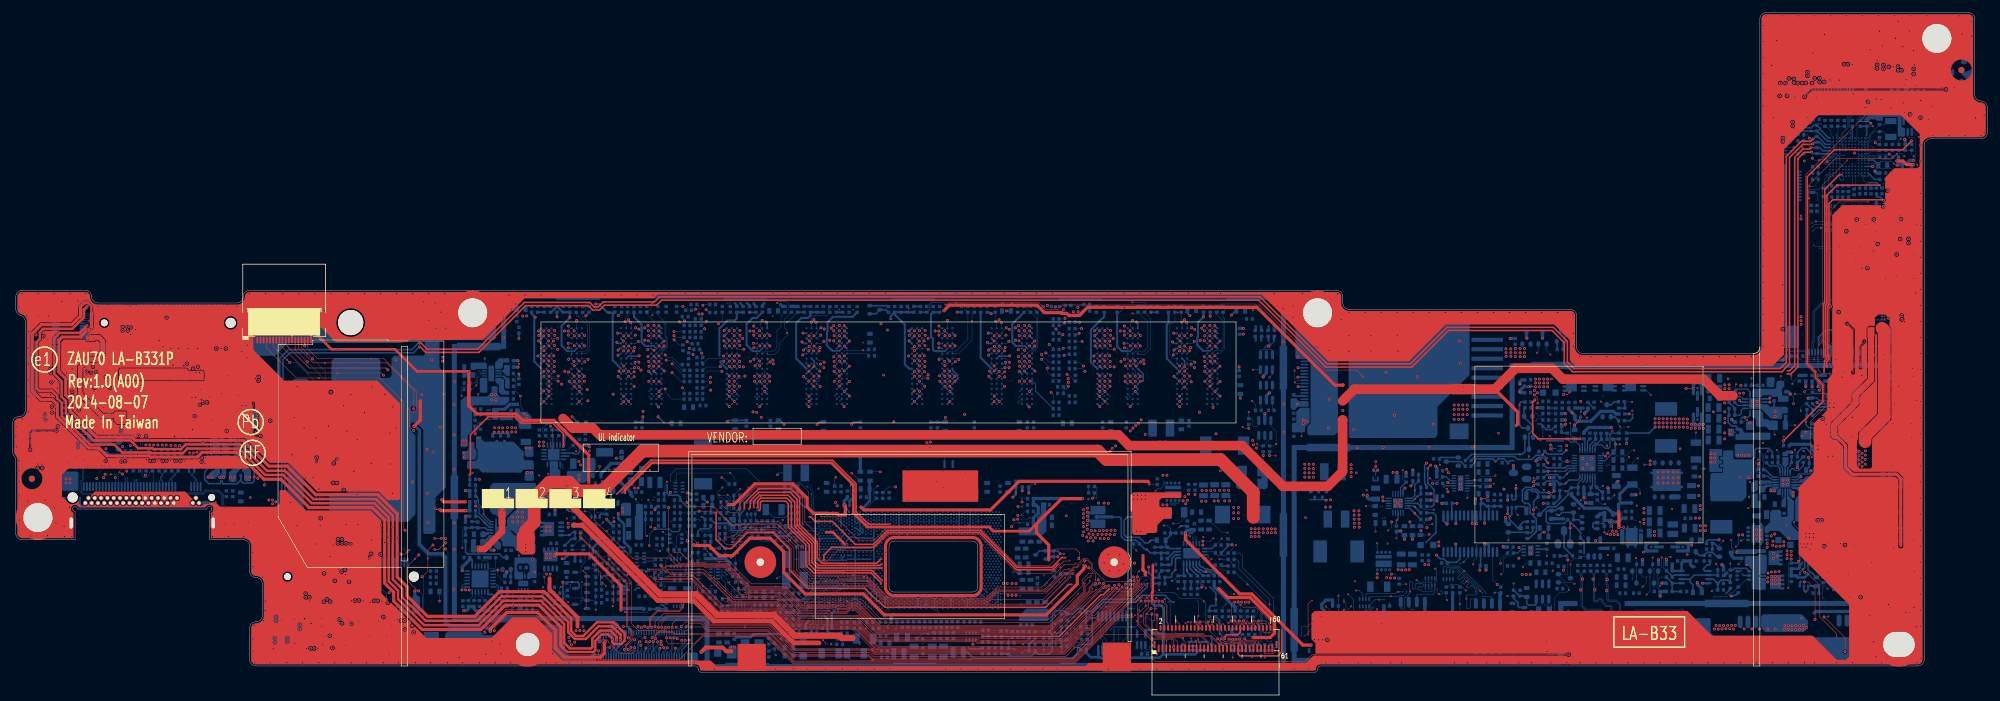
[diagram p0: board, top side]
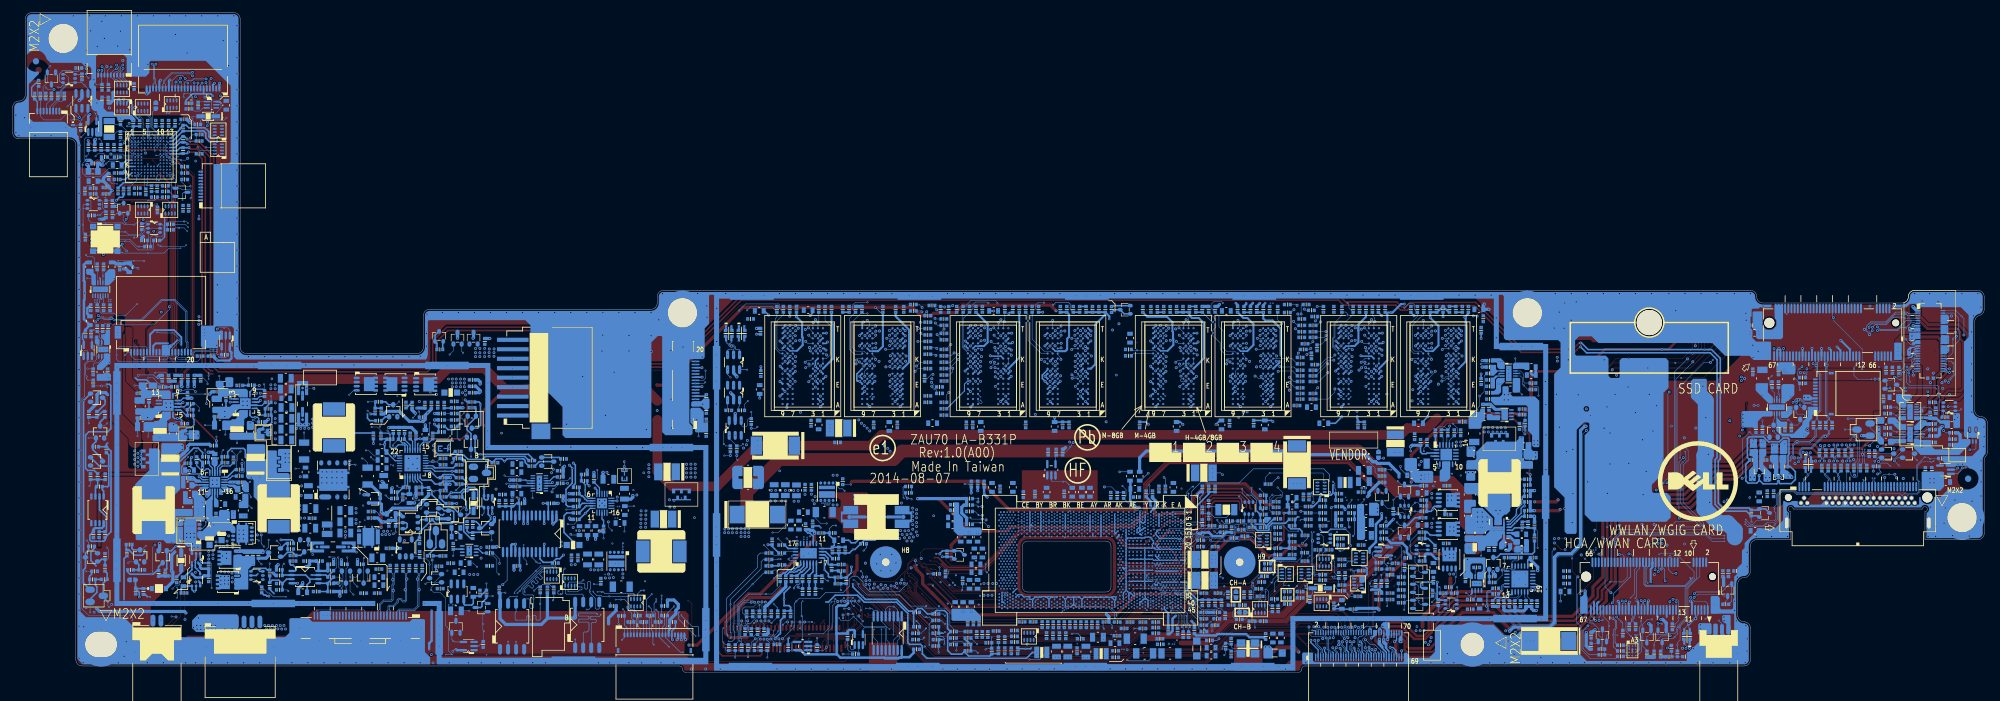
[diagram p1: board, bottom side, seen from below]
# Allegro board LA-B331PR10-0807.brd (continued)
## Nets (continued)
+3VALW_EC: C140.1 C141.1 C142.1 C143.1 C144.1 C145.1 C146.1 C147.1 C256.1 L10.1 R206.2 R207.1 R215.2 R229.1 R233.1 R234.1 R236.1 R237.1 R239.1 R243.1 R309.1 R330.2 R331.2 R332.2 R340.1 R349.2 R354.1 RP12.2 RP12.3 RP12.4 RP14.7 RP14.8 RP15.5 RP15.6 RP15.7 RP15.8 RP16.1 RP16.2 RP16.3 RP16.4 RP17.5 RP17.6 RP17.7 RP17.8 RP20.1 RP20.2 RP20.3 RP20.4 RP21.1 RP21.2 RP21.3 RP21.4 U38.A6 U38.F3 U38.F12 U38.K1 U38.K2 U38.K4 U38.K12 U38.L4 U38.N4
+3VALW_EC_L: C139.1 L10.2 U38.H3
+3VALWP: PC307.1 PJ301.1 PL301.1 PR300.1 PR311.1
+3VLP: PC300.1 PR773.1 PU300.3 RTCD1.2 U58.6
+3VNS_PWR: C198.1 JSNR1.3 R153.2 R336.2
+3VS: C103.1 C193.1 C234.1 C235.1 C243.1 C252.1 CH54.1 CH80.1 CH81.1 CH82.1 CZ3.1 JCAN1.4 JCAN1.5 JIO1.65 JLPDE1.1 JLPDE1.2 JUSH1.8 MD2.5 MD7.5 MD14.5 PR512.2 Q7.2 Q43.2 QH1.2 QH1.5 R14.2 R168.1 R175.1 R183.1 R194.1 R212.1 R292.2 R316.1 R317.1 R318.1 R319.1 R346.1 R390.1 RC17.1 RC51.1 RH11.1 RH16.2 RH17.2 RH21.1 RH26.1 RH29.1 RH34.1 RH37.1 RH42.1 RH44.1 RH59.2 RH94.2 RH95.2 RH96.2 RH99.2 RH101.2 RH114.1 RH119.2 RH120.2 RH122.2 RH124.2 RH126.1 RH142.2 RH160.2 RH168.2 RH169.2 RH174.2 RH176.2 RH177.1 RP1.1 RP1.2 RP1.3 RP1.4 RP7.5 RP7.6 RP8.1 RP19.1 RP19.2 RP19.3 RP19.4 RP22.5 RP22.6 RP22.7 RP22.8 U56.1 U56.13 UCPU1.A26 UCPU1.A28 UCPU1.A30 UCPU1.AB36 UCPU1.T27 UH1.5
+3VS_AUDIO: CH62.1 JAUD1.29 JIO1.66 Q1.6 R190.2 UCPU1.AA13 UCPU1.W1
+3VS_CAM: C119.1 C194.1 C244.1 JCAN1.1 JCAN1.2 JCAN1.3 R160.2
+3VS_TPM: C74.1 C75.1 C76.1 C77.1 C78.1 C79.1 C90.1 C250.1 R345.2 U21.3 U21.10 U21.12 U21.19 U21.24
+3VS_TS: C112.1 C262.1 JTS1.8 MD1.5 Q5.2 Q41.2 Q41.5 R40.1 R159.2 R335.2 R337.2 RH166.2 RH167.2 U60.5
+3VS_WLAN: C16.1 C17.1 C18.1 C19.1 C96.1 C245.1 C246.1 JNGFF1.2 JNGFF1.4 JNGFF1.64 JNGFF1.66 R146.2 U51.5
+3VS_WWAN: C20.1 C21.1 C22.1 C23.1 C35.1 C247.1 C248.1 C260.1 C266.1 C267.1 JNGFF2.2 JNGFF2.4 JNGFF2.62 JNGFF2.64 JNGFF2.66 R70.1 R72.1 R73.1 R78.2 R391.1 U53.A2
+5V_DOCK: C239.1 JIO1.67 JIO1.68 R321.2
+5VALW: C33.1 C95.1 C106.1 C118.1 C240.1 JDEBUG.1 JSNR1.1 PC607.2 PJ300.2 PR104.2 PR603.1 PU600.12 Q12.4 Q16.4 Q20.4 R1.2 R169.1 R176.1 R184.1 U24.4 U25.1 U25.2 U25.4 U26.4 U27.4 U28.2 U29.4 U30.4 U33.4 U33.6 U33.7 U34.4 U57.1 U57.2 U57.4 U59.4
+5VALWP: PC308.1 PJ300.1 PL302.2 PR301.2 PU300.14
+5VLP: PC311.1 PU300.13
+5VS: C92.1 C251.1 CZ2.1 JUSH1.7 PC519.1 PU702.12 QV1.2 R143.2
+5VS_AUDIO: JAUD1.19 JAUD1.21 JAUD1.23 R193.2
+V1.05A_AOSCSUS: CH72.1 CH73.1 CH74.1 L2.1 UCPU1.T21
+V1.05A_DCPSUS1: CH58.1 RH138.1 UCPU1.U16
+V1.05A_DCPSUS2: CH63.1 RH141.2 UCPU1.AG14
+V1.05A_DCPSUS3: CH60.1 CH61.1 RH139.2 UCPU1.U30
+V1.05S_APLL: CH69.1 RH144.1 UCPU1.AK29
+V1.05S_APLLOPI: CH65.1 RH143.1 UCPU1.AK19
+V1.05S_ASATA3PLL: CH46.1 CH47.1 CH48.1 LH1.2 RH20.2 UCPU1.L42 UCPU1.T33
+V1.05S_AUSB: CH79.1 RH147.1 UCPU1.AK17
+V1.05S_AUSB3PLL: CH55.1 CH56.1 CH57.1 LH2.2 RH134.1 UCPU1.C41 UCPU1.T35
+V1.05S_AXCK_DCB: CH66.1 CH67.1 CH68.1 L1.2 UCPU1.AL37
+V1.05S_AXCK_LCPLL: CH75.1 CH76.1 CH77.1 L3.2 RH31.2 UCPU1.AK35
+V1.05S_MPHY_PCIE: CH25.1 CH26.1 CH27.1 R9.2 UCPU1.AA45 UCPU1.AB38 UCPU1.W45
+V1.05S_MPHY_SATA: CH30.1 CH31.1 R10.2 UCPU1.N45 UCPU1.T45
+V1.05S_MPHY_USB3: CH38.1 CH39.1 R11.2 UCPU1.AC45 UCPU1.AD36 UCPU1.AE45
+VCC_CORE: C225.1 PC800.1 PC801.1 PC802.1 PC803.1 PC804.1 PC805.1 PC806.1 PC807.1 PC808.1 PC809.1 PC810.1 PC811.1 PC812.1 PC813.1 PC814.1 PC815.1 PC816.1 PC817.1 PC818.1 PC819.1 PC820.1 PC821.1 PC822.1 PC823.1 PC824.1 PC825.1 PC826.1 PC827.1 PC828.1 PC829.1 PC830.1 PC831.1 PC832.1 PC833.1 PC834.1 PC835.1 PC836.1 PC840.1 PL504.4 RC24.1 UCPU1.AV45 UCPU1.AY45 UCPU1.BB45 UCPU1.BD45 UCPU1.BF45 UCPU1.BH45 UCPU1.BK45 UCPU1.BM45 UCPU1.BP45 UCPU1.BT45 UCPU1.BV41 UCPU1.BV43 UCPU1.BV45 UCPU1.BW40 UCPU1.BW42 UCPU1.BW44 UCPU1.BY41 UCPU1.BY43 UCPU1.BY45 UCPU1.CA40 UCPU1.CA42 UCPU1.CA44 UCPU1.CB41 UCPU1.CB43 UCPU1.CB45 UCPU1.CD45 UCPU1.CF45 UCPU1.CM45 UCPU1.CN44 UCPU1.CR43 UCPU1.CR45 UCPU1.CU44 UCPU1.CV43 UCPU1.CV45 UCPU1.CY13 UCPU1.CY15 UCPU1.CY17 UCPU1.CY19 UCPU1.CY21 UCPU1.CY23 UCPU1.CY25 UCPU1.CY27 UCPU1.CY29 UCPU1.CY31 UCPU1.CY33 UCPU1.CY36 UCPU1.CY38 UCPU1.CY40 UCPU1.CY42 UCPU1.CY44
+VCCIO_OUT: CH19.1 UCPU1.BM43
+VCCIOA_OUT: RC1.2 UCPU1.AR40
AGND: JAUD1.15 JAUD1.17 JIO1.58 JIO1.60
GND: C1.2 C2.2 C4.2 C5.2 C6.2 C12.2 C16.2 C17.2 C18.2 C19.2 C20.2 C21.2 C22.2 C23.2 C29.2 C30.2 C31.2 C32.2 C33.2 C34.2 C35.2 C74.2 C75.2 C76.2 C77.2 C78.2 C79.2 C90.2 C92.2 C93.2 C94.2 C95.2 C96.2 C97.2 C98.2 C99.2 C100.2 C101.2 C102.1 C103.2 C104.2 C105.2 C106.2 C107.2 C109.2 C110.2 C111.2 C112.2 C113.2 C114.2 C115.2 C116.2 C117.2 C118.2 C119.2 C120.2 C121.2 C122.2 C123.2 C124.2 C125.2 C126.2 C127.2 C128.2 C129.2 C130.2 C131.2 C132.2 C133.2 C134.2 C135.2 C136.2 C139.2 C140.2 C141.2 C142.2 C143.2 C144.2 C145.2 C146.2 C147.2 C148.2 C149.2 C150.2 C157.2 C158.2 C159.2 C160.2 C161.2 C162.2 C165.2 C193.2 C194.2 C197.2 C198.2 C199.2 C200.2 C214.2 C215.2 C216.2 C217.2 C218.2 C219.2 C220.2 C221.2 C222.2 C223.2 C224.2 C225.2 C234.2 C235.2 C238.2 C239.2 C240.2 C241.2 C242.2 C243.2 C244.2 C245.2 C246.2 C247.2 C248.2 C249.2 C250.2 C251.2 C252.2 C253.2 C255.2 C256.2 C257.2 C258.2 C259.2 C260.2 C261.2 C262.2 C263.2 C264.2 C265.2 C266.2 C267.2 C268.2 C269.2 C270.2 C271.2 C272.2 C273.2 CA53.2 CA54.2 CA55.2 CA56.2 CA57.2 CC1.2 CC2.2 CC3.2 CC4.2 CC5.2 CC6.2 CC7.2 CC8.2 CC9.2 CC10.2 CC11.2 CD1.2 CD2.2 CD3.1 CD4.1 CD5.2 CD6.2 CD7.2 CD8.2 CD9.2 CD10.2 CD11.2 CD12.2 CD13.2 CD14.2 CD15.2 CD16.2 CD17.2 CD18.2 CD19.2 CD20.2 CD21.1 CD22.1 CD23.2 CD24.2 CD25.2 CD26.2 CD27.2 CD28.2 CD29.2 CD30.2 CD31.2 CD32.2 CD33.2 CD34.2 CD35.2 CD36.2 CD37.2 CD38.1 CD39.1 CD40.2 CD41.2 CD42.2 CD43.2 CD44.2 CD45.2 CD46.2 CD47.2 CD48.2 CD49.2 CD50.2 CD51.2 CD52.2 CD53.2 CD54.2 CD55.2 CD56.1 CD57.1 CD58.2 CD59.2 CD60.2 CD61.2 CD62.2 CD63.2 CD64.2 CD65.2 CD66.2 CD67.2 CD68.2 CD69.2 CD70.2 CD71.2 CD75.2 CD76.2 CD77.2 CD78.2 CD79.2 CD80.2 CD81.2 CD82.2 CD83.2 CD84.2 CD85.2 CD86.2 CD87.2 CD88.2 CH1.2 CH2.2 CH3.1 CH4.2 CH5.2 CH6.2 CH7.2 CH8.2 CH19.2 CH20.2 CH21.2 CH25.2 CH26.2 CH27.2 CH28.2 CH30.2 CH31.2 CH32.2 CH33.2 CH34.2 CH35.2 CH38.2 CH39.2 CH40.2 CH41.2 CH42.2 CH44.2 CH45.2 CH46.2 CH47.2 CH48.2 CH49.2 CH50.2 CH51.2 CH52.2 CH53.2 CH54.2 CH55.2 CH56.2 CH57.2 CH58.2 CH59.2 CH60.2 CH61.2 CH62.2 CH63.2 CH64.2 CH65.2 CH66.2 CH67.2 CH68.2 CH69.2 CH70.2 CH71.2 CH72.2 CH73.2 CH74.2 CH75.2 CH76.2 CH77.2 CH78.2 CH79.2 CH80.2 CH81.2 CH82.2 CH83.2 CH84.2 CH85.2 CH86.2 CH87.2 CH88.2 CH89.2 CH90.2 CH93.2 CLIP1.1 CLIP2.1 CLIP3.1 CLIP4.1 CLIP5.1 CLIP6.1 CLIP7.1 CLIP8.1 CLIP9.1 CLIP10.1 CLIP11.1 CLIP12.1 CLIP13.1 CLIP14.1 CLIP15.1 CLIP17.1 CLIP18.1 CLIP19.1 CLIP20.1 CLIP21.1 CLIP22.1 CLIP23.1 CLIP24.1 CLRP1.1 CLRP3.2 CZ2.2 CZ3.2 CZ4.2 D23.2 DA1.1 DA5.1 H1.1(TP-1) H2.1(TP-1) H3.1(TP-1) H4.1(TP-1) H5.1(TP-1) H6.1(TP-1) H8.1(TP-1) H9.1(TP-1) JAPS1.5 JAPS1.7 JAPS1.9 JAPS1.11 JAPS1.19 JAPS1.20 JAUD1.31 JAUD1.35 JAUD1.39 JAUD1.40 JAUD1.43 JAUD1.44 JAUD1.47 JAUD1.48 JAUD1.51 JAUD1.52 JAUD1.53 JAUD1.54 JBAT1.1 JBAT1.2 JBAT1.4 JBAT1.10 JBAT1.11 JBT1.2 JBT1.3 JBT1.4 JCAN1.7 JCAN1.10 JCAN1.13 JCAN1.16 JCAN1.19 JCAN1.20 JCAN1.21 JCAN1.22 JCAN1.23 JCAN1.24 JDEBUG.4 JDEBUG.11 JDEBUG.12 JDEG1.10 JDEG1.11 JDEG1.12 JIO1.3 JIO1.9 JIO1.15 JIO1.21 JIO1.27 JIO1.33 JIO1.39 JIO1.44 JIO1.45 JIO1.46 JIO1.48 JIO1.50 JIO1.51 JIO1.52 JIO1.54 JIO1.55 JIO1.56 JIO1.62 JIO1.64 JIO1.71 JIO1.72 JLPDE1.9 JLPDE1.11 JLPDE1.12 JLVDS1.2 JLVDS1.5 JLVDS1.8 JLVDS1.11 JLVDS1.15 JLVDS1.16 JLVDS1.18 JLVDS1.19 JLVDS1.20 JLVDS1.21 JLVDS1.31 JLVDS1.32 JLVDS1.33 JLVDS1.34 JLVDS1.35 JNGFF1.1 JNGFF1.7 JNGFF1.9 JNGFF1.10 JNGFF1.15 JNGFF1.16 JNGFF1.21 JNGFF1.22 JNGFF1.25 JNGFF1.28 JNGFF1.31 JNGFF1.37 JNGFF1.43 JNGFF1.49 JNGFF1.55 JNGFF1.61 JNGFF1.67 JNGFF1.68 JNGFF1.69 JNGFF2.3 JNGFF2.5 JNGFF2.11 JNGFF2.19 JNGFF2.25 JNGFF2.31 JNGFF2.37 JNGFF2.43 JNGFF2.49 JNGFF2.63 JNGFF2.65 JNGFF2.68 JNGFF2.69 JNGFF3.3 JNGFF3.5 JNGFF3.11 JNGFF3.19 JNGFF3.25 JNGFF3.31 JNGFF3.37 JNGFF3.43 JNGFF3.49 JNGFF3.63 JNGFF3.65 JNGFF3.68 JNGFF3.69 JPWR1.1 JPWR1.2 JPWR1.3 JPWR1.7 JPWR1.8 JSNR1.17 JSNR1.20 JSNR1.23 JSNR1.24 JSNR1.25 JSNR1.26 JSPI1.18 JSPI1.19 JSPI1.20 JSPI1.21 JSPI1.22 JSPK1.5 JSPK1.6 JTS1.1 JTS1.2 JTS1.9 JTS1.10 JUSH1.2 JUSH1.3 JUSH1.17 JUSH1.20 JUSH1.21 JUSH1.22 JXDP1.1 JXDP1.2 JXDP1.7 JXDP1.8 JXDP1.13 JXDP1.14 JXDP1.19 JXDP1.20 JXDP1.25 JXDP1.26 JXDP1.31 JXDP1.32 JXDP1.37 JXDP1.38 JXDP1.49 JXDP1.50 JXDP1.59 JXDP1.61 JXDP1.62 JXDP1.63 MC1.2 MC2.1 MC5.2 MD1.2 MD2.2 MD7.2 MD14.2 PC1.2 PC2.2 PC3.2 PC4.2 PC5.2 PC6.2 PC8.2 PC55.2 PC56.2 PC60.2 PC70.2 PC80.2 PC108.2 PC110.2 PC111.2 PC300.2 PC303.2 PC307.2 PC308.2 PC309.2 PC310.2 PC311.2 PC312.2 PC313.2 PC314.2 PC315.2 PC400.2 PC401.2 PC403.2 PC404.2 PC405.2 PC406.2 PC407.2 PC408.2 PC409.2 PC411.2 PC412.2 PC413.2 PC414.2 PC415.2 PC500.2 PC502.2 PC503.2 PC504.2 PC506.2 PC507.2 PC509.2 PC510.2 PC511.2 PC512.2 PC513.2 PC514.2 PC515.2 PC517.2 PC519.2 PC532.2 PC533.1 PC538.1 PC539.2 PC540.1 PC541.2 PC542.1 PC547.1 PC559.1 PC600.2 PC601.2 PC602.2 PC603.2 PC605.2 PC606.2 PC607.1 PC609.2 PC610.2 PC611.2 PC612.2 PC613.2 PC614.2 PC617.2 PC705.2 PC706.1 PC709.2 PC713.2 PC714.2 PC717.2 PC718.2 PC719.2 PC720.2 PC722.2 PC726.2 PC727.2 PC728.2 PC729.2 PC730.2 PC731.2 PC732.2 PC760.2 PC800.2 PC801.2 PC802.2 PC803.2 PC804.2 PC805.2 PC806.2 PC807.2 PC808.2 PC809.2 PC810.2 PC811.2 PC812.2 PC813.2 PC814.2 PC815.2 PC816.2 PC817.2 PC818.2 PC819.2 PC820.2 PC821.2 PC822.2 PC823.2 PC824.2 PC825.2 PC826.2 PC827.2 PC828.2 PC829.2 PC830.2 PC831.2 PC832.2 PC833.2 PC834.2 PC835.2 PC836.2 PC840.2 PC900.2 PC901.2 PC902.2 PC903.2 PC905.2 PC906.2 PC907.1 PD3.1 PD4.1 PH504.2 PJP701.2 PQ6.3 PQ7.3 PQ30.3 PQ31.3 PQ32.3 PQ34.3 PQ52.3 PQ53.3 PQ54.3 PQ60.3 PQ61.3 PQ62.3 PQ102.3 PQ300.8 PQ501.8 PQ503.5 PQ503.6 PQ503.7 PQ600.5 PQ600.6 PQ600.7 PQ701.6 PQ702.8 PQ900.1 PQ901.1 PR30.2 PR42.2 PR62.1 PR75.2 PR76.2 PR106.2 PR302.1 PR303.2 PR304.1 PR305.1 PR306.2 PR403.2 PR408.2 PR501.2 PR507.2 PR508.2 PR514.2 PR518.2 PR520.1 PR529.2 PR562.2 PR607.2 PR772.2 PR905.2 PR906.2 PR911.2 PR912.2 PU300.21 PU400.6 PU400.8 PU400.15 PU400.16 PU400.17 PU401.6 PU401.8 PU401.15 PU401.16 PU401.17 PU500.9 PU600.1 PU600.3 PU600.14 PU600.21 PU700.22 PU702.21 PU900.4 PU901.3 PU902.3 PU904.4 Q1.4 Q3.3 Q4.3 Q12.1 Q13.3 Q14.3 Q16.1 Q17.3 Q18.3 Q20.1 Q21.3 Q22.3 Q23.3 Q45.4 Q46.3 R13.1 R23.2 R32.2 R35.2 R44.2 R48.2 R68.2 R79.1 R147.1 R148.1 R155.1 R158.1 R162.1 R163.1 R173.2 R181.2 R189.2 R192.1 R195.1 R210.2 R214.1 R223.2 R225.1 R230.2 R244.2 R303.2 R306.1 R308.1 R320.2 R322.1 R326.2 R334.2 R341.2 R350.1 R361.1 R379.1 R380.1 R381.1 R382.1 R383.1 RC2.1 RC4.1 RC10.1 RC12.2 RC13.2 RC14.2 RC15.2 RC16.2 RC18.2 RC22.2 RC34.2 RC35.2 RC36.2 RC37.2 RC39.2 RD1.2 RD2.2 RD3.2 RD4.2 RD5.2 RD6.2 RD7.2 RD8.2 RD9.2 RD10.2 RD11.2 RD12.2 RD13.2 RD14.2 RD15.2 RD16.2 RD19.2 RD20.2 RD25.2 RD26.2 RD27.2 RD28.2 RH1.1 RH2.1 RH3.1 RH4.1 RH24.1 RH39.1 RH64.2 RH81.1 RH89.2 RH92.1 RH102.2 RH103.2 RH105.2 RH113.2 RH121.1 RH123.1 RH125.1 RH132.2 RH133.2 RH170.2 RH171.2 RH172.2 RH173.2 RH178.1 RP12.1 RP13.2 RP13.3 RP13.4 RP24.1 RP24.2 RP24.3 RP24.4 RV1.2 RZ3.1 RZ5.1 SW6.1 SW6.2 U1.4 U2.4 U4.8 U5.3 U6.2 U7.3 U21.1 U21.2 U21.4 U21.8 U21.9 U21.11 U21.17 U21.18 U21.25 U24.5 U24.9 U25.11 U25.15 U26.11 U26.15 U27.11 U27.15 U28.3 U29.11 U29.15 U30.11 U30.15 U33.11 U33.15 U34.5 U34.9 U37.3 U38.A2 U38.A3 U38.F4 U38.F11 U38.G2 U38.H4 U38.J4 U38.N3 U46.2 U46.7 U51.3 U53.D2 U54.3 U56.10 U56.21 U56.25 U57.5 U57.9 U58.2 U59.5 U59.9 U60.3 U61.3 UC1.3 UCPU1.A6 UCPU1.A10 UCPU1.A16 UCPU1.A20 UCPU1.A36 UCPU1.A40 UCPU1.A42 UCPU1.AA3 UCPU1.AA5 UCPU1.AA7 UCPU1.AA11 UCPU1.AA19 UCPU1.AA21 UCPU1.AA22 UCPU1.AA24 UCPU1.AA25 UCPU1.AA26 UCPU1.AA28 UCPU1.AA29 UCPU1.AA30 UCPU1.AA32 UCPU1.AA33 UCPU1.AA34 UCPU1.AA35 UCPU1.AA37 UCPU1.AA39 UCPU1.AB8 UCPU1.AB12 UCPU1.AB15 UCPU1.AB16 UCPU1.AB40 UCPU1.AB44 UCPU1.AC1 UCPU1.AC3 UCPU1.AC5 UCPU1.AC7 UCPU1.AC9 UCPU1.AC11 UCPU1.AC13 UCPU1.AC19 UCPU1.AC24 UCPU1.AC28 UCPU1.AC32 UCPU1.AC35 UCPU1.AC37 UCPU1.AC41 UCPU1.AC43 UCPU1.AD6 UCPU1.AD12 UCPU1.AD14 UCPU1.AD16 UCPU1.AD19 UCPU1.AD24 UCPU1.AD28 UCPU1.AD32 UCPU1.AD44 UCPU1.AE16 UCPU1.AE19 UCPU1.AE24 UCPU1.AE28 UCPU1.AE32 UCPU1.AE35 UCPU1.AE37 UCPU1.AF6 UCPU1.AF12 UCPU1.AF14 UCPU1.AF16 UCPU1.AF36 UCPU1.AF44 UCPU1.AG19 UCPU1.AG24 UCPU1.AG28 UCPU1.AG32 UCPU1.AG35 UCPU1.AG37 UCPU1.AG39 UCPU1.AH6 UCPU1.AH12 UCPU1.AH14 UCPU1.AH15 UCPU1.AH16 UCPU1.AH17 UCPU1.AH19 UCPU1.AH20 UCPU1.AH21 UCPU1.AH22 UCPU1.AH23 UCPU1.AH25 UCPU1.AH26 UCPU1.AH27 UCPU1.AH28 UCPU1.AH29 UCPU1.AH30 UCPU1.AH31 UCPU1.AH32 UCPU1.AH33 UCPU1.AH34 UCPU1.AH44 UCPU1.AJ13 UCPU1.AJ18 UCPU1.AJ24 UCPU1.AJ30 UCPU1.AJ37 UCPU1.AJ39 UCPU1.AK6 UCPU1.AK12 UCPU1.AK15 UCPU1.AK21 UCPU1.AK27 UCPU1.AK44 UCPU1.AL26 UCPU1.AL28 UCPU1.AM13 UCPU1.AM17 UCPU1.AM19 UCPU1.AM21 UCPU1.AM23 UCPU1.AM25 UCPU1.AM27 UCPU1.AM29 UCPU1.AM31 UCPU1.AM33 UCPU1.AM35 UCPU1.AM39 UCPU1.AM45 UCPU1.AN2 UCPU1.AN4 UCPU1.AN6 UCPU1.AN8 UCPU1.AN10 UCPU1.AN12 UCPU1.AN14 UCPU1.AN40 UCPU1.AN42 UCPU1.AN44 UCPU1.AP7 UCPU1.AP15 UCPU1.AP39 UCPU1.AP43 UCPU1.AR12 UCPU1.AR14 UCPU1.AR42 UCPU1.AT1 UCPU1.AT7 UCPU1.AT15 UCPU1.AT39 UCPU1.AT45 UCPU1.AU12 UCPU1.AU44 UCPU1.AV3 UCPU1.AV5 UCPU1.AV7 UCPU1.AV9 UCPU1.AV11 UCPU1.AV13 UCPU1.AV15 UCPU1.AV39 UCPU1.AW14 UCPU1.AW44 UCPU1.AY1 UCPU1.AY7 UCPU1.AY13 UCPU1.AY15 UCPU1.AY39 UCPU1.BA44 UCPU1.BB3 UCPU1.BB5 UCPU1.BB7 UCPU1.BB9 UCPU1.BB11 UCPU1.BB13 UCPU1.BB15 UCPU1.BB39 UCPU1.BC44 UCPU1.BD1 UCPU1.BD7 UCPU1.BD13 UCPU1.BD15 UCPU1.BD39 UCPU1.BE40 UCPU1.BE42 UCPU1.BE44 UCPU1.BF7 UCPU1.BF13 UCPU1.BF15 UCPU1.BF39 UCPU1.BG14 UCPU1.BG44 UCPU1.BH1 UCPU1.BH7 UCPU1.BH13 UCPU1.BH15 UCPU1.BH39 UCPU1.BH41 UCPU1.BH43 UCPU1.BJ44 UCPU1.BK7 UCPU1.BK13 UCPU1.BK15 UCPU1.BK39 UCPU1.BL2 UCPU1.BL4 UCPU1.BL6 UCPU1.BL8 UCPU1.BL10 UCPU1.BL12 UCPU1.BL40 UCPU1.BL42 UCPU1.BL44 UCPU1.BM1 UCPU1.BM7 UCPU1.BM13 UCPU1.BM15 UCPU1.BM39 UCPU1.BN14 UCPU1.BN44 UCPU1.BP7 UCPU1.BP13 UCPU1.BP15 UCPU1.BP39 UCPU1.BR14 UCPU1.BR44 UCPU1.BT1 UCPU1.BT7 UCPU1.BT13 UCPU1.BT39 UCPU1.BU40 UCPU1.BU42 UCPU1.BU44 UCPU1.BV7 UCPU1.BV13 UCPU1.BV15 UCPU1.BV39 UCPU1.BW14 UCPU1.BY1 UCPU1.BY3 UCPU1.BY5 UCPU1.BY7 UCPU1.BY9 UCPU1.BY11 UCPU1.BY13 UCPU1.BY15 UCPU1.BY39 UCPU1.C16 UCPU1.C20 UCPU1.C24 UCPU1.C28 UCPU1.C32 UCPU1.C36 UCPU1.CA8 UCPU1.CA14 UCPU1.CB7 UCPU1.CB13 UCPU1.CB15 UCPU1.CB39 UCPU1.CC10 UCPU1.CC40 UCPU1.CC42 UCPU1.CC44 UCPU1.CD1 UCPU1.CD3 UCPU1.CD5 UCPU1.CD7 UCPU1.CD9 UCPU1.CD11 UCPU1.CD13 UCPU1.CD15 UCPU1.CD39 UCPU1.CE14 UCPU1.CE44 UCPU1.CF7 UCPU1.CF13 UCPU1.CF15 UCPU1.CF39 UCPU1.CG14 UCPU1.CG44 UCPU1.CH1 UCPU1.CH7 UCPU1.CH13 UCPU1.CH15 UCPU1.CJ18 UCPU1.CJ20 UCPU1.CJ24 UCPU1.CJ26 UCPU1.CJ30 UCPU1.CJ34 UCPU1.CK3 UCPU1.CK10 UCPU1.CK29 UCPU1.CK33 UCPU1.CK38 UCPU1.CK44 UCPU1.CL5 UCPU1.CL12 UCPU1.CL24 UCPU1.CL30 UCPU1.CL32 UCPU1.CM15 UCPU1.CM17 UCPU1.CM19 UCPU1.CM21 UCPU1.CM23 UCPU1.CM25 UCPU1.CM31 UCPU1.CM35 UCPU1.CM43 UCPU1.CN1 UCPU1.CN5 UCPU1.CN8 UCPU1.CN26 UCPU1.CN42 UCPU1.CP3 UCPU1.CP17 UCPU1.CP29 UCPU1.CR5 UCPU1.CR8 UCPU1.CR14 UCPU1.CR18 UCPU1.CR22 UCPU1.CR26 UCPU1.CR37 UCPU1.CT31 UCPU1.CU1 UCPU1.CU5 UCPU1.CU8 UCPU1.CU14 UCPU1.CU18 UCPU1.CU22 UCPU1.CU26 UCPU1.CU42 UCPU1.CV3 UCPU1.CV35 UCPU1.CV37 UCPU1.CV39 UCPU1.CV41 UCPU1.CW5 UCPU1.CW8 UCPU1.CW12 UCPU1.CW14 UCPU1.CW16 UCPU1.CW18 UCPU1.CW20 UCPU1.CW22 UCPU1.CW24 UCPU1.CW26 UCPU1.CW28 UCPU1.CW30 UCPU1.CW32 UCPU1.CW34 UCPU1.CY7 UCPU1.CY10 UCPU1.D4 UCPU1.D10 UCPU1.D42 UCPU1.E16 UCPU1.E20 UCPU1.E24 UCPU1.E28 UCPU1.E32 UCPU1.E36 UCPU1.F5 UCPU1.G16 UCPU1.G20 UCPU1.G24 UCPU1.G28 UCPU1.G32 UCPU1.H4 UCPU1.H10 UCPU1.H36 UCPU1.H42 UCPU1.J1 UCPU1.J3 UCPU1.J16 UCPU1.J20 UCPU1.J24 UCPU1.J28 UCPU1.J32 UCPU1.J43 UCPU1.J45 UCPU1.L2 UCPU1.L16 UCPU1.L20 UCPU1.L24 UCPU1.L28 UCPU1.L32 UCPU1.L38 UCPU1.N16 UCPU1.N20 UCPU1.N24 UCPU1.N28 UCPU1.N32 UCPU1.P35 UCPU1.R2 UCPU1.R4 UCPU1.R6 UCPU1.R8 UCPU1.R10 UCPU1.R16 UCPU1.R18 UCPU1.R20 UCPU1.R22 UCPU1.R24 UCPU1.R26 UCPU1.R28 UCPU1.R30 UCPU1.R44 UCPU1.T13 UCPU1.T15 UCPU1.T19 UCPU1.T23 UCPU1.T29 UCPU1.U14 UCPU1.U20 UCPU1.U22 UCPU1.U24 UCPU1.U26 UCPU1.U28 UCPU1.U32 UCPU1.U34 UCPU1.V2 UCPU1.V17 UCPU1.V40 UCPU1.V44 UCPU1.W16 UCPU1.W18 UCPU1.W19 UCPU1.W24 UCPU1.W28 UCPU1.W30 UCPU1.W32 UCPU1.W34 UCPU1.W35 UCPU1.Y2 UCPU1.Y12 UCPU1.Y14 UCPU1.Y16 UCPU1.Y19 UCPU1.Y24 UCPU1.Y28 UCPU1.Y32 UCPU1.Y40 UCPU1.Y42 UCPU1.Y44 UD1.A9 UD1.B1 UD1.B3 UD1.B9 UD1.D1 UD1.D3 UD1.D8 UD1.E1 UD1.E2 UD1.E7 UD1.E8 UD1.F9 UD1.G1 UD1.G8 UD1.G9 UD1.J2 UD1.J8 UD1.M1 UD1.M9 UD1.P1 UD1.P9 UD1.T1 UD1.T9 UD2.A9 UD2.B1 UD2.B3 UD2.B9 UD2.D1 UD2.D3 UD2.D8 UD2.E1 UD2.E2 UD2.E7 UD2.E8 UD2.F9 UD2.G1 UD2.G8 UD2.G9 UD2.J2 UD2.J8 UD2.M1 UD2.M9 UD2.P1 UD2.P9 UD2.T1 UD2.T9 UD3.A9 UD3.B1 UD3.B3 UD3.B9 UD3.D1 UD3.D3 UD3.D8 UD3.E1 UD3.E2 UD3.E7 UD3.E8 UD3.F9 UD3.G1 UD3.G8 UD3.G9 UD3.J2 UD3.J8 UD3.M1 UD3.M9 UD3.P1 UD3.P9 UD3.T1 UD3.T9 UD4.A9 UD4.B1 UD4.B3 UD4.B9 UD4.D1 UD4.D3 UD4.D8 UD4.E1 UD4.E2 UD4.E7 UD4.E8 UD4.F9 UD4.G1 UD4.G8 UD4.G9 UD4.J2 UD4.J8 UD4.M1 UD4.M9 UD4.P1 UD4.P9 UD4.T1 UD4.T9 UD5.A9 UD5.B1 UD5.B3 UD5.B9 UD5.D1 UD5.D3 UD5.D8 UD5.E1 UD5.E2 UD5.E7 UD5.E8 UD5.F9 UD5.G1 UD5.G8 UD5.G9 UD5.J2 UD5.J8 UD5.M1 UD5.M9 UD5.P1 UD5.P9 UD5.T1 UD5.T9 UD6.A9 UD6.B1 UD6.B3 UD6.B9 UD6.D1 UD6.D3 UD6.D8 UD6.E1 UD6.E2 UD6.E7 UD6.E8 UD6.F9 UD6.G1 UD6.G8 UD6.G9 UD6.J2 UD6.J8 UD6.M1 UD6.M9 UD6.P1 UD6.P9 UD6.T1 UD6.T9 UD7.A9 UD7.B1 UD7.B3 UD7.B9 UD7.D1 UD7.D3 UD7.D8 UD7.E1 UD7.E2 UD7.E7 UD7.E8 UD7.F9 UD7.G1 UD7.G8 UD7.G9 UD7.J2 UD7.J8 UD7.M1 UD7.M9 UD7.P1 UD7.P9 UD7.T1 UD7.T9 UD8.A9 UD8.B1 UD8.B3 UD8.B9 UD8.D1 UD8.D3 UD8.D8 UD8.E1 UD8.E2 UD8.E7 UD8.E8 UD8.F9 UD8.G1 UD8.G8 UD8.G9 UD8.J2 UD8.J8 UD8.M1 UD8.M9 UD8.P1 UD8.P9 UD8.T1 UD8.T9 UH1.3 YH2.2 YH2.4
GNDA_CHG: PC702.1 PC704.2 PC707.1 PC715.1 PC716.1 PC721.1 PC723.1 PC725.2 PJP701.1 PQ709.3 PR709.1 PR712.2 PR723.2 PR745.2 PU700.29
VBATT: PQ2.5 PQ703.5 PR720.2
VCCSENSE: PC542.2 PC549.1 PR542.1 PR550.1 RC25.1
VCCSENSE_R: RC24.2 RC25.2 UCPU1.CH45
VCCSTPG_MCP: RC29.2 UCPU1.BU14
VDD_1.35V: PC611.1 PR601.1 PR603.2 PU600.11
VSSSENSE: PC547.2 PC549.2 PU702.8 RC38.2
VSSSENSE_R: RC38.1 RC39.1 UCPU1.CH43
+DC_IN: JPWR1.4 JPWR1.5 JPWR1.6 PC700.1 PD700.3 PQ4.5 PQ700.1 PQ720.3 PR707.1 R333.1
+DCIN: PC706.2 PR705.2 PU700.28
+EDP_COM: RC1.1 UCPU1.AP41
+INV_PWR_SRC: C12.1 JLVDS1.25 JLVDS1.26 JLVDS1.27 JLVDS1.28 Q2.1 Q2.2 Q2.5 Q2.6 R25.2 R39.1
+LCDVDD: C4.1 C5.1 C6.1 C215.1 C242.1 JLVDS1.12 JLVDS1.13 R19.2 U7.5
+PBATT: PC8.1 PC56.1 PD700.2 PL1.2 PQ1.5 PR10.1
+PCH_VCCDSW: C205.1 RH137.1 UCPU1.AG13
+PWR_SRC_AC: PL700.1 PR700.1
+RTC_VCCSUS: CH28.1 RH136.1 UCPU1.AC15
+RTCBATT: JBT1.1 RTCR1.2
+RTCVCC: CH32.1 CH33.1 CH34.1 CH93.1 CLRP3.1 JAUD1.33 R208.1 RH15.1 RH18.1 RH19.1 RH23.1 RH79.1 RP13.1 RTCD1.1 RTCR1.1 UCPU1.AA15
+RTCVCC_R: C149.1 R208.2 U38.B2
+SDC_IN: PQ700.3 PR700.4
+SIM_PWR: JIO1.69 JIO1.70 JNGFF2.28
+VCHGR: PC718.1 PC719.1 PC720.1 PQ703.1 PQ703.2 PQ703.3 PR717.1
+VR_CAP: C160.1 U38.H1
+VREFCA: CD1.1 CD2.1 CD19.1 CD20.1 CD36.1 CD37.1 CD54.1 CD55.1 CD71.1 RD17.2 RD18.2 RD19.1 UD1.M8 UD2.M8 UD3.M8 UD4.M8 UD5.M8 UD6.M8 UD7.M8 UD8.M8
+VREFDQ_A: CD3.2 CD4.2 CD21.2 CD22.2 RD21.2 RD23.2 RD25.1 UD1.H1 UD2.H1 UD3.H1 UD4.H1
+VREFDQ_B: CD38.2 CD39.2 CD56.2 CD57.2 RD22.2 RD24.2 RD26.1 UD5.H1 UD6.H1 UD7.H1 UD8.H1
+VS_LPSS_SDIO: CH64.1 RH112.1 RH140.1 RH142.1 UCPU1.A32
A_ON: R152.1 R163.2 R342.1 R368.1 U38.L8
A_ON_R: R152.2 U24.3
AC_DIS: PQ701.5 PQ721.3 PR774.2 U38.B6
AC_PRESENT: RH70.1 RH80.2 U38.N8
AC_PRESENT_R: RH70.2 UCPU1.M17
ACAV_IN: PR56.1 PR711.1 U38.C1
ALS_INT#: JCAN1.6 MD14.1 R52.2
ALS_INT#_HUB: JSNR1.14 R52.1
ALS_SMBCLK: JCAN1.8 MD14.6 R54.2
ALS_SMBDATA: JCAN1.9 MD14.4 R55.2
ALW_PWRGD: PR311.2 PU300.7 R213.2
ALWON: D22.2 PC312.1 PR330.1 PR331.2 R356.2 RP13.7
APWROK: RH65.2 RH179.2 UCPU1.J22
AUDIO_IRQ: JAUD1.2 UCPU1.F35
AUDIO_PWREN: R194.2 R195.2 U30.3 U33.3 U33.5 UCPU1.R36
AUX_EN_WOWL: D13.3 U38.L13
B+: C11.1 PC111.1 PC713.1 PC714.1 PC717.1 PC732.1 PL300.1 PL304.1 PL400.1 PL402.1 PL500.1 PL503.2 PL600.1 PL701.2 PQ5.5 PR72.1 PR560.2 PR561.2 PR717.4 PR770.1 Q2.4 R25.1 R28.1
B+_1.05V: PC503.1 PC504.1 PC506.1 PC507.1 PL500.2 PU500.8
BASE_DC_IN_SS: JIO1.2 PC11.2 PQ4.4 PQ5.4 PR12.2 PR46.2 PR95.2
BASE_DET: Q44.2 Q44.5 Q45.2 Q45.3 R354.2
BASE_DET#: D21.1 JIO1.8 PD1.1 PR13.2 PR93.2 Q45.5 R215.1 U38.K10
BASE_HEAD_CHG_ON: PR55.1 U38.N10
BASE_SMB_ALERT#: JIO1.20 Q45.6 R330.1 R353.2
BASE_SMB_ALERT#_Q: Q45.1 R353.1 RP12.5 U38.B5
BASE_SMBCLK: JIO1.22 Q44.6 R331.1 R351.2
BASE_SMBCLK_Q: Q44.1 R351.1 RP15.3 U38.A9
BASE_SMBDAT: JIO1.24 Q44.3 R332.1 R352.2
BASE_SMBDAT_Q: Q44.4 R352.1 RP15.4 U38.D8
BATDRV#: PQ703.4 PR718.2
BATT++: JBAT1.8 JBAT1.9 PC3.1 PC4.1 PC5.1 PC55.1 PL1.1
BATT_PRS#: JBAT1.5 PC6.1 PD4.2 PR5.1
BATT_SEL_BASE_HEAD#: JIO1.6 PR42.1 PR59.1
BATT_SEL_CONTROL: PQ6.1 PQ32.1 PQ901.5 PR30.1 PR59.2
BATT_VREF: PC907.2 PR908.2 PR912.1 PU900.2 PU900.6
BEEP: JAUD1.38 U38.M8
BIA_PWM_EC: D4.2 U38.M10
BOARD_ID: C150.1 R207.2 U38.G1
BOOT: PR538.2 PU702.13
BOOT_1.35V: PR600.2 PU600.18
BQ24777_REGN: PC705.1 PR710.1 PR721.1 PR740.2 PU700.24
BST_1.05V: PR503.1 PU500.6
BST_1.35V: PC604.1 PR600.1
BST_3V: PR307.2 PU300.9
BST_5V: PR308.1 PU300.17
BT_OFF#_R: D19.1 JNGFF1.46 R326.1
BT_ON/OFF#: D19.3 UCPU1.L34
BT_RADIO_DIS#: D19.2 U38.L11
CFG0: JXDP1.9 R310.1
CFG1: JXDP1.11 UCPU1.CT27
CFG2: JXDP1.15 UCPU1.CP27
CFG3: JXDP1.17 R17.2 T39.1(TP-1) UCPU1.CU28
CFG4: JXDP1.27 RC34.1 UCPU1.CV29
CFG5: JXDP1.29 UCPU1.CT29
CFG6: JXDP1.33 UCPU1.CM29
CFG7: JXDP1.35 UCPU1.CU30
CFG8: JXDP1.10 UCPU1.CN30
CFG9: JXDP1.12 UCPU1.CV31
CFG10: JXDP1.16 UCPU1.CP31
CFG11: JXDP1.18 UCPU1.CN32
CFG12: JXDP1.28 UCPU1.CV33
CFG13: JXDP1.30 UCPU1.CU34
CFG14: JXDP1.34 UCPU1.CT33
CFG15: JXDP1.36 UCPU1.CP33
CFG16: JXDP1.6 UCPU1.CR28
CFG17: JXDP1.4 UCPU1.CN28
CFG18: JXDP1.24 UCPU1.CR32
CFG19: JXDP1.22 UCPU1.CU32
CFG_RCOMP: RC35.1 UCPU1.CR30
CHAGER_SRC: PC709.1 PC726.1 PC727.1 PC728.1 PC729.1 PC730.1 PC731.1 PL700.2 PQ702.1
CHARGER_SCL: PR731.2 PU700.12
CHARGER_SDA: PR730.2 PU700.11
CHARGER_SMBCLK: PR731.1 RP14.2 U38.B8
CHARGER_SMBDAT: PR730.1 RP14.1 U38.C8
CHG_BTS: PR708.1 PU700.25
CHG_BTS_C: PC708.1 PR708.2
CHG_LED#: JSNR1.10 U38.E3
CHG_LGATE: PQ702.4 PU700.23
CHG_ON#: PR49.2 U38.C3
CHG_SNUB: PC722.1 PR719.1
CHG_SW: PC708.2 PQ702.3 PU700.27
CHG_SW1: PL701.1 PQ702.5 PQ702.6 PQ702.7 PR719.2
CHG_UGATE: PQ702.2 PU700.26
CL_CLK: R64.2 UCPU1.D23
CL_CLK_R: JNGFF1.34 R64.1
CL_DATA: R63.2 UCPU1.H23
CL_DATA_R: JNGFF1.32 R63.1
CL_RST#: R61.2 UCPU1.K23
CL_RST#_R: JNGFF1.30 R61.1
CLK_LPC_DEBUG: JLPDE1.10 RH41.2
CLK_PCI_MEC: R231.1 RH38.2 U38.N6
CLK_PCIE2: JNGFF1.39 UCPU1.AG30
CLK_PCIE2#: JNGFF1.41 UCPU1.AE30
CLK_PCIE4: JNGFF1.63 UCPU1.AG29
CLK_PCIE4#: JNGFF1.65 UCPU1.AE29
CLK_PCIE5: JNGFF2.47 UCPU1.AE33
CLK_PCIE5#: JNGFF2.45 UCPU1.AG33
CLK_REQ2#: JNGFF1.45 RH40.1
CLK_REQ2#_R: RH34.2 RH40.2 UCPU1.P25
CLK_REQ3#_R: RH37.2 UCPU1.P27
CLK_REQ4#: JNGFF1.60 RH43.1
CLK_REQ4#_R: RH42.2 RH43.2 UCPU1.D35
CLK_REQ5#: JNGFF2.44 RH45.1
CLK_REQ5#_R: RH44.2 RH45.2 UCPU1.G30
CLKOUT_LPC0: RH38.1 UCPU1.K15
CLKOUT_LPC1: RH41.1 UCPU1.L14
CLKRUN#: RH59.1 U38.J3 UCPU1.B35
CODEC_MUTE#: DA8.1 JAUD1.4
COMP: PC538.2 PR564.2 PU702.6
CONTACTLESS_DET#: JUSH1.4 RH174.1 UCPU1.H40
CPU_B+: PC108.1 PC110.1 PC515.1 PC517.1 PC539.1 PL503.1 PQ503.2 PQ503.3 PQ503.4 PQ503.10 PR560.1 PR561.1
CPU_PATH_EN: R12.2 R13.2 U5.2
CPU_PATH_EN_G: U4.2 U4.5 U4.12 U4.15 U5.4
CPU_XDP_TCK: RC15.1 RH148.1 T11.1(TP-1) UCPU1.CM41
CPU_XDP_TDI: T14.1(TP-1) U4.11 UCPU1.CU36
CPU_XDP_TDO: RC11.1 T15.1(TP-1) U4.6 UCPU1.CU38
CPU_XDP_TMS: T12.1(TP-1) U4.14 UCPU1.CN40
CS1: PR305.2 PU300.1
CS2: PR304.2 PU300.5
CS_1.35V: PR601.2 PU600.13
CS_PWR_BTN#: RP8.6 U38.H13 UCPU1.H17
CSSN_1: PR700.2 PR704.2
CSSP_1: PR700.3 PR703.2
DDI2_HPD_SINK: JNGFF1.23 QV1.1 RV1.1
DDR3_DRAMRST#: CD5.1 CD23.1 CD40.1 CD58.1 RC19.2 RC20.2 UD1.T2 UD2.T2 UD3.T2 UD4.T2 UD5.T2 UD6.T2 UD7.T2 UD8.T2
DDR_A_BS0: RD71.1 UCPU1.CB5 UD1.M2 UD2.M2 UD3.M2 UD4.M2
DDR_A_BS1: RD75.1 UCPU1.CC2 UD1.N8 UD2.N8 UD3.N8 UD4.N8
DDR_A_BS2: RD73.1 UCPU1.CF11 UD1.M3 UD2.M3 UD3.M3 UD4.M3
DDR_A_CAS#: RD67.1 UCPU1.CC8 UD1.K3 UD2.K3 UD3.K3 UD4.K3
DDR_A_CKE0: RD61.1 UCPU1.CH11 UD1.K9 UD2.K9 UD3.K9 UD4.K9
DDR_A_CKE1: RD77.1 UCPU1.CH9 UD1.J9 UD2.J9 UD3.J9 UD4.J9
DDR_A_CS0#: RD65.1 UCPU1.CA4 UD1.L2 UD2.L2 UD3.L2 UD4.L2
DDR_A_CS1#: RD79.1 UCPU1.CA2 UD1.L1 UD2.L1 UD3.L1 UD4.L1
DDR_A_D0: UCPU1.CT17 UD1.F7
DDR_A_D1: UCPU1.CV17 UD1.H7
DDR_A_D2: UCPU1.CN14 UD1.G2
DDR_A_D3: UCPU1.CP15 UD1.F2
DDR_A_D4: UCPU1.CN16 UD1.H8
DDR_A_D5: UCPU1.CR16 UD1.F8
DDR_A_D6: UCPU1.CM13 UD1.H3
DDR_A_D7: UCPU1.CV15 UD1.E3
DDR_A_D8: UCPU1.CT13 UD1.A7
DDR_A_D9: UCPU1.CP13 UD1.B8
DDR_A_D10: UCPU1.CP10 UD1.A2
DDR_A_D11: UCPU1.CM10 UD1.C2
DDR_A_D12: UCPU1.CN12 UD1.C8
DDR_A_D13: UCPU1.CV13 UD1.D7
DDR_A_D14: UCPU1.CV10 UD1.C3
DDR_A_D15: UCPU1.CT10 UD1.A3
DDR_A_D16: UCPU1.CT25 UD2.H8
DDR_A_D17: UCPU1.CP25 UD2.F8
DDR_A_D18: UCPU1.CN22 UD2.H3
DDR_A_D19: UCPU1.CP23 UD2.F2
DDR_A_D20: UCPU1.CN24 UD2.H7
DDR_A_D21: UCPU1.CV25 UD2.F7
DDR_A_D22: UCPU1.CV23 UD2.G2
DDR_A_D23: UCPU1.CT23 UD2.E3
DDR_A_D24: UCPU1.CN20 UD2.B8
DDR_A_D25: UCPU1.CN18 UD2.C2
DDR_A_D26: UCPU1.CT21 UD2.A7
DDR_A_D27: UCPU1.CT19 UD2.C3
DDR_A_D28: UCPU1.CP19 UD2.A2
DDR_A_D29: UCPU1.CP21 UD2.C8
DDR_A_D30: UCPU1.CV19 UD2.A3
DDR_A_D31: UCPU1.CV21 UD2.D7
DDR_A_D32: UCPU1.BU2 UD4.C3
DDR_A_D33: UCPU1.BW2 UD4.A7
DDR_A_D34: UCPU1.BW6 UD4.B8
DDR_A_D35: UCPU1.BU4 UD4.A3
DDR_A_D36: UCPU1.BW4 UD4.C8
DDR_A_D37: UCPU1.BT3 UD4.A2
DDR_A_D38: UCPU1.BU6 UD4.D7
DDR_A_D39: UCPU1.BT5 UD4.C2
DDR_A_D40: UCPU1.BN2 UD3.C8
DDR_A_D41: UCPU1.BR2 UD3.B8
DDR_A_D42: UCPU1.BN6 UD3.A2
DDR_A_D43: UCPU1.BN4 UD3.D7
DDR_A_D44: UCPU1.BR6 UD3.C3
DDR_A_D45: UCPU1.BR4 UD3.A7
DDR_A_D46: UCPU1.BM5 UD3.C2
DDR_A_D47: UCPU1.BM3 UD3.A3
DDR_A_D48: UCPU1.BT11 UD4.F2
DDR_A_D49: UCPU1.BU10 UD4.F8
DDR_A_D50: UCPU1.BW12 UD4.F7
DDR_A_D51: UCPU1.BW10 UD4.H8
DDR_A_D52: UCPU1.BW8 UD4.H7
DDR_A_D53: UCPU1.BU8 UD4.H3
DDR_A_D54: UCPU1.BU12 UD4.E3
DDR_A_D55: UCPU1.BT9 UD4.G2
DDR_A_D56: UCPU1.BN8 UD3.G2
DDR_A_D57: UCPU1.BR8 UD3.H3
DDR_A_D58: UCPU1.BN12 UD3.F8
DDR_A_D59: UCPU1.BN10 UD3.F7
DDR_A_D60: UCPU1.BR12 UD3.H7
DDR_A_D61: UCPU1.BR10 UD3.H8
DDR_A_D62: UCPU1.BM11 UD3.E3
DDR_A_D63: UCPU1.BM9 UD3.F2
DDR_A_DQS0: UCPU1.CT15 UD1.F3
DDR_A_DQS1: UCPU1.CU12 UD1.C7
DDR_A_DQS2: UCPU1.CU24 UD2.F3
DDR_A_DQS3: UCPU1.CU20 UD2.C7
DDR_A_DQS4: UCPU1.BV5 UD4.C7
DDR_A_DQS5: UCPU1.BP5 UD3.C7
DDR_A_DQS6: UCPU1.BV11 UD4.F3
DDR_A_DQS7: UCPU1.BP11 UD3.F3
DDR_A_DQS#0: UCPU1.CU16 UD1.G3
DDR_A_DQS#1: UCPU1.CR12 UD1.B7
DDR_A_DQS#2: UCPU1.CR24 UD2.G3
DDR_A_DQS#3: UCPU1.CR20 UD2.B7
DDR_A_DQS#4: UCPU1.BV3 UD4.B7
DDR_A_DQS#5: UCPU1.BP3 UD3.B7
DDR_A_DQS#6: UCPU1.BV9 UD4.G3
DDR_A_DQS#7: UCPU1.BP9 UD3.G3
DDR_A_MA0: RD33.1 UCPU1.CE8 UD1.N3 UD2.N3 UD3.N3 UD4.N3
DDR_A_MA1: RD41.1 UCPU1.CE12 UD1.P7 UD2.P7 UD3.P7 UD4.P7
DDR_A_MA2: RD39.1 UCPU1.CF5 UD1.P3 UD2.P3 UD3.P3 UD4.P3
DDR_A_MA3: RD45.1 UCPU1.CE10 UD1.N2 UD2.N2 UD3.N2 UD4.N2
DDR_A_MA4: RD37.1 UCPU1.CG8 UD1.P8 UD2.P8 UD3.P8 UD4.P8
DDR_A_MA5: RD51.1 UCPU1.CG6 UD1.P2 UD2.P2 UD3.P2 UD4.P2
DDR_A_MA6: RD43.1 UCPU1.CH3 UD1.R8 UD2.R8 UD3.R8 UD4.R8
DDR_A_MA7: RD55.1 UCPU1.CE6 UD1.R2 UD2.R2 UD3.R2 UD4.R2
DDR_A_MA8: RD57.1 UCPU1.CB9 UD1.T8 UD2.T8 UD3.T8 UD4.T8
DDR_A_MA9: RD47.1 UCPU1.CC12 UD1.R3 UD2.R3 UD3.R3 UD4.R3
DDR_A_MA10: RD35.1 UCPU1.CF3 UD1.L7 UD2.L7 UD3.L7 UD4.L7
DDR_A_MA11: RD49.1 UCPU1.CG12 UD1.R7 UD2.R7 UD3.R7 UD4.R7
DDR_A_MA12: RD29.1 UCPU1.CH5 UD1.N7 UD2.N7 UD3.N7 UD4.N7
DDR_A_MA13: RD59.1 UCPU1.CB3 UD1.T3 UD2.T3 UD3.T3 UD4.T3
DDR_A_MA14: RD53.1 UCPU1.CF9 UD1.T7 UD2.T7 UD3.T7 UD4.T7
DDR_A_MA15: RD31.1 UCPU1.CG10 UD1.M7 UD2.M7 UD3.M7 UD4.M7
DDR_A_RAS#: RD63.1 UCPU1.CE2 UD1.J3 UD2.J3 UD3.J3 UD4.J3
DDR_A_WE#: RD69.1 UCPU1.CE4 UD1.L3 UD2.L3 UD3.L3 UD4.L3
DDR_B_BS0: RD74.1 UCPU1.AY11 UD5.M2 UD6.M2 UD7.M2 UD8.M2
DDR_B_BS1: RD70.1 UCPU1.BA12 UD5.N8 UD6.N8 UD7.N8 UD8.N8
DDR_B_BS2: RD72.1 UCPU1.AU2 UD5.M3 UD6.M3 UD7.M3 UD8.M3
DDR_B_CAS#: RD66.1 UCPU1.AW10 UD5.K3 UD6.K3 UD7.K3 UD8.K3
DDR_B_CKE0: RD62.1 UCPU1.BA2 UD5.K9 UD6.K9 UD7.K9 UD8.K9
DDR_B_CKE1: RD78.1 UCPU1.BA4 UD5.J9 UD6.J9 UD7.J9 UD8.J9
DDR_B_CS0#: RD64.1 UCPU1.AR10 UD5.L2 UD6.L2 UD7.L2 UD8.L2
DDR_B_CS1#: RD80.1 UCPU1.AT11 UD5.L1 UD6.L1 UD7.L1 UD8.L1
DDR_B_D0: UCPU1.BK3 UD5.C2
DDR_B_D1: UCPU1.BK5 UD5.C3
DDR_B_D2: UCPU1.BG6 UD5.A2
DDR_B_D3: UCPU1.BJ2 UD5.D7
DDR_B_D4: UCPU1.BJ4 UD5.C8
DDR_B_D5: UCPU1.BJ6 UD5.A3
DDR_B_D6: UCPU1.BG2 UD5.A7
DDR_B_D7: UCPU1.BG4 UD5.B8
DDR_B_D8: UCPU1.BF3 UD6.C8
DDR_B_D9: UCPU1.BF5 UD6.D7
DDR_B_D10: UCPU1.BC6 UD6.A2
DDR_B_D11: UCPU1.BE2 UD6.B8
DDR_B_D12: UCPU1.BE4 UD6.A7
DDR_B_D13: UCPU1.BE6 UD6.A3
DDR_B_D14: UCPU1.BC2 UD6.C3
DDR_B_D15: UCPU1.BC4 UD6.C2
DDR_B_D16: UCPU1.BE10 UD6.F2
DDR_B_D17: UCPU1.BC10 UD6.H3
DDR_B_D18: UCPU1.BE8 UD6.F8
DDR_B_D19: UCPU1.BC8 UD6.G2
DDR_B_D20: UCPU1.BF11 UD6.H8
DDR_B_D21: UCPU1.BC12 UD6.F7
DDR_B_D22: UCPU1.BE12 UD6.E3
DDR_B_D23: UCPU1.BF9 UD6.H7
DDR_B_D24: UCPU1.BJ12 UD5.F7
DDR_B_D25: UCPU1.BG12 UD5.H3
DDR_B_D26: UCPU1.BJ8 UD5.F8
DDR_B_D27: UCPU1.BJ10 UD5.G2
DDR_B_D28: UCPU1.BG8 UD5.E3
DDR_B_D29: UCPU1.BG10 UD5.F2
DDR_B_D30: UCPU1.BK9 UD5.H8
DDR_B_D31: UCPU1.BK11 UD5.H7
DDR_B_D32: UCPU1.AM1 UD8.A7
DDR_B_D33: UCPU1.AH2 UD8.A3
DDR_B_D34: UCPU1.AJ3 UD8.C2
DDR_B_D35: UCPU1.AM5 UD8.C8
DDR_B_D36: UCPU1.AM3 UD8.B8
DDR_B_D37: UCPU1.AJ1 UD8.C3
DDR_B_D38: UCPU1.AJ5 UD8.D7
DDR_B_D39: UCPU1.AH4 UD8.A2
DDR_B_D40: UCPU1.AG3 UD7.A7
DDR_B_D41: UCPU1.AG1 UD7.B8
DDR_B_D42: UCPU1.AD2 UD7.C3
DDR_B_D43: UCPU1.AE3 UD7.D7
DDR_B_D44: UCPU1.AE1 UD7.C8
DDR_B_D45: UCPU1.AG5 UD7.C2
DDR_B_D46: UCPU1.AD4 UD7.A3
DDR_B_D47: UCPU1.AE5 UD7.A2
DDR_B_D48: UCPU1.AM9 UD8.H8
DDR_B_D49: UCPU1.AM7 UD8.H7
DDR_B_D50: UCPU1.AH8 UD8.F2
DDR_B_D51: UCPU1.AJ9 UD8.F8
DDR_B_D52: UCPU1.AM11 UD8.H3
DDR_B_D53: UCPU1.AJ7 UD8.E3
DDR_B_D54: UCPU1.AJ11 UD8.F7
DDR_B_D55: UCPU1.AH10 UD8.G2
DDR_B_D56: UCPU1.AE11 UD7.E3
DDR_B_D57: UCPU1.AG7 UD7.H8
DDR_B_D58: UCPU1.AE7 UD7.H3
DDR_B_D59: UCPU1.AE9 UD7.H7
DDR_B_D60: UCPU1.AG11 UD7.F8
DDR_B_D61: UCPU1.AG9 UD7.F2
DDR_B_D62: UCPU1.AD8 UD7.F7
DDR_B_D63: UCPU1.AD10 UD7.G2
DDR_B_DQS0: UCPU1.BH3 UD5.C7
DDR_B_DQS1: UCPU1.BD3 UD6.C7
DDR_B_DQS2: UCPU1.BD9 UD6.F3
DDR_B_DQS3: UCPU1.BH9 UD5.F3
DDR_B_DQS4: UCPU1.AK4 UD8.C7
DDR_B_DQS5: UCPU1.AF4 UD7.C7
DDR_B_DQS6: UCPU1.AK10 UD8.F3
DDR_B_DQS7: UCPU1.AF10 UD7.F3
DDR_B_DQS#0: UCPU1.BH5 UD5.B7
DDR_B_DQS#1: UCPU1.BD5 UD6.B7
DDR_B_DQS#2: UCPU1.BD11 UD6.G3
DDR_B_DQS#3: UCPU1.BH11 UD5.G3
DDR_B_DQS#4: UCPU1.AK2 UD8.B7
DDR_B_DQS#5: UCPU1.AF2 UD7.B7
DDR_B_DQS#6: UCPU1.AK8 UD8.G3
DDR_B_DQS#7: UCPU1.AF8 UD7.G3
DDR_B_MA0: RD34.1 UCPU1.AT9 UD5.N3 UD6.N3 UD7.N3 UD8.N3
DDR_B_MA1: RD48.1 UCPU1.AR4 UD5.P7 UD6.P7 UD7.P7 UD8.P7
DDR_B_MA2: RD44.1 UCPU1.AU8 UD5.P3 UD6.P3 UD7.P3 UD8.P3
DDR_B_MA3: RD54.1 UCPU1.AR6 UD5.N2 UD6.N2 UD7.N2 UD8.N2
DDR_B_MA4: RD42.1 UCPU1.AT5 UD5.P8 UD6.P8 UD7.P8 UD8.P8
DDR_B_MA5: RD60.1 UCPU1.AT3 UD5.P2 UD6.P2 UD7.P2 UD8.P2
DDR_B_MA6: RD40.1 UCPU1.BA8 UD5.R8 UD6.R8 UD7.R8 UD8.R8
DDR_B_MA7: RD52.1 UCPU1.AY3 UD5.R2 UD6.R2 UD7.R2 UD8.R2
DDR_B_MA8: RD46.1 UCPU1.AW2 UD5.T8 UD6.T8 UD7.T8 UD8.T8
DDR_B_MA9: RD56.1 UCPU1.AY5 UD5.R3 UD6.R3 UD7.R3 UD8.R3
DDR_B_MA10: RD36.1 UCPU1.AY9 UD5.L7 UD6.L7 UD7.L7 UD8.L7
DDR_B_MA11: RD58.1 UCPU1.AU4 UD5.R7 UD6.R7 UD7.R7 UD8.R7
DDR_B_MA12: RD30.1 UCPU1.AU6 UD5.N7 UD6.N7 UD7.N7 UD8.N7
DDR_B_MA13: RD50.1 UCPU1.AW8 UD5.T3 UD6.T3 UD7.T3 UD8.T3
DDR_B_MA14: RD38.1 UCPU1.BA6 UD5.T7 UD6.T7 UD7.T7 UD8.T7
DDR_B_MA15: RD32.1 UCPU1.AR2 UD5.M7 UD6.M7 UD7.M7 UD8.M7
DDR_B_RAS#: RD68.1 UCPU1.BA10 UD5.J3 UD6.J3 UD7.J3 UD8.J3
DDR_B_WE#: RD76.1 UCPU1.AW12 UD5.L3 UD6.L3 UD7.L3 UD8.L3
DDR_CHA_EN: RH99.1 RH102.1 UCPU1.M35
DDR_CHB_EN: RH101.1 RH103.1 UCPU1.F39
DDR_PG_CNTL: UC1.2 UCPU1.BL14
DDR_PWROK: PR604.2 PU600.10 R227.2
DEAD_BATT#: PD701.1 PQ52.2 PQ54.2 PR65.2 PR67.1 PR94.2 U38.B9
DEBUG_UART_TX: JDEG1.9 UCPU1.H38
DEVSLP0: JNGFF2.30 UCPU1.E30
DEVSLP1: JNGFF3.30 T51.1(TP-1) UCPU1.K31
DH_1.35V: PQ600.1 PU600.17
DISPOFF#: D3.1 JLVDS1.22 R44.1
DL_1.35V: PQ600.8 PU600.15
DMIC_CLK: JAUD1.49 R300.1
DMIC_CLK_R: JCAN1.11 MD2.6 R300.2
DMIC_DAT: JAUD1.45 R301.1
DMIC_DAT_R: JCAN1.12 MD2.4 R301.2
DOCKPWROUT: R322.2 U38.M5 U56.5 U57.3
DPWROK: RH64.1 RH72.1 RH74.1 UCPU1.J7
DSWODVREN: RH79.2 RH81.2 UCPU1.G14
DTDK_AC_DET: C272.1 R333.2 R334.1 U38.L3
EC_ALWON: R356.1 U38.E1
EC_GPIO166: R349.1 U38.J2
EC_GPIO222: RP12.8 U38.M7
EC_IN_VOLUMEDOWN#: JSNR1.8 RP16.5 U38.E12
EC_IN_VOLUMEUP#: JSNR1.7 RP16.8 U38.E11
EC_MUTE#: DA8.2 U38.C6
EC_PROCHOT#: Q23.2 U38.M12
EC_SMCA: JBAT1.7 PD3.2 PR1.1
EC_SMDA: JBAT1.6 PD3.3 PR2.1
EC_WAKE#: RH93.2 U38.C12
EC_WAKE#_R: RH93.1 RP8.5 UCPU1.K17
EDP_AUXN: C14.1 UCPU1.AG16
EDP_AUXN_CONN: C14.2 JLVDS1.10
EDP_AUXP: C13.1 UCPU1.AE17
EDP_AUXP_CONN: C13.2 JLVDS1.9
EDP_DISP: RC2.2 UCPU1.Y21
EDP_HPD: JLVDS1.17 RC4.2 UCPU1.W29
EDP_TXN_P0: C9.1 UCPU1.AD17
EDP_TXN_P0_CONN: C9.2 JLVDS1.6
EDP_TXN_P1: C7.1 UCPU1.AG18
EDP_TXN_P1_CONN: C7.2 JLVDS1.3
EDP_TXP_P0: C10.1 UCPU1.AC17
EDP_TXP_P0_CONN: C10.2 JLVDS1.7
EDP_TXP_P1: C8.1 UCPU1.AE18
EDP_TXP_P1_CONN: C8.2 JLVDS1.4
EN_0.675VSP: PC614.1 PR609.1 PU600.7
EN_1.5V: PC400.1 PR400.2 PU400.13
EN_1.8V: PC408.1 PR405.2 PU401.13
EN_1.35V: PC613.1 PR608.1 PU600.8
EN_CAM: R162.2 U25.5 UCPU1.F17
EN_INVPWR: Q3.2 R32.1 R225.2 U7.2 U38.J10
ENBKL: D3.2 RH1.2 UCPU1.BR42
ENVDD: D1.1 R23.1 U6.3
FB: PC523.2 PR550.2 PU702.7
FB_1.5V: PC402.2 PR401.2 PR403.1 PU400.5
FB_1.8V: PC410.2 PR406.2 PR408.1 PU401.5
FB_1.35V: PR605.1 PR607.1 PU600.6
FB_3V: PR300.2 PR302.2 PU300.4
FB_5V: PR301.1 PR303.1 PU300.2
FIVE_EN: JXDP1.45 R8.2 UCPU1.CK40
GNSS_IRQ: R364.2 RC49.1
GNSS_IRQ_L: JNGFF2.36 U53.D3
GNSS_IRQ_R: RC49.2 RP1.8 UCPU1.C39
GNSS_OFF#: Q43.1 UCPU1.F15
GNSS_OFF#_R: JNGFF2.18 Q43.3 R290.2
GNSS_SCL: JNGFF2.32 U53.B3
GNSS_SDA: JNGFF2.34 U53.C3
GPIO88_SLP_S0#: R329.1 UCPU1.M31
H_CATERR#: T2.1(TP-1) UCPU1.CH39
H_CPU_SVIDALRT#: RC26.2 UCPU1.CD43
H_CPU_SVIDCLK: RC27.2 UCPU1.CD41
H_CPU_SVIDDAT: RC28.2 RC33.2 UCPU1.CE40
H_CPUPWRGD_R: RC10.2 UCPU1.CG42
H_DRAMRST#: RC20.1 UCPU1.AB2
H_PECI: R219.2 UCPU1.CK42
H_PROCHOT#: JIO1.12 PC541.1 PQ900.6 PR511.2 PR714.1 PR901.2 Q23.1 RC6.1 RC8.1
H_PROCHOT#_R: RC8.2 UCPU1.CH41
H_THERMTRIP#: Q26.3 RC21.1 RC23.2
H_THERMTRIP#_R: RC23.1 UCPU1.CG40
HDA_BIT_CLK: RP2.8 UCPU1.L6
HDA_RST#: RP2.7 UCPU1.J9
HDA_SDOUT: MC1.1 RH25.2 RP2.5 UCPU1.N3
HDA_SPKR: JAUD1.42 RH126.2 UCPU1.A34
HDA_SYNC: RP2.6 UCPU1.L4
HOME_KEY#: JSNR1.5 RP16.7 U38.H12
HOST_DEBUG_TX: JDEG1.8 R237.2 U38.C9
HOT#: PR511.1 PU702.4
HP_AMP_EN: JAUD1.37 JIO1.42
HW_RST#: D22.1 U58.5
I2C0_SCK: JAUD1.50 JSNR1.21 R362.2 RP22.1 UCPU1.R42
I2C0_SDA: JAUD1.46 JSNR1.22 R363.2 RP22.2 UCPU1.N36
I2C1_SCK: JIO1.30 Q41.6 R338.1 RP22.4 UCPU1.M33
I2C1_SCK_TS: JTS1.3 MD1.1 Q41.1 R338.2 RH166.1
I2C1_SDA: JIO1.32 Q41.3 R339.1 RP22.3 UCPU1.J37
I2C1_SDA_TS: JTS1.4 MD1.3 Q41.4 R339.2 RH167.1
I2C#_LINE_SEL: JIO1.16 Q47.2 R350.2 U38.F10
I2C_READY: JIO1.28 RP16.6 U38.A11
I2S_MCLK: CA57.1 JAUD1.7 RP2.2
I2S_SCLK: JAUD1.3 RP2.1
I2S_SDIN0: JAUD1.9 UCPU1.L10
I2S_SDOUT: JAUD1.11 RP2.4
I2S_SFRM: JAUD1.5 RP2.3
I_ADP: C257.1 PR713.1 U38.M2
I_BATT: C259.1 R228.1 U38.M4
I_SYS: C258.1 PR716.1 U38.M1
ILMT_1.05V: PR504.2 PR507.1 PU500.3
IMON: PC540.2 PR520.2 PU702.3
INV_PWM_R: D4.1 JLVDS1.23 MC5.1 R48.1
IRQ_SERIRQ: RH95.1 U38.L5 UCPU1.E34
ISUMN: PC531.2 PC537.2 PH503.2 PL504.3 PR540.2 PR565.2
ISUMP: PC531.1 PC537.1 PR546.2 PR562.1 PR563.1 PR565.1 PU702.10
JTAG_CLK: JDEG1.4 RP17.3 U38.D9
JTAG_RST#: C161.1 R210.1 R229.2 U38.B10
JTAG_TDI: JDEG1.2 RP17.1 U38.D10
JTAG_TDO: JDEG1.5 RP17.4 U38.C10
JTAG_TMS: JDEG1.3 RP17.2 U38.A10
JTAG_TRST#: RC16.1 T13.1(TP-1) U4.3 UCPU1.CM7 UCPU1.CR39
LAGTE: PQ503.8 PU702.16
LCD_CAB_DET#: RH114.2 UCPU1.J39
LCD_TST: JLVDS1.14 U38.C5
LCD_VCC_TEST_EN: D1.3 R214.2 U38.B12
LDO_3V: PC513.1 PU500.5
LG_3V: PQ300.4 PU300.11
LG_5V: PQ501.4 PU300.15
LID_CL_SIO#: C200.1 R284.2 U38.J1 U46.6 U54.2
LINE1_L: JAUD1.13 JIO1.57
LINE1_R: JAUD1.1 JIO1.59
LINE_PLUG#: JIO1.18 Q47.1 R365.1
LINE_PLUG#_Q: JAUD1.41 Q47.6 R365.2
LPC_AD0: JLPDE1.3 U38.K6 UCPU1.P13
LPC_AD1: JLPDE1.4 U38.L6 UCPU1.M13
LPC_AD2: JLPDE1.5 U38.M6 UCPU1.R14
LPC_AD3: JLPDE1.6 U38.K7 UCPU1.K13
LPC_FRAME#: JLPDE1.7 U38.K5 UCPU1.P15
LX_1.05V: PC505.2 PL501.1 PR502.1 PU500.10
LX_3V: PC305.1 PL301.2 PQ300.3 PQ300.5 PQ300.6 PQ300.7 PR309.1 PU300.8
LX_5V: PC306.2 PL302.1 PQ501.3 PQ501.5 PQ501.6 PQ501.7 PR310.1 PU300.18
M_CLK_A_DDR0: RD83.1 UCPU1.CG2 UD1.J7 UD2.J7 UD3.J7 UD4.J7
M_CLK_A_DDR#0: RD85.1 UCPU1.CG4 UD1.K7 UD2.K7 UD3.K7 UD4.K7
M_CLK_B_DDR0: RD84.1 UCPU1.AW4 UD5.J7 UD6.J7 UD7.J7 UD8.J7
M_CLK_B_DDR#0: RD86.1 UCPU1.AW6 UD5.K7 UD6.K7 UD7.K7 UD8.K7
M_ODT0: RD81.1 UD1.J1 UD1.K1 UD2.J1 UD2.K1 UD3.J1 UD3.K1 UD4.J1 UD4.K1
M_ODT2: RD82.1 UD5.J1 UD5.K1 UD6.J1 UD6.K1 UD7.J1 UD7.K1 UD8.J1 UD8.K1
MASK_LEDS#: JSNR1.4 U54.4
ME_FWP#: Q1.5 R243.2 R244.1 U38.J13
ME_SUS_PWR_ACK: RH68.1 U38.H2
MEC_XTAL1: C157.1 U38.A1 Y3.1
MEC_XTAL2: C158.1 U38.B1 Y3.2
MEM_CONFIG0: RH122.1 RH123.2 UCPU1.N26
MEM_CONFIG1: RH124.1 RH125.2 UCPU1.H31
MEM_CONFIG2: RH120.1 RH121.2 UCPU1.H33
MPHY_PWREN: R172.1 R180.1 R188.1 UCPU1.D29
MPHY_PWREN#: Q12.2 Q12.5 Q13.1 Q14.2 R169.2
MPHY_PWREN_R: Q13.2 R168.2 R172.2 R173.1
MSCLK: JDEG1.6 R236.2 U38.C11
MSDATA: JDEG1.7 R223.1 R239.2 U38.E10
NGFF1_CONFIG_0: JNGFF2.13 RP20.8 U38.G13
NGFF1_CONFIG_1: JNGFF2.61 RP20.7 U38.N13
NGFF1_CONFIG_2: JNGFF2.67 RP20.6 U38.G10
NGFF1_CONFIG_3: JNGFF2.1 RP20.5 U38.L9
NGFF1_SATA_SEL: RH17.1 T24.1(TP-1) U38.K11 UCPU1.L26
NGFF2_CONFIG_0: JNGFF3.13 RP21.8 U38.H11
NGFF2_CONFIG_1: JNGFF3.61 RP21.7 U38.J11
NGFF2_CONFIG_2: JNGFF3.67 RP21.6 U38.K8
NGFF2_CONFIG_3: JNGFF3.1 RP21.5 U38.H10
NGFF_COEX1: JNGFF1.40 JNGFF2.56
NGFF_COEX2: JNGFF1.38 JNGFF2.54
NGFF_COEX3: JNGFF1.36 JNGFF2.52
NGFF_WWAN_PWREN: D18.2 UCPU1.G34
NTC: PR526.1 PU702.5
PANEL_BKEN_EC: D3.3 U38.F2
PBAT_PRES#: PR3.2 PR5.2 PR722.1 U38.M9
PBAT_SMBCLK: PC2.1 PR1.2 RP15.1 U38.C7
PBAT_SMBDAT: PC1.1 PR2.2 RP15.2 U38.D7
PBTN_OUT#_R: R2.2 RH69.2 UCPU1.M21
PCH_ALW_ON: R323.1 R343.1 U38.D5
PCH_APWROK: RH65.1 RP24.7 U38.N7
PCH_DDI1_AUXN: JIO1.31 UCPU1.Y26
PCH_DDI1_AUXP: JIO1.29 UCPU1.W26
PCH_DDI1_CLK: JIO1.63 RP19.7 UCPU1.BP43
PCH_DDI1_DAT: JIO1.61 RP19.8 UCPU1.BN42
PCH_DDI1_HPD: JIO1.14 RH3.2 UCPU1.Y30
PCH_DDI1_N0: JIO1.7 UCPU1.AD25
PCH_DDI1_N1: JIO1.13 UCPU1.AD26
PCH_DDI1_N2: JIO1.19 UCPU1.AG25
PCH_DDI1_N3: JIO1.25 UCPU1.AG26
PCH_DDI1_P0: JIO1.5 UCPU1.AC25
PCH_DDI1_P1: JIO1.11 UCPU1.AC26
PCH_DDI1_P2: JIO1.17 UCPU1.AE25
PCH_DDI1_P3: JIO1.23 UCPU1.AE26
PCH_DDI2_AUXN: CV9.1 UCPU1.Y25
PCH_DDI2_AUXN_C: CV9.2 JNGFF1.12
PCH_DDI2_AUXP: CV10.1 UCPU1.W25
PCH_DDI2_AUXP_C: CV10.2 JNGFF1.14
PCH_DDI2_CLK: RP19.6 UCPU1.BP41
PCH_DDI2_DAT: RP19.5 UCPU1.BR40
PCH_DDI2_HPD: QV1.3 RH4.2 UCPU1.Y29
PCH_DDI2_N0: CV1.1 UCPU1.AD22
PCH_DDI2_N0_C: CV1.2 JNGFF1.24
PCH_DDI2_N1: CV3.1 UCPU1.AG22
PCH_DDI2_N1_C: CV3.2 JNGFF1.18
PCH_DDI2_N2: CV5.1 UCPU1.AD21
PCH_DDI2_N2_C: CV5.2 JNGFF1.17
PCH_DDI2_N3: CV7.1 UCPU1.AG21
PCH_DDI2_N3_C: CV7.2 JNGFF1.11
PCH_DDI2_P0: CV2.1 UCPU1.AC22
PCH_DDI2_P0_C: CV2.2 JNGFF1.26
PCH_DDI2_P1: CV4.1 UCPU1.AE22
PCH_DDI2_P1_C: CV4.2 JNGFF1.20
PCH_DDI2_P2: CV6.1 UCPU1.AC21
PCH_DDI2_P2_C: CV6.2 JNGFF1.19
PCH_DDI2_P3: CV8.1 UCPU1.AE21
PCH_DDI2_P3_C: CV8.2 JNGFF1.13
PCH_DPWROK: RH72.2 U38.A5
PCH_ENVDD: D1.2 RH2.2 U60.1 U60.2 UCPU1.BN40
PCH_GPIO13: RH111.2 UCPU1.E14
PCH_GPIO15: RH100.1 UCPU1.K25
PCH_GPIO18: RH26.2 UCPU1.B33
PCH_GPIO19: RH29.2 UCPU1.H25
PCH_GPIO34: D21.2 RH168.1 T21.1(TP-1) UCPU1.F29
PCH_GPIO64: RH11.2 UCPU1.N34
PCH_GPIO79: RC51.2 UCPU1.J34
PCH_GPIO83: RH176.1 UCPU1.D40
PCH_INTVRMEN: RH23.2 RH24.2 UCPU1.H6
PCH_INV_PWM: D4.3 UCPU1.BM41
PCH_JTAG_JTAGX: RH36.2 RH154.1 RH155.1 T16.1(TP-1) UCPU1.CL16
PCH_JTAG_TCK: RH39.2 RH152.1 RH153.1 T19.1(TP-1) UCPU1.CK17
PCH_JTAG_TDO: RH32.2 RH156.1 RH157.1 T17.1(TP-1) UCPU1.CL18
PCH_MUTE#: DA8.3 UCPU1.M29
PCH_ON: R306.2 R323.2 U26.3
PCH_OPIRCOMP: RC22.1 UCPU1.AB4
PCH_PCIE_WAKE#: RH83.2 U38.G12
PCH_PLTRST#: RH78.2 RH92.2 UCPU1.M23 UH1.1 UH1.2
PCH_PWRBTN#_XDP: JXDP1.41 RH163.2
PCH_RSMRST#: RH67.1 RH74.2 RP24.6 U38.N12
PCH_RSMRST#_R: RH67.2 UCPU1.F7
PCH_RTCRST#: CH3.2 CLRP1.2 JAPS1.10 RH18.2 UCPU1.A8
PCH_RTCX1: CH1.1 RH14.1 UCPU1.C9 YH1.1
PCH_RTCX2: CH2.1 RH14.2 UCPU1.C7 YH1.2
PCH_SATALED#: RH21.2 UCPU1.C30
PCH_SMBCLK: JXDP1.53 QH1.1 RH54.2 RP7.3
PCH_SMBDATA: JXDP1.51 QH1.4 RH57.2 RP7.4
PCH_SPI_CLK: JSPI1.8 RC43.2 RP11.5 UCPU1.C26
PCH_SPI_CS0#: JSPI1.10 RC44.2 UCPU1.H27
PCH_SPI_CS1#: JSPI1.2 RC40.2 UCPU1.M27
PCH_SPI_CS2#: U21.22 UCPU1.K27
PCH_SPI_IO2: JSPI1.12 RC45.2 UCPU1.F27
PCH_SPI_IO3: JSPI1.14 RC46.2 UCPU1.J26
PCH_SPI_SI: JSPI1.6 RC42.2 RP11.6 UCPU1.D31
PCH_SPI_SO: JSPI1.4 RC41.2 RP11.7 UCPU1.B23
PCH_SRTCRST#: CH4.1 RH19.2 UCPU1.D6
PCH_WWAN_WAKE#: R358.1 RH175.2 UCPU1.P23
PCIE_PRX_DTX_N3: JNGFF1.35 UCPU1.AD38
PCIE_PRX_DTX_N5: JNGFF1.59 UCPU1.AF40
PCIE_PRX_DTX_N6: JNGFF2.35 UCPU1.W37
PCIE_PRX_DTX_P3: JNGFF1.33 UCPU1.AC39
PCIE_PRX_DTX_P5: JNGFF1.57 UCPU1.AG41
PCIE_PRX_DTX_P6: JNGFF2.33 UCPU1.Y36
PCIE_PTX_DRX_N3: CH15.1 JNGFF1.29
PCIE_PTX_DRX_N3_C: CH15.2 UCPU1.AY41
PCIE_PTX_DRX_N5: CH9.1 JNGFF1.53
PCIE_PTX_DRX_N5_C: CH9.2 UCPU1.AU40
PCIE_PTX_DRX_N6: C203.1 UCPU1.AB42
PCIE_PTX_DRX_N6_C: C203.2 JNGFF2.39
PCIE_PTX_DRX_P3: CH16.1 JNGFF1.27
PCIE_PTX_DRX_P3_C: CH16.2 UCPU1.AY43
PCIE_PTX_DRX_P5: CH11.1 JNGFF1.51
PCIE_PTX_DRX_P5_C: CH11.2 UCPU1.AU42
PCIE_PTX_DRX_P6: C204.1 UCPU1.AA41
PCIE_PTX_DRX_P6_C: C204.2 JNGFF2.41
PCIE_RCOMP: RH134.2 UCPU1.F41
PCIE_WAKE#: JNGFF1.47 JNGFF1.62 JNGFF2.46 RP12.7 U38.G11
PECI_EC: R219.1 U38.A12
PHASE: PC534.2 PL504.1 PQ503.9 PR548.1 PU702.15
PLT_RST#: JLPDE1.8 JNGFF2.42 JSNR1.12 R366.1 R387.1 RH78.1 RH89.1 RH164.2 U21.16 U38.K3 U51.1 U61.2 UH1.4
PLTRST1#_XDP: JXDP1.46 RH164.1
PM_SYS_RESET#: C1.1 JAPS1.6 JXDP1.48 RH63.1 RH160.1
POWER_SW_IN#: JSNR1.6 R324.1 SW6.3 SW6.4
PQ2_G: PC10.2 PQ2.4 PR58.2 PR77.1 PR78.1
PRGM1: PR514.1 PU702.17
PRGM2: PR518.1 PU702.11
PROC_OPI_COMP: RC36.1 UCPU1.AB6
PROJECT_ID: R340.2 R341.1 U38.N9 U61.1
PROXIMITY_OUT#: JSNR1.15 RP12.6 U38.D4
PS_ID: JIO1.10 PQ101.1 PR105.1 PR130.1
PS_ID_EC: PR102.2 PR103.2 U38.L12
PSID-1: PQ102.2 PR105.2 PR106.1
PSID-2: PQ101.2 PQ102.1 PR104.1
PTP_I2C_BUF_EN: JIO1.26 U38.N11
PWR_LED#: JSNR1.9 U38.B3
PWR_SRC_ON: C11.2 Q2.3 R28.2 R33.1
PWR_SW_IN#: C241.1 R324.2 RP13.8 U38.C2 U58.3
REM_DIODE1_N: C154.2 C163.2 C164.1 Q24.3 Q25.1 Q25.2 U38.E13
REM_DIODE1_P: C154.1 C163.1 C164.2 Q24.1 Q24.2 Q25.3 U38.F13
REM_DIODE2_N: C155.2 C166.2 Q27.3 U38.D13
REM_DIODE2_P: C155.1 C166.1 Q27.1 Q27.2 U38.C13
REM_DIODE3_N: C156.2 C168.2 Q29.3 U38.A13
REM_DIODE3_P: C156.1 C168.1 Q29.1 Q29.2 U38.B13
RESET_OUT#: R202.1 RH179.1 RP24.5 U38.G3 UCPU1.F9
RUN_ON: PR400.1 PR405.1 R142.1 R149.1 R157.2 R369.1 RP13.5 U38.D1
RUNPWROK: R212.2 R213.1 R222.1 R227.1 R240.1 R241.1 U38.F1
RX_DE_0: R318.2 R381.2 U56.16
RX_DE_1: R319.2 R382.2 U56.18
RX_EQ_0: R316.2 R379.2 U56.17
RX_EQ_1: R317.2 R380.2 U56.15
RX_GND: R383.2 U56.6
S3_CONTROL: PQ901.2 PQ901.3 PR9.2 PR10.2 PR48.1 PR79.2
SAR_DPR: JNGFF2.17 R327.2 U38.E4
SATA_MPHY_EN#: Q16.2 Q16.5 Q17.1 Q18.2 R176.2
SATA_RCOMP: RH20.1 UCPU1.L44
SATA_RN1: CS4.1 UCPU1.T37
SATA_RN1_C: CS4.2 JNGFF3.35
SATA_RP1: CS3.1 UCPU1.T39
SATA_RP1_C: CS3.2 JNGFF3.33
SATA_TN1: CS7.1 UCPU1.T43
SATA_TN1_C: CS7.2 JNGFF3.39
SATA_TP1: CS8.1 UCPU1.V42
SATA_TP1_C: CS8.2 JNGFF3.41
SATAMPHY_PWREN: R178.1 RH169.1 T22.1(TP-1) UCPU1.H29
SATAMPHY_PWREN_R: Q17.2 R175.2 R178.2 R180.2 R181.1
SDIO_D0: RH112.2 RH113.1 UCPU1.R40
SENSOR_EN: R155.2 U27.5 UCPU1.L22
SENSOR_HUB_I2C_WAKE: JSNR1.11 UCPU1.B29
SENSOR_I2C_SCL: JSNR1.18 R54.1
SENSOR_I2C_SDA: JSNR1.19 R55.1
SENSOR_INT#: JSNR1.16 RH109.1 UCPU1.M19
SENSOR_RST#: JSNR1.13 UCPU1.L18
SIO_EXT_SCI#: RH12.2 U38.C4 UCPU1.B17
SIO_EXT_SMI#: R357.1 RH16.1 T23.1(TP-1) UCPU1.D33
SIO_EXT_SMI#_R: R357.2 U38.N5
SIO_EXT_WAKE#: RH110.2 U38.L7 UCPU1.F25
SIO_PWRBTN#: JAPS1.8 RH69.1 RH163.1 U38.M13
SIO_RCIN#: RH96.1 U38.D11 UCPU1.C34
SIO_SLP_M#: JAPS1.13 T49.1(TP-1) U38.N1 UCPU1.G18
SIO_SLP_S0#: JAPS1.4 PR913.1 R328.1 RH71.1
SIO_SLP_S0#_R: R328.2 R329.2 U38.J12
SIO_SLP_S3#: JAPS1.17 T48.1(TP-1) U38.L2 UCPU1.N22
SIO_SLP_S4#: JAPS1.14 T47.1(TP-1) U38.A4 UCPU1.H19
SIO_SLP_S5#: JAPS1.15 T46.1(TP-1) UCPU1.A18
SIO_SLP_SUS#: RH73.2 U38.M3
SIO_SLP_WLAN#: T50.1(TP-1) U38.A8 UCPU1.J18
SLP_S0#: RH71.2 UCPU1.G22
SM_INTRUDER#: RH15.2 UCPU1.J5
SM_PG_CTRL: PR609.2 RC17.2 RC18.1 UC1.4
SM_RCOMP0: RC12.1 UCPU1.CV7
SM_RCOMP1: RC13.1 UCPU1.CP7
SM_RCOMP2: RC14.1 UCPU1.CT7
SMBALERT#: RP7.1 UCPU1.K21
SMBCLK: QH1.6 RH54.1 RP5.1 UCPU1.P21
SMBDATA: QH1.3 RH57.1 RP5.2 UCPU1.B21
SML0ALERT#: RP23.1 UCPU1.F21
SML0CLK: RP23.2 UCPU1.P19
SML0DATA: RP23.3 UCPU1.B19
SML1_SMBCLK: RH55.2 U38.D3
SML1_SMBDATA: RH56.2 U38.A7
SML1ALERT#: RP7.2 UCPU1.H8
SML1CLK: RH55.1 RP5.3 UCPU1.C14
SML1DATA: RH56.1 RP5.4 UCPU1.A14
SNB_1.05V: PC502.1 PR502.2
SNUB_1.5V: PC407.1 PR402.2
SNUB_1.8V: PC415.1 PR407.2
SPI_CLK_ROM1: RH46.1 U1.6
SPI_CLK_ROM2: RH52.1 U2.6
SPI_IO2_ROM1: RP4.2 U1.3
SPI_IO2_ROM2: RP6.2 U2.3
SPI_IO3_ROM1: RP4.4 U1.7
SPI_IO3_ROM2: RP6.4 U2.7
SPI_PCH_CLK: JSPI1.7 RC43.1 RH46.2 RH52.2
SPI_PCH_CS0#: JSPI1.9 RC44.1 U1.1
SPI_PCH_CS1#: JSPI1.1 RC40.1 U2.1
SPI_PCH_IO2: JSPI1.11 RC45.1 RH47.2 RP4.7 RP6.7
SPI_PCH_IO3: JSPI1.13 RC46.1 RH48.2 RP4.5 RP6.5
SPI_PCH_SI: JSPI1.5 RC42.1 RP4.6 RP6.6
SPI_PCH_SO: JSPI1.3 RC41.1 RP4.8 RP6.8
SPI_SI_ROM1: RP4.3 U1.5
SPI_SI_ROM2: RP6.3 U2.5
SPI_SO_ROM1: RP4.1 U1.2
SPI_SO_ROM2: RP6.1 U2.2
SPK_L+_C: JAUD1.6 JAUD1.8 JAUD1.10 JAUD1.12 L11.1
SPK_L+_L: CA53.1 DA1.3 JSPK1.3 L11.2
SPK_L-_C: JAUD1.14 JAUD1.16 JAUD1.18 JAUD1.20 L12.1
SPK_L-_L: CA54.1 DA1.2 JSPK1.4 L12.2
SPK_R+_C: JAUD1.22 JAUD1.24 JAUD1.26 JAUD1.28 L13.1
SPK_R+_L: CA55.1 DA5.2 JSPK1.2 L13.2
SPK_R-_C: JAUD1.30 JAUD1.32 JAUD1.34 JAUD1.36 L14.1
SPK_R-_L: CA56.1 DA5.3 JSPK1.1 L14.2
SS_1.5V: PC406.1 PU400.9
SS_1.8V: PC414.1 PU401.9
SSD_PWREN: R192.2 RH105.1 U30.5 UCPU1.K33
SUS_ON: PR608.2 R385.1 RP13.6 U38.N2
SUS_PWR_DN: RH61.1 RH68.2 RP8.7 UCPU1.D8
SUSACK#: RH62.1 U38.L1
SUSACK#_R: RH61.2 RH62.2 UCPU1.D19
SUSCLK: JNGFF2.60 MC2.2 R65.2 R76.2 UCPU1.B27
SVID_ALRT#: PR509.1 PR516.2 PU702.19
SVID_CLK: PR513.1 PR517.2 PU702.20
SVID_DAT: PR510.1 PR515.2 PU702.18
SW_1.5V: PL401.1 PR402.1 PU400.1 PU400.2 PU400.3
SW_1.8V: PL403.1 PR407.1 PU401.1 PU401.2 PU401.3
SW_1.35V: PC604.2 PL601.2 PQ600.9 PR602.1 PU600.16
SYS_LED_MASK#: U38.K13 U54.1
SYS_PWROK: R16.1 U38.D6 UCPU1.A22
SYS_PWROK_XDP: C2.1 JXDP1.47 R14.1 R16.2
SYS_RESET#: RH63.2 RP8.8 UCPU1.E26
SYSCLK: JNGFF2.38 U53.A3
TD_IREF: RC37.1 UCPU1.L40
TESTLOW1: RH170.1 UCPU1.AC33
TESTLOW2: RH171.1 UCPU1.AD33
TESTLOW3: RH172.1 UCPU1.N14
TESTLOW4: RH173.1 UCPU1.M15
THERMATRIP#: C165.1 Q26.1 R233.2 U38.B4
TON_1.35V: PR606.2 PU600.9
TP_A44: T41.1(TP-1) UCPU1.A44
TP_C45: T42.1(TP-1) UCPU1.C45
TP_D2: T43.1(TP-1) UCPU1.D2
TP_D44_C43: UCPU1.C43 UCPU1.D44
TP_F1: T45.1(TP-1) UCPU1.F1
TP_F3_H2: UCPU1.F3 UCPU1.H2
TP_F45_F43: UCPU1.F43 UCPU1.F45
TP_H44: T44.1(TP-1) UCPU1.H44
TP_INT#: JIO1.34 RP1.6 U38.E2 UCPU1.L30
TPM_DET: RH129.2 RH132.1 UCPU1.M25
TPM_IRQ#: RC50.1 U21.20
TPM_IRQ#_R: RC50.2 RP1.5 UCPU1.F31
TPM_SPI_CLK: RP11.4 U21.21
TPM_SPI_SI: RP11.3 U21.23
TPM_SPI_SO: RP11.2 U21.26
TS_EN: R158.2 U27.3 UCPU1.F37
TS_GPIO: JTS1.7 MD1.4 R35.1 R337.1 R371.2 U60.4
TS_INT#: Q5.1 R41.1 RH119.1 UCPU1.F33
TS_INT#_R: JTS1.5 MD1.6 Q5.3 R40.2 R41.2
TS_RST#: R371.1 R388.1 UCPU1.N43
TS_RST#_R: D23.1 JTS1.6 R388.2
TX_BLANKING: JNGFF2.40 T40.1(TP-1)
UAGTE: PQ503.1 PU702.14
UG_3V: PQ300.2 PU300.10
UG_5V: PQ501.2 PU300.16
UIM_CLK: JIO1.53 JNGFF2.24
UIM_DATA: JIO1.38 JNGFF2.26
UIM_DET: JNGFF2.58 Q46.1 R348.1
UIM_DET#: JIO1.40 Q46.2 R70.2 R348.2
UIM_RESET: JIO1.36 JNGFF2.22
USB3_MPHY_EN#: Q20.2 Q20.5 Q21.1 Q22.2 R184.2
USB3MPHY_PWREN: R186.1 UCPU1.J30
USB3MPHY_PWREN_R: Q21.2 R183.2 R186.2 R188.2 R189.1
USB3RN1: C236.2 UCPU1.AJ41
USB3RN1_C: C236.1 U56.11
USB3RN1_RP: JIO1.43 U56.20
USB3RP1: C237.2 UCPU1.AM41
USB3RP1_C: C237.1 U56.12
USB3RP1_RP: JIO1.41 U56.19
USB3TN1: JIO1.37 UCPU1.BG42
USB3TP1: JIO1.35 UCPU1.BG40
USB20_N0: JIO1.49 UCPU1.W12
USB20_N1: JDEBUG.2 UCPU1.T9
USB20_N2: ML10.1 R139.1 UCPU1.Y10
USB20_N2_R: JCAN1.18 MD7.3 ML10.2 R139.2
USB20_N4: ML1.1 R22.1 UCPU1.W9
USB20_N4_R: JCAN1.15 MD7.4 ML1.2 R22.2
USB20_N5: ML6.4 R71.1 UCPU1.V8
USB20_N5_R: JNGFF2.9 ML6.3 R71.2
USB20_N6: ML5.4 R62.1 UCPU1.V6
USB20_N6_R: JNGFF1.5 ML5.3 R62.2
USB20_N7: JUSH1.19 UCPU1.Y6
USB20_P0: JIO1.47 UCPU1.V12
USB20_P1: JDEBUG.3 UCPU1.V10
USB20_P2: ML10.4 R138.1 UCPU1.Y8
USB20_P2_R: JCAN1.17 MD7.1 ML10.3 R138.2
USB20_P4: ML1.4 R20.1 UCPU1.W7
USB20_P4_R: JCAN1.14 MD7.6 ML1.3 R20.2
USB20_P5: ML6.1 R69.1 UCPU1.T7
USB20_P5_R: JNGFF2.7 ML6.2 R69.2
USB20_P6: ML5.1 R60.1 UCPU1.T5
USB20_P6_R: JNGFF1.3 ML5.2 R60.2
USB20_P7: JUSH1.18 UCPU1.W5
USB_OC0#: RP9.1 T35.1(TP-1) UCPU1.E18
USB_OC1#: RP9.4 T36.1(TP-1) UCPU1.E22
USB_OC2#: RP9.2 T37.1(TP-1) UCPU1.H21
USB_OC3#: RP9.3 T38.1(TP-1) UCPU1.D21
USBRBIAS: RH133.1 UCPU1.B13 UCPU1.D13
USH_ALERT#: JUSH1.14 R309.2 U38.L10
USH_DET#: JUSH1.1 RH94.1 UCPU1.L36
USH_ON: R384.1 RH107.1 UCPU1.J14
USH_ON_R: R308.2 R384.2 R385.2 U34.3
USH_PWR_STATE#: JUSH1.5 RZ3.2 U38.K9
USH_RST#: JUSH1.6 R387.2 RZ4.2 RZ5.2 U61.4
USH_SMBCLK: JUSH1.16 RP14.4 U38.B7
USH_SMBDAT: JUSH1.15 RP14.3 U38.D2
V_DDR_REF_CA: CD72.1 RD18.1 UCPU1.AP13
V_DDR_REFA_R: CD73.1 RD23.1 UCPU1.AU14
V_DDR_REFB_R: CD74.1 RD24.1 UCPU1.AT13
V_SYS: PR715.1 R228.2
VGATE: PR512.1 PU702.2 R6.2 R7.2 RC31.1
VPRO: RH177.2 RH178.2 UCPU1.D38
VR12.6_VR_ON: PR519.1 R7.1 RC30.1
VR_ON: PR519.2 PU702.1
VR_ON_MCP: RC30.2 UCPU1.CE42
VR_SVID_ALRT#: PR516.1 RC26.1 RC32.1
VR_SVID_CLK: PR517.1 RC27.1
VR_SVID_DAT: PR515.1 RC28.1
VRPG_MCP: RC31.2 UCPU1.CF43
VS_EN: R148.2 R149.2 U26.5
VSET_1641: C159.1 R230.1 U38.D12
VTTREF_1.35V: PC610.1 PU600.4
WAKE#: RH58.1 RH83.1 UCPU1.F19
WL_OFF#_R: D20.1 JNGFF1.48 R68.1
WLAN_EN: D13.1 R147.2 U29.3
WLAN_ON: D20.3 UCPU1.C18
WLAN_PWR: D13.2 UCPU1.C22
WLAN_RST#: RP1.7 U51.2 UCPU1.K35
WLAN_RST#_Q: JNGFF1.44 JNGFF1.58 R303.1 U51.4
WLAN_WIGIG60GHZ_DIS#: D20.2 U38.M11
WWAN_EN: D18.1 R79.2 U29.5
WWAN_OFF#: Q7.3 UCPU1.F23
WWAN_OFF#_R: JNGFF2.8 Q7.1 R73.2
WWAN_PWR_OFF#: R386.2 UCPU1.J41
WWAN_PWR_OFF#_R: JNGFF2.6 R389.1
WWAN_RST#: R367.1 UCPU1.R38
WWAN_RST#_Q: JNGFF2.59 Q48.3
WWAN_WAKE#: JNGFF2.15 R358.2
XCLK_BIASREF: RH31.1 UCPU1.A38
XDP_BPM0#: JXDP1.21 UCPU1.CM39
XDP_BPM1#: JXDP1.23 UCPU1.CN38
XDP_PIN60: JXDP1.60 R17.1
XDP_PRDY#: JXDP1.5 T9.1(TP-1) UCPU1.CU40
XDP_PREQ#: JXDP1.3 T10.1(TP-1) UCPU1.CR41
XDP_PWRGD: JXDP1.39 R15.2
XDP_TCK0: JXDP1.57 RH148.2 RH153.2 RH154.2
XDP_TCK1: JXDP1.55 RH152.2
XDP_TDI: JXDP1.56 RH28.2 RH158.1 T20.1(TP-1) UCPU1.CL20
XDP_TDI_SWITCH: RH157.2 RH158.2 U4.10
XDP_TDO: JXDP1.52 RH155.2 RH156.2 RH159.2 U4.7
XDP_TMS: JXDP1.58 RH33.2 T18.1(TP-1) U4.13 UCPU1.CK15
XDP_TRST#: JXDP1.54 U4.4
XTAL24_IN: CH6.1 RH27.2 UCPU1.AR44 YH2.3
XTAL24_OUT: CH5.1 RH27.1 UCPU1.AP45 YH2.1
N13240801: PQ900.4 PR902.2 PR903.2 PU900.1
N13240823: PC906.1 PR907.2 PR909.1 PR911.1 PU900.5
N13240827: PQ900.5 PR909.2 PR910.2 PU900.7
N13240889: PQ900.3 PR904.2 PU901.1
N13240891: PU901.2 PU902.4
N13240897: PC904.2 PR906.1 PU902.1 PU902.2
N13240925: PC903.1 PR900.2 PR902.1 PR905.1 PU900.3
N13240953: PC904.1 PQ900.2 PU901.4
N13282828: PQ8.1 PR7.1 PR43.1 PR77.2
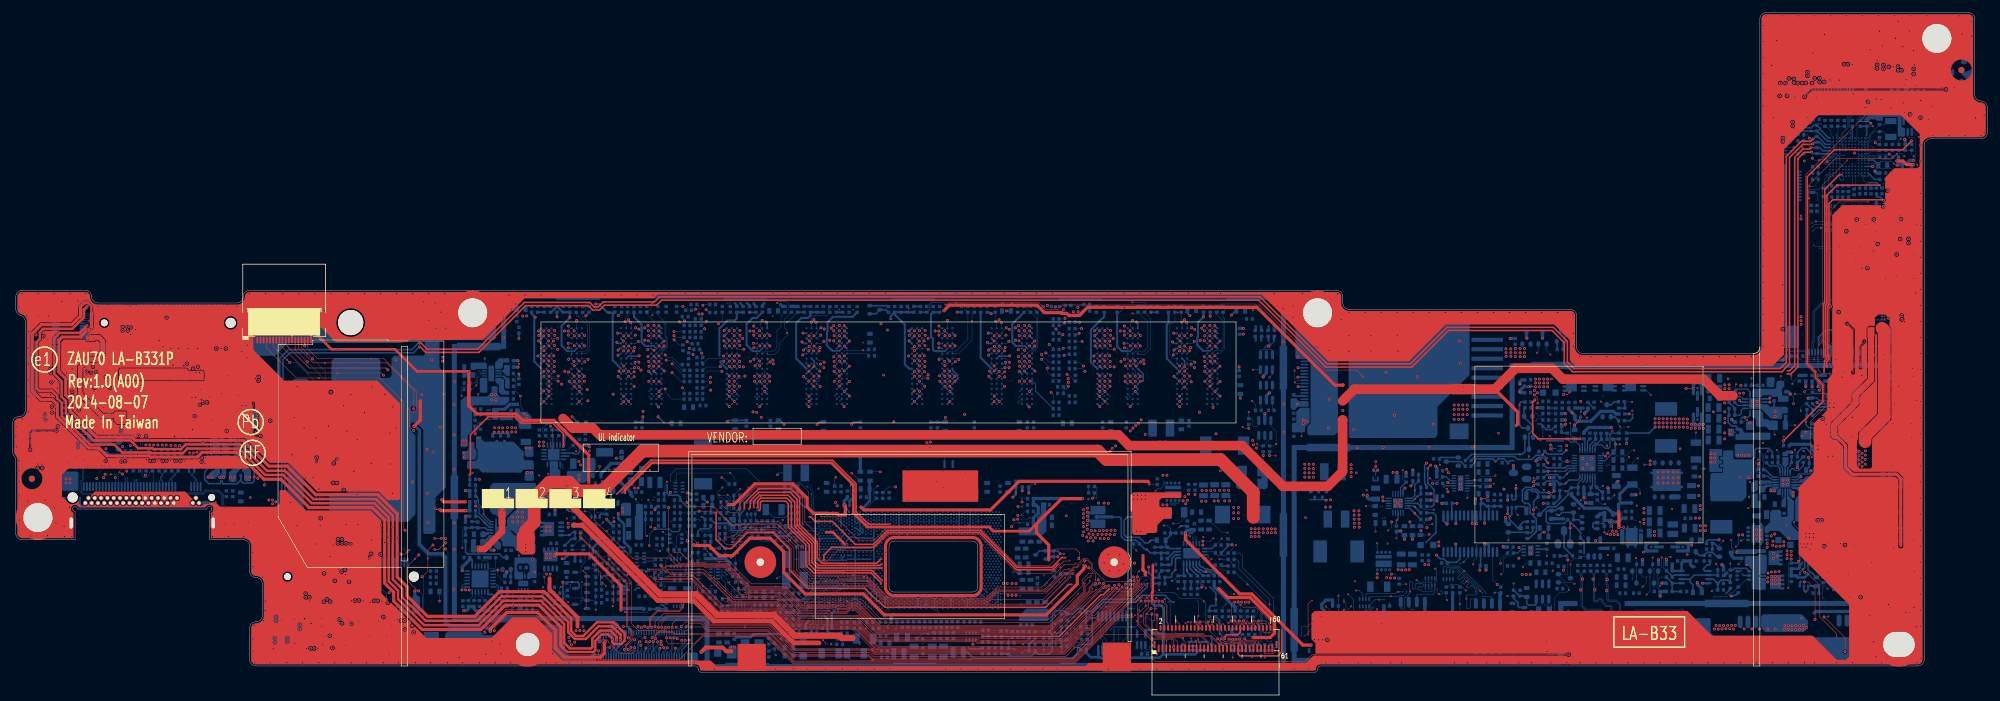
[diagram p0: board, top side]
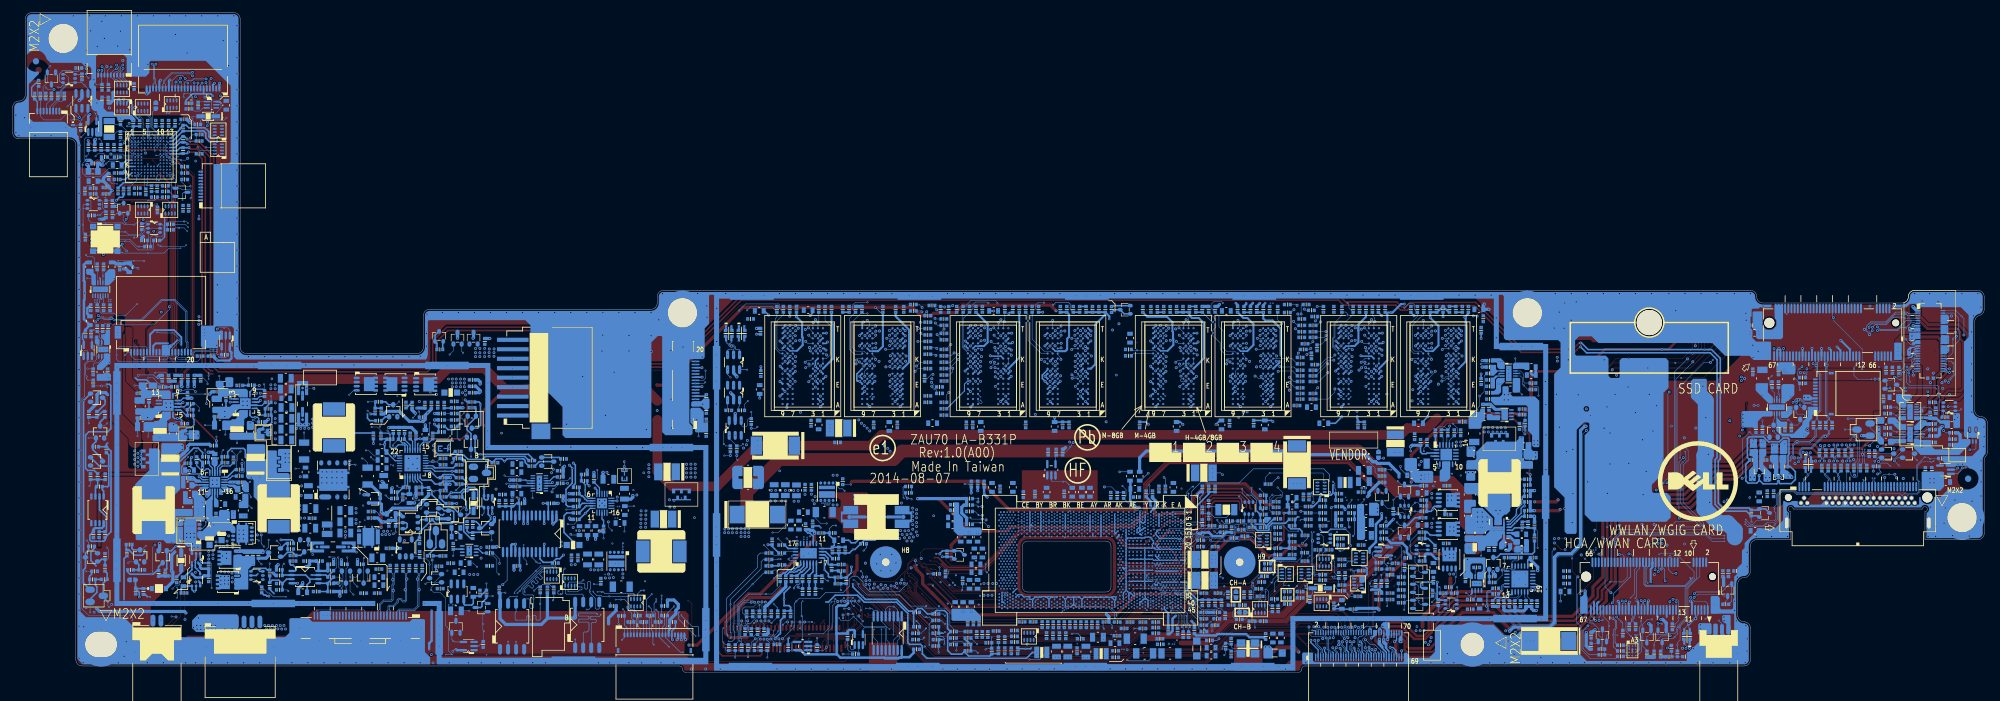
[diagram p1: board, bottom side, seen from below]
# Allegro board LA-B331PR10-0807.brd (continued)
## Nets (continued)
N13290509: PC508.2 PR505.2 PR508.1 PR521.1 PU500.4
N13291543: PQ7.1 PR521.2
N13321827: PQ101.3 PR103.1 PR130.2
N17205976: JDEG1.1 R234.2
N22841841: R291.1 U26.13 U26.14
N34536136: T1.1(TP-1) UCPU1.B25
N35032609: CH35.1 UCPU1.V15
N36180324: CH49.1 RH137.2
N39815594: T3.1(TP-1) UCPU1.CK36
N39815596: T4.1(TP-1) UCPU1.CM37
N39815598: T5.1(TP-1) UCPU1.CN36
N39815600: T6.1(TP-1) UCPU1.CR35
N39815609: T8.1(TP-1) UCPU1.CR34
N39815611: T7.1(TP-1) UCPU1.CN34
N40621945: Q3.1 R33.2
N41500627: C111.1 U28.1
N41500629: R156.1 U28.15
N41500729: R154.1 U28.6 U28.7 U28.8
N41505847: R157.1 U28.16
N41869823: C108.1 U28.17
N42233415: JNGFF1.42 R65.1
N42775202: Q1.1 RH25.1
N43454028: R143.1 U25.13 U25.14
N43599831: Q1.2 Q1.3 R1.1
N44370994: C104.1 U27.12
N44372336: R153.1 U27.8 U27.9
N44373242: C105.1 U27.10
N44377351: C98.1 U26.12
N44380707: C113.1 U29.12
N44531503: C93.1 U25.12
N44535135: C94.1 U25.10
N44948988: RD9.1 UD5.L8
N44951196: RD10.1 UD6.L8
N44953884: RD13.1 UD7.L8
N44956010: RD14.1 UD8.L8
N44984260: RD1.1 UD1.L8
N44985933: RD2.1 UD2.L8
N44994261: RD5.1 UD3.L8
N44996448: RD6.1 UD4.L8
N45067794: CD73.2 RD27.1
N45067802: CD74.2 RD28.1
N45067875: CD72.2 RD20.1
N45134129: RD3.1 UD1.L9
N45134345: RD4.1 UD2.L9
N45134724: RD7.1 UD3.L9
N45134937: RD8.1 UD4.L9
N45136338: RD11.1 UD5.L9
N45136742: RD12.1 UD6.L9
N45137119: RD15.1 UD7.L9
N45137332: RD16.1 UD8.L9
N45346942: C99.1 U26.10
N45347364: C114.1 U29.10
N47519532: R19.1 U6.1
N48029100: PC612.1 PR602.2
N48096052: PR306.1 PU300.19
N48096331: PC305.2 PR307.1
N48096357: PC309.1 PR309.2
N48096365: PC310.1 PR310.2
N48096452: PC306.1 PR308.2
N49570867: PC500.1 PR500.1 PR501.1 PU500.1
N49571039: PC505.1 PR503.2
N49813715: RH73.1 UCPU1.D27
N50118236: C124.1 Q11.4 R170.2 R171.2
N50118262: Q12.3 R170.1
N50118264: Q12.6 R171.1
N50119442: C127.1 Q15.4 R177.2 R179.2
N50119466: Q16.3 R177.1
N50119468: Q16.6 R179.1
N50121680: C130.1 Q19.4 R185.2 R187.2
N50121692: Q20.3 R185.1
N50121694: Q20.6 R187.1
N50198050: CH70.1 CH71.1 LH3.1 RH143.2 RH144.2 RH147.2
N50266102: JNGFF3.60 R76.1
N50817741: PC701.1 PQ700.4 PQ701.4 PR706.1
N50817746: PQ700.2 PR701.1
N50817748: PC700.2 PC701.2 PQ701.3 PR701.2 PR702.1
N50817758: PR706.2 PU700.3
N50817759: PQ701.1 PQ701.2
N50817763: PC721.2 PR41.1 PR720.1 PU700.17
N50817815: PR702.2 PU700.4
N50817862: PC707.2 PQ709.1 PR707.2 PR709.2 PU700.6
N50817876: PR710.2 PR711.2 PR712.1 PU700.5
N50817886: PC715.2 PR713.2 PU700.7
N50817889: PC716.2 PR715.2 PU700.8
N50817892: PR716.2 PR745.1 PU700.9
N50817915: PR714.2 PU700.10
N50817928: PC703.2 PC704.1 PR704.1 PU700.1
N50817929: PR721.2 PR723.1 PU700.16
N50817930: PC702.2 PC703.1 PR703.1 PU700.2
N50817943: PC723.2 PC724.1 PR717.3 PU700.20
N50817947: PC724.2 PC725.1 PR717.2 PU700.19
N50817961: PR722.2 PU700.15
N50817990: PR718.1 PU700.18
N51581707: R161.1 U24.7 U24.8
N51581718: C121.1 U24.6
N51582271: C102.2 R151.2 U30.1 U30.2
N51582977: R292.1 U26.8 U26.9
N51584481: R159.1 U27.13 U27.14
N51589797: R146.1 U29.13 U29.14
N51592304: R160.1 U25.8 U25.9
N51594594: C34.1 U30.12
N51597050: R78.1 U29.8 U29.9
N51600655: R190.1 U33.13 U33.14
N51600691: R193.1 U33.8 U33.9
N51600744: C132.1 U33.12
N51600766: C135.1 U33.10
N52122807: PC10.1 PQ1.1 PQ1.2 PQ1.3 PQ2.1 PQ2.2 PQ2.3 PQ8.3 PR8.1 PR44.1 PR58.1
N52128481: PC11.1 PQ4.1 PQ4.2 PQ4.3 PQ5.1 PQ5.2 PQ5.3 PR12.1
N52131952: PR330.2 PU300.6
N52518612: Q48.2 R390.2 R391.2
N52542818: R362.1 U53.A1 U53.B1
N52542819: R363.1 U53.C1
N52542820: R364.1 U53.D1
N52674055: PQ8.2 PR8.2 PR9.1
N52697183: PD700.1 PR705.1
N52711885: PD1.2 PQ901.4
N53141348: R191.1 U30.8 U30.9
N53141760: C133.1 U30.10
N53209975: PC533.2 PR564.1
N53258922: R310.2 UCPU1.CV27
N53478108: C238.1 U57.6
N53478114: R321.1 U57.7 U57.8
N53657262: R142.2 U25.3
N53764974: PC532.1 PR548.2
N53793451: PR331.1 PU300.20
N53869491: C162.1 R231.2
N54019852: C218.1 U34.6
N54019866: R307.1 U34.7 U34.8
N54349775: PQ1.4 PR43.2 PR44.2 PR45.1
N54350306: PQ53.1 PR48.2
N54350813: PC60.1 PQ53.2 PR60.2
N54351061: PQ54.1 PR60.1 PR61.2
N54351819: PQ51.1 PR95.1
N54351962: PQ51.3 PR62.2 PR93.1
N54352171: PQ51.2 PQ52.1 PR63.2
N54358925: PQ7.2 PR530.2 PR913.2
N54390062: PC70.1 PR72.2 PR75.1 PR80.1 PU904.3
N54390064: PR73.2 PR76.1 PU904.2
N54390136: PQ62.2 PR74.2 PR80.2 PU904.1
N54390171: PR70.1 PR71.1 PR78.2
N54390185: PQ60.2 PR79.1
N54390343: PQ61.2 PQ62.1 PR81.2
N54404550: PQ32.2 PR46.1
N54411628: PQ34.1 PR45.2
N54411650: PR740.1 PU700.21
N54411767: PQ34.2 PR49.1
N54412068: PQ6.2 PR55.2 PR56.2
N54716504: C261.1 U58.1
N54825139: C264.1 U59.6
N54825153: R360.1 U59.7 U59.8
N54916658: Q48.1 R366.2 R367.2
N55068043: PQ60.1 PR71.2
N55068086: PQ61.1 PR70.2
N55263746: R320.1 U56.7
N55267985: PQ30.1 PQ31.2 PR40.2
N55268579: PQ31.1 PR41.2
N55269036: PQ30.2 PR67.2
N55274703: PQ720.2 PR770.2
N55277501: PQ720.1 PR771.1
N55277504: PQ721.2 PR771.2 PR772.1
N55277649: PC760.1 PD701.2 PQ709.2 PQ721.1 PR773.2 PR774.1
N55277894: PQ901.6 PR7.2
N55924880: C273.1 R72.2 R386.1 R389.2
N62111964: Q26.2 R235.2
N93297419: Q4.2 U7.4
N93297423: Q4.1 R39.2
N115444004: PR540.1 PU702.9
N115444061: PC534.1 PR538.1
N115444065: PH504.1 PR526.2 PR529.1
N115444070: PL504.2 PR546.1
N115444157: PC523.1 PR542.2
N115444179: PH503.1 PR563.2

Pads without a net: FD1 1; FD2 1; FD3 1; FD4 1; JAPS1 1 2 3; JBAT1 3; JDEBUG 5 6 7 8 9 10; JIO1 1 4; JLVDS1 1 24 29 30; JNGFF1 6 8 50 52 54 56; JNGFF2 10 12 14 16 20 21 23 27 29 48 50 51 53 55 57; JNGFF3 6 7 8 9 10 12 14 15 16 17 18 20 21 22 23 24 26 27 28 29 32 34 36 38 40 42 44 45 46 47 48 50 51 52 53 54 55 56 57 58 59; JSPI1 17; JUSH1 9 10; JXDP1 40 42; MD2 1 3; MD14 3; PD4 3; PU700 13 14; PU904 5 6 7; Q47 3 4 5; RP11 1 8; RP23 4; RP24 8; U4 1 9; U7 1; U21 5 6 7 13 14 15 27 28; U37 1; U46 1 3 5; U56 2 3 4 8 9 14 22 23 24; U58 4; UC1 1; UCPU1 AA9 AA17 AA18 AA43 AB10 AC18 AC29 AC30 AC34 AD18 AD29 AD30 AD34 AD40 AD42 AE34 AE39 AE41 AE43 AF38 AF42 AG34 AG43 AH38 AH40 AH42 AJ14 AJ22 AJ34 AJ43 AK25 AK33 AK42 AL16 AL18 AL20 AL22 AL24 AL32 AL34 AM43 AP3 AP5 AP9 AP11 AR8 AT41 AT43 AU10 AV41 AV43 AW40 AW42 B15 B31 BA40 BA42 BB41 BB43 BC40 BC42 BD41 BD43 BF41 BF43 BJ14 BJ40 BJ42 BK41 BK43 BT15 BT41 BT43 C5 CA6 CA10 CA12 CB11 CC4 CC6 CC14 CF41 CJ16 CJ22 CJ28 CJ32 CK6 CK13 CK19 CK21 CK23 CK25 CK27 CK31 CL8 CL14 CL22 CL26 CL28 CL34 CM27 CM33 D15 D17 D25 F13 G26 H13 H15 H35 K19 K29 L8 N5 N7 N9 N18 N30 N39 N41 P17 P29 P31 P33 R32 R34 T3 T41 V4 V36 V38 W3 W17 W21 W33 W39 W41 W43 Y4 Y18 Y33 Y34 Y38

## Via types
v1: diameter 0.254, hole 0.102, IN4 to BOTTOM, 1810 vias
v2: diameter 0.305, hole 0.152, TOP to BOTTOM, 543 vias
v3: diameter 0.457, hole 0.203, TOP to BOTTOM, 2310 vias
v4: diameter 0.406, hole 0.203, IN1 to IN4, 1281 vias
v5: diameter 0.254, hole 0.102, TOP to IN1, 178 vias
v6: diameter 0.406, hole 0.203, TOP to BOTTOM, 98 vias
v7: diameter 0.254, hole 0.102, IN4 to GND3, 85 vias
v8: diameter 0.254, hole 0.102, GND3 to BOTTOM, 1366 vias
v9: diameter 0.254, hole 0.102, TOP to GND1, 85 vias
v10: diameter 0.254, hole 0.102, GND1 to IN1, 92 vias
v11: diameter 0.305, hole 0.102, IN4 to BOTTOM, 3 vias
v12: diameter 0.508, hole 0.254, TOP to BOTTOM, 19 vias

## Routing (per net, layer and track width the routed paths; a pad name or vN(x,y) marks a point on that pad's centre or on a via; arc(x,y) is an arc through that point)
1.05V_M_EN: length 2.2
  BOTTOM w0.076: U59.3 74.7,41.06 74.43,40.8 R342.2 R361.2
1.05V_VR_EN: length 30
  TOP w0.254: v3(87.14,35.79) 87.14,37.8 85.47,39.46 80.5,39.46 79.49,40.48 75.28,40.48 v3(73.17,38.36) 72.45,37.64 72.45,31.41 v3(72.35,31.31)
  BOTTOM w0.076: v3(72.35,31.31) 72.5,31.31 v2(72.78,31.59)
  BOTTOM w0.254: v3(87.14,35.79) 87.36,36.01 R369.2 ; v3(72.35,31.31) R343.2 72.35,29.67 PR500.2 ; R368.2 v3(73.17,38.36)
1.05VA_PG: length 333.9
  IN2 w0.076: v4(289.09,6.32) 288.78,6.32 287.43,4.97 266.92,4.97 266.66,5.23 261.04,5.23 259.62,6.65 243.48,6.65 243.14,6.3 237.92,6.3 237.25,6.98 216.74,6.98 216.13,7.59 210.22,7.59 209.74,8.07 205.66,8.07 204.38,9.35 197.1,9.35 196.94,9.19 192.6,9.19 192.5,9.1 185.48,9.1 185.16,8.78 185.16,8.23 184.7,7.77 183.62,7.77 181.94,6.09 171.6,6.09 169.33,8.36 163.04,8.36 162.96,8.44 158.04,8.44 157.95,8.52 157.57,8.52 157.52,8.47 145.08,8.47 143.83,9.73 135.18,9.73 134.43,8.98 133.57,8.98 131.97,7.38 127.49,7.38 126.74,8.14 125.21,8.14 125,8.35 123.85,8.35 122.76,9.44 121.49,9.44 120.03,10.9 115.34,10.9 114.68,11.56 113.79,11.56 112.37,12.98 104.1,12.98 103.93,13.15 102.58,13.15 101.71,14.01 99.53,14.01 96.16,17.38 95.2,17.38 94.59,16.77 92.47,16.77 92.19,16.49 83.56,16.49 83.25,16.81 81.6,16.81 79.86,18.55 73.19,18.55 72.76,18.98 72.76,25.83 v3(73.26,26.33)
  IN4 w0.076: v4(289.09,6.32) 293.17,6.32 293.83,6.97 293.83,11.74 293.95,11.86 297.89,11.86 297.96,11.79 299.92,11.79 300.99,12.85 300.99,20.84 300.79,21.03 300.79,33.48 301.3,33.99 301.3,62.23 296.84,66.7 296.84,68.95 298.47,70.59 298.47,71.92 298.55,72.01 298.55,78.5 297.81,79.24 297.81,82.99 298.44,83.61 v1(298.49,83.61)
  BOTTOM w0.076: v2(298.78,84.5) 298.49,84.21 v1(298.49,83.61)
  BOTTOM w0.203: PU500.2 75.55,23.42 73.79,25.18 73.79,25.99 73.44,26.33 v3(73.26,26.33) PR506.2
1.05VS_PG: length 9.8
  IN4 w0.076: v1(184.67,3.96) 180.03,3.96 v1(179.93,4.06)
  BOTTOM w0.076: U37.2 185.41,4.16 R202.2 ; v1(179.93,4.06) 179.96,4.03 179.96,3.74 179.81,3.59 179.47,3.59 179.25,3.81 U5.1 ; v2(185.2,5.44) R202.2 ; R202.2 184.88,4.36 184.67,4.14 v1(184.67,3.96)
1.5VS_PWROK: length 62.9
  IN1 w0.076: v3(294.76,83.9) 295.59,83.9 296.19,83.3 298.51,83.3 298.98,82.83 298.98,77.11 299.79,76.3 299.79,70.63 299.36,70.2 299.36,66.58 299.79,66.15 299.79,65.22 299.23,64.66 299.23,59.24 296.77,56.78 296.77,54.84 296.19,54.25 296.19,50.35 296.15,50.31 296.15,50.11 294.89,48.85 294.89,44.63 295.32,44.2 295.32,42.11 295.03,41.82 294.37,41.82 293.51,40.96 293.51,40.34 293.18,40.01 286.62,40.01 v3(286.43,40.2)
  BOTTOM w0.076: v3(294.76,83.9) 294.76,83.89 295.04,83.61 R240.2 ; PR404.1 286.04,39.68 v2(286.71,39.68)
  BOTTOM w0.203: PU400.4 287.13,40.43 286.9,40.2 v3(286.43,40.2) 285.99,40.2 285.75,39.96 PR404.1
1.05VS_VCCST_PG: length 46.1
  IN4 w0.066: v1(170.27,28.41) 170.27,27.86 169.58,27.17 169.17,27.17 168.1,26.1 168.1,23.17 167.9,22.98 167.9,15.86 170.79,12.97 178.37,12.97 178.97,12.37 179.15,12.37 179.28,12.24 180.76,12.24 180.91,12.24 181.26,11.89 186.85,11.89 v1(187.48,11.26)
  BOTTOM w0.097: R201.2 189.37,3.45 189.19,3.62 189.19,4.69 189.07,4.81 U37.4 187.74,4.81 187.54,5 187.54,8.82 v2(187.64,8.92) 187.64,11.09 v1(187.48,11.26) ; v1(170.27,28.41) R15.1
1.8VS_PWROK: length 75.8
  IN1 w0.076: v4(296.68,84.09) 297.14,83.63 298.41,83.63 299.13,82.91 299.13,77.2 299.94,76.39 299.94,70.56 299.51,70.13 299.51,66.64 299.94,66.21 299.94,65.15 299.39,64.6 299.39,59.17 296.92,56.71 296.92,54.77 296.34,54.19 296.34,48.76 295.04,47.46 295.04,44.7 295.48,44.26 295.48,42.05 295.1,41.67 294.45,41.67 293.72,40.95 293.72,40.3 293.28,39.86 286.61,39.86 284.12,37.37 283.63,37.37 282.72,38.28 277.43,38.28 275.32,40.39 v3(274.13,40.39)
  IN4 w0.254: v1(296.45,83.61) 296.45,83.86 v4(296.68,84.09)
  BOTTOM w0.076: PR409.1 273.92,39.64 274.27,39.98 v2(274.48,39.98)
  BOTTOM w0.203: PR409.1 273.55,40.21 273.73,40.39 v3(274.13,40.39) 274.65,40.39 274.94,40.68 PU401.4
1.35V_B+: length 6.6
  BOTTOM w0.254: PR606.1 224.81,25.24 225.25,24.81 225.25,22.15 223.63,20.54
  vias: v2(217.59,20.4)
3.3V_NGFF1_EN: length 380
  IN2 w0.076: v3(28.79,40.59) 29.62,40.59 36.66,33.55 51.51,33.55 61.68,23.37 61.68,22.12 69.45,14.34 73.67,14.34 74.66,13.35 74.86,13.35 75.16,13.66 77.18,13.66 77.33,13.51 85.99,13.51 86.49,13.01 92.68,13.01 92.82,13.15 94.08,13.15 95.06,12.17 97.15,12.17 97.89,11.43 99.16,11.43 99.51,11.08 103.08,11.08 103.85,10.32 110.13,10.32 111.69,8.76 119.42,8.76 123.18,5 128.03,5 128.59,4.44 129.64,4.44 130.2,5 133.07,5 134.57,6.49 138.2,6.49 139.34,5.35 152.79,5.35 154.36,3.79 166.85,3.79 167.5,4.44 168.66,4.44 169.24,3.86 197.8,3.86 199.07,5.13 200.63,5.13 202.53,7.04 204.48,7.04 205.66,5.86 213.43,5.86 214.07,5.22 234.99,5.22 236.23,3.98 243.72,3.98 244.7,4.95 259.34,4.95 260.69,3.6 289.01,3.6 292.62,7.21 v4(293.28,7.21)
  IN4 w0.076: v1(292.11,81.63) 292.37,81.89 292.37,82.23 292.51,82.37 292.75,82.37 292.77,82.34 292.99,82.34 293.01,82.37 293.21,82.37 293.35,82.23 293.78,82.23 294.03,82.49 295.06,82.49 295.51,82.04 297,80.55 297,78.08 297.58,77.5 297.58,75.07 297.79,74.87 297.79,71.78 296.53,70.52 296.53,66.57 301,62.1 301,34.11 300.49,33.6 300.49,20.9 300.68,20.71 300.68,12.98 299.79,12.09 298.09,12.09 298.02,12.16 293.82,12.16 293.28,11.62 v4(293.28,7.21)
  BOTTOM w0.076: D18.3 30.27,41.15 30.01,40.89 29.09,40.89 v3(28.79,40.59)
3/5V_B+: length 27.9
  IN1 w0.254: v4(271.05,12.04) 271.66,12.65 272.53,12.65 273.44,11.74 279.5,11.74 280.59,12.83 280.59,15.6 281.9,16.91 281.9,20.4 281.07,21.23 v3(281.06,21.23)
  IN4 w0.254: v1(271.13,12.48) 271.13,12.13 v4(271.05,12.04) 270.34,12.04 269.59,12.79 v1(264.91,12.79)
  BOTTOM w0.254: v1(271.13,12.48) 271.14,12.48 271.81,13.15 PR900.1
  vias: v2(280.73,23.34)
+0.675VS: length 4
  IN4 w0.254: v4(103.92,57.12) 103.77,56.96 103.49,56.96 v1(103.41,57.04) ; v1(105.07,57.04) 104.53,57.04 v4(104.38,56.89) ; v4(162.67,57.04) v1(163.1,57.04) ; v4(169.91,58.11) 170.06,58.26 v1(170.37,58.26) ; v4(171.08,57.96) v1(171.51,57.96) ; v4(163.94,57.04) v1(164.37,57.04)
  BOTTOM w0.102: v3(215.71,32.58) v6(215.71,33.37)
  vias: v1(106.89,56.43) v1(113.07,58.46) v1(113.45,58.46) v3(215.4,32.05) v3(216.01,32.05) v4(112.86,58.77) v4(113.29,58.77) v4(196.89,55.97) v4(197.14,56.35) v4(197.52,55.97)
+0.675VSP:
  vias: v2(214.26,28.85)
+1.5V_B+: length 1.2
  BOTTOM w0.076: PL400.2 v2(293.21,45.42)
+1.05V_M: length 10
  IN1 w0.254: v4(132.38,21.57) 132.37,21.59 132.37,22.33 132.41,22.37 132.41,23.55 131.05,24.91 131.05,26.03 130.83,26.24 130.79,26.24 130.66,26.37 v3(130.5,26.37)
  IN2 w0.254: v4(132.38,21.57) 132.51,21.44 132.51,21.3 132.96,20.85 133.32,20.85 133.34,20.87 134.12,20.87 134.76,21.51 v4(134.88,21.51)
  IN4 w0.203: v7(134.67,21.78) 134.67,21.72 v4(134.88,21.51)
  IN4 w0.254: v1(132.34,21.92) 132.34,21.62 132.38,21.58 v4(132.38,21.57)
  GND3 w0.203: v8(134.99,21.87) 134.75,21.87 v7(134.67,21.78)
  vias: v2(127.52,29.1) v3(80.94,40.94) v3(81.35,40.52) v3(89.6,33.39) v3(89.9,32.86) v3(98.4,29.19) v3(98.98,29.19) v3(130.21,26.9)
+1.05V_SATAMODPHY: length 46.6
  TOP w0.762: 88.76,23.28 90.18,23.28 102.09,11.37 107.77,11.37 111,8.14 120.08,8.14 123.57,4.65 127.61,4.65
  vias: v1(128.65,4.45) v1(128.95,4.45) v2(87.69,24.36) v3(87.92,23.59) v3(87.92,22.98) v4(129.07,4.77) v4(129.49,4.77) v5(128.59,4.74) v5(129.6,4.41)
+1.05V_SATAMODPHY_D: length 4.4
  BOTTOM w0.102: v2(93.43,23.75) 92.95,23.27 Q18.1
  BOTTOM w0.254: Q18.1 91.77,23.27 90.56,24.48 R174.2
+1.05V_USB3MODPHY: length 63.4
  TOP w0.635: v3(108.98,3.22) 109.69,3.93 112.31,3.93 112.91,3.33 113.69,3.33 113.7,3.32 ; 89.39,7.24 89.39,8.69 84.97,13.11 84.97,14.88
  IN2 w0.635: 114.03,4.65 114.03,5.05 114.74,5.76 119.16,5.76 120.24,4.68 120.24,2.91 120.83,2.32 134.24,2.32 135.11,3.19 135.85,3.19 v4(136.25,3.58) ; v3(108.98,3.22) 108.98,2.95 108.57,2.55 105.22,2.55 105.03,2.35 90.66,2.35 89.75,3.27 89.75,5.9
  vias: v1(136.61,3.62) v1(136.99,3.64) v3(84.48,15.55) v3(85.06,15.55) v3(89.15,6.59) v3(89.76,6.61) v3(113.64,4) v3(114.23,4) v6(136.13,3.57)
+1.05V_USB3MODPHY_D: length 3.5
  BOTTOM w0.254: Q22.1 89.48,13.3 89.67,13.49 89.67,14.02 89.42,14.28 v2(88.54,14.28) 87.83,14.28 R182.2
+1.05VA: length 164.9
  TOP w0.432: 162.02,23.53 160.86,22.36 155.19,22.36 154.53,23.02 135.24,23.02 133.04,25.21 133.04,29.69 129.56,33.18 101.15,33.18 96.89,28.91 v5(96.89,28.44)
  TOP w0.508: v3(96.28,9.9) 96.28,13.73 91.25,18.75 86.03,18.75 v3(85.76,18.48) ; v5(163.97,17.8) 163.97,20.16 162.02,22.1 162.02,23.53 166.01,27.51 v3(169.28,27.51)
  IN1 w0.508: v4(96.48,28.04) 96.87,28.44 v5(96.89,28.44) ; v5(163.97,17.8) 164.53,17.8 v4(164.83,17.49)
  IN2 w0.508: v4(181.24,9.67) 181.24,9.95 180.54,10.65 171.68,10.65 v4(164.83,17.49)
  IN4 w0.508: v4(181.24,9.67) 181.56,9.99 186.16,9.99 187.16,8.98 189.93,8.98 191.09,7.82 191.09,7.81 191.22,7.68 191.22,7.54 191.37,7.38 191.37,7.38 191.7,7.05 191.7,7.05 191.72,7.04 191.87,7.04 191.88,7.05 192.62,7.05 192.75,6.93 192.82,6.93 192.91,6.84 v1(192.94,6.84) 193.15,6.84 193.43,7.12 195.26,7.12 195.54,7.39 195.54,8.88 v1(196.36,9.7)
  BOTTOM w0.508: v1(192.94,6.84) 192.94,6.22 193.16,5.99 RH159.1 ; v3(96.28,9.9) 96.5,10.13 99.78,10.13 RH139.1 ; RH28.1 161.53,24.41 161.52,24.43 162.3,25.21 162.3,26.14 161.95,26.49 RH36.1 RH33.1 v3(169.28,27.51)
  vias: v1(86.78,32.34) v1(87.01,32.95) v1(87.01,32.64) v1(87.13,32.37) v1(101.36,27.25) v1(101.56,27.7) v1(113.45,24.48) v1(114.13,23.97) v2(83.33,31.18) v3(76.21,38.03) v3(76.26,38.74) v3(76.95,38.74) v3(76.93,38.04) v3(77.54,38.71) v3(77.58,38.04) v3(78.24,38.05) v3(78.29,38.77) v3(78.98,38.77) v3(78.97,38.07) v3(79.58,38.74) v3(79.61,38.07) v3(83.35,36.48) v3(83.34,35.87) v3(84.02,36.47) v3(84.01,35.87) v3(84.44,23) v3(84.45,22.38) v3(84.5,18.71) v3(84.5,18.13) v3(84.77,27.96) v3(84.8,27.27) v3(85.05,23.03) v3(85.06,22.37) v3(85.1,18.72) v3(85.1,18.14) v3(85.37,27.93) v3(85.39,27.27) v4(86.02,33.34) v4(86.09,32.89) v4(86.52,33.63) v4(86.52,33.23) v4(86.51,32.76) v4(101.91,27.18) v4(102.42,26.81) v4(112.56,24.6) v4(113.07,24.6)
+1.05VDX_MODPHY: length 53.4
  TOP w1.016: 88.45,26.64 88.45,26.37 102.49,12.34 108.17,12.34 111.4,9.11 120.48,9.11 123.78,5.81 130.85,5.81 131.23,5.43 132.88,5.43
  vias: v1(133.59,3.78) v1(133.55,3.1) v3(87.92,28.31) v3(87.92,27.63) v4(133.35,3.42) v4(133.79,3.42) v5(134.05,4.44) v5(134.07,4.78) v6(87.69,29.52)
+1.05VDX_MODPHY_D: length 4
  BOTTOM w0.102: Q14.1 92.77,29.75 v2(93.3,30.28)
  BOTTOM w0.254: Q14.1 92.05,29.56 R167.2
+1.5VS: length 214.3
  IN1 w0.508: v4(294.36,43.09) 294.29,43.02 290.54,43.02 288.35,40.84 284.14,40.84 283.49,40.19 283.49,38.28 v3(283.78,37.99)
  IN2 w0.508: v4(137.01,13.23) 137.7,13.23 138.1,12.83 138.1,12.83 138.42,12.52 138.42,12.51 138.96,11.97 140.42,11.97 141.4,10.99 144.47,10.99 145.58,9.89 169.99,9.89 172.44,7.43 181.13,7.43 184.19,10.49 196.5,10.49 197.35,11.34 211.44,11.34 213.04,9.75 224.86,9.75 225.87,8.74 238.48,8.74 239.1,8.12 250.37,8.12 250.61,7.88 260.32,7.88 261.07,7.13 267.75,7.13 269.33,8.7 284.01,8.7 285.48,7.23 287.6,7.23 288.21,7.84 289.51,7.84 294.64,12.97 294.64,15.52 295.12,16 295.12,18.12 296.1,19.09 296.1,20.92 296.17,20.99 296.17,42.03 295.05,43.16 294.57,43.16 294.52,43.11 294.43,43.11 294.41,43.09 v4(294.36,43.09)
  IN4 w0.254: v4(137.01,13.23) 136.94,13.23 136.79,13.37 v1(136.79,13.99)
  vias: v6(283.14,37.46)
+1.05VS: length 490.1
  TOP w0.254: v5(137.55,14.64) 137.48,14.64 135.99,16.12 127.06,16.12 126.06,17.12 126.06,20.24 123.23,23.06 123.23,26.86 122.5,27.59 118.37,27.59 117.9,27.12 117.9,26.13 v5(117.82,26.04) ; v5(137.46,18) 136.73,17.26 128.12,17.26 127.32,18.07 127.32,20.63 124.53,23.41 124.53,27.68 123.15,29.06 118.06,29.06 115.82,26.83 v5(115.82,25.89) ; v5(137.61,16.58) 137.57,16.58 137.51,16.52 127.38,16.52 126.5,17.39 126.5,20.36 123.77,23.09 123.77,26.99 122.72,28.05 118.22,28.05 117.27,27.09 117.27,26.14 v5(117.29,26.12) ; v5(116.53,25.9) 116.54,25.9 116.72,26.08 116.72,27.16 118.08,28.52 123.04,28.52 124.15,27.4 124.15,23.25 126.9,20.51 126.9,17.54 127.52,16.92 137.25,16.92 137.53,17.2 v5(137.54,17.2) ; v5(118.03,25.63) 118.15,25.63 118.32,25.81 118.32,26.93 118.51,27.12 122.3,27.12 122.74,26.68 122.74,22.99 125.52,20.21 125.52,16.98 126.75,15.75 135.85,15.75 137.46,14.14 v5(137.46,13.96)
  IN1 w0.254: v4(137.28,17.58) 137.28,17.7 137.46,17.89 v5(137.46,18) ; v4(137.34,16.39) 137.41,16.39 v5(137.61,16.58) ; v4(137.81,13.95) 137.46,13.95 v5(137.46,13.96) ; v5(117.29,26.12) 117.27,26.12 117.16,26.23 v4(116.98,26.23) ; v4(117.77,25.34) 117.84,25.41 117.84,25.42 118.03,25.61 v5(118.03,25.63) ; v4(116.98,25.58) 116.87,25.58 116.55,25.9 v5(116.53,25.9) ; v4(116.17,25.61) 115.9,25.89 v5(115.82,25.89) ; v5(117.82,26.04) 117.82,26.03 117.5,25.71 117.47,25.71 v4(117.45,25.68) ; v4(137.31,20.84) 137.23,20.76 136.4,20.76 136.34,20.81 136.17,20.81 135.79,21.2 v4(135.29,21.2) ; v4(137.3,16.92) 137.3,16.96 137.54,17.2 v5(137.54,17.2) ; v5(137.55,14.64) 137.66,14.64 v4(137.84,14.46)
  IN1 w0.508: v4(149.92,3.9) 148.5,5.33 139.87,5.33 139.66,5.53 138.59,5.53 v4(138.36,5.76)
  IN2 w0.254: v4(123.87,15.45) 124.77,15.45 126.84,13.38 127.64,13.38 129.01,14.74 131.68,14.74 v4(131.74,14.68) ; v4(293.41,13.52) 293.09,13.52 291.76,12.18 291.76,11.47 288.96,8.68 287.46,8.68 286.28,9.86 273.94,9.86 271.94,11.85 v3(271.94,12.07) 271.51,11.64 270.94,11.64 267.71,8.41 261.15,8.41 260.13,9.43 246.78,9.43 246.67,9.54 226.97,9.54 224.06,12.45 215.31,12.45 214.6,13.16 v4(202.74,13.16)
  IN3 w0.254: v4(287.88,86.96) 288.45,86.96 288.78,86.63 288.78,85.18 289.44,84.52 295.68,84.52 299.45,80.75 299.45,74.55 299.06,74.15 298.6,74.15 298.07,73.62 298.07,73.61 v4(296.71,72.26) ; v4(133.15,21.25) 133.15,21.19 132.73,20.77 131.89,20.77 131.74,20.62 131.74,20.01 131.94,19.8 132.06,19.8 132.42,19.44 v4(132.42,19.35)
  IN4 w0.203: v4(133.15,21.25) 133.12,21.28 132.79,21.28 132.61,21.1 132.45,21.1 132.17,20.82 131.43,20.82 v1(131.38,20.77)
  IN4 w0.254: v1(136.79,20.92) 137.19,20.92 137.27,20.84 v4(137.31,20.84) ; v1(288.61,84.13) 288.48,84.13 287.64,84.97 287.64,86.33 v1(287.82,86.5) 287.88,86.57 v4(287.88,86.96) ; v1(296.71,72.94) v4(296.71,72.26) 295.52,71.06 295.52,69.53 295.67,69.37 295.67,67.6 294.87,66.79 294.87,65.85 295.12,65.6 296.08,65.6 299.99,61.69 299.99,34.53 299.48,34.02 299.48,20.49 299.68,20.3 299.68,16.06 298.43,14.81 297.39,14.81 296.09,13.51 293.42,13.51 v4(293.41,13.52) ; v1(137.04,14.43) 137.52,13.95 v4(137.81,13.95) ; v4(137.28,17.58) 137.21,17.65 137.21,17.66 137.04,17.82 v1(137.04,17.89) ; 88.75,32.25 88.75,35.49 v1(85.86,38.37) 85.84,38.37 85.81,38.4 v1(84.36,38.4) ; v4(137.34,16.39) 137.27,16.39 136.8,15.92 136.8,15.73 v1(136.79,15.72) ; v4(125.92,25.77) 125.61,26.08 125.58,26.08 v1(125.45,26.21) ; v1(136.61,16.27) 136.62,16.27 136.9,16.55 136.9,16.67 137.16,16.92 v4(137.3,16.92) ; v1(132.12,18.51) 132.12,18.82 132.4,19.1 132.4,19.2 132.42,19.22 v4(132.42,19.35) ; v4(149.92,3.9) 149.92,3.32 150.1,3.14 v1(150.44,3.14) ; v1(136.29,12.38) 136.31,12.37 136.37,12.37 v4(136.96,11.78) 137.19,11.55 v1(137.29,11.55) ; v1(137.29,14.86) 137.3,14.86 137.7,14.46 v4(137.84,14.46) ; v4(131.74,14.68) 131.72,14.71 v1(131.38,14.71) ; v3(192.97,20.21) 192.97,19.17 191.96,18.15 191.96,17.72 v1(191.25,17.01) 191.27,16.98 191.27,16.57 189.49,14.79 v1(189.49,13.49) ; v4(202.74,13.16) 201.72,13.16 199.04,10.47 197.38,10.47 197.11,10.21 190.77,10.21 v1(190.42,10.56) 186.95,10.56 186.38,11.13 v1(183.81,11.13)
  BOTTOM w0.254: v3(271.94,12.07) 272.29,12.07 272.45,12.24 272.73,12.24 PR901.1 ; RH161.1 CH90.1 189.39,10.32 189.64,10.56 v1(190.42,10.56) v6(190.42,11.56) 190.42,12.55 189.49,13.48 v1(189.49,13.49) ; v1(136.61,16.27) 136.61,16.41 UCPU1.AJ26 ; RH135.1 109.32,27.45 109.8,26.97 v3(109.95,26.97) ; PR509.2 191.4,16.86 v1(191.25,17.01) ; v1(85.86,38.37) 85.89,38.4 C108.2 ; v1(125.45,26.21) 125.26,26.21 123.23,28.24 CH88.1 CH59.1 ; PR510.2 192.31,19.96 PC559.2 v3(192.97,20.21) ; UCPU1.Y22 v1(132.12,18.51) ; v1(150.44,3.14) 151.13,3.14 152.06,2.21 167.83,2.21 168.54,2.93 168.54,4.15 168.82,4.42 170.57,4.42 170.84,4.69 170.84,9.31 172.63,11.1 177.72,11.1 178.83,12.21 182.32,12.21 183.4,11.13 v1(183.81,11.13)
  vias: v1(88.45,31.31) v1(88.45,30.9) v1(88.45,30.5) v1(89.01,31.34) v1(89.01,30.93) v1(89.01,30.5) v1(123.87,17.89) v1(124.27,17.9) v1(124.25,15.54) v1(124.8,17.87) v1(124.8,15.44) v1(134.99,22.37) v1(137.95,6.46) v1(138.67,5.99) v3(89.62,31.21) v3(89.65,30.57) v3(96.52,26) v3(96.52,25.39) v4(88.4,31.74) v4(88.73,31.13) v4(88.73,30.7) v4(88.91,31.77) v4(89.42,31.77) v4(123.18,17.49) v4(123.4,15.45) v4(123.66,17.49) v4(137.75,5.76) v4(137.88,12.3)
+1.05VS_VCCST: length 157.6
  TOP w0.254: v3(111.31,25.19) 111.31,21.01 112.71,19.61 113.76,19.61 115.71,21.56 115.71,21.58 116.25,22.13 120.29,22.13 122.95,19.48 122.95,16.18 125.83,13.3 134.85,13.3 136.85,11.3 v5(136.89,11.3) 137.06,11.3 138.05,10.3 163.48,10.3 167.1,13.92 v5(167.61,13.92)
  IN1 w0.254: v4(137.45,19.08) 137.45,18.97 136.7,18.22 136.7,17.33 136.89,17.14 136.89,15.68 137.23,15.34 137.88,15.34 138.25,14.97 138.25,13.25 137.37,12.37 137.37,11.61 137.13,11.37 136.97,11.37 v5(136.89,11.3) ; v4(178.14,15.98) 178.13,15.97 176.93,15.97 176.41,15.45 172.46,15.45 171.77,16.15 170.76,16.15 170.45,15.84 170,15.84 169.9,15.74 169.67,15.74 167.85,13.92 v5(167.61,13.92)
  IN4 w0.254: v4(178.14,15.98) 178.22,15.98 178.45,15.75 178.69,15.75 179.08,15.36 179.08,14.46 v1(179.54,14) ; v4(137.45,19.08) 137.42,19.08 137.32,19.19 v1(136.79,19.19) ; v1(169.91,7.21) 169.68,6.98 v4(169.68,6.82) 170.08,6.43 173.22,6.43 173.74,5.91 178.79,5.91 179.1,6.21 182.7,6.21 182.95,6.47 183.78,6.47 184.33,5.91 185.69,5.91 186.4,5.2 189.34,5.2 v1(189.6,5.45)
  BOTTOM w0.254: v3(111.31,25.19) 111.26,25.24 CH21.1 110.48,26.14 CH20.1 RH135.2 ; RC6.2 169.29,10.11 168.6,10.11 167.73,9.24 R8.1 166.32,9.78 165.03,9.78 164.55,9.3 164.55,6.93 RC21.2 164.53,5.99 164.53,3.46 163.94,2.88 162.3,2.88 R6.1 161.78,3.14 161.22,2.58 157.88,2.58 RC33.1 157.52,2.94 RC32.2 ; RC6.2 v1(169.91,7.21) ; RC6.2 170.1,9.68 170.71,9.68 172.58,11.55 177.54,11.55 v6(178.05,12.06) 179.54,13.55 v1(179.54,14) ; v1(189.6,5.45) 189.77,5.28 R201.1
+1.05VS_XDP: length 29.8
  TOP w0.254: v5(200.84,6.7) 200.84,3.25 200.18,2.59 194.21,2.59 193.96,2.84 JXDP1.43 ; JXDP1.44 194.26,6.3 193.89,5.93 192.12,5.93 191.82,5.63 v3(191.82,5.3)
  IN1 w0.254: v5(200.84,6.7) 200.62,6.48 v4(200.62,6.25)
  IN2 w0.254: v4(200.62,6.25) 200.2,5.83 198.74,5.83 197.55,4.65 192.42,4.65 191.82,5.24 v3(191.82,5.3)
  BOTTOM w0.254: v3(191.82,5.3) 191.82,5.37 191.11,6.09 v2(191.11,6.09) 190.99,6.2 190.99,8.22 RH161.2
+1.5VSP: length 15.4
  IN4 w0.508: v1(289.37,42.55) 291.77,42.55 292.52,41.8 292.52,37.71 292.52,37.7 292.52,37.69 292.07,37.24 v1(289.18,37.24)
  BOTTOM w0.203: PR401.1 283.93,41.58 PC402.1 283.93,40.17 283.79,40.04 v2(283.79,39.62) 283.79,39.2 284.26,38.74
  BOTTOM w0.254: 285.28,38.35 284.89,38.74 284.26,38.74
+1.05VSP: length 14
  IN4 w0.254: v1(73.65,34.64) 71.03,32.02 71.03,24.63 71.79,23.87 v1(72.68,23.87)
  BOTTOM w0.254: PC508.1 73.54,23.87 v1(72.68,23.87)
  vias: v2(73.68,37.16)
+1.8V_B+: length 1.2
  BOTTOM w0.076: PL402.2 v2(279.81,46.92)
+1.8VS: length 406.6
  IN1 w0.635: 293.3,43.86 287.55,43.86 285.35,41.66 284.52,41.66 284.16,42.02 278.36,42.02 277.75,41.41 273.84,41.41 273.35,40.92 273.35,38.87 272.65,38.17 ; v4(53.16,27.75) 63.09,27.75 68.03,22.81 v4(68.03,22.64)
  IN2 w0.635: 44.24,26.89 44.49,27.14 46.06,27.14 46.67,27.75 v4(53.16,27.75) ; v4(74.65,19.06) 75.57,19.98 79.1,19.98 81.84,17.24 83.42,17.24 83.74,16.92 87.84,16.92 89.65,18.72 95.43,18.72 99.68,14.47 101.87,14.47 102.75,13.58 104.5,13.58 105.74,13.58 106.2,14.04 107.21,14.04 107.67,13.58 112.41,13.58 113.22,12.77 114.12,12.77 115.54,11.34 120.24,11.34 121.33,10.25 121.52,10.25 v4(121.75,10.25) 122.08,9.92 124.28,9.92 125.44,8.76 127.38,8.76 128.18,7.97 131.56,7.97 134.59,10.99 138.02,10.99 138.67,10.35 144.2,10.35 145.31,9.24 169.72,9.24 172.17,6.79 181.4,6.79 184.46,9.85 196.77,9.85 197.62,10.7 211.18,10.7 212.77,9.1 224.4,9.1 225.45,8.06 237.16,8.06 237.74,7.47 250.1,7.47 250.34,7.23 260.06,7.23 261.47,5.82 266.93,5.82 267.18,5.57 286.93,5.57 288.54,7.18 289.77,7.18 295.31,12.73 295.31,14.59 296,15.28 296,18.08 296.75,18.83 296.75,20.44 296.82,20.51 296.82,42.44 295.4,43.86 295.01,43.86 295.03,43.88 ; 5.31,39.2 5.31,37.43 14.11,28.63 21.76,28.63 22.21,29.07 33.69,29.07 37.6,25.16 40.68,25.16 ; 42.06,24.51 42.06,24.02 44.65,21.43 44.65,9.35 47.89,6.11 49.39,6.11 v4(49.44,6.06)
  IN3 w0.635: v4(74.65,19.06) 74.65,18.78 74.05,18.18 72.55,18.18 68.1,22.64 v4(68.03,22.64)
  IN4 w0.254: v1(56.17,3.15) 55.87,2.85 55.6,2.85 55.56,2.81
  IN4 w0.635: 55.56,2.81 55.18,2.43 v1(53.88,2.43) v1(52.74,2.43) 52.74,2.77 50.61,4.91 49.96,4.91 49.44,5.43 v4(49.44,6.06) ; v4(121.75,10.25) 121.45,10.56 v1(121.19,10.56)
  BOTTOM w0.254: U53.B2 v1(56.17,3.15)
  BOTTOM w0.635: v1(52.74,2.43) v1(53.88,2.43)
  vias: v2(4.7,40.37) v3(5.1,40.84) v3(5.17,40.02) v3(271.84,38.32) v3(271.82,37.74) v4(42.65,25.1) v4(43.12,24.63) v4(43.61,26.55) v4(43.99,26.23) v4(294.27,44.16) v4(294.33,43.68)
+1.8VS_AUDIO: length 15
  IN4 w0.508: v1(13.9,40.18) 13.9,45.24 13.16,45.99 13.16,46.6 13.96,47.4 13.96,48.38 v4(13.92,48.42) 13.92,48.59 13.09,49.42 13.09,50.75 11.88,51.95 v1(11.75,51.95)
  BOTTOM w0.076: v1(11.75,51.95) 12.2,51.95 12.85,52.61 v2(12.85,52.8)
+1.8VSP: length 18.8
  IN4 w0.254: v1(273.75,37.89) 279.69,37.89 280.02,38.22 280.02,42.03 279.49,42.56 278.3,42.56 v3(278.08,42.78)
  BOTTOM w0.076: PL403.2 v2(276.99,36.32)
  BOTTOM w0.203: PU401.14 278.06,42.8 v3(278.08,42.78)
  BOTTOM w0.254: PR406.1 PC410.1 271.49,40.61 271.49,39.58 272.07,38.99 272.7,38.99 273.09,38.61
+1.35V_DDR: length 128.3
  IN1 w0.254: v4(119.01,49.32) 119.29,49.32 v5(119.49,49.52) ; v4(135.02,52.23) v5(134.59,52.23) ; v5(184.39,56.99) v4(184.39,57.96) ; v5(120.28,56.41) 120.15,56.53 v4(120.15,56.89) ; v5(129.22,57.5) 128.89,57.83 128.78,57.83 v4(128.76,57.85) ; v5(159.07,57.04) v4(159.55,57.04) ; v5(180.17,57) 180.17,57.08 180.5,57.42 v4(180.58,57.42) ; v4(142.1,58.03) 141.81,57.74 v5(141.81,57.6) ; v5(100.37,57.14) 100.26,57.04 v4(99.83,57.04) ; v4(130.82,57.04) v5(130.82,57.47) ; v4(117.16,57.02) v5(116.66,57.02) ; v4(108.67,49.19) v5(109.05,49.19) ; v4(133.03,57.04) v5(133.03,57.42)
  IN4 w0.254: v4(159.55,57.04) v1(159.04,57.04) ; v1(183.93,57.96) v4(184.39,57.96) ; v4(142.1,58.03) 142.02,57.96 v1(141.62,57.96) ; v1(108.29,48.86) 108.34,48.86 v4(108.67,49.19) ; v4(119.01,49.32) 118.63,49.7 v1(118.61,49.7) ; v1(116.62,57.02) v4(117.16,57.02) ; v4(145.8,27.49) 145.91,27.49 146.09,27.68 v1(146.09,27.81) ; v1(132.37,57.04) v4(133.03,57.04) ; v1(119.73,57.24) 119.8,57.24 v4(120.15,56.89) ; v1(128.31,57.96) 128.61,57.96 128.72,57.85 v4(128.76,57.85) ; v1(135.67,52.23) v4(135.02,52.23) ; v1(180.12,57.04) 180.5,57.42 v4(180.58,57.42) ; v1(143.24,21.59) 143.24,21.59 143.24,21.59 143.16,21.59 143.15,21.6 143.13,21.6 142.96,21.43 v4(142.96,21.41) ; v1(130.34,57.04) v4(130.82,57.04) ; v1(99.35,57.04) v4(99.83,57.04)
  BOTTOM w0.102: UD7.F1 v3(84.07,46.9) ; v3(172.05,46.1) 172.05,46.11 171.66,46.5 UD1.F1 ; UD3.F1 v3(142.72,46.9) ; UD6.F1 v3(113.41,46.1)
  BOTTOM w0.203: v1(141.57,21.54) UCPU1.BA14
  BOTTOM w0.254: v3(189.52,56.41) CD9.1 ; UD3.N9 148.74,52.1 v3(149.14,51.7) ; v3(119.83,53.34) 119.47,53.7 UD6.R9 ; UD5.F1 125.54,46.5 v3(125.17,46.88) ; v3(122.07,39.27) 121.45,39.89 CD51.1 ; UD7.K8 89.62,49.35 89.62,49.34 v3(89.65,49.32) ; v3(155.33,47.74) 155.7,48.1 UD4.H2 ; UD1.C9 v3(177.65,44.5) ; UD7.H2 84.47,48.07 84.82,47.73 v3(84.82,47.7) ; v3(112.56,52.5) 112.96,52.1 UD6.N1 ; CD46.1 114.35,39.91 CD70.1 113.24,39.89 v3(113.07,39.72) ; v3(90.49,51.7) 90.1,52.1 UD7.N9 ; UD6.G7 v3(118.21,46.9) ; v3(129.99,47.68) 130.37,47.3 UD5.G7 ; UD1.K2 172.85,49.3 v3(172.85,49.3) ; v3(90.5,53.34) 90.14,53.7 UD7.R9 ; UD2.A8 189.98,42.39 v3(189.98,41.95) ; UD5.N1 125.14,52.1 v3(124.91,52.33) ; UD4.G7 159.68,47.3 v3(159.3,47.68) ; v3(143.51,43.76) 143.12,43.37 UD3.B2 ; UD3.C9 v3(148.32,44.5) ; UD7.A1 v3(84.07,42.9) ; v3(155.33,42.88) 154.95,42.5 UD4.A1 ; UD8.D9 102.3,44.51 v3(102.3,44.48) ; UD4.F1 154.85,46.5 v3(154.48,46.88) ; UD7.K2 84.87,49.3 v3(84.87,49.3) ; v3(112.6,53.3) 112.62,53.3 113.01,53.69 UD6.R1 ; UD8.C9 102.68,44.08 v3(102.3,43.69) ; v3(149.14,53.34) 148.78,53.7 UD3.R9 ; v3(154.39,53.72) 154.41,53.7 UD4.R1 ; UD2.H9 191.05,48.49 v3(191.05,48.49) ; UD5.H9 132.03,48.1 132.41,48.48 v3(132.41,48.49) ; UD4.H9 161.39,48.1 v3(161.77,47.72) ; UD1.R9 178.12,53.7 v3(178.48,53.34) ; v1(130.34,57.04) 131.34,57.04 CD49.1 ; UD1.B2 v3(172.85,42.9) ; UD1.R1 171.65,53.69 171.27,53.3 v3(171.24,53.3) ; v3(96.69,47.74) 97.05,48.1 UD8.H2 ; UD2.F1 184.19,46.5 v3(183.81,46.88) ; v3(99.73,40.48) 99.73,40.16 99.62,40.04 99.62,39.66 CD67.1 CD64.1 ; UD3.A1 142.32,42.5 v3(142.72,42.9) ; RD17.1 v3(86.14,56.33) ; UD6.C1 v3(113.41,43.7) ; UD2.D9 190.28,44.51 v3(190.28,44.48) ; UD8.R9 102.67,53.7 v3(102.29,54.08) ; v3(88.56,40.48) 89.32,39.71 CD66.1 ; UD1.K8 177.25,49.7 v3(177.63,49.32) ; UD3.E9 v3(149.12,46.1) 149.55,46.53 149.55,47.08 148.72,47.91 UD3.H9 ; UD8.K8 101.86,49.7 v3(101.48,50.08) ; UD2.E9 190.66,45.71 191.02,46.06 v3(191.08,46.06) ; UD1.N1 171.61,52.1 v3(171.21,52.5) ; v3(176.85,46.9) UD1.G7 ; UD6.N9 119.43,52.1 v3(119.83,51.7) ; UD5.C9 132.08,44.1 132.42,43.76 v3(132.42,43.76) ; UD7.C1 83.67,44.21 v3(84.04,44.58) ; UD8.K2 97.47,50.08 99.07,50.08 v3(99.14,50.14) ; UD2.N1 183.79,52.1 v3(183.55,52.33) ; UD8.H9 102.75,48.1 v3(103.13,47.72) ; v3(156.14,42.9) 155.74,43.3 UD4.B2 ; UD1.A8 v3(176.85,42.1) ; UD7.D9 v3(89.67,45.3) ; CD61.1 v3(80.11,52.88) ; UD2.K8 189.84,49.7 v3(189.46,50.08) ; v3(132.78,39.29) 133.14,39.65 CD43.1 ; UD5.B2 126.42,43.3 v3(126.04,42.92) ; v3(142.68,44.58) 142.32,44.21 UD3.C1 ; v3(96.68,42.88) 96.66,42.88 96.29,42.5 UD8.A1 ; UD3.N1 142.27,52.1 v3(141.87,52.5) ; UD2.C9 190.7,44.1 191.04,43.76 v3(191.07,43.76) ; v3(149.49,57.04) CD25.1 ; CD62.1 v3(80.11,47.25) ; UD8.A8 101.86,42.48 101.86,42.39 v3(102.22,42.04) ; v3(192.87,56.58) 192.87,56.59 193.52,57.24 CD16.1 ; UD6.B2 v3(114.21,42.9) ; UD6.K2 114.21,49.3 v3(114.21,49.3) ; v3(141.9,53.36) 142.24,53.7 UD3.R1 ; UD6.D2 v3(114.21,44.5) ; UD2.A1 v3(184.69,42.08) ; UD1.A1 v3(172.05,42.1) ; UD6.A8 v3(118.21,42.1) ; UD2.N9 190.69,52.1 v3(191.06,52.48) ; CD13.1 185.9,56.9 v3(186.29,56.51) ; v3(90.71,56.48) 91.22,56.99 CD68.1 ; v3(148.32,45.3) UD3.D9 ; v3(100.66,47.68) 101.04,47.3 UD8.G7 ; UD8.B2 97.09,43.3 v3(97.5,42.9) ; UD8.R1 95.77,53.7 v3(95.74,53.72) ; v3(154.26,52.27) 154.43,52.1 UD4.N1 ; UD5.H2 126.46,48.1 v3(126.82,48.47) 126.82,49.3 126.43,49.7 UD5.K2 ; UD7.R1 83.59,53.7 v3(83.25,53.36) ; v3(84.87,43.76) 84.47,43.37 UD7.B2 ; v3(148.32,42.9) 148.32,42.9 UD3.A8 ; UD2.K2 185.07,49.7 185.47,49.3 v3(185.47,48.47) 185.1,48.1 UD2.H2 ; CD63.1 96.36,57.02 v3(95.84,56.51) ; UD5.A8 131.24,42.5 131.58,42.15 v3(131.58,42.08) ; v3(132.42,52.48) 132.04,52.1 UD5.N9 ; v3(132.43,46.06) 132.36,46.06 132.02,45.72 UD5.E9 ; v3(89.67,42.9) 89.67,42.9 UD7.A8 ; UD1.E9 v3(178.45,46.1) 178.49,46.14 178.83,46.14 178.91,46.22 178.91,47.24 UD1.H9 ; UD6.A1 v3(113.41,42.1) ; v3(130.82,50.08) 131.2,49.7 UD5.K8 ; v3(147.52,46.9) UD3.G7 ; v3(160.86,42.04) 160.53,42.37 UD4.A8 ; UD4.K8 160.51,49.7 v3(160.13,50.08) ; v3(131.63,44.48) 131.63,44.51 UD5.D9 ; CD45.1 v1(116.62,57.02) ; UD2.B2 v3(184.68,42.92) ; UD5.R9 132.01,53.7 v3(131.63,54.08) ; v3(95.62,52.27) 95.78,52.1 UD8.N1 ; UD8.N9 102.71,52.1 v3(103.08,52.48) ; UD4.D9 160.94,44.51 v3(160.94,44.48) ; v3(157.26,57.24) CD35.1 ; v3(177.65,45.3) UD1.D9 ; v3(127.32,39.27) 127.68,39.64 CD48.1 ; v3(157.78,50.14) 157.72,50.08 156.11,50.08 UD4.K2 ; v3(147.61,40.35) CD31.1 146.35,39.64 CD28.1 CD26.1 ; v1(180.12,57.04) CD14.1 ; UD6.H2 113.81,48.13 113.46,48.48 v3(113.41,48.48) ; v3(178.47,51.7) 178.08,52.1 UD1.N9 ; UD1.D2 v3(172.85,44.5) ; UD1.H2 172.45,48.13 172.1,48.48 v3(172.05,48.48) ; v3(102.3,46.08) 102.32,46.05 102.33,46.05 UD8.E9 ; UD4.R9 161.32,53.7 v3(160.93,54.08) ; v3(102.14,40.48) 103.18,39.45 CD69.1 ; UD5.R1 125.1,53.7 v3(125.08,53.72) ; UD7.G7 v3(88.87,46.9) ; v3(148.29,49.32) 148.27,49.34 148.27,49.35 UD3.K8 ; v3(154.85,56.81) 154.64,57.02 CD29.1 ; v3(190.27,54.08) 190.65,53.7 UD2.R9 ; UD4.N9 161.35,52.1 v3(161.73,52.48) ; UD1.C1 v3(172.05,43.7) ; v3(194.09,48.4) CD11.1 ; UD3.K2 v3(143.52,49.3) ; v3(143.47,47.7) 143.47,47.73 143.12,48.07 UD3.H2 ; v3(183.72,53.72) 183.75,53.7 UD2.R1 ; UD3.D2 v3(143.52,44.5) ; v3(194.78,53.56) CD8.1 ; v3(95.83,46.88) 96.21,46.5 UD8.F1 ; UD7.D2 v3(84.87,44.5) ; v3(188.64,47.68) 189.02,47.3 UD2.G7 ; v3(83.23,52.5) 83.63,52.1 UD7.N1 ; v3(194.28,43.43) CD12.1 ; UD5.A1 v3(126.04,42.08) ; UD6.D9 v3(119.01,45.3) ; v3(89.67,44.5) UD7.C9 ; v3(119.01,44.5) UD6.C9
  vias: v1(150.72,27.76) v3(90.47,46.1) v3(90.93,44.77) v3(91.03,43) v3(95.03,44.05) v3(96.7,43.74) v3(99.76,41.35) v3(117.16,41.26) v3(117.75,41.17) v3(118.47,40.39) v3(119.81,46.1) v3(126.03,43.74) v3(139.45,39.68) v3(150.65,40.85) v3(155.34,43.74) v3(187.82,41.19) v3(190.43,37.77) v3(204.48,32.96) v3(204.48,32.28) v3(204.48,31.59) v3(204.48,30.9) v3(205.17,32.96) v3(205.17,32.28) v3(205.17,31.59) v3(205.17,30.9) v3(205.85,32.96) v3(205.85,32.28) v3(205.85,31.59) v3(205.85,30.9) v4(145.54,27.08) v6(137.83,47.08)
+1.35VP: length 36.8
  IN3 w0.254: v3(220.33,29.18) 211.52,29.18 209.66,27.32 v3(208.57,27.32) ; v3(221.27,29.53) 221.14,29.53 220.94,29.74 211.39,29.74 209.46,27.81 208.29,27.81 207.83,27.35 v3(207.83,27.25)
  IN3 w1.016: 215.89,27.14 210.98,27.14 210.04,26.21 209.43,26.21
  BOTTOM w0.203: v3(220.33,29.18) 220.04,28.88 PU600.5 ; v3(216.85,27.16) PU600.19
  BOTTOM w0.254: PR605.2 221.57,29.84 v3(221.27,29.53)
  vias: v3(207.78,26.15) v3(208.49,26.18) v3(216.83,27.75) v6(204.61,24.49)
+3.3V_M: length 199
  TOP w0.254: v5(165.53,17.22) 164.56,16.25 159.33,16.25 159.33,16.25 158.88,16.25 153.01,22.12 138.54,22.12 136.23,19.8 129.63,19.8 128.38,18.56 128.38,17.79 v5(128.34,17.75)
  IN1 w0.203: v5(165.53,17.22) 165.48,17.26 165.48,17.65 v4(165.45,17.68)
  IN1 w0.254: v5(128.34,17.75) 128.28,17.75 128.18,17.64 v4(127.29,17.64)
  IN2 w0.254: 128.26,17.35 128.03,17.35 127.74,17.64 v4(127.29,17.64) ; 128.26,17.35 129.37,17.35 129.48,17.24 129.51,17.24 129.97,16.78 130.53,16.78 130.72,16.97 130.72,16.98 130.96,17.21 131.29,17.21 131.66,16.85 v4(131.66,16.81) ; 128.26,17.35 128.23,17.33 128.23,15.26 127.65,14.67 126.69,14.67 126.27,15.09 126.27,15.46 125.51,16.22 125.23,16.22 124.96,16.49 122.49,16.49 119.28,19.7 117.2,19.7 115.69,18.19 107.71,18.19 106.97,17.45 105.75,17.45 105.28,17.92 105.27,17.92 105.09,18.1 104.44,18.1 103.46,19.08 102.16,19.08 101.66,19.58 v3(101.66,22.77)
  IN3 w0.203: v4(165.45,17.68) 165.82,17.32 165.82,11.35 173.02,4.15 197.24,4.15 197.83,4.75 200.89,4.75 201.86,5.72 205.29,5.72 205.42,5.58 207.62,5.58 v3(208.06,5.14) 208.06,5.16 208.47,4.75 230.81,4.75 234.25,8.2 v4(238.16,8.2)
  IN4 w0.203: v1(243.03,21.48) 242.72,21.17 v1(242.72,17.28) 242.72,15.39 238.16,10.83 v4(238.16,8.2)
  IN4 w0.254: v1(126.96,17.72) 127.01,17.72 127.09,17.64 v4(127.29,17.64) ; v1(131.38,17.3) 131.39,17.3 131.39,17.12 131.53,16.98 131.53,16.93 v4(131.66,16.81)
  BOTTOM w0.102: v3(101.66,22.77) 101.66,22.76 100.76,21.86 v6(100.76,20.07)
  BOTTOM w0.203: v3(101.66,22.77) 101.76,22.67 103.92,22.67 104.33,22.27 105.27,22.27 105.6,22.6 CH40.1 ; RC47.1 207.6,7.1 208.18,6.53 JSPI1.16 208.18,5.26 v3(208.06,5.14) ; R346.2 243.03,22.84 v1(243.03,21.48)
  BOTTOM w0.254: v1(126.96,17.72) 126.97,17.72 126.99,17.74 UCPU1.A24
+3.3V_SPI: length 50.6
  IN4 w0.508: v1(217,10.51) 216.86,10.51 216.03,11.34 212.44,11.34 212.13,11.03 209.29,11.03 v1(208.87,11.45) ; v1(218.2,7.66) 221.27,7.66 222.26,8.65 v1(223.48,8.65)
  BOTTOM w0.076: v2(234.53,12.6) 234.54,12.59 CH8.1
  BOTTOM w0.33: RC47.2 208.52,7.54 208.52,7.53 208.52,6.78 208.68,6.62 JSPI1.15
  BOTTOM w0.508: RH48.1 v1(208.87,11.45) 207.85,11.45 207.16,10.76 207.16,10.19 207.54,9.81 207.54,9.26 208.52,8.28 RC47.2 ; 227.87,8.59 CH7.1 ; 227.87,8.59 223.57,8.59 223.49,8.67 ; 227.87,8.59 227.87,8.53 228.82,7.57 234.47,7.57 235.37,8.48 U2.8 235.37,12.46 CH8.1 ; v1(217,10.51) 217,9.78 218.2,8.59 v1(218.2,7.66) ; U1.8 223.48,8.9 223.49,8.88 223.49,8.67 ; 223.49,8.67 v1(223.48,8.65)
+3.3V_SUS: length 71
  IN1 w0.508: v4(283.5,88.77) 284.62,88.77 v4(285.89,90.04) ; v3(280.16,49.47) 284.87,49.47 286.42,51.02 286.87,51.02
  IN3 w0.508: v4(283.5,88.77) 283.5,88.75 283.22,88.47 280.22,88.47 279.55,87.8 279.55,81.56 281.66,79.46 281.66,70.31 v4(281.21,69.87)
  IN4 w0.254: v4(285.89,90.04) 285.94,90.04 286.49,90.58 v1(286.56,90.58)
  IN4 w0.508: v1(283.75,47.03) 283.75,48.25 284.55,49.05 284.55,49.84 284.62,49.9 284.62,51.53 285.6,52.51 ; v1(286.37,52.58) 286.29,52.51 285.6,52.51 ; v4(281.21,69.87) 281.21,64.69 282.05,63.85 282.05,54.59 284.14,52.51 285.6,52.51
  BOTTOM w0.076: CZ4.1 282.74,47.03 281.66,45.95 v2(281.66,45.69)
  BOTTOM w0.254: v1(287.37,51.71) 287.06,52.02 287.02,52.02 286.46,52.58 v1(286.37,52.58)
  BOTTOM w0.356: v3(280.16,49.47) 280.08,49.39 278.2,49.39 277.87,49.72 277.87,50.68 278.13,50.93 U61.5
  BOTTOM w0.508: v3(280.16,49.47) 280.64,49.95 RZ4.1 ; v1(283.75,47.03) CZ4.1
  vias: v1(287.76,51.72) v1(287.87,51.43) v1(297.1,46.72) v1(297.43,46.7) v1(297.47,47.13) v4(287.51,51.33) v4(287.53,50.84) v4(287.87,51.09) v4(296.69,47.99) v4(296.95,47.68) v4(297.24,47.39)
+3.3VDX_SSD:
  vias: v1(36.17,53.97) v1(36.15,53.53) v2(17.18,48.35) v3(17.18,46.43) v3(17.77,46.43) v3(28.99,47.45) v3(29.58,47.46)
+3V_PCH: length 286.2
  TOP w0.305: JAPS1.12 44.21,53.41 44.65,53.85 47.12,53.85 47.21,53.76 JAPS1.18
  TOP w0.406: v3(180.31,11.26) 180.31,12.6 180.43,12.72 v5(180.43,17.04) ; 47.13,53.84 47.79,53.84 50.46,51.17 v6(51.48,51.17) 60.52,51.17 64.02,47.67 72.16,47.67 72.21,47.62 v3(72.21,47.6) ; v5(131.74,20.24) 129.79,22.18 v5(128.73,22.18)
  TOP w0.508: 72.21,45.52 v3(72.21,47.6) ; 72.21,45.52 72.21,42.18 ; 72.21,45.52 72.2,45.51 72.2,42.19 72.21,42.18 ; v3(91.17,30.12) 91.17,34.41 85.66,39.92 80.69,39.92 79.68,40.94 73.45,40.94 72.21,42.18 ; v5(134.26,26.19) 134.73,25.72 154.74,25.72 159.27,30.24 179.63,30.24 v5(179.82,30.05)
  IN1 w0.254: v4(134.45,25.79) 134.26,25.98 v5(134.26,26.19) ; v4(132.14,20.24) v5(131.74,20.24)
  IN1 w0.406: v3(93.98,24.26) 94.32,24.26 95.21,25.15 95.84,25.15 v3(95.84,25.15) 96.19,24.81 98.17,24.81 98.72,25.35 100.33,25.35 100.72,25.75 v3(101.65,25.75) ; v4(125.43,22.18) 126.76,22.18 126.96,22.38 128.52,22.38 v5(128.73,22.18)
  IN1 w0.508: v5(179.82,30.05) 180.07,29.8 180.07,17.39 v5(180.43,17.04)
  IN2 w0.406: v4(125.43,22.18) 125.46,22.21 125.46,23.67 124.72,24.4 124.14,24.4 123.77,24.77 v4(123.77,24.78)
  IN3 w0.178: 137.03,21.22 137.04,21.22 137.79,21.22 138.13,20.89 v4(138.13,20.88)
  IN3 w0.254: 134.74,22.33 135.45,21.62 135.45,21.61 135.7,21.37 135.7,21.19 136.07,20.82 136.63,20.82 137.03,21.22
  IN3 w0.406: v3(101.65,25.75) 101.64,25.74 v4(101.64,23.91) ; v4(109.88,16.34) 109.88,16.64 110.79,17.56 110.79,21.77 110.91,21.89 v4(110.91,22.15) ; 134.74,22.33 134.74,24.89 134.45,25.18 v4(134.45,25.79)
  IN4 w0.203: v1(125.04,22.14) 125.39,22.14 v4(125.43,22.18) ; 133.58,20.52 132.5,20.52 132.25,20.27 132.18,20.27 v4(132.14,20.24) 131.73,20.24 v1(131.63,20.33)
  IN4 w0.254: v4(138.13,20.88) 138.27,20.75 138.27,20.16 138.25,20.14 138.25,19.62 138.21,19.58 ; v1(134.17,26.08) 134.17,26.01 134.4,25.79 v4(134.45,25.79)
  IN4 w0.305: v4(138.13,20.88) 138.05,20.96 137.75,21.26 v1(137.75,21.3) ; 138.21,19.58 138.21,19.15 137.65,18.6 137.25,18.6 137.24,18.61 136.97,18.61 136.8,18.78 136.69,18.78 136.39,19.09 136.39,19.22 136.09,19.52 135.28,19.52 135.27,19.52 134.58,19.52 133.58,20.52
  IN4 w0.406: v1(95.08,21.18) v1(95.08,23.21) ; v4(101.64,23.91) 101.74,23.8 102.36,23.8 102.98,24.42 107.32,24.42 108.33,23.4 109.64,23.4 110.8,22.25 110.82,22.25 v4(110.91,22.15) 110.93,22.15 111.31,22.54 111.31,22.71 111.56,22.95 v1(111.85,22.95) 112.12,23.22 114.78,23.22 ; 114.78,23.22 114.62,23.39 114.62,24.34 114.64,24.36 114.64,24.57 114.93,24.86 116.01,24.86 117.57,24.86 117.57,24.86 117.95,24.86 118.37,24.44 120.04,24.44 120.91,23.56 121.71,23.56 121.92,23.77 122.32,23.77 123.28,24.73 123.72,24.73 v4(123.77,24.78) ; 114.78,23.22 v1(115.05,22.95) ; v1(110.46,16.34) v4(109.88,16.34)
  IN4 w0.508: v3(93.98,24.26) 94.14,24.43 94.14,27.45 93.01,28.58 93.01,29.39 92.29,30.12 v3(91.17,30.12)
  BOTTOM w0.254: UCPU1.AL14 137.44,21.62 v1(137.75,21.3)
  BOTTOM w0.381: 171.88,2.32 171.8,2.39 U4.16 ; 97.53,13.01 97.46,13.09 96.16,13.09 96.13,13.06 95.84,12.77 RH12.1 ; R12.1 180.38,6.47 180.14,6.7 179.36,6.7 179.25,6.58 U5.5
  BOTTOM w0.406: 171.88,2.32 172.22,2.32 172.32,2.21 174.44,2.21 174.54,2.32 181.52,2.32 182.04,2.84 ; 171.8,2.39 170.6,2.39 169.91,3.08 CH89.1 ; RH109.2 101.98,26.26 101.65,25.93 v3(101.65,25.75) ; 182.04,2.84 182.1,2.9 182.1,6.14 ; 182.04,2.84 187.13,2.84 187.8,3.51 U37.5 ; v1(134.17,26.08) 134.61,26.08 135.65,27.12 135.65,28.3 135.61,28.34 RH146.1 135.61,30.3 CH50.1 ; v1(95.08,23.21) 95.04,23.25 94.97,23.25 94.57,23.64 94.57,23.67 v3(93.98,24.26) ; 182.1,6.14 182.13,6.16 182.13,10.29 181.85,10.57 180.68,10.57 180.31,10.94 v3(180.31,11.26) ; 182.1,6.14 R12.1 ; 97.76,18.94 97.76,19.63 96.76,20.63 96.76,23.45 95.84,24.36 v3(95.84,25.15) ; RH175.1 119.67,22.19 RH111.1 120.48,22.18 121.09,21.57 122.6,21.57 123.17,22.14 124.28,22.14 124.45,21.96 124.86,21.96 v1(125.04,22.14) ; R291.2 C97.1 71.96,47.08 72.21,47.34 v3(72.21,47.6) ; RH100.2 91.27,18.36 91.86,18.94 91.86,19.75 92.57,20.46 94.37,20.46 v1(95.08,21.18)
+3V_PCH_DSW: length 68.9
  IN2 w0.254: v4(99.83,17.43) 99.85,17.42 100.13,17.42 102.06,15.49 102.27,15.49 103.2,14.56 105.08,14.56 v4(105.22,14.7)
  IN3 w0.254: 133.74,26.41 133.69,26.36 133.69,26.18 133.59,26.08 133.59,25.44 133.67,25.37 133.67,22.72 133.29,22.35 133.29,22.33 v4(133.27,22.31) ; 133.74,26.41 v4(133.79,26.46) ; 133.74,26.41 132.41,26.41 131.27,27.55 114.69,27.55 114.23,27.09 114.23,26.58 114.07,26.42 114.07,25.85 v4(113.85,25.63) ; v4(107.58,26.81) 107.58,25.93 108.06,25.45 108.06,21.24 ; 108.06,21.24 108.85,21.24 109.26,20.84 109.26,19.88 108.23,18.85 108.23,17.79 v4(108.06,17.62) ; 108.06,21.24 106.33,21.24 105.63,20.54 104.42,20.54 102.53,18.65 101.93,18.65 100.71,17.43 v4(99.83,17.43)
  IN4 w0.254: v1(99.1,16.92) 99.16,16.92 99.65,17.42 99.82,17.42 v4(99.83,17.43) ; v1(107.35,27.32) 107.58,27.09 v4(107.58,26.81) 107.66,26.74 108.21,26.74 109.15,25.8 112.87,25.8 112.88,25.8 113.06,25.8 113.29,25.57 113.79,25.57 v4(113.85,25.63) 114.13,25.91 v1(114.13,26) ; v4(105.22,14.7) 104.99,14.47 v1(104.73,14.47) ; v1(133.7,22.12) 133.55,22.12 133.35,22.32 133.28,22.32 v4(133.27,22.31) ; v1(133.46,26.66) 133.46,26.64 133.64,26.46 v4(133.79,26.46) ; v1(108.44,17.62) v4(108.06,17.62)
  BOTTOM w0.102: RH145.2 133.96,30.37 v6(132.79,31.54)
  BOTTOM w0.254: v1(99.1,16.92) 98.98,16.81 98.49,16.81 98.17,16.49 98.17,15.49 98.47,15.18 98.77,15.18
+3VALW: length 303.3
  TOP w0.102: v6(66.81,19.43) 67.42,19.43 68.48,20.49 v3(68.5,20.49) ; v6(66.89,25.95) 67.03,25.81 67.63,25.81 v3(67.61,25.8) ; v3(67.84,21.21) v6(66.79,21.21)
  TOP w0.305: JAPS1.16 v3(46.21,51.72)
  TOP w0.508: v3(67.61,25.8) 67.81,25.6 v3(71.69,25.6)
  TOP w2.032: 295.82,54.5 296.19,54.13 296.19,40.49 293.15,37.46 293.15,36.54
  IN1 w0.508: v3(279.61,91.31) 279.49,91.18 279.49,85.51 279.18,85.21 279.18,69.72 284.22,64.67 294.89,64.67 v4(295.11,64.46) ; v3(243.11,27.78) 242.25,27.78 241.92,28.11 241.92,32.66 v3(241.08,33.49) 240.71,33.86 240.71,36.31 241.48,37.08 v4(243.42,37.08) ; v4(283.2,17.97) 284.32,17.97 285.76,19.41 290.11,19.41 291.12,20.41 292.43,20.41 293.86,21.85 293.86,32.3 v3(293.19,32.97)
  IN3 w0.508: v3(272.04,40.06) 273.3,41.32 v3(273.3,43.07) ; v4(295.11,64.46) 295.11,65.5 296.15,66.54 296.15,69.22 296.72,69.79 296.72,70.88 298.22,72.38 299.53,72.38 300.45,73.31 v4(300.45,77.12)
  IN4 w0.254: v1(299.07,16.01) 298.83,16.01 v4(298.61,16.22) ; v1(297.46,36.33) v4(297.46,35.56)
  IN4 w0.508: 266.84,16.73 267.05,16.52 269.73,16.52 270.17,16.08 270.93,16.08 v1(271.27,15.74) ; 266.84,16.73 267.68,17.57 v1(267.68,17.62) 268.56,18.51 v1(268.59,18.51) ; 266.84,16.73 v1(266.1,16.73) ; v1(262.62,16.1) 262.61,16.11 258.16,16.11 257.98,16.29 255.4,16.29 252.05,19.64 v1(251.12,19.64) 251.12,19.88 v4(250.77,20.22) ; v3(285.54,42.74) 285.54,40.1 v1(284.83,39.39) 284.83,35.95 v4(285.01,35.77) ; v1(240.26,41.91) 240.88,42.54 241.46,42.54 242.94,41.06 242.94,39.29 244.18,38.04 ; v4(283.2,17.97) v1(283.2,17.38) ; v1(93.11,30.92) 91.02,30.92 89.99,29.89 88.1,29.89 87.69,30.29 87.69,33.86 83.75,37.8 83.75,39.91 81.23,42.44 77.14,42.44 76.96,42.61 ; 244.18,38.04 243.42,37.28 v4(243.42,37.08) ; 244.18,38.04 v1(244.18,38.07) ; v1(287.73,15.26) 287.73,15.94 v4(287.75,15.97) ; v3(300.26,88.38) 299.73,87.85 299.73,85.11 299.98,84.85 299.98,82.69 299.67,82.38 299.67,79.96 300.45,79.18 v1(300.45,77.82) v4(300.45,77.12)
  BOTTOM w0.254: PR74.1 297.59,35.7 296.93,35.04 296.93,22.28 PR73.1 297.86,20.97 298.08,20.75 300.03,20.75 300.28,21 300.28,21.72 PC80.1 ; PR74.1 297.69,35.73 PR81.1 ; PR74.1 297.66,36.13 v1(297.46,36.33) ; v3(273.3,43.07) 273.57,42.8 PU401.7 ; v3(285.54,42.74) 285.63,42.74 285.83,42.55 PU400.7
  BOTTOM w0.356: PC80.1 299.74,22.61 299.51,22.84 298.39,22.84 298.1,23.13 PU904.8
  BOTTOM w0.381: PC901.1 264.11,17.33 PU900.8 262.66,16.06 v1(262.62,16.1) ; v3(300.26,88.38) 300.53,88.12 U54.5 ; R335.1 300.68,56.81 300.68,57.66 C101.1
  BOTTOM w0.406: PR904.1 282.63,16.4 282.82,16.6 PU901.5 282.82,17.01 v1(283.2,17.38) ; PU902.5 283.57,15.01 282.5,15.01
  BOTTOM w0.508: v1(271.27,15.74) 270.86,15.33 PR908.1 ; 4.32,36.04 4.32,36.04 4.32,37.61 4.65,37.94 R284.1 ; PC905.1 v1(262.62,16.1) ; v1(93.11,30.92) 93.11,31.49 94.71,33.09 96.51,33.09 96.76,33.34 97.24,33.34 98.38,34.49 110.91,34.49 111.47,35.04 133.08,35.04 134.15,33.98 RH145.1 ; PR530.1 77.9,15.46 78.19,15.75 v3(78.19,15.92) ; PR94.1 241.46,33.88 v3(241.08,33.49) ; 282.5,15.01 282.23,15.28 PC902.1 PR904.1 ; PC901.1 PC900.1 265.52,17.06 265.85,16.73 v1(266.1,16.73) ; v1(287.73,15.26) 287.74,15.27 PR65.1 289.34,15.27 PR61.1 ; v3(71.69,25.6) PR504.1 PR506.1 ; PR409.2 272.46,39.64 v3(272.04,40.06) ; R336.1 294.08,63.4 294.57,63.9 v1(294.96,63.9) ; v3(224.39,24.41) 224.2,24.22 PR604.1 ; v3(243.11,27.78) PR13.1 ; v1(251.12,19.64) C214.1
  vias: v1(30.97,42.03) v1(30.99,41.68) v1(31.19,41.35) v1(31.29,41.67) v1(31.53,41) v1(31.56,41.32) v1(76.36,20.29) v1(76.36,19.91) v1(76.69,49.19) v1(76.9,45.66) v1(77,49.19) v1(77,20.67) v1(77.2,45.66) v1(77.3,49.19) v1(77.51,45.66) v1(296.97,59.06) v1(296.97,58.76) v1(297.32,59.05) v1(297.3,58.74) v1(298.02,53.4) v1(298.03,53.01) v1(298.33,53.41) v1(298.35,53.01) v1(299.12,59.02) v1(299.12,58.67) v1(299.5,59.02) v1(299.5,58.64) v3(9.43,44.44) v3(9.42,43.85) v3(10.35,36.28) v3(10.34,35.66) v3(38.71,40.82) v3(38.68,40.22) v3(38.69,39.61) v3(38.67,38.98) v3(68.04,49.29) v3(68.07,49.89) v3(68.51,21.18) v3(226.93,32.16) v3(227.21,31.62) v3(238.36,18.08) v3(250.49,20.86) v3(292.19,35.02) v3(292.19,34.33) v3(292.19,33.65) v3(292.19,32.96) v3(292.68,34.69) v3(292.68,34) v3(292.68,33.32) v3(292.68,32.63) v3(293.19,35.09) v3(293.19,34.4) v3(293.19,33.71) v4(30.57,42) v4(31.33,42.11) v4(31.37,42.57) v4(31.63,41.67) v4(31.76,42.11) v4(32.14,41.7) v4(294.99,55.8) v4(295.39,56.43) v4(295.37,55.95) v4(295.39,55.45) v5(295.82,56.35) v5(295.82,55.95) v5(296.2,56.35) v5(296.2,55.95)
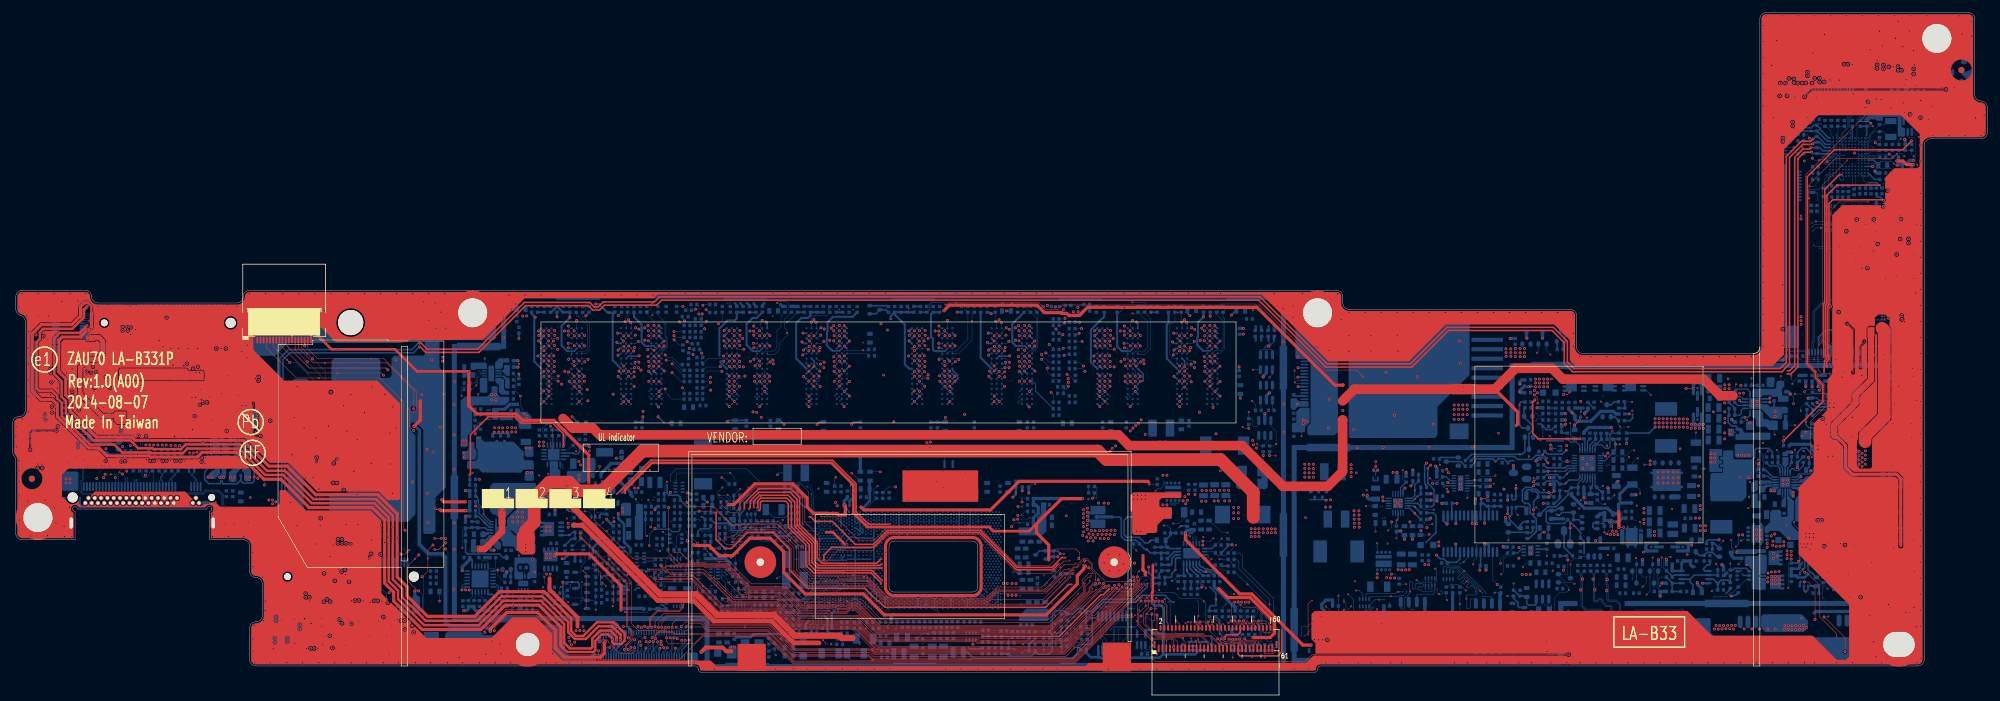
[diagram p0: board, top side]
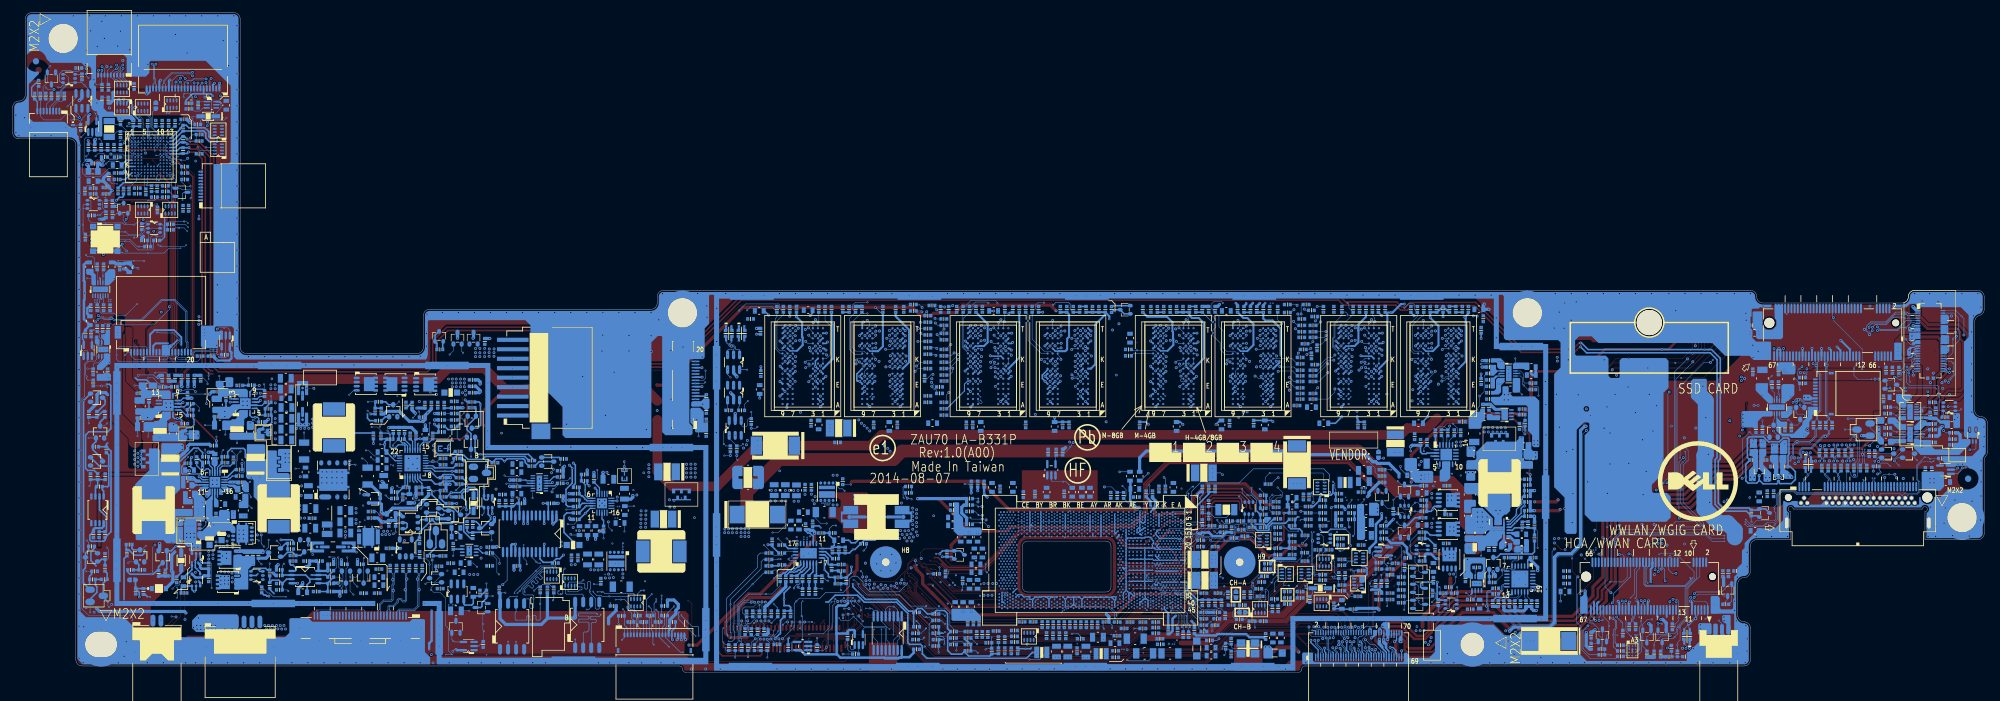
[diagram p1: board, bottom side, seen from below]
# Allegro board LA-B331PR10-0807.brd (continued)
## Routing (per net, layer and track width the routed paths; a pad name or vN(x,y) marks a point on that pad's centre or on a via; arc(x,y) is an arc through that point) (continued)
+3VALW_EC: length 101.9
  TOP w0.508: v3(298.21,80.99) 299.12,80.99 299.68,80.43 v3(300.74,80.43)
  IN1 w0.508: v4(292.16,80.56) 292.21,80.56 293.67,82.02 v4(294.27,82.02) 295.49,82.02 296.52,80.99 v3(298.21,80.99) ; v4(287.82,90.89) 287.36,91.34 285.1,91.34 284.53,90.77 v4(284.53,89.82) ; v3(298.82,71.79) 298.04,71.79 v3(296.02,73.8)
  IN2 w0.508: v3(291.84,71.71) 292.21,71.71 292.25,71.75 292.95,71.75 293.13,71.93 293.13,75.25 292.16,76.22 v4(292.16,80.56) 293.1,81.5 293.1,83.88 292.33,84.65 291.78,84.65 291.4,85.03 291.4,85.78 v4(291.06,86.12) ; v3(294.32,80.13) 294.32,81.97 v4(294.27,82.02) ; v4(287.82,90.89) 287.82,89.22 286.97,88.37 286.97,82.94 287.67,82.24 v4(287.67,82.24) 287.78,82.12 287.78,82.11 288.36,81.54 288.36,80.69 287.86,80.19 v4(287.65,80.19)
  IN3 w0.508: v3(298.82,71.79) 299.37,71.79 300.19,70.97 v4(300.19,69.29) ; v4(291.06,86.12) 290.83,86.35 290.31,86.35 289.42,87.24 v4(289.42,87.84) ; 294.75,79.38 294.32,79.81 v3(294.32,80.13) ; 294.75,79.38 296.74,77.39 v3(296.74,76.29) 296.74,74.52 v3(296.02,73.8) ; 294.75,79.38 v3(294.73,79.38)
  IN4 w0.203: v1(288.11,80.13) 288.09,80.1 287.74,80.1 v4(287.65,80.19) ; v1(288.11,82.13) 287.78,82.13 v4(287.67,82.24) ; v4(294.27,82.02) 294.16,82.02 293.99,81.86 293.27,81.86 293.24,81.82 292.99,81.82 292.68,82.13 v1(292.61,82.13) ; v4(292.16,80.56) 292.11,80.51 v1(292.11,80.13) v1(292.11,79.63)
  IN4 w0.254: v4(291.06,86.12) 291.06,86.23 291.12,86.29 v1(291.12,86.5) ; v1(287.31,72.67) 287.31,72.49 287.13,72.31 v4(287.03,72.31) 286.81,72.52 v1(286.81,72.67) ; v1(288.06,90.58) 288.06,90.64 v4(287.82,90.89) 287.56,90.63 v1(287.56,90.58) ; v1(287.81,72.67) 287.81,72.55 v4(288.05,72.32) 288.31,72.59 v1(288.31,72.67) ; v1(289.85,87.42) 289.84,87.42 v4(289.42,87.84)
  IN4 w0.508: v1(291.81,69.07) 291.87,69.13 291.87,71.68 v3(291.84,71.71) ; v4(284.53,89.82) 281.92,89.82 278.77,86.67 v1(278.7,86.67) ; v4(300.19,69.29) 300.74,68.74 300.74,68.73 v1(300.99,68.48)
  BOTTOM w0.203: U38.A6 291.11,86.5 v1(291.12,86.5) ; 288.46,71.8 288.45,71.78 288.45,68.96 288.99,68.42 R331.2 ; U38.K2 U38.K1
  BOTTOM w0.254: U38.K1 v3(294.32,80.13)
  BOTTOM w0.381: C145.1 297.25,75.79 v3(296.74,76.29) 297.25,76.8 C143.1
  BOTTOM w0.508: C141.1 295.01,79.09 294.73,79.37 v3(294.73,79.38) ; v3(300.74,80.43) 300.74,80.41 300.51,80.18 L10.1 ; v3(298.21,80.99) 298.44,81.22 R207.1 ; 298.13,77.82 297.27,76.96 C143.1 ; 298.13,77.82 298.13,78.28 297.39,79.01 R349.2 ; 298.13,77.82 R206.2 ; v1(291.81,69.07) 292.09,68.79 R332.2 ; R330.2 297.84,72.03 298.08,71.79 v3(298.82,71.79) ; 296.54,91.9 296.62,91.83 296.62,90.59 297.03,90.19 R239.1 ; v3(296.02,73.8) R233.1
  vias: v6(283.54,80.99)
+3VALW_EC_L: length 8.4
  IN3 w0.254: v3(298.21,80.36) 297.3,81.27 v4(295.15,81.27)
  IN4 w0.152: v1(292.61,81.13) 292.61,81.13 292.89,81.41 293.43,81.41 293.44,81.41 293.89,81.41
  IN4 w0.203: 293.89,81.41 295.01,81.41 v4(295.15,81.27)
  BOTTOM w0.508: v3(298.21,80.36) 298.49,80.36 298.74,80.61 C139.1 299.04,79.38 L10.2
+3VALWP: length 12.9
  BOTTOM w0.254: PR300.1 282.43,34.8 283.14,35.51 283.84,35.51 285.3,34.05 285.37,34.05 286.17,33.25 286.17,32.99
  BOTTOM w0.508: 286.68,33.49 285.56,34.61 285.48,34.61 284.81,35.29 v2(284.81,35.79) 284.48,36.12 281.38,36.12 PR311.1
+3VLP: length 165.1
  IN3 w0.508: v4(281.16,33.37) 278.21,36.33 270.52,36.33 270.17,36.68 270.17,46.41 270.94,47.19 277.71,47.19 278.95,48.43 v4(278.95,89.74)
  IN4 w0.254: v4(278.95,89.74) 279.13,89.74 279.52,90.14 v1(279.52,90.17)
  IN4 w0.508: v1(248.12,20.37) 248.12,20.42 249.71,22.01 251.81,22.01 255.32,18.51 262.45,18.51 264.13,16.82 264.13,15.56 264.78,14.91 265.38,14.91 266.01,15.55 269.23,15.55 269.61,15.17 270.55,15.17 270.94,14.77 271.9,14.77 273.77,12.91 273.77,11.59 274.88,10.48 280.21,10.48 281.28,11.55 281.28,15.76 281.95,16.43 283.79,16.43 286.45,19.08 v1(286.82,19.08) 287.3,19.56 290.52,19.56 290.93,19.97 292.99,19.97 293.23,20.2 293.23,23.37 293.54,23.68 293.54,30.62 290.79,33.37 v4(281.16,33.37) 280.73,33.37 280.54,33.18 v1(280.52,33.18)
  BOTTOM w0.254: v1(279.52,90.17) 279.76,90.41 U58.6
  BOTTOM w0.508: v1(286.82,19.08) 287.34,18.57 v2(287.34,16.03) 287.14,15.84 287.14,14.36 RTCD1.2
+3VNS_PWR: length 48.6
  IN1 w0.508: v3(280.57,93.32) 280.57,93.18 278.42,91.04 278.42,69.65 285.1,62.97 292.48,62.97 293.49,63.99 v3(293.49,64.06)
  BOTTOM w0.102: v3(293.49,64.06) 292.73,64.06 v6(292.67,64)
  BOTTOM w0.305: v3(280.57,93.32) 280.78,93.11 JSNR1.3
  BOTTOM w0.508: v3(293.49,64.06) 293.49,64.27 294.03,64.8 R336.2 294.79,64.8 294.9,64.69 C198.1 296.11,64.69 296.35,64.93 R153.2
+3VS: length 794.5
  TOP w0.254: v5(173.52,13.22) 173.52,13.2 172.6,12.29 172.23,12.29 165.63,5.68 v5(153.45,5.68)
  TOP w0.508: v3(67.93,27.32) 68.26,27 v3(71.66,27) ; v3(147.38,57.27) 148.26,58.15 162.12,58.15 163.31,56.96 165.92,56.96 166.02,56.86 166.79,56.86 167.11,56.54 168.85,56.54 169.17,56.87 169.17,56.89 170.1,57.82 188.18,57.82 188.19,57.81 196.93,57.81 209.26,45.48 210.5,45.48 210.56,45.55 ; v5(237.92,39.08) 238.16,39.32 238.16,41.24 234.55,44.85 ; v5(196.26,5.5) 198.99,5.5 199.69,6.2 199.69,7.98 195.84,11.83 192.29,11.83 190.88,13.24 v5(190.84,13.24)
  TOP w1.524: 210.45,39.97 210.48,39.95 210.48,31.82 208.11,29.46 201.03,29.46 194.57,35.91 176.69,35.91 174.99,37.61 92.87,37.61 91.81,38.68 88.63,38.68 87.1,40.21 ; 272.25,43.81 270.22,43.81 267.57,46.45 245.31,46.45 243.61,48.15 237.86,48.15 234.55,44.85 231.32,44.85 231.29,44.82 ; 228.34,44.85 212.33,44.85 210.48,42.99
  IN1 w0.254: v4(152.92,5.68) v5(153.45,5.68) ; v5(190.84,13.24) 190.22,13.24 v4(190.18,13.2) 190.04,13.06 187.87,13.06 187.56,13.36 178.43,13.36 177.91,12.84 173.69,12.84 173.52,13.02 v5(173.52,13.22) ; v4(131.68,16.1) 131.52,15.93 131.52,15.92 131.13,15.53 131.13,15.02 130.77,14.66 130.43,14.66 130.19,14.9 129.64,14.9 129.41,15.14 127.49,15.14 127.24,15.38 v4(127.22,15.38) ; v4(196.66,5.33) 196.43,5.33 v5(196.26,5.5)
  IN1 w0.508: v5(229.59,45.12) v4(229.94,45.12) ; v3(223.8,22.93) 228.93,28.06 233.93,28.06 236.03,30.15 236.03,33.57 237.3,34.84 237.3,37.58 237.88,38.17 v4(237.88,38.31) 237.92,38.35 v5(237.92,39.08) ; v5(229.54,44.49) v4(229.93,44.49) ; v3(67.93,27.32) 64.65,27.32 63.09,28.88 v3(52.4,28.88)
  IN2 w0.508: 105.75,18.26 v4(105.75,18.1) ; 105.75,18.26 105.59,18.26 105.47,18.38 105.46,18.38 104.73,19.1 104.73,19.23 104.42,19.54 102.68,19.54 v4(102.44,19.78) ; 105.75,18.26 105.79,18.31 105.94,18.31 106.18,18.55 107.42,18.55 107.52,18.65 108.72,18.65 v4(109.04,18.97) 109.04,18.85 109.25,18.65 115.5,18.65 117.01,20.16 119.47,20.16 122.67,16.96 125.15,16.96 125.42,16.68 125.7,16.68 126.23,16.15 126.93,16.15 ; v4(145.53,35.93) 145.55,35.93 146.05,36.43 146.05,38 140.83,43.22 140.83,54.37 141.36,54.91 141.74,54.91 v4(142.12,55.29) ; v3(51.66,8.36) 52.92,8.36 v3(53.59,7.69) 57.62,7.69 58.75,6.56 60.81,6.56 61.49,5.87 63.04,5.87 v3(63.47,6.3) ; v4(126.95,16.87) 126.95,16.85 126.93,16.83 126.93,16.15 ; 126.93,16.15 127.24,15.84 127.24,15.4 v4(127.22,15.38) ; v3(197.9,46.8) 198.88,45.82 v3(198.88,44.26) 198.16,43.54 v3(198.16,40.99) 201.83,40.99 v3(203.31,42.47) 204.31,41.47 v3(210.5,41.47) ; v3(52.4,28.88) 46.65,28.88 44,31.53 28.45,31.53 28.16,31.82 20.42,31.82 19.52,32.72 16.42,32.72 15.44,33.7 15.44,36.3 14.48,37.25 6.98,37.25 6.39,37.85 6.39,39.13 v4(6.44,39.18)
  IN3 w0.254: v4(131.68,16.1) 132.34,15.44 132.75,15.44 133.31,14.88 133.31,14.44 v4(132.88,14.01)
  IN3 w0.508: v4(142.12,55.29) 145.45,55.29 147.38,57.22 v3(147.38,57.27) ; v4(93.75,11.8) 93.75,9.43 94.81,8.37 96.87,8.37 99.01,6.23 104.39,6.23 104.57,6.06 107.4,6.06 108.07,5.39 108.07,2.3 ; 108.07,2.3 109.94,2.3 113.1,5.47 113.1,7.12 114.78,8.8 114.78,10.82 114.01,11.6 v4(114.01,11.9) ; 108.07,2.3 96.26,2.3 94.64,3.93 v3(94.51,3.93) ; v3(53.59,7.69) 53.66,7.75 59.66,7.75 60.86,8.96 70.56,8.96 v3(71.38,9.78) ; v4(190.88,15.38) 196.12,15.38 198.22,17.48 202.14,17.48 204.02,15.6 214.83,15.6 215.43,16.2 218.38,16.2 219.56,15.02 222.03,15.02 222.49,15.47 222.49,17.65 223.07,18.23 223.07,20.27 223.8,21 v3(223.8,22.93) ; v4(75.3,13.09) 73.07,13.09 71.16,15 v3(71.16,16.11)
  IN4 w0.203: 133.51,12.84 133.53,12.83 133.53,12.55 v1(133.7,12.38) 134.19,12.88 134.78,12.88 135.35,12.31 135.35,11.74 135.12,11.51 135.12,10.73 135.22,10.63
  IN4 w0.254: v4(109.04,18.97) 109.04,18.47 109.51,18 v1(109.57,18) ; v4(145.53,35.93) 145.55,35.93 v1(145.87,35.61) ; v4(196.66,5.33) 196.66,5.26 195.39,3.99 v1(194.59,3.99) ; v4(105.75,18.1) 105.73,18.08 105.73,17.62 v1(105.45,17.34) ; v4(152.92,5.68) 152.92,5.72 152.57,6.06 v1(152.42,6.22) ; v1(287.91,52.1) 287.77,52.24 v4(287.77,52.41) ; v1(127.63,16.87) v4(126.95,16.87) ; v1(98.51,13.04) 98.45,13.04 98.19,13.29 97.21,13.29 96.91,13.59 95.93,13.59 v1(95.92,13.61) ; v4(131.68,16.1) 131.68,16.21 131.45,16.44 v1(131.38,16.44) ; v4(132.88,14.01) 133.06,14.01 133.51,13.56 133.51,12.84 ; v1(127.54,15.46) 127.3,15.46 127.23,15.38 v4(127.22,15.38)
  IN4 w0.381: v1(114.64,12.03) 114.13,12.03 v4(114.01,11.9)
  IN4 w0.508: v4(6.44,39.18) 6.92,39.18 v3(7.15,38.96) ; v3(298.14,66.18) 297.22,67.1 297.22,68.82 298.78,70.38 298.9,70.38 299.65,71.14 299.65,76.58 299.4,76.83 299.4,78.68 299.08,79 299.08,82.62 299.4,82.94 v3(299.4,84.43) ; 78.14,13.62 78.2,13.62 78.23,13.59 78.52,13.3 85.65,13.3 86.65,12.3 92.94,12.3 v1(93.2,12.03) 93.52,12.03 v4(93.75,11.8) ; v1(284.77,47.03) 284.77,47.21 v4(284.45,47.53) ; 135.22,10.63 135.55,10.3 135.55,8.55 v4(135.51,8.51) 135.51,8.36 v1(135.21,8.07) ; v4(75.3,13.09) 75.3,12.82 v1(75.73,12.39) ; v4(288.8,46.71) 288.8,46.66 288.83,46.63 v1(288.83,46.12) ; v4(190.18,13.2) 190.18,13.68 190.16,13.71 v1(190.16,14.37) 190.16,14.66 v4(190.88,15.38)
  IN4 w0.762: 241.98,23.41 241.98,25.48 240.46,27 240.46,28.69 238.68,30.47 238.68,39.78 235.13,43.34 231.72,43.34 230.72,44.34
  GND3 w0.254: v7(126.15,6.8) 126.38,6.57 126.38,5.61 v8(126.4,5.58)
  BOTTOM w0.203: R14.2 194.46,3.99 v1(194.59,3.99) ; v3(94.51,3.93) 94.06,3.93 93.61,3.48 93.61,3.13 93.5,3.02 JIO1.65
  BOTTOM w0.254: C234.1 77.77,11.85 76.38,11.85 75.84,12.39 v1(75.73,12.39) 75.65,12.31 75.23,12.31 U56.13 ; C235.1 72.73,17.77 U56.1 ; RP8.1 98.77,13.31 98.51,13.06 v1(98.51,13.04)
  BOTTOM w0.305: JUSH1.8 290.25,51.73 289.88,52.1 v1(287.91,52.1)
  BOTTOM w0.508: R317.1 76.52,9.91 76.34,9.73 74.75,9.73 ; v3(71.16,16.11) 71.16,16.67 72.34,17.85 C235.1 ; v3(299.4,84.43) 299.5,84.33 R212.1 ; v3(198.88,44.26) 198.41,43.79 MD2.5 ; 74.75,9.73 73.34,9.73 73.01,10.06 R316.1 R319.1 72.13,10.09 71.83,9.78 v3(71.38,9.78) ; 74.75,9.73 74.76,9.74 R318.1 ; v3(53.59,7.69) 53.53,7.69 53.23,7.39 Q43.2 ; v3(198.16,40.99) MD14.5 ; CH82.1 CH81.1 v1(103.11,23.21) ; v1(98.11,27.82) 97.85,28.07 97.85,28.47 R168.1 ; MD7.5 198.41,47.4 197.9,46.89 v3(197.9,46.8) ; RH160.2 193.46,10.38 193.28,10.56 193.14,10.56 190.16,13.54 v1(190.16,14.37) ; RH26.1 v1(123.53,9.49) ; v1(145.87,35.61) 146.15,35.33 RC17.1 ; Q7.2 50.82,7.81 51.37,8.36 v3(51.66,8.36) ; RH120.2 113.47,17.34 112.81,18 v1(109.57,18) ; R390.1 62.94,3.66 63.47,4.19 v3(63.47,6.3) ; v3(7.15,38.96) 7.58,38.52 7.58,37.69 7.83,37.43 R194.1
  vias: v1(93.72,18.27) v1(101.94,20.16) v1(103.99,21.18) v1(105.89,21.18) v1(123.23,10.56) v1(123.53,8.48) v1(241.65,22.86) v3(71.13,36.09) v3(71.16,36.67) v3(71.74,36.67) v3(71.71,36.09) v3(75.83,43.99) v3(75.83,43.15) v3(76.41,43.99) v3(76.45,43.15) v3(273.3,44.21) v3(273.9,44.21) v3(283.02,56.33) v3(283.02,55.69) v3(283.05,55.11) v6(66.6,34.95) v8(117.43,10.63) v8(120.13,10.63)
+3VS_AUDIO: length 220
  TOP w0.508: v3(93.81,4.84) 93.62,4.66 93.62,2.99 93.03,2.39 87.31,2.39 85.88,3.83 85.88,6.66 83.04,9.5 78.2,9.5 75.6,6.9 v3(75.6,6.52) ; v5(64.51,43.02) 64.51,39.95 v3(63.52,38.97) ; v3(131.6,26.54) 131.79,26.35 v5(131.79,24.91) 130.66,24.91 130.4,25.16 126.74,25.16 125.73,26.18 125.73,27.59 123.47,29.85 117.43,29.85 114.14,26.56 v5(113.24,26.56)
  IN1 w0.254: v5(131.79,24.91) 131.9,24.79 131.9,24.63 132.18,24.36 132.36,24.36 132.5,24.22 132.83,24.22 132.98,24.38 132.98,24.41 133.04,24.48 133.04,24.48 v4(133.06,24.49)
  IN1 w0.381: v5(113.24,26.56) 113.05,26.37 112.57,26.37 v4(112.55,26.38)
  IN1 w0.508: v4(112.55,26.38) 108.9,26.38 107.47,27.81 100.51,27.81 100.33,27.98 98.42,27.98 97.76,27.32 95.8,27.32 94.32,28.8 94.32,29.61 85.48,38.45 84.77,38.45 84.33,38.89 84.33,39.75 81.49,42.59 75.6,42.59 75.17,43.02 v5(64.51,43.02) ; v3(17.18,38.75) 18.62,38.75 19.66,39.8 34.53,39.8 36.27,41.53 37.54,41.53 37.91,41.9 46.96,41.9 47.99,40.87 61.5,40.87 63.41,38.97 v3(63.52,38.97)
  IN3 w0.508: v4(117.53,26.52) 117.53,26.52 117.08,26.97 115.89,26.97 115.51,26.59 115.51,25.61 115,25.1 113.55,25.1 112.55,26.1 v4(112.55,26.38)
  IN4 w0.254: v7(133.37,22.74) 133.41,22.74 133.61,22.94 133.61,23.73 133.2,24.14 133.2,24.25 133.06,24.39 v4(133.06,24.49)
  IN4 w0.508: v1(117.53,26.95) v4(117.53,26.52)
  GND3 w0.203: v8(133.26,22.37) 133.37,22.48 v7(133.37,22.74)
  BOTTOM w0.203: v3(93.81,4.84) 93.72,4.84 93.5,5.07 JIO1.66
  BOTTOM w0.254: 131.97,25.86 132.4,25.44 UCPU1.W1
  BOTTOM w0.508: 131.97,25.86 131.6,26.24 v3(131.6,26.54) 131.6,27.11 132.12,27.64 CH62.1 ; v3(63.52,38.97) 63.73,38.97 64.39,38.32 64.39,20.26 65.86,18.79 67.96,18.79 68.51,18.23 68.51,7.9 69.26,7.15 74.97,7.15 v3(75.6,6.52)
  vias: v1(12.22,50.5) v1(12.55,50.51) v3(17.16,38.14) v6(12.38,50.97)
+3VS_CAM: length 31.4
  IN4 w1.524: 233.63,34.5 233.13,34.99 233.13,35.37 231.62,36.89 206.91,36.89 205.23,38.56
  BOTTOM w0.102: 203.95,38.5 v2(203.95,37.39)
  vias: v1(233.4,33.29) v1(233.4,32.99) v1(233.4,31.72) v3(204.24,39.99) v3(204.26,39.4) v3(204.8,39.73)
+3VS_TPM: length 69.5
  TOP w0.102: v6(233.44,27.81) 233.11,27.48 v3(232.4,27.48)
  IN1 w0.254: 234.97,23.21 234.97,25.56 233.06,27.48 v3(232.4,27.48) 231.68,26.76 v3(228.56,26.76) ; 234.97,23.21 235.11,23.21 235.46,22.87 241.74,22.87 242.39,22.22 v3(242.39,22.2) ; 234.97,23.21 234.97,18.98 v3(232.17,16.17) 229.53,16.17 227.52,18.18 225.73,18.18 v3(225.33,18.57)
  IN3 w0.254: v3(245.4,16.15) 245.17,16.38 238.24,16.38 237.39,15.52 233.11,15.52 232.46,16.17 v3(232.17,16.17)
  BOTTOM w0.254: C74.1 C250.1 C75.1 ; C74.1 233.21,26.31 232.75,26.76 C79.1 ; C74.1 233.59,26.18 U21.12 ; C79.1 232.29,26.66 U21.10 ; C79.1 v3(232.4,27.48) ; U21.19 232.29,16.91 C76.1 232.17,16.78 v3(232.17,16.17) ; U21.3 227.74,26.68 C78.1 v3(228.56,26.76) ; v3(245.4,16.15) 245.51,16.26 C90.1 ; R345.2 241.63,21.77 242.06,22.2 v3(242.39,22.2) ; v3(225.33,18.57) 225.92,17.99 226.46,17.99 227.07,17.38 C77.1 227.19,17.42 228.51,17.42 229.04,17.95 U21.24
+3VS_TS: length 47
  IN4 w0.381: v1(300.39,64.93) 300.39,66.22 299.26,67.35 299.26,69.14 301.05,70.93 301.05,79.32 300.19,80.18 300.19,82.16 300.51,82.48 300.51,83.47 301.08,84.04 301.08,88.89 v1(301.53,89.34)
  BOTTOM w0.203: U60.5 301.26,52.57 301.45,52.76 301.45,53.61 C112.1 ; JTS1.8 308.6,90.41 C262.1 309.5,91.3 309.5,92.66 v1(308.39,93.77)
  BOTTOM w0.381: C112.1 300.98,54.28 R335.2 301.22,55.95 301.22,58.96 301.13,59.04 v6(301.13,60.06) 301.13,61.92 301.24,62.03 301.24,64.54 300.86,64.93 v1(300.39,64.93)
  vias: v1(302.62,94.07) v1(304.33,91.74) v1(304.52,94.07) v1(305.34,91.74) v1(305.71,95.02) v1(307.25,91.74)
+3VS_WLAN:
  vias: v3(8.44,30.66) v3(8.44,30.03) v3(9.08,30.66) v3(9.08,30.03) v3(40.55,27.29) v3(41.14,27.28) v3(41.14,26.69) v3(41.66,27.02) v6(37.6,27.68)
+3VS_WWAN: length 65
  TOP w0.102: v6(53.5,20.36) 53.43,20.44 52.77,20.44 v3(52.74,20.41)
  IN3 w0.508: 59.03,5.96 59.47,5.96 59.8,5.63 60.95,5.63 v3(62.09,6.77) ; 59.03,5.96 v4(59.03,6.01) ; 59.03,5.96 57.91,5.96 57.58,5.63 52.33,5.63 51.45,4.74 50.38,4.74 49.92,4.28 v4(48.93,4.28) 48.73,4.49 48.73,6.39 49.67,7.33 49.67,8.78 50.89,10 50.89,12.51 50.29,13.11 50.29,16.95 51.47,18.13 v3(51.47,20.41)
  IN4 w0.254: v4(59.03,6.01) 59,6.04 58.75,6.04 v1(58.57,5.86)
  IN4 w0.508: v1(51.71,2.43) 50.77,2.43 50.2,3 50.2,3.02 v4(48.93,4.28)
  BOTTOM w0.508: R72.1 51.68,2.47 v1(51.71,2.43) ; R391.1 62.52,6.34 v3(62.09,6.77)
  BOTTOM w2.54: 45.64,44.05 44.55,42.96 44.55,34.56 44.78,34.33 44.78,25.91 42.48,23.61 41.12,23.61 39.96,22.46 39.96,21.38
  vias: v1(31.56,47.48) v1(31.86,47.79) v1(31.87,47.48) v1(32.17,48.11) v1(32.17,47.79) v1(32.18,47.46) v1(44.65,46.07) v1(44.98,46.06) v1(45.32,46.06) v1(45.67,46.06) v1(45.98,46.04) v1(46.31,46.03) v1(61.96,19.73) v1(61.99,19.37) v1(62.24,19.02) v1(62.37,19.35) v1(62.62,19.04) v3(51.5,21.06) v3(52.11,21.06) v3(52.11,20.41)
+5V_DOCK: length 0.9
  IN1 w0.508: v4(89.7,14.27) v5(90.1,14.27)
  IN4 w0.508: v1(83.33,15.54) v4(83.82,15.54)
  vias: v3(90.41,6.59) v6(90.27,7.24)
+5VALW: length 335.3
  TOP w0.508: 288.84,37.15 290.04,35.95 290.04,32.47 291.14,31.37 298.13,31.37 298.8,30.7 v5(298.8,20.09)
  TOP w1.016: 288.25,38.38 288.25,39.21 291.63,42.59 291.63,43.89 294.09,46.35 294.09,53.33
  IN1 w0.254: v5(298.8,20.09) 298.98,19.92 v4(298.98,16.56)
  IN1 w0.508: 294.74,61.46 296.16,61.46 298.03,59.59 298.03,58.86 v4(298.01,58.84) ; 294.74,61.46 294.74,61.88 294.23,62.39 284.86,62.39 277.84,69.41 277.84,91.34 279.74,93.25 v3(279.74,93.34) ; 294.74,61.46 294.74,60.41 293.81,59.48 293.81,55.3 294.09,55.02
  IN1 w1.016: 248.08,20.69 239.81,20.69 239.3,20.19 ; 248.08,20.69 248.59,20.69 ; 248.08,20.69 248.59,20.69 ; 248.59,20.69 249.17,20.69 250.46,19.41 252.98,19.41 256.52,15.87 262.57,15.87 263.62,16.92 v4(265.11,16.92) ; 269.35,35.6 269.85,36.1 277.42,36.1 278.98,37.66 282.46,37.66 283.37,36.75 287.67,36.75
  IN2 w0.508: v4(77.34,46.86) 77.34,50.45 v4(76.54,51.25) ; v3(222.84,22.42) 222.84,42.46 225.16,44.77 225.16,50.34 v4(225.23,50.41) ; v3(91.26,35.73) 94.69,32.3 97.51,32.3 100.15,29.66 100.47,29.66 103.03,27.09 103.03,27.05 103.42,26.66 104.41,26.66 104.92,26.15 106.49,26.15 106.58,26.24 107.21,26.24 107.91,25.54 107.91,25.16 108.16,24.91 109.99,24.91 110.96,23.94 v4(115.48,23.94)
  IN3 w0.508: v3(87.06,14.27) 87.06,17.87 v3(86.95,17.98) 86.3,17.98 84.86,16.54 83.28,16.54 82.63,15.89 v3(82.61,15.89)
  IN3 w0.61: 81.44,43.45 81.44,42.85 80.29,41.7 80.29,37.98 83.98,34.28 83.98,24.99 82.64,23.64 82.64,15.92 v3(82.61,15.89) ; 81.44,43.45 81.44,49.75 v4(78.45,52.75) ; 81.44,43.45 84.61,40.29 86.7,40.29 v3(91.26,35.73)
  IN4 w0.076: 115.5,23.97 v4(115.48,23.94)
  IN4 w0.203: v1(298.45,59.12) 298.22,58.89 298.12,58.89 298.12,58.84 v4(298.01,58.84) ; v1(115.91,23.97) 115.5,23.97
  IN4 w0.254: v1(77.32,47.29) 77.3,47.27 77.3,46.89 v4(77.34,46.86) ; v4(298.98,16.56) 298.99,16.57 299,16.57 v1(299.32,16.89) ; v3(86.95,17.98) 86.95,18.05 90.18,21.28 90.97,21.28 92.89,23.2 v1(92.89,24.6)
  IN4 w0.508: v1(75.31,41.56) 75.26,41.61 75.26,46.31 75.67,46.72 76.68,46.72
  IN4 w1.016: v4(265.11,16.92) 265.11,18.28 269.17,22.34 269.17,32.02
  BOTTOM w0.102: v6(224.18,21.86) 224.06,21.75 PR603.1 ; v3(91.26,35.73) v6(91.26,35.06)
  BOTTOM w0.203: U27.4 298.61,59.29 v1(298.45,59.12) ; U26.4 77.2,47.34 77.25,47.29 v1(77.32,47.29) ; U25.4 227.21,29.94 v3(227.09,30.07)
  BOTTOM w0.254: C106.1 89.7,34.9 89.42,34.63 88.78,34.63 88.67,34.74 U28.2 ; v1(299.32,16.89) 299.32,16.89 300.1,17.67 300.1,19.11 299.57,19.65 PR104.2 ; R169.1 93.03,25.04 92.89,24.9 v1(92.89,24.6) ; v3(87.06,14.27) 87.06,13.78 87.08,13.76 87.08,11.65 R184.1 86.5,11.47 86.44,11.41 Q20.4
  BOTTOM w0.305: v3(279.74,93.34) 279.74,93.2 279.78,93.16 JSNR1.1
  BOTTOM w0.406: R176.1 88.99,18.62 88.86,18.75 Q16.4 88.04,18.75 87.27,17.98 v3(86.95,17.98)
  BOTTOM w0.508: C106.1 91.03,35.96 v3(91.26,35.73)
  vias: v1(9.9,39.81) v1(10.01,37.71) v1(10.21,39.81) v1(10.31,37.71) v1(10.42,39.46) v1(10.51,39.81) v1(10.63,37.71) v1(28.74,37.76) v1(28.73,37.43) v1(29.04,37.76) v1(29.06,37.42) v1(299.35,53.15) v1(299.35,52.82) v3(10.48,41.52) v3(227.14,28.59) v3(238.38,19.76) v3(268.74,34.64) v3(268.74,33.95) v3(268.74,33.27) v3(269.35,34.64) v3(269.35,33.95) v3(269.35,33.27) v4(9.56,47.24) v4(9.66,46.55) v4(10.04,47.26) v4(10.15,46.55) v4(294.14,54.22) v4(294.6,54.17) v5(288.01,37.69) v5(288.54,37.7) v5(294,54.62) v5(294.36,54.59) v6(82.27,17.87)
+5VALWP: length 13.8
  IN4 w0.254: v3(274.76,30.8) 278.34,30.8 280.09,29.06 v1(280.09,27.78)
  BOTTOM w0.203: PU300.14 v1(280.09,27.78)
  BOTTOM w0.254: 275.22,33.62 275.35,33.75 275.35,33.75 275.68,34.07 275.68,35.18 275.96,35.46 277.9,35.46 278.47,34.89 PR301.2
  vias: v2(273.4,30.9)
+5VS: length 429.7
  TOP w0.102: v6(51.33,33.81) 50.82,33.3 v3(50.82,33.1)
  TOP w0.508: v3(205.47,4.31) 204.19,4.31 196.09,12.41 194.19,12.41 185.6,21.01 185.6,22.01 v3(185.61,22.03)
  IN1 w0.508: v3(236,29.01) 236,28.8 236.43,28.36 237.27,28.36 238.66,26.97 238.66,25.25 239.69,24.22 247.98,24.22 251.93,20.28 253.29,20.28 256.75,16.82 262.32,16.82 263.36,17.86 268.06,17.86 269.11,16.81 269.11,11.61 270.75,9.97 280.46,9.97 282.26,11.77 282.26,14.51 282.63,14.89 284.9,14.89 287.62,17.61 290.75,17.61 295.84,22.71 295.84,44.42 295.41,44.85 295.41,46.3 v4(295.84,46.73)
  IN2 w0.508: v4(295.84,46.73) 294.71,46.73 292.72,48.72 291.66,48.72 291.32,49.07 291.1,49.28 288.92,49.28 288.21,49.99 286.75,49.99 286.12,49.37 v4(286.11,49.37) ; v3(19.92,37.48) 19.92,36.97 20.23,36.67 26.53,36.67 27.2,36 32.99,36 35.6,33.39 35.6,33.39 35.89,33.1 v3(50.82,33.1) 51.43,33.1 61.3,23.23 61.3,20.76 68.29,13.77 73.45,13.77 74.67,12.55 75.54,12.55 75.92,12.93 85.83,12.93 86.27,12.49 92.9,12.49 93.04,12.63 93.68,12.63 94.28,12.02 94.28,11.49 94.93,10.84 98.48,10.84 98.76,10.56 101.98,10.56 102.92,9.62 107.5,9.62 107.85,9.28 109.24,9.28 109.61,8.91 109.82,8.91 110.35,8.39 119.26,8.39 123.14,4.51 127.99,4.51 128.43,4.07 129.8,4.07 130.36,4.63 133.22,4.63 134.71,6.11 136.57,6.11 138.02,4.66 138.64,4.66 138.95,4.36 143.55,4.36 144.03,4.84 150.42,4.84 151.86,3.4 197.86,3.4 199.16,4.7 200.72,4.7 202.58,6.56 204.41,6.56 205.42,5.55 205.42,4.36 v3(205.47,4.31) 205.7,4.54 208.77,4.54 209.06,4.84 234.7,4.84 235.29,4.24 v4(235.31,4.24)
  IN4 w0.508: v1(285.81,51.86) 285.86,51.81 285.86,49.61 v4(286.11,49.37) 286.11,47.28 285.86,47.03 v1(285.79,47.03) ; v3(236,29.01) 235.97,29.01 235.32,28.36 235.32,19.36 236.61,18.06 236.61,10.97 236,10.36 236,4.91 235.34,4.24 v4(235.31,4.24)
  BOTTOM w0.254: PU702.12 185.81,21.54 186.32,22.05 186.66,22.05 187.02,22.41 PC519.1
  BOTTOM w0.305: v1(285.81,51.86) 285.81,53.07 286.94,54.2 290.04,54.2 290.75,53.49 JUSH1.7
  BOTTOM w0.508: PC519.1 186.46,22.61 186.32,22.47 185.85,22.47 185.61,22.23 v3(185.61,22.03) ; v3(19.92,37.48) QV1.2 ; v1(285.79,47.03) CZ2.1
+5VS_AUDIO: length 24
  TOP w0.762: 12.95,53.05 13.67,53.05 14.27,52.46 14.27,50.44 13.38,49.56 11.96,49.56 10.69,48.29 10.69,44.05 14.13,40.62 16.38,40.62 16.39,40.61
  BOTTOM w0.102: v3(17.42,40.16) v6(22.05,40.16)
  vias: v3(11.94,53.28) v3(11.95,52.68) v3(17.44,39.58)
+V1.05A_AOSCSUS: length 40.4
  IN2 w0.254: v4(100.11,27.45) 100.11,26.64 103.24,23.51 103.24,22.36 105.51,20.08 105.51,20.03 105.81,19.73 106.61,19.73 106.99,20.1 106.99,20.78 107.36,21.16 108.68,21.16 109.38,20.46 111.8,20.46 111.94,20.33 113.82,20.33 115.26,21.77 116.4,21.77 116.47,21.84 120.4,21.84 123.33,18.9 124.6,18.9 124.93,18.57 126.13,18.57 126.17,18.53 126.67,18.53 126.9,18.76 127.23,18.76 127.35,18.76 127.35,18.76 128.71,18.76 128.86,18.61 129.65,18.61 129.66,18.61 130.09,18.61 130.09,18.61 130.59,18.61 131.35,19.37 v4(131.38,19.37)
  IN4 w0.254: v1(131.38,19.04) v4(131.38,19.37) ; v4(100.11,27.45) 99.99,27.32 v1(99.55,27.32)
  vias: v2(100.85,32.02)
+V1.05A_DCPSUS1: length 37.7
  IN2 w0.254: v4(103.57,27.27) 103.64,27.35 107.96,27.35 109.66,25.65 112.91,25.65 113.5,25.06 115.78,25.06 115.92,25.21 116.34,25.21 116.58,25.45 116.58,25.78 116.57,25.79 116.57,26.39 116.57,26.4 116.57,27.45 116.92,27.81 122.74,27.81 128.18,22.37 128.67,22.37 129.33,21.71 129.84,21.71 129.87,21.74 130.82,21.74 130.86,21.71 130.9,21.71 131.2,21.4 v4(131.2,21.33)
  IN4 w0.254: v4(131.2,21.33) 131.26,21.33 131.39,21.2 v1(131.63,21.2) ; v1(103.11,27.27) v4(103.57,27.27)
  BOTTOM w0.102: RH138.1 103.11,28.94 103.26,29.09 103.26,29.9 v2(103.55,30.19)
  BOTTOM w0.254: RH138.1 v1(103.11,27.27)
+V1.05A_DCPSUS2: length 33.9
  IN2 w0.254: v4(136.15,21.61) 135.46,21.61 134.9,22.17 134.9,23.44 134.66,23.68 134.66,24.29 134.21,24.73 134.21,24.96 133.5,25.67 133.39,25.67 132.95,26.1 131.33,26.1 131.1,26.33 131.1,26.99 129.5,28.59 116.6,28.59 114.97,26.97 v4(114.97,26.26)
  IN4 w0.203: v4(136.15,21.61) 136.12,21.64 136.08,21.64 135.86,21.86 v1(135.86,21.87)
  IN4 w0.254: v4(114.97,26.26) 115,26.23 115,25.95 115.34,25.61 v1(115.67,25.61)
  BOTTOM w0.102: v2(117.08,28.06) 116.47,28.06 115.67,27.26 v1(115.67,25.61)
  BOTTOM w0.254: RH141.2 CH63.1 v1(115.67,25.61)
+V1.05A_DCPSUS3: length 49.6
  IN2 w0.254: v4(103.36,18.33) 103.36,18.24 103.55,18.05 103.55,18.04 104.05,17.54 104.2,17.54 104.77,16.97 107.3,16.97 107.54,17.21 108.38,17.21 108.87,17.71 115.89,17.71 117.39,19.21 119.08,19.21 122.31,15.98 124.79,15.98 125.03,15.74 125.29,15.74 125.63,15.41 125.79,15.24 125.79,14.89 126.98,13.71 127.51,13.71 128.87,15.07 131.23,15.07 131.67,15.51 v4(131.68,15.51)
  IN3 w0.254: v4(103.36,18.33) 103.36,18.28 103.16,18.08 103.16,16.55 102.8,16.2 102.8,11.12 102.91,11.02 102.91,10.77 v4(102.93,10.75)
  IN4 w0.203: v1(102.6,10.71) 102.7,10.71 102.72,10.72 102.88,10.72 102.91,10.75 v4(102.93,10.75)
  IN4 w0.254: v1(131.63,15.14) 131.63,15.46 v4(131.68,15.51)
  BOTTOM w0.102: RH139.2 100.82,9.97 100.37,9.52 96.96,9.52 v2(96.9,9.58)
  BOTTOM w0.254: RH139.2 102.08,10 CH60.1 103.4,10.06 CH61.1 103.41,10.11 102.82,10.71 v1(102.6,10.71)
+V1.05S_APLL: length 60.4
  IN2 w0.254: v4(137.32,15.85) 137.15,15.85 136.91,16.09 136.3,16.09 135.72,15.51 135.15,15.51 133.97,14.33 133.97,12.03 131.06,9.12 128.76,9.12 127.96,9.92 125.95,9.92 124.79,11.08 124.33,11.08 123.62,11.8 122.56,11.8 122.41,11.95 121.52,11.95 119.79,13.68 116.6,13.68 115.39,14.89 108.39,14.89 107.54,15.74 104.27,15.74 103.89,16.12 103.38,16.12 102.8,16.71 101.77,16.71 100.62,17.86 v4(100.62,18.23)
  IN3 w0.254: v4(100.58,21.26) 100.58,18.27 v4(100.62,18.23)
  IN4 w0.254: v4(100.58,21.26) 100.99,21.67 102.28,21.67 102.83,22.22 106.02,22.22 106.55,21.68 v1(108.44,21.68) ; v1(137.04,15.29) 137.35,15.6 137.35,15.83 v4(137.32,15.85)
  BOTTOM w0.254: v1(108.44,21.68) 108.44,22.31 108.86,22.72 110.23,22.72 110.48,22.96 RH144.1
+V1.05S_APLLOPI: length 65.5
  IN2 w0.254: v4(97.45,23.35) 97.27,23.17 97.27,20.74 101.71,16.3 102.41,16.3 102.8,15.91 102.8,15.58 103.49,14.89 104.57,14.89 104.86,15.18 107.63,15.18 108.26,14.56 113.02,14.56 113.7,13.87 114.18,13.87 114.29,13.98 115.61,13.98 116.33,13.25 119.75,13.25 121.39,11.62 122.27,11.62 122.42,11.47 122.86,11.47 123.58,10.75 124.62,10.75 125.78,9.59 127.83,9.59 128.62,8.79 131.22,8.79 134.3,11.87 134.3,14.19 135.27,15.16 135.84,15.16 136.44,15.76 136.78,15.76 137.15,15.38 137.45,15.38 138.21,16.15 138.21,17.6 137.01,18.8 137.01,19.68 v4(137.26,19.92)
  IN4 w0.254: v1(137.04,19.62) 137.04,19.69 137.26,19.91 v4(137.26,19.92) ; v1(100.16,24.22) 98.22,24.22 97.45,23.45 v4(97.45,23.35)
  BOTTOM w0.102: v1(100.16,24.22) 100.16,21.81 v2(100.39,21.58)
  BOTTOM w0.254: RH143.1 v1(100.16,24.22)
+V1.05S_ASATA3PLL: length 14.1
  IN2 w0.381: v4(132.17,13.97) 132.36,13.78 132.36,13.29 132.59,13.06 132.93,13.06 133.16,12.84 133.16,11.77 131.46,10.08 130.92,10.08 130.71,10.29 v4(130.13,10.29)
  IN4 w0.203: v4(130.13,10.29) 130.13,10.29 130.08,10.34 130.08,10.74 v1(130.23,10.88)
  IN4 w0.254: v1(131.81,13.99) 132.15,13.99 132.17,13.97 132.17,13.97 v4(132.17,13.97)
  IN4 w0.381: v4(130.13,10.29) 129.87,10.02 129.18,10.02 128.43,9.27 v1(128.43,8.97)
  BOTTOM w0.254: UCPU1.T33 131.66,13.84 v1(131.81,13.99)
  BOTTOM w0.381: RH20.2 129.4,6.09 128.94,6.54 128.94,8.46 v1(128.43,8.97)
  vias: v2(128.24,5.07)
+V1.05S_AUSB: length 34.8
  IN2 w0.254: v4(136.69,20.35) 136.69,19.94 136.34,19.59 134.44,19.59 133.74,20.29 133.04,20.29 132.69,20.64 131.94,20.64 131.66,20.92 130.88,20.92 130.88,20.93 130.28,20.93 130.14,20.78 129.37,20.78 128.37,21.79 128.08,21.79 124.52,25.34 124.52,25.34 122.74,27.12 118.5,27.12 118.33,26.95 118.33,24.9 117.97,24.54 117.33,24.54 116.81,24.02 v4(116.81,23.99)
  IN4 w0.254: v1(116.47,23.51) 116.56,23.51 116.81,23.77 v4(116.81,23.99) ; v1(137.04,20.49) 136.83,20.49 v4(136.69,20.35)
  BOTTOM w0.254: RH147.1 111.07,23.63 113.16,23.63 113.68,23.11 113.68,22.59 113.81,22.46 115.49,22.46 115.91,22.88 CH79.1 115.94,22.95 116.47,23.49 v1(116.47,23.51)
+V1.05S_AUSB3PLL: length 53.2
  IN2 w0.381: v4(132.03,12.77) 132.03,12.77 131.73,12.77 131.43,12.47 131.04,12.47 130.7,12.81 129.59,12.81 129.53,12.87 129.31,12.87 127.54,11.1 v4(127.54,11.03) 126.91,11.03 125.39,12.55 124.95,12.55 123.76,13.74 121.8,13.74 120.76,14.78 117.25,14.78 116.26,15.76 108.77,15.76 v4(108.71,15.7)
  IN3 w0.381: v4(110.28,3.8) 110.28,3.83 109.23,4.88 109.23,14.79 108.71,15.31 v4(108.71,15.7)
  IN4 w0.254: v4(127.54,11.03) 127.65,11.13 v1(128.07,11.13) ; v1(131.59,12.74) 132,12.74 v4(132.03,12.77)
  IN4 w0.381: v4(110.28,3.8) 110.99,3.8 v1(111.45,3.34)
  BOTTOM w0.381: CH57.1 114.53,5.54 116.79,5.54 v2(117.17,5.92) 117.29,6.05 121.84,6.05 122.06,5.83 125.2,5.83 RH134.1
+V1.05S_AXCK_DCB: length 15.2
  IN4 w0.254: v1(144.02,4.53) 141.27,4.53 140.09,5.71 140.09,6.3 139.33,7.06 139.33,8.28 139.03,8.58 139.03,8.86 137.96,9.93 137.96,11.49 v1(137.29,12.15)
  BOTTOM w0.102: L1.2 149.95,2.04 v2(151.59,2.04)
+V1.05S_AXCK_LCPLL: length 35.5
  IN2 w0.254: v4(124.42,6.82) 124.87,6.38 132.39,6.38 133.96,7.96 137.72,7.96 138.44,8.68 138.96,8.68 139.55,8.09 142.1,8.09 143.22,6.98 v4(143.24,6.98)
  IN4 w0.254: v1(137.04,12.69) 137.13,12.78 138.35,12.78 139.5,11.63 139.5,10.88 139.5,10.88 139.5,10.75 139.51,10.74 139.51,10.49 140.46,9.54 141.67,9.54 143.24,7.97 v4(143.24,6.98) 143.06,6.8 v1(143.09,5.3) ; v1(123.98,6.82) v4(124.42,6.82)
  BOTTOM w0.102: v2(144.87,6.1) 143.89,6.1 v1(143.09,5.3)
  BOTTOM w0.254: RH31.2 123.91,6.82 v1(123.98,6.82)
+V1.05S_MPHY_PCIE: length 9.1
  IN4 w0.381: v1(132.61,8.44) 134.09,9.92 134.09,11.05 134.04,11.09 134.04,11.16 133.7,11.51 v1(133.7,11.88)
  BOTTOM w0.102: v2(136.12,1.92) 136.01,1.82 132.73,1.82 132.03,2.52 R9.2
+V1.05S_MPHY_SATA:
  vias: v2(129.5,4.53)
+V1.05S_MPHY_USB3: length 5.7
  IN4 w0.254: v1(134.56,12.38) 134.56,12.35 134.89,12.02 134.89,11.75 134.76,11.61 134.76,8.63 134.18,8.04 v1(134.17,8.04)
  BOTTOM w0.102: CH39.1 v2(135.07,6.94)
+VCC_CORE: length 13.3
  IN3 w0.508: v3(158.79,12.2) 158.83,12.2 158.86,12.16 161.43,12.16 165.05,8.54 165.05,5.33 165.66,4.73 166.15,4.73 v4(166.21,4.79)
  IN4 w0.508: v1(166.86,4.16) 166.75,4.27 166.72,4.27 v4(166.21,4.79)
  vias: v1(145.78,10.05) v1(146.09,9.87) v1(146.37,9.7) v1(146.54,9.44) v1(149.36,11.55) v1(149.79,11.13) v1(149.79,10.63) v1(150.23,11.55) v1(150.23,10.88) v1(150.54,11.44) v1(150.66,11.13) v1(150.66,10.13) v3(156.8,14.06) v3(157.39,14.06) v3(157.52,12.2) v3(158.15,14.06) v3(158.16,12.2) v3(158.79,14.06) v3(169.33,21.68) v3(169.45,25.75) v3(169.45,25.11) v3(169.45,24.48) v3(169.45,23.72) v3(169.45,23.08) v3(169.49,22.24) v3(169.96,21.43) v3(170.09,26) v3(170.08,25.38) v3(170.08,24.73) v3(170.08,24.06) v3(170.06,23.38) v3(170.06,22.66) v3(170.22,20.79) v3(170.33,21.92) v3(170.6,21.3) v3(170.7,22.44) v3(170.98,21.81) v3(170.98,20.79) v3(171.3,22.41) v3(171.36,21.3) v3(171.73,21.82) v3(171.84,26.81) v3(171.98,22.44) v3(172.12,21.18) v3(172.4,21.83) v3(172.59,22.46) v3(172.72,26.8) v3(172.76,21.19) v3(173.04,21.85) v3(173.19,22.46) v3(173.4,26.77) v3(173.4,21.17) v3(173.67,21.82) v3(173.82,22.48) v3(174.36,21.82) v3(174.46,22.47) v4(145.07,11.14) v4(145.53,11.47) v4(145.45,10.94) v4(145.91,10.94) v4(145.98,11.4) v4(146.39,11.54) v4(149.16,11.19) v4(149.57,10.89) v4(149.74,11.55) v4(150.18,11.22) v4(150.15,10.53) v4(150.53,11.78) v4(150.58,10.79) v4(150.92,11.48) v6(166.75,24.8)
+VCCIO_OUT: length 11.4
  IN4 w0.254: v1(146.33,10.63) 146.33,10.31 147.88,8.76 147.88,8.74 149.24,7.39 149.35,7.39 150,6.73 150.21,6.52 150.21,6.15 150.21,6.15 150.21,4.6 150.96,3.85 v1(151.29,3.85)
  BOTTOM w0.254: v1(151.29,3.85) 151.42,3.73 v2(152.26,3.73) 153.33,3.73 CH19.1
+VCCIOA_OUT: length 5.2
  IN1 w0.508: v4(139.89,8.53) 139.89,10 139.13,10.76 139.13,11.09 139.05,11.17 139.05,11.17 v4(139.07,11.17)
  IN4 w0.254: v4(139.07,11.17) 139.05,11.17 139.13,11.24 139.13,11.39 v1(138.97,11.55) ; v1(139.94,7.97) 139.94,8.48 v4(139.89,8.53)
  BOTTOM w0.102: v2(139.8,6.91) 139.94,7.05 v1(139.94,7.97)
AGND: length 286.7
  TOP w0.381: 87.17,3.8 87.75,3.22 91.91,3.22 92.21,3.52 92.21,4.97 93.22,5.97 94.26,5.97 94.89,5.35 v3(94.89,5.19) 94.89,4.76 95.17,4.48 96.34,4.48 96.84,4.99 96.84,6.2 95.77,7.27 v3(95.66,7.27) 95.66,7.38 95.12,7.92 92.46,7.92 90.31,5.76 89.17,5.76 88.4,6.52 88.4,8.48 ; 12.46,56.86 12.46,57.99 11.92,58.53
  TOP w0.508: 12.46,56.86 12.46,54.65 v3(12.29,54.48) 11.97,54.16 v3(11.77,54.16) 10.72,53.12 7.85,53.12 7.31,52.58 7.31,47.6 8.41,46.5 8.41,43.95 9.12,43.23 9.12,41.38 13.24,37.27 18.85,37.27 19.36,36.76 36.45,36.76 40.54,32.66 43.44,32.66 47.97,28.13 v6(54.48,28.13) 57.81,28.13 60.85,25.1 v6(60.85,21.33) 60.85,15.1 62.42,13.54 62.42,12.1 65.65,8.86 73.13,8.86 77.04,12.77 84.12,12.77 88.4,8.48 ; 87.17,3.8 86.74,4.23 86.74,7.18 83.29,10.63 77.95,10.63 74.09,6.77 64.82,6.77 60.3,11.29 60.3,12.68 58.88,14.1 v6(58.88,20.58) 58.88,24.14 56.91,26.1 46.91,26.1 42.42,30.59 39.76,30.59 35.5,34.85 30.01,34.85 29.25,34.09 21.82,34.09 21.63,34.28 14.92,34.28 13.66,35.54 12.03,35.54 7.06,40.51 7.06,42.43 6.25,43.24 4.45,43.24 3.09,44.6 3.09,53.63 4.53,55.07 9.36,55.07 10.75,56.47 10.75,57.97 11.32,58.53 11.92,58.53
GND: length 1422
  TOP w0.508: JAPS1.20 v3(49.31,57.29) ; v3(38.16,55.77) JAPS1.19
  GND1 w0.203: 8.62,24.86 JNGFF1.69 ; JNGFF1.69 8.62,22.44 ; JNGFF1.69 8.62,23.65 ; JNGFF1.69 9.25,24.86 ; JNGFF1.69 9.25,22.44 ; H2.1 301.43,1.98 ; H2.1 301.43,6.84 ; H2.1 301.43,4.41 ; H2.1 295.57,4.41 ; H2.1 298.5,1.98 ; H2.1 295.57,6.84 ; H2.1 298.5,6.84 ; H2.1 295.57,1.98 ; H8.1 175.1,16.67 ; H8.1 174.32,16.42 ; H8.1 173.54,18.23 ; H8.1 174.32,18.48 ; H8.1 175.35,17.45 ; H8.1 173.54,16.67 ; H8.1 173.29,17.45 ; H8.1 175.1,18.23 ; H1.1 307.23,100.41 ; H1.1 304.5,103.14 ; H1.1 302.52,102.39 ; H1.1 304.5,97.68 ; H1.1 302.52,98.43 ; H1.1 301.77,100.41 ; H1.1 306.48,98.43 ; H1.1 306.48,102.39 ; H6.1 209.23,56.95 ; H6.1 204.52,58.93 ; H6.1 208.48,58.93 ; H6.1 206.5,54.22 ; H6.1 206.5,59.68 ; H6.1 208.48,54.97 ; H6.1 203.77,56.95 ; H6.1 204.52,54.97 ; H4.1 75.53,56.95 ; H4.1 70.07,56.95 ; H4.1 74.78,58.93 ; H4.1 72.8,59.68 ; H4.1 70.82,54.97 ; H4.1 72.8,54.22 ; H4.1 70.82,58.93 ; H4.1 74.78,54.97 ; JNGFF1.22 22.94,26.36 ; JNGFF1.22 22.05,26.36 ; JNGFF1.22 22.5,26.25 ; 118.32,16.42 H9.1 ; H9.1 119.1,16.67 ; H9.1 119.35,17.45 ; H9.1 117.54,16.67 ; H9.1 119.1,18.23 ; H9.1 118.32,18.48 ; H9.1 117.29,17.45 ; H9.1 117.54,18.23 ; JNGFF1.68 32.37,23.65 ; JNGFF1.68 31.75,24.86 ; JNGFF1.68 32.37,24.86 ; JNGFF1.68 32.37,22.44 ; JNGFF1.68 31.75,22.44 ; JNGFF1.16 24,28.17 ; JNGFF1.16 24.44,28.06 ; JNGFF1.16 23.55,28.06 ; 1.27,24.51 H5.1 ; H5.1 6.73,24.51 ; H5.1 4,27.24 ; H5.1 5.98,26.49 ; H5.1 4,21.78 ; H5.1 2.02,26.49 ; H5.1 5.98,22.53 ; H5.1 2.02,22.53 ; JNGFF1.10 26.06,26.81 ; JNGFF1.10 25.94,26.36 ; JNGFF1.10 25.05,26.36 ; JNGFF1.10 25.5,26.25 ; H3.1 83.17,6.08 ; H3.1 79.21,4.41 ; H3.1 79.83,2.74 ; H3.1 81.5,6.7 ; H3.1 79.83,6.08 ; H3.1 83.17,2.74 ; H3.1 83.79,4.41 ; H3.1 81.5,2.12 ; JNGFF1.28 21.44,28.06 ; JNGFF1.28 21,28.17 ; JNGFF1.28 20.55,28.06
  IN1 w0.203: v10(138.2,20.06) 138.05,19.91 v4(137.77,19.91) ; v10(143.89,11.76) 143.75,11.9 v4(143.75,12.16) ; v10(142.29,12.28) 142.47,12.28 v4(142.65,12.1) ; v4(142.65,12.1) 142.83,12.28 v10(142.98,12.28) ; v4(142.65,12.1) 142.69,12.06 v10(142.69,11.67) ; v4(134.83,17.85) v10(134.83,18.28)
  IN1 w0.254: v4(153.66,14.41) 154,14.41 v10(154.01,14.39) ; v10(151.86,11.96) 151.76,11.96 151.72,11.92 v4(151.36,11.92) ; v4(140.74,21.32) 140.72,21.3 v10(140.37,21.3) ; v4(202.32,13.68) v10(202.32,14.01) ; v10(135.01,1.92) 135.05,1.96 v4(135.05,2.28) ; v10(152.87,28.06) 152.87,27.73 v4(152.89,27.7) ; v10(252.82,16.1) 252.8,16.11 v4(252.8,16.43) ; v10(137.96,2.79) 137.96,2.47 v4(137.98,2.44) ; v10(153.33,13.73) 153.45,13.86 v4(153.67,13.86) ; v4(153.62,17.94) 153.62,17.58 v10(153.6,17.57) ; v10(136.51,16.39) 136.51,16.72 v4(136.48,16.74) ; v10(156.07,27.45) 156.22,27.6 v4(156.22,27.81) ; v4(138.65,21.06) 138.64,21.06 138.42,21.28 v10(138.36,21.28) ; v10(297.04,13.35) 297.01,13.38 v4(297.01,13.73) ; v10(250.73,16.86) 250.73,16.53 v4(250.71,16.5) ; v4(113,2.1) 112.98,2.1 v10(112.72,2.36) ; v10(133.84,19.14) 133.84,19.17 v4(133.59,19.42) ; v4(153.85,15.79) 153.87,15.82 v10(154.21,15.82) ; 30.36,32.96 30.36,32.99 v3(30.44,33.06) 30.54,32.96 ; 30.36,32.96 30.36,32.52 29.72,31.88 29.72,30.8 34.06,26.47 34.06,25.24 40.7,18.6 40.7,4.37 41.25,3.83 v3(41.25,3.75) 44.74,3.75 45.3,4.31 45.3,4.41 48.72,7.83 48.72,18.46 39.81,27.36 39.81,29 38.22,30.59 v3(38.22,30.95) 38.22,32 37.26,32.96 30.54,32.96 ; 30.36,32.96 30.54,32.96 ; v4(128.23,26.36) 128.23,25.93 v10(128.26,25.9) ; v10(150.81,21.23) 150.81,21.23 150.58,21.45 v4(150.58,21.48) ; v4(143.88,8.91) 143.72,8.76 v10(143.55,8.76) ; v10(148.04,2.71) 148.07,2.74 v4(148.07,3.09) ; v10(153.6,16.71) 153.97,16.71 v4(153.97,16.7) ; v10(111.74,3.29) 111.98,3.29 112.09,3.18 v4(112.12,3.18) ; v4(157.76,8.05) 157.81,8.01 158.01,8.01 158.07,7.94 v10(158.25,7.94) ; v4(144.33,27.65) 144.31,27.68 v10(144.31,28.01) ; v10(144.31,11.83) 144.28,11.85 v4(144.28,12.18) ; v4(153.38,18.99) 153.38,18.86 v10(153.2,18.69) ; v10(161.05,7.87) 161.05,7.52 v4(161.03,7.5) ; v4(136.31,18.45) 136.55,18.69 v10(136.56,18.69) ; v4(249.04,16.13) 249.04,15.92 v10(248.89,15.78) ; v4(137.86,20.38) 137.9,20.38 137.98,20.45 138.22,20.45 v10(138.27,20.5) ; v10(141.64,9.16) v4(141.64,8.81) ; v10(140.85,27.04) 140.8,27.09 v4(140.8,27.4) ; v10(247.53,15.94) 247.51,15.97 v4(247.51,16.3) ; v10(159.45,7.89) 159.45,7.54 v4(159.47,7.51) ; v4(135.49,12.72) 135.49,12.57 v10(135.34,12.41) ; v4(159.07,17.21) 158.91,17.06 v10(158.74,17.06) ; v10(132.52,13.43) 132.62,13.53 v4(132.88,13.53) ; v4(151.5,21.48) 151.55,21.48 v10(151.78,21.25) ; v4(133.03,16.4) 133.03,16.25 v10(132.88,16.1) ; v4(200.57,13.4) v10(200.9,13.4) ; v4(18.86,31.39) v10(18.86,31.01)
  IN1 w0.508: v4(185.51,57.96) v10(185.89,57.96) ; v4(145.07,58.01) v10(144.56,58.01) ; v4(88.17,58.51) v10(88.17,58.88) ; v4(89.19,58.64) v10(89.57,58.64) ; v4(187.3,56.93) v10(186.79,56.93) ; v4(190.1,57.96) v10(190.1,57.57) ; v4(192.11,57.96) v10(192.11,57.45) ; v4(90.21,58.77) v10(90.59,58.77) ; v4(179.87,57.5) 179.74,57.5 v10(179.49,57.75) ; v4(87.16,58.51) v10(87.16,58.89) ; v4(132.37,58.5) v10(132.37,58.83) ; v4(130.34,58.34) v10(130.34,58.68) ; v4(129.32,58.34) v10(129.32,58.76) ; v4(83.09,58.39) v10(83.09,58.89) ; v4(127.86,58.81) v10(128.29,58.81) ; v10(131.34,58.79) 131.38,58.76 v4(131.38,58.45) ; v4(189.14,57.96) v10(189.14,57.5) ; v4(188.02,57.98) v10(187.51,57.98) ; v4(133.64,58.43) v10(133.64,58.76) ; v4(82.13,58.44) v10(82.13,58.82) ; v4(150.15,57.62) v10(150.53,57.62) ; v4(148.25,57.24) v10(148.88,57.24)
  VCC w0.203: 301.77,100.41 H1.1 ; H1.1 302.52,102.39 ; H1.1 302.52,98.43 ; H1.1 306.48,102.39 ; H1.1 304.5,103.14 ; H1.1 306.48,98.43 ; H1.1 304.5,97.68 ; H1.1 307.23,100.41 ; H6.1 208.48,54.97 ; H6.1 204.52,54.97 ; H6.1 206.5,54.22 ; H6.1 204.52,58.93 ; H6.1 203.77,56.95 ; H6.1 209.23,56.95 ; H4.1 75.53,56.95 ; H4.1 70.82,58.93 ; H4.1 70.82,54.97 ; H4.1 70.07,56.95 ; H4.1 74.78,58.93 ; H4.1 74.78,54.97 ; H4.1 72.8,54.22
  IN3 w0.254: 5.14,55.53 5.96,54.71 5.96,53.23 5.89,53.16 5.89,52.46 5.89,52.46 5.89,50.16 6.89,49.15 10.01,49.15 10.34,48.82 19.73,48.82 20.93,50.02 20.93,52.56 19.85,53.64 18.8,53.64 v3(18.66,53.49) ; v3(99.22,4.83) 99.22,5.32 96.63,7.92 93.22,7.92 91.16,5.86 91.16,4.65 90.69,4.18 88.62,4.18 v3(88.44,4.36) 88.26,4.18 87.98,4.18 87.54,4.63 87.54,6.46 82.38,11.62 71.52,11.62 71.5,11.64 64.03,11.64 61.89,13.77 58.62,13.77 55.16,17.23 52.49,17.23 51.62,16.36 v3(51.62,16.35) 51.47,16.19 51.47,15.88 51.88,15.47 v3(52.7,15.47) 52.93,15.47 53.56,16.1 54.97,16.1 58.91,12.16 61.86,12.16 63.62,10.41 70.79,10.41 71.03,10.64 71.74,10.64 71.98,10.41 82.1,10.41 86.5,6.01 86.5,4.23 87.58,3.15 91.15,3.15 92.2,4.21 92.2,5.16 92.94,5.9 94.24,5.9 94.43,5.71 97.19,5.71 v3(97.45,5.46) 97.45,5.07 97.93,4.59 98.97,4.59 99.21,4.83 v3(99.22,4.83)
  GND2 w0.203: H2.1 301.43,4.41 ; H2.1 295.57,4.41 ; H2.1 301.43,6.84 ; H2.1 301.43,1.98 ; H2.1 298.5,6.84 ; H2.1 295.57,1.98 ; H2.1 295.57,6.84 ; H2.1 298.5,1.98 ; JNGFF1.28 21,28.17 ; JNGFF1.28 21.44,28.06 ; JNGFF1.28 20.55,28.06 ; H6.1 208.48,58.93 ; H6.1 208.48,54.97 ; H6.1 204.52,54.97 ; H6.1 206.5,54.22 ; H6.1 209.23,56.95 ; H6.1 203.77,56.95 ; H6.1 204.52,58.93 ; H6.1 206.5,59.68 ; H1.1 306.48,98.43 ; H1.1 302.52,98.43 ; H1.1 301.77,100.41 ; H1.1 304.5,103.14 ; H1.1 304.5,97.68 ; H1.1 302.52,102.39 ; H1.1 306.48,102.39 ; H1.1 307.23,100.41 ; JNGFF1.68 32.37,22.44 ; JNGFF1.68 31.75,24.86 ; JNGFF1.68 32.37,24.86 ; JNGFF1.68 31.75,22.44 ; JNGFF1.68 32.37,23.65 ; H4.1 72.8,59.68 ; H4.1 70.82,54.97 ; H4.1 74.78,58.93 ; H4.1 70.82,58.93 ; H4.1 74.78,54.97 ; H4.1 75.53,56.95 ; H4.1 72.8,54.22 ; H4.1 70.07,56.95 ; 9.25,22.44 JNGFF1.69 ; JNGFF1.69 9.25,24.86 ; JNGFF1.69 8.62,24.86 ; JNGFF1.69 8.62,22.44 ; JNGFF1.69 8.62,23.65 ; 174.32,16.42 H8.1 ; H8.1 174.32,18.48 ; H8.1 173.54,16.67 ; H8.1 175.1,18.23 ; H8.1 175.35,17.45 ; H8.1 173.54,18.23 ; H8.1 175.1,16.67 ; H8.1 173.29,17.45 ; H3.1 83.17,6.08 ; H3.1 81.5,2.12 ; H3.1 83.79,4.41 ; H3.1 79.83,6.08 ; H3.1 83.17,2.74 ; H3.1 81.5,6.7 ; H3.1 79.21,4.41 ; H3.1 79.83,2.74 ; 25.5,26.25 JNGFF1.10 ; JNGFF1.10 25.94,26.36 ; JNGFF1.10 26.06,26.81 ; JNGFF1.10 25.05,26.36 ; 22.05,26.36 JNGFF1.22 ; JNGFF1.22 22.5,26.25 ; JNGFF1.22 22.94,26.36 ; H9.1 119.1,16.67 ; H9.1 118.32,16.42 ; H9.1 117.54,18.23 ; H9.1 118.32,18.48 ; H9.1 117.54,16.67 ; H9.1 117.29,17.45 ; H9.1 119.35,17.45 ; H9.1 119.1,18.23 ; H5.1 4,27.24 ; H5.1 5.98,26.49 ; H5.1 6.73,24.51 ; H5.1 4,21.78 ; H5.1 2.02,26.49 ; H5.1 5.98,22.53 ; H5.1 1.27,24.51 ; H5.1 2.02,22.53 ; JNGFF1.16 24,28.17 ; JNGFF1.16 23.55,28.06 ; JNGFF1.16 24.44,28.06
  IN4 w0.102: 121.2,4.06 121.58,3.68 122.1,3.68 122.58,3.21 v7(122.82,3.21) v7(126.5,3.21) v7(129.05,3.21) 129.96,3.21 v7(130.95,4.2) v7(132.23,5.47) 132.67,5.92 v7(133.93,5.92) 134.24,6.22 135.98,6.22 137.38,7.62 137.38,9.04 137.67,9.34 137.91,9.34 138.3,8.94 138.3,7.51 v7(138.23,7.43) 138.23,7.23 135.75,4.75 134.72,4.75 v4(134.71,4.77) 134.37,5.11 133.01,5.11 132.16,4.25 v7(132.16,4.25) 132.16,4.25 v7(130.98,3.08) 130.24,2.33 v7(129.1,2.33) v7(126.32,2.33) v7(123.43,2.33) v7(120.79,2.33) 120.76,2.36 120.74,2.36 120.21,2.89 120.21,4.13 v7(120.39,4.32) 120.65,4.06 121.2,4.06
  IN4 w0.203: v4(153.38,18.99) 153.4,19.02 153.4,19.09 153.61,19.3 v1(153.62,19.3) ; v1(153.62,17.57) v4(153.62,17.94) ; v4(153.85,15.79) 153.87,15.77 v1(153.87,15.41) ; v4(153.66,14.41) 153.68,14.41 153.81,14.54 v1(154.37,14.54) ; v4(153.67,13.86) 153.77,13.86 154.02,14.11 v1(154.12,14.11) ; v4(140.74,21.32) 140.64,21.32 140.42,21.54 v1(140.27,21.54) ; v4(134.83,17.85) v7(134.83,18.23) ; v1(153.62,16.7) v4(153.97,16.7)
  IN4 w0.254: v4(293.76,85.64) v7(293.76,86) ; v7(157.36,17.9) 157.14,18.13 v4(157.14,18.18) ; v7(159.42,17.21) v4(159.07,17.21) ; v7(132.99,13.19) 132.88,13.3 v4(132.88,13.53) ; v7(152.54,27.63) 152.82,27.63 v4(152.89,27.7) ; v4(113,2.1) 113.01,2.11 113.26,2.11 v7(113.36,2.01) ; v7(151.01,21.4) 150.66,21.4 v4(150.58,21.48) ; v7(140.42,27.42) 140.78,27.42 v4(140.8,27.4) ; v7(144.5,11.68) 144.5,11.71 144.28,11.93 v4(144.28,12.18) ; v4(297.01,13.73) 297.01,13.91 v7(297.18,14.08) ; v4(156.22,27.81) 156.22,27.73 v7(156.02,27.53) ; v3(18.66,53.49) 18.48,53.68 16.4,53.68 16.14,53.93 16.14,55.75 15.4,56.49 13.92,56.49 12.77,55.35 12.77,53.35 12.41,52.98 12.41,52.08 13.55,50.94 13.55,49.63 16.1,47.08 19.47,47.08 24.84,41.71 24.86,41.71 28.15,38.42 28.43,38.42 v3(28.46,38.45) 28.99,38.45 29.89,37.55 29.89,37.55 30.56,36.88 30.56,36.88 31.36,36.08 31.87,36.08 32.31,35.64 37.58,35.64 38.16,36.22 38.16,41.03 v3(36.92,42.27) 33.15,46.04 30.59,46.04 30.26,46.37 28.2,46.37 23.79,50.79 v3(23.79,51.54) 23.79,51.96 23.2,52.55 v3(23.2,52.56) ; v7(144.69,27.78) 144.46,27.78 v4(144.33,27.65) ; v7(151.84,21.39) 151.65,21.39 151.56,21.48 v4(151.5,21.48) ; v1(137.54,20.49) 137.75,20.49 v4(137.86,20.38) ; v7(144.17,8.64) 143.9,8.91 v4(143.88,8.91) ; v4(137.77,19.91) 137.77,19.86 137.54,19.63 v1(137.54,19.62) ; v4(198.47,7.53) 198.47,7.54 198.64,7.71 v7(198.64,7.91) ; v7(142.9,11.64) 142.89,11.64 142.65,11.88 v4(142.65,12.1) ; v4(161.03,7.5) v7(161.43,7.5) ; v4(249.04,16.13) 249.29,15.88 v7(249.31,15.88) ; v4(141.64,8.81) 141.7,8.81 v7(141.95,8.56) ; v4(136.48,16.74) 136.48,16.81 136.56,16.88 v7(136.56,17.16) ; v7(250.48,16.22) 250.71,16.45 v4(250.71,16.5) ; v1(296.64,80.36) 296.64,79.81 v4(296.68,79.77) ; v4(135.05,2.28) 135.14,2.28 135.37,2.05 v7(135.38,2.05) ; v4(133.59,19.42) 133.64,19.47 v7(133.64,19.78) ; v1(69.9,27.75) v4(69.9,28.2) ; v4(143.75,12.16) v7(143.75,11.66) ; v4(252.8,16.43) 252.8,16.13 v7(252.77,16.1) ; v7(140.04,27.3) 140.04,26.97 v4(140.02,26.94) ; v4(136.31,18.45) 136.51,18.45 136.65,18.31 v7(136.66,18.31) ; v1(181.14,57.96) v1(180.12,57.96) ; v4(157.76,8.05) 157.76,8.24 v7(157.63,8.37) ; v7(112.32,2.89) 112.32,2.89 112.12,3.09 v4(112.12,3.18) ; v7(247.81,16.1) 247.61,16.3 v4(247.51,16.3) ; v7(138.85,2.76) 138.3,2.76 v4(137.98,2.44) ; v1(144.66,57.96) 144.71,58.01 v4(145.07,58.01) 145.63,58.01 v1(145.68,57.96) ; v4(128.23,26.36) 128.23,26.29 128.15,26.22 v7(128.15,25.98) ; v4(204.43,4.26) v7(204.85,4.26) ; v4(135.49,12.72) 135.34,12.87 v7(135.34,13.07) ; v1(151.61,11.6) 151.61,11.66 v4(151.36,11.92) ; v4(148.07,3.09) v7(148.45,3.09)
  IN4 w0.381: v1(114.26,58.49) 114.26,58.62 v4(114.06,58.82) ; v1(115.15,58.49) 115.15,58.69 v4(115.01,58.83) ; v4(119.31,58.68) 119.12,58.68 v1(118.93,58.49) ; v4(116.55,58.67) 116.38,58.5 v1(116.23,58.5) ; v4(118.08,58.67) 117.47,58.67 v1(117.3,58.49)
  IN4 w0.508: v1(130.34,57.96) v4(130.34,58.34) ; v1(188.45,57.98) v4(188.02,57.98) ; v1(127.29,57.96) 127.29,58.23 v4(127.86,58.81) ; v1(190.54,57.96) v4(190.1,57.96) ; v4(179.87,57.5) 180.12,57.75 v1(180.12,57.96) ; v1(83.09,57.96) v4(83.09,58.39) ; v1(184.92,57.96) v4(185.51,57.96) ; v1(178.09,57.96) v7(177.51,57.96) ; v1(172.76,57.96) 173.21,57.96 v4(173.39,58.13) ; v1(132.37,57.96) v4(132.37,58.5) ; v1(90.21,57.94) v4(90.21,58.77) ; v1(80.11,54.64) v4(80.11,55.14) ; v1(191.55,57.96) v4(192.11,57.96) ; v4(131.38,58.45) 131.35,58.42 v1(131.35,57.94) ; v1(129.32,57.94) v4(129.32,58.34) ; v1(87.16,57.96) v4(87.16,58.51) ; v1(174.79,57.96) v4(175.3,57.96) ; v4(148.25,57.24) 148.25,57.37 147.66,57.96 v1(146.7,57.96) ; v1(187.3,57.37) v4(187.3,56.93) ; v1(82.13,57.96) v4(82.13,58.44) ; v1(89.19,57.94) v4(89.19,58.64) ; v1(133.64,57.94) v4(133.64,58.43) ; v1(88.17,57.96) v4(88.17,58.51) ; v1(121.51,58.26) v4(121.51,58.88) ; v1(189.52,57.96) v4(189.14,57.96)
  GND3 w0.203: 118.32,16.42 H9.1 ; H9.1 117.54,16.67 ; H9.1 118.32,18.48 ; H9.1 119.1,16.67 ; H9.1 117.54,18.23 ; H9.1 119.1,18.23 ; H9.1 117.29,17.45 ; H9.1 119.35,17.45 ; H5.1 4,27.24 ; H5.1 2.02,26.49 ; H5.1 1.27,24.51 ; H5.1 4,21.78 ; H5.1 6.73,24.51 ; H5.1 5.98,22.53 ; H5.1 5.98,26.49 ; H5.1 2.02,22.53 ; 70.07,56.95 H4.1 ; H4.1 74.78,54.97 ; H4.1 70.82,54.97 ; H4.1 75.53,56.95 ; H4.1 72.8,54.22 ; H4.1 70.82,58.93 ; H4.1 72.8,59.68 ; H4.1 74.78,58.93 ; 81.5,2.12 H3.1 ; H3.1 79.83,2.74 ; H3.1 81.5,6.7 ; H3.1 79.21,4.41 ; H3.1 83.17,6.08 ; H3.1 83.79,4.41 ; H3.1 79.83,6.08 ; H3.1 83.17,2.74 ; H6.1 209.23,56.95 ; H6.1 204.52,58.93 ; H6.1 208.48,54.97 ; H6.1 204.52,54.97 ; H6.1 203.77,56.95 ; H6.1 206.5,59.68 ; H6.1 206.5,54.22 ; H6.1 208.48,58.93 ; 302.52,102.39 H1.1 ; H1.1 302.52,98.43 ; H1.1 304.5,103.14 ; H1.1 307.23,100.41 ; H1.1 306.48,98.43 ; H1.1 301.77,100.41 ; H1.1 304.5,97.68 ; H1.1 306.48,102.39 ; JNGFF1.16 24.44,28.06 ; JNGFF1.16 23.55,28.06 ; JNGFF1.16 24,28.17 ; H8.1 175.35,17.45 ; H8.1 174.32,16.42 ; H8.1 173.29,17.45 ; H8.1 173.54,18.23 ; H8.1 175.1,18.23 ; H8.1 174.32,18.48 ; H8.1 175.1,16.67 ; H8.1 173.54,16.67 ; 9.25,22.44 JNGFF1.69 ; JNGFF1.69 8.62,22.44 ; JNGFF1.69 8.62,24.86 ; JNGFF1.69 8.62,23.65 ; JNGFF1.69 9.25,24.86 ; 298.5,1.98 H2.1 ; H2.1 295.57,6.84 ; H2.1 295.57,1.98 ; H2.1 301.43,1.98 ; H2.1 295.57,4.41 ; H2.1 301.43,6.84 ; H2.1 301.43,4.41 ; H2.1 298.5,6.84 ; JNGFF1.10 26.06,26.81 ; JNGFF1.10 25.94,26.36 ; JNGFF1.10 25.5,26.25 ; JNGFF1.10 25.05,26.36 ; 22.05,26.36 JNGFF1.22 ; JNGFF1.22 22.5,26.25 ; JNGFF1.22 22.94,26.36 ; JNGFF1.68 32.37,22.44 ; JNGFF1.68 31.75,24.86 ; JNGFF1.68 32.37,24.86 ; JNGFF1.68 31.75,22.44 ; JNGFF1.68 32.37,23.65 ; JNGFF1.28 21,28.17 ; JNGFF1.28 20.55,28.06 ; JNGFF1.28 21.44,28.06
  BOTTOM w0.076: v8(154.87,15.41) 154.69,15.23 154.53,15.23 154.28,14.97 v8(154.12,14.97) ; v8(292.11,82.13) 292.36,81.88 292.87,81.88 293.11,81.63 v8(293.11,81.63) ; v8(155.93,12.13) UCPU1.CR37 155.07,12.29 155.41,12.63 v8(155.93,12.63) ; v8(156.12,14.97) 155.93,14.78 155.77,14.78 155.72,14.73 155.56,14.73 v8(155.37,14.54) ; v8(144.17,10.38) 144.16,10.39 143.3,10.39 v8(143.3,10.38) 143.29,10.39 142.44,10.39 v8(142.43,10.38) 142.43,10.39 141.57,10.39 v8(141.57,10.38) 141.24,10.38 141.24,10.39 140.7,10.39 v8(140.7,10.38) 140.7,10.39 139.84,10.39 v8(139.83,10.38) ; v8(138.1,24.12) v8(137.16,24.12) v8(136.29,24.12) v8(135.43,24.12) v8(134.56,24.12) 134.38,24.12 v8(134.13,24.37) ; v8(141.13,23.87) v8(142,23.87) v8(142.87,23.87) v8(143.73,23.87) v8(144.6,23.87) v8(145.46,23.87) ; v8(152.39,23.87) v8(153.34,23.87) ; v8(145.03,10.38) 145.04,10.39 145.57,10.39 145.57,10.38 v8(145.9,10.38) ; v8(131.96,11.38) v8(132.83,11.38) ; v8(146.33,23.87) v8(147.2,23.87) v8(148.06,23.87) v8(148.93,23.87) v8(149.79,23.87)
  BOTTOM w0.102: v8(135.67,31.76) 137.3,31.76 v6(137.32,31.74) ; v6(130.29,30.88) 130.08,30.68 v8(130.08,29.49) ; v3(289.47,46.74) 289.85,46.74 290.22,47.11 292.54,47.11 v6(292.63,47.02) ; v8(179.56,2.89) v6(181.1,2.89) ; v6(121.6,5.31) 121.87,5.05 CH48.2 ; v8(91.79,31.21) 91.86,31.21 92.87,32.22 v6(92.87,32.6) ; v6(121.03,31.3) 121.32,31.59 v8(122.61,31.59) ; v6(108.38,20.43) 107.53,21.28 v8(107.53,21.68) ; v6(112.22,30.84) 112.34,30.84 v8(113.37,29.81) ; v8(159.73,45.71) UD4.E7 ; v1(101.08,24.22) 101.08,23.12 v6(100.98,23.02) ; v3(36.92,42.27) v6(36.26,42.27) ; v3(281.32,44.09) 281.82,43.58 v6(281.82,42.55) ; UD8.E7 v8(101.08,45.71) ; v8(67.54,12.79) v6(67.54,11.27)
  BOTTOM w0.203: U27.11 298.61,62.36 v8(298.7,62.45) ; v8(131.38,22.5) 131.38,22.32 v8(131.63,22.07) 131.63,21.88 v8(131.38,21.63) 131.13,21.38 v8(131.13,21.2) v8(130.63,21.2) v8(130.13,21.2) v8(129.63,21.2) v8(129.13,21.2) v8(128.63,21.2) v8(128.13,21.2) 128.05,21.12 127.72,21.12 v8(127.63,21.2) ; v8(151.09,11.55) v8(151.09,10.88) v8(151.09,10.38) ; v8(151.09,11.55) 151.08,11.55 v8(150.66,11.96) 150.58,11.96 150.52,11.9 149.97,11.9 149.91,11.96 v8(149.79,11.96) 149.68,11.96 149.67,11.97 149.05,11.97 149.04,11.96 v8(148.93,11.96) ; v8(151.09,11.55) 151.56,11.55 v1(151.61,11.6) 151.61,11.88 v8(151.53,11.96) v8(152.39,11.96) 152.52,11.96 152.84,12.28 153.38,12.28 153.77,11.89 v8(153.77,11.88) ; v8(133.34,16.16) v8(133.95,16.16) v8(134.56,16.16) v8(135.17,16.16) v8(135.77,16.16) ; v8(133.34,16.16) v8(133.34,16.76) v8(133.34,17.31) v8(133.34,17.91) ; v8(133.34,16.16) v8(133.34,15.56) v8(133.34,15) v8(133.34,14.4) ; v8(133.34,16.16) v8(132.73,16.16) v8(132.12,16.16) ; v8(133.26,11.63) 133.08,11.63 v8(132.83,11.38) v8(132.83,10.88) v8(132.83,10.38) ; v8(133.26,11.63) 133.44,11.63 v8(133.7,11.38) 133.94,11.13 v8(134.13,11.13) v8(134.13,10.63) ; v8(133.26,11.63) v8(133.26,12.13) v8(133.26,12.63) ; v8(143.3,11.55) 143.32,11.55 v8(143.73,11.96) 143.79,11.9 144.54,11.9 v8(144.6,11.96) ; v8(143.3,11.55) v8(143.3,10.88) v8(143.3,10.38) ; v8(143.3,11.55) 143.28,11.55 v8(142.87,11.96) 142.77,11.87 142.1,11.87 v8(142,11.96) 141.9,11.87 141.23,11.87 v8(141.13,11.96) 141.04,11.87 140.37,11.87 v8(140.27,11.96) 140.19,11.89 139.48,11.89 v8(139.4,11.96) 139.33,11.89 138.61,11.89 v8(138.54,11.96) ; v8(134.13,23.87) v8(134.13,23.37) v8(134.13,22.87) ; v8(134.13,23.87) v8(134.13,24.37) v8(134.13,24.87) v8(134.13,25.37) ; v8(134.13,23.87) 133.95,23.87 v8(133.7,23.62) 133.51,23.62 v8(133.26,23.87) v8(133.26,24.37) v8(133.26,24.87) ; v8(133.34,14.4) v8(132.73,14.4) v8(132.12,14.4) ; v8(133.34,14.4) v8(133.95,14.4) v8(134.56,14.4) v8(135.17,14.4) v8(135.77,14.4) ; v8(133.34,14.4) v8(133.34,13.8) v8(133.34,13.25) ; v8(151.53,25.37) v8(151.53,24.87) v8(151.53,24.37) v8(151.53,23.87) v8(151.53,23.37) ; v8(94.3,5.55) 94.3,5.56 JIO1.62 ; U26.11 v8(74.03,47.34) ; v8(135.86,12.63) v8(135.86,12.13) v8(135.86,11.63) ; v8(135.86,12.63) 135.93,12.63 v8(136.29,13) ; v8(135.86,12.63) 135.68,12.63 v8(135.43,12.38) 135.18,12.13 v8(134.99,12.13) v8(134.99,12.63) ; v8(134.13,22.37) 134.13,22.36 134.38,22.12 v8(134.56,22.12) v8(134.56,22.62) 134.31,22.87 v8(134.13,22.87) ; v8(134.13,22.37) 134.04,22.37 133.79,22.62 v8(133.7,22.62) 133.45,22.87 UCPU1.AA11 ; v8(134.13,22.37) v8(134.13,22.87) ; v8(138.54,11.96) v8(137.94,11.96) 137.94,11.55 v8(138.1,11.38) ; v8(138.54,11.96) 138.54,11.82 v8(138.1,11.38) ; v8(138.1,11.38) v8(138.1,10.88) v8(138.1,10.38) ; v8(131.38,18.17) 131.13,17.92 v8(131.13,17.74) ; v8(131.38,18.17) 131.13,18.42 v8(131.13,18.6) ; v8(131.38,18.17) 131.63,18.42 v8(131.63,18.6) ; v3(97.85,3.98) 97.85,3.41 97.5,3.06 JIO1.45 ; v8(95.59,5.63) 95.5,5.72 JIO1.56 ; PU400.8 285.88,43.05 285.49,43.44 PC406.2 ; v8(95.73,3.29) 95.5,3.06 JIO1.55 ; v3(102.44,3.8) 102.3,3.67 JIO1.21 ; v8(142,24.87) v8(142,24.37) v8(142,23.87) v8(142,23.37) v8(142,22.87) v8(142,22.37) ; v8(148.5,11.55) 148.48,11.55 v8(148.06,11.96) ; v8(148.5,11.55) 148.51,11.55 v8(148.93,11.96) ; v8(148.5,11.55) v8(148.5,10.88) v8(148.5,10.38) ; v8(11.54,48.1) JAUD1.47 ; v8(132.12,19.66) 132.13,19.66 v8(132.13,20.26) 131.96,20.43 v8(131.96,20.79) 132.26,21.09 v8(132.26,21.19) 132.47,21.4 v8(132.78,21.4) 133.26,21.4 v8(133.38,21.28) 133.85,21.28 v8(133.88,21.31) 134.39,21.31 v8(134.4,21.3) 134.87,21.3 v8(134.92,21.25) 135.55,21.25 v8(135.57,21.27) 136.02,21.27 v8(136.29,21) ; v8(132.12,19.66) 131.82,19.66 v8(131.63,19.47) v8(131.13,19.47) ; v8(132.12,19.66) v8(132.73,19.66) v8(133.34,19.66) ; v8(135.77,19.66) v8(135.17,19.66) v8(134.56,19.66) v8(133.95,19.66) v8(133.34,19.66) ; v8(33.31,43.68) U29.11 ; v8(96.43,3.18) 96.3,3.05 JIO1.51 ; PR408.2 273.03,42.26 274.16,42.26 ; v8(131.13,20.33) 131.38,20.09 v8(131.38,19.9) 131.38,19.9 131.13,19.66 v8(131.13,19.47) ; v8(140.27,24.87) v8(140.27,24.37) v8(140.27,23.87) v8(140.27,23.37) v8(140.27,22.87) v8(140.27,22.37) v1(140.27,21.54) ; JIO1.46 97.5,6.78 v8(97.71,6.99) 97.9,6.8 JIO1.44 ; v8(144.6,11.96) v8(144.6,11.13) v8(144.6,10.63) ; v8(144.6,11.96) 144.67,11.89 145.39,11.89 v8(145.46,11.96) 145.88,11.55 v8(145.9,11.55) ; v8(128.13,17.74) v8(128.63,17.74) v8(129.13,17.74) v8(129.63,17.74) v8(130.13,17.74) v8(130.63,17.74) v8(131.13,17.74) ; v8(136.29,21) v8(136.29,21.62) v8(136.29,22.12) v8(136.29,22.62) ; v8(136.29,21) v8(136.29,20.5) v8(136.29,20) v8(136.29,19.5) v8(136.29,19) v8(136.29,18.5) v8(136.29,18) v8(136.29,17.5) v8(136.29,17) v8(136.29,16.5) v8(136.29,16) v8(136.29,15.5) v8(136.29,15) v8(136.29,14.5) v8(136.29,14) v8(136.29,13.5) v8(136.29,13) ; JIO1.15 103.5,3.05 103.66,3.21 v8(103.66,3.2) ; JAUD1.43 11.47,48.9 v8(11.58,48.79) ; JIO1.27 101.1,3.18 101.37,3.46 v3(101.37,4.87) ; v3(107.05,5.07) 107.05,4.7 105.9,3.56 JIO1.3 ; v8(11.55,49.58) 11.43,49.7 JAUD1.39 ; v8(131.1,25.12) v8(131.1,24.62) v8(131.1,24.12) v8(131.1,23.62) v8(131.1,23.12) ; JAUD1.48 6.74,48.1 v8(6.45,47.82) ; v8(153.62,13.24) 154.2,12.66 v8(154.2,12.63) ; v8(133.34,17.91) v8(133.95,17.91) v8(134.56,17.91) v8(135.17,17.91) v8(135.77,17.91) ; v8(133.34,17.91) v8(132.73,17.91) v8(132.12,17.91) 131.95,17.74 v8(131.63,17.74) v8(131.13,17.74) ; v8(133.34,17.91) v8(133.34,18.51) v8(133.34,19.06) v8(133.34,19.66) ; JIO1.33 99.9,3.14 100.1,3.34 100.1,3.71 v3(100.23,3.84) ; JIO1.39 98.7,2.95 98.96,3.21 98.96,4.57 v3(99.22,4.83) ; JIO1.52 96.3,6.83 v8(96.16,6.96) 95.9,6.7 JIO1.54 ; v8(136.29,13) 136.73,12.57 v8(136.73,12.13) v8(136.73,11.63) ; v3(104.89,3.83) 104.89,3.29 104.7,3.11 JIO1.9 ; v8(146.33,11.96) 145.91,11.55 v8(145.9,11.55) ; UCPU1.C36 128.12,12.25 128.32,12.45 128.5,12.45 128.58,12.52 v8(128.61,12.52) ; v8(147.2,11.96) 147.26,11.9 148,11.9 v8(148.06,11.96) ; PR403.2 285.34,42.05 PU400.6 ; v8(151.53,23.37) v8(151.53,22.87) v8(151.53,22.37) ; v8(151.53,23.37) 151.34,23.37 v8(151.09,23.12) ; v8(130.63,14.27) v8(130.13,14.27) v8(129.63,14.27) v8(129.13,14.27) v8(128.63,14.27) v8(128.13,14.27) ; v8(148.06,11.96) v8(148.93,11.96) ; PU401.8 273.79,43.3 273.4,43.69 v8(272.64,43.69) ; JAUD1.44 6.64,48.9 v8(6.47,48.72) ; v8(155.5,10.88) 155.75,11.13 v8(155.93,11.13) v8(155.93,11.63) v8(155.93,12.13) v8(155.93,12.63) ; v8(144.6,10.63) 144.78,10.63 v8(145.03,10.38) ; v8(144.6,10.63) 144.42,10.63 v8(144.17,10.38) ; v8(138.1,25.12) v8(138.1,24.62) v8(138.1,24.12) v8(138.1,23.62) v8(138.1,23.12) v8(138.1,22.62) v8(138.1,21.95) 138.01,21.95 v8(137.59,22.37) ; v8(134.13,12.63) v8(134.13,12.13) ; v8(131.13,19.47) v8(130.63,19.47) v8(130.13,19.47) v8(129.63,19.47) v8(129.13,19.47) v8(128.63,19.47) v8(128.13,19.47) v8(127.63,19.47) ; PU700.22 251.58,34.31 251.67,34.41 v8(251.67,34.82) ; v8(149.79,25.37) v8(149.79,24.87) v8(149.79,24.37) v8(149.79,23.87) v8(149.79,23.37) v8(149.79,22.87) v8(149.79,22.37) ; v8(231.05,29.94) U25.11 ; JAUD1.31 11.29,51.3 11.46,51.13 v8(11.53,51.13) ; v8(145.9,10.38) v8(145.9,10.88) v8(145.9,11.55) ; v8(131.63,16) v8(131.13,16) v8(130.63,16) v8(130.13,16) v8(129.63,16) v8(129.13,16) v8(128.63,16) v8(128.13,16) ; v8(6.43,49.57) 6.56,49.7 JAUD1.40 ; JAUD1.35 11.28,50.5 11.45,50.34 v8(11.55,50.34) ; JIO1.64 v8(93.9,5.55) ; v8(13.9,37.69) U33.11 ; v8(145.9,25.12) v8(145.9,24.62) v8(145.9,24.12) v8(145.9,23.62) v8(145.9,23.12) v8(145.9,22.62) ; v8(13.93,41.24) U30.11
  BOTTOM w0.254: v3(102.28,53.29) 102.67,52.9 UD8.P9 ; v3(171.24,54.13) 171.28,54.13 UD1.T1 ; v3(84.04,53.3) 83.67,52.93 UD7.P1 ; UD5.P9 132.01,52.9 v3(131.62,53.29) ; UD6.E1 v3(113.41,45.3) ; UD3.J2 143.13,48.9 143.5,48.53 143.5,48.54 v3(143.5,48.54) ; v3(83.21,54.06) 83.62,54.47 83.64,54.47 UD7.T1 ; UD4.M9 161.34,51.3 v3(161.74,51.7) ; UD5.E2 126.42,45.69 126.78,45.32 126.78,45.31 v3(126.81,45.28) ; v3(177.87,55.48) 178.05,55.3 UD1.T9 ; PR302.1 282.48,33.24 283.37,34.13 PR304.1 ; UD2.P9 190.65,52.9 v3(190.26,53.29) ; 36.1,30.46 v8(36.1,31.14) ; 36.1,30.46 36.1,30.36 36.49,29.98 37.87,29.98 38.22,30.33 v3(38.22,30.95) 38.22,32.94 37.58,33.58 v8(37.58,33.62) 37.98,34.03 37.98,37 37.69,37.29 35.42,37.29 34.63,36.5 32.92,36.5 32.32,37.1 31.56,37.1 31.39,36.94 31.39,34.5 31.54,34.35 31.54,32.64 v8(31.58,32.61) 31.2,32.61 30.39,31.79 30.39,30.52 31.02,29.89 32.82,29.89 v8(33.06,30.13) 33.33,29.85 35.49,29.85 36.1,30.46 ; v3(101.5,49.28) 101.87,48.9 UD8.J8 ; v3(176.05,46.1) UD1.E7 ; v3(189.51,49.29) 189.86,48.94 UD2.J8 ; v3(84.09,51.62) 84.09,51.62 84.09,51.62 83.77,51.3 UD7.M1 ; v3(154.6,47.71) 154.93,47.39 UD4.G1 ; UD2.G8 189.84,47.3 v3(189.46,46.92) ; UD5.G8 131.19,47.3 v3(130.81,46.92) ; RP13.2 v3(294.93,90.78) ; v3(131.59,54.91) 131.59,54.9 131.99,54.5 UD5.T9 ; UD3.P1 142.32,52.93 v3(142.69,53.3) ; v3(147.52,46.1) UD3.E8 ; v3(203.41,45.25) JCAN1.10 ; UD7.G8 v3(89.67,46.9) ; v3(190.23,54.91) 190.23,54.9 190.63,54.5 UD2.T9 ; UD6.T1 112.64,54.13 v3(112.6,54.13) ; UD6.G9 119.41,47.3 v3(119.81,46.9) 119.41,46.5 UD6.F9 ; v3(155.32,52.47) 154.93,52.86 UD4.P1 ; v8(202.73,43.97) 202.95,43.75 JCAN1.7 ; UD4.G8 160.53,47.31 v3(160.12,47.72) ; UD4.T9 161.3,54.5 160.9,54.9 v3(160.9,54.91) ; v3(172.05,46.94) 172.03,46.96 172.03,46.98 171.71,47.3 UD1.G1 ; v3(146.72,46.1) UD3.E7 ; UD3.F9 v3(149.12,46.9) UD3.G9 ; UD3.T1 142.29,54.47 142.27,54.47 v3(141.86,54.06) ; UD3.M1 142.42,51.3 142.73,51.62 142.73,51.62 v3(142.74,51.62) ; UD7.F9 v3(90.47,46.9) UD7.G9 ; UD2.P1 184.33,52.9 v3(184.76,52.47) ; UD1.J8 177.39,48.9 v3(177.79,48.51) ; PC413.2 278.74,42.09 279.1,41.73 ; UD6.E2 v3(114.21,45.3) ; UD2.M9 190.3,51.67 v3(190.3,51.68) ; v3(96.67,52.47) 96.28,52.86 UD8.P1 ; v3(84.08,47.68) 83.7,47.3 UD7.G1 ; UD5.P1 125.69,52.9 v3(126.12,52.47) ; v3(103.1,51.7) 102.69,51.3 UD8.M9 ; v3(101.48,47.72) 101.88,47.31 UD8.G8 ; v3(176.85,46.1) UD1.E8 ; JCAN1.19 203.55,49.75 v3(203.36,49.94) 203.67,50.25 JCAN1.20 ; PC405.2 290.93,41.83 291.29,41.48 ; UD6.D1 v3(113.41,44.5) ; v3(184.67,47.71) UD2.G1 ; UD1.D1 v3(172.05,44.5) ; UD8.M1 96.08,51.3 v3(95.81,51.03) ; v3(172.04,52.51) 171.65,52.9 UD1.P1 ; UD3.D8 v3(147.52,45.3) ; UD1.E1 v3(172.05,45.3) ; UD5.J8 131.22,48.94 v3(130.86,49.29) ; UD7.J2 84.48,48.9 84.85,48.53 84.85,48.54 v3(84.86,48.54) ; v3(113.41,46.94) 113.39,46.96 113.39,46.98 113.07,47.3 UD6.G1 ; UD1.M1 171.65,51.35 v3(171.3,51.71) ; v3(183.79,51.03) 184.06,51.3 UD2.M1 ; UD6.T9 119.41,55.3 v3(119.23,55.48) ; UD5.G1 v3(126.03,47.71) ; UD5.M9 131.65,51.67 v3(131.65,51.68) ; v3(172.85,45.3) UD1.E2 ; UD6.P1 113.01,52.9 v3(113.4,52.51) ; RP13.3 295.43,90.48 v3(295.7,90.75) 295.72,90.75 295.93,90.53 RP13.4 ; v3(112.65,51.71) 113.01,51.35 UD6.M1 ; v3(95.96,47.71) 96.28,47.39 UD8.G1 ; UD2.E8 v3(189.47,45.31) ; v3(154.46,51.03) 154.72,51.3 UD4.M1 ; U57.5 81.56,12.48 v8(81.7,12.34) ; UD5.M1 125.41,51.3 v3(125.15,51.03) ; UD3.G1 142.34,47.3 v3(142.72,47.68) ; v3(185.44,46.14) 185.06,45.76 UD2.E2 ; UD4.P9 161.32,52.9 v3(160.93,53.29) ; UD7.E7 v3(88.07,46.1) ; v3(102.25,54.91) 102.25,54.9 102.65,54.5 UD8.T9 ; UD6.E7 v3(117.41,46.1) ; UD1.G9 v3(178.45,46.9) UD1.F9 ; UD7.D8 v3(88.87,45.3) ; v3(203.39,46.75) JCAN1.13 ; UD4.J8 160.52,48.9 v3(160.14,49.28) ; v3(148.32,46.9) UD3.G8 ; U28.3 v8(88,34.24) ; UD7.E8 v3(88.87,46.1) ; v3(203.41,48.25) JCAN1.16 ; v3(130.82,45.31) 131.22,45.7 UD5.E8 ; UD6.E8 v3(118.21,46.1)
  BOTTOM w0.305: v3(299.63,93.87) 299.47,94.03 JDEG1.10 ; v3(55.46,11.32) 55.25,11.11 JNGFF2.37 ; JSNR1.20 289.28,93.62 v3(289.09,93.81) ; v3(206.02,5.17) 206.02,5.25 206.18,5.41 JSPI1.20 ; JNGFF2.43 56.75,11 v3(56.65,11.1) ; JNGFF3.25 23.25,51.01 v3(23.79,51.54) ; U21.25 228.39,20.28 v3(228.36,20.31) ; JNGFF2.49 58.25,11.06 v3(58.43,11.24) ; JNGFF2.65 v8(62.25,11.15) ; JNGFF3.65 33.25,51.03 v3(32.98,51.3) 32.75,51.07 JNGFF3.63 ; v3(26.25,51.31) JNGFF3.37 ; v3(207.35,5.15) 207.35,5.16 207.17,5.34 207.17,5.92 JSPI1.18 ; v3(46.99,11.29) 46.75,11.05 JNGFF2.11 ; U21.18 232.94,20.3 ; JSNR1.24 291.29,92.47 v3(291.29,91.61) 291.13,91.61 290.78,91.96 JSNR1.23 ; v8(61.53,11.17) 61.54,11.17 61.75,10.96 JNGFF2.63 ; v3(29.25,51.3) JNGFF3.49 ; v3(25.04,51.31) 24.75,51.02 JNGFF3.31 ; JSNR1.17 287.78,93.67 v3(287.61,93.83) ; v3(53.63,11.32) 53.75,11.2 JNGFF2.31 ; JNGFF2.19 v8(50.75,8.79) ; v3(23.2,52.56) 23.16,52.56 21.75,51.16 JNGFF3.19 ; JSPI1.19 206.68,5.17 v3(206.66,5.15) ; v3(27.75,51.31) JNGFF3.43 ; v8(52.13,8.78) 52.25,8.9 JNGFF2.25
  BOTTOM w0.356: U21.9 v3(231.64,23.52) ; U21.4 v3(228.39,23.55) ; U21.17 233.59,20.16 233.46,20.29 232.95,20.29 v3(232.93,20.31) ; U21.11 v3(232.94,23.6) ; v1(283.04,14.39) 282.82,14.17 PU902.3 ; U21.2 227.09,23.57 v3(226.99,23.46) 226.44,24 U21.1 ; U21.8 v3(230.99,23.56) ; v3(278.33,96.11) 278.78,95.66 JSNR1.25 ; PU900.4 v3(267.41,14.11)
  BOTTOM w0.381: v3(284.4,19.47) 284.12,19.19 PU901.3 ; CD37.2 118.65,58.2 118.93,58.48 v1(118.93,58.49) ; CD39.1 115.61,57.99 115.15,58.45 v1(115.15,58.49) ; CD45.2 117.64,58.01 117.3,58.35 v1(117.3,58.49) ; CD42.2 116.62,58.09 116.23,58.49 v1(116.23,58.5) ; CD38.1 114.59,58.16 v1(114.26,58.49)
  BOTTOM w0.406: v3(291.09,96.31) 291.8,96.31 292.28,95.83 JSNR1.26 ; JDEG1.12 300.47,96.77 v3(300.99,96.25) ; JDEG1.11 v3(293.97,98.62)
  BOTTOM w0.432: v3(236.6,27.27) PQ901.1
  BOTTOM w0.508: v3(283.75,45.26) C253.2 ; v3(76.19,19.35) 75.73,19.35 75.53,19.55 PC514.2 ; R44.2 v3(257.92,17.87) ; v3(208.24,38.69) 207.9,38.35 JCAN1.21 ; v3(78.9,57.5) 78.9,57.5 CD65.2 79.78,58.15 v3(79.6,58.32) ; v3(238.52,45.67) 238.52,46 238.83,46.32 PC5.2 ; C79.2 v3(231.48,27.48) ; PD4.1 239.56,53 v3(239.63,52.93) ; v3(224.45,28.29) PC614.2 ; PC412.2 280.95,44.45 v3(281.32,44.09) ; v3(245.7,40.99) PC2.2 ; v3(284.44,87.06) 284.95,87.57 R214.1 ; C100.2 v3(79.94,49.37) ; v3(284.52,31.91) 285.11,31.91 PC312.2 ; v1(121.51,58.26) 121.82,57.96 RD10.2 ; PC905.2 v3(261.71,17.87) ; v3(266.61,14.19) 266.61,13.94 267.31,13.24 PC907.1 ; v3(221.57,32.05) PR607.2 ; JCAN1.24 v3(208.33,50.99) ; v3(284.77,45.23) C252.2 ; v3(260.72,12.06) MC5.2 PR911.2 ; JNGFF3.69 v3(36.28,50.85) ; v3(282.43,32.43) PR302.1 ; v3(221.52,21.07) PC611.2 ; C251.2 285.79,45.33 v3(285.71,45.26) ; PC605.2 219.07,31.65 v3(219.06,31.67) ; PC55.2 v3(236.99,52.88) ; JAUD1.51 8.11,58.41 v3(7.8,58.73) ; R223.2 v3(299.17,90.19) ; v3(225.18,32.63) 225.38,32.43 C117.2 R162.1 ; C95.2 v3(225.38,27.14) ; PQ6.3 236.7,23.48 236.27,23.9 v3(236.27,24.52) ; R163.1 235.98,19.83 v3(235.88,19.93) ; JAUD1.52 9.92,58.41 v3(10.32,58.82) ; JSPK1.5 45.3,3.89 v3(44.66,4.52) ; v8(77.39,10.43) C234.2 ; C93.2 233.79,29.43 v3(233.84,29.48) ; PQ54.3 289.23,19.43 v3(289.23,20.4) ; PC706.1 253.78,29.98 v3(254.05,30.24) ; PC3.2 239.2,45.31 238.53,44.63 v3(238.53,44.4) 238.64,44.29 PC4.2 ; v3(206.41,51.52) 206.38,51.55 JCAN1.22 ; PC500.2 PR501.2 v3(71.66,28.78) ; C125.2 v3(85.84,25.72) ; v3(228.96,52.47) 228.9,52.53 JBAT1.10 ; C76.2 v3(233.16,16.2) ; JNGFF2.69 63.85,11.95 63.65,12.15 v3(63.65,12.87) ; PC613.2 v3(224.47,27.27) ; R48.2 v3(260.46,17.82) ; C78.2 v3(226.17,26.76) ; v8(41.86,15.16) 41.75,15.04 Q46.3 ; v3(260.99,14.13) 261.64,14.13 PC906.2 ; PR912.2 270.75,16.78 v3(270.5,17.04) ; v3(233.84,30.47) 233.82,30.45 C94.2 ; RD12.2 v1(124.24,57.96) ; PR508.2 71.66,24.68 v3(71.69,24.71) PR507.2 ; PC606.2 214.65,27.44 214.36,27.73 v3(214.36,28.01) ; R383.1 v8(75.52,18.16) ; v3(220.25,21.07) PC607.1 ; v3(194.78,54.48) CD8.2 ; v3(284.14,43.4) 284.17,43.44 PC406.2 ; C139.2 299.96,80.84 300.22,81.11 v3(300.78,81.11) ; v3(289.47,46.74) 289.47,46.75 289.4,46.82 289.4,46.84 289.2,47.03 CZ3.2 ; PD3.1 v3(242.1,52.93) ; JCAN1.23 v3(208.33,43.27) ; v8(287.82,46.12) CZ2.2 ; v3(220.51,31.67) PC610.2 ; PC300.2 280.52,34.6 280.78,34.87 v3(281.54,34.87) ; MD1.2 301.53,91 v3(301.95,90.58) ; v3(245.73,39.97) PC1.2 ; R306.1 v3(79.96,48.35) ; v1(178.09,57.96) RD3.2
  vias: v1(43.15,10.65) v1(85.99,29.56) v1(91.22,57.96) v1(92.95,34.79) v1(93.43,34.79) v1(93.89,34.79) v1(102.19,25.22) v1(102.19,24.21) v1(102.19,23.21) v1(104.68,23.21) v1(150.15,57.96) v1(151.17,57.96) v1(181.14,30.65) v1(195.11,57.37) v1(195.11,56.99) v1(233.41,45.17) v1(239.69,22.95) v1(248.09,19.12) v1(248.37,22.75) v1(250.28,18.51) v1(266.43,17.62) v1(284.92,12.56) v1(289.63,77.07) v3(0.54,38.88) v3(0.51,37.33) v3(0.56,35.73) v3(1.01,57.84) v3(1.01,33.5) v3(1,31.93) v3(1.01,30.16) v3(1,27.93) v3(1.08,24.12) v3(1.5,59.99) v3(1.53,40.11) v3(2.2,56.46) v3(2.41,27.11) v3(2.5,53.93) v3(2.5,51.39) v3(2.5,48.85) v3(2.5,46.31) v3(2.5,43.77) v3(2.47,41.22) v3(2.86,21.58) v3(3.95,32.97) v3(4.04,59.99) v3(4.65,32.96) v3(5.07,53.88) v3(5.14,27.3) v3(5.52,21.64) v3(5.7,56.44) v3(6.01,43.96) v3(6.58,59.99) v3(6.66,46.15) v3(6.67,26.03) v3(6.86,23.61) v3(7.07,44.99) v3(7.19,45.87) v3(8.15,23.1) v3(8.19,21.52) v3(8.56,47.38) v3(9.01,45.88) v3(9,26.15) v3(9.12,59.99) v3(9.43,48.06) v3(9.38,21.52) v3(11.5,59.99) v3(11.72,47.08) v3(13.31,30.7) v3(13.5,57.99) v3(14.39,30.83) v3(18.58,57.99) v3(19.46,54.32) v3(21.09,36.01) v3(21.17,33.69) v3(22.88,33.47) v3(23,36.01) v3(24.98,33.49) v3(25.06,35.93) v3(27.18,33.47) v3(28.38,43.53) v3(28.97,43.54) v3(29.17,34.86) v3(30.54,33.96) v3(31.62,25.07) v3(31.62,21.5) v3(34.14,21.5) v3(35.5,57.99) v3(36.59,21.5) v3(37.5,59.99) v3(38,19.02) v3(38,16.72) v3(37.98,5.28) v3(38.02,3.37) v3(38.21,56.86) v3(38.22,7.39) v3(38.33,1.51) v3(38.44,46.53) v3(38.8,30.74) v3(39.56,15.07) v3(39.73,8.16) v3(40.04,59.99) v3(40.04,11.27) v3(39.99,9.77) v3(40.76,1.49) v3(42.78,59.99) v3(43.41,1.51) v3(45.32,59.99) v3(45.86,1.49) v3(46.12,38.69) v3(46.37,30.78) v3(46.54,3.75) v3(47.58,30.88) v3(47.86,59.99) v3(47.97,37.14) v3(48.25,3.8) v3(48.49,1.51) v3(50.4,59.99) v3(50.7,20.15) v3(50.91,1.49) v3(52.74,23.39) v3(52.93,38.21) v3(53.14,59.99) v3(53.5,44.01) v3(53.57,1.51) v3(54.66,23.42) v3(55.68,59.99) v3(55.99,1.5) v3(56.75,33.1) v3(58.22,59.99) v3(58.23,23.3) v3(58.65,1.51) v3(58.91,44) v3(60.64,49.5) v3(60.64,38.66) v3(60.76,59.99) v3(61.08,1.5) v3(63.3,59.99) v3(63.26,30.17) v3(63.73,1.51) v3(64.74,43.97) v3(65.06,58.66) v3(65.59,35.31) v3(65.59,28.31) v3(65.7,23.7) v3(65.84,59.99) v3(65.86,55.77) v3(66.14,1.5) v3(66.3,49.5) v3(66.88,58.5) v3(66.98,54.5) v3(67.71,38.82) v3(67.75,57.06) v3(68.2,44.04) v3(68.38,59.99) v3(68.54,54.52) v3(68.81,1.51) v3(69.78,13.15) v3(69.94,46.07) v3(69.86,42.41) v3(69.86,37.61) v3(69.86,32.12) v3(69.86,23.67) v3(69.86,19.47) v3(70.66,2.34) v3(71.19,1.49) v3(71.49,34.76) v3(71.49,34.1) v3(72.24,13.03) v3(73.89,1.51) v3(74.89,2.85) v3(76.38,1.5) v3(77.18,4.46) v3(77.25,2.95) v3(77.71,56.13) v3(77.71,53) v3(78.52,59.74) v3(78.76,1.49) v3(79.16,24.6) v3(79.16,23.84) v3(79.92,25.37) v3(79.92,24.6) v3(79.92,23.84) v3(80.73,56.43) v3(80.68,25.37) v3(80.68,24.6) v3(80.68,23.84) v3(81.06,59.74) v3(81.24,35.54) v3(81.34,56.46) v3(81.46,31.64) v3(81.87,35.5) v3(82.14,31.64) v3(83.6,59.74) v3(84.43,1.51) v3(84.87,54.13) v3(85.46,2.95) v3(85.57,52.48) v3(85.63,50.14) v3(86,1.51) v3(86.88,45.65) v3(87.34,54.07) v3(88.02,5.52) v3(88.05,1.5) v3(88.89,53.31) v3(88.89,51.72) v3(90.09,1.51) v3(93.72,59.75) v3(96.26,59.75) v3(97.46,55.85) v3(98.42,51.44) v3(98.51,49.11) v3(98.8,59.75) v3(99.08,54.35) v3(99.43,47.87) v3(100.03,54.57) v3(100.05,52.6) v3(100.04,7.28) v3(100.06,5.48) v3(101.34,59.75) v3(101.49,51.01) v3(102.66,4.36) v3(103.89,59.99) v3(104.07,28.49) v3(105.18,5.33) v3(106.43,59.99) v3(106.77,28.41) v3(107.87,1.51) v3(108.96,60.01) v3(110.46,44.7) v3(111.07,0.5) v3(111.5,60.01) v3(112.54,49.28) v3(114.2,54.13) v3(114.96,52.47) v3(114.96,50.14) v3(115.66,48.38) v3(116.68,54.07) v3(116.75,49.26) v3(118.23,53.31) v3(118.23,51.72) v3(120.33,60) v3(120.39,48.86) v3(120.76,0.49) v3(122.87,60) v3(123.57,0.53) v3(125.41,60) v3(125.84,0.49) v3(126.8,55.85) v3(127.75,51.44) v3(127.84,48.82) v3(127.95,60) v3(128.45,54.38) v3(128.65,0.53) v3(129.3,52.6) v3(129.54,54.52) v3(130.49,60) v3(131.29,0.52) v3(133.03,60) v3(133.73,0.53) v3(135.57,60) v3(136.37,0.52) v3(138.11,60) v3(138.81,0.53) v3(143.51,54.13) v3(144.22,52.48) v3(144.27,50.14) v3(145.22,36.47) v3(145.99,54.07) v3(146.77,60) v3(147.54,53.31) v3(147.54,51.72) v3(147.66,0.52) v3(149.31,60) v3(150.06,0.51) v3(151.85,60) v3(151.97,4.47) v3(152.74,0.52) v3(154.39,60) v3(155.14,0.51) v3(156.11,55.85) v3(156.93,60) v3(157.06,51.44) v3(157.15,49.11) v3(157.72,54.31) v3(157.92,0.49) v3(158.46,24.14) v3(158.69,54.56) v3(158.69,52.61) v3(159.47,60) v3(160.13,51.01) v3(160.22,0.51) v3(162.01,60) v3(163,0.49) v3(164.55,60) v3(165.3,0.51) v3(167.04,46.5) v3(170.32,16.54) v3(171.18,49.28) v3(171.79,14.65) v3(172.72,17.33) v3(172.84,54.13) v3(173.37,60) v3(173.39,18.68) v3(173.41,0.5) v3(173.61,52.47) v3(173.61,50.14) v3(173.65,35.02) v3(173.55,16.08) v3(174.03,35.48) v3(174.31,48.38) v3(174.56,35.86) v3(175.09,16.09) v3(175.19,18.68) v3(175.32,54.07) v3(175.4,49.26) v3(175.77,17.17) v3(175.91,60) v3(176.87,53.31) v3(176.87,51.72) v3(176.87,38.23) v3(177.28,38.68) v3(177.54,17.29) v3(177.72,39.07) v3(178.17,39.45) v3(178.45,60) v3(178.37,0.5) v3(178.6,39.98) v3(179.03,48.86) v3(179.23,37.66) v3(180.99,60) v3(181.03,0.5) v3(183.45,0.5) v3(183.53,60) v3(184.68,43.74) v3(185.23,27.17) v3(185.44,55.85) v3(185.51,27.83) v3(185.63,26.69) v3(185.89,27.25) v3(186.07,60) v3(186.09,28.21) v3(186.12,0.5) v3(186.4,51.44) v3(186.48,48.82) v3(187.06,54.31) v3(187.11,28.16) v3(187.95,52.6) v3(188.15,27.09) v3(188.18,54.51) v3(188.22,28.8) v3(188.61,60) v3(188.64,0.5) v3(188.83,27.09) v3(188.91,28.8) v3(189.6,28.8) v3(190.22,28.82) v3(190.16,27.14) v3(190.79,27.14) v3(191.01,28.82) v3(191.15,60) v3(191.53,0.51) v3(191.74,28.82) v3(191.81,27.14) v3(192.43,28.82) v3(192.57,27.14) v3(193.23,26.1) v3(193.23,25.27) v3(193.23,24.35) v3(193.99,26.1) v3(193.99,25.27) v3(193.99,24.35) v3(196.23,36.72) v3(196.38,36.03) v3(196.84,35.53) v3(199.65,60) v3(200.52,0.5) v3(201.08,57.65) v3(201.08,52.39) v3(201.15,42.49) v3(201.15,37.99) v3(202.61,56.24) v3(202.65,58.04) v3(202.83,0.51) v3(204.11,60.01) v3(205.1,0.51) v3(207.86,1.5) v3(209.66,59.98) v3(209.9,1.51) v3(210.26,55.85) v3(211.44,50.82) v3(211.48,56.99) v3(211.45,53.32) v3(211.82,32.89) v3(211.82,32.28) v3(211.82,31.67) v3(211.82,30.98) v3(212.2,38.44) v3(212.28,25.57) v3(212.3,24.91) v3(212.3,24.25) v3(212.33,23.59) v3(212.33,22.98) v3(212.81,35.57) v3(212.94,1.5) v3(213.04,25.57) v3(213.07,24.91) v3(213.07,24.25) v3(213.09,23.59) v3(213.09,22.98) v3(213.73,28.08) v3(214.02,56.99) v3(214.96,53.34) v3(214.96,50.9) v3(214.98,1.51) v3(216.56,56.99) v3(216.91,35.59) v3(217.32,47.53) v3(217.43,15) v3(218.04,14.94) v3(218.02,1.5) v3(218.2,15.55) v3(218.45,31.67) v3(218.68,40.71) v3(218.7,14.94) v3(218.8,27.2) v3(218.8,26.38) v3(219.1,56.99) v3(219.12,53.41) v3(219.21,26.79) v3(219.25,50.88) v3(219.26,16.26) v3(219.63,27.2) v3(219.63,26.38) v3(219.85,16.21) v3(219.8,1.51) v3(220.43,16.22) v3(221.02,16.25) v3(221.64,56.99) v3(222.31,46.83) v3(223.48,17.06) v3(224.09,17.04) v3(224.18,56.99) v3(224.17,35.66) v3(224.85,39.3) v3(226.72,56.99) v3(228.13,42.34) v3(228.13,41.66) v3(228.13,40.82) v3(228.13,40.06) v3(228.18,1.5) v3(228.81,42.34) v3(228.81,41.66) v3(228.81,40.82) v3(228.81,40.06) v3(229.11,48.96) v3(229.12,30.62) v3(229.12,29.79) v3(229.12,29.1) v3(229.26,56.99) v3(229.5,42.34) v3(229.5,41.66) v3(229.5,40.82) v3(229.5,40.06) v3(230.19,42.34) v3(230.19,41.66) v3(230.19,40.82) v3(230.22,1.51) v3(231.05,35.66) v3(231.8,56.99) v3(233.26,1.5) v3(234.34,56.99) v3(235.3,1.51) v3(236.88,56.99) v3(238.34,1.5) v3(239.42,56.99) v3(240.22,19.73) v3(240.22,18.89) v3(240.38,1.51) v3(241.96,56.99) v3(243.37,36.01) v3(243.37,35.4) v3(243.42,1.5) v3(244.5,56.99) v3(245.96,1.5) v3(246.93,56.72) v3(247.01,53.69) v3(247,51.65) v3(247.98,50.09) v3(248,1.51) v3(249.77,49.99) v3(250.54,1.51) v3(250.89,48.68) v3(252.31,49.99) v3(253.08,1.51) v3(254.85,49.99) v3(255.62,1.51) v3(257.39,49.99) v3(258.15,25.95) v3(258.15,25.27) v3(258.15,24.2) v3(258.15,23.59) v3(258.16,1.51) v3(258.51,48.68) v3(259.83,22.29) v3(259.83,21.68) v3(259.93,49.99) v3(260.36,31.74) v3(260.36,30.83) v3(260.36,29.99) v3(260.7,1.51) v3(261.2,31.74) v3(261.2,30.83) v3(261.2,29.99) v3(261.96,31.74) v3(261.96,30.83) v3(261.96,29.99) v3(262.47,49.99) v3(262.8,31.74) v3(262.8,30.83) v3(262.8,29.99) v3(263.24,1.51) v3(263.48,31.74) v3(263.56,30.83) v3(263.56,29.99) v3(265.01,49.99) v3(265.78,1.51) v3(266.13,48.68) v3(266.3,24.43) v3(266.76,29.53) v3(266.84,28.01) v3(266.91,24.43) v3(266.99,30.98) v3(267.07,26.41) v3(267.07,25.8) v3(267.07,23.21) v3(267.07,22.45) v3(267.55,49.99) v3(267.9,23.21) v3(267.9,22.45) v3(268.32,1.51) v3(269.14,41.25) v3(270.09,49.99) v3(270.93,42.68) v3(270.93,37.92) v3(270.92,36.98) v3(270.86,1.51) v3(270.95,45.53) v3(270.95,44.92) v3(270.95,41.27) v3(270.95,40.2) v3(270.95,39.51) v3(271.64,45.53) v3(271.64,44.92) v3(272.63,49.99) v3(273.01,34.39) v3(273.4,1.51) v3(273.59,34.39) v3(274.2,34.38) v3(274.79,34.38) v3(274.91,39.51) v3(275.17,49.99) v3(275.37,42.94) v3(275.37,42.26) v3(275.94,1.51) v3(275.98,22.52) v3(275.98,21.84) v3(275.98,21.15) v3(276.06,42.94) v3(276.06,42.26) v3(276.67,22.52) v3(276.67,21.84) v3(276.67,21.15) v3(277,102.43) v3(277,99.89) v3(277,97.35) v3(277,94.81) v3(277,92.27) v3(277,89.73) v3(277,87.19) v3(277,84.65) v3(277,82.11) v3(277,79.57) v3(277,77.03) v3(277,74.49) v3(277,71.95) v3(277,69.41) v3(277,66.87) v3(277,64.33) v3(277,61.79) v3(277,59.25) v3(277,56.71) v3(277,54.17) v3(277,51.63) v3(277.5,103.99) v3(277.76,6.84) v3(278.48,1.51) v3(278.93,41.32) v3(278.93,40.51) v3(278.94,6.85) v3(279.18,100.08) v3(280.04,103.99) v3(280.1,61.38) v3(280.1,57.04) v3(280.17,51.78) v3(280.17,30.45) v3(280.17,29.76) v3(280.39,6.81) v3(280.45,7.39) v3(280.86,30.45) v3(280.86,29.76) v3(281.03,7.4) v3(280.98,6.81) v3(281.02,1.51) v3(281.62,7.36) v3(281.56,6.78) v3(282.05,91.1) v3(282.14,6.79) v3(282.2,7.37) v3(282.58,103.99) v3(282.73,6.79) v3(282.79,7.38) v3(282.87,20.35) v3(283.18,19.81) v3(283.31,6.82) v3(283.37,7.41) v3(283.46,20.33) v3(283.56,1.51) v3(283.79,22) v3(283.78,21.4) v3(283.79,19.78) v3(283.86,7.09) v3(284.04,20.33) v3(284.39,21.99) v3(284.36,21.38) v3(284.62,20.33) v3(284.88,98.11) v3(284.97,21.99) v3(284.97,21.38) v3(285.12,103.99) v3(285.12,1.5) v3(285.66,35.91) v3(285.66,35.27) v3(286.74,101.03) v3(287.03,39.29) v3(287.14,80.88) v3(287.31,34.21) v3(287.49,42.64) v3(287.49,41.95) v3(287.66,103.99) v3(288.02,34.23) v3(288.25,42.64) v3(288.17,41.95) v3(288.64,1.51) v3(290.2,103.99) v3(291.15,40.35) v3(291.18,1.51) v3(291.48,82.26) v3(292.74,103.99) v3(293.18,89.45) v3(294.51,4.84) v3(294.85,2.52) v3(295.06,96.92) v3(295.28,103.99) v3(295.44,101.55) v3(295.77,1.49) v3(295.88,99.2) v3(296.84,10.75) v3(297.19,89.4) v3(297.58,95.94) v3(297.82,103.99) v3(297.98,100.42) v3(298.38,103.11) v3(299.11,99.13) v3(299.38,55.52) v3(299.6,9.52) v3(300.16,101.6) v3(300.36,103.99) v3(300.81,98.47) v3(300.87,10.25) v3(301.25,7.22) v3(301.34,1.51) v3(301.99,83.5) v3(301.99,80.96) v3(301.99,78.42) v3(301.99,75.88) v3(301.99,73.34) v3(301.99,70.8) v3(301.99,68.26) v3(301.99,65.72) v3(301.99,63.18) v3(301.99,60.64) v3(301.99,58.1) v3(301.99,55.56) v3(301.99,53.02) v3(301.99,50.48) v3(301.99,47.94) v3(301.99,45.4) v3(301.99,42.86) v3(301.99,40.32) v3(301.99,37.78) v3(301.99,35.24) v3(301.99,32.7) v3(301.99,30.16) v3(301.99,27.62) v3(301.99,25.08) v3(301.99,22.54) v3(301.99,20) v3(301.99,17.46) v3(301.99,14.92) v3(301.99,12.38) v3(301.99,9.84) v3(301.99,7.3) v3(301.99,2.22) v3(302.9,103.99) v3(303.88,85.01) v3(306.42,85.01) v3(307.98,103.99) v3(308.48,101.12) v3(308.96,85.01) v3(309.9,103.06) v3(310,100.77) v3(310.63,87.84) v3(311.5,85.01) v3(311.99,88.26) v3(311.99,85.5) v4(86.14,57.37) v4(194.6,57.5) v4(194.6,56.99) v6(37.12,51.81) v6(37.08,49.83) v6(43.95,26.91) v6(44.17,34.51) v6(44.55,40.35) v6(45.02,45.29) v6(44.99,23.22) v6(47.93,20.32) v6(48.46,29.03) v6(48.66,23.21) v6(49.99,39.01) v6(50.23,18.34) v6(52.33,42.23) v6(53.99,31.81) v6(54.57,36.84) v6(55.69,41.13) v6(56.84,45.2) v6(56.79,20.95) v6(59.71,37.9) v6(59.71,33) v6(60.13,28.34) v6(60.18,42.04) v6(75.83,4.95) v6(212.63,31.6) v6(235.13,37.89) v6(271.46,46.49) v6(283.09,8.6) v7(138.02,18.22) v7(138.03,17.4) v7(138.03,16.61) v7(138.03,15.71) v7(138.05,14.97) v7(138.07,13.22) v7(139.52,12.26) v7(140.32,12.26) v7(141.04,12.26) v7(148.53,12.25) v7(149.33,12.27) v7(149.96,12.26) v7(150.8,12.26) v7(151.96,12.28) v7(153.14,15.29) v7(153.14,14.51) v7(153.17,20.14) v7(153.23,18.48) v7(153.22,17.08) v7(153.22,16.31) v7(153.19,15.69) v7(153.15,13.78) v8(5.04,36.92) v8(5.9,30.47) v8(5.9,30.15) v8(5.9,29.84) v8(5.95,36.03) v8(8.21,42.77) v8(8.15,41.89) v8(8.21,39.34) v8(8.21,38.45) v8(8.21,36.42) v8(8.55,46.58) v8(8.8,32.43) v8(9.05,41.19) v8(9.45,46.58) v8(9.82,32.43) v8(11.25,29.4) v8(12.23,41.83) v8(12.23,41.24) v8(12.23,40.65) v8(12.23,38.22) v8(12.23,37.69) v8(12.23,37.06) v8(12.75,29.4) v8(14.01,47.39) v8(14.15,51.49) v8(14.13,50.21) v8(14.15,50.85) v8(14.25,29.4) v8(15.02,47.39) v8(15.75,29.4) v8(15.75,50.12) v8(16.04,47.39) v8(16.24,42) v8(16.24,40.99) v8(16.24,38.7) v8(16.24,37.69) v8(16.25,50.12) v8(16.43,42.87) v8(17.25,29.4) v8(17.75,50.12) v8(17.82,35.1) v8(18.71,35.1) v8(18.75,29.4) v8(20.25,29.4) v8(21.75,29.4) v8(22.13,32.81) v8(22.75,29.4) v8(24.25,29.4) v8(24.72,47.4) v8(24.72,40.9) v8(25.75,29.4) v8(28.25,29.4) v8(28.78,45.77) v8(29.75,29.4) v8(31.02,38.24) v8(32.04,38.24) v8(32.75,42) v8(33.06,47.13) v8(33.06,46.02) v8(33.31,42) v8(33.82,28.75) v8(33.87,42) v8(34.07,46.02) v8(34.28,32.61) v8(34.83,28.75) v8(34.88,33.62) v8(35.6,37.99) v8(36.1,28.48) v8(36.61,37.99) v8(37.12,47.13) v8(37.58,53.95) v8(37.56,53.57) v8(39.7,2.95) v8(40.98,15.16) v8(44.75,9.88) v8(45.25,9.88) v8(56.17,2.65) v8(67.04,15.08) v8(67.04,14.06) v8(67.06,16.04) v8(70.55,8.43) v8(71.26,10.43) v8(71.42,18.16) v8(71.46,45.81) v8(71.46,44.8) v8(71.77,4.94) v8(71.93,14.53) v8(72.07,51.55) v8(72.35,4.95) v8(72.88,47.39) v8(72.87,47.08) v8(72.86,46.78) v8(72.99,21.85) v8(72.96,4.94) v8(73.07,15.73) v8(73.1,13.86) v8(73.16,41.7) v8(73.75,51.6) v8(73.89,10.43) v8(74.04,38.5) v8(73.98,14.78) v8(74.75,8.5) v8(74.88,15.73) v8(74.88,13.81) v8(75.25,51.59) v8(75.64,10.43) v8(75.73,47.97) v8(75.73,47.34) v8(75.73,46.73) v8(76.03,14.53) v8(76.74,22.83) v8(77.13,22.83) v8(77.53,16.29) v8(77.6,22.79) v8(78.01,22.83) v8(78.01,19.3) v8(78.4,22.83) v8(78.88,42.43) v8(78.89,19.3) v8(78.85,8.5) v8(79.23,46.32) v8(79.23,44.29) v8(79.23,43.27) v8(79.78,55.55) v8(79.79,42.43) v8(79.86,22.97) v8(80.11,45.59) v8(80.23,22.96) v8(80.33,14.05) v8(80.35,16.6) v8(80.6,22.98) v8(80.81,14.06) v8(81.19,14.08) v8(82.28,11.52) v8(82.28,10) v8(82.64,39.7) v8(82.59,14.37) v8(83.35,38.4) v8(83.67,45.7) v8(83.67,44.9) v8(83.67,43.3) v8(83.73,8.5) v8(83.98,10.11) v8(84.47,45.7) v8(85.27,44.9) v8(85.27,43.3) v8(85.74,13.48) v8(86.09,20.41) v8(87.35,59.61) v8(87.41,19.19) v8(87.36,17.32) v8(87.67,17.3) v8(87.97,17.32) v8(88.53,8.5) v8(88.68,36.87) v8(89.27,48.9) v8(89.5,59.6) v8(89.65,27.27) v8(89.7,36.87) v8(90.07,54.5) v8(90.07,52.9) v8(90.07,51.3) v8(90.07,43.3) v8(90.07,42.5) v8(90.14,28.41) v8(90.14,23.33) v8(90.13,23.03) v8(90.16,23.64) v8(90.34,20.05) v8(90.64,36.87) v8(90.72,39.45) v8(90.9,15.19) v8(90.9,12.65) v8(90.9,10.11) v8(91.23,59.66) v8(91.59,27.85) v8(91.59,26.39) v8(91.59,21.37) v8(92.24,17.06) v8(92.72,8.58) v8(93.2,11.02) v8(94.07,16.35) v8(94.07,11.52) v8(95.08,22.19) v8(95.29,57.96) v8(95.84,17.37) v8(95.84,11.52) v8(96.28,54.5) v8(96.28,45.7) v8(96.28,44.9) v8(96.28,43.3) v8(96.25,32.1) v8(96.37,57.94) v8(96.35,34.93) v8(96.44,28.73) v8(96.41,18.49) v8(96.99,8.5) v8(97.08,48.9) v8(97.08,45.7) v8(97.32,57.96) v8(97.47,24.1) v8(97.48,23.72) v8(97.47,23.31) v8(97.47,22.06) v8(97.48,21.68) v8(97.5,21.23) v8(97.83,32.36) v8(97.81,31.98) v8(97.8,31.6) v8(97.83,30.59) v8(97.81,30.21) v8(97.83,29.82) v8(97.88,44.9) v8(97.88,43.3) v8(98.33,57.94) v8(98.59,38.74) v8(98.64,28.54) v8(98.64,20.16) v8(99.35,57.96) v8(99.6,38.74) v8(99.9,8.46) v8(100.16,26.26) v8(100.37,57.96) v8(101.25,8.5) v8(101.88,45.7) v8(101.88,44.9) v8(101.94,21.18) v8(102.14,57.96) v8(102.14,11.46) v8(102.19,27.27) v8(102.45,8.5) v8(102.68,47.3) v8(102.68,46.5) v8(102.68,43.3) v8(102.68,42.5) v8(103.41,57.96) v8(103.41,10.97) v8(104.73,25.24) v8(105.37,8.43) v8(105.65,26.26) v8(105.7,39.45) v8(106.27,42) v8(107.02,24.22) v8(107.58,18.94) v8(108.62,29.86) v8(108.95,53.05) v8(109.21,44.16) v8(109.21,43.27) v8(109.26,29.86) v8(109.32,26.38) v8(109.56,25.24) v8(109.56,21.68) v8(109.56,20.67) v8(109.56,19.65) v8(109.71,42.26) v8(109.79,29.88) v8(109.87,8.12) v8(109.87,3.93) v8(109.87,0.96) v8(110.32,12.79) v8(111.85,24.3) v8(111.85,18.64) v8(111.8,6.13) v8(112.1,27.02) v8(112.1,26.13) v8(112.1,25.24) v8(112.23,0.88) v8(113.01,43.3) v8(113.07,6.13) v8(113.47,16.35) v8(113.57,57.04) v8(113.81,48.9) v8(114.02,21.67) v8(114.02,21.17) v8(114.02,20.67) v8(114.02,20.17) v8(114.13,24.99) v8(114.13,8.09) v8(114.21,6.14) v8(114.3,59.58) v8(114.34,38.5) v8(114.61,44.9) v8(114.61,43.3) v8(114.62,0.93) v8(115.05,28.03) v8(115.9,2.93) v8(116,59.6) v8(116.11,38.99) v8(116.23,26.95) v8(116.25,0.9) v8(116.62,12.74) v8(116.83,22.95) v8(117.41,9.49) v8(117.55,59.61) v8(117.96,0.91) v8(118.1,4.63) v8(118.61,48.9) v8(118.61,47.3) v8(118.61,44.9) v8(118.91,12.77) v8(119.41,52.9) v8(119.41,51.3) v8(119.41,43.3) v8(119.41,42.5) v8(119.7,5.38) v8(119.7,2.41) v8(119.92,38.99) v8(120.38,23.97) v8(120.48,23.08) v8(120.61,8.5) v8(121.14,57.42) v8(121.14,57.04) v8(121.19,38.5) v8(121.3,12.54) v8(121.75,19.91) v8(122.15,17.32) v8(122.21,29.49) v8(122.16,18.5) v8(122.16,17.91) v8(122.18,15.26) v8(122.16,14.44) v8(122.16,13.76) v8(122.16,3.93) v8(122.16,2.56) v8(122.59,32.24) v8(122.62,30.93) v8(122.62,5.07) v8(122.71,18.5) v8(122.71,17.91) v8(122.72,17.32) v8(122.79,15.26) v8(122.77,14.47) v8(122.79,13.75) v8(123.23,29.49) v8(123.23,27.21) v8(123.23,24.27) v8(123.51,12.54) v8(124.24,29.51) v8(124.24,24.17) v8(124.19,10.56) v8(124.95,20.92) v8(124.95,19.91) v8(125.62,54.5) v8(125.62,45.7) v8(125.62,44.9) v8(125.62,43.3) v8(126.42,48.9) v8(127.22,44.9) v8(127.22,43.3) v8(127.63,24.12) v8(127.63,23.12) v8(127.63,12.42) v8(127.63,11.38) v8(127.63,10.88) v8(128.08,38.22) v8(128.53,38.22) v8(128.5,24.62) v8(128.5,23.12) v8(128.5,10.88) v8(128.81,29.99) v8(128.93,24.37) v8(129.36,24.62) v8(129.36,23.12) v8(129.36,12.38) v8(129.36,10.88) v8(129.8,25.37) v8(129.8,24.87) v8(129.8,10.63) v8(129.8,10.13) v8(130.23,25.12) v8(130.23,11.88) v8(130.42,45.7) v8(130.88,12.97) v8(131.1,29.49) v8(131.13,16.87) v8(131.13,15.14) v8(131.1,10.38) v8(131.22,44.9) v8(131.15,7.95) v8(131.15,7.08) v8(131.15,6.19) v8(131.33,4.44) v8(131.38,15.57) v8(131.4,5.3) v8(131.63,16.87) v8(131.63,14.27) v8(131.63,13.41) v8(132.02,47.3) v8(132.02,46.5) v8(132.02,43.3) v8(132.02,42.5) v8(131.96,25.12) v8(131.96,10.38) v8(132.12,28.73) v8(132.12,15) v8(132.12,13.25) v8(132.4,12.63) v8(132.83,25.12) v8(132.83,22.62) v8(132.83,22.12) v8(133.13,28.73) v8(133.18,7.97) v8(133.18,6.98) v8(133.7,10.38) v8(134.17,38.75) v8(134.56,10.38) v8(135.09,27.79) v8(135.43,22.62) v8(135.43,22.12) v8(135.43,10.38) v8(135.67,53.62) v8(136.15,7.89) v8(136.15,6.95) v8(136.29,10.38) v8(136.38,51.15) v8(136.38,50.13) v8(136.73,22.37) v8(136.79,20.05) v8(136.79,17.46) v8(136.79,14.86) v8(137.02,21.37) v8(137.04,18.76) v8(137.04,16.16) v8(137.16,22.62) v8(137.16,10.38) v8(137.29,16.59) v8(137.29,15.72) v8(137.28,5.78) v8(137.36,4.61) v8(137.54,18.76) v8(137.54,17.89) v8(137.54,17.02) v8(137.54,16.16) v8(137.54,15.29) v8(137.54,14.43) v8(137.54,13.56) v8(137.54,12.69) v8(137.48,3.42) v8(137.59,10.13) v8(137.55,2.35) v8(138.16,7.97) v8(138.54,23.87) v8(138.54,21.54) v8(138.54,10.63) v8(138.72,28.49) v8(138.97,22.62) v8(138.97,21.95) v8(138.97,10.88) v8(139.4,25.37) v8(139.4,23.87) v8(139.4,21.54) v8(139.4,10.13) v8(139.58,57.96) v8(139.83,22.62) v8(139.91,5.91) v8(139.91,5.22) v8(140.4,59.66) v8(140.6,57.96) v8(140.7,21.95) v8(140.79,7.06) v8(141.13,25.37) v8(141.13,22.37) v8(141.13,21.54) v8(141.26,0.86) v8(141.7,7.08) v8(142.02,29.24) v8(142,21.54) v8(142.32,45.7) v8(142.32,44.9) v8(142.32,43.3) v8(142.4,2.35) v8(142.5,59.6) v8(142.58,7.08) v8(142.75,0.9) v8(142.87,25.37) v8(142.87,22.37) v8(142.87,21.54) v8(143.01,2.35) v8(143.12,45.7) v8(143.24,29.24) v8(143.46,7.08) v8(143.73,22.37) v8(143.73,21.54) v8(143.92,44.9) v8(143.92,43.3) v8(144,5.3) v8(144.08,2.94) v8(144.23,59.62) v8(144.17,21.95) v8(144.32,7.08) v8(144.32,0.92) v8(144.6,25.37) v8(144.6,22.37) v8(144.6,21.54) v8(144.84,29.24) v8(145.2,7.08) v8(145.32,38.74) v8(145.27,2.41) v8(145.46,22.37) v8(145.46,21.54) v8(145.73,2.41) v8(146.06,28.7) v8(146.07,7.08) v8(146.33,25.37) v8(146.33,22.37) v8(146.33,21.54) v8(146.37,38.75) v8(146.76,21.95) v8(146.76,10.38) v8(146.95,7.08) v8(147.03,2.41) v8(147.2,22.37) v8(147.2,21.54) v8(147.43,38.3) v8(147.36,35.33) v8(147.47,31.19) v8(147.48,2.41) v8(147.63,21.95) v8(147.63,10.38) v8(147.81,38.3) v8(147.83,7.08) v8(147.92,48.9) v8(148.06,25.37) v8(148.06,22.37) v8(148.63,35.33) v8(148.72,54.5) v8(148.72,52.9) v8(148.72,51.3) v8(148.72,43.3) v8(148.72,42.5) v8(148.7,7.09) v8(148.88,29.24) v8(148.93,22.37) v8(148.93,21.54) v8(149.36,21.95) v8(149.58,7.09) v8(149.79,21.54) v8(150.23,23.62) v8(150.23,21.95) v8(150.56,7.99) v8(150.7,28.65) v8(150.66,23.87) v8(150.66,22.37) v8(150.66,21.54) v8(151.53,21.54) v8(151.96,21.95) v8(151.96,10.38) v8(152.18,57.96) v8(152.16,38.75) v8(152.39,22.37) v8(152.39,21.54) v8(152.59,28.58) v8(152.83,21.95) v8(152.83,10.38) v8(153.2,57.96) v8(153.21,7.98) v8(153.34,25.37) v8(153.34,22.37) v8(153.38,21.8) v8(153.53,2.94) v8(153.62,20.17) v8(153.62,14.97) v8(153.83,23.18) v8(153.77,10.38) v8(153.86,24.93) v8(153.87,13.67) v8(154.12,24.5) v8(154.12,22.77) v8(154.12,17.57) v8(154.21,57.94) v8(154.21,30) v8(154.2,10.63) v8(154.37,21.47) v8(154.37,20.6) v8(154.37,19.74) v8(154.37,18.87) v8(154.37,18) v8(154.37,17.14) v8(154.43,6.63) v8(154.42,5.71) v8(154.42,4.79) v8(154.52,2.94) v8(154.62,25.37) v8(154.62,24.5) v8(154.62,23.63) v8(154.62,16.7) v8(154.63,10.88) v8(154.93,54.5) v8(154.93,45.7) v8(154.93,44.9) v8(154.93,43.3) v8(154.87,24.93) v8(154.87,20.6) v8(155.12,24.5) v8(155.12,23.63) v8(155.12,21.9) v8(155.12,20.17) v8(155.12,18.44) v8(155.12,16.7) v8(155.51,57.96) v8(155.51,2.94) v8(155.62,25.37) v8(155.62,24.5) v8(155.62,23.63) v8(155.62,21.9) v8(155.62,20.17) v8(155.62,18.44) v8(155.62,16.7) v8(155.73,48.9) v8(155.73,45.7) v8(155.87,24.93) v8(156.12,24.5) v8(156.12,23.63) v8(156.12,22.77) v8(156.12,21.9) v8(156.12,21.03) v8(156.12,20.17) v8(156.12,19.3) v8(156.12,18.44) v8(156.12,17.57) v8(156.12,16.7) v8(156.12,15.84) v8(156.12,14.11) v8(156.12,13.24) v8(156.2,29.47) v8(156.37,24.07) v8(156.37,23.2) v8(156.53,57.42) v8(156.53,57.04) v8(156.53,44.9) v8(156.53,43.3) v8(157.31,6.54) v8(157.49,30) v8(158.18,5.53) v8(158.76,30.27) v8(158.91,18.19) v8(159.04,57.96) v8(159.05,5.54) v8(159.24,18.18) v8(159.29,38.24) v8(159.36,16.89) v8(159.6,22.24) v8(159.61,21.93) v8(159.62,14.64) v8(159.78,30.27) v8(159.93,22.24) v8(159.92,21.93) v8(159.93,5.54) v8(160.03,57.96) v8(159.97,14.64) v8(160.15,18.19) v8(160.53,45.7) v8(160.53,44.9) v8(160.48,18.19) v8(160.56,38.74) v8(160.64,9.87) v8(160.65,9.53) v8(160.79,30.27) v8(160.79,16.03) v8(160.77,15.65) v8(160.95,22.26) v8(160.86,14.62) v8(160.96,21.91) v8(160.96,9.87) v8(160.96,9.53) v8(161.15,57.96) v8(161.23,14.62) v8(161.33,47.3) v8(161.33,46.5) v8(161.33,43.3) v8(161.33,42.5) v8(161.3,22.26) v8(161.3,21.91) v8(161.53,25.48) v8(161.58,38.74) v8(161.94,9.87) v8(161.94,9.53) v8(162.06,58.03) v8(162.16,14.95) v8(162.25,9.86) v8(162.27,9.54) v8(163.13,57.96) v8(164.07,5.43) v8(164.65,46.14) v8(164.73,40.81) v8(164.88,16.05) v8(166.86,7.21) v8(166.91,0.93) v8(166.98,59.58) v8(167.63,39.51) v8(168.16,43.78) v8(168.16,42.79) v8(169,59.6) v8(169,3.65) v8(169.25,0.9) v8(170.06,6.22) v8(170.06,5.15) v8(170.62,59.63) v8(170.8,0.96) v8(171.49,57.04) v8(171.65,43.3) v8(172.45,48.9) v8(172.5,38.74) v8(173.25,44.9) v8(173.25,43.3) v8(173.77,38.24) v8(176.24,38.74) v8(176.25,8.86) v8(177.25,47.3) v8(177.25,44.9) v8(177.95,4.3) v8(178.05,52.9) v8(178.05,51.3) v8(178.05,43.3) v8(178.05,42.5) v8(180.92,17.07) v8(180.87,16.06) v8(182.41,36.42) v8(182.92,57.96) v8(183.15,39.3) v8(183.15,38.69) v8(183.15,38.08) v8(183.17,26.8) v8(183.32,27.2) v8(183.32,26.52) v8(183.5,26.8) v8(183.63,26.52) v8(183.82,26.79) v8(183.96,27.22) v8(183.98,26.51) v8(184.12,26.79) v8(184.26,54.5) v8(184.26,45.7) v8(184.26,44.9) v8(184.26,43.3) v8(184.44,26.8) v8(184.47,14.37) v8(184.61,27.23) v8(184.95,38.5) v8(185.02,22.06) v8(185.06,48.9) v8(185.46,12.39) v8(185.68,19.32) v8(185.68,18.41) v8(185.86,44.9) v8(185.86,43.3) v8(185.9,24) v8(186.15,38.99) v8(186.52,12.39) v8(186.56,18.85) v8(186.59,4.81) v8(186.99,23.55) v8(187.36,19.32) v8(187.36,18.41) v8(187.51,12.39) v8(188.35,14.37) v8(189.06,45.7) v8(189.27,14.37) v8(189.39,8.81) v8(189.86,44.9) v8(190.66,47.3) v8(190.66,46.5) v8(190.66,43.3) v8(190.66,42.5) v8(191.25,20.16) v8(192.31,21.15) v8(192.44,9.72) v8(193.08,4.36) v8(193.53,0.88) v8(193.58,59.66) v8(194.09,46.88) v8(194.07,45.53) v8(194.45,45.53) v8(194.6,36.77) v8(194.6,35.93) v8(194.6,35.25) v8(195.5,59.6) v8(195.75,0.9) v8(196.18,55.97) v8(197,59.66) v8(197.8,0.88) v8(198.16,37.53) v8(198.41,50.29) v8(198.41,45.46) v8(201.08,50.26) v8(201.08,48.28) v8(201.08,46.14) v8(201.1,21.53) v8(201.18,23) v8(201.17,20.27) v8(201.15,17.42) v8(201.15,13.68) v8(201.15,9.8) v8(201.15,6.44) v8(202.73,41.02) v8(202.74,40.1) v8(202.75,37.38) v8(202.78,8.2) v8(202.8,6.75) v8(202.83,5.45) v8(205.18,3.44) v8(206.58,35.6) v8(208.25,35.6) v8(209.59,35.59) v8(216.68,3.44) v8(217.26,16.25) v8(217.71,15.49) v8(217.94,16.25) v8(218.74,15.5) v8(219.42,14.88) v8(219.67,3.88) v8(222.41,1.92) v8(223.75,1.9) v8(225.08,1.89) v8(226.16,17.3) v8(227.87,13.51) v8(228.77,32.73) v8(231.56,3.65) v8(232,32.99) v8(233.46,27.22) v8(234.48,27.22) v8(235.44,28.16) v8(235.49,27.22) v8(235.49,13.51) v8(235.72,33.19) v8(236.56,16.86) v8(237.27,45.84) v8(237.35,38.22) v8(237.35,35.64) v8(237.34,10.9) v8(238.03,3.95) v8(239.41,48.58) v8(239.48,4.81) v8(240.49,40.58) v8(240.61,37.24) v8(241.34,20.02) v8(241.7,6.26) v8(242.15,42.92) v8(242.78,20.41) v8(243.06,38.96) v8(243.63,17.28) v8(243.75,48.6) v8(243.95,18.43) v8(244.6,16.79) v8(245.04,10.79) v8(245.04,10.19) v8(245.02,7.42) v8(244.99,5.95) v8(245.01,4.11) v8(245.22,41.85) v8(245.3,13.25) v8(247.33,10.86) v8(247.85,7) v8(250.75,8.95) v8(251.1,5.05) v8(251.63,40.48) v8(252.25,8.95) v8(253.39,19.64) v8(253.78,15.08) v8(253.78,13.81) v8(253.75,8.95) v8(254.04,16.35) v8(254.34,12.54) v8(254.73,34.89) v8(255.25,8.95) v8(255.48,10.94) v8(257.25,8.95) v8(257.41,12.54) v8(257.5,5.05) v8(257.75,8.95) v8(258.75,8.95) v8(259.25,8.95) v8(259.75,8.95) v8(260.06,10.94) v8(260.25,8.95) v8(263.48,17.62) v8(263.64,10.94) v8(263.9,5.05) v8(267.01,20.98) v8(267.07,10.94) v8(267.15,7) v8(268.06,19.52) v8(268.98,48.57) v8(270.25,48.6) v8(270.75,14.06) v8(270.75,13.05) v8(271.17,3.92) v8(271.25,10.9) v8(271.49,48.7) v8(272.9,14.68) v8(274.31,48.43) v8(275.22,10.86) v8(276.18,31.08) v8(276.97,48.51) v8(277.01,45.45) v8(277.2,28.01) v8(277.2,27.63) v8(277.56,34.1) v8(277.58,25.42) v8(277.57,24.99) v8(278.45,33.2) v8(278.7,89.13) v8(278.88,26.79) v8(278.88,26.41) v8(280.02,10.86) v8(280.24,80.31) v8(280.24,73.81) v8(280.33,25.19) v8(281.47,14.37) v8(281.77,89.91) v8(281.85,48.58) v8(281.82,3.92) v8(282.15,54.34) v8(282.15,53.85) v8(282.15,53.36) v8(282.53,85.18) v8(282.53,84.17) v8(282.53,82.14) v8(282.46,26.94) v8(282.74,78.81) v8(282.74,46.12) v8(283.14,89.4) v8(283.07,25.87) v8(283.07,25.49) v8(283.07,25.04) v8(283.3,50.09) v8(283.93,23.17) v8(284.25,50.7) v8(284.39,23.17) v8(284.44,10.86) v8(284.65,73.05) v8(284.82,79.09) v8(284.85,23.17) v8(285.06,89.26) v8(285.2,48.58) v8(285.53,73.04) v8(285.75,50.7) v8(286.19,3.26) v8(286.54,14.19) v8(286.74,75.39) v8(287.82,87.42) v8(288.61,82.13) v8(288.83,87.42) v8(288.78,76.17) v8(289.04,8.19) v8(289.2,45.19) v8(289.6,73.7) v8(289.77,48.58) v8(289.85,90.24) v8(290.15,10.79) v8(290.56,75.28) v8(291.12,87.42) v8(291.13,73.82) v8(291.62,16.22) v8(291.68,17.5) v8(292.11,81.13) v8(292.11,80.63) v8(292.61,84.63) v8(292.61,78.63) v8(292.75,50.7) v8(292.8,44.2) v8(293.03,12.4) v8(293.11,84.63) v8(293.05,48.51) v8(293.14,3.26) v8(293.28,76.7) v8(293.28,75.86) v8(293.25,50.7) v8(293.41,87.42) v8(294.02,14.64) v8(294.08,75.79) v8(295.44,87.67) v8(295.44,84.73) v8(295.57,63.77) v8(295.82,75.79) v8(295.82,70.6) v8(295.84,54.35) v8(295.85,53.85) v8(295.87,53.37) v8(295.95,48.35) v8(295.95,36.01) v8(295.95,31.06) v8(295.95,21.91) v8(295.97,45.71) v8(296,44.25) v8(295.97,42.85) v8(296.02,40.05) v8(296.02,26.48) v8(296.02,19.27) v8(296,17.75) v8(296.02,13.68) v8(296.09,16.48) v8(296.1,10.94) v8(296.4,81.63) v8(296.4,79.09) v8(296.4,78.07) v8(297.09,57.29) v8(297.37,54.91) v8(297.47,48.05) v8(297.72,73.8) v8(297.74,51.16) v8(297.85,31.45) v8(297.88,18.81) v8(297.97,60.65) v8(298.01,37.12) v8(298.11,64.69) v8(298.11,57.29) v8(298.14,51.15) v8(298.18,76.8) v8(298.18,75.79) v8(298.61,60.67) v8(298.59,51.16) v8(298.77,73.47) v8(298.81,21.35) v8(298.89,50.05) v8(299.12,64.69) v8(299.1,60.66) v8(299.12,57.29) v8(299.12,54.91) v8(299.07,18.85) v8(299.23,85.58) v8(299.74,21.35) v8(299.76,70.6) v8(299.76,47.13) v8(299.96,50.1) v8(300.05,27.85) v8(300.14,57.29) v8(300.21,76.67) v8(300.17,42.85) v8(300.17,32.75) v8(300.18,31.45) v8(300.98,53.17) v8(301.06,75.77) v8(304.1,86.25) v8(305.1,88.9) v8(305.6,88.9) v8(308.13,91.74) v8(309.01,91.74) v8(309.6,86.25) v9(8.17,50.88) v9(40.71,52.62) v9(41.71,52.62) v9(42.71,52.62) v9(43.71,52.62) v9(114.84,3.31) v9(114.86,2.37) v9(117.21,17.69) v9(117.54,16.58) v9(117.87,18.51) v9(118.94,18.43) v9(119.01,16.56) v9(119.1,3.06) v9(119.12,2.35) v9(119.46,17.59) v9(138.16,18.92) v9(138.16,17.65) v9(138.16,16.38) v9(138.16,15.11) v9(138.16,14.44) v9(138.16,13.84) v9(138.33,12.84) v9(138.64,21.14) v9(139.25,12.28) v9(139.44,21.29) v9(140.17,12.26) v9(140.71,21.29) v9(141.02,12.26) v9(141.74,31.78) v9(141.74,29.19) v9(141.72,27.17) v9(141.98,21.29) v9(143.25,21.29) v9(143.56,12.26) v9(144.55,31.75) v9(144.61,29.23) v9(144.57,21.26) v9(144.83,12.26) v9(145.84,21.26) v9(147.11,21.26) v9(147.06,12.24) v9(147.33,31.79) v9(147.28,29.23) v9(148.38,21.26) v9(149.6,12.24) v9(149.65,21.26) v9(150.74,29.18) v9(150.82,31.66) v9(150.79,27.18) v9(150.87,12.24) v9(152.14,12.24) v9(152.41,21.2) v9(152.99,12.89) v9(153.16,20.3) v9(153.18,19.18) v9(153.18,17.91) v9(153.18,16.64) v9(153.18,14.1) v9(172.95,4.27) v9(173.02,2.01) v9(174.93,4.31) v9(174.92,2.08) v9(176.78,4.31) v9(176.79,2.07) v9(180.71,4.38) v9(181.36,3.78) v9(181.66,7.03) v9(183.16,3.78) v9(183.46,7.03) v9(184.96,3.78) v9(185.26,7.03) v9(186.76,3.78) v9(187.06,7.03) v9(188.56,3.78) v9(188.86,7.03) v9(190.36,3.78) v9(190.66,7.03) v9(192.16,3.78) v9(192.46,7.03) v9(195.76,3.78) v9(196.06,7.03) v9(198.76,3.78) v9(199.36,3.78) v9(200.01,4.16) v10(138.14,15.77) v10(138.18,19.45) v10(138.17,18.41) v10(138.16,17.02) v10(145.2,12.26) v10(146.22,12.27) v10(148.35,12.24) v10(149.9,12.26) v10(151.19,21.23) v10(152.16,21.24) v10(153.17,19.49) v10(153.21,18.2) v10(153.21,16.94) v10(153.21,16.34) v10(153.23,15.84) v10(153.18,15.26) v10(153.21,14.72) v10(153.23,13.35) v10(194.22,57.5) v10(194.22,56.99)
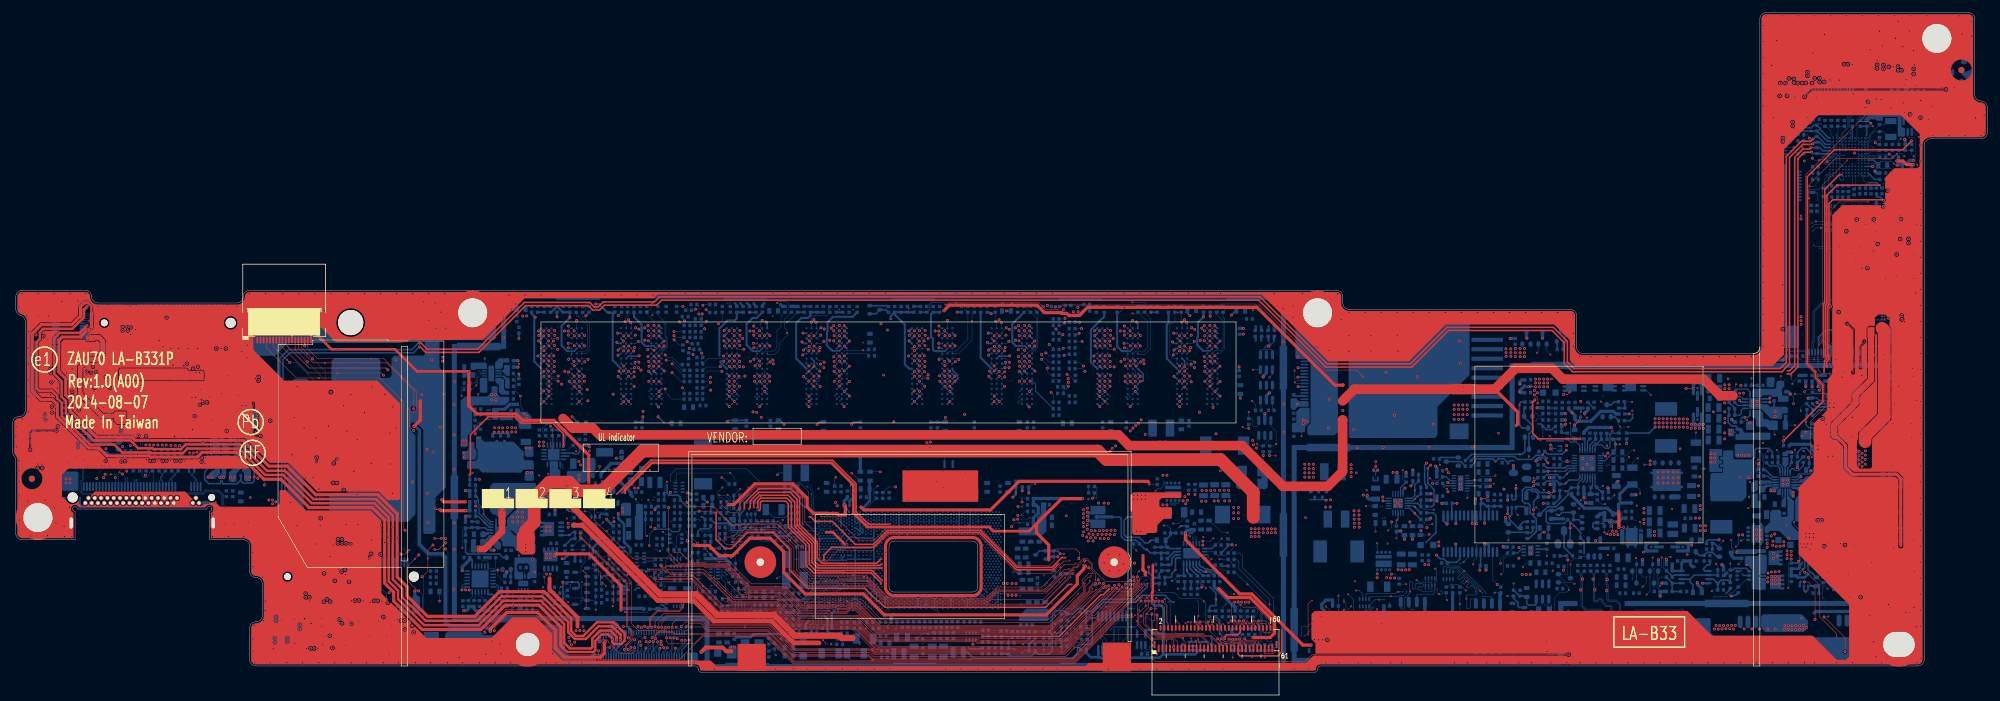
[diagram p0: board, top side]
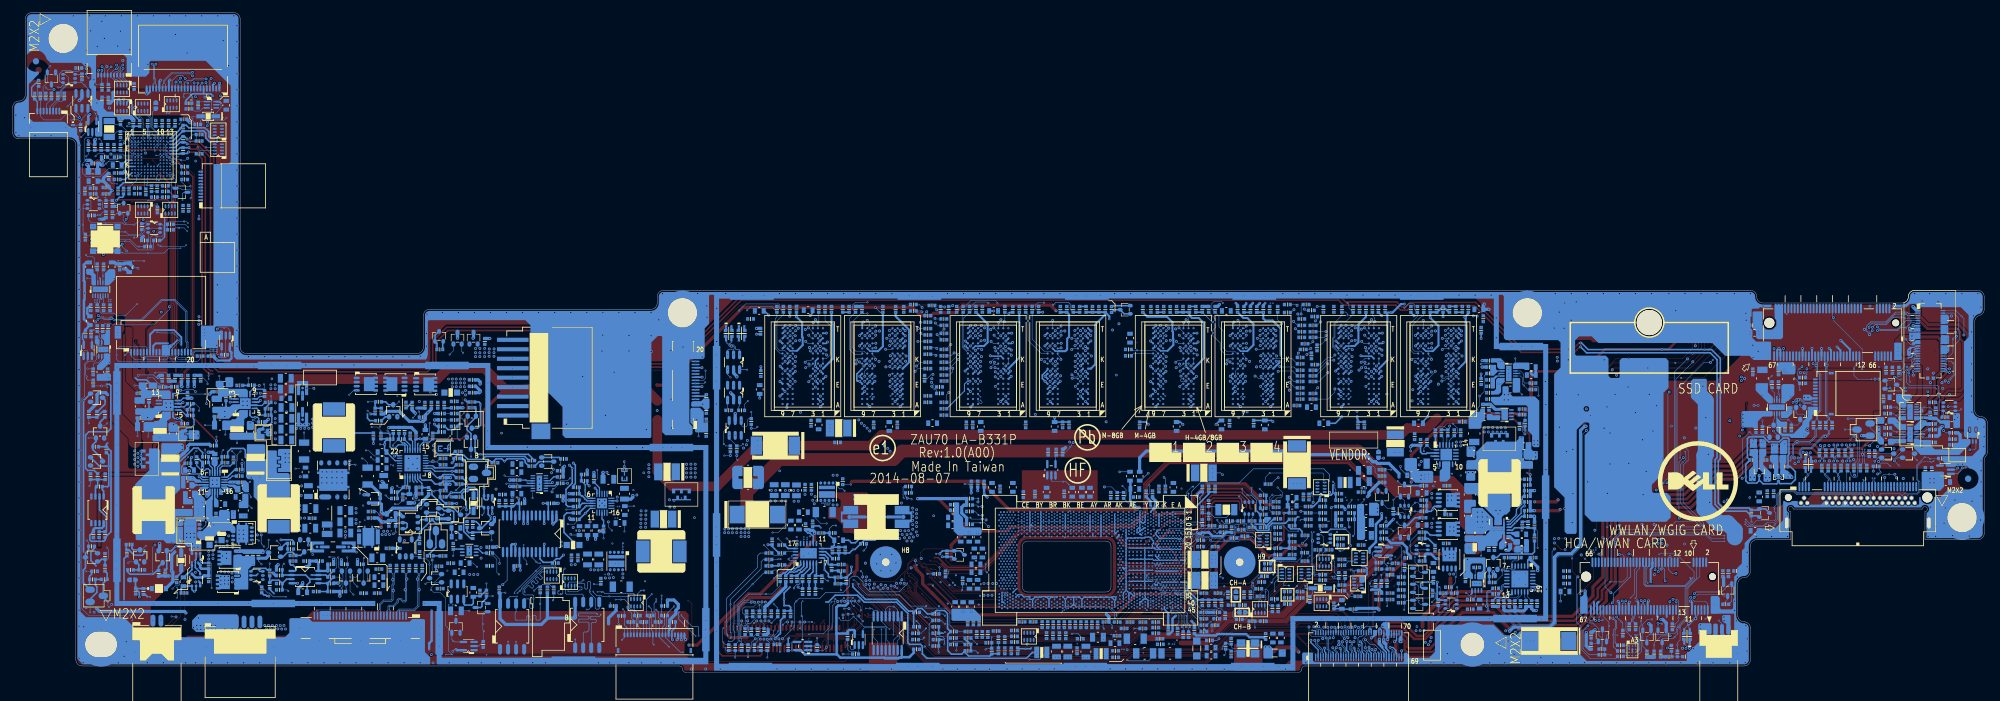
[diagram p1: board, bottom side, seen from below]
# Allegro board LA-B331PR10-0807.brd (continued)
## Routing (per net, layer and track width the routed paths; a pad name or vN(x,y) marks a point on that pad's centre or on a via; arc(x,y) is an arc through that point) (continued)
GNDA_CHG: length 22.4
  IN4 w0.508: v3(243.29,29.76) 243.29,29.35 245.46,27.19 v1(245.46,24.34)
  BOTTOM w0.254: v3(245.86,35.17) 245.25,34.56 242.9,34.56 242.49,34.97 PR745.2
  BOTTOM w0.508: v3(252.44,29.23) 252.54,29.13 PC704.2 ; v3(252.97,38.78) PR723.2 PC723.1 PC725.2 249.39,38.78 248.66,38.05 PC721.1 ; PC707.1 PR709.1 v3(248.65,27.65) ; v1(245.46,24.34) 245.43,24.31 PQ709.3 ; v3(243.29,29.76) 243.34,29.81 PC715.1 PR712.2 ; PC716.1 v3(243.22,30.83) ; PC702.1 v3(248.89,26.83)
  vias: v3(245.91,35.91) v3(248.47,33.88) v3(248.47,32.28) v3(249.16,32.96) v3(249.85,33.88) v3(249.92,32.28)
VBATT: length 9.1
  TOP w0.102: v6(247.97,39.9) 247.25,39.18 v3(247.18,39.18)
  IN4 w0.508: v1(251.65,43.77) 251.65,42.37 248.46,39.18 v3(247.18,39.18)
  BOTTOM w0.508: PR720.2 v3(247.18,39.18)
VCCSENSE: length 39.3
  IN3 w0.254: v4(166.82,5.6) 166.88,5.66 166.88,6.28 166.78,6.38 166.78,9.17 162.32,13.64 162.32,16.14 165.47,19.3 166.5,19.3 167.32,18.48 168.24,18.48 172.19,18.48 173.15,19.44 177.99,19.44 179.77,17.66 v3(179.77,16.68)
  IN4 w0.254: v1(166.81,5.17) 166.82,5.22 v4(166.82,5.6)
  BOTTOM w0.254: v3(179.77,16.68) 179.77,16.67 v2(179.77,15.79) PR542.1 181.38,14.99 PR550.1 181.43,15.65 PC542.2 181.89,16.11 PC549.1
VCCSENSE_R: length 16.7
  IN4 w0.254: v1(153.34,10.13) 153.57,9.9 153.75,9.9 154.29,9.36 157.22,9.36 158.53,8.04 162.54,8.04 165.14,5.44 165.14,5.32 v1(165.29,5.17)
  BOTTOM w0.102: RC24.2 v2(165.95,3.14)
  BOTTOM w0.254: v1(165.29,5.17) RC25.2 165.95,5.12 RC24.2
VCCSTPG_MCP: length 29.1
  IN3 w0.076: 158.79,21.18 157.39,21.18 156.42,20.21 154.83,20.21 154.81,20.24 153.85,20.24 153.71,20.09 153.45,20.09 153.26,20.28 153.26,20.3 152.42,21.14 149.96,21.14 149.77,21.33 149.77,21.45 149.55,21.68 149.28,21.68 149.06,21.46 v4(148.94,21.46)
  IN3 w0.097: 158.79,21.18 160.46,21.18 160.52,21.24 162.08,21.24 168.95,28.11 170.39,28.11 v3(170.93,27.58)
  IN4 w0.066: v1(148.43,21.49) 148.91,21.49 v4(148.94,21.46)
  BOTTOM w0.076: UCPU1.BU14 148.5,21.55 v1(148.43,21.49)
  BOTTOM w0.097: v2(170.23,27.4) 170.33,27.5 170.85,27.5 v3(170.93,27.58) 170.93,27.63 171.18,27.88 RC29.2
VDD_1.35V: length 4.3
  IN3 w0.508: v3(221.12,23.82) 221.12,22.9 220.58,22.37 v3(219.67,22.37)
  BOTTOM w0.076: PR601.1 v2(218.98,21.23)
  BOTTOM w0.508: PR601.1 219.11,22.37 v3(219.67,22.37)
VSSSENSE: length 43.7
  IN3 w0.254: v4(166.28,5.83) 166.28,5.86 166.11,6.03 166.11,9.06 161.76,13.41 161.76,16.37 165.24,19.86 166.73,19.86 167.55,19.04 168.01,19.04 168.01,19.04 171.96,19.04 172.92,20 178.22,20 180.86,17.37 v4(181.37,17.37)
  IN4 w0.254: v4(166.28,5.83) 166.28,5.84 166.62,6.19 v1(166.86,6.19) ; v4(181.37,17.37) 181.37,17.23 181.52,17.07 v1(181.84,17.07)
  BOTTOM w0.102: v2(165.05,4.41) 165.01,4.45 165.01,5.34 165.33,5.66 166.33,5.66 v1(166.86,6.19)
  BOTTOM w0.254: v1(181.84,17.07) 181.89,17.02 PC549.2 183.3,17.02 183.45,17.18 183.45,18.05 184,18.6 PU702.8
VSSSENSE_R: length 15.9
  IN4 w0.254: v1(153.34,10.63) 153.58,10.39 153.73,10.39 154.35,9.77 157.39,9.77 158.18,8.98 158.43,8.98 158.81,8.6 162.78,8.6 165.19,6.19 v1(165.33,6.19)
  BOTTOM w0.102: v2(164.98,6.39) 165.17,6.19 v1(165.33,6.19)
  BOTTOM w0.254: v1(165.33,6.19) RC38.1 RC39.1
+DC_IN: length 124.7
  TOP w0.102: v3(254.19,22.94) v6(254.96,22.94) ; v3(253.17,22.33) 253.17,23.28 v6(252.7,23.75) ; v3(252.87,21.82) 252.36,21.82 v6(252.25,21.94)
  TOP w0.508: v3(254.19,22.94) 254.19,25.35 v3(254.14,25.4)
  IN2 w0.381: v4(298.98,65.6) 300.19,64.39 300.19,63.47 300.59,63.06 300.59,52.75 300.71,52.63 300.71,11.68 v4(299.71,10.68)
  IN4 w0.508: v1(252.56,22.41) 252.12,22.85 249.26,22.85 248.52,22.11 246.35,22.11 244.57,20.34 v1(244.55,20.34) ; v1(299.25,10.14) 299.25,10.21 v4(299.71,10.68) ; v4(298.98,65.6) 298.97,65.61 298.97,66.18 297.81,67.34 297.81,68.58 299.03,69.8 299.17,69.8 300.24,70.87 300.24,75.73 v1(300.26,75.76) ; v3(274.01,6.87) 275.04,5.84 283.99,5.84 284.59,6.45 284.59,8.92 v1(285.06,9.39)
  BOTTOM w0.508: v1(299.25,10.14) 298.74,9.63 285.3,9.63 v1(285.06,9.39) ; PD700.3 254.38,26.82 254.14,26.58 v3(254.14,25.4) 253.82,25.09 PC700.1 252.39,25.99 248.73,25.99 246.67,28.04 PR707.1
  vias: v3(253.45,21.81) v3(253.77,22.33) v3(254.04,21.8) v3(269.32,6.85) v3(269.56,7.42) v3(269.91,6.85) v3(270.15,7.39) v3(270.53,6.88) v3(270.74,7.42) v3(271.12,6.89) v3(271.4,7.41) v3(271.72,6.89) v3(272.02,7.43) v3(272.32,6.85) v3(272.61,7.43) v3(275.23,6.89) v3(276.43,6.84) v3(277.75,14.98) v3(277.75,14.3) v3(277.79,15.71) v3(278.34,15.89) v3(278.38,15.18) v3(278.37,14.56) v3(278.36,13.98) v3(278.93,15.91) v3(278.94,14.01) v3(278.97,15.18) v3(278.95,14.6) v3(279.54,15.97) v3(279.56,15.16) v3(279.55,14.57) v3(279.55,13.94)
+DCIN: length 1.9
  BOTTOM w0.076: PR705.2 256.32,33.18 257.02,33.88 v2(257.2,33.88)
+EDP_COM: length 4.9
  IN4 w0.508: v1(138.54,11.13) 138.54,10.3 139.42,9.42 v1(139.42,9.2)
  BOTTOM w0.102: v2(138.5,7.03) 138.5,7.46 139.01,7.97 RC1.1
  BOTTOM w0.508: RC1.1 139.02,8.8 v1(139.42,9.2)
+INV_PWR_SRC:
  vias: v1(242.43,10.69) v1(242.86,10.69) v1(243.5,10.69) v1(262.25,8.95) v1(262.75,8.95) v1(263.25,8.95) v2(243.71,16.09)
+LCDVDD: length 29
  IN4 w0.381: v1(246.2,9.77) 246.2,12.65 246.89,13.34 254.84,13.34 255.26,12.92 v1(255.26,12.54) 255.75,12.05 v1(255.75,8.95) ; v1(246.59,3.65) v1(242.33,3.65)
  BOTTOM w0.102: v6(242.83,3.32) 242.5,3.65 v1(242.33,3.65)
  BOTTOM w0.381: v1(242.33,3.65) 242.18,3.51 U7.5 ; v1(246.2,9.77) 246.2,4.98 246.59,4.59 v1(246.59,3.65)
+PBATT: length 31.3
  TOP w0.102: v3(245.43,44.01) 246.04,44.01 v6(246.42,44.39)
  IN1 w0.508: v3(256.89,28.12) 256.7,28.31 247.18,28.31 246.57,28.92 246.57,37.48 249.49,40.4 249.49,41.29 248.8,41.98 247.97,41.98 245.93,44.01 v3(245.43,44.01)
  BOTTOM w0.508: v3(256.89,28.12) PD700.2
+PCH_VCCDSW: length 37
  IN2 w0.254: v4(114.48,26.25) 114.48,26.33 114.58,26.43 114.58,27.27 116.91,29.6 129.14,29.6 130.58,28.16 131,28.16 132.45,26.71 132.81,26.71 133.52,26 133.64,26 134.99,24.66 134.99,23.81 135.66,23.14 136.42,23.14 137.12,22.45 137.12,21.58 136.88,21.34 136.57,21.34 v4(136.46,21.23)
  IN4 w0.102: 135.52,21.89 135.86,22.23 v1(135.86,22.37)
  IN4 w0.254: 135.52,21.89 135.52,21.59 136.06,21.06 136.29,21.06 v4(136.46,21.23) ; v4(114.48,26.25) 114.48,26.15 114.62,26.01 v1(114.62,25.58)
  BOTTOM w0.102: v2(116.44,29.23) 116.44,28.41 RH137.1
  BOTTOM w0.254: v1(114.62,25.58) C205.1 RH137.1
+PWR_SRC_AC:
  vias: v6(265.01,18.66)
+RTC_VCCSUS: length 27.6
  IN2 w0.254: v4(127.67,26.13) 128.2,25.6 128.52,25.6 130.12,24 131.19,24 131.52,23.67 132.27,23.67 132.42,23.82 132.88,23.82 133.03,23.97 133.36,23.97 133.6,23.73 133.6,22.89 133.69,22.81 133.69,21.72 v4(133.53,21.56)
  IN3 w0.254: v4(116.32,23.97) 116.32,24.21 116.55,24.44 117.52,24.44 117.79,24.17 122.49,24.17 124.62,26.31 127.49,26.31 v4(127.67,26.13)
  IN4 w0.254: v1(115.86,23.46) 115.88,23.49 115.9,23.49 116.24,23.83 116.24,23.89 v4(116.32,23.97) ; v4(133.53,21.56) 133.64,21.67 133.79,21.67 v1(133.84,21.72)
  BOTTOM w0.254: v1(115.86,23.46) 114.43,23.46 114.13,23.17 114.13,23.12 ; UCPU1.AC15 133.99,21.87 v1(133.84,21.72) ; 114.13,23.12 RH136.1 ; 114.13,23.12 112.96,24.3 CH28.1
+RTCBATT: length 5.8
  IN4 w0.254: v1(291.17,11.99) 291.18,11.99 291.58,11.59 291.58,9.47 v1(290.29,8.19)
  BOTTOM w0.076: v1(291.17,11.99) 290.81,11.99 v2(290.73,11.9)
  BOTTOM w0.254: RTCR1.2 291.52,12.34 291.17,11.99 v1(291.17,11.99)
+RTCVCC: length 438
  TOP w0.254: v5(166.63,18.17) 166.01,18.17 164.46,16.62 158.97,16.62 153.14,22.45 138.41,22.45 136.22,20.26 133.34,20.26 v5(132.67,20.93) 132.67,20.93 v2(131.07,22.54) 129.7,23.91 126.99,23.91 126.3,24.59 126.08,24.59 v5(126.07,24.58)
  IN1 w0.203: v5(132.67,20.93) 132.76,21.02 132.76,21.6 v4(132.86,21.7)
  IN1 w0.254: v4(165.97,17.96) 166.17,18.17 v5(166.63,18.17) ; v4(122.85,23.27) 122.93,23.35 122.93,23.36 124.54,24.96 125.23,24.96 125.52,24.68 125.97,24.68 v5(126.07,24.58) ; v4(88.5,37.48) 88.5,37.76 80.88,45.39 80.66,45.61 37.44,45.61 34.15,48.9 v3(27.58,48.9)
  IN2 w0.254: v4(106.36,25.6) 107.24,24.72 107.7,24.72 107.97,24.45 109.61,24.45 110.58,23.49 115.67,23.49 115.73,23.55 116.96,23.55 117.22,23.81 117.22,23.94 117.49,24.21 118.36,24.21 118.57,24.43 122.17,24.43 122.85,23.75 122.85,23.27 v4(122.85,23.27) ; v3(12.71,48.37) 13.36,49.01 27.46,49.01 v3(27.58,48.9) ; v3(293.62,90.35) 293.76,90.21 293.76,88.03 293.18,87.44 291.37,87.44 288.59,84.66 288.59,81.95 288.81,81.73 288.81,81.68 288.99,81.5 288.99,79.78 290.17,78.6 290.17,72.08 290.22,72.03 290.22,72 290.56,71.66 290.56,70.23 290.21,69.88 v3(290.18,69.88)
  IN3 w0.254: v4(165.97,17.96) 166.15,17.77 166.15,11.51 173.21,4.46 196.93,4.46 197.53,5.05 200.77,5.05 201.78,6.06 205.5,6.06 205.64,5.92 208.51,5.92 209.37,5.06 230.68,5.06 234.22,8.6 246.17,8.6 248.94,5.83 260.91,5.83 262.07,4.68 285.32,4.68 292.45,11.82 v3(292.45,11.9) 292.86,12.31 293.64,12.31 297.13,15.8 297.13,17.59 297.55,18.01 297.55,19.52 299.3,21.26 299.3,46.91 298.8,47.4 298.8,47.95 297.85,48.9 297.85,49.42 294.1,53.17 294.1,53.25 290.98,56.37 290.98,69.46 290.55,69.89 290.23,69.89 290.21,69.88 v3(290.18,69.88) ; v4(105.98,22.66) 105.98,22.75 106.46,23.23 106.46,25.49 v4(106.36,25.6)
  IN4 w0.203: v1(133.26,21.87) 133.09,21.7 132.87,21.7 v4(132.86,21.7)
  IN4 w0.254: v1(110.02,21.68) 110.02,21.74 109.89,21.86 108.77,21.86 108.45,22.19 108.04,22.19 v1(107.02,23.21) 106.44,23.21 105.98,22.75 v4(105.98,22.66) ; v1(12.53,49.81) 12.58,49.76 12.58,49.14 12.71,49.02 v3(12.71,48.37) ; v1(103.52,29.68) 103.5,29.67 98.92,29.67 95.82,32.77 95.02,32.77 94.83,32.96 94.83,34.51 92.26,37.08 88.91,37.08 v4(88.5,37.48) ; v1(122.26,23.21) 122.7,23.21 122.76,23.27 v4(122.85,23.27) ; v4(106.36,25.6) 106.36,25.98 106.64,26.26 v1(107.02,26.26)
  BOTTOM w0.203: JAUD1.33 11.29,50.9 11.43,50.76 11.65,50.76 11.86,50.55 11.86,50.11 12.05,49.91 12.43,49.91 v1(12.53,49.81)
  BOTTOM w0.254: CH93.1 293.03,13.24 292.45,12.67 v3(292.45,11.9) ; CH93.1 292.96,13.25 RTCR1.1 290.45,13.25 RTCD1.1 ; CH93.1 293.05,13.34 CLRP3.1 ; RH79.1 CH32.1 CH34.1 CH33.1 v1(110.02,21.68) ; R208.1 292.42,87.42 293.62,88.63 v3(293.62,90.35) 293.8,90.53 294.21,90.53 294.43,90.3 RP13.1 ; v1(103.52,29.68) 103.57,29.63 103.57,28.36 103.87,28.06 105.34,28.06 105.65,27.75 RH23.1 106.67,26.26 v1(107.02,26.26)
+RTCVCC_R: length 4.5
  BOTTOM w0.076: 293.36,85.08 293.36,84.38 U38.B2
  BOTTOM w0.102: v2(294.38,86.5) C149.1
  BOTTOM w0.254: R208.2 C149.1 293.41,85.12 293.36,85.08
+SDC_IN:
  vias: v6(258.09,19.03)
+SIM_PWR: length 59.2
  IN1 w0.508: v3(92.7,3.41) 92.71,3.41 92.95,3.65 92.95,4.75 v3(92.84,4.85)
  IN3 w0.508: v3(92.7,3.41) 92.7,3.39 91.59,2.28 87.09,2.28 85.25,4.12 85.25,5.96 82.08,9.14 77.91,9.14 76.36,7.59 68.72,7.59 68.26,8.04 62.91,8.04 62.46,7.59 61,7.59 60.31,6.9 56.97,6.9 55.68,6.88 55.06,6.88 53.75,6.88 53.74,6.87 53.18,6.87 52.72,7.33 52.72,8.03 53.33,8.63 53.33,9.5 53,9.83 53,14.08 v3(53.24,14.32)
  BOTTOM w0.203: JIO1.69 v3(92.7,3.41)
  BOTTOM w0.305: v3(53.24,14.32) 53.28,14.36 53.28,16.34 53,16.62 53,17.25 53,17.26 JNGFF2.28
+VCHGR: length 1.1
  TOP w0.102: v3(264.83,44.98) v6(265.95,44.98)
+VR_CAP: length 4.9
  BOTTOM w0.102: v2(297.7,80.59) 297.32,80.97 295.73,80.97 295.25,80.48 C160.1
  BOTTOM w0.254: C160.1 294.48,81.13 U38.H1
+VREFCA: length 201.1
  IN1 w0.254: v4(98.91,57.02) 98.91,57.02 99.4,57.51 101.01,57.51 v4(101.54,56.98)
  IN3 w0.254: v4(101.54,56.98) 101.54,56.98 100.42,58.11 ; 174.64,57.75 174.64,57.78 173.29,59.12 173.26,59.12
  IN3 w0.33: v3(188.45,56.3) 187.87,56.89 187.87,57.12 186.35,58.64 179.05,58.64 177.44,57.03 v4(175.36,57.03) 173.26,59.12 162.7,59.12 v4(160.61,57.04) 159.32,58.34 153.69,58.34 153.25,58.78 146.73,58.78 145.07,57.12 v4(144.69,57.12) 144.54,57.27 144.54,58.03 143.93,58.64 141.23,58.64 138.94,56.35 v4(133.64,56.35) 133.59,56.3 128.75,56.3 127.03,58.02 122.34,58.02 121.84,57.52 118.5,57.52 v4(118.02,57.04) 117.51,56.53 113.52,56.53 111.34,58.72 108.88,58.72 108.72,58.56 103.13,58.56 v4(101.54,56.98) 100.42,58.11 93.71,58.11 93.47,57.86 91.25,57.86 89.98,56.6 88.54,56.6 v3(88.17,56.23)
  IN4 w0.254: v1(118.65,57.04) v4(118.02,57.04) ; v1(174.79,57.04) 174.8,57.03 v4(175.36,57.03) ; v4(160.61,57.04) v1(160.06,57.04) ; v4(144.69,57.12) 144.77,57.04 v1(145.68,57.04) ; v1(98.33,57.02) v4(98.91,57.02) ; v1(133.64,57.02) v4(133.64,56.35)
  BOTTOM w0.102: v1(174.79,57.04) 175.22,57.04 v6(175.96,57.78)
  BOTTOM w0.254: 159.43,51.68 160.15,51.68 UD4.M8 ; UD6.M8 118.18,50.87 117.65,50.87 117.65,50.87 117.13,50.87 ; UD3.M8 147.49,50.87 146.93,50.87 ; 129.75,50.92 130.84,50.92 UD5.M8 ; UD1.M8 176.83,50.87 176.3,50.87 176.29,50.87 176.1,50.87 ; UD8.M8 101.5,51.68 100.63,51.68 ; 188.39,50.92 189.48,50.92 UD2.M8 ; UD7.M8 88.85,50.87 87.76,50.87 ; 99.53,54.57 99.53,54.14
  BOTTOM w0.305: 99.87,51.95 100.14,51.68 100.63,51.68
  BOTTOM w0.33: 159.43,51.68 158.79,51.68 158.2,52.27 158.2,55.18 v1(160.06,57.04) ; 99.87,51.95 99.53,52.29 99.53,54.14 99.55,54.16 99.55,54.55 99.53,54.57 99.53,55.11 98.33,56.3 v1(98.33,57.02) ; CD2.1 v3(188.45,56.3) 187.57,55.43 187.57,53.14 187.47,53.03 187.47,51.84 188.39,50.92 ; v1(133.64,57.02) 132.92,56.3 129.81,56.3 128.97,55.46 128.97,54.02 128.87,53.92 128.87,52.83 128.82,52.78 128.82,51.85 129.75,50.92 ; v1(118.65,57.04) 117.74,56.13 117.1,56.13 116.14,55.17 116.14,51.85 117.13,50.87 ; RD18.2 85.23,57.04 RD17.2 87.06,57.04 RD19.1 CD55.1 v3(88.17,56.23) 88.17,56.17 86.86,54.85 86.86,51.78 87.76,50.87 ; 176.1,50.87 175.55,50.87 174.79,51.63 v1(174.79,57.04) ; CD19.1 v1(145.68,57.04) 145.32,56.69 145.32,53.13 145.63,52.83 145.63,51.15 145.9,50.87 146.93,50.87
+VREFDQ_A: length 95.2
  IN3 w0.33: 173.33,57.05 173.29,57.05 171.65,58.69 163.03,58.69 160.92,56.58 157.1,56.58 155.93,57.75 153.93,57.75 v4(153.72,57.54) 152.99,58.26 147.23,58.26 145.57,56.6 144.45,56.6 144,57.04 144,57.73 143.77,57.96 142.86,57.96 141.95,57.04 v4(140.73,57.04) ; 173.33,57.05 173.72,57.05 174.22,56.55 177.65,56.55 179.27,58.17 182.75,58.17 v4(182.92,58.01) ; 173.33,57.05 v4(173.33,57.04)
  IN4 w0.33: v4(153.72,57.54) 153.22,57.04 v1(153.2,57.04) ; v1(182.92,57.04) v4(182.92,58.01) ; v1(172.76,57.04) 173.01,57.04 173.02,57.05 173.33,57.05 v4(173.33,57.04) ; v4(140.73,57.04) v1(141.62,57.04)
  BOTTOM w0.33: RD23.2 v1(141.62,57.04) RD25.1 CD21.2 ; v2(138.95,55.94) 138.95,56.41 CD21.2 ; v1(153.2,57.04) 153.2,49.83 UD4.H1 ; UD2.H1 182.64,49.73 182.64,55.06 182.92,55.34 v1(182.92,57.04) ; CD21.2 139.58,56.69 141.18,55.08 141.18,48.79 141.87,48.1 UD3.H1 ; UD1.H1 170.64,49.12 170.64,54.26 171.96,55.59 172.5,56.13 172.76,56.38 v1(172.76,57.04)
+VREFDQ_B: length 99.5
  IN3 w0.33: v4(128.99,57.04) 128.63,57.04 127.21,58.46 122.03,58.46 121.53,57.96 116.43,57.96 115.49,57.02 v4(115.18,57.02) 113.72,57.02 111.61,59.13 93.97,59.13 93.18,58.34 v3(92.26,58.34) 90.96,58.34 89.72,57.09 88.28,57.09 86.98,55.8 83.14,55.8 v3(82.69,56.25)
  IN4 w0.33: v1(112.04,49.33) 112.04,49.34 111.85,49.53 v1(111.85,50.16) ; v1(128.31,57.04) v4(128.99,57.04) ; v1(114.59,57.02) v4(115.18,57.02)
  BOTTOM w0.33: UD5.H1 123.99,49.73 123.99,55.31 124.8,56.13 125.87,56.13 126.27,56.53 RD24.2 RD26.1 v1(128.31,57.04) ; 95.24,56.99 94.96,56.71 94.96,49.43 UD8.H1 ; 95.24,56.99 CD56.2 ; 95.24,56.99 v2(94.4,56.99) 94.13,56.99 92.78,58.34 v3(92.26,58.34) ; v1(111.85,50.16) 111.85,54.46 113.11,55.73 114.27,55.73 114.59,56.05 v1(114.59,57.02) CD39.2 ; UD6.H1 112.04,49.07 v1(112.04,49.33) ; UD7.H1 82.55,49.23 82.55,56.11 v3(82.69,56.25) 82.13,56.81 CD57.2
+VS_LPSS_SDIO: length 8.2
  BOTTOM w0.254: UCPU1.A32 126.77,14.27 126.52,14.02 126.52,12.98 125.01,11.47 CH64.1 RH142.1 RH112.1 RH140.1
A_ON: length 359
  IN1 w0.076: v4(238.86,18.46) 238.9,18.42 239.2,18.42 240.07,19.28 240.78,19.28 241.56,20.07 248.89,20.07 250.18,18.78 252.72,18.78 266.16,5.35 282.9,5.35 284.44,6.89 284.44,9.85 289.47,14.88 v4(289.47,14.93) ; v3(73.19,37.77) 73.18,37.77 72.45,37.04 72.45,34.18 71.07,32.79 71.07,18.84 71.66,18.24 74.3,18.24 75.88,16.67 81.14,16.67 v4(81.54,16.26)
  IN2 w0.076: v4(81.54,16.26) 82.94,16.26 83.04,16.16 92.3,16.16 92.6,16.45 95.68,16.45 97.1,15.03 98.07,15.03 99.4,13.7 101.48,13.7 102.4,12.78 103.78,12.78 103.89,12.67 110.03,12.67 110.75,11.94 112.85,11.94 113.61,11.18 114.48,11.18 115.06,10.59 119.85,10.59 121.31,9.12 122.49,9.12 123.63,7.99 124.58,7.99 125.33,7.23 132.03,7.23 133.63,8.83 134.49,8.83 135.24,9.58 143.76,9.58 145.02,8.32 153.9,8.32 153.92,8.3 157.56,8.3 157.63,8.37 157.89,8.37 158.13,8.13 162.73,8.13 163.37,7.5 169.98,7.5 171.55,5.92 181.99,5.92 183.68,7.62 184.77,7.62 185.31,8.16 185.31,8.71 185.54,8.95 192.57,8.95 192.66,9.03 198.04,9.03 198.24,8.83 204.69,8.83 205.8,7.71 209.78,7.71 210.13,7.36 214.35,7.36 214.9,6.81 236.9,6.81 v4(237.12,6.6)
  IN4 w0.076: v1(236.56,18.89) 237.08,18.37 237.08,17.66 237.27,17.47 237.27,6.75 v4(237.12,6.6) ; v1(237.45,19.83) 237.45,19.27 238.21,18.51 238.67,18.51 238.72,18.46 v4(238.86,18.46) ; v1(290.11,79.63) 290.14,79.6 290.14,79.44 290.35,79.23 290.35,78.53 290.26,78.44 290.26,76.86 289.35,75.95 289.35,74.55 289.23,74.43 289.23,73.02 289.04,72.83 289.04,71.26 288.49,70.72 288.49,58.47 289.61,57.36 289.61,55.47 290.42,54.65 290.42,52.12 290.42,50.86 290.42,50.2 291.68,48.94 293.22,48.94 293.3,49.02 295.46,49.02 295.63,48.85 295.63,48.54 295.35,48.27 295.35,46.51 295.58,46.28 295.58,45.41 296.09,44.9 296.09,43.79 296.77,43.1 296.77,22.34 296.53,22.09 296.53,16.97 295.4,15.84 295.19,15.84 295.16,15.81 295.16,15.8 294.51,15.16 292.92,15.16 292.42,15.65 292.14,15.65 291.39,14.91 289.49,14.91 v4(289.47,14.93)
  BOTTOM w0.076: v3(73.19,37.77) 73.19,37.77 73.57,38.15 73.57,39.51 73.17,39.91 R368.1 73.16,39.92 R342.1 ; v1(237.45,19.83) 237.45,19.78 v1(236.56,18.89) 236.41,18.89 235.46,17.94 v6(235.46,17.25)
A_ON_R: length 6.5
  BOTTOM w0.076: v2(235.56,15.51) 235.88,15.83 235.88,17.9 236.41,18.43 237.02,18.43 R152.2
  BOTTOM w0.203: R152.2 238.16,18.89 238.79,19.52 U24.3
AC_DIS: length 121
  IN4 w0.076: v1(244.27,25.06) 244.27,25.25 241.59,27.93 241.59,30.37 242.68,31.46 243.15,31.46 243.38,31.69 243.38,34.05 243.96,34.64 243.96,37.3 244.6,37.94 244.6,39.67 244.84,39.91 244.84,41.8 244.45,42.19 244.45,47.1 245.22,47.87 280.54,47.87 280.88,48.21 280.88,63.14 279.89,64.13 279.89,79.49 282.24,81.84 282.24,86.07 285.19,89.02 287.32,89.02 287.64,89.34 288.58,89.34 290.29,87.63 290.29,86.73 290.15,86.59 290.15,85.03 290.37,84.81 290.37,84.53 290.77,84.13 v1(291.11,84.13)
  BOTTOM w0.254: PQ701.5 247.9,24.17 PR774.2 247,24.2 PQ721.3 245.18,25.31 244.75,24.88 v2(244.65,24.88) 244.45,24.88 v1(244.27,25.06)
AC_PRESENT: length 291
  TOP w0.076: v5(167.17,16.39) 167.09,16.31 166.48,16.31 163.35,13.17 155.69,13.17 154.09,11.58 138.66,11.58 135.15,15.09 v2(134.72,15.09) 132.43,15.09 132.29,15.23 126.2,15.23 124.77,16.67 124.77,19.89 121.32,23.33 121.3,23.33 121.12,23.51 115.3,23.51 115.22,23.44 113.77,23.44 110.95,26.26 107.35,26.26 v3(106.69,26.92)
  IN1 w0.076: v4(167.5,16.48) 167.35,16.48 167.26,16.39 v5(167.17,16.39)
  IN3 w0.076: v4(167.5,16.48) 167.5,13.02 174.67,5.85 182.23,5.85 182.61,6.22 187.77,6.22 187.96,6.04 195.1,6.04 195.37,6.31 197.39,6.31 197.59,6.11 200.01,6.11 201.02,7.12 208.93,7.12 209.52,6.53 209.52,6.53 209.75,6.3 213.88,6.3 214.07,6.11 216.91,6.11 217.32,6.53 227.3,6.53 230.46,9.7 246.8,9.7 249.75,6.75 261.29,6.75 261.51,6.53 267.32,6.53 268.14,5.71 284.83,5.71 288.36,9.24 288.36,10.65 288.72,11 290.69,11 292.37,12.69 293.68,12.69 296.82,15.83 296.82,17.62 297.31,18.11 297.31,19.62 299.05,21.36 299.05,46.81 297.14,48.72 295.57,48.72 295.55,48.71 295.31,48.71 v4(295.31,48.71)
  IN4 w0.076: v1(290.11,78.63) 290.11,76.93 289.2,76.02 289.2,74.62 289.08,74.49 289.08,73.08 288.88,72.89 288.88,71.33 288.34,70.78 288.34,58.41 289.45,57.29 289.45,55.4 290.27,54.59 290.27,52.06 290.27,50.92 290.27,50.13 291.62,48.79 295.23,48.79 v4(295.31,48.71)
  BOTTOM w0.076: RH70.1 RH80.2 107.12,28.24 106.69,27.81 v3(106.69,26.92)
AC_PRESENT_R: length 40.2
  IN2 w0.076: v4(133.92,21.27) 133.93,21.29 133.93,23.05 133.86,23.12 133.86,24.05 133.81,24.1 133.81,24.68 132.71,25.77 131.68,25.77 131.62,25.7 131.38,25.7 131.2,25.52 131.2,25.29 130.92,25.01 130.31,25.01 130.03,25.29 130.03,26.47 130.05,26.48 130.05,26.55 128.24,28.35 116.7,28.35 115.31,26.97 115.31,26.15 115.1,25.94 114.61,25.94 114.34,25.94 113.76,26.51 113.76,27.15 113.58,27.34 113.22,27.34 113,27.12 113,26.17 112.72,25.89 110.14,25.89 v4(108.8,27.23)
  IN4 w0.076: v4(133.92,21.27) 133.53,20.88 132.54,20.88 132.26,20.6 131.56,20.6 131.48,20.53 131.28,20.53 131.04,20.77 v1(130.38,20.77) ; v1(108.24,27.32) 108.65,27.32 108.74,27.23 v4(108.8,27.23)
ACAV_IN: length 133.7
  TOP w0.102: v6(243.98,28.72) 243.72,28.47 v3(243.09,28.47)
  IN3 w0.254: v3(243.09,28.47) 243.9,29.28 243.9,46.5 245.05,47.65 277.52,47.65 278.48,48.61 278.48,90.12 278.85,90.49 279.74,90.49 v4(280.35,89.88)
  IN4 w0.076: v4(280.35,89.88) 280.76,90.29 284.41,90.29 285.1,90.97 285.28,90.97 285.9,91.6 288.04,91.6 288.73,90.9 288.73,90.8 291.41,88.12 291.41,87.88 292.39,86.89 293.32,86.89 294.12,86.1 294.12,85.27 293.77,84.93 293.77,83.79 v1(293.61,83.63)
  BOTTOM w0.254: PR56.1 240.02,21.2 241.12,22.3 241.12,24.29 240.14,25.26 240.14,26.5 239.9,26.74 239.33,26.74 238.91,27.16 238.91,28.79 239.42,29.3 240.32,29.3 240.65,28.97 241.17,28.97 241.68,28.47 v3(243.09,28.47) 243.77,27.78 PR711.1
ALS_INT#: length 11.7
  IN4 w0.076: v1(204.43,43.25) 204.43,43.25 203.59,43.25 199.11,38.76 v1(199.11,37.53)
  BOTTOM w0.076: v1(199.11,37.53) 199.11,37.06 R52.2 197.22,35.86 v2(196.92,36.15)
ALS_INT#_HUB: length 142.2
  IN3 w0.076: v3(285.93,94.12) 285.57,94.48 284.94,94.48 284.21,93.76 284.21,92.87 283.74,92.4 279.11,92.4 278.24,91.53 278.24,48.71 277.42,47.89 240.13,47.89 229.04,36.8 201.87,36.8 199.06,33.99 198.24,33.99 v3(197.9,34.33)
  BOTTOM w0.076: v3(285.93,94.12) 285.93,94.1 286.33,93.69 286.33,92.53 JSNR1.14 ; v2(197.79,33.65) 197.9,33.76 v3(197.9,34.33) R52.1
ALS_SMBCLK: length 15.9
  IN4 w0.076: v1(199.11,39.88) 198.4,39.88 197.72,40.56 197.72,41.72 198.26,42.26 200.29,42.26 202.42,44.39 204.29,44.39 v1(204.43,44.25)
  BOTTOM w0.076: v1(199.11,39.88) 199.11,39.02 199.96,38.17 v2(199.96,36.16) 199.65,35.86 R54.2
ALS_SMBDATA: length 14.7
  IN4 w0.076: v1(197.21,39.88) 197.57,40.24 197.57,41.79 198.19,42.41 200.23,42.41 202.36,44.54 204.22,44.54 v1(204.43,44.75)
  BOTTOM w0.076: v2(195.62,41.22) R55.2 196.02,40.18 196.23,39.97 196.23,39.08 196.43,38.88 196.91,38.88 197.21,39.17 v1(197.21,39.88)
ALW_PWRGD: length 75.9
  TOP w0.254: v3(300.54,84.22) 299.11,82.78 288.28,82.78 284,78.5 284,48.84 285.3,47.53 285.3,46.68 286.47,45.51 286.47,42.89 v3(280.25,36.67)
  IN1 w0.254: v3(282.99,30.98) 282.99,31.02 283.5,31.53 283.5,35.15 281.98,36.67 v3(280.25,36.67)
  BOTTOM w0.076: v3(280.25,36.67) v2(280.25,37.33)
  BOTTOM w0.203: v3(282.99,30.98) 282.95,30.98 282.48,30.5 PU300.7
  BOTTOM w0.254: v3(300.54,84.22) 300.52,84.19 R213.2 ; v3(280.25,36.67) PR311.2
ALWON: length 107.1
  TOP w0.076: v5(298.23,82.14) 297.47,81.37 288.43,81.37 284.26,77.21 284.26,48.91 285.54,47.63 285.54,46.94 285.55,46.94 285.55,46.78 286.8,45.52 286.8,42.03 284.52,39.74 284.52,34.41 v3(284.16,34.05)
  IN1 w0.076: v4(298.23,82.86) v5(298.23,82.14)
  IN4 w0.076: v4(298.23,82.86) 298.26,82.86 298.73,83.33 298.73,85.54 298.49,85.77 298.49,87.91 297.89,88.51 295.35,88.51 v1(294.93,88.93) 294.59,89.27 294.59,90.34 292.49,92.44 290.52,92.44 289.81,93.15 285.69,93.15 284.07,91.53 281.75,91.53 v1(281.49,91.28)
  IN4 w0.254: v3(284.16,34.05) 279.97,34.05 278.81,32.9 276.38,32.9 v3(276.21,33.06)
  BOTTOM w0.076: v1(281.49,91.28) 281.04,90.82 281.04,88.71 281.67,88.08 D22.2 283.88,88.08 v2(284.07,87.88) 284.07,87.47 283.67,87.06 R356.2
  BOTTOM w0.254: PR331.2 276.18,33.04 v3(276.21,33.06) ; PC312.1 284.31,32.53 PR330.1 284.31,33.9 v3(284.16,34.05)
APWROK: length 26.8
  IN2 w0.076: v4(117,21.13) 117.03,21.09 120.34,21.09 123.12,18.32 124.41,18.32 124.7,18.03 125.9,18.03 125.94,17.99 126.9,17.99 127.12,18.22 128.49,18.22 128.64,18.06 131.77,18.06 131.8,18.03 132.34,18.03 132.73,18.41 v4(133.49,18.41)
  IN4 w0.076: v1(117.54,21.2) 117.51,21.18 117.05,21.18 v4(117,21.13) ; v4(133.49,18.41) 133.11,18.03 132.05,18.03 131.66,18.41 130.78,18.41 130.73,18.36 130.53,18.36 130.48,18.41 130.28,18.41 130.23,18.36 130.03,18.36 129.79,18.6 v1(129.63,18.6)
  BOTTOM w0.076: v1(117.54,21.2) 117.57,21.24 117.6,21.24 117.92,21.56 RH65.2 118.5,21.56 RH179.2 118.79,21.22 119.16,20.85 120.68,20.85 v2(120.84,21.01)
AUDIO_IRQ: length 186.7
  TOP w0.076: v5(112.9,16.23) 114.82,14.31 114.82,12.84 115.35,12.31 116.15,12.31 116.37,12.53 121.59,12.53 124.57,9.55 v5(128.83,9.55)
  IN1 w0.076: v4(13.09,52.07) 13.56,51.6 20.55,51.6 27.49,44.66 50.16,44.66 50.35,44.47 v3(50.35,44.39) ; v4(129.92,9.53) 129.9,9.55 v5(128.83,9.55) ; v4(112.55,16.32) 112.63,16.23 v5(112.9,16.23)
  IN2 w0.076: v4(13.09,52.07) 12.95,51.93 5.21,51.93 3.71,53.43 v3(3.71,53.44)
  IN4 w0.076: v1(128.22,7.57) 128.39,7.74 129.98,7.74 132.45,10.21 132.45,11.27 133.15,11.97 133.15,12.41 132.32,13.24 v1(132.32,13.53) ; v4(112.55,16.32) 112.29,16.06 v1(112.21,16.06) 112.09,16.06 111.24,15.21 106.72,15.21 106.56,15.05 105.69,15.05 105.48,15.26 105,15.26 104.64,14.9 103.2,14.9 99.01,14.9 97.84,16.08 88.98,16.08 88.77,16.29 83.14,16.29 82.51,16.92 54.19,16.92 53.11,18 52.99,18 52.99,17.99 50.27,17.99 49.96,18.3 49.96,20.73 50.3,21.07 50.3,33.52 v1(50.54,33.76) ; v4(129.92,9.53) 129.68,9.29 v1(129.06,9.29)
  BOTTOM w0.076: v3(3.71,53.44) 3.71,56.02 v2(4.08,56.4) 4.98,57.3 JAUD1.2 ; v3(50.35,44.39) 50.54,44.2 v1(50.54,33.76) ; v1(129.06,9.29) 128.09,9.29 127.94,9.13 127.94,7.85 v1(128.22,7.57) ; v1(132.32,13.53) 131.99,13.53 131.87,13.41 131.87,13.3 131.74,13.17 131.03,13.17 130.98,13.22 130.79,13.22 130.64,13.07 130.64,12.88 130.45,12.7 130.3,12.7 130.22,12.78 130.04,12.78 129.94,12.68 129.17,12.68 UCPU1.F35
AUDIO_PWREN: length 150.5
  IN1 w0.127: v4(9.55,39.48) 9.55,39.4 10.75,38.19 13.35,38.19 14.18,37.36 18.04,37.36 19.98,39.29 34.83,39.29 36.67,41.14 37.77,41.14 38.14,41.51 39.12,41.51 v3(40.76,39.86)
  IN2 w0.127: v3(40.76,39.86) 41.02,40.11 83.21,40.11 84.87,38.45 85.96,38.45 95.91,28.5 95.91,28 98.19,25.71 98.19,20.87 99.93,19.13 100.85,19.13 102.05,17.92 102.71,17.92 103.9,16.73 104.14,16.73 104.53,16.35 107.54,16.35 107.8,16.6 108.63,16.6 108.95,16.92 116.48,16.92 117.65,15.75 121.64,15.75 122.46,14.94 122.49,14.94 122.68,14.76 124.6,14.76 126.24,13.11 126.59,12.77 126.87,12.77 126.88,12.76 128.27,12.76 128.78,13.26 130.89,13.26 131.22,12.94 v4(131.23,12.94)
  IN4 w0.076: v1(9.59,38.45) 9.59,38.46 9.55,38.5 v4(9.55,39.48) v1(9.55,40.89)
  IN4 w0.127: v1(131.13,12.44) 131.13,12.76 131.23,12.87 v4(131.23,12.94)
  BOTTOM w0.076: U30.3 9.59,40.84 v1(9.55,40.89) ; U33.3 10.23,37.29 v2(10.16,37.22) 9.35,37.22 R194.2 R195.2 v1(9.59,38.45) 9.6,38.45 9.96,38.09 U33.5
AUX_EN_WOWL: length 361.4
  IN2 w0.076: v3(33.87,38.22) 36.87,35.22 51.94,35.22 67.44,19.72 67.44,19.69 69.55,17.58 78.81,17.58 79.08,17.58 81.93,14.74 86.08,14.74 86.55,15.21 92.48,15.21 93.03,15.75 95.45,15.75 96.78,14.42 97.79,14.42 99.12,13.09 101.2,13.09 102.12,12.17 103.52,12.17 103.63,12.06 109.75,12.06 111.96,9.84 119.73,9.84 121.06,8.51 122.24,8.51 123.38,7.38 124.32,7.38 125.08,6.62 132.28,6.62 133.89,8.22 134.75,8.22 135.44,8.92 139.98,8.92 140.56,8.34 142.64,8.34 143.42,7.56 153.55,7.56 154.23,6.89 155.59,6.89 155.61,6.86 168.27,6.86 169.92,5.21 184.14,5.21 185.96,7.04 190.72,7.04 191.06,7.38 197.14,7.38 197.88,8.13 204.52,8.13 205.94,6.71 214.08,6.71 214.77,6.02 217.04,6.02 217.17,6.16 236.25,6.16 236.8,5.61 243.56,5.61 243.9,5.95 259.46,5.95 261.05,4.36 288.67,4.36 296.43,12.12 296.43,14.14 297.05,14.76 297.05,17.64 297.86,18.44 297.86,20.04 298.65,20.84 298.65,48.08 293.7,53.04 293.7,53.28 293.13,53.85 293.13,55.01 286.12,62.02 286.12,76.17 v4(285.74,76.55)
  IN4 w0.076: v1(287.61,79.63) 287.49,79.63 287.02,79.15 286.83,79.15 286.58,78.91 286.58,78.28 285.72,77.42 285.72,76.56 v4(285.74,76.55)
  BOTTOM w0.076: D13.3 33.17,37.52 v3(33.87,38.22)
B+: length 190.1
  TOP w1.016: 81.18,20.96 81.18,21.11
  TOP w2.032: 81.18,21.11 81.18,22.41 82.54,23.77 82.54,27.7 84.95,30.12 88.05,30.12 89.42,28.75 93.33,28.75 99.63,35.04 171.75,35.04 173.1,33.7 191.15,33.7 196.33,28.52 196.33,24.54
  IN2 w0.254: v4(297.22,45.61) 297.22,45.61 296.82,46 293.53,46 293.23,46.31 v4(293.22,46.31)
  IN4 w0.254: v1(293.06,46.61) 293.06,46.47 293.22,46.32 v4(293.22,46.31) ; v1(297.64,45.61) v4(297.22,45.61)
  IN4 w0.508: v1(289.72,45.42) 288.98,45.42 288.86,45.53 288.59,45.53 288.31,45.81 279.65,45.81 279.51,45.67 v4(278.84,45.67) v1(278.21,45.67) 277.7,46.18 270.02,46.18 268.43,44.58 v1(268.43,41.5)
  BOTTOM w0.254: PR72.1 299.57,31.98 300.62,31.98 300.95,32.3 300.95,37.6 300.44,38.11 297.46,38.11 296.96,38.6 296.96,45.41 297.17,45.61 v1(297.64,45.61) ; v3(259.93,38.85) 258.98,37.9 PR770.1 ; v1(293.06,46.61) 293.04,46.61 292.76,46.33 291.32,46.33 PL400.1
  vias: v1(81.82,19.55) v1(82.12,19.82) v3(81.23,20.29) v3(81.16,19.7) v3(81.19,19.11) v3(196.01,22.73) v3(196.01,22.12) v3(196.01,21.51) v3(196.62,22.73) v3(196.62,22.12) v3(196.62,21.51) v3(197.23,22.73) v3(197.23,22.12) v3(197.23,21.51) v3(197.91,22.73) v3(197.91,22.12) v3(198.6,22.73) v3(198.6,22.12) v3(199.21,22.73) v3(199.21,22.12) v3(199.79,22.69) v3(199.82,22.11) v3(225.69,20.64) v3(225.69,20.03) v3(238.9,15.49) v3(239.53,15.49) v3(240.17,15.49) v3(259.92,40.16) v3(259.92,39.5) v3(260.55,40.16) v3(260.55,39.5) v3(260.56,38.85) v3(261.19,40.16) v3(261.19,39.5) v3(261.2,38.85) v3(261.82,40.16) v3(261.82,39.5) v3(261.83,38.85) v3(262.47,40.14) v3(262.47,39.5) v3(262.48,38.83) v3(263.1,40.14) v3(263.1,39.5) v3(263.12,38.83) v3(263.74,40.14) v3(263.74,39.5) v3(263.75,38.83) v3(264.37,40.14) v3(264.37,39.5) v3(264.39,38.83) v3(265.02,40.11) v3(265.02,39.47) v3(265.03,38.8) v3(265.64,38.64) v3(265.66,39.29) v3(266.29,39.29) v3(266.28,38.64) v3(266.93,39.29) v3(266.91,38.64) v3(267.55,38.64) v3(267.56,39.29) v3(278.52,20.11) v3(278.57,20.77) v3(278.65,18.05) v3(278.67,18.83) v3(279.09,19.95) v3(279.3,18.42) v3(279.69,19.96) v3(280.3,20.67) v3(280.28,20.03) v3(280.8,19.23) v3(280.8,18.62) v3(280.8,18.01) v3(281.47,19.16) v3(281.47,18.55) v3(281.47,17.94) v4(81.71,19.88) v4(81.9,20.31) v5(81.98,19.63) v5(82.05,20.01) v6(263.88,35.4)
B+_1.05V: length 1.3
  BOTTOM w0.076: PL500.2 v2(80.12,18.48)
BASE_DC_IN_SS: length 240.3
  TOP w0.508: v3(107.83,20.18) 107.93,20.08 110.2,20.08 111.82,18.46 113.89,18.46 116.67,21.24 119.9,21.24 122.03,19.11 122.03,15.81 125.43,12.41 134.6,12.41 137.92,9.1 163.56,9.1 166.99,12.53 167,12.53 168.48,14 168.48,15.27 168.68,15.47 168.68,15.52 169.5,16.34 169.5,16.54 v5(169.8,16.83) ; v5(179.27,15.42) 179.25,15.45 179.25,15.87 178.88,16.24 v5(178.88,18.48)
  IN1 w0.508: v4(225.25,16.76) 225.25,16.71 225.27,16.73 225.27,16.84 223.92,18.19 v4(223.92,19.8) ; v5(169.8,16.83) 169.8,16.89 172.48,19.58 175.49,19.58 176.58,18.48 v5(178.88,18.48) ; v5(179.27,15.42) 179.31,15.46 180.43,15.46 v4(180.55,15.33)
  IN3 w0.508: v3(107.83,20.18) 107.78,20.18 106.56,18.97 105.33,18.97 104.05,17.68 104.05,17.17 104.62,16.6 104.77,16.6 106.27,15.11 106.27,12.46 106.93,11.8 106.93,10.04 105.01,8.12 v3(105.01,7.14) ; 225.25,16.73 225.27,16.71 227.59,19.03 230.58,19.03 230.9,19.35 236.14,19.35 237.31,20.51 238.72,20.51 238.92,20.31 248.95,20.31 250.22,19.04 252.49,19.04 254.29,17.24 262.11,17.24 263.33,16.02 271.04,16.02 272.91,17.89 v3(272.91,18.99) ; 225.25,16.73 225.25,16.43 222.33,13.51 215,13.51 214.08,14.43 203.53,14.43 201.65,16.31 198.7,16.31 196.57,14.18 188.82,14.18 188.4,14.6 187.44,14.6 186.7,15.33 v4(180.55,15.33) ; 225.25,16.73 v4(225.25,16.76)
  IN4 w0.203: v3(105.01,7.14) 105.01,6.85 105.21,6.65 v1(106.85,6.65)
  IN4 w0.508: v1(224.86,33.8) 223.09,33.8 222.76,33.47 222.76,23.85 222.25,23.35 222.25,21.48 v4(223.92,19.8) ; v1(276.73,19.12) 276.73,15.54 v1(276.98,15.28)
  BOTTOM w0.102: v2(271.99,20.97) 271.99,19.81 272.78,19.02 272.78,18.99 v3(272.91,18.99) 272.91,19.07 272.71,19.07
  BOTTOM w0.203: JIO1.2 106.3,6.51 106.4,6.61 106.8,6.61 v1(106.85,6.65)
  BOTTOM w0.508: PR95.2 v3(272.91,18.99)
BASE_DET: length 18.7
  BOTTOM w0.076: 301.36,73.48 v2(301.36,70.92) 301.36,69.76 R354.2 300.81,69.21 292.19,69.21 291.57,69.83 291.57,70.17 291.41,70.33 Q44.2 Q44.5 ; 301.36,73.48 301.34,73.47 Q45.3 ; 301.36,73.48 301.36,73.97 301.21,74.12 Q45.2
BASE_DET#: length 358
  TOP w0.076: v3(240.7,25.75) v2(240.7,25.1) ; v3(105.84,7.24) 105.85,7.26 105.85,7.33 106.49,7.97 108.87,7.97 110.08,6.76 119.51,6.76 123.44,2.83 135.46,2.83 136.05,2.24 167.61,2.24 176.17,10.79 176.81,11.44 177.44,11.44 177.65,11.64 177.65,11.65 178.05,12.06 v5(178.05,12.11)
  IN1 w0.076: v4(288.35,71.53) 288.41,71.47 288.76,71.47 290.17,72.88 292.86,72.88 294.16,74.17 298.48,74.17 v4(298.97,73.68) ; v4(290.2,15.5) 290.09,15.38 290.09,14.67 285.75,10.33 285.75,7.55 282.96,4.76 266.1,4.76 252.53,18.33 249.44,18.33 249.31,18.45 247.11,18.45 246.82,18.17 245.89,18.17 243.12,15.4 v4(241.71,15.4) 240.57,14.26 238.43,14.26 237.63,13.47 205.69,13.47 203.3,15.85 198.56,15.85 195.53,12.82 187.77,12.82 187.46,13.12 179.08,13.12 178.06,12.11 v5(178.05,12.11)
  IN3 w0.076: v3(270.04,20.99) 272.41,20.99 276.45,16.95 283.92,16.95 284.74,17.77 288.19,17.77 289.33,18.91 289.98,19.56 v3(289.98,20.16) ; v4(107.02,13.3) 107.15,13.3 108.49,11.96 108.49,9.45 106.89,7.85 106.32,7.85 105.84,7.37 v3(105.84,7.24)
  IN4 w0.076: v1(104.37,13.3) v4(107.02,13.3) ; v4(241.71,15.4) 241.71,20.89 240.18,22.42 240.18,25.23 v3(240.7,25.75) ; v1(290.36,15.91) 290.2,15.75 v4(290.2,15.5) 290.32,15.5 290.4,15.58 291.22,15.58 291.55,15.91 292.38,15.91 292.98,15.31 294.45,15.31 295.01,15.87 295.01,15.87 295.29,16.15 295.49,16.15 296.37,17.03 296.37,22.15 296.62,22.4 296.62,43.04 295.93,43.73 295.93,44.84 295.43,45.35 295.43,46.22 295.2,46.45 295.2,48.27 294.83,48.63 291.55,48.63 290.1,50.08 290.1,54.54 288.03,56.61 288.03,71.21 v4(288.35,71.53) 288.56,71.73 288.56,72.99 288.71,73.14 288.71,74.4 288.33,74.78 288.33,76.42 288.71,76.8 288.71,76.98 v1(288.78,77.06) 288.94,77.21 288.94,77.81 289.15,78.02 289.15,78.39 289.16,78.4 289.16,78.46 289.23,78.53 289.23,78.9 289.26,78.93 289.26,78.94 289.35,79.03 289.35,79.79 289.11,80.03 v1(289.11,80.13) ; v1(298.82,74.12) 298.82,74.12 298.97,73.97 v4(298.97,73.68)
  BOTTOM w0.076: v1(290.36,15.91) 290.36,19.78 v3(289.98,20.16) ; JIO1.8 105.1,6.59 105.53,7.03 105.62,7.03 v3(105.84,7.24)
  BOTTOM w0.254: v3(240.7,25.75) 240.7,27.05 241.39,27.74 PR13.2 241.39,28.29 241.03,28.64 240.51,28.64 240.24,28.92 239.71,28.92 239.56,28.77 PD1.1 ; PR93.2 268.06,20.73 268.31,20.99 v3(270.04,20.99)
BASE_HEAD_CHG_ON: length 108.2
  IN1 w0.076: v4(280.36,77.65) 280.68,77.97 283.37,77.97 283.79,77.55 286.42,77.55 286.71,77.26 289,77.26 v4(289.32,77.57) ; v4(240.83,23.51) v4(244.26,23.51)
  IN4 w0.076: v1(289.38,77.91) 289.35,77.88 289.35,77.61 v4(289.32,77.57) ; v1(240.59,23.88) 240.59,23.75 v4(240.83,23.51) ; v4(244.26,23.51) 244.54,23.79 244.54,25.21 241.74,28.01 241.74,30.31 242.75,31.31 243.25,31.31 243.53,31.59 243.53,33.99 244.12,34.57 244.12,37.24 244.75,37.88 244.75,39.6 244.99,39.84 244.99,41.86 244.6,42.26 244.6,47.03 245.27,47.71 280.67,47.71 281.09,48.13 281.09,63.3 280.07,64.32 280.07,77.36 v4(280.36,77.65)
  BOTTOM w0.076: U38.N10 289.11,78.19 289.38,77.92 v1(289.38,77.91)
BASE_SMB_ALERT#: length 301.5
  TOP w0.076: v3(102.73,7.13) 102.73,7.84 103.69,8.81 108.95,8.81 110.42,7.34 119.75,7.34 123.68,3.41 135.7,3.41 136.29,2.82 166.44,2.82 168.31,4.69 169.16,4.69 176.48,12.02 177.01,12.02 178.47,13.49 178.47,13.5 179.12,14.14 179.58,14.14 v5(179.68,14.04)
  IN1 w0.076: v5(179.68,14.04) 179.72,14 189.08,14 189.6,14.53 190.9,14.53 191.93,13.49 195.43,13.49 198.33,16.4 203.64,16.4 205.98,14.06 226.59,14.06 227.2,14.67 228.26,14.67 228.36,14.78 236.88,14.78 239.17,17.06 239.91,17.06 241.24,18.39 244.65,18.39 245.46,19.21 249.28,19.21 250.01,18.48 252.6,18.48 266.03,5.04 283.02,5.04 284.78,6.8 284.78,9.58 289.94,14.74 289.94,15.28 289.84,15.38 289.84,15.97 296.45,22.59 296.45,45.24 296.14,45.56 v4(296.14,45.56) ; v4(298.96,73.09) 298.96,72.88 299.41,72.42 299.41,70.71 298.94,70.24 289.63,70.24 289.42,70.02 283.27,70.02 v4(282.94,69.69)
  IN3 w0.076: v4(296.14,45.56) 295.59,45.56 293.22,47.93 293.22,48.23 292.68,48.77 292.68,50.78 282.67,60.78 282.67,69.42 v4(282.94,69.69)
  IN4 w0.076: v1(299.04,72.44) 299.04,73.01 v4(298.96,73.09)
  BOTTOM w0.076: Q45.6 298.42,74.77 298.26,74.6 298.26,73.56 297.72,73.03 R330.1 298.13,72.94 v2(298.63,72.45) 298.64,72.44 v1(299.04,72.44) 299.1,72.37 R353.2 ; JIO1.20 102.7,7.1 v3(102.73,7.13)
BASE_SMB_ALERT#_Q: length 38.2
  IN4 w0.076: v1(292.48,87.97) 292.76,87.97 293,87.72 294.63,87.72 295.46,86.89 295.46,84.75 295.82,84.4 295.82,83.38 296.53,82.67 296.53,81.86 297.5,80.89 297.5,79.1 298.24,78.35 298.24,75.02 298.09,74.87 298.09,71.65 297.78,71.33 v1(297.78,71.18) ; v1(292.63,72.67) 292.68,72.63 v1(292.68,71.38)
  BOTTOM w0.076: U38.B5 291.61,84.14 291.86,84.39 291.86,87.63 292.2,87.97 v1(292.48,87.97) ; Q45.1 300.26,74.77 300.11,74.62 300.11,73.26 300.48,72.89 R353.1 300.48,71.67 300.07,71.26 298.99,71.26 298.91,71.18 v1(297.78,71.18) 295.08,71.18 294.82,70.91 v2(293.25,70.91) 293.16,70.91 292.69,71.38 v1(292.68,71.38)
BASE_SMBCLK: length 291.4
  TOP w0.076: v3(101.75,5.33) 101.75,5.81 102.23,6.29 104.37,6.29 104.71,5.95 119.31,5.95 123.63,1.63 167.89,1.63 175.18,8.92 v5(177.14,8.92)
  IN1 w0.076: v3(300.02,68) 300.02,67.99 300.25,67.76 300.25,65.01 299.69,64.46 299.69,59.05 297.25,56.61 297.25,54.67 297.05,54.47 297.05,48.94 297.69,48.3 297.69,45.62 296.96,44.9 296.96,22.84 291.29,17.16 291.29,15.92 290.9,15.54 290.9,15.23 285.94,10.27 285.94,7.49 283.06,4.61 266.04,4.61 252.47,18.17 249.37,18.17 249.25,18.3 247.26,18.3 246.14,17.18 245.3,17.18 241.78,13.66 238.14,13.66 237.75,13.27 205.29,13.27 202.94,15.61 198.61,15.61 195.66,12.66 187.71,12.66 187.4,12.97 179.31,12.97 177.33,10.99 177.33,10.98 176.92,10.57 176.92,9.14 v5(177.14,8.92)
  BOTTOM w0.076: v3(300.02,68) 300,67.97 298.55,67.97 298.25,68.28 v2(294.66,68.28) 294.01,68.28 292.64,66.9 290.43,66.9 290.18,67.15 R331.1 289.55,69.05 288.86,69.05 288.68,69.24 288.68,70.83 288.83,70.98 Q44.6 289.76,70.98 290.14,71.37 291.32,71.37 291.64,71.05 R351.2 ; JIO1.22 102.3,5.88 v3(101.75,5.33)
BASE_SMBCLK_Q: length 36.6
  IN4 w0.076: v1(297.97,70.43) 298.31,70.77 298.31,71.98 298.4,72.07 298.4,78.41 297.66,79.15 297.66,82.15 297.03,82.78 296.7,82.78 295.97,83.51 295.97,87.13 295.22,87.88 293.06,87.88 292.69,88.24 292.3,88.24 291.63,88.91 v1(291.63,88.93)
  BOTTOM w0.076: v1(291.63,88.93) 291.63,88.63 290.68,87.67 290.68,86.4 289.61,85.34 U38.A9 ; v1(297.97,70.43) 297.3,69.77 v2(294.78,69.77) 294.56,69.77 294.16,69.36 292.34,69.36 292.05,69.65 R351.1 292.05,70.17 291.24,70.98 Q44.1
BASE_SMBDAT: length 284.8
  TOP w0.076: v3(101.2,5.48) 102.17,6.44 104.43,6.44 104.77,6.1 119.38,6.1 123.7,1.78 167.83,1.78 175.12,9.07 176.93,9.07 177.15,9.29 v5(177.16,9.29)
  IN1 w0.076: v5(177.16,9.29) 177.15,9.29 177.07,9.36 177.07,10.51 177.48,10.91 177.48,10.93 179.37,12.82 187.34,12.82 187.64,12.51 195.73,12.51 198.68,15.46 202.88,15.46 205.22,13.12 237.81,13.12 238.2,13.51 241.85,13.51 245.37,17.03 246.21,17.03 247.32,18.15 249.18,18.15 249.31,18.02 252.41,18.02 265.97,4.46 283.12,4.46 286.09,7.42 286.09,10.2 291.06,15.17 291.06,15.47 291.44,15.85 291.44,17.1 297.11,22.78 297.11,44.84 297.84,45.56 297.84,48.37 297.2,49 297.2,54.41 297.41,54.61 297.41,56.54 299.84,58.98 299.84,64.39 300.4,64.95 300.4,68.27 v3(300.01,68.66)
  BOTTOM w0.076: v3(300.01,68.66) 299.96,68.66 299.42,68.13 298.61,68.13 298.13,68.61 293.96,68.61 292.8,67.44 v2(292.5,67.44) R352.2 291.17,67.86 R332.1 291.06,68.53 291.06,69.67 Q44.3 ; v3(101.2,5.48) 101.46,5.73 101.74,5.73 101.9,5.9 JIO1.24
BASE_SMBDAT_Q: length 25.6
  IN3 w0.076: v4(290.03,70.96) 290.07,71 290.07,80.02 289.58,80.5 289.33,80.5 289.04,80.79 289.04,81.44 289.35,81.75 289.35,81.98 289.56,82.19 289.56,82.2 v4(289.57,82.21)
  IN4 w0.076: v4(289.57,82.21) 289.59,82.21 289.97,82.59 v1(289.98,82.59) ; v1(289.84,69.16) 289.84,70.77 v4(290.03,70.96)
  BOTTOM w0.076: Q44.4 289.4,69.68 289.54,69.55 289.54,69.34 289.72,69.16 v1(289.84,69.16) 290.35,69.16 290.67,68.84 290.67,67.45 R352.1 ; v1(289.98,82.59) 290,82.62 290,82.97 290.11,83.08 U38.D8 289.86,83.38 289.43,83.38 289.36,83.45 289.36,85.3 290.52,86.46 290.52,87.85 291.13,88.46 RP15.4
BATDRV#: length 13.4
  IN4 w0.508: v1(258.05,44.66) 257.74,44.66 254.82,41.74 252.27,41.74 249.59,39.06 v1(249.59,37.89)
  BOTTOM w0.102: v1(258.05,44.66) 258.54,44.66 v2(259.23,43.97)
BATT++: length 3.3
  TOP w0.076: v3(242.91,46.45) v6(243.52,46.45) ; v3(240.83,43.95) 240.83,43.96 241.36,43.42 v6(241.36,42.64) ; v3(241.01,45.23) v6(239.88,45.23)
  vias: v3(236.31,51.22) v3(236.33,50.64) v3(236.33,50.06) v3(237.07,51.22) v3(237.09,50.64) v3(237.09,50.06) v3(237.81,51.3) v3(237.81,50.61) v3(237.81,50) v3(238.57,51.3) v3(238.57,50.61) v3(238.57,50) v3(239.25,51.3) v3(239.25,50.61) v3(239.25,50) v3(240.84,44.63) v3(241.01,46.45) v3(241.01,45.84) v3(241.31,44.28) v3(241.62,46.45) v3(241.62,45.84) v3(241.62,45.23) v3(242.3,46.45) v3(242.3,45.84) v3(242.3,45.23) v3(242.91,45.84) v3(242.91,45.23)
BATT_PRS#: length 29.5
  IN4 w0.254: v1(240.21,52) 240.05,52.16 234.1,52.16 232.93,51 232.93,47.15 v1(233.41,46.67) 233.41,46.04 240.12,39.34 v1(241.34,39.34)
  BOTTOM w0.102: v2(241.78,36.78) 242.15,37.15 PC6.1
  BOTTOM w0.254: JBAT1.5 v1(233.41,46.67) ; v1(241.34,39.34) 241.83,39.34 242.08,39.08 242.08,39.02 PC6.1 242.66,38.45 243.6,38.45 244.1,38.96 PR5.1
BATT_SEL_BASE_HEAD#: length 172.8
  TOP w0.076: v3(106.58,7.19) 107.12,7.74 108.86,7.74 109.99,6.61 119.45,6.61 123.38,2.68 135.4,2.68 135.99,2.09 167.67,2.09 176.32,10.73 176.87,11.28 177.79,11.28 178.32,11.82 178.64,12.13 v5(179.44,12.13)
  IN1 w0.076: v4(238.49,13.15) 238.24,12.9 205,12.9 202.63,15.27 198.73,15.27 195.82,12.36 187.58,12.36 187.45,12.49 179.79,12.49 v5(179.44,12.13)
  IN4 w0.254: v1(237.55,33.53) 237.95,33.14 237.95,30.2 239.33,28.82 239.33,17.42 238.08,16.16 238.08,13.56 v4(238.49,13.15)
  BOTTOM w0.076: JIO1.6 105.5,6.69 105.64,6.82 105.79,6.82 105.8,6.83 106.13,6.83 106.49,7.19 v3(106.58,7.19)
  BOTTOM w0.254: PR59.1 231.38,33.24 231.38,33.53 231.66,33.81 234.25,33.81 v2(234.67,33.39) 235.09,33.81 236.01,33.81 PR42.1 236.98,33.53 v1(237.55,33.53)
BATT_SEL_CONTROL: length 22.9
  IN4 w0.254: v1(237.25,26.07) 237.25,30.66 236.8,31.11 230.31,31.11 229.88,31.54 v1(229.88,32.66)
  BOTTOM w0.254: v1(237.25,26.07) 237.25,25.02 v2(236.87,24.64) 236.87,24.22 238.26,22.83 PQ6.1 238.6,23.33 239.14,23.87 PR30.1 ; v1(229.88,32.66) 229.16,33.38 PQ32.1
BATT_VREF: length 10.3
  BOTTOM w0.076: PR912.1 269.83,16.93 v2(269.58,17.19)
  BOTTOM w0.254: 265.47,14.75 265.47,14.29 265.91,13.85 PC907.2 ; 265.47,14.75 264.11,14.75 PU900.6 ; 265.47,14.75 266.12,15.41 PU900.2 269.76,15.41 PR908.2 PR912.1
BEEP: length 402.7
  IN1 w0.076: v4(34.39,45.8) 28.94,45.8 19.41,55.33 17.4,55.33 16.83,54.75 16.82,54.75 v4(16.69,54.62)
  IN2 w0.076: v4(34.39,45.8) 33.91,45.32 33.91,42.05 39.59,36.37 51.52,36.37 67.97,19.92 68.65,19.92 70.53,18.04 78.62,18.04 78.63,18.04 79.27,18.04 82.12,15.19 85.86,15.19 86.68,16.01 92.37,16.01 92.66,16.3 95.61,16.3 97.04,14.88 97.98,14.88 99.31,13.54 101.41,13.54 102.33,12.62 103.71,12.62 103.82,12.51 109.94,12.51 112.15,10.3 119.92,10.3 121.25,8.97 122.43,8.97 123.57,7.83 124.51,7.83 125.27,7.08 132.1,7.08 133.7,8.68 134.56,8.68 135.31,9.43 142.2,9.43 143.46,8.17 153.83,8.17 153.87,8.13 156.96,8.13 157.44,7.65 158,7.65 158.31,7.96 162.69,7.96 163.3,7.34 169.91,7.34 171.51,5.74 182.47,5.74 184.16,7.43 185.02,7.43 186.38,8.79 192.63,8.79 192.72,8.88 197.98,8.88 198.18,8.67 204.62,8.67 205.74,7.56 209.72,7.56 210.1,7.18 214.26,7.18 214.79,6.65 236.49,6.65 237.07,6.06 243.37,6.06 243.77,6.47 259.59,6.47 261.04,5.01 266.66,5.01 266.86,4.82 288.4,4.82 295.97,12.39 295.97,13.4 295.97,13.52 295.97,13.53 295.97,14.33 296.59,14.95 296.59,17.83 297.39,18.63 297.39,20.26 298.2,21.06 298.2,47.9 293.38,52.71 292.82,52.71 288.96,56.57 v3(288.96,57.05) ; v4(16.69,54.62) 16.38,54.31 14.35,54.31 13.81,53.76 11.32,53.76 11.06,53.51 5.16,53.51 v3(4.89,53.24)
  IN4 w0.076: v3(288.96,57.05) 288.19,57.83 288.19,70.84 288.73,71.39 288.73,72.95 288.91,73.13 288.91,74.66 289.05,74.8 289.05,76.08 289.96,76.99 289.96,78.44 289.87,78.53 289.87,78.73 290.01,78.87 290.01,79.03 v1(290.11,79.13)
  BOTTOM w0.076: v3(4.89,53.24) 4.9,53.23 5.09,53.23 5.45,52.87 v2(5.45,52.77) 5.45,50.62 5.97,50.1 JAUD1.38
BIA_PWM_EC: length 120.1
  IN2 w0.076: v4(287.18,15.97) 287.18,12.77 286.73,12.31 284.26,12.31 v4(284.22,12.27)
  IN4 w0.076: v4(287.18,15.97) 287.69,16.48 290.21,16.48 290.83,15.85 291.28,15.85 291.49,16.06 292.44,16.06 293.04,15.46 294.38,15.46 296.22,17.3 296.22,22.22 296.47,22.47 296.47,42.97 295.78,43.66 295.78,44.78 295.28,45.28 295.28,46.16 295.04,46.39 295.04,48.2 294.77,48.48 291.49,48.48 289.95,50.02 289.95,54.4 286.8,57.55 286.8,71.87 286.56,72.11 286.56,72.87 286.85,73.16 286.85,74.86 287.69,75.7 287.69,76.17 288.49,76.97 288.49,77.25 288.79,77.54 288.79,77.87 289,78.08 289,78.46 289.01,78.46 289.01,78.53 289.06,78.58 289.06,78.94 289.08,78.95 289.08,78.96 289.11,79 v1(289.11,79.13) ; v4(284.22,12.27) 284.22,11.28 281.52,8.58 273.4,8.58 269.45,12.53 268.9,12.53 268.67,12.3 264.3,12.3 261.44,15.16 259.15,15.16 v1(259.1,15.11)
  BOTTOM w0.076: D4.2 v1(259.1,15.11) 259.1,12.84 v2(258.57,12.31)
BOARD_ID: length 6.5
  BOTTOM w0.076: U38.G1 C150.1 295.92,81.2 297.09,81.2 R207.2 298.05,82.16 298.98,82.16 v2(299.39,81.75)
BOOT:
  vias: v2(186.35,21.54)
BOOT_1.35V: length 1.4
  BOTTOM w0.076: PR600.2 v2(214.17,26.32)
BQ24777_REGN: length 28.6
  IN3 w0.254: v3(253.63,36.11) 253.22,35.7 253.22,26.83 252.35,25.95 243.02,25.95 v3(242.23,26.75)
  BOTTOM w0.102: v3(253.63,36.11) v2(254.34,36.11)
  BOTTOM w0.203: PU700.24 251.96,33.51 PC705.1
  BOTTOM w0.254: PC705.1 253.63,35.18 v3(253.63,36.11) 253.63,36.52 PR721.1 253.27,36.97 PR740.2 ; v3(242.23,26.75) 242.24,26.74 PR710.1
BST_1.35V: length 1.3
  BOTTOM w0.076: PC604.1 v2(215.68,22.31)
BST_3V:
  vias: v2(283.13,29.67)
BST_5V: length 2.8
  BOTTOM w0.076: PR308.1 276.29,28.38 275.21,28.38 274.8,27.97 v2(274.8,27.73)
BT_OFF#_R: length 17.2
  IN1 w0.076: v4(18.41,33.86) 18.36,33.81 18.36,33.27 16.9,31.8 16.9,29.67 16.5,29.27 JNGFF1.46
  IN4 w0.076: v1(11.53,34.64) 11.91,34.26 13.63,34.26 13.88,34.51 18.63,34.51 18.71,34.43 v1(18.71,34.18) 18.41,33.89 v4(18.41,33.86)
  BOTTOM w0.076: v2(11.12,33.57) 11.53,33.98 v1(11.53,34.64)
BT_ON/OFF#: length 142.1
  IN1 w0.076: v4(87.77,10.65) 87.77,10.69 87.98,10.9 93.94,10.9 95.06,12.02 98.36,12.02 98.87,11.51 101.13,11.51 102.29,12.67 108.8,12.67 109.84,13.71 110.89,14.76 114.18,14.76 114.56,14.37 116.66,14.37 116.94,14.09 123.55,14.09 124.05,13.58 124.33,13.58 124.87,14.12 126.54,14.12 127.02,14.61 129.31,14.61 v4(129.7,14.22)
  IN2 w0.076: v3(14.73,33.49) 14.74,33.49 15.45,32.78 15.45,30.63 15.88,30.21 21.21,30.21 21.31,30.31 35.69,30.31 37.47,28.53 41.38,28.53 42.81,27.1 42.81,26.52 45.87,23.46 45.87,11.47 47.51,9.83 57.67,9.83 59.5,11.66 68.01,11.66 69.16,10.51 77.28,10.51 78.01,11.24 85.27,11.24 85.87,10.65 v4(87.77,10.65)
  IN4 w0.076: v1(130.13,13.41) 130.12,13.42 130.12,13.94 129.98,14.08 129.94,14.08 129.8,14.21 129.7,14.21 v4(129.7,14.22)
  BOTTOM w0.076: D19.3 14.24,33.99 v3(14.73,33.49) 14.02,32.79 v2(14.02,32.76)
BT_RADIO_DIS#: length 384.3
  IN2 w0.076: v4(287.11,77.84) 287.11,73.88 287.56,73.42 287.56,70.88 288.8,69.65 288.8,60.2 293.74,55.26 293.74,54.17 294.33,53.57 294.33,53.27 299.43,48.17 299.43,12.68 296.36,9.61 296.36,9.22 293.71,6.57 292.69,6.57 289.27,3.14 260.5,3.14 259.17,4.47 245.1,4.47 244.14,3.51 206.13,3.51 205.87,3.26 202.3,3.26 201.57,3.98 199.52,3.98 198.14,2.61 151.41,2.61 151.13,2.88 149.06,2.88 148.37,3.57 137.88,3.57 136.66,4.79 135.7,4.79 135.15,4.25 133.95,4.25 133.65,3.95 132.99,3.95 132.9,3.86 130.61,3.86 130.14,3.4 127.98,3.4 127.65,3.72 122.85,3.72 119.16,7.41 109.94,7.41 108.95,8.4 108.73,8.4 108.53,8.6 107.57,8.6 107.22,8.95 102.42,8.95 101.88,9.49 94.96,9.49 92.7,11.75 86.05,11.75 85.55,12.26 77.63,12.26 77.07,11.7 69.29,11.7 60.46,20.53 60.46,22.22 53.02,29.66 53.02,30.28 51.1,32.2 45.59,32.2 45.29,31.9 28.61,31.9 28.3,32.2 20.56,32.2 19.67,33.09 19.37,33.09 17.51,33.09 17.23,33.37 v3(17.23,33.39)
  IN4 w0.076: v1(288.61,79.63) 288.45,79.63 288.21,79.38 287.93,79.38 287.77,79.23 287.52,79.23 287.26,78.96 287.26,78.62 287.11,78.48 v4(287.11,77.84)
  BOTTOM w0.076: v2(15.35,32.65) 15.83,33.13 16.96,33.13 17.22,33.39 v3(17.23,33.39) 17.13,33.49 16.47,33.49 16.09,33.88 14.67,33.88 13.43,35.11 D19.2
CFG0: length 26.7
  TOP w0.076: v3(178.57,11.3) 178.05,10.77 178.05,7.41 180.21,5.25 183.51,5.25 183.76,5.01 JXDP1.9
  IN4 w0.076: v1(166.74,15.65) 166.83,15.65 170.4,12.09 177.78,12.09 v3(178.57,11.3)
  BOTTOM w0.076: R310.1 v2(167.73,15.59)
CFG1: length 40.8
  TOP w0.076: v3(179.23,11.3) 179.23,10.41 178.2,9.38 178.2,7.63 180.41,5.42 183.73,5.42 184.36,4.79 JXDP1.11
  IN4 w0.076: v3(179.23,11.3) 179.02,11.51 178.84,11.51 178.71,11.64 178.51,11.64 177.91,12.24 170.49,12.24 166.03,16.7 162.29,16.7 162.01,16.43 157.49,16.43 157.32,16.26 156.22,16.26 155.97,16.51 155.77,16.51 155.6,16.35 155.45,16.35 v1(155.37,16.27)
  BOTTOM w0.076: v3(179.23,11.3) 178.27,10.33 v2(178.27,9.81)
CFG2: length 41.5
  TOP w0.076: JXDP1.15 185.56,4.83 184.82,5.57 181.05,5.57 178.98,7.64 178.98,9.5 179.77,10.29 v3(179.77,11.3)
  IN4 w0.076: v3(179.77,11.3) 179.77,11.46 179.57,11.66 179.04,11.66 178.91,11.79 178.57,11.79 177.97,12.39 170.55,12.39 166.09,16.86 162.22,16.86 161.94,16.58 157.39,16.58 157.22,16.41 156.28,16.41 156.03,16.67 155.7,16.67 155.54,16.5 155.48,16.5 155.47,16.51 155.11,16.51 v1(154.87,16.27)
  BOTTOM w0.076: v2(179.39,10.51) 179.77,10.89 v3(179.77,11.3)
CFG3: length 54.8
  TOP w0.076: v5(186.45,5.39) 186.57,5.26 186.57,5 186.16,4.58 JXDP1.17
  IN1 w0.076: v4(187.07,5.9) 187.06,5.9 186.94,5.9 186.45,5.41 v5(186.45,5.39)
  IN4 w0.076: v1(196.57,7.41) 195.55,6.39 193.66,6.39 193.15,5.89 189.33,5.89 188.9,6.31 187.56,6.31 187.15,5.9 v4(187.07,5.9) 186.61,5.9 v1(186.5,6.01) ; v1(158.52,17.14) 158.77,16.88 161.82,16.88 162.1,17.16 166.22,17.16 170.68,12.7 178.26,12.7 178.86,12.1 179.04,12.1 179.16,11.97 180.76,11.97 180.79,11.97 181.14,11.61 182.64,11.61 182.88,11.37 v1(182.88,11.17) ; v1(158.31,15.82) 158.29,15.8 155.76,15.8 155.73,15.84 v1(155.62,15.84)
  BOTTOM w0.076: v1(158.31,15.82) 158.52,16.03 v1(158.52,17.14) ; v1(182.88,11.17) 183.27,10.78 183.27,7.05 184.2,6.11 186.21,6.11 186.31,6.01 v1(186.5,6.01) ; R17.2 196.2,6.38 196.2,7.04 196.2,7.2 196.41,7.41 v1(196.57,7.41)
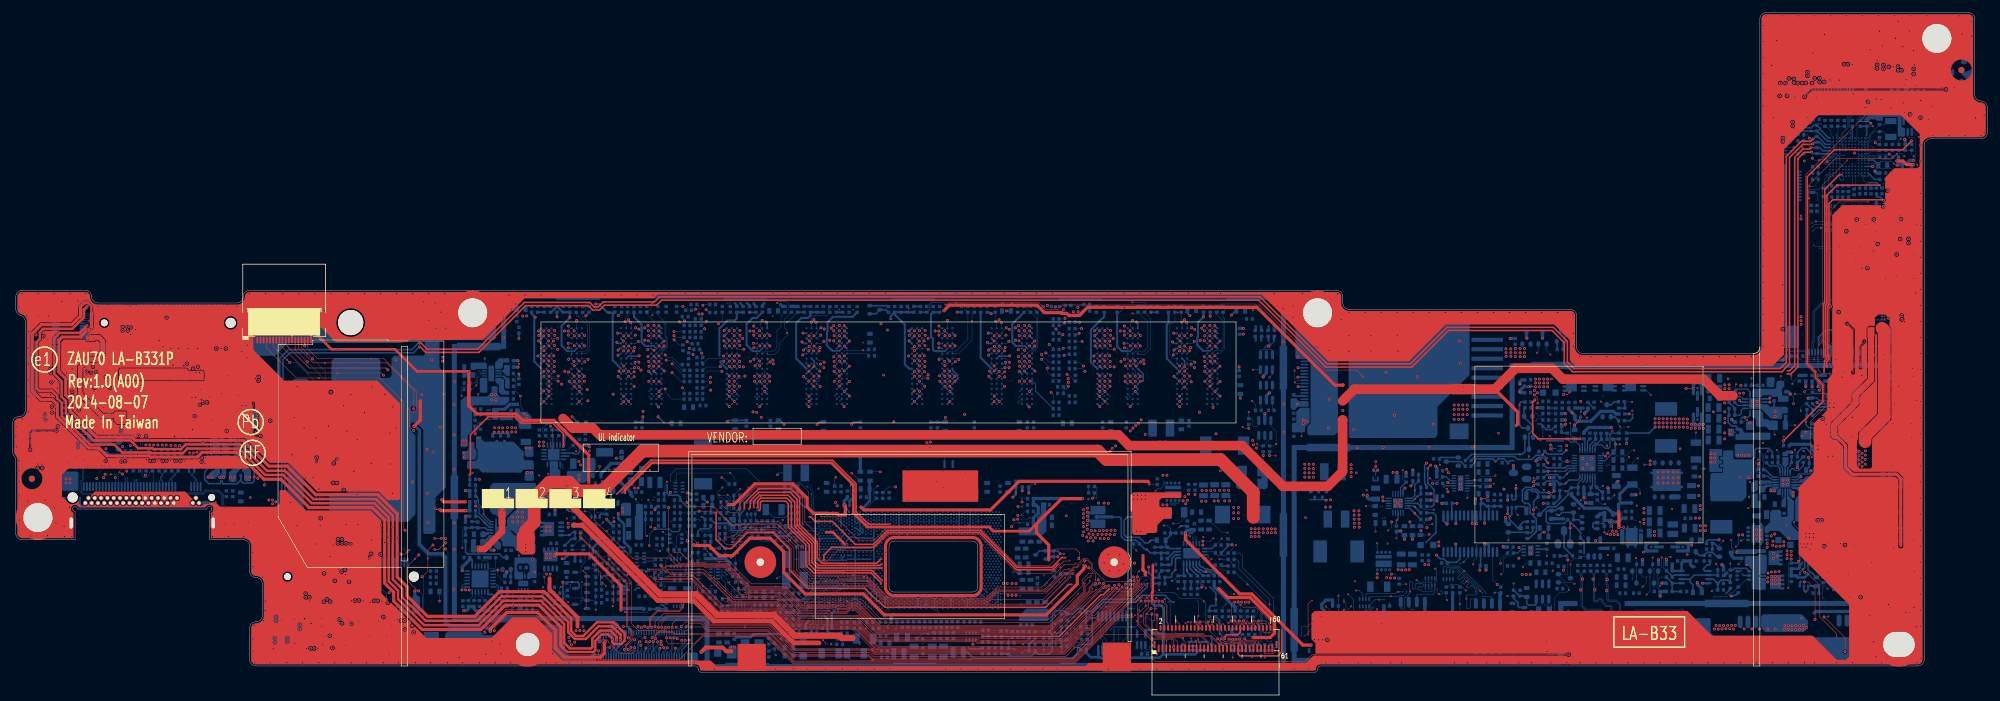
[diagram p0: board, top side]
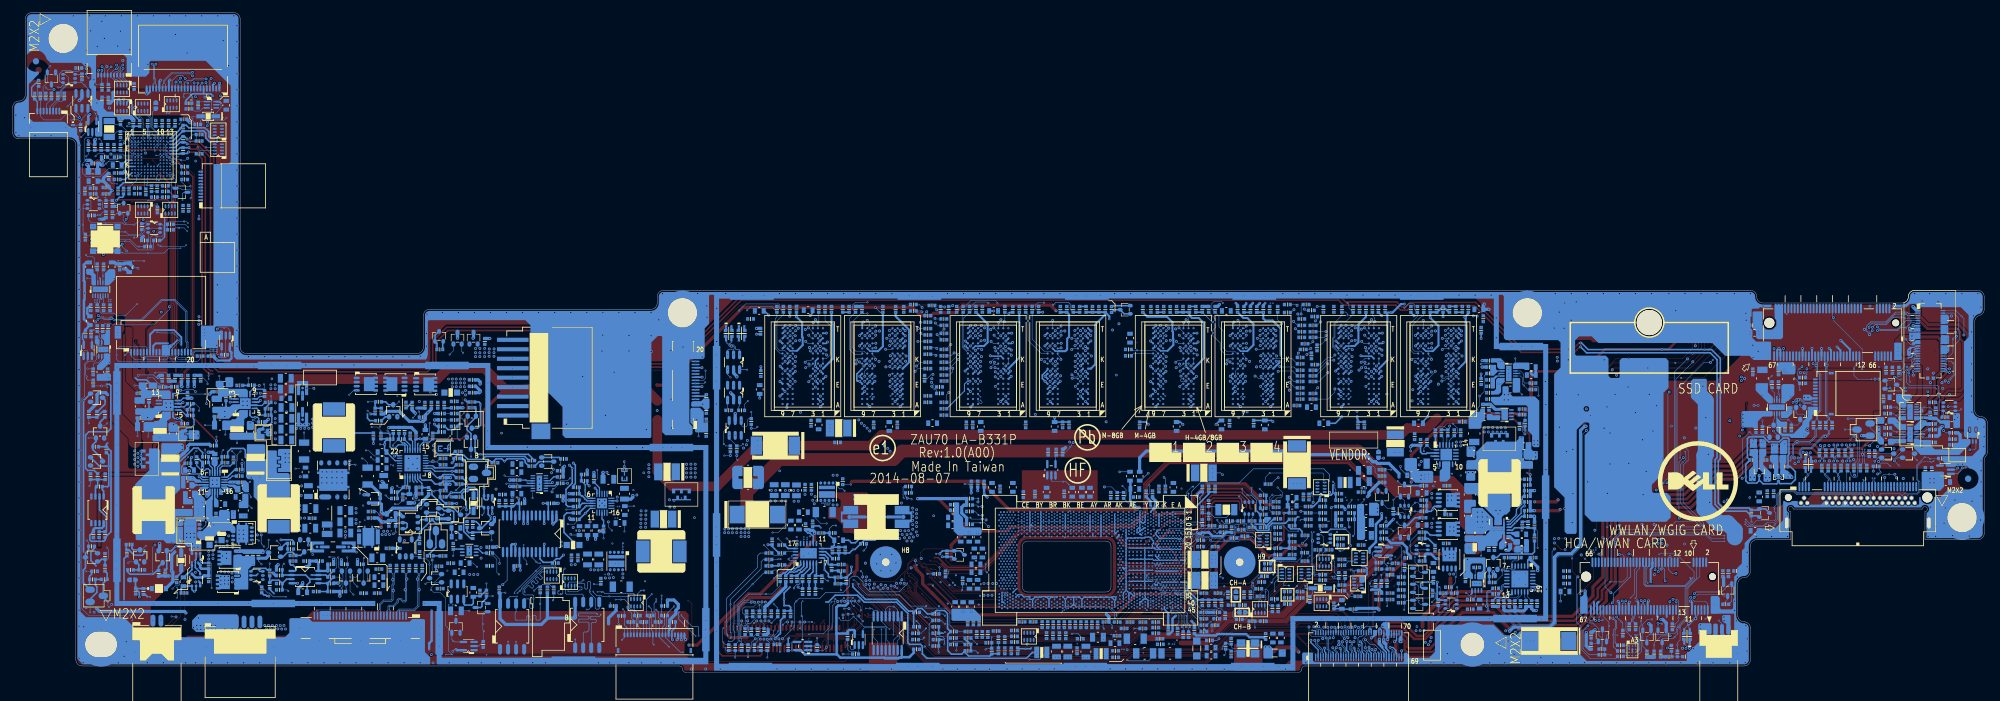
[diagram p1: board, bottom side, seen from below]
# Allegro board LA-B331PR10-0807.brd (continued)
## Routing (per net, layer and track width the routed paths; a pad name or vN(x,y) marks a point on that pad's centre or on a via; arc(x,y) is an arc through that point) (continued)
CFG4: length 43.6
  TOP w0.076: JXDP1.27 189.16,4.57 188.01,5.72 181.21,5.72 179.33,7.6 179.33,9.28 v3(180.15,10.09)
  IN4 w0.076: v1(155.87,15.41) 155.88,15.42 158.57,15.42 158.96,15.82 162.26,15.82 162.54,16.09 164.23,16.09 v1(164.37,15.95) 164.74,15.95 165.65,15.04 166.76,15.04 170.17,11.63 177.18,11.63 178.2,10.62 179.71,10.62 180.15,10.18 v3(180.15,10.09)
  BOTTOM w0.076: RC34.1 164.84,15.13 164.37,15.59 v1(164.37,15.95) ; v3(180.15,10.09) v2(180.92,10.09)
CFG5: length 43.1
  TOP w0.076: JXDP1.29 189.76,4.28 188.16,5.87 181.37,5.87 180.2,7.04 180.2,9.11 v3(180.3,9.22)
  IN4 w0.076: v1(155.37,15.41) 155.53,15.41 155.77,15.16 155.97,15.16 156.07,15.27 158.63,15.27 159.03,15.66 162.32,15.66 162.59,15.93 164.05,15.93 164.27,15.71 164.76,15.71 165.59,14.89 166.68,14.89 172.32,9.25 177.06,9.25 177.77,9.96 177.77,10.02 177.91,10.16 179.05,10.16 179.79,9.42 180.1,9.42 v3(180.3,9.22)
  BOTTOM w0.076: v3(180.3,9.22) v2(179.56,9.22)
CFG6: length 48.4
  TOP w0.076: v3(180.85,11.24) 180.69,11.09 180.69,8.31 180.39,8.01 180.39,7.07 181.43,6.02 188.28,6.02 188.64,5.66 189.63,5.66 190.96,4.34 JXDP1.33
  IN4 w0.076: v3(180.85,11.24) 180.71,11.38 180.71,11.64 180.53,11.81 179.1,11.81 178.97,11.94 178.63,11.94 178.03,12.54 170.62,12.54 166.15,17.01 162.16,17.01 161.88,16.73 157.31,16.73 157.15,16.57 156.35,16.57 156.09,16.82 155.64,16.82 155.49,16.67 155.05,16.67 154.91,16.67 154.37,16.12 v1(154.37,15.41)
  BOTTOM w0.076: v2(179.55,11.78) 180.31,11.78 v3(180.85,11.24)
CFG7: length 43.9
  TOP w0.076: v3(181.09,9.07) 181.09,6.58 181.49,6.18 188.36,6.18 188.69,5.85 189.66,5.85 190.99,4.52 191.07,4.52 191.18,4.41 191.44,4.41 191.56,4.29 JXDP1.35
  IN4 w0.076: v3(181.09,9.07) 181.09,9.07 180.59,8.58 177.52,8.58 177,9.1 172.26,9.1 166.62,14.74 165.52,14.74 164.7,15.56 164.21,15.56 163.99,15.78 162.66,15.78 162.39,15.51 159.09,15.51 158.64,15.07 156.12,15.07 156.03,14.97 v1(155.62,14.97)
  BOTTOM w0.076: v3(181.09,9.07) v2(181.09,8.56)
CFG8: length 35.6
  TOP w0.076: JXDP1.10 v5(184.06,7.79)
  IN1 w0.076: v4(184.63,8.54) 184.63,8.36 v5(184.06,7.79) ; v4(154.22,14.97) 154.73,14.97 155.25,14.44 v4(157.77,14.44)
  IN4 w0.076: v4(184.63,8.54) 184.63,8.49 184.47,8.32 182.18,8.32 182.13,8.28 181.95,8.28 181.79,8.11 177.17,8.11 176.64,8.64 171.82,8.64 167.21,13.25 160.74,13.25 159.55,14.44 v4(157.77,14.44) ; v4(154.22,14.97) v1(154.62,14.97)
CFG9: length 33
  TOP w0.076: JXDP1.12 184.66,7.67 v5(184.1,8.22)
  IN1 w0.076: v4(184.11,8.64) 184.1,8.63 v5(184.1,8.22)
  IN4 w0.076: v1(155.87,14.54) 156.37,14.54 156.59,14.76 159.52,14.76 160.88,13.41 167.27,13.41 171.88,8.79 176.71,8.79 177.23,8.27 181.73,8.27 182,8.54 184.01,8.54 v4(184.11,8.64)
CFG10: length 37
  TOP w0.076: JXDP1.16 185.86,7.55 v5(185.6,7.81)
  IN1 w0.076: v4(185.63,8.55) 185.6,8.52 v5(185.6,7.81)
  IN4 w0.076: v4(185.63,8.55) 185.34,8.84 185.34,9.17 184.89,9.62 182.39,9.62 181.18,8.42 177.42,8.42 176.9,8.95 172.18,8.95 166.54,14.58 165.46,14.58 164.64,15.41 164.15,15.41 163.93,15.63 162.72,15.63 162.45,15.36 159.15,15.36 158.71,14.91 156.28,14.91 156.15,14.78 155.77,14.78 155.53,14.54 v1(154.87,14.54)
CFG11: length 36.2
  TOP w0.076: JXDP1.18 v5(186.46,7.99)
  IN1 w0.076: v4(186.17,7.65) 186.46,7.93 v5(186.46,7.99)
  IN4 w0.076: v1(154.62,14.11) 154.78,14.11 155.02,13.87 155.22,13.87 155.27,13.91 155.47,13.91 155.52,13.87 155.72,13.87 155.77,13.91 155.97,13.91 156.11,13.77 156.11,13.77 156.5,13.38 159.84,13.38 160.5,12.72 166.98,12.72 171.52,8.18 176.45,8.18 177.01,7.62 182.13,7.62 182.37,7.87 184.4,7.87 184.49,7.78 184.77,7.5 184.92,7.35 185.87,7.35 v4(186.17,7.65)
CFG12: length 38.5
  TOP w0.076: JXDP1.28 189.46,7.47 189.32,7.61 189,7.61 188.64,7.97 v3(187.9,7.97)
  IN4 w0.076: v1(155.87,13.67) 155.99,13.67 156.44,13.23 159.78,13.23 160.46,12.54 166.95,12.54 171.46,8.03 176.39,8.03 176.95,7.47 182.19,7.47 182.43,7.71 184.34,7.71 184.47,7.59 184.86,7.2 187.13,7.2 v3(187.9,7.97)
  BOTTOM w0.076: v3(187.9,7.97) 187.89,7.96 v2(187.89,6.95)
CFG13: length 38.1
  TOP w0.076: JXDP1.30 190.06,7.43 189.94,7.55 v5(189.76,7.55)
  IN1 w0.076: v4(188.66,7.71) 188.82,7.55 v5(189.76,7.55)
  IN4 w0.076: v4(188.66,7.71) 187.83,6.89 184.69,6.89 184.17,7.41 182.56,7.41 182.32,7.17 176.82,7.17 176.26,7.73 171.28,7.73 166.8,12.2 160.33,12.2 159.61,12.92 156.31,12.92 155.99,13.24 v1(155.62,13.24)
CFG14: length 41.2
  TOP w0.076: v3(189.16,7.95) 189.55,8.35 190.41,8.35 191.26,7.5 JXDP1.34
  IN4 w0.076: v1(155.37,13.67) 155.53,13.67 155.77,13.43 156.02,13.43 156.37,13.07 159.67,13.07 160.36,12.39 166.88,12.39 171.4,7.88 176.32,7.88 176.88,7.32 182.25,7.32 182.5,7.56 184.23,7.56 184.75,7.04 187.68,7.04 188.24,7.6 188.24,7.91 188.48,8.15 188.97,8.15 v3(189.16,7.95)
  BOTTOM w0.076: v3(189.16,7.95) 189.24,7.88 189.24,7.33 v2(189.27,7.31)
CFG15: length 42.4
  TOP w0.076: v5(191.54,7.66) 191.86,7.34 JXDP1.36
  IN1 w0.076: v3(189.87,7.97) 191.23,7.97 v5(191.54,7.66)
  IN4 w0.076: v3(189.87,7.97) 189.87,7.5 189.09,6.72 184.64,6.72 184.11,7.26 182.62,7.26 182.38,7.01 176.69,7.01 176.13,7.57 171.21,7.57 166.74,12.04 160.27,12.04 159.55,12.77 157.75,12.77 157.75,12.77 157.5,12.77 156.25,12.77 156.02,13 155.51,13 155.36,13.15 155.36,13.34 155.03,13.67 v1(154.87,13.67)
  BOTTOM w0.076: v3(189.87,7.97) 190.17,7.97 v2(190.59,7.55)
CFG16: length 34.8
  TOP w0.076: JXDP1.6 182.86,7.72 182.61,7.97 182.61,10.53 v3(181.93,11.22)
  IN4 w0.076: v1(155.12,15.84) 155.28,15.84 155.52,15.6 155.72,15.6 155.77,15.65 158.03,15.65 158.11,15.58 158.51,15.58 158.9,15.97 162.2,15.97 162.48,16.25 164.66,16.25 165.71,15.19 166.83,15.19 170.24,11.78 177.25,11.78 178.26,10.77 180.1,10.77 180.12,10.75 181.45,10.75 v3(181.93,11.22)
  BOTTOM w0.076: v3(181.93,11.22) v2(182.32,11.61)
CFG17: length 34.9
  TOP w0.076: JXDP1.4 182.26,9.94 181.39,10.8 v3(181.39,11.27)
  IN4 w0.076: v3(181.39,11.27) 181.39,11.18 181.11,10.9 180.18,10.9 180.16,10.92 178.32,10.92 177.31,11.94 170.32,11.94 166.88,15.37 165.76,15.37 164.74,16.4 162.41,16.4 162.13,16.12 157.65,16.12 157.48,15.96 155.84,15.96 155.72,16.08 155.52,16.08 155.47,16.03 155.27,16.03 155.22,16.08 155.02,16.08 154.97,16.03 154.81,16.03 154.62,15.84 v1(154.62,15.84)
  BOTTOM w0.076: v3(181.39,11.27) 181.39,11.31 v2(180.96,11.74)
CFG18: length 38.3
  TOP w0.076: JXDP1.24 188.26,7.44 188.07,7.62 187.76,7.62 187.42,7.97 v3(187.16,7.97)
  IN4 w0.076: v3(187.16,7.97) 186.94,8.19 186.05,8.19 185.56,7.7 185,7.7 184.88,7.82 184.7,8 184.66,8.05 184.53,8.17 182.24,8.17 182.2,8.13 182.02,8.13 181.85,7.96 177.11,7.96 176.58,8.49 171.76,8.49 167.14,13.1 160.59,13.1 160.01,13.68 156.63,13.68 156.41,13.9 156.41,13.9 156.09,14.22 156.09,14.22 156.02,14.29 155.77,14.29 155.72,14.35 155.34,14.35 155.12,14.13 v1(155.12,14.11)
  BOTTOM w0.076: v3(187.16,7.97) v2(186,7.97)
CFG19: length 35.7
  TOP w0.076: JXDP1.22 187.66,7.36 187.41,7.61 v5(187.4,7.61)
  IN1 w0.076: v5(187.4,7.61) 186.77,7.61 v4(186.71,7.66)
  IN4 w0.076: v1(155.62,14.11) 155.99,14.11 156.03,14.07 156.03,14.07 156.26,13.84 156.26,13.83 156.56,13.53 159.91,13.53 160.52,12.92 167.07,12.92 171.65,8.34 176.52,8.34 177.04,7.81 181.92,7.81 182.08,7.97 182.26,7.97 182.31,8.02 184.47,8.02 184.59,7.89 184.88,7.61 184.94,7.55 185.62,7.55 186.11,8.04 186.34,8.04 v4(186.71,7.66)
CFG_RCOMP: length 9.5
  IN1 w0.381: v4(161.3,14.06) 160.79,14.57 158.51,14.57 158.1,14.98 155.2,14.98 v4(154.82,15.36)
  IN4 w0.381: v4(161.3,14.06) v1(162.16,14.06) ; v1(155.12,14.97) 155.01,15.08 155.01,15.14 154.82,15.32 v4(154.82,15.36)
  BOTTOM w0.102: v2(162.29,12.98) 162.16,13.11 RC35.1
CHAGER_SRC:
  vias: v2(262.61,25.89)
CHARGER_SCL: length 2.5
  BOTTOM w0.076: PR731.2 245.27,33.44 v12(245.98,33.44) 246.57,33.44 246.64,33.51 PU700.12
CHARGER_SDA: length 2.6
  BOTTOM w0.076: PU700.11 246.8,33.11 246.62,33.29 246.27,33.29 246.26,33.29 245.71,33.29 245.7,33.29 245.27,33.29 PR730.2
CHARGER_SMBCLK: length 104.6
  IN4 w0.076: v1(243.93,33.88) 243.93,33.52 244,33.44 244.37,33.44 244.75,33.82 244.75,37.15 245.18,37.58 245.18,41.9 244.75,42.33 244.75,46.94 245.36,47.55 280.73,47.55 281.24,48.06 281.24,63.37 280.22,64.38 280.22,76.13 280.73,76.63 280.73,80.11 282.51,81.89 282.51,85.27 283,85.77 283,86.35 284.81,88.16 287.34,88.16 v1(287.73,88.55) 288.06,88.88 288.38,88.88 288.86,88.4 288.86,87.53 289.7,86.7 289.7,84.37 289.94,84.13 v1(290.11,84.13)
  BOTTOM w0.076: RP14.2 287.56,88.72 v1(287.73,88.55)
CHARGER_SMBDAT: length 104.6
  IN4 w0.076: v1(290.11,83.63) 289.53,84.21 289.53,86.64 288.71,87.47 288.71,88.32 288.48,88.55 v1(288.15,88.55) 287.82,88.22 287.61,88.22 287.4,88 284.87,88 283.16,86.29 283.16,85.7 282.66,85.21 282.66,81.82 280.88,80.04 280.88,76.57 280.38,76.06 280.38,64.44 281.39,63.43 281.39,48 280.79,47.4 245.43,47.4 244.9,46.88 244.9,42.4 245.34,41.97 245.34,37.52 244.9,37.09 244.9,33.76 244.43,33.29 244,33.29 243.93,33.22 v1(243.93,32.86)
  BOTTOM w0.076: v1(288.15,88.55) 288.06,88.64 RP14.1
CHG_BTS: length 4
  BOTTOM w0.076: v2(256.59,35.15) 256.16,35.15 255.28,34.27 253.77,34.27 253.34,33.84 PR708.1
CHG_BTS_C: length 1.3
  BOTTOM w0.076: PR708.2 255.34,33.62 v2(255.8,34.08)
CHG_LED#: length 22.2
  IN4 w0.076: v1(285.34,91.66) 285.34,91.79 285.97,92.41 288.19,92.41 290.71,89.89 290.71,89.49 291.94,88.27 291.94,88.13 292.5,87.57 294.5,87.57 295.26,86.81 295.26,82.92 294.98,82.64 293.97,82.64 293.71,82.39 293.47,82.39 293.12,82.73 292.79,82.73 292.78,82.72 292.7,82.72 v1(292.61,82.63)
  BOTTOM w0.076: v2(285.43,91.09) 285.43,91.57 v1(285.34,91.66) 284.5,91.66 284.28,91.88 JSNR1.10
CHG_LGATE: length 6.6
  IN1 w1.016: 253.27,35.25 255.79,35.25 257.92,33.11 258.15,33.11
  BOTTOM w0.102: v3(259.14,32.89) v2(258.25,32.89)
  vias: v3(252.05,34.26) v3(252.44,34.71) v3(259.14,33.49)
CHG_ON#: length 83.9
  IN1 w0.076: v4(280.9,75.87) 280.93,75.87 281.87,74.93 286.5,74.93 287.54,75.97 289.85,75.97 292.16,78.29 292.16,79.8 291.79,80.17 291.79,80.78 294.12,83.11 v4(294.93,83.11)
  IN4 w0.076: v4(280.9,75.87) 280.53,75.5 280.53,64.85 281.54,63.83 281.54,47.53 v1(281.48,47.46) ; v1(256.35,40.94) 256.35,41.99 258.57,44.21 258.57,46.29 258.86,46.59 281.35,46.59 v1(281.48,46.46) ; v1(294.47,83.11) v4(294.93,83.11)
  BOTTOM w0.076: v1(281.48,47.46) v2(281.48,46.98) v1(281.48,46.46) ; U38.C3 292.62,83.63 292.87,83.38 294.21,83.38 v1(294.47,83.11)
  BOTTOM w0.254: PR49.2 255.95,39.86 256.35,40.25 v1(256.35,40.94)
CHG_SNUB: length 0.7
  BOTTOM w0.076: 267.03,32.26 v2(267.73,32.26)
CHG_SW: length 6.4
  IN4 w1.016: 254.34,32.28 254.65,32.28 258.99,27.93
  vias: v1(253.35,32.58) v1(253.35,32.2) v1(259.88,28.01) v1(259.88,27.65)
CHG_SW1: length 1.6
  BOTTOM w0.076: PR719.2 v2(266.38,37.98)
CHG_UGATE: length 9.7
  IN4 w1.016: 261.12,29 259.75,29 255.33,33.42 253.27,33.42
  vias: v1(252.66,32.89) v1(261.2,27.98) v1(261.17,27.63) v11(252.27,32.76)
CL_CLK: length 135.1
  IN4 w0.076: v1(19.4,35.3) 19.4,35.38 19.68,35.66 20.6,35.66 20.94,35.33 26.54,35.33 27.04,35.83 30.18,35.83 30.91,35.11 31.52,35.11 31.99,34.64 47.45,34.64 47.49,34.68 48.98,34.68 49.9,33.76 49.9,23.75 49.64,23.5 49.64,17.75 52.35,15.04 61.42,15.04 62.55,13.91 64.31,13.91 65.94,15.54 76.64,15.54 77.02,15.16 78.87,15.16 79.19,14.84 86.27,14.84 86.46,15.03 94.67,15.03 94.82,15.18 96.45,15.18 96.51,15.13 96.99,15.13 97.04,15.08 97.83,15.08 98.46,14.44 103.23,14.44 103.64,14.03 106.79,14.03 107.22,14.47 112.81,14.47 113.95,15.61 115,15.61 115.5,16.12 116.62,16.12 117.18,15.56 119.06,15.56 121.97,18.47 125.85,18.47 126.01,18.32 127.73,18.32 127.94,18.12 128.33,18.12 v1(128.38,18.17)
  BOTTOM w0.076: v1(19.4,35.3) 19.43,35.28 19.43,33.15 R64.2
CL_CLK_R: length 5.3
  IN1 w0.076: JNGFF1.34 19.5,26.81 19.5,31.37 19.34,31.53 v4(19.33,31.53)
  IN4 w0.076: v4(19.33,31.53) 19.33,31.65 v1(19.09,31.89)
CL_DATA: length 135.7
  IN4 w0.076: v1(19.78,35.3) 19.82,35.33 20.46,35.33 20.8,35 26.67,35 27.18,35.5 30.05,35.5 30.77,34.78 31.38,34.78 31.85,34.31 47.58,34.31 47.62,34.35 48.84,34.35 49.57,33.62 49.57,23.89 49.31,23.64 49.31,17.61 52.22,14.7 61.29,14.7 62.41,13.58 64.45,13.58 66.08,15.21 76.51,15.21 76.88,14.83 78.73,14.83 79.06,14.51 86.41,14.51 86.6,14.7 94.81,14.7 94.96,14.85 96.32,14.85 96.37,14.8 96.85,14.8 96.91,14.75 97.69,14.75 98.32,14.11 103.1,14.11 103.51,13.7 106.92,13.7 107.36,14.14 112.95,14.14 114.09,15.28 115.13,15.28 115.64,15.79 116.49,15.79 117.04,15.23 119.2,15.23 122.1,18.14 125.72,18.14 125.87,17.99 126.05,17.99 126.19,18.13 127.67,18.13 127.87,17.93 129.12,17.93 v1(129.37,18.18)
  BOTTOM w0.076: v1(129.37,18.18) 129.37,18.18 129.37,18.17 UCPU1.H23 ; R63.2 19.76,33.16 v12(19.76,34.54) 19.76,35.27 v1(19.78,35.3)
CL_DATA_R: length 4.7
  IN1 w0.076: JNGFF1.32 19.65,27.96 19.65,31.37 19.8,31.53 v4(19.86,31.53)
  IN4 w0.076: v1(20.1,31.89) 19.86,31.65 v4(19.86,31.53)
CL_RST#: length 129.1
  IN1 w0.076: v3(38.79,38.38) 38.75,38.35 36.87,38.35 36.32,38.89 22.6,38.89 v3(21.12,37.41)
  IN2 w0.076: v3(38.79,38.38) 38.88,38.38 39.92,39.42 39.92,39.79 40.69,40.55 63.69,40.55 64.6,41.47 83.94,41.47 98.78,26.63 98.78,26.28 102.32,22.74 102.32,22.41 105.57,19.16 107.25,19.16 107.29,19.19 108.49,19.19 108.84,19.55 115.63,19.55 116.78,20.71 119.91,20.71 122.63,17.99 124.27,17.99 124.56,17.7 125.77,17.7 125.81,17.66 126.4,17.66 126.55,17.81 126.94,17.81 127.09,17.96 128.52,17.96 128.58,17.91 129.43,17.91 v4(129.68,17.66)
  IN4 w0.076: v4(129.68,17.66) 129.7,17.68 129.7,17.75 129.88,17.93 v1(129.88,18.17)
  BOTTOM w0.076: R61.2 21.12,33.02 20.6,33.54 20.6,36.78 21.12,37.3 v3(21.12,37.41) 21.13,37.41 v2(21.69,36.85)
CL_RST#_R: length 5.3
  IN1 w0.076: JNGFF1.30 20.5,30.7 v3(21,31.21)
  BOTTOM w0.076: v3(21,31.21) 21.12,31.32 R61.1
CLK_LPC_DEBUG: length 282.7
  TOP w0.076: v5(166.57,15.03) 166.57,15.02 163.04,11.49 154.91,11.49 154.36,10.95 138.43,10.95 135.3,14.08 126.15,14.08 124.01,16.21 124.01,19.55 124.01,19.87 120.9,22.98 115.52,22.98 113.97,21.43 v5(112.66,21.43) ; v3(285.21,8.36) 285.24,8.39 285.24,13.21 284.15,14.3 v3(283.53,14.3)
  IN1 w0.076: v5(166.57,15.03) 166.98,15.44 167.55,15.44 167.58,15.41 168.22,15.41 168.71,15.9 168.71,16.6 v4(168.77,16.66) ; v4(112.23,21.07) 112.58,21.43 v5(112.66,21.43)
  IN3 w0.076: v4(168.77,16.66) 168.77,16.66 168.77,16.68 168.79,16.65 168.87,16.65 169.12,16.4 169.12,15.5 168.91,15.28 168.91,12.65 175,6.56 181.76,6.56 182.15,6.95 190.78,6.95 191.06,7.23 197.44,7.23 197.86,6.81 199.67,6.81 200.68,7.82 209.29,7.82 209.83,7.27 215.35,7.27 215.74,6.88 216.03,6.88 216.43,7.28 226.65,7.28 230,10.63 246.83,10.63 250.03,7.43 268.1,7.43 269.03,8.36 272.03,8.36 272.21,8.18 282.44,8.18 282.88,8.63 284.95,8.63 v3(285.21,8.36)
  IN4 w0.076: v1(282.74,79.31) 282.39,78.96 282.39,72.87 282.08,72.56 282.08,71.68 283.94,69.83 283.94,55.55 285.22,54.27 286.8,54.27 288.3,52.77 288.3,49.33 290.37,47.27 290.37,46.76 290.95,46.17 291.37,46.17 293.05,44.48 293.05,43.2 293.81,42.45 293.81,42.26 293.8,42.25 293.8,41.19 294.82,40.17 294.82,23.15 294.51,22.84 294.51,19.67 293.03,18.19 287.76,18.19 286.29,16.72 286.29,16.22 284.38,14.3 v3(283.53,14.3) ; v1(111.85,21.07) v4(112.23,21.07)
CLK_PCI_MEC: length 279.4
  TOP w0.076: v5(109.93,19.17) 111.49,17.6 113.32,17.6 116.91,14.01 122.7,14.01 125.1,11.61 130.63,11.61 130.95,11.3 v2(132.06,11.3) 134,11.3 137.37,7.92 164.1,7.92 168.63,12.45 v5(168.63,12.49)
  IN1 w0.076: v5(168.63,12.49) 168.63,13.77 168.63,13.77 168.63,14.03 169.87,15.27 170.2,15.27 v4(170.2,15.27) ; v5(109.93,19.17) 109.88,19.12 109.68,19.12 v4(109.59,19.21)
  IN3 w0.076: v4(292.92,14.59) 292.92,14.59 292.61,14.29 291.71,14.29 290.09,12.67 287.93,12.67 284.93,9.67 282.85,9.67 282.12,8.95 272.53,8.95 272.09,9.38 268.96,9.38 267.77,8.2 250.35,8.2 247.15,11.4 229.69,11.4 226.4,8.11 210.07,8.11 209.6,8.58 199.57,8.58 199.41,8.73 192.78,8.73 192.39,8.34 186.07,8.34 185.53,7.8 175.05,7.8 169.68,13.17 169.68,14.67 170.2,15.19 v4(170.2,15.27)
  IN4 w0.076: v1(291.25,77.13) 291.25,76.66 290.35,75.75 290.35,71.5 290.55,71.3 290.55,68.96 290.09,68.5 290.09,67.22 289.35,66.48 289.35,58.79 290.61,57.54 290.61,55.46 291.11,54.96 291.11,52.41 291.11,51.27 292.5,49.88 295.57,49.88 295.74,49.71 295.74,49.71 296.31,49.14 296.31,48.26 296.16,48.11 296.16,47.42 296.61,46.98 296.61,46.46 296.89,46.18 297.58,46.18 297.97,45.79 297.97,35.37 297.46,34.86 297.46,22.05 297.21,21.81 297.21,16.29 295.45,14.54 292.97,14.54 v4(292.92,14.59) ; v1(109.56,18.64) 109.52,18.67 109.52,19.14 v4(109.59,19.21)
  BOTTOM w0.076: U38.N6 291.11,77.49 291.25,77.36 v1(291.25,77.13) 291.18,77.07 R231.1
CLK_PCIE2: length 151.1
  IN1 w0.066: v4(45.27,25.99) 45.39,26.1 46.31,26.1 50,22.41 50,18.69 50.43,18.26 50.43,13.83 55.07,9.19 58.98,9.19 59.55,8.62 83.17,8.62 85.77,6.01 94.13,6.01 94.32,5.83 94.32,5.03 96.69,2.66 109.84,2.66 113.22,6.04 119.14,6.04 120.88,4.3 122.73,4.3 123.41,3.62 129.78,3.62 130.65,4.49 131.14,4.49 132.27,4.49 134.63,6.85 135.64,6.85 136.69,7.9 136.69,8.88 136.03,9.54 136.03,11.98 136.69,12.64 136.69,14.06 v4(136.08,14.67)
  IN4 w0.066: v1(18.18,30.76) 18.08,30.87 18.08,30.98 18.16,31.06 18.35,31.06 18.49,30.92 19.1,30.92 19.21,31.03 20.25,31.03 21.04,31.82 22.07,31.82 22.72,31.17 28.43,31.17 28.9,30.7 30.4,30.7 30.78,30.32 34.88,30.32 37.52,27.68 43.15,27.68 44.65,26.18 45.08,26.18 v4(45.27,25.99) ; v4(136.08,14.67) 135.93,14.52 135.82,14.52 135.52,14.83 135.52,14.9 135.62,15 v1(135.77,15)
  BOTTOM w0.084: v1(18.18,30.76) 18.11,30.68 18.11,30.29 18.25,30.15 JNGFF1.39
CLK_PCIE2#: length 151.1
  IN1 w0.066: v4(45.27,26.52) 45.53,26.25 46.37,26.25 50.15,22.47 50.15,18.75 50.58,18.32 50.58,13.89 55.13,9.34 59.04,9.34 59.61,8.77 83.23,8.77 85.83,6.16 94.19,6.16 94.47,5.89 94.47,5.09 96.75,2.81 109.78,2.81 113.15,6.19 119.2,6.19 120.94,4.45 122.79,4.45 123.47,3.77 129.72,3.77 130.58,4.64 131.2,4.64 132.21,4.64 134.57,7 135.58,7 136.54,7.96 136.54,8.82 135.88,9.48 135.88,12.04 136.54,12.7 136.54,14 136.18,14.36 136.1,14.36 v4(135.93,14.19)
  IN4 w0.066: v4(45.27,26.52) 45.08,26.33 44.71,26.33 43.21,27.83 37.58,27.83 34.94,30.47 30.84,30.47 30.46,30.85 28.97,30.85 28.5,31.32 22.78,31.32 22.13,31.97 20.98,31.97 20.19,31.18 19.15,31.18 19.04,31.07 18.55,31.07 18.41,31.21 18.1,31.21 17.93,31.04 17.93,30.86 v1(17.82,30.75) ; v4(135.93,14.19) 135.93,14.21 135.37,14.76 135.17,14.97 v1(135.17,15)
  BOTTOM w0.084: JNGFF1.41 17.75,30.12 17.92,30.29 17.92,30.65 v1(17.82,30.75)
CLK_PCIE4: length 161.3
  IN1 w0.066: v4(136.61,15.36) 136.61,15.36 136.71,15.26 136.96,15.26 137.14,15.08 137.14,13.74 137.47,13.42 137.47,12.85 136.56,11.94 136.56,9.82 137.32,9.06 137.32,7.69 135.89,6.26 134.88,6.26 132.52,3.89 130.89,3.89 129.99,2.99 123.17,2.99 122.47,3.69 120.64,3.69 118.94,5.38 113.44,5.38 110.11,2.05 96.43,2.05 95.9,2.58 88.98,2.58 88.97,2.59 88.32,2.59 82.89,8.02 62.87,8.02 62.48,7.63 55.54,7.63 49.82,13.34 49.82,17.86 49.31,18.37 49.31,21.25 46.34,24.22 45.21,24.22 44.62,24.81 44.62,26.31 40.37,30.56 40.07,30.56 39.73,30.21 39.55,30.21 v4(39.39,30.05)
  IN4 w0.066: v4(136.61,15.36) 136.61,15.35 136.61,15.18 136.54,15.11 136.48,15.11 136.42,15.05 136.37,15.05 136.21,15.21 136.12,15.21 135.93,15.39 135.8,15.39 135.77,15.42 v1(135.77,15.56) ; v1(12.25,29.4) 12.19,29.34 12.1,29.34 12.02,29.42 12.02,29.5 11.95,29.57 11.95,31.46 12.75,32.26 18.35,32.26 18.64,32.55 22.2,32.55 22.97,31.78 28.68,31.78 29.15,31.31 35.51,31.31 36.6,30.22 39.22,30.22 v4(39.39,30.05)
CLK_PCIE4#: length 161.4
  IN1 w0.066: v4(39.39,30.59) 39.62,30.36 39.67,30.36 40.01,30.71 40.43,30.71 44.77,26.37 44.77,24.88 45.27,24.37 46.41,24.37 49.46,21.32 49.46,18.43 49.97,17.92 49.97,13.4 55.6,7.78 62.42,7.78 62.81,8.17 82.95,8.17 88.39,2.74 89.04,2.74 89.04,2.73 95.96,2.73 96.49,2.2 110.05,2.2 113.38,5.53 119.01,5.53 120.7,3.84 122.53,3.84 123.23,3.14 129.93,3.14 130.83,4.04 132.46,4.04 134.82,6.41 135.83,6.41 137.17,7.75 137.17,9 136.41,9.76 136.41,12 137.32,12.91 137.32,13.36 136.99,13.68 136.99,15.02 136.9,15.11 136.82,15.11 136.61,14.9 v4(136.61,14.8)
  IN4 w0.066: v4(136.61,14.8) 136.51,14.9 136.31,14.9 136.15,15.06 136.06,15.06 135.87,15.24 135.74,15.24 135.52,15.46 135.26,15.46 v1(135.17,15.56) ; v1(11.75,29.4) 11.8,29.45 11.8,31.52 12.69,32.41 18.29,32.41 18.58,32.7 22.26,32.7 23.03,31.93 28.74,31.93 29.21,31.46 35.57,31.46 36.66,30.37 39.17,30.37 v4(39.39,30.59)
CLK_PCIE5: length 94.6
  IN1 w0.066: v4(135.86,13.17) 136.04,13.35 136.15,13.35 136.23,13.27 136.23,12.96 135.42,12.15 135.42,9.09 135.93,8.58 135.93,8.2 135.42,7.69 134.39,7.69 132.08,5.37 128.02,5.37 127.73,5.09 121.16,5.09 119.45,6.79 112.15,6.79 109.11,3.75 108,3.75 107.67,3.42 102.31,3.42 101.33,4.4 100.05,4.4 99.73,4.71 99.73,5.26 98.6,6.39 95.96,6.39 95.07,7.28 85.67,7.28 83.59,9.36 60.09,9.36 59.39,10.06 58.18,10.06 57.39,10.85 57.39,10.96 57.74,11.31 v3(57.79,11.31)
  IN4 w0.066: v1(135.17,13.8) 135.17,13.8 135.8,13.17 v4(135.86,13.17)
  BOTTOM w0.084: JNGFF2.47 57.75,10.85 57.63,10.97 57.63,11.16 57.79,11.31 v3(57.79,11.31)
CLK_PCIE5#: length 94.9
  IN1 w0.066: v3(57.21,11.31) 57.24,11.29 57.24,10.79 58.11,9.91 59.33,9.91 60.03,9.22 83.52,9.22 85.61,7.13 95.01,7.13 95.9,6.24 98.53,6.24 99.58,5.2 99.58,4.65 99.98,4.25 101.27,4.25 102.25,3.27 107.73,3.27 108.06,3.6 109.17,3.6 112.21,6.64 119.39,6.64 121.09,4.94 127.79,4.94 128.08,5.22 132.14,5.22 134.45,7.54 135.48,7.54 136.08,8.14 136.08,8.64 135.57,9.15 135.57,12.08 136.38,12.89 136.38,13.33 136.15,13.56 v4(136.15,13.68)
  IN4 w0.066: v4(136.15,13.68) 136.15,13.66 136.01,13.51 135.7,13.51 135.62,13.59 135.62,13.71 135.72,13.8 v1(135.77,13.8)
  BOTTOM w0.084: v3(57.21,11.31) 57.21,11.31 57.37,11.16 57.37,10.97 57.25,10.85 JNGFF2.45
CLK_REQ2#: length 97.4
  IN1 w0.076: v4(20.23,35.02) 20.45,34.79 27.46,34.79 28.24,35.57 28.83,35.57 28.83,35.57 29.21,35.57 37.69,35.57 45.2,28.06 47.12,28.06 55.7,19.47 62.73,19.47 68.39,13.81 72.03,13.81 73.78,12.06 91.25,12.06 v4(94.63,15.44)
  IN3 w0.076: v4(20.23,35.02) 20.04,34.83 19.91,34.83 17.89,32.81 16.09,32.81 v3(14.64,31.36)
  IN4 w0.076: v1(94.09,15.44) v4(94.63,15.44)
  BOTTOM w0.076: JNGFF1.45 16.75,30.99 16.37,31.36 v2(15.53,31.36) v3(14.64,31.36)
CLK_REQ2#_R: length 41.1
  IN1 w0.076: v4(95.39,14.52) 95.52,14.66 104.68,14.66 105.2,15.19 108.89,15.19 109.46,15.75 109.46,16.37 109.8,16.71 116.09,16.71 117.46,15.34 117.93,15.34 121.19,15.34 122.05,16.2 125.75,16.2 125.94,16 126.45,16 126.56,16.11 127.81,16.11 128.79,17.09 129.28,17.09 129.64,16.72 130.56,16.72 130.9,17.06 130.9,17.34 v4(131.24,17.68)
  IN4 w0.076: v1(130.88,17.3) 130.88,17.33 131.24,17.68 v4(131.24,17.68) ; v1(95.01,14.52) v4(95.39,14.52)
  BOTTOM w0.076: RH40.2 v1(95.01,14.52)
CLK_REQ3#_R: length 40.3
  IN1 w0.076: v4(94.78,12.95) 95.25,13.42 96.14,13.42 97.1,14.38 105.45,14.38 105.83,14.76 108.83,14.76 110.43,16.36 111.97,16.36 112.35,15.98 115.04,15.98 115.41,16.35 116.23,16.35 117.39,15.19 117.99,15.19 121.26,15.19 122.1,16.03 125.7,16.03 125.88,15.85 126.52,15.85 126.62,15.96 128.04,15.96 128.52,16.44 129.51,16.44 129.64,16.57 130.67,16.57 v4(131.1,16.15)
  IN4 w0.076: v4(131.1,16.15) 130.88,16.36 v1(130.88,16.44) ; v4(94.78,12.95) 94.98,12.74 v1(94.98,12.54)
CLK_REQ4#: length 156.1
  IN4 w0.076: v1(122.87,8.02) 122.87,8.08 121.8,9.16 111.17,9.16 109.17,11.16 106.87,11.16 106.19,11.84 101.44,11.84 101.07,11.47 97.52,11.47 97.22,11.77 94.7,11.77 93.8,12.67 86.82,12.67 85.81,13.67 78.67,13.67 78.32,14.03 69.46,14.03 67.2,11.77 62.46,11.77 60.76,13.47 51.26,13.47 50.31,14.42 50.31,15.28 48.61,16.98 48.61,22.93 48.61,22.94 v1(48.61,23.04) ; v1(8.48,33.49) 8.54,33.55 9.41,33.55 12.24,36.38 18.74,36.38 19.19,36.82 26.66,36.82 27.48,36 30.25,36 30.95,35.3 31.55,35.3 32.06,34.79 47.32,34.79 47.5,34.97 v1(47.83,34.97)
  BOTTOM w0.076: JNGFF1.60 12.38,28.22 11.05,28.22 10.67,28.6 10.67,30.18 11.02,30.53 11.02,32.71 10.39,33.34 v2(8.86,33.34) 8.64,33.34 v1(8.48,33.49) ; v1(47.83,34.97) 47.72,34.87 47.72,33.76 48.6,32.89 48.6,26.85 45.3,23.55 45.3,23.2 45.48,23.02 48.59,23.02 v1(48.61,23.04) ; v1(122.87,8.02) 122.97,8.02 RH43.1
CLK_REQ4#_R: length 7.7
  BOTTOM w0.076: UCPU1.D35 128.25,12.97 127.97,12.7 127.22,12.7 125.75,11.22 125.75,9.67 124.55,8.48 RH42.2 RH43.2
CLK_REQ5#: length 56.7
  IN4 w0.076: v1(59.73,14.32) 61.22,14.32 62.19,13.35 64.4,13.35 64.76,12.99 66.64,12.99 68.3,14.65 78.56,14.65 78.93,14.28 86.11,14.28 86.82,13.57 95.59,13.57 95.88,13.28 96.86,13.28 97.09,13.05 98.06,13.05 98.32,12.79 100.37,12.79 100.72,13.15 102.64,13.15 103.48,12.31 107.48,12.31 107.72,12.55 108.05,12.55 v1(108.29,12.79)
  BOTTOM w0.076: v1(59.73,14.32) 57.69,14.32 57,15.01 JNGFF2.44
CLK_REQ5#_R: length 23
  IN4 w0.076: v1(129.13,15.14) 128.97,15.14 128.73,15.38 128.53,15.38 128.48,15.33 128.28,15.33 128.23,15.38 128.03,15.38 127.87,15.22 127.86,15.22 127.54,14.9 126.53,14.9 125.5,15.93 121.62,15.93 119.6,13.91 115.91,13.91 115.59,13.59 114.38,13.59 114.3,13.52 114.04,13.52 113.72,13.2 109.61,13.2 v1(109.21,12.79)
  BOTTOM w0.076: RH44.2 v1(109.21,12.79)
CLKOUT_LPC0: length 22.8
  IN4 w0.076: v1(129.88,21.63) 129.68,21.63 129.63,21.58 129.63,21.36 129.55,21.28 129.43,21.28 129.35,21.36 129.35,21.51 128.98,21.88 128.78,21.88 128.72,21.81 128.46,21.81 128.38,21.88 128.38,22.23 128.25,22.36 127.22,22.36 126.94,22.08 126.17,22.08 125.6,22.65 125.27,22.65 124.94,22.65 124.85,22.55 124.34,22.55 123.38,21.6 121.47,21.6 121.18,21.89 118.37,21.89 118.29,21.98 116.64,21.98 115.71,21.05 115.65,21.05 115.4,21.05 115.38,21.05 114.92,20.59 114.56,20.59 113.65,19.68 113.42,19.68 113.01,19.27 112.6,19.27 112.6,19.27 111.11,19.27 v1(110.48,18.64)
CLKOUT_LPC1: length 18.5
  IN1 w0.076: v4(129.67,22.12) 129.41,21.86 128.52,21.86 128.34,22.04 127.07,22.04 126.67,21.63 124.65,21.63 124.46,21.44 120.67,21.44 120.28,21.83 117.81,21.83 117.56,22.09 113.92,22.09 113.22,21.38 v4(113.14,21.38)
  IN4 w0.076: v4(113.14,21.38) 113.14,21.35 112.86,21.07 v1(112.76,21.07) ; v4(129.67,22.12) 129.68,22.12 129.73,22.07 v1(130.13,22.07)
CLKRUN#: length 271.1
  IN2 w0.076: v4(297.5,13.72) 297.47,13.7 297.47,12.95 288.73,4.21 260.98,4.21 259.43,5.76 244.14,5.76 243.07,4.68 236.54,4.68 235.36,5.87 214.49,5.87 213.81,6.56 205.83,6.56 204.41,7.98 199.42,7.98 198.3,6.86 197.51,6.86 196.78,6.12 190.42,6.12 189.14,4.85 169.8,4.85 169.53,5.12 168.16,6.49 154.14,6.49 153.38,7.26 144.64,7.26 143.89,6.51 141.78,6.51 140.73,7.56 134.12,7.56 132.57,6.01 124.47,6.01 122.34,8.15 v4(121.8,8.15)
  IN4 w0.076: v4(297.5,13.72) 297.9,13.72 300.07,15.9 300.07,20.46 299.88,20.65 299.88,33.86 300.39,34.37 300.39,61.85 295.92,66.32 295.92,70.77 297.18,72.03 297.18,74.61 296.33,75.47 296.33,77.86 295.63,78.55 295.63,80.04 294.63,81.04 293.47,81.04 293.3,80.87 293.01,80.87 292.77,80.63 v1(292.61,80.63) ; v4(121.8,8.15) 121.75,8.2 121.75,8.22 v1(121.5,8.48)
  BOTTOM w0.076: v1(121.5,8.48) 122.06,9.03 124.68,9.03 125.58,9.93 125.58,11.27 127.28,12.97 UCPU1.B35
CODEC_MUTE#: length 23
  IN4 w0.076: v1(8.08,44.91) 7.61,45.38 6.13,45.38 5.71,45.8 5.71,46.15 v1(5.84,46.28)
  BOTTOM w0.076: v1(5.84,46.28) 5.84,46.41 5.12,47.13 5.12,51.91 4.48,52.54 4.48,54.28 v2(4.61,54.41) 4.61,56.19 5.32,56.9 JAUD1.4 ; v1(8.08,44.91) 8.21,45.05 v3(12.96,45.05) 13.84,45.05 DA8.1
COMP: length 4.4
  BOTTOM w0.102: v2(183.45,14.5) 183.65,14.5 PC538.2
  BOTTOM w0.254: PU702.6 185.31,15.43 PR564.2 PC538.2
CONTACTLESS_DET#: length 224.7
  TOP w0.076: v5(130.97,11.61) 130.97,11.61 134.22,11.61 137.53,8.3 163.9,8.3 169.28,13.67 169.28,14.64 170.33,15.69 v5(170.88,15.69)
  IN1 w0.076: v4(171.27,15.66) 170.9,15.66 v5(170.88,15.69) ; v4(130.73,11.1) 130.73,11.18 130.86,11.31 130.86,11.5 v5(130.97,11.61)
  IN3 w0.076: v4(171.27,15.66) 171.84,15.66 172.54,14.96 176.53,14.96 177.2,15.64 179.73,15.64 180.23,16.15 187.02,16.15 187.73,15.44 188.69,15.44 189.15,14.98 196.24,14.98 198.37,17.11 201.98,17.11 203.86,15.23 214.41,15.23 215.33,14.31 222,14.31 224.43,16.75 224.43,17.1 227.16,19.83 229.55,19.83 230.45,20.73 232.99,20.73 233.22,20.5 234.94,20.5 235.99,21.56 239.6,21.56 240.04,21.11 249.31,21.11 250.58,19.84 252.82,19.84 254.62,18.04 257.22,18.04 257.73,18.55 271.28,18.55 272.53,19.79 273.39,19.79 276.39,16.79 283.98,16.79 284.81,17.62 288.26,17.62 289.39,18.76 289.56,18.93 289.82,18.93 291.63,20.73 292.45,20.73 294.33,22.6 294.33,39.92 293.45,40.79 293.45,42.53 292.57,43.41 292.57,44.76 291.71,45.62 291.16,45.62 290,46.79 290,47.51 288.2,49.31 v4(287.89,49.31)
  IN4 w0.076: v1(129.36,11.38) 129.88,11.38 129.89,11.37 129.9,11.37 130.04,11.23 130.04,11.22 130.12,11.14 ; v1(127.18,7.5) 127.18,8.45 129.61,10.89 129.92,10.89 129.99,10.96 129.99,10.98 130.12,11.12 130.12,11.14 ; v4(130.73,11.1) 130.69,11.14 130.12,11.14 ; v4(287.89,49.31) 287.89,49.69 v1(287.95,49.74)
  BOTTOM w0.076: RH174.1 127.18,6.51 v1(127.18,7.5) ; v1(287.95,49.74) 288.14,49.55 v2(288.5,49.55) 291.12,49.55 291.46,49.89 292.03,49.89 292.25,50.11 JUSH1.4
CPU_B+:
  vias: v6(191.12,31.92)
CPU_PATH_EN: length 5.1
  BOTTOM w0.076: U5.2 178.6,2.94 R13.2 179.09,3.33 180.11,3.33 180.38,3.6 v2(180.38,4.26) R12.2
CPU_PATH_EN_G: length 21.6
  BOTTOM w0.076: U4.5 174.34,10.01 173.95,10.41 v2(173.05,10.41) 172.96,10.41 172.44,9.89 U4.2 172.18,8.61 172.18,5.31 172.44,5.06 U4.15 172.44,2.68 172.57,2.56 174.23,2.56 174.33,2.66 174.33,3.5 U4.12 174.34,6.88 174.52,7.05 177.68,7.05 177.95,6.79 U5.4
CPU_XDP_TCK: length 52.8
  IN4 w0.076: v1(154.2,11.13) 154.33,11.13 154.72,10.74 155.02,10.74 155.42,10.34 157.71,10.34 158.11,9.93 165.1,9.93 165.49,9.54 166.33,9.54 168.14,7.73 168.14,5.59 v1(168.24,5.49) 168.87,5.49 169.34,5.02 171.88,5.02 171.95,4.95 179.17,4.95 179.49,5.27 185.13,5.27 185.46,4.94 189.42,4.94 189.56,5.08 189.7,5.08 190.28,5.66 193.16,5.66 193.74,6.23 195.73,6.23 196.76,7.26 v1(197.82,7.26)
  BOTTOM w0.076: v1(168.24,5.49) 168.56,5.17 RC15.1 ; v1(197.82,7.26) 197.82,7.25 197.82,6.77 197.7,6.65 197.7,4.82 RH148.1
CPU_XDP_TDI: length 25.1
  IN4 w0.076: v1(155.5,12.38) 156.78,12.38 157.33,11.83 166.6,11.83 v1(167.92,10.51) 171,7.42 174.41,7.42 v1(175.02,6.81)
  BOTTOM w0.076: U4.11 174.98,6 175.02,6.04 v1(175.02,6.81)
CPU_XDP_TDO: length 24.1
  IN4 w0.076: v1(155.5,11.88) 155.52,11.9 156.55,11.9 156.92,11.54 156.92,11.45 157.09,11.28 166.33,11.28 169.47,8.14 v1(169.47,8.1) 170.42,7.15 170.42,7.15 170.75,6.82 v1(173.73,6.82)
  BOTTOM w0.076: v1(169.47,8.1) 169,7.63 RC11.1 ; U4.6 174.98,8.04 173.76,6.82 v1(173.73,6.82)
CPU_XDP_TMS: length 23.7
  IN4 w0.076: v1(154.63,11.38) 154.65,11.4 154.96,11.4 154.97,11.39 155.15,11.39 155.76,10.79 159.56,10.79 v1(159.62,10.73) 159.71,10.64 165.4,10.64 165.57,10.81 166.13,10.81 168.84,8.09 168.84,6.53 169.62,5.76 v1(172.45,5.76)
  BOTTOM w0.076: v1(172.45,5.76) 172.45,5.74 173.07,5.11 U4.14
CS1: length 5.5
  BOTTOM w0.076: PR305.2 277.12,33.61 277.12,34.38 v2(277.76,35.02)
  BOTTOM w0.203: PR305.2 277.58,33.18 278.09,32.67 279.35,32.67 279.69,32.33 PU300.1
CS2: length 5.7
  BOTTOM w0.076: PR304.2 283.4,33.23 283.78,33.61 283.78,34.71 v2(283.4,35.1)
  BOTTOM w0.203: PR304.2 283.37,32.75 282.6,31.97 282.11,31.97 281.85,32.23 281.52,32.23 281.29,32 PU300.5
CS_1.35V: length 2.2
  BOTTOM w0.203: PU600.13 219.24,24.3 v2(219.06,24.12) 218.98,24.05 PR601.2
CS_PWR_BTN#: length 312.8
  IN2 w0.076: v4(124.31,8.67) 124.89,8.67 125.24,8.33 127.2,8.33 128,7.54 131.91,7.54 134.28,9.91 144.02,9.91 145.24,8.69 169.21,8.69 171.63,6.28 181.92,6.28 183.63,7.99 184.71,7.99 185.01,8.29 185.01,8.84 185.42,9.25 192.44,9.25 192.55,9.36 196.9,9.36 197.41,9.87 199.9,9.87 200.17,10.14 203.8,10.14 205.55,8.4 209.63,8.4 210.2,7.83 216.24,7.83 216.94,7.13 237.31,7.13 237.98,6.46 241.46,6.46 242.05,7.04 249.92,7.04 250.16,6.8 259.88,6.8 261.29,5.39 266.72,5.39 266.98,5.12 287.1,5.12 288.71,6.74 290.1,6.74 295.82,12.45 295.82,13.34 295.82,13.34 295.82,13.59 295.82,13.59 295.82,14.39 296.44,15.02 296.44,17.89 297.24,18.69 297.24,20.32 298.04,21.13 298.04,47.83 293.32,52.56 292.76,52.56 292.21,53.1 291.7,53.1 287.31,57.5 287.31,58.98 285.15,61.13 285.15,74.07 284.33,74.89 284.33,78.46 283.46,79.33 283.46,80.41 284.49,81.44 v3(284.8,81.44)
  IN3 w0.076: v4(128,21.27) 127.97,21.27 127.89,21.19 127.3,21.19 127.14,21.02 127.14,18.7 126.9,18.46 125.44,18.46 123.09,16.1 123.09,13.1 124.31,11.87 v4(124.31,8.67)
  IN4 w0.076: v1(129.38,20.77) 129.22,20.77 128.98,21.01 128.91,21.01 128.57,21.35 128.08,21.35 v4(128,21.27) 127.97,21.24 125.13,21.24 124.98,21.09 124.82,21.09 124.33,20.6 120.73,20.6 120.54,20.41 118.14,20.41 117.64,20.41 117.13,20.41 115.4,18.68 113.89,18.68 113.39,18.18 112.01,18.18 110.93,17.1 107.9,17.1 107.21,16.41 101.24,16.41 101.15,16.5 100.61,16.5 100.41,16.3 v1(100.41,16.12)
  BOTTOM w0.076: RP8.6 100.74,14.31 100.8,14.37 100.8,14.98 100.39,15.38 100.39,16.1 v1(100.41,16.12) ; U38.H13 287.39,81.13 287.29,81.22 285.94,81.22 v2(285.85,81.13) 285.11,81.13 v3(284.8,81.44)
CSSN_1: length 16.9
  IN4 w0.254: v1(263.13,19.86) 262.49,19.86 262.04,20.31 262.04,23.36 258.38,27.02 252.97,27.02 v1(252.46,27.53)
  BOTTOM w0.102: v2(253.48,28.03) 252.97,27.53 v1(252.46,27.53)
CSSP_1: length 18.5
  IN4 w0.254: v1(260.51,19.86) 261.28,19.86 261.71,20.29 261.71,23.22 258.24,26.69 251.38,26.69 v1(250.76,27.31)
  BOTTOM w0.102: v2(252,26.64) 251.42,26.64 250.76,27.3 v1(250.76,27.31)
DDI2_HPD_SINK: length 14.5
  BOTTOM w0.076: JNGFF1.23 22.25,31.78 RV1.1 21.89,31.89 21.6,31.6 21.6,31.23 21.18,30.81 20.84,30.81 20.58,31.07 20.58,33.09 20.24,33.43 20.24,36.9 20.64,37.29 QV1.1 v2(22.55,38.45)
DDR3_DRAMRST#: length 217.5
  IN2 w0.076: v4(144.32,27.07) 144.18,27.07 143.99,27.26 143.99,27.61 144,27.62 144,27.7 142.34,29.36 v3(139.74,29.36)
  IN3 w0.076: v3(142.71,54.08) 143.05,53.74 144.96,53.74 146.42,55.2 149.6,55.2 150.81,56.42 152.12,56.42 v4(152.37,56.67) 152.55,56.85 153.68,56.85 154.66,55.87 155.34,55.87 155.59,55.63 v3(155.59,55.55) ; v3(96.94,55.55) 96.94,55.63 96.7,55.87 95.97,55.87 94.99,56.85 93.91,56.85 v4(93.73,56.67) 93.47,56.42 92.17,56.42 90.95,55.2 87.77,55.2 86.31,53.74 84.41,53.74 v3(84.06,54.08) ; v3(126.4,55.47) 126.4,55.9 126.33,55.97 126.16,55.97 125.99,55.8 125.99,55.3 125.89,55.2 125.79,55.2 125.46,55.53 125.41,55.58 125.41,55.69 125.96,56.24 125.96,56.35 125.86,56.46 125.75,56.46 125.19,55.9 125.09,55.9 124.98,56.01 124.98,56.12 125.53,56.68 125.53,56.78 125.43,56.89 125.32,56.89 124.76,56.33 124.65,56.33 124.55,56.44 124.55,56.55 125.04,57.04 125.04,57.15 124.93,57.26 124.82,57.26 124.49,56.93 124.42,56.85 123.58,56.85 123.5,56.77 123.5,56.49 123.43,56.42 123.27,56.42 123.2,56.49 123.2,56.77 123.12,56.85 123.01,56.85 v4(122.75,56.58) 122.58,56.42 121.76,56.42 120.09,54.75 118.7,54.75 118.44,55.01 117.85,55.01 117.65,55.2 117.1,55.2 115.66,53.76 113.73,53.76 v3(113.38,54.11) ; v4(144.32,27.07) 144.27,27.02 144.08,27.02 143.93,27.17 143.93,28.69 144.12,28.89 144.12,32.21 142.88,33.45 142.88,38.58 138.44,43.02 v3(138.44,54.22) ; v3(172.02,54.11) 172.37,53.76 174.31,53.76 175.74,55.2 176.3,55.2 176.49,55.01 177.09,55.01 177.35,54.75 178.74,54.75 180.41,56.42 181.23,56.42 v4(181.39,56.58) 181.66,56.85 181.77,56.85 181.84,56.77 181.84,56.49 181.92,56.42 182.07,56.42 182.15,56.49 182.15,56.77 182.22,56.85 183.06,56.85 183.14,56.93 183.47,57.26 183.57,57.26 183.68,57.15 183.68,57.04 183.19,56.55 183.19,56.44 183.3,56.33 183.41,56.33 183.96,56.89 184.07,56.89 184.18,56.78 184.18,56.68 183.62,56.12 183.62,56.01 183.73,55.9 183.84,55.9 184.39,56.46 184.5,56.46 184.61,56.35 184.61,56.24 184.05,55.69 184.05,55.58 184.11,55.53 184.43,55.2 184.53,55.2 184.63,55.3 184.63,55.8 184.81,55.97 184.97,55.97 185.05,55.9 v3(185.05,55.47)
  IN4 w0.076: v4(93.73,56.67) 93.08,56.67 92.88,56.87 92.88,57.33 94.74,59.19 119.91,59.19 121.21,57.89 123.51,57.89 123.8,57.61 123.8,57.24 123.51,56.95 123.12,56.95 v4(122.75,56.58) ; v3(142.71,54.08) 142.11,54.68 141.18,54.68 140.73,54.22 v3(138.44,54.22) 133.64,54.22 132.42,55.44 128.38,55.44 127.32,56.51 126.55,56.51 126.17,56.13 126.17,55.69 v3(126.4,55.47) ; v4(152.37,56.67) 152.03,56.67 151.7,57.01 151.7,57.5 153.03,58.83 178.02,58.83 178.39,58.46 181.91,58.46 182.23,58.14 182.23,57.87 182.32,57.78 182.32,57.24 181.66,56.58 v4(181.39,56.58)
  BOTTOM w0.076: v3(84.06,54.08) 84.46,54.48 84.47,54.48 UD7.T2 ; UD2.T2 185.06,55.45 v3(185.05,55.47) 184.92,55.59 CD5.1 ; UD4.T2 155.73,55.41 v3(155.59,55.55) 155.48,55.66 CD23.1 ; UD5.T2 126.42,55.45 v3(126.4,55.47) 126.4,56.13 126.78,56.51 128.8,56.51 CD40.1 ; UD3.T2 143.12,54.49 v3(142.71,54.08) ; UD1.T2 172.07,54.11 v3(172.02,54.11) ; UD6.T2 113.42,54.11 v3(113.38,54.11) ; CD58.1 97.32,56.53 96.94,56.16 v3(96.94,55.55) 97.08,55.41 UD8.T2 ; RC20.2 RC19.2 138.59,29.36 v3(139.74,29.36)
DDR_A_BS0: length 127.5
  IN3 w0.076: v3(142.72,50.95) 143.03,51.26 144.28,51.26 145.1,50.44 149.43,50.44 149.72,50.73 150.74,50.73 150.81,50.67 v4(151.11,50.67) 151.35,50.67 151.42,50.74 151.42,50.82 151.5,50.89 151.67,50.89 151.74,50.82 151.74,50.63 151.82,50.55 151.97,50.55 152.05,50.63 152.05,50.82 152.12,50.89 152.28,50.89 152.35,50.82 152.35,50.63 152.43,50.55 152.58,50.55 152.66,50.63 152.66,50.82 152.73,50.89 152.89,50.89 152.96,50.82 152.96,50.55 153.04,50.47 153.19,50.47 153.27,50.55 153.27,50.82 153.34,50.89 153.5,50.89 153.57,50.82 153.57,50.46 153.65,50.39 153.8,50.39 153.88,50.46 153.88,50.82 153.95,50.89 154.11,50.89 154.32,50.69 154.94,50.69 155.02,50.61 155.02,50.21 155.09,50.13 155.71,50.13 155.79,50.21 155.79,50.55 155.73,50.61 155.73,50.84 155.65,50.92 v3(155.31,50.92) ; v4(150.98,24.19) 150.61,24.56 150.61,24.97 148.35,27.23 148.35,28.02 ; v3(172.06,51.71) 172.51,51.26 173.61,51.26 174.44,50.44 178.77,50.44 179.06,50.73 180.08,50.73 180.14,50.67 v4(180.45,50.67) 180.68,50.67 180.76,50.74 180.76,50.82 180.83,50.89 181,50.89 181.08,50.82 181.08,50.63 181.15,50.55 181.31,50.55 181.38,50.63 181.38,50.82 181.46,50.89 181.61,50.89 181.69,50.82 181.69,50.63 181.76,50.55 181.92,50.55 181.99,50.63 181.99,50.82 182.07,50.89 182.22,50.89 182.3,50.82 182.3,50.55 182.37,50.47 182.53,50.47 182.6,50.55 182.6,50.82 182.68,50.89 182.83,50.89 182.91,50.82 182.91,50.46 182.98,50.39 183.14,50.39 183.21,50.46 183.21,50.82 183.29,50.89 183.45,50.89 183.65,50.69 184.27,50.69 184.35,50.61 184.35,50.21 184.43,50.13 185.05,50.13 185.13,50.21 185.13,50.55 185.06,50.61 185.06,50.84 184.99,50.92 v3(184.65,50.92)
  IN3 w0.165: 148.35,28.02 148.35,37.56 153.11,42.32 153.41,42.32 153.58,42.48 153.58,42.87 153.7,42.99 154.11,42.99 154.24,42.87 154.24,42.48 154.4,42.32 156.3,42.32 156.55,42.57 156.55,43.43 156.68,43.55 158.04,43.55 158.17,43.68 158.17,44.09 158.38,44.3 159.05,44.3 159.19,44.44 159.19,44.8 159.32,44.92 159.75,44.92 159.88,44.8 159.88,44.59 160.01,44.47 160.34,44.47 160.46,44.59 160.46,44.8 160.59,44.92 161.2,44.92 161.33,44.8 161.33,44.59 161.43,44.49 161.78,44.49 161.91,44.62 161.91,44.8 162.04,44.92 162.06,44.92 162.94,45.8 162.94,48.91 163.07,49.04 163.46,49.04 163.59,49.17 163.59,50.51 v3(163.51,50.59)
  IN4 w0.076: v4(180.45,50.67) 180.45,50.79 180.32,50.92 180.17,50.92 180.17,50.91 179.98,50.73 174.09,50.73 174.03,50.79 174.03,50.97 173.96,51.03 167.09,51.03 167.02,50.96 167.02,50.79 167.14,50.67 167.3,50.67 167.42,50.54 167.42,50.41 167.3,50.28 167.14,50.28 167.02,50.16 167.02,49.94 166.94,49.86 165.71,49.86 165.63,49.94 165.63,50.62 165.51,50.74 165.33,50.74 165.21,50.62 165.21,49.99 165.13,49.92 164.98,49.92 164.9,49.99 164.9,50.49 164.83,50.56 164.67,50.56 164.6,50.49 164.6,49.97 164.52,49.89 164.06,49.89 163.94,50.01 163.94,50.17 164.06,50.28 164.2,50.28 164.32,50.41 164.32,50.69 164.2,50.82 163.64,50.82 163.51,50.69 v3(163.51,50.59) 163.49,50.56 163.26,50.56 163.18,50.64 163.18,50.87 163.1,50.94 162.93,50.94 162.88,50.89 162.88,50.78 162.79,50.69 162.66,50.69 162.57,50.78 162.57,50.84 162.48,50.93 161.29,50.93 161.2,50.84 161.2,50.76 161.1,50.67 160.97,50.67 160.87,50.76 160.87,50.86 160.79,50.94 160.67,50.94 160.59,50.86 160.59,50.74 160.51,50.67 159.9,50.67 159.78,50.79 159.78,51.12 159.69,51.2 159.58,51.2 159.5,51.12 159.5,50.79 159.37,50.67 158.88,50.67 158.81,50.74 158.81,51.25 158.75,51.31 158.57,51.31 158.49,51.23 158.49,50.74 158.41,50.67 158.26,50.67 158.19,50.74 158.19,51.27 158.15,51.31 158.02,51.31 157.92,51.21 157.92,51.05 157.87,51 157.71,51 156.92,50.21 154.93,50.21 154.6,49.87 154.31,49.87 154.18,50 153.71,50 153.6,50.11 153.6,50.26 153.71,50.36 153.78,50.36 153.88,50.46 153.88,50.9 153.76,51.03 153.53,51.03 153.45,50.95 153.45,50.47 153.37,50.4 153.22,50.4 153.15,50.47 153.15,51.07 153.07,51.15 152.92,51.15 152.84,51.07 152.84,50.47 152.76,50.4 152.61,50.4 152.54,50.47 152.54,51.07 152.46,51.15 152.31,51.15 152.23,51.07 152.23,50.47 152.15,50.4 152,50.4 151.93,50.47 151.93,51.07 151.85,51.15 151.45,51.15 151.39,51.09 151.39,50.92 151.45,50.87 151.57,50.87 151.62,50.82 151.62,50.47 151.55,50.4 151.39,50.4 151.32,50.47 151.32,50.59 151.24,50.67 v4(151.11,50.67) ; v4(150.98,24.19) 150.8,24.37 v1(150.66,24.37)
  BOTTOM w0.076: RD71.1 164.02,50.13 163.51,50.64 v3(163.51,50.59) ; UD3.M2 143.07,51.3 v3(142.72,50.95) ; UD2.M2 185.06,51.29 184.69,50.92 v3(184.65,50.92) ; UD1.M2 172.06,51.69 v3(172.06,51.71) ; v3(155.31,50.92) 155.7,51.3 UD4.M2
DDR_A_BS1: length 118.4
  IN3 w0.076: v3(148.34,51.69) 148.34,51.95 148.42,52.02 148.69,52.02 148.77,51.95 148.77,51.12 148.84,51.05 149.1,51.05 149.18,51.12 149.18,51.27 149.25,51.35 149.41,51.35 149.54,51.49 149.54,51.95 149.62,52.02 150.04,52.02 150.16,52.15 150.81,52.15 150.92,52.05 151.18,52.05 151.34,52.21 153.01,52.21 153.05,52.25 153.25,52.25 153.33,52.18 153.33,52 153.4,51.92 v4(153.61,51.92) 154.4,51.92 154.6,52.12 154.6,52.13 155.55,52.13 155.6,52.18 157.42,52.18 157.52,52.08 160.56,52.08 v3(160.94,51.7) ; v4(151.47,25.19) 151.47,25.27 149.49,27.25 149.49,28.02 ; v3(177.68,51.69) 177.85,51.69 177.93,51.61 177.93,51.12 178.01,51.05 178.25,51.05 178.33,51.12 178.33,51.27 178.4,51.35 178.74,51.35 179.15,51.76 179.58,51.76 179.66,51.83 179.66,51.95 179.74,52.02 179.89,52.02 179.96,51.95 179.96,51.83 180.04,51.76 180.19,51.76 180.27,51.83 180.27,51.95 180.35,52.02 181.04,52.02 181.14,52.13 182.74,52.13 v4(182.95,51.92) 183.64,51.92 183.82,52.1 185.19,52.1 185.27,52.18 185.68,52.18 185.76,52.1 186.83,52.1 186.85,52.08 189.06,52.08 v3(189.47,52.48)
  IN3 w0.165: v3(164.04,51.94) 164.04,53.55 164.21,53.71 164.87,53.71 165.03,53.55 165.03,53.05 164.65,52.67 164.65,51.58 164.34,51.26 164.34,47.85 164.01,47.52 164.01,45.41 162.99,44.4 162.99,44.23 162.99,43.94 161.91,42.87 160.39,42.87 159.82,42.3 157.91,42.3 156.4,40.78 153.6,40.78 153.43,40.95 153.2,40.95 152.96,40.72 152.96,40.48 153.06,40.39 153.06,40.15 152.83,39.92 152.59,39.92 152.5,40.02 152.26,40.02 152.03,39.78 152.03,39.55 152.13,39.45 152.13,39.22 151.89,38.99 151.66,38.99 151.56,39.08 151.33,39.08 151.09,38.85 151.09,38.62 151.19,38.52 151.19,38.29 150.96,38.05 150.72,38.05 150.63,38.15 150.39,38.15 150.16,37.91 150.16,37.68 150.21,37.63 150.21,37.4 149.98,37.17 149.64,37.17 149.49,37.01 149.49,28.02
  IN4 w0.076: v1(151.09,25.12) 151.17,25.19 151.45,25.19 151.47,25.17 v4(151.47,25.19) ; v4(182.95,51.92) 182.74,52.13 180.59,52.13 180.51,52.05 180.12,52.05 179.88,51.81 179.07,51.81 178.22,52.66 176.54,52.66 176.46,52.74 175.5,52.74 174.51,53.73 170.74,53.73 170.14,53.13 168.57,53.13 168.17,52.74 166.55,52.74 165.75,51.94 v3(164.04,51.94) 163.76,51.94 163.61,52.09 163.61,53.07 163.54,53.14 163.13,53.14 163.06,53.07 163.06,52.19 162.98,52.11 162.83,52.11 162.75,52.19 162.75,53.07 162.68,53.14 162.52,53.14 162.45,53.07 162.45,52.33 162.37,52.25 162.22,52.25 162.14,52.33 162.14,53.07 162.07,53.14 161.49,53.14 161.41,53.07 161.41,52.85 161.34,52.77 160.94,52.77 160.87,52.7 160.87,52.33 160.79,52.25 160.64,52.25 160.56,52.33 160.56,52.7 160.49,52.77 160.34,52.77 160.26,52.7 160.26,52.33 160.18,52.25 160.03,52.25 159.95,52.33 159.95,52.7 159.88,52.77 159.66,52.77 159.58,52.7 159.58,52.25 159.51,52.17 158.34,52.17 158.27,52.25 158.27,52.83 158.19,52.91 156.51,52.91 156.37,52.77 156.07,52.77 156.03,52.81 155.13,52.81 155.06,52.89 154.83,52.89 154.68,52.74 154.53,52.74 154.37,52.89 154.22,52.89 154.15,52.81 154.15,52.71 154.07,52.63 153.92,52.63 153.84,52.71 153.84,52.81 153.77,52.89 153.6,52.89 152.88,52.17 152.88,52.01 152.97,51.92 v4(153.61,51.92)
  BOTTOM w0.076: v3(189.47,52.48) 189.85,52.1 UD2.N8 ; v3(177.68,51.69) 177.67,51.69 UD1.N8 ; v3(164.04,51.94) 164.68,51.3 RD75.1 ; UD4.N8 160.54,52.1 v3(160.94,51.7) ; UD3.N8 148.33,51.69 v3(148.34,51.69)
DDR_A_BS2: length 119.2
  IN3 w0.076: v3(174.35,51.17) 174.35,50.74 174.5,50.59 178.7,50.59 179.08,50.97 179.47,50.97 179.55,51.05 v4(179.85,51.05) 183.07,51.05 183.42,51.4 184.38,51.4 184.52,51.26 185.4,51.26 185.48,51.33 v3(185.48,51.68) ; 153.53,28.02 153.53,27.14 153.77,26.9 153.77,26.6 152.99,25.83 152.99,24.28 152.68,23.97 152.68,22.36 152.59,22.27 v4(152.33,22.27) ; v3(144.9,51.14) 144.9,50.88 145.18,50.59 149.37,50.59 149.75,50.97 150.14,50.97 150.21,51.05 v4(150.51,51.05) 153.73,51.05 154.09,51.4 155.04,51.4 155.18,51.26 156.07,51.26 156.14,51.33 v3(156.14,51.68)
  IN3 w0.165: v3(166.39,50.2) 166.09,49.9 166.09,47.17 165.8,46.88 165.8,43.59 162.31,40.1 160.62,40.1 160.42,39.9 160.19,39.9 159.99,40.1 159.76,40.1 159.52,39.87 159.52,39.63 159.72,39.44 159.72,39.2 159.49,38.97 159.25,38.97 158.67,39.55 158.44,39.55 158.21,39.31 158.21,39.08 158.79,38.5 158.79,38.27 158.55,38.03 158.32,38.03 157.74,38.61 157.51,38.61 157.27,38.38 157.27,38.15 157.85,37.57 157.85,37.33 157.62,37.1 157.39,37.1 156.81,37.68 156.57,37.68 156.34,37.45 156.34,37.21 156.92,36.63 156.92,36.4 156.69,36.17 156.45,36.17 155.87,36.75 155.64,36.75 155.4,36.51 155.4,36.28 156.23,35.45 156.23,35.21 155.91,34.89 154.58,34.89 154.42,34.72 154.42,34.39 154.58,34.23 155.6,34.23 155.77,34.06 155.77,33.73 155.6,33.57 154.58,33.57 154.42,33.4 154.42,33.07 154.58,32.91 155.6,32.91 155.77,32.74 155.77,32.41 155.6,32.25 154.44,32.25 154.32,32.12 154.32,31.71 154.44,31.59 155.51,31.59 155.64,31.46 155.64,31.06 155.51,30.93 154.14,30.93 154.01,30.8 154.01,30.35 154.14,30.22 154.43,30.22 154.55,30.09 154.55,29.86 154.32,29.62 154.09,29.62 154.04,29.67 153.81,29.67 153.57,29.44 153.57,29.2 153.62,29.16 153.62,28.92 153.53,28.83 153.53,28.02
  IN4 w0.076: v4(150.51,51.05) 150.77,51.3 153.71,51.3 154.33,50.68 154.85,50.68 155.17,50.36 156.85,50.36 157.95,51.46 160.31,51.46 160.61,51.16 164.28,51.16 164.35,51.08 164.35,50.96 164.43,50.88 164.58,50.88 164.66,50.96 164.66,51.08 164.74,51.16 164.89,51.16 164.96,51.08 164.96,51.06 165.04,50.98 165.19,50.98 165.27,51.06 165.27,51.08 165.35,51.16 165.72,51.16 165.8,51.08 165.8,50.28 165.87,50.2 v3(166.39,50.2) 166.79,50.2 166.86,50.28 166.86,51.11 166.94,51.19 168.71,51.19 168.78,51.26 168.78,51.85 168.86,51.92 169.01,51.92 169.09,51.85 169.09,51.26 169.17,51.19 169.32,51.19 169.39,51.26 169.39,51.85 169.47,51.92 169.62,51.92 169.7,51.85 169.7,51.26 169.78,51.19 169.93,51.19 170,51.26 170,51.78 170.08,51.86 170.23,51.86 170.31,51.78 170.31,51.43 170.37,51.36 173.84,51.36 174.04,51.57 175.03,51.57 175.69,50.91 179.71,50.91 v4(179.85,51.05) ; v1(152.39,22.87) 152.33,22.81 v4(152.33,22.27)
  BOTTOM w0.076: UD4.M3 156.52,51.3 v3(156.14,51.68) ; RD73.1 166.57,50.39 v3(166.39,50.2) ; v3(185.48,51.68) 185.86,51.3 UD2.M3 ; UD1.M3 173.38,51.17 v3(174.35,51.17) ; v3(144.9,51.14) 144.74,51.3 UD3.M3
DDR_A_CAS#: length 145
  IN3 w0.076: v3(187.08,49.11) 187.08,48.84 185.86,47.63 185.86,47.45 185.74,47.33 184.9,47.33 184.33,46.75 184.33,46.51 184.2,46.39 183.97,46.39 183.82,46.53 183.67,46.53 183.59,46.46 183.59,46.16 183.52,46.08 183.36,46.08 183.29,46.16 183.29,46.91 183.21,46.98 183.06,46.98 182.98,46.91 182.98,45.87 182.91,45.8 182.75,45.8 182.68,45.87 182.68,46.3 182.6,46.37 182.45,46.37 182.37,46.3 182.37,45.98 182.3,45.9 182.14,45.9 182.07,45.98 182.07,46.3 181.99,46.37 181.84,46.37 181.76,46.3 181.76,46.16 181.69,46.08 v4(181.28,46.08) 180.81,46.08 180.74,46.16 180.74,46.42 180.66,46.5 180.45,46.5 180.38,46.42 180.38,45.88 180.3,45.8 180.15,45.8 180.07,45.88 180.07,46.42 180,46.5 179.84,46.5 179.77,46.42 179.77,45.88 179.69,45.8 179.54,45.8 179.46,45.88 179.46,46.42 179.39,46.5 178.37,46.5 178.11,46.76 178.11,46.95 177.01,48.05 175.75,48.05 174.67,49.13 174.18,49.13 174.05,49.25 v3(173.69,49.25) ; v4(150.83,22.97) 150.64,22.97 150.29,23.31 150.29,23.76 146.86,27.18 146.86,28.02 ; v3(157.74,49.11) 157.74,48.85 157.58,48.68 156.12,48.68 155.99,48.56 155.99,48.22 156.12,48.1 156.51,48.1 156.58,48.02 156.58,46.54 156.13,46.08 154.64,46.08 154.56,46.16 154.56,46.33 154.47,46.42 154.35,46.42 154.26,46.33 154.26,46.16 154.18,46.08 154.03,46.08 153.95,46.16 153.95,46.65 153.88,46.73 153.72,46.73 153.65,46.65 153.65,46.14 153.56,46.05 153.43,46.05 153.29,46.19 153.13,46.19 153.01,46.08 v4(151.95,46.08) 149.74,46.08 149.31,46.51 146.63,46.51 146.32,46.82 146.32,47.29 146.23,47.38 146.23,47.49 146.46,47.72 146.46,47.85 146.38,47.94 146.25,47.94 146.02,47.7 145.91,47.7 145.8,47.81 145.8,47.92 146.11,48.23 146.11,48.34 146,48.45 145.9,48.45 145.58,48.14 145.48,48.14 145.37,48.24 145.37,48.35 145.68,48.66 145.68,48.77 145.57,48.88 144.73,48.88 v3(144.35,49.25)
  IN3 w0.165: v3(161.01,46.12) 161.01,46.53 160.87,46.68 159.22,46.68 158.98,46.43 158.74,46.43 158.49,46.68 158.26,46.68 158.03,46.45 158.03,46.22 158.27,45.97 158.27,45.73 157.34,44.8 154.16,44.8 154.04,44.67 154.04,44.28 153.93,44.18 151.05,44.18 148.63,41.76 148.63,41.52 148.91,41.24 148.91,41.01 146.86,38.97 146.86,28.02
  IN4 w0.076: v4(151.95,46.08) 150.96,46.08 150.89,46.16 150.89,46.59 150.96,46.66 152.11,46.66 152.23,46.54 152.23,46.37 152.36,46.25 152.49,46.25 152.61,46.37 152.61,46.54 152.74,46.66 153.15,46.66 153.25,46.56 153.25,46.3 153.3,46.25 153.73,46.25 153.86,46.12 153.86,45.86 153.95,45.78 154.38,45.78 154.46,45.7 154.46,45.02 154.53,44.95 154.76,44.95 154.84,45.02 154.84,45.48 154.92,45.56 155.07,45.56 155.14,45.48 155.14,45.02 155.22,44.95 155.49,44.95 155.57,45.02 155.57,45.47 155.64,45.55 155.8,45.55 155.87,45.47 155.87,45.02 155.95,44.95 156.1,44.95 156.18,45.02 156.18,45.47 156.25,45.55 156.41,45.55 156.48,45.47 156.48,45.02 156.56,44.95 157.26,44.95 157.33,45.02 157.33,45.38 157.41,45.46 157.66,45.46 157.73,45.38 157.73,45.06 157.81,44.99 157.96,44.99 158.04,45.06 158.04,45.38 158.12,45.46 158.27,45.46 158.34,45.38 158.34,45.06 158.42,44.99 158.57,44.99 158.65,45.06 158.65,45.38 158.72,45.46 158.88,45.46 158.95,45.38 158.95,45.06 159.03,44.99 159.18,44.99 159.26,45.06 159.26,45.38 159.33,45.46 159.49,45.46 159.56,45.38 159.56,45.06 159.64,44.99 159.79,44.99 159.87,45.06 159.87,45.38 159.94,45.46 160.1,45.46 160.17,45.38 160.17,45.06 160.25,44.99 160.4,44.99 160.48,45.06 160.48,45.38 160.55,45.46 160.89,45.46 160.95,45.41 160.95,45.15 161.02,45.08 162.27,45.08 162.39,45.2 162.39,45.62 162.27,45.74 162.11,45.74 161.99,45.62 161.99,45.46 161.86,45.33 161.63,45.33 161.5,45.46 161.5,45.56 161.38,45.69 161.14,45.69 161.01,45.81 v3(161.01,46.12) 162.44,46.12 162.65,45.92 162.65,44.94 162.7,44.89 162.85,44.89 162.93,44.96 162.93,45.7 163.02,45.79 163.14,45.79 163.23,45.7 163.23,44.96 163.31,44.89 163.46,44.89 163.54,44.96 163.54,45.42 163.63,45.51 163.75,45.51 163.84,45.42 163.84,44.96 163.92,44.89 164.12,44.89 164.2,44.96 164.2,45.22 164.29,45.31 164.42,45.31 164.5,45.22 164.5,44.96 164.83,44.63 168.46,44.63 168.67,44.84 174.45,44.84 175.29,45.68 178.64,45.68 179.04,46.08 v4(181.28,46.08) ; v1(151.09,23.62) 151.09,23.27 150.83,23 v4(150.83,22.97)
  BOTTOM w0.076: v3(144.35,49.25) 143.92,49.69 UD3.K3 ; v3(157.74,49.11) 157.15,49.7 UD4.K3 ; UD2.K3 186.18,49.38 186.81,49.38 v3(187.08,49.11) ; UD1.K3 173.25,49.69 173.69,49.26 v3(173.69,49.25)
  BOTTOM w0.17: v3(161.01,46.12) 161.4,46.12 161.87,45.65 161.87,44.56 RD67.1
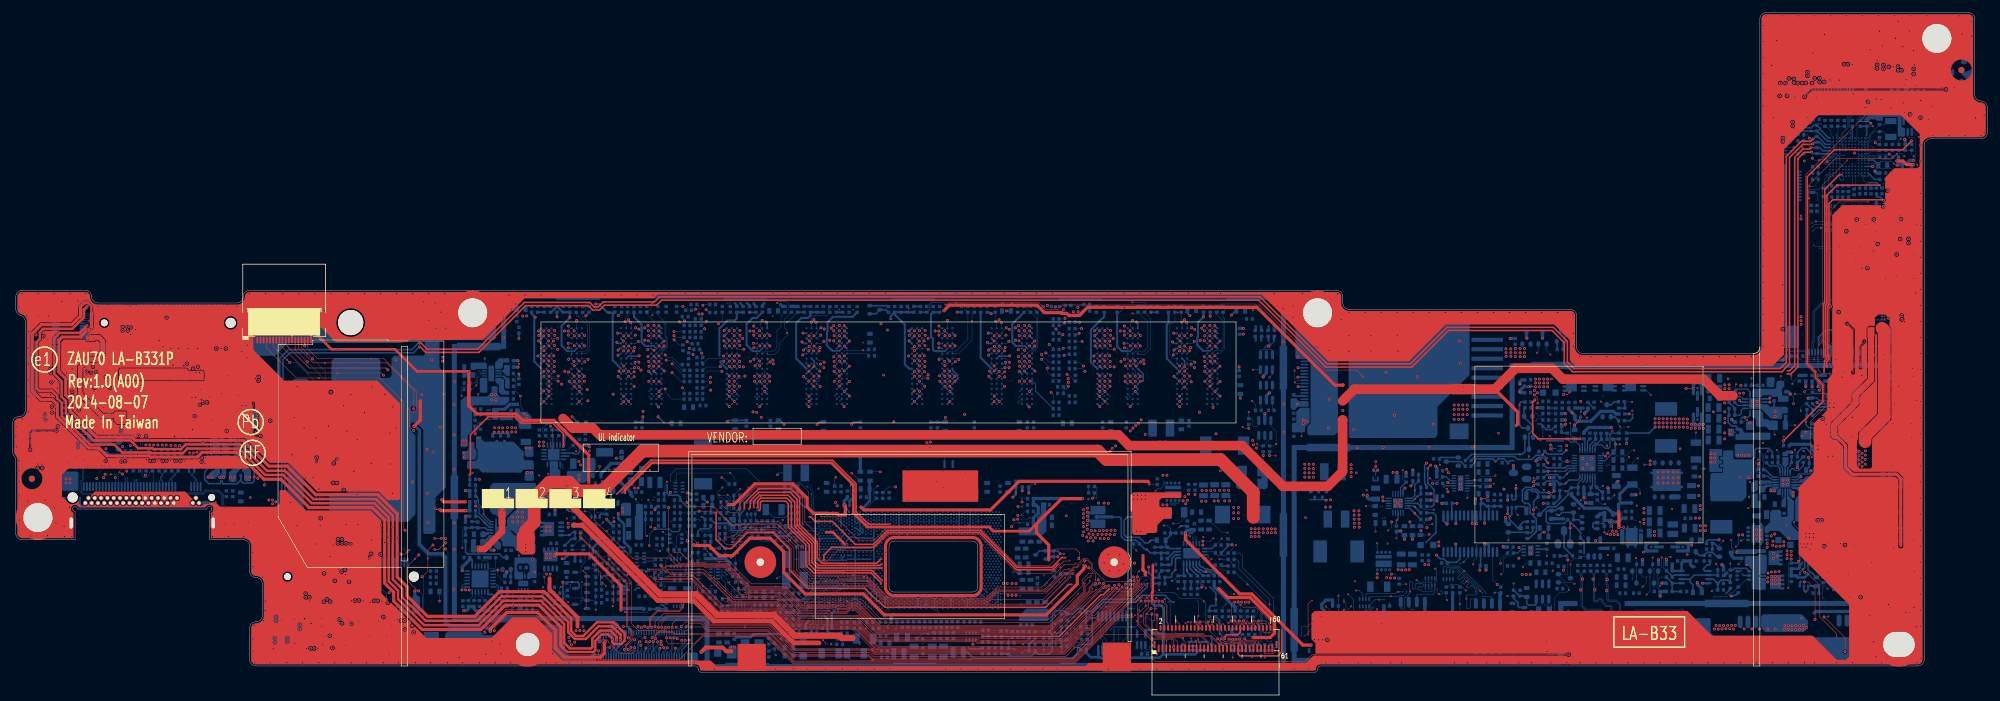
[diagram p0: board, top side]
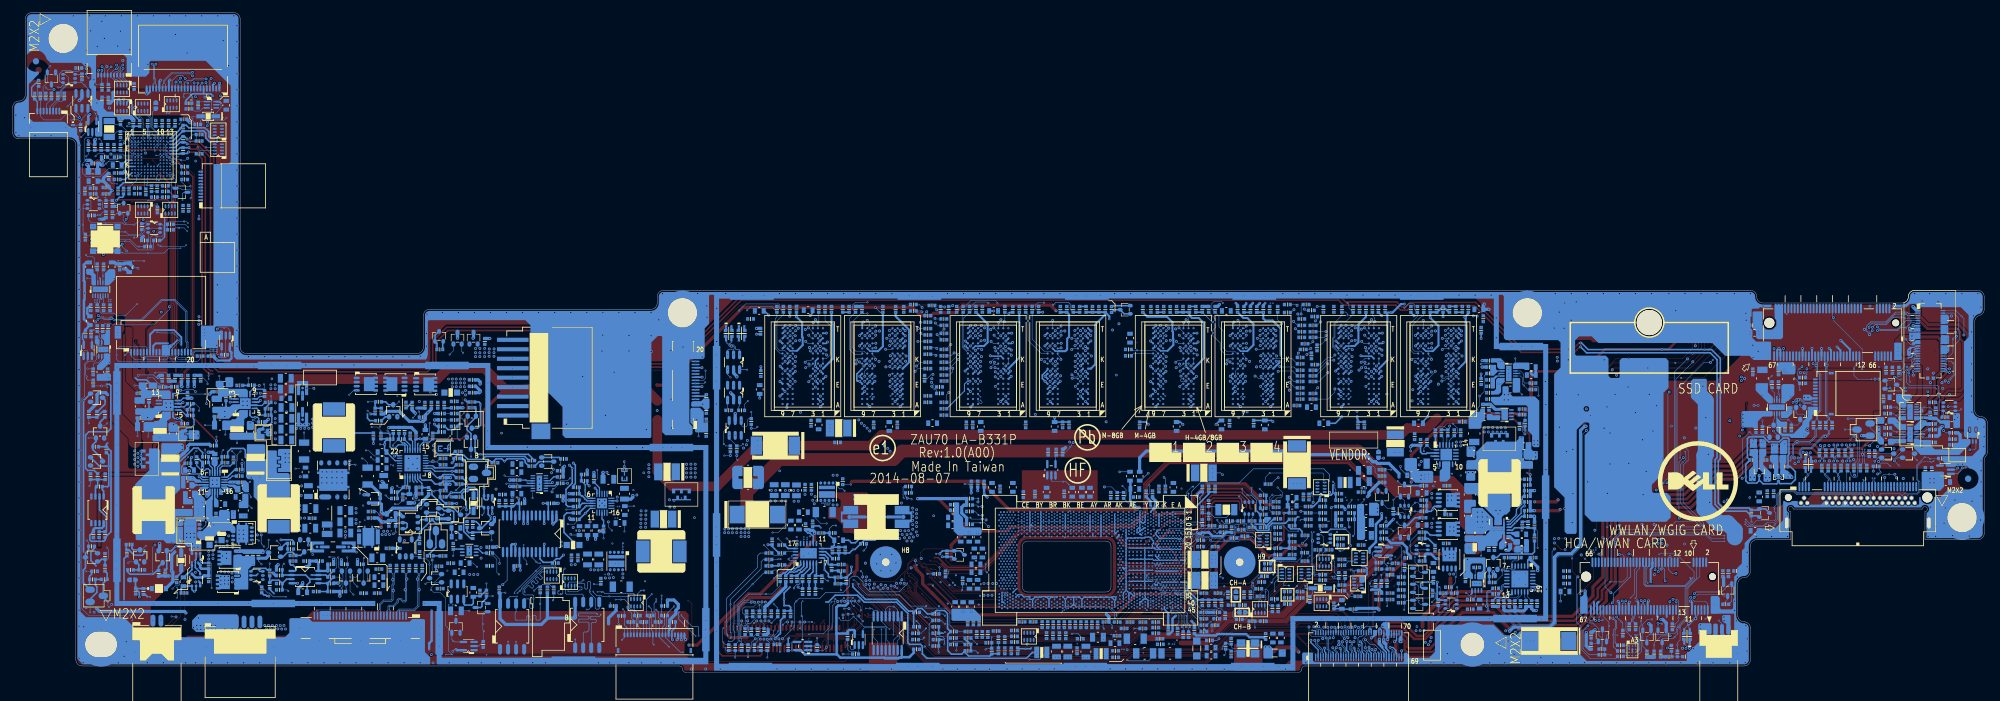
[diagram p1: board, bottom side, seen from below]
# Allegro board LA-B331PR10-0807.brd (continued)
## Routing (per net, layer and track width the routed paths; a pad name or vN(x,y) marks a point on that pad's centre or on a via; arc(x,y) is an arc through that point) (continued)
DDR_A_CKE0: length 120.6
  IN3 w0.076: v3(178.95,49.46) 178.95,49.27 179.02,49.2 179.22,49.2 179.4,49.38 179.53,49.38 179.69,49.22 179.93,49.22 180.01,49.29 180.01,49.34 180.08,49.42 180.19,49.42 180.33,49.28 180.5,49.28 180.64,49.42 180.8,49.42 180.9,49.32 181.14,49.32 181.25,49.42 181.32,49.42 181.4,49.34 181.4,48.84 181.48,48.76 181.63,48.76 181.71,48.84 181.71,49.34 181.78,49.42 181.93,49.42 182.01,49.34 182.01,48.84 182.09,48.76 182.24,48.76 182.32,48.84 182.32,49.34 182.39,49.42 182.54,49.42 182.62,49.34 182.62,48.99 182.7,48.91 182.85,48.91 182.92,48.99 182.92,49.12 183,49.19 v4(183.21,49.19) 183.44,49.42 184.03,49.42 184.03,49.42 184.29,49.67 185.43,49.67 186.34,50.58 189.79,50.58 v3(190.25,50.13) ; v3(149.71,49.55) 149.67,49.5 149.67,49.24 149.74,49.17 149.92,49.17 150.09,49.33 150.24,49.33 150.36,49.22 150.6,49.22 150.67,49.29 150.67,49.34 150.75,49.42 151.99,49.42 152.07,49.34 152.07,49.1 152.15,49.01 152.28,49.01 152.37,49.1 152.37,49.34 152.45,49.42 152.6,49.42 152.68,49.34 152.68,48.84 152.75,48.76 152.9,48.76 152.98,48.84 152.98,49.34 153.06,49.42 153.21,49.42 153.28,49.34 153.28,48.99 153.36,48.91 153.51,48.91 153.59,48.99 153.59,49.12 153.67,49.19 v4(153.88,49.19) 154.64,49.19 154.93,49.48 155.9,49.48 156.49,50.08 157.01,50.08 157.58,50.64 160.4,50.64 v3(160.92,50.13) ; 157.39,23.26 157.27,23.14 153.85,23.14 v4(153.74,23.25)
  IN3 w0.165: 157.39,23.26 157.72,23.59 160.12,23.59 160.45,23.26 160.68,23.26 160.92,23.49 160.92,23.73 160.78,23.86 160.78,24.04 161.07,24.33 161.25,24.33 161.66,23.92 161.89,23.92 162.13,24.15 162.13,24.38 161.63,24.88 161.63,25.11 161.87,25.35 162.1,25.35 162.6,24.85 162.83,24.85 163.06,25.08 163.06,25.32 162.57,25.81 162.57,26.05 162.8,26.28 163.03,26.28 163.53,25.78 163.76,25.78 164,26.02 164,26.25 163.5,26.75 163.5,26.98 163.73,27.22 163.97,27.22 164.46,26.72 164.7,26.72 164.93,26.95 164.93,27.19 164.43,27.68 164.43,27.92 164.67,28.15 164.9,28.15 165.4,27.65 165.63,27.65 165.87,27.89 165.87,28.12 165.37,28.62 165.37,28.85 165.6,29.08 165.84,29.08 166.33,28.59 166.57,28.59 166.8,28.82 166.8,29.05 166.3,29.55 166.3,29.78 166.54,30.02 166.77,30.02 167.27,29.52 167.5,29.52 167.73,29.76 167.73,29.99 167.24,30.49 167.24,30.72 167.56,31.04 167.79,31.04 168.29,30.55 168.52,30.55 168.76,30.78 168.76,31.01 168.26,31.51 168.26,31.74 170.86,34.34 170.86,34.58 170.63,34.81 170.63,35.04 171.68,36.09 171.68,40.73 170.61,41.8 170.61,47.48 169.58,48.51 v3(169.45,48.51)
  IN4 w0.076: v4(153.74,23.25) 153.68,23.25 153.34,22.9 v1(153.34,22.87) ; v4(153.88,49.19) 155.15,49.19 155.57,48.77 158.58,48.77 159.22,48.13 162.42,48.13 162.73,47.82 166.76,47.82 167.35,48.4 168.98,48.4 169.09,48.51 v3(169.45,48.51) 169.71,48.51 170.09,48.89 173.97,48.89 174.05,48.96 174.05,49.26 174.13,49.34 174.28,49.34 174.35,49.26 174.35,48.96 174.43,48.89 174.58,48.89 174.66,48.96 174.66,49.28 174.74,49.35 174.89,49.35 174.96,49.28 174.96,48.96 175.04,48.89 175.64,48.89 175.72,48.96 178.07,48.96 178.59,48.44 179.1,48.44 180.41,49.75 182.66,49.75 v4(183.21,49.19)
  BOTTOM w0.076: UD3.K9 149.56,49.7 v3(149.71,49.55) ; v3(178.95,49.46) 178.71,49.7 UD1.K9 ; UD2.K9 190.66,49.72 v3(190.25,50.13) ; v3(160.92,50.13) 160.92,50.06 161.27,49.7 UD4.K9 ; v3(169.45,48.51) 168.84,49.12 RD61.1
DDR_A_CKE1: length 123.3
  IN3 w0.076: v3(149.18,49.2) 149.02,49.2 148.86,49.05 148.86,48.8 149.15,48.52 150.11,48.52 150.19,48.6 150.19,48.99 150.26,49.07 150.42,49.07 150.49,48.99 150.49,48.58 150.57,48.51 150.72,48.51 150.8,48.58 150.8,49.05 150.87,49.13 151.02,49.13 151.1,49.05 151.1,48.6 151.18,48.52 151.33,48.52 151.41,48.6 151.41,49.08 151.48,49.15 151.63,49.15 151.71,49.08 151.71,48.68 151.79,48.61 v4(153.61,48.61) 154.27,48.61 155,49.33 155.96,49.33 156.17,49.54 156.56,49.92 157.08,49.92 157.64,50.49 159.24,50.49 159.87,49.86 159.87,49.86 160.08,49.64 160.56,49.64 v3(160.92,49.28) ; 157.16,23.62 154.12,23.62 v4(154.11,23.61) ; v3(190.25,49.28) 189.89,49.64 189.42,49.64 189.2,49.86 189.2,49.86 188.73,50.33 186.29,50.33 185.5,49.54 185.45,49.48 184.31,49.48 184.09,49.26 183.73,49.26 183.08,48.61 v4(182.95,48.61) 181.12,48.61 181.05,48.68 181.05,49.08 180.97,49.15 180.82,49.15 180.74,49.08 180.74,48.6 180.66,48.52 180.51,48.52 180.44,48.6 180.44,49.05 180.36,49.13 180.21,49.13 180.13,49.05 180.13,48.58 180.06,48.51 179.9,48.51 179.83,48.58 179.83,48.99 179.75,49.07 179.6,49.07 179.52,48.99 179.52,48.6 179.45,48.52 178.48,48.52 178.2,48.8 178.2,49.05 178.32,49.17 v3(178.51,49.17)
  IN3 w0.165: v3(169.68,47.67) 170.27,47.08 170.27,41.58 171.34,40.52 171.34,36.23 169.87,34.77 169.87,34.54 170.06,34.35 170.06,34.11 169.83,33.88 169.59,33.88 169.41,34.07 169.17,34.07 168.94,33.83 168.94,33.6 169.13,33.41 169.13,33.18 168.89,32.95 168.66,32.95 168.47,33.13 168.24,33.13 168,32.9 168,32.67 168.19,32.48 168.19,32.25 167.96,32.01 167.72,32.01 167.54,32.2 167.3,32.2 167.07,31.97 167.07,31.73 167.26,31.55 167.26,31.31 167.02,31.08 166.79,31.08 166.6,31.27 166.37,31.27 166.14,31.03 166.14,30.8 166.32,30.61 166.32,30.38 166.09,30.14 165.86,30.14 165.67,30.33 165.44,30.33 165.14,30.03 165.14,29.8 165.37,29.57 165.37,29.33 165.13,29.1 164.9,29.1 164.32,29.68 164.09,29.68 163.85,29.45 163.85,29.21 164.43,28.63 164.43,28.4 164.2,28.17 163.97,28.17 163.39,28.75 163.15,28.75 162.92,28.51 162.92,28.28 163.5,27.7 163.5,27.47 163.27,27.23 163.03,27.23 162.45,27.81 162.22,27.81 161.98,27.58 161.98,27.35 162.56,26.77 162.56,26.53 162.33,26.3 162.1,26.3 161.52,26.88 161.28,26.88 161.05,26.64 161.05,26.41 161.63,25.83 161.63,25.6 161.4,25.36 161.16,25.36 160.58,25.94 160.35,25.94 160.12,25.71 160.12,25.48 160.7,24.9 160.7,24.66 160.46,24.43 160.23,24.43 159.39,25.27 158.81,25.27 157.16,23.62
  IN4 w0.076: v4(153.61,48.61) 154.04,48.19 156.48,48.19 156.9,48.6 158.48,48.6 158.96,48.13 158.96,47.54 159.16,47.33 161.96,47.33 162.29,47.67 v3(169.68,47.67) 170.58,48.57 171.26,48.57 171.79,48.04 174.62,48.04 174.7,48.11 174.7,48.56 174.78,48.63 174.93,48.63 175.01,48.56 175.01,48.11 175.08,48.04 175.23,48.04 175.31,48.11 175.31,48.56 175.39,48.63 175.54,48.63 175.62,48.56 175.62,48.11 175.69,48.04 177.08,48.04 177.18,48.14 177.18,48.2 177.27,48.29 177.39,48.29 177.48,48.2 177.48,48.14 177.58,48.04 178.91,48.04 180.48,49.6 182.31,49.6 182.95,48.96 v4(182.95,48.61) ; v4(154.11,23.61) 153.58,23.61 v1(153.34,23.37)
  BOTTOM w0.076: v3(190.25,49.28) 190.63,48.9 UD2.J9 ; UD4.J9 161.29,48.9 v3(160.92,49.28) ; RD77.1 169.25,48.1 v3(169.68,47.67) ; v3(178.51,49.17) 178.24,48.9 UD1.J9 ; v3(149.18,49.2) 148.88,48.9 UD3.J9
DDR_A_CS0#: length 124.8
  IN3 w0.076: 147.78,28.02 147.78,27.26 150.02,25.01 150.02,24.48 v4(150.55,23.95) ; v3(156.06,50.92) 156.27,50.71 156.27,50.29 155.77,49.79 154.81,49.79 154.67,49.65 154.18,49.65 154.1,49.73 150.75,49.73 150.23,50.25 v4(149.9,50.25) 149.73,50.25 149.57,50.09 145.02,50.09 144.58,50.53 143.32,50.53 142.91,50.12 v3(142.73,50.12) ; v3(172.06,50.12) 172.24,50.12 172.65,50.53 173.92,50.53 174.35,50.09 178.91,50.09 179.06,50.25 v4(179.24,50.25) 179.56,50.25 180.08,49.73 183.91,49.73 184.16,49.98 185.3,49.98 185.61,50.29 185.61,50.85 185.54,50.92 v3(185.4,50.92)
  IN3 w0.165: v3(162.82,49.57) 162.55,49.29 162.55,46.22 161.61,45.28 159.01,45.28 157.66,43.92 156.16,43.92 155.56,43.32 152.52,43.32 152.28,43.08 152.28,42.85 152.54,42.6 152.54,42.36 152.31,42.13 152.07,42.13 151.82,42.38 151.58,42.38 151.35,42.15 151.35,41.92 151.61,41.66 151.61,41.43 151.37,41.19 151.14,41.19 150.88,41.45 150.65,41.45 150.15,40.95 150.15,40.69 150.29,40.56 150.29,40.31 149.35,39.37 149.24,39.25 149,39.25 148.87,39.39 148.64,39.39 148.4,39.15 148.4,38.92 148.54,38.79 148.54,38.55 147.78,37.8 147.78,28.02
  IN4 w0.076: v4(150.55,23.95) 150.23,24.28 v1(150.23,24.62) ; v4(149.9,50.25) 149.9,50.04 150.06,49.89 150.58,49.89 150.81,49.66 150.92,49.66 151,49.59 151,49.28 151.07,49.2 151.23,49.2 151.3,49.28 151.3,49.59 151.38,49.66 151.53,49.66 151.61,49.59 151.61,49.28 151.68,49.2 151.84,49.2 151.91,49.28 151.91,49.59 151.99,49.66 152.14,49.66 152.22,49.59 152.22,49.28 152.29,49.2 152.45,49.2 152.52,49.28 152.52,49.59 152.6,49.66 152.75,49.66 152.83,49.59 152.83,49.28 152.9,49.2 153.06,49.2 153.13,49.28 153.13,49.59 153.21,49.66 154.07,49.66 154.17,49.57 155.02,49.57 155.1,49.64 155.1,49.83 155.17,49.9 155.32,49.9 155.4,49.83 155.4,49.74 155.48,49.66 155.63,49.66 155.71,49.74 155.71,49.83 155.78,49.9 155.93,49.9 156.01,49.83 156.01,49.74 156.09,49.66 156.24,49.66 156.31,49.74 156.31,49.83 156.39,49.9 156.54,49.9 156.62,49.83 156.62,49.74 156.7,49.66 156.85,49.66 156.92,49.74 156.92,49.83 157,49.9 157.15,49.9 157.23,49.83 157.23,49.74 157.31,49.66 158.1,49.66 158.17,49.74 158.17,50.26 158.25,50.34 158.77,50.34 158.85,50.26 158.85,50.13 158.77,50.06 158.55,50.06 158.48,49.98 158.48,49.7 158.55,49.62 159.42,49.62 159.5,49.7 159.5,49.88 159.58,49.96 159.73,49.96 159.8,49.88 159.8,49.7 159.88,49.62 160.27,49.62 160.35,49.7 160.35,49.81 160.43,49.89 160.58,49.89 160.66,49.81 160.66,49.7 160.73,49.62 161.2,49.62 161.27,49.54 161.27,48.82 161.35,48.74 161.55,48.74 161.63,48.82 161.63,49.7 161.71,49.78 161.87,49.78 161.95,49.7 161.95,48.84 162.02,48.76 162.25,48.76 162.33,48.84 162.33,49.92 162.41,50 162.75,50 162.82,49.92 v3(162.82,49.57) 163.28,49.57 163.65,49.2 163.79,49.2 163.86,49.28 163.86,49.34 163.94,49.42 164.09,49.42 164.17,49.34 164.17,49.03 164.24,48.95 164.4,48.95 164.47,49.03 164.47,49.34 164.55,49.42 164.7,49.42 164.78,49.34 164.78,49.03 164.85,48.95 165.01,48.95 165.08,49.03 165.08,49.34 165.16,49.42 165.31,49.42 165.39,49.34 165.39,49 165.46,48.93 165.61,48.93 165.69,49 165.69,49.34 165.77,49.42 165.92,49.42 166,49.34 166,49 166.07,48.93 166.22,48.93 166.3,49 166.3,49.34 166.38,49.42 167.14,49.42 168.34,50.61 169.55,50.61 169.62,50.54 169.62,50.35 169.7,50.27 169.85,50.27 169.93,50.35 169.93,50.54 170,50.61 170.16,50.61 170.23,50.54 170.23,50.39 170.31,50.31 170.46,50.31 170.54,50.39 170.54,50.54 170.61,50.61 173.72,50.61 173.92,50.41 174.81,50.41 174.89,50.34 174.89,50.13 174.97,50.06 175.12,50.06 175.19,50.13 175.19,50.34 175.27,50.41 175.54,50.41 175.61,50.34 175.61,50.14 175.69,50.07 175.84,50.07 175.92,50.14 175.92,50.34 175.99,50.41 176.15,50.41 176.22,50.34 176.22,50.14 176.3,50.07 176.45,50.07 176.53,50.14 176.53,50.34 176.6,50.41 176.76,50.41 176.83,50.34 176.83,50.14 176.91,50.07 177.06,50.07 177.14,50.14 177.14,50.34 177.21,50.41 177.37,50.41 177.44,50.34 177.44,50.14 177.52,50.07 177.67,50.07 177.75,50.14 177.75,50.34 177.82,50.41 177.98,50.41 178.05,50.34 178.05,50.14 178.13,50.07 178.28,50.07 178.36,50.14 178.36,50.34 178.43,50.41 178.58,50.41 178.66,50.34 178.66,50.32 178.74,50.25 178.92,50.25 v4(179.24,50.25)
  BOTTOM w0.076: v3(162.82,49.57) 164.3,48.1 RD65.1 ; UD3.L2 143.11,50.5 v3(142.73,50.12) ; UD1.L2 172.45,50.5 v3(172.06,50.12) ; v3(156.06,50.92) 156.06,50.84 UD4.L2 ; v3(185.4,50.92) 185.4,50.84 UD2.L2
DDR_A_CS1#: length 126.3
  IN3 w0.076: v3(171.11,50.1) 171.57,50.1 172.14,50.68 173.98,50.68 174.39,50.27 178.82,50.27 179.11,50.56 179.8,50.56 v4(179.95,50.41) 179.95,50.07 180.12,49.9 180.24,49.9 180.31,49.97 180.31,50.27 180.38,50.35 180.54,50.35 180.61,50.27 180.61,49.95 180.69,49.88 180.84,49.88 180.92,49.95 180.92,50.32 180.99,50.4 181.14,50.4 181.22,50.32 181.22,49.95 181.3,49.88 181.45,49.88 181.53,49.95 181.53,50.32 181.6,50.4 181.75,50.4 181.83,50.32 181.83,49.95 181.91,49.88 182.06,49.88 182.14,49.95 182.14,50.25 182.21,50.32 182.36,50.32 182.44,50.25 182.44,49.95 182.52,49.88 182.72,49.88 182.8,49.95 182.8,50.12 182.87,50.2 183.03,50.2 183.1,50.12 183.1,49.95 183.18,49.88 183.84,49.88 184.2,50.23 184.2,50.46 184.12,50.54 183.76,50.54 183.68,50.46 v3(183.68,50.27) ; v3(154.45,50.21) 154.45,50.4 154.53,50.47 154.79,50.47 154.86,50.4 154.86,50.06 154.61,49.8 154.24,49.8 154.16,49.88 153.84,49.88 153.77,49.95 153.77,50.12 153.69,50.2 153.54,50.2 153.46,50.12 153.46,49.95 153.39,49.88 153.18,49.88 153.11,49.95 153.11,50.25 153.03,50.32 152.88,50.32 152.8,50.25 152.8,49.95 152.72,49.88 152.57,49.88 152.5,49.95 152.5,50.32 152.42,50.4 152.27,50.4 152.19,50.32 152.19,49.95 152.11,49.88 151.96,49.88 151.89,49.95 151.89,50.32 151.81,50.4 151.66,50.4 151.58,50.32 151.58,49.95 151.5,49.88 151.35,49.88 151.28,49.95 151.28,50.27 151.2,50.35 151.05,50.35 150.97,50.27 150.97,49.97 150.9,49.9 150.79,49.9 150.62,50.07 v4(150.62,50.41) 150.46,50.56 149.77,50.56 149.48,50.27 145.05,50.27 144.65,50.68 143.06,50.68 142.92,50.54 142.56,50.54 142.12,50.1 v3(141.78,50.1) ; 147.44,27.97 147.44,26.98 149.53,24.88 v4(149.71,24.88)
  IN3 w0.165: v3(162.82,50.34) 162.82,50.82 162.7,50.94 162.32,50.94 162.19,50.82 162.19,47.34 162.06,47.21 161.38,47.21 161.25,47.08 161.25,46.78 161.38,46.65 162.01,46.65 162.14,46.53 162.14,46.23 162.01,46.11 161.78,46.11 161.64,45.97 161.64,45.8 161.47,45.62 158.76,45.62 157.45,44.32 154.98,44.32 154.37,43.71 151.85,43.71 151.71,43.85 151.53,43.85 151.25,43.56 151.25,43.38 151.58,43.05 151.58,42.87 151.28,42.58 151.11,42.58 150.79,42.9 150.61,42.9 150.32,42.61 150.32,42.43 150.64,42.11 150.64,41.98 150.21,41.54 150.07,41.54 149.83,41.78 149.65,41.78 149.37,41.49 149.37,41.31 149.6,41.07 149.6,40.84 149.45,40.69 149.45,40.45 149.55,40.35 149.55,40.12 149.32,39.89 149.08,39.89 148.98,39.99 148.75,39.99 147.44,38.67 147.44,27.97
  IN4 w0.076: v4(149.71,24.88) 149.85,25.03 150.14,25.03 v1(150.23,25.12) ; v4(179.95,50.41) 179.58,50.41 179.43,50.56 174.03,50.56 173.82,50.77 168.27,50.77 168.02,50.52 167.92,50.52 167.82,50.61 167.71,50.61 167.61,50.51 167.61,50.4 167.7,50.3 167.7,50.2 167.12,49.61 163.85,49.61 163.78,49.69 163.78,50.14 163.7,50.22 163.51,50.22 163.43,50.14 163.43,49.8 163.36,49.73 163.18,49.73 163.1,49.8 163.1,50.26 163.03,50.34 v3(162.82,50.34) 162.36,50.34 162.28,50.41 162.28,50.7 162.2,50.78 162.05,50.78 161.98,50.7 161.98,50 161.9,49.93 161.75,49.93 161.67,50 161.67,50.7 161.6,50.78 161.44,50.78 161.37,50.7 161.37,50.41 161.29,50.34 161.19,50.34 161.04,50.49 159.88,50.49 159.8,50.41 159.8,50.28 159.72,50.21 159.57,50.21 159.49,50.28 159.49,50.41 159.42,50.49 158.11,50.49 158.03,50.56 158.03,50.77 157.96,50.84 157.8,50.84 157.73,50.77 157.73,50.56 157.65,50.49 157.41,50.49 156.98,50.06 155,50.06 154.66,49.72 154.23,49.72 154.14,49.81 153.53,49.81 153.41,49.94 153.41,50.17 153.33,50.25 153.18,50.25 153.1,50.17 153.1,49.9 153.03,49.82 152.87,49.82 152.8,49.9 152.8,50.17 152.72,50.25 152.57,50.25 152.49,50.17 152.49,49.9 152.42,49.82 152.26,49.82 152.19,49.9 152.19,50.17 152.11,50.25 151.96,50.25 151.88,50.17 151.88,49.9 151.81,49.82 151.65,49.82 151.58,49.9 151.58,50.17 151.5,50.25 151.35,50.25 151.27,50.17 151.27,49.94 151.2,49.86 150.9,49.86 150.82,49.94 150.82,49.97 150.75,50.04 150.3,50.04 150.22,50.12 150.22,50.34 150.3,50.41 v4(150.62,50.41)
  BOTTOM w0.076: v3(141.78,50.1) 142.17,50.5 UD3.L1 ; UD2.L1 183.91,50.5 v3(183.68,50.27) ; v3(171.11,50.1) 171.51,50.5 UD1.L1 ; v3(162.82,50.34) 164.04,49.12 RD79.1 ; UD4.L1 154.53,50.5 154.46,50.42 154.46,50.21 v3(154.45,50.21)
DDR_A_D0: length 41.8
  IN1 w0.122: v4(154.96,20.53) 155.33,20.16 156.79,20.16 156.97,20.34 157.44,20.34 158.44,21.34 158.44,21.4 162.53,25.49 162.53,29.03 167.23,33.73 167.41,33.73 167.72,33.41 167.93,33.41 168.08,33.57 168.08,33.77 167.77,34.09 167.77,34.27 168.03,34.53 168.21,34.53 168.54,34.21 168.86,34.21 169.34,34.69 169.52,34.69 169.92,34.28 170.1,34.28 175.69,39.87 175.69,43.76 176.43,44.51 176.43,45.38 176.19,45.62 175.91,45.62 175.69,45.84 175.69,46.53 v3(176.05,46.9)
  IN4 w0.076: v1(155.37,20.6) 155.04,20.6 v4(154.96,20.53)
  BOTTOM w0.076: v3(176.05,46.9) UD1.F7
DDR_A_D1: length 41.2
  IN1 w0.122: v3(176.13,48.54) 175.69,48.1 175.69,47.06 175.69,47.05 175.69,46.94 175.34,46.6 175.34,40.01 170.2,34.86 170.02,34.86 169.04,35.84 168.86,35.84 168.59,35.57 168.59,35.39 168.98,35 168.98,34.82 168.81,34.64 168.63,34.64 168.23,35.03 168.05,35.03 162.19,29.17 162.19,25.63 158.44,21.88 158.44,21.83 157.3,20.68 156.84,20.68 156.76,20.6 v4(156.25,20.6)
  IN4 w0.076: v1(155.87,20.6) 155.9,20.56 156.22,20.56 v4(156.25,20.6)
  BOTTOM w0.076: UD1.H7 176.45,48.23 v3(176.13,48.54)
DDR_A_D2: length 42.1
  IN1 w0.122: v3(172.85,46.9) 172.53,46.57 172.01,46.57 171.61,46.18 171.61,43.83 170.48,42.7 170.48,41.58 170.34,41.43 170.16,41.43 169.94,41.65 169.76,41.65 169.58,41.47 169.58,41.29 169.8,41.07 169.8,40.89 163.13,34.23 163.13,34.05 163.46,33.72 163.46,33.54 163.28,33.36 163.1,33.36 162.77,33.69 162.59,33.69 162.41,33.51 162.41,33.33 162.74,33 162.74,32.82 162.56,32.64 162.38,32.64 162.05,32.97 161.87,32.97 161.69,32.79 161.69,32.61 162.02,32.29 162.02,32.11 161.84,31.93 161.66,31.93 161.34,32.25 161.16,32.25 160.98,32.07 160.98,31.89 161.3,31.57 161.3,31.39 161.12,31.21 160.94,31.21 160.62,31.53 160.44,31.53 160.26,31.35 160.26,31.17 160.58,30.85 160.58,30.67 160.42,30.51 160.24,30.51 159.93,30.83 159.75,30.83 159.57,30.65 159.57,30.47 159.88,30.15 159.88,29.97 159.7,29.79 159.52,29.79 159.3,30.02 159.12,30.02 158.94,29.84 158.94,29.66 159.17,29.43 159.17,29.25 159.01,29.1 159.01,27.39 158.38,26.76 158.38,26.6 158.25,26.48 158.11,26.48 157.92,26.29 157.92,26.14 158.21,25.85 158.21,25.66 158.13,25.58 157.96,25.58 157.83,25.45 157.83,25.28 154.43,21.87 v4(154.25,21.87)
  IN4 w0.076: v1(154.62,21.9) 154.28,21.9 v4(154.25,21.87)
  BOTTOM w0.076: v3(172.85,46.9) UD1.G2
DDR_A_D3: length 43.3
  IN1 w0.122: v3(172.85,46.1) 173.12,46.1 173.29,45.93 173.29,43.56 173.01,43.29 172.68,43.29 172.33,42.94 172.15,42.94 171.84,43.25 171.67,43.25 171.49,43.07 171.49,42.89 171.79,42.58 171.79,42.4 171.61,42.22 171.43,42.22 171.13,42.53 170.95,42.53 170.77,42.35 170.77,42.17 171.07,41.86 171.07,41.68 168.06,38.67 168.06,38.49 168.38,38.16 168.38,37.98 168.2,37.8 168.02,37.8 167.7,38.13 167.52,38.13 167.34,37.95 167.34,37.77 167.66,37.44 167.66,37.26 167.48,37.08 167.3,37.08 166.98,37.41 166.8,37.41 166.62,37.23 166.62,37.05 166.94,36.72 166.94,36.55 166.76,36.37 166.58,36.37 166.26,36.69 166.08,36.69 165.9,36.51 165.9,36.33 166.22,36.01 166.22,35.83 166.04,35.65 165.87,35.65 165.54,35.97 165.36,35.97 165.18,35.79 165.18,35.61 165.49,35.31 165.49,35.09 165.28,34.88 165.1,34.88 164.77,35.2 164.59,35.2 164.41,35.02 164.41,34.84 164.74,34.52 164.74,34.34 164.56,34.16 164.38,34.16 164.06,34.48 163.88,34.48 163.7,34.3 163.7,34.13 164.02,33.8 164.02,33.61 159.35,28.94 159.35,27.2 158.7,26.55 158.7,25.66 154.42,21.38 v4(154.4,21.38)
  IN4 w0.076: v1(154.87,21.47) 154.49,21.47 v4(154.4,21.38)
  BOTTOM w0.076: v3(172.85,46.1) UD1.F2
DDR_A_D4: length 42.2
  IN1 w0.122: v4(154.28,20.66) 154.28,20.45 154.8,19.93 156.97,19.93 157.03,19.99 157.58,19.99 158.44,20.86 158.44,20.91 162.87,25.34 162.87,28.88 167.06,33.07 168.21,33.07 169.07,33.93 170.24,33.93 176.03,39.73 176.03,43.59 176.84,44.4 176.84,45.57 177.22,45.95 177.22,46.47 v3(177.65,46.9)
  IN4 w0.076: v4(154.28,20.66) 154.62,20.99 v1(154.62,21.03)
  BOTTOM w0.076: UD1.H8 177.65,47.7 v3(177.65,46.9)
DDR_A_D5: length 41.7
  IN1 w0.122: v4(154.37,19.75) 154.47,19.65 157.72,19.65 158.44,20.37 158.44,20.43 163.22,25.2 163.22,28.74 167.2,32.73 168.35,32.73 169.21,33.59 170.44,33.59 176.37,39.52 176.37,43.46 177.18,44.27 177.18,45.34 177.65,45.82 v3(177.65,46.1)
  IN4 w0.076: v1(155.12,21.03) 154.96,21.03 154.61,20.68 154.61,20.53 154.37,20.29 v4(154.37,19.75)
  BOTTOM w0.076: v3(177.65,46.1) UD1.F8
DDR_A_D6: length 43.3
  IN1 w0.122: v4(153.73,22.76) 153.85,22.76 154,22.91 154.18,22.91 154.54,22.55 154.72,22.55 154.9,22.73 154.9,22.91 154.54,23.27 154.54,23.45 154.72,23.63 154.9,23.63 155.26,23.27 155.44,23.27 155.62,23.45 155.62,23.63 155.26,23.99 155.26,24.17 155.38,24.3 156.37,24.3 157.49,25.42 157.49,26.36 158.67,27.54 158.67,29.45 158.6,29.52 158.6,30.18 167.07,38.65 167.07,38.83 166.77,39.13 166.77,39.31 166.95,39.49 167.13,39.49 167.43,39.19 167.61,39.19 167.79,39.37 167.79,39.55 167.16,40.18 167.16,40.36 167.34,40.54 167.52,40.54 168.15,39.91 168.33,39.91 168.51,40.09 168.51,40.27 167.87,40.91 167.87,41.09 168.05,41.27 168.23,41.27 168.87,40.63 169.05,40.63 169.31,40.89 169.31,42.14 171.19,44.02 171.19,46.6 172.85,48.26 v3(172.85,48.48)
  IN4 w0.076: v1(154.37,22.33) 154.16,22.33 v4(153.73,22.76)
  BOTTOM w0.076: v3(172.85,48.48) 173.23,48.1 UD1.H3
DDR_A_D7: length 41.4
  IN1 w0.122: v4(156.59,21.82) 156.59,22.95 156.83,23.19 157.01,23.19 157.25,22.95 157.43,22.95 157.61,23.13 157.61,23.31 157.37,23.55 157.37,23.73 159,25.36 159.18,25.36 159.42,25.12 159.54,25.12 159.78,25.36 159.78,25.48 159.54,25.72 159.54,25.9 159.72,26.08 159.9,26.08 160.14,25.84 160.26,25.84 160.5,26.08 160.5,26.2 160.26,26.44 160.26,26.62 160.42,26.79 160.42,29.54 168.87,37.99 168.87,38.17 168.58,38.46 168.58,38.64 168.76,38.82 168.94,38.82 169.23,38.53 169.41,38.53 169.59,38.71 169.59,38.89 169.3,39.18 169.3,39.36 169.48,39.54 169.66,39.54 169.95,39.25 170.13,39.25 170.31,39.43 170.31,39.61 170.02,39.9 170.02,40.08 170.2,40.26 170.38,40.26 170.67,39.97 170.85,39.97 171.03,40.15 171.03,40.33 170.74,40.62 170.74,40.8 170.92,40.98 171.1,40.98 171.39,40.69 171.57,40.69 171.75,40.87 171.75,41.05 171.46,41.34 171.46,41.52 171.64,41.7 171.82,41.7 172.11,41.41 172.29,41.41 174.14,43.26 174.14,44.01 174.01,44.13 173.65,44.13 173.52,44.26 173.52,44.51 173.65,44.64 174.01,44.64 174.14,44.77 174.14,45.19 174.03,45.3 v3(173.65,45.3)
  IN4 w0.076: v4(156.59,21.82) 156.38,21.82 156.17,21.61 156.01,21.61 v1(155.87,21.47)
  BOTTOM w0.076: v3(173.65,45.3) UD1.E3
DDR_A_D8: length 39.9
  IN4 w0.076: 157.62,22.4 157.05,22.4 157,22.45 156.32,22.45 155.97,22.09 155.72,22.09 155.48,22.33 v1(155.37,22.33)
  IN4 w0.122: v1(176.45,42.5) 176.45,42.4 175.83,41.78 175.83,41.6 176.64,40.79 176.64,40.56 176.46,40.38 176.33,40.38 175.47,41.24 175.29,41.24 175.11,41.06 175.11,40.88 175.88,40.11 175.88,39.92 175.7,39.74 175.53,39.74 174.75,40.52 174.57,40.52 174.06,40 174.06,37.33 171.2,34.47 169.84,34.47 169.71,34.33 169.71,33.68 169.58,33.55 169.32,33.55 169.19,33.68 169.19,34.18 169.11,34.27 168.77,34.27 168.69,34.18 168.69,33.68 168.56,33.55 167.09,33.55 162.62,29.09 162.62,25.68 159.19,22.25 157.76,22.25 157.62,22.4
DDR_A_D9: length 40.3
  IN4 w0.076: 157.35,22.18 157.02,22.18 156.91,22.29 156.38,22.29 156.03,21.94 155.66,21.94 155.5,22.09 155.27,22.09 155.03,22.33 v1(154.87,22.33)
  IN4 w0.122: 157.35,22.18 157.62,21.91 159.36,21.91 162.96,25.52 162.96,28.94 167.23,33.21 169.72,33.21 170.64,34.12 171.34,34.12 174.64,37.42 174.64,37.6 174.4,37.84 174.4,38.02 174.58,38.2 174.76,38.2 175,37.96 175.18,37.96 175.36,38.14 175.36,38.32 174.4,39.28 174.4,39.49 174.58,39.67 174.73,39.67 175.72,38.68 175.9,38.68 176.08,38.86 176.08,39.04 175.86,39.26 175.86,39.41 176.04,39.59 176.24,39.59 176.44,39.4 176.62,39.4 177.28,40.06 177.28,43.28 v1(177.25,43.3)
DDR_A_D10: length 38.1
  IN4 w0.076: 157.11,24.72 157.11,24.57 156.13,23.59 155.26,23.59 v1(154.87,23.2)
  IN4 w0.122: v1(172.45,42.5) 172.39,42.56 171.7,42.56 171.57,42.69 171.57,43.31 171.44,43.44 171.19,43.44 171.06,43.31 171.06,41.92 170.93,41.79 170.67,41.79 170.53,41.93 170.53,43.39 170.43,43.49 170.13,43.49 170.01,43.37 170.01,41.84 169.9,41.72 169.12,41.72 168.99,41.6 168.99,39.89 168.78,39.67 168.58,39.67 168.49,39.76 168.49,41.6 168.35,41.74 168.07,41.74 167.93,41.6 167.93,38.82 158.95,29.84 158.95,27.66 157.11,25.82 157.11,24.72
DDR_A_D11: length 39
  IN4 w0.076: v1(154.37,23.2) 154.92,23.75 156.07,23.75 156.85,24.53 156.85,24.86
  IN4 w0.122: v1(172.82,43.73) 172.37,43.29 171.95,43.29 171.46,43.77 169.78,43.77 169.65,43.64 169.65,42.21 169.53,42.08 169.27,42.08 169.15,42.21 169.15,43.64 169.02,43.77 168.77,43.77 168.64,43.64 168.64,42.21 168.5,42.07 168.24,42.07 168.13,42.18 168.13,43.64 168,43.77 167.7,43.77 167.59,43.65 167.59,38.96 158.05,29.43 158.05,28.67 157.9,28.52 157.9,27.4 156.85,26.36 156.85,24.86
  BOTTOM w0.076: UD1.C2 v1(172.82,43.73)
DDR_A_D12: length 38.8
  IN4 w0.076: v1(154.62,22.77) 154.62,22.24 154.82,22.04 155.1,22.04 155.2,21.94 155.44,21.94 155.61,21.77 156.08,21.77 156.45,22.14 156.72,22.14 156.93,21.93 157.17,21.93
  IN4 w0.122: v1(177.25,44.1) 177.63,43.72 177.63,39.93 171.28,33.58 171.14,33.58 170.95,33.78 170.78,33.78 170.53,33.53 170.53,33.39 170.74,33.19 170.74,33.04 170.56,32.87 167.37,32.87 163.31,28.8 163.31,25.35 159.52,21.57 157.53,21.57 157.17,21.93
DDR_A_D13: length 38.9
  IN4 w0.076: 157.1,22.6 156.18,22.6 155.92,22.33 v1(155.87,22.33)
  IN4 w0.122: 157.1,22.6 159.05,22.6 162.28,25.82 162.28,29.23 167.37,34.32 167.55,34.32 167.98,33.89 168.16,33.89 168.34,34.07 168.34,34.25 167.91,34.68 167.91,34.86 168.09,35.04 168.27,35.04 168.7,34.61 168.88,34.61 169.06,34.79 169.06,34.97 168.63,35.4 168.63,35.58 168.83,35.78 169.1,35.78 170.07,34.81 171.05,34.81 173.71,37.47 173.71,40.14 177.09,43.52 177.09,43.88 176.45,44.52 v1(176.45,44.9)
DDR_A_D14: length 37.4
  IN4 w0.122: v1(155.87,23.2) 156.59,23.2 159.65,26.26 160.46,26.26 160.59,26.38 160.59,27.28 160.46,27.41 159.71,27.41 159.62,27.5 159.62,27.82 159.73,27.92 160.07,27.92 160.2,28.05 160.2,29.31 164.47,33.58 164.47,33.76 164.26,33.96 164.26,34.14 164.44,34.32 164.62,34.32 164.83,34.12 165.01,34.12 165.19,34.3 165.19,34.48 164.98,34.68 164.98,34.86 165.16,35.04 165.34,35.04 165.55,34.84 165.73,34.84 165.9,35.02 165.9,35.2 165.7,35.4 165.7,35.58 165.88,35.76 166.06,35.76 166.26,35.56 166.44,35.56 166.62,35.74 166.62,35.92 166.42,36.12 166.42,36.3 166.6,36.48 166.78,36.48 166.98,36.28 167.16,36.28 167.34,36.45 167.34,36.63 167.14,36.84 167.14,37.02 167.32,37.2 167.5,37.2 167.7,36.99 167.88,36.99 168.06,37.17 168.06,37.35 167.86,37.56 167.86,37.74 168.04,37.92 168.22,37.92 168.42,37.71 168.6,37.71 168.78,37.89 168.78,38.07 168.57,38.28 168.57,38.46 168.75,38.64 168.93,38.64 169.14,38.43 169.32,38.43 169.5,38.61 169.5,38.79 169.29,39 169.29,39.18 169.47,39.36 169.65,39.36 169.86,39.15 170.04,39.15 171.99,41.1 172.51,41.1 173.67,42.26 173.67,43.68 v1(173.59,43.76)
  BOTTOM w0.076: UD1.C3 v1(173.59,43.76)
DDR_A_D15: length 38
  IN4 w0.076: v1(155.37,23.2) 155.61,23.44 156.2,23.44 157.44,24.69
  IN4 w0.122: v1(173.25,42.5) 172.17,41.42 171.51,41.42 171.38,41.29 171.38,40.81 171.26,40.68 171,40.68 170.88,40.81 170.88,41.29 170.75,41.42 170.5,41.42 170.37,41.29 170.37,39.97 170.24,39.84 169.99,39.84 169.86,39.97 169.86,41.29 169.73,41.42 169.45,41.42 169.34,41.3 169.34,39.74 168.92,39.33 168.41,39.33 168.27,39.18 168.27,38.68 163.68,34.08 163.68,33.9 163.9,33.68 163.9,33.5 163.72,33.32 163.54,33.32 163.32,33.54 163.14,33.54 162.96,33.36 162.96,33.18 163.18,32.96 163.18,32.78 163,32.6 162.82,32.6 162.6,32.82 162.42,32.82 162.24,32.64 162.24,32.47 162.46,32.24 162.46,32.06 162.28,31.88 162.1,31.88 161.88,32.11 161.7,32.11 161.52,31.93 161.52,31.75 161.74,31.52 161.74,31.35 161.56,31.17 161.38,31.17 161.16,31.39 160.98,31.39 160.8,31.21 160.8,31.03 161.02,30.81 161.02,30.63 160.84,30.45 160.66,30.45 160.44,30.67 160.26,30.67 160.08,30.49 160.08,30.31 160.3,30.09 160.3,29.91 160.12,29.73 159.94,29.73 159.72,29.95 159.54,29.95 159.29,29.69 159.29,27.47 157.44,25.62 157.44,24.69
DDR_A_D16: length 55.4
  IN1 w0.122: v4(154.52,16.87) 155.84,15.55 159.8,15.55 167.16,22.91 167.16,26.01 169.68,28.52 175.19,28.52 187.4,40.73 187.4,42.49 190.26,45.34 v3(190.26,47.75)
  IN4 w0.076: v4(154.52,16.87) 154.99,16.87 155.26,17.14 v1(155.37,17.14)
  BOTTOM w0.076: v3(190.26,47.75) 190.23,47.75 189.87,48.1 UD2.H8
DDR_A_D17: length 53.2
  IN1 w0.122: v4(154.2,17.37) 154.51,17.37 155.98,15.89 159.66,15.89 166.82,23.05 166.82,26.15 169.54,28.87 175.05,28.87 187.06,40.88 187.06,40.9 187.07,40.92 187.07,43.72 v3(189.45,46.1)
  IN4 w0.076: v1(154.87,17.14) 154.7,17.3 154.26,17.3 v4(154.2,17.37)
  BOTTOM w0.076: UD2.F8 189.85,46.5 v3(189.45,46.1)
DDR_A_D18: length 51.1
  IN1 w0.122: v4(154.43,18.86) 154.85,19.28 157.84,19.28 163.56,25 163.56,27.45 168.2,32.09 171.58,32.09 172.45,32.96 172.63,32.96 173.36,32.23 173.54,32.23 173.72,32.41 173.72,32.59 172.99,33.32 172.99,33.5 173.17,33.68 173.35,33.68 174.08,32.95 174.26,32.95 174.44,33.13 174.44,33.31 173.71,34.04 173.71,34.22 181.86,42.37 182.03,42.37 183.56,43.91 183.56,45.81 v3(185.48,47.72)
  IN4 w0.076: v1(154.62,18.44) 154.62,18.68 v4(154.43,18.86)
  BOTTOM w0.076: UD2.H3 185.86,48.1 v3(185.48,47.72)
DDR_A_D19: length 50.9
  IN1 w0.122: v3(184.64,46.12) 184.64,45.51 183.96,44.82 183.96,42.72 183.03,41.79 181.76,41.79 175.16,35.19 175.16,35.01 176.01,34.16 176.01,33.98 175.83,33.8 175.65,33.8 174.8,34.65 174.62,34.65 174.44,34.47 174.44,34.29 175.29,33.44 175.29,33.26 173.78,31.75 168.34,31.75 163.9,27.31 163.9,24.86 157.96,18.92 154.97,18.92 154.47,18.42 v4(154.19,18.42)
  IN4 w0.076: v4(154.19,18.42) 154.44,18.17 154.53,18.17 154.69,18 v1(154.87,18)
  BOTTOM w0.076: v3(184.64,46.12) 184.68,46.12 UD2.F2
DDR_A_D20: length 53.7
  IN1 w0.122: v3(189.47,47.72) 186.52,44.78 186.52,41.31 174.76,29.55 169.25,29.55 166.13,26.44 166.13,23.33 159.38,16.58 157.31,16.58 156,17.89 v4(154.2,17.89)
  IN4 w0.076: v1(154.62,17.57) 154.52,17.57 v4(154.2,17.89)
  BOTTOM w0.076: v3(189.47,47.72) 189.44,47.72 UD2.H7
DDR_A_D21: length 49.8
  IN1 w0.122: v3(188.67,46.09) 186.78,44.19 186.78,41.08 174.91,29.21 169.39,29.21 166.48,26.3 166.48,23.19 159.52,16.24 157.16,16.24 v4(156.45,16.95)
  IN4 w0.076: v1(155.87,17.14) 156.26,17.14 v4(156.45,16.95)
  BOTTOM w0.076: v3(188.67,46.09) 189.06,46.48 UD2.F7
DDR_A_D22: length 52.7
  IN1 w0.122: v4(156.3,18.09) 156.76,18.55 158.13,18.55 164.24,24.66 164.24,27.17 168.48,31.41 174,31.41 176.66,34.07 176.66,34.31 175.8,35.17 175.8,35.35 175.98,35.53 176.16,35.53 177.02,34.67 177.2,34.67 177.38,34.85 177.38,35.03 176.52,35.89 176.52,36.07 176.7,36.25 176.88,36.25 177.74,35.39 177.92,35.39 178.1,35.57 178.1,35.75 177.24,36.61 177.24,36.79 181.85,41.39 183.27,41.39 184.31,42.43 184.31,44.55 185.01,45.25 185.01,46.46 v3(185.45,46.91)
  IN4 w0.076: v4(156.3,18.09) 156.25,18.03 155.89,18.03 v1(155.87,18)
  BOTTOM w0.076: v3(185.45,46.91) 185.06,47.29 UD2.G2
DDR_A_D23: length 52.1
  IN1 w0.122: v3(185.45,45.17) 185.45,42.32 183.95,40.82 181.76,40.82 181.6,40.66 181.6,40.48 181.91,40.17 181.91,39.99 181.73,39.81 181.55,39.81 181.24,40.12 181.06,40.12 180.88,39.94 180.88,39.76 181.19,39.45 181.19,39.27 181.01,39.09 180.83,39.09 180.52,39.4 180.41,39.4 178.54,37.53 178.54,37.35 179.39,36.5 179.39,36.32 179.21,36.14 179.03,36.14 178.18,36.99 178,36.99 177.82,36.81 177.82,36.63 178.67,35.78 178.67,35.6 177.7,34.62 177.7,34.62 174.14,31.06 168.63,31.06 164.59,27.02 164.59,24.52 158.12,18.05 157.64,18.05 157.41,17.82 v4(156.71,17.82)
  IN4 w0.076: v4(156.71,17.82) 156.65,17.76 155.77,17.76 155.53,18 155.37,18 v1(155.37,18)
  BOTTOM w0.076: UD2.E3 185.86,45.59 v3(185.45,45.17)
DDR_A_D24: length 49.4
  IN4 w0.076: 157.44,18.61 157.33,18.72 156.38,18.72 156.36,18.7 156.26,18.7 156.03,18.48 155.7,18.48 155.56,18.62 155.27,18.62 155.11,18.78 155.11,18.97 154.78,19.3 v1(154.62,19.3)
  IN4 w0.122: v1(189.86,43.3) 189.58,43.02 189.58,41.43 177.46,29.3 169.42,29.3 167.03,26.91 167.03,23.62 161.4,17.99 158.48,17.99 157.86,18.61 157.44,18.61
DDR_A_D25: length 48.5
  IN4 w0.076: 157.26,21.23 157.05,21.01 157.05,20.88 156.45,20.28 155.19,20.28 155.08,20.17 v1(154.62,20.17)
  IN4 w0.122: 157.26,21.23 159.67,21.23 163.7,25.25 163.7,28.71 167.51,32.52 174.74,32.52 175.61,33.39 175.79,33.39 176.28,32.9 176.46,32.9 176.64,33.07 176.64,33.25 176.15,33.75 176.15,33.93 176.33,34.11 176.51,34.11 177,33.61 177.18,33.61 177.36,33.79 177.36,33.97 176.87,34.47 176.87,34.65 177.05,34.83 177.23,34.83 177.72,34.33 177.9,34.33 178.08,34.51 178.08,34.69 177.59,35.19 177.59,35.37 184.15,41.93 184.15,43.93 184.4,44.19 184.98,44.19 v1(185.06,44.1)
DDR_A_D26: length 46.7
  IN4 w0.076: v1(155.37,18.87) 155.38,18.87 155.42,18.83 155.57,18.83 155.77,18.63 155.97,18.63 156.2,18.86 156.3,18.86 156.32,18.88 157.53,18.88 157.59,18.81
  IN4 w0.122: 157.59,18.81 158,18.81 158.48,18.33 161.25,18.33 166.69,23.77 166.69,27.05 169.28,29.64 177.31,29.64 188.81,41.14 188.81,42.25 v1(189.06,42.5)
DDR_A_D27: length 45.1
  IN4 w0.076: 156.7,19.98 155.61,19.98 v1(155.37,19.74)
  IN4 w0.122: 156.7,19.98 157.26,20.54 160.07,20.54 164.39,24.86 164.39,28.43 167.8,31.84 176.4,31.84 181.55,36.98 181.55,37.16 181.09,37.61 181.09,37.79 184.3,41 185.02,41 185.52,41.5 185.52,43.76 v1(185.86,44.1)
DDR_A_D28: length 47.9
  IN4 w0.076: v1(154.87,19.74) 155.03,19.74 155.42,20.13 156.51,20.13 157.26,20.88
  IN4 w0.122: v1(185.06,42.5) 185.06,41.83 184.71,41.47 184.24,41.47 180.46,37.69 180.46,37.51 180.93,37.03 180.93,36.85 180.75,36.67 180.57,36.67 180.1,37.15 179.92,37.15 179.74,36.97 179.74,36.79 180.22,36.31 180.22,36.13 180.04,35.95 179.86,35.95 179.38,36.43 179.2,36.43 179.02,36.25 179.02,36.07 179.5,35.59 179.5,35.41 179.32,35.23 179.14,35.23 178.66,35.71 178.48,35.71 178.3,35.53 178.3,35.35 178.78,34.88 178.78,34.7 176.26,32.18 167.66,32.18 164.04,28.57 164.04,25.06 159.86,20.88 157.26,20.88
DDR_A_D29: length 50.7
  IN4 w0.076: 157.44,18.36 157.22,18.57 156.44,18.57 156.42,18.55 156.32,18.55 156.09,18.32 155.64,18.32 155.49,18.47 155.21,18.47 154.87,18.81 v1(154.87,18.87)
  IN4 w0.122: 157.44,18.36 157.77,18.36 158.48,17.65 161.54,17.65 167.37,23.47 167.37,26.76 169.56,28.96 177.6,28.96 190.35,41.7 190.35,43.62 v1(189.86,44.1)
DDR_A_D30: length 43.4
  IN4 w0.076: v1(155.87,19.74) 155.89,19.72 156.77,19.72
  IN4 w0.122: 156.77,19.72 157.25,20.2 160.27,20.2 164.73,24.66 164.73,28.28 167.94,31.49 176.55,31.49 182.29,37.24 182.29,37.42 181.85,37.86 181.85,38.04 184.24,40.43 185.02,40.43 185.86,41.27 v1(185.86,42.5)
DDR_A_D31: length 48.1
  IN4 w0.076: 158.2,19.03 156.25,19.03 156.24,19.01 156.01,19.01 v1(155.87,18.87)
  IN4 w0.122: 158.2,19.03 158.56,18.68 160.93,18.68 166.34,24.09 166.34,27.19 169.14,29.98 177.17,29.98 188.47,41.28 188.47,42.33 189.37,43.23 189.37,44.59 v1(189.06,44.9)
DDR_A_D32: length 39.6
  IN4 w0.076: v1(148.5,25.12) 148.5,25.36 149.06,25.92 149.67,25.92 149.81,26.06 150.25,26.06 150.52,26.33 151.25,26.33 151.83,26.91 153.6,26.91 153.94,27.24 154.38,27.24 154.56,27.42 154.56,27.73 154.38,27.91 154.38,28.02
  IN4 w0.122: 154.38,28.02 154.38,31.33 157.97,34.92 157.97,37.4 158.1,37.53 160.15,37.53 160.28,37.65 160.28,37.91 160.15,38.03 158.1,38.03 157.97,38.16 157.97,38.41 158.1,38.54 160.15,38.54 160.28,38.67 160.28,38.92 160.15,39.05 158.1,39.05 157.97,39.18 157.97,39.43 158.1,39.56 160.15,39.56 160.28,39.68 160.28,39.94 160.15,40.07 158.1,40.07 157.97,40.19 157.97,43.81 157.68,44.1 v1(156.53,44.1)
DDR_A_D33: length 39.7
  IN4 w0.076: 154.2,26.4 154.06,26.26 152.19,26.26 151.6,25.66 150.87,25.66 150.56,25.36 150.09,25.36 149.95,25.21 149.46,25.21 v1(149.36,25.12)
  IN4 w0.122: 154.2,26.4 155.29,26.4 156.58,27.68 156.58,28.36 156.26,28.68 156.26,29.5 158.42,31.67 158.42,31.85 158.16,32.11 158.16,32.29 158.34,32.47 158.52,32.47 158.78,32.21 158.96,32.21 159.14,32.39 159.14,32.57 158.88,32.83 158.88,33.01 159.06,33.19 159.24,33.19 159.5,32.93 159.68,32.93 159.86,33.11 159.86,33.29 159.6,33.55 159.6,33.73 159.78,33.91 159.96,33.91 160.22,33.65 160.4,33.65 160.58,33.83 160.58,34.01 160.32,34.26 160.32,34.44 160.5,34.62 160.68,34.62 160.94,34.37 161.12,34.37 161.3,34.55 161.3,34.73 161.04,34.98 161.04,35.16 161.22,35.34 161.4,35.34 161.66,35.08 161.84,35.08 162.02,35.26 162.02,35.44 161.76,35.7 161.76,35.88 161.94,36.06 162.12,36.06 162.38,35.8 162.55,35.8 162.73,35.98 162.73,36.16 162.48,36.42 162.48,36.6 166.37,40.49 166.37,41.95 165.74,42.58 159.8,42.58 v1(159.73,42.5)
DDR_A_D34: length 41.7
  IN4 w0.076: v1(149.36,24.12) 149.4,24.08 149.71,24.08 149.83,23.96 150.1,23.96 150.43,23.62 150.72,23.62 150.96,23.87 151.1,23.87 151.31,24.07 151.31,24.26 151.28,24.28 151.28,24.46 151.69,24.87 152.06,24.87 152.15,24.96 152.15,24.97 152.22,25.04 152.22,25.14 152.45,25.37 152.45,25.56 152.84,25.95 156.02,25.95
  IN4 w0.122: v1(160.53,43.3) 160.57,43.26 161.25,43.26 161.38,43.39 161.38,43.67 161.5,43.79 161.76,43.79 161.88,43.67 161.88,43.39 162.01,43.26 162.26,43.26 162.39,43.39 162.39,43.67 162.52,43.79 162.77,43.79 162.9,43.67 162.9,43.39 163.03,43.26 163.28,43.26 163.41,43.39 163.41,43.67 163.53,43.79 163.79,43.79 163.92,43.67 163.92,43.39 164.04,43.26 164.3,43.26 164.42,43.39 164.42,43.67 164.55,43.79 164.8,43.79 164.93,43.67 164.93,43.39 165.06,43.26 165.31,43.26 165.44,43.39 165.44,43.67 165.57,43.79 165.82,43.79 165.95,43.67 165.95,43.39 166.07,43.26 166.39,43.26 166.48,43.35 166.48,43.71 166.57,43.79 166.93,43.79 167.05,43.67 167.05,39.33 157,29.27 157,28.91 157.32,28.58 157.32,27.26 156.02,25.95
DDR_A_D35: length 39.6
  IN4 w0.076: 154.01,28.02 154.01,27.9 153.17,27.07 151.77,27.07 151.18,26.48 150.46,26.48 150.19,26.21 149.74,26.21 149.6,26.07 149,26.07 148.25,25.33 148.25,25.02 148.3,24.97 148.3,24.96 148.5,24.77 v1(148.5,24.62)
  IN4 w0.122: v1(156.53,42.5) 156.07,42.5 155.98,42.41 155.98,42.09 156.11,41.97 156.94,41.97 157.08,42.11 157.08,43.03 156.96,43.16 156.44,43.16 156.33,43.26 156.33,43.65 156.45,43.77 157.52,43.77 157.63,43.66 157.63,37.92 157.5,37.8 156.2,37.8 156.07,37.67 156.07,37.42 156.2,37.29 157.5,37.29 157.63,37.16 157.63,36.91 157.5,36.78 156.2,36.78 156.07,36.65 156.07,36.4 156.2,36.27 157.5,36.27 157.63,36.15 157.63,35.89 157.5,35.76 156.2,35.76 156.07,35.64 156.07,35.38 156.2,35.26 157.5,35.26 157.57,35.19 157.57,35.04 157.27,34.75 156.17,34.75 156.07,34.65 156.07,33.55 154.01,31.48 154.01,28.02
DDR_A_D36: length 40.1
  IN4 w0.076: v1(149.36,24.62) 149.41,24.56 149.84,24.56 149.85,24.58 149.86,24.58 149.99,24.7 149.99,24.71 150.02,24.75 150.02,24.75 150.14,24.88 150.33,24.88 150.47,25.02 150.47,25.05 150.93,25.51 151.66,25.51 152.26,26.1 154.16,26.1 154.21,26.15
  IN4 w0.122: 154.21,26.15 155.63,26.15 156.98,27.5 156.98,28.43 156.65,28.76 156.65,29.42 163.27,36.03 163.27,36.21 163.02,36.47 163.02,36.65 163.2,36.83 163.38,36.83 163.63,36.57 163.81,36.57 163.99,36.75 163.99,36.93 163.73,37.18 163.73,37.36 163.91,37.54 164.09,37.54 164.35,37.29 164.53,37.29 164.71,37.47 164.71,37.65 164.45,37.9 164.45,38.08 164.63,38.26 164.81,38.26 165.07,38.01 165.25,38.01 165.43,38.19 165.43,38.37 165.17,38.62 165.17,38.8 165.35,38.98 165.53,38.98 165.79,38.73 165.96,38.73 166.14,38.91 166.14,39.09 165.89,39.34 165.89,39.52 166.71,40.34 166.71,42.05 165.83,42.93 160.22,42.93 160.09,43.06 160.09,43.95 160.25,44.1 v1(160.53,44.1)
DDR_A_D37: length 39
  IN4 w0.076: 153.66,28.02 153.66,27.76 153.11,27.22 151.7,27.22 151.12,26.63 150.39,26.63 150.13,26.37 149.68,26.37 149.54,26.23 148.93,26.23 148.06,25.36 148.06,25.02 v1(148.06,24.87)
  IN4 w0.122: v1(155.73,42.5) 155.73,42.47 155.6,42.34 154.67,42.34 154.54,42.21 154.54,41.96 154.67,41.83 155.53,41.83 155.67,41.7 157.05,41.7 157.17,41.57 157.17,41.31 157.05,41.19 155.86,41.19 155.73,41.06 155.73,40.81 155.86,40.68 157.05,40.68 157.17,40.55 157.17,40.3 157.05,40.17 155.86,40.17 155.73,40.04 155.73,39.79 155.86,39.66 157.05,39.66 157.17,39.54 157.17,39.28 157.05,39.16 155.86,39.16 155.73,39.03 155.73,38.77 155.86,38.65 157.05,38.65 157.17,38.52 157.17,38.27 157.05,38.14 155.86,38.14 155.73,38.01 155.73,34.64 155.6,34.52 154.7,34.52 154.57,34.39 154.57,34.13 154.7,34.01 155.6,34.01 155.73,33.88 155.73,33.7 155.1,33.07 154.92,33.07 154.68,33.31 154.5,33.31 154.32,33.13 154.32,32.95 154.56,32.71 154.56,32.53 154.38,32.35 154.2,32.35 153.96,32.59 153.78,32.59 153.6,32.41 153.6,32.23 153.84,31.99 153.84,31.82 153.66,31.63 153.66,28.02
DDR_A_D38: length 40.3
  IN4 w0.076: 155.91,27.97 155.91,28.02 ; 154.19,26.64 153.97,26.42 152.14,26.42 151.56,25.83 150.77,25.83 150.48,25.54 150.04,25.54 149.86,25.36 149.26,25.36 149.11,25.21 149.11,25.03 149.19,24.94 149.19,24.79 149.12,24.72 149.12,24.52 149.17,24.46 149.17,24.27 149.12,24.22 149.12,24.21 149.03,24.12 v1(148.5,24.12)
  IN4 w0.122: 154.19,26.64 154.71,26.64 155.77,27.7 155.77,27.83 155.91,27.97 ; v1(159.39,44.53) 159.74,44.18 159.74,42.99 159.37,42.63 159.37,41.78 159.52,41.62 161.08,41.62 161.68,42.22 165.59,42.22 166.01,41.8 166.01,40.68 157.61,32.28 157.61,32.1 157.85,31.86 157.85,31.68 157.67,31.5 157.49,31.5 157.25,31.74 157.07,31.74 156.89,31.56 156.89,31.38 157.13,31.14 157.13,30.96 156.95,30.78 156.77,30.78 156.53,31.02 156.35,31.02 155.91,30.58 155.91,28.02
  BOTTOM w0.076: v1(159.39,44.53) 159.39,44.56 UD4.D7
DDR_A_D39: length 39.7
  IN4 w0.076: v1(148.06,24.37) 148.06,24.52 147.82,24.77 147.82,24.96 147.9,25.05 147.9,25.41 148.87,26.38 149.48,26.38 149.62,26.52 150.06,26.52 150.33,26.79 151.06,26.79 151.64,27.37 153.01,27.37 153.26,27.61 153.26,28.02
  IN4 w0.122: 153.26,28.02 153.26,32.55 154.23,33.53 154.23,34.8 154.36,34.93 155.24,34.93 155.37,35.06 155.37,35.31 155.24,35.44 154.36,35.44 154.23,35.57 154.23,35.82 154.36,35.95 155.24,35.95 155.37,36.07 155.37,36.33 155.24,36.46 154.36,36.46 154.23,36.58 154.23,36.84 154.36,36.96 155.24,36.96 155.37,37.09 155.37,37.34 155.24,37.47 154.36,37.47 154.23,37.6 154.23,37.85 154.36,37.98 155.24,37.98 155.37,38.11 155.37,38.36 155.24,38.49 154.36,38.49 154.23,38.61 154.23,38.87 154.36,39 155.24,39 155.37,39.12 155.37,39.38 155.24,39.5 154.36,39.5 154.23,39.63 154.23,39.88 154.36,40.01 155.24,40.01 155.37,40.14 155.37,40.39 155.24,40.52 154.36,40.52 154.23,40.65 154.23,40.9 154.36,41.03 155.24,41.03 155.37,41.15 155.37,41.41 155.24,41.54 154.36,41.54 154.23,41.66 154.23,42.3 154.54,42.61 154.54,43.11 154.68,43.25 155.84,43.25 156.04,43.45 156.04,43.79 v1(155.73,44.1)
DDR_A_D40: length 38.6
  IN4 w0.076: 150.23,28.02 150.23,27.9 149.69,27.36 149.32,27.36 149.15,27.18 148.56,27.18 147.07,25.69 147.06,25.69 v7(146.89,25.52)
  IN4 w0.122: 150.23,28.02 150.23,34.11 150.76,34.64 150.76,35.25 150.23,35.78 150.23,37.67 148.02,39.88 148.02,40.57 147.82,40.77 147.13,40.77 145.96,41.94 145.96,43.95 146.64,44.63 147.81,44.63 148.08,44.9 148.5,44.9 148.73,45.13 148.73,47.97 148.93,48.18 150.96,48.18 151.12,48.02 151.12,47.71 150.91,47.5 149.87,47.5 149.49,47.12 149.49,44.49 149.1,44.1 v1(147.92,44.1)
  GND3 w0.076: v7(146.89,25.52) 146.89,25.24 v8(146.76,25.12)
DDR_A_D41: length 39.3
  IN4 w0.076: 152.66,28.02 152.59,27.94 152.47,27.94 152.09,27.56 151.62,27.56 150.99,26.94 150.27,26.94 150,26.67 149.55,26.67 149.41,26.53 148.81,26.53 147.75,25.47 147.75,25.24 v1(147.63,25.12)
  IN4 w0.122: 152.66,28.02 152.72,28.08 152.72,32.77 153.7,33.75 153.7,42.36 154.1,42.76 154.1,43.63 154.16,43.69 154.86,43.69 154.96,43.79 154.96,44.12 154.77,44.32 153.68,44.32 153.55,44.19 153.55,43.02 153.48,42.94 153.33,42.94 153.03,43.24 153.03,44.24 152.92,44.35 152.64,44.35 152.52,44.24 152.52,44.06 152.46,44 152.27,44 151.69,44.58 151.69,45.6 151.48,45.8 150.89,45.8 150.7,45.99 150.7,46.3 150.45,46.54 149.9,46.54 149.69,46.33 149.69,44 148.86,43.16 148.74,43.16 148.67,43.22 148.67,43.74 148.55,43.87 148.29,43.87 148.16,43.74 148.16,43.43 148.04,43.3 v1(147.92,43.3)
DDR_A_D42: length 40.1
  IN4 w0.076: 148.52,28.02 148.52,27.98 148.48,27.94 148.25,27.94 147.66,27.36 147.44,27.36 146.01,25.93 146.01,25.12 145.92,25.03 145.92,24.72 146.07,24.56 146.07,24.27 146.22,24.13 146.75,24.13 v1(146.76,24.12)
  IN4 w0.122: v1(143.12,42.5) 143.12,43.13 142.77,43.48 142.77,44.14 143.1,44.47 143.1,46.23 143.13,46.26 143.13,47.28 143.1,47.31 143.1,49.12 143.13,49.15 143.13,50.31 142.94,50.5 142.45,50.5 142.31,50.36 142.31,42.73 143.02,42.03 143.4,42.03 148.52,36.91 148.52,28.02
DDR_A_D43: length 39.4
  IN4 w0.076: v1(146.76,24.62) 146.77,24.63 146.77,24.98 146.62,25.13 146.62,25.64 146.84,25.86 147.03,25.86 148.5,27.33 149.08,27.33 149.26,27.51 149.63,27.51 149.89,27.77 149.89,28.02
  IN4 w0.122: 149.89,28.02 149.89,34.25 150.42,34.78 150.42,35.11 149.89,35.63 149.89,37.53 145.62,41.8 145.62,44.06 146.38,44.82 146.5,44.95 146.5,45.31 147.09,45.9 147.09,47.39 146.96,47.51 146.68,47.51 146.56,47.64 146.56,47.89 146.68,48.02 146.96,48.02 147.09,48.15 147.09,48.4 146.96,48.53 146.68,48.53 146.56,48.66 146.56,48.91 146.68,49.04 146.96,49.04 147.09,49.16 147.09,50.36 147.25,50.53 147.76,50.53 147.91,50.37 147.91,47.95 147.88,47.91 147.88,47.49 147.91,47.45 147.91,45.03 147.75,44.86 147.16,44.86 v1(147.12,44.9)
DDR_A_D44: length 38.6
  IN4 w0.076: 149.55,28.02 149.55,28.01 149.02,27.48 148.44,27.48 146.96,26.01 146.76,26.01 146.47,25.71 146.47,25.07 146.62,24.92 146.62,24.81 146.52,24.72 146.52,24.52 146.66,24.38 146.85,24.38 147,24.22 147,24.2 147.08,24.13 147.62,24.13 v1(147.63,24.12)
  IN4 w0.122: v1(143.92,44.1) 143.89,44.13 143.89,44.88 143.76,45.01 143.5,45.01 143.37,45.14 143.37,45.39 143.5,45.52 143.76,45.52 143.89,45.64 143.89,49.3 143.99,49.4 144.2,49.62 144.2,49.62 144.36,49.78 144.42,49.78 144.7,50.05 144.94,50.05 146.3,48.69 146.3,45.03 145.4,44.13 145.4,41.53 149.55,37.38 149.55,28.02
DDR_A_D45: length 39.6
  IN4 w0.076: 151.93,27.79 151.63,27.79 150.93,27.09 150.2,27.09 149.94,26.82 149.49,26.82 149.35,26.68 148.74,26.68 147.6,25.54 147.6,25.43 147.39,25.22 147.39,25.02 147.63,24.78 v1(147.63,24.62)
  IN4 w0.122: 151.93,27.79 152.38,28.24 152.38,32.91 153.36,33.89 153.36,39.48 153.23,39.61 152.59,39.61 152.46,39.73 152.46,39.99 152.59,40.12 153.23,40.12 153.36,40.24 153.36,40.5 153.23,40.62 152.59,40.62 152.46,40.75 152.46,41 152.59,41.13 153.23,41.13 153.36,41.26 153.36,41.51 153.23,41.64 152.59,41.64 152.46,41.77 152.46,42.02 152.59,42.15 153.23,42.15 153.36,42.27 153.36,42.63 151.64,44.34 150.61,44.34 150.49,44.46 150.49,44.75 150.62,44.88 151.29,44.88 151.42,45.01 151.42,45.26 151.29,45.39 150.62,45.39 150.49,45.52 150.49,46.21 150.37,46.33 150.01,46.33 149.9,46.22 149.9,43.82 148.58,42.5 v1(147.12,42.5)
DDR_A_D46: length 39.1
  IN4 w0.076: 148.86,28.02 148.86,27.88 148.77,27.79 148.31,27.79 147.73,27.21 147.53,27.21 146.16,25.84 146.16,25.06 146.07,24.97 146.07,24.78 146.33,24.52 v1(146.33,24.37)
  IN4 w0.122: v1(143.12,44.1) 143.12,43.64 143.36,43.4 143.43,43.4 143.65,43.17 143.65,42.31 143.77,42.19 144.08,42.19 144.21,42.33 144.21,42.62 144.12,42.71 144.12,43.44 144.39,43.71 144.39,44.56 145.53,45.7 145.53,47.69 145.11,48.11 145.11,48.76 145.2,48.86 145.55,48.86 145.89,48.52 145.89,45.2 144.99,44.3 144.99,42.88 144.51,42.4 144.51,41.42 148.86,37.07 148.86,28.02
DDR_A_D47: length 39.1
  IN4 w0.076: 149.2,28.02 149.2,27.88 148.96,27.64 148.37,27.64 147.79,27.05 147.59,27.05 146.31,25.78 146.31,24.88 v1(146.33,24.87)
  IN4 w0.122: v1(143.92,42.5) 143.92,43.53 144.19,43.79 144.19,44.65 145.22,45.68 145.22,45.79 145.16,45.85 144.17,45.85 144.09,45.93 144.09,46.13 144.17,46.21 145.01,46.21 145.26,46.46 145.26,47.46 144.74,47.99 144.74,49.54 144.84,49.64 145.06,49.64 146.09,48.6 146.09,45.12 145.2,44.22 145.2,41.24 149.2,37.24 149.2,28.02
DDR_A_D48: length 42.1
  IN1 w0.076: v4(148.63,21.85) 148.64,21.86 148.64,22.18 149.01,22.54 149.01,25.22 149.96,26.18 150.66,26.18 151.36,26.87 152.16,26.87 152.48,27.19 152.85,27.19 153.29,27.64 153.29,28.02
  IN1 w0.122: v3(156.13,46.88) 156.13,44.7 156.39,44.44 156.39,44.26 156.21,44.08 156.21,43.9 156.39,43.72 156.57,43.72 156.75,43.9 156.93,43.9 157.33,43.5 157.33,43.26 157.2,43.13 156.64,43.13 156.51,43 156.51,42.75 156.64,42.62 157.2,42.62 157.33,42.5 157.33,42.24 157.2,42.11 156.23,42.11 156.11,41.99 156.11,41.73 156.23,41.61 157.2,41.61 157.33,41.48 157.33,41.23 157.2,41.1 156.23,41.1 156.11,40.97 156.11,40.72 156.23,40.59 157.2,40.59 157.33,40.46 157.33,40.21 157.2,40.08 156.37,40.08 156.25,39.96 156.25,39.7 156.37,39.57 157.2,39.57 157.33,39.45 157.33,39.19 157.2,39.07 156.37,39.07 156.25,38.94 156.25,38.69 156.37,38.56 157.2,38.56 157.33,38.43 157.33,34.45 153.29,30.41 153.29,28.02
  IN4 w0.076: v4(148.63,21.85) 148.61,21.86 148.61,21.86 148.09,22.37 148.09,22.84 v1(148.06,22.87)
  BOTTOM w0.076: v3(156.13,46.88) 155.75,46.5 UD4.F2
DDR_A_D49: length 42.3
  IN1 w0.076: v4(150.15,21.97) 150.55,21.97 150.88,21.64 151.12,21.64 151.3,21.82 151.84,21.82 152.02,22 152.02,22.52
  IN1 w0.122: v3(160.12,46.1) 160.12,45.84 160.7,45.26 160.97,45.26 162.04,44.18 162.36,44.18 165.1,41.44 165.61,41.44 165.73,41.31 166.27,41.31 166.39,41.19 166.39,40.93 166.27,40.8 165.73,40.8 165.61,40.68 165.61,40.42 165.73,40.3 166.34,40.3 166.47,40.17 166.47,39.92 166.34,39.79 165.73,39.79 165.61,39.66 165.61,39.41 165.73,39.28 166.3,39.28 166.43,39.15 166.43,38.9 166.3,38.77 165.73,38.77 165.61,38.65 165.61,37.97 157.97,30.33 157.97,28.47 154.75,25.24 153.97,25.24 152.02,23.28 152.02,22.52
  IN4 w0.076: v1(148.5,23.12) 148.5,22.96 148.74,22.72 148.74,22.64 149.29,22.09 149.29,22.01 149.37,21.93 149.38,21.93 149.47,21.83 149.74,21.83 149.87,21.97 v4(150.15,21.97)
  BOTTOM w0.076: v3(160.12,46.1) 160.13,46.1 160.53,46.5 UD4.F8
DDR_A_D50: length 43.1
  IN1 w0.076: v4(151,21.99) 151.15,22.14 151.15,23.7 151.48,24.03 151.81,24.03 152.99,25.21 152.99,25.66 153.29,25.96 155.09,25.96
  IN1 w0.122: v3(159.33,46.09) 159.33,45.1 159.51,44.93 159.86,44.93 159.99,44.8 159.99,44.51 160.11,44.38 160.37,44.38 160.5,44.51 160.5,44.8 160.62,44.93 161.01,44.93 161.63,44.31 161.63,44.13 161.31,43.81 161.31,43.63 161.49,43.45 161.67,43.45 161.99,43.77 162.17,43.77 162.35,43.59 162.35,43.41 161.92,42.99 161.92,42.81 162.1,42.63 162.28,42.63 162.71,43.05 162.89,43.05 164.6,41.34 164.6,41.07 164.73,40.95 165.15,40.95 165.28,40.82 165.28,40.57 165.15,40.44 164.73,40.44 164.6,40.31 164.6,40.06 164.73,39.93 165.14,39.93 165.26,39.8 165.26,39.55 165.14,39.42 164.73,39.42 164.6,39.3 164.6,39.04 164.73,38.91 165.14,38.91 165.26,38.79 165.26,38.53 165.14,38.41 164.73,38.41 164.6,38.28 164.6,37.62 157.19,30.21 157.19,28.87 156.58,28.26 156.58,27.45 155.09,25.96
  IN4 w0.076: v1(149.36,22.62) 149.39,22.65 149.58,22.65 149.94,22.29 150.28,22.29 150.73,21.84 150.85,21.84 v4(151,21.99)
  BOTTOM w0.076: v3(159.33,46.09) 159.33,46.1 159.73,46.49 UD4.F7
DDR_A_D51: length 42.6
  IN1 w0.076: v4(150.02,23.14) 150.43,23.55 150.79,23.55 151.32,24.08 151.32,24.54 151.58,24.8 151.77,24.8 152.15,25.18 152.26,25.18 152.45,25.37 152.45,25.48 153.11,26.14
  IN1 w0.122: 153.11,26.14 154.48,26.14 155.71,27.37 155.71,27.75 155.87,27.9 155.87,28.24 156.74,29.11 156.74,30.25 163.57,37.07 163.57,37.55 163.72,37.71 164.13,37.71 164.26,37.83 164.26,38.09 164.13,38.21 163.69,38.21 163.57,38.34 163.57,38.59 163.69,38.72 164.13,38.72 164.26,38.85 164.26,39.1 164.13,39.23 163.64,39.23 163.51,39.36 163.51,39.61 163.64,39.74 164.13,39.74 164.26,39.86 164.26,40.12 164.13,40.25 163.64,40.25 163.51,40.37 163.51,40.63 163.64,40.75 164.27,40.75 164.4,40.88 164.4,41.13 164.27,41.26 163.85,41.26 163.73,41.39 163.73,41.71 163.02,42.42 161.44,42.42 158.97,44.9 158.97,47.07 159.16,47.26 160.6,47.26 160.92,47.58 v3(160.92,48.48)
  IN4 w0.076: v1(149.36,23.12) 149.39,23.14 v4(150.02,23.14)
  BOTTOM w0.076: UD4.H8 160.54,48.1 v3(160.92,48.48)
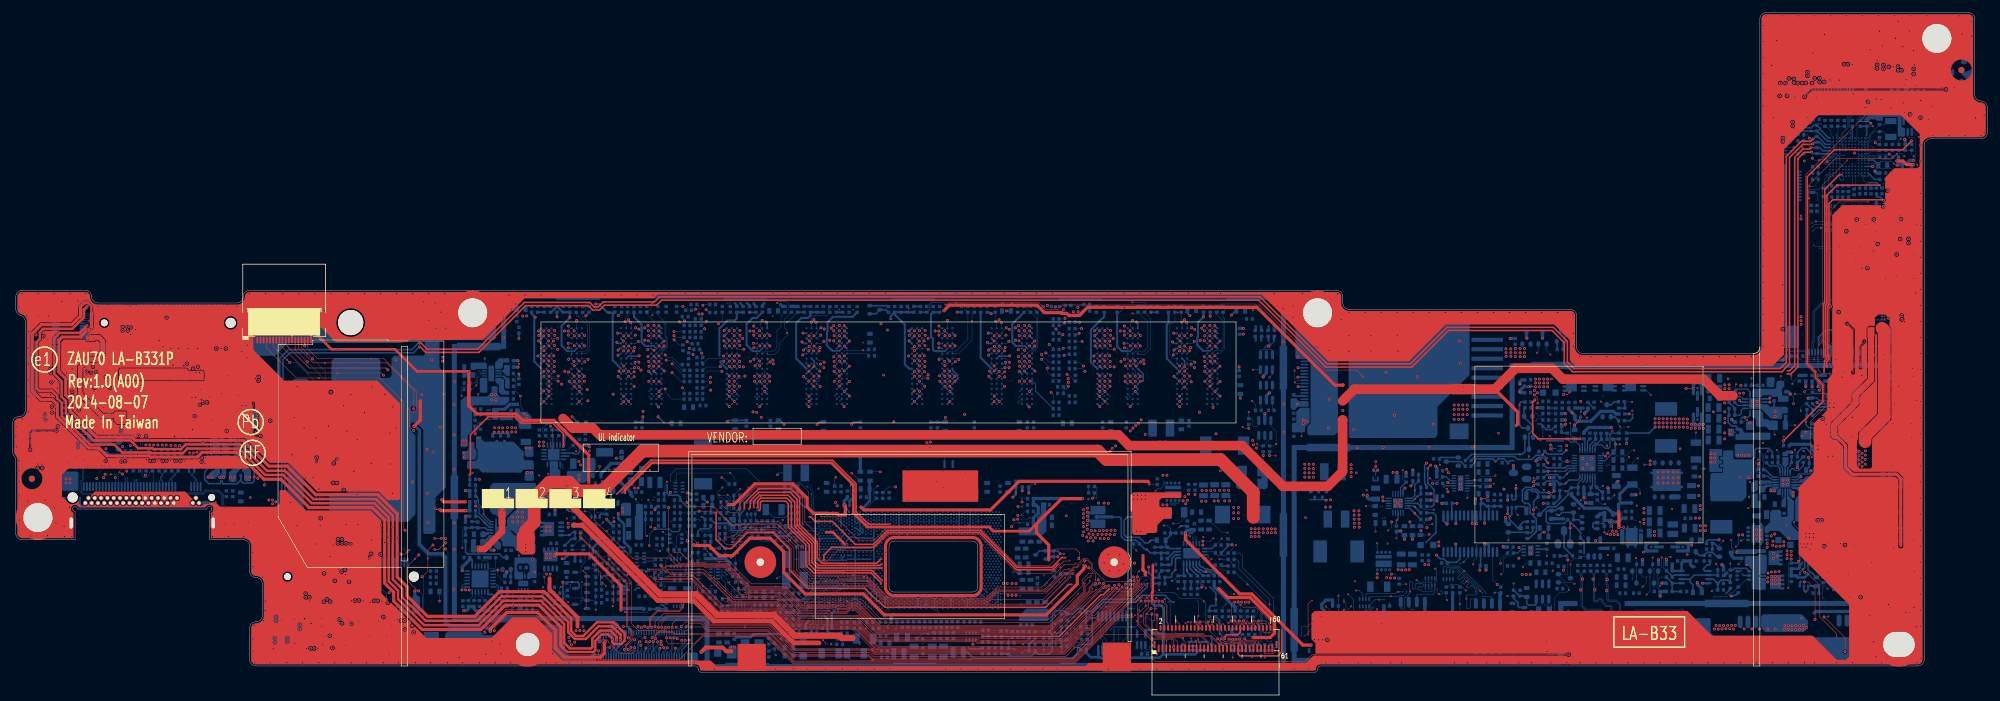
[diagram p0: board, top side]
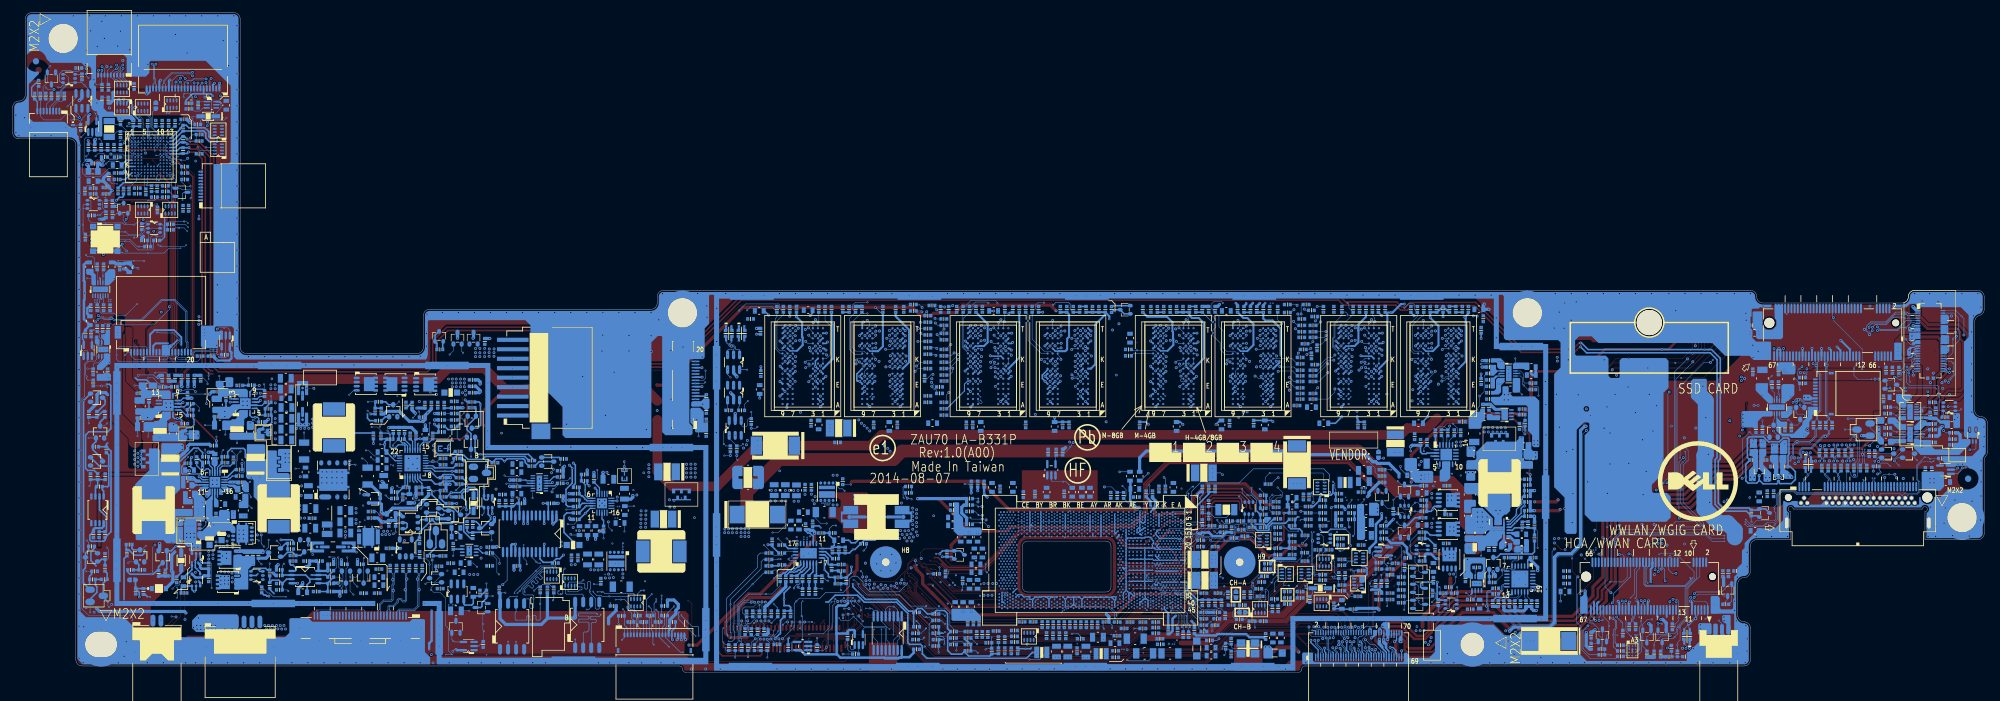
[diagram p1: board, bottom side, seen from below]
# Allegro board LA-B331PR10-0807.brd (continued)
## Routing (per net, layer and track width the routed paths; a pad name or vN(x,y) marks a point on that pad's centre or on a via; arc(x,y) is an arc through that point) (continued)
DDR_A_D52: length 42.1
  IN1 w0.076: 153.06,26.36 152.62,25.92 151.64,25.92 150.72,25 150.72,24.57 149.97,23.82 v4(149.97,23.62)
  IN1 w0.122: v3(160.11,48.5) 159.72,48.11 158.74,48.11 158.61,47.97 158.61,44.82 161.32,42.1 162.85,42.1 163.22,41.73 163.22,39.93 163.1,39.8 162.94,39.8 162.81,39.68 162.81,39.42 162.94,39.3 163.1,39.3 163.22,39.17 163.22,37.21 162.79,36.78 162.61,36.78 162.41,36.98 162.23,36.98 162.05,36.8 162.05,36.62 162.25,36.42 162.25,36.24 162.07,36.06 161.89,36.06 160.98,36.98 160.8,36.98 160.62,36.8 160.62,36.62 161.53,35.7 161.53,35.52 161.35,35.34 161.17,35.34 160.83,35.69 160.65,35.69 160.47,35.51 160.47,35.33 160.81,34.98 160.81,34.8 156.4,30.39 156.4,29.26 155.45,28.31 155.45,27.49 154.32,26.36 153.06,26.36
  IN4 w0.076: v4(149.97,23.62) 149.37,23.62 v1(149.36,23.62)
  BOTTOM w0.076: UD4.H7 159.73,48.12 v3(160.11,48.5)
DDR_A_D53: length 41.5
  IN1 w0.076: 153.63,28.02 153.63,27.74 152.93,27.04 152.54,27.04 152.16,26.66 151.36,26.66 150.72,26.02 150.16,26.02 149.16,25.02 149.16,22.47 148.97,22.28 148.97,21.9 149.41,21.46 149.41,21.36 v4(149.42,21.36)
  IN1 w0.122: v3(157.04,48.26) 156.81,48.26 156.62,48.07 156.62,46.44 156.75,46.31 157.46,46.31 157.59,46.19 157.59,45.93 157.46,45.81 156.75,45.81 156.62,45.68 156.62,44.75 157.67,43.71 157.67,37.29 157.8,37.17 158.49,37.17 158.62,37.04 158.62,36.79 158.49,36.66 157.8,36.66 157.67,36.53 157.67,36.28 157.8,36.15 158.49,36.15 158.62,36.02 158.62,35.77 158.49,35.64 157.8,35.64 157.67,35.52 157.67,35.26 157.8,35.14 157.99,35.14 158.12,35.01 158.12,34.75 157.99,34.63 157.8,34.63 157.67,34.5 157.67,34.31 153.63,30.27 153.63,28.02
  IN4 w0.076: v1(148.5,23.62) 148.3,23.43 148.3,23.27 148.25,23.22 148.25,23.02 148.3,22.97 148.3,22.77 148.25,22.71 148.25,22.52 148.41,22.35 148.58,22.35 148.97,21.96 148.97,21.9 149.41,21.46 149.41,21.36 v4(149.42,21.36)
  BOTTOM w0.076: UD4.H3 156.88,48.1 v3(157.04,48.26)
DDR_A_D54: length 42.8
  IN1 w0.076: 153.97,28.02 153.97,27.87 153,26.89 152.61,26.89 152.23,26.51 151.42,26.51 150.78,25.87 150.25,25.87 149.31,24.94 149.31,22.37 149.15,22.2 149.15,21.95 149.26,21.84 149.47,21.84 149.47,21.83 149.72,21.83 v4(150.09,21.46)
  IN1 w0.122: 153.97,28.02 153.97,29.1 154.87,30 154.87,31.02 158.96,35.11 158.96,37.39 158.83,37.52 158.14,37.52 158.01,37.65 158.01,37.9 158.14,38.03 158.83,38.03 158.96,38.16 158.96,38.52 158.83,38.64 158.14,38.64 158.01,38.77 158.01,39.02 158.14,39.15 158.83,39.15 158.96,39.28 158.96,39.53 158.83,39.66 158.14,39.66 158.01,39.79 158.01,40.04 158.14,40.17 158.97,40.17 159.1,40.29 159.1,40.55 158.97,40.67 158.14,40.67 158.01,40.8 158.01,41.06 158.14,41.18 159.16,41.18 159.29,41.31 159.29,41.56 159.16,41.69 158.14,41.69 158.01,41.82 158.01,42.07 158.14,42.2 158.83,42.2 158.96,42.33 158.96,42.75 158.75,42.95 158.57,42.95 158.44,42.82 158.26,42.82 158.08,43 158.08,43.18 158.21,43.31 158.21,43.49 157.41,44.29 157.41,45.13 157.25,45.29 v3(156.99,45.29)
  IN4 w0.076: v1(148.5,22.62) 148.55,22.62 148.91,22.25 149.12,22.04 149.12,21.96 149.31,21.77 149.32,21.77 149.41,21.68 149.8,21.68 149.8,21.68 149.87,21.68 150.1,21.46 v4(150.09,21.46)
  BOTTOM w0.076: UD4.E3 156.58,45.7 v3(156.99,45.29)
DDR_A_D55: length 42.5
  IN1 w0.076: v4(148.14,21.8) 148.14,21.93 148.85,22.65 148.85,25.33 149.86,26.33 150.59,26.33 151.29,27.03 152.01,27.03 152.52,27.53 152.52,28.02
  IN1 w0.122: v3(156.12,47.68) 155.71,47.28 155.71,45.58 155.59,45.45 154.43,45.45 154.3,45.33 154.3,45.07 154.43,44.94 155.59,44.94 155.71,44.82 155.71,42.66 155.9,42.47 155.9,38.2 156.03,38.07 156.86,38.07 156.98,37.94 156.98,37.69 156.86,37.56 156.03,37.56 155.9,37.44 155.9,37.18 156.03,37.06 156.86,37.06 156.98,36.93 156.98,36.67 156.86,36.55 156.03,36.55 155.9,36.42 155.9,36.17 156.03,36.04 156.86,36.04 156.98,35.91 156.98,35.66 156.86,35.53 156.03,35.53 155.9,35.4 155.9,35.15 156.03,35.02 156.86,35.02 156.98,34.9 156.98,34.64 156.86,34.52 156.03,34.52 155.9,34.39 155.9,33.51 152.52,30.13 152.52,28.02
  IN4 w0.076: v4(148.14,21.8) 148.14,22.11 147.94,22.31 147.94,22.65 147.87,22.72 147.81,22.77 147.81,22.95 147.82,22.96 147.82,22.97 148.06,23.21 v1(148.06,23.37)
  BOTTOM w0.076: v3(156.12,47.68) 155.74,47.3 UD4.G2
DDR_A_D56: length 42.4
  IN1 w0.122: v3(143.52,46.9) 143.52,46.66 143.39,46.53 141.36,46.53 141.23,46.4 141.23,46.13 141.36,46 142.99,46 143.11,45.88 143.11,45.55 142.99,45.42 141.48,45.42 141.35,45.29 141.35,44.19 141.43,44.11 143.04,44.11 143.11,44.04 143.11,42.42 144.84,40.7 145.14,40.7 146.4,41.96 146.58,41.96 146.76,41.78 146.76,41.6 145.41,40.25 145.41,40.07 145.59,39.89 145.77,39.89 146.43,40.55 146.6,40.55 146.78,40.37 146.78,40.19 146.11,39.51 146.11,39.33 146.38,39.06 146.56,39.06 147.03,39.53 147.21,39.53 147.39,39.35 147.39,39.17 146.95,38.73 146.95,38.55 147.13,38.37 147.31,38.37 147.49,38.56 147.67,38.56 147.85,38.38 147.85,38.2 147.75,38.09 147.75,37.91 148.32,37.34 148.32,28.25 146.44,26.36 v4(146.44,23.81)
  IN4 w0.076: v1(146.76,23.62) 146.63,23.62 v4(146.44,23.81)
  BOTTOM w0.076: v3(143.52,46.9) UD3.G2
DDR_A_D57: length 42.1
  IN1 w0.076: 149.84,27.13 149.21,27.13 147.92,25.84 v4(147.92,23.83)
  IN1 w0.122: v3(144.3,47.63) 144.9,47.63 145.24,47.29 145.24,45.92 147.36,43.79 150.67,43.79 152.12,42.35 152.12,41.13 153.04,40.21 153.04,39.42 153.19,39.27 153.77,39.27 153.9,39.14 153.9,38.89 153.77,38.76 152.77,38.76 152.65,38.63 152.65,38.38 152.77,38.25 153.77,38.25 153.9,38.13 153.9,37.87 153.77,37.74 153.17,37.74 153.04,37.62 153.04,37.36 153.17,37.24 153.77,37.24 153.9,37.11 153.9,36.86 153.77,36.73 153.1,36.73 152.98,36.6 152.98,36.35 153.1,36.22 153.77,36.22 153.9,36.09 153.9,35.84 153.77,35.71 153.19,35.71 153.06,35.59 153.06,35.33 153.19,35.2 153.77,35.2 153.9,35.08 153.9,34.82 153.77,34.7 153.19,34.7 153.06,34.57 153.06,34.08 152.38,33.39 150.79,33.39 150.61,33.22 150.61,27.9 149.84,27.13
  IN4 w0.076: v4(147.92,23.83) 147.84,23.83 147.78,23.76 v1(147.63,23.62)
  BOTTOM w0.076: UD3.H3 143.92,48.06 144.3,47.68 v3(144.3,47.63)
DDR_A_D58: length 42
  IN1 w0.076: 151.3,27.59 151.19,27.49 150.99,27.49 150.3,26.8 149.39,26.8 148.4,25.81 148.4,22.94 147.33,21.87 v4(147.33,21.76)
  IN1 w0.122: v3(148.32,46.1) 148.69,45.73 148.96,45.73 149.08,45.6 149.08,45.19 149.21,45.06 149.46,45.06 149.59,45.19 149.59,45.6 149.72,45.73 149.93,45.73 150.34,45.32 150.34,45.14 150.11,44.91 150.11,44.62 150.33,44.4 151.18,44.4 151.54,44.04 151.72,44.04 152.24,44.55 152.42,44.55 152.59,44.37 152.59,44.19 152.08,43.68 152.08,43.5 152.26,43.32 152.44,43.32 152.95,43.83 153.13,43.83 153.31,43.65 153.31,43.47 152.8,42.96 152.8,42.78 152.98,42.6 153.16,42.6 153.67,43.11 153.85,43.11 154.03,42.93 154.03,42.75 153.52,42.24 153.52,42.06 153.7,41.88 153.88,41.88 154.37,42.37 154.55,42.37 154.73,42.19 154.73,42.01 154.24,41.52 154.24,41.34 154.68,40.9 154.68,34.64 152.59,32.55 152.59,31.98 152.26,31.65 151.48,31.65 151.3,31.47 151.3,27.59
  IN4 w0.076: v4(147.33,21.76) 147.29,21.76 146.99,22.06 146.97,22.06 146.88,22.15 146.78,22.15 146.68,22.25 146.68,22.54 v1(146.76,22.62)
  BOTTOM w0.076: v3(148.32,46.1) UD3.F8
DDR_A_D59: length 42.7
  IN1 w0.076: 150.96,28.02 150.96,27.92 149.98,26.95 149.25,26.95 148.25,25.95 148.25,23.06 147.24,22.06 146.99,22.06 v4(146.75,21.83)
  IN1 w0.122: 150.96,28.02 150.96,31.86 151.08,31.99 152.12,31.99 152.25,32.12 152.25,32.37 152.12,32.5 151.08,32.5 150.96,32.63 150.96,32.92 151.08,33.05 152.6,33.05 154.24,34.68 154.24,39.56 154.11,39.68 153.51,39.68 153.38,39.81 153.38,40.06 153.51,40.19 154.11,40.19 154.24,40.32 154.24,40.73 153.97,41.01 153.79,41.01 153.47,40.69 153.29,40.69 153.11,40.87 153.11,41.05 153.43,41.36 153.43,41.54 153.25,41.72 153.07,41.72 152.75,41.41 152.57,41.41 152.39,41.59 152.39,41.77 152.71,42.08 152.71,42.26 150.9,44.07 148.21,44.07 146.35,45.93 146.35,46.65 v3(146.67,46.97)
  IN4 w0.076: v1(146.76,23.12) 146.76,22.96 146.52,22.72 146.52,22.47 146.52,22.46 146.52,22.06 v4(146.75,21.83)
  BOTTOM w0.076: UD3.F7 146.67,46.95 v3(146.67,46.97)
DDR_A_D60: length 43.2
  IN1 w0.076: v4(148.03,21.33) 147.8,21.56 147.8,21.91 148.7,22.81 148.7,25.49 149.69,26.48 150.52,26.48 151.22,27.18 151.82,27.18 151.98,27.34
  IN1 w0.122: 151.98,27.34 151.98,30.82 152.13,30.96 152.6,30.96 153.27,31.64 153.27,32.26 153.49,32.48 153.67,32.48 153.8,32.34 153.98,32.34 154.16,32.52 154.16,32.7 154.03,32.83 154.03,33.01 154.21,33.19 154.39,33.19 154.52,33.06 154.7,33.06 154.88,33.24 154.88,33.42 154.75,33.55 154.75,33.73 155.37,34.36 155.37,42.31 154.95,42.73 154.95,43.96 154.83,44.08 154.65,44.08 154.23,43.67 154.05,43.67 153.87,43.85 153.87,44.03 154.29,44.44 154.29,44.62 153.99,44.92 153.81,44.92 153.35,44.46 153.17,44.46 152.99,44.64 152.99,44.82 153.45,45.28 153.45,45.46 153.27,45.64 153.09,45.64 152.91,45.46 152.75,45.46 152.55,45.66 152.55,45.82 152.73,46 152.73,46.18 150.84,48.07 147.86,48.07 v3(147.49,47.71)
  IN4 w0.076: v4(148.03,21.33) 147.8,21.56 147.8,22.06 147.69,22.17 147.69,22.56 v1(147.63,22.62)
  BOTTOM w0.076: v3(147.49,47.71) 147.12,48.08 UD3.H7
DDR_A_D61: length 42.3
  IN1 w0.076: 151.64,27.5 151.47,27.33 151.05,27.33 150.37,26.65 149.57,26.65 148.55,25.63 148.55,22.87 147.65,21.97 147.65,21.41 v4(147.55,21.31)
  IN1 w0.122: 151.64,27.5 151.64,31.13 151.82,31.3 152.46,31.3 152.93,31.78 152.93,32.4 155.03,34.5 155.03,42.32 152.32,45.03 151.7,45.03 151.22,45.51 151.22,45.85 151.85,46.49 151.85,46.66 151.67,46.84 151.49,46.84 150.57,45.93 150.39,45.93 150.21,46.11 150.21,46.29 151.13,47.2 151.13,47.38 150.81,47.7 150.55,47.7 150.42,47.58 150.42,47.4 150.29,47.27 150.04,47.27 149.91,47.4 149.91,47.58 149.79,47.7 149.53,47.7 149.41,47.58 149.41,47.4 149.28,47.27 149.02,47.27 148.9,47.4 148.9,47.58 148.77,47.7 v3(148.28,47.7)
  IN4 w0.076: v1(147.63,23.12) 147.63,22.96 147.39,22.72 147.39,22.52 147.53,22.37 147.53,22.11 147.65,21.99 147.65,21.41 v4(147.55,21.31)
  BOTTOM w0.076: v3(148.28,47.7) 147.92,48.06 UD3.H8
DDR_A_D62: length 42
  IN1 w0.076: 146.93,25.89 146.93,23.64 146.42,23.12 146.42,21.71 146.81,21.32 v4(146.96,21.32) ; 149.01,28.02 149.01,27.96
  IN1 w0.122: 149.01,27.96 146.93,25.89 ; v3(144.32,45.3) 146.92,42.69 146.92,42.5 147.81,41.61 149.57,41.61 149.69,41.74 149.69,42.54 149.82,42.66 150.18,42.66 150.31,42.54 150.31,40.99 150.18,40.87 148.37,40.87 148.25,40.74 148.25,40.49 148.37,40.36 150.05,40.36 150.18,40.23 150.18,39.98 150.05,39.85 148.36,39.85 148.23,39.72 148.23,39.44 148.36,39.31 149.22,39.31 149.35,39.19 149.35,38.93 149.22,38.8 148.91,38.8 148.78,38.68 148.78,38.42 148.91,38.3 149.18,38.3 149.31,38.17 149.31,37.92 149.18,37.79 149.13,37.79 149.01,37.66 149.01,37.41 149.13,37.28 149.18,37.28 149.31,37.15 149.31,36.9 149.18,36.77 149.13,36.77 149.01,36.65 149.01,36.39 149.13,36.26 149.18,36.26 149.31,36.14 149.31,35.88 149.18,35.76 149.13,35.76 149.01,35.63 149.01,35.38 149.13,35.25 149.18,35.25 149.31,35.12 149.31,34.87 149.18,34.74 149.13,34.74 149.01,34.61 149.01,28.02
  IN4 w0.076: v4(146.96,21.32) 146.81,21.32 146.37,21.77 146.37,22.83 v1(146.33,22.87)
  BOTTOM w0.076: v3(144.32,45.3) UD3.E3
DDR_A_D63: length 42.1
  IN1 w0.076: 146.75,26.19 146.75,23.68 146.26,23.19 146.26,21.99 v4(146.05,21.77)
  IN1 w0.122: v3(143.52,46.1) 143.52,45.5 144.55,44.46 144.55,44.28 143.41,43.14 143.41,42.96 143.59,42.78 143.77,42.78 144.91,43.92 145.09,43.92 145.27,43.74 145.27,43.56 144.1,42.39 144.1,42.21 144.28,42.03 144.46,42.03 145.63,43.2 145.81,43.2 145.99,43.03 145.99,42.85 144.84,41.7 144.84,41.52 145.02,41.34 145.2,41.34 146.35,42.49 146.53,42.49 147.13,41.89 147.13,41.5 147.25,41.37 147.99,41.37 148.12,41.24 148.12,40.99 147.99,40.86 147.25,40.86 147.13,40.74 147.13,40.1 147.91,39.31 147.91,38.8 148.66,38.05 148.66,28.1 146.75,26.19
  IN4 w0.076: v1(146.33,23.37) 146.33,23.33 146.06,23.06 146.06,22.77 146.21,22.62 146.21,22.04 146.05,21.87 v4(146.05,21.77)
  BOTTOM w0.076: v3(143.52,46.1) UD3.F2
DDR_A_DQS0: length 43.5
  IN1 w0.076: v4(156.26,21.25) 156.47,21.47 156.69,21.47 157.31,22.09 157.58,22.09 158.61,23.12 158.61,23.18 158.62,23.19
  IN1 w0.137: v3(173.65,46.1) 173.54,46.21 173.54,46.4 173.7,46.55 173.89,46.55 174.53,45.91 174.53,42.87 174.1,42.44 173.35,41.68 173.35,41.12 174.11,40.36 174.11,40.13 173.76,39.78 173.53,39.78 173.19,40.12 173.19,40.19 172.94,40.45 172.87,40.45 172.77,40.54 172.21,40.54 172.11,40.45 172.08,40.45 171.62,40 171.62,39.39 172.27,38.75 172.27,38.52 171.92,38.17 171.69,38.17 171.05,38.82 170.48,38.82 169.9,38.23 169.9,37.67 170.66,36.91 170.66,36.68 170.31,36.33 170.08,36.33 169.32,37.09 168.76,37.09 161.23,29.57 161.23,25.8 158.62,23.19
  IN4 w0.076: v4(156.26,21.25) 156.23,21.23 155.77,21.23 155.63,21.37 155.63,21.42 155.57,21.47 v1(155.37,21.47)
  BOTTOM w0.076: v3(173.65,46.1) 173.65,46.4 173.56,46.5 UD1.F3
DDR_A_DQS1: length 40.3
  IN4 w0.076: v1(155.62,22.77) 156.87,22.77 157.63,23.53 158.73,23.53 158.78,23.48 158.79,23.48
  IN4 w0.137: v1(176.79,43.64) 176.78,43.64 176.12,42.98 175.64,42.98 173.1,40.44 172.68,40.44 171.94,39.7 171.94,39.47 173.16,38.25 173.16,37.7 172.58,37.11 172,37.11 170.79,38.32 170.56,38.32 170.22,37.98 170.22,37.75 171.45,36.52 171.45,35.98 170.83,35.36 170.3,35.36 169.07,36.6 168.84,36.6 161.71,29.47 161.71,26.01 159.18,23.48 158.79,23.48
  BOTTOM w0.076: v1(176.79,43.64) 176.45,43.98 UD1.C7
DDR_A_DQS2: length 51.8
  IN1 w0.076: 158.79,17.61 157.85,17.61 157.69,17.46 157.69,17.33 157.87,17.15 v4(157.92,17.15)
  IN1 w0.137: 158.79,17.61 159.4,17.61 165.58,23.79 165.58,24.16 165.58,26.67 169.02,30.1 174.53,30.1 180.78,36.35 180.78,36.92 180.15,37.55 180.15,37.78 180.49,38.13 180.72,38.13 181.36,37.49 181.92,37.49 182.32,37.89 182.32,39.04 182.6,39.32 183.72,39.32 186.06,41.66 186.06,46.12 186.18,46.23 186.31,46.23 v3(186.51,46.03)
  IN4 w0.076: v1(155.62,17.57) 155.66,17.53 156.03,17.53 156.06,17.51 156.58,17.51 156.58,17.5 156.84,17.5 156.85,17.51 157.29,17.51 157.3,17.49 157.58,17.49 v4(157.92,17.15)
  BOTTOM w0.076: UD2.F3 186.04,46.5 v3(186.51,46.03)
DDR_A_DQS3: length 47.5
  IN4 w0.076: v1(155.62,19.3) 155.62,19.43 155.68,19.49 158.73,19.49 158.78,19.53 158.79,19.53
  IN4 w0.137: v1(189.06,44.1) 189.16,44 189.16,43.79 189.02,43.65 188.89,43.65 185.8,40.57 185.8,40.39 184.89,39.47 184.89,38.95 184.54,38.6 183.19,38.6 182.78,38.19 182.78,37.7 183.11,37.37 183.11,37.13 176.86,30.89 168.62,30.89 165.29,27.56 165.29,24.39 160.43,19.53 158.79,19.53
DDR_A_DQS4: length 41.9
  IN4 w0.076: 155.02,28.02 155.02,27.47 154.59,27.04 154.09,27.04 153.79,26.74 151.93,26.74 151.34,26.15 150.59,26.15 150.3,25.86 149.88,25.86 149.72,25.7 149.13,25.7 148.78,25.34 148.78,25.06 148.69,24.97 148.69,24.77 148.93,24.53 v1(148.93,24.37)
  IN4 w0.137: 155.02,28.02 155.02,30.86 159.12,34.95 159.12,35.28 158.69,35.71 158.69,36.52 158.98,36.81 159.44,36.81 159.86,36.39 160.29,36.39 161.14,37.24 161.42,37.24 162.12,37.94 162.12,38.26 161.93,38.45 161.34,38.45 161,38.79 161,39.37 161.32,39.69 162.54,39.69 163.03,39.21 163.36,39.21 165.02,40.87 165.02,41.19 164.77,41.45 164,41.45 163.44,40.89 162.98,40.89 162.45,41.42 162,41.42 161.39,40.81 159.01,40.81 158.71,41.11 158.71,43.21 158.97,43.47 159.18,43.47 v1(159.34,43.64)
  BOTTOM w0.076: v1(159.34,43.64) 159.73,44.03 UD4.C7
DDR_A_DQS5: length 41.4
  IN4 w0.076: v1(147.2,24.37) 147.2,24.53 146.95,24.77 146.95,24.97 147.04,25.06 147.04,25.31 147.23,25.49 147.23,25.6 148.61,26.99 149.21,26.99 149.36,27.14 149.79,27.14 150.1,27.45 150.78,27.45 151.13,27.8 151.13,27.97 151.09,28.01 151.09,28.02
  IN4 w0.137: 151.09,28.02 151.09,28.71 151.58,29.19 151.58,29.68 151.35,29.9 151.2,29.9 150.95,30.16 150.95,30.95 151.19,31.2 151.36,31.2 151.58,31.41 151.58,32.12 151.35,32.34 151.2,32.34 150.95,32.6 150.95,33.8 151.21,34.06 151.67,34.06 151.85,33.89 152.24,33.89 152.57,34.22 152.57,35.58 152.32,35.83 151.19,35.83 150.95,36.07 150.95,36.88 151.19,37.12 152.32,37.12 152.57,37.37 152.57,38.21 152.31,38.46 150.45,38.46 149.64,39.27 149.64,39.65 149.87,39.88 151.31,39.88 151.6,40.17 151.6,43.21 151.14,43.67 150.76,43.67 149.89,42.8 149.89,41.3 149.6,41.02 148.93,41.02 148.65,41.3 148.65,41.62 148.37,41.89 146.71,41.89 146.42,42.18 146.42,43.56 146.77,43.91 146.99,43.91 147.12,44.04 v1(147.12,44.1)
DDR_A_DQS6: length 43.6
  IN1 w0.076: v4(149.6,22.15) 149.71,22.15 149.83,22.27 149.83,22.38 149.69,22.53 149.69,22.78 149.5,22.96 149.5,24.09 150.11,24.7 150.11,24.94 151.47,26.31 152.49,26.31 152.91,26.73 153.95,26.73 154.69,27.47 154.69,27.97 154.65,28.01 154.65,28.02
  IN1 w0.137: v3(156.99,46.81) 157.36,47.19 157.69,47.19 157.81,47.07 157.81,44.36 159.51,42.66 159.51,41.59 159.91,41.18 162.15,41.18 162.28,41.06 162.28,40.5 162.15,40.37 159.91,40.37 159.51,39.97 159.51,39.15 159.91,38.75 162.02,38.75 162.15,38.62 162.15,38.06 162.02,37.93 159.91,37.93 159.51,37.53 159.51,34.88 155.42,30.79 155.42,29.77 154.65,29 154.65,28.02
  IN4 w0.076: v1(148.93,22.87) 149.07,22.72 149.07,22.56 149.3,22.33 149.43,22.33 v4(149.6,22.15)
  BOTTOM w0.076: v3(156.99,46.81) 156.68,46.5 UD4.F3
DDR_A_DQS7: length 43.7
  IN1 w0.076: v4(147.1,22.39) 147.57,22.86 147.57,25.87 149.03,27.33 149.57,27.33 149.85,27.61 149.85,27.97 149.89,28.01 149.89,28.02
  IN1 w0.137: 149.89,28.02 149.89,33.89 150.11,34.11 152.08,34.11 152.34,34.37 152.34,35.25 152.08,35.51 150.36,35.51 150.14,35.74 150.14,36.43 150.36,36.66 152.05,36.66 152.32,36.93 152.32,37.69 152.05,37.96 150.36,37.96 150.14,38.18 150.14,38.88 150.36,39.1 151.87,39.1 152.32,39.56 152.32,40.12 151.97,40.47 151.58,40.47 151.3,40.75 151.3,41.27 151.65,41.61 151.65,42.11 150.46,43.29 149.53,43.29 148.51,42.28 148.04,42.28 147.52,42.8 147.52,42.95 144.39,46.07 144.39,46.27 144.7,46.58 v3(144.83,46.58)
  IN4 w0.076: v1(147.2,22.87) 147.2,22.48 v4(147.1,22.39)
  BOTTOM w0.076: UD3.F3 144.57,46.5 144.65,46.58 v3(144.83,46.58)
DDR_A_DQS#0: length 43.5
  IN1 w0.076: 158.79,23.02 158.78,23.02 158.72,23.02 157.64,21.94 157.37,21.94 156.73,21.29 v4(156.73,21.14)
  IN1 w0.137: 158.79,23.02 161.47,25.7 161.47,29.47 168.85,36.85 169.22,36.85 169.98,36.09 170.41,36.09 170.9,36.58 170.9,37.01 170.14,37.77 170.14,38.14 170.58,38.58 170.95,38.58 171.59,37.93 172.02,37.93 172.51,38.42 172.51,38.85 171.86,39.49 171.86,39.9 172.29,40.33 172.68,40.33 172.78,40.24 172.81,40.24 172.95,40.1 172.95,40.02 173.43,39.54 173.86,39.54 174.35,40.03 174.35,40.21 174.32,40.24 174.32,40.45 173.56,41.21 173.56,41.6 174.25,42.29 174.75,42.78 174.75,46 173.98,46.76 173.88,46.76 173.72,46.92 v3(173.72,47.05)
  IN4 w0.076: v1(155.62,21.03) 155.72,20.93 156.53,20.93 v4(156.73,21.14)
  BOTTOM w0.076: UD1.G3 173.47,47.3 173.72,47.05 v3(173.72,47.05)
DDR_A_DQS#1: length 40.3
  IN4 w0.076: 158.79,23.72 158.78,23.72 158.73,23.68 157.57,23.68 156.81,22.92 155.81,22.92 155.72,23.01 155.52,23.01 155.28,22.77 v1(155.12,22.77)
  IN4 w0.137: v1(176.16,43.6) 176.16,43.58 175.77,43.2 175.55,43.2 173.04,40.68 172.58,40.68 171.7,39.8 171.7,39.37 172.92,38.15 172.92,37.8 172.48,37.35 172.1,37.35 170.89,38.56 170.46,38.56 169.98,38.07 169.98,37.65 171.21,36.42 171.21,36.08 170.73,35.6 170.4,35.6 169.17,36.83 168.74,36.83 161.47,29.56 161.47,26.11 159.08,23.72 158.79,23.72
  BOTTOM w0.076: UD1.B7 176.48,43.32 176.48,43.58 176.35,43.71 176.26,43.71 v1(176.16,43.6)
DDR_A_DQS#2: length 51.8
  IN1 w0.076: 158.79,17.85 158.78,17.85 158.72,17.79 158.71,17.79 158.68,17.76 157.79,17.76 157.54,17.52 157.54,17.24 v4(157.44,17.14)
  IN1 w0.137: 158.79,17.85 159.3,17.85 165.34,23.89 165.34,24.26 165.34,26.76 168.92,30.34 174.44,30.34 180.54,36.45 180.54,36.82 179.91,37.45 179.91,37.88 180.39,38.37 180.82,38.37 181.46,37.73 181.82,37.73 182.08,37.99 182.08,39.14 182.5,39.56 183.62,39.56 184.42,40.36 184.46,40.36 185.85,41.75 185.85,46.21 186.25,46.61 v3(186.25,46.92)
  IN4 w0.076: v1(155.12,17.57) 155.28,17.57 155.52,17.33 155.72,17.33 155.77,17.38 155.97,17.38 155.99,17.35 156.51,17.35 156.52,17.35 156.91,17.35 156.91,17.35 157.22,17.35 v4(157.44,17.14)
  BOTTOM w0.076: UD2.G3 185.87,47.3 v3(186.25,46.92)
DDR_A_DQS#3: length 47.5
  IN4 w0.076: v1(155.12,19.3) 155.28,19.3 155.52,19.06 155.71,19.06 155.99,19.33 158.73,19.33 158.78,19.29 158.79,19.29
  IN4 w0.137: 158.79,19.29 160.52,19.29 165.53,24.29 165.53,27.46 168.72,30.65 176.96,30.65 183.35,37.04 183.35,37.47 183.02,37.8 183.02,38.09 183.29,38.36 184.64,38.36 185.13,38.85 185.13,39.38 186.01,40.26 186.01,40.48 188.84,43.3 v1(189.06,43.3)
DDR_A_DQS#4: length 42
  IN4 w0.076: v1(148.93,24.87) 148.93,25.28 149.2,25.54 149.78,25.54 149.95,25.71 150.36,25.71 150.65,26 151.41,26 151.99,26.59 153.86,26.59 154.16,26.88 154.65,26.88 155.24,27.47 155.24,28.02
  IN4 w0.137: v1(159.34,43.07) 159.34,43.16 159.24,43.26 159.06,43.26 158.93,43.12 158.93,41.19 159.09,41.03 161.3,41.03 161.91,41.64 162.54,41.64 163.07,41.1 163.35,41.1 163.91,41.66 164.86,41.66 165.24,41.28 165.24,40.75 163.46,38.97 162.93,38.97 162.44,39.45 161.41,39.45 161.24,39.27 161.24,38.89 161.44,38.69 162.02,38.69 162.35,38.36 162.35,37.84 161.52,37 161.24,37 160.39,36.15 159.76,36.15 159.35,36.57 159.08,36.57 158.93,36.42 158.93,35.81 159.36,35.37 159.36,34.85 155.24,30.73 155.24,28.02
  BOTTOM w0.076: v1(159.34,43.07) 159.09,42.82 159.09,42.72 159.19,42.61 159.42,42.61 159.73,42.92 UD4.B7
DDR_A_DQS#5: length 41.4
  IN4 w0.076: v1(147.2,24.87) 147.2,24.87 147.2,25.24 147.38,25.43 147.38,25.54 148.68,26.84 149.27,26.84 149.43,26.99 149.86,26.99 150.16,27.29 150.85,27.29 151.29,27.73 151.29,27.96 151.33,28 151.33,28.02
  IN4 w0.137: 151.33,28.02 151.33,28.61 151.81,29.09 151.81,29.78 151.45,30.14 151.3,30.14 151.19,30.26 151.19,30.85 151.29,30.96 151.46,30.96 151.81,31.31 151.81,32.22 151.45,32.58 151.3,32.58 151.19,32.7 151.19,33.71 151.31,33.83 151.57,33.83 151.75,33.65 152.33,33.65 152.8,34.12 152.8,35.68 152.42,36.07 151.29,36.07 151.19,36.17 151.19,36.78 151.29,36.88 152.42,36.88 152.8,37.27 152.8,38.31 152.41,38.7 150.55,38.7 149.88,39.37 149.88,39.55 149.97,39.64 151.41,39.64 151.81,40.05 151.81,43.3 151.23,43.88 150.67,43.88 149.67,42.89 149.67,41.39 149.51,41.23 149.02,41.23 148.86,41.39 148.86,41.71 148.46,42.11 146.8,42.11 146.63,42.27 146.63,43.47 146.86,43.69 147.46,43.69 147.53,43.62 147.53,43.38 147.46,43.3 v1(147.12,43.3)
DDR_A_DQS#6: length 43.6
  IN1 w0.076: 154.89,28.02 154.89,28.01 154.84,27.97 154.84,27.4 154.01,26.57 152.97,26.57 152.55,26.15 151.54,26.15 150.26,24.88 150.26,24.64 149.65,24.03 149.65,23.03 v4(150.02,22.66)
  IN1 w0.137: v3(156.99,47.6) 157.19,47.4 157.78,47.4 158.02,47.16 158.02,44.45 159.72,42.75 159.72,41.67 160,41.4 162.24,41.4 162.49,41.15 162.49,40.41 162.24,40.16 160.03,40.16 159.75,39.87 159.75,39.25 160.01,38.98 162.12,38.98 162.39,38.72 162.39,37.96 162.12,37.69 160.01,37.69 159.75,37.43 159.75,34.78 155.66,30.69 155.66,29.67 154.89,28.9 154.89,28.02
  IN4 w0.076: v4(150.02,22.66) 149.82,22.86 149.26,22.86 149.18,22.94 149.18,22.96 148.93,23.21 v1(148.93,23.37)
  BOTTOM w0.076: UD4.G3 156.69,47.3 v3(156.99,47.6)
DDR_A_DQS#7: length 43.7
  IN1 w0.076: 149.65,28.02 149.65,28.01 149.7,27.97 149.7,27.67 149.51,27.48 148.96,27.48 147.42,25.94 147.42,23.93 v4(147.25,23.77)
  IN1 w0.137: v3(144.87,47.13) 144.71,46.98 144.59,46.98 144.18,46.58 144.18,45.98 147.31,42.86 147.31,42.71 147.95,42.07 148.6,42.07 149.61,43.08 150.37,43.08 151.43,42.02 151.43,41.7 151.09,41.36 151.09,40.66 151.49,40.26 151.84,40.26 152.08,40.02 152.08,39.65 151.77,39.34 150.27,39.34 149.9,38.98 149.9,38.08 150.27,37.72 151.95,37.72 152.08,37.59 152.08,37.03 151.95,36.9 150.27,36.9 149.9,36.53 149.9,35.64 150.27,35.28 151.98,35.28 152.11,35.15 152.11,34.47 151.98,34.35 150.01,34.35 149.65,33.99 149.65,28.02
  IN4 w0.076: v1(147.2,23.37) 147.07,23.37 147.01,23.43 147.01,23.72 147.06,23.77 v4(147.25,23.77)
  BOTTOM w0.076: UD3.G3 143.84,47.22 143.84,47.03 144.1,46.77 144.46,46.77 144.63,46.93 144.64,46.93 144.84,47.13 v3(144.87,47.13)
DDR_A_MA0: length 116.8
  IN3 w0.076: v3(186.99,52.42) 185.65,52.42 185.26,52.81 183.11,52.81 183.07,52.77 182.71,52.77 182.31,52.37 v4(180.38,52.37) 179.74,52.37 179.55,52.18 176.45,52.18 176.03,51.76 v3(173.72,51.76) ; 151.14,28.02 151.14,27.75 152.54,26.36 152.54,24.47 152.22,24.16 152.22,23.6 151.77,23.15 v4(151.54,23.15) ; v3(144.38,51.76) 144.39,51.77 146.71,51.77 147.11,52.18 149.97,52.18 150.1,52.3 150.98,52.3 v4(151.05,52.37) 152.91,52.37 153.3,52.76 154.81,52.76 154.86,52.81 155.97,52.81 156.12,52.67 157.41,52.67 v3(157.66,52.42)
  IN3 w0.165: 151.14,28.02 151.14,32.98 151.31,33.15 152.31,33.15 152.47,33.31 152.47,33.71 152.31,33.88 151.97,33.88 151.81,34.04 151.81,34.37 151.97,34.54 152.31,34.54 152.47,34.7 152.47,35.11 152.35,35.23 151.94,35.23 151.83,35.35 151.83,36.02 152.15,36.34 152.38,36.34 152.9,35.81 153.14,35.81 153.37,36.04 153.37,36.28 152.84,36.8 152.84,37.04 153.08,37.27 153.31,37.27 153.84,36.74 154.07,36.74 154.31,36.98 154.31,37.21 153.78,37.74 153.78,37.97 154.01,38.21 154.25,38.21 154.77,37.68 155.01,37.68 155.24,37.91 155.24,38.15 154.71,38.67 154.71,38.91 154.95,39.14 155.18,39.14 155.71,38.61 155.94,38.61 158.46,41.13 161.84,41.13 164.77,44.06 164.77,47.31 165.06,47.6 165.06,50.8 166.2,51.95 v3(166.2,53.5)
  IN4 w0.076: v4(151.54,23.15) 151.64,23.15 151.96,23.48 v1(151.96,23.62) ; v4(180.38,52.37) 180.15,52.37 179.77,51.99 179.77,51.99 179.74,51.96 179.13,51.96 178.28,52.81 176.67,52.81 176.56,52.91 175.59,52.91 174.02,54.49 171.06,54.49 170.07,53.5 169.05,53.5 168.91,53.35 168.63,53.35 168.48,53.5 167.67,53.5 167.6,53.42 167.6,53.1 167.52,53.03 167.37,53.03 167.29,53.1 167.29,53.42 167.22,53.5 167.06,53.5 166.99,53.42 166.99,53.1 166.91,53.03 166.76,53.03 166.68,53.1 166.68,53.42 166.61,53.5 v3(166.2,53.5) 166.2,53 166.08,52.88 165.87,52.88 165.75,53 165.75,53.21 165.66,53.29 165.47,53.29 165.34,53.17 165.34,52.9 165.21,52.77 164.96,52.77 164.83,52.9 164.83,53.17 164.7,53.29 161.43,53.29 161.06,52.93 159.21,52.93 158.93,53.21 157.48,53.21 157.33,53.06 156.44,53.06 156.31,52.93 156.13,52.93 156.09,52.97 155.2,52.97 155.12,53.04 153.5,53.04 152.83,52.37 v4(151.05,52.37)
  BOTTOM w0.076: v3(173.72,51.76) 173.6,51.76 UD1.N3 ; UD2.N3 186.67,52.1 v3(186.99,52.42) ; v3(166.2,53.5) 165.59,52.89 RD33.1 ; v3(157.66,52.42) 157.34,52.1 UD4.N3 ; UD3.N3 144.26,51.76 v3(144.38,51.76)
DDR_A_MA1: length 118.6
  IN3 w0.076: v3(175.92,53.41) 176.27,53.75 176.96,53.75 177.19,53.99 179.06,53.99 179.1,54.03 179.14,54.03 179.86,54.75 v4(182.34,54.75) 182.74,54.75 182.86,54.87 183.08,54.87 183.2,54.75 183.8,54.75 184.17,54.39 185.49,54.39 186.06,53.81 186.64,53.81 186.79,53.66 188.23,53.66 188.32,53.57 188.38,53.57 v3(188.64,53.31) ; 153.9,28.02 153.9,27.51 153.99,27.42 154.28,27.42 154.37,27.34 154.37,26.98 153.15,25.76 153.15,24.22 152.83,23.9 152.83,21.95 152.62,21.74 v4(152.26,21.74) ; v3(159.31,53.31) 159.21,53.22 157.86,53.22 157.33,53.75 156.73,53.75 155.89,54.59 153.47,54.59 153.31,54.75 v4(153,54.75) 150.53,54.75 149.79,54.02 147.91,54.02 147.56,53.66 146.84,53.66 v3(146.59,53.41)
  IN3 w0.165: 153.9,28.02 153.9,28.71 154.36,29.18 154.83,29.18 155.03,29.38 155.03,30.37 155.13,30.48 155.66,30.48 156.11,30.93 156.11,33.68 156.34,33.91 156.34,34.14 156.11,34.37 156.11,34.6 156.35,34.84 156.58,34.84 156.81,34.61 157.04,34.61 157.27,34.84 157.27,35.08 156.79,35.56 156.79,35.79 157.03,36.02 157.26,36.02 157.74,35.54 157.97,35.54 158.21,35.78 158.21,36.01 157.73,36.49 157.73,36.72 157.96,36.96 158.2,36.96 158.67,36.48 158.91,36.48 159.14,36.71 159.14,36.94 158.66,37.42 158.66,37.66 158.9,37.89 159.13,37.89 159.61,37.41 159.84,37.41 160.08,37.65 160.08,37.88 159.6,38.36 159.6,38.59 159.83,38.82 160.06,38.82 160.54,38.35 160.78,38.35 161.01,38.58 161.01,38.81 160.53,39.29 160.53,39.53 160.76,39.76 161,39.76 161.48,39.28 161.71,39.28 162.19,39.76 162.45,39.76 166.14,43.44 166.14,46.74 166.44,47.04 166.44,47.64 166.65,47.85 166.91,47.85 167.04,47.97 167.04,48.35 166.88,48.52 166.67,48.52 166.51,48.68 166.51,49.01 166.67,49.18 166.88,49.18 167.04,49.34 167.04,54.08 166.04,55.08 166.04,55.82 166.29,56.08 v3(166.55,56.08)
  IN4 w0.076: v4(152.26,21.74) 151.96,22.05 v1(151.96,22.62) ; v4(182.34,54.75) 181.96,55.13 177.38,55.13 176.58,55.94 169,55.94 168.86,56.08 v3(166.55,56.08) 160.21,56.08 160.1,55.96 160.1,55.86 160.02,55.78 159.87,55.78 159.79,55.86 159.79,55.96 159.72,56.04 159.56,56.04 159.49,55.96 159.49,55.86 159.41,55.78 159.26,55.78 159.18,55.86 159.18,55.96 159.11,56.04 158.95,56.04 158.88,55.96 158.88,55.86 158.8,55.78 158.65,55.78 158.57,55.86 158.57,55.96 158.5,56.04 158.34,56.04 158.27,55.96 158.27,55.86 158.19,55.78 158.04,55.78 157.96,55.86 157.96,55.96 157.89,56.04 157.73,56.04 157.66,55.96 157.66,55.86 157.58,55.78 157.43,55.78 157.35,55.86 157.35,55.96 157.28,56.04 157.12,56.04 157.05,55.96 157.05,55.89 156.97,55.81 156.82,55.81 156.74,55.89 156.74,56.07 156.61,56.2 155.5,56.2 155.05,55.76 154,55.76 153.6,55.36 153.6,55.15 153.41,54.97 153.22,54.97 v4(153,54.75)
  BOTTOM w0.076: UD1.P7 176.26,52.9 175.92,53.24 v3(175.92,53.41) ; RD41.1 166.44,55.97 v3(166.55,56.08) ; v3(159.31,53.31) 159.37,53.37 159.6,53.37 159.73,53.24 UD4.P7 ; v3(188.64,53.31) 188.7,53.37 188.94,53.37 189.06,53.24 UD2.P7 ; v3(146.59,53.41) 146.59,53.21 146.9,52.9 UD3.P7
DDR_A_MA2: length 121.6
  IN3 w0.076: v3(186.52,53.4) 186.26,53.66 185.99,53.66 185.42,54.23 184.11,54.23 183.9,54.44 181.78,54.44 181.68,54.34 181.44,54.34 181.34,54.44 181.17,54.44 181.03,54.3 180.87,54.3 180.73,54.44 180.31,54.44 v4(180.24,54.37) 179.69,54.37 179.16,53.83 177.64,53.83 177.21,53.41 177.21,53.16 177.01,52.96 176.73,52.96 176.63,53.07 174.33,53.07 v3(174.17,52.9) ; 156.72,25.38 156.54,25.2 156.2,25.2 155.34,25.2 155.04,24.9 v4(154.62,24.9) ; v3(157.19,53.4) 156.83,53.4 155.86,54.37 152.86,54.37 152.71,54.22 152.55,54.22 152.4,54.37 152.25,54.37 152.1,54.22 151.94,54.22 151.79,54.37 151.57,54.37 151.47,54.27 151.26,54.27 151.16,54.37 v4(150.91,54.37) 150.36,54.37 149.85,53.87 148.03,53.87 147.95,53.79 147.95,53.15 147.76,52.96 144.96,52.96 v3(144.89,52.9)
  IN3 w0.165: 156.72,25.38 156.78,25.44 156.78,25.62 156.4,26 156.4,26.18 156.63,26.41 156.83,26.41 157.14,26.1 157.31,26.1 157.57,26.36 157.57,26.54 157.34,26.77 157.34,26.92 157.64,27.22 157.82,27.22 158.01,27.03 158.24,27.03 158.96,27.75 159.31,27.75 159.93,28.36 160.16,28.36 160.75,28.96 160.75,29.19 160.29,29.65 160.29,29.88 160.52,30.11 160.76,30.11 161.56,29.31 161.79,29.31 162.02,29.55 162.02,29.78 161.22,30.58 161.22,30.82 161.46,31.05 161.69,31.05 162.05,30.69 162.28,30.69 170.08,38.48 170.08,40.28 169.15,41.21 169.15,46.14 168.1,47.2 168.1,55.16 168.37,55.44 v3(168.84,55.44)
  IN4 w0.076: v4(150.91,54.37) 153.07,54.37 153.62,54.92 156.47,54.92 157.15,55.6 161.16,55.6 161.24,55.52 163.67,55.52 163.75,55.44 163.75,55.08 163.82,55.01 163.98,55.01 164.05,55.08 164.05,55.44 164.13,55.52 164.28,55.52 164.36,55.44 164.36,55.08 164.43,55.01 164.59,55.01 164.66,55.08 164.66,55.44 164.74,55.52 165.07,55.52 165.15,55.44 165.15,55.33 165.22,55.25 165.37,55.25 165.45,55.33 165.45,55.44 165.53,55.52 166.13,55.52 166.33,55.72 168.57,55.72 v3(168.84,55.44) 169.09,55.44 169.17,55.36 169.17,55.21 169.25,55.14 169.4,55.14 169.47,55.21 169.47,55.58 169.55,55.66 169.7,55.66 169.78,55.58 169.78,55.21 169.85,55.14 170.01,55.14 170.08,55.21 170.08,55.58 170.16,55.66 170.31,55.66 170.39,55.58 170.39,55.33 170.46,55.25 170.62,55.25 170.69,55.33 170.69,55.39 170.77,55.47 170.92,55.47 171,55.39 171,55.34 171.07,55.26 171.23,55.26 171.3,55.34 171.3,55.36 171.38,55.44 171.53,55.44 171.61,55.36 171.61,55.34 171.68,55.26 171.84,55.26 171.91,55.34 171.91,55.36 171.99,55.44 172.14,55.44 172.22,55.36 172.22,55.34 172.29,55.26 172.45,55.26 172.52,55.34 172.52,55.36 172.6,55.44 172.75,55.44 172.83,55.36 172.83,55.33 172.9,55.25 173.06,55.25 173.13,55.33 173.13,55.36 173.21,55.44 173.36,55.44 173.44,55.36 173.44,55.33 173.51,55.25 173.66,55.25 173.74,55.33 173.74,55.36 173.82,55.44 173.97,55.44 174.05,55.36 174.05,55.33 174.12,55.25 174.27,55.25 174.35,55.33 174.35,55.36 174.43,55.44 175.56,55.44 175.63,55.5 176.79,55.5 177.32,54.98 178.94,54.98 179.02,54.9 179.02,54.72 179.09,54.64 179.25,54.64 179.32,54.72 179.32,54.9 179.4,54.98 179.55,54.98 179.63,54.9 179.63,54.6 179.7,54.53 179.86,54.53 179.93,54.6 179.93,54.9 180.01,54.98 180.47,54.98 180.55,54.9 180.55,54.74 180.62,54.67 180.78,54.67 180.85,54.74 180.85,54.9 180.93,54.98 181.9,54.98 181.97,54.9 181.97,54.37 181.77,54.17 180.32,54.17 180.24,54.25 v4(180.24,54.37) ; v4(154.62,24.9) 154.3,24.9 154.12,24.72 153.56,24.72 153.45,24.61 153.17,24.61 152.93,24.37 v1(152.39,24.37)
  BOTTOM w0.076: UD2.P3 186.02,52.9 v3(186.52,53.4) ; v3(144.89,52.9) UD3.P3 ; RD39.1 168.82,55.47 v3(168.84,55.44) ; v3(157.19,53.4) 156.69,52.9 UD4.P3 ; UD1.P3 173.33,52.82 174.09,52.82 v3(174.17,52.9)
DDR_A_MA3: length 114.3
  IN3 w0.076: v3(143.52,51.71) 143.52,51.57 143.68,51.41 144.52,51.41 144.64,51.53 145.88,51.53 146.1,51.31 146.1,50.91 146.27,50.74 149.3,50.74 149.85,51.29 v4(150.01,51.29) 150.17,51.45 150.66,51.45 150.74,51.38 150.74,51.33 150.81,51.25 150.96,51.25 151.04,51.33 151.04,51.38 151.12,51.45 151.27,51.45 151.34,51.38 151.34,51.33 151.42,51.25 151.57,51.25 151.65,51.33 151.65,51.38 151.73,51.45 151.88,51.45 151.95,51.38 151.95,51.33 152.03,51.25 152.18,51.25 152.26,51.33 152.26,51.58 152.34,51.66 152.49,51.66 152.56,51.58 152.56,51.33 152.64,51.25 152.79,51.25 152.87,51.33 152.87,51.57 152.95,51.64 153.1,51.64 153.17,51.57 153.17,51.33 153.25,51.25 153.4,51.25 153.48,51.33 153.48,51.38 153.55,51.45 153.81,51.45 153.97,51.62 154.79,51.62 154.96,51.8 155.2,51.8 v3(155.38,51.62) ; 152.16,28.02 152.16,27.48 152.69,26.95 152.69,24.41 152.37,24.09 152.37,23.54 151.52,22.68 v4(151.52,22.63) ; v3(172.85,51.71) 172.85,51.57 173.01,51.41 173.86,51.41 173.97,51.53 175.22,51.53 175.44,51.31 175.44,50.91 175.6,50.74 178.64,50.74 179.18,51.29 v4(179.34,51.29) 179.51,51.45 179.99,51.45 180.07,51.38 180.07,51.33 180.15,51.25 180.3,51.25 180.38,51.33 180.38,51.38 180.45,51.45 180.6,51.45 180.68,51.38 180.68,51.33 180.76,51.25 180.91,51.25 180.98,51.33 180.98,51.38 181.06,51.45 181.21,51.45 181.29,51.38 181.29,51.33 181.37,51.25 181.52,51.25 181.59,51.33 181.59,51.58 181.67,51.66 181.82,51.66 181.9,51.58 181.9,51.33 181.98,51.25 182.13,51.25 182.2,51.33 182.2,51.57 182.28,51.64 182.43,51.64 182.51,51.57 182.51,51.33 182.58,51.25 182.74,51.25 182.81,51.33 182.81,51.38 182.89,51.45 183.14,51.45 183.31,51.62 183.78,51.62 183.96,51.8 184.51,51.8 v3(184.7,51.61)
  IN3 w0.165: v3(166.25,51.31) 166.25,51.25 165.4,50.4 165.4,47.46 165.11,47.17 165.11,43.87 162.03,40.79 158.61,40.79 152.82,34.99 152.82,32.97 152.65,32.81 151.65,32.81 151.48,32.64 151.48,32.31 151.65,32.15 152.72,32.15 152.88,31.98 152.88,31.65 152.72,31.49 151.65,31.49 151.48,31.32 151.48,30.99 151.65,30.82 152.74,30.82 152.91,30.66 152.91,30.33 152.74,30.16 151.65,30.16 151.48,30 151.48,29.67 151.65,29.5 151.99,29.5 152.16,29.34 152.16,29.01 151.99,28.84 151.65,28.84 151.48,28.68 151.48,28.35 151.65,28.18 151.99,28.18 152.16,28.02
  IN4 w0.076: v4(150.01,51.29) 150.17,51.45 154.52,51.45 154.8,51.18 154.8,50.95 155.17,50.57 156.21,50.57 156.55,50.92 156.55,51.42 156.92,51.78 160.37,51.78 160.84,51.31 v3(166.25,51.31) 166.6,51.31 166.67,51.39 166.67,52 166.75,52.08 166.93,52.08 167,52 167,51.48 167.08,51.4 167.23,51.4 167.31,51.48 167.31,52 167.38,52.08 167.54,52.08 167.61,52 167.61,51.48 167.69,51.4 167.84,51.4 167.92,51.48 167.92,52 167.99,52.08 168.15,52.08 168.22,52 168.22,51.48 168.3,51.4 168.45,51.4 168.53,51.48 168.53,52 168.6,52.08 170.94,52.08 170.97,52.1 174.74,52.1 175.78,51.06 176.2,51.06 176.43,51.29 v4(179.34,51.29) ; v1(151.96,23.12) 151.96,23.07 v4(151.52,22.63)
  BOTTOM w0.076: RD45.1 166.35,51.4 v3(166.25,51.31) ; v3(184.7,51.61) 185.06,51.97 UD2.N2 ; v3(172.85,51.71) 172.46,52.1 UD1.N2 ; UD3.N2 143.12,52.1 v3(143.52,51.71) ; v3(155.38,51.62) 155.73,51.97 UD4.N2
DDR_A_MA4: length 119.3
  IN3 w0.076: 157.26,27.84 156.87,27.45 156.27,27.45 156.14,27.32 156.14,26.61 154.81,25.27 153.47,25.27 153.3,25.1 153.3,23.89 v4(153.19,23.78) ; v3(177.63,53.34) 177.91,53.62 178.28,53.62 178.33,53.68 179.27,53.68 179.38,53.79 179.38,53.84 179.46,53.92 179.61,53.92 179.68,53.84 179.68,53.79 179.76,53.71 179.91,53.71 179.99,53.79 179.99,53.9 180.06,53.98 180.22,53.98 180.29,53.9 180.29,53.79 180.37,53.71 180.52,53.71 180.6,53.79 180.6,53.9 180.67,53.98 180.83,53.98 180.9,53.9 180.9,53.79 180.98,53.71 181.13,53.71 181.21,53.79 181.21,53.9 181.28,53.98 181.44,53.98 181.51,53.9 181.51,53.79 181.59,53.71 181.74,53.71 181.82,53.79 181.82,53.95 181.89,54.03 182.05,54.03 182.12,53.95 182.12,53.79 182.2,53.71 182.33,53.71 182.63,54.02 v4(182.87,54.02) 183.39,54.02 183.46,54.08 185.27,54.08 186.3,53.05 186.7,53.05 186.78,53.13 188.18,53.13 188.34,52.96 189.11,52.96 v3(189.46,53.31) ; v3(148.29,53.34) 148.54,53.34 148.92,53.71 149.97,53.71 150.04,53.79 150.04,53.84 150.12,53.92 150.27,53.92 150.35,53.84 150.35,53.79 150.43,53.71 150.58,53.71 150.65,53.79 150.65,53.9 150.73,53.98 150.88,53.98 150.96,53.9 150.96,53.79 151.03,53.71 151.19,53.71 151.26,53.79 151.26,53.9 151.34,53.98 151.49,53.98 151.57,53.9 151.57,53.79 151.64,53.71 151.8,53.71 151.87,53.79 151.87,53.9 151.95,53.98 152.1,53.98 152.18,53.9 152.18,53.79 152.25,53.71 152.41,53.71 152.48,53.79 152.48,53.9 152.56,53.98 152.71,53.98 152.79,53.9 152.79,53.79 152.86,53.71 152.99,53.71 153.3,54.02 v4(153.54,54.02) 154.06,54.02 154.12,54.08 155.94,54.08 157.05,52.97 159.78,52.97 v3(160.13,53.31)
  IN3 w0.165: v3(166.48,55.34) 166.48,55.54 166.61,55.67 167.27,55.67 167.4,55.54 167.4,55.29 167.27,55.16 166.99,55.16 166.86,55.03 166.86,54.73 166.99,54.6 167.26,54.6 167.38,54.48 167.38,46.91 168.4,45.89 168.4,41.55 168.1,41.25 168.01,41.25 167.47,40.72 167.47,40.39 167.98,39.88 169.23,39.88 169.39,39.71 169.39,39.38 169.23,39.22 168.24,39.22 168.07,39.05 168.07,38.65 167.86,38.44 167.86,38.21 168.23,37.84 168.23,37.61 168,37.37 167.76,37.37 167.25,37.89 167.07,37.89 166.78,37.6 166.78,37.42 167.3,36.91 167.3,36.67 167.06,36.44 166.83,36.44 166.46,36.81 166.23,36.81 164.36,34.94 161.53,32.11 158.1,28.68 157.87,28.68 157.52,29.03 157.34,29.03 157.05,28.74 157.05,28.56 157.4,28.21 157.4,27.98 157.26,27.84
  IN4 w0.076: v1(152.83,23.62) 153.03,23.62 v4(153.19,23.78) ; v4(182.87,54.02) 182.42,54.02 182.35,53.94 182.35,53.6 182.27,53.52 182.12,53.52 182.04,53.6 182.04,53.94 181.97,54.02 181.81,54.02 181.74,53.94 181.74,53.6 181.66,53.52 181.51,53.52 181.43,53.6 181.43,53.94 181.36,54.02 179.5,54.02 178.69,54.83 177.25,54.83 176.73,55.35 175.69,55.35 175.44,55.1 170.38,55.1 170.27,54.98 168.62,54.98 168.26,55.34 v3(166.48,55.34) 165.72,55.34 165.64,55.26 165.64,54.79 165.57,54.72 163.34,54.72 163.26,54.79 163.26,55.14 163.19,55.21 163.03,55.21 162.96,55.14 162.96,54.79 162.88,54.72 162.73,54.72 162.65,54.79 162.65,55.15 162.58,55.22 162.42,55.22 162.35,55.15 162.35,54.79 162.27,54.72 161.83,54.72 161.1,55.45 157.22,55.45 156.45,54.68 156.45,54.55 156.38,54.48 156.38,54.29 156.3,54.22 156.15,54.22 156.07,54.29 156.07,54.48 155.99,54.55 155.84,54.55 155.77,54.48 155.77,54.29 155.69,54.22 155.54,54.22 155.46,54.29 155.46,54.55 155.38,54.63 155.23,54.63 155.16,54.55 155.16,54.29 155.08,54.22 154.93,54.22 154.85,54.29 154.85,54.63 154.78,54.7 154.62,54.7 154.55,54.63 154.55,54.29 154.47,54.22 154.32,54.22 154.24,54.29 154.24,54.6 154.17,54.68 154.01,54.68 153.94,54.6 153.94,54.29 153.86,54.22 153.74,54.22 v4(153.54,54.02)
  BOTTOM w0.076: UD3.P8 147.92,52.96 v3(148.29,53.34) ; v3(160.13,53.31) 160.53,52.91 UD4.P8 ; v3(166.48,55.34) 166.1,54.96 RD37.1 ; UD1.P8 177.25,52.96 v3(177.63,53.34) ; UD2.P8 189.86,52.91 v3(189.46,53.31)
DDR_A_MA5: length 120.1
  IN3 w0.076: v3(143.47,52.47) 143.94,52 144.14,52 144.24,52.1 144.52,52.1 144.62,52 145.97,52 146.45,52.48 149.61,52.48 v4(149.78,52.65) 150.1,52.96 150.32,52.96 150.43,52.86 150.43,52.72 150.51,52.64 150.66,52.64 150.74,52.72 150.74,52.99 150.81,53.07 150.96,53.07 151.04,52.99 151.04,52.98 151.12,52.9 151.27,52.9 151.34,52.98 151.34,52.99 151.42,53.07 151.57,53.07 151.65,52.99 151.65,52.98 151.73,52.9 151.88,52.9 151.95,52.98 151.95,52.99 152.03,53.07 154.68,53.07 154.93,53.31 v3(155.34,53.31) ; v3(172.88,52.48) 173.11,52.48 173.46,52.13 174.15,52.13 174.66,52.63 179.1,52.63 v4(179.11,52.65) 179.36,52.65 179.44,52.72 179.44,53 179.51,53.08 179.78,53.08 179.85,53 179.85,52.91 179.93,52.84 180.08,52.84 180.16,52.91 180.16,53 180.23,53.08 182.93,53.08 183.08,53.23 183.93,53.23 184.22,53.52 184.6,53.52 184.67,53.44 v3(184.67,53.31) ; 157.26,24.53 156.66,23.93 v4(153.73,23.93)
  IN3 w0.165: v3(169.15,54.45) 169.18,54.42 169.18,53.43 168.78,53.03 168.78,47.6 169.84,46.55 169.84,41.49 170.76,40.56 170.76,37.17 170.48,36.89 170.48,36.65 170.6,36.54 170.6,36.3 170.37,36.07 170.13,36.07 170.02,36.19 169.78,36.19 169.55,35.95 169.55,35.72 169.66,35.6 169.66,35.37 169.43,35.14 169.2,35.14 169.08,35.25 168.85,35.25 168.61,35.02 168.61,34.78 168.73,34.67 168.73,34.43 168.5,34.2 168.26,34.2 168.15,34.32 167.91,34.32 167.68,34.08 167.68,33.85 167.8,33.73 167.8,33.5 167.56,33.27 167.33,33.27 167.21,33.38 166.98,33.38 166.75,33.15 166.75,32.92 166.86,32.8 166.86,32.57 166.63,32.33 166.39,32.33 166.28,32.45 166.05,32.45 165.81,32.22 165.81,31.98 165.93,31.87 165.93,31.63 165.69,31.4 165.46,31.4 165.34,31.51 165.11,31.51 164.88,31.28 164.88,31.05 164.99,30.93 164.99,30.7 164.76,30.46 164.53,30.46 164.41,30.58 164.18,30.58 159.44,25.84 158.58,25.84 157.26,24.53
  IN4 w0.076: v1(152.83,24.12) 153.54,24.12 v4(153.73,23.93) ; v4(149.78,52.65) 150.12,52.65 150.58,53.1 152.67,53.1 152.91,53.35 154.53,53.35 155.08,53.9 158.55,53.9 159.1,54.45 161.05,54.45 161.7,53.8 161.98,53.8 162.06,53.88 162.06,54.04 162.13,54.12 162.28,54.12 162.36,54.04 162.36,53.88 162.44,53.8 162.59,53.8 162.67,53.88 162.67,54.04 162.74,54.12 162.89,54.12 162.97,54.04 162.97,53.88 163.05,53.8 163.2,53.8 163.28,53.88 163.28,54.04 163.35,54.12 163.5,54.12 163.58,54.04 163.58,53.88 163.66,53.8 165.22,53.8 165.57,54.15 168.84,54.15 v3(169.15,54.45) 169.73,54.45 169.81,54.38 169.81,54.02 169.89,53.94 170.04,53.94 170.11,54.02 170.11,54.38 170.19,54.45 170.42,54.45 170.76,54.79 174.15,54.79 174.45,54.49 176.08,54.49 176.16,54.41 176.16,54.27 176.24,54.19 176.39,54.19 176.46,54.27 176.46,54.41 176.54,54.49 177.19,54.49 177.27,54.41 177.27,53.76 177.34,53.69 177.49,53.69 177.57,53.76 177.57,54.41 177.65,54.49 177.81,54.49 178.04,54.26 178.14,54.26 178.34,54.46 178.45,54.46 178.56,54.35 178.56,54.25 178.2,53.89 178.2,53.77 178.29,53.68 178.42,53.68 178.8,54.05 178.9,54.05 179.01,53.95 179.01,53.84 178.79,53.61 178.79,53.49 178.88,53.4 179,53.4 179.26,53.65 179.36,53.65 179.47,53.54 179.47,53.44 179.29,53.25 179.29,53.17 179.37,53.08 179.92,53.08 180.08,53.24 181.58,53.24 181.66,53.17 181.66,52.97 181.58,52.89 180.24,52.89 179.65,52.3 179.23,52.3 179.11,52.41 v4(179.11,52.65)
  BOTTOM w0.076: v3(155.34,53.31) 155.73,52.92 UD4.P2 ; UD1.P2 172.46,52.9 v3(172.88,52.48) ; v3(169.15,54.45) 169.14,54.45 RD51.1 ; UD2.P2 185.06,52.92 v3(184.67,53.31) ; UD3.P2 143.12,52.82 v3(143.47,52.47)
DDR_A_MA6: length 115.7
  IN3 w0.076: v3(147.49,54.11) 147.61,54.22 149.74,54.22 150.43,54.91 150.92,54.91 151,54.98 151,55.21 151.07,55.28 151.22,55.28 151.3,55.21 151.3,55.03 151.38,54.96 151.53,54.96 151.6,55.03 151.6,55.21 151.68,55.28 151.83,55.28 151.91,55.21 151.91,55.08 151.99,55.01 152.14,55.01 152.21,55.08 152.21,55.21 152.29,55.28 152.44,55.28 152.52,55.21 152.52,55.08 152.59,55.01 152.75,55.01 152.82,55.08 152.82,55.21 152.9,55.28 v4(153.28,55.28) 153.52,55.28 153.77,55.03 154.97,55.03 155.24,54.75 156,54.75 156.84,53.92 157.38,53.92 157.52,53.77 159.79,53.77 v3(160.12,54.1) ; v4(155.54,25.52) 156.08,25.52 156.17,25.61 156.17,26.27 157.26,27.36 ; v3(189.46,54.1) 189.08,53.73 188.38,53.73 188.29,53.81 186.85,53.81 186.7,53.97 186.12,53.97 185.55,54.54 184.23,54.54 183.79,54.98 183.35,54.98 183.05,55.28 v4(182.62,55.28) 182.23,55.28 182.16,55.21 182.16,55.08 182.08,55.01 181.93,55.01 181.85,55.08 181.85,55.21 181.78,55.28 181.62,55.28 181.55,55.21 181.55,55.08 181.47,55.01 181.32,55.01 181.24,55.08 181.24,55.21 181.17,55.28 181.02,55.28 180.94,55.21 180.94,55.03 180.86,54.96 180.71,54.96 180.63,55.03 180.63,55.21 180.56,55.28 180.41,55.28 180.33,55.21 180.33,54.98 180.26,54.91 179.76,54.91 178.99,54.14 176.86,54.14 v3(176.83,54.11)
  IN3 w0.165: v3(167.85,57.12) 167.74,57 167.74,47.05 168.77,46.02 168.77,46.01 168.81,45.97 168.81,41.47 168.17,40.83 168.17,40.38 168.3,40.25 169.46,40.25 169.74,39.97 169.74,38.63 169.63,38.52 169.39,38.52 169.08,38.83 168.85,38.83 168.61,38.6 168.61,38.36 168.93,38.05 168.93,37.82 167.06,35.95 166.83,35.95 166.46,36.32 166.23,36.32 166,36.08 166,35.85 166.36,35.48 166.36,35.25 166.13,35.02 165.89,35.02 165.53,35.38 165.3,35.38 165.06,35.15 165.06,34.91 165.43,34.55 165.43,34.32 165.19,34.08 164.96,34.08 164.59,34.45 164.36,34.45 164.13,34.21 164.13,33.98 164.49,33.62 164.49,33.38 164.26,33.15 164.03,33.15 163.66,33.51 163.43,33.51 163.19,33.28 163.19,33.05 163.56,32.68 163.56,32.45 163.32,32.21 163.09,32.21 162.73,32.58 162.49,32.58 162.26,32.35 162.26,32.11 162.62,31.75 162.62,31.51 162.39,31.28 162.16,31.28 161.79,31.64 161.56,31.64 160.62,30.71 160.62,30.71 159.53,29.63 158.33,28.43 157.26,27.36
  IN4 w0.076: v4(155.54,25.52) 155.29,25.27 154.46,25.27 154.06,24.87 153.34,24.87 v1(153.34,24.87) ; v4(153.28,55.28) 153.91,55.91 154.99,55.91 155.43,56.35 164.34,56.35 164.42,56.27 165.28,56.27 165.35,56.34 165.35,56.58 165.43,56.66 166.32,56.66 166.77,57.12 v3(167.85,57.12) 168.12,57.12 169.14,56.09 178.23,56.09 179.03,55.28 v4(182.62,55.28)
  BOTTOM w0.076: UD4.R8 160.52,53.7 v3(160.12,54.1) ; UD3.R8 147.9,53.7 v3(147.49,54.11) ; v3(189.46,54.1) 189.86,53.7 UD2.R8 ; RD43.1 168.13,56.84 v3(167.85,57.12) ; v3(176.83,54.11) 177.23,53.7 UD1.R8
DDR_A_MA7: length 121.4
  IN3 w0.076: v3(185.47,53.31) 185.47,53.66 185.21,53.93 185.01,53.93 184.93,53.85 184.93,53.74 184.85,53.66 184.7,53.66 184.62,53.74 184.62,53.85 184.55,53.93 184.19,53.93 184.07,53.8 184.07,53.58 183.87,53.38 183.01,53.38 182.95,53.32 182.95,53.31 182.87,53.23 182.72,53.23 182.64,53.31 182.64,53.32 182.57,53.4 182.41,53.4 182.34,53.32 182.34,53.31 182.26,53.23 182.11,53.23 182.03,53.31 182.03,53.32 181.96,53.4 181.8,53.4 181.73,53.32 181.73,53.31 181.65,53.23 181.5,53.23 181.42,53.31 181.42,53.45 181.35,53.52 181.19,53.52 181.12,53.45 181.12,53.4 181.04,53.32 180.81,53.32 180.74,53.4 v4(179.79,53.4) 179.02,53.4 178.41,52.79 174.57,52.79 174.34,52.56 174.02,52.56 173.26,53.32 v3(172.84,53.32) ; v3(143.51,53.32) 143.98,53.32 144.83,52.47 146.13,52.47 146.36,52.7 148.98,52.7 149.68,53.4 v4(150.45,53.4) 151.4,53.4 151.48,53.32 151.48,53.31 151.55,53.23 151.71,53.23 151.78,53.31 151.78,53.32 151.86,53.4 152.01,53.4 152.09,53.32 152.09,53.31 152.16,53.23 152.32,53.23 152.39,53.31 152.39,53.32 152.47,53.4 152.62,53.4 152.7,53.32 152.7,53.31 152.77,53.23 152.93,53.23 153,53.31 153,53.32 153.08,53.4 153.23,53.4 153.31,53.32 153.31,53.31 153.38,53.23 153.54,53.23 153.61,53.31 153.61,53.32 153.69,53.4 154.03,53.4 154.21,53.22 154.58,53.22 154.73,53.37 154.73,53.8 154.86,53.93 155.87,53.93 156.14,53.66 v3(156.14,53.31) ; 149.83,28.02 149.83,27.28 151.97,25.15 151.97,24.06 v4(151.55,23.64)
  IN3 w0.165: 149.83,28.02 149.83,34.36 150,34.53 150.96,34.53 151.12,34.7 151.12,35.19 150.96,35.36 150,35.36 149.83,35.52 149.83,36.44 149.94,36.54 150.17,36.54 150.68,36.04 150.91,36.04 151.15,36.27 151.15,36.5 150.64,37.01 150.64,37.25 153.63,40.24 156.36,40.24 157.95,41.83 159.97,41.83 160.67,42.52 162.07,42.52 163.4,43.85 163.4,44.32 164.35,45.27 164.35,47.37 164.7,47.73 164.7,50.93 165.07,51.29 165.07,52.12 165.16,52.21 165.56,52.21 165.79,52.44 165.79,54.13 165.54,54.37 v3(165.11,54.37)
  IN4 w0.076: v4(150.45,53.4) 150.81,53.4 150.89,53.47 150.89,53.85 150.98,53.94 151.11,53.94 151.19,53.85 151.19,53.47 151.27,53.4 151.42,53.4 151.5,53.47 151.5,53.85 151.59,53.94 151.72,53.94 151.8,53.85 151.8,53.47 151.88,53.4 152.03,53.4 152.11,53.47 152.11,53.8 152.19,53.88 152.34,53.88 152.41,53.8 152.41,53.47 152.49,53.4 152.75,53.4 152.85,53.5 153.68,53.5 154.25,54.07 156.48,54.07 156.84,54.42 156.84,54.86 157.28,55.3 157.46,55.3 157.53,55.22 157.53,54.86 157.61,54.78 157.76,54.78 157.84,54.86 157.84,55.22 157.91,55.3 158.07,55.3 158.14,55.22 158.14,54.86 158.22,54.78 158.37,54.78 158.45,54.86 158.45,55.22 158.52,55.3 161.01,55.3 161.94,54.37 v3(165.11,54.37) 165.95,54.37 166.02,54.45 166.02,54.84 166.11,54.93 166.24,54.93 166.33,54.84 166.33,54.45 166.41,54.37 166.56,54.37 166.63,54.45 166.63,54.89 166.72,54.98 166.85,54.98 166.94,54.89 166.94,54.45 167.02,54.37 167.17,54.37 167.24,54.45 167.24,54.79 167.33,54.88 167.46,54.88 167.55,54.79 167.55,54.45 167.62,54.37 167.75,54.37 167.83,54.45 167.83,54.78 167.88,54.83 168.08,54.83 168.15,54.75 168.15,54.45 168.23,54.37 168.38,54.37 168.46,54.45 168.46,54.75 168.54,54.83 170.33,54.83 170.44,54.95 174.32,54.95 174.39,54.87 174.39,54.78 174.47,54.7 174.62,54.7 174.7,54.78 174.7,54.87 174.77,54.95 174.93,54.95 175,54.87 175,54.78 175.08,54.7 175.23,54.7 175.31,54.78 175.31,54.87 175.38,54.95 175.53,54.95 175.78,55.2 176.26,55.2 176.31,55.15 176.31,54.83 176.47,54.68 178.5,54.68 179.27,53.9 179.4,53.9 179.79,53.52 v4(179.79,53.4) ; v1(151.96,24.12) 151.96,24.07 151.55,23.66 v4(151.55,23.64)
  BOTTOM w0.076: UD3.R2 143.12,53.7 v3(143.51,53.32) ; v3(185.47,53.31) 185.08,53.7 UD2.R2 ; v3(156.14,53.31) 155.75,53.7 UD4.R2 ; v3(165.11,54.37) 165.59,53.89 RD55.1 ; UD1.R2 172.46,53.7 v3(172.84,53.32)
DDR_A_MA8: length 129
  IN3 w0.076: v3(160.13,54.95) 159.83,55.26 157.63,55.26 155.49,57.4 154.28,57.4 154.03,57.16 153.31,57.16 152.89,57.57 v4(152.64,57.57) 151.54,57.57 151.36,57.4 151.25,57.4 151.07,57.58 150.96,57.58 150.85,57.47 150.85,57.36 151.04,57.18 151.04,57.07 150.93,56.96 150.82,56.96 150.64,57.15 150.53,57.15 150.42,57.04 150.42,56.93 150.6,56.75 150.6,56.64 150.5,56.53 150.39,56.53 150.21,56.71 150.1,56.71 149.99,56.61 149.99,56.5 150.17,56.32 150.17,56.21 150.07,56.1 149.96,56.1 149.78,56.28 149.67,56.28 149.56,56.18 149.56,56.07 149.74,55.89 149.74,55.78 149.47,55.5 148.88,55.5 148.8,55.58 148.8,55.78 148.73,55.86 148.57,55.86 148.5,55.78 148.5,55.58 148.42,55.5 148.16,55.5 v3(147.92,55.75) ; v3(189.47,54.95) 189.16,55.26 186.81,55.26 184.49,57.57 v4(181.97,57.57) 181.29,57.57 180.44,56.72 180.28,56.72 180,56.44 179.89,56.44 179.88,56.46 179.77,56.46 179.66,56.35 179.66,56.24 179.68,56.23 179.68,56.12 179.48,55.92 179.38,55.92 179.05,56.25 178.95,56.25 178.84,56.14 178.84,56.03 179.16,55.71 179.16,55.6 179.05,55.49 178.94,55.49 178.62,55.81 178.52,55.81 178.41,55.71 178.41,55.6 178.73,55.28 178.73,55.17 178.62,55.06 177.47,55.06 177.25,55.27 v3(177.25,55.75) ; v4(150.51,22.56) 150.29,22.34 149.89,22.34 149.48,22.76 149.48,24.11 146.67,26.92 146.67,27.77 146.5,27.94 146.5,28.02
  IN3 w0.165: v3(163.74,58.11) 163.74,57.54 162.19,55.99 162.19,51.53 161.44,50.78 161.44,48.34 160.21,47.12 158.06,47.12 156.18,45.23 153.31,45.23 153.04,44.96 151.26,44.96 146.5,40.19 146.5,28.02
  IN4 w0.076: v4(150.51,22.56) 150.51,23.21 v1(150.66,23.37) ; v4(152.64,57.57) 152.64,57.95 153.21,58.53 158.33,58.53 158.41,58.45 158.41,58.01 158.48,57.93 158.63,57.93 158.71,58.01 158.71,58.45 158.79,58.53 158.94,58.53 159.02,58.45 159.02,58.01 159.09,57.93 159.24,57.93 159.32,58.01 159.32,58.45 159.4,58.53 159.55,58.53 159.63,58.45 159.63,58.01 159.7,57.93 159.85,57.93 159.93,58.01 159.93,58.45 160.01,58.53 160.16,58.53 160.23,58.45 160.23,58.01 160.31,57.93 160.46,57.93 160.54,58.01 160.54,58.45 160.62,58.53 160.77,58.53 160.84,58.45 160.84,58.01 160.92,57.93 161.07,57.93 161.15,58.01 161.15,58.45 161.23,58.53 161.38,58.53 161.45,58.45 161.45,58.01 161.53,57.93 161.68,57.93 161.76,58.01 161.76,58.45 161.83,58.53 161.99,58.53 162.06,58.45 162.06,58.01 162.14,57.93 162.29,57.93 162.37,58.01 162.37,58.45 162.44,58.53 162.6,58.53 162.67,58.45 162.67,57.99 162.75,57.92 162.9,57.92 162.98,57.99 162.98,58.29 163.05,58.36 163.26,58.36 163.33,58.29 163.33,58.18 163.41,58.11 v3(163.74,58.11) 164.62,58.11 164.8,58.29 168.91,58.29 169.7,57.51 179.25,57.51 180.1,56.66 180.76,56.66 181.09,57 181.09,57.62 181.17,57.7 181.89,57.7 181.97,57.62 v4(181.97,57.57)
  BOTTOM w0.076: v3(189.47,54.95) 189.86,54.56 UD2.T8 ; v3(160.13,54.95) 160.53,54.56 UD4.T8 ; v3(163.74,58.11) 163.89,57.96 RD57.1 ; v3(177.25,55.75) 176.95,55.44 176.95,54.81 UD1.T8 ; v3(147.92,55.75) UD3.T8
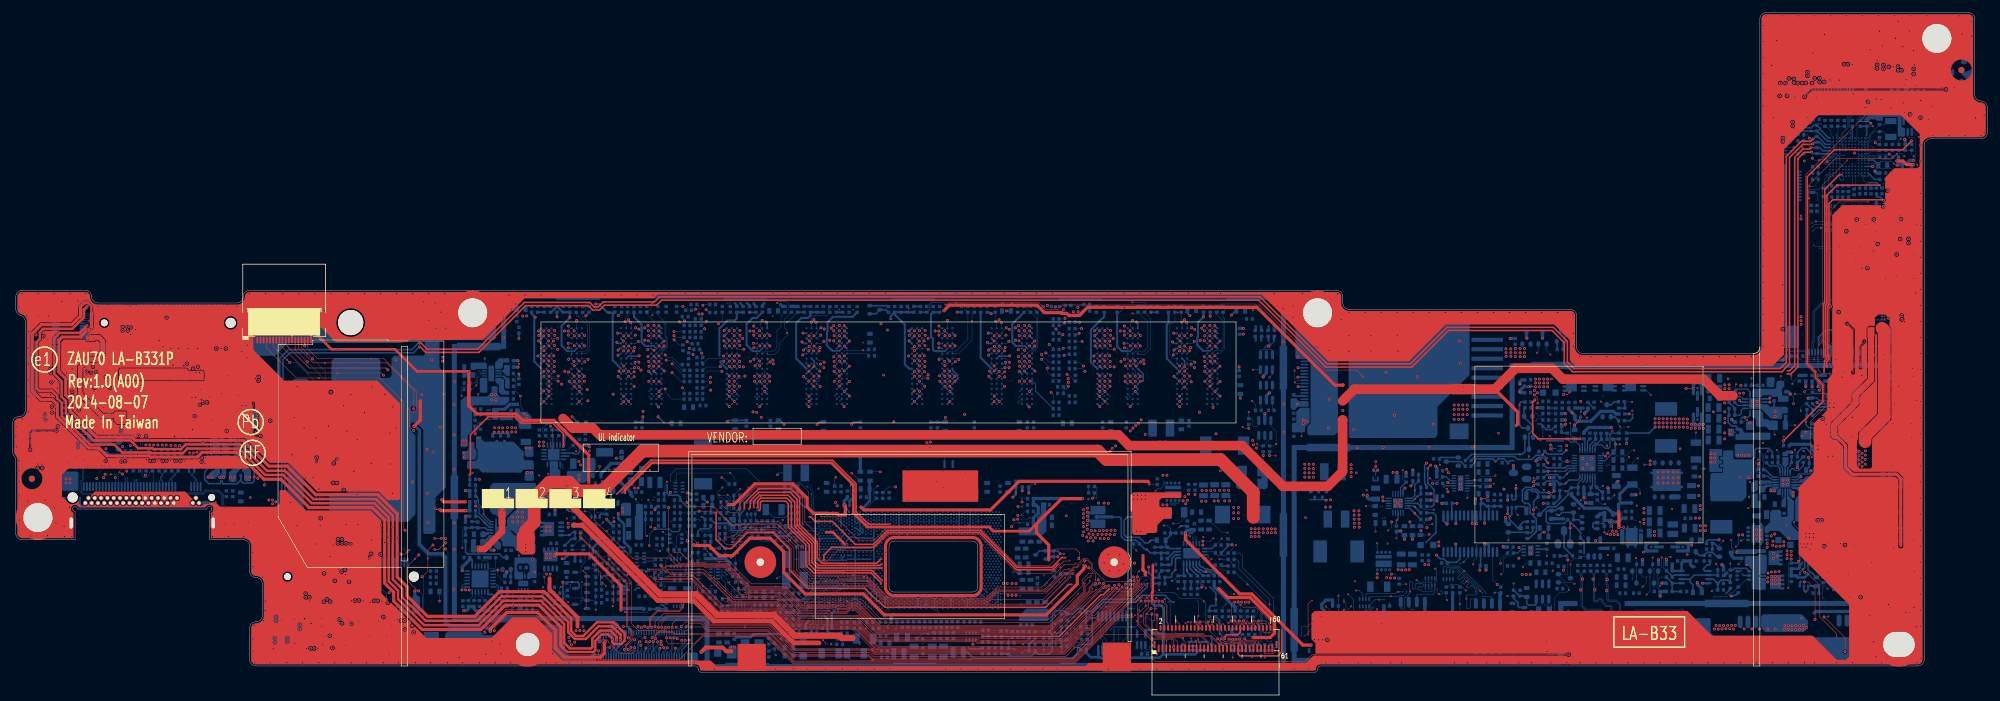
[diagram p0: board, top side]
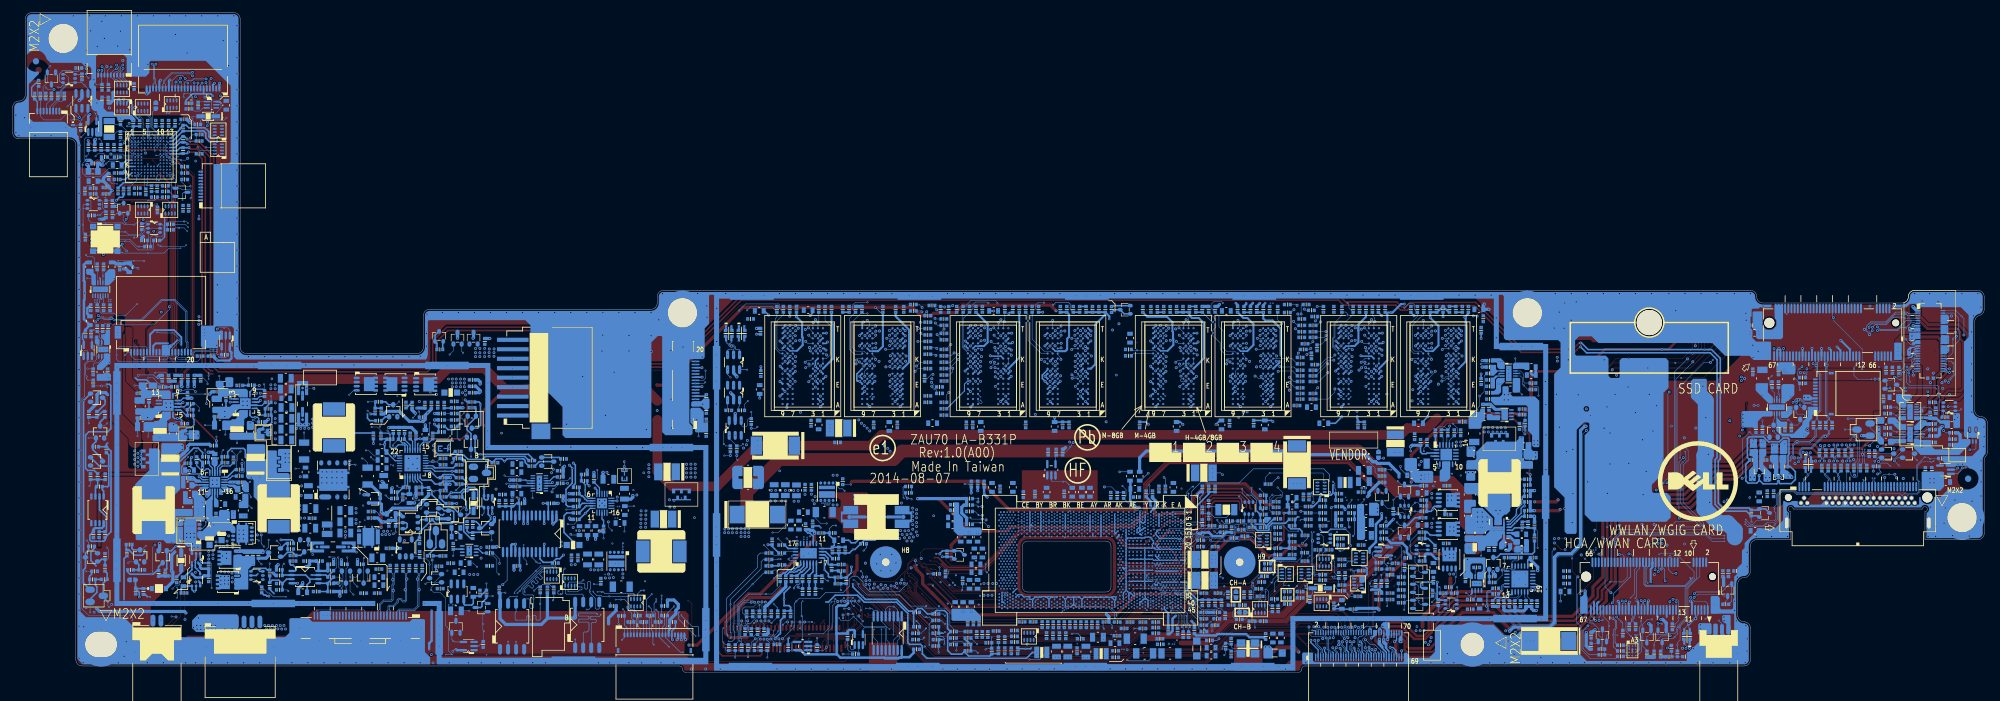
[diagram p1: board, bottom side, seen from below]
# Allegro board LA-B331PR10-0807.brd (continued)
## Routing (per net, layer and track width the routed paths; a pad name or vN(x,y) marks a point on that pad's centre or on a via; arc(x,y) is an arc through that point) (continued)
DDR_A_MA9: length 119.5
  IN3 w0.076: v3(186.57,54.58) 186.57,54.37 186.48,54.27 186.25,54.27 185.75,54.77 185.68,54.84 184.36,54.84 183.91,55.29 183.47,55.29 182.65,56.11 182.15,56.11 182.03,55.99 181.86,55.99 181.73,56.11 181.6,56.11 181.53,56.04 181.53,55.68 181.45,55.61 181.3,55.61 181.22,55.68 181.22,56.04 181.14,56.11 180.99,56.11 180.92,56.04 180.92,55.86 180.84,55.78 v4(180.64,55.78) 180.2,55.78 178.87,54.44 177.19,54.44 176.93,54.7 176.26,54.7 176.07,54.51 175.28,54.51 174.15,53.38 v3(173.74,53.38) ; v4(151.55,22.15) 151.77,22.15 152.52,22.91 152.52,24.03 152.84,24.35 152.84,27.01 152.58,27.28 152.58,28.02 ; v3(157.24,54.58) 157.24,54.38 157.14,54.27 156.91,54.27 156.13,55.06 155.37,55.06 155.1,55.33 154.04,55.33 153.3,56.08 152.38,56.08 152.3,56 152.3,55.68 152.23,55.61 152.07,55.61 152,55.68 152,56 151.92,56.08 151.77,56.08 151.69,56 151.69,55.86 151.62,55.78 v4(151.3,55.78) 150.61,55.78 149.52,54.69 146.93,54.69 146.72,54.48 145.91,54.48 144.82,53.38 v3(144.41,53.38)
  IN3 w0.165: v3(166.25,57.42) 166.25,56.55 165.66,55.95 165.66,54.91 166.69,53.88 166.69,51.08 165.75,50.14 165.75,47.32 165.45,47.02 165.45,43.73 162.17,40.44 159.61,40.44 159.31,40.14 158.55,40.14 154.91,36.51 154.91,36.27 155.49,35.7 155.49,35.47 155.26,35.23 155.02,35.23 154.45,35.81 154.21,35.81 154.07,35.67 154.07,35.24 153.91,35.08 153.39,35.08 153.22,34.91 153.22,34.58 153.39,34.42 153.91,34.42 154.07,34.25 154.07,33.92 153.91,33.76 153.39,33.76 153.22,33.59 153.22,33.26 153.39,33.1 153.91,33.1 154.07,32.93 154.07,32.6 153.91,32.43 153.39,32.43 153.22,32.27 153.22,31.94 153.59,31.57 153.59,29.96 153.36,29.73 153.12,29.73 153.03,29.82 152.79,29.82 152.58,29.61 152.58,29.09 152.74,28.92 152.87,28.92 153.03,28.76 153.03,28.43 152.87,28.26 152.74,28.26 152.58,28.1 152.58,28.02
  IN4 w0.076: v1(151.09,22.62) 151.09,22.52 151.46,22.15 v4(151.55,22.15) ; v4(180.64,55.78) 180.46,55.78 180.08,56.16 179.97,56.16 179.79,55.98 179.69,55.98 179.58,56.09 179.58,56.19 179.68,56.3 179.68,56.41 179.57,56.51 179.47,56.51 179.3,56.35 179.19,56.35 179.04,56.51 172.5,56.51 172.2,56.81 169.47,56.81 168.84,57.44 168.38,57.44 168.18,57.64 166.47,57.64 v3(166.25,57.42) 165.97,57.14 164.83,57.14 164.54,57.43 158.86,57.43 158.18,56.75 155.4,56.75 154.86,56.22 151.73,56.22 v4(151.3,55.78)
  BOTTOM w0.076: UD4.R3 156.53,53.87 v3(157.24,54.58) ; UD1.R3 173.42,53.7 v3(173.74,53.38) ; UD2.R3 185.86,53.87 v3(186.57,54.58) ; RD47.1 166.56,57.73 v3(166.25,57.42) ; v3(144.41,53.38) 144.09,53.7 UD3.R3
DDR_A_MA10: length 125.6
  IN3 w0.076: v3(175.95,49.57) 175.95,49.08 176.03,49 176.32,49 176.39,49.08 176.39,49.6 176.47,49.67 177.89,49.67 178.05,49.52 178.05,48.74 178.51,48.28 v4(181.56,48.28) 183.09,48.28 183.92,49.1 184.15,49.1 184.38,49.33 185.51,49.33 186.19,50 188.57,50 v3(188.59,49.98) ; 154.82,27.74 154.82,26.98 v4(153.46,25.63) ; v3(146.62,49.57) 146.62,49.08 146.69,49 146.98,49 147.06,49.08 147.06,49.6 147.14,49.67 148.56,49.67 148.71,49.52 148.71,48.74 149.17,48.28 v4(152.23,48.28) 154.16,48.28 155.06,49.18 156.02,49.18 156.62,49.77 158.95,49.77 v3(159.18,50)
  IN3 w0.165: 154.82,27.74 154.82,27.91 154.71,28.02 154.44,28.02 154.28,28.19 154.28,28.52 154.44,28.68 154.91,28.68 155.8,29.57 155.8,29.58 155.94,29.72 155.94,29.93 155.89,29.99 155.89,30.22 156.94,31.27 157.37,31.27 157.54,31.44 157.54,31.7 157.37,31.86 156.62,31.86 156.46,32.03 156.46,32.36 156.62,32.52 157.31,32.52 157.48,32.69 157.48,32.85 156.74,33.59 156.74,33.82 156.97,34.05 157.2,34.05 157.83,33.43 158.06,33.43 158.3,33.66 158.3,33.9 157.67,34.52 157.67,34.76 157.89,34.97 158.12,34.97 158.43,34.66 158.6,34.66 158.77,34.83 158.77,35.85 159.83,36.91 160.11,36.91 160.41,36.62 160.64,36.62 160.87,36.85 160.87,37.08 160.55,37.4 160.55,37.64 161.14,38.23 161.93,39.01 162.16,39.01 162.46,38.71 162.7,38.72 162.93,38.95 162.93,39.18 162.79,39.32 162.79,39.55 164.42,41.18 164.65,41.18 165.32,40.5 165.5,40.5 165.79,40.79 165.79,40.97 165.25,41.51 165.25,41.69 165.54,41.98 165.72,41.98 166.1,41.6 166.28,41.6 166.75,42.07 166.75,42.25 166.66,42.35 166.57,42.35 166.44,42.48 166.44,42.88 166.48,42.92 166.48,46.6 166.79,46.9 166.79,47.16 166.81,47.19 166.81,47.19 v3(166.86,47.19)
  IN4 w0.076: v4(181.56,48.28) 181.21,47.92 180.89,47.92 180.82,48 180.82,48.19 180.74,48.27 180.59,48.27 180.51,48.19 180.51,48 180.43,47.92 180.28,47.92 180.21,48 180.21,48.09 180.13,48.16 179.98,48.16 179.9,48.09 179.9,48 179.66,47.75 170.5,47.75 170.37,47.63 170.37,46.61 170.28,46.53 170.15,46.53 170.06,46.61 170.06,47.22 169.97,47.31 169.83,47.31 169.73,47.22 169.73,46.62 169.64,46.53 169.51,46.53 169.42,46.62 169.42,47.39 169.35,47.46 169.19,47.46 169.12,47.39 169.12,46.61 169.03,46.53 168.9,46.53 168.81,46.61 168.81,47.39 168.74,47.46 168.58,47.46 168.51,47.39 168.51,46.64 168.42,46.55 168.29,46.55 168.2,46.64 168.2,47.39 168.13,47.46 167.97,47.46 167.9,47.39 167.9,46.61 167.81,46.53 167.68,46.53 167.59,46.61 167.59,47.39 167.52,47.46 167.36,47.46 167.29,47.39 167.29,47.26 167.21,47.19 166.86,47.19 v3(166.86,47.19) 166.86,47.22 166.74,47.34 166.57,47.34 166.46,47.22 166.46,46.76 166.35,46.65 166.21,46.65 166.1,46.76 166.1,47.41 166.03,47.49 165.87,47.49 165.8,47.41 165.8,46.74 165.71,46.65 165.58,46.65 165.49,46.74 165.49,47.41 165.42,47.49 165.27,47.49 165.19,47.41 165.19,46.72 165.1,46.63 164.97,46.63 164.88,46.72 164.88,47.41 164.81,47.49 164.66,47.49 164.58,47.41 164.58,46.69 164.49,46.6 164.36,46.6 164.27,46.69 164.27,47.41 164.2,47.49 164.05,47.49 163.97,47.41 163.97,46.64 163.88,46.55 163.75,46.55 163.67,46.64 163.67,47.41 163.59,47.49 163.44,47.49 163.36,47.41 163.36,47.26 163.28,47.18 163.13,47.18 163.06,47.26 163.06,47.41 162.98,47.49 162.83,47.49 162.75,47.41 162.75,47.26 162.67,47.18 158.28,47.18 158.13,47.33 158.13,47.71 158.04,47.8 157.91,47.8 157.82,47.71 157.82,47.33 157.75,47.26 154.57,47.26 153.55,48.28 v4(152.23,48.28) ; v1(152.39,24.87) 152.39,25.09 152.6,25.3 152.6,25.49 152.74,25.63 v4(153.46,25.63)
  BOTTOM w0.076: v3(175.95,49.57) 175.95,49.8 176.45,50.3 UD1.L7 ; v3(146.62,49.57) 146.62,49.8 147.12,50.3 UD3.L7 ; v3(166.86,47.19) 166.86,47.19 167.12,47.19 RD35.1 ; v3(188.59,49.98) 189.06,50.46 UD2.L7 ; UD4.L7 159.68,50.5 v3(159.18,50)
DDR_A_MA11: length 118.8
  IN3 w0.076: v4(153.14,21.81) 153.63,22.29 153.93,22.29 153.98,22.34 157.26,22.34 ; v3(188.58,54.11) 188.44,53.97 186.91,53.97 186.76,54.12 186.18,54.12 185.61,54.69 184.29,54.69 183.85,55.14 183.41,55.14 182.83,55.72 v4(182.2,55.72) 181.91,55.72 181.64,55.45 180.09,55.45 178.93,54.29 177.13,54.29 176.97,54.45 176.31,54.45 v3(175.9,54.04) ; v3(159.25,54.11) 159.1,53.97 157.54,53.97 157.44,54.07 156.9,54.07 156.06,54.91 155.31,54.91 155.03,55.18 153.83,55.18 153.3,55.72 v4(152.86,55.72) 152.57,55.72 152.31,55.45 151.18,55.45 151.01,55.63 150.67,55.63 149.58,54.54 147.06,54.54 v3(146.56,54.04)
  IN3 w0.165: 157.26,22.34 161.62,22.34 171.94,32.67 171.94,32.91 171.45,33.4 171.45,33.64 171.71,33.9 171.95,33.9 172.24,33.6 172.42,33.6 172.59,33.78 172.59,40.95 171.3,42.24 171.3,47.97 170.06,49.2 170.06,55.35 168.62,56.8 v3(168.62,57.1)
  IN4 w0.076: v4(152.86,55.72) 153.21,56.06 154.93,56.06 155.41,56.55 164.49,56.55 164.55,56.61 164.55,56.75 164.63,56.82 164.78,56.82 164.86,56.75 164.86,56.49 164.93,56.42 165.08,56.42 165.16,56.49 165.16,56.75 165.24,56.82 166.14,56.82 166.8,57.49 168.12,57.49 168.35,57.26 168.46,57.26 v3(168.62,57.1) 169.22,56.49 169.22,56.37 169.3,56.29 169.45,56.29 169.53,56.37 169.53,56.49 169.6,56.57 169.76,56.57 169.83,56.49 169.83,56.33 169.91,56.25 170.06,56.25 170.14,56.33 170.14,56.49 170.21,56.57 170.37,56.57 170.44,56.49 170.44,56.33 170.52,56.25 170.67,56.25 170.75,56.33 170.75,56.49 170.82,56.57 170.97,56.57 171.05,56.49 171.05,56.33 171.13,56.25 171.28,56.25 171.36,56.33 171.36,56.49 171.43,56.57 171.58,56.57 171.66,56.49 171.66,56.33 171.74,56.25 171.89,56.25 171.97,56.33 171.97,56.46 172.04,56.53 172.19,56.53 172.27,56.46 172.27,56.33 172.35,56.25 178.92,56.25 178.99,56.18 178.99,55.54 179.07,55.47 179.39,55.47 179.46,55.54 179.46,55.68 179.54,55.76 179.69,55.76 179.77,55.68 179.77,55.54 179.84,55.47 181.95,55.47 v4(182.2,55.72) ; v1(152.83,22.62) 152.83,22.13 v4(153.14,21.81)
  BOTTOM w0.076: UD3.R7 146.91,53.7 v3(146.56,54.04) ; UD2.R7 188.99,53.7 v3(188.58,54.11) ; RD49.1 168.76,57.24 v3(168.62,57.1) ; UD4.R7 159.66,53.7 v3(159.25,54.11) ; UD1.R7 176.24,53.7 v3(175.9,54.04)
DDR_A_MA12: length 116.2
  IN3 w0.076: v3(175.9,52.11) 175.9,52.28 176.1,52.48 178.83,52.48 178.98,52.33 179.46,52.33 179.54,52.41 179.54,52.6 179.61,52.67 180.24,52.67 180.49,52.93 181.6,52.93 181.77,52.75 v4(182.1,52.75) 182.38,52.75 182.56,52.93 183,52.93 183.15,53.08 184.38,53.08 184.49,52.97 185.32,52.97 185.4,52.89 186.83,52.89 186.92,52.98 188.11,52.98 v3(188.57,52.52) ; v4(153.86,24.4) 154.16,24.1 156,24.1 157.25,25.36 ; v3(159.24,52.52) 158.98,52.25 158.47,52.25 157.9,52.82 156.18,52.82 156.03,52.97 154.8,52.97 154.75,52.91 153.22,52.91 153.06,52.75 v4(152.76,52.75) 152.6,52.75 152.53,52.67 152.53,52.63 152.45,52.56 152.3,52.56 152.22,52.63 152.22,52.67 152.15,52.75 152,52.75 151.92,52.67 151.92,52.63 151.84,52.56 151.69,52.56 151.61,52.63 151.61,52.67 151.54,52.75 150.98,52.75 150.72,52.49 150.07,52.49 149.91,52.33 146.64,52.33 146.56,52.25 v3(146.56,52.11)
  IN3 w0.165: 157.25,25.36 157.4,25.5 157.4,25.71 157.75,26.05 158.19,26.05 158.36,26.22 158.36,26.67 159.1,27.41 159.45,27.41 160.07,28.02 160.41,28.02 160.65,27.78 160.89,27.78 161.23,28.12 161.23,28.76 161.44,28.97 162.08,28.97 162.63,29.52 162.63,29.9 162.42,30.11 162.42,30.34 162.65,30.57 162.89,30.57 163.17,30.29 163.4,30.29 163.64,30.52 163.64,30.76 163.35,31.04 163.35,31.27 163.59,31.51 163.82,31.51 164.1,31.22 164.34,31.22 164.57,31.46 164.57,31.69 164.29,31.97 164.29,32.21 164.52,32.44 164.76,32.44 165.04,32.16 165.27,32.16 165.51,32.39 165.51,32.63 165.22,32.91 165.22,33.14 165.46,33.38 165.69,33.38 165.97,33.09 166.21,33.09 166.44,33.33 166.44,33.56 166.16,33.84 166.16,34.08 166.39,34.31 166.62,34.31 166.91,34.03 167.14,34.03 167.37,34.26 167.37,34.5 167.09,34.78 167.09,35.01 167.32,35.24 167.56,35.24 167.84,34.96 168.07,34.96 168.31,35.2 168.31,35.43 168.03,35.71 168.03,35.94 168.26,36.18 168.49,36.18 168.77,35.9 169.01,35.9 169.24,36.13 169.24,36.36 168.96,36.65 168.96,36.88 169.19,37.11 169.43,37.11 169.71,36.83 169.94,36.83 170.31,37.2 170.31,37.43 170.03,37.71 170.03,37.95 170.42,38.34 170.42,40.42 169.49,41.35 169.49,46.4 168.44,47.46 168.44,53.3 168.45,53.32 168.45,53.38 v3(168.77,53.7)
  IN4 w0.076: v4(182.1,52.75) 182.1,52.86 182.17,52.94 182.95,52.94 183.03,52.86 183.03,52.38 182.95,52.3 181.91,52.3 181.48,52.74 180.31,52.74 179.71,52.14 179.16,52.14 178.34,52.96 176.73,52.96 176.63,53.07 175.66,53.07 174.08,54.64 170.95,54.64 170.01,53.7 v3(168.77,53.7) 168.5,53.7 168.23,53.97 165.63,53.97 165.29,53.63 163.67,53.63 163.58,53.54 161.3,53.54 161.1,53.74 160.88,53.74 160.88,53.75 158.65,53.75 158.58,53.67 158.58,53.52 158.5,53.45 158.35,53.45 158.27,53.52 158.27,53.67 158.19,53.75 158.04,53.75 157.97,53.67 157.97,53.47 157.89,53.4 157.74,53.4 157.66,53.47 157.66,53.67 157.59,53.75 155.15,53.75 154.59,53.19 153.21,53.19 v4(152.76,52.75) ; v1(153.34,24.37) 153.58,24.37 153.62,24.4 v4(153.86,24.4)
  BOTTOM w0.076: RD29.1 168.5,53.43 v3(168.77,53.7) ; UD4.N7 159.68,52.1 159.27,52.52 v3(159.24,52.52) ; v3(146.56,52.11) 146.58,52.1 UD3.N7 ; v3(175.9,52.11) 175.91,52.1 UD1.N7 ; UD2.N7 189.02,52.1 188.6,52.52 v3(188.57,52.52)
DDR_A_MA13: length 123.4
  IN3 w0.076: v3(173.74,54.15) 174.47,54.15 175.68,55.35 176.36,55.35 176.55,55.16 177.15,55.16 177.4,54.91 178.68,54.91 180.35,56.57 180.53,56.57 181.21,57.24 v4(181.41,57.24) 181.66,57.24 181.73,57.17 181.73,57.08 181.81,57 182,57 182.08,57.08 182.08,57.23 182.15,57.31 182.31,57.31 182.38,57.23 182.38,57.08 182.46,57 182.61,57 182.69,57.08 182.69,57.35 182.76,57.42 182.94,57.42 183.01,57.35 183.01,57.28 183.07,57.22 183.21,57.22 183.4,57.41 183.86,57.41 184.21,57.05 184.33,57.05 184.51,57.23 184.62,57.23 184.72,57.12 184.72,57.02 184.5,56.79 184.5,56.69 184.61,56.58 184.72,56.58 184.94,56.8 185.05,56.8 185.16,56.69 185.16,56.59 184.93,56.36 184.93,56.26 185.04,56.15 185.15,56.15 185.37,56.37 185.48,56.37 186.24,55.61 186.24,55.34 186.08,55.17 185.88,55.17 185.81,55.25 v3(185.81,55.42) ; v3(144.41,54.15) 145.07,54.15 146.28,55.35 149.53,55.35 151.16,56.98 151.38,56.98 151.46,56.9 151.46,56.85 151.53,56.77 151.69,56.77 151.76,56.85 151.76,57.17 151.84,57.24 v4(152.08,57.24) 152.4,57.24 152.47,57.17 152.47,57.08 152.55,57 152.7,57 152.78,57.08 152.78,57.17 152.85,57.24 153.01,57.24 153.08,57.17 153.08,57.08 153.16,57 154.1,57 154.34,57.24 155.01,57.24 155.34,56.92 155.34,56.81 155.1,56.57 155.1,56.46 155.2,56.35 155.31,56.35 155.62,56.66 155.72,56.66 155.83,56.55 155.83,56.44 155.64,56.25 155.64,56.17 155.71,56.1 155.88,56.1 155.97,56.19 156.25,56.19 156.34,56.1 156.57,56.1 157.33,55.35 157.33,55.19 157.21,55.07 156.61,55.07 156.47,55.22 v3(156.47,55.42) ; 148.69,28.02 148.69,27.2 151.04,24.86 v4(151.04,24.7)
  IN3 w0.165: v3(165.01,57.88) 165.06,57.93 165.43,57.93 165.59,57.76 165.59,56.71 165.38,56.5 164.2,56.5 163.6,55.9 163.6,51.67 163.97,51.29 163.97,48.97 163.32,48.32 163.32,45.7 162.28,44.66 162.28,44.24 162.1,44.06 159.55,44.06 159.17,43.68 158.61,43.68 157.91,42.98 157.5,42.98 156.5,41.98 153.25,41.98 148.69,37.42 148.69,28.02
  IN4 w0.076: v4(152.08,57.24) 152.75,57.24 153.52,58.01 154.76,58.01 154.87,57.89 155.06,57.89 155.45,58.29 155.61,58.29 155.68,58.21 155.68,57.84 155.76,57.76 155.91,57.76 155.99,57.84 155.99,58.29 156.06,58.36 156.21,58.36 156.29,58.29 156.29,57.84 156.37,57.76 156.52,57.76 156.6,57.84 156.6,58.23 156.67,58.31 156.82,58.31 156.9,58.23 156.9,57.84 156.98,57.76 157.13,57.76 157.21,57.84 157.21,58.21 157.28,58.29 157.43,58.29 157.51,58.21 157.51,57.84 157.59,57.76 157.74,57.76 157.82,57.84 157.82,58.21 157.89,58.29 158.04,58.29 158.12,58.21 158.12,57.84 158.2,57.76 164.48,57.76 164.59,57.88 v3(165.01,57.88) 165.3,57.88 165.38,57.96 168.23,57.96 168.42,58.14 168.85,58.14 169.63,57.36 179.18,57.36 180.03,56.51 180.86,56.51 181.41,57.06 v4(181.41,57.24) ; v4(151.04,24.7) 150.88,24.87 v1(150.66,24.87)
  BOTTOM w0.076: v3(173.74,54.15) 173.61,54.15 UD1.T3 ; v3(185.81,55.42) 185.86,55.36 UD2.T3 ; RD59.1 165.09,57.96 v3(165.01,57.88) ; v3(156.47,55.42) 156.53,55.36 UD4.T3 ; v3(144.41,54.15) 144.27,54.15 UD3.T3
DDR_A_MA14: length 119.7
  IN3 w0.076: v4(152.79,21.45) 153.3,21.45 154.04,22.19 156.66,22.19 156.85,22 157.26,22 ; v3(159.18,54.91) 159.18,54.92 156.48,54.92 156.19,55.21 155.43,55.21 155.06,55.59 154.39,55.59 154.28,55.49 154.18,55.49 154.07,55.59 154.07,55.7 154.19,55.82 154.19,55.93 154.08,56.03 153.97,56.03 153.85,55.92 153.75,55.92 153.64,56.03 153.64,56.13 153.74,56.24 153.74,56.39 153.59,56.53 v4(153.21,56.53) 152.68,56.53 152.42,56.27 150.88,56.27 149.47,54.86 147.42,54.86 147.35,54.93 147.35,54.97 147.27,55.05 147.12,55.05 147.04,54.97 147.04,54.92 146.97,54.84 146.6,54.84 v3(146.59,54.86) ; v3(175.92,54.86) 176.99,54.86 177.25,54.6 178.8,54.6 180.47,56.27 182.27,56.27 v4(182.54,56.53) 182.88,56.53 183.07,56.34 183.07,56.24 182.97,56.13 182.97,56.03 183.08,55.92 183.19,55.92 183.29,56.02 183.4,56.02 183.51,55.91 183.51,55.8 183.4,55.7 183.4,55.59 183.51,55.49 183.62,55.49 183.72,55.59 183.83,55.59 184.42,55 185.74,55 185.82,54.92 188.58,54.92 v3(188.58,54.91)
  IN3 w0.165: v3(168.58,57.8) 170.48,55.89 170.48,49.32 171.64,48.16 171.64,43.3 172.94,42 172.94,33.18 161.76,22 157.26,22
  IN4 w0.076: v1(152.39,23.37) 152.39,23.21 152.63,22.97 152.63,22.77 152.58,22.72 152.58,22.52 152.67,22.43 152.67,22.06 152.79,21.94 v4(152.79,21.45) ; v4(153.21,56.53) 154.29,57.61 164.58,57.61 164.7,57.49 165.19,57.49 165.5,57.8 v3(168.58,57.8) 168.89,57.8 169.72,56.96 172.32,56.96 172.58,56.71 179.61,56.71 179.97,56.35 180.1,56.35 180.33,56.13 180.88,56.13 180.96,56.05 180.96,55.86 181.03,55.78 181.18,55.78 181.26,55.86 181.26,56.05 181.34,56.13 181.49,56.13 181.57,56.05 181.57,55.78 181.64,55.71 181.79,55.71 181.87,55.78 181.87,56.05 181.95,56.13 182.14,56.13 v4(182.54,56.53)
  BOTTOM w0.076: v3(159.18,54.91) 159.6,54.5 UD4.T7 ; v3(168.58,57.8) 169.04,58.26 RD53.1 ; v3(146.59,54.86) 146.59,54.77 146.86,54.5 UD3.T7 ; v3(188.58,54.91) 188.99,54.5 UD2.T7 ; v3(175.92,54.86) 176.28,54.5 UD1.T7
DDR_A_MA15: length 125.9
  IN3 w0.076: v3(159.15,51.12) 158.36,51.91 157.45,51.91 157.33,52.02 155.69,52.02 155.63,51.96 154.9,51.96 154.71,51.77 153.91,51.77 153.74,51.61 153.48,51.61 153.28,51.81 v4(151.97,51.81) 151.24,51.81 151.04,51.61 149.87,51.61 149.16,50.89 148.52,50.89 148.44,50.97 148.44,51.2 148.37,51.27 148.21,51.27 148.14,51.2 148.14,50.97 148.06,50.89 147.91,50.89 147.83,50.97 147.83,51.26 147.76,51.34 147.6,51.34 147.53,51.26 147.53,50.97 147.45,50.89 147.3,50.89 147.22,50.97 147.22,51.1 147.15,51.17 147,51.17 146.92,51.1 146.92,50.97 146.84,50.89 146.33,50.89 146.25,50.97 146.25,51.3 146.35,51.4 v3(146.59,51.4) ; 157.26,22.69 154.1,22.69 153.86,22.45 153.28,22.45 v4(153.15,22.32) ; v3(175.92,51.4) 175.69,51.4 175.59,51.3 175.59,50.97 175.66,50.89 176.18,50.89 176.25,50.97 176.25,51.1 176.33,51.17 176.48,51.17 176.56,51.1 176.56,50.97 176.64,50.89 176.79,50.89 176.86,50.97 176.86,51.26 176.94,51.34 177.09,51.34 177.17,51.26 177.17,50.97 177.24,50.89 177.4,50.89 177.47,50.97 177.47,51.2 177.55,51.27 177.7,51.27 177.78,51.2 177.78,50.97 177.85,50.89 178.5,50.89 179.21,51.61 180.38,51.61 180.58,51.81 v4(181.31,51.81) 182.61,51.81 182.82,51.61 183.08,51.61 183.24,51.77 183.72,51.77 183.89,51.95 185.26,51.95 185.33,52.02 185.62,52.02 185.69,51.95 186.75,51.95 186.78,51.91 189.27,51.91 v3(189.47,51.71)
  IN3 w0.165: 157.26,22.69 160.92,22.69 161.58,23.34 162.13,23.34 169.59,30.81 169.59,30.99 169.07,31.51 169.07,31.74 169.33,32 169.56,32 170.06,31.51 170.29,31.51 170.53,31.74 170.53,31.97 170.03,32.47 170.03,32.7 170.26,32.94 170.5,32.94 170.99,32.44 171.23,32.44 171.46,32.67 171.46,32.91 170.96,33.4 170.96,33.64 171.98,34.65 172.25,34.92 172.25,40.74 170.95,42.04 170.95,47.77 169.68,49.04 169.68,51.99 v3(169.25,52.42)
  IN4 w0.076: v4(181.31,51.81) 182.36,51.81 182.43,51.73 182.43,51.52 182.36,51.44 180.95,51.44 180.87,51.52 180.87,51.77 180.79,51.85 180.64,51.85 180.56,51.77 180.56,51.52 180.49,51.44 180.34,51.44 180.26,51.52 180.26,51.62 180.18,51.69 180.03,51.69 179.95,51.62 179.95,51.52 179.88,51.44 179.64,51.44 179.42,51.66 179,51.66 178.2,52.46 174.97,52.46 174.89,52.53 174.89,53.12 174.82,53.2 174.67,53.2 174.59,53.12 174.59,52.53 174.51,52.46 174.11,52.46 173.61,52.96 172.61,52.96 172.53,53.04 172.53,53.17 172.46,53.24 172.3,53.24 172.23,53.17 172.23,53.04 172.15,52.96 172,52.96 171.92,53.04 171.92,53.48 171.85,53.56 171.69,53.56 171.62,53.48 171.62,53.04 171.54,52.96 170.67,52.96 170.58,52.88 170.58,52.49 170.51,52.42 170.1,52.42 170.03,52.49 170.03,52.85 169.95,52.93 169.8,52.93 169.72,52.85 169.72,52.49 169.64,52.42 v3(169.25,52.42) 166.71,52.42 165.89,51.59 163.13,51.59 162.68,52.05 159.71,52.05 159.68,52.02 158.28,52.02 158.22,52.08 157.3,52.08 157.23,52.15 157.23,52.68 157.15,52.76 157,52.76 156.92,52.68 156.92,52.15 156.85,52.08 156.7,52.08 156.62,52.15 156.62,52.55 156.54,52.62 156.39,52.62 156.31,52.55 156.31,52.15 156.24,52.08 154.56,52.08 154.09,51.61 152.18,51.61 v4(151.97,51.81) ; v4(153.15,22.32) 153.15,22.67 152.83,22.99 v1(152.83,23.12)
  BOTTOM w0.076: v3(169.25,52.42) RD31.1 ; v3(159.15,51.12) 159.33,51.3 UD4.M7 ; UD3.M7 146.69,51.3 v3(146.59,51.4) ; UD2.M7 189.06,51.3 v3(189.47,51.71) ; v3(175.92,51.4) 176.35,51.4 UD1.M7
DDR_A_RAS#: length 131.8
  IN3 w0.076: v3(173.68,48.44) 175.54,46.58 175.54,46.13 176,45.66 178.74,45.66 178.91,45.5 v4(181.58,45.5) 183.01,45.5 183.09,45.57 183.09,45.76 183.16,45.84 183.32,45.84 183.39,45.76 183.39,45.57 183.47,45.5 183.62,45.5 183.7,45.57 183.7,45.89 183.77,45.97 183.93,45.97 184,45.89 184,45.57 184.08,45.5 184.23,45.5 184.31,45.57 184.31,45.7 184.38,45.78 184.53,45.78 184.61,45.7 184.61,45.57 184.69,45.5 184.84,45.5 184.92,45.57 184.92,45.78 184.99,45.85 185.14,45.85 185.42,45.57 185.72,45.57 185.85,45.7 185.85,47.09 v3(187.01,48.25) ; v3(157.68,48.25) 157.33,47.91 157.33,46.66 156.17,45.5 155.96,45.5 155.89,45.57 155.89,45.78 155.81,45.85 155.66,45.85 155.58,45.78 155.58,45.57 155.5,45.5 155.35,45.5 155.28,45.57 155.28,45.78 155.2,45.85 155.05,45.85 154.97,45.78 154.97,45.57 154.9,45.5 154.74,45.5 154.67,45.57 154.67,45.75 154.59,45.83 154.44,45.83 154.36,45.75 154.36,45.57 154.29,45.5 154.13,45.5 154.06,45.57 154.06,45.76 153.98,45.84 153.83,45.84 153.75,45.76 153.75,45.57 153.68,45.5 v4(152.24,45.5) 149.57,45.5 149.41,45.66 146.67,45.66 146.37,45.95 146.37,46.41 v3(144.35,48.44) ; v4(152.13,25.5) 152.29,25.5 152.39,25.6 152.39,26.26 152.06,26.59 151.29,26.59 150.76,27.12 150.76,27.68
  IN3 w0.165: 150.76,27.68 150.76,28.01 150.59,28.17 150.34,28.17 150.18,28.34 150.18,28.67 150.34,28.84 150.63,28.84 150.8,29 150.8,29.33 150.63,29.5 150.34,29.5 150.18,29.66 150.18,29.99 150.34,30.16 150.59,30.16 150.76,30.32 150.76,30.65 150.59,30.82 150.34,30.82 150.18,30.98 150.18,31.31 150.34,31.48 150.59,31.48 150.76,31.64 150.76,31.97 150.59,32.14 150.34,32.14 150.18,32.3 150.18,32.63 150.34,32.8 150.63,32.8 150.8,32.96 150.8,33.29 150.63,33.46 150.34,33.46 150.18,33.62 150.18,34.02 150.34,34.19 151.3,34.19 151.46,34.35 151.46,36.14 151.7,36.38 151.7,36.61 151.21,37.1 151.21,37.33 151.44,37.57 151.68,37.57 152.16,37.08 152.4,37.08 152.63,37.31 152.63,37.54 152.14,38.03 152.14,38.27 152.38,38.5 152.61,38.5 153.1,38.01 153.33,38.01 153.57,38.24 153.57,38.48 153.08,38.97 153.08,39.2 153.31,39.43 153.54,39.43 154.03,38.94 154.27,38.94 155.09,39.77 156.47,39.77 158.18,41.47 161.55,41.47 164.35,44.28 v3(164.35,44.32)
  IN4 w0.076: v4(152.13,25.5) 152.13,25.47 151.96,25.3 v1(151.96,25.12) ; v4(181.58,45.5) 181.58,45.19 181.35,44.96 181.03,44.96 180.95,45.03 180.95,45.41 180.88,45.48 180.73,45.48 180.65,45.41 180.65,45.03 180.57,44.96 180.42,44.96 180.35,45.03 180.35,45.41 180.27,45.48 180.12,45.48 180.04,45.41 180.04,44.79 179.95,44.7 179.82,44.7 179.74,44.79 179.74,45.41 179.66,45.48 179.51,45.48 179.43,45.41 179.43,44.79 179.34,44.7 179.22,44.7 179.13,44.79 179.13,45.41 179.05,45.48 178.9,45.48 178.82,45.41 178.82,45.03 178.74,44.96 178.59,44.96 178.52,45.03 178.52,45.41 178.44,45.48 178.29,45.48 178.21,45.41 178.21,45.03 178.14,44.96 177.51,44.96 177.14,45.33 175.5,45.33 174.31,44.15 171.77,44.15 171.65,44.26 169.66,44.26 169.59,44.34 169.59,44.47 169.51,44.54 169.36,44.54 169.28,44.47 169.28,44.23 169.19,44.14 169.07,44.14 168.98,44.23 168.98,44.47 168.9,44.54 168.75,44.54 168.67,44.47 168.67,44.34 168.6,44.26 168.45,44.26 168.37,44.34 168.37,44.39 168.28,44.48 168.15,44.48 168.06,44.39 168.06,44.34 167.99,44.26 164.4,44.26 v3(164.35,44.32) 164.35,44.34 164.22,44.47 164.05,44.47 163.92,44.34 163.92,44.26 163.85,44.19 163.69,44.19 163.62,44.26 163.62,44.56 163.53,44.65 163.4,44.65 163.31,44.56 163.31,44.34 163.24,44.26 163.08,44.26 163.01,44.34 163.01,44.49 162.93,44.57 162.78,44.57 162.7,44.49 162.7,44.34 162.63,44.26 162.47,44.26 162.4,44.34 162.4,44.81 162.31,44.9 162.18,44.9 162.09,44.81 162.09,44.34 162.02,44.26 161.81,44.26 161.73,44.34 161.73,44.72 161.63,44.82 160.3,44.82 160.22,44.74 160.22,44.56 160.14,44.48 159.99,44.48 159.92,44.56 159.92,44.74 159.84,44.82 158.84,44.82 158.71,44.69 158.71,43.76 158.64,43.68 158.48,43.68 158.41,43.76 158.41,44.57 158.33,44.64 154.33,44.64 154.25,44.72 154.25,45.37 154.17,45.46 154.04,45.46 153.95,45.37 153.95,44.72 153.87,44.64 153.72,44.64 153.64,44.72 153.64,45.85 153.56,45.94 153.43,45.94 153.34,45.85 153.34,44.72 153.26,44.64 153.11,44.64 153.04,44.72 153.04,46.16 152.95,46.25 152.82,46.25 152.73,46.16 152.73,44.72 152.65,44.64 152.32,44.64 152.24,44.72 v4(152.24,45.5)
  BOTTOM w0.076: v3(187.01,48.25) 187.01,48.3 186.93,48.38 186.38,48.38 UD2.J3 ; RD63.1 164.68,43.99 v3(164.35,44.32) ; v3(144.35,48.44) 143.92,48.87 UD3.J3 ; UD1.J3 173.25,48.87 v3(173.68,48.44) ; v3(157.68,48.25) 157.68,48.3 157.26,48.72 156.71,48.72 UD4.J3
DDR_A_WE#: length 130.3
  IN3 w0.076: v3(143.55,50.11) 143.55,49.88 143.62,49.8 144.41,49.8 144.63,50.02 144.82,50.02 144.88,49.95 144.88,49.6 144.96,49.52 145.11,49.52 145.19,49.6 145.19,49.87 145.26,49.94 145.42,49.94 145.49,49.87 145.49,49.6 145.57,49.52 145.72,49.52 145.8,49.6 145.8,49.87 145.87,49.94 148.79,49.94 148.87,49.87 148.87,49.62 148.95,49.55 149.21,49.55 149.29,49.62 149.29,49.87 149.36,49.94 149.76,49.94 149.77,49.93 150.06,49.93 150.14,49.85 150.14,49.65 150.22,49.57 v4(150.45,49.57) 154.04,49.57 154.11,49.5 154.73,49.5 154.87,49.63 155.83,49.63 156.51,50.31 156.51,51.38 156.92,51.78 157.2,51.78 157.4,51.58 157.4,51.3 157.03,50.92 v3(156.93,50.92) ; v3(186.26,50.92) 186.45,50.92 186.74,51.21 186.74,51.58 186.54,51.78 186.19,51.78 185.84,51.43 185.84,50.3 185.36,49.83 184.22,49.83 183.97,49.57 v4(179.79,49.57) 179.55,49.57 179.47,49.65 179.47,49.85 179.4,49.93 179.11,49.93 179.1,49.94 178.7,49.94 178.62,49.87 178.62,49.6 178.55,49.52 178.28,49.52 178.21,49.6 178.21,49.87 178.13,49.94 175.21,49.94 175.13,49.87 175.13,49.6 175.06,49.52 174.9,49.52 174.83,49.6 174.83,49.87 174.75,49.94 174.6,49.94 174.52,49.87 174.52,49.6 174.45,49.52 174.29,49.52 174.22,49.6 174.22,49.95 174.15,50.02 173.97,50.02 173.75,49.8 172.96,49.8 172.88,49.88 v3(172.88,50.11) ; 149.04,28.02 149.04,27.18 151.4,24.81 151.65,24.81 151.78,24.69 151.78,24.51 v4(151.65,24.38)
  IN3 w0.165: 149.04,28.02 149.04,37.28 153.15,41.39 156.47,41.39 157.71,42.64 158.43,42.64 158.56,42.77 158.56,43.07 158.68,43.2 159.04,43.2 159.17,43.07 159.17,42.77 159.29,42.64 159.62,42.64 159.75,42.77 159.75,43.5 159.87,43.62 160.24,43.62 160.34,43.53 160.34,43.29 160.41,43.21 161.77,43.21 162.65,44.09 162.65,44.54 163.66,45.56 163.66,48.09 v3(163.74,48.16)
  IN4 w0.076: v1(151.96,24.62) 151.89,24.62 v4(151.65,24.38) ; v4(179.79,49.57) 179.44,49.92 175.81,49.92 175.61,49.72 170.85,49.72 170.77,49.8 170.77,50.08 170.69,50.16 170.54,50.16 170.46,50.08 170.46,49.54 170.39,49.47 170.24,49.47 170.16,49.54 170.16,50.07 170.08,50.14 169.93,50.14 169.86,50.07 169.86,49.54 169.78,49.47 169.63,49.47 169.55,49.54 169.55,50.2 169.47,50.28 169.32,50.28 169.25,50.2 169.25,49.54 169.17,49.47 169.02,49.47 168.94,49.54 168.94,50.39 168.86,50.46 168.71,50.46 168.64,50.39 168.64,49.76 168.56,49.68 168.41,49.68 168.33,49.76 168.33,50.09 168.25,50.17 168.1,50.17 168.03,50.09 168.03,49.8 167.95,49.72 167.77,49.72 166.67,48.62 166.32,48.62 166.24,48.54 166.24,48.16 166.15,48.07 166.02,48.07 165.93,48.16 165.93,48.54 165.86,48.62 165.69,48.62 165.62,48.54 165.62,48.25 165.54,48.18 165.39,48.18 165.31,48.25 165.31,48.54 165.24,48.62 165.08,48.62 165.01,48.54 165.01,48.25 164.93,48.18 164.78,48.18 164.7,48.25 164.7,48.54 164.63,48.62 164.34,48.62 164.27,48.54 164.27,48.24 164.19,48.16 v3(163.74,48.16) 163.54,48.16 163.46,48.24 163.46,49.14 163.38,49.22 163.26,49.22 163.18,49.14 163.18,48.2 163.08,48.1 162.93,48.1 162.82,48.2 162.82,49.07 162.73,49.17 162.6,49.17 162.51,49.07 162.51,48.62 162.43,48.54 161.33,48.54 160.98,48.9 159.05,48.9 158.97,48.98 158.97,49.39 158.89,49.47 156.6,49.47 156.47,49.34 156.47,49.24 156.38,49.14 156.24,49.14 156.14,49.24 156.14,49.34 156.02,49.47 155.86,49.47 155.79,49.39 155.79,49.07 155.71,49 155.56,49 155.48,49.07 155.48,49.43 155.41,49.51 155.25,49.51 155.16,49.41 154.11,49.41 154.01,49.51 153.43,49.51 153.32,49.4 153.32,48.73 153.19,48.6 152.71,48.6 152.63,48.67 152.63,48.98 152.56,49.05 152.41,49.05 152.33,48.98 152.33,48.67 152.25,48.6 152.1,48.6 152.02,48.67 152.02,48.98 151.95,49.05 151.8,49.05 151.72,48.98 151.72,48.54 151.64,48.47 151.49,48.47 151.41,48.54 151.41,48.98 151.34,49.05 151.19,49.05 151.11,48.98 151.11,48.54 151.03,48.47 150.88,48.47 150.81,48.54 150.81,49.13 150.73,49.2 150.58,49.2 150.5,49.13 150.5,48.54 150.42,48.47 149.95,48.47 149.77,48.65 149.77,49.12 150.22,49.57 v4(150.45,49.57)
  BOTTOM w0.076: v3(186.26,50.92) 185.86,50.52 UD2.L3 ; v3(163.74,48.16) 163.74,47.59 164.25,47.08 RD69.1 ; v3(172.88,50.11) 173.25,50.48 UD1.L3 ; v3(143.55,50.11) 143.92,50.48 UD3.L3 ; v3(156.93,50.92) 156.53,50.52 UD4.L3
DDR_B_BS0: length 137.9
  IN3 w0.076: 138.44,27.67 138.55,27.67 138.7,27.53 138.7,27.41 139.16,26.94 139.17,26.94 139.25,26.86 139.36,26.74 139.36,26.26 139.44,26.18 139.44,25.96 140.78,24.63 140.78,22.81 141.13,22.45 v4(141.13,22.25) ; v3(126.01,50.92) 126.34,50.92 126.42,50.84 126.42,50.61 126.48,50.55 126.48,50.21 126.41,50.13 125.78,50.13 125.71,50.21 125.71,50.61 125.63,50.69 125.01,50.69 124.8,50.89 124.64,50.89 124.57,50.82 124.57,50.46 124.49,50.39 124.34,50.39 124.26,50.46 124.26,50.82 124.19,50.89 124.03,50.89 123.96,50.82 123.96,50.55 123.88,50.47 123.73,50.47 123.65,50.55 123.65,50.82 123.58,50.89 123.42,50.89 123.35,50.82 123.35,50.63 123.27,50.55 123.12,50.55 123.04,50.63 123.04,50.82 122.97,50.89 122.81,50.89 122.74,50.82 122.74,50.63 122.66,50.55 122.51,50.55 122.43,50.63 122.43,50.82 122.36,50.89 122.19,50.89 122.11,50.82 122.11,50.74 122.04,50.67 v4(121.8,50.67) 121.5,50.67 121.43,50.73 120.41,50.73 120.12,50.44 115.79,50.44 114.97,51.26 113.86,51.26 v3(113.42,51.71) ; v3(96.67,50.92) 97.01,50.92 97.09,50.84 97.09,50.61 97.15,50.55 97.15,50.21 97.07,50.13 96.45,50.13 96.37,50.21 96.37,50.61 96.3,50.69 95.67,50.69 95.47,50.89 95.31,50.89 95.23,50.82 95.23,50.46 95.16,50.39 95,50.39 94.93,50.46 94.93,50.82 94.85,50.89 94.7,50.89 94.62,50.82 94.62,50.55 94.55,50.47 94.39,50.47 94.32,50.55 94.32,50.82 94.24,50.89 94.09,50.89 94.01,50.82 94.01,50.63 93.94,50.55 93.78,50.55 93.71,50.63 93.71,50.82 93.63,50.89 93.48,50.89 93.4,50.82 93.4,50.63 93.33,50.55 93.17,50.55 93.1,50.63 93.1,50.82 93.02,50.89 92.85,50.89 92.78,50.82 92.78,50.74 92.7,50.67 v4(92.47,50.67) 92.16,50.67 92.1,50.73 91.08,50.73 90.79,50.44 86.46,50.44 85.63,51.26 84.39,51.26 v3(84.08,50.95)
  IN3 w0.165: v3(107.68,50.34) 107.88,50.13 107.88,41.79 113.57,36.1 124.42,36.1 125.35,37.04 133.54,37.04 133.74,36.84 133.74,36.29 133.87,36.16 134.28,36.16 134.4,36.29 134.4,36.81 134.63,37.04 134.85,37.04 135.72,36.16 135.72,35.93 133.72,33.93 133.72,33.69 133.95,33.46 134.19,33.46 136.19,35.46 136.42,35.46 136.66,35.23 136.66,34.99 134.66,32.99 134.66,32.76 137.6,29.81 137.6,28.44 138.36,27.67 138.44,27.67
  IN4 w0.076: v4(121.8,50.67) 121.74,50.73 115.66,50.73 115.17,51.21 111.98,51.21 111.9,51.29 111.9,51.63 111.82,51.71 111.67,51.71 111.6,51.63 111.6,51.29 111.52,51.21 111.37,51.21 111.29,51.29 111.29,51.49 111.22,51.57 111.06,51.57 110.99,51.49 110.99,51.29 110.91,51.21 110.76,51.21 110.68,51.29 110.68,51.49 110.61,51.57 110.45,51.57 110.38,51.49 110.38,51.29 110.3,51.21 110.17,51.21 109.18,50.22 108.82,50.22 108.71,50.34 v3(107.68,50.34) 107.21,50.81 106.86,50.81 106.67,51 102.02,51 101.55,51.47 99.53,51.47 99.12,51.06 98.27,50.21 96.29,50.21 95.95,49.87 95.65,49.87 94.86,50.67 v4(92.47,50.67) ; v4(141.13,22.25) v1(141.13,22.87)
  BOTTOM w0.076: v3(113.42,51.71) 113.42,51.69 UD6.M2 ; v3(107.68,50.34) 107.43,50.59 RD74.1 ; v3(96.67,50.92) 97.05,51.3 UD8.M2 ; UD7.M2 84.42,51.3 v3(84.08,50.95) ; UD5.M2 126.42,51.29 126.04,50.92 v3(126.01,50.92)
DDR_B_BS1: length 138.8
  IN3 w0.076: v3(119.03,51.69) 119.2,51.69 119.29,51.61 119.29,51.12 119.36,51.05 119.6,51.05 119.68,51.12 119.68,51.27 119.76,51.35 120.1,51.35 120.5,51.76 120.94,51.76 121.01,51.83 121.01,51.95 121.09,52.02 121.24,52.02 121.32,51.95 121.32,51.83 121.4,51.76 121.55,51.76 121.62,51.83 121.62,51.95 121.7,52.02 122.4,52.02 122.5,52.13 124.1,52.13 v4(124.3,51.92) 125,51.92 125.17,52.1 126.55,52.1 126.63,52.18 127.04,52.18 127.11,52.1 128.18,52.1 128.21,52.08 130.42,52.08 v3(130.82,52.48) ; v3(89.7,51.69) 89.7,51.95 89.77,52.02 90.05,52.02 90.12,51.95 90.12,51.12 90.2,51.05 90.46,51.05 90.53,51.12 90.53,51.27 90.61,51.35 90.76,51.35 90.9,51.49 90.9,51.95 90.97,52.02 91.39,52.02 91.52,52.15 92.17,52.15 92.27,52.05 92.53,52.05 92.7,52.21 94.36,52.21 94.4,52.25 94.6,52.25 94.68,52.18 94.68,52 94.76,51.92 v4(94.97,51.92) 95.76,51.92 95.96,52.12 95.96,52.13 96.9,52.13 96.95,52.18 98.77,52.18 98.87,52.08 101.91,52.08 v3(102.3,51.7) ; v4(141.86,22.84) 141.6,22.58 141.6,22.06 141.33,21.78 140.75,21.78 140.54,21.57 140.07,21.57 139.74,21.9 139.74,22.18 139.09,22.82 138.74,22.82 138.41,22.49 138.02,22.49 137.64,22.88 137.64,23.12 137.05,23.71 136.88,23.71 136.68,23.91 136.68,24.81 134.19,27.3 133.83,27.3 133.45,27.67 133.19,27.67 133.07,27.79
  IN3 w0.165: 133.07,27.79 130.98,29.88 115.84,29.88 114.04,31.68 111.88,31.68 111.74,31.81 108.17,31.81 102.83,37.15 102.83,45.1 103.31,45.58 103.31,46.75 103.97,47.41 103.97,49.24 103.97,49.24 103.97,51.96 v3(104.68,52.67)
  IN4 w0.076: v4(141.86,22.84) 141.79,22.84 v1(141.57,22.62) ; v4(94.97,51.92) 94.8,51.76 93.84,51.76 93.58,52.01 93.58,52.17 93.66,52.25 94.31,52.25 94.88,52.81 94.99,52.81 95.07,52.74 95.07,52.51 95.14,52.43 95.3,52.43 95.37,52.51 95.37,52.74 95.45,52.81 95.92,52.81 96,52.74 96,52.35 96.07,52.28 96.25,52.28 96.33,52.35 96.33,52.74 96.4,52.81 96.8,52.81 96.84,52.77 97.73,52.77 97.86,52.91 99.55,52.91 99.62,52.83 99.62,52.25 99.7,52.17 100.86,52.17 100.94,52.25 100.94,52.7 101.01,52.77 101.23,52.77 101.31,52.7 101.31,52.28 101.39,52.2 101.54,52.2 101.61,52.28 101.61,52.7 101.69,52.77 101.84,52.77 101.92,52.7 101.92,52.28 102,52.2 102.15,52.2 102.22,52.28 102.22,52.7 102.3,52.77 102.47,52.77 102.53,52.82 102.74,52.82 102.82,52.9 102.82,53.55 102.89,53.62 103.05,53.62 103.12,53.55 103.12,52.89 103.2,52.81 103.35,52.81 103.43,52.89 103.43,53.12 103.5,53.19 103.66,53.19 103.73,53.12 103.73,52.58 103.81,52.51 103.99,52.51 104.06,52.58 104.06,53 104.14,53.08 104.33,53.08 104.4,53 104.4,52.75 104.48,52.67 v3(104.68,52.67) 105.17,53.15 111.43,53.15 112,53.73 115.75,53.73 116.86,52.61 119.63,52.61 120.19,52.05 122.06,52.05 122.13,52.13 124.1,52.13 v4(124.3,51.92)
  BOTTOM w0.076: v3(104.68,52.67) 105.5,51.86 RD70.1 ; UD8.N8 101.89,52.1 v3(102.3,51.7) ; v3(130.82,52.48) 131.21,52.1 UD5.N8 ; UD7.N8 89.69,51.69 v3(89.7,51.69) ; v3(119.03,51.69) 119.02,51.69 UD6.N8
DDR_B_BS2: length 124.9
  IN3 w0.076: v3(86.25,51.14) 86.25,50.88 86.54,50.59 90.72,50.59 91.1,50.97 91.49,50.97 91.57,51.05 v4(91.87,51.05) 95.09,51.05 95.44,51.4 96.4,51.4 96.54,51.26 97.42,51.26 97.5,51.33 v3(97.5,51.68) ; v3(126.83,51.68) 126.83,51.33 126.76,51.26 125.88,51.26 125.73,51.4 124.78,51.4 124.42,51.05 v4(121.2,51.05) 120.9,51.05 120.83,50.97 120.44,50.97 120.06,50.59 115.86,50.59 115.71,50.74 v3(115.71,51.17) ; v4(139.83,26.46) 139.69,26.61 139.69,27.2 138.97,27.91 138.97,28.02
  IN3 w0.165: 138.97,28.02 138.97,28.03 138.29,28.72 138.29,30.32 137.66,30.94 137.66,35.23 135.17,37.72 125.06,37.72 124.13,36.79 113.85,36.79 108.6,42.05 108.6,48.47 109.06,48.93 109.06,49.35 108.83,49.58 108.8,49.58 108.57,49.81 108.57,50.73 108.43,50.87 108.43,53.31 108.54,53.42 108.91,53.42 109.03,53.29 v3(109.03,50.56)
  IN4 w0.076: v4(121.2,51.05) 121.13,50.97 120.56,50.97 120.47,51.06 116.95,51.06 116.88,51.14 116.88,51.77 116.8,51.85 115.49,51.85 115.42,51.77 115.42,51.44 115.34,51.36 112.38,51.36 112.3,51.44 112.3,51.81 112.23,51.88 112.07,51.88 111.99,51.96 111.99,52.06 111.92,52.14 111.76,52.14 111.69,52.06 111.69,51.96 111.61,51.88 111.46,51.88 111.38,51.96 111.38,52.44 111.31,52.52 111.15,52.52 111.08,52.44 111.08,51.96 111,51.88 110.85,51.88 110.77,51.96 110.77,52.44 110.7,52.52 110.54,52.52 110.47,52.44 110.47,51.96 110.39,51.88 110.24,51.88 110.16,51.96 110.16,52.44 110.09,52.52 109.93,52.52 109.86,52.44 109.86,51.96 109.78,51.88 109.46,51.88 109.38,51.81 109.38,50.64 109.31,50.56 v3(109.03,50.56) 108.64,50.96 106.92,50.96 106.72,51.16 102.12,51.16 101.66,51.62 99.47,51.62 98.21,50.36 96.53,50.36 96.19,50.69 95.67,50.69 95.06,51.3 92.12,51.3 v4(91.87,51.05) ; v4(139.83,26.46) 139.83,26.46 v1(139.83,25.12)
  BOTTOM w0.076: UD6.M3 114.74,51.17 v3(115.71,51.17) ; UD5.M3 127.21,51.3 v3(126.83,51.68) ; RD72.1 109.21,50.39 v3(109.03,50.56) ; UD8.M3 97.88,51.3 v3(97.5,51.68) ; UD7.M3 86.09,51.3 v3(86.25,51.14)
DDR_B_CAS#: length 147.4
  IN3 w0.076: v3(115.05,49.25) 115.41,49.25 115.53,49.13 116.03,49.13 117.11,48.05 118.37,48.05 119.47,46.95 119.47,46.76 119.72,46.5 120.74,46.5 120.82,46.42 120.82,45.88 120.89,45.8 121.05,45.8 121.12,45.88 121.12,46.42 121.2,46.5 121.35,46.5 121.43,46.42 121.43,45.88 121.5,45.8 121.66,45.8 121.73,45.88 121.73,46.42 121.81,46.5 122.02,46.5 122.09,46.42 122.09,46.16 122.17,46.08 v4(122.64,46.08) 123.04,46.08 123.12,46.16 123.12,46.3 123.19,46.37 123.35,46.37 123.42,46.3 123.42,45.98 123.5,45.9 123.65,45.9 123.73,45.98 123.73,46.3 123.8,46.37 123.96,46.37 124.03,46.3 124.03,45.87 124.11,45.8 124.26,45.8 124.34,45.87 124.34,46.91 124.41,46.98 124.57,46.98 124.64,46.91 124.64,46.16 124.72,46.08 124.87,46.08 124.95,46.16 124.95,46.46 125.02,46.53 125.18,46.53 125.33,46.39 125.56,46.39 125.68,46.51 125.68,46.75 126.26,47.33 127.09,47.33 127.22,47.45 127.22,47.68 127.58,48.05 127.61,48.05 128.43,48.87 v3(128.43,49.11) ; v3(85.71,49.25) 86.08,48.88 86.93,48.88 87.04,48.77 87.04,48.66 86.72,48.35 86.72,48.24 86.83,48.14 86.94,48.14 87.25,48.45 87.36,48.45 87.47,48.34 87.47,48.23 87.26,48.02 87.22,48.02 86.93,47.73 86.93,47.57 87.99,46.51 90.67,46.51 91.1,46.08 91.34,46.08 91.41,46.16 91.41,46.4 91.49,46.47 91.64,46.47 91.72,46.4 91.72,46.16 91.79,46.08 v4(93.3,46.08) 94.37,46.08 94.48,46.19 94.64,46.19 94.79,46.05 94.91,46.05 95,46.14 95,46.65 95.08,46.73 95.23,46.73 95.31,46.65 95.31,46.16 95.38,46.08 95.54,46.08 95.61,46.16 95.61,46.33 95.7,46.42 95.83,46.42 95.92,46.33 95.92,46.16 95.99,46.08 97.48,46.08 97.94,46.54 97.94,48.02 97.86,48.1 97.47,48.1 97.35,48.22 97.35,48.56 97.47,48.68 98.93,48.68 99.1,48.85 v3(99.1,49.11) ; v4(140.38,23.33) 140.37,23.35 140.37,23.37 140.07,23.67 140.07,24.26 139.3,25.02 138.95,25.02 137.48,26.48 137.3,26.48 136.62,27.17 136.62,27.19
  IN3 w0.165: v3(105.98,45.07) 105.95,45.07 105.8,44.92 105.8,41.45 112.86,34.39 121.12,34.39 121.24,34.26 121.24,33.06 121.37,32.94 121.78,32.94 121.91,33.06 121.91,34.26 122.03,34.39 122.44,34.39 122.57,34.26 122.57,32.91 122.69,32.78 123.1,32.78 123.23,32.91 123.23,34.26 123.35,34.39 123.76,34.39 123.89,34.26 123.89,32.91 124.01,32.78 124.42,32.78 124.55,32.91 124.55,34.26 124.67,34.39 125.08,34.39 125.21,34.26 125.21,32.91 125.33,32.78 125.74,32.78 125.87,32.91 125.87,34.26 125.99,34.39 126.4,34.39 126.53,34.26 126.53,32.91 126.66,32.78 127.06,32.78 127.19,32.91 127.19,34.22 127.32,34.35 127.72,34.35 127.85,34.22 127.85,32.91 127.98,32.78 131.89,32.78 135.89,28.78 135.89,27.88 136.09,27.68 136.09,27.68 136.33,27.43 136.37,27.43 136.62,27.19
  IN4 w0.076: v4(93.3,46.08) 95.26,46.08 96.39,44.95 96.85,44.95 96.92,45.02 96.92,45.47 97,45.55 97.15,45.55 97.23,45.47 97.23,45.02 97.3,44.95 97.46,44.95 97.53,45.02 97.53,45.47 97.61,45.55 97.76,45.55 97.84,45.47 97.84,45.02 97.91,44.95 98.61,44.95 98.69,45.02 98.69,45.38 98.77,45.46 104.01,45.46 104.08,45.38 104.08,45.15 104.16,45.07 104.31,45.07 104.39,45.15 104.39,45.42 104.46,45.5 104.61,45.5 104.69,45.42 104.69,45.15 104.77,45.07 104.92,45.07 105,45.15 105,45.39 105.07,45.47 105.22,45.47 105.3,45.39 105.3,45.15 105.38,45.07 v3(105.98,45.07) 112.94,45.07 113.05,44.96 115.15,44.96 115.88,45.68 119.99,45.68 120.39,46.08 v4(122.64,46.08) ; v1(140.7,23.12) 140.55,23.12 140.38,23.28 v4(140.38,23.33)
  BOTTOM w0.076: UD6.K3 114.61,49.69 115.05,49.26 v3(115.05,49.25) ; UD8.K3 98.51,49.7 v3(99.1,49.11) ; UD5.K3 127.54,49.38 128.16,49.38 v3(128.43,49.11) ; RD66.1 106.26,44.79 v3(105.98,45.07) ; v3(85.71,49.25) 85.27,49.69 UD7.K3
DDR_B_CKE0: length 137.1
  IN3 w0.076: v3(102.27,50.13) 101.76,50.64 98.93,50.64 98.37,50.08 97.85,50.08 97.25,49.48 96.29,49.48 96,49.19 v4(95.24,49.19) 95.02,49.19 94.95,49.12 94.95,48.99 94.87,48.91 94.72,48.91 94.64,48.99 94.64,49.34 94.56,49.42 94.41,49.42 94.34,49.34 94.34,48.84 94.26,48.76 94.11,48.76 94.03,48.84 94.03,49.34 93.95,49.42 93.8,49.42 93.73,49.34 93.73,48.84 93.65,48.76 93.5,48.76 93.42,48.84 93.42,49.34 93.34,49.42 93.27,49.42 93.16,49.32 92.92,49.32 92.82,49.42 92.66,49.42 92.52,49.28 92.35,49.28 92.21,49.42 92.1,49.42 92.03,49.34 92.03,49.29 91.95,49.22 91.71,49.22 91.6,49.33 91.44,49.33 91.28,49.17 91.1,49.17 91.02,49.24 91.02,49.5 v3(91.07,49.55) ; v3(120.31,49.46) 120.31,49.27 120.37,49.2 120.58,49.2 120.75,49.38 120.88,49.38 121.05,49.22 121.29,49.22 121.36,49.29 121.36,49.34 121.44,49.42 121.55,49.42 121.69,49.28 121.85,49.28 121.99,49.42 122.16,49.42 122.26,49.32 122.5,49.32 122.6,49.42 122.68,49.42 122.76,49.34 122.76,48.84 122.83,48.76 122.98,48.76 123.06,48.84 123.06,49.34 123.14,49.42 123.29,49.42 123.37,49.34 123.37,48.84 123.44,48.76 123.59,48.76 123.67,48.84 123.67,49.34 123.75,49.42 123.9,49.42 123.98,49.34 123.98,48.99 124.05,48.91 124.2,48.91 124.28,48.99 124.28,49.12 124.36,49.19 v4(124.57,49.19) 124.8,49.42 125.39,49.42 125.39,49.42 125.64,49.67 126.78,49.67 127.69,50.58 131.15,50.58 v3(131.61,50.13)
  IN3 w0.127: v4(141.6,25.53) 141.73,25.66 141.73,25.67
  IN3 w0.165: v3(111.97,48.44) 112.04,48.51 112.51,48.51 113.15,47.86 115.11,47.86 115.58,47.39 116.11,47.39 116.67,46.84 116.67,45.01 117.56,44.11 117.76,44.11 117.77,44.11 119.64,44.11 120.31,44.77 130.9,44.77 131.2,45.08 132.27,45.08 132.57,44.77 134.77,44.77 134.99,44.99 134.99,46.55 135.11,46.68 137.56,46.68 137.69,46.55 137.69,42.71 142.12,38.27 142.12,33.14 143.37,31.89 143.37,27.31 141.73,25.67
  IN4 w0.076: v4(124.57,49.19) 124.04,49.19 123.97,49.27 123.97,49.78 123.89,49.85 123.74,49.85 123.66,49.78 123.66,49.27 123.58,49.19 123.43,49.19 123.36,49.27 123.36,49.69 123.28,49.76 123.13,49.76 123.05,49.69 123.05,49.27 122.97,49.19 122.82,49.19 122.75,49.27 122.75,49.69 122.67,49.76 122.52,49.76 122.44,49.69 122.44,49.27 122.37,49.19 122.21,49.19 122.14,49.27 122.14,49.69 122.06,49.76 121.91,49.76 121.83,49.69 121.83,49.27 121.76,49.19 121.21,49.19 120.53,48.52 120.03,48.52 119.64,48.9 117.47,48.9 117.39,48.98 117.39,49.15 117.32,49.23 117.16,49.23 117.09,49.15 117.09,48.98 117.01,48.9 116.4,48.9 116.33,48.98 116.33,49.85 116.25,49.93 116.1,49.93 116.02,49.85 116.02,48.98 115.95,48.9 115.79,48.9 115.72,48.98 115.72,49.85 115.64,49.93 115.49,49.93 115.41,49.85 115.41,48.98 115.34,48.9 113.35,48.9 112.95,48.51 112.77,48.51 112.69,48.58 112.69,48.75 112.62,48.82 112.47,48.82 112.39,48.75 112.39,48.58 112.31,48.51 112.04,48.51 v3(111.97,48.44) 111.91,48.51 107.6,48.51 107.52,48.58 107.52,48.76 107.45,48.84 107.3,48.84 107.22,48.76 107.22,48.58 107.14,48.51 106.99,48.51 106.91,48.58 106.91,48.76 106.84,48.84 106.69,48.84 106.61,48.76 106.61,48.58 106.53,48.51 106.29,48.51 106.21,48.58 106.21,49.37 106.14,49.45 105.98,49.45 105.91,49.37 105.91,48.58 105.83,48.51 105.68,48.51 105.6,48.58 105.6,49.37 105.53,49.45 105.38,49.45 105.3,49.37 105.3,48.58 105.22,48.51 102.79,48.51 102.42,48.13 100.57,48.13 99.94,48.77 98.35,48.77 97.93,49.19 96.43,49.19 96.36,49.12 96.36,49.01 96.28,48.94 96.13,48.94 96.05,49.01 96.05,49.12 95.98,49.19 v4(95.24,49.19) ; v1(141.57,25.12) 141.6,25.15 v4(141.6,25.53)
  BOTTOM w0.076: UD8.K9 102.63,49.7 102.27,50.06 v3(102.27,50.13) ; RD62.1 109.71,48.35 111.88,48.35 v3(111.97,48.44) ; UD7.K9 90.92,49.7 v3(91.07,49.55) ; UD5.K9 132.02,49.72 v3(131.61,50.13) ; UD6.K9 120.07,49.7 v3(120.31,49.46)
DDR_B_CKE1: length 137.5
  IN3 w0.076: v3(131.61,49.28) 131.25,49.64 130.77,49.64 130.56,49.86 130.56,49.86 130.09,50.33 127.65,50.33 126.86,49.54 126.81,49.48 125.67,49.48 125.44,49.26 125.08,49.26 124.44,48.61 v4(124.3,48.61) 122.48,48.61 122.4,48.68 122.4,49.08 122.32,49.15 122.17,49.15 122.1,49.08 122.1,48.6 122.02,48.52 121.87,48.52 121.79,48.6 121.79,49.05 121.72,49.13 121.56,49.13 121.49,49.05 121.49,48.58 121.41,48.51 121.26,48.51 121.18,48.58 121.18,48.99 121.11,49.07 120.95,49.07 120.88,48.99 120.88,48.6 120.8,48.52 119.84,48.52 119.55,48.8 119.55,49.05 119.67,49.17 v3(119.86,49.17) ; v3(102.27,49.28) 101.91,49.64 101.44,49.64 101.22,49.86 101.22,49.86 100.59,50.49 99,50.49 98.43,49.92 97.91,49.92 97.52,49.54 97.52,49.54 97.32,49.33 96.35,49.33 95.63,48.61 v4(94.97,48.61) 93.14,48.61 93.07,48.68 93.07,49.08 92.99,49.15 92.84,49.15 92.76,49.08 92.76,48.6 92.69,48.52 92.53,48.52 92.46,48.6 92.46,49.05 92.38,49.13 92.23,49.13 92.15,49.05 92.15,48.58 92.08,48.51 91.92,48.51 91.85,48.58 91.85,48.99 91.77,49.07 91.62,49.07 91.54,48.99 91.54,48.6 91.47,48.52 90.5,48.52 90.22,48.8 90.22,49.05 90.37,49.2 v3(90.54,49.2)
  IN3 w0.127: 141.59,26.04 141.55,26.04 v4(141.51,26)
  IN3 w0.165: v3(112.23,47.67) 112.44,47.45 114.95,47.45 115.37,47.03 115.37,46.49 116.13,45.73 116.13,44.56 116.95,43.74 119.78,43.74 120.36,44.32 130.85,44.32 131.15,44.01 131.81,44.01 132.19,44.39 135.23,44.39 135.36,44.52 135.36,45.38 135.49,45.51 135.89,45.51 136.02,45.38 136.02,44.09 136.15,43.96 136.55,43.96 136.68,44.09 136.68,46.14 136.81,46.27 137.22,46.27 137.34,46.14 137.34,42.56 141.73,38.18 141.73,33.02 143.01,31.74 143.01,27.46 141.59,26.04
  IN4 w0.076: v4(94.97,48.61) 96.11,48.61 96.53,48.19 97.84,48.19 98.26,48.6 99.24,48.6 100.51,47.33 103.31,47.33 103.79,47.81 103.98,47.81 104.06,47.88 104.06,48.11 104.13,48.19 104.29,48.19 104.36,48.11 104.36,47.88 104.44,47.81 104.59,47.81 104.67,47.88 104.67,48.11 104.74,48.19 104.9,48.19 104.97,48.11 104.97,47.88 105.05,47.81 105.2,47.81 105.28,47.88 105.28,48.11 105.35,48.19 105.51,48.19 105.58,48.11 105.58,47.88 105.66,47.81 111.55,47.81 111.69,47.67 v3(112.23,47.67) 112.52,47.67 112.6,47.74 112.6,48.28 112.67,48.35 112.96,48.35 113.04,48.28 113.04,48.11 113.12,48.04 115.97,48.04 116.04,48.11 116.04,48.35 116.12,48.43 116.27,48.43 116.35,48.35 116.35,48.11 116.42,48.04 116.57,48.04 116.65,48.11 116.65,48.6 116.73,48.67 116.88,48.67 116.96,48.6 116.96,48.11 117.03,48.04 118.56,48.04 118.64,48.11 118.64,48.67 118.72,48.75 118.87,48.75 118.94,48.67 118.94,48.11 119.02,48.04 119.17,48.04 119.25,48.11 119.25,48.67 119.33,48.75 119.48,48.75 119.55,48.67 119.55,48.11 119.63,48.04 119.78,48.04 119.86,48.11 119.86,48.29 119.94,48.37 120.09,48.37 120.16,48.29 120.16,48.11 120.24,48.04 120.36,48.04 121.36,49.04 121.65,49.04 121.73,48.96 121.73,48.75 121.81,48.67 121.96,48.67 122.04,48.75 122.04,48.96 122.11,49.04 122.26,49.04 122.34,48.96 122.34,48.7 122.42,48.62 122.57,48.62 122.65,48.7 122.65,48.96 122.72,49.04 122.87,49.04 122.95,48.96 122.95,48.75 123.03,48.67 123.18,48.67 123.26,48.75 123.26,48.96 123.33,49.04 124.18,49.04 124.3,48.91 v4(124.3,48.61) ; v1(141.57,24.62) 141.57,24.78 141.33,25.02 141.33,25.36 141.25,25.43 141.25,25.59 141.3,25.64 141.3,25.77 141.51,25.99 141.51,26 v4(141.51,26)
  BOTTOM w0.076: RD78.1 109.97,47.72 112.18,47.72 v3(112.23,47.67) ; v3(119.86,49.17) 119.6,48.9 UD6.J9 ; UD5.J9 131.98,48.9 v3(131.61,49.28) ; v3(90.54,49.2) 90.23,48.9 UD7.J9 ; v3(102.27,49.28) 102.65,48.9 UD8.J9
DDR_B_CS0#: length 136
  IN3 w0.076: v3(84.08,50.12) 84.27,50.12 84.67,50.53 85.94,50.53 86.37,50.09 90.93,50.09 91.08,50.25 v4(91.26,50.25) 91.58,50.25 92.1,49.73 95.46,49.73 95.53,49.65 96.02,49.65 96.16,49.79 97.13,49.79 97.63,50.29 97.63,50.71 v3(97.42,50.92) ; v3(126.75,50.92) 126.9,50.92 126.96,50.85 126.96,50.29 126.66,49.98 125.52,49.98 125.26,49.73 121.44,49.73 120.92,50.25 v4(120.6,50.25) 120.42,50.25 120.26,50.09 115.71,50.09 115.27,50.53 114.01,50.53 113.6,50.12 v3(113.42,50.12) ; 133.08,27.45 133.09,27.43 133.11,27.43 133.4,27.14 134.12,27.14 136.47,24.8 136.47,23.83 136.79,23.51 136.98,23.51 137.3,23.19 137.3,21.77 137.49,21.58 138.34,21.58 138.65,21.89 138.65,22.25 v4(138.88,22.48)
  IN3 w0.165: v3(103.42,49.45) 103.57,49.3 103.57,47.54 102.74,46.72 102.74,45.92 101.71,44.89 101.71,37.43 107.91,31.24 108.25,31.24 108.42,31.07 108.42,30.98 108.55,30.85 108.95,30.85 109.08,30.98 109.08,31.07 109.25,31.24 109.81,31.24 109.92,31.13 109.92,29.43 110.04,29.31 110.49,29.31 110.66,29.47 110.66,31.11 110.78,31.24 111.19,31.24 111.32,31.11 111.32,29.47 111.48,29.31 130.75,29.31 132.61,27.45 133.08,27.45
  IN4 w0.076: v1(138.97,23.12) 138.88,23.03 v4(138.88,22.48) ; v4(120.6,50.25) 120.53,50.31 115.63,50.31 115.23,50.72 110.35,50.72 109.43,49.8 103.78,49.8 v3(103.42,49.45) 103.08,49.45 102.91,49.62 102.09,49.62 102.01,49.7 102.01,49.81 101.93,49.89 101.78,49.89 101.71,49.81 101.71,49.7 101.63,49.62 101.24,49.62 101.16,49.7 101.16,49.88 101.08,49.96 100.93,49.96 100.86,49.88 100.86,49.7 100.78,49.62 99.91,49.62 99.83,49.7 99.83,49.98 99.91,50.06 100,50.06 100.07,50.13 100.07,50.26 100,50.34 99.6,50.34 99.53,50.26 99.53,49.74 99.45,49.66 98.66,49.66 98.58,49.74 98.58,49.83 98.51,49.9 98.36,49.9 98.28,49.83 98.28,49.74 98.2,49.66 98.05,49.66 97.98,49.74 97.98,49.83 97.9,49.9 97.75,49.9 97.67,49.83 97.67,49.74 97.59,49.66 97.44,49.66 97.37,49.74 97.37,49.83 97.29,49.9 97.14,49.9 97.06,49.83 97.06,49.74 96.98,49.66 96.83,49.66 96.76,49.74 96.76,49.83 96.68,49.9 96.53,49.9 96.45,49.83 96.45,49.64 96.37,49.57 95.53,49.57 95.43,49.66 94.56,49.66 94.49,49.59 94.49,49.28 94.41,49.2 94.26,49.2 94.18,49.28 94.18,49.59 94.11,49.66 93.95,49.66 93.88,49.59 93.88,49.28 93.8,49.2 93.65,49.2 93.57,49.28 93.57,49.59 93.5,49.66 92.17,49.66 91.94,49.89 91.41,49.89 91.26,50.04 v4(91.26,50.25)
  BOTTOM w0.076: RD64.1 105.93,47.85 104.33,49.45 v3(103.42,49.45) ; UD5.L2 126.75,50.84 v3(126.75,50.92) ; UD8.L2 97.42,50.84 v3(97.42,50.92) ; UD7.L2 84.47,50.5 v3(84.08,50.12) ; v3(113.42,50.12) 113.8,50.5 UD6.L2
DDR_B_CS1#: length 143.9
  IN3 w0.076: v3(95.81,50.21) 95.81,50.4 95.89,50.47 96.14,50.47 96.22,50.4 96.22,50.06 95.96,49.8 95.59,49.8 95.52,49.88 95.2,49.88 95.12,49.95 95.12,50.12 95.05,50.2 94.89,50.2 94.82,50.12 94.82,49.95 94.74,49.88 94.54,49.88 94.46,49.95 94.46,50.25 94.38,50.32 94.23,50.32 94.16,50.25 94.16,49.95 94.08,49.88 93.93,49.88 93.85,49.95 93.85,50.32 93.77,50.4 93.62,50.4 93.55,50.32 93.55,49.95 93.47,49.88 93.32,49.88 93.24,49.95 93.24,50.32 93.17,50.4 93.01,50.4 92.94,50.32 92.94,49.95 92.86,49.88 92.71,49.88 92.63,49.95 92.63,50.27 92.56,50.35 92.4,50.35 92.33,50.27 92.33,49.97 92.26,49.9 92.14,49.9 91.97,50.07 v4(91.97,50.41) 91.82,50.56 91.13,50.56 90.84,50.27 86.41,50.27 86,50.68 84.42,50.68 84.28,50.54 83.91,50.54 83.48,50.1 v3(83.13,50.1) ; v4(139.05,22.02) 139.05,22 138.48,21.43 137.31,21.43 137.06,21.68 137.06,23.15 136.9,23.31 136.71,23.31 136.57,23.45 136.1,23.45 135.75,23.8 135.75,25.3 134.06,26.99 133.27,26.99 133.01,27.25 132.53,27.25 132.1,27.67 131.98,27.67 ; v3(112.47,50.1) 112.92,50.1 113.5,50.68 115.34,50.68 115.74,50.27 120.17,50.27 120.46,50.56 121.15,50.56 v4(121.31,50.41) 121.31,50.07 121.48,49.9 121.59,49.9 121.66,49.97 121.66,50.27 121.74,50.35 121.89,50.35 121.97,50.27 121.97,49.95 122.04,49.88 122.2,49.88 122.27,49.95 122.27,50.32 122.35,50.4 122.5,50.4 122.58,50.32 122.58,49.95 122.65,49.88 122.8,49.88 122.88,49.95 122.88,50.32 122.96,50.4 123.11,50.4 123.19,50.32 123.19,49.95 123.26,49.88 123.41,49.88 123.49,49.95 123.49,50.25 123.57,50.32 123.72,50.32 123.8,50.25 123.8,49.95 123.87,49.88 124.08,49.88 124.15,49.95 124.15,50.12 124.23,50.2 124.38,50.2 124.46,50.12 124.46,49.95 124.53,49.88 125.2,49.88 125.55,50.23 125.55,50.46 125.48,50.54 125.11,50.54 125.03,50.46 v3(125.03,50.27)
  IN3 w0.165: 131.98,27.67 131.9,27.67 130.61,28.96 109.69,28.96 100.3,38.36 100.3,46.94 100.49,47.13 101.71,47.13 102.8,48.23 102.8,50.13 102.93,50.26 v3(103.26,50.26)
  IN4 w0.076: v4(121.31,50.41) 121.15,50.56 115.59,50.56 115.29,50.87 110.16,50.87 109.28,49.99 107.53,49.99 107.26,50.26 v3(103.26,50.26) 102.84,50.26 102.44,50.67 100.47,50.67 100.12,51.01 99.82,51.01 99.7,50.89 99.7,50.56 99.62,50.49 99.46,50.49 99.39,50.56 99.39,50.79 99.31,50.87 99.16,50.87 99.08,50.79 99.08,50.56 99.01,50.49 98.77,50.49 98.34,50.06 96.35,50.06 96.02,49.72 95.59,49.72 95.49,49.81 94.88,49.81 94.76,49.94 94.76,50.42 94.69,50.5 94.53,50.5 94.46,50.42 94.46,49.9 94.38,49.82 94.23,49.82 94.15,49.9 94.15,50.44 94.08,50.51 93.92,50.51 93.85,50.44 93.85,49.9 93.77,49.82 93.62,49.82 93.54,49.9 93.54,50.42 93.47,50.5 93.31,50.5 93.24,50.42 93.24,49.9 93.16,49.82 93.01,49.82 92.93,49.9 92.93,50.37 92.86,50.45 92.7,50.45 92.63,50.37 92.63,49.94 92.55,49.86 92.26,49.86 92.18,49.94 92.18,49.97 92.1,50.04 91.65,50.04 91.58,50.12 91.58,50.34 91.65,50.41 v4(91.97,50.41) ; v1(139.4,22.87) 139.2,22.66 139.2,22.34 139.15,22.3 139.15,22.13 v4(139.05,22.02)
  BOTTOM w0.076: UD5.L1 125.26,50.5 v3(125.03,50.27) ; v3(83.13,50.1) 83.53,50.5 UD7.L1 ; v3(112.47,50.1) 112.86,50.5 UD6.L1 ; v3(103.26,50.26) 103.69,49.83 104.46,49.83 105.55,48.73 RD80.1 ; v3(95.81,50.21) 95.81,50.21 96.1,50.5 UD8.L1
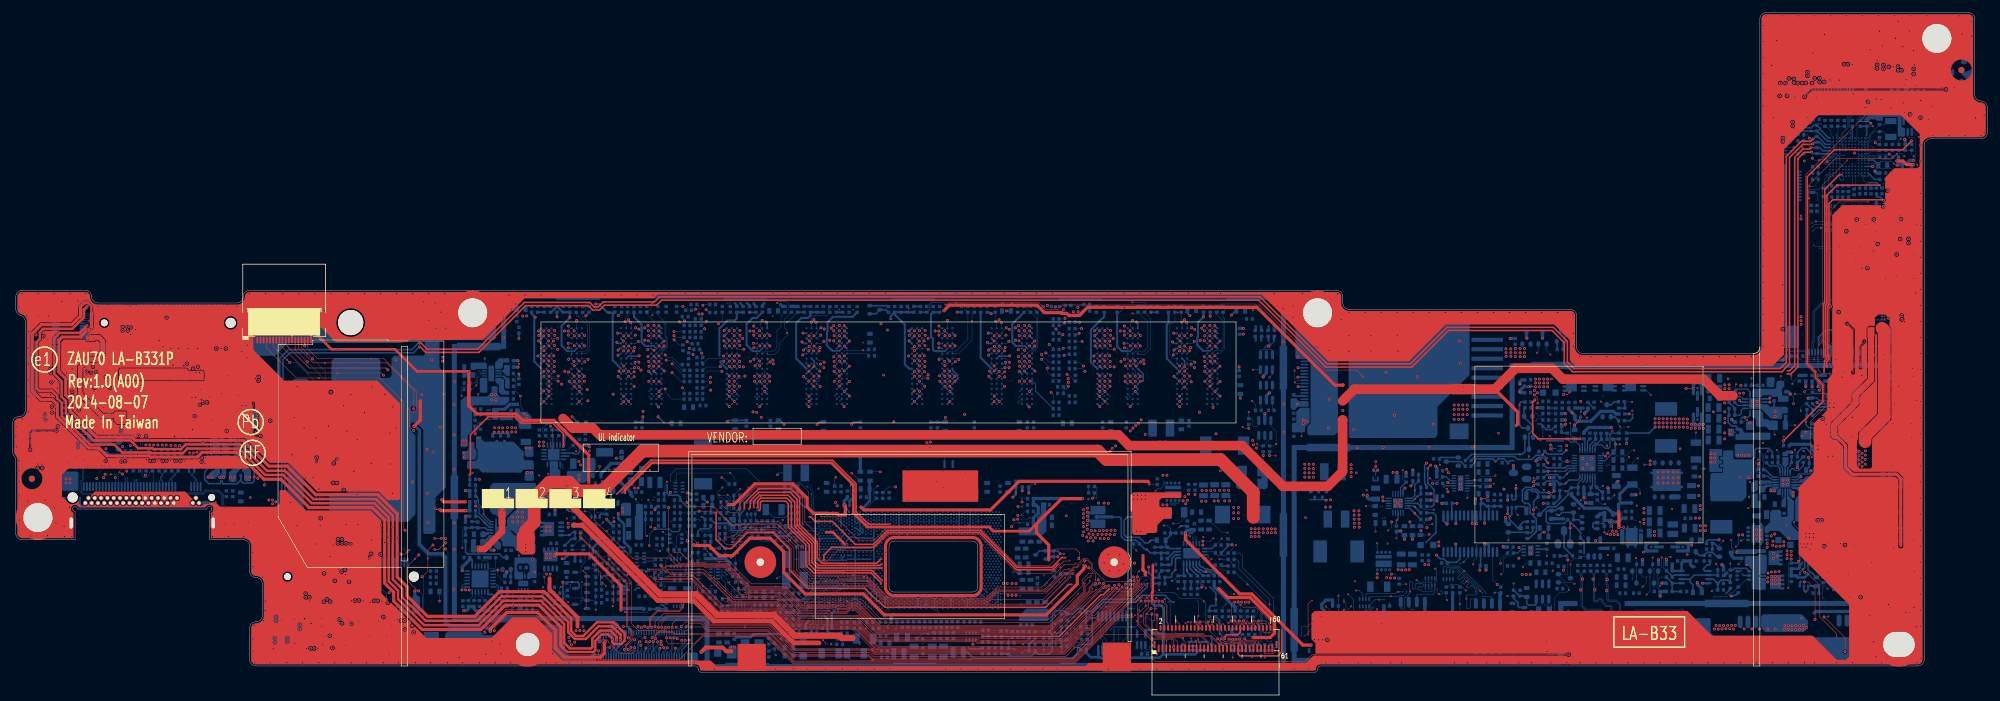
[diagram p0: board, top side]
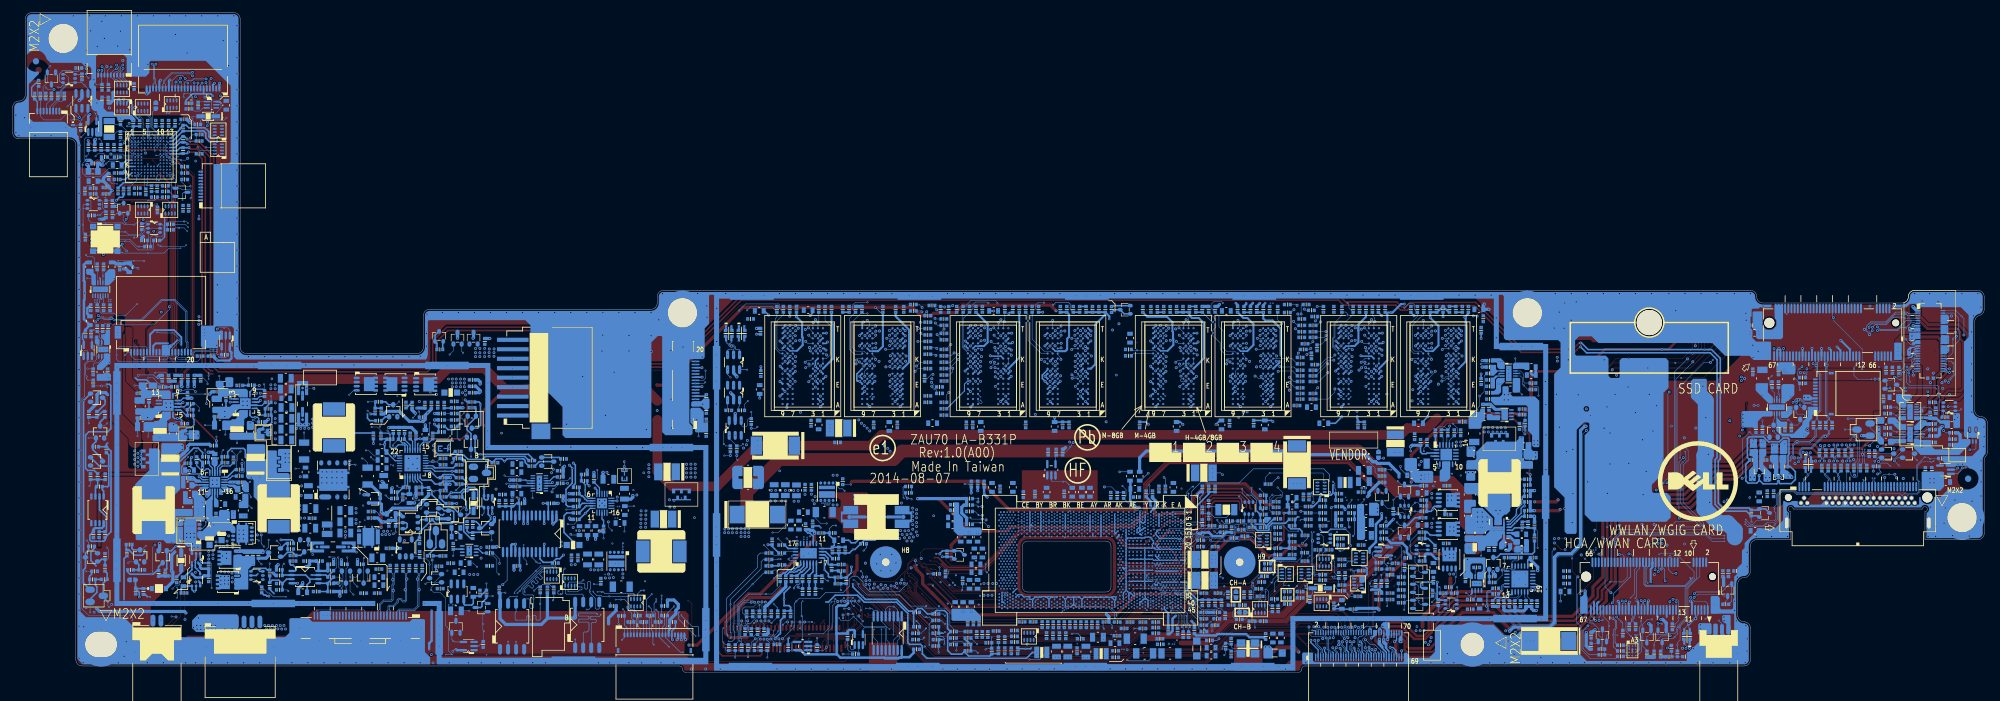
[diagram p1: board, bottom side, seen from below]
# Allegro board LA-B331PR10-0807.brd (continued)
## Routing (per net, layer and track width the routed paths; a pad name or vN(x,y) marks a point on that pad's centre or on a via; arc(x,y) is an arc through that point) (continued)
DDR_B_D0: length 52
  IN4 w0.076: 134.87,51.4 134.91,51.4 ; 147.64,28.02 145.54,25.92 145.54,25.36 145.46,25.28 v1(145.46,24.87)
  IN4 w0.102: 134.87,51.4 133.4,51.4 133.06,51.06 133.06,48.39 131.96,47.29 129.26,47.29 128.15,46.18 128.15,44.43 127.57,43.85 126.67,43.85 v1(126.42,44.1)
  IN4 w0.122: 147.64,28.02 147.64,36.54 141.4,42.78 141.4,49.08 140.52,49.95 140.52,51.82 139.65,52.7 136.74,52.7 136.5,52.46 136.5,51.89 136.01,51.4 134.91,51.4
DDR_B_D1: length 52.1
  IN4 w0.076: 147.98,28.02 147.98,27.93 147.56,27.51 147.37,27.51 145.71,25.84 145.71,24.61 v1(145.46,24.37)
  IN4 w0.102: v1(127.22,44.1) 127.44,44.32 127.44,46.04 129.5,48.1 132.52,48.1 132.76,48.34 132.76,51.04 134.77,53.05
  IN4 w0.122: 147.98,28.02 147.98,36.68 141.78,42.88 141.78,49.22 140.87,50.13 140.87,51.97 139.79,53.05 134.77,53.05
DDR_B_D2: length 52.8
  IN4 w0.076: v1(144.17,24.12) 144.17,24.28 143.92,24.52 143.92,24.72 143.98,24.77 143.98,24.96 143.88,25.06 143.88,25.49 143.61,25.77 143.61,26.82 143.66,26.87 143.66,28.15 144.4,28.89
  IN4 w0.122: v1(126.42,42.5) 125.92,42.5 125.71,42.7 125.71,42.72 125.67,42.77 125.67,43.07 125.71,43.12 125.71,43.38 125.56,43.54 125.36,43.54 125.28,43.46 125.28,42.16 125.16,42.03 124.9,42.03 124.77,42.16 124.77,44.12 124.86,44.21 125.69,44.21 125.82,44.34 125.82,44.67 125.69,44.8 124.39,44.8 124.27,44.67 124.27,42.16 124.14,42.03 123.89,42.03 123.76,42.16 123.76,44.32 123.63,44.44 123.38,44.44 123.25,44.32 123.25,41.71 123.82,41.14 134.35,41.14 134.69,41.48 136.7,41.48 138.97,39.21 139.53,39.21 139.82,38.92 139.82,38.35 143.96,34.22 143.96,32.12 144.4,31.68 144.4,28.89
DDR_B_D3: length 51.1
  IN4 w0.076: v1(145.15,25.52) 145.15,25.95 146.95,27.76 146.95,28.02
  IN4 w0.102: v1(130.42,44.9) 128.72,44.9 128.62,45 128.62,45.51 128.79,45.67 131.52,45.67 133.6,47.76 133.6,50.54 133.78,50.72 134.91,50.72
  IN4 w0.122: 134.91,50.72 138.06,50.72 138.15,50.81 138.15,51.72 138.44,52.01 138.55,52.01 138.66,51.91 138.66,50.84 138.78,50.72 139.02,50.72 139.16,50.86 139.16,51.95 139.23,52.01 139.36,52.01 139.67,51.7 139.67,49.62 140.66,48.63 140.66,42.54 146.95,36.25 146.95,28.02
  BOTTOM w0.076: UCPU1.BJ2 145.03,25.4 v1(145.15,25.52)
DDR_B_D4: length 51
  IN4 w0.076: v1(145.03,24.62) 145.03,25.1 145.03,25.1 145.03,25.29 144.9,25.42 144.9,25.97 146.61,27.67 146.61,28.02
  IN4 w0.102: 134.91,50.37 134.1,50.37 133.96,50.23 133.96,47.15 133.86,47.05 133.37,47.05 133.27,46.95 133.27,46.74 133.37,46.64 133.86,46.64 133.96,46.54 133.96,46.34 133.86,46.24 132.93,46.24 132.84,46.14 132.84,45.93 132.94,45.83 133.86,45.83 133.96,45.73 133.96,43.9 133.83,43.77 133.61,43.77 133.51,43.87 133.51,45.17 133.37,45.31 133.12,45.31 133.03,45.22 133.03,44.65 132.95,44.57 132.67,44.57 132.08,45.17 131.21,45.17 130.81,44.76 130.81,44.26 130.97,44.1 v1(131.22,44.1)
  IN4 w0.122: 146.61,28.02 146.61,36.11 140.31,42.41 140.31,48.5 139.33,49.48 139.33,50.23 139.19,50.37 134.91,50.37
DDR_B_D5: length 53.2
  IN4 w0.076: v1(145.03,24.12) 145.03,24.28 145.27,24.52 145.27,24.72 145.18,24.81 145.18,25.22 145.39,25.42 145.39,25.98 147.3,27.89 147.3,28.02
  IN4 w0.102: v1(127.22,42.5) 127.22,43.09 128.37,44.24 128.37,45.75 129.18,46.56 131.77,46.56 133.3,48.09 133.3,50.94 133.41,51.06 134.91,51.06
  IN4 w0.122: 147.3,28.02 147.3,36.39 141.03,42.66 141.03,48.86 140.12,49.78 140.12,51.74 139.5,52.35 137.98,52.35 137.86,52.23 137.86,51.9 137.74,51.78 137.49,51.78 137.35,51.92 137.35,52.23 137.22,52.35 136.95,52.35 136.84,52.24 136.84,51.22 136.68,51.06 134.91,51.06
DDR_B_D6: length 52
  IN4 w0.076: 144.74,28.9 144.25,28.41 144.14,28.41 143.81,28.09 143.81,26.81 143.76,26.76 143.76,25.83 144.04,25.56 144.04,25.56 144.08,25.52 144.08,25.21 v1(144.17,25.12)
  IN4 w0.102: v1(130.42,42.5) 130.25,42.33 130.13,42.33 130.03,42.44 130.03,42.61 130.3,42.88 130.3,43.15 129.79,43.67 129.68,43.67 129.62,43.6 129.62,42.4 129.52,42.3 129.32,42.3 129.21,42.4 129.21,44.05 129.33,44.17 130.18,44.17 130.25,44.24 130.25,44.48 130.17,44.56 128.91,44.56 128.81,44.46 128.81,42.4 128.71,42.3 128.5,42.3 128.4,42.4 128.4,43.43 128.3,43.53 128.1,43.53 128,43.43 128,43.24 127.89,43.14 127.7,43.14 127.59,43.04 127.59,42.83 127.7,42.73 127.89,42.73 128,42.63 128,42.28 127.92,42.21 126.97,42.21 126.9,42.13 126.9,41.79 127.11,41.57 131.63,41.57 131.89,41.84
  IN4 w0.122: 131.89,41.84 135.67,41.84 135.8,41.96 135.8,42.42 135.88,42.5 136.23,42.5 136.31,42.42 136.31,41.96 136.43,41.84 136.69,41.84 136.82,41.96 136.82,42.49 136.89,42.56 137.25,42.56 137.32,42.49 137.32,41.85 137.45,41.72 137.98,41.72 138.19,41.52 138.19,41.34 137.81,40.96 137.81,40.85 138.06,40.6 138.17,40.6 138.55,40.98 138.73,40.98 138.91,40.8 138.91,40.62 138.53,40.24 138.53,40.13 138.78,39.88 138.89,39.88 139.27,40.26 139.45,40.26 140.17,39.54 140.17,38.49 144.3,34.36 144.3,32.27 144.74,31.82 144.74,28.9
DDR_B_D7: length 52.4
  IN4 w0.076: v1(144.17,24.62) 144.29,24.62 144.36,24.68 144.36,24.97 144.41,25.02 144.41,25.64 144.34,25.71 144.1,25.71 143.91,25.9 143.91,26.69 143.99,26.77 143.99,28.05 144.2,28.26 144.32,28.26 144.49,28.43 144.6,28.43 144.74,28.28 145.12,28.28 145.17,28.34 145.17,28.46 144.96,28.68 144.96,29.84
  IN4 w0.102: 131.96,42.52 131.7,42.52 131.47,42.75 131.28,42.75 131.18,42.65 131.18,42.16 131.09,42.08 130.81,42.08 130.71,42.18 130.71,42.79 v1(130.92,43)
  IN4 w0.122: 131.96,42.52 132.22,42.27 134.54,42.27 134.68,42.41 134.87,42.41 135.01,42.27 135.25,42.27 135.46,42.48 135.46,42.6 135.22,42.84 135.22,42.97 135.46,43.21 135.46,43.84 135.61,43.99 136.85,43.99 137.84,44.98 137.84,45.52 137.93,45.61 138.1,45.61 138.54,45.17 138.74,45.17 138.74,45.17 138.87,45.04 138.87,44.56 138.74,44.43 138.1,44.43 137.97,44.3 137.97,44.05 138.1,43.92 138.74,43.92 138.87,43.8 138.87,43.54 138.74,43.41 137.89,43.41 137.59,43.72 137.46,43.72 137.16,43.41 136.08,43.41 135.97,43.3 135.97,42.99 136.05,42.91 138.74,42.91 138.87,42.78 138.87,42.53 138.74,42.4 138.11,42.4 138.03,42.32 138.03,42.16 138.3,41.89 138.74,41.89 138.87,41.76 138.87,41.56 140.76,39.67 140.76,39.53 140.51,39.27 140.51,39.16 140.76,38.91 140.87,38.91 141.14,39.18 141.25,39.18 141.5,38.93 141.5,38.82 141.01,38.33 141.01,38.15 141.19,37.97 141.37,37.97 141.86,38.46 141.97,38.46 142.22,38.21 142.22,38.1 141.73,37.61 141.73,37.43 141.91,37.25 142.09,37.25 142.58,37.74 142.69,37.74 142.94,37.49 142.94,37.39 142.45,36.89 142.45,36.7 144.64,34.51 144.64,34.36 144.74,34.26 144.89,34.26 145.1,34.05 145.1,33.89 144.98,33.76 144.72,33.76 144.64,33.68 144.64,33.33 144.72,33.25 144.98,33.25 145.1,33.13 145.1,32.87 144.98,32.74 144.81,32.74 144.74,32.67 144.74,32.31 144.81,32.24 144.98,32.24 145.1,32.11 145.1,29.98 144.96,29.84
  BOTTOM w0.076: v1(130.92,43) UD5.B8
DDR_B_D8: length 51.8
  IN4 w0.076: v1(143.73,24.87) 143.73,25.43 143.46,25.71 143.46,26.88 143.51,26.93 143.51,28.39
  IN4 w0.102: v1(118.61,44.1) 119.94,44.1 120.03,44.19 120.03,44.48 119.94,44.57 119.45,44.57 119.37,44.66 119.37,44.77 119.81,45.22 120.33,45.22 120.43,45.12 120.43,43.93 120.53,43.83 120.74,43.83 120.84,43.93 120.84,45.12 120.94,45.22 121.14,45.22 121.24,45.12 121.24,43.93 121.35,43.83 121.55,43.83 121.65,43.93 121.65,45.12 121.75,45.22 121.96,45.22 122.06,45.12 122.06,43.93 122.16,43.83 122.36,43.83 122.46,43.93 122.46,45 122.57,45.1 123.45,45.1 123.53,45.03 123.53,44.86 123.28,44.61 122.97,44.61 122.87,44.52 122.87,41.38 123.31,40.95 123.81,40.95
  IN4 w0.122: 143.51,28.39 143.87,28.75 143.87,31.46 143.42,31.9 143.42,34 136.48,40.95 123.81,40.95
DDR_B_D9: length 52.8
  IN4 w0.076: v1(143.73,24.37) 143.73,24.53 143.49,24.77 143.49,24.97 143.54,25.02 143.54,25.22 143.52,25.24 143.52,25.43 143.3,25.64 143.3,28.53 143.38,28.61
  IN4 w0.102: v1(117.81,44.9) 116.69,44.9 116.57,44.79 116.57,44.59 117.08,44.09 117.6,44.09 118.43,44.92 118.56,44.92 118.65,44.82 118.65,44.5 118.36,44.21 118.36,43.79 118.49,43.65 118.78,43.65 118.85,43.72 118.85,43.86 118.91,43.92 119.19,43.92 119.25,43.85 119.25,43.71 119.31,43.65 119.59,43.65 119.66,43.72 119.66,43.85 119.73,43.92 120,43.92 120.07,43.85 120.07,43.73 120.14,43.65 122.54,43.65 122.62,43.58 122.62,43.34 122.53,43.25 121.04,43.25 120.94,43.15 120.94,42.94 121.04,42.84 122.51,42.84 122.62,42.74 122.62,42.54 122.51,42.44 121.04,42.44 120.94,42.33 120.94,42.13 121.04,42.03 122.51,42.03 122.62,41.93 122.62,40.73 122.74,40.6
  IN4 w0.122: 122.74,40.6 136.33,40.6 143.08,33.86 143.08,31.76 143.53,31.32 143.53,28.75 143.38,28.61
DDR_B_D10: length 53.3
  IN4 w0.076: v1(142.43,24.12) 142.19,24.12 141.89,24.42 141.89,25.34 141.92,25.38 141.92,27.52 141.57,27.87 141.13,27.87 140.29,28.7 ; 111.45,42.37 111.58,42.5 v1(113.81,42.5)
  IN4 w0.122: 111.45,42.37 111.45,41.84 111.33,41.71 110.45,41.71 110.32,41.59 110.32,41.33 110.45,41.2 111.33,41.2 111.45,41.08 111.45,40.82 111.33,40.7 110.45,40.7 110.32,40.57 110.32,40.32 110.45,40.19 111.33,40.19 111.45,40.06 111.45,39.81 111.33,39.68 110.45,39.68 110.32,39.55 110.32,39.3 110.45,39.17 111.88,39.17 112,39.3 112,39.82 112.13,39.95 112.38,39.95 112.51,39.82 112.51,39.3 112.64,39.17 115.35,39.17 117.83,36.69 134.69,36.69 139.6,31.78 139.6,30.31 140.29,29.62 140.29,28.7
DDR_B_D11: length 51.9
  IN4 w0.076: v1(143.3,25.12) 143.3,25.43 143.15,25.58 143.15,28.92
  IN4 w0.102: v1(118.61,43.3) 118.79,43.48 119.04,43.48 119.14,43.38 119.14,43.03 119.04,42.93 118.52,42.93 118.43,42.84 118.43,42.64 118.54,42.52 119.04,42.52 119.14,42.42 119.14,41.18 119.21,41.11 119.47,41.11 119.54,41.18 119.54,43.38 119.64,43.48 119.85,43.48 119.95,43.38 119.95,41.18 120.02,41.11 120.29,41.11 120.36,41.18 120.36,43.38 120.46,43.48 120.67,43.48 120.76,43.39 120.76,41.97 120.89,41.84 121.16,41.84
  IN4 w0.122: 121.16,41.84 121.28,41.84 121.37,41.75 121.37,40.35 121.46,40.26 121.75,40.26 121.88,40.39 121.88,41.7 122.02,41.84 122.27,41.84 122.39,41.72 122.39,40.39 122.51,40.26 136.19,40.26 142.74,33.71 142.74,31.62 143.18,31.17 143.18,28.95 143.15,28.92
DDR_B_D12: length 52.4
  IN4 w0.076: 142.84,28.23 142.92,28.14 142.92,25.56 143.06,25.43 143.06,25.02 143.3,24.78 v1(143.3,24.62)
  IN4 w0.102: v1(117.81,42.5) 117.81,42.99 117.94,43.12 118.17,43.12 118.25,43.04 118.25,42.56 118.47,42.34 118.87,42.34 118.96,42.26 118.96,41.1 119.13,40.93 120.44,40.93 120.53,41.02 120.53,41.6 120.6,41.66 120.93,41.66 121.06,41.53 121.06,40.21
  IN4 w0.122: 142.84,28.23 142.84,31.03 142.4,31.48 142.4,32.61 142.11,32.89 142.11,33.03 142.4,33.31 142.4,33.57 142.23,33.74 142.05,33.74 141.72,33.41 141.6,33.41 141.36,33.64 141.36,33.76 141.69,34.09 141.69,34.27 141.51,34.45 141.33,34.45 141.01,34.13 140.87,34.13 140.65,34.35 140.65,34.49 140.97,34.81 140.97,34.99 140.79,35.17 140.61,35.17 140.28,34.84 140.16,34.84 139.93,35.07 139.93,35.2 140.25,35.53 140.25,35.71 140.07,35.89 139.9,35.89 139.57,35.57 139.44,35.57 139.2,35.8 139.2,35.92 139.54,36.25 139.54,36.43 139.36,36.61 139.18,36.61 138.85,36.29 138.71,36.29 138.49,36.51 138.49,36.64 138.82,36.97 138.82,37.15 138.64,37.33 138.46,37.33 138.13,37 138,37 137.77,37.23 137.77,37.36 138.1,37.69 138.1,37.87 137.92,38.05 137.74,38.05 137.41,37.72 137.28,37.72 137.06,37.94 137.06,38.08 137.38,38.41 137.38,38.59 137.2,38.77 137.02,38.77 136.69,38.44 136.57,38.44 136.33,38.67 136.33,38.8 136.66,39.13 136.66,39.31 136.43,39.54 136.28,39.54 135.98,39.24 135.81,39.24 135.67,39.38 135.67,39.82 135.57,39.92 135.22,39.92 135.13,39.83 135.13,39.7 135.01,39.58 134.76,39.58 134.63,39.71 134.63,39.82 134.53,39.92 121.86,39.92 121.6,39.65 121.6,39.32 121.51,39.23 121.13,39.23 121.06,39.3 121.06,40.21
DDR_B_D13: length 53
  IN4 w0.076: v1(114.61,42.5) 114.15,42.5 113.83,42.18 113.83,41.85 113.74,41.76 113.27,41.76 112.97,42.05 112.9,42.05 112.85,42 112.85,41.7 112.77,41.62 112.62,41.62 112.55,41.69 112.55,42.27 112.47,42.35 112.32,42.35 112.24,42.27 112.24,41.69 112.16,41.62 112.01,41.62 111.94,41.69 111.94,42.27 111.86,42.35 111.71,42.35 111.63,42.27 111.63,41.39 111.71,41.31 112.98,41.31 113.05,41.24 113.05,41.08 112.98,41.01 111.71,41.01 111.63,40.93 111.63,40.78 111.71,40.7 112.28,40.7 112.36,40.63 112.36,40.34 112.44,40.26 112.59,40.26 112.66,40.34 112.66,40.63 112.74,40.7 112.93,40.7 113,40.63 113,40.4 113.2,40.21 ; v1(143.3,24.12) 142.77,24.12 142.53,24.36 142.23,24.36 142.04,24.55 142.04,25.28 142.07,25.31 142.07,27.6 141.66,28.02 141.23,28.02 140.64,28.61
  IN4 w0.122: 140.64,28.61 140.64,29.79 139.94,30.48 139.94,31.92 134.83,37.03 117.97,37.03 115.49,39.52 113.59,39.52 113.46,39.64 113.46,39.95 113.2,40.21
DDR_B_D14: length 51.9
  IN4 w0.076: v1(114.94,43.76) 114.94,43.69 114.71,43.46 114.57,43.46 114.46,43.57 114.46,43.86 114.82,44.21 115.21,44.21 115.37,44.06 115.37,43.41 115.27,43.3 114.99,43.3 114.88,43.19 114.88,42.99 114.97,42.9 115.39,42.9 115.46,42.82 115.46,42.56 115.39,42.49 115.11,42.49 115.04,42.42 115.04,42.16 115.12,42.08 115.39,42.08 115.46,42.01 115.46,41.75 115.39,41.67 114.39,41.67 114.3,41.58 114.3,41.35 114.38,41.27 115.38,41.27 115.46,41.18 115.46,40.81 115.37,40.72 ; v1(142.43,25.12) 142.38,25.17 142.38,27.73 141.73,28.38 141.42,28.38
  IN4 w0.122: 141.42,28.38 141.32,28.48 141.32,30.41 140.63,31.11 140.63,32.21 135.11,37.72 134.14,37.72 134.06,37.8 134.06,37.97 133.87,38.16 133.76,38.16 133.55,37.94 133.55,37.81 133.46,37.72 131.58,37.72 131.48,37.82 131.48,37.99 131.3,38.17 131.12,38.17 130.97,38.02 130.97,37.85 130.85,37.72 129.06,37.72 128.99,37.79 128.99,37.99 128.82,38.16 128.63,38.16 128.48,38.01 128.48,37.83 128.37,37.72 126.05,37.72 125.94,37.83 125.94,38.02 125.75,38.22 125.59,38.22 125.44,38.07 125.44,37.81 125.34,37.72 123.57,37.72 123.48,37.81 123.48,38.05 123.37,38.16 123.09,38.16 122.97,38.04 122.97,37.84 122.85,37.72 119.69,37.72 119.56,37.85 119.56,38.37 119.43,38.5 119.19,38.5 118.99,38.29 118.99,37.82 118.88,37.72 118.58,37.72 118.45,37.85 118.45,38.18 118.34,38.29 117.68,38.29 116.79,39.19 116.79,39.32 117.04,39.57 117.04,39.9 116.91,40.02 116.67,40.02 116.39,39.74 116.23,39.74 115.37,40.6 115.37,40.72
  BOTTOM w0.076: v1(114.94,43.76) UD6.C3
DDR_B_D15: length 52.6
  IN4 w0.076: v1(114.18,43.73) 113.95,43.73 113.36,43.15 112.88,43.15 112.67,42.95 112.67,42.8 112.77,42.71 113.52,42.71 114.09,43.29 114.32,43.29 114.86,42.75 114.86,41.93 114.78,41.85 114.57,41.85 114.48,41.94 114.48,42.25 114.4,42.32 114.22,42.32 114.06,42.16 114.06,41.65 113.96,41.55 113.32,41.55 113.22,41.45 113.22,41.24 113.32,41.14 113.96,41.14 114.06,41.04 114.06,40.84 113.96,40.74 113.31,40.74 113.22,40.65 113.22,40.48 113.37,40.33 114,40.33 114.06,40.28 ; 141.3,28.2 141.69,28.2 142.23,27.66 142.23,25.25 142.19,25.22 142.19,25.02 142.23,24.98 142.23,24.82 v1(142.43,24.62)
  IN4 w0.122: 141.3,28.2 140.98,28.52 140.98,30.13 140.28,30.82 140.28,32.07 134.97,37.38 118.11,37.38 115.63,39.86 115.2,39.86 115.11,39.95 115.11,40.96 115,41.08 114.68,41.08 114.58,40.98 114.58,39.97 114.46,39.86 114.15,39.86 114.06,39.95 114.06,40.28
  BOTTOM w0.076: v1(114.18,43.73) UD6.C2
DDR_B_D16: length 51.5
  IN1 w0.076: v4(142.48,21.48) 142.31,21.65 142.31,22.03 142.29,22.05 142.29,22.82 142.18,22.92 142.18,24.13 141.16,25.15
  IN1 w0.122: 141.16,25.15 141.16,27.66 140.84,27.98 140.84,31.6 133.92,38.53 120.08,38.53 119.79,38.82 119.79,42.92 119.7,43.01 117.93,43.01 116.58,44.35 116.37,44.35 116.04,44.02 115.89,44.02 115.78,44.12 115.78,44.77 115.67,44.89 115.3,44.89 115.17,44.76 115.17,44.14 115.05,44.01 114.74,44.01 114.62,44.14 114.62,45.97 114.48,46.1 v3(114.21,46.1)
  IN4 w0.076: v4(142.48,21.48) 142.48,21.49 142.48,21.69 142.57,21.78 142.94,21.78 142.96,21.8 142.97,21.8 143.11,21.95 143.11,21.96 143.13,21.97 143.13,22.23 143.02,22.34 143.02,22.68 143.11,22.77 143.11,22.93 v1(143.3,23.12)
  BOTTOM w0.076: UD6.F2 v3(114.21,46.1)
DDR_B_D17: length 53.3
  IN1 w0.076: 139.33,26.84 139.33,24.68 139.91,24.1 139.91,23.8 139.51,23.4 139.51,22.27 140.02,21.76 141.61,21.76 v4(141.97,21.4)
  IN1 w0.122: 139.33,26.84 139.33,31.66 133.49,37.5 119.44,37.5 115.25,41.69 113.3,41.69 112.63,42.35 112.63,47 114.12,48.48 v3(114.21,48.48)
  IN4 w0.076: v1(142.43,23.12) 142.43,22.96 142.62,22.77 142.62,22.77 142.69,22.7 142.69,22.46 142.45,22.23 142.45,21.9 142.31,21.77 142.31,21.76 141.97,21.42 v4(141.97,21.4)
  BOTTOM w0.076: UD6.H3 114.59,48.1 v3(114.21,48.48)
DDR_B_D18: length 51.6
  IN1 w0.076: v4(143.62,23.85) 143.62,24.54 143.01,25.15 143.01,28.49 143.39,28.87 143.39,29.03
  IN1 w0.122: 143.39,29.03 143.39,32.64 134.63,41.41 124.9,41.41 124.64,41.67 124.64,42.14 124.76,42.26 125.59,42.26 125.72,42.39 125.72,42.65 125.59,42.77 124.76,42.77 124.64,42.9 124.64,43.15 124.76,43.28 125.44,43.28 125.56,43.41 125.56,43.66 125.44,43.79 124.76,43.79 124.64,43.92 124.64,46.23 124.52,46.34 124.34,46.34 123.98,45.98 123.81,45.98 123.63,46.16 123.63,46.35 123.98,46.7 123.98,46.88 123.65,47.21 123.18,47.21 123,47.03 123,46.63 122.9,46.53 122.45,46.53 122.33,46.65 122.33,47.31 122.2,47.44 121.95,47.44 121.82,47.31 121.82,46.65 121.69,46.53 121.41,46.53 121.28,46.65 121.28,47.23 121.12,47.39 119.57,47.39 119.39,47.21 119.39,46.48 v3(119.01,46.1)
  IN4 w0.076: v4(143.62,23.85) 143.62,23.83 143.4,23.62 v1(143.3,23.62)
  BOTTOM w0.076: UD6.F8 v3(119.01,46.1)
DDR_B_D19: length 52.5
  IN1 w0.076: v4(141.97,22.36) 141.8,22.36 141.54,22.62 141.54,24.23 140.88,24.89 140.88,26.66 140.45,27.09 140.45,28.98
  IN1 w0.122: 140.45,28.98 140.5,29.03 140.5,31.46 133.77,38.19 119.72,38.19 119.09,38.82 119.09,42.28 118.73,42.64 117.77,42.64 116.8,43.6 116.49,43.6 116.36,43.48 116.36,42.73 116.23,42.6 115.98,42.6 115.85,42.73 115.85,43.48 115.72,43.6 115.47,43.6 115.34,43.48 115.34,42.73 115.22,42.6 114.96,42.6 114.84,42.73 114.84,43.48 114.71,43.6 113.9,43.6 113.78,43.73 113.78,46.47 v3(114.21,46.9)
  IN4 w0.076: v1(142.43,23.62) 142.43,23.54 142.19,23.3 142.19,22.64 141.97,22.42 141.97,22.36 v4(141.97,22.36)
  BOTTOM w0.076: UD6.G2 v3(114.21,46.9)
DDR_B_D20: length 52.6
  IN1 w0.076: v4(143.75,22.23) 143.3,22.68 143.3,23.91 143.11,24.1 143.11,24.83 142.86,25.08 142.86,28.61 143.05,28.81 143.05,29.03
  IN1 w0.122: 143.05,29.03 143.05,32.5 134.49,41.06 124.96,41.06 124.43,41.59 124.43,45.56 124.28,45.71 123.56,45.71 123.43,45.59 123.43,45.06 123.3,44.94 122.71,44.94 122.59,45.06 122.59,45.53 122.46,45.66 122.21,45.66 122.08,45.53 122.08,45.06 121.95,44.94 121.7,44.94 121.57,45.06 121.57,46.06 121.45,46.19 121.19,46.19 121.06,46.06 121.06,45.06 120.94,44.94 120.68,44.94 120.56,45.06 120.56,45.82 120.43,45.95 120.18,45.95 120.05,45.82 120.05,45.06 119.92,44.94 119.61,44.94 119.48,45.06 119.48,45.59 119.35,45.71 118.69,45.71 118.59,45.81 118.59,46.49 119,46.9 v3(119.01,46.9)
  IN4 w0.076: v4(143.75,22.23) 143.73,22.24 v1(143.73,22.87)
  BOTTOM w0.076: UD6.H8 119.01,47.7 v3(119.01,46.9)
DDR_B_D21: length 53.5
  IN1 w0.076: 139.61,27.04 139.61,26.79 139.48,26.66 139.48,25.35 140.8,24.03 140.8,23.14 141.49,22.46 141.49,22.23 141.84,21.88 v4(141.98,21.88)
  IN1 w0.122: 139.61,27.04 140.14,27.58 140.14,31.33 133.63,37.85 119.58,37.85 115.26,42.17 113.86,42.17 112.84,43.19 112.84,46.91 113.67,47.74 116.56,47.74 v3(117.41,46.9)
  IN4 w0.076: v1(142.43,22.62) 142.3,22.49 142.3,22.2 141.98,21.88 v4(141.98,21.88)
  BOTTOM w0.076: UD6.F7 v3(117.41,46.9)
DDR_B_D22: length 52.8
  IN1 w0.076: 142.33,24.45 142.33,22.99 142.44,22.88 142.44,22.12 142.47,22.09 142.47,21.97 142.65,21.78 143.33,21.78 143.56,21.55 v4(143.56,21.31)
  IN1 w0.122: v3(115.01,45.3) 116.08,45.3 118.1,43.29 119.95,43.29 120.13,43.11 120.13,39.27 120.53,38.88 120.86,38.88 120.99,39 120.99,39.11 121.11,39.24 121.37,39.24 121.49,39.11 121.49,39 121.62,38.88 122.88,38.88 123,39 123,39.11 123.13,39.24 123.38,39.24 123.51,39.11 123.51,39 123.64,38.88 123.89,38.88 124.02,39 124.02,39.11 124.15,39.24 124.4,39.24 124.53,39.11 124.53,39 124.65,38.88 124.91,38.88 125.04,39 125.04,39.11 125.16,39.24 125.42,39.24 125.54,39.11 125.54,39 125.67,38.88 125.92,38.88 126.05,39 126.05,39.11 126.18,39.24 126.43,39.24 126.56,39.11 126.56,39 126.69,38.88 127.49,38.88 127.71,39.1 127.96,39.1 128.18,38.88 128.43,38.88 128.53,38.97 128.53,39.14 128.63,39.24 128.93,39.24 129.03,39.13 129.03,38.96 129.12,38.88 129.45,38.88 129.54,38.97 129.54,39.14 129.64,39.24 129.95,39.24 130.05,39.14 130.05,38.98 130.15,38.88 130.47,38.88 130.56,38.96 130.56,39.14 130.66,39.24 130.97,39.24 131.07,39.14 131.07,38.98 131.17,38.88 131.48,38.88 131.57,38.97 131.57,39.14 131.67,39.24 132,39.24 132.08,39.15 132.08,38.95 132.16,38.88 133.12,38.88 133.2,38.96 133.2,39.15 133.29,39.24 133.66,39.24 133.73,39.17 133.73,38.95 133.8,38.88 134.06,38.88 141.19,31.75 141.19,28.5 141.95,27.74 141.95,24.84 142.33,24.45
  IN4 w0.076: v4(143.56,21.31) 143.65,21.4 143.65,21.66 143.28,22.03 143.28,22.6 v1(143.3,22.62)
  BOTTOM w0.076: UD6.E3 v3(115.01,45.3)
DDR_B_D23: length 52.1
  IN1 w0.076: 142.71,29.03 142.71,25.02 142.96,24.77 142.96,24.03 143.15,23.84 143.15,22.27 143.7,21.72 143.82,21.72 v4(144.15,21.39)
  IN1 w0.122: 142.71,29.03 142.71,32.36 134.32,40.75 124.33,40.75 124.23,40.85 124.23,45.39 124.12,45.51 123.75,45.51 123.63,45.39 123.63,44.86 123.51,44.73 119.4,44.73 119.24,44.9 117.98,44.9 117.83,45.05 117.83,48.21 v3(117.49,48.54)
  IN4 w0.076: v4(144.15,21.39) 144.14,21.39 143.62,21.91 143.62,21.91 143.43,22.1 143.43,22.36 143.54,22.47 143.54,22.52 143.54,22.72 143.54,22.72 143.49,22.77 143.49,22.97 143.73,23.21 v1(143.73,23.37)
  BOTTOM w0.076: v3(117.49,48.54) 117.81,48.23 UD6.H7
DDR_B_D24: length 48.7
  IN1 w0.076: v4(145.24,21.88) 145.23,21.88 145.23,21.89 145.15,21.97 145.15,23.07 145.65,23.57 145.65,26.67 146.12,27.14 146.12,28.13
  IN1 w0.122: v3(130.03,46.09) 128.21,46.09 128.06,46.24 128.06,46.95 128.17,47.06 128.48,47.06 128.59,46.96 128.59,46.68 128.7,46.56 129,46.56 129.12,46.69 129.12,46.96 129.25,47.08 129.5,47.08 129.63,46.96 129.63,46.7 129.82,46.51 131.72,46.51 133.36,48.16 133.36,49.1 133.75,49.5 137.49,49.5 138.03,48.96 138.03,45.36 138.71,44.69 138.71,44.68 146.7,36.68 146.7,28.71 146.12,28.13
  IN4 w0.076: v1(145.11,22.31) 145.11,22.02 v4(145.24,21.88)
  BOTTOM w0.076: UCPU1.BJ12 145.03,22.38 v1(145.11,22.31)
  BOTTOM w0.102: v3(130.03,46.09) 130.42,46.48 UD5.F7
DDR_B_D25: length 50.1
  IN1 w0.076: v4(144.64,21.42) 144.64,21.75 144.45,21.94 144.45,22 144.22,22.23 144.22,22.42 144.09,22.56 144.09,24.58 143.38,25.29 143.38,28.21 144.03,28.86 144.24,28.86 144.32,28.93 144.32,29.03
  IN1 w0.122: v3(127.73,47.71) 127.72,47.72 127.1,47.72 126.44,47.06 126.44,44.47 127.21,43.71 130.22,43.71 131.48,42.45 134.83,42.45 135.14,42.13 135.32,42.13 136,42.81 136.18,42.81 136.36,42.63 136.36,42.45 135.68,41.77 135.68,41.59 135.86,41.41 136.04,41.41 136.72,42.09 136.9,42.09 137.04,41.94 137.04,41.69 136.4,41.05 136.4,40.87 137.91,39.36 138.04,39.36 138.53,39.86 138.71,39.86 138.89,39.68 138.89,39.5 138.42,39.02 138.42,38.86 142.48,34.8 142.66,34.8 143.43,35.58 143.61,35.58 143.79,35.4 143.79,35.22 143.37,34.8 143.37,34.62 143.55,34.44 143.73,34.44 144.02,34.72 144.17,34.72 144.32,34.58 144.32,29.03
  IN4 w0.076: v4(144.64,21.42) 144.64,21.42 144.49,21.57 144.49,21.83 144.45,21.87 144.45,22.06 144.22,22.29 144.22,22.42 144.17,22.48 v1(144.17,22.62)
  BOTTOM w0.102: v3(127.73,47.71) 127.34,48.1 UD5.H3
DDR_B_D26: length 47.8
  IN1 w0.076: 145.21,27.71 145.21,23.93 v4(145.31,23.83)
  IN1 w0.122: 145.21,27.71 146.36,28.86 146.36,36.54 138.36,44.54 138.36,44.55 137.69,45.22 137.69,48.81 137.35,49.15 137.25,49.15 137.12,49.03 137.12,46.86 136.99,46.73 136.74,46.73 136.61,46.86 136.61,49.03 136.48,49.15 136.23,49.15 136.1,49.03 136.1,46.86 135.98,46.73 135.72,46.73 135.59,46.86 135.59,49.03 135.47,49.15 134.06,49.15 133.67,48.76 133.67,48.07 131.69,46.1 v3(130.81,46.1)
  IN4 w0.076: v1(145.03,23.62) 145.24,23.83 v4(145.31,23.83)
  BOTTOM w0.076: v3(130.81,46.1) 131.2,46.5 UD5.F8
DDR_B_D27: length 48.9
  IN1 w0.076: v4(145.12,21.41) 145.22,21.41 145.58,21.76 145.58,22 145.38,22.2 145.37,22.2 145.3,22.27 145.3,23 145.81,23.51 145.81,26.61 146.33,27.13 146.33,27.85
  IN1 w0.122: 146.33,27.85 147.06,28.58 147.06,36.82 139.05,44.82 139.05,44.83 138.38,45.51 138.38,49.1 137.64,49.84 133.69,49.84 133.11,49.26 133.11,48.19 132.09,47.17 131.33,47.17 131.21,47.29 127.19,47.29 v3(126.81,46.91)
  IN4 w0.076: v4(145.12,21.41) 145.12,21.41 145.26,21.55 145.28,21.55 145.28,21.56 145.37,21.56 145.58,21.76 145.58,22.03 145.36,22.25 145.36,22.63 145.22,22.77 145.22,22.93 v1(145.03,23.12)
  BOTTOM w0.076: v3(126.81,46.91) 126.42,47.29 UD5.G2
DDR_B_D28: length 50.5
  IN1 w0.076: 144.98,27.96 144.98,22.24 v4(144.79,22.05)
  IN1 w0.122: v3(127.8,45.27) 128.22,45.7 133.58,45.7 133.7,45.82 133.7,47.66 133.85,47.8 134.1,47.8 134.21,47.69 134.21,45.82 134.34,45.7 134.59,45.7 134.72,45.82 134.72,47.99 134.22,48.48 134.22,48.66 134.38,48.81 135.1,48.81 135.23,48.69 135.23,46.61 135.46,46.39 137.17,46.39 137.35,46.21 137.35,45.08 138.02,44.41 138.02,44.4 144.1,38.32 144.11,38.32 145.91,36.52 145.91,28.89 144.98,27.96
  IN4 w0.076: v1(144.17,23.62) 144.27,23.51 144.27,23.35 144.41,23.22 144.5,23.13 144.68,23.13 144.7,23.11 144.7,23.11 144.88,22.93 144.88,22.43 144.86,22.41 144.86,22.33 144.79,22.26 v4(144.79,22.05)
  BOTTOM w0.102: v3(127.8,45.27) 127.8,45.27 127.37,45.7 UD5.E3
DDR_B_D29: length 50.1
  IN1 w0.076: v4(144.13,21.87) 144.13,22.08 144.07,22.15 144.07,22.36 143.93,22.49 143.93,24.52 143.23,25.22 143.23,28.28 143.95,29.01 143.95,29.03
  IN1 w0.122: v3(125.99,46.12) 125.6,45.73 125.6,45.33 125.13,44.86 125.13,44.61 125.27,44.47 125.82,44.47 127.29,43 127.29,41.88 127.46,41.71 127.73,41.71 127.85,41.84 127.85,43.15 127.98,43.27 128.23,43.27 128.36,43.15 128.36,41.84 128.49,41.71 128.74,41.71 128.87,41.84 128.87,43.15 129,43.27 129.25,43.27 129.38,43.15 129.38,41.84 129.5,41.71 129.76,41.71 129.88,41.84 129.88,43.15 130.01,43.27 130.27,43.27 130.39,43.15 130.39,41.84 130.52,41.71 135.08,41.71 142.5,34.29 142.68,34.29 142.84,34.45 143.02,34.45 143.2,34.27 143.2,34.09 143.04,33.93 143.04,33.75 143.22,33.57 143.4,33.57 143.71,33.88 143.86,33.88 143.97,33.77 143.97,33.42 143.76,33.21 143.76,33.03 143.95,32.84 143.95,29.03
  IN4 w0.076: v1(144.17,23.12) 144.17,22.96 143.97,22.77 143.97,22.77 143.91,22.71 143.91,22.51 144.07,22.36 144.07,22.09 144.16,22 144.16,21.87 v4(144.13,21.87)
  BOTTOM w0.102: UD5.F2 126.04,46.12 v3(125.99,46.12)
DDR_B_D30: length 45.8
  IN1 w0.076: 146.99,27.27 146.11,26.39 146.11,22.26 145.93,22.09 145.89,22.09 145.84,22.04 145.82,22.04 145.73,21.95 145.73,21.46 v4(145.59,21.32)
  IN1 w0.122: v3(131.61,47.75) 131.61,48.22 132.31,48.91 132.31,49.93 132.98,50.6 137.84,50.6 139.74,48.71 139.74,45.18 147.97,36.94 147.97,28.46 146.99,27.48 146.99,27.27
  IN4 w0.076: v1(145.46,23.37) 145.74,23.09 145.74,22.76 146.02,22.49 146.02,22.22 145.74,21.94 145.74,21.91 145.73,21.9 145.73,21.46 v4(145.59,21.32)
  BOTTOM w0.076: v3(131.61,47.75) 131.58,47.75 131.23,48.1 UD5.H8
DDR_B_D31: length 46.3
  IN1 w0.076: v4(145.71,22.35) 145.96,22.61 145.96,26.5 146.61,27.14 146.61,27.65
  IN1 w0.122: v3(130.82,47.72) 131.11,47.72 131.46,47.38 131.81,47.38 132.77,48.34 132.77,49.84 133.2,50.26 137.7,50.26 138.72,49.24 138.72,48.72 138.85,48.59 139.25,48.59 139.38,48.47 139.38,48.21 139.25,48.08 138.85,48.08 138.72,47.96 138.72,47.7 138.85,47.58 139.25,47.58 139.38,47.45 139.38,47.2 139.25,47.07 138.85,47.07 138.72,46.94 138.72,46.69 138.85,46.56 139.25,46.56 139.38,46.43 139.38,46.18 139.25,46.05 138.85,46.05 138.72,45.93 138.72,45.65 138.85,45.52 139.28,45.52 139.39,45.41 139.39,45.01 147.51,36.89 147.51,28.55 146.61,27.65
  IN4 w0.076: v4(145.71,22.35) 145.55,22.51 145.55,22.78 v1(145.46,22.87)
  BOTTOM w0.076: v3(130.82,47.72) 130.8,47.72 UD5.H7
DDR_B_D32: length 51.3
  IN4 w0.122: v1(137.59,25.37) 137.59,27.34 138.21,27.96 138.21,31.44 134.18,35.47 117.32,35.47 114.84,37.95 105.96,37.95 105.84,38.08 105.84,38.33 105.71,38.46 105.45,38.46 105.33,38.33 105.33,38.08 105.2,37.95 104.95,37.95 104.82,38.08 104.82,38.33 104.69,38.46 104.44,38.46 104.31,38.33 104.31,38.08 104.18,37.95 102.62,37.95 101.07,39.5 101.07,40.84 101.08,40.85 v1(101.08,42.5)
DDR_B_D33: length 50.4
  IN4 w0.122: v1(136.29,25.12) 136.29,27.26 135.67,27.88 135.67,30.39 133.13,32.94 116.27,32.94 113.79,35.42 101.4,35.42 98.33,38.49 98.33,42.05 v1(97.88,42.5)
DDR_B_D34: length 52.8
  IN4 w0.076: 136.5,25.66 136.48,25.65 136.48,25.27 136.53,25.22 136.53,25.2 136.73,25.01 v1(136.73,24.87)
  IN4 w0.122: v1(97.08,44.1) 97.11,44.1 98.68,42.53 98.68,38.63 101.55,35.76 113.93,35.76 116.41,33.28 133.27,33.28 136.02,30.53 136.02,27.9 136.5,27.42 136.5,25.66
DDR_B_D35: length 52.7
  IN4 w0.076: 138.1,25.99 138.16,25.92 138.16,24.94 v1(137.59,24.37)
  IN4 w0.122: v1(101.88,44.1) 101.89,44.1 102.46,44.1 102.82,43.74 102.82,39.57 103.2,39.18 105.95,39.18 106.5,38.64 115.13,38.64 117.61,36.16 134.47,36.16 138.97,31.65 138.97,27.83 138.82,27.68 138.66,27.68 138.1,27.12 138.1,25.99
DDR_B_D36: length 51.3
  IN4 w0.076: v1(137.59,24.87) 137.98,25.26 137.98,25.77 137.88,25.87
  IN4 w0.122: v1(101.88,43.3) 101.62,43.04 101.62,39.64 102.42,38.84 105.81,38.84 106.36,38.3 114.99,38.3 117.47,35.82 134.32,35.82 138.59,31.55 138.59,27.91 138.35,27.68 138.31,27.68 137.95,27.31 137.94,27.31 137.88,27.26 137.88,25.87
DDR_B_D37: length 51.9
  IN4 w0.122: v1(136.73,25.37) 136.73,25.37 136.73,27.59 136.36,27.95 136.36,30.67 133.41,33.62 116.56,33.62 114.08,36.1 101.74,36.1 99.02,38.82 99.02,42.96 v1(97.88,44.1)
DDR_B_D38: length 54
  IN4 w0.076: v1(136.73,24.37) 136.85,24.49 136.85,24.65 136.97,24.77 136.97,24.97 136.88,25.06 136.88,25.18 136.97,25.27 136.97,25.51
  IN4 w0.122: v1(100.75,44.53) 99.36,43.14 99.36,39.07 101.99,36.44 114.22,36.44 116.7,33.96 133.56,33.96 136.7,30.82 136.7,27.91 136.97,27.64 136.97,25.51
  BOTTOM w0.076: v1(100.75,44.53) 100.75,44.56 UD8.D7
DDR_B_D39: length 51.3
  IN4 w0.076: v1(136.29,24.62) 136.29,24.68 136.1,24.87 136.1,24.97 136.05,25.02 136.05,25.21 136.1,25.27 136.1,25.76 136.07,25.8
  IN4 w0.122: 136.07,25.8 136.07,27.08 135.33,27.82 135.33,30.25 132.99,32.59 116.13,32.59 113.65,35.07 101.26,35.07 97.99,38.34 97.99,41.59 v1(97.08,42.5)
DDR_B_D40: length 56.8
  IN4 w0.076: 135.62,25.57 135.62,25.27 135.86,25.03 v1(135.86,24.87)
  IN4 w0.122: 135.62,25.57 135.62,26.84 134.46,28.01 134.46,29.88 132.62,31.72 115.77,31.72 113.29,34.2 100.9,34.2 93.87,41.23 89.75,41.23 v1(88.47,42.5)
DDR_B_D41: length 56.8
  IN4 w0.122: v1(135.86,25.37) 135.86,26.91 134.8,27.97 134.8,30.03 132.77,32.06 115.91,32.06 113.43,34.54 101.04,34.54 94.11,41.47 90,41.47 89.27,42.19 v1(89.27,43.3)
DDR_B_D42: length 59.3
  IN4 w0.076: v1(134.56,25.12) 134.56,25.21 133.55,26.22 133.54,26.22 133.22,26.54 133.22,26.92 132.74,27.4
  IN4 w0.122: v1(85.27,44.1) 86.02,43.36 86.02,41.41 88.17,39.25 92.73,39.25 99.97,32 112.38,32 114.74,29.64 131.49,29.64 131.98,29.15 131.98,27.91 132.48,27.4 132.74,27.4
DDR_B_D43: length 60.7
  IN4 w0.076: 134.77,25.96 134.77,25.63 134.74,25.6 134.74,25.27 134.95,25.06 134.95,24.91 v1(134.99,24.87)
  IN4 w0.122: v1(88.47,44.9) 88.17,44.9 87.09,43.83 87.09,40.82 88.32,39.59 92.87,39.59 100.12,32.34 112.52,32.34 114.88,29.98 131.74,29.98 132.46,29.26 132.46,27.9 132.75,27.61 133.12,27.61 134.77,25.96
DDR_B_D44: length 60.2
  IN4 w0.122: v1(134.99,25.37) 134.99,26.08 132.95,28.13 132.95,29.26 132,30.21 131.99,30.21 131.88,30.32 115.03,30.32 112.66,32.69 100.26,32.69 93.01,39.93 88.46,39.93 87.43,40.96 87.43,43.66 88.32,44.54 88.83,44.54 v1(89.27,44.1)
DDR_B_D45: length 61.4
  IN4 w0.076: v1(135.86,24.37) 135.32,24.37 135.24,24.45 135.24,24.47 135.08,24.63 134.89,24.63 134.64,24.88 134.46,24.88 134.32,25.02 134.32,25.23 133.63,25.93 133.49,26.07 133.48,26.07 133.07,26.47 133.07,26.48 133.06,26.49 133.06,26.73 132.65,27.14 132.45,27.14
  IN4 w0.122: v1(84.47,44.1) 84.47,43.64 85.06,43.06 85.09,43.06 85.63,42.51 85.63,41.3 88.03,38.91 92.59,38.91 99.83,31.66 112.23,31.66 114.59,29.3 131.08,29.3 131.49,28.9 131.49,27.91 131.58,27.82 131.77,27.82 132.45,27.14
DDR_B_D46: length 58.1
  IN4 w0.076: v1(134.56,24.62) 134.45,24.72 134.4,24.72 134.17,24.95 134.17,25.17 133.56,25.77 133.42,25.91 133.41,25.91 132.92,26.41 132.92,26.42 132.91,26.43 132.91,26.54 132.57,26.88 132.41,26.88 131.68,27.6
  IN4 w0.122: 131.68,27.6 131.37,27.6 131.01,27.96 131.01,28.71 130.75,28.97 114.44,28.97 112.09,31.32 99.69,31.32 92.44,38.56 87.89,38.56 85.27,41.18 v1(85.27,42.5)
DDR_B_D47: length 59.1
  IN4 w0.076: v1(134.99,24.37) 134.45,24.37 133.94,24.87 133.94,25.18 133.48,25.64 133.36,25.76 133.35,25.76 132.81,26.3 132.76,26.3 131.81,27.25 131.71,27.25 131.6,27.36
  IN4 w0.122: 131.6,27.36 131.19,27.36 130.66,27.89 130.66,28.33 130.37,28.63 114.29,28.63 111.95,30.97 99.55,30.97 92.3,38.22 87.68,38.22 84.47,41.42 v1(84.47,42.5)
DDR_B_D48: length 57.4
  IN1 w0.076: v4(138.23,23.52) 138.67,23.96 138.67,24.39 138.42,24.63 138.42,26.7 138.64,26.92
  IN1 w0.122: v3(102.27,48.48) 103.34,48.48 103.82,48 103.82,47.16 104.15,46.83 105.4,46.83 115.41,36.82 115.81,36.82 115.94,36.95 115.94,37.84 116.07,37.97 116.32,37.97 116.45,37.84 116.45,36.95 116.58,36.82 116.83,36.82 116.96,36.95 116.96,37.84 117.08,37.97 117.34,37.97 117.46,37.84 117.46,36.95 117.59,36.82 133.2,36.82 138.64,31.38 138.64,26.92
  IN4 w0.076: v1(137.59,23.37) 137.75,23.52 v4(138.23,23.52)
  BOTTOM w0.076: UD8.H8 101.89,48.1 v3(102.27,48.48)
DDR_B_D49: length 57.8
  IN1 w0.076: v4(138.29,24.06) 138.29,24.39 138.19,24.49 138.19,26.76 138.3,26.88
  IN1 w0.122: 138.3,26.88 138.3,31.24 133.06,36.48 114.06,36.48 113.95,36.59 113.95,36.76 114.33,37.15 114.33,37.33 114.15,37.51 113.98,37.51 113.59,37.12 113.41,37.12 113.23,37.3 113.23,37.48 113.62,37.87 113.62,38.05 113.44,38.23 113.26,38.23 112.87,37.84 112.69,37.84 112.51,38.02 112.51,38.2 112.9,38.59 112.9,38.77 112.72,38.95 112.54,38.95 112.15,38.56 111.97,38.56 111.79,38.74 111.79,38.92 112.18,39.31 112.18,39.49 112,39.67 111.82,39.67 111.43,39.28 111.25,39.28 109.77,40.76 109.53,40.76 102.21,48.08 101.88,48.08 v3(101.46,48.5)
  IN4 w0.076: v4(138.29,24.06) 138.1,23.87 v1(137.59,23.87)
  BOTTOM w0.076: UD8.H7 101.08,48.12 v3(101.46,48.5)
DDR_B_D50: length 58
  IN1 w0.076: 136.68,24.45 136.68,23.71 136.56,23.6 136.56,22.53 136.21,22.18 v4(136.21,22.1)
  IN1 w0.122: 136.68,24.45 136.68,26.61 135.76,27.52 135.76,29.98 131.81,33.94 112.05,33.94 107.23,38.76 107.23,38.94 107.53,39.24 107.53,39.42 107.44,39.51 105.27,41.67 100.75,41.67 97.48,44.94 v3(97.48,46.88)
  IN4 w0.076: v1(136.29,23.62) 136.29,23.46 136.48,23.27 136.48,23.27 136.54,23.22 136.54,23.02 136.48,22.97 136.48,22.77 136.51,22.74 136.51,22.48 136.4,22.36 136.4,22.34 136.21,22.15 v4(136.21,22.1)
  BOTTOM w0.076: v3(97.48,46.88) 97.11,46.5 UD8.F2
DDR_B_D51: length 56
  IN1 w0.076: 137.49,24.5 137.49,23.71 137.07,23.29 137.07,21.85 136.97,21.75 v4(136.71,21.75)
  IN1 w0.122: v3(101.47,46.1) 100.91,45.54 100.91,43.65 101.37,43.2 105.2,43.2 113.43,34.97 132.24,34.97 136.79,30.41 136.79,27.5 137.49,26.8 137.49,24.5
  IN4 w0.076: v1(136.73,23.37) 136.73,23.21 137.04,22.89 137.04,22.02 136.76,21.74 136.74,21.74 136.74,21.75 v4(136.71,21.75)
  BOTTOM w0.076: UD8.F8 101.88,46.5 101.48,46.1 v3(101.47,46.1)
DDR_B_D52: length 58.3
  IN1 w0.076: v4(138.18,23.04) 138.23,23.04 138.53,23.33 138.53,23.38 138.54,23.39 138.54,23.6 138.82,23.88 138.82,24.46 138.58,24.71 138.58,26.6 138.99,27.01
  IN1 w0.122: v3(98.4,48.26) 98.76,48.62 99.13,48.62 99.38,48.87 103.57,48.87 104.72,47.72 105.62,47.72 115.03,38.31 117.65,38.31 118.8,37.16 133.35,37.16 138.99,31.52 138.99,27.01
  IN4 w0.076: v4(138.18,23.04) 137.76,23.04 v1(137.59,22.87)
  BOTTOM w0.076: v3(98.4,48.26) 98.24,48.1 UD8.H3
DDR_B_D53: length 55.7
  IN1 w0.122: v4(137.02,24.06) 137.02,26.57 136.11,27.49 136.11,30.13 131.95,34.28 112.19,34.28 109.96,36.51 109.96,36.69 110.26,36.99 110.26,37.17 110.08,37.35 109.9,37.35 109.6,37.05 109.42,37.05 109.24,37.23 109.24,37.41 109.54,37.71 109.54,37.89 109.36,38.07 109.18,38.07 108.88,37.77 108.7,37.77 108.52,37.95 108.52,38.13 108.82,38.43 108.82,38.61 108.64,38.79 108.46,38.79 108.16,38.49 107.98,38.49 107.8,38.67 107.8,38.85 108.1,39.15 108.1,39.33 104.95,42.47 100.82,42.47 98.35,44.95 v3(98.35,45.29)
  IN4 w0.076: v4(137.02,24.06) 136.83,23.87 v1(136.73,23.87)
  BOTTOM w0.076: v3(98.35,45.29) 97.94,45.7 UD8.E3
DDR_B_D54: length 57.5
  IN1 w0.076: 137.22,24.41 137.34,24.3 137.34,23.78 136.79,23.23 136.79,22.31 v4(136.71,22.23)
  IN1 w0.122: v3(100.69,46.09) 100.09,45.48 100.09,43.91 101.14,42.85 105.06,42.85 110.83,37.08 110.83,36.9 110.53,36.6 110.53,36.42 110.71,36.24 110.89,36.24 111.19,36.54 111.37,36.54 111.55,36.36 111.55,36.18 111.25,35.88 111.25,35.7 111.43,35.52 111.61,35.52 111.91,35.82 112.09,35.82 112.27,35.64 112.27,35.46 111.97,35.16 111.97,34.98 112.15,34.8 112.33,34.8 112.63,35.1 112.81,35.1 113.29,34.62 132.09,34.62 136.45,30.27 136.45,27.52 137.22,26.75 137.22,24.41
  IN4 w0.076: v4(136.71,22.23) 136.71,22.23 136.73,22.23 v1(136.73,22.87)
  BOTTOM w0.076: v3(100.69,46.09) 100.69,46.1 101.08,46.49 UD8.F7
DDR_B_D55: length 56.4
  IN1 w0.076: 136.48,24.3 136.48,23.8 136.19,23.51 v4(136.19,22.63)
  IN1 w0.122: 136.48,24.3 136.35,24.44 136.35,26.55 135.42,27.48 135.42,29.84 131.67,33.6 111.9,33.6 104.24,41.25 100.56,41.25 97.11,44.7 97.11,47.32 v3(97.47,47.68)
  IN4 w0.076: v4(136.19,22.63) 136.19,23.01 v1(136.29,23.12)
  BOTTOM w0.076: UD8.G2 97.09,47.3 v3(97.47,47.68)
DDR_B_D56: length 63
  IN1 w0.076: v4(134.25,21.79) 133.92,22.12 133.92,22.41 133.77,22.56 133.77,22.77 133.55,22.99 133.55,23.92 133.46,24.01 133.46,24.77 ; v3(84.88,45.34) 85.54,45.34 88.21,42.66 89.23,41.65 89.58,41.65
  IN1 w0.122: 89.58,41.65 92.35,41.65 97.55,36.45 103.23,36.45 110.19,29.5 129.94,29.5 131.28,28.15 131.28,27.6 132.4,26.48 132.4,26.17 133.46,25.11 133.46,24.77
  IN4 w0.076: v1(134.99,22.87) 134.99,22.79 134.57,22.36 134.57,22.15 134.25,21.83 v4(134.25,21.79)
  BOTTOM w0.076: v3(84.88,45.34) 85.25,45.7 UD7.E3
DDR_B_D57: length 61.9
  IN1 w0.122: v4(136.13,24.06) 136.13,26.41 134.89,27.65 134.89,29.62 131.45,33.06 111.68,33.06 103.9,40.85 98.19,40.85 97.98,41.06 97.98,41.24 98.08,41.34 98.08,41.52 97.9,41.7 97.72,41.7 97.62,41.6 97.44,41.6 97.26,41.78 97.26,41.95 97.37,42.06 97.37,42.24 97.19,42.42 97.01,42.42 96.9,42.31 96.72,42.31 96.31,42.72 96.31,44.75 93.79,47.27 90.07,47.27 v3(89.63,47.7)
  IN4 w0.076: v1(135.86,23.87) 136.05,24.06 v4(136.13,24.06)
  BOTTOM w0.076: UD7.H8 89.27,48.06 v3(89.63,47.7)
DDR_B_D58: length 62.3
  IN1 w0.076: v3(85.66,47.63) 85.66,45.86 89.27,42.26 89.55,42.26
  IN1 w0.122: v4(134.12,24.23) 134.12,25.3 133.16,26.26 133.16,26.87 132.31,27.72 132.31,28.58 130.36,30.52 110.61,30.52 103.65,37.49 97.96,37.49 93.19,42.26 89.55,42.26
  IN4 w0.076: v4(134.12,24.23) 134.15,24.21 134.53,24.21 134.87,23.87 v1(134.99,23.87)
  BOTTOM w0.076: v3(85.66,47.63) 85.66,47.68 85.27,48.06 UD7.H3
DDR_B_D59: length 65.6
  IN1 w0.076: v3(87.98,47.57) 87.69,47.27 86.19,47.27 85.98,47.07 85.98,45.98 88.52,43.45 89.1,43.45 ; v4(134.18,23.25) 134.68,23.75 134.68,25.53 134.77,25.62 134.77,26.14
  IN1 w0.122: 89.1,43.45 92.97,43.45 98.25,38.17 103.94,38.17 110.9,31.21 130.65,31.21 132.99,28.86 132.99,27.92 134.77,26.14
  IN4 w0.076: v4(134.18,23.25) 134.29,23.37 v1(134.99,23.37)
  BOTTOM w0.076: UD7.H7 88.47,48.08 87.98,47.59 v3(87.98,47.57)
DDR_B_D60: length 62.6
  IN1 w0.122: v3(89.67,46.1) 89.67,46.39 89.82,46.53 93.9,46.53 95.95,44.48 95.95,42.61 98.44,40.11 104.15,40.11 111.54,32.72 131.3,32.72 134.5,29.52 134.5,27.61 135.75,26.37 135.75,22.61 135.42,22.28 v4(135.39,22.28)
  IN4 w0.076: v1(135.86,22.87) 135.86,22.74 135.4,22.28 v4(135.39,22.28)
  BOTTOM w0.076: UD7.F8 v3(89.67,46.1)
DDR_B_D61: length 64
  IN1 w0.076: v3(84.87,46.1) 84.99,46.1 89.24,41.85 89.53,41.85 ; 132.82,26.04 133.65,25.2 133.65,24.03 133.71,23.98 133.71,23.06 133.93,22.84 133.93,22.63 134.25,22.31 v4(134.25,22.28)
  IN1 w0.122: 89.53,41.85 92.63,41.85 97.68,36.8 103.37,36.8 110.33,29.84 130.08,29.84 131.62,28.29 131.62,27.64 132.62,26.64 132.62,26.23 132.82,26.04
  IN4 w0.076: v1(135.86,23.37) 135.34,23.37 135.08,23.11 134.89,23.11 134.73,22.95 134.73,22.84 134.57,22.67 134.57,22.63 134.38,22.44 134.34,22.44 134.25,22.35 v4(134.25,22.28)
  BOTTOM w0.076: UD7.F2 v3(84.87,46.1)
DDR_B_D62: length 64.8
  IN1 w0.076: 89.53,42.53 89.22,42.53 85.83,45.92 85.83,47.13 86.14,47.44 87.13,47.44 v3(87.37,47.68) ; 134.44,25.31 134.44,23.96 v4(134.23,23.75)
  IN1 w0.122: 134.44,25.31 133.41,26.34 133.41,26.97 132.65,27.73 132.65,28.72 130.5,30.87 110.76,30.87 103.79,37.83 98.11,37.83 93.4,42.53 89.53,42.53
  IN4 w0.076: v4(134.23,23.75) 134.36,23.62 v1(134.56,23.62)
  BOTTOM w0.076: v3(87.37,47.68) 87.37,47.6 UD7.F7
DDR_B_D63: length 62.7
  IN1 w0.076: 133.81,25.33 133.81,24.1 133.86,24.04 133.86,23.12 134.22,22.76 v4(134.25,22.76) ; 89.61,42.05 89.25,42.05 85.51,45.8 85.51,46.27 v3(84.87,46.9)
  IN1 w0.122: 89.61,42.05 92.91,42.05 97.82,37.14 103.51,37.14 110.47,30.18 130.22,30.18 131.97,28.43 131.97,27.58 132.93,26.61 132.93,26.21 133.81,25.33
  IN4 w0.076: v4(134.25,22.76) 134.3,22.76 134.56,23.02 v1(134.56,23.12)
  BOTTOM w0.076: UD7.G2 v3(84.87,46.9)
DDR_B_DQS0: length 53.8
  IN4 w0.076: v1(144.6,24.87) 144.6,26.58 145.02,27.01 145.02,27.54 145.65,28.17 145.65,29.23 ; v1(130.08,43.77) 130.27,43.95 130.38,43.95 130.45,43.87 130.45,43.49 130.55,43.39 130.97,43.39
  IN4 w0.137: 145.65,29.23 145.65,34.28 143.5,36.44 143.5,37.71 139.42,41.79 139.42,45.56 139.26,45.72 138.77,45.72 138.37,46.12 138.37,46.95 138.77,47.35 139.26,47.35 139.42,47.51 139.42,48 139.26,48.16 138.77,48.16 138.37,48.56 138.37,49.18 138.14,49.42 135.15,49.42 134.91,49.18 134.91,48.77 135.07,48.6 137.16,48.6 137.56,48.2 137.56,47.38 137.16,46.98 135.07,46.98 134.91,46.81 134.91,46.33 135.07,46.16 136.9,46.16 137.29,45.78 137.29,45.21 136.6,44.52 135.07,44.52 134.82,44.27 134.82,43.35 134.31,42.84 131.7,42.84 131.15,43.39 130.97,43.39
  BOTTOM w0.076: UD5.C7 v1(130.08,43.77)
DDR_B_DQS1: length 54.2
  IN4 w0.076: 118.01,40.21 118.01,40.45 118.48,40.92 118.48,41.33 117.47,42.33 116.86,42.33 116.52,41.99 116.52,40.93 116.4,40.81 116.1,40.81 115.99,40.92 115.99,44.02 116.1,44.14 116.28,44.14 116.56,43.86 116.56,43.21 116.86,42.91 117.31,42.91 117.83,43.43 117.83,43.68 117.9,43.76 118.07,43.76 118.15,43.68 v1(118.15,43.64) ; v1(142.87,24.87) 142.83,24.91 142.83,25.44 142.77,25.5 142.77,27.92 142.2,28.49 142.2,28.93 142.23,28.96 142.23,28.97 142.29,29.02 142.29,29.03
  IN4 w0.137: 142.29,29.03 142.29,30.8 141.59,31.5 141.59,32.63 135.66,38.56 134.67,38.56 134.55,38.69 134.55,39.01 134.19,39.37 133.62,39.37 132.93,38.68 132.14,38.68 132,38.82 132,39.04 131.68,39.37 130.71,39.37 130.11,38.77 129.84,38.77 129.24,39.37 128.26,39.37 127.94,39.05 127.94,38.82 127.8,38.68 126.64,38.68 126.48,38.84 126.48,38.99 126.11,39.37 125.21,39.37 124.86,39.01 124.86,38.84 124.69,38.68 124.33,38.68 123.64,39.37 122.94,39.37 122.25,38.68 120.6,38.68 120.47,38.81 120.47,40.2 120.05,40.62 119.21,40.62 118.82,40.23 118.82,39.48 118.59,39.25 118.31,39.25 118.01,39.56 118.01,40.21
  BOTTOM w0.076: v1(118.15,43.64) 117.81,43.98 UD6.C7
DDR_B_DQS2: length 55.2
  IN1 w0.076: 142.14,29.03 142.14,29.02 142.1,28.98 142.1,28.46 142.39,28.17 142.39,25.06 142.81,24.64 142.81,23.97 142.83,23.95 v4(142.83,23.71)
  IN1 w0.137: 142.14,29.03 142.14,32.14 134.09,40.2 123.69,40.2 123.53,40.36 123.53,43.98 123.13,44.38 122.3,44.38 121.9,43.98 121.9,40.36 121.74,40.2 121.25,40.2 121.09,40.36 121.09,43.98 120.69,44.38 119.86,44.38 119.6,44.11 118.23,44.11 116.46,45.89 116.14,45.89 115.4,46.63 115.4,47.38 115.54,47.52 115.75,47.52 115.89,47.38 v3(115.89,46.93)
  IN4 w0.076: v4(142.83,23.71) 142.83,23.41 v1(142.87,23.37)
  BOTTOM w0.076: UD6.F3 115.33,46.5 115.76,46.93 v3(115.89,46.93)
DDR_B_DQS3: length 50.8
  IN1 w0.076: 144.98,30.07 144.98,29.97 145.03,29.92 145.03,29.3 144.38,28.65 144.05,28.65 143.78,28.38 143.6,28.2 143.6,25.38 144.51,24.46 144.51,23.87 v4(144.5,23.85) ; v3(126.83,46.15) 126.83,46.39 127.04,46.6 127.25,46.6 127.57,46.28 127.57,45.88 127.18,45.48 127.18,44.7 127.5,44.37 127.76,44.37
  IN1 w0.137: 127.76,44.37 130.66,44.37 131.94,43.09 132.77,43.09 133.08,43.39 133.08,44.64 133.34,44.9 133.96,44.9 134.22,44.64 134.22,43.24 134.54,42.92 135.28,42.92 135.68,43.32 135.68,44.79 135.84,44.95 136.12,44.95 136.49,44.57 136.49,43.49 137.9,42.08 137.9,41.85 137.58,41.53 137.58,40.99 138.17,40.41 138.76,40.41 139.05,40.7 139.28,40.7 140.46,39.51 140.46,39.28 139.92,38.74 139.92,38.18 140.5,37.59 141.07,37.59 141.61,38.13 141.84,38.13 142.18,37.79 142.18,37.52 141.64,36.98 141.64,36.45 142.23,35.87 142.79,35.87 143.33,36.41 143.56,36.41 144.85,35.12 144.85,33.6 144.98,33.47 144.98,30.07
  IN4 w0.076: v4(144.5,23.85) 144.6,23.75 v1(144.6,23.37)
  BOTTOM w0.076: UD5.F3 127.49,46.5 127.68,46.31 127.68,46.17 127.58,46.07 126.91,46.07 v3(126.83,46.15)
DDR_B_DQS4: length 52.8
  IN4 w0.076: 137.54,28.02 137.54,27.63 137.31,27.4 137.31,25.31 137.4,25.22 137.4,25.02 137.16,24.78 v1(137.16,24.62) ; 100.42,40.21 100.42,40.22 100.37,40.27 100.37,42.37 101.26,43.26 101.26,43.51 v1(101.46,43.72)
  IN4 w0.137: 137.54,28.02 137.54,31.1 133.88,34.75 117.03,34.75 114.55,37.23 102.32,37.23 100.42,39.14 100.42,40.21
  BOTTOM w0.076: v1(101.46,43.72) UD8.C7
DDR_B_DQS5: length 59.2
  IN4 w0.076: v1(135.43,24.62) 135.27,24.77 135.27,24.93 135.19,25.02 135.19,25.22 135.27,25.31 135.27,26.37 133.67,27.98 133.67,28.02 ; 89.27,40.69 89.26,40.69 89.23,40.72 89.2,40.72 89.17,40.75 88.96,40.75 87.97,41.74 87.97,43.55 88.21,43.79 88.4,43.79 88.47,43.87 v1(88.47,44.1)
  IN4 w0.137: 133.67,28.02 133.67,29.56 132.3,30.93 115.44,30.93 112.96,33.41 100.56,33.41 94.14,39.82 94.14,39.86 93.31,40.69 89.27,40.69
DDR_B_DQS6: length 58.6
  IN1 w0.076: 109.47,40.21 109.29,40.39 109.21,40.39 109.16,40.39 102.82,46.74 99.82,46.74 99.39,46.31 98.21,46.31 98,46.51 98,46.74 98.08,46.81 v3(98.35,46.81) ; 137.75,28.02 137.75,28.01 137.69,27.95 137.69,27.94 137.66,27.91 137.66,27.37 138.02,27.01 138.02,24.43 137.86,24.26 137.86,22.63 137.95,22.54 137.95,22.21 v4(137.63,21.9)
  IN1 w0.137: 109.47,40.21 113.76,35.92 132.63,35.92 137.75,30.81 137.75,28.02
  IN4 w0.076: v4(137.63,21.9) 137.2,22.33 137.2,23.08 v1(137.16,23.12)
  BOTTOM w0.076: UD8.F3 98.03,46.5 v3(98.35,46.81)
DDR_B_DQS7: length 63.9
  IN1 w0.076: 133.65,28.02 133.65,27.9 133.7,27.86 133.7,27.6 135.24,26.05 135.24,24.41 135.08,24.25 135.08,23.82 135.39,23.5 135.39,22.8 135.41,22.79 v4(135.41,22.77)
  IN1 w0.137: 133.65,28.02 133.65,29.1 130.97,31.78 111.2,31.78 104.07,38.92 103.15,38.92 102.73,39.34 102.09,39.34 101.67,38.92 101.03,38.92 100.61,39.34 99.98,39.34 99.47,38.83 98.48,38.83 93.45,43.86 89.32,43.86 87.05,46.13 v3(86.33,46.13)
  IN4 w0.076: v4(135.41,22.77) 135.41,22.79 135.39,22.8 135.39,23.08 v1(135.43,23.12)
  BOTTOM w0.076: UD7.F3 85.59,46.5 85.83,46.26 86.19,46.26 v3(86.33,46.13)
DDR_B_DQS#0: length 53.8
  IN4 w0.076: v1(144.6,24.37) 144.71,24.37 144.79,24.45 144.79,24.71 144.84,24.76 144.84,24.97 144.75,25.06 144.75,26.52 145.17,26.94 145.17,27.48 145.81,28.11 145.81,29.12 145.84,29.15 145.84,29.19 145.87,29.22 145.87,29.23 ; 131.39,43.44 131.26,43.57 130.91,43.57 v1(130.8,43.68)
  IN4 w0.137: 145.87,29.23 145.87,30.04 145.89,30.07 145.89,34.38 143.73,36.54 143.73,37.81 141.19,40.36 141.15,40.36 139.66,41.85 139.66,45.66 139.36,45.96 138.87,45.96 138.61,46.22 138.61,46.85 138.87,47.11 139.36,47.11 139.66,47.41 139.66,48.09 139.36,48.4 138.87,48.4 138.61,48.66 138.61,49.28 138.24,49.65 135.05,49.65 134.7,49.3 134.7,48.64 134.97,48.36 137.06,48.36 137.32,48.1 137.32,47.48 137.06,47.22 134.97,47.22 134.7,46.94 134.7,46.2 134.97,45.93 136.81,45.93 137.05,45.68 137.05,45.31 136.51,44.76 134.97,44.76 134.61,44.4 134.61,43.44 134.22,43.05 131.79,43.05 131.39,43.44
  BOTTOM w0.076: UD5.B7 v1(130.8,43.68)
DDR_B_DQS#1: length 54.4
  IN4 w0.076: v1(117.51,43.6) 117.6,43.51 117.6,43.41 117.24,43.06 116.93,43.06 116.71,43.27 116.71,43.92 116.34,44.29 116.04,44.29 115.83,44.09 115.83,40.86 116.04,40.66 116.47,40.66 116.67,40.86 116.67,41.93 116.93,42.18 117.41,42.18 118.32,41.27 118.32,40.98 117.85,40.51 117.85,40.32 117.82,40.29 117.82,40.28 117.77,40.22 117.77,40.21 ; 142.05,29.03 142.05,28.42 142.62,27.85 142.62,25.43 142.67,25.38 142.67,25.02 142.62,24.96 142.62,24.77 142.67,24.72 142.67,24.56 v1(142.87,24.37)
  IN4 w0.137: 142.05,29.03 142.05,30.7 141.35,31.4 141.35,32.53 135.56,38.32 134.57,38.32 134.31,38.59 134.31,38.91 134.09,39.13 133.72,39.13 133.03,38.44 132.04,38.44 131.77,38.72 131.77,38.94 131.58,39.13 130.81,39.13 130.21,38.53 129.74,38.53 129.14,39.13 128.36,39.13 128.18,38.95 128.18,38.72 127.9,38.44 126.54,38.44 126.24,38.74 126.24,38.89 126.01,39.13 125.31,39.13 125.09,38.91 125.09,38.74 124.79,38.44 124.23,38.44 123.54,39.13 123.04,39.13 122.35,38.44 120.51,38.44 120.23,38.71 120.23,40.1 119.95,40.38 119.31,40.38 119.06,40.13 119.06,39.38 118.69,39.01 118.21,39.01 117.77,39.46 117.77,40.21
  BOTTOM w0.076: UD6.B7 117.83,43.32 117.83,43.58 117.71,43.71 117.62,43.71 v1(117.51,43.6)
DDR_B_DQS#2: length 55.1
  IN1 w0.076: v4(142.81,22.1) 142.81,23.27 142.5,23.58 142.5,23.84 142.65,23.99 142.65,24.58 142.24,25 142.24,28.11 141.95,28.4 141.95,28.97 141.91,29.01 141.91,29.03
  IN1 w0.137: v3(114.94,46.89) 115.19,46.63 115.19,46.54 116.05,45.67 116.37,45.67 118.14,43.9 119.69,43.9 119.95,44.17 120.6,44.17 120.87,43.89 120.87,40.23 121.15,39.96 121.84,39.96 122.11,40.23 122.11,43.89 122.39,44.17 123.04,44.17 123.31,43.89 123.31,40.27 123.63,39.96 133.99,39.96 141.91,32.04 141.91,29.03
  IN4 w0.076: v1(142.87,22.87) 142.87,22.18 142.78,22.1 v4(142.81,22.1)
  BOTTOM w0.076: v3(114.94,46.89) 114.95,46.89 114.61,47.22 UD6.G3
DDR_B_DQS#3: length 50.8
  IN1 w0.076: v3(127.61,46.92) 127.61,46.46 127.72,46.35 127.72,45.81 127.33,45.42 127.33,44.76 127.54,44.55 127.72,44.55 127.75,44.58 127.76,44.58 ; 145.22,30.07 145.22,30.05 145.18,30 145.18,29.24 144.44,28.5 144.12,28.5 143.85,28.23 143.75,28.13 143.75,25.44 144.77,24.42 144.77,24.03 144.81,23.99 144.81,23.72 144.77,23.68 144.77,23.6 144.54,23.38 v4(144.54,22.46)
  IN1 w0.137: 127.76,44.58 130.75,44.58 132.03,43.3 132.69,43.3 132.86,43.48 132.86,44.73 133.25,45.12 134.05,45.12 134.44,44.73 134.44,43.32 134.6,43.16 135.18,43.16 135.44,43.42 135.44,44.89 135.75,45.19 136.22,45.19 136.73,44.67 136.73,43.58 138.13,42.18 138.13,41.75 137.82,41.44 137.82,41.09 138.27,40.65 138.66,40.65 138.95,40.93 139.37,40.93 140.7,39.61 140.7,39.19 140.16,38.65 140.16,38.28 140.6,37.83 140.97,37.83 141.51,38.37 141.94,38.37 142.42,37.89 142.42,37.42 141.88,36.88 141.88,36.55 142.33,36.11 142.69,36.11 143.23,36.65 143.66,36.65 145.09,35.22 145.09,33.7 145.22,33.57 145.22,30.07
  IN4 w0.076: v1(144.6,22.87) 144.6,22.52 v4(144.54,22.46)
  BOTTOM w0.076: UD5.G3 127.23,47.3 v3(127.61,46.92)
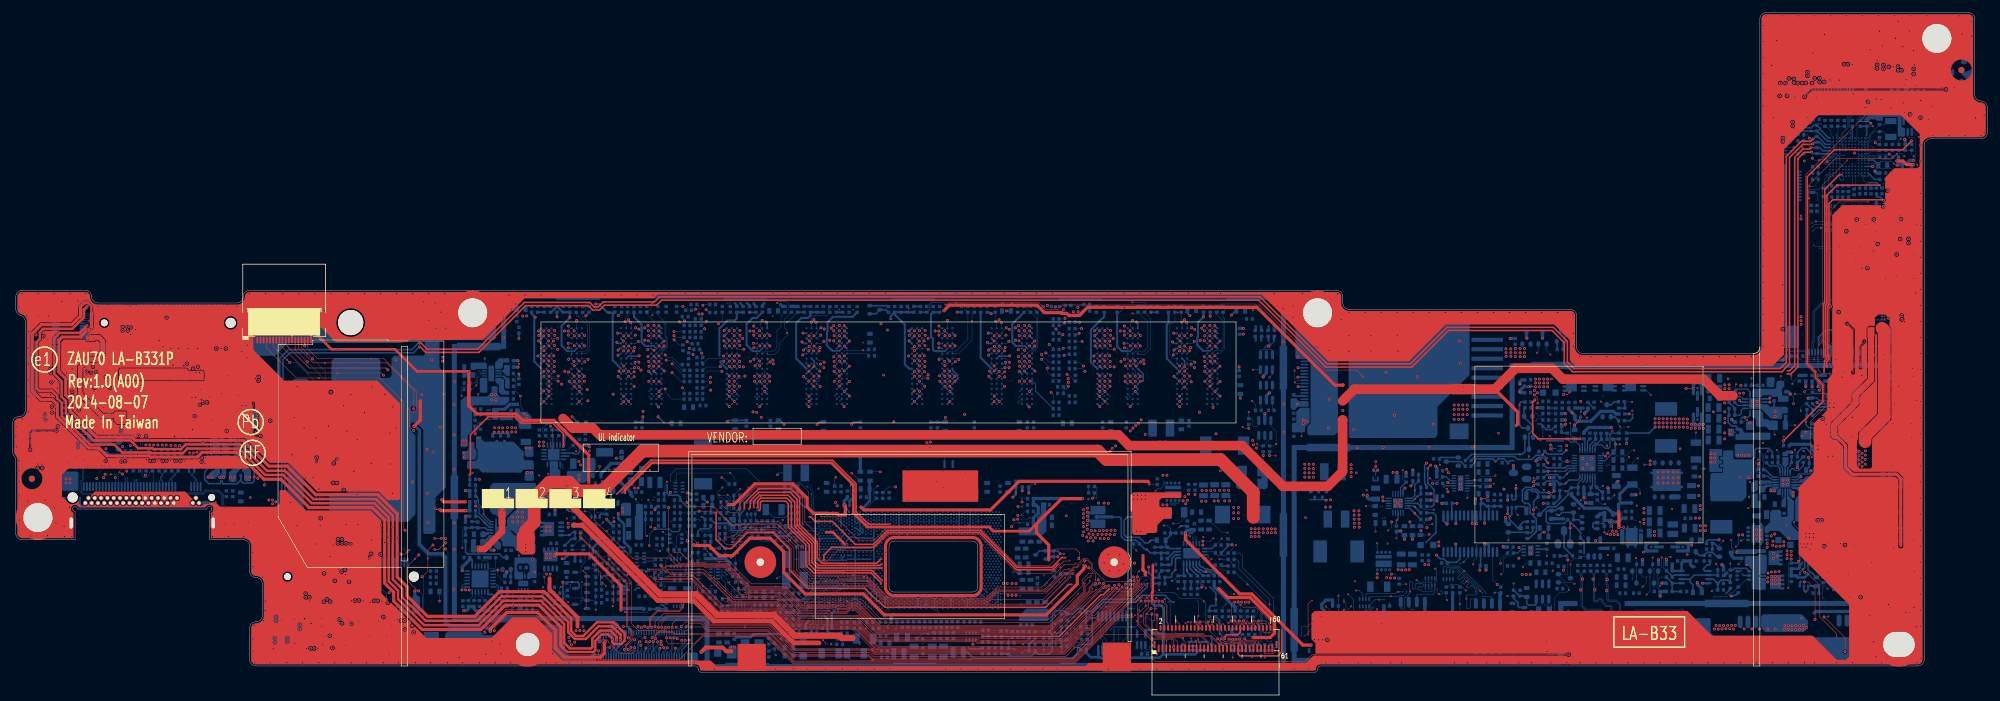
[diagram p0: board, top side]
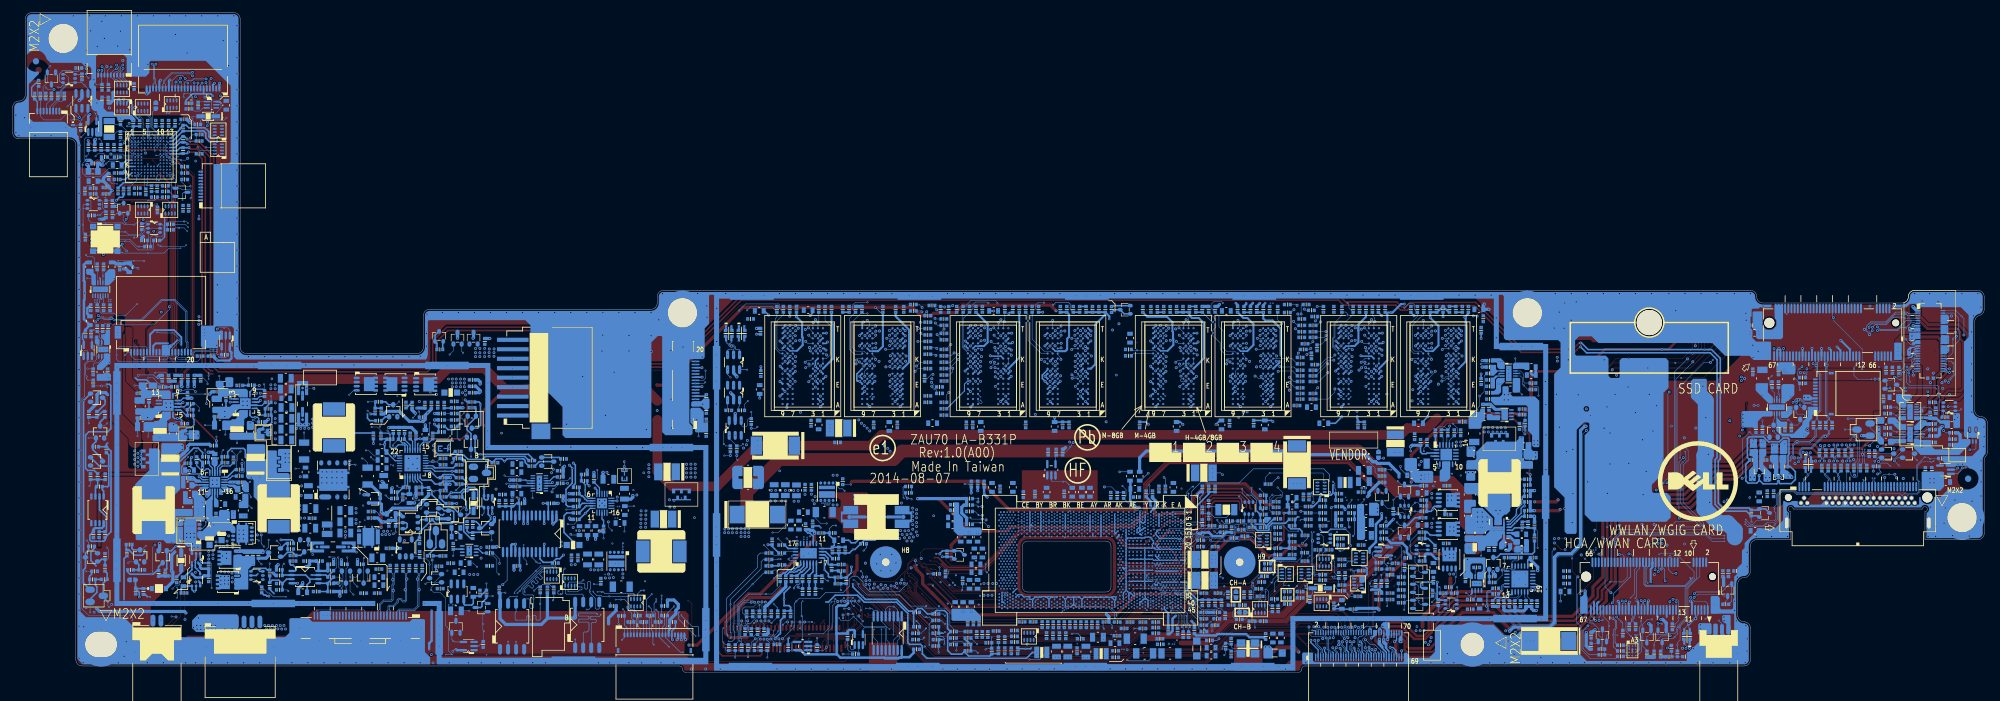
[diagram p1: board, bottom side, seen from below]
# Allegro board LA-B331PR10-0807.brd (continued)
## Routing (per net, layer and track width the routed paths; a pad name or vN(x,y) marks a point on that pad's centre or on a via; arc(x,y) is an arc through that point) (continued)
DDR_B_DQS#4: length 52.7
  IN4 w0.076: v1(100.75,43.64) 100.75,43.79 100.87,43.92 101.04,43.92 101.1,43.86 101.1,43.32 100.21,42.44 100.21,40.26 100.18,40.22 100.18,40.21 ; 137.3,28.02 137.3,28.01 137.35,27.95 137.35,27.94 137.38,27.91 137.38,27.69 137.16,27.46 137.16,25.12 v1(137.16,25.12)
  IN4 w0.137: 137.3,28.02 137.3,31 133.78,34.52 116.93,34.52 114.45,37 102.22,37 100.18,39.04 100.18,40.21
  BOTTOM w0.076: v1(100.75,43.64) UD8.B7
DDR_B_DQS#5: length 59.2
  IN4 w0.076: 89.27,40.9 89.02,40.9 88.12,41.8 88.12,43.49 88.28,43.64 88.85,43.64 88.92,43.57 88.92,43.38 88.85,43.3 v1(88.47,43.3) ; v1(135.43,25.12) 135.43,25.24 135.43,25.24 135.43,26.45 133.91,27.97 133.91,28.02
  IN4 w0.137: 133.91,28.02 133.88,28.05 133.88,29.68 132.39,31.17 115.54,31.17 113.06,33.64 100.66,33.64 93.4,40.9 89.27,40.9
DDR_B_DQS#6: length 58.5
  IN1 w0.076: 109.13,40.21 102.75,46.59 99.88,46.59 99.45,46.16 98.14,46.16 97.85,46.45 97.85,46.8 98.35,47.3 v3(98.35,47.6) ; 137.51,28.02 137.51,27.3 137.87,26.94 137.87,24.49 137.7,24.33 137.7,22.88 137.63,22.8 v4(137.63,22.4)
  IN1 w0.137: 109.13,40.21 113.66,35.69 132.53,35.69 137.51,30.71 137.51,28.02
  IN4 w0.076: v1(137.16,23.62) 137.16,23.46 137.41,23.21 137.41,23.03 137.35,22.97 137.35,22.68 137.63,22.41 v4(137.63,22.4)
  BOTTOM w0.076: v3(98.35,47.6) 98.05,47.3 UD8.G3
DDR_B_DQS#7: length 64.1
  IN1 w0.076: v4(135.41,24.01) 135.41,24.03 135.39,24.05 135.39,26.12 133.85,27.66 133.85,27.97 133.89,28.02
  IN1 w0.137: v3(86.33,46.93) 86.27,46.87 86.27,46.62 86.39,46.5 86.54,46.5 86.7,46.34 87.14,46.34 89.41,44.07 93.57,44.07 98.58,39.07 99.37,39.07 99.88,39.58 100.71,39.58 101.13,39.16 101.57,39.16 101.99,39.58 102.83,39.58 103.25,39.15 104.17,39.15 111.3,32.02 131.07,32.02 133.89,29.2 133.89,28.02
  IN4 w0.076: v1(135.43,23.62) 135.43,23.99 v4(135.41,24.01)
  BOTTOM w0.076: UD7.G3 85.27,46.92 85.41,46.79 85.71,46.79 85.95,46.55 86.26,46.55 86.33,46.62 v3(86.33,46.93)
DDR_B_MA0: length 133
  IN3 w0.076: v3(115.07,51.76) 117.38,51.76 117.8,52.18 120.91,52.18 121.1,52.37 v4(121.74,52.37) 123.66,52.37 124.07,52.77 124.42,52.77 124.46,52.81 126.62,52.81 127.01,52.42 v3(128.35,52.42) ; v4(139.1,23.73) 139.1,24.2 138.4,24.89 137.73,24.89 134.95,27.68 134.83,27.68 134.68,27.83 134.64,27.87 134.64,27.88 ; v3(99.01,52.42) 98.77,52.67 97.47,52.67 97.32,52.81 96.22,52.81 96.17,52.76 94.66,52.76 94.26,52.37 v4(92.4,52.37) 92.34,52.3 91.46,52.3 91.33,52.18 88.47,52.18 88.06,51.77 85.75,51.77 v3(85.74,51.76)
  IN3 w0.165: 134.64,27.88 134.64,28.45 131.34,31.75 119.43,31.75 119.3,31.62 119.3,31.45 119.13,31.29 118.8,31.29 118.64,31.45 118.64,31.62 118.51,31.75 118.1,31.75 117.98,31.62 117.98,31.39 117.85,31.26 117.42,31.26 117.29,31.39 117.29,33.15 117.13,33.32 116.64,33.32 116.47,33.15 116.47,31.97 116.35,31.84 115.94,31.84 115.81,31.97 115.81,33.15 115.65,33.32 112.47,33.32 104.68,41.11 104.68,46.27 105.12,46.7 105.12,48.44 104.79,48.77 104.79,49 105.01,49.22 105.01,49.64 104.81,49.84 104.56,49.84 104.46,49.94 104.46,50.27 104.62,50.43 105,50.43 105.09,50.52 105.09,51 105,51.09 104.62,51.09 104.46,51.26 104.46,51.59 104.62,51.75 105,51.75 105.12,51.87 105.12,53.46 105.07,53.51 104.79,53.51 104.66,53.38 v3(104.66,53.33)
  IN4 w0.076: v4(92.4,52.37) 92.4,52.28 92.33,52.2 90.85,52.2 90.78,52.13 90.78,51.91 90.85,51.83 92.42,51.83 93.01,52.43 94.26,52.43 94.87,53.04 96.48,53.04 96.55,52.97 96.86,52.97 96.9,52.93 97.67,52.93 97.93,53.19 98.14,53.19 98.28,53.06 98.69,53.06 98.83,53.21 100.29,53.21 100.55,52.94 102.42,52.94 102.63,53.14 102.63,53.57 102.87,53.81 103.58,53.81 103.65,53.74 103.65,53.41 103.73,53.33 103.88,53.33 103.96,53.41 103.96,53.74 104.03,53.81 104.19,53.81 104.26,53.74 104.26,53.41 104.34,53.33 v3(104.66,53.33) 104.94,53.33 105.42,53.81 110.79,53.81 111.47,54.49 115.3,54.49 117.03,52.76 119.73,52.76 120.27,52.23 120.69,52.23 120.83,52.37 v4(121.74,52.37) ; v1(139.4,23.37) 139.4,23.4 139.1,23.7 v4(139.1,23.73)
  BOTTOM w0.076: v3(99.01,52.42) 98.69,52.1 UD8.N3 ; v3(104.66,53.33) 104.94,53.05 RD34.1 ; UD5.N3 128.03,52.1 v3(128.35,52.42) ; UD6.N3 114.95,51.76 v3(115.07,51.76) ; UD7.N3 85.62,51.76 v3(85.74,51.76)
DDR_B_MA1: length 127.6
  IN3 w0.076: v4(138.95,25.99) 138.78,26.15 138.76,26.15 138.58,26.34 138.58,26.36 137.69,27.25 ; v3(130,53.31) 129.74,53.57 129.67,53.57 129.58,53.66 128.14,53.66 127.99,53.81 127.41,53.81 126.84,54.39 125.52,54.39 125.16,54.75 124.55,54.75 124.44,54.87 124.21,54.87 124.1,54.75 v4(123.69,54.75) 121.22,54.75 120.49,54.03 120.46,54.03 120.41,53.99 118.55,53.99 118.31,53.75 117.62,53.75 v3(117.28,53.41) ; v3(100.66,53.31) 100.57,53.22 99.21,53.22 98.69,53.75 98.09,53.75 97.24,54.59 94.83,54.59 94.66,54.75 v4(94.36,54.75) 91.88,54.75 91.15,54.02 89.27,54.02 88.91,53.66 88.2,53.66 v3(87.95,53.41)
  IN3 w0.165: 137.69,27.25 137.34,27.25 136.57,28.01 136.57,29.26 132.37,33.47 131.4,33.47 131.27,33.59 131.27,34 131.15,34.13 130.74,34.13 130.61,34 130.61,33.59 130.49,33.47 130.03,33.47 129.86,33.64 129.86,35.84 129.69,36.01 125.78,36.01 124.84,35.08 113.14,35.08 106.82,41.4 106.82,49.14 106.54,49.42 106.54,51.58 107.22,52.27 107.22,54.04 106.34,54.93 v3(106.34,55.67)
  IN4 w0.076: v4(94.36,54.75) 94.57,54.97 94.77,54.97 94.87,55.07 95.24,55.07 95.31,55.15 95.31,55.68 95.39,55.76 95.54,55.76 95.62,55.68 95.62,55.15 95.69,55.07 95.85,55.07 95.92,55.15 95.92,55.68 96,55.76 96.15,55.76 96.23,55.68 96.23,55.15 96.3,55.07 96.51,55.07 96.58,55.15 96.58,56.16 96.66,56.24 97.82,56.24 97.89,56.16 97.89,55.85 97.97,55.77 98.12,55.77 98.2,55.85 98.2,56.16 98.28,56.24 98.43,56.24 98.5,56.16 98.5,55.85 98.58,55.77 98.73,55.77 98.81,55.85 98.81,56.16 98.88,56.24 99.04,56.24 99.11,56.16 99.11,55.85 99.19,55.77 99.34,55.77 99.42,55.85 99.42,56.16 99.49,56.24 99.72,56.24 99.8,56.16 99.8,56.15 99.87,56.08 100.03,56.08 100.1,56.15 100.1,56.16 100.18,56.24 105.76,56.24 v3(106.34,55.67) 106.67,55.67 107.25,56.25 119.9,56.25 121.02,55.13 123.32,55.13 v4(123.69,54.75) ; v1(138.97,24.62) 138.97,24.62 138.61,24.98 138.61,25.64 v4(138.95,25.99)
  BOTTOM w0.076: UD5.P7 130.42,53.24 130.29,53.37 130.06,53.37 v3(130,53.31) ; UD7.P7 88.25,52.9 87.95,53.21 v3(87.95,53.41) ; UD8.P7 101.08,53.24 100.96,53.37 100.72,53.37 v3(100.66,53.31) ; v3(106.34,55.67) 105.98,56.02 RD48.1 ; UD6.P7 117.62,52.9 117.28,53.24 v3(117.28,53.41)
DDR_B_MA2: length 129.5
  IN3 w0.076: 135.44,28.02 138.26,25.2 138.53,25.2 138.86,24.87 139.2,24.87 139.85,24.22 139.85,24.09 139.88,24.06 139.88,23.21 v4(139.94,23.15) ; v3(86.25,52.9) 86.31,52.96 89.12,52.96 89.31,53.15 89.31,53.79 89.38,53.87 91.21,53.87 91.71,54.37 v4(92.26,54.37) 92.52,54.37 92.62,54.27 92.82,54.27 92.92,54.37 93.15,54.37 93.3,54.22 93.45,54.22 93.6,54.37 93.76,54.37 93.91,54.22 94.06,54.22 94.21,54.37 97.22,54.37 98.19,53.4 v3(98.54,53.4) ; v3(127.88,53.4) 127.62,53.66 127.35,53.66 126.78,54.23 125.46,54.23 125.26,54.44 123.14,54.44 123.03,54.34 122.79,54.34 122.69,54.44 122.53,54.44 122.39,54.3 122.22,54.3 122.08,54.44 121.67,54.44 v4(121.6,54.37) 121.05,54.37 120.51,53.83 118.99,53.83 118.57,53.41 118.57,53.16 118.37,52.96 118.08,52.96 117.98,53.07 115.69,53.07 v3(115.52,52.9)
  IN3 w0.165: v3(105.52,55.52) 105.84,55.2 105.84,46.28 105.42,45.86 105.42,41.34 112.71,34.05 118.13,34.05 118.26,33.92 118.26,33.57 118.39,33.44 118.79,33.44 118.92,33.57 118.92,33.92 119.05,34.05 119.45,34.05 119.58,33.92 119.58,32.56 119.71,32.44 120.11,32.44 120.24,32.56 120.24,33.92 120.37,34.05 120.77,34.05 120.9,33.92 120.9,32.56 121.03,32.44 131.62,32.44 135.39,28.67 135.39,28.07 135.44,28.02
  IN4 w0.076: v4(121.6,54.37) 121.57,54.37 119.84,56.1 107.31,56.1 106.54,55.33 105.98,55.33 105.79,55.52 v3(105.52,55.52) 104.95,56.09 102.76,56.09 102.68,56.01 102.68,55.97 102.61,55.9 102.46,55.9 102.38,55.97 102.38,56.01 102.3,56.09 102.15,56.09 102.07,56.01 102.07,55.68 102,55.61 101.85,55.61 101.77,55.68 101.77,56.01 101.69,56.09 101.54,56.09 101.47,56.01 101.47,55.68 101.39,55.61 101.24,55.61 101.16,55.68 101.16,56.01 101.08,56.09 100.93,56.09 100.86,56.01 100.86,55.68 100.78,55.61 100.63,55.61 100.55,55.68 100.55,56.01 100.47,56.09 100.26,56.09 99.78,55.6 98.51,55.6 97.83,54.92 97.39,54.92 97.31,55 97.31,55.14 97.23,55.21 97.08,55.21 97.01,55.14 97.01,55 96.93,54.92 94.97,54.92 94.42,54.37 v4(92.26,54.37) ; v4(139.94,23.15) 139.95,23.15 139.95,23.16 139.94,23.16 139.85,23.25 139.85,23.6 v1(139.83,23.62)
  BOTTOM w0.076: v3(127.88,53.4) 127.38,52.9 UD5.P3 ; RD44.1 106.08,54.96 v3(105.52,55.52) ; UD6.P3 114.68,52.82 115.45,52.82 v3(115.52,52.9) ; v3(98.54,53.4) 98.04,52.9 UD8.P3 ; UD7.P3 v3(86.25,52.9)
DDR_B_MA3: length 129.5
  IN3 w0.076: v3(126.05,51.61) 125.86,51.8 125.31,51.8 125.13,51.62 124.66,51.62 124.5,51.45 124.25,51.45 124.17,51.38 124.17,51.33 124.09,51.25 123.94,51.25 123.86,51.33 123.86,51.57 123.79,51.64 123.64,51.64 123.56,51.57 123.56,51.33 123.48,51.25 123.33,51.25 123.25,51.33 123.25,51.58 123.18,51.66 123.03,51.66 122.95,51.58 122.95,51.33 122.87,51.25 122.72,51.25 122.64,51.33 122.64,51.38 122.57,51.45 122.42,51.45 122.34,51.38 122.34,51.33 122.26,51.25 122.11,51.25 122.04,51.33 122.04,51.38 121.96,51.45 121.81,51.45 121.73,51.38 121.73,51.33 121.65,51.25 121.5,51.25 121.43,51.33 121.43,51.38 121.35,51.45 120.86,51.45 v4(120.7,51.29) 120.54,51.29 119.99,50.74 116.96,50.74 116.79,50.91 116.79,51.31 116.58,51.53 115.33,51.53 115.21,51.41 114.37,51.41 114.21,51.57 v3(114.21,51.71) ; v3(84.87,51.71) 84.87,51.57 85.03,51.41 85.88,51.41 85.99,51.53 87.24,51.53 87.46,51.31 87.46,50.91 87.62,50.74 90.66,50.74 91.21,51.29 v4(91.36,51.29) 91.53,51.45 92.01,51.45 92.09,51.38 92.09,51.33 92.17,51.25 92.32,51.25 92.4,51.33 92.4,51.38 92.47,51.45 92.62,51.45 92.7,51.38 92.7,51.33 92.78,51.25 92.93,51.25 93.01,51.33 93.01,51.38 93.08,51.45 93.23,51.45 93.31,51.38 93.31,51.33 93.39,51.25 93.54,51.25 93.61,51.33 93.61,51.58 93.69,51.66 93.84,51.66 93.92,51.58 93.92,51.33 94,51.25 94.15,51.25 94.22,51.33 94.22,51.57 94.3,51.64 94.45,51.64 94.53,51.57 94.53,51.33 94.61,51.25 94.76,51.25 94.83,51.33 94.83,51.38 94.91,51.45 95.16,51.45 95.33,51.62 96.14,51.62 96.32,51.8 96.55,51.8 v3(96.73,51.62) ; v4(138.89,26.47) 138.89,26.62 138.45,27.06 138.15,27.06 137.64,27.58 137.49,27.58 137.05,28.02
  IN3 w0.165: v3(107.07,51.31) 107.06,51.31 106.89,51.15 106.89,49.57 107.2,49.27 107.2,41.5 113.28,35.42 124.7,35.42 125.63,36.35 130.27,36.35 130.39,36.23 130.39,34.97 130.52,34.84 130.93,34.84 131.05,34.97 131.05,36.23 131.18,36.35 131.59,36.35 131.71,36.23 131.71,33.94 131.84,33.81 132.25,33.81 132.37,33.94 132.37,36.23 132.5,36.35 132.91,36.35 133.04,36.23 133.04,33.29 136.92,29.41 136.92,28.15 137.05,28.02
  IN4 w0.076: v4(138.89,26.47) 138.97,26.47 138.44,25.94 138.44,24.65 v1(138.97,24.12) ; v4(120.7,51.29) 118.17,51.29 117.71,51.74 117.13,51.74 116.77,52.1 116.45,52.1 116.37,52.18 116.37,52.19 116.29,52.27 116.14,52.27 116.07,52.19 116.07,52.18 115.99,52.1 112.29,52.1 112.22,52.18 112.22,52.6 112.14,52.67 109.63,52.67 109.56,52.6 109.56,52.18 109.48,52.1 109.33,52.1 109.25,52.18 109.25,52.57 109.18,52.65 109.02,52.65 108.95,52.57 108.95,52.18 108.87,52.1 108.72,52.1 108.64,52.18 108.64,52.57 108.57,52.65 108.42,52.65 108.34,52.57 108.34,52.18 108.26,52.1 108.07,52.1 107.28,51.31 v3(107.07,51.31) 102.2,51.31 101.72,51.78 98.27,51.78 97.91,51.42 97.91,50.91 97.57,50.57 96.53,50.57 96.24,50.86 96.24,51.09 95.88,51.45 91.53,51.45 v4(91.36,51.29)
  BOTTOM w0.076: UD7.N2 84.48,52.1 v3(84.87,51.71) ; UD8.N2 97.08,51.97 v3(96.73,51.62) ; v3(126.05,51.61) 126.42,51.97 UD5.N2 ; v3(107.07,51.31) 107.23,51.15 RD54.1 ; UD6.N2 113.81,52.1 v3(114.21,51.71)
DDR_B_MA4: length 126.9
  IN3 w0.076: v3(101.48,53.31) 101.14,52.97 98.4,52.97 97.29,54.08 95.48,54.08 95.41,54.02 v4(94.89,54.02) 94.65,54.02 94.35,53.71 94.22,53.71 94.14,53.79 94.14,53.9 94.07,53.98 93.91,53.98 93.84,53.9 93.84,53.79 93.76,53.71 93.61,53.71 93.53,53.79 93.53,53.9 93.46,53.98 93.3,53.98 93.23,53.9 93.23,53.79 93.15,53.71 93,53.71 92.92,53.79 92.92,53.9 92.85,53.98 92.7,53.98 92.62,53.9 92.62,53.79 92.54,53.71 92.39,53.71 92.31,53.79 92.31,53.9 92.24,53.98 92.09,53.98 92.01,53.9 92.01,53.79 91.93,53.71 91.78,53.71 91.7,53.79 91.7,53.84 91.63,53.92 91.48,53.92 91.4,53.84 91.4,53.79 91.32,53.71 90.27,53.71 89.9,53.34 v3(89.65,53.34) ; v3(118.98,53.34) 119.27,53.62 119.63,53.62 119.69,53.68 120.63,53.68 120.73,53.79 120.73,53.84 120.81,53.92 120.96,53.92 121.04,53.84 121.04,53.79 121.12,53.71 121.27,53.71 121.34,53.79 121.34,53.9 121.42,53.98 121.57,53.98 121.65,53.9 121.65,53.79 121.73,53.71 121.88,53.71 121.95,53.79 121.95,53.9 122.03,53.98 122.18,53.98 122.26,53.9 122.26,53.79 122.33,53.71 122.49,53.71 122.56,53.79 122.56,53.9 122.64,53.98 122.79,53.98 122.87,53.9 122.87,53.79 122.94,53.71 123.1,53.71 123.17,53.79 123.17,53.95 123.25,54.03 123.4,54.03 123.48,53.95 123.48,53.79 123.55,53.71 123.68,53.71 123.99,54.02 v4(124.23,54.02) 124.75,54.02 124.81,54.08 126.63,54.08 127.66,53.05 128.06,53.05 128.13,53.13 129.53,53.13 129.7,52.96 130.47,52.96 v3(130.82,53.31)
  IN3 w0.165: v3(109.79,55.58) 110.17,55.2 110.17,48.14 109.83,47.8 109.83,42.27 114.28,37.82 123.7,37.82 123.83,37.95 123.83,39.41 123.96,39.53 124.45,39.53 124.62,39.37 124.62,39.04 124.75,38.92 125.15,38.92 125.28,39.04 125.28,39.37 125.45,39.53 126.66,39.53 126.83,39.36 126.83,39.03 127.09,38.78 127.6,38.78 127.73,38.91 127.73,39.41 127.86,39.53 132.24,39.53 132.36,39.41 132.36,38.88 132.49,38.75 133.06,38.75 133.19,38.88 133.19,39.41 133.32,39.53 134.81,39.53 138.69,35.65 138.69,31.49 139.32,30.87 139.32,29.15 139.74,28.72 v4(139.77,28.72)
  IN4 w0.076: v4(94.89,54.02) 95.61,54.73 97.86,54.73 98.57,55.45 105.1,55.45 105.37,55.17 106.6,55.17 107,55.58 v3(109.79,55.58) 110.29,55.58 110.36,55.65 110.36,55.78 110.44,55.86 110.59,55.86 110.67,55.78 110.67,55.65 110.74,55.58 110.9,55.58 110.97,55.65 110.97,55.73 111.05,55.81 111.2,55.81 111.28,55.73 111.28,55.65 111.35,55.58 117.86,55.58 118.61,54.83 120.69,54.83 121.47,54.05 124.19,54.05 v4(124.23,54.02) ; v4(139.77,28.72) 139.44,28.39 139.44,28.16 139.29,28.01 139.29,26.8 139.21,26.72 139.21,26.2 139.29,26.13 139.29,25.09 139.14,24.95 139.14,24.78 139.4,24.53 v1(139.4,24.37)
  BOTTOM w0.076: v3(89.65,53.34) 89.27,52.96 UD7.P8 ; UD5.P8 131.22,52.91 v3(130.82,53.31) ; v3(101.48,53.31) 101.88,52.91 UD8.P8 ; v3(118.98,53.34) 118.61,52.96 UD6.P8 ; v3(109.79,55.58) 109.17,54.96 RD42.1
DDR_B_MA5: length 125
  IN3 w0.076: v3(126.03,53.31) 126.03,53.44 125.82,53.65 125.71,53.65 125.28,53.23 124.44,53.23 124.29,53.08 121.59,53.08 121.51,53 121.51,52.91 121.44,52.84 121.28,52.84 121.21,52.91 121.21,53 121.13,53.08 120.87,53.08 120.79,53 120.79,52.79 120.7,52.7 v4(120.47,52.7) 119.96,52.7 119.9,52.63 116.02,52.63 115.51,52.13 114.82,52.13 114.46,52.48 v3(114.24,52.48) ; v3(96.69,53.31) 96.28,53.31 96.04,53.07 93.39,53.07 93.31,52.99 93.31,52.98 93.23,52.9 93.08,52.9 93.01,52.98 93.01,52.99 92.93,53.07 92.78,53.07 92.7,52.99 92.7,52.98 92.62,52.9 92.47,52.9 92.4,52.98 92.4,52.99 92.32,53.07 92.17,53.07 92.09,52.99 92.09,52.72 92.01,52.64 91.86,52.64 91.79,52.72 91.79,52.86 91.68,52.96 91.45,52.96 v4(91.13,52.65) 90.97,52.48 87.8,52.48 87.32,52 85.98,52 85.88,52.1 85.59,52.1 85.49,52 85.29,52 v3(84.82,52.47)
  IN3 w0.165: v4(139.76,28.21) 139.41,28.57 139.41,28.57 138.97,29 138.97,30.65 138.35,31.27 138.35,35.51 135.45,38.41 126.39,38.41 126.23,38.57 126.23,38.6 126.1,38.73 125.7,38.73 125.57,38.6 125.57,38.57 125.4,38.41 124.78,38.41 123.85,37.48 114.14,37.48 109.39,42.22 109.39,48.01 109.83,48.44 109.83,53.75 109.69,53.89 109.69,54.25 v3(109.51,54.42)
  IN4 w0.076: v4(139.76,28.21) 139.44,27.89 139.44,26.74 139.42,26.71 139.36,26.65 139.36,26.26 139.44,26.19 139.44,24.9 v1(139.4,24.87) ; v4(120.47,52.7) 120.47,52.94 120.54,53.02 120.76,53.02 120.84,53.09 120.84,53.25 120.76,53.32 120.54,53.32 120.38,53.48 120.38,53.6 120.88,54.1 120.88,54.21 120.77,54.31 120.66,54.31 120.16,53.81 120.03,53.81 119.94,53.9 119.94,54.02 120.23,54.31 120.23,54.41 120.12,54.52 120.01,54.52 119.63,54.15 119.54,54.15 119.2,54.49 116.55,54.49 116.47,54.56 116.47,54.89 116.38,54.98 116.25,54.98 116.16,54.89 116.16,54.56 116.09,54.49 115.94,54.49 115.86,54.56 115.86,54.91 115.82,54.95 111.91,54.95 111.82,54.86 111.45,54.86 111.26,55.05 111.12,55.05 111.05,54.97 111.05,54.51 110.97,54.44 110.82,54.44 110.74,54.51 110.74,54.97 110.67,55.05 110.52,55.05 110.44,54.97 110.44,54.49 110.36,54.41 110.21,54.41 110.13,54.49 110.13,54.97 110.06,55.05 109.87,55.05 109.79,54.97 109.79,54.5 109.71,54.42 v3(109.51,54.42) 109.04,54.42 108.9,54.56 100.52,54.56 99.92,53.97 96.48,53.97 95.86,53.35 92.21,53.35 91.95,53.08 91.56,53.08 v4(91.13,52.65)
  BOTTOM w0.076: v3(114.24,52.48) 113.82,52.9 UD6.P2 ; RD60.1 109.43,54.42 v3(109.51,54.42) ; v3(84.82,52.47) 84.47,52.82 UD7.P2 ; UD8.P2 97.08,52.92 v3(96.69,53.31) ; UD5.P2 126.42,52.92 v3(126.03,53.31)
DDR_B_MA6: length 129.1
  IN3 w0.076: 141.16,25.35 141.97,24.54 141.97,23.93 141.87,23.83 v4(141.86,23.83) ; v3(130.81,54.1) 130.44,53.73 129.74,53.73 129.65,53.81 128.21,53.81 128.05,53.97 127.48,53.97 126.91,54.54 125.59,54.54 125.14,54.98 124.7,54.98 124.4,55.28 v4(123.97,55.28) 123.59,55.28 123.51,55.21 123.51,55.08 123.44,55.01 123.29,55.01 123.21,55.08 123.21,55.21 123.13,55.28 122.98,55.28 122.9,55.21 122.9,55.08 122.83,55.01 122.68,55.01 122.6,55.08 122.6,55.21 122.52,55.28 122.37,55.28 122.29,55.21 122.29,55.03 122.22,54.96 122.07,54.96 121.99,55.03 121.99,55.21 121.91,55.28 121.76,55.28 121.69,55.21 121.69,54.98 121.61,54.91 121.12,54.91 120.35,54.14 118.21,54.14 v3(118.18,54.11) ; v3(88.85,54.11) 88.96,54.22 91.1,54.22 91.78,54.91 92.28,54.91 92.35,54.98 92.35,55.21 92.43,55.28 92.58,55.28 92.65,55.21 92.65,55.03 92.73,54.96 92.88,54.96 92.96,55.03 92.96,55.21 93.04,55.28 93.19,55.28 93.26,55.21 93.26,55.08 93.34,55.01 93.49,55.01 93.57,55.08 93.57,55.21 93.65,55.28 93.8,55.28 93.87,55.21 93.87,55.08 93.95,55.01 94.1,55.01 94.18,55.08 94.18,55.21 94.26,55.28 v4(94.64,55.28) 94.87,55.28 95.13,55.03 96.32,55.03 96.6,54.75 97.35,54.75 98.19,53.92 98.73,53.92 98.88,53.77 101.14,53.77 v3(101.48,54.1)
  IN3 w0.127: 141.16,25.35 141.16,28.5 141.3,28.64
  IN3 w0.165: v3(109.13,56.76) 109.38,56.76 110.5,55.64 110.5,55.35 110.51,55.34 110.51,47.33 112.02,45.81 112.02,42.92 112.13,42.82 113.68,42.82 113.8,42.69 113.8,42.38 113.98,42.21 114.51,42.21 114.67,42.37 114.67,42.84 114.8,42.97 115.2,42.97 115.33,42.84 115.33,42.37 115.5,42.21 116.83,42.21 117.36,41.67 118.98,41.67 119.7,42.38 124.42,42.38 124.72,42.08 124.72,41.47 124.95,41.24 127.04,41.24 128,42.21 130.16,42.21 131.13,41.24 131.48,41.24 132.52,42.28 135.36,42.28 137.79,39.85 137.79,38.84 140.13,36.5 140.13,32.36 141.3,31.19 141.3,28.64
  IN4 w0.076: v4(94.64,55.28) 95.26,55.91 96.06,55.91 96.55,56.39 106.44,56.39 106.92,56.88 107.92,56.88 108.38,56.42 108.79,56.42 v3(109.13,56.76) 109.18,56.71 119.66,56.71 121.09,55.28 v4(123.97,55.28) ; v4(141.86,23.83) 141.78,23.83 v1(141.57,23.62)
  BOTTOM w0.076: v3(130.81,54.1) 131.21,53.7 UD5.R8 ; v3(88.85,54.11) 89.25,53.7 UD7.R8 ; RD40.1 108.95,56.58 v3(109.13,56.76) ; UD8.R8 101.88,53.7 v3(101.48,54.1) ; v3(118.18,54.11) 118.59,53.7 UD6.R8
DDR_B_MA7: length 132.8
  IN3 w0.076: 142.44,29.03 142.44,27.42 141.51,26.49 v4(141.51,26.48) ; v3(126.83,53.31) 126.83,53.66 126.56,53.93 126.36,53.93 126.28,53.85 126.28,53.74 126.21,53.66 126.06,53.66 125.98,53.74 125.98,53.85 125.9,53.93 125.55,53.93 125.42,53.8 125.42,53.58 125.22,53.38 124.36,53.38 124.3,53.32 124.3,53.31 124.23,53.23 124.07,53.23 124,53.31 124,53.32 123.92,53.4 123.77,53.4 123.69,53.32 123.69,53.31 123.62,53.23 123.46,53.23 123.39,53.31 123.39,53.32 123.31,53.4 123.16,53.4 123.08,53.32 123.08,53.31 123.01,53.23 122.85,53.23 122.78,53.31 122.78,53.45 122.7,53.52 122.55,53.52 122.47,53.45 122.47,53.4 122.4,53.32 122.17,53.32 122.09,53.4 v4(121.14,53.4) 120.37,53.4 119.76,52.79 115.93,52.79 115.7,52.56 115.38,52.56 114.62,53.32 v3(114.2,53.32) ; v3(84.86,53.32) 85.34,53.32 86.19,52.47 87.49,52.47 87.72,52.7 90.34,52.7 91.04,53.4 v4(91.81,53.4) 92.76,53.4 92.83,53.32 92.83,53.31 92.91,53.23 93.06,53.23 93.14,53.31 93.14,53.32 93.21,53.4 93.37,53.4 93.44,53.32 93.44,53.31 93.52,53.23 93.67,53.23 93.75,53.31 93.75,53.32 93.82,53.4 93.98,53.4 94.05,53.32 94.05,53.31 94.13,53.23 94.28,53.23 94.36,53.31 94.36,53.32 94.43,53.4 94.59,53.4 94.66,53.32 94.66,53.31 94.74,53.23 94.89,53.23 94.97,53.31 94.97,53.32 95.04,53.4 95.39,53.4 95.57,53.22 95.93,53.22 96.09,53.37 96.09,53.8 96.21,53.93 97.23,53.93 97.49,53.66 v3(97.49,53.31)
  IN3 w0.165: v3(111.69,55.21) 111.55,55.07 111.55,47.77 112.82,46.5 114.78,46.5 115.52,45.76 115.52,44.45 116.66,43.31 135.79,43.31 138.82,40.28 138.82,39.59 139.18,39.24 139.86,39.24 141.16,37.94 141.16,32.78 142.44,31.5 142.44,29.03
  IN4 w0.076: v4(121.14,53.4) 123.62,53.4 124.25,52.76 124.98,52.76 125.11,52.89 125.11,53.08 124.98,53.21 124.4,53.21 123.71,53.9 121.4,53.9 120.63,54.68 118.55,54.68 118.01,55.21 117.63,55.21 117.56,55.29 117.56,55.34 117.48,55.42 117.33,55.42 117.25,55.34 117.25,55.29 117.17,55.21 117.02,55.21 116.95,55.29 116.95,55.34 116.87,55.42 116.72,55.42 116.64,55.34 116.64,55.29 116.57,55.21 116.41,55.21 116.34,55.29 116.34,55.34 116.26,55.42 116.11,55.42 116.03,55.34 116.03,55.29 115.96,55.21 115.8,55.21 115.73,55.29 115.73,55.34 115.65,55.42 115.5,55.42 115.42,55.34 115.42,55.29 115.35,55.21 115.19,55.21 115.12,55.29 115.12,55.34 115.04,55.42 114.89,55.42 114.81,55.34 114.81,55.29 114.74,55.21 114.58,55.21 114.51,55.29 114.51,55.34 114.43,55.42 114.28,55.42 114.2,55.34 114.2,55.29 114.13,55.21 113.97,55.21 113.9,55.29 113.9,55.34 113.82,55.42 113.67,55.42 113.59,55.34 113.59,55.29 113.52,55.21 113.36,55.21 113.29,55.29 113.29,55.34 113.21,55.42 113.06,55.42 112.98,55.34 112.98,55.29 112.91,55.21 112.76,55.21 112.68,55.29 112.68,55.34 112.6,55.42 112.45,55.42 112.37,55.34 112.37,55.29 112.3,55.21 v3(111.69,55.21) 106.86,55.21 106.67,55.02 105.31,55.02 105.03,55.3 98.64,55.3 98.2,54.86 97.92,54.58 95.91,54.58 94.83,53.5 91.91,53.5 v4(91.81,53.4) ; v4(141.51,26.48) 141.51,26.47 141.15,26.1 141.15,25.7 141.1,25.65 141.1,25.37 141.17,25.29 141.17,24.91 v1(141.13,24.87)
  BOTTOM w0.076: UD5.R2 126.44,53.7 v3(126.83,53.31) ; v3(111.69,55.21) 112.3,55.82 RD52.1 ; v3(84.86,53.32) 84.48,53.7 UD7.R2 ; v3(97.49,53.31) 97.1,53.7 UD8.R2 ; v3(114.2,53.32) 113.81,53.7 UD6.R2
DDR_B_MA8: length 132.5
  IN3 w0.076: v3(130.83,54.95) 130.52,55.26 128.16,55.26 125.85,57.57 v4(123.33,57.57) 122.65,57.57 121.8,56.72 121.64,56.72 121.36,56.44 121.25,56.44 121.23,56.46 121.12,56.46 121.02,56.35 121.02,56.24 121.03,56.23 121.03,56.12 120.84,55.92 120.73,55.92 120.41,56.25 120.3,56.25 120.19,56.14 120.19,56.03 120.52,55.71 120.52,55.6 120.41,55.49 120.3,55.49 119.98,55.81 119.87,55.81 119.76,55.71 119.76,55.6 120.08,55.28 120.08,55.17 119.97,55.06 118.82,55.06 118.61,55.27 v3(118.61,55.75) ; v3(89.27,55.75) 89.52,55.5 89.78,55.5 89.85,55.58 89.85,55.78 89.93,55.86 90.08,55.86 90.16,55.78 90.16,55.58 90.23,55.5 90.82,55.5 91.1,55.78 91.1,55.89 90.92,56.07 90.92,56.18 91.02,56.28 91.13,56.28 91.31,56.1 91.42,56.1 91.53,56.21 91.53,56.32 91.35,56.5 91.35,56.61 91.45,56.71 91.56,56.71 91.74,56.53 91.85,56.53 91.96,56.64 91.96,56.75 91.78,56.93 91.78,57.04 91.89,57.15 91.99,57.15 92.18,56.96 92.28,56.96 92.39,57.07 92.39,57.18 92.21,57.36 92.21,57.47 92.32,57.58 92.43,57.58 92.61,57.4 92.72,57.4 92.89,57.57 v4(93.99,57.57) 94.25,57.57 94.67,57.16 95.39,57.16 95.63,57.4 96.63,57.4 97.78,56.25 97.99,56.25 98.99,55.26 101.19,55.26 v3(101.49,54.95)
  IN3 w0.165: v4(141.54,27.45) 141.69,27.6 141.69,31.28 140.47,32.5 140.47,36.64 138.14,38.98 138.14,39.99 135.5,42.63 127.82,42.63 126.89,41.69 125.7,41.69 124.7,42.69 116.01,42.69 115.25,43.45 113.8,43.45 113.65,43.3 112.91,43.3 112.42,43.79 112.42,45.92 110.86,47.48 110.86,55.77 109.13,57.5 108.94,57.5 108.77,57.66 108.77,58.06 108.9,58.18 109.18,58.18 v3(109.23,58.13)
  IN4 w0.076: v1(140.7,25.12) 140.75,25.16 140.75,25.74 140.84,25.83 140.84,26.32 140.86,26.34 140.86,26.76 141.2,27.09 141.2,27.1 141.38,27.28 141.39,27.28 141.54,27.43 v4(141.54,27.45) ; v4(93.99,57.57) 94.71,58.3 109.07,58.3 v3(109.23,58.13) 109.28,58.18 120.06,58.18 121.81,56.43 122.07,56.43 122.17,56.53 122.17,57.1 122.65,57.57 v4(123.33,57.57)
  BOTTOM w0.076: UD5.T8 131.22,54.56 v3(130.83,54.95) ; RD46.1 109.36,58.26 v3(109.23,58.13) ; v3(101.49,54.95) 101.88,54.56 UD8.T8 ; v3(118.61,55.75) 118.3,55.44 118.3,54.81 UD6.T8 ; UD7.T8 v3(89.27,55.75)
DDR_B_MA9: length 133.3
  IN3 w0.076: v3(85.76,53.38) 86.17,53.38 87.26,54.48 88.07,54.48 88.29,54.69 90.87,54.69 91.97,55.78 v4(92.66,55.78) 92.97,55.78 93.05,55.86 93.05,56 93.12,56.08 93.28,56.08 93.35,56 93.35,55.68 93.43,55.61 93.58,55.61 93.66,55.68 93.66,56 93.73,56.08 94.66,56.08 95.4,55.33 96.45,55.33 96.73,55.06 97.48,55.06 98.27,54.27 98.49,54.27 98.59,54.38 v3(98.59,54.58) ; v3(115.1,53.38) 115.51,53.38 116.64,54.51 117.42,54.51 117.61,54.7 118.28,54.7 118.54,54.44 120.22,54.44 121.56,55.78 v4(121.99,55.78) 122.2,55.78 122.27,55.86 122.27,56.04 122.35,56.11 122.5,56.11 122.58,56.04 122.58,55.68 122.65,55.61 122.8,55.61 122.88,55.68 122.88,56.04 122.96,56.11 123.09,56.11 123.22,55.99 123.38,55.99 123.51,56.11 124,56.11 124.83,55.29 125.27,55.29 125.71,54.84 127.03,54.84 127.11,54.77 127.6,54.27 127.83,54.27 127.93,54.37 v3(127.93,54.58) ; 142.07,27.51 141.53,26.97 v4(141.51,26.97)
  IN3 w0.165: 142.07,27.51 142.07,31.38 140.81,32.64 140.81,36.79 138.48,39.12 138.48,40.13 135.64,42.97 127.59,42.97 127.14,42.51 125.69,42.51 125.21,42.99 116.47,42.99 115.35,44.11 115.29,44.11 114.49,44.91 113.04,44.91 112.8,45.15 112.8,46.03 111.21,47.62 111.21,55.97 110.98,56.2 110.98,56.43 111.36,56.81 111.36,56.99 111.07,57.28 110.89,57.28 110.51,56.9 110.28,56.9 v3(109.74,57.44)
  IN4 w0.076: v4(121.99,55.78) 121.81,55.78 121.44,56.16 121.33,56.16 121.12,55.95 121.01,55.95 120.91,56.06 120.91,56.17 121.11,56.37 121.11,56.48 121,56.59 120.9,56.59 120.66,56.35 120.55,56.35 120.44,56.46 120.44,56.57 120.68,56.81 120.68,56.91 119.87,57.73 119.69,57.73 119.61,57.65 119.61,57.5 119.53,57.42 119.38,57.42 119.3,57.5 119.3,57.65 119.23,57.73 119,57.73 118.93,57.65 118.93,57.61 118.85,57.54 118.7,57.54 118.62,57.61 118.62,57.65 118.55,57.73 118.39,57.73 118.32,57.65 118.32,57.61 118.24,57.54 118.09,57.54 118.01,57.61 118.01,57.65 117.94,57.73 117.78,57.73 117.71,57.65 117.71,57.61 117.63,57.54 117.48,57.54 117.4,57.61 117.4,57.65 117.33,57.73 117.17,57.73 117.1,57.65 117.1,57.61 117.02,57.54 116.87,57.54 116.79,57.61 116.79,57.65 116.72,57.73 116.56,57.73 116.49,57.65 116.49,57.61 116.41,57.54 116.26,57.54 116.18,57.61 116.18,57.65 116.11,57.73 115.96,57.73 115.88,57.65 115.88,57.61 115.8,57.54 115.65,57.54 115.57,57.61 115.57,57.65 115.5,57.73 115.35,57.73 115.27,57.65 115.27,57.61 115.19,57.54 115.04,57.54 114.96,57.61 114.96,57.65 114.89,57.73 114.74,57.73 114.66,57.65 114.66,57.61 114.58,57.54 114.43,57.54 114.35,57.61 114.35,57.65 114.28,57.73 114.13,57.73 114.05,57.65 114.05,57.61 113.97,57.54 113.82,57.54 113.75,57.61 113.75,57.65 113.67,57.73 113.52,57.73 113.44,57.65 113.44,57.61 113.36,57.54 113.21,57.54 113.14,57.61 113.14,57.65 113.06,57.73 112.91,57.73 112.83,57.65 112.83,57.61 112.75,57.54 112.6,57.54 112.53,57.61 112.53,57.65 112.45,57.73 112.3,57.73 112.22,57.65 112.22,57.61 112.15,57.54 111.99,57.54 111.92,57.61 111.92,57.65 111.84,57.73 111.69,57.73 111.61,57.65 111.61,57.61 111.54,57.54 111.38,57.54 111.31,57.61 111.31,57.65 111.23,57.73 111.08,57.73 111,57.65 111,57.61 110.93,57.54 110.77,57.54 110.7,57.61 110.7,57.65 110.62,57.73 110.36,57.73 110.08,57.44 v3(109.74,57.44) 108.92,57.44 108.66,57.18 107.33,57.18 107.07,57.43 95.92,57.43 94.7,56.22 94.42,56.22 94.37,56.27 93.14,56.27 v4(92.66,55.78) ; v1(141.13,24.37) 141.13,24.53 140.89,24.77 140.89,24.97 141.02,25.1 141.02,25.23 140.94,25.31 140.94,25.72 140.99,25.77 140.99,26.25 141.11,26.37 141.11,26.54 141.51,26.95 v4(141.51,26.97)
  BOTTOM w0.076: UD8.R3 97.88,53.87 v3(98.59,54.58) ; RD56.1 110.19,56.99 v3(109.74,57.44) ; UD5.R3 127.22,53.87 v3(127.93,54.58) ; v3(85.76,53.38) 85.44,53.7 UD7.R3 ; UD6.R3 114.78,53.7 v3(115.1,53.38)
DDR_B_MA10: length 138.2
  IN3 w0.076: v3(117.31,49.57) 117.31,49.08 117.38,49 117.67,49 117.75,49.08 117.75,49.6 117.83,49.67 119.25,49.67 119.4,49.52 119.4,48.74 119.86,48.28 v4(122.92,48.28) 124.45,48.28 125.27,49.1 125.5,49.1 125.73,49.33 126.87,49.33 127.54,50 129.92,50 v3(129.95,49.98) ; v4(140.32,22.1) 140.04,22.1 140.04,22.38 139.19,23.23 138.9,23.23 138.82,23.31 138.81,23.31 138.59,23.52 138.59,23.88 138.61,23.89 138.61,23.93 138.63,23.96 138.63,24.2 138.32,24.51 137.52,24.51 137.31,24.73 137.23,24.73 134.47,27.5 134.43,27.5 134.29,27.63 ; v3(100.54,50) 100.3,49.77 97.97,49.77 97.38,49.18 96.41,49.18 95.52,48.28 v4(93.58,48.28) 90.53,48.28 90.07,48.74 90.07,49.52 89.91,49.67 88.49,49.67 88.42,49.6 88.42,49.08 88.34,49 88.05,49 87.97,49.08 v3(87.97,49.57)
  IN3 w0.127: 134.16,27.68 134.2,27.63 134.29,27.63
  IN3 w0.165: 134.16,27.68 131.27,30.56 116.13,30.56 114.33,32.36 112.37,32.36 109.51,35.22 109.33,35.22 107.87,33.76 107.69,33.76 107.41,34.05 107.41,34.23 108.84,35.66 108.84,35.84 108.55,36.13 108.37,36.13 106.98,34.74 106.75,34.74 106.51,34.97 106.51,35.2 107.18,35.87 107.18,36.1 106.95,36.34 106.71,36.34 106.05,35.67 105.81,35.67 103.82,37.66 103.82,46.55 104.35,47.08 v3(104.35,47.46)
  IN4 w0.076: v1(141.13,23.37) 141.13,23.21 140.94,23.02 140.88,22.95 140.88,22.78 140.94,22.72 140.94,22.52 140.53,22.1 v4(140.32,22.1) ; v4(122.92,48.28) 120.83,48.28 120.43,47.88 112.95,47.88 112.39,47.33 112.06,47.33 111.92,47.46 v3(104.35,47.46) 103.8,47.46 103.51,47.18 100.29,47.18 100.22,47.26 100.22,47.4 100.14,47.48 99.99,47.48 99.91,47.4 99.91,47.26 99.84,47.18 99.68,47.18 99.61,47.26 99.61,47.43 99.53,47.5 99.38,47.5 99.3,47.43 99.3,47.26 99.23,47.18 99.08,47.18 99,47.26 99,47.85 98.92,47.92 98.77,47.92 98.69,47.85 98.69,47.26 98.62,47.18 97.99,47.18 97.92,47.26 95.93,47.26 95.55,47.63 95.55,48.2 95.48,48.28 94.16,48.28 94.08,48.2 94.08,47.81 94,47.73 91.48,47.73 91.4,47.81 91.4,48 91.48,48.07 93.38,48.07 v4(93.58,48.28)
  BOTTOM w0.076: v3(104.35,47.46) 105.75,46.07 RD36.1 ; v3(129.95,49.98) 130.42,50.46 UD5.L7 ; UD6.L7 117.81,50.3 117.31,49.8 v3(117.31,49.57) ; v3(87.97,49.57) 87.97,49.8 88.47,50.3 UD7.L7 ; UD8.L7 101.03,50.5 v3(100.54,50)
DDR_B_MA11: length 126.2
  IN3 w0.076: v3(129.94,54.11) 129.79,53.97 128.27,53.97 128.12,54.12 127.54,54.12 126.97,54.69 125.65,54.69 125.21,55.14 124.77,55.14 124.18,55.72 v4(123.55,55.72) 123.26,55.72 123,55.45 121.45,55.45 120.28,54.29 118.48,54.29 118.32,54.45 117.66,54.45 v3(117.26,54.04) ; v4(139.76,27.7) 139.32,28.15 139.32,28.18 139.23,28.27 ; v3(87.92,54.04) 88.42,54.54 90.94,54.54 92.03,55.63 92.36,55.63 92.54,55.45 93.66,55.45 93.93,55.72 v4(94.22,55.72) 94.65,55.72 95.19,55.18 96.39,55.18 96.66,54.91 97.42,54.91 98.26,54.07 98.79,54.07 98.9,53.97 100.46,53.97 v3(100.6,54.11)
  IN3 w0.165: 139.23,28.27 138.63,28.86 138.63,30.46 138.01,31.09 138.01,35.37 135.31,38.07 124.92,38.07 123.99,37.13 113.99,37.13 108.99,42.14 108.99,48.21 109.48,48.71 109.48,53.61 109.05,54.04 109.05,54.41 108.99,54.48 108.72,54.48 108.6,54.6 108.6,55.1 108.72,55.23 109.1,55.23 109.23,55.36 109.23,55.76 109.1,55.89 108.52,55.89 108.43,55.98 108.43,56.67 108.52,56.76 v3(108.6,56.76)
  IN4 w0.076: v4(123.55,55.72) 123.3,55.47 121.12,55.47 119.2,57.38 110.23,57.38 109.94,57.09 109.45,57.09 109.43,57.1 108.94,57.1 v3(108.6,56.76) 108.3,56.76 108.04,57.03 106.86,57.03 106.37,56.55 96.48,56.55 96,56.06 94.36,56.06 94.31,56.11 94.05,56.11 93.85,55.91 93.85,55.64 93.93,55.57 94.07,55.57 v4(94.22,55.72) ; v4(139.76,27.7) 139.76,27.49 139.6,27.32 139.6,26.67 139.57,26.65 139.52,26.59 139.52,26.33 139.59,26.25 139.59,25.02 139.83,24.78 v1(139.83,24.62)
  BOTTOM w0.076: RD58.1 108.44,58.26 108.6,58.11 v3(108.6,56.76) ; v3(117.26,54.04) 117.6,53.7 UD6.R7 ; UD7.R7 88.26,53.7 v3(87.92,54.04) ; v3(129.94,54.11) 130.35,53.7 UD5.R7 ; UD8.R7 101.01,53.7 v3(100.6,54.11)
DDR_B_MA12: length 131.3
  IN3 w0.076: v3(117.26,52.11) 117.26,52.28 117.45,52.48 120.18,52.48 120.34,52.33 120.82,52.33 120.89,52.41 120.89,52.6 120.97,52.67 121.59,52.67 121.85,52.93 122.95,52.93 123.13,52.75 v4(123.45,52.75) 123.74,52.75 123.92,52.93 124.35,52.93 124.5,53.08 125.74,53.08 125.84,52.97 126.68,52.97 126.76,52.89 128.18,52.89 128.27,52.98 129.47,52.98 v3(129.93,52.52) ; v3(87.92,52.11) 87.92,52.25 88,52.33 91.26,52.33 91.43,52.49 92.08,52.49 92.34,52.75 92.89,52.75 92.97,52.67 92.97,52.63 93.05,52.56 93.2,52.56 93.27,52.63 93.27,52.67 93.35,52.75 93.5,52.75 93.58,52.67 93.58,52.63 93.66,52.56 93.81,52.56 93.88,52.63 93.88,52.67 93.96,52.75 v4(94.12,52.75) 94.41,52.75 94.58,52.91 96.1,52.91 96.16,52.97 97.39,52.97 97.54,52.82 99.26,52.82 99.82,52.25 100.33,52.25 v3(100.59,52.52) ; v4(139.56,23.93) 139.56,24.06 138.9,24.72 138.8,24.72 138.47,25.05 137.88,25.05 134.99,27.94 134.99,27.99 135.01,28.02
  IN3 w0.165: 135.01,28.02 135.01,28.56 131.48,32.09 119.22,32.09 119.05,32.26 119.05,32.97 118.92,33.1 118.52,33.1 118.39,32.97 118.39,32.26 118.23,32.09 117.9,32.09 117.73,32.26 117.73,33.58 117.6,33.7 112.57,33.7 105.04,41.24 105.04,46.04 105.5,46.5 105.5,54.12 105.34,54.27 104.79,54.27 104.66,54.15 v3(104.66,53.97)
  IN4 w0.076: v1(139.83,24.12) 139.65,23.93 v4(139.56,23.93) ; v4(94.12,52.75) 92.33,52.75 91.93,52.35 91.54,52.35 91.45,52.44 91.45,52.75 91.63,52.93 92.01,52.93 92.17,53.09 92.28,53.19 95.95,53.19 96.5,53.75 98.94,53.75 99.02,53.67 99.02,53.43 99.09,53.36 99.25,53.36 99.32,53.43 99.32,53.67 99.4,53.75 99.55,53.75 99.63,53.67 99.63,53.47 99.7,53.4 99.86,53.4 99.93,53.47 99.93,53.66 100.01,53.74 102.56,53.74 102.64,53.81 102.64,54.34 102.72,54.41 102.9,54.41 102.98,54.34 102.98,54.07 103.05,53.99 103.21,53.99 103.28,54.07 103.28,54.34 103.36,54.41 103.51,54.41 103.59,54.34 103.59,54.07 103.66,53.99 103.82,53.99 103.89,54.07 103.89,54.34 103.97,54.41 104.26,54.41 104.34,54.34 104.34,54.04 104.42,53.97 v3(104.66,53.97) 110.73,53.97 111.4,54.64 115.44,54.64 117.16,52.91 119.8,52.91 120.33,52.38 120.61,52.38 120.98,52.75 v4(123.45,52.75)
  BOTTOM w0.076: v3(100.59,52.52) 100.62,52.52 101.04,52.1 UD8.N7 ; v3(129.93,52.52) 129.96,52.52 130.38,52.1 UD5.N7 ; UD6.N7 117.27,52.1 v3(117.26,52.11) ; UD7.N7 87.93,52.1 v3(87.92,52.11) ; RD30.1 104.68,53.94 v3(104.66,53.97)
DDR_B_MA13: length 140
  IN3 w0.076: 138.45,27.43 139.21,26.68 139.21,26.2 139.29,26.12 139.29,25.78 140.4,24.68 v4(140.4,23.83) ; v3(85.76,54.15) 86.43,54.15 87.63,55.35 90.89,55.35 92.51,56.98 92.74,56.98 92.81,56.9 92.81,56.85 92.89,56.77 93.04,56.77 93.12,56.85 93.12,57.17 93.19,57.24 v4(93.43,57.24) 93.75,57.24 93.83,57.17 93.83,57.08 93.9,57 94.06,57 94.13,57.08 94.13,57.17 94.21,57.24 94.36,57.24 94.44,57.17 94.44,57.08 94.51,57 95.45,57 95.7,57.24 96.37,57.24 96.69,56.92 96.69,56.81 96.45,56.57 96.45,56.46 96.56,56.35 96.67,56.35 96.97,56.66 97.08,56.66 97.19,56.55 97.19,56.44 97,56.25 97,56.17 97.07,56.1 97.23,56.1 97.32,56.19 97.61,56.19 97.7,56.1 97.93,56.1 98.68,55.35 98.68,55.19 98.57,55.07 97.97,55.07 97.83,55.22 v3(97.83,55.42) ; v3(127.16,55.42) 127.16,55.25 127.24,55.17 127.43,55.17 127.6,55.34 127.6,55.61 126.83,56.37 126.73,56.37 126.5,56.15 126.4,56.15 126.29,56.26 126.29,56.36 126.51,56.59 126.51,56.69 126.4,56.8 126.3,56.8 126.07,56.58 125.97,56.58 125.86,56.69 125.86,56.79 126.08,57.02 126.08,57.12 125.97,57.23 125.86,57.23 125.69,57.05 125.57,57.05 125.21,57.41 124.76,57.41 124.57,57.22 124.42,57.22 124.37,57.28 124.37,57.35 124.29,57.42 124.12,57.42 124.04,57.35 124.04,57.08 123.97,57 123.81,57 123.74,57.08 123.74,57.23 123.66,57.31 123.51,57.31 123.43,57.23 123.43,57.08 123.36,57 123.17,57 123.09,57.08 123.09,57.17 123.01,57.24 v4(122.77,57.24) 122.56,57.24 121.89,56.57 121.7,56.57 120.04,54.91 118.76,54.91 118.51,55.16 117.91,55.16 117.72,55.35 117.03,55.35 115.83,54.15 v3(115.1,54.15)
  IN3 w0.165: v3(106.06,57.96) 106.06,56.81 106.94,55.92 106.94,54.93 107.66,54.22 107.66,51.15 107.24,50.73 107.24,49.87 107.54,49.56 107.54,41.65 113.43,35.76 124.56,35.76 125.49,36.7 133.25,36.7 133.38,36.57 133.38,33.55 137.26,29.67 137.26,28.29 137.88,27.67 138.02,27.67 138.26,27.43 138.45,27.43
  IN4 w0.076: v4(140.4,23.83) 140.61,23.62 v1(140.7,23.62) ; v4(93.43,57.24) 94.11,57.24 95.01,58.15 96.89,58.15 96.96,58.07 96.96,57.96 97.04,57.88 97.19,57.88 97.27,57.96 97.27,58.07 97.34,58.15 97.5,58.15 97.57,58.07 97.57,57.96 97.65,57.88 97.8,57.88 97.88,57.96 97.88,58.07 97.95,58.15 98.11,58.15 98.18,58.07 98.18,57.96 98.26,57.88 98.41,57.88 98.49,57.96 98.49,58.07 98.56,58.15 98.72,58.15 98.79,58.07 98.79,57.96 98.87,57.88 99.02,57.88 99.1,57.96 99.1,58.07 99.17,58.15 99.33,58.15 99.4,58.07 99.4,57.96 99.48,57.88 99.63,57.88 99.71,57.96 99.71,58.07 99.78,58.15 99.94,58.15 100.01,58.07 100.01,57.96 100.09,57.88 100.24,57.88 100.32,57.96 100.32,58.07 100.39,58.15 100.55,58.15 100.62,58.07 100.62,57.96 100.7,57.88 100.85,57.88 100.93,57.96 100.93,58.07 101,58.15 101.15,58.15 101.23,58.07 101.23,57.96 101.31,57.88 101.46,57.88 101.54,57.96 101.54,58.07 101.61,58.15 101.76,58.15 101.84,58.07 101.84,57.96 101.92,57.88 102.07,57.88 102.15,57.96 102.15,58.07 102.22,58.15 102.37,58.15 102.45,58.07 102.45,57.96 102.53,57.88 102.68,57.88 102.75,57.96 102.75,58.07 102.83,58.15 102.98,58.15 103.06,58.07 103.06,57.96 103.14,57.88 103.29,57.88 103.36,57.96 103.36,58.07 103.44,58.15 103.59,58.15 103.67,58.07 103.67,57.96 103.75,57.88 103.9,57.88 103.97,57.96 103.97,58.07 104.05,58.15 104.2,58.15 104.28,58.07 104.28,57.96 104.36,57.88 104.51,57.88 104.58,57.96 104.58,58.07 104.66,58.15 104.81,58.15 104.89,58.07 104.89,57.92 104.96,57.84 105.12,57.84 105.19,57.92 105.19,58.07 105.27,58.15 105.42,58.15 105.5,58.07 105.5,58.03 105.57,57.96 v3(106.06,57.96) 108.58,57.96 108.75,57.79 109.38,57.79 109.62,58.03 119.99,58.03 121.75,56.28 122.14,56.28 122.4,56.54 122.4,56.89 122.76,57.24 v4(122.77,57.24)
  BOTTOM w0.076: UD5.T3 127.22,55.36 v3(127.16,55.42) ; UD8.T3 97.88,55.36 v3(97.83,55.42) ; v3(115.1,54.15) 114.96,54.15 UD6.T3 ; v3(85.76,54.15) 85.63,54.15 UD7.T3 ; RD50.1 v3(106.06,57.96)
DDR_B_MA14: length 130.7
  IN3 w0.076: 138.5,28.02 139.48,27.04 139.48,26.92 139.52,26.89 139.52,26.33 139.6,26.25 139.6,26.02 141.16,24.46 v4(141.16,23.9) ; v3(87.95,54.86) 87.96,54.84 88.32,54.84 88.4,54.92 88.4,54.97 88.47,55.05 88.63,55.05 88.7,54.97 88.7,54.93 88.78,54.86 90.82,54.86 92.23,56.27 93.77,56.27 94.04,56.53 v4(94.56,56.53) 94.95,56.53 95.09,56.39 95.09,56.24 94.99,56.13 94.99,56.03 95.1,55.92 95.21,55.92 95.32,56.03 95.43,56.03 95.54,55.93 95.54,55.82 95.42,55.7 95.42,55.59 95.53,55.49 95.64,55.49 95.74,55.59 96.41,55.59 96.79,55.21 97.54,55.21 97.84,54.92 100.53,54.92 v3(100.54,54.91) ; v3(117.28,54.86) 118.35,54.86 118.61,54.6 120.16,54.6 121.83,56.27 123.63,56.27 v4(123.9,56.53) 124.24,56.53 124.43,56.34 124.43,56.24 124.33,56.13 124.33,56.03 124.44,55.92 124.54,55.92 124.65,56.02 124.75,56.02 124.86,55.91 124.86,55.8 124.76,55.7 124.76,55.59 124.87,55.49 124.97,55.49 125.08,55.59 125.18,55.59 125.78,55 127.09,55 127.17,54.92 129.93,54.92 v3(129.94,54.91)
  IN3 w0.165: 138.5,28.02 137.95,28.58 137.95,30.08 135.34,32.69 135.34,32.92 137.32,34.91 137.32,35.09 135.03,37.38 125.21,37.38 124.27,36.45 113.71,36.45 108.23,41.93 108.23,50.59 108.09,50.73 v3(108.09,57.52)
  IN4 w0.076: v4(94.56,56.53) 94.26,56.53 94.12,56.67 94.12,57.04 94.81,57.73 95.15,57.73 95.23,57.8 95.23,57.9 95.3,57.98 95.46,57.98 95.53,57.9 95.53,57.76 95.61,57.69 95.76,57.69 95.84,57.76 95.84,57.9 95.91,57.98 96.07,57.98 96.14,57.9 96.14,57.75 96.22,57.68 96.37,57.68 96.45,57.75 96.45,57.9 96.52,57.98 96.67,57.98 96.75,57.9 96.75,57.72 96.86,57.61 106.67,57.61 106.85,57.79 107,57.79 107.08,57.71 107.08,57.66 107.15,57.59 107.3,57.59 107.38,57.66 107.38,57.71 107.46,57.79 107.61,57.79 107.69,57.71 107.69,57.6 107.76,57.52 v3(108.09,57.52) 108.43,57.52 108.54,57.64 109.45,57.64 109.69,57.88 119.93,57.88 121.68,56.13 122.88,56.13 123.29,56.53 v4(123.9,56.53) ; v4(141.16,23.9) 141.37,24.12 v1(141.57,24.12)
  BOTTOM w0.076: v3(117.28,54.86) 117.28,54.77 117.55,54.5 UD6.T7 ; UD5.T7 130.35,54.5 v3(129.94,54.91) ; UD7.T7 88.22,54.5 87.95,54.77 v3(87.95,54.86) ; v3(100.54,54.91) 100.95,54.5 UD8.T7 ; v3(108.09,57.52) 107.91,57.35 RD38.1
DDR_B_MA15: length 129.5
  IN3 w0.076: v3(130.82,51.71) 130.62,51.91 128.14,51.91 128.1,51.95 127.05,51.95 126.97,52.02 126.69,52.02 126.61,51.95 125.25,51.95 125.07,51.77 124.6,51.77 124.44,51.61 124.17,51.61 123.97,51.81 v4(122.67,51.81) 121.93,51.81 121.73,51.61 120.57,51.61 119.85,50.89 119.21,50.89 119.13,50.97 119.13,51.2 119.06,51.27 118.91,51.27 118.83,51.2 118.83,50.97 118.75,50.89 118.6,50.89 118.52,50.97 118.52,51.26 118.45,51.34 118.3,51.34 118.22,51.26 118.22,50.97 118.14,50.89 117.99,50.89 117.91,50.97 117.91,51.1 117.84,51.17 117.69,51.17 117.61,51.1 117.61,50.97 117.53,50.89 117.02,50.89 116.94,50.97 116.94,51.3 117.05,51.4 v3(117.28,51.4) ; 137.58,26.89 v4(138.97,25.5) ; v3(87.95,51.4) 87.71,51.4 87.61,51.3 87.61,50.97 87.68,50.89 88.2,50.89 88.27,50.97 88.27,51.1 88.35,51.17 88.5,51.17 88.58,51.1 88.58,50.97 88.66,50.89 88.81,50.89 88.88,50.97 88.88,51.26 88.96,51.34 89.11,51.34 89.19,51.26 89.19,50.97 89.27,50.89 89.42,50.89 89.49,50.97 89.49,51.2 89.57,51.27 89.72,51.27 89.8,51.2 89.8,50.97 89.87,50.89 90.52,50.89 91.23,51.61 92.4,51.61 92.6,51.81 v4(93.33,51.81) 94.63,51.81 94.84,51.61 95.1,51.61 95.27,51.77 96.06,51.77 96.26,51.96 96.98,51.96 97.04,52.02 98.69,52.02 98.8,51.91 100.59,51.91 100.75,51.76 100.75,51.36 v3(100.5,51.12)
  IN3 w0.165: 137.58,26.89 137.35,26.89 136.57,27.68 136.43,27.68 136.23,27.88 136.23,28.92 132.03,33.12 129.64,33.12 129.51,33.25 129.51,35.54 129.39,35.67 128.98,35.67 128.85,35.54 128.85,34.03 128.73,33.9 128.32,33.9 128.19,34.03 128.19,35.54 128.06,35.67 127.66,35.67 127.53,35.54 127.53,34.82 127.4,34.69 127,34.69 126.87,34.82 126.87,35.54 126.74,35.67 126.34,35.67 126.21,35.54 126.21,34.94 126,34.73 113,34.73 106.46,41.27 106.46,48.91 106.18,49.19 106.18,51.81 v3(106.74,52.37)
  IN4 w0.076: v4(93.33,51.81) 93.53,51.61 95.44,51.61 95.91,52.08 97.59,52.08 97.67,52.15 97.67,52.55 97.75,52.62 97.9,52.62 97.97,52.55 97.97,52.15 98.05,52.08 98.2,52.08 98.28,52.15 98.28,52.68 98.36,52.76 98.51,52.76 98.58,52.68 98.58,52.15 98.66,52.08 99.58,52.08 99.64,52.02 101.04,52.02 101.07,52.05 103.52,52.05 103.59,52.12 103.59,52.28 103.67,52.35 103.82,52.35 103.9,52.28 103.9,52.12 103.98,52.05 104.13,52.05 104.2,52.12 104.2,52.18 104.28,52.25 104.43,52.25 104.51,52.18 104.51,52.12 104.58,52.05 104.74,52.05 105.07,52.37 v3(106.74,52.37) 107.2,52.37 107.73,52.9 115.06,52.9 115.19,52.77 115.19,52.74 115.47,52.46 119.57,52.46 120.13,51.9 122.58,51.9 v4(122.67,51.81) ; v1(138.97,25.12) v4(138.97,25.5)
  BOTTOM w0.076: v3(117.28,51.4) 117.71,51.4 UD6.M7 ; v3(130.82,51.71) 130.42,51.3 UD5.M7 ; v3(100.5,51.12) 100.69,51.3 UD8.M7 ; RD32.1 107.07,52.04 v3(106.74,52.37) ; v3(87.95,51.4) 88.05,51.3 UD7.M7
DDR_B_RAS#: length 147.6
  IN3 w0.076: v3(115.04,48.44) 115.75,47.72 117.28,47.72 117.83,47.17 117.83,45.9 118.07,45.66 120.1,45.66 120.26,45.5 v4(122.93,45.5) 124.98,45.5 125.05,45.57 125.05,45.89 125.13,45.97 125.28,45.97 125.36,45.89 125.36,45.57 125.43,45.5 125.59,45.5 125.66,45.57 125.66,45.7 125.74,45.78 125.89,45.78 125.97,45.7 125.97,45.57 126.04,45.5 126.2,45.5 126.27,45.57 126.27,45.78 126.35,45.85 126.62,45.85 126.78,45.69 127.04,45.69 127.21,45.86 127.21,47.02 127.56,47.36 127.89,47.36 128.37,47.84 v3(128.37,48.25) ; v3(99.03,48.25) 98.69,47.91 98.69,46.66 97.52,45.5 97.32,45.5 97.24,45.57 97.24,45.78 97.16,45.85 97.01,45.85 96.94,45.78 96.94,45.57 96.86,45.5 96.71,45.5 96.63,45.57 96.63,45.78 96.56,45.85 96.4,45.85 96.33,45.78 96.33,45.57 96.25,45.5 96.1,45.5 96.02,45.57 96.02,45.75 95.95,45.83 95.79,45.83 95.72,45.75 95.72,45.57 95.64,45.5 v4(93.6,45.5) 90.93,45.5 90.76,45.66 88.02,45.66 87.73,45.95 87.73,46.41 v3(85.7,48.44) ; 133.33,28.02 133.9,27.45 134.25,27.45 137.17,24.53 137.22,24.53 137.84,23.91 137.84,22.9 138.04,22.7 138.33,22.7 138.66,23.03 139.18,23.03 139.89,22.31 139.89,22 140.14,21.74 140.5,21.74 140.69,21.93 141.27,21.93 141.45,22.12 141.45,22.93 v4(141.86,23.34)
  IN3 w0.165: 133.33,28.02 131.13,30.22 115.99,30.22 114.19,32.02 112.2,32.02 110.59,33.63 110.36,33.63 108.88,32.15 108.64,32.15 108.41,32.39 108.41,32.62 109.89,34.1 109.89,34.34 109.66,34.57 109.42,34.57 107.94,33.09 107.71,33.09 103.36,37.43 103.36,44.78 v3(103.26,44.89)
  IN4 w0.076: v4(122.93,45.5) 119.69,45.5 119.15,44.96 118.87,44.96 118.49,45.33 115.89,45.33 115.24,44.68 114.91,44.68 114.37,44.15 110.06,44.15 109.54,44.67 103.48,44.67 v3(103.26,44.89) 102.87,45.28 102.34,45.28 102.27,45.2 102.27,44.9 102.19,44.82 102.04,44.82 101.96,44.9 101.96,45.2 101.89,45.28 101.73,45.28 101.66,45.2 101.66,44.9 101.58,44.82 101.43,44.82 101.35,44.9 101.35,45.2 101.28,45.28 101.12,45.28 101.05,45.2 101.05,44.9 100.97,44.82 100.82,44.82 100.74,44.9 100.74,45.2 100.67,45.28 100.51,45.28 100.44,45.2 100.44,44.9 100.36,44.82 100.21,44.82 100.13,44.9 100.13,45.2 100.06,45.28 99.9,45.28 99.83,45.2 99.83,44.9 99.75,44.82 99.6,44.82 99.52,44.9 99.52,45.2 99.45,45.28 99.29,45.28 99.22,45.2 99.22,44.72 99.14,44.64 96.3,44.64 96.22,44.72 96.22,44.91 96.14,44.98 95.99,44.98 95.91,44.91 95.91,44.72 95.84,44.64 95.69,44.64 95.61,44.72 95.61,45.39 95.53,45.47 95.38,45.47 95.31,45.39 95.31,44.72 95.23,44.64 95.08,44.64 95,44.72 95,45.62 94.92,45.7 94.77,45.7 94.7,45.62 94.7,44.72 94.62,44.64 94.47,44.64 94.39,44.72 94.39,45.67 94.31,45.75 94.16,45.75 94.09,45.67 94.09,44.72 94.01,44.64 93.67,44.64 93.6,44.72 v4(93.6,45.5) ; v4(141.86,23.34) 141.79,23.34 v1(141.57,23.12)
  BOTTOM w0.076: UD5.J3 127.74,48.38 128.29,48.38 128.37,48.3 v3(128.37,48.25) ; v3(103.26,44.89) 103.26,44.37 104.35,43.27 RD68.1 ; UD7.J3 85.27,48.87 v3(85.7,48.44) ; v3(115.04,48.44) 114.61,48.87 UD6.J3 ; v3(99.03,48.25) 99.03,48.3 98.61,48.72 98.07,48.72 UD8.J3
DDR_B_WE#: length 143.3
  IN3 w0.076: 134.3,27.88 134.3,27.87 134.32,27.85 134.32,27.85 134.5,27.68 134.62,27.68 134.77,27.52 134.8,27.52 137.58,24.74 138.34,24.74 138.81,24.27 138.81,23.88 138.78,23.86 138.78,23.81 138.77,23.8 138.77,23.6 138.88,23.48 138.89,23.48 138.97,23.41 139.23,23.41 140.02,22.62 v4(140.34,22.62) ; v3(84.9,50.11) 84.9,49.88 84.98,49.8 85.77,49.8 85.99,50.02 86.17,50.02 86.24,49.95 86.24,49.6 86.31,49.52 86.47,49.52 86.54,49.6 86.54,49.87 86.62,49.94 86.77,49.94 86.85,49.87 86.85,49.6 86.92,49.52 87.08,49.52 87.15,49.6 87.15,49.87 87.23,49.94 90.15,49.94 90.23,49.87 90.23,49.62 90.3,49.55 90.57,49.55 90.64,49.62 90.64,49.87 90.72,49.94 91.12,49.94 91.13,49.93 91.42,49.93 91.49,49.85 91.49,49.65 91.57,49.57 v4(91.81,49.57) 95.39,49.57 95.47,49.5 96.09,49.5 96.22,49.63 97.19,49.63 97.87,50.31 97.87,51.38 98.27,51.78 98.56,51.78 98.76,51.58 98.76,51.3 98.38,50.92 v3(98.28,50.92) ; v3(127.62,50.92) 127.8,50.92 128.09,51.21 128.09,51.58 127.89,51.78 127.55,51.78 127.19,51.43 127.19,50.3 126.72,49.83 125.58,49.83 125.33,49.57 v4(121.14,49.57) 120.91,49.57 120.83,49.65 120.83,49.85 120.75,49.93 120.46,49.93 120.45,49.94 120.06,49.94 119.98,49.87 119.98,49.6 119.9,49.52 119.64,49.52 119.56,49.6 119.56,49.87 119.48,49.94 116.56,49.94 116.49,49.87 116.49,49.6 116.41,49.52 116.26,49.52 116.18,49.6 116.18,49.87 116.11,49.94 115.95,49.94 115.88,49.87 115.88,49.6 115.8,49.52 115.65,49.52 115.57,49.6 115.57,49.95 115.51,50.02 115.32,50.02 115.1,49.8 114.32,49.8 114.24,49.88 v3(114.24,50.11)
  IN3 w0.165: v3(104.38,48.86) 104.38,48.2 104.76,47.82 104.76,46.93 104.28,46.45 104.28,41.03 104.86,40.44 104.86,40.21 104.16,39.51 104.16,39.33 104.45,39.04 104.63,39.04 105.33,39.74 105.56,39.74 105.8,39.51 105.8,39.27 104.4,37.88 104.4,37.64 104.63,37.41 104.87,37.41 106.26,38.81 106.5,38.81 106.73,38.57 106.73,38.34 105.33,36.94 105.33,36.71 105.57,36.47 105.8,36.47 107.2,37.87 107.43,37.87 112.6,32.71 114.56,32.71 116.37,30.91 131.7,30.91 134.3,28.31 134.3,27.88
  IN4 w0.076: v4(121.14,49.57) 120.84,49.87 120.52,49.87 120.31,50.08 115.64,50.08 115.16,50.56 110.54,50.56 109.62,49.65 105.12,49.65 105.04,49.57 105.04,48.94 104.96,48.86 v3(104.38,48.86) 104.09,48.86 104.05,48.9 100.4,48.9 100.32,48.98 100.32,49.38 100.25,49.46 96.61,49.46 96.61,49.45 96.57,49.41 95.47,49.41 95.37,49.51 94.78,49.51 94.68,49.4 94.68,48.73 94.54,48.6 93.13,48.6 93,48.47 92.85,48.47 92.77,48.54 92.77,48.98 92.69,49.05 92.54,49.05 92.47,48.98 92.47,48.54 92.39,48.47 92.24,48.47 92.16,48.54 92.16,49.09 92.08,49.17 91.93,49.17 91.86,49.09 91.86,48.54 91.78,48.47 91.3,48.47 91.12,48.65 91.12,49.12 91.58,49.57 v4(91.81,49.57) ; v1(140.7,22.62) v4(140.34,22.62)
  BOTTOM w0.076: v3(127.62,50.92) 127.22,50.52 UD5.L3 ; UD6.L3 114.61,50.48 v3(114.24,50.11) ; v3(84.9,50.11) 85.27,50.48 UD7.L3 ; RD76.1 106.26,46.98 v3(104.38,48.86) ; UD8.L3 97.88,50.52 v3(98.28,50.92)
DDR_CHA_EN: length 13.6
  IN4 w0.076: v1(130.38,12.97) 130.24,12.97 130,12.73 129.52,12.73 129.47,12.68 128.71,12.68 128.46,12.43 128.27,12.43 128.27,12.43 126.52,12.43 126.15,12.06 124.77,12.06 124.25,12.58 123.66,12.58 122.86,13.38 122.01,13.38 121.24,12.61 121.15,12.61 v1(120.79,12.26)
  BOTTOM w0.076: v1(120.79,12.26) 120.77,12.28 120.77,12.46 120.49,12.74 RH99.1 119.85,12.74 RH102.1
DDR_CHB_EN: length 13.7
  IN4 w0.076: v1(119.05,9.49) 119.51,9.49 121.01,10.99 121.51,10.99 121.91,11.38 122.69,11.38 122.72,11.35 123.97,11.35 124.39,10.93 125.45,10.93 125.81,10.57 126.1,10.57 126.42,10.25 127.79,10.25 128.53,11 128.53,11.08 128.93,11.47 v1(128.93,11.63)
  BOTTOM w0.076: RH101.1 118.37,10.61 RH103.1 119.05,9.49 v1(119.05,9.49)
DDR_PG_CNTL: length 13.9
  IN3 w0.076: v4(146.37,21.31) 146.37,23.17 146.09,23.46 146.09,25.63 146.26,25.81 146.26,27.65 145.39,28.53 145.39,28.69 v4(145.27,28.81)
  IN4 w0.076: v1(145.35,29.74) 145.35,28.88 v4(145.27,28.81) ; v1(146,21.35) 146.33,21.35 v4(146.37,21.31)
  BOTTOM w0.076: v1(145.35,29.74) 145.81,30.19 v2(146.25,30.19) 147.94,30.19 148.12,30.37 UC1.2 ; v1(146,21.35) 145.99,21.35 145.9,21.45 UCPU1.BL14
DDR_PWROK: length 172.2
  IN1 w0.076: v4(297.24,84.07) 297.52,83.79 298.47,83.79 299.29,82.97 299.29,82.85 299.29,77.27 300.1,76.46 300.1,70.5 299.67,70.07 299.67,66.7 300.1,66.27 300.1,65.09 299.54,64.53 299.54,59.11 297.08,56.65 297.08,54.71 296.49,54.13 296.49,48.52 296.34,48.37 296.34,46.59 295.78,46.03 295.78,45 296.24,44.54 296.24,22.58 289.68,16.03 289.68,15.31 289.78,15.21 289.78,14.8 284.62,9.63 284.62,6.85 282.96,5.19 266.1,5.19 252.66,18.63 250.11,18.63 249.39,19.36 241.99,19.36 239.91,17.28 239.11,17.28 236.76,14.93 223.4,14.93 222.74,15.59 222.74,18.81 221.88,19.68 v3(221.88,25.19)
  IN4 w0.254: v4(297.24,84.07) 297.47,83.84 v1(297.47,83.61)
  BOTTOM w0.076: PR604.2 222.86,24.22 223.62,23.46 v2(224.65,23.46)
  BOTTOM w0.203: 221.46,25.61 221.1,25.96 PU600.10
  BOTTOM w0.254: PR604.2 v3(221.88,25.19) 221.46,25.61
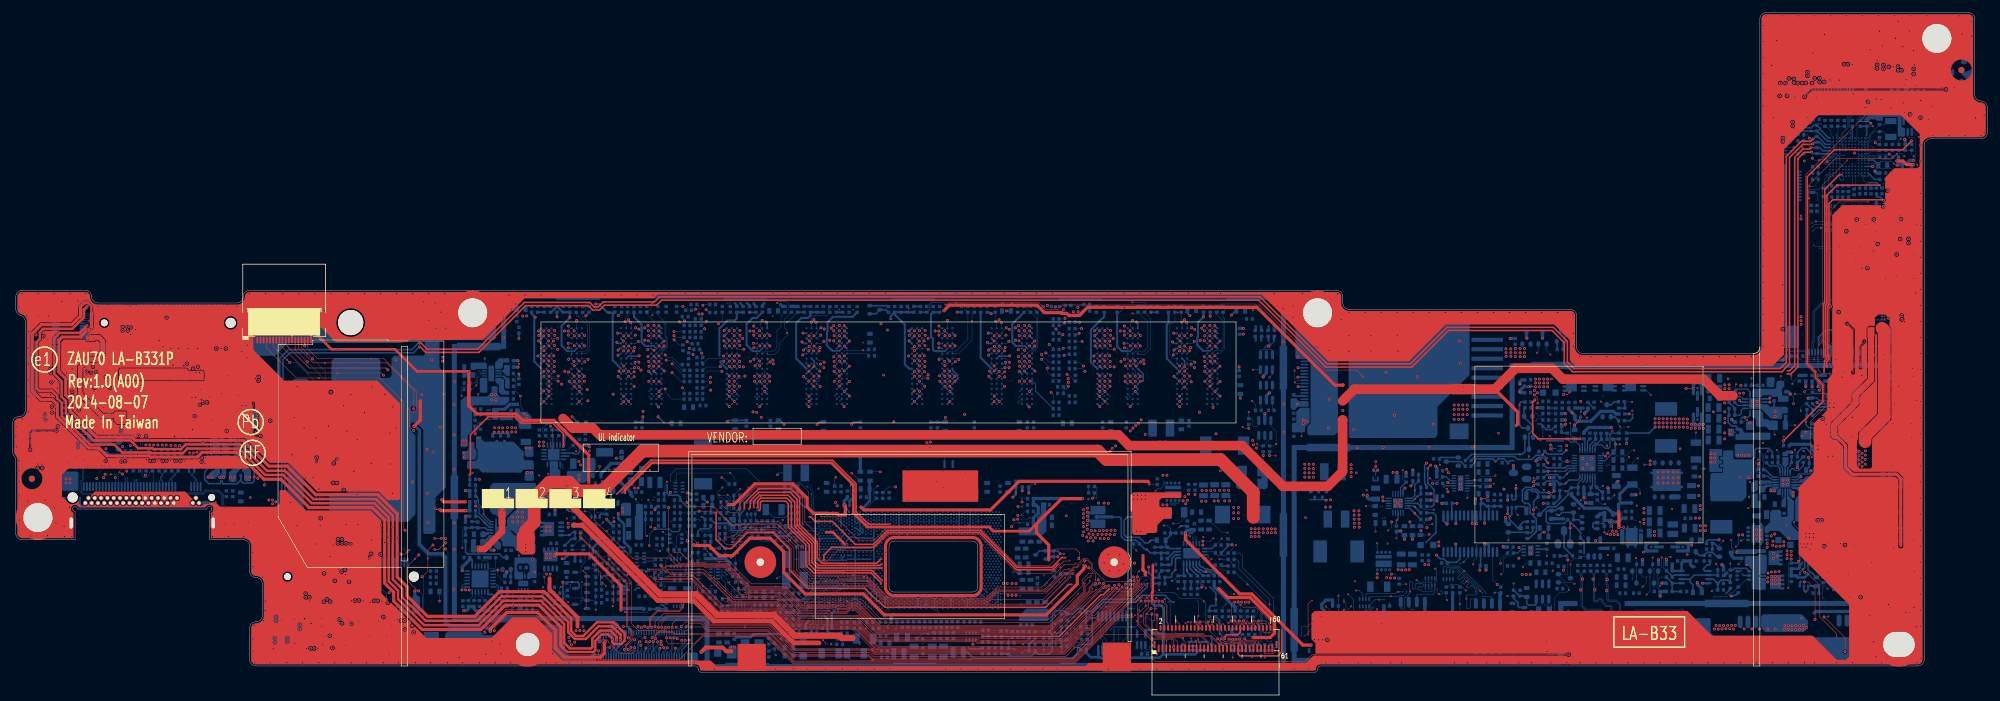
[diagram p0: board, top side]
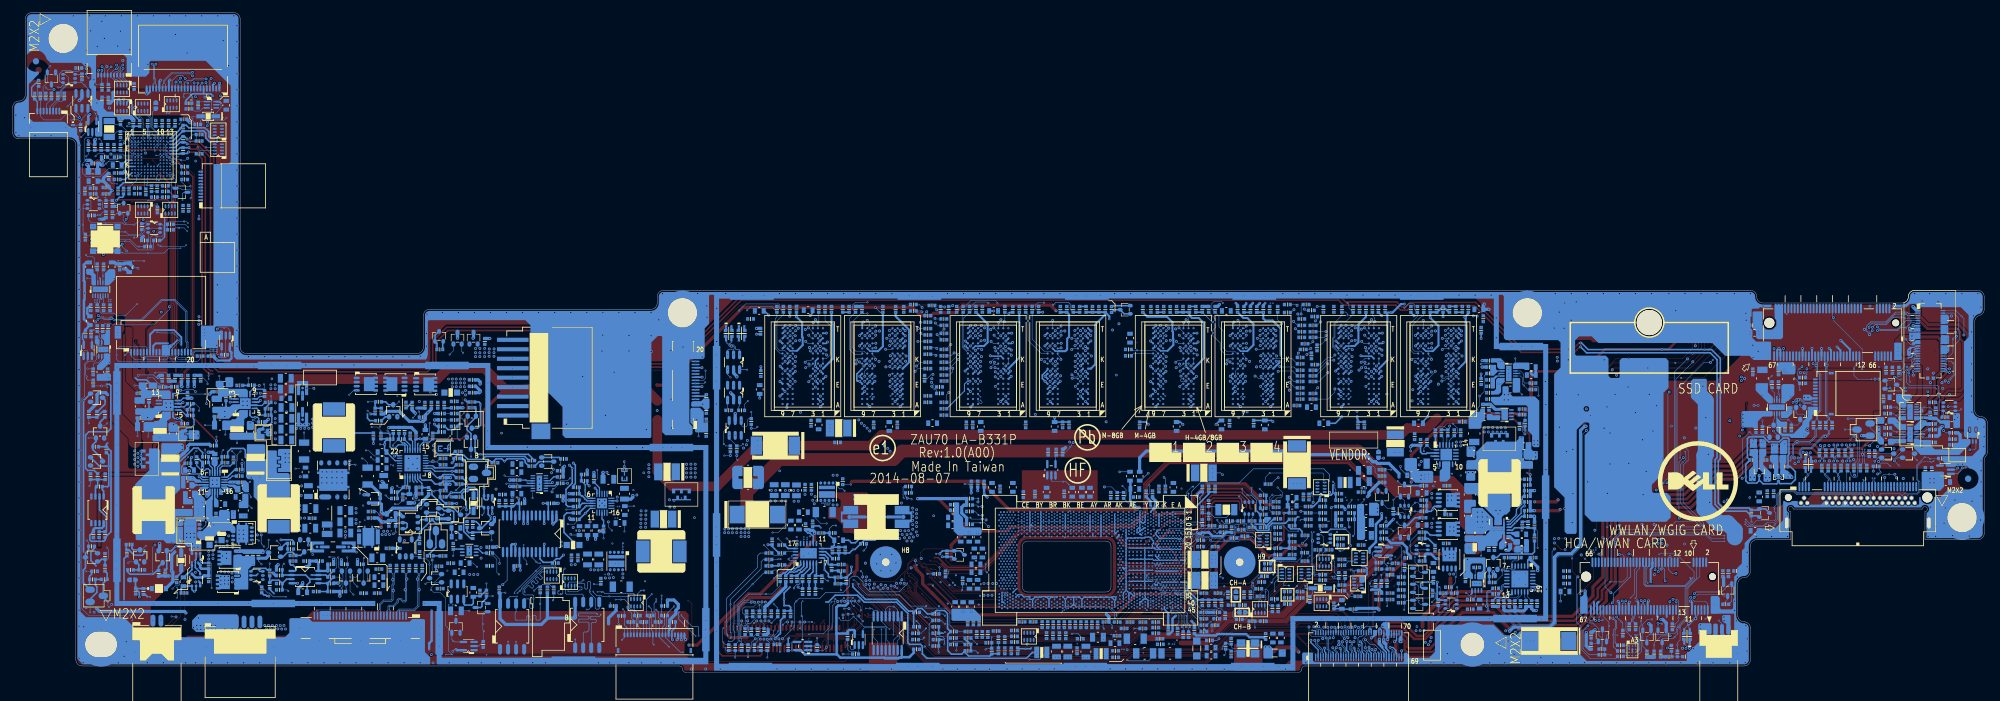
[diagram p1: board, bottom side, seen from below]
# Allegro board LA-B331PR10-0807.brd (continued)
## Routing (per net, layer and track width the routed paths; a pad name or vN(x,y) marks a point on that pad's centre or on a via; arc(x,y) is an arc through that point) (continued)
DEAD_BATT#: length 223.5
  TOP w0.076: v9(288.63,5.68) 288.63,6.13 285.98,8.77 285.98,13.75 283.9,15.84 v3(283.58,15.84) ; v2(242.15,34.57) 242.15,33.99 v3(242.96,33.18)
  GND1 w0.076: v10(288.34,5.44) 288.4,5.44 v9(288.63,5.68)
  IN1 w0.076: v10(288.34,5.44) 288.53,5.63 v4(288.71,5.63) 288.92,5.63 294.41,11.12 294.41,11.8 297.03,14.42 297.03,18.78 299.51,21.27 299.51,49.73 300.16,50.37 300.16,54.53 301.34,55.72 301.34,85.05 301.88,85.59 301.88,86.83 v4(302.08,87.02)
  IN2 w0.254: 265.71,17.76 263.34,17.76 261.42,15.84 259.12,15.84 257.87,14.6 238.07,14.6 236.89,15.78 236.89,22.7 239.3,25.11 242.44,25.11 243.81,26.48 243.81,32.31 242.96,33.16 v3(242.96,33.18) ; 265.71,17.76 266.03,17.43 268.45,17.43 268.77,17.11 268.77,15.59 269.28,15.08 271.96,15.08 273.4,13.63 274.04,13 274.04,12.81 275.13,11.71 281.15,11.71 282.23,12.79 282.23,14.51 283.56,15.84 v3(283.58,15.84) 283.85,15.84 286.18,18.17 286.18,19.48 v3(286.68,19.97) ; 265.71,17.76 v3(265.71,20.14)
  IN3 w0.076: v4(302.08,87.02) 301.97,86.91 300.48,86.91 299.23,88.16 295.07,88.16 294.7,87.79 293.3,87.79 291.15,85.63 290.64,85.63 v4(290.51,85.75)
  IN4 w0.076: v1(290.41,85.23) 290.41,85.65 v4(290.51,85.75)
  BOTTOM w0.076: U38.B9 289.86,84.38 289.86,84.76 290.33,85.23 v1(290.41,85.23)
  BOTTOM w0.254: 288.34,16.18 288.11,16.41 PQ54.2 287.39,19.25 v3(286.68,19.97) 286.13,19.97 285.82,19.66 PD701.1 ; PQ52.2 v3(265.71,20.14) ; PR67.1 231.46,34.19 237.68,34.19 238.15,33.72 240.42,33.72 241.08,34.38 242.18,34.38 PR94.2 242.68,33.46 v3(242.96,33.18)
DEBUG_UART_TX: length 304.5
  IN3 w0.076: v3(298.92,95.37) 299.18,95.1 299.18,91.74 301.57,89.35 302.96,89.35 303.35,88.96 303.35,86.73 301.44,84.83 301.44,13.01 290.59,2.15 259.02,2.15 258.96,2.21 206.67,2.21 206.38,1.92 204.66,1.92 204.04,1.3 121.98,1.3 119.19,4.09 119.19,5.21 116.01,8.39 116.01,10.11 114.45,11.67 114.45,11.99 114.15,12.3 113.7,12.3 113.43,12.03 113.43,11.48 114.17,10.75 v4(114.17,10.64)
  IN4 w0.076: v1(129.36,11.88) 128.84,11.88 128.6,11.64 128.42,11.64 128.15,11.38 127.37,11.38 127.12,11.13 125.9,11.13 125.89,11.12 124.42,11.12 124.03,11.5 122.87,11.5 122.83,11.54 121.84,11.54 121.45,11.14 120.95,11.14 119.55,9.74 118.84,9.74 118.73,9.86 115.2,9.86 114.41,10.64 v4(114.17,10.64)
  BOTTOM w0.076: JDEG1.9 298.97,95.32 v3(298.92,95.37)
DEVSLP0: length 83.6
  IN4 w0.076: v1(53.74,14.16) 53.85,14.06 61.26,14.06 63.03,12.29 66.3,12.29 68.51,14.5 78.49,14.5 78.86,14.13 86.05,14.13 86.76,13.42 95.53,13.42 95.82,13.12 96.8,13.12 97.02,12.9 98,12.9 98.26,12.64 100.43,12.64 100.74,12.95 102.63,12.95 103.42,12.16 107.54,12.16 107.64,12.26 109.01,12.26 109.8,13.05 113.78,13.05 114.1,13.37 114.36,13.37 114.44,13.44 116.06,13.44 116.08,13.43 116.46,13.43 116.49,13.46 119.58,13.46 121.24,15.12 v1(121.44,15.12) 123.37,15.12 123.67,14.81 126.18,14.81 126.41,14.59 127.67,14.59 127.97,14.9 128.23,14.9 128.47,15.14 v1(128.63,15.14)
  BOTTOM w0.076: v1(53.74,14.16) 53.99,14.41 53.99,16.4 53.5,16.89 JNGFF2.30 ; v1(121.44,15.12) 121.19,15.12 v2(120.98,14.9)
DEVSLP1: length 159.3
  IN1 w0.076: v4(19.14,36) 19.14,35.54 20.04,34.64 27.22,34.64 27.47,34.39 29.24,34.39 29.55,34.71 38.34,34.71 45.14,27.91 47.06,27.91 58.16,16.81 64.29,16.81 68.92,12.18 72.54,12.18 73.42,11.3 84.48,11.3 85.44,10.33 88.02,10.33 88.35,10.66 93.91,10.66 95.12,11.87 98.3,11.87 98.8,11.36 101.19,11.36 102.34,12.5 109.07,12.5 111.18,14.61 114.11,14.61 114.5,14.22 116.59,14.22 116.88,13.93 123.35,13.93 123.89,13.39 124.35,13.39 124.93,13.97 126.47,13.97 126.7,13.74 128.83,13.74 129.2,14.12 v4(129.2,14.21)
  IN3 w0.076: v3(24.36,56.18) 24.17,55.99 24.17,41.05 19.14,36.02 v4(19.14,36)
  IN4 w0.076: v1(129.88,14.71) 129.72,14.71 129.48,14.46 129.46,14.46 v4(129.2,14.21)
  BOTTOM w0.076: JNGFF3.30 24.5,56.32 v3(24.36,56.18) 24.36,55.74 19.81,51.2 T51.1
DH_1.35V: length 5.7
  IN4 w1.016: 215.71,20.62 215.71,25.04 216.16,25.49
  BOTTOM w0.076: v1(215.94,19.86) v2(215.94,20.44)
  vias: v1(215.94,19.47) v1(216.47,26.26) v1(216.77,26.26)
DISPOFF#: length 10.8
  IN4 w0.076: v1(256.96,14.13) 260.75,10.34 v1(260.75,8.95)
  BOTTOM w0.076: v1(256.96,14.13) 257.01,14.18 R44.1 257.01,17.99 v2(256.87,18.13)
DL_1.35V: length 9.2
  IN1 w1.016: 217,15.74 217,16.35 218.37,17.72 218.37,22.83
  BOTTOM w0.076: v3(218.22,23.82) 218.22,23.02 v2(217.68,22.47)
  vias: v3(215.94,15.59) v3(215.94,14.98)
DMIC_CLK: length 250.3
  IN2 w0.076: v4(199.48,7.43) 199.35,7.43 197.81,5.9 190.41,5.9 189.21,4.7 169.74,4.7 169.47,4.97 168.09,6.34 154.07,6.34 153.31,7.1 144.7,7.1 143.95,6.36 141.6,6.36 140.55,7.41 134.19,7.41 132.63,5.85 124.03,5.85 122.17,7.7 121.65,7.7 119.66,9.69 111.9,9.69 110.49,11.1 107.24,11.1 106.69,11.65 103.61,11.65 103.41,11.84 102.01,11.84 101.07,12.78 98.92,12.78 98.16,13.54 97.23,13.54 95.78,14.99 94.96,14.99 94.84,14.88 86.78,14.88 86.33,14.43 81.79,14.43 78.94,17.28 68.86,17.28 51.06,35.07 36.26,35.07 23.15,48.18 15.02,48.18 14.94,48.09 13.03,48.09 12.72,47.78 12.29,47.78 12.15,47.64 v3(11.73,47.64)
  IN4 w0.076: v4(199.48,7.43) 199.48,8.15 200.32,8.99 200.32,9.82 203.26,12.77 203.26,32.76 197.88,38.15 197.88,38.7 196.68,39.9 v1(196.68,41.5)
  BOTTOM w0.076: v3(11.73,47.64) 11.68,47.7 JAUD1.49 ; v1(196.68,41.5) 196.68,42.45 v2(196.15,42.98)
DMIC_CLK_R: length 11.6
  IN4 w0.076: v1(204.43,45.75) 203,45.75 200.04,42.79 197.78,42.79 v1(197.46,43.11)
  BOTTOM w0.076: v2(202.89,45.94) 203.08,45.75 v1(204.43,45.75) ; v1(197.46,43.11) 197.46,42.19 197.6,42.05 R300.2
DMIC_DAT: length 250.9
  IN2 w0.076: v4(199.98,7.62) 199.98,7.4 199.58,7 199.13,7 197.87,5.74 190.47,5.74 189.27,4.54 169.42,4.54 167.79,6.18 154.02,6.18 153.65,6.56 144.37,6.56 144.02,6.2 141.4,6.2 141.01,6.6 139.99,6.6 139.33,7.26 134.25,7.26 132.65,5.66 124,5.66 122.11,7.55 121.59,7.55 119.6,9.54 111.84,9.54 110.43,10.94 107.18,10.94 106.62,11.5 103.55,11.5 103.35,11.69 101.95,11.69 101.01,12.63 98.86,12.63 98.1,13.39 97.17,13.39 95.72,14.84 95.02,14.84 94.91,14.72 93.1,14.72 92.26,13.88 86.71,13.88 86.31,14.28 81.71,14.28 78.86,17.12 68.79,17.12 51,34.92 36.2,34.92 23.18,47.94 13.12,47.94 12.63,47.44 v3(12.43,47.44)
  IN4 w0.076: v1(198.71,41.5) 199.45,40.76 199.45,39.34 198.84,38.73 198.84,37.4 203.49,32.75 203.49,12.78 200.47,9.76 200.47,8.11 v4(199.98,7.62)
  BOTTOM w0.076: v2(12.28,46.04) 12.28,46.87 12.43,47.02 v3(12.43,47.44) 12.43,47.71 11.64,48.5 JAUD1.45
DMIC_DAT_R: length 11
  IN4 w0.076: v1(199.36,43.11) 200.15,43.11 203.29,46.25 v1(204.43,46.25)
  BOTTOM w0.076: v1(204.43,46.25) 203.18,46.25 202.86,46.57 v2(202.86,47.79) ; R301.2 199.36,41.77 v1(199.36,43.11)
DOCKPWROUT: length 315.7
  IN2 w0.076: v4(297.65,17.35) 297.98,17.02 297.98,15.05 298.13,14.9 298.13,13.18 295.76,10.8 295.76,9.36 295.37,8.98 294.16,8.98 288.94,3.75 260.77,3.75 259.4,5.12 244.64,5.12 243.66,4.13 236.31,4.13 235.06,5.37 214.2,5.37 213.51,6.06 205.68,6.06 204.55,7.19 202.47,7.19 200.56,5.29 199,5.29 197.73,4.02 169.29,4.02 168.71,4.6 167.45,4.6 166.78,3.94 155.17,3.94 153.09,6.02 144.65,6.02 144.16,5.53 139.39,5.53 138.28,6.65 134.5,6.65 133.06,5.2 123.19,5.2 119.48,8.91 111.77,8.91 110.19,10.48 103.9,10.48 103.15,11.23 99.62,11.23 99.27,11.58 97.96,11.58 97.15,12.39 97.04,12.39 96.12,13.3 92.76,13.3 92.62,13.16 86.55,13.16 86.04,13.67 81.18,13.67 79.26,15.59 v4(78.92,15.59)
  IN4 w0.076: v1(81.06,15.16) 80.64,15.59 v4(78.92,15.59) 78.76,15.59 78.63,15.46 77.02,15.46 v1(76.12,16.36) ; v1(291.61,79.13) 291.97,78.77 291.97,75.08 291.07,74.18 291.07,71.81 291.4,71.48 291.4,67.88 291.15,67.63 291.15,55.68 291.64,55.18 291.64,52.63 291.64,52.63 291.64,51.49 292.72,50.41 293.42,50.41 293.61,50.6 293.89,50.6 294.23,50.26 295.76,50.26 298.35,47.66 298.35,35.21 297.84,34.7 297.84,21.9 297.61,21.66 297.61,17.39 v4(297.65,17.35)
  BOTTOM w0.076: R322.2 81.06,16.4 v1(81.06,15.16) ; U56.5 74.73,16.41 74.88,16.26 75.32,16.26 75.51,16.45 76.03,16.45 v1(76.12,16.36)
DPWROK: length 28.5
  IN1 w0.076: v4(127.77,25.34) 127.07,25.34 126.25,26.17 123.33,26.17 122.48,25.32 122.48,24.76 122.32,24.6 118.38,24.6 118.27,24.71 117.21,24.71 117.03,24.9 114.5,24.9 113.88,24.27 109.49,24.27 109.29,24.47 108.19,24.47 v4(107.02,25.65)
  IN4 w0.076: v4(127.77,25.34) 128.4,25.34 128.77,24.97 128.85,24.97 129.8,24.03 v1(129.8,23.87) ; v1(107.02,25.24) v4(107.02,25.65)
  BOTTOM w0.076: RH74.1 RH64.1 v1(107.02,25.24)
DSWODVREN: length 20.6
  IN4 w0.076: v1(129.13,22.07) 129.13,22.08 128.54,22.67 126.35,22.67 125.82,23.2 124.73,23.2 124.62,23.09 123.82,23.09 123,22.27 118.63,22.27 118.54,22.36 116.48,22.36 115.56,21.43 115.15,21.43 114.69,20.97 114.23,20.97 113.37,20.12 113.23,20.12 112.76,19.66 v1(112.76,19.65)
  BOTTOM w0.076: v1(112.76,19.65) RH81.2 113.22,18.64 v2(113.71,18.14)
DTDK_AC_DET: length 19.3
  IN1 w0.076: v4(298.94,74.76) 298.51,74.33 294.09,74.33 293.04,73.27 v4(291.41,73.27)
  IN4 w0.076: v4(291.41,73.27) 291.38,73.3 291.38,74.28 292.17,75.07 292.17,79.3 292.5,79.63 v1(292.61,79.63) ; v1(298.94,75.29) v4(298.94,74.76)
  BOTTOM w0.076: C272.1 300.65,77.09 299.69,77.09 299.3,76.7 R334.1 R333.2 299.3,75.64 v1(298.94,75.29)
EC_ALWON: length 29.7
  IN4 w0.076: v1(279.21,87.87) 279.92,88.59 279.92,90.03 280.33,90.44 284.35,90.44 285.04,91.13 285.21,91.13 286.35,92.26 288.12,92.26 290.55,89.83 290.55,89.43 290.7,89.28 291.78,88.2 291.78,88.07 292.43,87.42 294.18,87.42 294.57,87.02 294.57,85.08 294.3,84.8 294.3,83.42 293.61,82.74 v1(293.61,82.63)
  BOTTOM w0.076: R356.1 282.75,87.44 282.62,87.57 279.51,87.57 v1(279.21,87.87)
EC_GPIO166: length 7.3
  IN4 w0.076: v1(293.11,80.63) 293.27,80.63 293.53,80.89 294.56,80.89 295.48,79.98 295.48,78.49 295.99,77.97 v1(295.99,77.38)
  BOTTOM w0.076: R349.1 297.28,77.95 296.71,77.38 v1(295.99,77.38)
EC_GPIO222: length 8
  IN4 w0.076: v1(289.62,74.19) 289.66,74.22 289.66,75.83 290.57,76.74 290.57,78.24 290.85,78.53 290.85,78.73 290.61,78.97 v1(290.61,79.13)
  BOTTOM w0.076: v1(289.62,74.19) 290.07,74.19 291.13,73.12 RP12.8
EC_IN_VOLUMEDOWN#: length 24
  IN1 w0.076: v3(283.18,93.34) 282.43,92.59 282.43,90.98 281.67,90.21 v3(281.67,87.16) 282.12,87.16 283.82,85.46 v4(284.64,85.46)
  IN4 w0.076: v4(284.64,85.46) 284.64,85.4 284.01,84.77 284.01,84.22 284.14,84.09 284.52,84.09 284.53,84.08 285.05,84.08 285.27,83.86 285.27,83.56 285.1,83.39 285.1,82.39 285.3,82.19 285.96,82.19 286.64,82.86 287.77,82.86 288.01,82.63 v1(288.11,82.63)
  BOTTOM w0.076: RP16.5 281.08,86.57 v3(281.67,87.16) 281.42,87.42 279.09,87.42 v2(278.65,87.86) ; JSNR1.8 283.28,93.07 283.18,93.17 v3(283.18,93.34)
EC_IN_VOLUMEUP#: length 82.2
  IN1 w0.076: v3(283.02,71.82) 283.65,71.19 288.7,71.19 290.21,72.71 294.67,72.71 296.28,71.1 v4(298.82,71.1) ; v4(281.3,85.08) 281.3,90.56 281.69,90.95 281.69,92.51 v3(282.52,93.34)
  IN4 w0.076: v1(288.61,82.63) 288.35,82.37 287.99,82.37 287.7,82.65 286.93,82.65 286.64,82.37 286.64,81.65 286.46,81.47 286.24,81.47 285.88,81.83 284.68,81.83 283.69,80.84 283.69,80.1 283.7,80.09 283.7,72.51 v3(283.02,71.82) ; v1(280.52,85.07) 280.53,85.08 v4(281.3,85.08) ; v4(298.82,71.1) 298.87,71.1 299.29,71.52 299.29,76.36 299.03,76.61 299.03,78.53 298.71,78.85 298.71,82.77 299.03,83.09 299.03,85.67 298.8,85.9 298.8,89.06 294.66,93.2 290.9,93.2 289.32,94.79 285.21,94.79 284.27,93.85 283.03,93.85 v3(282.52,93.34)
  BOTTOM w0.076: JSNR1.7 282.78,93.08 v3(282.52,93.34) ; v3(283.02,71.82) v2(283.02,72.33)
EC_MUTE#: length 406.2
  IN2 w0.076: v4(285.89,88.54) 285.89,88.32 285.93,88.28 285.93,81.84 285.68,81.6 285.68,77.05 286.39,76.35 286.39,61.96 293.28,55.07 293.28,53.92 293.85,53.35 293.85,53.1 298.81,48.15 298.81,20.53 298.02,19.74 298.02,18.39 297.22,17.59 297.22,15.5 297.98,14.74 297.98,13.24 288.8,4.06 260.92,4.06 259.53,5.44 244.32,5.44 243.39,4.51 236.5,4.51 235.31,5.7 214.39,5.7 213.7,6.39 205.78,6.39 204.64,7.53 202.38,7.53 200.44,5.59 198.84,5.59 197.57,4.33 169.42,4.33 168.84,4.91 167.33,4.91 166.81,4.4 155.58,4.4 153.57,6.4 144.45,6.4 143.91,5.87 140.42,5.87 139.19,7.1 134.31,7.1 132.71,5.5 123.94,5.5 122.08,7.36 121.56,7.36 119.53,9.39 111.77,9.39 110.37,10.79 104.04,10.79 103.29,11.54 101.88,11.54 100.94,12.48 98.79,12.48 98.03,13.23 97.05,13.23 96.08,14.2 94.45,14.2 94.1,14.56 93.15,14.56 92.32,13.73 86.64,13.73 86.24,14.13 81.65,14.13 78.8,16.97 68.73,16.97 50.94,34.76 36.13,34.76 23.3,47.59 15.56,47.59 v3(14.71,46.74)
  IN4 w0.076: v1(291.11,83.63) 290.85,83.89 290.69,83.89 290.2,84.38 290.02,84.38 289.85,84.55 289.85,86.76 289.01,87.6 289.01,88.46 288.44,89.03 287.84,89.03 287.13,88.32 286.04,88.32 285.89,88.47 v4(285.89,88.54)
  BOTTOM w0.076: DA8.2 15.24,46.21 v3(14.71,46.74) 14.42,46.74 14.06,46.39 v2(13.64,46.39)
EC_PROCHOT#: length 7.2
  BOTTOM w0.076: U38.M12 287.86,78.88 287.42,78.88 287.28,78.74 287.28,78.63 286.74,78.08 Q23.2 285.97,76.69 285.72,76.44 284.4,76.44 284.17,76.22 284.17,75.25 v2(284.33,75.1)
EC_SMCA: length 33.5
  IN4 w0.076: v1(233.41,49.67) 234.09,48.99 240.17,48.99 240.55,49.37 240.55,52.48 240.89,52.82 241.57,52.82 242.17,52.22 242.17,52.08 242.25,52 v1(242.75,52) 241.97,51.22 241.97,48.86 240.83,47.72 238.71,47.72 238.03,47.05 238.03,43.17 240.62,40.58 240.85,40.58 240.99,40.72 240.99,41.05 241.03,41.09 v1(241.03,41.12)
  BOTTOM w0.076: v2(243.34,50.33) 242.75,50.93 v1(242.75,52) ; v1(241.03,41.12) 241.08,41.07 241.08,41.04 241.54,40.58 241.74,40.58 PR1.1 ; JBAT1.7 v1(233.41,49.67)
EC_SMDA: length 32.8
  IN4 w0.076: v1(241.04,39.84) 241.04,39.89 240.99,39.94 240.99,40.22 240.78,40.43 240.56,40.43 237.88,43.11 237.88,47.11 238.64,47.87 240.76,47.87 241.82,48.93 241.82,51.63 v1(241.45,52) 241.95,52 242.02,52.08 242.02,52.15 241.5,52.67 240.96,52.67 240.7,52.42 240.7,49.31 240.23,48.84 234.08,48.84 v1(233.41,48.17)
  BOTTOM w0.076: v2(241.22,50.61) 241.45,50.84 v1(241.45,52) ; JBAT1.6 v1(233.41,48.17) ; PR2.1 241.84,40.28 241.44,40.28 241.08,39.92 241.08,39.89 v1(241.04,39.84)
EC_WAKE#: length 291.5
  TOP w0.076: v5(100.49,16.35) 103.01,16.35 103.42,15.94 103.81,15.94 104.17,15.58 109.41,15.58 113.89,11.1 121.1,11.1 124.18,8.02 133.68,8.02 136.57,5.13 152.73,5.13 153,4.86 166.09,4.86 166.35,5.13 166.37,5.13 171.76,10.51 171.99,10.51 174.74,13.26 v3(174.74,13.32)
  IN1 w0.076: v4(99.02,16.1) 99.25,16.1 99.5,16.35 v5(100.49,16.35)
  IN3 w0.076: v4(284.29,81.98) 283.6,81.3 283.6,60.07 292.83,50.84 292.83,48.83 293.37,48.29 293.37,48 295.45,45.92 296.26,45.92 296.45,45.73 296.45,44.65 296.8,44.31 296.8,21.76 291.52,16.49 290.57,16.49 288.35,14.27 287.2,14.27 286.32,13.39 285.57,13.39 285.4,13.23 284.3,13.23 283.38,12.3 282.56,12.3 281.33,11.07 273.47,11.07 273.13,11.41 267.99,11.41 267.1,10.52 251.04,10.52 247.62,13.94 237.25,13.94 236.75,14.45 232.77,14.45 232.21,15 228.09,15 227.05,13.96 227.05,13.22 224.34,10.5 213.55,10.5 213.11,10.95 200.58,10.95 199.59,11.94 192.48,11.94 191.36,10.82 188.95,10.82 188.59,11.18 187.48,11.18 187.48,11.18 184.99,11.18 184.6,11.57 184.27,11.57 183.15,12.69 175.09,12.69 174.74,13.05 v3(174.74,13.32)
  IN4 w0.076: v1(286.34,81.71) 286.07,81.98 v4(284.29,81.98) ; v1(98.64,16.1) v4(99.02,16.1)
  BOTTOM w0.076: v1(286.34,81.71) 286.67,81.39 287.43,81.39 287.44,81.38 287.77,81.38 287.86,81.47 287.86,81.78 287.96,81.88 288.27,81.88 288.36,81.97 288.36,83.38 U38.C12 ; v2(175.25,13.11) 174.95,13.11 v3(174.74,13.32)
EC_WAKE#_R: length 34.9
  IN4 w0.076: v1(100.02,16.13) 100.02,16.28 100.41,16.66 101.21,16.66 101.3,16.57 107.15,16.57 107.83,17.25 110.87,17.25 111.94,18.33 113.32,18.33 113.82,18.83 115.33,18.83 117.07,20.57 117.7,20.57 118.21,20.57 120.47,20.57 120.66,20.76 124.07,20.76 124.55,21.24 124.92,21.24 125.07,21.39 127.53,21.39 127.73,21.59 128.13,21.59 128.22,21.51 128.63,21.51 128.75,21.39 128.83,21.39 129.14,21.07 129.45,21.07 129.76,20.77 v1(129.88,20.77)
  BOTTOM w0.076: RP8.5 100.4,14.81 100.49,14.9 100.49,14.94 100.11,15.32 100.11,16.04 v1(100.02,16.13) 99.59,16.13 RH93.1
EDP_AUXN: length 134.3
  IN1 w0.066: v4(141.87,12.08) 141.96,11.99 142.25,11.99 142.38,11.87 142.38,11.58 143.01,10.94 143.98,10.94 144.59,10.33 145.76,10.33 147.66,10.33 151.11,6.88 153.83,6.88 154.82,5.9 162.99,5.9 164.97,7.88 169.78,7.88 171.62,6.05 180.16,6.05 180.64,6.53 181.93,6.53 182.39,7 184.47,7 184.68,6.79 186.28,6.79 186.65,7.16 187.62,7.16 187.98,6.79 191.44,6.79 191.86,7.21 197.04,7.21 198.08,8.25 199.63,8.25 200.93,9.55 244.19,9.55 250.4,15.77 250.49,15.77 251.29,16.57 251.84,16.57 252,16.73 252,16.78 v4(252.18,16.96)
  IN3 w0.076: v4(136.17,20.41) 135.98,20.21 135.98,20.08 136.04,20.02 136.7,20.02 137.15,19.57 137.66,19.57 138.33,18.9 138.33,13.03 138.99,12.37 141.05,12.37 141.49,11.93 141.72,11.93 v4(141.87,12.08)
  IN4 w0.066: v4(252.18,16.96) 252.18,16.89 252.32,16.76 252.59,16.76 v1(252.77,16.93) ; v4(136.17,20.41) 136,20.41 135.77,20.64 v1(135.77,20.81)
EDP_AUXN_CONN: length 9
  BOTTOM w0.097: JLVDS1.10 254.75,9.63 254.45,9.93 254.45,10.81 253.81,11.44 252.59,11.44 252.49,11.55 252.49,13.85 252.32,14.02 252.32,14.31 252.34,14.34 v12(252.34,14.67) 252.34,15 252.32,15.03 252.32,15.57 C14.2
EDP_AUXP: length 134.3
  IN1 w0.066: v4(141.87,11.6) 141.87,11.61 142.11,11.86 142.2,11.86 142.24,11.81 142.24,11.52 142.96,10.81 143.92,10.81 144.53,10.2 145.7,10.2 147.61,10.2 151.05,6.75 153.78,6.75 154.76,5.77 163.04,5.77 165.02,7.75 169.73,7.75 171.56,5.91 180.21,5.91 180.7,6.4 181.98,6.4 182.45,6.86 184.41,6.86 184.62,6.65 186.34,6.65 186.71,7.02 187.56,7.02 187.93,6.65 191.49,6.65 191.91,7.07 197.1,7.07 198.14,8.12 199.69,8.12 200.99,9.41 244.24,9.41 250.46,15.63 250.55,15.63 251.34,16.43 v4(252.18,16.43)
  IN3 w0.076: v4(135.47,20.54) 135.82,20.19 135.82,20.02 135.98,19.86 136.64,19.86 137.09,19.41 137.59,19.41 138.17,18.83 138.17,12.96 138.93,12.21 140.98,12.21 141.42,11.77 141.7,11.77 v4(141.87,11.6)
  IN4 w0.066: v4(252.18,16.43) 252.05,16.43 251.75,16.73 v1(251.75,16.93) ; v1(135.17,20.81) 135.2,20.81 v4(135.47,20.54)
EDP_AUXP_CONN: length 8.8
  BOTTOM w0.097: JLVDS1.9 254.25,10.73 253.73,11.24 252.51,11.24 252.29,11.47 252.29,12.65 252.26,12.67 v12(252.26,12.94) 252.26,13.25 252.29,13.27 252.29,13.77 252.12,13.94 252.12,15.65 C13.2
EDP_DISP: length 29.5
  IN2 w0.076: v4(133.07,19.4) 133.07,19.29 132.27,18.48 131.05,18.48 130.93,18.37 129.99,18.37 129.76,18.37 129.75,18.37 128.76,18.37 128.61,18.52 127.25,18.52 127,18.52 126.77,18.29 126.07,18.29 126.03,18.33 124.83,18.33 124.51,18.65 123.22,18.65 120.27,21.6 116.57,21.6 116.5,21.53 115.37,21.53 113.92,20.08 108.65,20.08 v4(108.55,20.18)
  IN4 w0.076: v4(108.55,20.18) 108.68,20.05 v1(108.97,20.05) ; v4(133.07,19.4) 132.74,19.06 v1(132.73,19.06)
  BOTTOM w0.076: RC2.2 108.49,19.56 108.97,20.04 v1(108.97,20.05)
EDP_HPD: length 184.6
  IN1 w0.076: v4(95.57,11.45) 95.83,11.71 98.23,11.71 98.74,11.21 101.26,11.21 102.4,12.35 109.13,12.35 110.73,13.94 114.11,13.94 114.23,14.07 116.48,14.07 116.77,13.78 123.28,13.78 123.83,13.24 124.41,13.24 125,13.82 126.41,13.82 126.64,13.59 130.19,13.59 130.35,13.75 130.35,14.06 130.41,14.12 130.5,14.21 130.5,14.23 130.64,14.37 130.97,14.37 131.61,15 131.62,15 132.12,15.5 132.12,16.1 132.17,16.15 132.17,16.18 v4(132.17,16.18)
  IN3 w0.076: v4(240.09,6.88) 239.9,7.07 234.07,7.07 231.05,4.04 205.92,4.04 205.66,3.79 202.27,3.79 202,4.06 198.15,4.06 197.43,3.35 165.83,3.35 164.08,5.09 164.08,7.26 161.42,9.92 153.36,9.92 152.98,9.54 152.6,9.54 140.46,9.54 140.23,9.77 138.45,9.77 137.3,10.93 136.08,10.93 134.17,12.83 134.17,12.98 134.17,12.98 134.17,13.24 134.17,13.24 134.17,13.36 134.17,14.39 132.34,16.22 132.22,16.22 v4(132.17,16.18)
  IN4 w0.076: v1(132.12,15.56) 132.17,15.61 v4(132.17,16.18) ; v1(258.25,8.95) 257.95,8.65 255.89,8.65 255.88,8.65 255.62,8.65 255.61,8.65 246.19,8.65 244.52,10.32 244.52,11.08 243.83,11.78 241.21,11.78 240.52,11.09 240.52,7.31 v4(240.09,6.88) ; v1(94.98,11.52) 95.01,11.5 95.51,11.5 v4(95.57,11.45)
  BOTTOM w0.076: v1(94.98,11.52) v2(94.98,10.48)
EDP_TXN_P0: length 134.8
  IN1 w0.066: v4(250.23,17.11) 250,16.88 249.14,16.88 248.79,17.24 247.7,17.24 241.32,10.86 197.85,10.86 196.44,9.44 191.33,9.44 190.93,9.83 183.46,9.83 181.39,7.76 180.11,7.76 179.6,7.25 172.24,7.25 170.4,9.09 163.34,9.09 161.31,7.06 155.45,7.06 154.29,8.22 151.55,8.22 147.78,11.99 145.68,11.99 145.62,11.93 144.99,11.93 v4(144.82,12.11)
  IN3 w0.076: v4(134.86,20.54) 134.86,20.53 134.4,20.07 134.4,19.87 134.96,19.32 136.22,19.32 136.22,19.32 136.96,18.58 136.96,15.7 137.3,15.36 137.3,14.81 136.69,14.2 136.69,12.72 138.63,10.78 140.96,10.78 141.11,10.63 143.09,10.63 144.18,11.73 144.41,11.73 144.79,12.11 v4(144.82,12.11)
  IN4 w0.066: v1(134.56,20.81) 134.56,20.68 134.69,20.54 v4(134.86,20.54) ; v4(250.23,17.11) 249.85,17.11 249.72,16.98 v1(249.72,16.93)
EDP_TXN_P0_CONN: length 10
  BOTTOM w0.097: C9.2 250.15,15.58 250.15,15.06 250.13,15.03 v12(250.13,14.76) 250.13,14.47 250.15,14.44 250.15,11.33 250.35,11.13 250.76,11.13 251.13,11.5 251.35,11.5 251.48,11.38 251.48,11.09 252.14,10.42 252.84,10.42 252.9,10.36 252.9,9.9 252.75,9.74 JLVDS1.6
EDP_TXN_P1: length 134.5
  IN1 w0.066: v4(248.07,16.6) 248.3,16.6 248.35,16.55 248.35,15.66 247.85,15.17 247.46,15.17 247.09,15.54 246.84,15.54 246.66,15.37 246.66,15.12 247.03,14.75 247.03,14.66 246.89,14.51 246.8,14.51 246.42,14.89 246.18,14.89 246,14.71 246,14.47 246.37,14.09 246.37,14 246.23,13.86 246.14,13.86 245.82,14.18 245.57,14.18 245.39,14.01 245.39,13.76 245.72,13.43 245.72,13.34 242.51,10.13 199.76,10.13 199.63,10.26 198.21,10.26 196.76,8.81 190.92,8.81 190.48,9.25 183.74,9.25 181.61,7.12 180.35,7.12 179.86,6.63 171.98,6.63 170.09,8.51 163.63,8.51 161.61,6.48 155.09,6.48 154.06,7.51 151.37,7.51 148.26,10.62 144.87,10.62 143.97,11.52 143.71,11.52 143.64,11.59 143.64,11.67 143.3,12.01 143.29,12.01 v4(143.29,12.01)
  IN3 w0.076: v4(135.48,20) 135.48,19.73 135.53,19.67 136.41,19.67 137.98,18.1 137.98,15.05 137.46,14.53 137.46,13.81 137.82,13.44 137.82,13.1 139.13,11.78 140.82,11.78 141.43,11.17 142.04,11.17 142.55,11.68 142.96,11.68 143.29,12.01 v4(143.29,12.01)
  IN4 w0.066: v1(135.77,20.26) 135.72,20.26 135.47,20.01 135.47,20 v4(135.48,20) ; v1(247.69,16.93) 247.93,16.93 248.07,16.79 v4(248.07,16.6)
EDP_TXN_P1_CONN: length 10
  BOTTOM w0.097: JLVDS1.3 251.25,9.57 251.33,9.66 251.33,9.74 251.26,9.81 248.85,9.81 248.19,10.47 248.19,12.73 248.17,12.75 v12(248.17,13.07) 248.17,13.34 248.19,13.36 248.19,15.14 248.07,15.27 248.07,15.64 C7.2
EDP_TXP_P0: length 134.8
  IN1 w0.066: v4(250.18,16.58) 250.01,16.75 249.09,16.75 248.73,17.1 247.76,17.1 241.38,10.72 197.91,10.72 196.49,9.31 191.27,9.31 190.88,9.7 183.52,9.7 181.45,7.63 180.17,7.63 179.65,7.12 172.18,7.12 170.34,8.96 163.4,8.96 161.37,6.93 155.39,6.93 154.23,8.09 151.49,8.09 147.72,11.85 145.74,11.85 145.68,11.8 145.16,11.8 145,11.63 v4(145,11.62)
  IN3 w0.076: v4(134.29,20.49) 134.24,20.45 134.24,19.81 134.89,19.16 136.15,19.16 136.16,19.16 136.8,18.52 136.8,15.63 137.14,15.29 137.14,14.88 136.53,14.27 136.53,12.66 138.57,10.62 140.9,10.62 141.04,10.48 143.15,10.48 144.25,11.57 144.48,11.57 144.66,11.75 144.87,11.75 v4(145,11.62)
  IN4 w0.066: v1(250.73,16.93) 250.68,16.93 250.33,16.58 v4(250.18,16.58) ; v4(134.29,20.49) 134.29,20.5 133.98,20.81 v1(133.95,20.81)
EDP_TXP_P0_CONN: length 10
  BOTTOM w0.097: C10.2 250.35,15.64 250.35,13.35 250.38,13.33 v12(250.38,13.07) 250.38,12.82 250.35,12.79 250.35,11.41 250.44,11.33 250.68,11.33 251.05,11.7 251.43,11.7 251.67,11.46 251.67,11.17 252.22,10.62 252.92,10.62 253.1,10.44 253.1,9.9 253.25,9.74 JLVDS1.7
EDP_TXP_P1: length 134.5
  IN1 w0.066: v4(143.32,11.53) 143.46,11.39 143.91,11.39 144.81,10.49 148.2,10.49 151.31,7.38 154.01,7.38 155.03,6.35 161.66,6.35 163.69,8.37 170.04,8.37 171.92,6.49 179.91,6.49 180.4,6.98 181.66,6.98 183.8,9.12 190.43,9.12 190.86,8.68 196.82,8.68 198.27,10.13 199.58,10.13 199.71,9.99 242.56,9.99 245.85,13.28 245.85,13.49 245.53,13.81 245.53,13.95 245.62,14.05 245.76,14.05 246.09,13.72 246.29,13.72 246.51,13.94 246.51,14.15 246.13,14.52 246.13,14.66 246.23,14.76 246.37,14.76 246.74,14.38 246.95,14.38 247.17,14.6 247.17,14.8 246.8,15.17 246.8,15.31 246.89,15.41 247.03,15.41 247.4,15.04 247.91,15.04 248.48,15.61 248.48,16.31 v4(248.69,16.52)
  IN3 w0.076: v4(143.32,11.53) 142.62,11.53 142.1,11.01 141.37,11.01 140.75,11.63 139.07,11.63 137.66,13.03 137.66,13.38 137.3,13.74 137.3,14.59 137.83,15.12 137.83,18.03 136.35,19.51 135.47,19.51 134.97,20.01 v4(134.86,20.01)
  IN4 w0.066: v1(248.7,16.93) 248.69,16.92 v4(248.69,16.52) ; v1(135.17,20.26) 135.11,20.26 v4(134.86,20.01)
EDP_TXP_P1_CONN: length 10.1
  BOTTOM w0.097: JLVDS1.4 251.75,9.54 251.53,9.76 251.53,9.83 251.35,10.01 248.93,10.01 248.39,10.55 248.39,14.46 248.42,14.48 v12(248.42,14.76) 248.42,14.97 248.39,15 248.39,15.23 248.27,15.35 248.27,15.58 C8.2
EN_0.675VSP: length 3.6
  BOTTOM w0.203: PU600.7 221.58,27.16
  BOTTOM w0.254: 221.58,27.16 v2(221.9,27.48) 222.35,27.93 222.49,27.93 PC614.1 PR609.1
EN_1.5V: length 6.9
  IN4 w0.254: v1(288.28,45.19) 288.28,44.13 v1(289.37,43.05)
  BOTTOM w0.076: v2(291.02,46.68) 290.29,46.68 289.25,45.64 288.72,45.64 288.28,45.2 v1(288.28,45.19)
  BOTTOM w0.254: PR400.2 287.4,45.19 v1(288.28,45.19)
EN_1.8V: length 6
  IN4 w0.254: v3(278.08,43.46) 278.08,43.82 276.45,45.45 v1(276.09,45.45)
  BOTTOM w0.076: PR405.2 v2(275.17,46.59)
  BOTTOM w0.203: PU401.13 277.92,43.3 v3(278.08,43.46)
  BOTTOM w0.254: PR405.2 275.2,45.45 v1(276.09,45.45)
EN_1.35V: length 5.6
  BOTTOM w0.076: v2(224.88,25.77) 223.33,25.77 PR608.1
  BOTTOM w0.203: PU600.8 221.96,26.76
  BOTTOM w0.254: PC613.1 PR608.1 222.34,26.76 221.96,26.76
EN_CAM: length 147.6
  IN1 w0.076: v4(155.48,7.61) 155.48,9.06 157.74,11.32 167.97,11.32 169.01,12.36 169.01,13.88 170.02,14.88 171.31,14.88 171.46,15.03 172.19,15.03 172.34,14.88 176.19,14.88 176.92,15.61 178.25,15.61 178.94,16.3 180.83,16.3 182.98,14.15 189.01,14.15 189.54,14.68 191.12,14.68 192.15,13.64 195.36,13.64 198.27,16.55 203.71,16.55 206.04,14.22 221.91,14.22 222.59,14.9 222.59,18.75 220.76,20.58 220.76,26.81 224.52,30.57 v4(226.3,30.57)
  IN3 w0.076: v4(128.44,21.04) 128.41,21.01 128.41,20.21 127.44,19.24 127.44,18.39 126.96,17.92 126.96,17.3 127.26,17 127.26,16.74 127.08,16.55 126.72,16.55 125.78,15.61 125.78,9.62 127.25,8.16 129.47,5.94 135.27,5.94 135.53,5.68 135.75,5.68 135.97,5.47 136.93,5.47 137.43,4.97 138.74,4.97 139.04,4.67 143.05,4.67 145.87,7.49 153.75,7.49 153.88,7.61 v4(155.48,7.61)
  IN4 w0.076: v1(128.88,20.77) 128.71,20.77 128.49,20.99 128.49,20.99 v4(128.44,21.04)
  IN4 w0.254: v4(226.3,30.57) v1(226.3,30.95)
  BOTTOM w0.076: v2(224.31,30.73) 224.61,30.42 225.77,30.42 v1(226.3,30.95)
  BOTTOM w0.203: U25.5 227.5,30.34 226.88,30.95 v1(226.3,30.95)
EN_INVPWR: length 166.3
  IN1 w0.076: v4(285.65,75.26) 286.19,75.81 287,75.81 287.45,76.25 289.88,76.25 292.01,78.39 292.01,79.73 291.49,80.25 291.49,81.05 291.13,81.4 v4(291.13,81.44)
  IN2 w0.076: v4(287.73,9.26) 288.47,9.26 290.95,11.75 290.95,16.03 290.97,16.04 v4(290.97,16.17)
  IN4 w0.076: v4(290.97,16.17) 290.97,16.17 291.51,16.71 292.77,16.71 293.35,16.12 294.11,16.12 295.56,17.57 295.56,22.49 295.81,22.74 295.81,42.7 295.12,43.39 295.12,44.5 294.61,45.01 294.61,45.88 294.38,46.11 294.38,47.02 293.95,47.45 292.17,47.45 291.8,47.82 291.21,47.82 289.29,49.74 289.29,50 289.29,53.22 285.63,56.89 285.63,71.45 285.44,71.63 285.44,73.87 v1(285.53,73.96) 285.24,74.25 285.24,74.86 v4(285.65,75.26) ; v1(237.89,6.51) 238.62,7.24 238.62,10.51 245.1,16.99 246.63,16.99 246.86,16.99 247.58,17.71 252.5,17.71 254.99,15.22 257.52,15.22 259.11,13.63 260.24,13.63 260.31,13.71 261.41,13.71 263.52,11.6 267.02,11.6 268.03,10.58 268.03,6.59 269.55,5.07 284.31,5.07 286.02,6.78 286.02,9 286.27,9.25 287.72,9.25 v4(287.73,9.26) ; v1(289.11,80.63) 289.17,80.69 289.42,80.69 290.56,81.83 290.98,81.83 291.13,81.68 v4(291.13,81.44)
  BOTTOM w0.076: Q3.2 237.86,9.6 238.08,9.38 v2(238.08,7.65) 238.08,6.7 v1(237.89,6.51) 238.03,6.37 R32.1 238.75,4.16 U7.2
ENBKL: length 140.3
  IN4 w0.076: v1(256.31,14.75) 256.35,14.79 257.65,14.79 259.18,13.25 260.07,13.25 260.37,13.56 261.17,13.56 263.94,10.79 263.94,7.28 261.88,5.22 250.48,5.22 248.4,3.14 243.88,3.14 242.86,2.13 199.97,2.13 199.15,1.31 157.25,1.31 154.71,3.85 v1(154.44,3.85) 153.25,5.05 153.25,5.9 151.71,7.44 151.71,7.44 148.35,10.81 148.35,11.56 148.12,11.79 147.51,11.79 146.95,11.23 146.95,11.03 147.1,10.88 v1(147.63,10.88)
  BOTTOM w0.076: D3.2 v1(256.31,14.75)
ENVDD: length 5.7
  BOTTOM w0.076: D1.1 v2(246.53,17.07) 246.53,17.46 247.04,17.97 247.86,17.97 R23.1 248.24,18.35 U6.3
FB: length 5.7
  BOTTOM w0.254: PC523.2 PR550.2 183.26,15.04 183.41,15.19 183.41,15.6 v2(184.02,16.21) 184.02,17.99 184.14,18.1 PU702.7
FB_1.5V: length 5.9
  BOTTOM w0.076: v2(282.98,41.45) 282.98,41.94 283.58,42.54 PR403.1
  BOTTOM w0.203: PR403.1 283.95,42.54 284.39,42.1 284.39,42.1 284.86,41.63 PR401.2 284.84,41.58 284.84,40.7 ; PC402.2 284.84,40.7 ; 284.84,40.7 285.04,40.7 285.89,41.55 PU400.5
FB_1.8V: length 5.9
  BOTTOM w0.076: PR408.1 v2(271.61,43.78)
  BOTTOM w0.203: PC410.2 273.31,40.73 273.54,40.96 273.54,41.5 273.85,41.8 PU401.5
  BOTTOM w0.254: PC410.2 PR406.2 272.53,41.85 PR408.1
FB_1.35V: length 4.9
  BOTTOM w0.203: PR605.1 221.89,29.72 v2(221.89,28.82) 221.89,28.02 221.44,27.56 PU600.6
  BOTTOM w0.254: PR605.1 PR607.1
FB_3V: length 4.2
  BOTTOM w0.076: v2(282.05,35.27) 282.05,34.66 PR300.2
  BOTTOM w0.203: PR300.2 PR302.2 281.34,33.06 281.34,32.8 280.89,32.35 PU300.4
FB_5V: length 4
  BOTTOM w0.076: v2(279.17,35.2) 279.39,34.98 PR301.1
  BOTTOM w0.203: PU300.2 280.09,32.46 279.37,33.18 PR303.1
  BOTTOM w0.254: PR301.1 279.37,34.11 PR303.1
FIVE_EN: length 47.5
  TOP w0.076: v3(192.53,5.27) 192.94,4.86 193.22,4.86 193.47,4.6 194.18,4.6 194.31,4.48 194.46,4.48 194.56,4.38 JXDP1.45
  IN4 w0.076: v3(192.53,5.27) 192.05,4.78 185.39,4.78 185.06,5.12 179.59,5.12 179.27,4.8 171.89,4.8 171.82,4.87 169.28,4.87 168.9,5.25 168.14,5.25 167.99,5.4 167.99,7.08 167.89,7.18 167.89,7.76 166.42,9.24 166.06,9.24 v1(165.95,9.24) 165.58,9.24 165.04,9.78 157.97,9.78 157.57,10.19 155.04,10.19 154.37,10.86 154.14,10.86 154.11,10.89 154.1,10.89 153.77,11.22 v1(153.77,11.38)
  BOTTOM w0.076: v2(164.97,8.97) 165.24,9.24 v1(165.95,9.24)
GNSS_IRQ: length 81.6
  TOP w0.076: v3(66.52,20.16) 65.71,19.35 v2(65.71,18.04) 65.71,16.01 64.82,15.12 v3(64.81,15.12)
  IN2 w0.076: v3(66.52,20.16) 66.52,19.86 68.95,17.43 79,17.43 81.85,14.58 86.15,14.58 86.6,15.03 94.78,15.03 94.89,15.14 95.84,15.14 96.74,14.24 97.75,14.24 99.06,12.93 101.13,12.93 102.05,12.01 103.46,12.01 103.67,11.8 107.73,11.8 v4(107.81,11.73)
  IN4 w0.076: v4(107.81,11.73) 107.92,11.62 108.92,11.62 111.23,9.31 116.45,9.31 v1(116.75,9.6)
  BOTTOM w0.076: v3(64.81,15.12) 65.02,14.9 65.02,7.97 64.3,7.24 64.3,3.65 62.8,2.15 58.87,2.15 R364.2 ; v1(116.75,9.6) 116.86,9.49 116.86,8.96 117.43,8.39 RC49.1
GNSS_IRQ_L: length 16.5
  IN4 w0.076: v1(55.13,8.76) 55.23,8.86 55.27,8.86 55.89,9.48 55.89,11.57 v1(55.71,11.75)
  BOTTOM w0.076: v1(55.13,8.76) 54.8,8.43 v2(54.8,8.08) 54.8,7.4 55.08,7.12 55.08,5.96 54.7,5.58 54.7,3.35 55.4,2.65 U53.D3 ; v1(55.71,11.75) 55.48,11.98 55.48,15.97 55,16.46 JNGFF2.36
GNSS_IRQ_R: length 15.5
  IN4 w0.076: v1(115.85,10.57) 116.41,10.01 v1(119.02,10.01) 119.6,10.01 120.89,11.3 121.39,11.3 121.79,11.7 122.89,11.7 122.93,11.65 124.1,11.65 124.46,11.29 124.76,11.29 127.07,11.29 127.41,11.63 v1(128.07,11.63)
  BOTTOM w0.076: RC49.2 118.96,8.39 119.39,8.82 119.39,9.64 v1(119.02,10.01)
GNSS_OFF#: length 104
  IN4 w0.076: v1(128.88,21.63) 128.72,21.63 128.7,21.66 128.39,21.66 128.31,21.75 127.67,21.75 127.47,21.54 125.01,21.54 124.86,21.39 124.49,21.39 124.01,20.91 120.6,20.91 120.41,20.72 117.01,20.72 115.27,18.98 113.76,18.98 113.26,18.48 111.88,18.48 110.8,17.4 109.15,17.4 108.67,17.89 108.24,17.89 108.19,17.94 107.72,17.94 106.5,16.72 101.37,16.72 101.26,16.82 99.57,16.82 99.28,16.53 89.22,16.53 89.01,16.74 88.45,16.74 83.33,16.74 82.7,17.38 54.56,17.38 53.27,18.66 v1(51.95,18.66)
  BOTTOM w0.076: Q43.1 53.88,5.62 53.48,6.02 50.67,6.02 50.53,6.16 49.44,6.16 49.22,6.38 49.22,6.9 48.96,7.17 v2(48.96,7.22) 48.96,7.43 47.84,8.55 47.84,13.29 46.42,14.71 46.42,15.94 49.34,18.86 51.75,18.86 v1(51.95,18.66)
GNSS_OFF#_R: length 20.9
  IN1 w0.076: v4(53.99,6.32) 53.99,8.54 49.29,13.24 v3(49.29,15.66)
  IN4 w0.076: v4(53.99,6.32) 54.3,6.63 v1(54.53,6.63)
  BOTTOM w0.076: R290.2 53.88,3.5 54.52,4.13 54.52,6.62 v1(54.53,6.63) 54.53,7.61 53.77,8.37 v2(53.07,8.37) ; JNGFF2.18 50.5,16.3 49.87,15.66 v3(49.29,15.66)
GNSS_SCL: length 27.9
  IN4 w0.066: v1(55.79,5.94) 55.67,6.06 55.67,6.11 55.22,6.56 55.22,6.95 49.86,12.31 49.27,12.31 46.93,14.66 46.93,14.86 v1(47.04,14.98)
  BOTTOM w0.097: JNGFF2.32 54,16.96 54.16,16.8 54.16,13.95 53.94,13.73 47.9,13.73 46.94,14.69 46.94,14.87 v1(47.04,14.98) ; v1(55.79,5.94) 55.71,5.86 55.71,5.61 55.16,5.05 55.16,3.67 55.32,3.51 55.53,3.51 U53.B3
GNSS_SDA: length 28.7
  IN4 w0.066: v1(46.66,14.98) 46.78,14.85 46.78,14.6 49.21,12.17 49.8,12.17 55.07,6.9 55.07,6.5 55.41,6.17 v1(55.41,5.94)
  BOTTOM w0.097: JNGFF2.34 54.5,16.96 54.34,16.8 54.34,13.88 54.01,13.56 47.83,13.56 46.76,14.62 46.76,14.87 v1(46.66,14.98) ; U53.C3 55.67,3.18 55.51,3.34 55.25,3.34 54.99,3.6 54.99,5.12 55.54,5.68 55.54,5.8 v1(55.41,5.94)
GPIO88_SLP_S0#: length 243.1
  TOP w0.076: v5(130.63,14.99) 130.82,14.8 135.23,14.8 138.62,11.41 154.14,11.41 155.72,12.98 163.44,12.98 166.32,15.86 167.06,15.86 167.89,16.7 168.41,16.7 168.57,16.85 168.57,17.16 169.47,18.06 169.99,18.06 170.85,17.2 170.85,16.45 171.87,15.43 172.93,14.37 176.67,14.37 v3(176.87,14.57)
  IN1 w0.076: v4(130.41,15.49) 130.63,15.26 v5(130.63,14.99)
  IN3 w0.076: v4(285.49,55.69) 287.12,55.69 290.65,52.16 290.65,49.01 292.36,47.3 292.73,47.3 296.03,44 296.03,43.93 296.03,22.81 296.03,22.08 291.21,17.25 290.26,17.25 288.04,15.03 287.27,15.03 284.78,15.03 282.97,13.21 282.18,13.21 280.95,11.98 273.96,11.98 272.58,13.36 268.57,13.36 267.7,12.5 250.74,12.5 247.95,15.28 246.95,15.28 245.59,16.64 238.14,16.64 237.34,15.84 234.55,15.84 233.86,16.54 231.99,16.54 231.37,15.91 227.71,15.91 226.12,14.33 226.12,13.59 223.96,11.42 214.48,11.42 213.75,12.15 203.54,12.15 203.46,12.06 201.38,12.06 201.1,12.34 200.48,12.34 199.75,13.07 v4(199.57,13.07)
  IN4 w0.076: v4(285.49,55.69) 284.78,56.41 284.78,69.8 v1(284.87,69.89) ; v3(176.87,14.57) 176.87,14.56 176.56,14.26 176.56,13.56 176.88,13.25 178.48,13.25 179.09,12.64 179.26,12.64 179.39,12.51 180.77,12.51 181.02,12.51 181.37,12.16 186.96,12.16 187.32,11.8 198.52,11.8 199.53,12.81 199.53,13.02 199.57,13.06 v4(199.57,13.07) ; v1(130.38,14.71) 130.38,15.46 v4(130.41,15.49)
  BOTTOM w0.076: R329.1 286.77,70.4 v2(286.15,70.4) 285.38,70.4 v1(284.87,69.89)
H_CATERR#: length 15.6
  IN1 w0.066: v4(165,13.82) 163.74,12.55 156.55,12.55 155.47,11.48 154.05,11.48 153.22,12.31 v4(153.22,12.46)
  IN4 w0.066: v1(166.84,13.74) 166.84,13.75 165.07,13.75 v4(165,13.82) ; v4(153.22,12.46) 153.26,12.43 v1(153.26,11.96)
H_CPU_SVIDALRT#: length 7.8
  IN4 w0.066: v1(151.53,10.63) 151.74,10.42 151.74,9.33 153.07,8 154.47,6.6 155.53,6.6 155.76,6.37 156.02,6.37 156.5,5.89 v1(156.5,5.63)
H_CPU_SVIDCLK: length 13.1
  IN4 w0.066: v1(155.48,5.63) 155.48,5.69 155.64,5.84 155.8,5.84 155.93,5.72 155.93,5.43 155.81,5.31 155.09,5.31 155.05,5.28 155.05,5.02 154.96,4.92 154.82,4.92 154.73,5.02 154.73,5.63 154.85,5.76 155.03,5.76 155.08,5.81 155.08,6.01 155.02,6.07 154.51,6.07 154.42,5.98 154.42,5.41 154.32,5.3 154.17,5.3 154.09,5.39 154.09,6.06 154.08,6.07 154.08,6.25 152.55,7.79 151.19,9.14 151.19,10.11 151.22,10.14 151.22,11.26 151.32,11.36 151.32,11.37 151.48,11.37 151.53,11.33 v1(151.53,11.13)
H_CPU_SVIDDAT: length 14.1
  IN4 w0.066: v1(157.57,5.55) 157.82,5.3 157.82,5.07 157.69,4.95 157.33,4.95 157.2,5.07 157.2,5.92 156.12,7 155.89,7 155.76,7.13 154.68,7.13 153.59,8.22 152.09,9.72 152.09,9.82 152.09,10.23 152.09,10.33 151.95,10.46 151.95,10.55 151.72,10.78 151.72,10.98 151.82,11.08 151.82,11.08 151.92,11.18 152.07,11.18 152.18,11.29 152.18,11.44 152.07,11.55 v1(151.96,11.55)
  BOTTOM w0.097: v2(158.54,3.6) 158.34,3.8 RC33.2 RC28.2 v1(157.57,5.55)
H_CPUPWRGD_R: length 13.4
  IN4 w0.076: v1(152.83,10.88) 152.69,10.75 152.69,9.87 152.76,9.8 153.11,9.8 153.51,9.41 153.58,9.41 154.72,8.27 156.07,8.27 158.23,6.11 162.47,6.11 v1(163.15,5.43)
H_DRAMRST#: length 6.5
  BOTTOM w0.076: UCPU1.AB2 133.7,25.42 133.96,25.68 134.81,25.68 RC20.1 136.29,27.95 136.29,28.94 v2(136.87,29.51)
H_PECI: length 246
  IN3 w0.076: v4(246.72,18.59) 246.72,18.66 246.19,19.19 244.26,19.19 244.08,19.37 240.84,19.37 240.78,19.31 239.82,19.31 239.76,19.37 237.3,19.37 236.47,18.55 232.23,18.55 v4(232.17,18.61)
  IN4 w0.076: v4(246.72,18.59) 247.68,19.55 249.04,19.55 249.31,19.82 249.31,20.55 250.02,21.26 251.5,21.26 255.72,17.04 258.29,17.04 258.47,16.86 263.04,16.86 263.38,16.51 263.38,15.25 264.47,14.16 265.69,14.16 266.3,14.77 268.94,14.77 269.3,14.42 270.24,14.42 270.63,14.02 271.59,14.02 273.02,12.6 273.02,11.28 274.57,9.73 280.52,9.73 282.03,11.24 282.03,14.86 282.62,15.45 283.87,15.45 286.74,18.32 287.13,18.32 287.54,18.73 292.81,18.73 293.98,19.89 293.98,23.06 294.28,23.37 294.28,39.95 293.58,40.65 293.27,40.96 293.27,42.23 292.52,42.98 292.52,44.26 291.15,45.64 290.73,45.64 289.83,46.53 289.83,46.92 288.35,48.4 287.83,48.4 287.36,48.87 287.36,49.91 286.8,50.47 286.8,51.95 287.15,52.3 287.15,53.17 286.58,53.74 285,53.74 283.39,55.35 283.39,68.43 282.53,69.29 282.53,70.37 281.42,71.48 281.42,72.65 281.8,73.03 281.8,79.99 283.2,81.38 283.2,84.99 283.69,85.48 283.69,85.78 285.33,87.42 v1(286.8,87.42) ; v1(153.77,10.88) 153.89,10.88 153.98,10.79 153.98,10.79 154.41,10.36 154.49,10.36 154.83,10.03 157.51,10.03 158.15,9.39 158.93,9.39 159.07,9.25 164.82,9.25 165.36,8.7 166.11,8.7 167.17,7.65 167.17,6.76 167.44,6.49 167.44,5.11 167.85,4.7 168.69,4.7 169.14,4.25 179.5,4.25 179.82,4.58 184.84,4.58 185.17,4.25 193.13,4.25 193.51,4.63 195.1,4.63 196.95,6.48 199.48,6.48 200.06,5.9 201.48,5.9 201.52,5.94 201.95,5.94 208.36,12.36 209.59,13.58 219.15,13.58 221.49,15.92 221.49,17.21 223.27,18.99 225.89,18.99 226.73,19.83 230.95,19.83 231.41,19.37 231.41,19.37 v4(232.17,18.61)
H_PROCHOT#: length 334.4
  TOP w0.097: v3(104.38,7.13) 104.38,7.69 104.96,8.27 108.98,8.27 110.2,7.05 119.63,7.05 123.56,3.12 135.58,3.12 136.17,2.53 166.67,2.53 167.98,3.84 v5(167.98,3.9) 168.78,3.9 176.6,11.73 177.13,11.73 178.76,13.36 178.76,13.38 v5(179.23,13.85)
  IN1 w0.066: v4(298.66,12.44) 298.65,12.45 298.65,15.52 298.01,16.16 298.01,16.42 v4(297.59,16.84) ; v4(167.67,4.08) 167.79,4.08 167.97,3.9 v5(167.98,3.9) ; v4(292.02,74.24) 289.96,74.24 289.59,73.87 286.15,73.87 v4(285.61,74.41) ; v4(245.36,18.51) 242.61,15.75 241.58,15.75 240.41,14.58 237.08,14.58 236.99,14.5 233.64,14.5 233.08,13.94 226.85,13.94 226.71,13.79 205.87,13.79 205.72,13.94 205.61,13.94 203.42,16.13 198.45,16.13 195.54,13.22 191.72,13.22 191.3,13.64 188.38,13.64 188.24,13.51 v3(188.2,13.51) 188.16,13.51 187.94,13.73 179.35,13.73 v5(179.23,13.85)
  IN4 w0.066: v4(292.02,74.24) 292.14,74.24 293.02,73.36 293.02,70.31 292.46,69.75 292.46,68.1 292.44,68.08 292.44,68.05 291.42,67.03 291.42,55.79 291.92,55.3 291.92,52.74 291.92,51.6 292.84,50.68 293.3,50.68 293.5,50.88 294,50.88 294.35,50.53 295.87,50.53 298.63,47.78 298.63,35.1 298.12,34.59 298.12,21.78 297.88,21.55 297.88,17.72 298,17.59 298,17.23 297.61,16.84 v4(297.59,16.84) ; v4(167.67,4.08) 167.67,4.09 167.44,4.32 v1(167.43,4.32) ; v4(298.66,12.44) 290.35,12.44 289.41,11.49 286.6,11.49 285.74,10.64 285.74,6.9 284.19,5.35 269.66,5.35 268.34,6.67 268.34,10.71 269.23,11.6 v1(269.23,11.96) 269.2,11.98 269.02,11.98 268.92,11.87 263.88,11.87 261.25,14.51 258.62,14.51 257.64,15.49 255.1,15.49 252.61,17.99 247.47,17.99 246.94,17.46 245.97,17.46 245.36,18.07 v4(245.36,18.51) 244.33,18.51 243.47,19.37 243.47,22.22 242.67,23.02 242.67,25.68 241.08,27.27 241.08,31.63 240.87,31.85 240.87,32.34 v1(241.39,32.86) ; v4(285.61,74.41) v1(285.61,74.81)
  BOTTOM w0.097: v1(167.43,4.32) 167.46,4.36 167.46,7.62 RC8.1 167.37,8.73 v2(167.9,8.73) 168.23,8.73 RC6.1 ; v3(104.38,7.13) 104.3,7.05 JIO1.12 ; v3(188.2,13.51) 188.2,13.47 187.98,13.25 PC541.1 PR511.2 ; Q23.1 285.43,76.04 285.61,75.86 v1(285.61,74.81) ; v1(269.23,11.96) 271.27,11.96 271.88,12.57 272.15,12.57 PR901.2 273.12,13.51 274.3,14.68 PQ900.6
H_PROCHOT#_R: length 16.2
  IN3 w0.076: 158.79,10.68 153.96,10.68 153.31,11.33 v4(153.31,11.55)
  IN3 w0.097: 158.79,10.68 162.2,10.68 164.22,8.66 164.22,8.46 164.36,8.32 164.36,8.17 164.47,8.06 164.47,8.04 v4(164.49,8.02)
  IN4 w0.066: v4(164.49,8.02) 164.51,8.04 165.76,8.04 v1(165.95,8.22) ; v4(153.31,11.55) 153.31,11.47 153.34,11.44 v1(153.34,11.13)
  BOTTOM w0.097: v2(164.96,7.69) 165.03,7.69 165.57,8.22 v1(165.95,8.22)
H_THERMTRIP#: length 222.8
  IN1 w0.076: v4(281.09,71.02) 281.18,71.02 281.34,70.86 289.12,70.86 289.73,71.47 290.78,71.47 291.21,71.04 292.61,71.04 293.31,71.75 v3(294.54,71.75)
  IN3 w0.076: v4(281.09,71.02) 280.58,70.51 280.58,61.26 284.13,57.71 284.13,55.14 285.07,54.21 287.19,54.21 289.66,51.74 289.66,48.6 290.53,47.73 290.53,47.35 292.97,44.9 292.97,43.52 293.98,42.51 293.98,40.66 294.91,39.74 294.91,22.57 290.73,18.39 289.78,18.39 289.61,18.22 288.06,16.67 286.55,16.67 286.23,16.35 283.5,16.35 281.32,14.17 281.32,13.84 280.5,13.02 274.39,13.02 272.54,14.88 263.34,14.88 261.78,16.44 253.95,16.44 252.16,18.23 249.91,18.23 248.89,19.24 247.64,19.24 247.29,18.9 247.29,18.38 246.95,18.04 246.4,18.04 246.21,18.23 245.81,18.23 245.7,18.13 244.4,18.13 244.03,18.5 239.34,18.5 239.01,18.83 238.73,18.83 238.52,18.61 237.29,18.61 236.52,17.84 231.46,17.84 230.83,17.21 227.16,17.21 222.66,12.71 214.66,12.71 213.74,13.63 203.2,13.63 201.32,15.51 199.03,15.51 196.9,13.38 192.08,13.38 191.18,12.48 187.64,12.48 185.79,14.33 180.38,14.33 v4(180.26,14.44)
  IN4 w0.076: v1(179.46,14.63) 180.07,14.63 v4(180.26,14.44)
  BOTTOM w0.076: RC23.2 v1(163.15,6.44) 164.18,7.47 164.18,9.47 164.88,10.16 168.03,10.16 168.35,10.48 170.39,10.48 172.16,12.25 177.29,12.25 178.64,13.59 v2(178.64,13.96) 178.64,13.98 179.29,14.63 v1(179.46,14.63) ; v3(294.54,71.75) 294.28,72 Q26.3
H_THERMTRIP#_R: length 10.9
  IN4 w0.076: v1(160.87,6.44) 160.27,7.04 158.43,7.04 158.39,7 158.1,7 156.07,9.03 154.17,9.03 153.64,9.56 153.56,9.56 153.07,10.06 153.07,11.24 152.83,11.49 v1(152.83,11.55)
HDA_BIT_CLK: length 27.1
  IN1 w0.066: v4(106.97,29.05) 107.05,29.13 107.4,29.13 109.16,27.37 127.67,27.37 128.6,26.44 128.6,26.13 v4(128.73,26)
  IN4 w0.066: v4(106.97,29.05) 106.88,29.05 106.51,28.68 106.15,28.68 v1(106.02,28.55) ; v4(128.73,26) 129.13,25.6 129.5,25.6 129.98,25.11 129.98,24.52 130.04,24.47 130.04,24.31 v1(130.23,24.12)
HDA_RST#: length 28.6
  IN1 w0.066: v4(106.36,29.05) 106.7,29.39 106.79,29.39 106.89,29.5 107.56,29.5 109.32,27.74 127.56,27.74 128.74,26.56 v4(128.89,26.56)
  IN4 w0.066: v1(106.02,29.05) v4(106.36,29.05) ; v4(128.89,26.56) 129,26.45 129.24,26.45 130.41,25.28 130.41,24.78 130.47,24.72 130.47,24.02 130.44,23.98 130.44,23.97 129.84,23.37 v1(129.8,23.37)
HDA_SDOUT: length 40.1
  IN1 w0.066: v4(106.44,30.05) 107.41,30.05 109.44,28.02 128.1,28.02 129.54,26.58 v4(129.55,26.58)
  IN4 w0.066: v1(121.18,24.02) 121.24,24.08 121.93,24.08 123.8,25.95 123.8,26.37 123.91,26.48 127.76,26.48 128.3,27.02 129.12,27.02 v4(129.55,26.58) 129.75,26.38 129.75,26.3 130.2,25.86 130.2,25.81 130.66,25.35 v1(130.66,24.87) ; v1(106.02,30.05) v4(106.44,30.05)
  BOTTOM w0.097: v1(121.18,24.02) 120.7,23.54 119.9,23.54 MC1.1 RH25.2
HDA_SPKR: length 156.6
  TOP w0.076: v3(39.21,37.42) 38.61,37.42 38.16,37.87 38.16,42.55 v5(38.1,42.61)
  IN1 w0.076: v5(38.1,42.61) 36.37,42.61 34.98,41.22 29.96,41.22 28.57,42.61 25.2,42.61 22.3,45.51 6.56,45.51 v3(6.14,45.93)
  IN2 w0.076: v3(39.21,37.42) 39.34,37.56 40.09,37.56 41.95,39.42 83.16,39.42 84.65,37.93 85.56,37.93 92.56,30.92 92.56,30.05 95.58,27.03 96.1,27.03 97.5,25.63 97.5,24.15 96.7,23.35 96.7,19.87 99.95,16.62 99.95,15.44 100.33,15.05 102.11,15.05 103,14.17 103.66,14.17 105.5,14.17 105.96,14.63 107.53,14.63 107.99,14.17 112.85,14.17 113.54,13.48 114.35,13.48 114.45,13.58 115.45,13.58 116.29,12.74 119.67,12.74 121.35,11.06 v4(122.03,11.06)
  IN4 w0.076: v1(125.33,10.69) 125.27,10.75 124.44,10.75 124.44,10.75 124.35,10.75 123.91,11.2 122.66,11.2 122.63,11.22 122.19,11.22 122.03,11.06 v4(122.03,11.06)
  BOTTOM w0.076: RH126.2 124.72,9.49 125.33,10.1 v1(125.33,10.69) 125.33,11.24 126.91,12.82 126.91,13.21 127.11,13.41 UCPU1.A34 ; JAUD1.42 5.74,49.3 v2(5.48,49.03) 5.28,48.84 5.28,47.2 6.14,46.33 v3(6.14,45.93)
HDA_SYNC: length 27
  IN1 w0.066: v4(129.25,25.99) 129.22,26.02 129.22,26.7 129.04,26.88 128.7,26.88 127.7,27.88 109.38,27.88 107.62,29.64 106.83,29.64 106.75,29.55 v4(106.42,29.55)
  IN4 w0.066: v1(130.23,24.62) 130.23,25.17 129.41,25.99 v4(129.25,25.99) ; v1(106.02,29.55) v4(106.42,29.55)
HOME_KEY#: length 20.3
  IN1 w0.076: v3(281.91,93.41) 281.85,93.41 281.54,93.1 281.54,91.01 280.99,90.46 280.99,85.6 v4(280.96,85.58) 280.88,85.5 280.88,84.84 282.17,83.56 282.17,82.73 283.93,80.97 285.42,80.97 285.9,80.48 287.28,80.48 287.46,80.66 287.59,80.66 287.72,80.79 287.72,80.81 v4(287.82,80.91)
  IN4 w0.076: v1(280.52,85.57) 280.95,85.57 v4(280.96,85.58) ; v1(288.11,81.13) 288.07,81.13 287.85,80.91 v4(287.82,80.91)
  BOTTOM w0.076: JSNR1.5 281.78,93.28 v3(281.91,93.41)
HOST_DEBUG_TX: length 20.1
  IN1 w0.076: v4(289.22,86.37) 289.22,86.49 291.78,89.06 291.78,89.43 295.97,93.62 297.79,93.62 298.21,94.04 298.21,95.2 v3(298.37,95.37)
  IN4 w0.076: v1(289.61,83.63) 289.61,83.85 289.35,84.1 289.35,86.23 v4(289.22,86.37)
  BOTTOM w0.076: v2(299.35,93.13) R237.2 298.47,93.24 JDEG1.8 298.47,95.06 298.37,95.15 v3(298.37,95.37)
HOT#: length 5.3
  BOTTOM w0.102: v2(188.86,13.3) 188.86,13.45 188.42,13.9 188.07,13.9 187.92,14.05 187.92,14.85 PR511.1
  BOTTOM w0.254: PR511.1 186.31,16.47 PU702.4
HP_AMP_EN: length 137.1
  TOP w0.076: v3(98.44,3.89) 98.44,3.32 98.13,3.01 96.02,3.01 94.27,4.77 94.27,4.92 93.95,5.24 93.43,5.24 93.25,5.06 93.25,3.14 92.88,2.77 87.45,2.77 86.24,3.98 86.24,6.85 83.14,9.95 78,9.95 74.72,6.68 v3(74.72,6.32) ; v3(63.46,38.3) 62.82,38.93 v2(62.82,40.66) 62.82,41.6 v5(62.62,41.8)
  IN1 w0.076: v5(62.62,41.8) 61.77,42.65 48.33,42.65 47.08,43.91 26.09,43.91 22.46,47.53 v3(13.23,47.53)
  BOTTOM w0.076: JAUD1.37 11.37,50.1 12.02,49.45 12.02,48.54 12.63,47.93 12.82,47.93 v3(13.23,47.53) ; v3(63.46,38.3) 64.02,37.74 64.02,20.11 65.71,18.42 67.8,18.42 68.15,18.08 68.15,7.75 69.11,6.79 74.24,6.79 74.7,6.32 v3(74.72,6.32) ; v3(98.44,3.89) 98.44,4.61 98.84,5.02 98.84,5.27 98.3,5.82 JIO1.42
HW_RST#: length 2.9
  BOTTOM w0.076: D22.1 280.36,88.55 279.51,89.4 279.51,89.81 279.61,89.91 U58.5
I2C0_SCK: length 465.6
  IN1 w0.066: v4(131.11,10.55) 130.91,10.34 130.59,10.34 130.22,10.71 129.45,10.71 128.74,11.42 122.62,11.42 122.41,11.64 114.97,11.64 114.19,12.42 112.5,12.42 111.96,11.88 110.83,11.88 108.29,9.34 105.02,9.34 104.16,10.2 104.16,10.69 104.3,10.84 v4(104.3,11.18) ; v4(141.11,8.81) 140.91,9.01 140.91,9.47 141.69,10.25 143.88,10.25 144.4,9.73 144.52,9.73 147.24,9.73 150.89,6.07 153.62,6.07 154.52,5.18 163.48,5.18 165.43,7.13 168.62,7.13 170.45,5.3 180.6,5.3 181.11,5.81 182.24,5.81 182.69,6.25 183.87,6.25 184.32,5.81 186.09,5.81 186.35,6.06 186.59,6.06 186.86,6.34 187.34,6.34 187.62,6.06 199.27,6.06 201.86,8.65 259.91,8.65 264.96,3.6 284.25,3.6 288.14,7.49 288.14,8.76 293.37,13.99 293.46,13.99 294.21,14.74 294.21,15.78 295.48,17.05 295.48,19.25 298.17,21.94 298.17,48.56 297.51,49.22 297.51,54.3 297.73,54.52 297.73,56.44 300.13,58.84 300.13,64.27 300.69,64.83 300.69,76.29 300.03,76.96 300.03,84.86 301.05,85.88 301.05,89.88 300.18,90.75 300.18,96.5 298.65,98.04 290.89,98.04 290.07,97.21 290.07,96.57 v3(289.83,96.33)
  IN3 w0.076: 139.96,8.97 139.86,9.06 138.3,9.06 137.04,10.32 134.86,10.32 134.62,10.56 131.13,10.56 v4(131.11,10.55)
  IN3 w0.097: v4(141.11,8.81) 140.75,8.45 140.47,8.45 140.44,8.48 140.44,8.48 140.25,8.67 140.25,8.68 139.96,8.97
  IN4 w0.066: v1(131.1,10.88) 131,10.79 131,10.61 131.06,10.55 v4(131.11,10.55) ; v1(104.59,11.59) 104.59,11.46 104.31,11.18 v4(104.3,11.18) 104.07,10.94 103.38,10.94 103.12,11.21 102.01,11.21 101.82,11.02 95.77,11.02 95.66,10.91 89.79,10.91 89.16,11.54 86.45,11.54 85.06,12.93 77.85,12.93 76.75,11.83 71.54,11.83 69.71,10 63.4,10 62.95,9.56 60.03,9.56 v1(59.19,8.72) 59.19,8.71 59.19,8.45 59.12,8.38 58.22,8.38 58.1,8.5 58.1,9.73 59.01,10.64 59.01,11.63 58.25,12.4 52.05,12.4 48.37,16.07 48.37,29.58 48.75,29.96 48.75,32.48 47.08,34.15 31.8,34.15 31.33,34.62 30.71,34.62 29.98,35.35 27.3,35.35 26.57,34.62 19.63,34.62 18.05,33.04 12.13,33.04 10.58,31.49 3.91,31.49 3.48,31.92 3.48,42.54 5.54,44.6 5.54,47.56 5.67,47.69 5.79,47.69 v3(6,47.48)
  BOTTOM w0.097: R362.2 58.91,4.68 58.91,6.73 58.69,6.96 58.69,8.17 59.07,8.55 59.11,8.55 59.19,8.63 v1(59.19,8.72) ; v3(6,47.48) 6.48,47.48 6.7,47.7 JAUD1.50 ; v3(289.83,96.33) 290.03,96.13 290.03,94.16 289.94,94.07 289.94,93.29 289.78,93.12 JSNR1.21
I2C0_SDA: length 469.2
  IN1 w0.066: v4(140.59,8.81) 140.76,8.98 140.76,9.52 141.64,10.41 143.93,10.41 144.46,9.87 147.3,9.87 150.95,6.22 153.68,6.22 154.58,5.32 163.42,5.32 165.37,7.27 168.68,7.27 170.51,5.44 180.54,5.44 181.05,5.95 182.18,5.95 182.63,6.4 183.93,6.4 184.38,5.95 186.03,5.95 186.29,6.21 186.53,6.21 186.8,6.48 187.4,6.48 187.68,6.21 199.21,6.21 201.8,8.8 259.96,8.8 265.02,3.74 284.19,3.74 288,7.55 288,8.82 293.31,14.13 293.4,14.13 294.07,14.8 294.07,15.84 295.34,17.11 295.34,19.31 298.03,22 298.03,48.5 297.37,49.16 297.37,54.36 297.59,54.58 297.59,56.5 299.99,58.9 299.99,64.33 300.55,64.89 300.55,76.23 299.88,76.9 299.88,84.92 300.91,85.94 300.91,89.82 300.04,90.69 300.04,96.44 298.59,97.9 290.95,97.9 290.21,97.15 290.21,96.54 v3(290.41,96.33) ; v4(104.79,11.14) 104.79,11.11 104.53,10.86 104.52,10.86 104.3,10.63 104.3,10.25 105.08,9.48 108.23,9.48 110.77,12.02 111.9,12.02 112.44,12.56 114.25,12.56 115.03,11.78 122.46,11.78 122.68,11.56 128.8,11.56 129.51,10.86 130.28,10.86 130.41,10.73 130.84,10.73 131.12,11.01 131.08,11.04 131.08,11.3 131.26,11.49 131.27,11.49 131.27,11.86 v4(131.14,11.98)
  IN3 w0.076: v4(131.14,11.98) 131.14,11.98 131.14,11.96 131.26,11.84 131.26,11.49 131.07,11.31 131.07,11.04 131.26,10.86 131.32,10.86 131.47,10.71 134.68,10.71 134.92,10.47 137.11,10.47 138.36,9.21 139.96,9.21 140.2,8.97
  IN3 w0.097: 140.2,8.97 140.36,8.81 v4(140.59,8.81)
  IN4 w0.066: v3(5.99,48.07) 5.75,47.83 5.61,47.83 5.4,47.62 5.4,44.66 3.34,42.6 3.34,31.86 3.85,31.35 10.64,31.35 12.19,32.9 18.11,32.9 19.69,34.48 26.63,34.48 27.36,35.21 29.93,35.21 30.66,34.48 31.27,34.48 31.74,34.01 47.02,34.01 48.61,32.42 48.61,30.02 48.23,29.64 48.23,16.01 51.99,12.25 58.19,12.25 58.87,11.57 58.87,10.69 57.96,9.78 57.96,8.44 58.16,8.23 59.18,8.23 v1(59.61,8.67) 59.61,8.67 59.61,8.94 60.09,9.42 63.01,9.42 63.46,9.86 69.77,9.86 71.6,11.69 76.81,11.69 77.91,12.78 85,12.78 86.39,11.39 89.1,11.39 89.73,10.76 95.72,10.76 95.83,10.87 101.87,10.87 102.07,11.06 103.06,11.06 103.33,10.8 104.47,10.8 104.79,11.12 v4(104.79,11.14) 104.81,11.14 105.09,11.43 v1(105.09,11.59) ; v1(130.74,11.96) 130.76,11.98 v4(131.14,11.98)
  BOTTOM w0.076: UCPU1.N36 130.66,12.05 v1(130.74,11.96)
  BOTTOM w0.097: v3(290.41,96.33) 290.21,96.13 290.21,94.07 290.12,93.99 290.12,93.29 290.28,93.12 JSNR1.22 ; v3(5.99,48.07) 6.27,48.07 6.7,48.5 JAUD1.46 ; R363.2 59.2,4.06 v2(59.2,5.86) 59.2,6.69 58.86,7.03 58.86,8.09 59.14,8.37 59.32,8.37 v1(59.61,8.67)
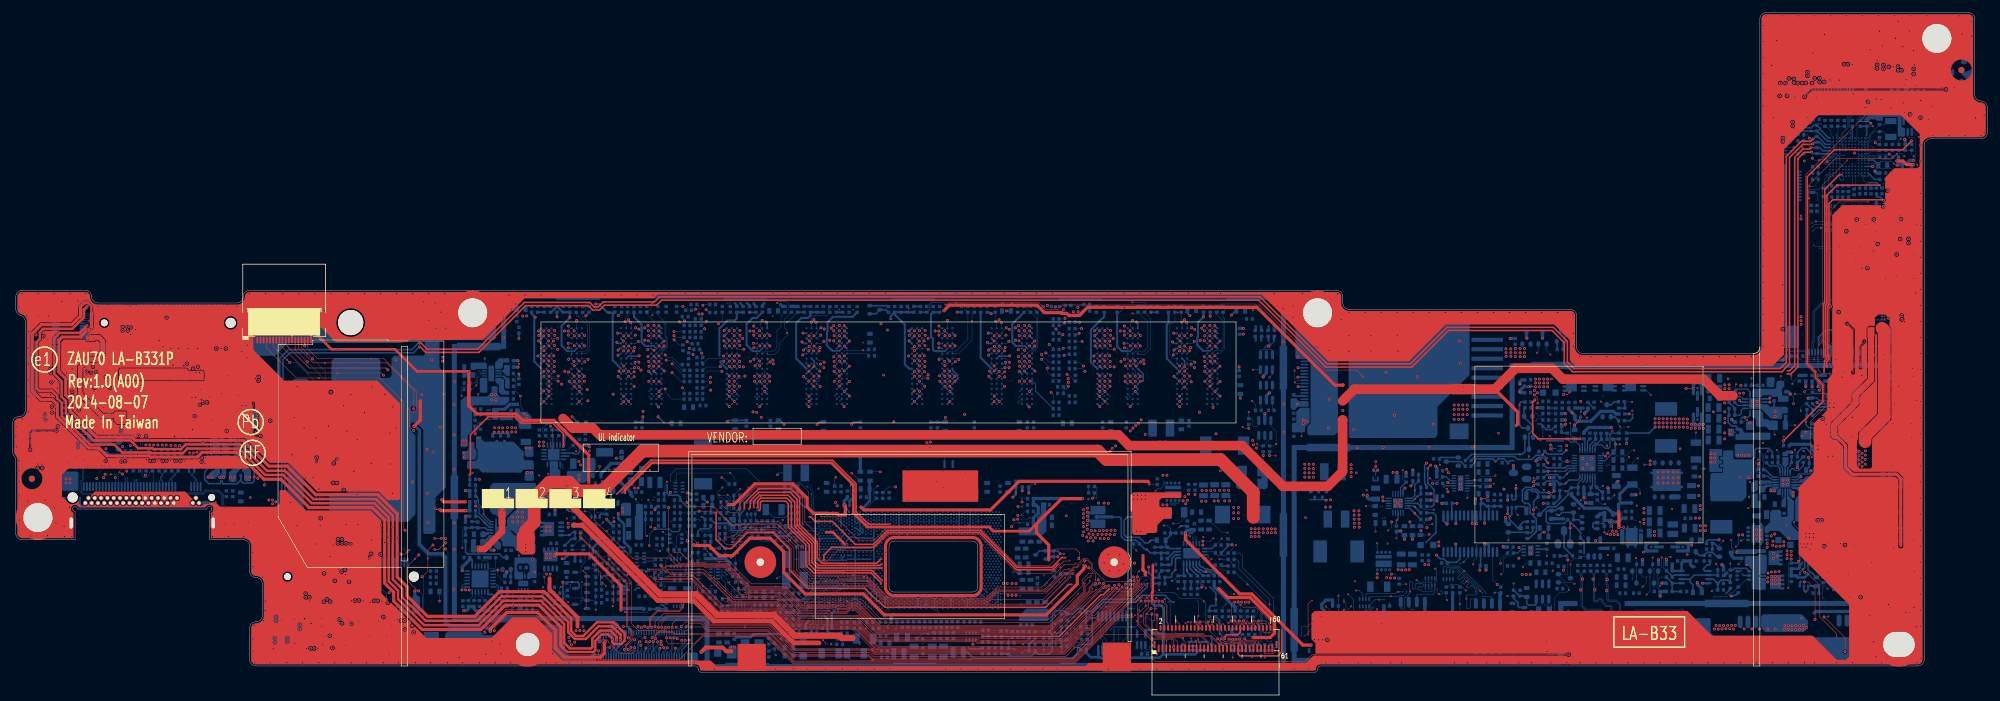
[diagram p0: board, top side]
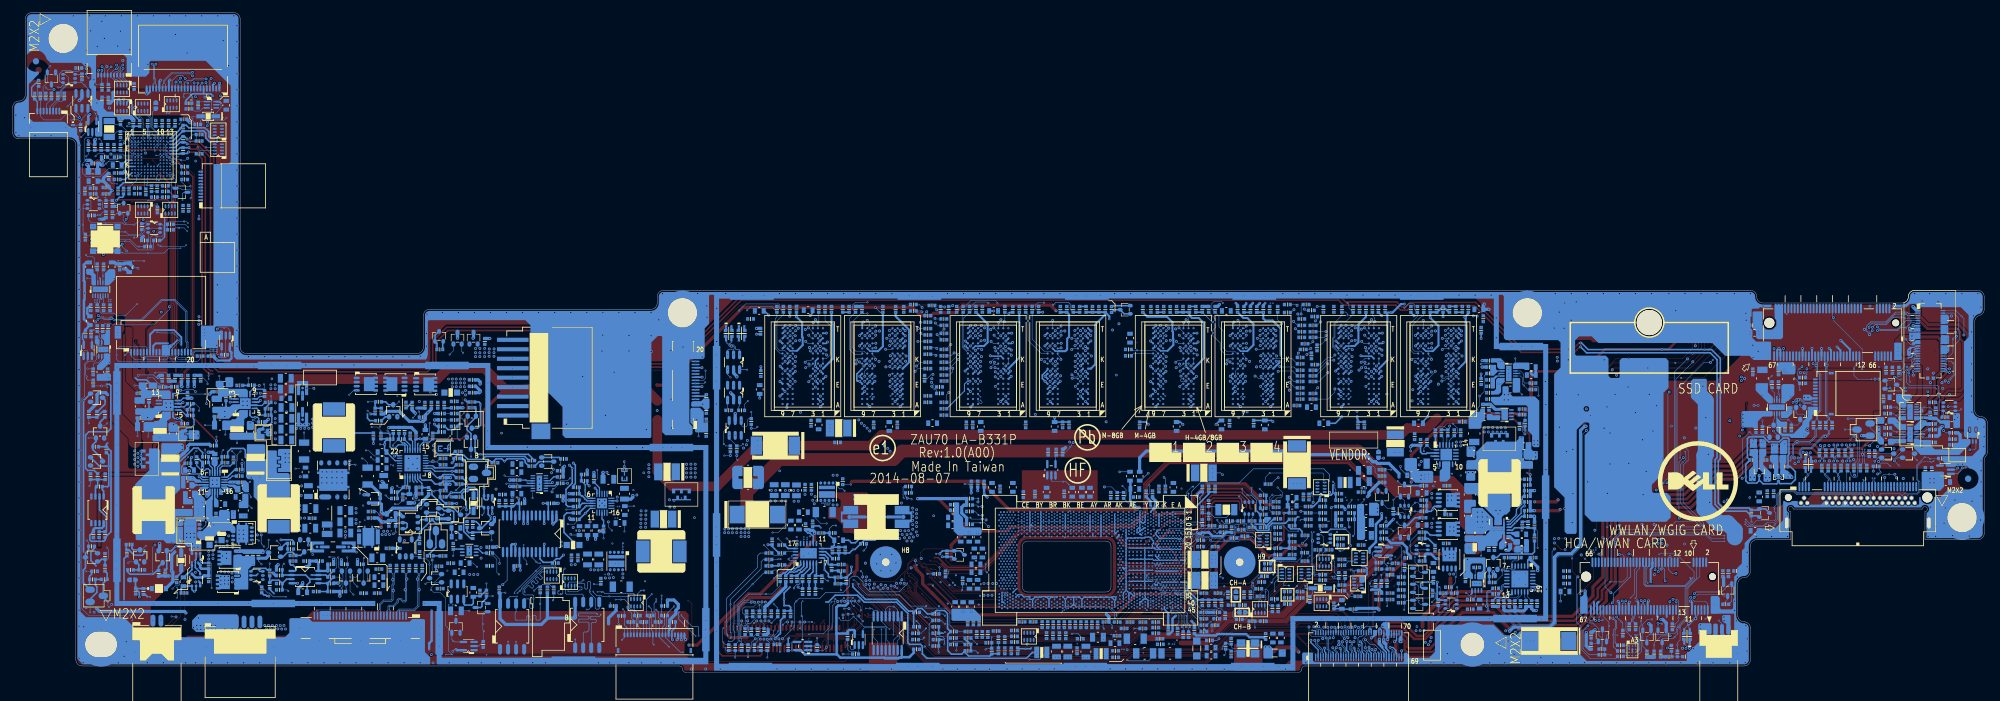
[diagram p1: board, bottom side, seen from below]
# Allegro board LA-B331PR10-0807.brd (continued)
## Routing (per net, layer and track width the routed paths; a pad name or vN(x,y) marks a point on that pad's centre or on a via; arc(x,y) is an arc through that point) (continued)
I2C1_SCK: length 310.7
  TOP w0.097: v3(101.09,7.14) 100.92,7.31 100.92,8.47 102.09,9.64 105.54,9.64 106.08,10.18 106.08,10.66 v5(106.21,10.79)
  IN1 w0.066: v3(300.84,95.61) 300.84,95.35 300.91,95.27 301.35,95.27 301.58,95.04 301.58,85.72 301.04,85.18 301.04,82.5 300.4,81.85 300.4,79.03 300.98,78.45 300.98,64.7 300.44,64.17 300.44,58.72 298.02,56.29 298.02,54.41 297.88,54.27 297.88,49.37 298.46,48.79 298.46,21.76 295.93,19.23 295.93,14.93 293.14,12.14 293.14,11.72 284.74,3.31 264.36,3.31 260.01,7.66 201.33,7.66 199.41,5.75 190.65,5.75 189.52,4.61 180.18,4.61 179.83,4.96 170.03,4.96 168.38,6.61 165.66,6.61 163.95,4.89 154.15,4.89 153.83,5.21 150.88,5.21 146.94,9.15 144.27,9.15 143.7,9.72 143.38,9.72 143.28,9.62 143.28,9.38 v4(143.47,9.19) ; v4(106.28,11.17) 106.21,11.1 v5(106.21,10.79) 106.06,10.63 106.06,10.56 106.13,10.48 106.34,10.48 106.74,10.89 106.74,11.45 107.48,12.18 109.18,12.18 110.79,13.79 114.17,13.79 114.29,13.91 116.34,13.91 116.62,13.63 123.16,13.63 123.7,13.09 124.48,13.09 125.06,13.67 126.29,13.67 126.52,13.44 130.45,13.44 130.73,13.73 130.73,13.98 130.74,13.99 130.72,13.99 v4(130.72,13.98)
  IN3 w0.076: v4(143.47,9.19) 143.47,9.11 143.33,8.97 ; v4(130.72,13.98) 130.97,13.73 130.97,13.54 131.15,13.37 131.89,13.37 132.31,12.95 133.63,12.95 135.95,10.62 137.17,10.62 138.33,9.47 140.08,9.47 140.36,9.19 140.48,9.19 140.49,9.19 141.93,9.19 142.1,9.02 142.1,9.01 142.14,8.97
  IN3 w0.097: 143.33,8.97 143.17,8.81 142.33,8.81 142.31,8.82 142.28,8.82 142.14,8.97
  IN4 w0.066: v4(130.72,13.98) 130.58,13.84 v1(130.38,13.84) ; v4(106.28,11.17) 106.09,11.36 v1(106.09,11.59)
  BOTTOM w0.097: v2(305.3,92.66) 304.88,92.66 304.52,93.02 Q41.6 304.82,93.42 305.12,93.72 305.12,94.77 304.53,95.36 303.36,95.36 303.22,95.22 302.09,95.22 R338.1 300.95,95.72 v3(300.84,95.61) ; v3(101.09,7.14) 101.09,7.13 100.7,6.74 JIO1.30
I2C1_SCK_TS: length 13.1
  IN4 w0.076: v1(302.62,93.42) 303.06,93.87 303.06,95.17 v1(302.5,95.72)
  BOTTOM w0.076: MD1.1 300.58,92.45 v2(301.1,92.97) 301.56,93.42 v1(302.62,93.42) 303.47,93.42 304.76,92.13 304.76,91.25 RH166.1 304.76,90.39 305.37,90.39 306.1,89.66 JTS1.3
I2C1_SDA: length 307.1
  TOP w0.097: v5(105.83,10.79) 105.9,10.71 105.9,10.25 105.47,9.82 102.02,9.82 100.75,8.55 100.75,7.34 v3(100.56,7.14)
  IN1 w0.066: v4(131.36,13.99) 131.27,13.99 130.58,13.3 126.46,13.3 126.23,13.53 125.12,13.53 124.53,12.95 123.65,12.95 123.1,13.49 116.56,13.49 116.29,13.77 114.35,13.77 114.23,13.65 110.85,13.65 109.24,12.04 107.54,12.04 106.88,11.39 106.88,10.83 106.4,10.34 106.07,10.34 105.9,10.51 105.9,10.71 v5(105.83,10.79) 105.83,11.09 v4(105.75,11.17) ; v3(300.84,94.79) 300.84,94.95 301.01,95.13 301.29,95.13 301.44,94.98 301.44,85.78 300.9,85.24 300.9,82.56 300.26,81.91 300.26,78.97 300.83,78.39 300.83,64.76 300.3,64.23 300.3,58.78 297.87,56.35 297.87,54.47 297.73,54.33 297.73,49.31 298.32,48.73 298.32,21.82 295.79,19.29 295.79,14.99 293,12.2 293,11.78 284.68,3.46 264.41,3.46 260.07,7.8 201.27,7.8 199.35,5.89 190.59,5.89 189.46,4.75 180.24,4.75 179.89,5.1 170.09,5.1 168.44,6.75 165.61,6.75 163.89,5.03 154.21,5.03 153.89,5.35 150.94,5.35 147,9.29 144.33,9.29 143.75,9.87 143.32,9.87 143.13,9.68 143.13,9.34 142.97,9.19 v4(142.94,9.19)
  IN3 w0.076: v4(131.36,13.99) 131.13,13.76 131.13,13.61 131.21,13.52 131.95,13.52 132.37,13.1 133.69,13.1 136.01,10.78 137.23,10.78 138.39,9.62 140.14,9.62 140.42,9.34 142,9.34 142.35,8.98 142.73,8.98 v4(142.94,9.19)
  IN4 w0.066: v1(130.73,12.61) 130.73,12.61 130.83,12.71 130.83,12.98 131.36,13.5 v4(131.36,13.99) ; v1(105.59,11.59) 105.59,11.32 v4(105.75,11.17)
  BOTTOM w0.076: v1(130.73,12.61) 130.59,12.61 130.11,12.13 UCPU1.J37
  BOTTOM w0.097: v2(300.49,94.15) 300.84,94.5 v3(300.84,94.79) R339.1 301.6,94.72 Q41.3 ; JIO1.32 100.3,6.89 v3(100.56,7.14)
I2C1_SDA_TS: length 16.1
  IN1 w0.076: v4(304.81,91.13) 303.52,91.13 v4(302.96,91.69)
  IN4 w0.076: v1(305.34,90.82) 305.12,90.82 v4(304.81,91.13) ; v4(302.96,91.69) v1(302.48,91.69) 302.48,92.92 v1(301.53,93.87)
  BOTTOM w0.076: Q41.4 304.15,94.72 303.68,94.25 303.68,93.44 304.91,92.21 304.91,91.1 305.19,90.82 v1(305.34,90.82) 306.6,89.57 JTS1.4 ; v1(302.48,91.69) 302.48,90.98 v2(303.81,89.65)
I2C#_LINE_SEL: length 427.5
  TOP w0.076: v5(177.63,9.07) 177.23,8.67 175.15,8.67 167.96,1.48 123.57,1.48 119.25,5.8 109.09,5.8 107.89,4.59 103.77,4.59 103.49,4.87 v3(103.49,5.49)
  IN1 w0.076: v5(177.63,9.07) 177.63,10.86 178.62,11.85 195.74,11.85 198.85,14.97 202.32,14.97 204.69,12.6 241.37,12.6 245.47,16.71 246.31,16.71 247.32,17.71 247.45,17.84 249.04,17.84 249.17,17.72 252.28,17.72 265.85,4.15 283.65,4.15 287.09,7.6 287.09,10.98 291.45,15.33 v4(292.29,15.33)
  IN2 w0.076: v3(6.21,42.08) 5.87,41.74 5.87,37.48 14.2,29.15 21.68,29.15 22.1,29.58 33.94,29.58 37.82,25.7 42.6,25.7 44,24.29 44,23.18 45.14,22.05 45.14,11.09 47.14,9.09 56.74,9.09 58.9,6.92 60.96,6.92 61.64,6.24 62.8,6.24 64.45,7.89 76.28,7.89 78.49,10.1 84.95,10.1 85.83,9.21 92.99,9.21 94.14,8.06 97.35,8.06 99.04,6.37 102.61,6.37 v3(103.49,5.49)
  IN4 w0.076: v1(285.02,67.7) 285.16,67.85 285.16,71.27 284.99,71.45 284.99,73 284.65,73.33 v1(284.65,73.96) 284.65,76.56 286.34,78.26 286.34,78.88 286.77,79.31 286.95,79.31 287.33,79.68 287.33,79.71 287.48,79.87 288.22,79.87 288.35,80 288.35,81.23 288.49,81.37 288.72,81.37 289.24,81.89 v1(289.82,81.89) ; v1(289.46,67.73) 288.8,67.06 288.8,58.6 289.91,57.48 289.91,55.62 290.73,54.81 290.73,52.25 290.73,52.25 290.73,51.62 290.73,51.62 290.73,51.11 292.34,49.49 295.41,49.49 295.58,49.33 295.58,49.33 295.93,48.98 295.93,48.42 295.72,48.2 295.72,47.33 296.23,46.82 296.23,45.98 296.45,45.75 296.45,43.85 297.08,43.23 297.08,22.21 296.83,21.96 296.83,16.45 295.32,14.94 293.06,14.94 293.03,14.97 292.66,14.97 v4(292.29,15.33)
  BOTTOM w0.076: v1(289.46,67.73) 289.22,67.49 v2(289.05,67.49) 285.23,67.49 v1(285.02,67.7) ; v1(289.82,81.89) 289.79,81.86 289.38,81.86 289.11,82.12 U38.F10 ; JIO1.16 103.5,5.5 v3(103.49,5.49) ; v3(6.21,42.08) Q47.2
I2C_READY: length 301.4
  TOP w0.076: v3(177.98,15.11) 177.98,14.75 178.17,14.55 178.17,13.61 176.88,12.32 176.36,12.32 170.63,6.6 169.78,6.6 166.31,3.12 136.42,3.12 135.83,3.72 123.81,3.72 119.88,7.65 110.8,7.65 109.18,9.26 102.93,9.26 101.66,7.99 v3(101.66,7.23)
  IN1 w0.076: v3(281.7,86.57) 281.7,86.38 282.93,85.15 284.77,85.15 284.83,85.2 288.28,85.2 v4(288.27,85.2)
  IN3 w0.076: v3(281.7,86.57) 282.32,85.94 282.32,80.2 282.04,79.91 282.04,60.56 284.82,57.77 284.82,55.2 285.29,54.74 287.41,54.74 290.19,51.96 290.19,48.82 291.06,47.95 291.06,47.23 293.32,44.97 293.32,43.57 294.26,42.62 294.26,41.13 295.39,40 295.39,22.3 290.95,17.86 290.01,17.86 288.53,16.39 286.66,16.39 285.91,15.64 284.15,15.64 283.86,15.36 282.9,15.36 281.6,14.06 281.6,13.72 280.63,12.74 274.28,12.74 272.43,14.6 268.73,14.6 267.48,13.35 252.71,13.35 248.61,17.45 237.67,17.45 237.51,17.3 231.68,17.3 231.05,16.68 227.38,16.68 225.36,14.66 225.36,13.9 223.64,12.18 214.79,12.18 214.07,12.91 203.23,12.91 203.16,12.84 202.61,12.84 202.13,13.33 201.61,13.33 201.32,13.62 201.32,14.03 201.34,14.05 201.34,14.54 201.34,14.66 201.05,14.95 200.64,14.95 200.58,14.89 199.62,14.89 v4(199.13,14.41)
  IN4 w0.076: v4(199.13,14.41) 198.7,14.41 198.52,14.23 198.52,13.47 197.47,12.41 187.57,12.41 187.21,12.77 181.68,12.77 181.33,13.12 179.65,13.12 177.98,14.79 v3(177.98,15.11) ; v1(280.52,86.07) 281.2,86.07 v3(281.7,86.57) ; v4(288.27,85.2) 288.59,85.2 v1(288.61,85.21)
  BOTTOM w0.076: U38.A11 288.68,84.7 288.68,85.13 v1(288.61,85.21) ; v3(177.98,15.11) 177.98,15.73 v2(178.27,16.02) ; JIO1.28 101.1,6.66 101.66,7.22 v3(101.66,7.23)
I2S_MCLK: length 124.9
  IN1 w0.066: v3(18.19,54.65) 18.73,54.11 18.92,54.11 19.31,53.71 20.11,53.71 28.87,44.95 79.85,44.95 95.39,29.4 97.26,29.4 97.81,28.85 103.46,28.85 103.74,29.12 103.74,29.18 103.92,29.36 104.18,29.36 104.24,29.3 104.28,29.3 v4(104.53,29.05)
  IN4 w0.066: v4(104.53,29.05) v1(104.87,29.05) ; v3(18.19,54.65) 19,53.84 23.45,53.84 24.37,52.92 24.37,50.61 28.22,46.76 30.39,46.76 v1(30.52,46.64)
  BOTTOM w0.097: JAUD1.7 13.2,56.1 13.36,56.25 14.84,56.25 16,55.09 17.75,55.09 v3(18.19,54.65) ; v1(30.52,46.64) 29.69,45.81 CA57.1 v2(29.69,44.75)
I2S_SCLK: length 108.6
  IN1 w0.066: v4(104.05,29.05) 103.7,28.7 97.75,28.7 97.2,29.25 95.34,29.25 79.79,44.81 28.81,44.81 20.08,53.54 19.19,53.54 18.82,53.91 18.41,53.91 18.2,54.11 v3(18.2,54.11)
  IN4 w0.066: v1(104.87,28.55) 104.54,28.55 v4(104.05,29.05)
  BOTTOM w0.097: JAUD1.3 11.36,56.9 11.48,56.78 12.43,56.78 12.7,57.05 14.53,57.05 16.07,55.51 18.44,55.51 19.1,54.85 19.1,54.04 18.95,53.89 18.42,53.89 18.2,54.11 v3(18.2,54.11)
I2S_SDIN0: length 136.1
  IN1 w0.066: v3(17.41,54.72) 17.45,54.72 17.88,55.15 19.34,55.15 29.12,45.37 80.17,45.37 93.91,31.63 106.05,31.63 109.52,28.17 128.43,28.17 130.07,26.53 130.07,26.13 130.32,25.87 v4(130.59,25.87)
  IN4 w0.066: v1(130.23,23.12) 130.23,23.55 130.67,23.98 130.67,24.53 130.89,24.75 130.89,24.76 130.9,24.77 130.9,25.57 v4(130.59,25.87)
  BOTTOM w0.097: v3(17.41,54.72) 17,54.32 14.27,54.32 12.89,55.7 v2(12.11,55.7) JAUD1.9
I2S_SDOUT: length 105.4
  IN1 w0.066: v4(104.53,30.05) 95.15,30.05 79.97,45.23 29.06,45.23 19.3,55 18.04,55 17.75,54.71 17.75,54.2 17.7,54.14 v3(17.39,54.14)
  IN4 w0.066: v1(104.87,30.05) v4(104.53,30.05)
  BOTTOM w0.097: v3(17.39,54.14) 14.18,54.14 13.72,54.6 v2(12.86,54.6) 12.1,55.36 11.49,55.36 11.43,55.3 JAUD1.11
I2S_SFRM: length 105.4
  IN1 w0.066: v4(104.53,29.55) 95.45,29.55 79.91,45.09 28.93,45.09 20.11,53.92 19.35,53.92 18.87,54.39 18.87,54.47 18.72,54.62 v3(18.72,54.64)
  IN4 w0.066: v1(104.87,29.55) v4(104.53,29.55)
  BOTTOM w0.097: v3(18.72,54.64) 18.72,54.8 18.21,55.31 16.02,55.31 14.59,56.74 v2(12.88,56.74) 12.64,56.5 JAUD1.5
I_ADP: length 168.2
  IN2 w0.254: v3(240.7,29.56) 240.25,29.56 236.93,26.23 235.22,26.23 233.74,24.75 233.74,12.92 235.97,10.69 266.38,10.69 269.21,13.52 271.62,13.52 272.37,13.52 273.23,12.66 273.23,12.4 274.61,11.02 286.8,11.02 288.05,12.26 288.05,15.09 291.86,18.9 293.32,18.9 294.39,19.97 294.39,39.99 292.39,41.99 292.39,44.78 290.89,46.28 288.17,46.28 287.21,47.25 286.7,47.76 286.15,47.76 285.35,48.56 285.35,51.52 285.61,51.77 292.48,51.77 292.75,52.03 v4(292.75,52.09)
  IN4 w0.254: v4(292.75,52.09) 292.75,52.11 292.58,52.27 292.58,53.02 292.58,55.58 292.09,56.07 292.09,66.02 293.7,67.63 293.7,74.33 293.53,74.49 293.53,77.05 293.66,77.18 v1(293.66,77.56) 293.66,77.61 292.78,78.49 292.78,78.8 v1(293.11,79.13)
  BOTTOM w0.102: PR713.1 241.39,29.77 v2(242.31,28.85)
  BOTTOM w0.254: v3(240.7,29.56) 240.96,29.81 PR713.1 ; C257.1 295.82,76.71 294.97,77.56 v1(293.66,77.56)
I_BATT: length 4.3
  BOTTOM w0.076: U38.M4 292.36,78.88 292.75,78.88 292.86,78.77 292.86,77.93 C259.1 R228.1
I_SYS: length 165.2
  TOP w0.254: v5(286.64,47.62) 286.66,47.64 286.66,48.38 286.73,48.45 286.73,49.33 287.11,49.72 287.11,49.99 286.93,50.17 286.93,58.23 287.11,58.41 287.11,75.58 288.71,77.18 v5(295.49,77.18)
  IN1 w0.254: v5(286.64,47.62) 286.68,47.59 286.68,47.15 v4(287.23,46.59) ; v5(295.49,77.18) v4(295.49,77.51)
  IN2 w0.254: v4(241.25,32.24) 241.39,32.1 241.39,29.61 240.02,28.24 239.4,28.24 237.06,25.9 235.36,25.9 234.07,24.61 234.07,13.06 236.11,11.02 266.24,11.02 269.09,13.86 272.49,13.86 273.56,12.8 273.56,12.54 274.73,11.37 286.34,11.37 287.72,12.74 287.72,15.23 291.72,19.23 293.16,19.23 294.06,20.13 294.06,39.78 292.06,41.77 292.06,44.64 290.75,45.95 287.73,45.95 287.23,46.45 v4(287.23,46.59)
  IN4 w0.254: v4(295.49,77.51) v1(295.49,78.07) ; v4(241.25,32.24) 241.25,31.98 v1(241.39,31.84)
  BOTTOM w0.254: U38.M1 294.67,78.07 v1(295.49,78.07)
ILMT_1.05V: length 4.2
  BOTTOM w0.254: PU500.3 75.43,22.97 v2(74.71,23.7) 74.47,23.93 74.47,23.93 73.69,24.71 PR507.1 PR504.2
IMON: length 3.7
  BOTTOM w0.254: PU702.3 186.81,16.68 v2(187.27,16.21) 187.62,15.87 187.79,15.87 PC540.2 PR520.2
INV_PWM_R: length 10
  IN4 w0.076: v1(261.25,8.95) 261.25,10.41 259.8,11.85 v1(259.8,12.79)
  BOTTOM w0.076: v1(259.8,12.79) 259.64,12.96 259.64,13.21 259.75,13.33 D4.1 259.75,16.38 259.55,16.58 R48.1 v2(259.55,18.18)
IRQ_SERIRQ: length 277.8
  TOP w0.076: v5(116.5,12.26) 116.6,12.16 121.5,12.16 124.36,9.3 128.63,9.3 131.98,9.3 132.52,9.85 v2(133.03,9.85) 133.34,9.85 136.92,6.28 164.87,6.28 170.48,11.89 170.65,11.89 172.38,13.63 172.38,13.86 v3(172.62,14.1)
  IN1 w0.076: v4(117.18,12.1) 117.16,12.1 117.12,12.06 116.65,12.06 116.5,12.21 v5(116.5,12.26)
  IN3 w0.076: v3(172.62,14.1) 172.53,14.01 172.53,12.45 173.34,11.64 181.99,11.64 183.1,10.53 184.17,10.53 184.56,10.14 187.91,10.14 188.16,10.15 188.52,9.78 191.79,9.78 192.33,10.33 199.95,10.33 200.21,10.06 210.16,10.06 210.65,9.58 224.99,9.58 228.56,13.15 232.56,13.15 233.03,12.68 247.63,12.68 250.92,9.39 267.22,9.39 268.36,10.53 272.69,10.53 273.04,10.18 281.69,10.18 282.93,11.42 284.99,11.42 287.39,13.81 288.9,13.81 289.29,14.2 289.89,14.2 297.81,22.13 297.81,45.56 297.39,45.98 296.85,45.98 296.45,46.38 295.64,46.38 293.83,48.19 293.83,50.16 v4(293.72,50.26)
  IN4 w0.076: v4(293.72,50.26) 293.71,50.26 292.66,50.26 291.49,51.43 291.49,52.56 291.49,52.56 291.49,55.12 290.99,55.62 290.99,57.69 289.74,58.95 289.74,66.32 290.47,67.06 290.47,68.35 291.06,68.93 291.06,71.38 290.73,71.71 290.73,75.6 291.67,76.54 291.67,78.73 291.37,79.03 291.37,79.39 v1(291.61,79.63) ; v1(117.64,11.83) 117.61,11.8 117.45,11.8 117.18,12.07 v4(117.18,12.1) 117.18,12.17 117.55,12.54 119.96,12.54 120.64,13.22 120.97,13.22 121.73,13.99 123.11,13.99 123.91,13.19 124.5,13.19 125.03,12.67 125.9,12.67 126.26,13.04 127.75,13.04 127.88,13.17 128.23,13.17 128.47,13.41 v1(128.63,13.41)
ISUMN: length 14.7
  BOTTOM w0.254: PR565.2 PC537.2 ; PC537.2 181.76,18.06 PR540.2 ; PC537.2 PC531.2 180.07,18.9 v2(179.52,19.46) 179.2,19.46 PH503.2 177.73,20.92 176.06,20.92 175.45,21.53 175.45,24.34 175.21,24.58 173.02,24.58 PL504.3
ISUMP: length 9.3
  BOTTOM w0.102: PR563.1 183.25,22.76 182.76,23.25 v2(182.2,23.25)
  BOTTOM w0.254: PC531.1 PC537.1 PR565.1 ; PR565.1 182.47,20.12 PR546.2 183.25,21.7 PR563.1 PR562.1 ; PR565.1 182.99,19.6 PU702.10
JTAG_CLK: length 23.2
  IN1 w0.076: v4(289.2,83.02) 289.2,84.07 288.92,84.35 288.92,85.77 288.73,85.96 288.73,86.68 290.89,88.84 290.89,92.4 293.37,94.87 296.15,94.87 296.47,95.19 296.47,95.83 296.1,96.19 v3(296.06,96.19)
  IN4 w0.076: v4(289.2,83.02) 289.28,83.1 289.58,83.1 v1(289.61,83.13)
  BOTTOM w0.076: v3(296.06,96.19) 296.05,96.19 295.68,95.83 295.68,95.39 295.91,95.17 296.14,95.17 296.47,94.84 JDEG1.4 296.47,94.14 296.25,93.92 296.02,93.92 295.43,93.33 RP17.3
JTAG_RST#: length 6.9
  BOTTOM w0.076: R210.1 290.33,88.79 290.33,86.67 290.17,86.5 R229.2 C161.1 288.86,86.48 288.86,84.39 289.11,84.14 U38.B10
JTAG_TDI: length 20.8
  IN1 w0.076: v4(288.26,86.2) 288.38,86.31 288.38,87.08 288.71,87.41 288.71,88.1 290.4,89.79 290.4,92.84 293.2,95.65 v3(295.03,95.65)
  IN4 w0.076: v7(288.86,83.89) 288.86,84.22 288.71,84.37 288.58,84.37 287.88,85.07 287.88,85.82 v4(288.26,86.2)
  GND3 w0.076: v7(288.86,83.89) 288.88,83.87 289.21,83.87 289.35,83.73 289.35,83.37 v8(289.11,83.13)
  BOTTOM w0.076: RP17.1 294.43,93.3 295.47,94.33 JDEG1.2 295.47,95.04 295.09,95.41 295.09,95.62 295.06,95.65 v3(295.03,95.65)
JTAG_TDO: length 20.7
  IN1 w0.076: v3(296.06,95.61) 295.64,95.19 293.25,95.19 290.68,92.61 290.68,89.86 288.88,88.07 288.88,87.27 288.58,86.96 288.58,85.97 v4(288.29,85.68)
  IN4 w0.076: v4(288.29,85.68) 288.62,85.68 288.86,85.44 288.86,84.5 289.11,84.25 v1(289.11,83.63)
  BOTTOM w0.076: RP17.4 295.93,93.3 296.97,94.33 JDEG1.5 296.97,94.92 296.43,95.46 296.21,95.46 v3(296.06,95.61)
JTAG_TMS: length 19.7
  IN1 w0.076: v4(288.35,87.76) 288.35,88.13 290.18,89.96 290.18,93.06 293.18,96.06 294.89,96.06 v3(295.06,96.22)
  IN4 w0.076: v4(288.35,87.76) 288.35,87.16 288.62,86.89 288.62,85.92 289.11,85.43 v1(289.11,84.63)
  BOTTOM w0.076: RP17.2 294.93,93.38 295.97,94.41 JDEG1.3 295.97,94.83 295.45,95.34 295.45,95.83 v3(295.06,96.22)
JTAG_TRST#: length 43
  IN2 w0.076: v4(154.34,24.47) 154.05,24.76 153.3,24.76 151.86,23.32 151.86,21.69 153.05,20.51 153.05,15.61 155.07,13.59 v4(155.07,12.01)
  IN4 w0.076: v1(154.37,24.07) 154.37,24.44 v4(154.34,24.47) ; v1(173.11,5.95) 173.11,5.97 172.9,6.19 169.78,6.19 v1(169.25,6.72) 169.25,6.74 169.18,6.81 169.18,8.19 166.25,11.13 157.03,11.13 156.9,11.25 156.4,11.75 155.81,11.75 155.69,11.63 v1(155.07,11.63) v4(155.07,12.01)
  BOTTOM w0.076: T13.1 168.72,6.19 RC16.1 169.15,6.62 v1(169.25,6.72) ; U4.3 173.07,5.99 v1(173.11,5.95)
LAGTE: length 10.9
  IN1 w1.016: 188.81,21.76 188.81,24.15 187.48,25.48 182.68,25.48 182.66,25.49
  BOTTOM w0.102: v2(190.02,21.21) 189.57,20.77 v3(188.35,20.77)
  vias: v3(182.03,26.51) v3(182.66,26.51) v3(188.35,20.16)
LCD_CAB_DET#: length 7.2
  IN4 w0.076: v1(129.8,11.63) 129.27,11.63 129.1,11.46 129.1,11.3 129.17,11.23 129.17,10.94 127.35,9.11 126.91,9.11 v1(126.79,8.99)
  BOTTOM w0.076: v1(126.79,8.99) 126.69,8.89 126.69,7.77 126.5,7.58 126.5,7.01 126.4,6.91 RH114.2
LCD_TST: length 134.8
  IN1 w0.076: v4(296.1,82.31) 296.1,82.69 295.31,83.48 294.09,83.48 293.69,83.07 291.93,83.07 291.72,83.29 v4(291.64,83.29)
  IN4 w0.076: v1(291.61,83.63) 291.61,83.32 v4(291.64,83.29) ; v4(296.1,82.31) 296.1,82.07 297.32,80.85 297.32,79.04 298.08,78.28 298.08,75.09 297.94,74.95 297.94,71.71 296.68,70.45 296.68,66.64 301.15,62.17 301.15,34.05 300.64,33.54 300.64,20.97 300.83,20.77 300.83,12.92 299.85,11.94 298.03,11.94 297.95,12.01 293.89,12.01 293.57,11.7 v1(293.57,8.21) 293.67,8.11 293.67,7.04 293.52,6.89 290.64,6.89 289.21,8.31 286.42,8.31 286.17,8.06 286.17,6.72 284.37,4.92 269.28,4.92 v1(264.4,9.8)
  BOTTOM w0.076: v1(293.57,8.21) 293.57,8.7 v2(293.88,9.01) ; v1(264.4,9.8) 264.32,9.87 256.91,9.87 256.75,9.72 JLVDS1.14
LCD_VCC_TEST_EN: length 148
  IN4 w0.076: v1(287.89,83.9) 287.89,84.3 286.54,85.66 v7(286.54,86) ; v3(246.11,17.8) 246.87,17.8 247.34,18.26 252.72,18.26 255.21,15.77 257.76,15.77 258.13,15.4 261.63,15.4 263.85,13.17 269.55,13.17 269.99,12.74 271.21,12.74 271.38,12.56 271.38,11.31 273.96,8.73 281.46,8.73 283.81,11.08 283.81,12.98 286.69,15.87 286.69,16.21 287.92,17.44 294.45,17.44 294.89,17.89 294.89,18.35 294.89,18.35 294.89,22.69 295.2,22.99 295.2,40.4 294.19,41.41 294.19,42.6 293.43,43.36 293.43,44.64 291.52,46.55 291.11,46.55 290.77,46.89 290.77,47.4 288.68,49.49 288.68,49.62 288.68,52.92 286.95,54.65 285.38,54.65 284.32,55.71 284.32,69.98 282.46,71.84 282.46,72.19 283.55,73.28 283.55,79.82 283.49,79.89 283.49,80.92 283.73,81.16 283.73,84.77 283.91,84.95 284.22,85.26 284.22,85.56 285.51,86.85 v1(286.13,86.85)
  GND3 w0.076: v7(286.54,86) 286.13,86.4 v1(286.13,86.85)
  BOTTOM w0.076: U38.B12 287.89,83.91 v1(287.89,83.9) ; v2(247.17,14.01) 246.91,14.27 245.74,14.27 244.63,15.38 D1.3 246.03,15.55 246.11,15.63 v3(246.11,17.8) ; v1(286.13,86.85) 285.86,87.11 R214.2
LG_3V: length 3.6
  IN1 w1.016: 282.69,27.4 285.22,24.86 285.22,24.86
  vias: v3(281.75,28.49) v3(281.77,27.91) v3(285.66,24.07) v3(286.26,24.07)
LG_5V: length 8.8
  IN4 w1.016: 279.26,27.48 279.26,26.41 276.61,23.76 275.35,23.76 274.59,23 274.59,21.99
  BOTTOM w0.102: v2(273.56,20.86) 273.68,20.98 274.13,20.98
  vias: v1(274.51,20.92) v1(274.84,20.92) v1(279.33,28.62) v1(279.33,28.31)
LID_CL_SIO#: length 427.5
  TOP w0.076: v3(6.94,38.3) 3.09,38.3 2.77,37.98 v3(2.77,35.24)
  IN1 w0.076: v4(295.25,68.9) 295.22,68.93 292.82,68.93 292.29,69.46 v4(287.72,69.46)
  IN2 w0.076: v4(287.72,69.46) 287.72,60.85 293.43,55.13 293.43,54.04 294.03,53.45 294.03,53.14 299.01,48.16 299.01,17.71 298.13,16.83 298.13,15.12 298.28,14.96 298.28,13.11 295.97,10.8 295.97,9.26 293.59,6.88 292.52,6.88 289.09,3.45 260.63,3.45 259.28,4.79 244.76,4.79 243.79,3.82 206,3.82 205.75,3.56 202.43,3.56 201.69,4.3 199.4,4.3 198.05,2.95 151.61,2.95 151.37,3.19 149.18,3.19 148.44,3.93 138.17,3.93 136.37,5.73 134.85,5.73 133.37,4.26 130.56,4.26 130,3.7 128.28,3.7 127.85,4.13 122.97,4.13 119.24,7.87 110.13,7.87 109.55,8.45 109.33,8.45 109.08,8.7 108.86,8.7 108.66,8.91 107.69,8.91 107.35,9.25 102.55,9.25 101.76,10.04 98.48,10.04 98.05,10.47 94.63,10.47 93.04,12.06 86.18,12.06 85.67,12.57 77.42,12.57 76.91,12.06 69.48,12.06 60.86,20.68 60.86,23.13 51.33,32.66 35.6,32.66 32.63,35.63 27.2,35.63 26.16,34.58 26.16,34.56 19.34,34.56 16.01,37.89 7.35,37.89 v3(6.94,38.3)
  IN4 w0.076: v1(293.61,80.63) 294.37,80.63 295.12,79.88 295.12,75.89 295.25,75.76 v4(295.25,68.9)
  BOTTOM w0.076: v1(293.61,80.63) 294.53,80.63 294.7,80.46 294.7,79.98 294.92,79.76 297.36,79.76 298.6,78.53 300.9,78.53 301.42,79.05 v2(301.42,80.38) 301.42,80.6 301.18,80.84 301.18,84.4 300.9,84.68 300.06,84.68 299.88,84.85 U54.2 ; C200.1 R284.2 6.59,37.94 v3(6.94,38.3) ; U46.6 1.8,35.49 2.05,35.24 v3(2.77,35.24)
LINE1_L: length 135.5
  TOP w0.406: v3(11.75,54.9) 10.61,53.76 7.43,53.76 6.59,52.93 6.59,47.24 7.73,46.1 7.73,43.66 8.44,42.95 8.44,41.07 12.78,36.73 18.63,36.73 19.89,35.47 22.12,35.47 22.24,35.36 26.64,35.36 27.38,36.1 36.07,36.1 40.24,31.92 43.1,31.92 47.59,27.44 57.51,27.44 60.16,24.78 v2(60.16,23) 60.16,14.7 61.65,13.22 61.65,11.89 65.37,8.16 73.51,8.16 77.37,12.01 83.84,12.01 87.93,7.92 87.93,6.33 88.97,5.29 90.72,5.29 92.71,7.28 94.86,7.28 96.21,5.93 96.21,5.25 v3(96.18,5.22)
  BOTTOM w0.203: v3(11.75,54.9) JAUD1.13
LINE1_R: length 145.5
  TOP w0.406: v3(95.53,5.12) 95.53,5.66 94.59,6.61 93,6.61 91.74,5.35 91.74,4.02 91.5,3.78 88.18,3.78 87.27,4.68 87.27,7.64 83.58,11.33 77.65,11.33 73.78,7.47 65.11,7.47 60.99,11.59 60.99,12.94 59.5,14.43 59.5,24.5 57.23,26.77 47.31,26.77 v2(44.28,29.8) 42.82,31.26 39.97,31.26 35.79,35.44 27.65,35.44 26.92,34.7 21.96,34.7 21.85,34.81 17.37,34.81 16.11,36.07 12.25,36.07 7.78,40.55 7.78,42.67 7.05,43.39 7.05,43.78 6.21,44.62 4.19,44.62 3.79,45.01 3.79,52.27 4.32,52.8 4.32,53.88 4.86,54.42 9.46,54.42 11.29,56.25 11.29,57.46 v3(11.76,57.93)
  BOTTOM w0.203: v3(11.76,57.93) 11.76,57.76 11.3,57.3 JAUD1.1
LINE_PLUG#: length 128.6
  IN2 w0.076: v3(103.27,7.13) 103.27,7.12 102.68,6.52 99.18,6.52 97.49,8.21 94.21,8.21 93.05,9.36 85.9,9.36 85.01,10.25 78.42,10.25 76.21,8.04 64.39,8.04 62.74,6.39 61.71,6.39 61.02,7.08 58.97,7.08 56.81,9.24 47.2,9.24 45.29,11.15 45.29,22.11 44.16,23.24 44.16,24.36 42.66,25.85 37.88,25.85 34,29.73 21.84,29.73 21.41,29.3 15.29,29.3 12.95,31.64 12.05,31.64 6.02,37.67 6.02,39.34 6.3,39.62 6.3,41.1 v3(6.26,41.14)
  BOTTOM w0.076: R365.1 v3(6.26,41.14) 5.97,41.43 Q47.1 4.39,41.43 v2(4.14,41.68)
  BOTTOM w0.203: JIO1.18 103.1,6.95 v3(103.27,7.13)
LINE_PLUG#_Q: length 15.5
  BOTTOM w0.076: JAUD1.41 11.66,49.3 11.87,49.09 11.87,48.48 12.57,47.78 12.72,47.78 12.8,47.71 12.8,45.93 12.34,45.47 7.91,45.47 7.67,45.23 v6(7.67,43.91) 7.67,43.7 7.61,43.64 7.61,41.58 7.45,41.43 Q47.6 6.97,40.63 R365.2
LPC_AD0: length 289.7
  IN1 w0.076: v4(291.16,80.87) 291.16,80.37 291.83,79.69 291.83,78.42 289.9,76.5 286.33,76.5 286,76.17 283.68,76.17 v4(282.99,75.48)
  IN3 w0.076: v4(130.74,22.83) 130.74,22.75 129.45,21.45 129.45,20.55 128.01,19.12 128.01,16.81 127.27,16.07 126.88,16.07 126.24,15.42 126.24,9.82 129.66,6.4 135.68,6.4 136.13,5.95 137.09,5.95 137.62,5.43 138.93,5.43 139.23,5.12 142.83,5.12 145.65,7.94 153.56,7.94 154,8.37 161.03,8.37 162.56,6.85 162.56,4.89 165.38,2.07 202.3,2.07 202.8,2.57 206.17,2.57 206.42,2.82 236.1,2.82 237.88,4.6 243.67,4.6 244.19,4.08 260.35,4.08 261.36,3.07 288.14,3.07 292.35,7.28 292.35,7.93 297.33,12.91 297.97,12.91 300.3,15.23 300.3,49.88 292.36,57.82 292.36,66.08 293.83,67.54 293.83,74.31 293.25,74.88 293.25,77.16 290.35,80.07 290.35,80.93 290.53,81.12 290.9,81.12 v4(291.16,80.87)
  IN4 w0.076: v4(291.16,80.87) 291.16,80.53 v1(291.11,80.48) ; v1(282.74,75.81) 282.97,75.58 282.97,75.51 v4(282.99,75.48) ; v1(130.88,22.5) 130.88,22.69 v4(130.74,22.83)
  BOTTOM w0.076: U38.K6 v1(291.11,80.48)
LPC_AD1: length 287.8
  IN1 w0.076: v4(291.11,79.96) 291.11,79.91 291.68,79.34 291.68,78.49 289.84,76.65 286.46,76.65 286.17,76.94 283.96,76.94 v4(283.08,76.07)
  IN3 w0.076: v4(129.83,22.9) 129.33,22.9 129.06,22.63 129.06,20.59 127.71,19.24 127.71,16.97 127.11,16.37 126.76,16.37 125.94,15.55 125.94,9.69 129.53,6.09 135.55,6.09 136.02,5.63 136.98,5.63 137.49,5.12 138.8,5.12 139.11,4.82 142.97,4.82 145.79,7.64 153.69,7.64 154.11,8.06 156.83,8.06 157.38,7.51 157.9,7.51 158.42,8.03 160.94,8.03 162.26,6.72 162.26,4.77 165.25,1.77 202.44,1.77 202.93,2.25 206.28,2.25 206.55,2.52 236.23,2.52 237.98,4.27 243.56,4.27 244.08,3.75 260.23,3.75 261.22,2.76 288.3,2.76 292.66,7.12 292.66,7.81 297.45,12.6 298.13,12.6 300.6,15.08 300.6,52.17 292.67,60.1 292.67,65.96 294.13,67.42 294.13,74.43 293.56,75.01 293.56,77.39 291.11,79.83 v4(291.11,79.96)
  IN4 w0.076: v4(129.83,22.9) 129.98,22.75 130.13,22.75 130.38,22.5 v1(130.38,22.5) ; v1(282.74,76.31) 282.98,76.07 v4(283.08,76.07) ; v1(291.11,79.63) v4(291.11,79.96)
LPC_AD2: length 282
  IN1 w0.076: v4(283.08,76.58) 283.17,76.58 283.68,77.09 286.23,77.09 286.52,76.8 289.71,76.8 291.32,78.42 v4(291.32,78.58)
  IN3 w0.076: v4(131.28,22.42) 130.73,22.42 129.6,21.3 129.6,20.46 128.17,19.03 128.17,16.74 127.34,15.91 126.95,15.91 126.39,15.36 126.39,9.9 129.74,6.55 136.29,6.55 136.74,6.1 138.47,6.1 139.3,5.28 142.77,5.28 145.59,8.09 153.5,8.09 154,8.59 161.03,8.59 162.71,6.91 162.71,4.96 165.44,2.23 202.03,2.23 202.52,2.72 206.1,2.72 206.36,2.98 236.04,2.98 237.96,4.9 243.58,4.9 244.25,4.23 260.41,4.23 261.43,3.22 288.07,3.22 292.2,7.35 292.2,8.01 297.25,13.06 297.73,13.06 300.15,15.48 300.15,49.82 292.21,57.75 292.21,66.15 293.67,67.61 293.67,74.21 293.09,74.79 293.09,76.82 v4(291.32,78.58)
  IN4 w0.076: v4(283.08,76.58) 282.86,76.81 v1(282.74,76.81) ; v1(291.11,79.13) 291.11,78.99 291.32,78.78 v4(291.32,78.58) ; v1(131.13,22.07) 131.28,22.22 v4(131.28,22.42)
LPC_AD3: length 286.8
  IN1 w0.076: v4(283.11,77.09) 283.26,77.25 286.29,77.25 286.59,76.95 289.61,76.95 290.5,77.84 290.5,79.83 290.66,80 v4(290.66,80.8)
  IN3 w0.076: v4(290.66,80.8) 290.66,79.96 293.41,77.22 293.41,74.94 293.98,74.37 293.98,67.48 292.52,66.02 292.52,60.04 300.45,52.1 300.45,15.16 298.04,12.76 297.39,12.76 292.5,7.87 292.5,7.21 288.21,2.91 261.29,2.91 260.28,3.92 244.13,3.92 243.61,4.43 237.93,4.43 236.17,2.67 206.48,2.67 206.23,2.42 202.87,2.42 202.38,1.92 165.32,1.92 162.41,4.83 162.41,6.78 160.97,8.22 158.38,8.22 157.88,7.73 157.48,7.73 156.98,8.22 154.06,8.22 153.63,7.79 145.73,7.79 142.91,4.97 139.17,4.97 138.86,5.28 137.55,5.28 137.03,5.8 136.07,5.8 135.62,6.25 129.6,6.25 126.09,9.76 126.09,15.49 126.82,16.22 127.18,16.22 127.86,16.9 127.86,19.18 129.26,20.58 129.26,22.39 v4(129.37,22.5)
  IN4 w0.076: v1(282.74,77.31) 282.89,77.31 v4(283.11,77.09) ; v1(129.88,22.5) v4(129.37,22.5) ; v4(290.66,80.8) 290.61,80.75 v1(290.61,80.13)
LPC_FRAME#: length 287.8
  IN1 w0.076: v4(291.81,81.36) 291.33,81.83 290.59,81.83 290.12,81.35 290.12,81.02 290.35,80.79 290.35,77.93 289.52,77.11 286.65,77.11 286.36,77.4 283.33,77.4 v4(283.12,77.61)
  IN2 w0.076: v4(291.81,81.36) 291.76,81.31 291.76,79.69 290.61,78.54 290.61,72.23 291.46,71.38 291.46,69.92 292.9,68.48 292.9,68.17 v4(293.28,67.78)
  IN3 w0.076: v4(293.28,67.78) 292.06,66.57 292.06,57.69 299.99,49.76 299.99,15.54 297.68,13.23 297.17,13.23 292.05,8.11 292.05,7.41 288,3.37 261.49,3.37 260.47,4.39 244.3,4.39 243.64,5.05 237.9,5.05 235.98,3.13 206.29,3.13 206.04,2.88 202.46,2.88 201.96,2.38 165.51,2.38 162.87,5.02 162.87,6.97 161.06,8.78 153.97,8.78 153.44,8.25 145.5,8.25 142.71,5.45 139.36,5.45 138.51,6.3 136.84,6.3 136.44,6.7 129.82,6.7 126.6,9.92 126.6,14.51 127.02,14.93 127.22,14.93 128.13,15.84 128.13,16.49 128.32,16.68 128.32,18.96 129.42,20.06 129.75,20.06 130.54,20.86 130.54,21.19 v4(130.69,21.34)
  IN4 w0.076: v1(282.74,77.81) 282.93,77.81 v4(283.12,77.61) ; v1(291.61,80.13) 291.61,81.17 v4(291.81,81.36) ; v4(130.69,21.34) 130.69,21.34 130.69,21.46 130.87,21.63 v1(130.88,21.63)
LX_1.05V: length 6.4
  TOP w1.016: 74.53,19.55 74.71,19.55 77.46,22.29 77.46,24.68
  vias: v2(77.42,25.07) v3(73.67,19.8) v3(73.67,19.22) v3(77.13,25.62) v3(77.76,25.62)
LX_3V: length 5.8
  IN4 w1.016: 283.33,24.13 284.06,24.86 284.06,29.61
  vias: v1(282.79,23.4) v1(283.09,23.4) v1(284.06,30.9) v1(284.06,30.52) v1(285.86,22.77) v2(287.33,20.6)
LX_5V: length 6.3
  IN4 w1.016: 275.91,25.72 277.35,27.17 277.35,29.33
  BOTTOM w0.102: v3(273.16,21.76) 273.16,20.37 272.69,19.9 v2(272.69,19.9)
  vias: v1(275.63,24.78) v1(276.01,24.77) v1(277.3,30.09) v1(277.68,30.09) v3(273.77,21.76) v3(277.66,20.39) v3(277.66,19.8)
M_CLK_A_DDR0: length 113.4
  IN3 w0.076: v3(176.86,48.56) 176.86,48.74 176.97,48.85 177.15,48.85 177.26,48.74 177.26,48.33 177.71,47.88 180.21,47.88 180.28,47.81 180.28,47.68 180.45,47.52 180.81,47.52 180.97,47.68 180.97,47.82 181.04,47.88 181.29,47.88 181.38,47.8 181.38,47.68 181.52,47.54 182.45,47.54 v4(182.62,47.38) 182.8,47.55 183.03,47.55 184.5,49.03 185.66,49.03 186.09,49.46 187.31,49.46 188.03,48.73 188.44,48.73 v3(188.7,48.48) ; v3(159.36,48.48) 159.1,48.73 158.7,48.73 157.98,49.46 156.75,49.46 156.17,48.87 155.19,48.87 153.87,47.55 153.46,47.55 v4(153.28,47.38) 153.12,47.54 152.27,47.54 151.93,47.88 151.71,47.88 151.64,47.81 151.64,47.62 151.47,47.45 151.12,47.45 150.95,47.62 150.95,47.81 150.87,47.88 148.58,47.88 148.16,48.31 148.16,48.79 148.09,48.85 147.75,48.85 147.53,48.63 v3(147.53,48.56) ; v4(153.97,25.6) 154.2,25.83 154.32,25.83 155.43,26.94 155.43,27.94 155.36,28.01 155.36,28.02
  IN3 w0.178: v3(167.07,45.31) 167.3,45.53 167.52,45.53 167.61,45.44 167.61,42.07 166.52,40.98 166.52,39.89 167.05,39.37 167.05,39.08 166.62,38.65 166.33,38.65 164.85,40.12 164.2,40.12 163.52,39.44 163.52,38.8 165,37.32 165,37.03 164.57,36.6 164.28,36.6 162.8,38.08 162.16,38.08 161.47,37.39 161.47,36.75 162.49,35.73 162.95,35.27 162.95,34.98 162.52,34.55 162.23,34.55 160.75,36.03 160.11,36.03 159.42,35.34 159.42,34.7 160.9,33.22 160.9,32.93 160.47,32.5 160.18,32.5 159.4,33.28 158.75,33.28 158.07,32.6 158.07,31.96 158.85,31.17 158.85,30.88 158.42,30.45 158.13,30.45 157.9,30.68 157.19,30.68 156.57,30.07 156.57,29.52 155.36,28.31 155.36,28.02
  IN4 w0.076: v4(153.28,47.38) 153.28,47.41 153.43,47.55 153.59,47.55 153.93,47.21 153.93,46.72 154.59,46.07 157.43,46.07 157.64,46.28 157.64,46.65 157.77,46.78 157.97,46.78 158.1,46.65 158.1,46.52 158.3,46.32 158.59,46.32 158.79,46.52 158.79,46.69 158.87,46.78 162.9,46.78 163.6,46.08 166.3,46.08 166.8,45.59 166.8,45.59 v3(167.07,45.31) 167.27,45.51 167.56,45.51 168.13,46.08 170.71,46.08 172.03,47.4 181.63,47.4 181.8,47.57 182.43,47.57 v4(182.62,47.38) ; v4(153.97,25.6) 154.09,25.6 154.16,25.53 154.16,25.41 153.96,25.2 153.72,25.2 153.66,25.27 153.27,25.27 153.06,25.48 152.83,25.48 152.75,25.41 152.75,25.19 v1(152.83,25.12)
  BOTTOM w0.076: v3(147.53,48.56) 147.19,48.9 UD3.J7 ; RD83.1 166.28,44.65 166.38,44.75 166.66,44.75 166.89,44.98 166.89,45.13 v3(167.07,45.31) ; UD1.J7 176.55,48.9 176.86,48.58 v3(176.86,48.56) ; v3(159.36,48.48) 159.73,48.84 UD4.J7 ; v3(188.7,48.48) 189.06,48.84 UD2.J7
M_CLK_A_DDR#0: length 113.6
  IN3 w0.076: v4(154.53,25.59) 154.53,25.82 155.59,26.88 155.59,27.95 155.64,28.01 155.64,28.02 ; v3(188.65,49.24) 188.65,49.2 188.34,48.89 188.1,48.89 187.38,49.61 186.02,49.61 185.6,49.18 184.44,49.18 182.97,47.71 182.77,47.71 v4(182.62,47.86) 182.45,47.69 181.58,47.69 181.53,47.74 181.53,47.86 181.35,48.04 180.97,48.04 180.82,47.88 180.82,47.74 180.74,47.67 180.51,47.67 180.44,47.74 180.44,47.87 180.27,48.04 177.77,48.04 177.41,48.4 177.41,48.8 177.21,49 177.01,49 176.85,49.16 v3(176.85,49.31) ; v3(147.48,49.25) 147.73,49 148.16,49 148.31,48.85 148.31,48.37 148.65,48.04 150.94,48.04 151.1,47.87 151.1,47.68 151.18,47.6 151.41,47.6 151.48,47.68 151.48,47.87 151.65,48.04 151.99,48.04 152.34,47.69 153.12,47.69 v4(153.28,47.86) 153.44,47.71 153.8,47.71 155.12,49.02 156.11,49.02 156.69,49.61 158.04,49.61 158.76,48.89 159,48.89 159.31,49.2 v3(159.31,49.24)
  IN3 w0.178: v3(167.09,45.93) 167.21,45.81 167.64,45.81 167.89,45.56 167.89,41.95 166.8,40.86 166.8,40.01 167.33,39.48 167.33,38.96 166.73,38.37 166.21,38.37 164.73,39.85 164.32,39.85 163.8,39.32 163.8,38.91 165.28,37.43 165.28,36.91 164.68,36.32 164.16,36.32 162.68,37.8 162.27,37.8 161.75,37.28 161.75,36.86 162.64,35.97 163.23,35.38 163.23,34.87 162.63,34.27 162.12,34.27 160.64,35.75 160.22,35.75 159.7,35.23 159.7,34.81 161.18,33.33 161.18,32.82 160.59,32.22 160.07,32.22 159.28,33.01 158.87,33.01 158.35,32.48 158.35,32.07 159.13,31.29 159.13,30.77 158.54,30.17 158.02,30.17 157.78,30.4 157.3,30.4 156.85,29.95 156.85,29.4 155.64,28.19 155.64,28.02
  IN4 w0.076: v4(154.53,25.59) 154.53,25.56 154.02,25.05 153.66,25.05 153.59,25.11 153.2,25.11 153.07,24.99 153.07,24.86 v1(152.83,24.62) ; v4(182.62,47.86) 182.48,47.72 181.74,47.72 181.57,47.55 171.97,47.55 170.64,46.23 168.07,46.23 167.5,45.66 167.36,45.66 v3(167.09,45.93) 166.9,45.74 166.86,45.74 166.37,46.23 163.66,46.23 162.96,46.93 158.81,46.93 158.63,46.75 158.63,46.59 158.52,46.47 158.36,46.47 158.25,46.59 158.25,46.72 158.04,46.93 157.71,46.93 157.49,46.72 157.49,46.35 157.36,46.22 154.65,46.22 154.09,46.78 154.09,47.27 153.66,47.71 153.4,47.71 153.28,47.82 v4(153.28,47.86)
  BOTTOM w0.076: UD3.K7 147.12,49.61 v3(147.48,49.25) ; v3(176.85,49.31) 176.46,49.7 UD1.K7 ; v3(159.31,49.24) 159.73,49.66 UD4.K7 ; v3(167.09,45.93) 166.71,45.55 166.71,45.05 166.61,44.95 166.53,44.95 RD85.1 ; UD2.K7 189.06,49.66 v3(188.65,49.24)
M_CLK_B_DDR0: length 129.9
  IN3 w0.076: v3(100.72,48.48) 100.46,48.73 100.05,48.73 99.33,49.46 98.11,49.46 97.52,48.87 96.54,48.87 95.22,47.55 94.82,47.55 v4(94.64,47.38) 94.47,47.54 93.63,47.54 93.29,47.88 93.07,47.88 92.99,47.81 92.99,47.62 92.83,47.45 92.47,47.45 92.31,47.62 92.31,47.81 92.23,47.88 89.94,47.88 89.51,48.31 89.51,48.79 89.45,48.85 89.11,48.85 88.89,48.63 v3(88.89,48.56) ; v3(130.05,48.48) 129.79,48.73 129.39,48.73 128.67,49.46 127.44,49.46 127.01,49.03 125.86,49.03 124.39,47.55 124.15,47.55 v4(123.97,47.38) 123.81,47.54 122.96,47.54 122.62,47.88 122.4,47.88 122.33,47.81 122.33,47.68 122.16,47.52 121.81,47.52 121.64,47.68 121.64,47.81 121.56,47.88 119.08,47.88 118.85,48.11 118.85,48.79 118.79,48.85 118.51,48.85 v3(118.22,48.56) ; 140.38,29.03 140.38,29.01 140.45,28.95 140.45,28.31 140.33,28.2 140.33,26.74 140.21,26.61 140.21,26.32 140.52,26 v4(140.52,25.96)
  IN3 w0.178: 140.38,29.03 140.38,30.89 139.27,32 139.27,36.13 135.05,40.35 134.47,40.35 134.14,40.68 134.14,40.99 133.94,41.19 133.13,41.19 132.92,40.99 132.92,40.58 132.47,40.12 129.96,40.12 129.51,40.58 129.51,40.86 129.3,41.06 128.49,41.06 128.29,40.86 128.29,40.58 127.83,40.12 123.6,40.12 123.24,39.77 123.24,38.79 122.86,38.41 121.37,38.41 120.99,38.79 120.99,40.88 120.85,41.01 119.91,41.01 119.8,40.9 119.8,38.82 119.39,38.41 118.07,38.41 117.69,38.79 117.69,40.3 117.56,40.43 116.6,40.43 116.47,40.3 116.47,38.9 116.09,38.52 114.64,38.52 114.26,38.9 114.26,40.72 114.04,40.94 112.04,40.94 111.07,41.9 111.07,45.79 110.78,46.08 110.56,46.08 v3(110.42,45.94)
  IN4 w0.076: v1(140.7,24.62) 140.78,24.54 140.78,24.45 140.68,24.36 140.6,24.36 140.55,24.31 140.43,24.31 140.23,24.51 140.23,25.51 140.14,25.6 140.14,26.09 140.26,26.21 140.33,26.21 140.4,26.14 140.47,26.14 140.52,26.09 v4(140.52,25.96) ; v4(123.97,47.38) 123.78,47.57 123.57,47.57 123.4,47.4 123.24,47.4 123.17,47.33 123.17,46.93 123,46.77 122.65,46.77 122.48,46.93 122.48,47.68 122.4,47.76 122.18,47.76 122.1,47.68 122.1,46.93 121.93,46.77 121.58,46.77 121.41,46.93 121.41,47.33 121.34,47.4 113.26,47.4 112.08,46.22 110.7,46.22 v3(110.42,45.94) 110.07,46.3 109.31,46.3 109.1,46.5 98.74,46.5 98.56,46.32 95.68,46.32 95.29,46.71 95.29,47.27 95.01,47.55 94.78,47.55 94.64,47.41 v4(94.64,47.38)
  BOTTOM w0.076: v3(110.42,45.94) 109.54,45.05 RD84.1 ; UD6.J7 117.9,48.9 118.22,48.58 v3(118.22,48.56) ; UD8.J7 101.08,48.84 v3(100.72,48.48) ; v3(88.89,48.56) 88.54,48.9 UD7.J7 ; v3(130.05,48.48) 130.42,48.84 UD5.J7
M_CLK_B_DDR#0: length 130.1
  IN3 w0.076: v3(100.67,49.24) 100.67,49.2 100.36,48.89 100.12,48.89 99.4,49.61 98.04,49.61 97.46,49.02 96.48,49.02 95.16,47.71 94.79,47.71 v4(94.64,47.86) 94.47,47.69 93.69,47.69 93.35,48.04 93,48.04 92.84,47.87 92.84,47.68 92.76,47.6 92.53,47.6 92.46,47.68 92.46,47.87 92.29,48.04 90,48.04 89.67,48.37 89.67,48.85 89.51,49 88.99,49 88.83,49.15 v3(88.83,49.25) ; v3(118.21,49.31) 118.51,49 118.85,49 119,48.85 119,48.18 119.14,48.04 121.63,48.04 121.79,47.87 121.79,47.74 121.87,47.67 122.1,47.67 122.17,47.74 122.17,47.87 122.34,48.04 122.68,48.04 123.03,47.69 123.81,47.69 v4(123.97,47.86) 124.13,47.71 124.32,47.71 125.8,49.18 126.95,49.18 127.38,49.61 128.73,49.61 129.45,48.89 129.69,48.89 130,49.2 v3(130,49.24) ; 140.66,29.03 140.66,29.01 140.6,28.95 140.6,28.25 140.49,28.14 140.49,26.51 v4(140.52,26.47)
  IN3 w0.178: v3(110.42,46.73) 110.42,46.45 110.51,46.36 110.89,46.36 111.35,45.9 111.35,42.02 112.15,41.22 114.16,41.22 114.54,40.84 114.54,39.02 114.76,38.8 115.97,38.8 116.19,39.02 116.19,40.42 116.48,40.71 117.67,40.71 117.97,40.42 117.97,38.91 118.18,38.69 119.28,38.69 119.52,38.93 119.52,41.02 119.79,41.29 120.97,41.29 121.27,40.99 121.27,38.91 121.49,38.69 122.74,38.69 122.96,38.91 122.96,39.88 123.48,40.4 127.75,40.4 128.03,40.69 128.03,40.97 128.39,41.32 129.41,41.32 129.76,40.97 129.76,40.69 130.04,40.4 132.39,40.4 132.67,40.69 132.67,41.09 133.02,41.45 134.04,41.45 134.4,41.09 134.4,40.78 134.55,40.63 135.16,40.63 139.55,36.25 139.55,32.12 140.66,31 140.66,29.03
  IN4 w0.076: v4(94.64,47.86) 94.64,47.82 94.76,47.71 95.07,47.71 95.44,47.33 95.44,46.78 95.75,46.47 98.5,46.47 98.68,46.65 109.17,46.65 109.37,46.45 110.15,46.45 v3(110.42,46.73) 110.78,46.37 112.01,46.37 113.19,47.55 121.4,47.55 121.57,47.39 121.57,47 121.64,46.92 121.87,46.92 121.95,47 121.95,47.74 122.11,47.91 122.47,47.91 122.63,47.74 122.63,47 122.71,46.92 122.94,46.92 123.01,47 123.01,47.39 123.18,47.55 123.34,47.55 123.51,47.72 123.83,47.72 v4(123.97,47.86) ; v4(140.52,26.47) 140.41,26.36 140.19,26.36 139.99,26.15 139.99,25.53 140.08,25.45 140.08,24.42 140.34,24.16 140.66,24.16 v1(140.7,24.12)
  BOTTOM w0.076: v3(100.67,49.24) 101.08,49.66 UD8.K7 ; v3(88.83,49.25) 88.47,49.61 UD7.K7 ; v3(110.42,46.73) 109.76,46.07 RD86.1 ; UD5.K7 130.42,49.66 v3(130,49.24) ; UD6.K7 117.82,49.7 v3(118.21,49.31)
M_ODT0: length 80.5
  IN3 w0.076: v3(172.05,49.3) 172.4,49.65 173.94,49.65 174.22,49.37 174.65,49.37 175.82,48.2 177.07,48.2 177.65,47.63 178.21,47.63 178.96,46.88 v4(179.53,46.88) 179.9,46.88 179.98,46.8 179.98,46.74 180.05,46.66 180.2,46.66 180.28,46.74 180.28,47.19 180.36,47.26 180.51,47.26 180.59,47.19 180.59,46.74 180.66,46.66 180.81,46.66 180.89,46.74 180.89,47.16 180.97,47.24 181.12,47.24 181.2,47.16 181.2,46.74 181.27,46.66 181.42,46.66 181.5,46.74 181.5,46.86 181.58,46.93 181.73,46.93 181.81,46.86 181.81,46.74 181.88,46.66 182.03,46.66 182.11,46.74 182.11,46.8 182.19,46.88 182.34,46.88 182.41,46.8 182.41,46.74 182.49,46.66 182.64,46.66 182.72,46.74 182.72,47.03 184.22,48.53 v3(184.66,48.53) ; v3(142.72,49.33) 142.8,49.41 143.08,49.41 143.31,49.65 143.66,49.65 143.71,49.6 144.5,49.6 144.95,49.14 145.56,49.14 147.45,47.25 149.26,47.25 149.63,46.88 v4(150.2,46.88) 150.57,46.88 150.64,46.8 150.64,46.59 150.72,46.51 150.87,46.51 150.95,46.59 150.95,46.8 151.02,46.88 151.17,46.88 151.25,46.8 151.25,46.61 151.33,46.54 151.48,46.54 151.56,46.61 151.56,46.8 151.63,46.88 151.78,46.88 151.86,46.8 151.86,46.61 151.94,46.54 152.09,46.54 152.17,46.61 152.17,46.8 152.24,46.88 152.39,46.88 152.47,46.8 152.47,46.61 152.55,46.54 152.7,46.54 152.77,46.61 152.77,46.8 152.85,46.88 153,46.88 153.08,46.8 153.08,46.61 153.16,46.54 153.31,46.54 153.38,46.61 153.38,46.8 153.46,46.88 153.98,46.88 154.32,47.22 154.6,47.22 154.98,47.6 154.98,48.19 v3(155.33,48.53)
  IN4 w0.076: v4(150.2,46.88) 153.31,46.88 154.26,45.93 154.44,45.93 154.64,45.73 160.33,45.73 160.58,45.98 160.58,46.36 160.81,46.59 162.68,46.59 163.54,45.73 165.34,45.73 166.29,44.79 168.23,44.79 169.15,45.7 174.83,45.7 175.62,46.48 178.63,46.48 179.03,46.88 v4(179.53,46.88)
  BOTTOM w0.076: UD3.K1 142.34,49.7 v3(142.72,49.33) 142.32,48.93 UD3.J1 ; UD1.K1 171.65,49.7 v3(172.05,49.3) UD1.J1 ; v3(184.66,48.53) 184.66,48.54 184.3,48.9 UD2.J1 UD2.K1 183.7,49.7 183.13,50.27 183.13,54.95 183.93,55.75 RD81.1 ; UD4.K1 UD4.J1 154.97,48.9 155.33,48.54 v3(155.33,48.53)
M_ODT2: length 74.6
  IN3 w0.076: v3(126.02,48.53) 125.58,48.53 124.07,47.03 124.07,46.74 124,46.66 123.85,46.66 123.77,46.74 123.77,46.8 123.69,46.88 123.54,46.88 123.47,46.8 123.47,46.74 123.39,46.66 123.24,46.66 123.16,46.74 123.16,46.86 123.08,46.93 122.93,46.93 122.86,46.86 122.86,46.74 122.78,46.66 122.63,46.66 122.55,46.74 122.55,47.16 122.47,47.24 122.32,47.24 122.25,47.16 122.25,46.74 122.17,46.66 122.02,46.66 121.94,46.74 121.94,47.19 121.87,47.26 121.71,47.26 121.64,47.19 121.64,46.74 121.56,46.66 121.41,46.66 121.33,46.74 121.33,46.8 121.26,46.88 v4(120.89,46.88) 120.32,46.88 119.57,47.63 119,47.63 118.43,48.2 117.17,48.2 116,49.37 115.57,49.37 115.29,49.65 113.76,49.65 v3(113.41,49.3) ; v3(84.07,49.33) 84.16,49.41 84.43,49.41 84.67,49.65 85.01,49.65 85.07,49.6 85.85,49.6 86.31,49.14 86.92,49.14 88.81,47.25 90.61,47.25 90.98,46.88 v4(91.55,46.88) 91.92,46.88 92,46.8 92,46.59 92.07,46.51 92.23,46.51 92.3,46.59 92.3,46.8 92.38,46.88 92.53,46.88 92.61,46.8 92.61,46.61 92.68,46.54 92.83,46.54 92.91,46.61 92.91,46.8 92.99,46.88 93.14,46.88 93.22,46.8 93.22,46.61 93.29,46.54 93.44,46.54 93.52,46.61 93.52,46.8 93.6,46.88 93.75,46.88 93.83,46.8 93.83,46.61 93.9,46.54 94.05,46.54 94.13,46.61 94.13,46.8 94.21,46.88 94.36,46.88 94.44,46.8 94.44,46.61 94.51,46.54 94.66,46.54 94.74,46.61 94.74,46.8 94.82,46.88 95.34,46.88 95.68,47.22 95.96,47.22 96.34,47.6 96.34,48.19 v3(96.68,48.53)
  IN4 w0.076: v4(120.89,46.88) 120.38,46.88 119.98,46.48 116.21,46.48 115.42,45.7 110.67,45.7 110.57,45.6 109.7,45.6 109.56,45.73 96.01,45.73 94.87,46.88 v4(91.55,46.88)
  BOTTOM w0.076: UD7.J1 83.67,48.93 v3(84.07,49.33) 83.7,49.7 UD7.K1 ; RD82.1 110.04,49.7 UD6.K1 113.01,49.7 v3(113.41,49.3) UD6.J1 ; v3(96.68,48.53) 96.68,48.54 96.32,48.9 UD8.J1 UD8.K1 ; v3(126.02,48.53) 126.02,48.54 125.66,48.9 UD5.J1 UD5.K1
MASK_LEDS#: length 25.9
  IN4 w0.076: v1(299.23,87.32) 299.23,88.84 294.73,93.35 290.97,93.35 289.28,95.03 285.25,95.03 284.31,94.1 282.84,94.1 282.56,94.38 281.39,94.38 v3(281.09,94.07)
  BOTTOM w0.076: v2(299.4,88.65) 299.4,88.37 299.23,88.2 v1(299.23,87.32) ; JSNR1.4 281.28,93.88 v3(281.09,94.07)
ME_FWP#: length 297.2
  TOP w0.076: v5(114.91,25.74) 115,25.82 115,26.84 117.64,29.48 123.32,29.48 125.36,27.44 125.36,23.75 127.71,21.4 127.71,18.01 128.22,17.51 128.79,17.51 130.59,19.31 136.08,19.31 138.64,21.87 152.82,21.87 159.02,15.68 164.37,15.68 166.32,17.62 167.19,17.62 v5(167.28,17.71)
  IN1 w0.076: v5(167.28,17.71) 167.28,17.66 v4(166.81,17.19) ; v4(293.53,16.67) 293.74,16.46 293.74,14.83 289.49,10.58 v4(289.32,10.58) ; v5(114.91,25.74) 115.17,25.74 115.38,25.94 115.52,25.94 115.82,26.25 116.02,26.25 116.03,26.24 v4(116.1,26.24)
  IN3 w0.076: v4(289.32,10.58) 289.32,9.14 285.23,5.05 262.04,5.05 261,6.09 249.11,6.09 246.35,8.84 230.69,8.84 227.3,5.45 209.66,5.45 208.66,6.46 201.83,6.46 200.82,5.45 197.29,5.45 197.08,5.65 196.06,5.65 195.25,4.85 185.21,4.85 185.05,5.01 173.21,5.01 166.55,11.67 166.55,16.92 v4(166.81,17.19)
  IN4 w0.076: v1(116.88,26.95) 116.88,26.63 116.49,26.25 116.13,26.25 116.12,26.24 v4(116.1,26.24) ; v4(293.53,16.67) 293.53,16.81 294.02,17.29 294.56,17.29 295.04,17.77 295.04,22.62 295.35,22.93 295.35,42.51 294.66,43.2 294.66,44.28 294.08,44.86 293.43,44.86 291.59,46.7 291.18,46.7 290.92,46.96 290.92,47.47 288.83,49.55 288.83,49.81 288.83,52.99 287.02,54.8 285.44,54.8 284.48,55.77 284.48,72.3 284.59,72.41 284.59,72.79 284.09,73.29 284.09,77.54 286.13,79.58 286.13,80.02 v1(286.76,80.65)
  BOTTOM w0.076: U38.J13 287.47,80.48 286.94,80.48 286.78,80.65 v1(286.76,80.65) 286.26,80.65 285.74,80.13 R243.2 R244.1 ; v1(116.88,26.95) 116.88,27.34 117.93,28.39 v2(117.93,29.06)
ME_SUS_PWR_ACK: length 291.4
  TOP w0.076: v5(101.48,15.44) 101.48,15.22 102.02,14.68 107.52,14.68 112.17,10.03 120.87,10.03 123.81,7.09 133.24,7.09 136.76,3.58 166.12,3.58 169.6,7.05 170.44,7.05 176.17,12.78 176.69,12.78 177.46,13.54 v3(177.46,13.91)
  IN1 w0.076: v5(101.48,15.44) 101.17,15.75 101.14,15.75 v4(101.1,15.79) ; v4(283.16,13.91) 283.3,13.91 v4(284.5,12.7)
  IN3 w0.076: v4(283.16,13.91) 282.66,13.91 280.88,12.13 274.03,12.13 272.47,13.69 268.68,13.69 267.73,12.74 250.71,12.74 248.02,15.44 247.01,15.44 245.64,16.81 238.09,16.81 237.27,15.99 234.62,15.99 233.92,16.69 231.93,16.69 231.3,16.07 227.64,16.07 225.97,14.39 225.97,13.65 223.89,11.57 214.54,11.57 213.81,12.3 203.48,12.3 203.39,12.21 201.45,12.21 201.09,12.57 200.47,12.57 199.87,13.17 199.87,13.22 199.66,13.43 199.38,13.43 199.07,13.12 v4(199.07,13.02)
  IN4 w0.076: v4(284.5,12.7) 284.66,12.86 285.02,12.86 285.35,12.53 288.67,12.53 289.62,13.48 290.28,13.48 290.57,13.19 297.65,13.19 300.22,15.76 300.22,20.52 300.03,20.71 300.03,33.79 300.54,34.3 300.54,61.91 296.07,66.38 296.07,70.71 297.33,71.97 297.33,74.68 297.13,74.88 297.13,77.27 295.95,78.45 295.95,79.94 294.69,81.2 293.5,81.2 293.5,81.2 293.33,81.2 293.26,81.13 v1(293.11,81.13) ; v4(199.07,13.02) 199.02,13.02 197.95,11.96 187.38,11.96 187.02,12.31 181.43,12.31 181.08,12.67 181.06,12.67 180.82,12.67 179.46,12.67 179.33,12.8 179.15,12.8 178.55,13.4 177.97,13.4 v3(177.46,13.91) ; v1(101.64,15.79) v4(101.1,15.79)
MEC_XTAL1: length 4.9
  BOTTOM w0.076: U38.A1 293.89,84.9 293.89,85.21 C157.1 296.25,86.76 296.82,87.32 Y3.1
MEC_XTAL2: length 4.9
  BOTTOM w0.076: Y3.2 296.82,84.82 296,85.64 C158.1 294.63,85.64 294.04,85.06 294.04,84.56 U38.B1
MEM_CONFIG0: length 40.5
  IN2 w0.076: v4(131.13,16.81) 130.9,16.81 130.53,16.44 128.65,16.44 128.53,16.32 128.53,15.11 127.37,13.95 127.08,13.95 126.03,14.99 126.03,15.36 125.41,15.98 125.13,15.98 124.89,16.22 122.41,16.22 119.18,19.46 117.3,19.46 115.79,17.95 107.82,17.95 107.08,17.21 105.65,17.21 105.18,17.68 105.17,17.68 104.99,17.86 104.34,17.86 103.36,18.84 102.06,18.84 101.23,19.67 v4(101.23,19.78)
  IN4 w0.076: v4(101.23,19.78) 101.23,19.73 101.48,19.47 v1(101.76,19.47) ; v4(131.13,16.81) 131.06,16.87 v1(130.63,16.87)
  BOTTOM w0.076: v1(101.76,19.47) 102.02,19.22 v2(102.41,19.22) 102.56,19.22 102.86,19.51 RH122.1 RH123.2
MEM_CONFIG1: length 23.5
  IN4 w0.076: v1(129.38,14.71) 129.25,14.71 128.78,14.23 127.95,14.23 127.86,14.14 127.77,14.14 127.43,13.8 126.76,13.8 126.05,14.51 123.54,14.51 123.37,14.68 121.24,14.68 119.7,13.15 116.7,13.15 116.6,13.05 115.32,13.05 114.78,12.5 113.51,12.5 112.78,11.78 v1(111.24,11.78)
  BOTTOM w0.076: v1(111.24,11.78) RH125.2 110.77,13.26 109.65,13.26 v2(109.24,13.67)
MEM_CONFIG2: length 19.7
  IN2 w0.076: v4(114.86,16.39) 116.49,16.39 117.5,15.38 121.02,15.38 122.03,14.37 124.47,14.37 125.22,13.62 v4(125.22,13.16)
  IN4 w0.076: v1(114.46,16.35) 114.82,16.35 v4(114.86,16.39) ; v4(125.22,13.16) 125.23,13.16 125.72,13.16 125.89,13.34 127.62,13.34 127.93,13.65 128.23,13.65 128.28,13.6 128.48,13.6 128.53,13.65 128.73,13.65 128.78,13.6 129.14,13.6 129.38,13.84 v1(129.38,13.84)
  BOTTOM w0.076: v1(114.46,16.35) RH121.2 RH120.1 114.39,18.48 v2(114.79,18.89)
MPHY_PWREN: length 63.5
  TOP w0.076: v5(91.78,17.14) 91.78,16.98 93.05,15.71 93.05,14.51 v5(93.94,13.62)
  IN1 w0.076: v5(91.78,17.14) 91.78,17.29 91.81,17.32 v4(91.81,17.98) ; v4(93.67,13.89) v5(93.94,13.62)
  IN4 w0.076: v4(91.81,17.98) 91.83,18 91.83,18.93 94,21.1 94,23.03 94.63,23.65 94.63,26.78 96.75,28.9 v4(96.75,31.08) v1(96.25,31.08) ; v1(93.2,14.06) 93.5,14.06 v4(93.67,13.89) 96.8,13.89 97.13,14.22 97.69,14.22 98.55,13.35 102.65,13.35 103.54,12.46 107.4,12.46 107.74,12.81 107.85,12.81 108.41,13.37 113.67,13.37 113.97,13.67 114.24,13.67 114.31,13.75 115.53,13.75 115.87,14.09 119.56,14.09 121.56,16.08 125.75,16.08 126.07,15.77 126.65,15.77 126.68,15.79 127.39,15.79 127.47,15.87 128.09,15.87 v1(128.38,15.57)
  BOTTOM w0.076: v2(98.18,33.37) 98.17,33.36 97.9,33.36 96.9,32.35 96.9,31.73 v1(96.25,31.08) ; v1(93.2,14.06) R188.1
MPHY_PWREN#: length 9.3
  BOTTOM w0.076: R169.2 93.99,25.98 v2(93.99,27.32) 93.47,27.85 Q14.2 92.24,27.2 Q12.2 ; R169.2 94.02,25.82 93.53,25.34 92.52,25.34 92.24,25.06 Q12.5 ; R169.2 94.92,25.95 Q13.1
MPHY_PWREN_R: length 4.4
  BOTTOM w0.076: v2(94.41,32.1) R173.1 R172.2 R168.2 95.34,29.61 95.14,29.42 Q13.2
MSCLK: length 25.7
  IN1 w0.076: v3(296.92,95.9) 296.92,96.35 295.98,97.29 293.75,97.29 289.65,93.18 289.65,90.3 287.83,88.49 287.83,87.85 v4(287.84,87.84)
  IN4 w0.076: v1(288.61,83.63) 287.54,83.63 287.39,83.78 287.36,83.78 286.14,85 286.14,86.28 286.75,86.89 287.02,86.89 287.84,87.71 v4(287.84,87.84)
  BOTTOM w0.076: v3(296.92,95.9) 297.47,95.36 JDEG1.6 297.47,93.26 R236.2
MSDATA: length 27.7
  IN1 w0.076: v3(298.36,95.95) 298.3,95.95 296.75,94.4 293.38,94.4 292.66,93.68 292.66,91.8 291.77,90.91 291.77,90.33 291.23,89.79 291.23,88.87 288.9,86.54 288.9,86.01 289.09,85.82 289.09,84.61 289.56,84.14 289.56,82.72 v4(289.57,82.71)
  IN4 w0.076: v3(298.36,95.95) 297.93,95.52 297.93,94.28 298.36,93.85 v1(298.36,91.1) ; v4(289.57,82.71) 289.49,82.63 v1(289.11,82.63)
  BOTTOM w0.076: JDEG1.7 297.97,95.04 297.91,95.09 297.91,95.51 v3(298.36,95.95) ; v1(298.36,91.1) R239.2
Net_177:
  vias: v1(130.88,14.71)
NGFF1_CONFIG_0: length 340.2
  IN2 w0.076: v3(49.25,11.17) 49.25,11.74 49.48,11.97 68.13,11.97 69.21,10.89 77.23,10.89 77.96,11.63 85.32,11.63 85.8,11.14 92.23,11.14 94.49,8.88 101.62,8.88 102.17,8.34 106.97,8.34 107.31,7.99 108.28,7.99 110.23,6.04 110.29,5.99 112.94,5.99 113.29,5.63 113.29,3.49 114.89,1.89 135.69,1.89 135.86,2.06 150.88,2.06 151.09,1.85 202.19,1.85 202.83,2.49 206.2,2.49 206.45,2.75 244.46,2.75 245.38,3.67 258.28,3.67 259.42,2.53 290.56,2.53 296.82,8.79 296.82,9.3 299.89,12.37 299.89,49.76 289.25,60.39 289.25,72.54 v4(288.35,73.44)
  IN3 w0.076: v4(287.27,81.71) 287.25,81.71 287.25,81.56 287.53,81.29 287.9,81.29 288.14,81.04 288.14,80.58 288.14,80.57 288.14,75.15 288.64,74.64 288.64,73.73 v4(288.35,73.44)
  IN4 w0.076: v1(288.31,73.82) 288.31,73.48 v4(288.35,73.44) ; v1(287.61,81.63) 287.35,81.63 v4(287.27,81.71)
  BOTTOM w0.076: JNGFF2.13 v3(49.25,11.17)
NGFF1_CONFIG_1: length 326.4
  IN2 w0.076: v4(288.33,74.23) 288.33,74.19 289.56,72.95 289.56,60.52 300.19,49.88 300.19,12.2 297.17,9.18 297.17,8.62 290.78,2.23 259.17,2.23 258.03,3.37 245.51,3.37 244.58,2.44 206.58,2.44 206.3,2.17 202.95,2.17 202.32,1.54 150.96,1.54 150.79,1.72 135.95,1.72 135.78,1.54 114.8,1.54 112.99,3.36 112.99,5.48 112.81,5.65 110.18,5.65 108.15,7.69 107.19,7.69 106.84,8.03 102.04,8.03 101.5,8.58 94.36,8.58 92.32,10.62 88.6,10.62 88.07,10.1 86.2,10.1 85.28,11.02 78,11.02 77.34,10.36 63.61,10.36 v3(61.45,8.2)
  IN4 w0.076: v4(288.33,74.23) 287.92,73.82 v1(287.81,73.82)
  BOTTOM w0.076: v1(287.81,73.82) 287.81,74.15 287.4,74.57 287.4,78.41 U38.N13 ; v2(60.88,8.3) 61.02,8.16 61.42,8.16 v3(61.45,8.2) 61.45,8.72 61.25,8.93 JNGFF2.61
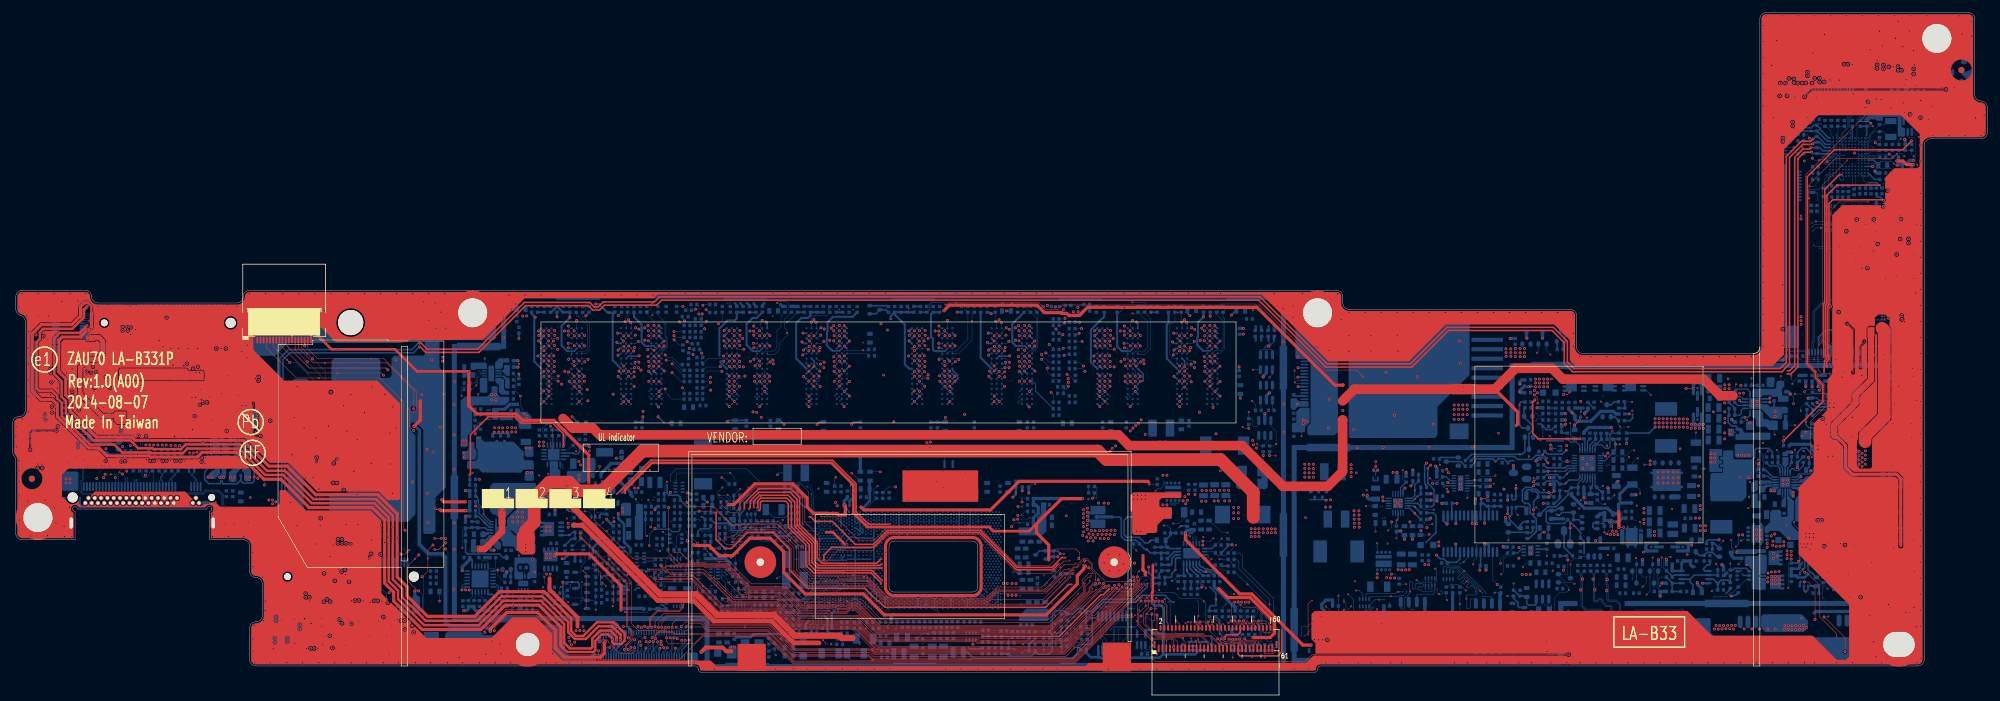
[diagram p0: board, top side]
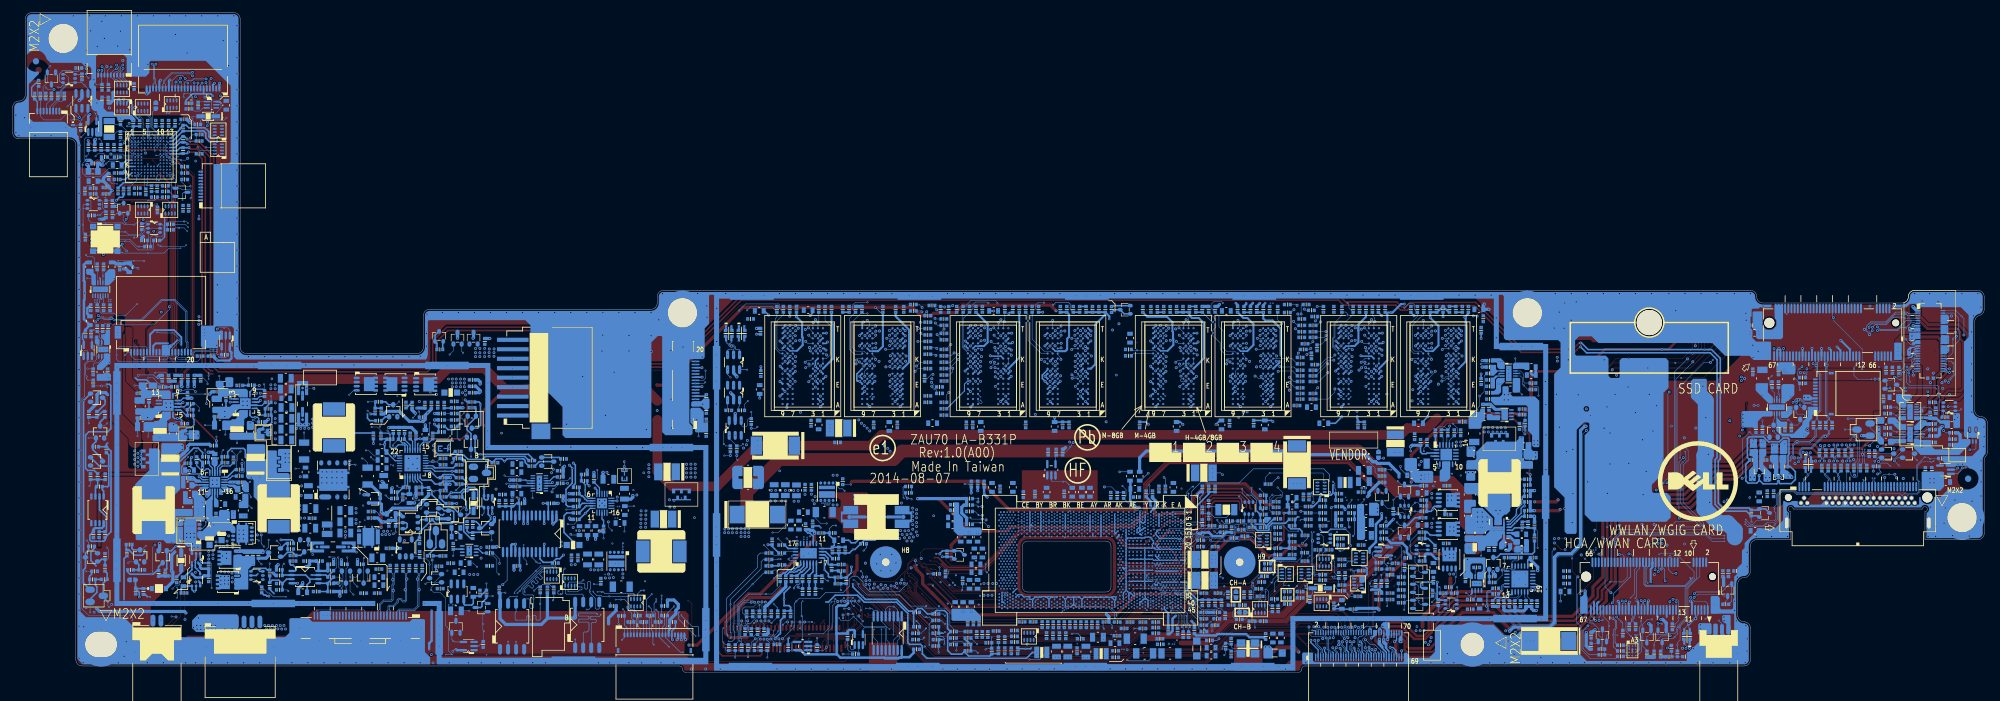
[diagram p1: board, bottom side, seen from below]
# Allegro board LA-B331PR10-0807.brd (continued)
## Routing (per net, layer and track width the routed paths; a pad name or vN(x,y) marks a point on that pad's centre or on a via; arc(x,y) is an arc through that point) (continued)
NGFF1_CONFIG_2: length 335.1
  IN2 w0.076: v3(62.01,8.2) 62.01,8.22 63.97,10.18 77.43,10.18 78.12,10.86 85.22,10.86 86.14,9.94 88.14,9.94 88.65,10.46 92.27,10.46 94.3,8.43 101.43,8.43 101.98,7.88 106.78,7.88 107.12,7.54 108.09,7.54 110.16,5.46 112.76,5.46 112.84,5.39 112.84,3.27 114.72,1.39 135.84,1.39 136,1.54 150.74,1.54 150.9,1.39 202.4,1.39 203.01,2 206.35,2 206.64,2.29 244.65,2.29 245.52,3.16 257.9,3.16 258.99,2.08 290.84,2.08 297.37,8.6 297.37,9.06 300.35,12.04 300.35,49.95 289.71,60.58 289.71,73.29 288.46,74.54 288.08,74.54 287.87,74.34 v4(287.86,74.34)
  IN3 w0.076: v4(289.03,82.23) 289.03,82.23 289.03,82.4 288.71,82.72 287.46,82.72 286.62,81.88 286.62,80.56 287.27,79.91 287.27,78.64 286.75,78.12 286.75,77.41 287.17,76.99 287.17,74.73 287.56,74.34 v4(287.86,74.34)
  IN4 w0.076: v1(287.31,73.82) 287.31,73.96 287.7,74.34 287.87,74.34 287.87,74.34 v4(287.86,74.34) ; v4(289.03,82.23) 289.03,82.05 v1(288.86,81.88)
  BOTTOM w0.076: JNGFF2.67 62.75,8.93 v3(62.01,8.2) v2(62.91,8.2) ; U38.G10 v1(288.86,81.88)
NGFF1_CONFIG_3: length 352.8
  IN2 w0.076: v3(46.96,11.88) 47.28,12.2 68.12,12.2 69.23,11.09 77.21,11.09 77.9,11.78 85.38,11.78 85.87,11.3 92.29,11.3 94.55,9.03 101.69,9.03 102.23,8.49 107.03,8.49 107.38,8.15 108.34,8.15 110.25,6.24 110.3,6.19 119.42,6.19 120.67,4.93 120.67,3.11 121.02,2.76 134.07,2.76 134.93,3.62 135.62,3.62 136.05,4.06 136.38,4.06 137.57,2.88 137.87,2.88 137.87,2.88 138.17,2.88 138.73,2.32 146.31,2.32 146.38,2.25 150.9,2.25 151.15,2 201.91,2 202.56,2.65 206.13,2.65 206.39,2.9 244.39,2.9 245.33,3.84 258.34,3.84 259.5,2.68 290.5,2.68 296.66,8.85 296.66,9.36 299.74,12.43 299.74,49.69 289.1,60.33 289.1,72.19 287.39,73.9 287.39,74.85 v4(287.49,74.95)
  IN3 w0.076: v4(289.62,79.99) 289.58,80.03 289.43,80.03 288.57,80.89 288.57,82.25 288.25,82.56 287.53,82.56 286.78,81.81 286.78,80.62 287.49,79.91 v4(287.49,74.95)
  IN4 w0.076: v1(287.1,74.59) 287.13,74.59 v4(287.49,74.95) ; v1(289.61,79.63) 289.61,79.99 v4(289.62,79.99)
  BOTTOM w0.076: RP20.5 286.81,74.32 287.09,74.59 v1(287.1,74.59) ; v2(44.63,8.41) 44.25,8.78 JNGFF2.1 44.25,10.87 44.63,11.24 46.33,11.24 v3(46.96,11.88)
NGFF1_SATA_SEL: length 313.3
  IN1 w0.076: v4(130.36,17.19) 129.59,17.19 129.4,17.38 128.11,17.38 127.47,16.74 127.27,16.74 127.08,16.55 126.17,16.55 125.98,16.74 121.77,16.74 120.91,15.89 117.68,15.89 116.3,17.28 109.24,17.28 108.47,16.5 101.49,16.5 101.06,16.93 96.63,16.93 96.3,17.26 v4(94.55,17.26)
  IN3 w0.076: v4(297.66,14.19) 297.02,14.19 289.41,6.58 289.41,6.19 289.22,6 288.6,6 286.28,3.68 261.62,3.68 260.58,4.71 244.42,4.71 243.77,5.36 237.72,5.36 237.13,4.78 232.86,4.78 231.52,3.43 206.17,3.43 205.91,3.18 202.33,3.18 201.86,2.71 165.61,2.71 163.17,5.15 163.17,7.1 161.14,9.12 153.88,9.12 153.31,8.55 145.38,8.55 142.61,5.79 139.49,5.79 138.67,6.61 137.08,6.61 136.67,7.01 130.02,7.01 126.9,10.13 126.9,14.38 127.12,14.6 127.32,14.6 128.43,15.71 128.43,16.36 128.69,16.62 128.69,16.76 129.11,17.19 v4(130.36,17.19)
  IN4 w0.076: v1(285.93,67.18) 285.78,67.33 285.78,71.51 285.75,71.55 285.75,73.2 286.04,73.5 286.04,75.39 286.41,75.76 286.41,76.26 287.51,77.35 287.51,78.11 287.58,78.19 287.58,78.78 288.02,79.22 288.29,79.22 288.45,79.37 288.74,79.37 288.86,79.49 288.86,79.85 288.61,80.1 v1(288.61,80.13) ; v4(130.36,17.19) 130.13,16.96 v1(130.13,16.87) ; v4(297.66,14.19) 298.15,14.19 299.92,15.96 299.92,20.4 299.73,20.59 299.73,33.92 300.24,34.43 300.24,61.79 295.51,66.51 v1(295.21,66.51) ; v1(94.17,17.26) v4(94.55,17.26)
  BOTTOM w0.076: v1(94.17,17.26) T24.1 ; v1(295.21,66.51) 295.18,66.51 295.08,66.4 v2(291.07,66.4) 288.54,66.4 287.77,67.18 v1(285.93,67.18)
NGFF2_CONFIG_0: length 409.1
  IN1 w0.076: v4(290.2,82.25) 289.81,81.86 289.23,81.86 288.62,81.25 286.81,81.25 286.28,81.78 284.54,81.78 284.43,81.67 283.53,81.67 282.48,82.71 282.48,83.8 v4(281.62,84.66)
  IN2 w0.076: v4(295.31,9.36) 294.32,9.36 288.86,3.9 260.86,3.9 259.48,5.28 244.59,5.28 243.67,4.36 236.36,4.36 235.17,5.55 214.24,5.55 213.57,6.22 205.74,6.22 204.61,7.35 202.41,7.35 200.5,5.44 198.9,5.44 197.64,4.18 169.35,4.18 168.78,4.75 167.38,4.75 166.87,4.24 155.08,4.24 153.12,6.21 144.48,6.21 143.99,5.72 139.44,5.72 138.35,6.8 134.44,6.8 132.99,5.35 123.25,5.35 119.38,9.22 111.72,9.22 110.31,10.63 103.98,10.63 103.23,11.38 101.77,11.38 100.84,12.31 98.52,12.31 97.91,12.93 96.93,12.93 95.96,13.9 94.33,13.9 94.02,14.2 93.23,14.2 92.6,13.57 86.57,13.57 86.17,13.98 81.3,13.98 78.61,16.67 68.6,16.67 50.81,34.46 36.18,34.46 24.34,46.3 v4(18.64,46.3)
  IN3 w0.076: v4(290.2,82.25) 290.55,81.91 292.02,81.91 292.97,80.95 292.97,79.27 295.2,77.04 295.2,70.64 294.65,70.1 294.65,67.33 292.97,65.65 292.97,60.27 300.91,52.33 300.91,14.01 296.26,9.36 v4(295.31,9.36)
  IN4 w0.076: v1(288.61,81.13) 288.69,81.13 289.24,81.67 289.54,81.67 289.65,81.56 289.84,81.56 290.2,81.92 v4(290.2,82.25) ; v4(18.64,46.3) 18.59,46.3 18.48,46.41 v1(18.31,46.41) ; v1(280.52,82.15) 281.27,82.15 281.62,82.5 v4(281.62,84.66)
  BOTTOM w0.076: JNGFF3.13 20.25,49.15 21.11,48.3 v2(21.11,48.11) 21.11,47.03 20.48,46.41 v1(18.31,46.41)
NGFF2_CONFIG_1: length 391.2
  IN1 w0.076: v4(290.78,82.24) 290.73,82.19 290.61,82.19 290.09,81.67 289.26,81.67 289.25,81.65 289.24,81.65 288.06,80.47 287.82,80.47 287.78,80.51 287.52,80.51 287.34,80.33 285.24,80.33 v4(284.96,80.61) 284.86,80.71 283.96,80.71 281.87,82.81 v4(281.21,82.81)
  IN2 w0.076: v3(32.25,51.29) 32.25,43.27 40.15,35.37 52.01,35.37 67.59,19.79 67.59,19.76 69.62,17.73 78.75,17.73 79.14,17.73 81.99,14.89 85.99,14.89 86.8,15.7 92.49,15.7 92.79,15.99 95.49,15.99 96.91,14.57 97.85,14.57 99.18,13.24 101.29,13.24 102.21,12.32 103.59,12.32 103.7,12.21 109.81,12.21 112.02,10 119.8,10 121.12,8.67 122.3,8.67 123.44,7.53 124.39,7.53 125.14,6.77 132.22,6.77 133.82,8.37 134.68,8.37 135.43,9.12 142.07,9.12 143.48,7.71 153.62,7.71 154.21,7.12 155.77,7.12 155.88,7.02 168.34,7.02 169.98,5.37 184.07,5.37 185.91,7.21 189.89,7.21 191.16,8.48 197.81,8.48 198.01,8.28 204.59,8.28 206.01,6.86 214.15,6.86 214.8,6.21 216.89,6.21 216.99,6.31 236.34,6.31 236.9,5.76 243.49,5.76 243.84,6.1 259.52,6.1 261.11,4.51 288.59,4.51 296.28,12.2 296.28,14.2 296.9,14.83 296.9,17.7 297.7,18.5 297.7,20.13 298.5,20.94 298.5,48.02 293.55,52.98 293.55,53.22 292.98,53.79 292.98,54.94 285.96,61.95 285.96,75.81 285.42,76.36 285.42,80.15 v4(284.96,80.61)
  IN4 w0.076: v4(281.21,82.81) 281.05,82.65 v1(280.52,82.65) ; v1(288.61,80.63) 288.86,80.88 289.39,80.88 289.85,81.33 289.85,81.34 290.7,82.19 290.73,82.19 v4(290.78,82.24)
  BOTTOM w0.076: v1(280.52,82.65) 282.74,82.65 283.23,83.14 v2(283.23,83.18) ; v3(32.25,51.29) 32.25,50.79 32.25,50.12 JNGFF3.61
NGFF2_CONFIG_2: length 386.9
  IN1 w0.076: v4(280.97,83.52) 280.97,83.29 280.69,83.01 280.69,82.2 283.16,79.74 v4(284.14,79.74) 285.52,79.74 286.19,79.06 287.72,79.06 289.15,80.5 289.84,80.5 289.9,80.56 v4(289.99,80.56)
  IN2 w0.076: v4(284.14,79.74) 284.14,79.72 284.9,78.96 284.9,74.64 285.33,74.21 285.33,62.37 292.82,54.88 292.82,53.7 293.39,53.13 293.39,52.91 298.35,47.96 298.35,21 297.55,20.2 297.55,18.56 296.75,17.76 296.75,14.89 296.12,14.27 296.12,12.31 288.48,4.67 261.17,4.67 259.54,6.3 243.83,6.3 243.43,5.91 236.97,5.91 236.42,6.46 216.93,6.46 216.88,6.42 214.81,6.42 214.21,7.01 206.07,7.01 204.65,8.43 198.07,8.43 197.87,8.63 191.1,8.63 190.98,8.51 186.42,8.51 185.07,7.17 185.07,6.66 183.99,5.58 169.99,5.58 168.4,7.17 155.94,7.17 155.83,7.28 154.51,7.28 153.77,8.02 143.4,8.02 142.14,9.28 135.37,9.28 134.62,8.53 133.76,8.53 132.16,6.93 125.21,6.93 124.45,7.68 123.5,7.68 122.37,8.82 121.19,8.82 119.86,10.15 112.09,10.15 109.88,12.36 103.76,12.36 103.65,12.47 102.27,12.47 101.35,13.39 99.25,13.39 97.91,14.72 96.97,14.72 95.55,16.15 92.72,16.15 92.43,15.85 86.74,15.85 85.93,15.04 82.05,15.04 79.21,17.89 78.69,17.89 69.68,17.89 67.75,19.82 67.75,19.85 52.07,35.53 40.22,35.53 33.75,41.99 v3(33.75,51.29)
  IN4 w0.076: v1(280.52,83.15) 280.6,83.15 v4(280.97,83.52) ; v1(290.11,80.13) 290.11,80.32 289.99,80.45 v4(289.99,80.56)
  BOTTOM w0.076: v1(280.52,83.15) 281.85,83.15 v2(281.89,83.19) ; v3(33.75,51.29) JNGFF3.67
NGFF2_CONFIG_3: length 414.2
  TOP w0.076: v3(48.11,34) v2(48.11,33.34)
  IN1 w0.076: v4(281.2,84) 281.35,83.85 281.35,83.43 280.86,82.93 280.86,82.26 282.57,80.55 284.16,80.55 284.57,80.14 286.9,80.14 287.21,79.84 287.75,79.84 289.26,81.35 v4(289.39,81.35)
  IN2 w0.076: v3(48.75,24.41) 52.94,24.41 58.35,19 58.37,19 58.57,18.8 58.57,18.79 59.1,18.25 62.52,18.25 69.29,11.49 77.11,11.49 77.66,12.03 77.72,12.03 77.77,12.08 85.51,12.08 85.99,11.6 92.52,11.6 94.78,9.34 101.81,9.34 102.36,8.79 107.16,8.79 107.5,8.45 108.47,8.45 108.67,8.25 108.85,8.25 109.9,7.19 119.16,7.19 122.79,3.57 127.59,3.57 127.91,3.24 130.2,3.24 130.62,3.66 132.95,3.66 133.1,3.8 133.75,3.8 134.03,4.08 135.34,4.08 135.86,4.6 136.64,4.6 137.86,3.38 138.31,3.38 138.78,2.91 146.59,2.91 146.77,2.73 151.07,2.73 151.34,2.46 201.72,2.46 202.36,3.1 205.94,3.1 206.19,3.36 244.21,3.36 245.16,4.31 259.11,4.31 259.8,3.62 259.8,3.33 v4(259.81,3.32) ; v4(14.02,46.56) 14.29,46.3 15.93,46.3 16.38,45.85 24.57,45.85 36.42,34 v3(48.11,34)
  IN3 w0.076: v4(289.39,81.35) 290,81.35 290.41,81.75 291.94,81.75 292.82,80.88 292.82,79.2 295.04,76.98 295.04,70.71 294.5,70.16 294.5,67.39 292.82,65.71 292.82,60.16 300.76,52.23 300.76,15.02 298.15,12.41 297.48,12.41 292.81,7.74 292.81,7.06 288.36,2.61 260.53,2.61 v4(259.81,3.32)
  IN4 w0.076: v4(14.02,46.56) 13.99,46.6 13.99,46.66 14.18,46.86 v1(14.18,46.91) ; v4(281.2,84) 280.87,84 v1(280.52,83.65) ; v4(289.39,81.35) 289.32,81.35 289.11,81.14 v1(289.11,81.13)
  BOTTOM w0.076: v3(48.75,24.41) 48.8,24.47 48.8,33.3 v3(48.11,34) ; JNGFF3.1 15.25,49.45 15.06,49.26 13.51,49.26 13.14,48.89 13.14,48.39 13.61,47.92 13.61,47.06 13.76,46.91 v1(14.18,46.91)
NGFF_COEX1: length 52.8
  IN4 w0.076: v1(41.6,21.66) 39.06,24.2 v1(38.24,24.2)
  BOTTOM w0.076: v1(41.6,21.66) 43.58,21.66 44.07,22.14 58.18,22.14 60,20.32 JNGFF2.56 ; JNGFF1.40 18,28.21 18.22,28.44 30.03,28.44 30.48,28.88 32.64,28.88 33.36,28.16 33.36,26.57 33.7,26.23 v2(33.7,26.08) 33.7,25.5 33.46,25.26 33.46,24.25 33.71,24.01 36.56,24.01 37.13,23.43 37.47,23.43 v1(38.24,24.2)
NGFF_COEX2: length 52.4
  IN4 w0.076: v1(41.62,21.21) 38.97,23.86 v1(38.31,23.86)
  BOTTOM w0.076: JNGFF2.54 59.5,20.6 58.2,21.9 44.4,21.9 43.71,21.21 v1(41.62,21.21) ; JNGFF1.38 18.5,28.02 18.77,28.29 30.1,28.29 30.54,28.73 32.57,28.73 33.21,28.1 33.21,24.21 33.7,23.72 34.86,23.72 v2(35.08,23.5) 35.33,23.24 37.7,23.24 v1(38.31,23.86)
NGFF_COEX3: length 50.6
  IN4 w0.076: v1(38.34,23.44) 38.91,23.44 v1(41.62,20.73)
  BOTTOM w0.076: JNGFF2.52 59,20.89 58.14,21.75 44.57,21.75 43.56,20.73 v1(41.62,20.73) ; JNGFF1.36 19.52,28.13 30.16,28.13 30.6,28.58 32.51,28.58 33.06,28.03 33.06,23.98 v2(33.63,23.41) 33.97,23.07 37.97,23.07 v1(38.34,23.44)
NGFF_WWAN_PWREN: length 121.6
  IN2 w0.076: v4(38.76,37.77) 38.8,37.81 39.8,37.81 41.68,39.69 83.11,39.69 84.72,38.08 85.62,38.08 93.83,29.88 93.83,29.6 95.79,27.64 96.01,27.64 97.8,25.85 97.8,20.74 99.87,18.67 100.62,18.67 101.69,17.61 101.69,17.13 101.87,16.95 102.9,16.95 103.48,16.37 103.99,16.37 104.37,15.98 107.64,15.98 108.49,15.13 115.49,15.13 116.7,13.92 119.91,13.92 121.65,12.19 123.12,12.19 v4(123.22,12.29)
  IN3 w0.076: v3(29.62,42.36) 29.46,42.2 29.46,38.89 30.86,37.5 38.49,37.5 v4(38.76,37.77)
  IN4 w0.076: v4(123.22,12.29) 123.22,12.29 123.26,12.25 124.15,12.25 124.65,11.75 126.28,11.75 126.64,12.12 126.87,12.12 v1(126.97,12.01)
  BOTTOM w0.076: UCPU1.G34 128.98,13.41 128.79,13.21 128.78,13.21 128.64,13.07 128.64,12.89 128.47,12.72 128.26,12.72 127.89,12.35 127.89,12.32 127.71,12.14 127.1,12.14 v1(126.97,12.01) ; v3(29.62,42.36) 29.62,42.1 29.48,41.95 D18.2
NTC: length 2.3
  BOTTOM w0.254: PU702.5 v2(185.81,16.21) 185.81,15.95 PR526.1
PANEL_BKEN_EC: length 123.8
  IN4 w0.076: v1(258.57,15.07) 258.79,14.85 261.33,14.85 264.03,12.15 268.8,12.15 268.96,12.31 269.33,12.31 273.29,8.35 281.51,8.35 285.53,12.37 289.44,12.37 289.95,12.88 297.85,12.88 300.53,15.56 300.53,20.65 300.34,20.84 300.34,33.67 300.85,34.18 300.85,62.04 296.38,66.51 296.38,70.58 297.64,71.84 297.64,74.8 297.43,75.01 297.43,77.44 296.3,78.57 296.3,80.99 294.95,82.34 294.1,82.34 293.83,82.07 293.17,82.07 v1(293.11,82.13)
  BOTTOM w0.076: D3.3 257.61,15.59 258.13,15.07 v1(258.57,15.07) 258.57,14.19 v2(257.95,13.57)
PBAT_PRES#: length 178.6
  TOP w0.102: v3(245.76,39.31) v2(245.02,39.31)
  TOP w0.254: v5(289.47,78.83) 289.09,78.83 286.78,76.52 286.78,58.55 286.6,58.37 286.6,50.03 v5(286.78,49.85)
  IN1 w0.254: v4(288.12,48.81) 287.91,48.81 287.84,48.87 287.59,48.87 287.11,49.36 287.11,49.47 286.78,49.8 v5(286.78,49.85) ; v5(289.47,78.83) v4(289.47,78.33)
  IN2 w0.254: v4(288.12,48.81) 288.29,48.63 289.89,48.63 290.49,48.04 291.71,48.04 292.21,47.54 292.21,45.93 293.16,44.98 293.16,42.27 295.08,40.34 295.08,19.73 293.6,18.24 292.2,18.24 288.86,14.9 288.86,11.98 287.23,10.36 274.32,10.36 272.57,12.11 272.57,12.39 272.09,12.86 269.49,12.86 266.65,10.03 235.7,10.03 231.13,14.6 231.13,21.77 232.14,22.79 232.14,24.5 235.79,28.15 237.78,28.15 240.21,30.57 240.21,37.34 242.17,39.31 v3(245.76,39.31)
  IN4 w0.254: v1(289.61,79.13) 289.59,79.11 289.59,78.93 289.51,78.84 289.51,78.83 289.47,78.8 v4(289.47,78.33)
  BOTTOM w0.254: v3(245.76,39.31) 245.4,38.96 PR5.2 PR3.2 245.27,37.89 PR722.1
PBAT_SMBCLK: length 111.3
  IN1 w0.076: v4(293.25,88.52) 293.16,88.52 292.57,87.93 291.39,87.93 289.95,86.49 289.95,83.37 v4(290.14,83.18)
  IN4 w0.076: v1(290.61,83.63) 290.61,83.57 290.22,83.18 v4(290.14,83.18) ; v1(244.18,40.99) 244.18,40.62 244.23,40.56 244.39,40.56 244.51,40.68 244.51,41.08 244.27,41.32 243.88,41.32 243.67,41.52 243.67,46.98 244.87,48.18 276.76,48.18 278.01,49.43 278.01,89.51 279.26,90.76 284.17,90.76 284.48,91.07 284.48,91.37 285.83,92.72 288.31,92.72 290.93,90.1 292.06,90.1 292.4,89.76 292.44,89.72 292.44,89.12 v1(292.63,88.93) 292.85,88.93 v4(293.25,88.52)
  BOTTOM w0.076: v1(244.18,40.99) PR1.2
PBAT_SMBDAT: length 110.9
  IN1 w0.076: v4(290.54,82.66) 290.14,82.66 289.8,83 289.8,86.56 291.32,88.08 291.95,88.08 v4(292.44,88.57)
  IN4 w0.076: v4(292.44,88.57) 292.44,88.6 292.13,88.91 v1(292.13,88.93) 292.29,89.08 292.29,89.65 292,89.95 290.87,89.95 288.25,92.56 285.89,92.56 284.63,91.3 284.63,90.99 284.25,90.61 279.32,90.61 278.17,89.45 278.17,49.37 276.82,48.02 244.93,48.02 243.83,46.92 243.83,41.62 243.98,41.47 244.34,41.47 244.66,41.14 244.66,40.62 244.46,40.41 244.23,40.41 244.18,40.36 v1(244.18,39.97) ; v1(290.61,83.13) 290.59,83.1 290.59,82.71 v4(290.54,82.66)
  BOTTOM w0.076: v1(244.18,39.97) PR2.2
PBTN_OUT#_R: length 20.9
  IN2 w0.076: v4(113.22,21.94) 113.6,22.32 116.18,22.32 116.24,22.38 120.74,22.38 123.67,19.45 124.82,19.45 125.15,19.12 125.88,19.12 126.17,19.41 126.71,19.41 126.87,19.24 128.86,19.24 129.1,19 129.49,19 129.49,19.01 129.97,19.01 130.26,19.3 v4(130.26,19.34)
  IN4 w0.076: v1(130.38,19.04) 130.38,19.23 130.26,19.35 v4(130.26,19.34) ; v1(112.76,21.94) v4(113.22,21.94)
  BOTTOM w0.076: R2.2 v1(112.76,21.94)
PCH_ALW_ON: length 403.5
  TOP w0.076: v3(246.24,2.8) 205.62,2.8 204.57,1.74 180.79,1.74 180.19,2.34 180.19,5.06 179.25,6 172.69,6 168.02,1.32 123.51,1.32 119.19,5.64 109.16,5.64 105.53,2.02 87.16,2.02 85.51,3.67 85.51,6.42 82.92,9.01 78.23,9.01 76.23,7.01 v3(76.23,6.57)
  IN3 w0.076: v4(292.05,82.23) 292.05,82.1 293.13,81.03 293.13,79.33 295.35,77.11 295.35,70.58 294.8,70.03 294.8,67.26 293.13,65.59 293.13,60.46 301.14,52.45 301.14,14.02 296.43,9.32 296.43,9.02 289.87,2.46 259.36,2.46 258.99,2.82 246.26,2.82 v3(246.24,2.8)
  IN4 w0.076: v1(80.67,41.56) 81.47,41.56 82.89,40.14 82.89,18.67 82.64,18.42 69.63,18.42 v3(68.51,19.54) 67.62,19.54 67.16,20.01 67.16,21.49 67.46,21.8 72.82,21.8 73.87,22.85 v3(73.87,30.57) ; v4(292.05,82.23) 291.61,82.67 v1(291.61,82.74)
  BOTTOM w0.076: v1(291.61,82.74) U38.D5 ; v3(76.23,6.57) 76.07,6.57 75.12,7.52 69.43,7.52 68.88,8.07 68.88,19.17 v3(68.51,19.54) ; R323.1 79.63,46.94 79.63,44.48 v6(80.35,43.76) 80.35,42.17 80.67,41.85 v1(80.67,41.56) ; R343.1 v3(73.87,30.57)
PCH_APWROK: length 284.8
  TOP w0.076: v3(286.64,8.77) 286.69,8.77 289.98,5.48 v3(289.98,3.27)
  IN2 w0.076: v4(121.42,3.31) 121.85,3.75 122.34,3.75 122.67,3.41 125.08,3.41 125.41,3.09 133.96,3.09 134.81,3.93 135.41,3.93 135.91,4.42 136.6,4.42 137.85,3.18 138.3,3.18 138.73,2.75 146.35,2.75 146.54,2.56 151.03,2.56 151.28,2.3 201.78,2.3 202.43,2.95 206,2.95 206.25,3.21 244.27,3.21 245.22,4.16 258.48,4.16 259.65,2.99 289.7,2.99 v3(289.98,3.27)
  IN3 w0.076: v4(115.56,20.49) 115.51,20.44 115.51,19.93 115.17,19.6 115.17,14.62 115.28,14.52 115.28,12.79 115.16,12.67 115.16,12.45 117.55,10.06 117.55,8.17 121.01,4.71 121.01,3.71 v4(121.42,3.31) ; v4(295.4,15.52) 295.31,15.44 295.31,14.54 293.61,12.84 292.31,12.84 290.63,11.16 288.57,11.16 286.64,9.23 v3(286.64,8.77)
  IN4 w0.076: v4(295.4,15.52) 295.45,15.58 295.6,15.58 296.68,16.65 296.68,22.03 296.93,22.28 296.93,43.16 296.24,43.85 296.24,44.97 295.73,45.47 295.73,46.35 295.5,46.58 295.5,48.2 295.78,48.48 295.78,48.92 295.52,49.18 295.52,49.18 295.35,49.34 292.28,49.34 290.57,51.05 290.57,51.68 290.57,54.71 289.76,55.53 289.76,57.42 288.64,58.53 288.64,70.65 289.19,71.2 289.19,72.76 289.38,72.95 289.38,74.36 289.51,74.49 289.51,75.89 290.42,76.8 290.42,78.38 290.51,78.46 290.51,78.52 v1(290.61,78.63) ; v4(115.56,20.49) 115.6,20.54 115.71,20.54 115.86,20.69 v1(115.86,20.72)
  BOTTOM w0.076: v2(287.34,8.84) 286.72,8.84 v3(286.64,8.77) ; RH65.1 116.32,21.56 115.99,21.22 115.99,20.85 v1(115.86,20.72) 115.48,20.72 115.44,20.67 RP24.7
PCH_DDI1_AUXN: length 47.7
  IN1 w0.066: v3(100.25,4.85) 100.45,5.05 100.45,5.06 100.45,5.86 101.16,6.58 105.39,6.58 105.62,6.81 108.06,6.81 110.94,9.7 120.94,9.7 121.38,9.25 125.65,9.25 126.5,8.4 130.91,8.4 133.2,10.69 133.2,14.97 132.82,15.34 132.82,15.67 132.97,15.82 133.3,15.82 v4(133.53,16.05)
  IN4 w0.066: v1(132.73,16.76) 132.71,16.78 132.52,16.78 132.47,16.73 132.47,16.6 132.71,16.36 132.71,16.18 132.99,15.91 133.39,15.91 v4(133.53,16.05)
  BOTTOM w0.097: v3(100.25,4.85) 100.45,4.65 100.45,4.3 100.7,4.05 100.7,3.72 100.4,3.42 100.4,3.1 100.3,3 JIO1.31
PCH_DDI1_AUXP: length 47.6
  IN1 w0.066: v3(100.84,4.85) 100.58,5.11 100.58,5.81 101.22,6.44 105.45,6.44 105.68,6.68 108.12,6.68 111,9.56 120.88,9.56 121.33,9.12 125.6,9.12 126.45,8.27 130.97,8.27 133.33,10.63 133.33,15.02 132.95,15.4 132.95,15.61 133.03,15.69 133.35,15.69 v4(133.53,15.51)
  IN4 w0.066: v4(133.53,15.51) 133.53,15.52 133.53,15.55 133.32,15.75 132.96,15.75 132.58,16.13 132.58,16.31 132.34,16.55 132.34,16.57 132.33,16.58 132.33,16.65 132.23,16.76 v1(132.12,16.76)
  BOTTOM w0.097: JIO1.29 100.7,2.98 100.6,3.08 100.6,3.34 100.9,3.64 100.9,4.13 100.65,4.38 100.65,4.67 v3(100.84,4.85)
PCH_DDI1_CLK: length 73.2
  IN1 w0.066: v4(135.67,2.48) 135.7,2.48 135.87,2.31 135.87,1.85 135.45,1.44 113.14,1.44 112.69,1.89 112.51,1.89 112.38,2.02 v4(112.38,2.06)
  IN4 w0.066: v1(94.21,3.56) 94.32,3.45 95.53,3.45 96.38,2.59 108.08,2.59 108.49,2.18 110.68,2.18 111.03,1.83 112.1,1.83 112.33,2.06 v4(112.38,2.06) ; v1(147.2,10.63) 147.2,10.56 147.17,10.54 147.17,10.42 149.52,8.06 149.63,8.06 150.68,7.01 150.89,6.8 150.89,6.43 150.89,6.43 150.89,6.11 151.2,5.8 151.2,5.33 v1(151.42,5.11) 151.25,4.93 151.25,4.66 152.06,3.85 152.06,2.47 152.06,2.36 151,1.3 136.24,1.3 136.03,1.51 136.03,2.13 v4(135.67,2.48)
  BOTTOM w0.097: v1(94.21,3.56) 94.14,3.56 93.9,3.32 JIO1.63
PCH_DDI1_DAT: length 72.6
  IN1 w0.066: v4(136.18,2.48) 136,2.3 136,1.8 135.51,1.3 113.09,1.3 112.64,1.76 112.57,1.76 112.38,1.57 v4(112.38,1.53)
  IN4 w0.066: v1(94.21,3.2) 94.31,3.31 95.47,3.31 96.33,2.45 108.02,2.45 108.43,2.05 110.63,2.05 110.98,1.7 112.1,1.7 112.27,1.53 v4(112.38,1.53) ; v4(136.18,2.48) 136.18,2.33 136.16,2.31 136.16,1.57 136.29,1.44 150.95,1.44 151.93,2.42 151.93,3.79 151.1,4.62 151.1,4.93 v1(150.92,5.11) 151.05,5.23 151.05,5.76 150.75,6.06 150.75,6.38 150.75,6.74 150.54,6.96 150.5,7 149.57,7.93 149.46,7.93 147.03,10.36 147.03,10.38 147.03,10.38 147.03,10.39 147.02,10.4 147.02,10.47 146.91,10.57 146.91,10.73 v1(146.76,10.88)
  BOTTOM w0.097: v1(94.21,3.2) 94.3,3.11 JIO1.61
PCH_DDI1_HPD: length 64.5
  TOP w0.076: v3(94.4,17.95) 94.4,17.88 97.98,14.3 97.98,7.66 99.05,6.6 103.25,6.6 103.8,7.14 v3(103.81,7.14)
  IN2 w0.076: v4(100.01,19.8) 100.05,19.77 100.73,19.77 102.14,18.36 102.8,18.36 104.05,17.1 104.3,17.1 104.67,16.73 107.4,16.73 107.64,16.97 108.48,16.97 108.97,17.47 115.99,17.47 117.36,18.84 119.11,18.84 122.82,15.13 124.74,15.13 126.61,13.27 126.74,13.14 128.06,13.14 128.48,13.56 131.56,13.56 131.77,13.77 131.77,14.23 132.11,14.56 132.4,14.56 132.53,14.69 v4(132.82,14.69)
  IN4 w0.076: v1(132.73,15) 132.73,14.83 132.81,14.75 132.81,14.69 v4(132.82,14.69) ; v4(100.01,19.8) 99.96,19.86 99.71,19.86 99.55,20.01 v1(99.55,20.16) 97.86,20.16 95.65,17.95 v3(94.4,17.95)
  BOTTOM w0.076: JIO1.14 103.9,7.05 v3(103.81,7.14)
PCH_DDI1_N0: length 44.3
  IN1 w0.066: v3(105.88,5.07) 106.11,5.3 106.11,5.43 106.29,5.61 108.51,5.61 111.43,8.53 120.22,8.53 121.3,7.45 125.23,7.45 125.48,7.21 131.38,7.21 134.1,9.92 134.1,14.81 134.85,15.56 134.85,16.3 134.37,16.78 133.68,16.78 v4(133.49,16.58)
  IN4 w0.066: v4(133.49,16.58) 133.56,16.65 133.56,16.73 133.9,17.07 134.05,17.07 134.29,17.31 v1(134.56,17.31)
  BOTTOM w0.097: v3(105.88,5.07) 106.06,4.89 106.06,4.45 105.24,3.63 105.24,3.12 105.1,2.97 JIO1.7
PCH_DDI1_N1: length 43.6
  IN1 w0.066: v4(134.53,16.17) 134.36,16.01 134.06,16.01 133.94,15.89 133.94,15.37 133.72,15.14 133.72,10.37 131.14,7.79 126.17,7.79 125.64,8.32 123.86,8.32 123.52,8.67 120.95,8.67 120.51,9.11 111.18,9.11 108.27,6.2 105.99,6.2 105.78,5.99 104.42,5.99 104.26,5.83 104.26,5.66 v3(104.05,5.45)
  IN4 w0.066: v1(134.56,16.76) 134.38,16.76 134.26,16.64 134.26,16.28 134.37,16.17 v4(134.53,16.17)
  BOTTOM w0.097: JIO1.13 103.9,3.01 104.03,3.14 104.03,3.44 104.29,3.7 104.29,5.21 v3(104.05,5.45)
PCH_DDI1_N2: length 47.4
  IN1 w0.066: v4(136.07,17.51) 136.07,17.38 136.01,17.33 135.95,17.33 135.78,17.16 135.72,17.16 135.59,17.03 135.59,16.81 135.88,16.53 135.88,15.32 135.41,14.86 135.41,13.28 134.96,12.83 134.96,9.11 131.81,5.96 127.74,5.96 127.46,5.67 121.39,5.67 119.7,7.37 111.91,7.37 108.98,4.44 107.82,4.44 107.39,4.01 105.45,4.01 105.04,4.41 103.45,4.41 103.26,4.22 103.26,4.02 103.14,3.9 v3(103.03,3.9)
  IN4 w0.066: v1(135.77,17.31) 135.77,17.45 135.83,17.51 v4(136.07,17.51)
  BOTTOM w0.097: v3(103.03,3.9) 103.19,3.75 103.19,3.57 102.8,3.18 102.8,3.05 102.7,2.95 JIO1.19
PCH_DDI1_N3: length 47.2
  IN1 w0.066: v3(102.07,4.83) 102.23,5 102.23,5.31 102.42,5.5 102.92,5.5 103.43,4.99 105.3,4.99 105.71,4.59 107.06,4.59 107.5,5.03 108.75,5.03 111.67,7.95 119.94,7.95 121.6,6.29 127.24,6.29 127.49,6.54 127.77,6.54 129.29,6.54 131.53,6.54 134.57,9.58 134.57,14.65 135.14,15.22 135.14,16.15 v4(135.44,16.45)
  IN4 w0.066: v4(135.44,16.45) 135.62,16.63 135.65,16.63 v1(135.77,16.76)
  BOTTOM w0.097: v3(102.07,4.83) 102.11,4.79 102.11,4.41 101.6,3.91 101.6,3.25 101.5,3.14 JIO1.25
PCH_DDI1_P0: length 44.3
  IN1 w0.066: v4(133.49,17.11) 133.69,16.91 134.43,16.91 134.98,16.36 134.98,15.51 134.23,14.76 134.23,9.87 131.44,7.07 125.43,7.07 125.18,7.32 121.24,7.32 120.17,8.4 111.48,8.4 108.56,5.48 106.35,5.48 106.24,5.37 106.24,5.27 v3(106.44,5.07)
  IN4 w0.066: v1(133.95,17.31) 134.08,17.44 134.08,17.56 133.98,17.66 133.85,17.66 133.65,17.45 133.65,17.28 v4(133.49,17.11)
  BOTTOM w0.097: v3(106.44,5.07) 106.28,4.92 106.28,4.39 105.44,3.54 105.44,3.15 105.5,3.09 JIO1.5
PCH_DDI1_P1: length 43.6
  IN1 w0.066: v4(134.48,15.69) 134.3,15.87 134.12,15.87 134.08,15.84 134.08,15.32 133.85,15.09 133.85,10.31 131.19,7.66 126.12,7.66 125.58,8.19 123.81,8.19 123.46,8.53 120.89,8.53 120.45,8.98 111.24,8.98 108.32,6.06 106.04,6.06 105.83,5.85 104.47,5.85 104.39,5.77 104.39,5.59 104.53,5.45 v3(104.64,5.45)
  IN4 w0.066: v4(134.48,15.69) 134.48,15.78 134.12,16.14 134.12,16.58 v1(133.95,16.76)
  BOTTOM w0.097: v3(104.64,5.45) 104.49,5.31 104.49,3.62 104.23,3.36 104.23,3.14 104.3,3.07 JIO1.11
PCH_DDI1_P2: length 47.5
  IN1 w0.066: v3(103.59,3.88) 103.59,3.88 103.39,4.08 103.39,4.16 103.5,4.27 104.99,4.27 105.39,3.87 107.45,3.87 107.88,4.3 109.03,4.3 111.96,7.23 119.64,7.23 121.34,5.53 127.51,5.53 127.8,5.82 131.86,5.82 135.1,9.06 135.1,12.78 135.55,13.23 135.55,14.8 136.01,15.27 136.01,16.58 135.72,16.87 135.72,16.97 135.78,17.02 v4(136.09,17.02)
  IN4 w0.066: v1(135.17,17.31) 135.45,17.02 v4(136.09,17.02)
  BOTTOM w0.097: v3(103.59,3.88) 103.57,3.88 103.39,3.69 103.39,3.48 103,3.1 103,3.04 103.1,2.94 JIO1.17
PCH_DDI1_P3: length 47.4
  IN1 w0.066: v3(102.63,4.91) 102.58,4.91 102.37,5.12 102.37,5.26 102.47,5.36 102.87,5.36 103.38,4.86 105.25,4.86 105.65,4.46 107.11,4.46 107.55,4.89 108.8,4.89 111.72,7.82 119.88,7.82 121.54,6.16 127.3,6.16 127.54,6.4 127.71,6.4 129.24,6.4 131.59,6.4 134.71,9.52 134.71,14.6 135.28,15.17 135.28,15.75 v4(135.49,15.97)
  IN4 w0.066: v4(135.49,15.97) 135.46,15.97 135.13,16.3 135.13,16.72 v1(135.17,16.76)
  BOTTOM w0.097: v3(102.63,4.91) 102.51,4.79 102.51,4.72 102.3,4.52 102.3,4.33 101.8,3.82 101.8,3.25 101.9,3.14 JIO1.23
PCH_DDI2_AUXN: length 125.7
  IN1 w0.066: v3(26.43,35.93) 26.25,35.76 26.25,35.57 26.33,35.48 27.3,35.48 28.05,36.23 37.86,36.23 45.43,28.67 47.37,28.67 51.71,24.33 59.31,24.33 69.11,14.52 72.17,14.52 74.04,12.65 89.62,12.65 91.17,14.2 91.17,18.18 91.6,18.61 97.05,18.61 97.53,18.13 100.07,18.13 100.35,17.86 100.81,17.86 100.92,17.96 105.36,17.96 106.06,17.26 108.18,17.26 108.95,18.03 116.55,18.03 117.51,18.99 118.95,18.99 119.6,18.34 125.68,18.34 125.86,18.16 126.69,18.16 126.81,18.28 131.82,18.28 132.53,17.57 132.53,17.53 v4(132.99,17.07)
  IN4 w0.066: v4(132.99,17.07) 132.75,17.31 v1(132.73,17.31)
  BOTTOM w0.097: v3(26.43,35.93) 26.2,35.7 26.2,35.6 CV9.1
PCH_DDI2_AUXN_C: length 8.2
  IN1 w0.066: v3(26.55,33.46) 26.29,33.46 25.91,33.08 25.91,30.35 24.64,29.08 24.64,27.69 24.72,27.61 JNGFF1.12
  BOTTOM w0.097: v3(26.55,33.46) 26.55,33.47 26.21,33.81 26.21,33.94 CV9.2
PCH_DDI2_AUXP: length 125.7
  IN1 w0.066: v4(132.4,17.08) 132.4,17.52 131.77,18.15 126.86,18.15 126.74,18.03 125.8,18.03 125.63,18.2 119.54,18.2 118.89,18.86 117.57,18.86 116.61,17.9 109.01,17.9 108.24,17.12 106,17.12 105.3,17.83 100.97,17.83 100.87,17.72 100.29,17.72 100.02,18 97.48,18 97,18.48 91.66,18.48 91.31,18.12 91.31,14.15 89.68,12.52 73.98,12.52 72.12,14.39 69.06,14.39 59.25,24.19 51.66,24.19 47.31,28.53 45.37,28.53 37.81,36.1 28.1,36.1 27.35,35.35 26.27,35.35 26.11,35.51 26.11,35.74 25.92,35.93 v3(25.74,35.93)
  IN4 w0.066: v4(132.4,17.08) 132.17,17.31 v1(132.12,17.31)
  BOTTOM w0.097: v3(25.74,35.93) 25.94,35.73 25.94,35.6 CV10.1
PCH_DDI2_AUXP_C: length 8.3
  IN1 w0.066: JNGFF1.14 24.51,26.82 24.51,29.14 25.78,30.41 v3(25.78,33.46)
  BOTTOM w0.097: CV10.2 26.01,33.86 26.01,33.69 v3(25.78,33.46)
PCH_DDI2_CLK: length 8.5
  IN4 w0.066: v1(147.2,11.13) 147.82,11.13 147.96,11 147.96,10.36 151.13,7.2 151.13,7.2 151.34,6.99 151.34,6.73 151.34,6.62 151.73,6.23 151.73,5.92 152.06,5.59 152.06,5.24 v1(151.92,5.11)
PCH_DDI2_DAT: length 8.4
  IN4 w0.066: v1(147.63,11.55) 147.63,11.5 147.85,11.29 147.86,11.29 148.09,11.05 148.09,10.42 151.26,7.25 151.26,7.25 151.47,7.04 151.47,6.67 151.86,6.28 151.86,6 152.21,5.66 152.21,5.32 v1(152.42,5.11)
PCH_DDI2_HPD: length 136.2
  IN1 w0.076: v3(18.64,35.89) 18.67,35.89 18.98,35.58 18.98,35.48 19.98,34.49 27.16,34.49 27.4,34.24 29.3,34.24 29.61,34.56 38.27,34.56 45.08,27.75 46.99,27.75 58.09,16.65 64.22,16.65 68.85,12.02 72.48,12.02 73.36,11.14 84.41,11.14 85.38,10.18 88.09,10.18 88.42,10.51 93.98,10.51 94.77,11.3 95.27,11.3 95.43,11.13 96.75,11.13 96.99,11.37 v4(97.17,11.37) 98.36,11.37 98.68,11.05 101.32,11.05 102.06,11.8 105.01,11.8 105.41,11.4 105.41,10.8 106.01,10.19 106.71,10.19 107.68,11.17 108.82,11.17 111.15,13.49 114.28,13.49 114.41,13.62 116.11,13.62 116.46,13.28 122.9,13.28 123.38,12.79 130.31,12.79 131.04,13.52 131.52,13.52 131.7,13.7 131.7,14.17 132.13,14.6 132.13,14.9 v4(132.15,14.93)
  IN4 w0.076: v4(132.15,14.93) 132.29,14.93 132.46,15.09 132.46,15.28 v1(132.73,15.56) ; v4(97.17,11.37) 97.01,11.52 v1(96.76,11.52)
  BOTTOM w0.076: v2(19.31,35.96) 19.25,35.89 v3(18.64,35.89) 18.64,35.92 17.56,37 17.56,37.76 18.55,38.75 QV1.3
PCH_DDI2_N0: length 129.9
  IN1 w0.066: v4(134.43,18.15) 134.43,18.15 134.43,18.05 134.1,17.72 133.35,17.72 132.26,18.81 129.33,18.81 129.06,19.07 126.89,19.07 126.48,19.47 124.76,19.47 119.96,19.47 119.39,20.05 117,20.05 116.03,19.09 110.65,19.09 110.04,19.7 109.23,19.7 108.74,19.2 105.2,19.2 104.93,19.47 103.98,19.47 103.78,19.28 97.95,19.28 97.5,19.73 91.17,19.73 90,18.56 90,18.08 85.63,13.71 76.36,13.71 73.58,16.49 69.46,16.49 60.6,25.36 52.37,25.36 48.02,29.7 45.87,29.7 38.07,37.5 22.7,37.5 22.31,37.11 v3(22.31,36.01)
  IN4 w0.066: v4(134.43,18.15) 134.43,18.15 134.56,18.28 v1(134.56,18.51)
  BOTTOM w0.097: CV1.1 22.11,35.63 22.11,35.81 v3(22.31,36.01)
PCH_DDI2_N0_C: length 8
  IN1 w0.066: JNGFF1.24 21.82,27.44 21.7,27.44 21.63,27.51 21.63,28.69 21.85,28.92 21.85,33.01 v3(22.3,33.46)
  BOTTOM w0.097: CV1.2 22.22,34.31 22.05,34.14 22.05,33.71 v3(22.3,33.46)
PCH_DDI2_N1: length 128.9
  IN1 w0.066: v3(24.29,36.01) 24.29,36.78 24.42,36.91 37.82,36.91 45.61,29.12 47.72,29.12 52.06,24.78 60.36,24.78 69.53,15.6 73.65,15.6 76.14,13.1 87.13,13.1 89.67,15.65 89.67,16.74 90.59,17.66 90.59,18.25 91.41,19.08 97.31,19.08 97.69,18.69 103.61,18.69 103.89,18.41 105.39,18.41 105.48,18.5 116.32,18.5 117.27,19.45 119.14,19.45 119.72,18.86 125.86,18.86 126.16,18.56 129.07,18.56 129.2,18.43 132.04,18.43 133.03,17.43 134.62,17.43 134.67,17.38 135.02,17.38 135.42,17.77 135.42,17.82 135.77,18.18 v4(135.77,18.18)
  IN4 w0.066: v1(135.77,18.51) v4(135.77,18.18)
  BOTTOM w0.097: CV3.1 24.14,35.63 24.14,35.86 v3(24.29,36.01)
PCH_DDI2_N1_C: length 8
  IN1 w0.066: JNGFF1.18 23.49,26.82 23.49,29.45 24.33,30.29 v3(24.33,33.46)
  BOTTOM w0.097: CV3.2 24.29,34.05 24.29,33.5 24.33,33.46 v3(24.33,33.46)
PCH_DDI2_N2: length 128.3
  IN1 w0.066: v4(134.81,18.82) 134.67,18.82 134.34,19.16 134.34,19.35 133.77,19.91 132.96,19.91 132.85,19.81 132.16,19.81 132.05,19.91 129.45,19.91 129.42,19.95 126.74,19.95 126.15,20.54 125.19,20.54 124.95,20.3 120.22,20.3 119.75,20.77 116.66,20.77 115.69,19.8 111.2,19.8 110.53,20.48 109.26,20.48 108.89,20.85 105.9,20.85 105.38,20.33 98.16,20.33 98.04,20.44 90.86,20.44 89.28,18.87 89.28,18.39 85.32,14.43 76.66,14.43 73.87,17.21 70.18,17.21 61.14,26.26 52.61,26.26 48.44,30.43 46.19,30.43 45.61,31.01 45.61,31.56 45.71,31.66 45.81,31.66 46.14,31.33 v4(46.14,31.28)
  IN4 w0.066: v4(134.81,18.82) 134.58,19.06 v1(134.56,19.06) ; v1(24.17,32.81) 23.74,32.81 23.68,32.86 23.68,33 23.38,33.3 23.38,33.7 23.54,33.86 28.43,33.86 29.77,32.52 30.69,32.52 30.8,32.63 43.49,32.63 44.67,31.46 45.96,31.46 v4(46.14,31.28)
PCH_DDI2_N2_C: length 2.8
  BOTTOM w0.097: CV5.2 23.75,31.48 23.75,31.07 23.6,30.92 23.6,30.45 23.75,30.3 JNGFF1.17
PCH_DDI2_N3: length 125.5
  IN1 w0.066: v4(136.03,18.84) 135.79,19.07 135.79,19.16 135.41,19.55 134.74,19.55 133.98,20.31 133.37,20.31 132.99,20.69 128.29,20.69 128.03,20.96 127.88,20.96 127.7,21.13 124.83,21.13 124.65,20.95 120.46,20.95 120.03,21.38 117.63,21.38 117.37,21.63 115.16,21.63 114.74,21.21 113.74,21.21 113.11,20.59 111.4,20.59 110.91,21.08 109.51,21.08 109.16,21.43 105.61,21.43 105.1,20.92 98.47,20.92 98.37,21.02 90.59,21.02 88.67,19.11 88.67,18.62 85.1,15.04 76.87,15.04 74.12,17.79 70.98,17.79 68.68,20.1 68.25,20.1 61.47,26.87 52.86,26.87 48.12,31.62 47.5,31.62 v4(47.28,31.84)
  IN4 w0.066: v1(26.2,32.81) 25.82,32.81 25.72,32.7 25.72,32.6 25.8,32.52 29,32.52 29.45,32.07 30.88,32.07 31,32.19 43.29,32.19 45.08,30.4 46.51,30.4 46.76,30.66 46.76,31.53 46.88,31.65 47.04,31.65 47.24,31.84 v4(47.28,31.84) ; v1(135.77,19.06) 135.81,19.06 v4(136.03,18.84)
PCH_DDI2_N3_C: length 3
  BOTTOM w0.097: CV7.2 26.2,31.89 25.79,31.49 25.79,31.26 25.1,30.56 25.1,30.45 25.25,30.3 JNGFF1.11
PCH_DDI2_P0: length 129.9
  IN1 w0.066: v3(21.7,36.01) 22.18,36.48 22.18,37.17 22.64,37.63 38.12,37.63 45.92,29.84 48.08,29.84 52.42,25.49 60.65,25.49 69.52,16.63 73.63,16.63 76.42,13.84 85.58,13.84 89.87,18.13 89.87,18.62 91.11,19.86 97.55,19.86 98,19.41 103.73,19.41 103.93,19.61 104.98,19.61 105.26,19.33 108.68,19.33 108.98,19.64 108.98,19.64 109.17,19.83 110.1,19.83 110.71,19.22 115.97,19.22 116.94,20.19 119.44,20.19 120.02,19.61 124.82,19.61 126.54,19.61 126.94,19.21 129.12,19.21 129.39,18.94 132.32,18.94 133.4,17.86 133.93,17.86 134.02,17.95 134.02,18.11 v4(133.95,18.18)
  IN4 w0.066: v4(133.95,18.18) 133.97,18.2 133.97,18.49 v1(133.95,18.51)
  BOTTOM w0.097: v3(21.7,36.01) 21.91,35.8 21.91,35.63 CV2.1
PCH_DDI2_P0_C: length 7.8
  IN1 w0.066: JNGFF1.26 21.49,26.82 21.49,28.75 21.71,28.97 v3(21.71,33.46)
  BOTTOM w0.097: CV2.2 21.85,33.95 21.85,33.6 v3(21.71,33.46)
PCH_DDI2_P1: length 129
  IN1 w0.066: v4(135.27,18.18) 135.27,17.82 134.99,17.54 134.97,17.54 134.96,17.54 134.7,17.54 134.68,17.56 133.09,17.56 132.09,18.56 129.26,18.56 129.12,18.69 126.22,18.69 125.91,19 119.78,19 119.19,19.58 117.21,19.58 116.27,18.64 105.42,18.64 105.33,18.55 103.95,18.55 103.67,18.83 97.75,18.83 97.36,19.22 91.36,19.22 90.45,18.31 90.45,17.71 89.54,16.8 89.54,15.71 87.07,13.24 76.2,13.24 73.71,15.73 69.59,15.73 60.41,24.91 52.12,24.91 47.78,29.25 45.67,29.25 37.87,37.05 24.37,37.05 24.16,36.84 24.16,36.48 v3(23.68,36.01)
  IN4 w0.066: v4(135.27,18.18) 135.27,18.41 v1(135.17,18.51)
  BOTTOM w0.097: v3(23.68,36.01) 23.91,35.78 23.91,35.6 CV4.1
PCH_DDI2_P1_C: length 8
  IN1 w0.066: JNGFF1.20 23.35,27.97 23.35,29.51 24.2,30.35 24.2,32.96 23.75,33.41 v3(23.75,33.46)
  BOTTOM w0.097: v3(23.75,33.46) 24.09,33.8 24.09,34.16 23.94,34.31 CV4.2
PCH_DDI2_P2: length 128.2
  IN1 w0.066: v4(46.14,31.81) 46.13,31.81 46.11,31.79 45.65,31.79 45.48,31.62 45.48,30.95 46.14,30.29 48.38,30.29 52.56,26.12 61.08,26.12 70.12,17.08 73.82,17.08 76.6,14.29 85.38,14.29 89.42,18.33 89.42,18.81 90.91,20.31 97.98,20.31 98.1,20.19 105.44,20.19 105.96,20.71 108.83,20.71 109.2,20.34 110.47,20.34 111.14,19.67 115.75,19.67 116.72,20.63 119.69,20.63 120.16,20.17 125.01,20.17 125.25,20.41 126.09,20.41 126.68,19.82 129.36,19.82 129.4,19.78 132,19.78 132.1,19.67 132.9,19.67 133.01,19.78 133.72,19.78 134.2,19.29 v4(134.2,18.83)
  IN4 w0.066: v4(46.14,31.81) 45.92,31.6 44.72,31.6 43.55,32.77 30.74,32.77 30.63,32.66 29.83,32.66 28.49,34 23.49,34 23.24,33.75 23.24,33.25 23.55,32.94 23.55,32.86 23.49,32.81 23.15,32.81 v1(23.15,32.81) ; v1(133.95,19.06) 133.97,19.06 v4(134.2,18.83)
PCH_DDI2_P2_C: length 2.8
  BOTTOM w0.097: CV6.2 23.55,31.5 23.55,31.15 23.4,31 23.4,30.45 23.25,30.3 JNGFF1.19
PCH_DDI2_P3: length 125.5
  IN1 w0.066: v4(47.28,31.31) 47.45,31.48 48.06,31.48 52.8,26.74 61.42,26.74 68.19,19.96 68.62,19.96 70.93,17.66 74.06,17.66 76.82,14.9 85.15,14.9 88.81,18.56 88.81,19.06 90.64,20.89 98.32,20.89 98.42,20.79 105.16,20.79 105.67,21.3 109.1,21.3 109.45,20.95 110.86,20.95 111.35,20.45 113.17,20.45 113.8,21.08 114.8,21.08 115.22,21.5 117.32,21.5 117.57,21.24 119.97,21.24 120.4,20.81 124.7,20.81 124.89,21 127.65,21 127.82,20.82 127.97,20.82 128.24,20.56 132.94,20.56 133.32,20.18 133.93,20.18 134.69,19.42 135.35,19.42 135.66,19.11 135.66,19.03 135.47,18.84 v4(135.42,18.84)
  IN4 w0.066: v4(47.28,31.31) 47.07,31.51 46.94,31.51 46.9,31.48 46.9,30.6 46.57,30.27 45.02,30.27 43.24,32.05 31.05,32.05 30.94,31.94 29.39,31.94 28.95,32.38 25.75,32.38 25.58,32.55 25.58,32.71 25.48,32.81 v1(25.18,32.81) ; v4(135.42,18.84) 135.2,19.06 v1(135.17,19.06)
PCH_DDI2_P3_C: length 3
  BOTTOM w0.097: CV8.2 25.19,31.89 25.59,31.49 25.59,31.34 24.9,30.64 24.9,30.45 24.75,30.3 JNGFF1.13
PCH_DPWROK: length 306.1
  TOP w0.076: v3(108.63,25.51) 108.63,25.53 111.46,25.53 113.7,23.28 115.28,23.28 115.36,23.36 121.06,23.36 124.41,20.01 124.41,16.36 126.31,14.46 v2(128.65,14.46) 135.14,14.46 138.5,11.1 154.3,11.1 155.74,12.54 163.55,12.54 166.51,15.5 167.13,15.5 167.78,16.15 167.91,16.15 v5(167.93,16.16)
  IN1 w0.076: v4(168.26,16.65) 168.26,16.65 167.93,16.32 v5(167.93,16.16)
  IN3 w0.076: v4(286.75,90.21) 286.54,90 286.54,82.5 286.17,82.14 286.17,79.19 285.6,78.62 285.6,77.58 286.29,76.89 286.29,60.5 293.7,53.09 293.7,52.32 294.8,51.22 294.8,48.51 295.33,47.99 296.15,47.99 297.24,46.9 297.84,46.9 298.74,46.01 298.74,21.47 297.01,19.74 297.01,18.24 296.52,17.75 296.52,17.33 294.93,15.74 294.93,14.59 293.49,13.14 292.18,13.14 290.56,11.52 288.4,11.52 285.72,8.84 285.72,7.37 284.41,6.05 268.22,6.05 267.45,6.83 261.64,6.83 261.41,7.05 249.87,7.05 246.72,10.2 230.11,10.2 226.81,6.9 217.26,6.9 216.86,6.49 214.12,6.49 213.99,6.63 209.85,6.63 209.06,7.42 201.47,7.42 201.34,7.42 200.86,7.42 199.85,6.41 197.72,6.41 197.48,6.65 193.28,6.65 193.09,6.85 191.7,6.85 191.38,6.53 182.27,6.53 181.92,6.18 174.81,6.18 168.48,12.51 168.48,15.42 168.72,15.66 168.72,16.14 168.39,16.47 168.39,16.52 v4(168.26,16.65)
  IN4 w0.076: v1(291.61,84.63) 291.61,85.6 291.72,85.7 291.72,86.71 290.79,87.63 290.79,87.85 288.73,89.91 287.06,89.91 v4(286.75,90.21)
  BOTTOM w0.076: v3(108.63,25.51) 108.2,25.51 RH72.2
PCH_ENVDD: length 222.9
  IN4 w0.076: v1(294.3,8.64) 294.3,6.87 292.66,5.24 284.9,5.24 284.43,4.77 258.96,4.77 258.66,5.07 250.54,5.07 248.46,2.99 247,2.99 246.44,2.43 244.32,2.43 v1(243.95,2.8) ; v1(242.94,2.81) 242.89,2.76 v1(237.51,2.76) 199.87,2.76 198.72,1.61 157.72,1.61 v1(155.48,3.85) 155.06,4.28 154.45,4.28 153.55,5.17 153.55,6.03 152.02,7.57 152.02,7.57 148.65,10.93 148.65,11.69 148.18,12.16 146.89,12.16 v1(146.76,12.03)
  BOTTOM w0.076: v1(294.3,8.64) 294.69,9.03 300.48,9.03 301.55,10.1 301.55,43.28 301.09,43.74 301.09,48.89 300.61,49.37 U60.2 300.61,50.86 300.68,50.93 301.15,50.93 301.26,50.83 U60.1 ; D1.2 245.45,14.25 246.28,13.43 v2(246.28,13.07) 245.84,12.64 244.85,12.64 244.02,11.8 244.02,7.41 243.5,6.89 243.5,3.37 v1(242.94,2.81) 242.95,2.8 v1(243.95,2.8) ; UCPU1.BN40 v1(146.76,12.03)
PCH_GPIO13: length 8.9
  IN4 w0.076: v1(128.63,22.07) 128.63,22.31 128.43,22.52 126.27,22.52 125.75,23.04 124.79,23.04 124.68,22.94 124.18,22.94 123.24,22 v1(121.88,22)
  BOTTOM w0.076: v2(122.32,22.33) 122,22 v1(121.88,22) 121.69,22.19 RH111.2
PCH_GPIO15: length 42.4
  IN1 w0.076: v4(130.21,17.72) 130.18,17.72 129.91,17.99 127.3,17.99 127.27,17.96 127.09,17.96 126.94,17.81 126.3,17.81 126.02,17.53 126.02,17.11 125.82,16.91 121.7,16.91 120.84,16.05 117.74,16.05 116.36,17.43 109.18,17.43 108.41,16.66 101.56,16.66 101.1,17.11 96.67,17.11 96.2,17.58 92.89,17.58 v4(92.49,17.98)
  IN4 w0.076: v4(92.49,17.98) 92.34,18.13 v1(92.19,18.13) ; v1(129.88,17.3) 129.97,17.3 130.21,17.54 v4(130.21,17.72)
  BOTTOM w0.076: v2(92.38,19.16) 92.19,18.97 v1(92.19,18.13)
PCH_GPIO18: length 9
  BOTTOM w0.076: RH26.2 121.98,9.97 124.35,9.97 125.09,10.71 125.09,11.21 126.76,12.88 126.76,13.76 126.83,13.84 UCPU1.B33
PCH_GPIO19: length 15.9
  IN4 w0.076: v1(129.38,17.3) 129.25,17.3 129.01,17.06 128.78,17.06 128.69,17.15 127.1,17.15 127.07,17.19 126.82,17.19 126.66,17.04 126.58,17.04 126.42,17.2 126.16,17.2 125.8,16.85 121.24,16.85 119.24,14.85 115.43,14.85 115.36,14.92 v1(115.34,14.92)
  BOTTOM w0.076: v1(115.34,14.92) 115.16,14.92 RH29.2
PCH_GPIO34: length 25.6
  IN4 w0.076: v1(128.88,15.57) 128.72,15.57 128.28,16.02 127.41,16.02 127.33,15.94 126.11,15.94 125.82,16.24 121.5,16.24 119.5,14.24 115.8,14.24 115.46,13.9 114.25,13.9 114.17,13.82 113.91,13.82 113.62,13.53 108.18,13.53 v1(107.95,13.3)
  BOTTOM w0.076: RH168.1 106.77,12.43 D21.2 107.95,13.3 v1(107.95,13.3) 107.96,13.31 T21.1
PCH_GPIO64: length 13.8
  IN4 w0.076: v1(119.21,11.17) 119.66,11.61 120.95,11.61 121.34,12 123.02,12 123.06,11.96 124.22,11.96 124.58,11.6 126.95,11.6 127.47,12.12 128.4,12.12 128.4,12.12 128.58,12.12 128.83,12.37 129.59,12.37 129.64,12.42 129.88,12.42 130.02,12.28 130.27,12.28 130.37,12.38 130.37,12.62 130.63,12.88 v1(130.63,13.41)
  BOTTOM w0.076: RH11.2 v1(119.21,11.17)
PCH_GPIO79: length 16.8
  IN4 w0.076: v1(128.55,7.48) 128.62,7.48 128.66,7.52 129.98,7.52 132.6,10.15 132.6,11.21 133.31,11.91 133.31,12.47 132.56,13.22 132.56,14.24 132.67,14.35 133.03,14.35 133.23,14.56 133.23,15.05 133.06,15.23 v1(133.02,15.23)
  BOTTOM w0.076: v1(128.55,7.48) 128.15,7.09 RC51.2 ; UCPU1.J34 129.79,13.41 130.03,13.65 130.23,13.65 130.3,13.58 130.46,13.58 130.53,13.65 130.53,13.65 130.64,13.76 130.64,13.94 130.78,14.08 130.98,14.08 131.04,14.02 131.22,14.02 131.28,14.08 131.28,14.08 131.34,14.14 131.34,14.14 131.37,14.17 131.37,14.36 131.53,14.51 131.54,14.51 131.75,14.72 132.93,14.72 133.02,14.81 v1(133.02,15.23)
PCH_GPIO83: length 11.9
  IN4 w0.076: v1(126,10.89) 126.1,10.89 126.58,10.41 127.72,10.41 128.38,11.06 128.38,11.27 v1(128.5,11.38) ; v1(122.69,7.46) 122.71,7.46 123.24,7.99 123.24,8.2 122.78,8.65 122.78,10.66 123.02,10.9 123.99,10.9 124.33,10.56 124.75,10.56 124.98,10.33 v1(126,10.33)
  BOTTOM w0.076: v1(126,10.33) v1(126,10.89) ; v2(122.64,6.49) 122.69,6.54 v1(122.69,7.46)
PCH_INTVRMEN: length 30.7
  IN1 w0.076: v4(128.23,24.96) 128.29,25.02 128.29,25.45 128.06,25.68 127.66,25.68 127.5,25.53 127.11,25.53 125.8,26.84 118.44,26.84 118.42,26.82 118.42,25.2 118.08,24.87 117.28,24.87 117.1,25.05 113.54,25.05 113.03,25.56 112.24,25.56 111.38,24.69 108.49,24.69 107.01,26.18 105.65,26.18 v4(105.14,26.69)
  IN4 w0.076: v1(129.36,24.12) 129.27,24.21 129.16,24.21 128.41,24.96 v4(128.23,24.96) ; v4(105.14,26.69) 104.73,26.28 v1(104.73,26.26)
  BOTTOM w0.076: RH23.2 v1(104.73,26.26)
PCH_INV_PWM: length 138.1
  IN4 w0.076: v1(146.33,11.13) 146.64,11.13 147.45,11.94 148.18,11.94 148.5,11.63 148.5,10.87 151.86,7.5 153.4,5.97 153.4,5.11 154.4,4.11 154.88,4.11 157.54,1.46 198.86,1.46 199.68,2.28 242.78,2.28 243.83,3.32 248.36,3.32 250.42,5.38 261.82,5.38 263.71,7.27 263.71,10.08 v1(260.47,13.31)
  BOTTOM w0.076: v2(260.97,18.18) 260.97,16.71 260.4,16.14 D4.3 260.4,15.57 260.24,15.41 260.24,13.55 v1(260.47,13.31)
PCH_JTAG_JTAGX: length 77.8
  IN2 w0.076: v3(195.62,11.09) 194.54,12.17 191.94,12.17 191.32,11.55 184.08,11.55 181.02,8.49 172.6,8.49 162.42,18.67 162.42,23.53 159.53,26.42 159.25,26.42 v3(159.09,26.26) 158.85,26.01 158.85,25.53 155.67,22.36 155.67,22.18 154.48,20.99 153.74,20.99 v4(153.74,20.99)
  IN4 w0.076: v4(153.74,20.99) 153.75,20.99 153.79,21.03 v1(154.12,21.03) ; v1(200.03,7.01) 199.71,7.01 199.7,7.01 196.73,7.01 195.7,5.99 v1(194.6,5.99)
  BOTTOM w0.076: v3(195.62,11.09) 196.76,11.09 197.49,10.36 197.49,7.7 197.24,7.45 197.24,5.76 197.1,5.62 195.27,5.62 194.9,5.99 v1(194.6,5.99) ; RH36.2 159.95,26.49 T16.1 159.12,26.23 v3(159.09,26.26) ; v1(200.03,7.01) 200.12,6.91 200.12,4.8 199.68,4.36 RH154.1
PCH_JTAG_TCK: length 69
  IN2 w0.076: v3(195.08,11.09) 194.17,12.01 191.99,12.01 191.24,11.26 184,11.26 180.94,8.2 172.68,8.2 161.69,19.18 161.69,23.35 160.18,24.86 v3(159.05,24.86) 158.39,24.86 157.52,23.98 157.52,21.41 156.24,20.13 154.96,20.13 154.87,20.22 153.77,20.22 v4(153.58,20.41)
  IN4 w0.076: v1(153.87,20.6) 153.68,20.41 v4(153.58,20.41)
  BOTTOM w0.076: v3(195.08,11.09) 195.43,11.44 196.63,11.44 197.64,10.42 197.64,7.63 197.4,7.39 197.4,5.58 197.14,5.33 RH153.1 RH152.1 ; v3(159.05,24.86) 159.59,24.86 T19.1 160.21,25.48 RH39.2
PCH_JTAG_TDO: length 66.6
  IN2 w0.076: v4(153.53,19.75) 153.85,20.07 154.76,20.07 154.84,19.98 156.3,19.98 157.67,21.35 157.67,23.92 158.25,24.51 158.81,24.51 v3(159.05,24.27) 159.78,24.27 161.26,22.79 161.26,19.4 172.62,8.04 181.01,8.04 184.07,11.1 191.3,11.1 192.05,11.85 193.76,11.85 v3(194.5,11.12)
  IN4 w0.076: v1(154.12,20.17) 153.7,19.75 v4(153.53,19.75)
  BOTTOM w0.076: RH32.2 196.53,8.61 196.53,7.75 196.02,7.23 196.02,6.4 195.62,6 RH156.1 ; RH32.2 196.33,8.81 RH157.1 ; RH32.2 197.01,9.44 197.01,10 196.66,10.36 195.26,10.36 v3(194.5,11.12) ; v3(159.05,24.27) 160.71,24.27 T17.1
PCH_MUTE#: length 150
  IN1 w0.076: v3(15.4,45.05) 22.25,45.05 24.99,42.31 28.53,42.31 29.84,41 35.2,41 36.11,41.91 37.39,41.91 37.78,42.31 47.08,42.31 47.99,41.39 53.17,41.39 v4(53.29,41.51) ; v4(130.17,14.33) 129.98,14.53 129.6,14.53 129.37,14.76 126.96,14.76 126.81,14.61 126.35,14.61 126.07,14.89 118.12,14.89 117.27,14.89 116.11,16.05 115.54,16.05 115.17,15.68 112.23,15.68 111.85,16.06 110.55,16.06 108.94,14.44 105.95,14.44 105.51,14.01 99.94,14.01 99.15,13.23 95.59,13.23 95.31,12.95 v4(95.31,12.92)
  IN3 w0.076: v4(53.29,41.51) 53.33,41.51 53.48,41.36 53.48,22.51 59.21,16.78 69.62,16.78 70.36,17.52 79.53,17.52 85.22,11.83 90.99,11.83 92.02,12.86 94.29,12.86 94.58,12.57 94.94,12.57 95.29,12.92 v4(95.31,12.92)
  IN4 w0.076: v7(130.78,15.33) 130.77,15.33 130.59,15.16 130.59,14.84 130.62,14.81 130.62,14.57 130.4,14.34 130.18,14.34 v4(130.17,14.33)
  GND3 w0.076: v7(130.78,15.33) 130.64,15.33 130.4,15.57 v8(130.38,15.57)
  BOTTOM w0.076: v2(12.84,44.57) 14.92,44.57 v3(15.4,45.05) 15.52,44.94 15.78,44.94 15.81,44.91 DA8.3
PCH_ON: length 2.1
  BOTTOM w0.076: v2(80.16,48.86) 78.8,48.86 78.32,48.38 R306.2
PCH_OPIRCOMP: length 6.2
  IN4 w0.203: v1(133.7,24.62) 133.67,24.65 133.67,25.1 133.36,25.41 133.36,25.44 133.27,25.53 133.27,25.54 132.72,26.09 132.67,26.09 132.43,26.32 v1(132.34,26.32)
  BOTTOM w0.076: RC22.1 133.1,27.81 132.62,28.29 v2(132.62,29.62)
  BOTTOM w0.381: RC22.1 132.45,27.13 132.45,26.42 v1(132.34,26.32)
PCH_PCIE_WAKE#: length 284.3
  TOP w0.076: v3(174.37,13.77) 174.37,13.11 172.84,11.58 172.47,11.58 166.46,5.57 166.46,5.45 166.02,5.01 153.15,5.01 152.89,5.28 136.63,5.28 133.73,8.18 124.23,8.18 121.16,11.25 113.95,11.25 109.39,15.82 v5(104.38,15.82)
  IN1 w0.076: v4(104.38,15.33) v5(104.38,15.82)
  IN3 w0.076: v4(284.01,80.23) 283.75,79.98 283.75,60.14 292.99,50.9 292.99,48.89 293.53,48.35 293.53,48.06 295.51,46.08 296.32,46.08 296.61,45.79 296.61,44.72 296.95,44.37 296.95,21.7 289.78,14.53 289.19,14.53 288.77,14.11 287.26,14.11 286.39,13.24 285.63,13.24 285.46,13.07 284.39,13.07 283.47,12.15 282.62,12.15 281.39,10.92 273.41,10.92 273.06,11.26 268.06,11.26 266.99,10.19 251.15,10.19 247.55,13.79 237.19,13.79 236.69,14.29 232.7,14.29 232.15,14.85 228.15,14.85 227.2,13.9 227.2,13.16 224.4,10.35 213.49,10.35 213.05,10.8 200.52,10.8 199.53,11.79 192.54,11.79 191.42,10.67 188.89,10.67 188.53,11.03 187.54,11.03 184.92,11.03 184.54,11.42 184.21,11.42 183.11,12.52 174.78,12.52 174.37,12.93 v3(174.37,13.77)
  IN4 w0.076: v1(104.73,15.33) v4(104.38,15.33) ; v4(284.01,80.23) 284.01,80.74 284.21,80.94 284.99,80.94 285.42,81.37 286.12,81.37 286.18,81.32 286.53,81.32 286.79,81.58 286.79,81.96 286.94,82.1 287.35,82.1 287.58,81.87 287.87,81.87 v1(288.11,81.63)
PCH_PLTRST#: length 44.8
  IN1 w0.066: v4(130.74,17.72) 130.74,17.13 130.49,16.88 129.7,16.88 129.34,17.24 128.49,17.24 127.75,16.5 127.42,16.5 127.19,16.28 126.05,16.28 125.86,16.47 121.93,16.47 121.08,15.62 117.82,15.62 117.81,15.62 117.57,15.62 116.21,16.98 109.33,16.98 108.58,16.23 105.86,16.23 104.56,14.93 97.77,14.93 97.3,15.4 v4(97.3,15.43)
  IN4 w0.066: v4(130.74,17.72) 130.74,17.8 130.38,18.16 v1(130.38,18.17) ; v1(96.81,15.46) 96.86,15.41 97.23,15.41 97.25,15.43 v4(97.3,15.43)
  BOTTOM w0.097: UH1.1 95.94,19.79 95.77,19.63 95.77,19.25 95.87,19.14 UH1.2 97.09,19.14 97.26,18.97 97.26,18.28 96.76,17.77 RH92.2 RH78.2 96.76,15.51 v1(96.81,15.46) 96.83,15.44 v2(97.24,15.44)
PCH_PWRBTN#_XDP: length 5.3
  TOP w0.076: v3(191.25,5.3) 191.56,4.99 191.68,4.99 191.85,4.82 192.69,4.82 192.81,4.7 193.15,4.7 193.36,4.5 JXDP1.41
  BOTTOM w0.076: v2(191.09,3.26) RH163.2 191.09,5.15 v3(191.25,5.3)
PCH_RSMRST#: length 299.6
  TOP w0.076: v5(168.21,17.26) 167.98,17.04 166.42,17.04 162.89,13.51 155.8,13.51 154.03,11.73 138.73,11.73 135.09,15.37 v2(132.99,15.37) 132.47,15.37 132.45,15.38 126.52,15.38 125.1,16.8 125.1,20.03 121.27,23.86 118.03,23.86 v5(118.02,23.84)
  IN1 w0.076: v5(118.02,23.84) 117.93,23.75 v4(117.65,23.75) ; v4(288.78,10.56) 288.78,10.99 292.98,15.18 v4(292.98,16.01) ; v5(168.21,17.26) 168.34,17.14 v4(168.59,17.14)
  IN3 w0.076: v4(168.59,17.14) 168.49,17.04 167.52,17.04 166.99,16.5 166.99,12.11 173.61,5.49 185.34,5.49 185.49,5.64 185.78,5.64 186.24,5.18 188.69,5.18 189.19,5.68 195.21,5.68 195.51,5.98 197.22,5.98 197.42,5.78 200.68,5.78 201.69,6.79 208.8,6.79 209.61,5.97 213.74,5.97 213.93,5.78 217.04,5.78 217.35,6.09 227.47,6.09 230.74,9.36 246.43,9.36 249.38,6.42 261.15,6.42 261.37,6.2 267.18,6.2 268,5.38 285,5.38 288.78,9.16 v4(288.78,10.56)
  IN4 w0.076: v1(104.19,23.92) 106.93,23.92 107.06,23.78 107.26,23.78 108.27,22.77 109.58,22.77 110.83,21.52 111.24,21.52 111.52,21.8 111.52,21.8 111.52,22.04 111.75,22.27 111.98,22.27 112.18,22.47 114.83,22.47 114.84,22.46 115.25,22.46 115.54,22.75 115.54,22.77 115.56,22.79 115.56,23.15 115.11,23.59 115.11,24.13 115.17,24.19 115.17,24.2 115.33,24.37 117.04,24.37 v4(117.65,23.75) 117.69,23.72 117.69,23.38 117.64,23.33 v1(117.64,23.3) ; v1(288.11,78.63) 288.07,78.59 288.07,77.98 287.99,77.9 287.99,77.15 287.13,76.29 287.13,76.02 286.93,75.82 286.93,75.81 286.37,75.25 286.37,73.36 286.08,73.07 286.08,71.91 286.32,71.67 286.32,56.66 289.62,53.36 289.62,50.14 289.62,49.88 291.35,48.15 293.72,48.15 294.71,47.16 294.71,46.25 294.95,46.02 294.95,45.15 295.45,44.64 295.45,43.52 296.14,42.84 296.14,22.6 295.89,22.35 295.89,17.44 294.24,15.79 293.2,15.79 v4(292.98,16.01)
  BOTTOM w0.076: v1(117.64,23.3) 117.64,22.57 RH67.1 117.17,22.1 116.28,22.1 115.35,21.17 RP24.6 ; v1(104.19,23.92) 104.43,23.92 RH74.2
PCH_RSMRST#_R: length 12.7
  IN1 w0.076: v4(127.42,24.27) 127.31,24.38 126.64,24.38 126.08,24.94 125.6,24.94 125.33,25.2 123.68,25.2 123.38,24.91 123.38,24.39 122.7,23.7 119.13,23.7 v4(118.83,23.4)
  IN4 w0.076: v4(118.83,23.4) 118.83,23.4 118.57,23.13 v1(118.53,23.13) ; v4(127.42,24.27) 128,24.27 128.26,24.02 128.26,24.02 128.41,23.87 v1(128.93,23.87)
  BOTTOM w0.076: RH67.2 118.55,23.11 v1(118.53,23.13)
PCH_RTCRST#: length 107.1
  TOP w0.097: v3(59.37,47.92) 59.09,48.2 v6(53.74,48.2) 46.95,48.2 43.21,51.94 JAPS1.10
  IN1 w0.066: v3(95.54,33.91) 95.54,34.61 89.94,40.21 ; 81.06,46.89 79.96,46.89 79.63,47.22 60.07,47.22 v3(59.37,47.92)
  IN1 w0.076: 89.94,40.21 85.2,44.95 84.72,44.95 84.47,45.2 83.75,45.2 82.06,46.89 81.06,46.89
  IN4 w0.066: v1(104.13,30.29) 104.07,30.24 99.22,30.24 95.57,33.9 95.55,33.9 v3(95.54,33.91)
  BOTTOM w0.076: 126.02,23.8 127.12,23.8 127.3,23.62 UCPU1.A8 126.02,25.23 126.02,26.59
  BOTTOM w0.097: 126.02,26.59 125.91,26.7 125.91,28.68 124.6,29.99 118.4,29.99 116.16,32.22 105,32.22 104.13,31.35 v1(104.13,30.29) ; RH18.2 123.23,23.26 CH3.2 124.78,23.8 126.02,23.8 ; v3(95.54,33.91) 95.55,33.9 96.29,33.9 CLRP1.2
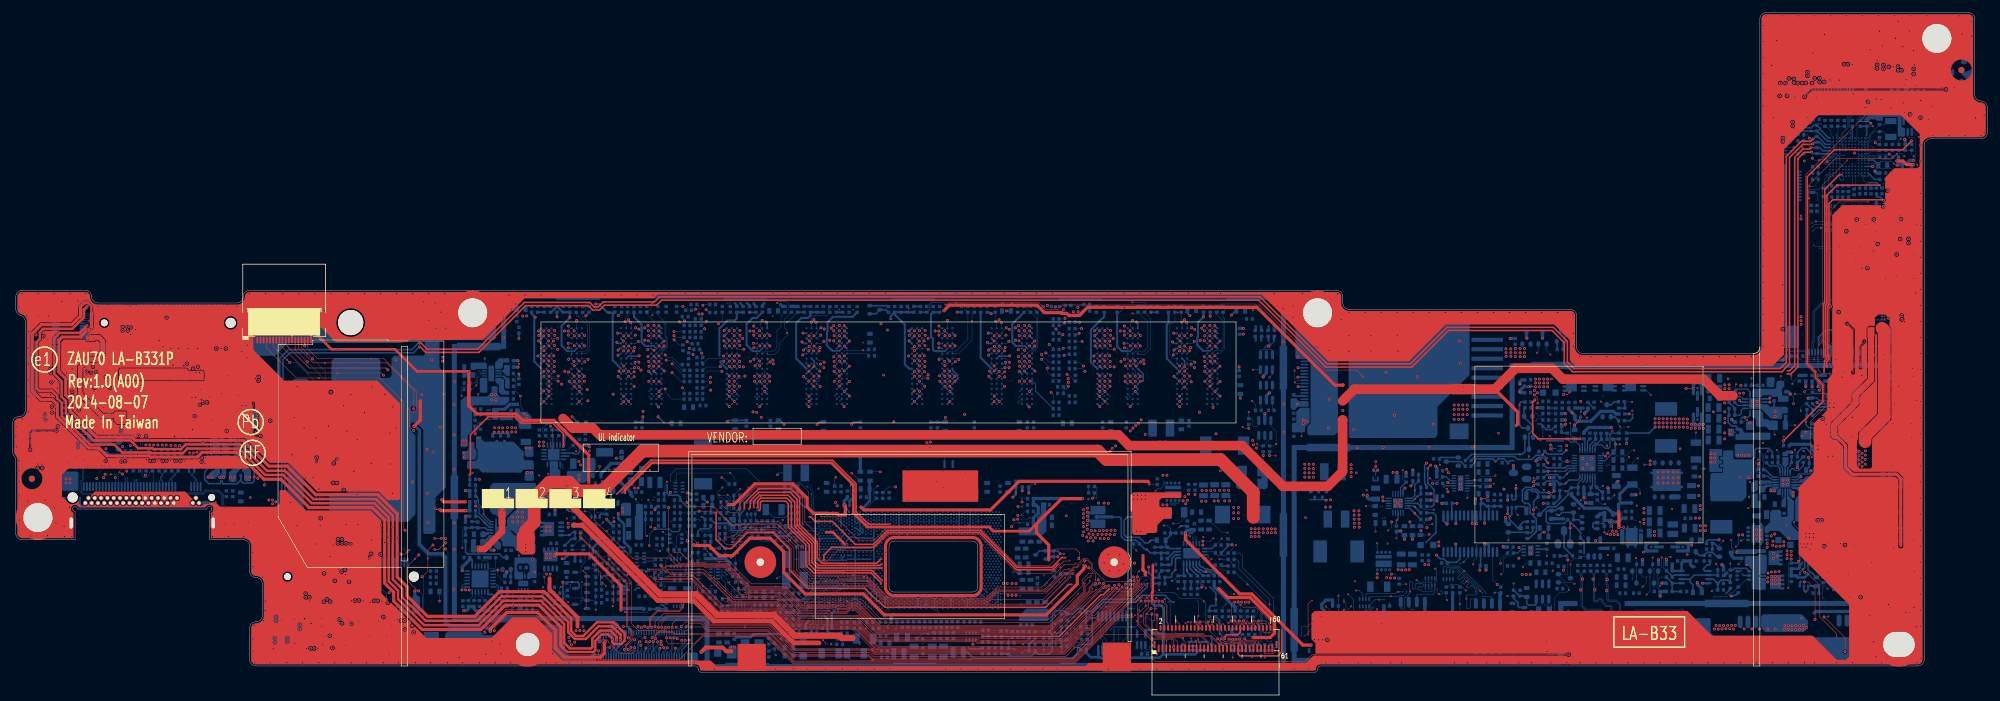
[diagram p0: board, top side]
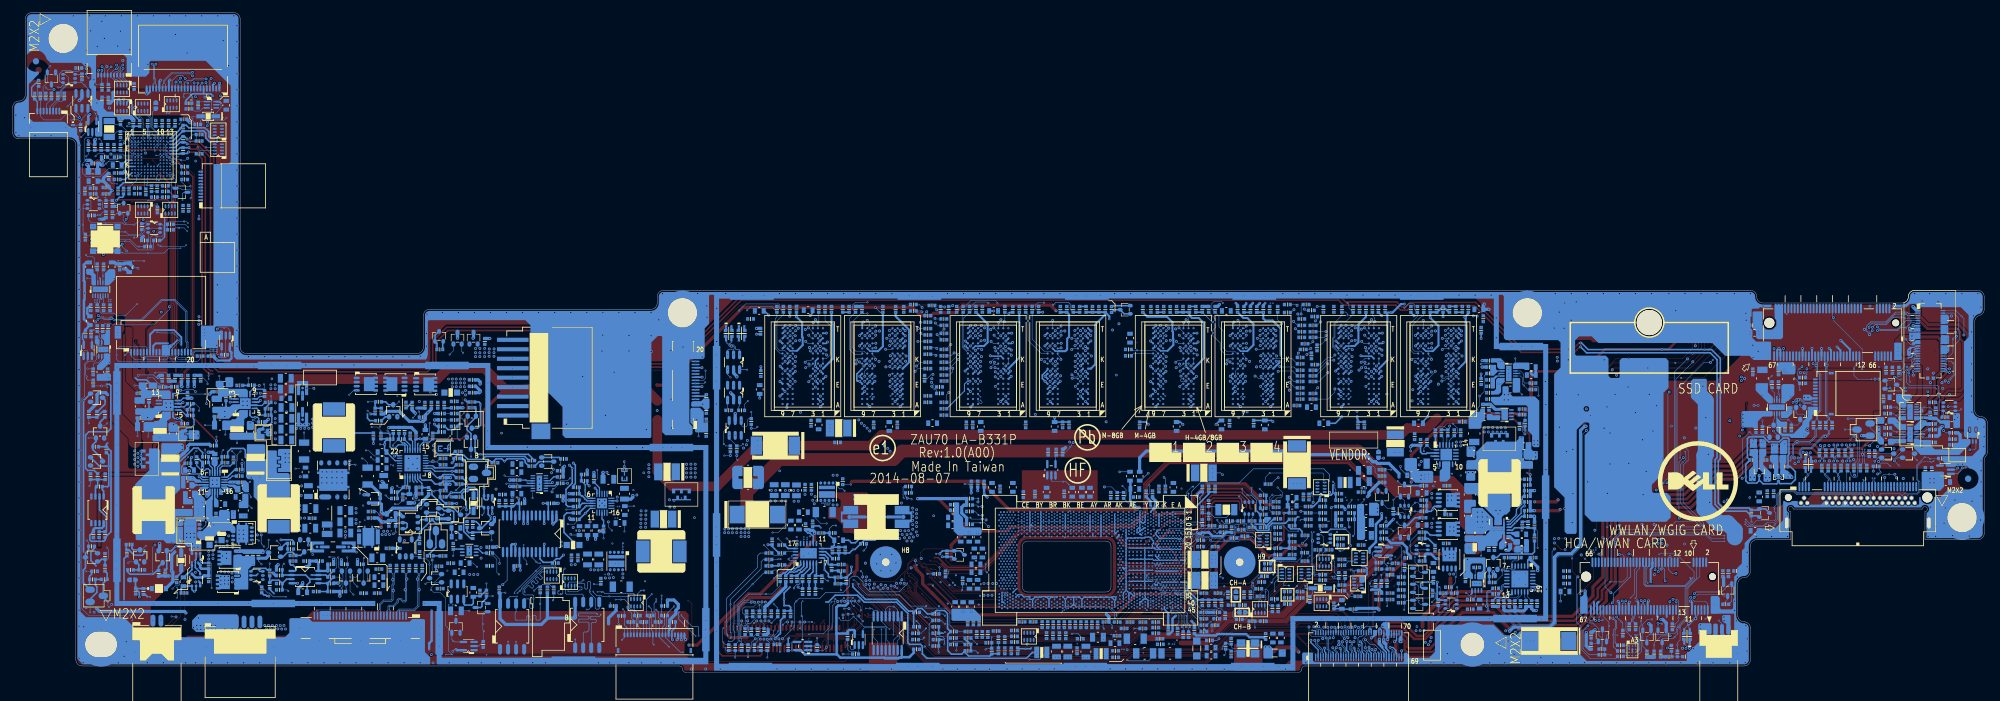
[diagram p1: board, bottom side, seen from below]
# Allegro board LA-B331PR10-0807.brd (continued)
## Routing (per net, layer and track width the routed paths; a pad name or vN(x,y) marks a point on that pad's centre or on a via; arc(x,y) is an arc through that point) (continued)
PCH_RTCX1: length 10.7
  IN4 w0.066: 126.02,24.31 126.01,24.32 125.84,24.32 124.71,25.46 124.42,25.46 v1(124.24,25.27)
  IN4 w0.076: 126.02,24.31 126.91,23.41 128.02,23.41 v1(128.07,23.37)
  BOTTOM w0.097: YH1.1 120.46,24.5 122.29,24.5 122.97,25.19 CH1.1 124.16,25.19 v1(124.24,25.27)
PCH_RTCX2: length 7.7
  IN4 w0.066: v1(124.24,26.19) 124.51,25.93 124.88,25.93 126.02,24.79
  IN4 w0.076: v1(128.07,23.87) 127.92,23.72 127.09,23.72 126.02,24.79
  BOTTOM w0.097: YH1.2 122.22,26.29 CH2.1 123.33,26.19 v1(124.24,26.19)
PCH_SATALED#: length 14.5
  IN4 w0.076: v1(128.13,15.14) 128.05,15.06 127.91,15.06 127.6,14.74 126.47,14.74 125.43,15.78 121.69,15.78 119.58,13.67 v1(116.19,13.67)
  BOTTOM w0.076: v2(116.2,14.14) 116.2,13.68 v1(116.19,13.67) 116.13,13.67 115.76,13.3 RH21.2
PCH_SMBCLK: length 111.3
  TOP w0.076: JXDP1.53 196.96,4.38 196.73,4.6 196.73,4.77 196.54,4.96 194.47,4.96 194.24,5.18 v3(194.18,5.25)
  IN1 w0.076: v3(194.18,5.25) 194.14,5.25 193.98,5.08 193.98,4.54 193.75,4.31 179.92,4.31 179.6,4.63 169.75,4.63 168.2,6.18 165.85,6.18 164.27,4.59 153.98,4.59 153.73,4.84 152.97,4.84 152.84,4.72 152.84,4.62 v4(153.03,4.42)
  IN3 w0.076: v4(153.03,4.42) 152.82,4.21 152.82,2.34 152.1,1.63 122.1,1.63 119.49,4.23 119.49,5.4 117.09,7.8 117.09,9.81 111.77,15.13 109.84,15.13 109.37,15.6 109.37,16.55 109.02,16.91 106.49,16.91 106,17.4 104.95,17.4 v4(104.87,17.48)
  IN4 w0.076: v4(104.87,17.48) 104.87,17.54 105.19,17.86 v1(105.19,17.94)
  BOTTOM w0.076: QH1.1 104.39,20.53 104.84,20.08 104.84,19.6 RH54.2 105.19,18.84 v1(105.19,17.94)
PCH_SMBDATA: length 112.4
  TOP w0.076: JXDP1.51 196.36,4.35 196.58,4.58 196.58,4.7 196.49,4.79 194.42,4.79 194.3,4.91 193.95,4.91 v3(193.61,5.25)
  IN1 w0.076: v4(152.5,4.42) 152.51,4.42 152.69,4.6 152.69,4.78 152.91,5 153.79,5 154.05,4.74 164.2,4.74 165.79,6.33 168.26,6.33 169.81,4.78 179.66,4.78 179.98,4.46 193.69,4.46 193.83,4.6 193.83,5.08 193.65,5.25 193.58,5.25 193.59,5.25 v3(193.61,5.25)
  IN3 w0.076: v4(106.25,17.86) 106.25,17.81 106.21,17.77 106.21,17.41 106.55,17.06 109.08,17.06 109.52,16.62 109.52,15.66 109.63,15.56 109.9,15.28 111.83,15.28 117.24,9.87 117.24,7.87 119.64,5.47 119.64,4.3 122.16,1.78 152.04,1.78 152.66,2.41 152.66,4.26 v4(152.5,4.42)
  IN4 w0.076: v1(106.16,18.38) 106.35,18.19 106.35,17.96 v4(106.25,17.86)
  BOTTOM w0.076: QH1.4 105.44,21.83 105.07,21.46 105.07,19.83 RH57.2 105.69,19.21 105.69,18.91 106.16,18.45 v1(106.16,18.38) 106.14,18.37 105.79,18.37 105.69,18.27 RP7.4
PCH_SPI_CLK: length 111.4
  IN1 w0.066: v4(134.97,5.25) 134.97,5.3 135.43,5.76 136.83,5.76 137.95,4.64 147.94,4.64 150.04,2.54 201.8,2.54 203.55,4.28 v4(203.74,4.28)
  IN3 w0.076: v4(126.29,16.88) 126.22,16.95 126.22,17.47 126.02,17.67
  IN3 w0.097: 126.02,17.67 125.87,17.82 125.47,17.82 124.87,17.21 124.87,9.57 129.31,5.12 134.3,5.12 134.43,5.25 v4(134.97,5.25)
  IN4 w0.066: v4(203.74,4.28) 203.74,4.29 204.06,4.6 204.32,4.6 207.68,7.97 v1(212.18,7.97) 212.18,8.91 212.9,9.63 214.18,9.63 214.65,10.1 v1(214.65,10.44)
  IN4 w0.076: v1(128.13,16.87) 127.97,16.87 127.73,16.63 127.15,16.63 127.08,16.55 126.62,16.55 v4(126.29,16.88)
  BOTTOM w0.097: v1(212.18,7.97) 212.18,7.96 JSPI1.8
PCH_SPI_CS0#: length 116.6
  IN1 w0.066: v4(141.97,7.36) 147.91,7.36 151.6,3.66 155.99,3.66 155.99,3.67 156.12,3.79 166.88,3.79 167.58,4.5 168.95,4.5 169.41,4.04 179.26,4.04 179.59,3.71 197.2,3.71 197.6,4.12 201.42,4.12 202.35,5.05 202.35,7 202.47,7.13 206.42,7.13 206.54,7.02 206.54,6.48 206.47,6.42 206.34,6.42 206.27,6.48 206.27,6.8 206.19,6.88 206.08,6.88 206.01,6.8 206.01,6.48 205.94,6.42 205.81,6.42 205.74,6.48 205.74,6.8 205.67,6.88 205.56,6.88 205.48,6.8 205.48,6.48 205.41,6.42 205.28,6.42 205.21,6.48 205.21,6.77 205.14,6.85 205.03,6.85 204.95,6.77 204.95,6.48 204.88,6.42 204.75,6.42 204.69,6.48 204.69,6.75 204.61,6.82 204.5,6.82 204.42,6.75 204.42,6.48 204.36,6.42 204.22,6.42 204.16,6.48 204.16,6.72 204.08,6.8 203.97,6.8 203.89,6.72 203.89,6.48 203.83,6.42 203.7,6.42 203.63,6.48 203.63,6.63 203.56,6.7 203.01,6.7 202.88,6.57 202.88,5.28 v4(202.83,5.22)
  IN3 w0.076: 129.36,8.97 128.48,9.85 128.48,15.12 129.17,15.8 129.2,15.8 129.52,16.12 v4(129.6,16.12)
  IN3 w0.097: v4(141.97,7.36) 141.62,7.01 141.02,7.01 140.6,7.43 139.42,7.43 139.35,7.49 137.6,7.49 137.17,7.92 130.41,7.92 129.36,8.97
  IN4 w0.066: v1(211.02,4.35) 208.11,4.35 207.59,3.84 203.56,3.84 202.83,4.56 v4(202.83,5.22)
  IN4 w0.076: v4(129.6,16.12) 129.6,16.16 129.38,16.38 v1(129.38,16.44)
  BOTTOM w0.097: v2(211.82,10.45) 211.41,10.04 211.41,9.62 211.16,9.38 RC44.2 211.36,8.78 211.36,6.65 211.18,6.47 JSPI1.10 211.18,4.51 v1(211.02,4.35)
PCH_SPI_CS1#: length 118.2
  IN1 w0.066: v4(215.89,7.22) 215.75,7.36 202.23,7.36 200.39,5.52 199.29,5.52 199.22,5.45 199.22,4.6 199.14,4.53 199.03,4.53 198.96,4.6 198.96,5.45 198.89,5.52 198.76,5.52 198.69,5.45 198.69,4.59 198.62,4.51 198.51,4.51 198.43,4.59 198.43,5.45 198.36,5.52 198.23,5.52 198.16,5.45 198.16,4.62 198.09,4.54 197.98,4.54 197.9,4.62 197.9,5.45 197.83,5.52 197.7,5.52 197.64,5.45 197.64,4.59 197.56,4.51 197.45,4.51 197.37,4.59 197.37,5.45 197.31,5.52 197.17,5.52 197.11,5.45 197.11,5.06 197.04,5 196.2,5 196.07,4.87 196.07,4.23 195.95,4.1 195.76,4.1 195.69,4.17 195.69,4.85 195.62,4.92 195.49,4.92 195.42,4.85 195.42,4.17 195.36,4.1 195.23,4.1 195.16,4.17 195.16,4.85 195.09,4.92 194.96,4.92 194.9,4.85 194.9,4.17 194.83,4.1 194.7,4.1 194.63,4.17 194.63,4.85 194.57,4.92 194.43,4.92 194.37,4.85 194.37,4.17 194.3,4.1 179.75,4.1 179.42,4.43 169.57,4.43 169.05,4.95 167.35,4.95 166.58,4.18 155.96,4.18 155.83,4.05 151.76,4.05 147.46,8.35 141.27,8.35 140.5,7.57 139.54,7.57 139.04,8.07 v4(138.64,8.07)
  IN3 w0.076: 136.89,8.97 136.57,9.29 133.54,9.29 133.22,8.97 ; v4(130.62,16.12) 130.63,16.11 130.63,16.11 130.88,15.85 130.88,15.14 130.69,14.95 129.49,14.95 128.84,14.31 128.84,10.13 130,8.97
  IN3 w0.097: 130,8.97 130.35,8.62 132.87,8.62 133.22,8.97 ; 136.89,8.97 137.79,8.07 v4(138.64,8.07)
  IN4 w0.066: v4(215.89,7.22) 215.77,7.1 v1(215.35,7.1)
  IN4 w0.076: v4(130.62,16.12) 130.38,16.35 v1(130.38,16.44)
  BOTTOM w0.097: v2(215.92,9.97) 215.71,9.76 RC40.2 215.64,8.87 215.64,7.4 v1(215.35,7.1) 215.35,7.09 215.18,6.92 JSPI1.2
PCH_SPI_CS2#: length 120.6
  IN1 w0.066: v4(201.39,3.52) 201.39,3.66 201.13,3.93 197.68,3.93 197.28,3.52 179.51,3.52 179.23,3.8 168.88,3.8 168.68,3.6 156.2,3.6 156.07,3.47 151.52,3.47 148.5,6.49 142.3,6.49 v4(141.44,7.36)
  IN3 w0.076: 129.68,8.97 128.69,9.96 128.69,14.37 129.42,15.11 129.66,15.11 130.05,15.49 130.05,16.03 v4(130.13,16.12)
  IN3 w0.097: v4(141.44,7.36) 141.14,7.65 139.51,7.65 139.45,7.71 137.7,7.71 137.26,8.16 133.19,8.16 132.96,8.39 130.25,8.39 129.68,8.97
  IN4 w0.066: v4(201.39,3.52) 201.19,3.73 201.19,4.87 201.74,5.41 202.16,5.41 208.89,12.14 220.6,12.14 221.18,12.72 221.18,13.14 224.06,16.01 226.35,16.01 227.28,16.95 228.67,16.95 v1(229.02,17.29)
  IN4 w0.076: v4(130.13,16.12) 130.13,16.2 129.89,16.44 v1(129.88,16.44)
  BOTTOM w0.097: v1(229.02,17.29) 229.41,17.29 v2(229.63,17.51) 230.34,18.22 U21.22
PCH_SPI_IO2: length 99.3
  IN1 w0.066: v4(140.1,7.05) 140.16,7.1 140.43,7.1 141.03,7.7 147.84,7.7 151.68,3.86 155.91,3.86 156.04,3.99 166.66,3.99 167.37,4.69 169.03,4.69 169.49,4.24 179.34,4.24 179.67,3.91 197.12,3.91 197.52,4.32 201.12,4.32 v4(201.88,5.07)
  IN3 w0.076: 129.03,8.97 128.33,9.67 128.33,15.18 128.74,15.59 128.74,15.79 v4(129.07,16.12)
  IN3 w0.097: 129.03,8.97 130.3,7.7 136.92,7.7 137.35,7.27 139.26,7.27 139.36,7.17 139.99,7.17 v4(140.1,7.05)
  IN4 w0.066: v1(208.61,4.02) 208.23,3.64 203.31,3.64 v4(201.88,5.07)
  IN4 w0.076: v1(128.88,16.44) 128.88,16.31 129.07,16.13 v4(129.07,16.12)
  BOTTOM w0.097: v1(208.61,4.02) 208.63,4.04 208.65,4.04 210.18,5.58 JSPI1.12 210.18,7.68 RC45.2 209.89,8.26 210.33,8.69 210.33,9.57 v2(210.67,9.91)
PCH_SPI_IO3: length 98.8
  IN1 w0.066: v4(200.86,3.4) 200.78,3.4 200.57,3.18 167.04,3.18 166.81,3.41 156.28,3.41 156.15,3.28 151.44,3.28 148.47,6.25 140.69,6.25 140.65,6.21 v4(140.59,6.21)
  IN3 w0.076: 128.7,8.97 127.93,9.74 127.93,14.99 128.59,15.65 128.59,16.2 129.14,16.76 v4(129.14,16.77)
  IN3 w0.097: 128.7,8.97 130.19,7.48 136.82,7.48 137.26,7.04 139.09,7.04 139.59,6.54 139.86,6.54 140.15,6.25 140.54,6.25 v4(140.59,6.21)
  IN4 w0.066: v4(200.86,3.4) 200.86,3.37 201.05,3.17 v1(206.45,3.17)
  IN4 w0.076: v4(129.14,16.77) 129.24,16.87 v1(129.63,16.87)
  BOTTOM w0.097: v2(207.81,10.44) 208.87,9.37 RC46.2 208.99,8.87 208.99,7.24 209.18,7.05 JSPI1.14 209.18,5.53 206.82,3.17 v1(206.45,3.17)
PCH_SPI_SI: length 104.9
  IN1 w0.066: v4(139.59,6.19) 139.91,5.87 148.58,5.87 151.36,3.08 156.23,3.08 156.36,3.21 166.58,3.21 166.8,2.98 201.47,2.98 203.63,5.14 v4(203.63,5.19)
  IN3 w0.076: v4(127.24,14.27) 127.24,14.22 127.12,14.09 127.12,10.23 128.38,8.97
  IN3 w0.097: 128.38,8.97 130.09,7.25 136.73,7.25 137.16,6.82 137.35,6.82 138.85,6.82 139.48,6.19 v4(139.59,6.19)
  IN4 w0.066: v1(214.15,10.44) 214.12,10.44 213.75,10.08 210.18,10.08 209.16,9.06 v1(206.67,9.06) ; v4(203.63,5.19) 203.63,5.48 v1(203.93,5.78)
  IN4 w0.076: v4(127.24,14.27) 127.41,14.44 127.73,14.44 127.99,14.71 v1(128.38,14.71)
  BOTTOM w0.097: v1(214.15,10.44) 214.15,9.95 RC42.2 213.54,8.64 213.54,7.32 213.18,6.97 JSPI1.6 ; v1(203.93,5.78) 203.93,7.13 204.03,7.23 204.94,7.23 v2(205.77,8.05) 206.67,8.95 v1(206.67,9.06)
PCH_SPI_SO: length 113.7
  IN1 w0.066: v4(135.61,5.3) 135.68,5.22 136.73,5.22 137.8,4.16 147.79,4.16 148.81,3.14 148.81,2.79 149.51,2.09 202.12,2.09 204.1,4.07 204.1,5.15 v4(204.2,5.25)
  IN3 w0.097: v4(125.67,17.34) 125.57,17.24 125.57,9.54 129.38,5.73 135.18,5.73 v4(135.61,5.3)
  IN4 w0.066: v1(215.28,10.34) 215.28,10.37 215.1,10.54 215.1,10.63 214.84,10.89 214.1,10.89 v1(213.65,10.44) 210.08,10.44 209.14,9.51 v1(207.05,9.51) ; v4(125.67,17.34) 125.74,17.34 125.75,17.35 125.93,17.35 126.02,17.44 ; v4(204.2,5.25) 204.2,5.38 204.4,5.58 v1(204.4,5.73)
  IN4 w0.076: 126.02,17.44 126.03,17.44 126.26,17.67 v1(126.29,17.67)
  BOTTOM w0.076: UCPU1.B23 126.93,18.17 126.43,17.67 v1(126.29,17.67)
  BOTTOM w0.097: v1(215.28,10.34) 215.28,10.1 214.6,9.42 214.6,8.6 214.21,8.21 RC41.2 214.18,7.94 JSPI1.4 ; v1(207.05,9.51) 207.1,9.46 v2(207.1,8.83) 207.1,8.43 v1(204.4,5.73)
PCH_SRTCRST#: length 23.8
  IN1 w0.066: 126.02,25.39 125.79,25.39 125.49,25.7 123.53,25.7 122.93,25.1 122.93,24.57 122.51,24.15 118.19,24.15 118.09,24.26 117.03,24.26 116.84,24.44 114.69,24.44 114.07,23.82 109.3,23.82 v4(109.1,24.02)
  IN1 w0.076: 126.02,25.39 126.06,25.39 126.79,24.66 127.32,24.66 v4(127.42,24.76)
  IN4 w0.066: v4(109.1,24.02) 108.76,24.02 v1(108.72,24.06)
  IN4 w0.076: v4(127.42,24.76) 127.79,24.76 128.43,24.12 v1(128.5,24.12)
  BOTTOM w0.097: RH19.2 CH4.1 108.6,24.22 108.72,24.1 v1(108.72,24.06)
PCH_WWAN_WAKE#: length 149.2
  IN2 w0.076: v4(52.74,47.86) 52.91,47.69 58.67,47.69 64.41,41.95 84.55,41.95 88.44,38.07 88.62,38.07 89.36,37.32 89.36,36.76 94.26,31.86 94.83,31.86 98.64,28.05 100.44,28.05 102.66,25.82 102.88,25.82 104.79,23.92 104.79,22.75 105.42,22.12 107.5,22.12 108.16,22.78 115.99,22.78 116.05,22.84 118.93,22.84 119.45,23.36 119.65,23.36 v4(119.66,23.35) 119.66,23.36 120.55,23.36 124,19.91 125.01,19.91 125.34,19.58 125.69,19.58 126.02,19.91 126.86,19.91 126.91,19.86 129.36,19.86 129.54,19.68 130.71,19.68 130.78,19.75 133.77,19.75 134.2,19.32 136.13,19.32 136.66,18.79 136.66,18.34 136.28,17.96 v4(136.24,17.96)
  IN3 w0.076: v3(49.75,11.56) 49.75,17.27 51.1,18.62 51.1,20.44 50.92,20.62 50.92,28.82 52.49,30.38 52.49,47.6 v4(52.74,47.86)
  IN4 w0.076: v1(119.59,23.03) 119.63,23.07 119.63,23.33 119.66,23.36 v4(119.66,23.35) ; v1(130.88,18.17) 131.67,18.17 132.01,17.82 134.38,17.82 134.7,17.51 134.96,17.51 135.3,17.85 136.13,17.85 v4(136.24,17.96)
  BOTTOM w0.076: v3(49.75,11.56) 49.13,11.56 48.89,11.32 v2(48.89,8.55) 48.89,8.13 49.41,7.61 49.41,7.18 R358.1
PCIE_PRX_DTX_N3: length 139.5
  IN4 w0.066: v1(19.26,30.5) 19.36,30.4 19.36,30.17 19.51,30.02 20.07,30.02 20.62,30.56 28.16,30.56 28.64,30.08 30.15,30.08 30.5,29.73 34.2,29.73 46,17.92 46,14.39 48.61,11.79 48.61,10.52 53.79,5.33 68.64,5.33 73.15,9.83 77.55,9.83 78.73,11.02 84.25,11.02 86.46,8.81 107.92,8.81 109.52,7.21 119.66,7.21 120.59,6.27 121.38,6.27 121.95,5.71 122.49,5.71 123.22,4.98 127.54,4.98 128.83,6.26 130.43,6.26 131.84,7.68 132.92,7.68 134.52,9.28 134.52,11.85 v1(134.56,11.88)
  BOTTOM w0.097: JNGFF1.35 19.25,30.16 19.34,30.25 19.34,30.42 v1(19.26,30.5)
PCIE_PRX_DTX_N5: length 147.3
  IN4 w0.066: v1(135.43,11.38) 135.43,10.97 136.25,10.15 136.25,8.11 135.55,7.4 133.57,7.4 133.39,7.22 132.03,7.22 130.62,5.81 129.01,5.81 127.73,4.53 123.04,4.53 122.3,5.26 121.76,5.26 121.19,5.83 120.36,5.83 119.43,6.76 109.34,6.76 107.73,8.36 86.23,8.36 84.03,10.57 78.92,10.57 77.74,9.39 73.4,9.39 68.9,4.88 53.6,4.88 48.09,10.39 48.09,11.63 45.5,14.22 45.5,15.63 36.21,24.93 36.21,26.89 33.82,29.28 30.3,29.28 29.94,29.63 28.38,29.63 28.01,30 20.69,30 20.24,29.56 18.25,29.56 17.35,30.45 13.9,30.45 13.41,29.96 13.41,29.56 v1(13.25,29.4)
PCIE_PRX_DTX_N6: length 87
  IN1 w0.066: v3(54.79,11.36) 54.49,11.66 54.49,11.82 54.76,12.08 61.96,12.08 63.65,10.39 72.13,10.39 72.71,9.81 83.81,9.81 85.81,7.82 108.43,7.82 110.78,10.17 121.1,10.17 121.53,9.74 126,9.74 126.88,8.86 130.73,8.86 131.04,9.17 131.41,9.17 132.52,10.28 132.52,11.59 132.31,11.8 132.31,12.01 132.46,12.16 132.55,12.16 132.67,12.03 v4(132.67,11.96)
  IN4 w0.066: v1(132.4,12.13) 132.55,12.13 132.67,12.01 v4(132.67,11.96)
  BOTTOM w0.097: JNGFF2.35 54.75,10.65 54.61,10.79 54.61,11.18 v3(54.79,11.36)
PCIE_PRX_DTX_P3: length 139.1
  IN4 w0.066: v1(19.64,30.5) 19.5,30.35 19.5,30.23 19.57,30.15 20.01,30.15 20.56,30.7 28.22,30.7 28.7,30.22 30.2,30.22 30.56,29.86 34.25,29.86 46.14,17.98 46.14,14.44 48.74,11.84 48.74,10.57 53.85,5.46 68.59,5.46 73.09,9.97 77.49,9.97 78.68,11.15 84.31,11.15 86.51,8.94 107.98,8.94 109.58,7.34 119.72,7.34 120.65,6.41 121.43,6.41 122,5.84 122.55,5.84 123.28,5.11 127.48,5.11 128.77,6.4 130.37,6.4 131.79,7.81 132.87,7.81 134.39,9.34 134.39,11.59 134.34,11.63 v1(134.13,11.63)
  BOTTOM w0.097: v1(19.64,30.5) 19.54,30.39 19.54,30.25 19.75,30.05 JNGFF1.33
PCIE_PRX_DTX_P5: length 147.3
  IN4 w0.066: v1(135.86,11.13) 135.61,11.13 135.56,11.08 135.56,11.02 136.38,10.2 136.38,8.05 135.6,7.27 133.63,7.27 133.45,7.09 132.09,7.09 130.67,5.68 129.06,5.68 127.78,4.39 122.98,4.39 122.25,5.13 121.7,5.13 121.14,5.69 120.31,5.69 119.38,6.62 109.28,6.62 107.68,8.23 86.18,8.23 83.97,10.43 78.97,10.43 77.79,9.25 73.46,9.25 68.96,4.75 53.55,4.75 47.96,10.34 47.96,11.57 45.37,14.16 45.37,15.58 36.07,24.87 36.07,26.83 33.76,29.14 30.24,29.14 29.89,29.5 28.33,29.5 27.96,29.87 20.74,29.87 20.3,29.42 18.19,29.42 17.3,30.32 13.96,30.32 13.54,29.91 13.54,29.6 v1(13.75,29.4)
PCIE_PRX_DTX_P6: length 87
  IN1 w0.066: v3(54.21,11.36) 54.34,11.5 54.34,11.88 54.68,12.21 62.02,12.21 63.71,10.53 72.19,10.53 72.77,9.95 83.87,9.95 85.87,7.95 108.37,7.95 110.72,10.3 121.16,10.3 121.59,9.87 126.06,9.87 126.94,8.99 130.68,8.99 130.99,9.3 131.35,9.3 132.39,10.33 132.39,11.53 132.17,11.75 132.17,12.06 132.38,12.27 132.38,12.27 132.53,12.42 v4(132.53,12.52)
  IN4 w0.066: v4(132.53,12.52) 132.54,12.52 132.67,12.38 v1(132.83,12.38)
  BOTTOM w0.097: JNGFF2.33 54.25,10.66 54.41,10.83 54.41,11.16 v3(54.21,11.36)
PCIE_PTX_DRX_N3: length 146.9
  IN4 w0.066: v1(148.88,5.35) 148.66,5.35 147.81,4.49 147.01,4.49 145.57,3.06 137.83,3.06 137.68,2.91 135.2,2.91 133.43,1.14 114.67,1.14 111.28,4.53 105.66,4.53 105.61,4.58 103.59,4.58 102.31,5.86 85.92,5.86 83.77,8.01 74.02,8.01 69.59,3.58 53.04,3.58 42.5,14.11 42.5,16.69 32.49,26.7 30.9,26.7 29.44,28.16 27.92,28.16 27.45,28.63 21.19,28.63 v7(21.09,28.73)
  GND3 w0.076: v7(21.09,28.73) 21.09,28.74 21.07,28.76
  GND3 w0.097: 21.07,28.76 21.07,28.91 20.9,29.08 20.9,29.25 v8(20.75,29.4)
PCIE_PTX_DRX_N3_C: length 9.9
  IN4 w0.066: v1(148.88,6.27) 148.5,6.27 148.45,6.32 148.45,6.49 148.12,6.82 147.52,6.82 145.41,8.93 143.3,11.04 141.23,11.04 v1(141.13,11.13)
PCIE_PTX_DRX_N5: length 153.9
  IN4 w0.066: v1(14.75,29.4) 14.88,29.4 14.93,29.35 14.93,29.07 15.17,28.82 20.56,28.82 21,29.26 27.7,29.26 28.09,28.87 29.64,28.87 29.96,28.55 33.44,28.55 35.43,26.56 35.43,24.65 44.69,15.39 44.69,12.77 53.29,4.17 69.27,4.17 73.7,8.59 84.06,8.59 85.68,6.97 91.17,6.97 91.67,6.47 104.21,6.47 105.02,5.67 107.85,5.67 108.11,5.4 118.95,5.4 119.36,5 119.36,2.33 119.96,1.73 133.17,1.73 134.96,3.52 135.29,3.52 135.96,4.19 137.62,4.19 137.97,3.85 145.52,3.85 146.58,4.9 146.58,5.05 146.85,5.33 v1(146.85,5.34)
PCIE_PTX_DRX_N5_C: length 10
  IN4 w0.066: v1(146.85,6.25) 146.49,6.25 146.42,6.33 146.42,7.09 143.41,10.09 140.89,10.09 140.57,10.41 140.57,10.94 140.27,11.24 140.26,11.24 140.15,11.35 139.93,11.35 139.83,11.45 v1(139.83,11.55)
PCIE_PTX_DRX_N6: length 85.6
  IN4 w0.066: v1(55.66,6.75) 55.76,6.75 56.41,6.11 56.8,6.11 57.38,6.69 60.16,6.69 61.15,7.68 62.56,7.68 62.8,7.92 70.41,7.92 72.95,10.46 77.23,10.46 78.37,11.61 84.49,11.61 86.7,9.39 108.16,9.39 109.68,7.88 119.82,7.88 120.85,6.86 121.62,6.86 122.19,6.29 122.73,6.29 123.46,5.56 127.29,5.56 128.61,6.88 130.2,6.88 131.72,8.41 131.72,8.42 133.4,10.1 133.4,10.67 133.61,10.88 v1(133.7,10.88)
PCIE_PTX_DRX_N6_C: length 2.5
  BOTTOM w0.097: JNGFF2.39 55.75,9 55.89,8.86 55.89,8.58 56.1,8.37 56.1,8.1 55.89,7.89 55.89,7.89 C203.2
PCIE_PTX_DRX_P3: length 146.9
  IN4 w0.066: v1(147.86,5.34) 148.11,5.58 148.46,5.58 148.54,5.5 148.54,5.42 147.75,4.63 146.95,4.63 145.51,3.19 137.78,3.19 137.62,3.04 135.14,3.04 133.38,1.28 114.72,1.28 111.34,4.66 105.72,4.66 105.67,4.71 103.65,4.71 102.36,6 85.98,6 83.83,8.15 73.96,8.15 69.54,3.72 53.09,3.72 42.64,14.17 42.64,16.75 32.55,26.84 30.96,26.84 29.5,28.3 27.98,28.3 27.51,28.77 21.52,28.77 v7(21.41,28.88)
  GND3 w0.097: v7(21.41,28.88) 21.25,29.05 v8(21.25,29.4)
PCIE_PTX_DRX_P3_C: length 9.8
  IN4 w0.066: v1(147.86,6.25) 148.23,6.25 148.3,6.32 148.3,6.43 148.04,6.69 147.47,6.69 145.33,8.83 145.32,8.83 143.24,10.91 141.24,10.91 141.13,10.8 v1(141.13,10.63)
PCIE_PTX_DRX_P5: length 153.8
  IN4 w0.066: v1(15.25,29.4) 15.18,29.4 15.06,29.28 15.06,29.12 15.23,28.95 20.5,28.95 20.95,29.4 27.75,29.4 28.15,29.01 29.7,29.01 30.01,28.69 33.49,28.69 35.57,26.61 35.57,24.7 44.82,15.44 44.82,12.82 53.35,4.3 69.22,4.3 73.64,8.73 84.11,8.73 85.74,7.1 91.23,7.1 91.72,6.61 104.26,6.61 105.07,5.8 107.9,5.8 108.17,5.54 119.01,5.54 119.49,5.05 119.49,2.39 120.02,1.87 133.11,1.87 134.9,3.65 135.23,3.65 135.9,4.32 137.68,4.32 138.02,3.98 145.46,3.98 146.44,4.96 146.44,5.25 146.36,5.34 v1(145.83,5.34)
PCIE_PTX_DRX_P5_C: length 10.1
  IN4 w0.066: v1(145.83,6.25) 146.19,6.25 146.28,6.34 146.28,7.04 143.36,9.96 140.82,9.96 140.74,10.04 140.43,10.35 140.43,10.88 140.09,11.22 139.84,11.22 139.74,11.12 139.74,10.98 v1(139.83,10.88)
PCIE_PTX_DRX_P6: length 85.7
  IN4 w0.066: v1(133.26,11.13) 133.26,10.15 131.59,8.48 131.59,8.47 130.14,7.02 128.56,7.02 127.23,5.69 123.52,5.69 122.79,6.42 122.24,6.42 121.68,6.99 120.9,6.99 119.88,8.01 109.73,8.01 108.22,9.52 86.76,9.52 84.54,11.74 78.32,11.74 77.17,10.59 72.89,10.59 70.36,8.06 62.75,8.06 62.5,7.81 61.09,7.81 60.1,6.82 57.32,6.82 56.74,6.24 56.46,6.24 56.04,6.66 56.04,6.72 56.09,6.77 56.65,6.77 v1(56.68,6.75)
PCIE_PTX_DRX_P6_C: length 2.5
  BOTTOM w0.097: JNGFF2.41 56.25,9 56.09,8.84 56.09,8.66 56.3,8.45 56.3,8.04 C204.2
PCIE_RCOMP: length 5.8
  IN4 w0.203: v1(128.93,11.13) 128.93,11.09 127.75,9.91 127.2,9.91 125.93,8.64 v1(125.93,8.17)
  BOTTOM w0.381: RH134.2 125.49,7.05 125.49,7.66 125.93,8.09 v1(125.93,8.17)
PCIE_WAKE#: length 400.2
  IN1 w0.076: v4(291.76,73.63) 289.88,73.63 288,71.75 v4(287.91,71.75) 285.15,71.75 v4(284.24,72.66)
  IN2 w0.076: v4(287.91,71.75) 287.91,70.76 288.95,69.73 288.95,60.26 299.58,49.63 299.58,12.61 296.51,9.54 296.51,8.94 290.41,2.84 259.57,2.84 258.41,4 245.28,4 244.33,3.05 206.32,3.05 206.06,2.8 202.49,2.8 201.84,2.15 151.22,2.15 150.97,2.4 146.44,2.4 146.29,2.56 138.7,2.56 138.23,3.03 137.72,3.03 136.48,4.26 136,4.26 135.51,3.78 134.87,3.78 134.01,2.92 125.3,2.92 124.95,3.26 122.66,3.26 122.33,2.93 121.07,2.93 120.83,3.18 120.83,5.2 119.63,6.39 110.31,6.39 108.4,8.3 107.44,8.3 107.1,8.64 102.3,8.64 101.75,9.19 94.65,9.19 93.58,10.26 93.54,10.26 92.35,11.45 85.93,11.45 85.45,11.93 77.84,11.93 77.16,11.26 69.28,11.26 62.66,17.87 59.01,17.87 v3(58.23,18.66) 52.88,24.01 45.55,24.01 42.99,26.57 42.99,27.18 41.39,28.78 37.59,28.78 35.91,30.46 21.2,30.46 21.09,30.36 16.73,30.36 v3(16.25,30.84)
  IN4 w0.076: v1(291.63,72.67) 291.82,72.86 291.82,73.56 v4(291.76,73.63) ; JNGFF1.62 12.5,28.28 12.7,28.48 13.57,28.48 14.23,29.14 14.23,29.67 14.43,29.86 15.79,29.86 v1(16.25,29.4) ; v4(284.24,72.66) 283.92,72.97 283.92,78.41 284.68,79.17 284.8,79.28 285.61,79.28 285.98,79.64 285.98,80.46 286.39,80.87 286.64,80.87 287.16,81.39 288.21,81.39 288.45,81.63 v1(288.61,81.63)
  BOTTOM w0.076: v3(58.23,18.66) 57.75,18.66 57.5,18.41 JNGFF2.46 ; v1(16.25,29.4) v3(16.25,30.84)
PECI_EC: length 2.5
  BOTTOM w0.076: R219.1 286.98,86.5 287.74,85.75 287.74,85.19 288.11,84.81 U38.A12
PHASE: length 6.9
  IN4 w1.016: 183.42,27.4 184.99,25.84 185.04,25.84 187.59,23.28 187.59,22.22
  vias: v1(182.92,28.16) v1(183.3,28.16) v1(187.28,21.46) v1(187.28,21.07) v2(188.43,21.42) v3(177.38,28.05) v3(177.35,27.38) v3(177.89,22.33) v3(178.01,28.05) v3(178.01,27.41) v3(178.52,22.33) v3(178.65,28.05) v3(178.65,27.41) v3(179.28,28.05) v3(179.28,27.41)
PLT_RST#: length 525.6
  TOP w0.097: v3(174.01,13.31) 173.9,13.19 173.9,13.04 172.76,11.91 172.39,11.91 166.17,5.69 166.17,5.57 165.9,5.3 153.29,5.3 153.02,5.57 136.75,5.57 133.74,8.59 124.23,8.59 121.28,11.54 114.07,11.54 109.38,16.23 v5(103.54,16.23) ; v5(90.47,10.01) 90.76,10.3 90.76,15.62 v5(90.31,16.07)
  IN1 w0.066: v4(280.25,78.55) 280.19,78.55 280.02,78.39 280.02,71.28 281,70.29 289.3,70.29 289.52,70.51 294.23,70.51 v4(294.7,70.99) ; v4(280.25,78.55) v4(283.13,78.55) ; v4(280.25,78.55) 280.19,78.62 280.19,82.92 280.53,83.27 280.53,85.66 280.71,85.83 280.71,90.57 281.26,91.13 281.26,93.36 281.89,93.99 v3(281.89,94.01) ; v4(89.06,9.86) 89.06,9.88 89.2,10.01 v5(90.47,10.01) ; v4(95.46,16.88) 95.69,16.65 100.96,16.65 101.38,16.23 v5(103.54,16.23) ; v4(90.69,16.93) 90.31,16.55 v5(90.31,16.07)
  IN2 w0.097: v4(13.12,34.64) 13.12,34.38 15.1,32.4 15.1,30.58 16.07,29.61 21.31,29.61 21.71,30.02 35.57,30.02 37.47,28.12 41.11,28.12 42.43,26.81 42.43,26.49 45.58,23.34 45.58,11.31 47.34,9.54 57.79,9.54 59.24,11 v3(59.36,11) 59.36,7.91 59.87,7.41 62.75,7.41 62.8,7.36 v3(63.21,7.36) 63.21,7.4 65.02,9.21 76.97,9.21 78.33,10.57 85.1,10.57 86.02,9.65 88.91,9.65 89.06,9.81 v4(89.06,9.86)
  IN3 w0.097: v4(279.75,50.33) 279.46,50.63 279.46,77.76 v4(280.25,78.55) ; v3(174.01,13.31) 174.01,12.87 174.65,12.23 182.98,12.23 184.09,11.13 184.42,11.13 184.8,10.74 187.66,10.74 188.41,10.74 188.77,10.38 191.54,10.38 192.29,11.13 192.6,11.13 v4(192.66,11.18) 192.97,11.5 199.41,11.5 200.4,10.51 212.93,10.51 213.37,10.06 224.52,10.06 228.14,13.68 232.83,13.68 233.08,13.43 234.48,13.43 v3(234.94,13.89) 234.96,13.89 235.35,13.5 247.43,13.5 251.08,9.85 267.06,9.85 268.18,10.97 272.94,10.97 273.29,10.63 281.51,10.63 282.74,11.86 284.73,11.86 v4(285.74,12.87)
  IN4 w0.066: v4(90.69,16.93) 90.74,16.88 v1(94.98,16.88) v4(95.46,16.88) ; v4(283.13,78.55) 282.96,78.38 282.95,78.38 282.87,78.31 v1(282.74,78.31) ; v1(279.91,49.94) 279.91,50.18 v4(279.75,50.33) ; v4(285.74,12.87) 288.53,12.87 289.85,14.19 292.39,14.19 292.69,13.88 295.94,13.88 297.72,15.66 297.85,15.66 298.24,16.05 298.24,16.34 299.31,17.41 299.31,20.14 299.12,20.34 299.12,34.17 299.63,34.68 299.63,48.41 296.31,51.73 294.8,51.73 294.09,52.44 294.09,53.45 293.71,53.83 293.71,56.04 293.56,56.19 293.56,60.38 294.46,61.28 294.46,66.89 294.66,67.1 294.66,70.95 v4(294.7,70.99) 294.97,71.25 294.97,75.64 294.84,75.77 294.84,77.32 294.85,77.33 294.85,78.11 294.21,78.75 294.21,79.42 293.49,80.14 292.63,80.14 v1(292.61,80.13) ; v3(3.97,32.38) 3.97,32.36 4.5,31.83 8.32,31.83 11.51,35.02 12.74,35.02 v4(13.12,34.64) ; v4(192.66,11.18) 192.31,10.84 v1(192.06,10.84)
  BOTTOM w0.097: R366.1 63.01,2.77 63.99,3.76 63.99,6.57 v3(63.21,7.36) ; RH164.2 191.43,10.19 192.06,10.82 v1(192.06,10.84) ; U51.1 4.7,31.45 4.18,31.97 4.18,32.17 v3(3.97,32.38) 3.5,32.38 v2(3.4,32.48) ; JNGFF2.42 56.5,15.1 59.14,12.46 59.14,11.22 v3(59.36,11) ; U61.2 278.78,50.56 R387.1 278.51,50.17 278.84,49.84 279.8,49.84 v1(279.91,49.94) ; v3(234.94,13.89) 234.24,14.59 U21.16 ; UH1.4 95.3,18.49 95.39,18.41 95.39,17.29 v1(94.98,16.88) RH89.1 RH78.1 ; v3(281.89,94.01) 283.82,94.01 284.12,93.71 284.96,93.71 285.28,93.39 JSNR1.12
PLTRST1#_XDP: length 4.6
  TOP w0.076: JXDP1.46 194.86,7.42 194.78,7.49 194.49,7.49 194.34,7.64 193.32,7.64 v3(192.82,8.14)
  BOTTOM w0.076: RH164.1 v2(192.4,7.83) 192.51,7.83 v3(192.82,8.14)
PM_SYS_RESET#: length 207.6
  TOP w0.076: v3(193.39,11.12) 193.21,11.12 192.86,10.77 192.86,8.75 193.44,8.17 v3(193.44,8.14) 193.78,7.8 194.4,7.8 194.55,7.64 195.27,7.64 195.46,7.46 JXDP1.48 ; JAPS1.6 41.21,51.7 v2(43.46,49.46) v3(43.83,49.09) ; v5(110.97,15.05) 114.19,11.83 121.4,11.83 124.35,8.88 133.86,8.88 136.76,5.97 165.22,5.97 172.5,13.25 173.04,13.25 v3(173.48,13.69)
  IN1 w0.076: v4(99.9,11.94) 100.17,11.66 101.07,11.66 102.22,12.82 108.73,12.82 v5(110.97,15.05)
  IN3 w0.076: v3(173.48,13.69) 173.62,13.55 173.62,12.84 174.52,11.94 182.12,11.94 183.22,10.84 184.3,10.84 184.68,10.45 187.78,10.45 188.29,10.45 188.65,10.09 191.66,10.09 192.41,10.84 192.8,10.84 193.11,10.84 v3(193.39,11.12)
  IN4 w0.076: v1(49.06,26.61) 49.11,26.56 49.11,24.2 48.89,23.98 48.89,17 50.48,15.41 50.48,14.47 51.32,13.62 60.82,13.62 62.52,11.92 67.03,11.92 69.3,14.19 78.37,14.19 78.74,13.82 85.88,13.82 86.88,12.82 93.86,12.82 94.7,11.98 97.25,11.98 97.44,11.79 98.91,11.79 v1(99.15,12.03) 99.73,12.03 99.83,11.94 v4(99.9,11.94)
  BOTTOM w0.076: v3(43.83,49.09) 44.82,49.09 49.11,44.8 49.11,26.79 49.06,26.74 v1(49.06,26.61) ; v3(193.44,8.14) 193.46,8.16 RH160.1 C1.1
POWER_SW_IN#: length 52
  IN1 w0.254: v3(295.16,67.83) 294.23,66.9 282.64,66.9 279.64,69.9 279.64,85.02 279.94,85.32 279.94,90.44 v3(280.81,91.31)
  BOTTOM w0.076: v6(294.45,66.75) 294.47,66.75 295.16,67.44 v3(295.16,67.83)
  BOTTOM w0.254: v3(280.81,91.31) 281.14,91.63 282.28,91.63 ; SW6.3 299.62,66.84 296.64,66.84 296.51,66.7 SW6.4 295.91,67.08 v3(295.16,67.83) ; R324.1 285.06,90.62 284.05,91.63 282.28,91.63 ; 282.28,91.63 JSNR1.6
PQ2_G: length 67.1
  IN1 w0.508: v4(293.85,45.18) 293.79,45.24 287.63,45.24 286.48,46.39 v4(286.48,46.4)
  IN2 w0.508: v4(297.47,43.56) 296.3,44.73 295.31,44.73 294.8,45.24 293.91,45.24 v4(293.85,45.18)
  IN4 w0.254: v1(297.47,43.98) v4(297.47,43.56)
  IN4 w0.508: 249.49,42.79 249.34,42.79 247.81,44.31 247.81,46.11 248.33,46.63 v1(250.48,46.63) 250.82,46.97 282.46,46.97 283.03,46.4 v4(286.48,46.4) ; 249.49,42.79 v1(250.26,42.79) ; 249.49,42.79 v1(248.55,41.85) 248.14,41.45 v1(248.14,40.42)
  BOTTOM w0.076: v2(248.22,41.31) 248.14,41.23 v1(248.14,40.42)
  BOTTOM w0.508: PC10.2 v1(248.55,41.85) ; v1(297.47,43.98) 297.79,44.3 298.82,44.3 299.15,43.97 299.15,42.61 PR78.1
PRGM1: length 3.4
  BOTTOM w0.076: PR514.1 v2(191.35,21.18)
  BOTTOM w0.254: PR514.1 189.78,19.6 PU702.17
PRGM2: length 4.3
  IN4 w0.254: v1(185.31,20.4) 184.61,21.1 v1(184.61,22.9)
  BOTTOM w0.254: PR518.1 185.77,23.18 v2(184.91,23.18) 184.88,23.18 v1(184.61,22.9)
PROC_OPI_COMP: length 13.4
  IN4 w0.152: 132.65,25.39 132.91,25.39 133.18,25.12 133.41,24.89 133.41,24.54 133.42,24.54 133.42,24.5 133.51,24.4 133.51,24.3 v1(133.7,24.12)
  IN4 w0.203: 132.65,25.39 132.03,26.01 132.03,26.71 131.72,27.02 131.19,27.02 130.52,27.7 125.24,27.7 v1(125.11,27.83)
  BOTTOM w0.102: v2(124.65,27.53) 124.65,27.68 124.24,28.08 RC36.1
  BOTTOM w0.381: v1(125.11,27.83) 125.03,27.91 125.03,28.16 124.6,28.59 RC36.1
PROJECT_ID: length 40
  IN1 w0.076: v3(280.12,54.37) 280.95,55.2 280.95,60.73 281.26,61.05 v4(290.54,61.05)
  IN4 w0.076: v1(291.09,74.73) 291.09,74.42 290.92,74.24 290.92,71.75 291.15,71.51 291.21,71.46 291.21,67.91 290.99,67.69 290.99,61.51 v4(290.54,61.05) ; v1(288.78,75.28) 288.78,76.57 289.71,77.5 v1(289.71,77.99)
  BOTTOM w0.076: U38.N9 289.71,78.53 v1(289.71,77.99) ; v1(291.09,74.73) 290.07,74.73 289.61,75.19 R341.1 v1(288.78,75.28) ; U61.1 278.13,54.22 278.47,54.56 v2(279.03,54.56) 279.93,54.56 v3(280.12,54.37)
PROXIMITY_OUT#: length 43.7
  IN1 w0.076: v4(298.96,75.71) 298.47,75.22 294.75,75.22 293.8,74.27 292.89,74.27 v4(292.24,73.63) ; v4(294.31,91.17) 294.31,89.44 293.89,89.02 293.89,88.61 292.67,87.39 291.5,87.39 290.13,86.02 290.13,85.1 291.31,83.91 291.69,83.91 v4(292.07,83.53)
  IN3 w0.076: v4(292.07,83.53) 292.81,84.27 295.59,84.27 298.75,81.11 298.75,77.12 298.61,76.98 298.61,76.07 v4(298.96,75.71)
  IN4 w0.076: v1(292.13,72.67) 292.13,73.52 v4(292.24,73.63) ; v3(286.68,93.52) 286.74,93.52 286.85,93.4 290.29,93.4 290.73,92.97 292.51,92.97 v4(294.31,91.17) ; v4(292.07,83.53) 292.11,83.49 v1(292.11,83.13)
  BOTTOM w0.076: v3(286.68,93.52) 286.78,93.41 JSNR1.15
PS_ID: length 224.4
  TOP w0.076: v3(107.35,7.18) 109.21,7.18 109.93,6.46 119.38,6.46 123.32,2.53 135.33,2.53 135.93,1.93 167.74,1.93 176.84,11.04 177.76,11.04 178.5,11.78 179.59,11.78 179.82,12.01 v5(179.82,12.1)
  IN1 w0.076: v4(286.53,7.87) 286.53,7.26 283.57,4.3 265.91,4.3 252.34,17.87 249.23,17.87 249.11,18 247.39,18 247.25,17.86 246.25,16.86 245.41,16.86 241.3,12.75 204.75,12.75 202.39,15.12 198.79,15.12 195.83,12.16 179.88,12.16 v5(179.82,12.1)
  IN4 w0.076: v1(297.42,11.13) 294.43,11.13 293.98,10.68 293.98,6.91 293.06,5.99 288.6,5.99 286.71,7.87 v4(286.53,7.87)
  BOTTOM w0.076: v1(297.42,11.13) 297.42,10.52 v2(297.22,10.32) ; JIO1.10 104.7,5.95 104.94,5.71 106.96,5.71 107.35,6.1 v3(107.35,7.18)
  BOTTOM w0.254: v1(297.42,11.13) 298.16,11.87 PQ101.1 298.16,14.11 PR130.1 297.55,15.7 PR105.1
PS_ID_EC: length 101.2
  IN4 w0.076: v1(300.33,13.98) 299.17,13.98 297.9,12.72 290.08,12.72 289.13,11.77 v1(286.49,11.77) ; v1(286.51,13.43) 286.84,13.76 286.84,16.13 287.56,16.86 292.83,16.86 293.41,16.27 293.77,16.27 294,16.5 294,16.96 294.18,17.14 294.63,17.14 295.2,17.71 295.2,22.56 295.5,22.87 295.5,42.57 294.82,43.26 294.82,44.35 294.31,44.85 294.31,45.24 294.06,45.5 293.01,45.5 291.65,46.86 291.24,46.86 291.08,47.02 291.08,47.53 288.99,49.62 288.99,49.87 288.99,49.87 288.99,53.1 285.32,56.76 285.32,71.32 285.14,71.51 285.14,73.09 284.91,73.32 284.91,75.23 286.05,76.38 286.05,77.54 286.74,78.22 286.74,78.83 286.89,78.99 287.06,78.99 287.46,79.38 287.71,79.38 287.96,79.63 v1(288.11,79.63)
  BOTTOM w0.076: v1(286.51,13.43) 286.42,13.34 286.42,11.84 v1(286.49,11.77) ; PR102.2 v2(300.94,16.01)
  BOTTOM w0.254: v1(300.33,13.98) PR103.2 300.33,15.23 299.98,15.57 PR102.2
PSID-1: length 4.7
  BOTTOM w0.076: PR106.1 297.54,17.9 297.35,18.08 297.35,19.52 v2(297.61,19.77)
  BOTTOM w0.254: PQ102.2 298.78,17.55 298.43,17.9 PR106.1 PR105.2
PSID-2: length 8.7
  BOTTOM w0.076: PR104.1 300.48,20.58 v2(300.79,20.89)
  BOTTOM w0.254: PQ101.2 301.31,14.15 301.31,16.19 300.97,16.53 PQ102.1 300.97,18.88 300.48,19.37 PR104.1
PTP_I2C_BUF_EN: length 291
  TOP w0.076: v3(102.19,7.13) 102.19,7.76 103.39,8.96 109.1,8.96 110.57,7.49 119.82,7.49 123.75,3.56 135.76,3.56 136.36,2.97 166.37,2.97 169.31,5.91 170.16,5.91 176.42,12.17 176.94,12.17 178.32,13.55 178.32,13.56 178.35,13.59 v5(178.35,14.73)
  IN1 w0.076: v4(282.36,79.6) 283.06,78.9 287.37,78.9 288.07,78.2 v4(288.45,78.2) ; v5(178.35,14.73) 178.36,14.74 178.36,14.85 v4(178.52,15.02)
  IN3 w0.076: v4(199.69,14.47) 199.82,14.47 200.09,14.74 200.64,14.74 200.71,14.8 200.99,14.8 201.19,14.6 201.19,14.12 201.17,14.09 201.17,13.68 201.17,13.55 201.54,13.17 202.06,13.17 202.55,12.69 203.23,12.69 203.29,12.76 214,12.76 214.73,12.03 223.7,12.03 225.51,13.84 225.51,14.6 227.44,16.52 231.11,16.52 231.74,17.15 234.11,17.15 234.79,16.46 237.1,16.46 237.9,17.26 248.58,17.26 252.65,13.2 267.54,13.2 268.79,14.44 272.36,14.44 274.22,12.59 280.69,12.59 281.75,13.66 281.75,13.99 282.96,15.2 283.93,15.2 284.21,15.49 287.46,15.49 287.85,15.49 290.07,17.71 291.02,17.71 295.55,22.24 295.55,43.77 294.45,44.86 293.65,44.86 291.22,47.29 291.22,48.01 290.35,48.88 290.35,52.02 287.48,54.89 285.35,54.89 284.98,55.27 284.98,57.83 282.19,60.62 282.19,79.43 v4(282.36,79.6)
  IN4 w0.076: v4(199.69,14.47) 199.41,14.75 198.83,14.75 198.37,14.29 198.37,13.53 197.41,12.57 187.63,12.57 187.28,12.92 181.75,12.92 181.39,13.28 179.71,13.28 178.47,14.51 178.47,14.97 v4(178.52,15.02) ; v4(288.45,78.2) 288.61,78.36 v1(288.61,78.63)
  BOTTOM w0.076: JIO1.26 101.5,6.77 101.6,6.86 101.93,6.86 v3(102.19,7.13)
PWR_LED#: length 21.1
  IN1 w0.076: v3(283.78,93.38) 282.59,92.18 282.59,90.91 282.1,90.43 v4(282.1,89.15)
  IN4 w0.076: v4(282.1,89.15) 284.52,89.15 285.8,90.43 285.99,90.43 286.43,90.87 286.69,90.87 287.5,90.06 288.8,90.06 290.95,87.9 290.95,87.68 292.26,86.38 292.26,86.1 292.61,85.75 v1(292.61,84.13)
  BOTTOM w0.076: JSNR1.9 v3(283.78,93.38)
PWR_SRC_ON: length 7.1
  BOTTOM w0.076: R33.1 v2(237.53,14.06)
  BOTTOM w0.254: Q2.3 241.1,10.83 240.92,10.65 239.85,10.65 239.61,10.89 C11.2 239.48,12.08 R28.2 238.44,12.08 R33.1
PWR_SW_IN#: length 25
  IN1 w0.076: v4(294.35,88.33) 294.26,88.42 293.99,88.42 292.64,87.08 v4(292.64,86.17)
  IN4 w0.076: v4(294.35,88.33) 294.43,88.42 v1(294.43,88.93) 294.43,90.28 292.43,92.28 290.46,92.28 289.75,92.99 285.75,92.99 284.07,91.31 v11(284.07,91.1) ; v1(293.11,83.63) 293.11,83.86 292.85,84.12 292.85,84.23 292.76,84.32 292.76,86.05 v4(292.64,86.17)
  BOTTOM w0.076: v11(284.07,91.1) 284.02,91.05 284.02,90.27 R324.2 C241.1 283.79,88.9 282.85,88.9 282.35,89.41 U58.3
REM_DIODE1_N: length 200.3
  TOP w0.254: v3(284.59,83.1) 284.38,82.89 283.32,82.89 282.01,81.58 282.01,48.58 281.21,47.77 v5(280.88,47.77)
  IN1 w0.254: v4(245.58,50.69) 245.63,50.64 245.78,50.64 246.09,50.34 246.09,49.07 247.08,48.07 278.71,48.07 279.02,47.77 v5(280.88,47.77)
  IN2 w0.254: v3(182.66,31.21) 182.66,31.72 182.37,32.01 172.08,32.01 164.12,24.05 164.12,19.04 164.67,18.48 165.14,18.48 165.31,18.31 v3(165.39,18.31)
  IN4 w0.254: v3(182.66,31.21) 193.08,41.63 193.08,55.01 193.91,55.85 195.74,55.85 196.75,56.85 198.99,56.85 203.83,52.01 219.59,52.01 221.88,54.3 242.27,54.3 243.88,52.69 243.88,50.82 244.31,50.39 245.25,50.39 245.55,50.69 v4(245.58,50.69) 245.35,50.92 v1(245.35,51.15)
  BOTTOM w0.254: U38.E13 286.45,82.63 285.98,83.1 C154.2 v3(284.59,83.1) ; Q24.3 163.83,18.31 C164.1 v3(165.39,18.31) ; v1(245.35,51.15) 245.35,52.11 Q25.2 245.66,53.37 Q25.1
REM_DIODE1_P: length 201.1
  TOP w0.254: v5(280.85,47.26) 281.42,47.26 282.52,48.37 282.52,81.37 283.53,82.38 284.63,82.38 v3(284.67,82.42)
  IN1 w0.254: v5(280.85,47.26) 278.81,47.26 278.5,47.57 246.63,47.57 245.55,48.65 v4(245.55,49.93)
  IN2 w0.254: v3(182.03,31.21) 181.73,31.5 172.29,31.5 164.63,23.84 164.63,19.25 164.88,18.99 165.54,18.99 v3(165.77,18.76)
  IN4 w0.254: v3(182.03,31.21) 182.03,31.34 192.57,41.88 192.57,55.22 193.7,56.35 195.53,56.35 196.53,57.36 199.2,57.36 204.04,52.52 219.38,52.52 221.67,54.81 242.48,54.81 244.43,52.85 v1(244.43,51.15) 244.84,51.55 245.91,51.55 246.09,51.38 246.09,50.31 245.7,49.93 v4(245.55,49.93)
  BOTTOM w0.102: v3(165.77,18.76) v2(166.36,18.76)
  BOTTOM w0.254: v1(244.43,51.15) 244.43,52.34 Q25.3 ; v3(165.77,18.76) 165.77,18.81 165.36,19.22 C164.2 163.5,19.22 Q24.2 162.52,19.25 Q24.1 ; v3(284.67,82.42) 284.9,82.19 C154.1 285.98,82.19 286.04,82.13 U38.F13
REM_DIODE2_N: length 328
  TOP w0.254: v3(64.37,51.55) 64.5,51.55 65.38,50.68 73.77,50.68 81.18,58.08 91.07,58.08 91.77,57.38 92.88,57.38 93.65,58.16 101.9,58.16 102.69,58.95 197.19,58.95 207.79,48.35 221.42,48.35 227.21,54.15 243.61,54.15 245.53,52.23 245.53,48.94 246.87,47.6 279.94,47.6 281.19,48.85 281.19,81.53 283.3,83.63 284.82,83.63 v3(284.9,83.71)
  BOTTOM w0.102: C166.2 37.37,23.88 v2(37.31,23.82)
  BOTTOM w0.254: v3(64.37,51.55) 63.43,50.61 63.39,50.61 43.86,50.61 42.78,49.53 42.78,34 43.09,33.68 43.09,26.58 42.02,25.52 38.11,25.52 C166.2 36.26,24.78 Q27.3 ; U38.D13 286.8,83.13 286.8,83.14 285.98,83.96 C155.2 285.15,83.96 v3(284.9,83.71)
REM_DIODE2_P: length 329.1
  TOP w0.254: v3(64.37,52.16) 64.61,52.16 65.59,51.19 v2(66.22,51.19) 73.56,51.19 80.97,58.59 91.32,58.59 92.02,57.89 92.67,57.89 93.44,58.67 101.55,58.67 102.36,59.47 197.39,59.47 208,48.86 221.21,48.86 227,54.65 243.82,54.65 246.04,52.44 246.04,49.15 247.08,48.1 279.67,48.1 280.68,49.11 280.68,81.74 283.09,84.14 284.57,84.14 v3(284.9,84.47)
  BOTTOM w0.254: U38.C13 286.88,83.63 285.63,84.88 C155.1 285.3,84.88 v3(284.9,84.47) ; v3(64.37,52.16) 64.22,52.16 63.18,51.12 44.07,51.12 44.07,51.12 43.65,51.12 42.27,49.74 42.27,33.79 42.58,33.47 42.58,26.79 41.81,26.03 37.7,26.03 C166.1 36.26,25.7 Q27.2 35.12,25.89 Q27.1
REM_DIODE3_N: length 204.9
  IN1 w0.254: v4(139.08,57.73) 139.31,57.73 140.66,59.07 198.54,59.07 204.56,53.05 207.85,53.05 209.88,55.08 245.07,55.08 v4(245.63,54.53)
  IN2 w0.254: v4(245.63,54.53) 245.3,54.53 243.88,53.1 243.88,50 245.37,48.51 246.31,48.51 247.3,47.52 277.28,47.52 278.12,48.35 v4(279.74,48.35)
  IN4 w0.254: v3(280.14,84.64) 279.36,84.64 278.61,83.89 278.61,48.91 279.16,48.35 v4(279.74,48.35) ; v1(138.59,57.93) 138.87,57.93 v4(139.08,57.73)
  BOTTOM w0.254: v1(138.59,57.93) 138.45,58.07 135.65,58.07 Q29.3 ; U38.A13 287.4,84.63 286.04,85.99 286.04,86.15 C156.2 285.02,86.66 284.62,86.25 282.03,86.25 v2(281.87,86.09) 281.43,85.65 281.43,84.85 281.17,84.59 280.19,84.59 v3(280.14,84.64)
REM_DIODE3_P: length 201.3
  IN1 w0.254: v4(139.1,57.19) 139.5,57.19 140.87,58.56 198.33,58.56 204.35,52.54 208.06,52.54 210.09,54.58 244.69,54.58 245.27,53.99 v4(245.63,53.99)
  IN2 w0.254: v4(279.74,48.89) 279.72,48.86 277.91,48.86 277.07,48.02 247.51,48.02 246.49,49.04 245.65,49.04 244.38,50.31 244.38,52.75 v4(245.63,53.99)
  IN4 w0.254: v1(138.59,57.02) 138.9,57.02 139.08,57.19 v4(139.1,57.19) ; v3(280.14,84.08) 279.95,84.08 279.89,84.13 279.57,84.13 279.12,83.68 279.12,49.12 279.37,48.86 279.72,48.86 v4(279.74,48.89)
  BOTTOM w0.254: v3(280.14,84.08) 281.38,84.08 281.94,84.64 281.94,85.42 282.26,85.74 v2(284.58,85.74) C156.1 285.57,85.74 287.18,84.13 U38.B13 ; v1(138.59,57.02) 138.18,57.43 Q29.1 136.58,56.78 Q29.2
RESET_OUT#: length 351.2
  TOP w0.076: v5(205.64,11.37) 205.53,11.37 205,10.84 v5(205,5.94)
  IN1 w0.076: v4(201.79,12.55) 202.01,12.33 202.28,12.33 203.21,11.4 205.61,11.4 v5(205.64,11.37) 205.69,11.43 241.25,11.43 247.38,17.56 247.51,17.69 248.98,17.69 249.11,17.56 252.22,17.56 265.78,4 283.73,4 287.36,7.63 287.36,10.22 289.49,12.35 289.49,12.48 289.49,12.82 289.74,13.07 v4(289.74,13.12) ; v4(121.93,3.27) 122.67,2.53 133.74,2.53 135.13,3.92 147.71,3.92 148.61,3.02 148.61,2.71 149.43,1.89 149.93,1.89 179.02,1.89 179.02,1.89 202.2,1.89 204.19,3.88 204.76,3.88 205,4.12 v5(205,5.94)
  IN2 w0.076: v4(201.79,12.55) 201.56,12.32 191.88,12.32 191.25,11.7 184.02,11.7 183.66,11.35 v4(183.35,11.35)
  IN3 w0.076: v4(121.93,3.27) 121.56,2.9 121.36,2.9 120.81,3.45 120.81,4.69 117.4,8.11 117.4,10 115.01,12.39 115.01,12.74 115.13,12.85 115.13,14.45 114.46,15.12 114.46,21.53 v4(114.39,21.61)
  IN4 w0.076: v4(183.35,11.35) 183.35,11.3 182.97,10.91 182.79,10.91 v1(182.46,11.24) ; v4(289.74,13.12) 289.83,13.04 297.79,13.04 300.38,15.62 300.38,20.59 300.18,20.78 300.18,33.73 300.69,34.24 300.69,61.98 296.23,66.45 296.23,70.64 297.49,71.9 297.49,74.74 297.28,74.95 297.28,77.37 296.15,78.5 296.15,80.8 295.25,81.7 294.48,81.7 294.41,81.64 293.36,81.64 293.33,81.61 292.9,81.61 292.88,81.63 v1(292.61,81.63) ; v4(114.39,21.61) 114.55,21.77 114.58,21.77 v1(114.68,21.87) 114.75,21.87 114.76,21.89 115.37,21.89 116.29,22.81 118.76,22.81 v1(118.95,23) 119.22,22.73 122.81,22.73 124.1,24.02 125.05,24.02 125.35,23.72 125.73,23.72 126.48,22.97 128.53,22.97 128.67,23.12 128.67,23.19 128.85,23.37 v1(128.93,23.37)
  BOTTOM w0.076: R202.1 184.2,3.45 v6(183.74,3.91) 183.46,4.18 183.46,6.43 182.8,7.09 182.8,10.51 182.46,10.85 v1(182.46,11.24) ; RH179.1 119.52,21.26 119.04,21.75 119.04,22.91 v1(118.95,23) ; v1(114.68,21.87) 114.88,21.67 RP24.5
RUN_ON: length 426.7
  TOP w0.076: v3(285.91,44.67) 286.08,44.84 286.08,45.56 285.06,46.58 285.06,47.43 283.75,48.73 283.75,78.82 292.15,87.22 293.8,87.22 v3(294.05,86.96) ; v5(85.38,35.49) 85.38,38.73 v3(85.1,39.01) ; v5(92.09,26.05) 92.09,24.1 98.08,18.1 103.92,18.1 104.99,17.04 109.51,17.04 109.63,16.92 113.04,16.92 116.62,13.33 122.15,13.33 124.96,10.51 125.81,10.51 125.91,10.61 130.58,10.61 130.82,10.37 131.91,10.37 132.27,10.72 133.6,10.72 137.22,7.1 164.26,7.1 169.84,12.68 169.84,13.7 170.48,14.34 v5(170.48,14.48)
  IN1 w0.076: v3(224.7,29.94) 226.25,29.94 228.15,31.84 232.83,31.84 236.26,35.27 236.26,37.51 237.46,38.71 237.46,39.27 237.73,39.54 238.11,39.54 238.2,39.45 238.73,39.45 239.06,39.12 239.06,38.11 237.82,36.86 237.82,34.72 236.93,33.83 236.93,31.11 239.6,28.45 239.6,25.65 240.22,25.02 248.35,25.02 252.36,21.01 253.58,21.01 256.23,18.36 262.83,18.36 263.19,18.73 268.86,18.73 270,17.58 270,11.82 271.07,10.75 279.91,10.75 281.42,12.26 281.42,15.22 282.97,16.77 285.2,16.77 286.8,18.38 289.72,18.38 291.39,20.05 292.6,20.05 295.06,22.51 295.06,41.2 v4(294.9,41.35) ; v5(85.38,35.49) 87.68,33.19 87.68,31.15 91.91,26.92 91.91,26.23 v5(92.09,26.05) ; v3(294.05,86.96) 294.05,87.14 v4(296.35,89.44) ; v4(293.79,44.54) 292.9,44.54 292.71,44.35 286.23,44.35 v3(285.91,44.67) ; v5(170.48,14.48) 170.84,14.48 v4(170.9,14.55)
  IN3 w0.076: v4(229.56,12.25) 229.54,12.25 226.08,8.79 210.36,8.79 209.89,9.26 199.88,9.26 199.71,9.44 192.52,9.44 192.1,9.02 188.21,9.02 187.93,9.3 184.32,9.3 184.18,9.44 182.43,9.44 181.62,10.25 181.37,10.25 180.71,9.59 179.75,9.59 179.09,10.25 173.65,10.25 170.76,13.14 170.76,14.36 170.9,14.5 v4(170.9,14.55)
  IN4 w0.076: v4(294.9,41.35) 294.54,41.35 294.34,41.56 294.34,42.67 293.79,43.22 v4(293.79,44.54) ; v4(229.56,12.25) 230.6,13.3 233.84,13.3 234.7,14.16 234.7,18.46 234.4,18.77 234.4,25.27 233.41,26.26 230.11,26.26 226.43,29.94 v3(224.7,29.94) ; v4(296.35,89.44) 295.93,89.02 v1(295.93,88.93) ; v3(85.1,39.01) 85.11,39.02 85.11,39.23 79.23,45.1 v1(79.23,45.31) ; v3(273.47,45.43) 273.82,45.79 276.86,45.79 277.59,45.05 282.81,45.05 283.19,44.67 v3(285.91,44.67) ; v1(293.61,83.13) 293.79,83.13 294.12,83.46 294.12,84.84 294.42,85.15 294.42,86.58 294.05,86.95 v3(294.05,86.96)
  BOTTOM w0.076: PR405.1 273.51,45.48 v3(273.47,45.43) ; v3(224.7,29.94) R142.1 ; R369.1 87.36,38.42 86.91,38.87 85.86,38.87 R157.2 85.1,38.68 v3(85.1,39.01) ; PR400.1 286.45,45.21 v3(285.91,44.67) 285.33,44.67 285.19,44.81 283.92,44.81 v6(283.56,44.46)
RUNPWROK: length 8.2
  BOTTOM w0.076: U38.F1 294,82.52 295.26,82.52 R240.1 R241.1 R227.1 R222.1 R212.2 R213.1 300.52,82.06 v2(300.85,81.73)
RX_DE_0: length 2.8
  BOTTOM w0.076: R381.2 R318.2 74.64,11.34 73.73,12.25 U56.16
RX_DE_1: length 2.5
  BOTTOM w0.076: U56.18 72.73,11.94 R319.2 R382.2
RX_EQ_0: length 2.4
  BOTTOM w0.076: R379.2 R316.2 73.01,11.7 73.23,11.92 U56.17
RX_EQ_1: length 4.1
  BOTTOM w0.076: R380.2 R317.2 76.07,11.79 74.53,11.79 74.23,12.09 U56.15
RX_GND: length 2.4
  BOTTOM w0.076: R383.2 74.31,17.64 75.07,17.64 75.23,17.48 U56.6
S3_CONTROL: length 97.6
  TOP w0.076: v3(237.9,29.14) v2(237.9,29.66)
  IN1 w0.254: v3(237.9,29.14) 237.9,28.39 239.12,27.16 239.12,25.44 239.88,24.68 248.17,24.68 252.12,20.73 253.48,20.73 256.94,17.28 262.09,17.28 263.13,18.32 268.25,18.32 269.57,17 269.57,11.8 270.94,10.43 280.28,10.43 281.8,11.95 281.8,14.7 282.45,15.34 284.71,15.34 287.43,18.07 289.92,18.07 v4(291.25,19.4)
  IN2 w0.254: v4(243.06,42.5) 243.06,40.97 239.86,37.77 239.86,31.26 237.9,29.29 v3(237.9,29.14)
  IN4 w0.254: v1(291.63,19.4) v4(291.25,19.4) ; v4(243.06,42.5) v1(243.06,41.9)
  BOTTOM w0.254: v3(237.9,29.14) PQ901.3 237.9,27.52 237.72,27.34 237.36,27.34 237.25,27.45 PQ901.2 ; v1(291.63,19.4) 291.63,18.88 291.97,18.53 293.24,18.53 294.07,19.36 PR79.2 294.52,19.46 PR48.1 ; v1(243.06,41.9) 243.11,41.85 PR10.2
SAR_DPR: length 374.3
  IN1 w0.076: v3(50.25,11.2) 50.38,11.07 50.38,5.99 v3(50.19,5.8)
  IN2 w0.076: v4(286.75,91.91) 287.08,91.58 287.08,89.37 286.6,88.89 286.6,80.62 287.81,79.42 287.81,74.82 287.54,74.55 287.54,74.21 287.94,73.8 288.44,73.8 289.41,72.84 289.41,60.45 300.04,49.82 300.04,12.3 297.02,9.28 297.02,8.68 290.72,2.38 259.32,2.38 258.18,3.52 245.44,3.52 244.52,2.6 206.51,2.6 206.25,2.34 202.9,2.34 202.26,1.69 151.03,1.69 150.85,1.87 135.89,1.87 135.72,1.7 114.86,1.7 113.14,3.42 113.14,5.55 112.88,5.82 110.24,5.82 108.21,7.84 107.25,7.84 106.91,8.18 102.11,8.18 101.56,8.73 94.42,8.73 92.19,10.97 85.76,10.97 85.33,11.4 77.95,11.4 77.29,10.74 69.15,10.74 68.07,11.82 50.87,11.82 v3(50.25,11.2)
  IN4 w0.076: v4(286.75,91.91) 287.94,91.91 288.88,90.97 288.88,90.86 291.56,88.18 291.56,87.98 292.49,87.05 293.38,87.05 294.27,86.16 294.27,85.21 293.95,84.89 293.95,83.51 293.83,83.38 293.52,83.38 293.37,83.23 293.37,82.99 293.27,82.89 293.01,82.89 292.95,82.95 292.79,82.95 292.71,82.87 292.37,82.87 292.13,82.63 v1(292.11,82.63)
  BOTTOM w0.076: R327.2 v2(52.74,4.27) 52.74,4.63 51.61,5.76 50.23,5.76 v3(50.19,5.8) ; JNGFF2.17 v3(50.25,11.2)
SATA_MPHY_EN#: length 13.3
  IN4 w0.076: v1(90.59,18.25) 90.34,18.5 v1(90.34,19.4) 91.06,20.12 91.64,20.12 v1(92.89,21.37)
  BOTTOM w0.076: R176.2 89.9,18.25 89.83,18.33 89.83,18.88 v1(90.34,19.4) Q16.5 ; v1(92.89,21.37) 93.7,21.37 v2(94.05,21.01) ; v1(90.59,18.25) 90.59,17.47 90.03,16.91 90.03,16.1 89.77,15.84 Q17.1
SATA_RCOMP: length 3.6
  BOTTOM w0.254: UCPU1.L44 130.23,9.98 129.63,9.38
  BOTTOM w0.381: 129.63,9.38 RH20.1
SATA_RN1: length 125.2
  IN1 w0.066: v3(29.96,33.95) 29.96,33.91 30.27,33.59 30.71,33.59 30.87,33.44 38.53,33.44 44.82,27.14 46.75,27.14 60.66,13.23 61.98,13.23 64.1,11.11 72.51,11.11 73.09,10.53 84.14,10.53 86.03,8.64 108.23,8.64 110.58,10.98 112.22,10.98 112.87,11.63 113.66,11.63 114.12,11.17 121.16,11.17 121.6,10.73 121.97,10.73 122.24,10.45 129.5,10.45 129.98,9.98 131.3,9.98 131.91,10.58 131.91,11.16 131.51,11.56 131.51,11.85 131.79,12.13 v4(131.86,12.13)
  IN4 w0.066: v1(131.53,12.13) v4(131.86,12.13)
  BOTTOM w0.097: CS4.1 25.13,38.23 25.13,37.86 25.41,37.58 25.92,37.58 27.85,35.65 29.25,35.65 29.78,35.12 29.78,34.63 29.57,34.42 29.57,34.06 29.68,33.95 v3(29.96,33.95)
SATA_RN1_C: length 10.9
  BOTTOM w0.097: CS4.2 25.19,39.97 25.19,40.23 25.59,40.63 25.59,48.4 25.61,48.42 25.61,48.89 25.59,48.92 25.59,49.12 25.75,49.28 JNGFF3.35
SATA_RP1: length 125.1
  IN1 w0.066: v3(29.91,33.34) 30.06,33.49 30.18,33.49 30.21,33.46 30.66,33.46 30.82,33.3 38.47,33.3 44.76,27.01 46.69,27.01 60.6,13.1 61.92,13.1 64.05,10.98 72.45,10.98 73.03,10.4 84.08,10.4 85.98,8.5 108.29,8.5 110.63,10.84 112.27,10.84 112.93,11.5 113.6,11.5 114.06,11.03 121.1,11.03 121.54,10.59 121.91,10.59 122.18,10.32 129.44,10.32 129.92,9.84 131.36,9.84 132.04,10.52 132.04,11.22 131.88,11.38 v4(131.88,11.63)
  IN4 w0.066: v1(131.53,11.63) v4(131.88,11.63)
  BOTTOM w0.097: v3(29.91,33.34) 29.91,33.45 29.38,33.98 29.38,34.5 29.58,34.71 29.58,35.04 29.16,35.45 27.77,35.45 25.86,37.36 v12(25.63,37.36) 25.35,37.36 24.93,37.78 24.93,38.3 CS3.1
SATA_RP1_C: length 10.9
  BOTTOM w0.097: JNGFF3.33 25.25,49.28 25.39,49.14 v12(25.39,48.66) 25.39,40.71 24.99,40.31 24.99,40.02 CS3.2
SATA_TN1: length 138.1
  IN4 w0.066: v11(31.19,33.53) 31.19,33.4 31.23,33.37 46.59,33.37 48.07,31.88 48.07,30.12 47.78,29.83 47.78,15.47 55.47,7.77 59.84,7.77 60.93,8.87 69.57,8.87 71.89,11.19 76.95,11.19 78.08,12.33 84.79,12.33 86.78,10.34 86.85,10.34 87.01,10.18 87.94,10.18 88.1,10.34 89.53,10.34 89.55,10.32 95.91,10.32 96.02,10.43 101.92,10.43 102.17,10.18 104.09,10.18 104.24,10.33 107.43,10.33 107.53,10.43 109.15,10.43 110.88,8.7 120.15,8.7 121.28,7.57 121.92,7.57 122.48,7.01 123.03,7.01 123.76,6.27 126.99,6.27 127.63,6.91 127.63,8.04 127.92,8.33 129.56,8.33 130.39,9.15 130.68,9.15 131.85,10.32 131.85,10.66 131.74,10.77 131.58,10.77 131.53,10.72 v1(131.53,10.63)
  BOTTOM w0.097: v11(31.19,33.53) 31.18,33.53 30.9,33.81 30.9,34.18 30.67,34.4 30.67,35.96 30.32,36.32 29.86,36.32 29.83,36.34 28.07,36.34 27.08,37.34 27.08,38.52 26.92,38.67 CS7.1
SATA_TN1_C: length 11.2
  BOTTOM w0.097: JNGFF3.39 26.75,49.2 26.9,49.05 26.9,48.9 26.88,48.87 26.88,48.22 26.9,48.2 26.9,47.76 26.34,47.2 26.34,41.43 26.88,40.89 26.88,39.97 CS7.2
SATA_TP1: length 138.1
  IN4 w0.066: v1(131.96,10.88) 131.95,10.87 131.95,10.77 131.98,10.73 131.98,10.27 130.73,9.02 130.44,9.02 129.62,8.19 127.98,8.19 127.77,7.98 127.77,6.86 127.05,6.14 123.71,6.14 122.97,6.87 122.43,6.87 121.86,7.44 121.23,7.44 120.1,8.57 110.83,8.57 109.1,10.3 107.58,10.3 107.48,10.2 104.3,10.2 104.15,10.04 102.11,10.04 101.86,10.29 96.07,10.29 95.96,10.18 89.49,10.18 89.47,10.2 88.15,10.2 88,10.04 86.95,10.04 86.8,10.2 86.73,10.2 84.73,12.19 78.14,12.19 77,11.06 71.95,11.06 69.62,8.74 60.99,8.74 59.89,7.64 55.42,7.64 47.64,15.41 47.64,29.88 47.93,30.17 47.93,31.83 46.53,33.23 31.05,33.23 30.87,33.4 30.87,33.63 v1(31.18,33.94)
  BOTTOM w0.097: v1(31.18,33.94) 31.1,34.02 31.1,34.26 30.87,34.49 30.87,36.05 30.38,36.54 v12(30.12,36.54) 28.15,36.54 27.28,37.42 27.28,38.44 CS8.1
SATA_TP1_C: length 11.2
  BOTTOM w0.097: JNGFF3.41 27.25,49.2 27.1,49.05 v12(27.1,48.6) 27.1,47.68 26.54,47.11 26.54,41.51 27.07,40.97 27.07,40.03 CS8.2
SATAMPHY_PWREN: length 38.2
  IN1 w0.076: v4(129.71,15.62) 129.69,15.62 129.69,15.61 129.11,15.61 128.92,15.8 126.68,15.8 126.58,15.7 125.81,15.7 125.67,15.84 122.12,15.84 121.32,15.04 118.06,15.04 118.06,15.04 117.33,15.04 116.17,16.2 115.47,16.2 115.11,15.83 112.29,15.83 111.91,16.21 110.49,16.21 108.88,14.6 105.88,14.6 105.51,14.23 97.71,14.23 v4(97.38,13.9)
  IN4 w0.076: v4(129.71,15.62) 129.68,15.62 129.63,15.57 v1(129.38,15.57) ; v1(97.56,13.62) 97.56,13.72 v4(97.38,13.9)
  BOTTOM w0.076: T22.1 RH169.1 95.92,14.5 R178.1 97.55,13.61 v1(97.56,13.62)
SATAMPHY_PWREN_R: length 9.7
  IN4 w0.076: v1(92.29,14.06) 92.34,14.06 92.77,14.49 94.58,14.49 94.87,14.2 95.68,14.2 96,14.52 v1(96.81,14.52)
  BOTTOM w0.076: Q17.2 91.89,16.49 R181.1 92.29,16.1 R175.2 v1(92.29,14.06) ; v2(97.71,14.05) 97.71,14.22 97.41,14.52 v1(96.81,14.52)
SDIO_D0: length 12.5
  TOP w0.076: v5(131.48,10.76) 130.93,10.76 130.67,11.03 v2(129.17,11.03) 125.48,11.03 v5(125.36,10.91)
  IN1 w0.076: v4(131.39,11.17) 131.39,11.17 131.46,11.1 131.46,10.79 v5(131.48,10.76) ; v5(125.36,10.91) v4(122.49,10.91)
  IN4 w0.076: v1(122.21,10.56) 122.21,10.62 v4(122.49,10.91) ; v1(131.1,11.38) 131.18,11.38 v4(131.39,11.17)
  BOTTOM w0.076: v1(122.21,10.56) 121.71,10.06 121.26,10.06 RH113.1
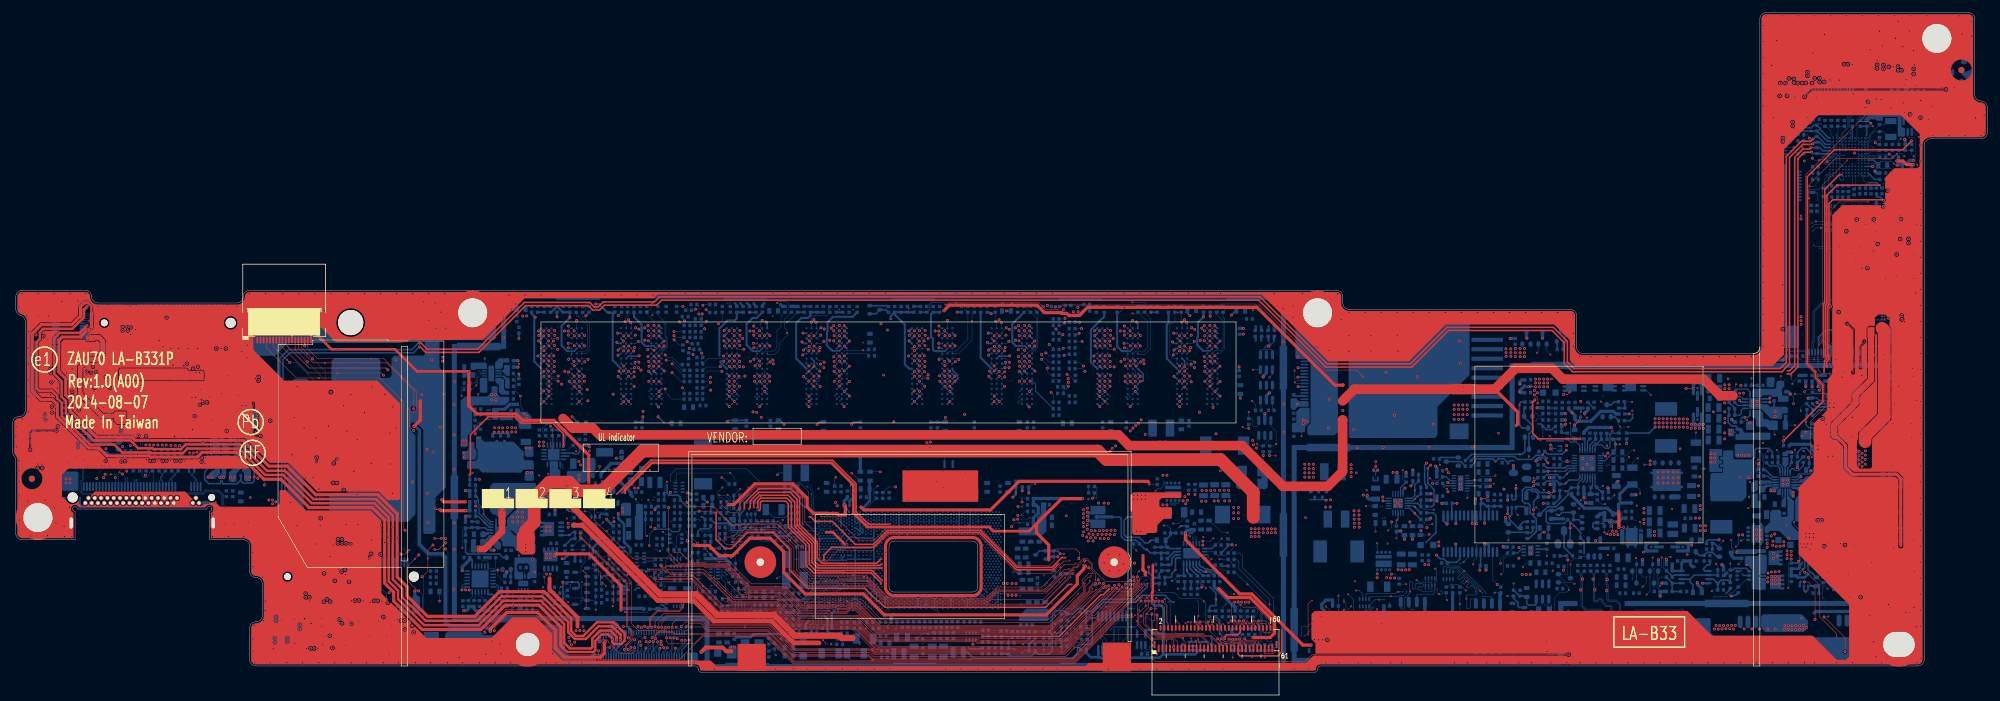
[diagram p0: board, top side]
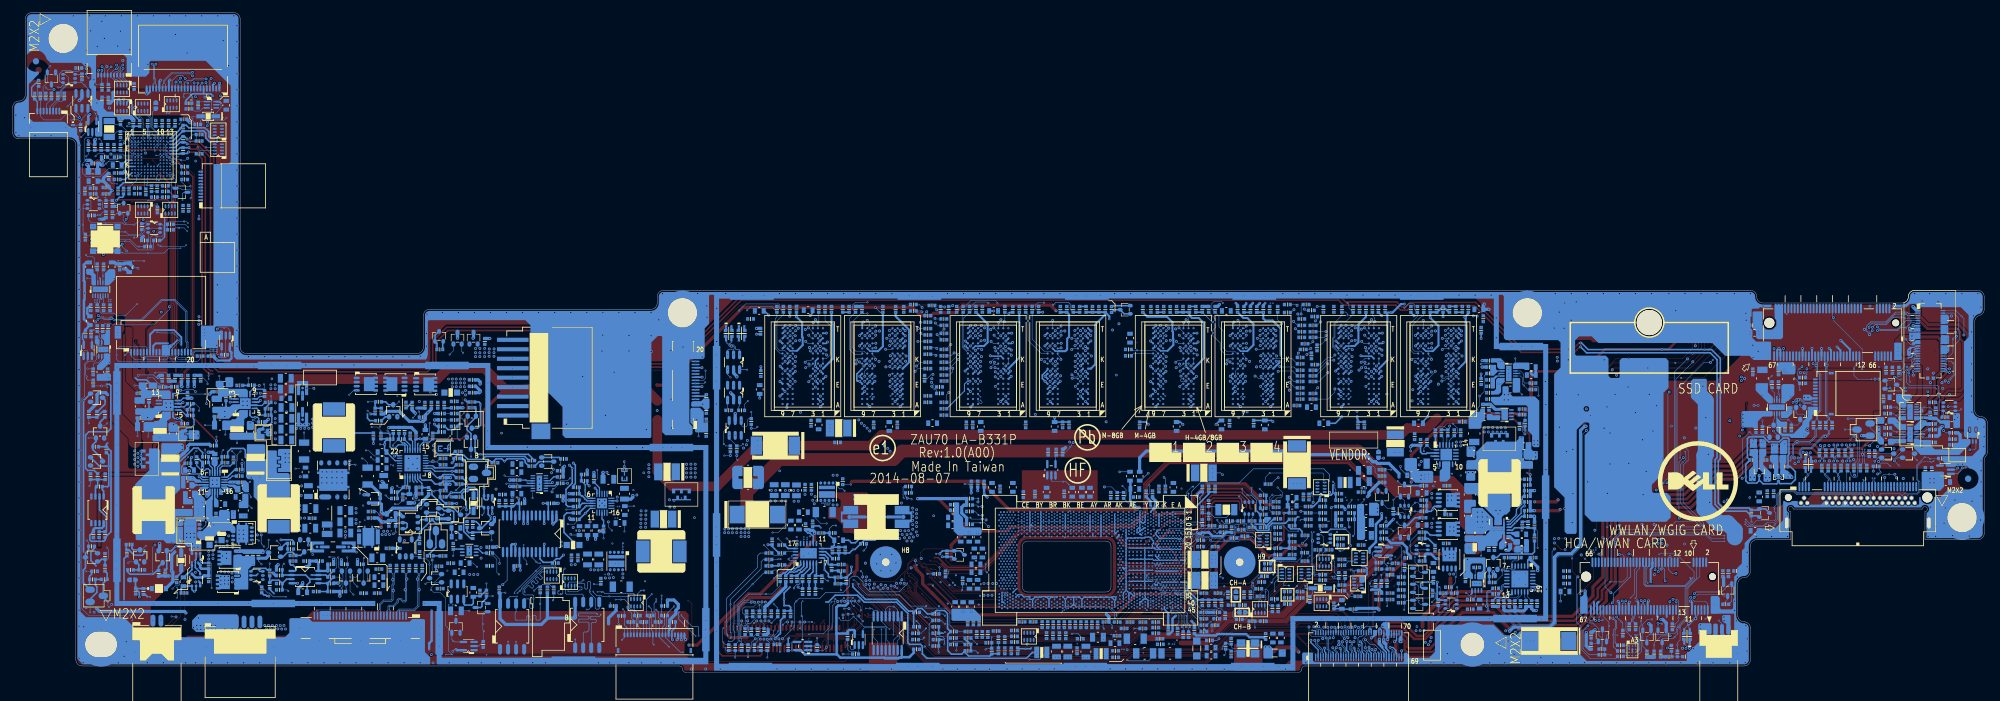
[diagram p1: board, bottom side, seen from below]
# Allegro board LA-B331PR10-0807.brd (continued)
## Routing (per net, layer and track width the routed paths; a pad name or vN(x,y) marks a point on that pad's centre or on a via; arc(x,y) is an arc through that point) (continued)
SENSOR_EN: length 254.5
  IN3 w0.076: v4(131.89,19.4) 131.89,19.13 133.23,17.79 133.28,17.79 133.85,17.22 133.85,15.38 134.33,14.9 134.33,13.3 134.33,13.17 134.33,13.05 134.33,12.9 136.14,11.08 137.36,11.08 138.52,9.92 140.3,9.92 140.52,9.7 152.67,9.7 152.67,9.69 152.92,9.69 153.3,10.08 161.49,10.08 164.24,7.33 164.24,5.16 165.69,3.7 166.61,3.7 166.82,3.5 197.37,3.5 198.09,4.22 202.05,4.22 202.33,3.94 205.6,3.94 205.85,4.2 230.99,4.2 234.01,7.22 246.71,7.22 248.73,5.2 260.74,5.2 261.81,4.13 285.67,4.13 292.93,11.39 293.5,11.39 298.12,16.01 298.12,17.89 297.95,18.06 297.95,18.75 298.55,19.35 298.55,19.64 v4(298.51,19.68)
  IN4 w0.076: v1(298.11,58.21) 297.67,58.64 297.67,63.44 296.1,65.01 296,65.01 v1(295.84,65.17) ; v4(298.51,19.68) 298.54,19.72 298.54,34.41 299.05,34.92 299.05,47.95 296.05,50.96 294.52,50.96 293.36,52.13 293.36,53.18 292.98,53.56 292.98,55.74 292.61,56.11 292.61,58.03 292.48,58.16 292.48,64.37 293.09,64.98 293.14,64.98 v1(293.32,65.16) ; v4(131.89,19.4) 131.74,19.24 131.74,19.02 131.51,18.79 131.28,18.79 131.21,18.86 131.09,18.86 131.02,18.79 130.78,18.79 130.71,18.86 130.55,18.86 130.29,18.6 v1(130.13,18.6)
  BOTTOM w0.076: v1(298.11,58.21) 298.11,59.16 298.21,59.27 U27.5 ; v2(291.69,65.16) v1(293.32,65.16) 293.41,65.24 295.77,65.24 v1(295.84,65.17)
SENSOR_HUB_I2C_WAKE: length 276.4
  TOP w0.076: v5(126.48,14.86) 129.09,14.86 129.35,14.61 135.2,14.61 138.56,11.25 154.22,11.25 155.77,12.81 163.6,12.81 166.44,15.65 167.07,15.65 167.96,16.54 168.35,16.54 168.48,16.54 168.73,16.8 168.73,16.93 169.47,17.67 v3(169.64,17.67) 170.14,17.67 170.7,17.11 170.7,16.27 171.33,15.64 v5(171.33,14.57)
  IN1 w0.076: v4(170.24,14.01) 170.34,14.11 170.95,14.11 171.07,14.23 171.07,14.23 171.27,14.43 171.28,14.43 171.33,14.48 v5(171.33,14.57) ; v5(126.48,14.86) 126.48,15 v4(126.71,15.23)
  IN3 w0.076: v4(170.24,14.01) 170.24,13.15 175.14,8.26 181.73,8.26 181.77,8.22 184.85,8.22 185.5,8.87 186.45,8.87 186.6,8.72 192.23,8.72 192.62,9.11 199.6,9.11 199.76,8.96 209.76,8.96 210.23,8.49 226.24,8.49 229.53,11.78 247.31,11.78 250.46,8.63 267.66,8.63 268.8,9.76 272.25,9.76 272.69,9.33 281.96,9.33 283.25,10.61 285.33,10.61 287.77,13.05 289.22,13.05 289.61,13.44 290.32,13.44 291.75,14.86 292.58,14.86 294.02,16.29 294.02,17.19 298.59,21.76 298.59,45.94 297.78,46.75 297.17,46.75 296.09,47.83 295.26,47.83 294.65,48.45 294.65,51.16 293.5,52.32 293.5,53.08 286.12,60.46 286.12,76.85 285.45,77.52 285.45,78.69 286.01,79.25 286.01,82.2 286.38,82.57 286.38,91.56 284.77,93.17 v3(284.77,93.35)
  IN4 w0.076: v1(127.88,15.57) 127.88,15.46 127.47,15.05 126.89,15.05 v4(126.71,15.23)
  BOTTOM w0.076: JSNR1.11 284.78,93.31 284.77,93.32 v3(284.77,93.35) ; v3(169.64,17.67) 169.64,17.22 v2(169.42,17)
SENSOR_I2C_SCL: length 147
  IN3 w0.076: v3(198.92,34.33) 197.36,36.37 197.37,36.48 197.43,36.52 197.86,36.95 228.98,36.95 240.07,48.04 277.36,48.04 278.09,48.77 278.09,92.22 280.68,94.81 283.7,94.81 v3(284.03,94.48)
  BOTTOM w0.076: JSNR1.18 288.28,93.12 288.45,93.29 288.45,93.69 287.26,94.89 284.44,94.89 v3(284.03,94.48) ; v2(199.86,34.33) v3(198.92,34.33) R54.1
SENSOR_I2C_SDA: length 147.2
  IN3 w0.076: v3(284.03,95.04) 283.96,94.96 280.62,94.96 277.94,92.28 277.94,48.84 277.29,48.19 240.01,48.19 228.92,37.1 197.8,37.1 197.33,36.64 197.28,36.6 197.18,36.61 v3(195.62,38.65)
  BOTTOM w0.076: v2(194.65,38.88) 194.88,38.65 v3(195.62,38.65) R55.1 ; JSNR1.19 288.78,93.12 288.61,93.29 288.61,93.76 287.32,95.04 v3(284.03,95.04)
SENSOR_INT#: length 341
  TOP w0.076: v5(169.68,14.1) 169.68,12.74 169.25,12.31 169.25,12.31 164.2,7.26 137.28,7.26 133.66,10.87 132.2,10.87 131.85,10.52 130.88,10.52 130.64,10.76 125.85,10.76 125.75,10.67 125.03,10.67 122.21,13.48 116.69,13.48 113.1,17.07 109.69,17.07 109.57,17.19 105.59,17.19 103.77,19 103.77,26.03 v3(103.82,26.08)
  IN1 w0.076: v4(170.06,14.47) 170.05,14.47 v5(169.68,14.1)
  IN2 w0.076: v4(130.59,20.24) 130.51,20.16 129.22,20.16 129.11,20.27 127.21,20.27 126.82,20.67 123.99,20.67 120.63,24.02 118.51,24.02 117.78,23.3 115.82,23.3 115.77,23.25 106.65,23.25 v3(103.82,26.08)
  IN3 w0.076: v3(285.19,94.07) 284.85,94.07 284.41,93.64 284.41,92.73 286.23,90.91 286.23,82.63 285.86,82.26 285.86,79.31 285.24,78.69 285.24,60.23 286.26,59.21 286.26,58.86 292.46,52.66 292.94,52.66 294.5,51.1 294.5,48.38 295.2,47.68 296.02,47.68 297.11,46.6 297.72,46.6 298.43,45.88 298.43,21.82 293.86,17.25 293.86,16.36 292.52,15.02 291.68,15.02 290.26,13.59 289.55,13.59 289.15,13.2 287.64,13.2 285.2,10.76 283.18,10.76 281.91,9.49 272.78,9.49 272.36,9.91 268.74,9.91 267.6,8.78 250.56,8.78 247.41,11.93 229.46,11.93 226.18,8.64 210.29,8.64 209.82,9.11 199.82,9.11 199.64,9.29 192.59,9.29 192.17,8.87 188.14,8.87 187.9,9.11 184.3,9.11 184.15,9.26 182.5,9.26 181.64,8.41 179.19,8.41 178.66,8.93 v3(178.57,8.93) 178.02,8.93 177.49,8.41 175.2,8.41 170.57,13.04 170.57,14.27 170.37,14.47 v4(170.06,14.47)
  IN4 w0.076: v1(130.38,19.9) 130.59,20.11 v4(130.59,20.24)
  BOTTOM w0.076: v3(178.57,8.93) 178.57,8.73 v2(177.94,8.09) ; JSNR1.16 287.28,93.71 286.45,94.54 285.66,94.54 v3(285.19,94.07) ; v3(103.82,26.08) 103.64,26.26 RH109.1
SENSOR_RST#: length 276
  IN3 w0.076: v3(285.95,93.49) 287.07,92.37 287.07,89.95 286.86,89.73 286.86,82.57 286.32,82.03 286.32,79.34 286.47,79.19 286.47,70.9 286.87,70.5 290.84,70.5 291.22,70.12 291.22,56.51 294.43,53.29 294.43,53.18 298.09,49.52 298.09,49 299.54,47.56 299.54,21.16 297.79,19.42 297.79,18 297.97,17.82 297.97,16.07 293.44,11.55 292.87,11.55 285.61,4.28 261.87,4.28 260.8,5.36 248.78,5.36 246.77,7.37 233.94,7.37 230.96,4.39 206.09,4.39 205.79,4.69 202.66,4.69 202.35,4.38 198.03,4.38 197.35,3.7 166.83,3.7 166.37,4.16 165.45,4.16 164.39,5.22 164.39,7.39 161.55,10.23 153.24,10.23 152.85,9.85 140.59,9.85 140.36,10.08 138.58,10.08 137.42,11.23 136.21,11.23 134.48,12.96 134.48,14.98 134.01,15.45 134.01,17.28 133.35,17.94 133.29,17.94 132.74,18.49 132.74,19.98 132.64,20.08 v4(132.64,20.12)
  IN4 w0.076: v1(130.13,20.33) 130.13,19.81 130.28,19.66 130.48,19.66 130.51,19.68 130.76,19.68 130.78,19.66 130.98,19.66 131.04,19.71 132.2,19.71 132.57,20.08 132.6,20.08 v4(132.64,20.12)
  BOTTOM w0.076: JSNR1.13 285.78,93.32 v3(285.95,93.49)
SIO_EXT_SCI#: length 323.9
  IN1 w0.076: v4(293.2,69.31) 298.02,69.31 v3(298.7,68.62) ; v4(115.91,15.17) 115.66,14.91 111.91,14.91 111.53,15.3 110.87,15.3 109.26,13.68 106.26,13.68 105.7,13.12 100.2,13.12 99.44,12.36 97.75,12.36 v4(97.7,12.41)
  IN2 w0.076: v4(293.2,69.31) 293.72,69.83 293.72,84.26 292.21,85.77 v4(292.14,85.77)
  IN3 w0.076: v3(298.7,68.62) 301.29,66.03 301.29,13.15 290.45,2.3 259.21,2.3 259.15,2.36 206.61,2.36 206.32,2.08 202.97,2.08 202.51,1.62 165.19,1.62 161.56,5.25 151.81,5.25 151.14,4.58 151.14,2.57 150.53,1.96 124.23,1.96 117.73,8.46 117.73,13.48 116.21,15 116.08,15 v4(115.91,15.17) 115.91,15.64 115.85,15.7 115.85,17.84 117.93,19.92 122.22,19.92 124.34,22.04 v4(124.62,22.04)
  IN4 w0.076: v1(124.06,21.73) 124.18,21.73 124.49,22.04 v4(124.62,22.04) ; v7(291.98,84.12) 291.87,84.23 291.87,85.05 291.82,85.1 291.82,85.45 v4(292.14,85.77) ; v1(96.76,12.54) 96.86,12.44 97.46,12.44 97.48,12.41 v4(97.7,12.41)
  GND3 w0.076: v7(291.98,84.12) 292.11,83.99 v8(292.11,83.63)
  BOTTOM w0.076: UCPU1.B17 127.6,20.77 126.42,21.95 125.33,21.95 125.02,21.65 124.32,21.65 124.27,21.7 124.09,21.7 v1(124.06,21.73)
SIO_EXT_SMI#: length 291.4
  TOP w0.076: v5(127.91,24.7) 130.12,24.7 133.89,20.93 136.33,20.93 138.09,22.69 139.16,22.69 139.17,22.69 153.24,22.69 159.07,16.86 163.97,16.86 164.81,17.7 164.81,19.25 165.1,19.54 168.26,19.54 168.84,18.95 168.84,18.17 168.72,18.04 v3(168.72,18.02)
  IN1 w0.076: v5(127.91,24.7) 127.91,24.75 127.56,25.1 126.82,25.1 v4(126.7,25.22) ; v4(294.75,53.31) 295.03,53.03 295.03,49.57 294.59,49.13 294.59,44.51 295.02,44.07 295.02,42.85 v4(294.79,42.62)
  IN2 w0.076: v4(294.79,42.62) 295.8,41.61 295.8,21.75 295.69,21.65 295.69,19.41 295.62,19.33 295.62,19.33 295.25,18.96 294.74,18.45 294.74,16.38 294.25,15.89 294.25,13.1 289.36,8.21 286.24,8.21 285.04,9.42 272.37,9.42 272.31,9.48 269.45,9.48 267.62,7.65 261.14,7.65 260.09,8.7 246.71,8.7 246.28,9.12 226.01,9.12 224.99,10.14 214.18,10.14 211.63,12.69 202.55,12.69 202.33,12.91 200.97,12.91 200.54,12.47 191.81,12.47 191.19,11.85 171.17,11.85 168.97,14.05 168.97,15.96 169.19,16.17 169.19,17.18 168.72,17.65 v3(168.72,18.02)
  IN3 w0.076: v4(126.7,25.22) 126.7,24.61 122.16,20.07 117.87,20.07 115.33,17.53 115.33,14.81 115.5,14.63 v4(115.5,12.57) ; v4(294.75,53.31) 295.11,53.66 295.11,54.21 291.53,57.79 291.53,67.18 293.52,69.17 293.52,74.11 292.91,74.72 292.91,74.96 292.49,75.38 291.64,75.38 v4(291.63,75.39)
  IN4 w0.076: v4(291.63,75.39) 291.61,75.39 291.41,75.59 v1(291.41,75.66) ; v1(113.34,11.68) 113.43,11.59 114.44,11.59 114.53,11.68 114.73,11.68 115.5,12.46 v4(115.5,12.57) 116.55,12.57 116.83,12.84 119.83,12.84 120.6,13.62 v1(120.75,13.62) 121.42,14.29 123.25,14.29 124.05,13.49 127.56,13.49 127.9,13.83 128.37,13.83 v1(128.38,13.84)
SIO_EXT_SMI#_R: length 2.2
  BOTTOM w0.076: U38.N5 291.68,78.56 291.68,76.84 R357.2
SIO_EXT_WAKE#: length 329.7
  TOP w0.076: v5(291.25,47.46) 291.36,47.58 291.36,54.34 290.46,55.24 v5(290.29,55.24) ; v3(177.46,14.5) 177.46,14.47 177.8,14.13 177.8,13.67 177.61,13.48 176.75,12.63 176.23,12.63 170.5,6.9 169.66,6.9 166.19,3.43 136.69,3.43 133.18,6.94 123.75,6.94 120.81,9.88 112.1,9.88 107.68,14.31 101.94,14.31 101.04,15.21 v5(101.03,15.21)
  IN1 w0.076: v4(100.57,15.52) 100.58,15.51 100.72,15.51 v5(101.03,15.21) ; v4(291.8,47.37) 291.71,47.46 v5(291.25,47.46) ; v5(290.29,55.24) 290.23,55.3 290.23,55.76 v4(290.24,55.77)
  IN3 w0.076: v4(126.65,17.46) 126.66,17.47 126.66,17.86 127.29,18.5 127.29,19.31 127.65,19.66 127.65,20.35 127.58,20.42 127.58,20.59 127.58,20.59 v4(127.58,20.61) ; v4(291.8,47.37) 291.8,47.16 293.28,45.69 294.06,45.69 295.87,43.87 295.87,22.13 291.14,17.4 290.2,17.4 287.97,15.18 287.33,15.18 284.34,15.18 284.06,14.9 283.09,14.9 282.06,13.87 282.06,13.53 280.82,12.29 274.09,12.29 272.24,14.14 268.92,14.14 267.67,12.89 250.88,12.89 248.18,15.59 247.08,15.59 245.7,16.96 238.02,16.96 237.22,16.16 234.67,16.16 233.98,16.85 231.87,16.85 231.24,16.22 227.58,16.22 225.82,14.46 225.82,13.71 223.83,11.72 214.6,11.72 213.88,12.45 203.42,12.45 203.35,12.39 202.42,12.39 202,12.81 201.99,12.81 201.92,12.87 201.36,12.87 201.24,12.76 201.17,12.76 201.14,12.73 200.52,12.73 200.02,13.23 200.02,13.28 199.63,13.67 v4(199.63,13.81) ; v4(100.57,15.52) 100.57,15.97 96,20.54 96,23.17 95.31,23.86 v3(95.15,23.86)
  IN4 w0.076: v1(290.61,79.63) 290.61,79.62 290.87,79.36 290.87,78.93 291.01,78.79 291.01,78.39 290.74,78.12 290.74,76.69 289.85,75.8 289.85,74.3 289.86,74.29 289.86,74.09 289.81,74.03 289.81,72.78 289.49,72.46 289.49,68.72 289.71,68.5 289.71,67.37 288.97,66.64 288.97,58.64 290.17,57.44 290.17,55.85 v4(290.24,55.77) ; v4(126.65,17.46) 126.66,17.44 126.83,17.44 126.94,17.34 127.13,17.34 127.17,17.3 127.48,17.3 127.67,17.49 128.73,17.49 128.88,17.34 v1(128.88,17.3) ; v4(100.57,15.52) 100.62,15.47 102.68,15.47 102.89,15.69 102.89,15.88 103.13,16.11 107.34,16.11 108.02,16.79 111.06,16.79 112.13,17.87 113.51,17.87 114.01,18.37 115.52,18.37 117.26,20.11 117.51,20.11 118.02,20.11 120.66,20.11 120.85,20.3 124.63,20.3 125.26,20.93 127.2,20.93 127.51,20.63 127.56,20.63 v4(127.58,20.61) ; v3(177.46,14.5) 177.57,14.39 177.77,14.39 179.22,12.95 179.39,12.95 179.52,12.82 181.2,12.82 181.56,12.47 187.09,12.47 187.44,12.11 197.6,12.11 199.02,13.53 199.38,13.53 199.63,13.78 v4(199.63,13.81)
  BOTTOM w0.076: v2(95.15,24.49) v3(95.15,23.86) 95.22,23.86 95.87,23.21 RH110.2
SIO_PWRBTN#: length 367.6
  TOP w0.076: JAPS1.8 42.21,51.97 46.77,47.41 v2(51.38,47.41) 58.33,47.41 v3(58.68,47.06) ; v5(167.4,15.05) 167.36,15.05 162.95,10.65 138.28,10.65 135.38,13.54 125.93,13.54 123.2,16.27 123.2,19.56 120.39,22.37 116.15,22.37 114.87,21.09 114.87,21.06 114.1,20.29 112.94,20.29 v5(111.69,21.53)
  IN1 w0.076: v5(167.4,15.05) 167.42,15.03 168.45,15.03 169.3,15.87 169.3,15.92 v4(169.5,16.13) ; v4(112.21,21.63) 112.12,21.54 111.71,21.54 v5(111.69,21.53)
  IN2 w0.076: v4(112.21,21.63) 112.13,21.71 111.34,21.71 110.75,21.13 109.52,21.13 108.83,21.81 104.6,21.81 103.62,22.79 103.62,24.58 100.37,27.83 98.64,27.83 94.9,31.57 94.33,31.57 89.18,36.72 89.18,37.29 88.56,37.91 88.38,37.91 84.49,41.8 63.94,41.8 v3(58.68,47.06)
  IN3 w0.076: v4(169.5,16.13) 169.57,16.07 169.57,15.36 169.3,15.09 169.3,13.17 169.3,12.85 174.82,7.33 190.56,7.33 v4(190.69,7.46) 190.84,7.61 197.6,7.61 198.19,8.2 209.44,8.2 209.98,7.66 226.49,7.66 229.84,11.02 246.99,11.02 250.19,7.82 267.93,7.82 269.12,9 271.94,9 272.37,8.56 282.28,8.56 282.84,9.12 284.92,9.12 288.08,12.29 290.25,12.29 291.87,13.9 292.78,13.9 293.33,14.46 293.33,15.39 294.33,16.4 v4(294.33,16.81)
  IN4 w0.076: v4(190.69,7.46) 191.37,6.77 v1(191.37,6.53) ; v4(294.33,16.81) 294.58,16.81 294.98,17.21 295.41,17.64 295.41,22.55 295.66,22.8 295.66,42.64 294.97,43.32 294.97,44.41 294.46,44.91 294.46,45.82 294.23,46.05 294.23,46.96 293.89,47.3 292.26,47.3 291.97,47.01 291.3,47.01 291.23,47.08 291.23,47.59 289.14,49.68 289.14,49.93 289.14,49.93 289.14,53.16 285.48,56.82 285.48,71.39 285.29,71.57 285.29,73.15 285.06,73.38 285.06,75.17 286.21,76.31 286.21,77.47 286.9,78.16 286.9,78.64 v1(286.99,78.73) ; v1(111.85,21.94) 111.92,21.86 111.98,21.86 v4(112.21,21.63)
  BOTTOM w0.076: v1(286.99,78.73) 286.99,78.73 287.39,79.13 U38.M13 ; v1(191.37,6.53) 191.37,6.39 192.19,5.58 192.19,4.97 192.01,4.79 RH163.1
SIO_RCIN#: length 285.3
  TOP w0.076: v5(171.46,13.1) 171.12,12.76 170.92,12.76 164.59,6.43 136.98,6.43 133.29,10.11 132.57,10.11 131.98,9.52 129.42,9.52 v2(129.21,9.73) 129.11,9.83 124.5,9.83 121.65,12.68 115.98,12.68 v5(115.93,12.63)
  IN1 w0.076: v4(116.04,12.25) 115.93,12.36 v5(115.93,12.63) ; v4(171.75,13.43) 171.75,13.39 v5(171.46,13.1)
  IN3 w0.076: v4(285.61,82.52) 285.71,82.42 285.71,79.38 285.06,78.73 285.06,59.8 292.35,52.51 292.86,52.51 294.34,51.02 294.34,48.32 295.14,47.53 295.96,47.53 297.05,46.44 297.65,46.44 298.28,45.82 298.28,21.89 290.14,13.75 289.48,13.75 289.09,13.35 287.58,13.35 285.14,10.91 283.11,10.91 281.86,9.67 272.9,9.67 272.5,10.07 268.67,10.07 267.54,8.93 250.73,8.93 247.44,12.22 232.73,12.22 232.31,12.64 228.85,12.64 225.31,9.1 210.48,9.1 209.97,9.61 199.97,9.61 199.83,9.75 192.4,9.75 191.98,9.33 188.33,9.33 188.05,9.61 184.45,9.61 184.31,9.75 182.56,9.75 181.75,10.56 173.77,10.56 171.75,12.58 v4(171.75,13.43)
  IN4 w0.076: v1(115.56,12.03) 115.77,12.25 v4(116.04,12.25) 116.2,12.41 116.61,12.41 116.89,12.69 119.89,12.69 120.58,13.38 120.91,13.38 121.67,14.14 123.19,14.14 123.99,13.34 124.57,13.34 125.09,12.82 125.83,12.82 126.2,13.19 127.69,13.19 127.91,13.41 v1(128.13,13.41) ; v4(285.61,82.52) 286.12,83.03 287.87,83.03 288.03,82.87 288.36,82.87 v1(288.61,83.13)
SIO_SLP_M#: length 393.3
  TOP w0.076: JAPS1.13 v2(44.71,51.1) v3(46.62,49.19) ; v3(176.29,13.35) 171.46,8.53 170.64,8.53 166,3.89 136.94,3.89 133.44,7.4 123.94,7.4 120.84,10.49 112.36,10.49 107.71,15.14 103.93,15.14 103.84,15.23 v5(103.75,15.23) ; v5(293.03,52.43) 293.03,52.21 292.42,51.61 v5(292.42,48.28)
  IN1 w0.076: v5(292.42,48.28) 292.42,47.91 v4(292.56,47.77) ; v4(293.01,53.05) 293.01,52.98 293.03,52.96 v5(293.03,52.43) ; v5(103.75,15.23) 103.75,15.46 103.66,15.55 v4(103.66,15.57)
  IN3 w0.076: v3(176.29,13.35) 176.34,13.35 176.54,13.15 183.34,13.15 184.46,12.03 184.79,12.03 185.18,11.64 187.29,11.64 188.27,11.64 188.78,11.64 189.14,11.28 191.17,11.28 192.29,12.4 192.71,12.4 199.78,12.4 200.57,11.6 203.65,11.6 203.73,11.69 213.5,11.69 214.23,10.96 224.15,10.96 226.59,13.41 226.59,14.15 227.9,15.46 232.4,15.46 232.96,14.9 236.94,14.9 237.44,14.4 247.93,14.4 250.98,11.36 267.21,11.36 268.7,12.85 272.45,12.85 273.77,11.52 281.14,11.52 282.37,12.76 283.17,12.76 284.09,13.68 285.04,13.68 285.04,13.68 285.21,13.68 285.38,13.85 286.13,13.85 287.01,14.72 287.14,14.72 288.16,14.72 290.39,16.95 291.33,16.95 296.34,21.95 296.34,44.12 292.69,47.77 v4(292.56,47.77)
  IN4 w0.076: v1(129.13,20.33) 129.11,20.31 128.95,20.31 128.73,20.09 128.53,20.09 128.48,20.14 127.38,20.14 127.23,20.3 126.91,20.3 126.83,20.38 125.38,20.38 124.84,19.84 121.04,19.84 120.85,19.65 117.83,19.65 117.45,19.65 115.71,17.92 114.23,17.92 113.57,17.26 112.49,17.26 111.03,15.8 109.56,15.8 109.17,16.2 107.86,16.2 107.46,15.8 103.95,15.8 103.71,15.57 v4(103.66,15.57) 103.32,15.22 v1(103.32,15.16) 102.8,15.16 102.69,15.05 99.07,15.05 98.31,15.82 98.31,15.82 97.9,16.23 89.04,16.23 88.83,16.44 88.58,16.44 88.58,16.44 83.21,16.44 82.57,17.07 54.25,17.07 53.18,18.15 52.93,18.15 50.33,18.15 50.12,18.37 50.12,20.67 50.46,21.01 50.46,29.76 v3(50.71,30.02) ; v4(293.01,53.05) 292.82,53.24 292.82,55.68 292.33,56.17 292.33,65.92 294,67.59 294,72.79 294.36,73.15 294.36,75.28 294.22,75.42 294.22,77.73 293.61,78.33 v1(293.61,78.63)
  BOTTOM w0.076: v3(50.71,30.02) 49.29,31.44 49.29,46.45 46.62,49.12 v3(46.62,49.19)
SIO_SLP_S0#: length 372.7
  TOP w0.076: JAPS1.4 40.21,51.32 44.91,46.62 v2(48.45,46.62) 58.11,46.62 61.86,42.87 61.86,22.66 62.02,22.5 v3(62.11,22.5) ; v5(108.34,13.3) 108.34,13.05 111.66,9.73 120.74,9.73 123.68,6.79 132.97,6.79 136.48,3.28 166.25,3.28 169.72,6.75 170.57,6.75 176.29,12.48 176.82,12.48 178.02,13.67 178.02,14.44 177.86,14.6 177.86,14.61 177.47,15 177.47,15.01 v3(177.37,15.1)
  IN1 w0.076: v5(108.34,13.3) 108.01,12.97 101.83,12.97 100.84,11.98 v4(100.68,11.98)
  IN2 w0.076: v4(100.68,11.98) 100.15,11.45 99.62,11.45 99.33,11.74 98.86,11.74 97.82,12.78 96.86,12.78 96.19,13.45 92.69,13.45 92.55,13.31 86.61,13.31 86.1,13.82 81.24,13.82 78.74,16.32 76.91,16.32 v3(76.78,16.2) 76.31,16.2 75.74,15.63 68.67,15.63 62.09,22.2 62.09,22.47 v3(62.11,22.5)
  IN3 w0.076: v4(285.48,55.21) 287.37,55.21 290.5,52.09 290.5,48.95 291.37,48.07 291.37,47.36 293.23,45.5 294.03,45.5 295.71,43.81 295.71,22.19 291.08,17.56 290.13,17.56 287.91,15.33 287.39,15.33 284.27,15.33 283.99,15.05 283.03,15.05 281.91,13.93 281.91,13.59 280.75,12.44 274.15,12.44 272.3,14.29 268.85,14.29 267.61,13.05 250.94,13.05 248.24,15.74 247.14,15.74 245.77,17.11 237.96,17.11 237.16,16.31 234.73,16.31 234.05,17 231.8,17 231.18,16.37 227.5,16.37 225.67,14.53 225.67,13.78 223.77,11.87 214.67,11.87 213.94,12.6 203.35,12.6 203.29,12.54 202.48,12.54 202,13.02 201.48,13.02 201.43,13.07 201.43,13.05 201.41,13.02 201.29,13.02 201.18,12.91 200.56,12.91 200.36,13.11 200.18,13.29 200.18,13.34 200.09,13.43 200.09,13.8 199.76,14.13 199.43,14.13 199.2,13.9 v4(198.87,13.9)
  IN4 w0.076: v3(177.37,15.1) 177.44,15.1 177.99,14.55 177.99,14.39 179.28,13.1 179.45,13.1 179.58,12.97 181.27,12.97 181.62,12.62 187.15,12.62 187.51,12.26 197.53,12.26 198.68,13.4 198.68,13.71 v4(198.87,13.9) ; v1(101.18,12.31) 101.18,12.31 100.85,11.98 v4(100.68,11.98) ; v4(285.48,55.21) 284.63,56.07 284.63,70.4 v1(284.72,70.5)
  BOTTOM w0.076: v1(101.18,12.31) 101.24,12.37 101.24,12.44 RH71.1 ; PR913.1 77.9,14.24 76.78,15.36 v3(76.78,16.2) ; R328.1 285.2,70.97 v1(284.72,70.5)
SIO_SLP_S0#_R: length 16.4
  IN4 w0.076: v1(284.73,71.13) 284.83,71.23 284.83,72.81 284.32,73.33 284.32,77.45 285.21,78.35 285.21,78.38 286.41,79.57 286.41,79.91 286.98,80.48 287.5,80.48 287.52,80.51 287.91,80.51 288.02,80.63 v1(288.11,80.63)
  BOTTOM w0.076: v1(284.73,71.13) 285.02,71.42 v2(285.37,71.42) 286.72,71.42 286.77,71.37 287.76,71.37 287.99,71.14 R328.2 R329.2
SIO_SLP_S3#: length 366.1
  TOP w0.076: JAPS1.17 46.71,51.21 48.23,49.69 v2(56.75,49.69) 58.72,49.69 63.87,44.54 63.87,41.6 63.49,41.22 v5(63.43,41.22)
  IN1 w0.076: v4(99.78,25.9) 99.24,26.45 95.48,26.45 86.12,35.81 86.12,36.13 83.81,38.43 83.81,39.53 81.27,42.07 75.66,42.07 74.81,41.22 v5(63.43,41.22)
  IN2 w0.076: v4(99.78,25.9) 100.09,25.9 102.99,23 102.99,22.2 105.71,19.49 107.13,19.49 107.18,19.54 108.35,19.54 108.75,19.93 113.98,19.93 115.43,21.38 116.57,21.38 116.63,21.44 120.21,21.44 123.15,18.5 124.45,18.5 124.76,18.18 125.97,18.18 126.01,18.14 126.83,18.14 127.06,18.37 128.55,18.37 128.7,18.22 132.31,18.22 133.03,18.94 v4(133.49,18.94)
  IN3 w0.076: v4(133.49,18.94) 133.41,18.94 133.11,18.64 133.11,18.39 133.17,18.33 133.17,18.28 133.36,18.09 133.41,18.09 134.17,17.33 134.17,15.88 134.16,15.87 134.16,15.51 134.63,15.04 134.63,13.02 136.27,11.38 137.49,11.38 138.64,10.23 140.42,10.23 140.65,10 152.79,10 153.17,10.38 161.63,10.38 164.54,7.47 164.54,5.28 165.51,4.32 166.51,4.32 166.72,4.52 168.13,4.52 v4(168.55,4.09) 168.71,3.93 197.37,3.93 197.97,4.53 202.29,4.53 202.6,4.84 205.86,4.84 206.17,4.54 230.9,4.54 233.88,7.52 246.84,7.52 248.83,5.53 260.87,5.53 261.96,4.44 285.54,4.44 292.8,11.7 293.37,11.7 297.62,15.95 v4(297.62,16.32)
  IN4 w0.076: v1(130.63,18.6) 131.69,18.6 132.02,18.27 132.1,18.27 132.16,18.21 132.76,18.21 v4(133.49,18.94) ; v1(293.11,79.63) 292.85,79.37 292.49,79.37 292.36,79.24 292.36,78.22 292.96,77.63 292.96,77.62 293.13,77.45 293.13,74.34 293.29,74.17 293.29,70.2 292.83,69.74 292.83,69.61 292.73,69.5 292.73,67.95 291.69,66.91 291.69,55.91 292.19,55.41 292.19,52.85 292.19,51.72 292.95,50.96 293.19,50.96 293.38,51.15 294.12,51.15 294.46,50.81 295.98,50.81 298.9,47.89 298.9,34.98 298.39,34.47 298.39,21.67 298.17,21.45 298.17,17.82 298.28,17.71 298.28,16.98 v4(297.62,16.32) ; v1(168.14,4.09) v4(168.55,4.09)
SIO_SLP_S4#: length 377.2
  TOP w0.076: v3(63.46,41.72) 63.51,41.78 63.51,44.68 59.18,49.01 v2(49.39,49.01) 47.56,49.01 45.21,51.36 JAPS1.14
  IN1 w0.076: v4(104.2,23.09) 104.2,24.26 101.92,26.55 99.74,26.55 99.65,26.64 95.6,26.64 86.29,35.95 86.29,36.18 83.96,38.51 83.96,39.59 81.34,42.22 75.6,42.22 75.1,41.72 v3(63.46,41.72)
  IN2 w0.076: v4(104.2,23.09) 105.33,21.96 108.11,21.96 108.77,22.62 116.05,22.62 116.11,22.69 120.89,22.69 123.82,19.75 124.95,19.75 125.28,19.42 125.75,19.42 126.05,19.72 126.83,19.72 127,19.55 129.22,19.55 v4(129.3,19.47) ; v4(293.28,68.32) 292.89,68.71 292.89,69.98 293.51,70.6 293.51,83.99 292.26,85.23 v4(292.14,85.23)
  IN3 w0.076: v4(293.28,68.32) 291.91,66.95 291.91,57.63 299.84,49.69 299.84,15.61 297.63,13.39 297.09,13.39 291.89,8.2 291.89,7.48 287.94,3.52 261.55,3.52 260.53,4.55 244.36,4.55 243.7,5.21 237.84,5.21 237.23,4.59 232.89,4.59 231.58,3.28 206.23,3.28 205.98,3.03 202.4,3.03 201.9,2.53 165.57,2.53 163.02,5.08 163.02,7.03 161.09,8.96 153.93,8.96 153.37,8.4 145.44,8.4 142.66,5.62 139.4,5.62 138.57,6.45 136.91,6.45 136.5,6.86 129.93,6.86 126.75,10.04 126.75,14.44 127.07,14.77 127.27,14.77 128.28,15.78 128.28,16.43 128.47,16.62 128.47,16.85 129.3,17.67 v4(129.3,19.47)
  IN4 w0.076: v4(293.28,68.32) 293.25,68.35 v1(293.25,68.86) ; v1(292.11,84.63) 292.14,84.65 v4(292.14,85.23) ; v4(129.3,19.47) 129.38,19.56 v1(129.38,19.9)
SIO_SLP_S5#: length 119.8
  TOP w0.076: JAPS1.15 45.71,51.4 v2(46.63,50.48) v3(47.46,49.65)
  IN4 w0.076: v1(127.01,20.54) 125.3,20.54 124.75,19.99 120.98,19.99 120.79,19.8 117.89,19.8 117.39,19.8 115.65,18.07 114.17,18.07 113.51,17.41 112.4,17.41 110.97,15.98 109.71,15.98 109.34,16.35 107.79,16.35 107.4,15.96 103.42,15.96 103.21,15.74 v4(103.21,15.74) 103.21,15.74 103.06,15.59 103.01,15.59 102.62,15.21 99.14,15.21 98.46,15.88 98.46,15.88 97.96,16.38 89.16,16.38 88.95,16.59 88.52,16.59 83.27,16.59 82.64,17.23 54.32,17.23 53.24,18.3 52.86,18.3 50.4,18.3 50.27,18.43 50.27,20.61 50.61,20.95 50.61,29.28 v3(51.32,29.99)
  BOTTOM w0.076: UCPU1.A18 127.22,20.33 v1(127.01,20.54) 126.02,21.53 T46.1 ; v3(47.46,49.65) 49.53,47.58 49.53,31.78 v3(51.32,29.99)
SIO_SLP_SUS#: length 264.2
  TOP w0.076: v3(172.92,13.62) 172.66,13.62 165.16,6.12 136.85,6.12 133.95,9.03 124.42,9.03 121.46,11.98 115.46,11.98 113.45,14 v5(113.45,14.29)
  IN1 w0.076: v4(113.98,14.29) v5(113.45,14.29)
  IN3 w0.076: v3(172.92,13.62) 172.92,13.17 174.31,11.79 182.05,11.79 183.16,10.69 184.23,10.69 184.62,10.3 187.84,10.3 187.85,10.3 188.22,10.3 188.59,9.94 191.73,9.94 192.27,10.48 197.14,10.48 197.71,11.05 199.44,11.05 200.28,10.22 210.23,10.22 210.71,9.73 224.85,9.73 228.42,13.3 232.62,13.3 233.09,12.83 247.69,12.83 250.99,9.54 267.16,9.54 268.3,10.68 272.81,10.68 273.16,10.34 281.63,10.34 282.86,11.57 284.93,11.57 287.32,13.96 288.84,13.96 289.23,14.36 289.82,14.36 297.1,21.64 297.1,44.44 296.76,44.78 296.76,45.85 296.38,46.23 295.57,46.23 293.68,48.12 293.68,49.3 293.4,49.57 293.4,50.95 v4(293.07,51.29)
  IN4 w0.076: v1(114.39,14.29) v4(113.98,14.29) ; v4(293.07,51.29) 292.89,51.29 292.34,51.83 292.34,52.92 292.34,55.48 291.85,55.97 291.85,66.76 292.89,67.8 292.89,69.44 293.44,70 293.44,74.24 293.29,74.39 293.29,77.64 292.54,78.39 292.54,78.9 292.61,78.97 v1(292.61,79.13)
  BOTTOM w0.076: v2(172.51,13.31) 172.61,13.31 v3(172.92,13.62)
SIO_SLP_WLAN#: length 333.7
  TOP w0.076: v3(176.13,13.98) 176.13,13.98 175.92,13.77 175.92,13.24 171.36,8.68 170.57,8.68 165.94,4.05 137.01,4.05 133.49,7.56 123.99,7.56 120.91,10.64 112.42,10.64 107.64,15.42 104.11,15.42 103.74,15.79 103.36,15.79 102.95,16.2 100.95,16.2 100.72,15.97 v5(100.19,15.97)
  IN1 w0.076: v4(99.4,15.79) 99.45,15.74 99.96,15.74 v5(100.19,15.97)
  IN3 w0.076: v4(282.64,85.93) 282.64,85.63 282.67,85.59 282.67,79.15 282.37,78.85 282.37,60.66 290.8,52.22 290.8,49.07 292.42,47.45 292.79,47.45 296.18,44.06 296.18,22.96 296.18,22.01 291.27,17.1 290.32,17.1 288.1,14.88 287.21,14.88 287.2,14.88 286.94,14.88 286.07,14 285.31,14 285.15,13.84 284.98,13.84 284.03,13.84 283.1,12.91 282.31,12.91 281.07,11.68 273.84,11.68 272.49,13.02 268.66,13.02 267.15,11.51 251.04,11.51 248,14.55 237.56,14.55 237.06,15.06 233.02,15.06 232.47,15.61 227.83,15.61 226.43,14.2 226.43,13.46 224.08,11.11 214.29,11.11 213.56,11.84 203.67,11.84 203.58,11.75 200.64,11.75 199.84,12.55 192.78,12.55 192.22,12.55 191.11,11.43 189.2,11.43 188.84,11.79 188.21,11.79 188.21,11.79 187.23,11.79 185.24,11.79 184.85,12.18 184.53,12.18 183.4,13.3 176.99,13.3 176.31,13.98 v3(176.13,13.98)
  IN4 w0.076: v1(290.11,84.63) 290,84.74 290,86.66 290.11,86.76 290.11,87.59 288.52,89.18 287.78,89.18 287.46,88.87 285.26,88.87 282.64,86.25 v4(282.64,85.93) ; v4(99.4,15.79) 99.55,15.79 99.6,15.84 100.52,15.84 100.75,16.07 v1(100.75,16.26) 100.76,16.26 107.27,16.26 107.96,16.95 110.99,16.95 112.07,18.02 113.45,18.02 113.95,18.53 115.46,18.53 117.2,20.26 117.58,20.26 118.08,20.26 120.6,20.26 120.79,20.45 124.56,20.45 125.2,21.09 127.26,21.09 127.39,20.96 127.77,20.96 128.13,20.6 128.71,20.6 128.78,20.53 128.98,20.53 129.03,20.58 129.23,20.58 129.47,20.33 v1(129.63,20.33)
SLP_S0#: length 31.6
  IN4 w0.076: v1(129.13,18.6) 129.28,18.6 129.61,18.28 129.61,18.08 129.31,17.78 127.81,17.78 127.61,17.98 126.25,17.98 126,17.72 125.42,17.72 124.7,17 121.18,17 119.22,15.04 116.89,15.04 116.34,15.59 115.99,15.59 115.99,15.59 115.67,15.59 115.21,15.13 114.15,15.13 113.01,13.99 107.74,13.99 107.39,13.63 107.39,13.11 107.2,12.92 103.9,12.92 v1(103.16,13.66)
  BOTTOM w0.076: RH71.2 103.16,13.45 v1(103.16,13.66)
SM_INTRUDER#: length 25.2
  IN1 w0.076: v4(108.19,26.03) 108.37,25.85 112.95,25.85 113.6,25.2 117.16,25.2 117.34,25.02 118.02,25.02 118.27,25.27 118.27,26.88 118.38,26.99 125.99,26.99 127.13,25.86 v4(127.26,25.86)
  IN4 w0.076: v4(127.26,25.86) 127.34,25.78 127.81,25.78 128.01,25.57 128.39,25.57 128.83,25.13 128.91,25.13 129.67,24.37 v1(129.8,24.37) ; v4(108.19,26.03) 107.96,26.26 v1(107.94,26.26)
SM_PG_CTRL: length 128.1
  TOP w0.076: v5(213.73,46.83) 212.68,47.87 207.66,47.87 197.35,58.18 188.34,58.18 188.34,58.18 166.13,58.18 166.01,58.07 166,58.07 165.95,58.01 165.95,58 165.42,57.47 163.49,57.47 162.44,58.52 148.05,58.52 147.76,58.23 v5(147.56,58.23)
  IN1 w0.076: v5(147.56,58.23) 146.96,57.64 144.04,57.64 143.47,57.07 v4(143.47,56.76) ; v3(223.76,33.14) 213.73,43.17 v5(213.73,46.83)
  IN3 w0.076: v4(143.47,56.76) 142.69,55.98 141.4,55.98 140.09,54.68 140.09,43.83 144,39.92 144,37.05 v3(144.67,36.38)
  BOTTOM w0.076: UC1.4 147.47,34.31 RC18.1 RC17.2 146.33,34.42 145.32,35.43 145.32,35.5 v2(145.18,35.65) 144.89,35.93 144.89,36.16 v3(144.67,36.38)
  BOTTOM w0.254: PR609.2 223.76,29.58 223.45,29.89 223.45,32.83 v3(223.76,33.14)
SM_RCOMP0: length 9.3
  IN2 w0.381: v4(156.33,24.88) 156.33,24.95 159.19,27.81 160.23,27.81 v3(160.82,28.39)
  IN4 w0.254: v1(155.87,24.07) 155.97,24.07 156.33,24.43 v4(156.33,24.88)
  BOTTOM w0.102: v2(161.85,29.82) 161.26,29.82 RC12.1
  BOTTOM w0.381: RC12.1 160.79,28.41 v3(160.82,28.39)
SM_RCOMP1: length 8.6
  IN2 w0.381: v3(159.76,28.75) 158.28,28.75 156.09,26.56 155.51,26.56 155.03,26.08 155.03,25.24 155.1,25.16 155.1,24.69 v4(154.87,24.45)
  IN4 w0.254: v4(154.87,24.45) v1(154.87,24.07)
  BOTTOM w0.381: RC13.1 159.78,28.77 v3(159.76,28.75)
SM_RCOMP2: length 6.7
  IN2 w0.381: v4(155.84,24.66) 155.84,25.1 158.28,27.54 v3(158.28,27.73)
  IN4 w0.254: v4(155.84,24.66) 155.84,24.55 155.37,24.08 v1(155.37,24.07)
  BOTTOM w0.381: RC14.1 v2(158.76,28.43) 158.76,28.21 v3(158.28,27.73)
SMBALERT#: length 31.2
  IN2 w0.076: v4(109.67,21.44) 109.66,21.46 109.66,22.05 110.08,22.47 116.11,22.47 116.18,22.53 120.8,22.53 123.73,19.6 124.89,19.6 125.22,19.27 125.82,19.27 126.11,19.56 126.77,19.56 126.94,19.4 128.93,19.4 129.17,19.16 129.43,19.16 129.43,19.16 129.45,19.16 129.64,19.35 v4(129.78,19.35)
  IN4 w0.076: v1(129.88,19.04) 129.88,19.24 129.78,19.35 129.78,19.35 v4(129.78,19.35) ; v1(104.19,18.57) 104.76,18.57 105.3,19.11 106.46,19.11 106.65,19.3 106.65,19.42 106.79,19.56 106.79,20.97 107.26,21.44 v4(109.67,21.44)
  BOTTOM w0.076: v1(104.19,18.57) RP7.1
SMBCLK: length 36.7
  IN2 w0.076: v4(130.74,19.34) 130.74,19.17 130.43,18.85 130.19,18.85 130.19,18.85 129.56,18.85 129.55,18.85 129.04,18.85 128.85,19.04 126.84,19.04 126.57,18.78 126.27,18.78 126.22,18.82 126.02,18.82 126.01,18.81 125.03,18.81 124.7,19.14 123.46,19.14 120.52,22.08 116.37,22.08 116.3,22.01 114.03,22.01 113.73,21.72 113.73,21.08 113.23,20.58 112.02,20.58 111.9,20.7 109.48,20.7 108.77,21.41 107.11,21.41 106.57,20.86 106.57,20.76 106.75,20.58 106.75,20.2 106.52,19.97 106.13,19.97 105.93,20.17 v4(105.93,20.19)
  IN4 w0.076: v1(99.93,18.88) 99.98,18.83 103.15,18.83 v1(103.72,19.4) 103.77,19.4 104.15,19.78 105.52,19.78 v4(105.93,20.19) 105.87,20.25 105.87,20.51 v1(105.89,20.53) ; v4(130.74,19.34) 130.74,19.33 130.74,19.33 130.74,19.32 130.88,19.18 130.88,19.08 v1(130.92,19.04)
  BOTTOM w0.076: v1(130.92,19.04) UCPU1.P21
SMBDATA: length 38.8
  IN2 w0.076: v4(106.41,20.32) 106.41,20.93 107.05,21.57 108.83,21.57 109.54,20.85 111.97,20.85 112.09,20.73 113.17,20.73 113.58,21.14 113.58,21.78 113.97,22.17 116.24,22.17 116.3,22.23 120.58,22.23 123.52,19.3 124.76,19.3 125.09,18.97 125.94,18.97 126.07,19.09 v4(126.4,19.09)
  IN4 w0.076: v1(99.93,18.38) 100.22,18.67 103.21,18.67 103.69,19.16 103.82,19.16 103.96,19.3 103.96,19.37 104.21,19.63 105.59,19.63 105.75,19.79 106.07,19.79 106.41,20.14 v4(106.41,20.32) ; v4(106.41,20.32) 106.63,20.1 106.63,19.62 v1(106.41,19.4) ; v4(106.41,20.32) 106.44,20.32 106.64,20.52 106.64,21.13 106,21.76 104.05,21.76 v1(103.99,21.83) ; v1(126.73,19.03) 126.71,19.03 126.65,19.09 v4(126.4,19.09)
  BOTTOM w0.076: v2(102.92,22.22) 103.31,21.83 v1(103.99,21.83) ; v1(126.73,19.03) 126.71,19.03 126.71,19.04 UCPU1.B21
SML0ALERT#: length 24.9
  IN4 w0.076: v1(128.88,19.04) 128.72,19.04 128.48,19.28 128.25,19.28 128.17,19.2 127.86,19.2 127.86,19.2 127.13,19.2 126.79,19.54 126.59,19.54 126.57,19.56 126.31,19.56 126.31,19.56 126.19,19.56 126.15,19.56 125.82,19.23 121.3,19.23 121.11,19.04 117.7,19.04 115.93,17.27 114.53,17.27 112.86,15.6 111.86,15.6 111.31,15.05 106.9,15.05 v1(106.81,14.96)
  BOTTOM w0.076: RP23.1 107.02,14.84 106.9,14.96 v1(106.81,14.96)
SML0CLK: length 35.9
  IN2 w0.076: v4(131.13,20.24) 131.05,20.24 130.72,19.91 129.53,19.91 129.43,20.01 127.26,20.01 127.21,20.06 125.96,20.06 125.63,19.73 125.41,19.73 125.06,20.07 124.15,20.07 120.51,23.72 118.63,23.72 117.91,22.99 115.99,22.99 115.92,22.93 108.09,22.93 107.61,22.45 107.34,22.45 107.18,22.28 106.83,22.28 106.55,22.56 v4(106.55,22.57)
  IN4 w0.076: v4(106.55,22.57) 106.59,22.53 v1(106.59,22.22) ; v4(131.13,20.24) 130.88,19.99 v1(130.88,19.9)
  BOTTOM w0.076: RP23.2 107.14,15.34 106.97,15.51 106.67,15.51 106.44,15.74 106.44,16.73 106.78,17.07 v12(106.78,20.82) 106.78,22.03 v1(106.59,22.22)
SML0DATA: length 31.1
  IN2 w0.076: v4(107.05,22.6) 107.54,22.6 108.02,23.08 115.86,23.08 115.92,23.14 117.85,23.14 118.57,23.87 120.57,23.87 124.21,20.23 125.26,20.23 125.42,20.07 v4(125.52,20.07)
  IN4 w0.076: v1(127.57,19.9) 127.58,19.9 127.57,19.9 127.41,19.9 127.16,20.15 126.85,20.15 126.82,20.17 126.56,20.17 126.15,20.17 126.15,20.17 125.89,20.17 125.89,20.17 125.64,20.17 125.53,20.07 v4(125.52,20.07) ; v1(106.97,22.22) 106.89,22.29 106.89,22.45 v4(107.05,22.6)
  BOTTOM w0.076: v1(106.97,22.22) 106.93,22.18 106.93,21.1 106.94,21.1 106.94,20.55 106.93,20.54 106.93,17.01 106.59,16.67 106.59,15.8 106.73,15.66 106.91,15.66 107.08,15.84 RP23.3 ; v1(127.57,19.9) 127.58,19.9 UCPU1.B19
SML1_SMBCLK: length 307.3
  TOP w0.076: v3(171.41,14.09) 171.41,14.06 171.23,13.89 170.81,13.89 170.34,13.42 170.34,12.93 164.36,6.95 137.15,6.95 133.54,10.57 132.38,10.57 131.9,10.09 130.89,10.09 130.52,10.46 126.03,10.46 125.91,10.34 124.87,10.34 122.04,13.17 116.51,13.17 112.92,16.76 109.57,16.76 109.45,16.88 103.46,16.88 103.24,16.65 102.82,16.65 102.66,16.81 102.66,16.85 v5(102.78,16.96)
  IN1 w0.076: v4(293.3,85.35) 292.92,85.35 292.22,84.65 292.22,83.94 292.55,83.61 v4(292.55,83.55) ; v5(102.78,16.96) 102.78,17.11 102.55,17.34 102.54,17.34 v4(102.49,17.39)
  IN3 w0.076: v4(285.79,90.79) 285.67,90.67 285.67,90.62 285.57,90.52 285.57,83.23 285.25,82.91 285.25,82.01 285.53,81.73 285.53,80.1 284.26,78.83 284.26,75.15 284.8,74.62 284.8,59.53 292.57,51.76 293.33,51.76 294.19,50.9 294.19,48.26 295.15,47.3 295.96,47.3 296.97,46.28 297.57,46.28 298.13,45.73 298.13,21.95 291.9,15.72 290.08,13.9 289.42,13.9 289.03,13.51 287.51,13.51 285.07,11.07 283.04,11.07 281.85,9.87 272.91,9.87 272.57,10.22 268.61,10.22 267.47,9.08 250.8,9.08 247.5,12.37 232.9,12.37 232.47,12.81 228.72,12.81 225.17,9.25 210.55,9.25 210.04,9.76 200.09,9.76 199.84,10.01 192.44,10.01 191.91,9.48 188.4,9.48 188.03,9.84 184.43,9.84 184.06,10.21 182.31,10.21 181.81,10.71 173.84,10.71 172.18,12.36 172.18,13.54 171.94,13.78 171.71,13.78 v3(171.41,14.09)
  IN4 w0.076: v4(102.49,17.39) 102.6,17.51 v1(102.6,17.87) ; v4(292.55,83.55) 292.58,83.52 292.58,83.16 v1(292.61,83.13) ; v4(285.79,90.79) 285.79,91.05 285.99,91.25 287.95,91.25 288.43,90.78 288.43,90.67 291.11,87.99 291.11,87.75 292.32,86.53 292.89,86.53 292.97,86.44 292.97,85.62 293.24,85.35 v4(293.3,85.35)
SML1_SMBDATA: length 308.1
  TOP w0.076: v3(172,14.12) 171.99,14.11 171.94,14.11 171.56,13.73 170.88,13.73 170.5,13.35 170.5,12.87 164.42,6.8 137.09,6.8 133.47,10.42 132.45,10.42 131.96,9.93 v2(130.65,9.93) 130.27,10.31 126.09,10.31 125.97,10.19 124.81,10.19 121.97,13.02 116.45,13.02 112.86,16.61 109.5,16.61 109.38,16.73 103.53,16.73 103.3,16.5 102.75,16.5 102.51,16.74 102.51,16.85 v5(102.4,16.96)
  IN1 w0.076: v5(102.4,16.96) 102.27,16.96 102,17.23 v4(102,17.26) ; v4(290.76,85.02) 290.93,84.85 292.21,84.85 293.05,85.69 293.1,85.69 293.29,85.88 v4(293.32,85.88)
  IN3 w0.076: v3(172,14.12) 171.99,14.12 171.99,13.96 172.34,13.62 172.34,12.43 173.9,10.86 181.87,10.86 182.38,10.36 184.13,10.36 184.49,9.99 188.1,9.99 188.46,9.63 191.85,9.63 192.38,10.16 199.9,10.16 200.15,9.91 210.1,9.91 210.61,9.4 225.11,9.4 228.66,12.96 232.53,12.96 232.97,12.53 247.57,12.53 250.86,9.23 267.41,9.23 268.55,10.37 272.63,10.37 272.98,10.03 281.79,10.03 282.98,11.22 285.01,11.22 287.45,13.66 288.96,13.66 289.36,14.05 290.01,14.05 291.83,15.87 297.98,22.01 297.98,45.66 297.51,46.13 296.91,46.13 295.9,47.15 295.09,47.15 294.04,48.19 294.04,50.83 293.27,51.6 292.5,51.6 284.64,59.46 284.64,74.55 284.11,75.09 284.11,78.9 285.38,80.17 285.38,81.67 285.1,81.95 285.1,82.97 285.42,83.29 285.42,90.51 v4(285.28,90.64)
  IN4 w0.076: v4(290.76,85.02) 290.61,84.87 v1(290.61,84.63) ; v4(102,17.26) 102,17.2 102.25,16.96 v1(102.63,16.96) ; v4(293.32,85.88) 293.13,86.07 293.13,86.5 292.95,86.68 292.39,86.68 291.26,87.81 291.26,88.05 288.58,90.73 288.58,90.84 288.01,91.41 285.93,91.41 285.63,91.11 285.63,91.09 285.47,90.92 285.47,90.84 v4(285.28,90.64)
SML1ALERT#: length 29.2
  IN4 w0.076: v1(129.36,23.62) 129.36,23.43 128.76,22.82 126.41,22.82 125.67,23.56 125.29,23.56 125,23.85 124.15,23.85 122.87,22.57 118.76,22.57 118.67,22.66 116.36,22.66 115.43,21.73 115.02,21.73 114.56,21.28 113.97,21.28 113.23,20.54 109.58,20.54 109.08,21.04 107.64,21.04 107.1,20.5 107.1,19.31 106.57,18.79 106.45,18.79 105.54,18.79 v1(104.69,17.94)
SML1CLK: length 32.2
  IN4 w0.076: v1(128.13,22.07) 127.97,22.07 127.97,22.07 127.29,22.07 127.07,21.85 124.88,21.85 124.73,21.7 124.36,21.7 123.88,21.21 118.17,21.21 117.79,21.6 116.8,21.6 116.47,21.26 116.47,20.73 115.03,19.29 113.63,19.29 113.13,18.79 111.75,18.79 110.68,17.71 109.28,17.71 108.8,18.19 108.37,18.19 108.32,18.24 107.59,18.24 106.45,17.1 103.87,17.1 103.2,17.77 103.2,17.83 102.76,18.27 102.35,18.27 101.95,17.87 v1(101.69,17.87)
  BOTTOM w0.076: v1(101.69,17.87) 101.46,17.65 100.16,17.65 RP5.3
SML1DATA: length 32.5
  IN4 w0.076: v1(101.71,16.96) 101.69,16.98 101.69,17.4 101.92,17.63 101.93,17.63 102.41,18.12 102.7,18.12 103.05,17.77 103.05,17.71 103.81,16.95 106.51,16.95 107.65,18.09 108.26,18.09 108.31,18.04 108.73,18.04 109.22,17.56 110.74,17.56 111.82,18.63 113.2,18.63 113.7,19.14 115.09,19.14 116.62,20.67 116.62,21.2 116.86,21.44 117.73,21.44 118.11,21.06 123.94,21.06 124.43,21.55 124.79,21.55 124.94,21.7 127.26,21.7 v1(127.4,21.83)
  BOTTOM w0.076: v1(127.4,21.83) UCPU1.A14 ; RP5.4 100.04,17.49 101.18,17.49 v1(101.71,16.96)
SNUB_1.5V: length 2.9
  BOTTOM w0.076: v2(292.74,37.41) PR402.2
  BOTTOM w0.508: PR402.2 292.74,40.21 PC407.1
SNUB_1.8V: length 2.9
  BOTTOM w0.076: v2(282.06,39.15) PR407.2
  BOTTOM w0.508: PR407.2 280.55,40.46 PC415.1
SPI_CLK_ROM1: length 16.4
  IN4 w0.066: v1(221.68,9.95) 223.49,9.95 223.6,10.06 223.6,10.89 223.74,11.03 223.83,11.03 224.51,10.35 224.6,10.35 224.74,10.49 224.74,10.58 224.06,11.26 224.06,11.36 224.2,11.5 224.3,11.5 224.98,10.82 225.07,10.82 225.21,10.96 225.21,11.05 224.53,11.73 224.53,11.82 224.67,11.96 224.76,11.96 225.45,11.28 225.54,11.28 225.68,11.42 225.68,11.52 225,12.2 225,12.29 225.14,12.43 225.23,12.43 225.91,11.75 226.01,11.75 226.85,12.59 v1(226.86,12.59)
  BOTTOM w0.097: U1.6 220.94,10.35 221.34,9.95 v1(221.68,9.95) ; v1(226.86,12.59) 226.86,11.56 v2(227.01,11.41)
SPI_CLK_ROM2: length 13.3
  BOTTOM w0.097: U2.6 232.83,9.57 232.98,9.42 232.98,8.39 232.85,8.26 231.22,8.26 231.13,8.36 231.13,8.83 231,8.96 230.77,8.96 230.64,8.83 230.64,8.36 230.55,8.26 230.26,8.26 230.16,8.36 230.16,8.91 230.03,9.03 229.8,9.03 229.68,8.91 229.68,8.36 229.58,8.26 229.14,8.26 229.02,8.39 v2(229.02,10.85) RH52.1
SPI_IO2_ROM1: length 18.6
  IN4 w0.066: v1(219.44,9.16) 219.44,9.19 220.37,10.11 221.17,10.11 223.95,12.9 224.42,12.9 224.57,13.04 v1(224.57,13.73)
  BOTTOM w0.097: v1(219.44,9.16) 219.44,9.03 219.59,8.88 220.98,8.88 221.07,8.78 221.07,8.49 220.98,8.4 220.25,8.4 220.15,8.3 220.15,8.01 220.25,7.91 220.75,7.91 220.94,7.72 U1.3 ; v2(222.18,14.58) 222.48,14.29 224.42,14.29 224.57,14.14 v1(224.57,13.73)
SPI_IO2_ROM2: length 17.3
  IN4 w0.066: v1(232.83,4.86) 233.03,5.06 233.03,12.1 232.62,12.5 v1(232.62,12.53)
  BOTTOM w0.097: v1(232.62,12.53) v2(232.23,12.92) 232,13.15 232,13.33 228.72,16.61 227.03,16.61 226.93,16.51 RP6.2 ; U2.3 v1(232.83,4.86)
SPI_IO3_ROM1: length 14.5
  IN4 w0.066: v1(223.57,13.21) 223.58,13.21 224.46,14.09 226.46,14.09 226.59,13.96 226.59,13.77 226.46,13.64 225.7,13.64 225.6,13.54 225.6,13.4 225.7,13.3 226.53,13.3 226.65,13.19 226.65,13.02 226.53,12.91 v1(226.06,12.91)
  BOTTOM w0.097: U1.7 222.21,12.22 222.36,12.37 224.85,12.37 224.98,12.5 224.98,13.11 225.11,13.24 225.31,13.24 225.44,13.11 225.44,12.5 225.56,12.37 v2(225.74,12.37) 226.11,12.37 226.24,12.5 226.24,12.78 226.11,12.91 v1(226.06,12.91) ; v1(223.57,13.21) RP4.4
SPI_IO3_ROM2: length 12.8
  IN4 w0.066: v1(231.46,12.71) 231.47,12.71 232.17,12.01 v1(232.69,12.01)
  BOTTOM w0.097: RP6.4 228.73,15.91 229.07,15.57 229.07,15.43 228.68,15.04 228.68,14.91 228.89,14.7 229.02,14.7 229.41,15.09 229.55,15.09 229.75,14.89 229.75,14.75 229.36,14.36 229.36,14.22 229.57,14.02 229.71,14.02 v2(230.1,14.41) 230.23,14.41 230.44,14.21 230.44,14.07 230.05,13.68 230.05,13.54 230.25,13.34 230.39,13.34 230.78,13.73 230.92,13.73 231.46,13.19 v1(231.46,12.71) ; U2.7 234.1,11.69 233.78,12.01 v1(232.69,12.01)
SPI_PCH_CLK: length 24.4
  IN4 w0.066: v1(213.09,7.97) 213.47,7.59 215.4,7.59 215.65,7.83 217.39,7.83 218.2,8.64 220.7,8.64 221.49,9.43 224.94,9.43 v1(229.02,13.51)
  BOTTOM w0.097: JSPI1.7 212.68,7.56 v1(213.09,7.97) ; v2(229.97,12.95) 229.94,12.95 229.38,13.51 v1(229.02,13.51) 228.61,13.91 227.53,13.91 227.13,13.51 RH46.2
SPI_PCH_CS0#: length 25.9
  IN4 w0.066: v1(223.47,5.22) 223.47,5.81 223.31,5.96 222.98,5.96 222.91,5.9 222.91,4.67 222.84,4.6 222.65,4.6 222.58,4.67 222.58,5.9 222.51,5.96 222.32,5.96 222.25,5.9 222.25,4.67 222.18,4.6 221.99,4.6 221.92,4.67 221.92,5.9 221.85,5.96 211.71,5.96 v1(211.68,5.94)
  BOTTOM w0.097: U1.1 223.48,5.21 v1(223.47,5.22) ; v2(211.36,12.36) 212.16,11.57 212.16,9.07 RC44.1 211.68,8.59 v1(211.68,5.94)
SPI_PCH_CS1#: length 24.3
  IN4 w0.066: v1(235.37,3.65) 217.57,3.65 v1(216.11,5.1)
  BOTTOM w0.097: v1(216.11,5.1) 215.68,5.53 JSPI1.1 215.68,6.76 v2(216.62,7.7) RC40.1
SPI_PCH_IO2: length 25
  IN4 w0.066: v1(226.93,14.76) 226.55,15.14 224.83,15.14 v1(224.57,14.88) 220.69,11 v1(217.92,11) 217.89,11.03 217.04,11.03 216.32,11.75 210.78,11.75 v1(210.67,11.64)
  BOTTOM w0.097: v1(217.92,11) RH47.2 ; v1(210.67,11.64) v2(210.67,11.21) 210.99,10.88 210.99,9.61 210.75,9.36 210.75,8.31 210.81,8.25 RC45.1 210.68,7.84 JSPI1.11
SPI_PCH_IO3: length 27
  IN4 w0.066: v1(209.79,11.64) 210.1,11.95 220.68,11.95 221.37,12.64 221.37,13.06 223.19,14.88 v1(223.57,14.88) 223.6,14.88 224.43,15.71 226.97,15.71 v1(227.93,14.76)
  BOTTOM w0.097: v2(209.79,12.15) v1(209.79,11.64) RH48.2 RC46.1 209.34,8.54 209.34,7.47 209.68,7.14 JSPI1.13
SPI_PCH_SI: length 20.2
  IN4 w0.066: v1(227.43,14.76) 226.74,15.44 224.63,15.44 v1(224.07,14.88) 220.73,11.54 217.1,11.54 v1(217.08,11.51)
  BOTTOM w0.097: JSPI1.5 213.68,6.98 213.76,7.07 213.76,8.64 RC42.1 214.11,9.58 214.49,9.96 214.77,9.96 214.93,10.12 214.93,10.79 215.65,11.51 v2(216.27,11.51) v1(217.08,11.51)
SPI_PCH_SO: length 16.4
  IN4 w0.066: v1(215.12,7.97) 217.21,10.05 220.02,10.05 224.54,14.57 224.76,14.57 v1(225.07,14.88) 226.31,14.88 v1(226.43,14.76)
  BOTTOM w0.097: v1(215.12,7.97) 214.68,7.53 JSPI1.3
SPI_SI_ROM1: length 15.6
  BOTTOM w0.097: RP4.3 224.07,13.26 224.14,13.19 224.55,13.19 224.62,13.12 224.62,12.83 224.55,12.76 223.09,12.76 222.81,13.03 222.52,13.03 222.39,13.16 222.39,13.4 222.52,13.53 223.12,13.53 223.25,13.66 223.25,13.94 223.12,14.07 222.08,14.07 221.96,13.94 221.96,13.3 221.83,13.18 221.65,13.18 221.52,13.3 221.52,14.24 221.4,14.37 221.16,14.37 221.03,14.24 221.03,13.25 221.17,13.11 v2(221.17,12.81) 221.17,12.59 220.3,11.72 220.3,10.17 220.13,10 219.8,10 219.67,10.13 U1.5
SPI_SI_ROM2: length 14.1
  BOTTOM w0.097: RP6.3 227.43,16.31 227.5,16.39 228.57,16.39 231.73,13.22 231.73,12.45 231.54,12.26 230.2,12.26 230.07,12.13 v2(230.07,11.68) 230.07,10.25 230.2,10.13 230.54,10.13 230.67,10.25 230.67,11.5 230.8,11.63 231.48,11.63 231.56,11.55 U2.5
SPI_SO_ROM1: length 23.9
  IN4 w0.066: v1(225.07,13.73) 225.07,13.26 224.48,12.68 224.01,12.68 220.54,9.21 v1(220,9.21)
  BOTTOM w0.097: v1(220,9.21) 220.17,9.38 222.88,9.38 222.97,9.29 222.97,9 222.88,8.9 221.39,8.9 221.3,8.8 221.3,8.52 221.39,8.42 222.88,8.42 222.97,8.32 222.97,8.03 222.88,7.94 221.39,7.94 221.3,7.84 221.3,6.67 221.57,6.39 222.03,6.39 222.21,6.21 U1.2 ; v2(225.14,16.42) 225.35,16.22 225.35,14.42 225.07,14.14 v1(225.07,13.73)
SPI_SO_ROM2: length 18.6
  IN4 w0.066: v1(233.08,12.5) 234.07,11.51 v1(234.07,4.88)
  BOTTOM w0.097: RP6.1 226.43,16.59 226.67,16.84 228.93,16.84 v2(229.71,16.06) 233.08,12.69 v1(233.08,12.5) ; U2.2 234.1,4.86 v1(234.07,4.88)
SPK_L+_C: length 35.9
  IN3 w1.016: 7.83,56.02 9.05,56.02 10.07,57.03 14.92,57.03 15.87,56.08 15.87,54.4 15.48,54.01
  IN4 w1.016: 15.15,52.83 16.11,51.86 16.11,50.51 17.33,49.29 20.15,49.29 27.97,41.47 29.41,41.47 31.39,39.49 32.07,39.49 32.93,38.63 32.93,38.3
  vias: v1(6.32,55.93) v1(6.33,55.55) v1(33.17,36.1) v1(33.51,36.11) v2(34,35.94) v4(6.79,56.04) v4(6.8,55.54) v4(14.32,53.25) v4(14.68,53.63)
SPK_L+_L: length 31.7
  IN1 w1.016: 42.15,5.95 42.82,6.63 42.82,8.87 43.67,9.72 43.67,13.31 44.88,14.52 44.88,17.45 36.32,26.01 36.32,27.56 33.6,30.28
  BOTTOM w0.076: v2(42.51,8.21) 42,7.7 JSPK1.3
  vias: v3(32.78,30.88) v3(33.36,30.88) v3(41.49,5.38) v3(41.5,4.75)
SPK_L-_C: length 31.5
  IN3 w1.016: 13.1,53.51 13.18,53.59 13.18,54.88 12.33,55.74 10.57,55.74 9.06,54.23 8.41,54.23
  IN4 w1.016: 14.01,52.12 14.69,51.44 14.69,50.11 16.88,47.92 19.71,47.92 28.32,39.32 29.77,39.32 31.37,37.71 31.63,37.71
  vias: v1(6.45,54.38) v1(6.45,54.06) v1(31.85,36.63) v1(32.23,36.64) v2(32.05,36.19) v4(6.87,54.46) v4(6.89,53.98) v4(13.27,52.6) v4(13.7,52.91)
SPK_L-_L: length 25
  IN1 w1.016: 31.62,30.52 35.1,27.04 35.1,25.41 41.79,18.72 41.79,10.22 41.47,9.9
  vias: v2(31.36,31.46) v3(30.95,30.9) v3(31.54,30.92) v3(41.67,8.76) v3(41.68,8.17)
SPK_R+_C: length 35
  IN3 w1.016: 7.68,52.53 7.74,52.47 10.39,52.47 11.63,51.24 15.43,51.24 16.52,52.33
  IN4 w1.016: 17.88,51.33 18.29,50.92 20.68,50.92 27.22,44.38 29.3,44.38 29.89,43.78 31.84,43.78 35.37,40.25 35.37,37.18
  vias: v1(6.25,52.83) v1(6.25,52.46) v1(35.4,36.41) v1(35.76,36.42) v2(35.56,36.8) v4(6.78,52.84) v4(6.77,52.41) v4(17.54,52.08) v4(17.56,52.66)
SPK_R+_L: length 29.9
  IN1 w1.016: 35.34,30.25 35.63,29.96 35.67,29.96 37.65,27.98 37.65,26.37 46.4,17.62 46.4,13.77 45.2,12.56 45.2,9.12 44.36,8.28 44.36,5.82
  vias: v2(34.81,30.33) v3(34.47,30.84) v3(35.05,30.84) v3(43.44,5.43) v3(43.44,4.83)
SPK_R-_C: length 37.3
  IN3 w1.016: 7.62,51 7.64,50.98 10.04,50.98 11.05,49.97 17.61,49.97 18.6,50.96
  IN4 w1.016: 19.64,52.19 21.21,52.19 27.75,45.65 29.83,45.65 30.4,45.08 32.47,45.08 36.98,40.57 36.98,37.23
  vias: v1(6.25,51.26) v1(6.25,50.88) v1(36.85,36.44) v1(37.2,36.44) v2(37.04,36.84) v4(6.72,51.28) v4(6.72,50.83) v4(18.77,52.66) v4(18.76,52.1)
SPK_R-_L: length 27.9
  IN1 w1.016: 37.37,30.1 38.94,28.54 38.94,26.91 47.89,17.95 47.89,8.87 46.26,7.24
  vias: v2(37.18,30.41) v3(36.88,30.88) v3(37.5,30.89) v3(45.41,7.51) v3(45.41,6.86)
SS_1.5V: length 5.6
  BOTTOM w0.076: PC406.1 284.55,44.07 v2(282.03,44.07)
  BOTTOM w0.203: PU400.9 287.13,44.01 286.98,44.16 285.02,44.16 PC406.1
SS_1.8V: length 4
  BOTTOM w0.076: v2(272.72,45.62) 272.64,45.54 PC414.1
  BOTTOM w0.203: PC414.1 272.88,44.85 274.51,44.85 274.94,44.42 PU401.9
SSD_PWREN: length 155.2
  IN4 w0.076: v1(129.88,13.84) 129.72,13.84 129.62,13.74 129.62,13.74 129.48,13.6 129.48,13.6 129.33,13.45 129.01,13.45 128.73,13.17 128.45,13.17 128.3,13.01 127.94,13.01 127.81,12.88 126.33,12.88 125.96,12.51 124.96,12.51 124.44,13.04 123.85,13.04 123.05,13.84 121.8,13.84 121.03,13.07 120.7,13.07 120.02,12.39 118.54,12.39 117.74,11.59 116.86,11.59 v1(116.62,11.83) 116.53,11.74 115,11.74 114.79,11.52 114.62,11.52 114.53,11.43 112.62,11.43 111.88,10.7 111.11,10.7 109.7,12.11 107.71,12.11 107.6,12.01 103.35,12.01 102.64,12.72 100.72,12.72 100.5,12.49 98.19,12.49 97.93,12.75 96.96,12.75 96.74,12.97 95.76,12.97 95.46,13.26 86.69,13.26 85.98,13.97 78.8,13.97 78.43,14.34 68.77,14.34 66.57,12.14 62.89,12.14 61.12,13.91 52.37,13.91 49.04,17.23 49.04,23.85 49.3,24.1 49.3,33.3 v1(48.64,33.96) ; v1(8.15,40.97) 8.15,38.82 9.94,37.03 10.13,37.03 10.63,36.53 18.68,36.53 19.12,36.97 26.74,36.97 27.54,36.17 30.29,36.17 31.01,35.46 31.61,35.46 32.12,34.94 47.25,34.94 47.72,35.41 48.41,35.41 v1(48.68,35.15)
  BOTTOM w0.076: U30.5 10.9,41.64 10.58,41.96 v2(10.01,41.96) 9.06,41.96 8.15,41.05 v1(8.15,40.97) ; v1(48.64,33.96) 48.64,35.11 v1(48.68,35.15)
SUS_ON: length 216.4
  TOP w0.076: v5(293.66,74.52) 289.09,74.52 287.69,73.12 v3(287.69,57.92) 287.5,57.73 287.5,50.4 287.68,50.23 287.68,49.48 287.59,49.39 287.59,48.58 v5(287.82,48.35)
  IN1 w0.076: v4(298.96,76.21) 298.46,75.71 294.6,75.71 v4(294.04,75.15) 293.66,74.77 v5(293.66,74.52) ; v5(287.82,48.35) v4(287.82,47.85)
  IN2 w0.076: v4(287.82,47.85) 287.52,48.14 287.52,49.39 287.75,49.62 288.03,49.62 288.74,48.91 290.95,48.91 291.51,48.35 292.57,48.35 292.89,48.03 292.89,47.57 292.47,47.15 292.47,46.03 293.4,45.1 293.4,42.37 295.47,40.29 295.47,21.88 295.39,21.8 295.39,19.69 293.49,17.8 293.49,17.67 291.45,15.63 291.45,11.88 288.52,8.95 287.53,8.95 286.38,10.1 274.08,10.1 272.32,11.85 272.32,12.22 271.93,12.62 269.59,12.62 266.75,9.78 235.6,9.78 230.62,14.77 230.62,31.84 229.32,33.14 224.73,33.14 v3(224.39,32.81)
  IN4 w0.076: v4(298.96,76.21) 298.88,76.29 298.88,78.47 298.56,78.78 298.56,82.83 298.88,83.15 298.88,85.6 298.64,85.84 298.64,88.02 298,88.66 295.7,88.66 v1(295.43,88.93) ; v1(293.11,78.63) 293.11,78.62 294.07,77.66 294.07,75.18 v4(294.04,75.15)
  BOTTOM w0.076: R385.1 297.86,55.29 296.96,55.29 296.71,55.04 290.14,55.04 287.69,57.49 v3(287.69,57.92)
  BOTTOM w0.254: v3(224.39,32.81) 224.38,32.81 223.95,32.38 v6(223.95,32.31) 223.95,29.95 224.93,28.97 224.93,26.56 224.62,26.26 PR608.2
SUS_PWR_DN: length 37.5
  IN4 w0.076: v1(128.5,23.62) 128.5,23.57 128.52,23.55 128.52,23.3 128.35,23.13 126.54,23.13 125.8,23.87 125.42,23.87 125.09,24.2 123.2,24.2 122.45,23.45 122.16,23.45 121.96,23.25 120.78,23.25 120.14,23.89 118.35,23.89 118.02,23.56 118.02,23.21 117.78,22.97 116.23,22.97 115.38,22.12 114.36,22.12 113.88,21.63 113.88,21.4 113.17,20.69 109.64,20.69 109.14,21.2 107.57,21.2 106.94,20.57 106.94,19.37 106.51,18.94 105.35,18.94 104.69,18.28 104.02,18.28 v1(103.87,18.43)
  BOTTOM w0.076: 101.68,13.81 RP8.7 ; 101.68,13.81 101.68,14.54 101.64,14.58 RH68.2 102.04,15.28 102.84,15.28 103.31,15.76 103.31,17.57 103.66,17.91 103.66,18.22 v1(103.87,18.43) ; 101.68,13.81 RH61.1
SUSACK#: length 286.5
  TOP w0.076: v5(102.25,15.51) 102.25,15.07 102.48,14.83 107.58,14.83 112.23,10.19 120.93,10.19 123.87,7.24 133.31,7.24 136.82,3.73 166.06,3.73 169.79,7.46 170.63,7.46 176.1,12.93 176.5,12.93 176.91,13.34 v3(176.91,13.91)
  IN1 w0.076: v4(102.25,15.89) v5(102.25,15.51)
  IN3 w0.076: v4(285.76,14.33) 285.61,14.18 284.15,14.18 283.03,13.06 282.24,13.06 281.01,11.83 273.9,11.83 272.52,13.21 268.63,13.21 267.08,11.66 251.1,11.66 248.06,14.71 237.62,14.71 237.12,15.21 233.08,15.21 232.53,15.76 227.77,15.76 226.28,14.27 226.28,13.52 224.02,11.26 214.41,11.26 213.69,11.99 203.61,11.99 203.52,11.9 200.7,11.9 199.9,12.7 192.84,12.7 192.16,12.7 191.04,11.58 189.27,11.58 188.91,11.94 188.15,11.94 187.16,11.94 187.16,11.94 185.3,11.94 184.92,12.33 184.59,12.33 183.47,13.45 177.36,13.45 v3(176.91,13.91)
  IN4 w0.076: v1(102.65,15.79) 102.35,15.79 v4(102.25,15.89) ; v4(285.76,14.33) 285.96,14.13 285.96,13.43 286.22,13.17 288.4,13.17 289.69,14.46 292.5,14.46 292.81,14.16 295.83,14.16 297.61,15.93 297.73,15.93 297.96,16.16 297.96,16.45 299.04,17.53 299.04,20.03 298.85,20.22 298.85,34.28 299.36,34.79 299.36,48.29 296.19,51.46 294.68,51.46 293.81,52.33 293.81,53.33 293.43,53.71 293.43,55.93 293.28,56.08 293.28,60.51 294.18,61.41 294.18,67.1 294.35,67.27 294.35,70.62 294.15,70.82 294.15,72.34 294.69,72.88 294.69,75.54 294.52,75.7 294.52,78.05 293.93,78.64 293.93,79.31 v1(293.61,79.63)
  BOTTOM w0.076: v2(176.81,13.2) 176.91,13.3 v3(176.91,13.91)
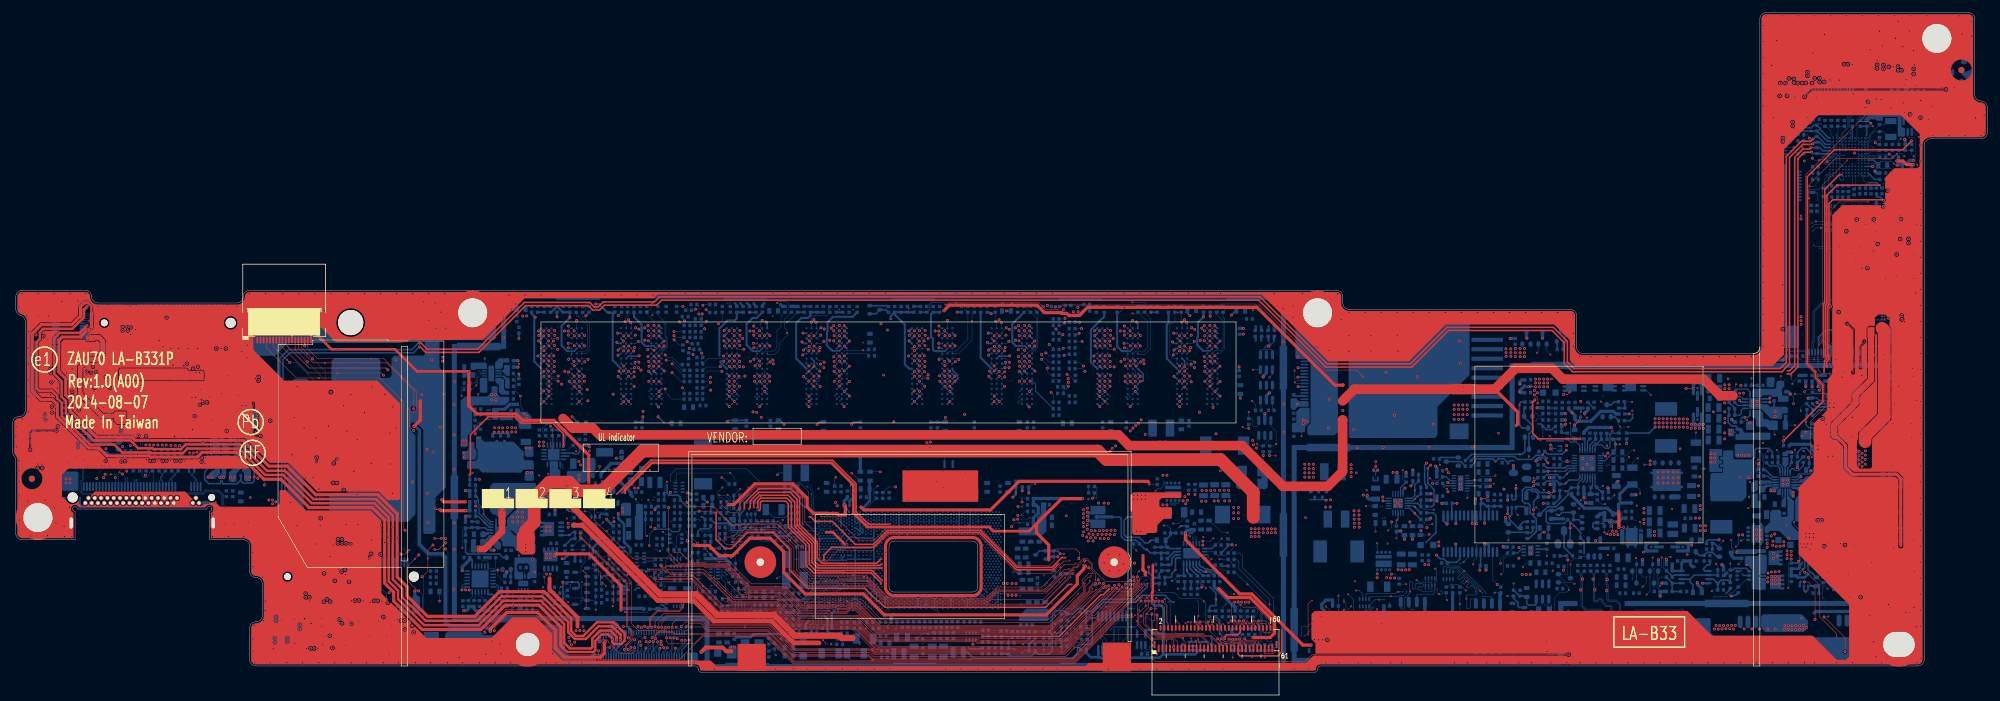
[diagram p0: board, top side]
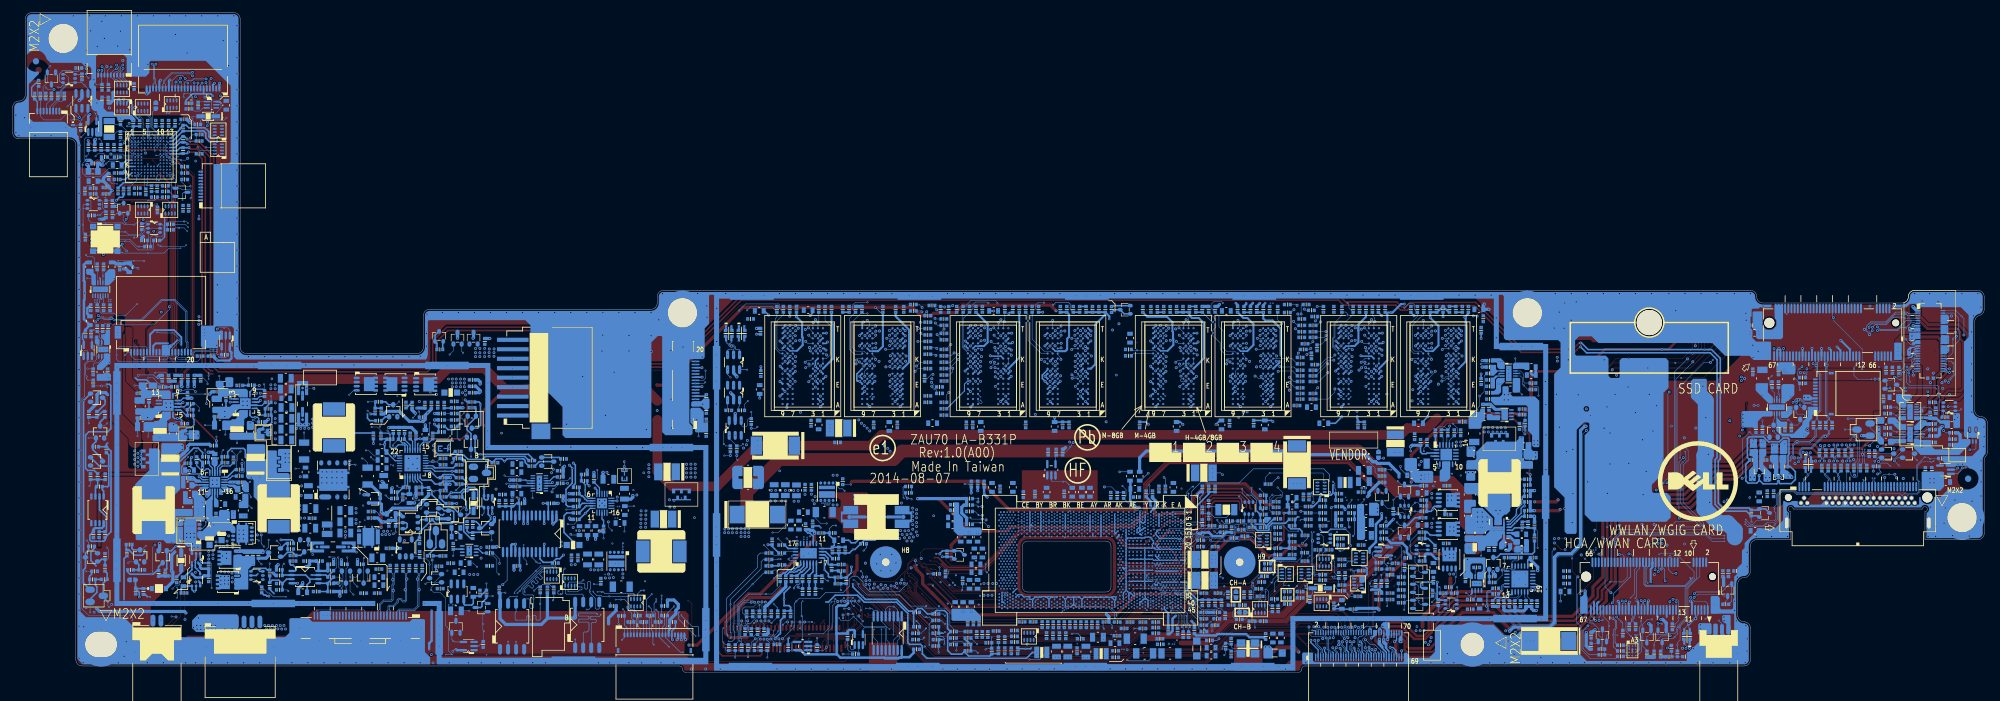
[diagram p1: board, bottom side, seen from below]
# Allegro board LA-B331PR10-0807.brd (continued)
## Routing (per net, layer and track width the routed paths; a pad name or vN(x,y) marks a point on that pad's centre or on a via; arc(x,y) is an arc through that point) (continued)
SUSACK#_R: length 29.6
  IN4 w0.076: v1(128.38,19.9) 127.92,19.9 127.67,19.66 127.36,19.66 127.02,19.99 126.78,19.99 126.76,20.02 126.5,20.02 125.96,20.02 125.63,19.69 121.11,19.69 120.92,19.5 117.77,19.5 117.76,19.5 117.51,19.5 115.75,17.74 114.27,17.74 113.64,17.1 112.55,17.1 111.1,15.65 109.42,15.65 109.03,16.05 107.92,16.05 107.53,15.65 104.2,15.65 103.7,15.15 v1(103.68,15.15)
  BOTTOM w0.076: v1(103.68,15.15) 103.68,15.09 103.47,14.88 RH62.2 102.65,13.86 RH61.2
SUSCLK: length 164
  TOP w0.076: v3(61.47,18.71) 62.12,18.71 v2(62.79,19.38)
  IN1 w0.076: v4(124.23,14.03) 123.79,14.47 117.13,14.47 116.03,15.58 115.61,15.58 115.33,15.3 112.07,15.3 111.69,15.68 110.71,15.68 109.1,14.06 106.1,14.06 105.6,13.56 100.02,13.56 99.31,12.84 95.81,12.84 95.53,12.57 93.58,12.57 92.7,11.68 73.62,11.68 72.71,12.59 69.07,12.59 62.95,18.71 v3(61.47,18.71)
  IN3 w0.076: v3(18.04,31.87) 18.34,32.16 27.02,32.16 27.68,32.82 27.68,33.58 27.16,34.1 27.16,36.05 v4(27.68,36.57) 27.68,36.57 25.99,38.26 25.99,45.53 28.56,48.1 v3(28.56,48.09)
  IN4 w0.076: v1(126.09,13.96) 126.02,14.03 v4(124.23,14.03) ; v1(47.86,35.79) 47.27,35.79 46.81,35.33 32.27,35.33 31.77,35.84 31.17,35.84 30.44,36.57 v4(27.68,36.57)
  BOTTOM w0.076: R65.2 v3(18.04,31.87) ; UCPU1.B27 127.82,16.38 126.9,16.38 126.17,15.65 126.17,14.84 126.09,14.76 v1(126.09,13.96) 126.09,13.22 125.41,12.54 MC2.2 ; JNGFF2.60 61,18.25 v3(61.47,18.71) 61,19.18 61,20.17 58.58,22.59 45.13,22.59 44.92,22.8 44.92,23.71 48.14,26.93 48.14,32.8 47.34,33.6 47.34,35.12 47.86,35.64 v1(47.86,35.79) ; R76.2 28.79,46.99 28.56,47.22 v3(28.56,48.09)
SVID_ALRT#: length 14.8
  IN4 w0.076: v1(189.2,18.38) 189.86,18.38 189.99,18.51 189.99,20.29 190.12,20.41 190.38,20.41 190.51,20.29 190.51,17.98 190.64,17.85 190.79,17.85 190.92,17.98 190.92,20.27 191.04,20.4 191.27,20.4 191.4,20.27 v1(191.4,17.92)
  BOTTOM w0.076: v1(189.2,18.38) 189.2,18.42 189.02,18.6 PU702.19 ; v2(190.99,17.92) v1(191.4,17.92) 191.45,17.87 PR516.2 192.95,17.29 192.95,17.19 PR509.1
SVID_CLK: length 7.7
  BOTTOM w0.076: PU702.20 189.59,18.1 189.71,17.99 v2(189.71,17.92) 189.71,17.83 189.59,17.72 188.54,17.72 188.42,17.6 188.42,17.43 188.54,17.32 189.29,17.32 189.42,17.19 189.42,16.95 189.52,16.85 189.89,16.85 190.05,17.01 PR513.1 191.15,16.2 192.01,16.2 PR517.2
SVID_DAT: length 6
  BOTTOM w0.076: PU702.18 190.12,19.1 PR510.1 190.33,18.86 190.71,18.48 191.96,18.48 PR515.2 192.36,18.92 v2(193.6,20.15)
SW_1.5V: length 1.5
  BOTTOM w0.076: PR402.1 v2(291.04,37.35)
SW_1.8V: length 1.5
  BOTTOM w0.076: PR407.1 v2(278.84,37.66)
SW_1.35V: length 5.5
  IN4 w1.016: 217,18.1 217,23.56
  vias: v1(216.62,17.26) v1(216.77,24.43) v1(217.08,17.26) v1(217.16,24.43) v2(212.41,14.42)
SYS_LED_MASK#: length 27.2
  IN3 w0.076: v4(286.83,79.65) 286.83,80.14 286.47,80.49 286.47,81.97 287.01,82.5 287.01,87.91 287.34,88.23 291.49,88.23 291.73,87.99 294.69,87.99 295.01,88.31 299.4,88.31 300.41,87.3 v4(300.59,87.3)
  IN4 w0.076: v1(300.53,85.58) 300.53,87.24 v4(300.59,87.3) ; v4(286.83,79.65) 287.17,79.99 v7(287.21,79.99)
  GND3 w0.076: v8(287.61,80.13) 287.47,79.99 v7(287.21,79.99)
  BOTTOM w0.076: v2(301.65,84.79) 300.85,85.58 v1(300.53,85.58)
SYS_PWROK: length 305.2
  TOP w0.076: v5(167.88,15.8) 167.83,15.75 167.69,15.75 166.95,15.02 166.95,14.87 162.88,10.8 138.34,10.8 135.44,13.7 125.99,13.7 123.63,16.05 123.63,19.71 120.75,22.6 115.73,22.6 113.93,20.79 v5(113.93,20.55)
  IN1 w0.076: v5(167.88,15.8) 167.92,15.8 168.2,16.08 v4(168.33,16.08) ; v5(113.93,20.55) 114.17,20.55 114.26,20.46 114.65,20.46 114.82,20.29 114.82,20.26 v4(114.89,20.19)
  IN2 w0.076: v4(290.57,60.43) 291.06,60.91 291.06,71.51 290.46,72.1 290.46,78.61 291.48,79.62 291.48,81.61 291.11,81.98 v4(291.11,82.67)
  IN3 w0.076: v4(168.33,16.08) 168.33,15.96 168.27,15.91 168.27,12.46 174.72,6.01 182.18,6.01 182.54,6.37 192.26,6.37 v4(192.4,6.52) 193.21,6.52 193.23,6.5 197.41,6.5 197.66,6.26 199.92,6.26 200.93,7.27 201.4,7.27 209,7.27 209.79,6.48 213.92,6.48 214.06,6.34 216.92,6.34 217.3,6.72 226.97,6.72 230.12,9.87 246.84,9.87 249.81,6.9 261.35,6.9 261.57,6.68 267.39,6.68 268.16,5.9 284.61,5.9 285.96,7.26 285.96,8.87 288.4,11.31 290.56,11.31 292.24,12.99 293.55,12.99 295.08,14.52 295.08,15.68 296.67,17.26 296.67,17.68 297.16,18.17 297.16,19.68 298.89,21.41 298.89,46.32 296.64,48.57 295.97,48.57 295.67,48.27 295.26,48.27 294.95,48.57 294.95,51.29 293.86,52.39 293.86,53.15 290.57,56.43 v4(290.57,60.43)
  IN4 w0.076: v4(192.4,6.52) 192.33,6.6 v1(192.07,6.6) ; v4(114.89,20.19) 114.72,20.19 v1(114.49,19.96) ; v1(291.11,83.13) v4(291.11,82.67)
  BOTTOM w0.076: R16.1 195.11,4.48 194.57,5.01 194.57,5.43 194.38,5.62 192.44,5.62 192.07,5.99 v1(192.07,6.6) ; UCPU1.A22 126.66,18.6 126.25,19.02 126.25,20.07 125.32,21 125.32,21.25 125.24,21.33 123.23,21.33 122.95,21.05 v6(122.95,20.92) 122.95,20.85 122.79,20.7 118.54,20.7 118.28,20.96 116.55,20.96 115.39,19.8 114.63,19.8 114.49,19.94 v1(114.49,19.96)
SYS_PWROK_XDP: length 8.3
  TOP w0.076: v3(193.06,5.22) 193.14,5.22 193.61,4.75 194.24,4.75 194.37,4.63 194.92,4.63 195.16,4.39 JXDP1.47
  BOTTOM w0.076: v3(193.06,5.22) 193,5.16 193,4.98 192.68,4.66 192.68,4.06 193,3.74 193,3.52 C2.1 ; C2.1 R14.1 R16.2 ; C2.1 v2(193.08,2.34)
SYS_RESET#: length 35.4
  IN4 w0.076: v1(128.63,16.87) 128.47,16.87 128.23,16.63 127.95,16.63 127.8,16.48 127.22,16.48 127.14,16.4 126.3,16.4 126.01,16.69 121.31,16.69 119.31,14.7 115.49,14.7 115.44,14.65 113.89,14.65 113.07,13.83 107.81,13.83 107.54,13.57 107.54,13.05 107.26,12.77 103.67,12.77 102.65,13.79 99.77,13.79 99.75,13.81 v1(99.65,13.81)
  BOTTOM w0.076: v2(100.98,12.01) 100.56,12.01 100.53,12.03 RH63.2 100.57,12.54 100.57,13.23 100.48,13.31 RP8.8 99.74,13.31 99.63,13.43 99.63,13.79 v1(99.65,13.81)
SYSCLK: length 14.8
  IN4 w0.076: v1(57.19,8.27) 56.27,9.19 56.27,11.63 v1(56.45,11.8)
  BOTTOM w0.076: v1(56.45,11.8) 55.88,12.37 55.88,16.2 55.5,16.58 JNGFF2.38 ; U53.A3 55.67,4.98 v2(56.45,5.76) 57.19,6.49 v1(57.19,8.27)
TD_IREF: length 10.5
  IN2 w0.381: v4(122.5,12.88) 123.53,12.88 124.63,11.78 125.08,11.78 126.55,10.31 127.91,10.31 128.18,10.58 129.14,10.58 130.05,11.49 130.41,11.49 130.44,11.52 130.5,11.52 v4(130.55,11.57)
  IN4 w0.254: v1(122.21,12.54) 122.5,12.83 v4(122.5,12.88) ; v4(130.55,11.57) 130.55,11.52 130.41,11.38 v1(130.23,11.38)
TESTLOW1: length 86.3
  IN1 w0.076: v4(105.42,30.23) 105.03,30.23 104.6,30.66 95.28,30.66 v4(94.95,31)
  IN2 w0.076: v4(135.06,14.24) 135.06,14.18 134.63,13.75 134.63,11.86 131.32,8.55 128.52,8.55 127.73,9.35 125.68,9.35 124.52,10.51 123.48,10.51 122.76,11.22 122.32,11.22 122.17,11.38 121.29,11.38 119.73,12.93 116.31,12.93 115.51,13.73 114.39,13.73 114.28,13.63 113.6,13.63 112.92,14.32 108.05,14.32 107.59,14.78 105.89,14.78 105.43,14.32 104.2,14.32 104.19,14.32 103.72,14.32 103.06,14.32 102.17,15.21 100.39,15.21 100.1,15.5 100.1,16.68 96.89,19.89 96.89,23.26 97.65,24.02 97.65,25.79 95.99,27.45 95.71,27.45 v4(93.18,29.98)
  IN3 w0.076: v4(93.18,29.98) 93.93,29.98 v4(94.95,31)
  IN4 w0.076: v4(105.42,30.23) 105.2,30.23 v1(105.03,30.41) ; v4(135.06,14.24) 134.96,14.14 134.29,14.14 v1(133.95,13.8)
  BOTTOM w0.076: RH170.1 114.29,30.85 v2(113.57,31.56) 105.18,31.56 105.03,31.41 v1(105.03,30.41)
TESTLOW2: length 58.9
  IN2 w0.076: v4(135.06,13.4) 135.06,13.35 134.86,13.15 134.86,11.87 131.38,8.4 128.36,8.4 127.56,9.2 125.62,9.2 124.46,10.36 123.42,10.36 123.33,10.44 122.17,10.44 121.93,10.69 121.51,10.69 119.61,12.59 116.22,12.59 116.2,12.62 116.18,12.62 115.36,13.43 114.51,13.43 114.41,13.33 113.47,13.33 112.79,14.01 107.93,14.01 107.47,14.47 106.02,14.47 105.56,14.01 104.32,14.01 104.32,14.01 103.59,14.01 103.59,14.01 102.93,14.01 102.04,14.9 100.26,14.9 99.79,15.37 99.79,16.46 96.45,19.8 96.45,23.63 v4(97.1,24.27)
  IN4 w0.076: v1(101.08,26.26) 98.96,26.26 97.1,24.4 v4(97.1,24.27) ; v4(135.06,13.4) 135.04,13.38 134.94,13.38 134.56,13.76 v1(134.56,13.8)
  BOTTOM w0.076: v1(101.08,26.26) 101.08,26.69 100.61,27.16 v2(100.61,27.34)
TESTLOW3: length 27.7
  IN2 w0.076: v4(131.46,21.74) 131.25,21.95 130.96,21.95 130.21,22.7 130.21,22.97 130.15,23.03 129.96,23.22 127.76,23.22 122.93,28.05 116.82,28.05 115.62,26.84 115.62,26.02 115.23,25.63 114.73,25.63 114.73,25.63 114.41,25.63 114.08,25.3 113.66,25.3 113.45,25.52 113.45,25.96 v4(113.46,25.97)
  IN4 w0.076: v1(113.02,26.13) 113.3,26.13 v4(113.46,25.97) ; v4(131.46,21.74) 131.45,21.74 131.39,21.68 131.17,21.68 130.79,22.07 v1(130.63,22.07)
  BOTTOM w0.076: v2(111.85,28.05) 112.71,28.05 113.38,27.37 113.38,26.5 v1(113.02,26.13)
TESTLOW4: length 26.8
  IN2 w0.076: v4(130,21.24) 129.85,21.24 129.83,21.23 129.39,21.23 128.58,22.03 128.18,22.03 122.85,27.36 118.4,27.36 118.09,27.05 118.09,25 117.87,24.78 113.4,24.78 112.94,25.24 v4(112.63,25.24)
  IN4 w0.076: v1(113.02,25.24) v4(112.63,25.24) ; v1(130.38,21.63) 130.22,21.63 130.11,21.52 130.11,21.35 v4(130,21.24)
  BOTTOM w0.076: v1(113.02,25.24) 113.13,25.24 113.62,25.74 113.62,27.64 v2(113.14,28.12)
THERMATRIP#: length 17.2
  IN4 w0.076: v1(297.83,75.21) 297.74,75.3 297.74,77.56 297.56,77.74 297.56,77.74 297.17,78.13 297.17,80.6 295.63,82.14 295.63,84.08 v1(295.55,84.15)
  BOTTOM w0.076: v1(295.55,84.15) 295.4,84.31 294.18,84.31 293.75,83.88 292.36,83.88 U38.B4 ; Q26.1 296.3,74.31 R233.2 C165.1 297.72,75.11 v1(297.83,75.21)
TON_1.35V: length 2.6
  BOTTOM w0.203: PU600.9 221.72,26.36
  BOTTOM w0.254: PR606.2 v2(221.91,26.18) 221.72,26.36
TP_A44: length 3.8
  BOTTOM w0.076: UCPU1.A44 127.62,10.38 126.54,9.3 126.54,7.83 126.2,7.49 T41.1
TP_C45: length 3.5
  BOTTOM w0.076: T42.1 126.81,7.53 127.12,7.85 127.12,9.21 128.05,10.13 UCPU1.C45
TP_D2: length 4.8
  BOTTOM w0.076: T43.1 126.4,25.98 127.27,25.12 UCPU1.D2
TP_D44_C43: length 0.5
  BOTTOM w0.076: UCPU1.C43 128.32,10.38 UCPU1.D44
TP_F1: length 6.5
  BOTTOM w0.076: T45.1 125.87,29.41 126.64,28.63 126.64,28.52 126.71,28.45 126.71,25.91 127.19,25.43 128.87,25.43 UCPU1.F1
TP_F3_H2: length 0.6
  BOTTOM w0.076: UCPU1.F3 128.93,24.9 129.15,25.12 UCPU1.H2
TP_F45_F43: length 0.5
  BOTTOM w0.076: UCPU1.F45 UCPU1.F43
TP_H44: length 4.5
  BOTTOM w0.076: T44.1 127.46,9.03 128.28,9.85 129.04,9.85 129.2,10 129.2,10.22 UCPU1.H44
TP_INT#: length 341.8
  TOP w0.076: v5(170.63,15.27) 170.36,15 170.18,15 169.43,14.25 169.43,12.71 164.13,7.41 137.34,7.41 133.72,11.03 131,11.03 130.73,11.3 128.14,11.3 128.08,11.23 124.67,11.23 122.27,13.63 116.75,13.63 113.16,17.22 109.76,17.22 109.64,17.34 107.34,17.34 v5(106.57,18.11) 105.67,19 v5(104.71,19)
  IN1 w0.076: v5(106.57,18.11) 106.66,18.02 v4(106.91,18.02) ; v4(294.78,42.14) 294.81,42.14 295.17,42.5 295.17,44.14 294.74,44.57 294.74,48.91 296,50.17 296,54.28 296.62,54.9 296.62,56.84 299.08,59.3 299.08,64.72 299.64,65.28 299.64,66.07 299.21,66.5 299.21,70.26 299.64,70.69 299.64,76.24 298.83,77.05 298.83,81.2 297.94,82.09 v3(296.96,82.09) ; v4(104.2,19) v5(104.71,19) ; v4(171.02,15.25) 170.91,15.35 170.68,15.35 170.63,15.3 v5(170.63,15.27)
  IN2 w0.076: v4(198.05,13.67) 198.28,13.44 199.86,13.44 200.22,13.09 202.37,13.09 202.61,12.84 211.72,12.84 214.25,10.32 225.22,10.32 226.26,9.28 246.36,9.28 246.78,8.85 260.15,8.85 260.93,8.07 267.8,8.07 269.4,9.67 272.45,9.67 272.51,9.61 285.06,9.61 286.31,8.36 289.28,8.36 292.01,11.09 292.01,11.98 292.85,12.82 293.32,12.82 294.1,13.6 294.1,16.12 293.93,16.29 293.93,18.02 295.54,19.63 295.54,21.71 295.62,21.79 295.62,41.56 295.04,42.14 v4(294.78,42.14)
  IN3 w0.076: v3(99.5,7.12) 99.5,8.43 102.19,11.12 102.19,15.49 101.93,15.76 101.93,16.02 102.11,16.21 102.25,16.21 102.89,16.85 102.89,18.55 103.39,19.04 104.16,19.04 v4(104.2,19)
  IN4 w0.076: v1(114.85,11.28) 114.85,11.32 115.11,11.59 116.41,11.59 116.57,11.44 117.8,11.44 118.59,12.22 120.07,12.22 120.77,12.92 121.1,12.92 121.86,13.68 122.99,13.68 123.79,12.88 124.38,12.88 124.9,12.36 126.02,12.36 126.39,12.73 127.88,12.73 127.88,12.73 128.33,12.73 128.58,12.98 128.8,12.98 129.03,13.21 129.98,13.21 130.05,13.15 130.22,13.15 130.39,13.32 130.39,13.5 130.39,13.51 130.53,13.65 130.88,13.65 131.04,13.81 131.04,14.42 131.13,14.51 131.13,15.47 130.84,15.75 130.59,15.75 130.53,15.81 130.26,15.81 130.03,15.58 130.03,15.24 v1(130.13,15.14) ; v4(106.91,18.02) 107.15,18.02 107.53,18.39 107.84,18.39 107.9,18.46 v1(108.5,18.46) ; v4(171.02,15.25) 172.34,15.25 172.73,14.85 176.3,14.85 176.96,15.51 178.59,15.51 178.84,15.26 178.84,14.36 179.77,13.43 181.46,13.43 181.81,13.08 187.34,13.08 187.7,12.72 196.32,12.72 196.65,13.05 197.44,13.05 v4(198.05,13.67)
  BOTTOM w0.076: v3(296.96,82.09) 295.08,82.09 294.88,81.88 293.43,81.88 293.36,81.95 293.36,82.38 U38.E2 ; v1(108.5,18.46) 108.5,18.25 109.26,17.5 v2(111.85,17.5) 112.8,17.5 113.04,17.25 113.04,16.08 113.45,15.68 115.11,15.68 115.33,15.46 115.33,15.39 116.47,14.25 116.47,13.48 116.18,13.19 116.18,11.83 115.97,11.63 115.11,11.63 114.85,11.36 v1(114.85,11.28) RP1.6 ; JIO1.34 99.9,6.72 v3(99.5,7.12)
TPM_DET: length 65.3
  TOP w0.076: v5(95.11,11.05) 95.11,13.81 93.62,15.3 v5(93.61,15.3)
  IN1 w0.076: v5(93.61,15.3) 93.47,15.44 v4(93.18,15.44) ; v4(131.74,17.65) 131.74,17.26 132.49,16.51 132.49,14.75 131.85,14.1 131.85,13.61 131.61,13.37 131.1,13.37 130.38,12.64 124.8,12.64 124.02,11.86 122.8,11.86 122.05,12.62 116.9,12.62 116.05,13.47 114.47,13.47 114.35,13.34 111.21,13.34 108.86,10.99 107.78,10.99 106.83,10.04 105.95,10.04 105.26,10.73 105.26,11.34 104.95,11.65 102.13,11.65 101.38,10.9 95.27,10.9 95.12,11.05 v5(95.11,11.05)
  IN4 w0.076: v1(92.73,15.44) v4(93.18,15.44) ; v1(131.81,17.19) 131.81,17.57 v4(131.74,17.65)
  BOTTOM w0.076: v1(131.81,17.19) 131.74,17.11 131.53,17.11 131.48,17.06 131.28,17.06 131.23,17.11 131.03,17.11 130.98,17.06 130.78,17.06 130.54,17.3 UCPU1.M25 ; v1(92.73,15.44) 92.72,15.45 92.72,19.86 92.99,20.12 95.32,20.12 96,20.79 RH129.2 RH132.1 96,22.24 95.53,22.71 94.35,22.71 v2(94.03,22.4)
TPM_IRQ#: length 146.5
  TOP w0.076: v5(115.16,13.09) 115.82,13.09 116.04,12.87 121.77,12.87 124.61,10.03 126.03,10.03 126.1,10.1 129.63,10.1 130.06,9.67 131.91,9.67 132.51,10.26 133.36,10.26 137.04,6.58 164.43,6.58 170.84,12.98 v5(170.84,13.3)
  IN1 w0.076: v4(114.68,13.08) 114.68,13.08 115.15,13.08 v5(115.16,13.09) ; v4(171.18,13.45) 171.03,13.3 v5(170.84,13.3)
  IN3 w0.076: v4(229.02,12.26) 229.02,11.94 226.02,8.95 210.42,8.95 209.91,9.45 199.91,9.45 199.77,9.59 192.46,9.59 192.04,9.17 188.27,9.17 187.99,9.45 184.39,9.45 184.25,9.59 182.5,9.59 181.68,10.41 181.31,10.41 180.65,9.75 179.82,9.75 179.16,10.41 173.71,10.41 171.18,12.93 v4(171.18,13.45)
  IN4 w0.076: v4(114.68,13.08) 114.67,13.1 v1(114.22,13.1) ; v4(229.02,12.26) 230.21,13.45 233.74,13.45 234.55,14.26 234.55,18.4 233.91,19.04 232.74,19.04 231.64,20.13 v1(231.64,20.18)
  BOTTOM w0.076: v1(231.64,20.18) U21.20 231.64,18.1 231.14,17.59 v2(231.14,17.11) ; v1(114.22,13.1) 114.03,13.1 113.76,12.83 113.76,10.77 113.52,10.53 RC50.1
TPM_IRQ#_R: length 20.4
  IN4 w0.076: v1(114.22,12.75) 114.24,12.73 114.79,12.73 115.34,13.28 116.61,13.28 116.64,13.3 119.64,13.3 121.17,14.84 123.43,14.84 123.61,14.66 126.11,14.66 126.83,13.95 127.37,13.95 127.71,14.29 127.79,14.29 127.89,14.39 128.72,14.39 128.88,14.55 v1(128.88,14.71)
  BOTTOM w0.076: v1(114.22,12.75) 114.22,11.47 114.35,11.34 RP1.5 114.35,10.15 113.82,9.62 RC50.2
TPM_SPI_CLK: length 20.7
  IN4 w0.066: v1(220.62,12.8) 220.62,13.21 222.66,15.25 222.66,16.73 223.43,17.5 226.17,17.5 226.88,18.21 228.25,18.21 228.62,18.59 230.54,18.59 v1(230.99,19.04)
  BOTTOM w0.097: v1(220.62,12.8) 220.62,12.72 220.05,12.14 219.34,12.14 219.23,12.04 v2(218.07,12.04) 214.89,12.04 214.65,11.8 RP11.4
TPM_SPI_SI: length 20.2
  IN4 w0.066: v1(229.69,19.04) 228.44,19.04 228.07,18.66 226.7,18.66 226.01,17.97 223.27,17.97 222.21,16.91 222.21,15.49 219.95,13.23 v1(219.95,12.74)
  BOTTOM w0.097: RP11.3 214.15,12.38 214.29,12.51 218.82,12.51 219.05,12.74 v2(219.3,12.74) v1(219.95,12.74)
TPM_SPI_SO: length 20.4
  IN4 w0.066: v1(213.07,12.96) 213.45,12.58 218.93,12.58 222.02,15.66 222.02,16.99 223.21,18.19 225.95,18.19 226.8,19.04 v1(227.74,19.04)
  BOTTOM w0.097: v2(212.6,12.96) v1(213.07,12.96) 213.65,12.37 213.65,12.21 213.65,12.21 RP11.2
TS_EN: length 242.3
  IN3 w0.076: v4(298.57,18.39) 299.32,17.63 299.32,16.42 297.4,14.5 297.05,14.5 293.49,10.94 293.16,10.94 286.05,3.83 261.68,3.83 260.64,4.87 244.47,4.87 243.82,5.52 237.39,5.52 237.23,5.68 233.33,5.68 231.39,3.74 206.04,3.74 205.79,3.48 202.21,3.48 201.76,3.04 165.71,3.04 163.63,5.12 163.63,7.13 161.23,9.53 153.64,9.53 153.12,9.01 145.09,9.01 144.36,8.27 143.71,8.27 142.94,8.27 142.68,8.02 139.66,8.02 139.1,8.58 138.5,8.58 137.92,8.58 136.84,9.66 133.2,9.66 132.54,9 130.4,9 130.29,9.11 130.29,9.7 130.01,9.97 130,9.97 129.82,10.16 129.82,10.17 129.22,10.76 129.22,11.57 v4(129.74,12.09)
  IN4 w0.076: v1(128.93,12.13) 128.97,12.17 129.66,12.17 v4(129.74,12.09) ; v4(298.57,18.39) 298.89,18.71 298.89,19.97 298.69,20.16 298.69,34.35 299.2,34.86 299.2,48.02 296.11,51.11 294.59,51.11 293.51,52.19 293.51,53.24 293.13,53.62 293.13,55.8 292.94,56 292.94,58.2 v1(292.78,58.35)
  BOTTOM w0.076: U27.3 299.01,59.29 298.74,59.02 298.74,58.59 R158.2 299.1,58.21 298.69,57.8 298.69,57.12 298.47,56.9 296.47,56.9 296.04,56.48 294.66,56.48 v1(292.78,58.35)
TS_GPIO: length 53.9
  IN1 w0.076: v4(299.45,51.62) 300,52.17 300,54.6 300.14,54.73 301.19,55.78 301.19,85.12 301.73,85.66 301.73,87.69 v3(301.92,87.88)
  IN4 w0.076: v4(299.45,51.62) 299.57,51.5 v1(299.57,51.1)
  BOTTOM w0.076: v1(299.57,51.1) 299.86,51.1 299.96,51.2 U60.4 299.96,53.02 R371.2 ; MD1.4 302.48,88.79 301.92,88.23 v3(301.92,87.88) 302.2,87.88 302.63,88.31 304.14,88.31 304.95,87.49 307.53,87.49 308.1,88.07 JTS1.7 308.1,90.8 R35.1 308.53,91.23 308.53,92.72 R337.1
TS_INT#: length 325.9
  TOP w0.076: v3(305.94,92.32) 284.72,92.32 v3(283.58,91.18) ; v5(112.29,11.74) 113.03,11.74 113.83,10.95 121.03,10.95 124.11,7.87 133.62,7.87 136.51,4.97 152.51,4.97 152.77,4.71 166.15,4.71 166.41,4.97 166.44,4.97 171.65,10.19 172.2,10.19 175.1,13.09 175.1,13.85 v3(175.08,13.87)
  IN1 w0.076: v4(112.06,11.46) 112.06,11.47 112.29,11.7 v5(112.29,11.74)
  IN3 w0.076: v3(283.58,91.18) 283.65,91.1 283.65,91.09 283.97,90.77 283.97,86.19 282.88,85.1 282.88,79.14 282.52,78.78 282.52,60.72 292.53,50.71 292.53,48.7 293.07,48.17 293.07,47.82 296.65,44.25 296.65,21.83 291.46,16.64 290.51,16.64 288.29,14.42 287.13,14.42 286.26,13.55 285.5,13.55 285.34,13.38 284.23,13.38 283.31,12.45 282.5,12.45 281.26,11.22 273.53,11.22 272.24,12.51 268.88,12.51 267.22,10.86 250.92,10.86 247.68,14.1 237.32,14.1 236.81,14.6 232.83,14.6 232.28,15.15 228.02,15.15 226.9,14.03 226.9,13.28 224.27,10.66 214.1,10.66 213.66,11.1 200.64,11.1 199.65,12.09 192.41,12.09 191.3,10.97 189.02,10.97 188.65,11.33 188.4,11.33 187.42,11.33 187.41,11.33 185.05,11.33 184.66,11.72 184.34,11.72 183.21,12.84 175.7,12.84 175.08,13.47 v3(175.08,13.87)
  IN4 w0.076: v1(111.21,10.94) 111.54,10.94 v4(112.06,11.46) 112.19,11.6 112.82,11.6 113.57,12.35 114.84,12.35 115.39,12.9 116.66,12.9 116.77,13 119.77,13 121.21,14.45 123.31,14.45 123.85,13.91 123.85,13.91 124.11,13.64 127.5,13.64 127.84,13.98 127.92,13.98 128.02,14.08 128.48,14.08 128.72,13.84 v1(128.88,13.84)
  BOTTOM w0.076: v3(305.94,92.32) 306.36,91.9 R41.1 ; v3(305.94,92.32) 306.93,92.32 v2(307.24,92.63) ; v3(305.94,92.32) 306.36,92.74 Q5.1 ; v1(111.21,10.94) RH119.1
TS_INT#_R: length 17.6
  IN4 w0.076: v1(301.6,87.52) 301.6,87.5 301.74,87.35 305.55,87.35 v1(307.1,88.9)
  BOTTOM w0.076: v2(306.55,96.03) 307.01,95.57 Q5.3 307.01,93.39 307.68,92.72 307.68,90.99 307.52,90.82 R40.2 R41.2 307.1,90.08 v1(307.1,88.9) ; MD1.6 300.58,88.63 301.6,87.62 v1(301.6,87.52)
TS_RST#: length 255
  IN1 w0.076: v4(300.77,63.67) 300.61,63.5 300.61,58.67 299.83,57.9 299.83,55.1 299.5,54.77 v4(299.5,54.74) 299.25,54.49 299.25,53.85 298.99,53.59 v4(298.99,49.73)
  IN3 w0.076: v4(298.99,49.73) 299.69,49.03 299.69,20.06 298.1,18.46 298.1,18.14 298.27,17.96 298.27,15.95 293.56,11.24 292.99,11.24 285.73,3.98 261.74,3.98 260.69,5.03 244.52,5.03 243.88,5.68 237.69,5.68 237.39,5.99 233.21,5.99 231.11,3.89 205.98,3.89 205.72,3.64 202.21,3.64 201.94,3.91 198.21,3.91 197.49,3.19 165.77,3.19 163.93,5.03 163.93,7.2 161.36,9.77 153.45,9.77 152.99,9.31 144.97,9.31 144.23,8.58 143.03,8.58 142.63,8.18 139.72,8.18 139.53,8.37 139.53,8.53 139.18,8.88 138.38,8.88 138.05,8.88 136.92,10.01 132.81,10.01 132.51,9.71 130.81,9.71 130.64,9.54 130.62,9.54 v4(130.61,9.53)
  IN4 w0.076: v4(299.5,54.74) 299.6,54.64 v1(299.6,54.26) ; v4(130.61,9.53) 130.61,9.79 130.93,10.11 130.93,10.27 130.66,10.54 v1(130.66,10.63) ; v4(300.77,63.67) 301.41,64.3 301.41,85.51 v1(301.74,85.84)
  BOTTOM w0.076: R371.1 299.8,54.06 v1(299.6,54.26)
TS_RST#_R: length 8.8
  IN4 w0.076: v1(302.96,86.69) 303.47,87.2 305.9,87.2 v1(307.6,88.9)
  BOTTOM w0.076: v2(303.19,87.53) 302.09,87.53 301.74,87.18 R388.2 301.81,86.69 v1(302.96,86.69)
TX_BLANKING: length 2.6
  TOP w0.076: T40.1 56.42,18.46 v3(56.73,18.76)
  BOTTOM w0.076: JNGFF2.40 56,18.31 56.45,18.76 v3(56.73,18.76)
UAGTE: length 12.3
  IN4 w1.016: 182,28.97 181.14,28.11 181.14,25.66 183.06,23.74 185.18,23.74 186.45,22.47 186.45,22.37
  BOTTOM w0.102: v1(182.2,29.84) 182.2,29.65 181.62,29.06 181.18,29.06 v2(180.85,28.73)
  vias: v1(182.19,30.18) v1(186.76,21.35) v1(186.76,21.05)
UG_3V: length 7.7
  IN4 w1.016: 282.02,22.69 281.7,23.01 281.7,24.64 282.84,25.79 282.84,28.06
  BOTTOM w0.102: v2(281.93,23.81) 281.93,23.35 282.5,22.77 PQ300.2
  vias: v1(282.76,29.23) v1(282.76,28.9) v1(282.79,22.71) v1(283.09,22.71)
UG_5V: length 5.3
  IN1 w1.016: 278.34,27.87 278.34,22.63 278.33,22.62
  vias: v3(278.24,28.77) v3(278.32,21.61) v3(278.83,28.75) v3(278.85,21.91)
UIM_CLK: length 61.5
  IN3 w0.097: v3(52.08,15.95) 52.19,15.83 52.88,15.83 53.39,16.35 55.1,16.35 58.44,13.01 61.41,13.01 63.69,10.72 70.75,10.72 70.92,10.89 71.84,10.89 72.02,10.72 82.26,10.72 83.03,9.96 86.47,6.51 86.88,6.1 86.88,4.31 87.77,3.42 90.92,3.42 91.87,4.36 91.87,5.46 92.64,6.22 97.87,6.22 98.46,5.63 98.46,5.2 v3(98.42,5.16)
  BOTTOM w0.097: JIO1.53 95.9,2.99 96.04,3.12 96.04,3.48 96.91,4.36 97.62,4.36 v3(98.42,5.16) ; JNGFF2.24 52,16.03 v3(52.08,15.95)
UIM_DATA: length 57.2
  IN3 w0.097: v3(96.64,7.25) 96.2,7.25 95.72,6.77 92.62,6.77 91.47,5.62 91.47,4.53 90.75,3.82 87.94,3.82 87.28,4.48 87.28,6.27 86.76,6.79 82.43,11.13 72.18,11.13 72.01,11.3 70.62,11.3 70.45,11.13 63.86,11.13 61.58,13.41 58.61,13.41 55.16,16.86 53.3,16.86 52.69,16.24 v3(52.58,16.24)
  BOTTOM w0.097: v3(96.64,7.25) 96.67,7.28 98.37,7.28 99.1,6.55 JIO1.38 ; JNGFF2.26 52.5,16.33 v3(52.58,16.24)
UIM_DET: length 25.9
  IN2 w0.076: v3(46.39,11.87) 46.4,11.87 46.98,12.45 59.41,12.45 v3(59.57,12.61)
  BOTTOM w0.076: v3(59.57,12.61) 60.5,13.54 JNGFF2.58 ; v3(46.39,11.87) 45.97,12.29 41.97,12.29 41.74,12.06 Q46.1 41.1,11.53 R348.1
UIM_DET#: length 79.5
  IN2 w0.097: v3(46.37,12.45) 47.21,13.29 60.35,13.29 v4(61,12.65)
  IN3 w0.097: v3(99.4,4.27) 99.34,4.33 97.53,4.33 97.28,4.59 94.26,4.59 94.03,4.36 92.77,4.36 91.31,2.9 87.36,2.9 86.13,4.13 86.13,6.02 82.17,9.99 72.04,9.99 71.64,10.39 71.13,10.39 70.73,9.99 61.68,9.99 61.34,10.32 v4(61.22,10.32) 61.19,10.29 60.2,10.29 v3(58.66,8.76)
  IN4 w0.066: v4(61.22,10.32) 61.22,12.43 v4(61,12.65)
  BOTTOM w0.097: R70.2 57.69,7.79 v2(57.92,8.02) v3(58.66,8.76) ; v3(46.37,12.45) 46.1,12.72 42.05,12.72 40.8,13.96 Q46.2 40.45,11.27 R348.2 ; v3(99.4,4.27) 99.59,4.46 99.59,5.41 99.32,5.68 98.99,5.68 98.7,5.97 JIO1.40
UIM_RESET: length 63.7
  IN3 w0.097: v3(98.96,7.27) 98.95,7.27 98.33,7.89 98.33,9.39 95.55,12.18 94.41,12.18 94.13,12.47 92.18,12.47 90.78,11.07 84.95,11.07 78.9,17.11 71.03,17.11 67.94,14.02 58.75,14.02 55.18,17.59 52.08,17.59 51.08,16.59 51.08,14.57 v3(50.99,14.48)
  BOTTOM w0.097: v3(50.99,14.48) 51.08,14.57 51.08,16.31 51.5,16.73 JNGFF2.22 ; JIO1.36 99.5,6.56 98.99,7.06 98.99,7.23 v3(98.96,7.27)
USB3_MPHY_EN#: length 13.3
  IN4 w0.076: v1(89.98,11.36) 90.31,11.69 v1(90.31,11.73)
  BOTTOM w0.076: Q20.5 86.7,10.76 R184.2 ; v1(90.31,11.73) 89.98,12.06 89.98,13.61 90.32,13.95 Q22.2 ; v1(89.98,11.36) 89.98,11.02 89.72,10.76 Q21.1 88.45,10.76 88.25,10.56 R184.2 ; R184.2 86.9,9.59 v2(86.84,9.53) 84.75,9.53 84.47,9.81 84.47,10.66 84.36,10.76 Q20.2
USB3MPHY_PWREN: length 48.5
  IN4 w0.076: v1(129.63,15.14) 129.47,15.14 129.12,15.49 129.12,15.67 128.98,15.81 128.7,15.81 128.34,16.17 127.34,16.17 127.27,16.1 126.17,16.1 125.88,16.39 121.43,16.39 119.43,14.39 115.74,14.39 115.4,14.05 114.19,14.05 114.11,13.98 113.85,13.98 113.55,13.68 107.87,13.68 107.69,13.51 107.69,12.98 107.33,12.62 103.6,12.62 102.66,13.56 98.55,13.56 97.75,14.37 97.06,14.37 96.75,14.05 94.71,14.05 94.44,14.33 92.97,14.33 92.47,13.82 88.28,13.82 v1(88.26,13.84)
  BOTTOM w0.076: v1(88.26,13.84) 88.26,13.47 R186.1 87.32,12.53 87.32,11.68 v2(87.89,11.1)
USB3MPHY_PWREN_R: length 8.1
  BOTTOM w0.076: R188.2 R183.2 R189.1 ; v2(92.29,9.91) R189.1 ; R189.1 91.89,11.41 Q21.2 90.28,11.41 89.92,11.77 88.1,11.77 R186.2
USB3RN1: length 70.1
  IN4 w0.066: v1(136.73,11.13) 136.75,11.15 137.02,11.15 137.14,11.03 137.14,10.87 136.85,10.58 136.85,7.87 135.79,6.82 133.83,6.82 133.62,6.61 132.29,6.61 129.59,3.91 122.83,3.91 122.06,4.68 121.52,4.68 120.95,5.25 120.12,5.25 119.23,6.14 109.13,6.14 107.49,7.78 97.33,7.78 97.33,7.78 87.48,7.78 85.95,7.78 84.37,9.36 79.12,9.36 79.05,9.43 79.05,9.53 79.18,9.66 v1(79.18,9.67)
  BOTTOM w0.097: C236.2 78.67,12.91 79.02,12.91 79.25,12.69 v12(79.25,10.51) 79.25,10.22 79.11,10.08 79.11,9.74 v1(79.18,9.67)
USB3RN1_C: length 2.3
  BOTTOM w0.097: C236.1 77.35,13.25 77.07,12.97 76.97,12.97 76.87,13.08 76.87,13.7 76.69,13.88 76.57,13.88 76.42,14.03 U56.11
USB3RN1_RP: length 36.6
  IN3 w0.097: v3(88.16,4.91) 88.36,5.11 88.36,5.36 88.5,5.49 88.5,6.39 82.71,12.17 71.75,12.17 71.3,12.63 71.3,12.86 71.11,13.05 v3(71.09,13.05)
  IN4 w0.066: v3(88.16,4.91) 88.43,4.91 88.5,4.97 88.5,5.16 88.68,5.35 89.99,5.35 90.88,4.46 95.42,4.46 96.67,3.2 98.32,3.2 98.37,3.25 98.37,3.36 98.23,3.5 v1(98.19,3.5)
  BOTTOM w0.097: v3(71.09,13.05) 71.07,13.07 71.07,13.7 71.23,13.86 71.43,13.86 71.6,14.03 U56.20 ; v1(98.19,3.5) 98.19,3.35 98.03,3.19 98.03,3.03 97.9,2.89 JIO1.43
USB3RP1: length 70.1
  IN4 w0.066: v1(78.8,9.67) 78.92,9.56 78.92,9.38 79.06,9.23 84.31,9.23 85.89,7.65 87.54,7.65 97.27,7.65 97.27,7.65 107.44,7.65 109.08,6 119.17,6 120.07,5.11 120.9,5.11 121.46,4.54 122.01,4.54 122.77,3.78 129.65,3.78 132.35,6.48 133.68,6.48 133.89,6.69 135.85,6.69 136.98,7.82 136.98,10.52 137.27,10.81 137.27,11.07 137.35,11.14 137.58,11.14 v1(137.59,11.13)
  BOTTOM w0.097: v1(78.8,9.67) 78.92,9.78 78.92,10.16 79.03,10.28 79.03,10.84 79.05,10.86 79.05,12.6 78.94,12.72 78.55,12.72 C237.2
USB3RP1_C: length 2.3
  BOTTOM w0.097: U56.12 76.38,13.53 76.53,13.68 76.6,13.68 76.67,13.62 76.67,13 76.9,12.77 77,12.77 C237.1
USB3RP1_RP: length 36.9
  IN3 w0.097: v3(71.68,13.05) 71.47,12.84 71.47,12.7 71.83,12.35 82.79,12.35 88.67,6.46 88.67,5.42 88.54,5.29 88.54,4.82 88.64,4.72 88.9,4.72 v3(88.94,4.75)
  IN4 w0.066: v1(98.63,3.45) 98.51,3.33 98.51,3.2 98.38,3.07 96.61,3.07 95.36,4.32 90.83,4.32 89.93,5.22 88.74,5.22 88.63,5.11 88.63,4.96 88.85,4.74 88.92,4.74 v3(88.94,4.75)
  BOTTOM w0.097: U56.19 71.59,13.53 71.45,13.66 71.32,13.66 71.27,13.62 71.27,13.43 71.65,13.05 v3(71.68,13.05) ; v1(98.63,3.45) 98.58,3.45 98.23,3.1 98.23,3.03 98.3,2.96 JIO1.41
USB3TN1: length 64.5
  IN1 w0.066: v4(137.45,2.45) 137.28,2.62 137.28,3.01 137.14,3.16 135.04,3.16 133.91,2.02 114.13,2.02 113.39,2.77 112.3,2.77 112.19,2.67 111.92,2.67 v4(111.71,2.87)
  IN4 w0.066: v4(137.45,2.45) 137.26,2.26 137.26,2.14 137.38,2.02 145.22,2.02 147.07,3.87 148.51,3.87 149.33,4.69 149.33,6.45 149.07,6.71 148.92,6.71 148.18,7.45 147.55,7.45 144.45,10.55 144.45,11.07 144.38,11.15 144.26,11.15 144.17,11.06 v1(144.17,10.88) ; v1(99.55,3.79) 99.63,3.71 99.87,3.71 100.11,3.47 101.35,3.47 101.53,3.29 108.24,3.29 108.72,2.81 111.06,2.81 111.22,2.65 111.49,2.65 v4(111.71,2.87)
  BOTTOM w0.097: JIO1.37 99.1,2.96 99.24,3.1 99.24,3.28 99.4,3.45 99.4,3.64 v1(99.55,3.79)
USB3TP1: length 64.5
  IN1 w0.066: v4(111.71,2.34) 111.9,2.53 112.25,2.53 112.35,2.63 113.33,2.63 114.08,1.89 133.96,1.89 135.1,3.02 137.08,3.02 137.15,2.96 137.15,2.6 136.99,2.45 v4(136.92,2.45)
  IN4 w0.066: v1(99.68,3.45) 99.68,3.5 99.74,3.57 99.83,3.57 100.06,3.34 101.29,3.34 101.47,3.16 108.18,3.16 108.67,2.68 111.01,2.68 111.17,2.52 111.53,2.52 v4(111.71,2.34) ; v1(144.17,11.55) 144.17,11.36 144.24,11.28 144.43,11.28 144.59,11.13 144.59,10.61 147.61,7.59 148.12,7.59 148.12,7.59 148.23,7.59 148.97,6.85 149.12,6.85 149.46,6.51 149.46,4.64 148.56,3.74 147.13,3.74 145.27,1.88 137.32,1.88 137.12,2.08 137.12,2.24 v4(136.92,2.45)
  BOTTOM w0.097: JIO1.35 99.5,2.97 99.43,3.03 99.43,3.2 v1(99.68,3.45)
USB20_N0: length 79.3
  TOP w0.097: v5(89.69,22.06) 89.72,22.03 89.72,21.43 97.15,14.01 97.15,7.21 97.84,6.51 97.84,5.23 96.99,4.38 96.99,3.8 v3(96.8,3.61)
  IN1 w0.066: v5(89.69,22.06) 89.69,22.47 89.91,22.7 90.38,22.7 90.44,22.77 90.44,23.3 90.59,23.45 90.9,23.45 91.04,23.3 91.04,22.77 91.11,22.7 91.31,22.7 91.37,22.77 91.37,23.3 91.52,23.45 91.83,23.45 91.97,23.3 91.97,22.77 92.04,22.7 92.24,22.7 92.3,22.77 92.3,23.3 92.45,23.45 92.76,23.45 92.9,23.3 92.9,22.77 92.97,22.7 93.17,22.7 93.23,22.77 93.23,23.3 93.38,23.45 93.69,23.45 93.83,23.3 93.83,22.77 93.9,22.7 94.1,22.7 94.16,22.77 94.16,23.3 94.31,23.45 94.62,23.45 94.76,23.3 94.76,22.77 94.83,22.7 95.02,22.7 95.09,22.77 95.09,23.3 95.24,23.45 95.55,23.45 95.69,23.3 95.69,22.77 95.76,22.7 95.95,22.7 96.02,22.77 96.02,23.3 96.17,23.45 96.48,23.45 96.62,23.3 96.62,22.77 96.69,22.7 100.01,22.7 100.34,22.37 104.56,22.37 105.45,23.26 118.14,23.26 118.4,23 121.07,23 121.35,22.73 123.08,22.73 124.45,24.1 126.27,24.1 126.46,23.92 128.06,23.92 128.5,24.35 131.28,24.35 132.17,23.46 132.17,22.71 131.91,22.45 131.91,22.21 v4(131.91,22.21)
  IN4 w0.066: v4(131.91,22.21) 132.12,22.42 v1(132.36,22.42)
  BOTTOM w0.097: JIO1.49 96.7,2.93 96.8,3.03 96.8,3.2 96.98,3.38 96.98,3.43 v3(96.8,3.61)
USB20_N1: length 122.3
  IN1 w0.066: v4(131.02,23.59) 130.9,23.72 130.44,23.72 130.26,23.89 129.03,23.89 128.07,22.93 124.85,22.93 123.95,22.03 121.17,22.03 120.79,22.42 118.06,22.42 117.8,22.67 108.52,22.67 107.99,22.15 105.28,22.15 104.92,21.79 89.24,21.79 88.78,22.24 88.78,29.18 84.86,33.1 84.86,36.36 80.62,40.61 62.98,40.61 61.48,42.11 48.11,42.11 46.94,43.28 30.54,43.28 30.39,43.14 30.39,42.97 v3(30.17,42.75)
  IN4 w0.066: v4(131.02,23.59) 130.92,23.49 130.92,23.33 131.04,23.22 131.19,23.22 131.26,23.28 131.45,23.28 v1(131.53,23.37)
  BOTTOM w0.097: JDEBUG.2 27.76,42.4 27.91,42.55 28.97,42.55 29.58,43.16 v12(29.88,43.16) 30.15,43.16 30.3,43.01 30.3,42.88 v3(30.17,42.75)
USB20_N2: length 164.4
  IN1 w0.066: v4(201.84,14.43) 201.84,14.33 201.31,13.8 201.31,13.03 201.2,12.93 201.2,12.4 200.27,11.47 197.49,11.47 196.12,10.1 191.61,10.1 191.29,10.42 183.22,10.42 181.16,8.36 179.8,8.36 179.32,7.88 172.67,7.88 170.87,9.68 161.3,9.68 160.4,8.79 160.4,7.91 v4(160.01,7.51)
  IN3 w0.097: v4(133.16,23.08) 132.85,23.38 132.58,23.38 131.48,24.48 129.44,24.48 125.53,20.58 124.76,20.58 120.66,16.47 120.66,8.39 125.7,3.34 130.17,3.34 130.78,3.95 134.07,3.95 134.33,3.69 135.58,3.69 136.04,4.15 136.45,4.15 136.92,3.67 138.43,3.67 138.77,3.33 144.09,3.33 147.05,6.29 153.46,6.29 153.75,6 159.31,6 160.36,7.05 160.36,7.16 v4(160.01,7.51)
  IN4 w0.066: v4(133.16,23.08) 133.12,23.12 v1(132.83,23.12) ; v4(201.84,14.43) 201.84,14.29 201.74,14.19 201.59,14.19 201.46,14.32 201.46,15.3 201.98,15.82 201.98,33.4 197.32,38.07 197.32,38.6 196.03,39.89 196.03,52.83 196.45,53.25 197.23,53.25 197.92,53.93 199.02,53.93 199.17,54.08 199.17,54.17 199.57,54.57 v1(199.57,54.63)
  BOTTOM w0.097: v1(199.57,54.63) 199.57,54.54 199.68,54.43 R139.1
USB20_N2_R: length 12.2
  IN4 w0.066: v1(204.43,49.25) 204.26,49.09 199.11,49.09 198.87,49.32 198.87,49.33 198.56,49.64 198.56,49.95 198.9,50.29 v1(199.36,50.29)
  BOTTOM w0.097: R139.2 199.68,52.95 199.57,52.84 199.57,52.25 199.48,52.15 199.37,52.15 199.27,52.05 199.27,51.87 199.06,51.66 v12(198.77,51.66) 198.49,51.66 198.3,51.47 198.3,51.28 198.41,51.17 199.2,51.17 199.36,51.01 v1(199.36,50.29)
USB20_N4: length 162
  IN1 w0.066: v4(158.41,7.51) 158.8,7.91 158.8,8.75 160.34,10.29 171.16,10.29 172.99,8.46 179.08,8.46 179.34,8.72 179.34,10.34 179.7,10.7 182.18,10.7 182.49,11.01 191.54,11.01 191.85,10.7 195.82,10.7 197.25,12.13 199.62,12.13 199.98,12.48 199.98,13.8 200.17,14 200.43,14 200.85,14.42 v4(200.85,14.46)
  IN3 w0.097: v4(158.41,7.51) 158.62,7.3 158.62,7.05 158.34,6.77 155.81,6.77 155.61,6.98 146.44,6.98 143.47,4.01 139.02,4.01 138.7,4.33 137.22,4.33 136.66,4.88 135.66,4.88 135.14,4.36 134.59,4.36 134.34,4.61 130.48,4.61 129.9,4.03 126.3,4.03 122.53,7.8 122.53,8.87 121.33,10.06 121.33,16.16 124.18,19 125.22,19 126.68,20.47 126.68,20.8 129.83,23.94 131.34,23.94 131.94,23.35 131.94,23.1 132.32,22.73 132.5,22.73 132.6,22.63 132.6,22.47 132.78,22.29 132.78,22.17 v4(132.79,22.18)
  IN4 w0.066: v1(132.4,23.37) 132.27,23.24 132.27,23.18 132.45,23 132.45,22.93 132.6,22.78 132.6,22.48 132.79,22.29 v4(132.79,22.18) ; v1(197.54,54.65) 197.51,54.65 197.15,54.29 197.15,54.03 197,53.88 196.23,53.88 195.44,53.09 195.44,39.64 196.63,38.45 196.63,37.92 201.36,33.18 201.36,16.46 200.28,15.37 200.28,14.72 200.28,14.71 200.28,14.37 200.43,14.22 200.82,14.22 200.85,14.25 v4(200.85,14.46)
  BOTTOM w0.097: v1(197.54,54.65) 197.54,54.25 R22.1
USB20_N4_R: length 15.6
  IN4 w0.066: v1(197.54,52.75) 197.25,52.46 197.25,50.89 197,50.63 197,50.06 198.4,48.66 198.4,48.54 198.89,48.05 199.25,48.05 v1(199.36,47.94) 199.24,47.82 198.56,47.82 198.45,47.71 198.45,47.51 198.67,47.29 202.65,47.29 202.91,47.56 204.24,47.56 v1(204.43,47.75)
  BOTTOM w0.097: v1(199.36,47.94) 199.36,47.17 v2(198.89,46.7) ; v1(197.54,52.75) 197.54,53.12 R22.2
USB20_N5: length 116
  IN3 w0.097: v3(47.7,3.78) 47.45,4.03 47.45,5.06 46.96,5.54 46.96,7.02 48.14,8.2 48.14,18.03 49.36,19.25 50.52,19.25 v4(50.7,19.07)
  IN4 w0.066: v4(50.7,19.07) 50.86,19.23 53.36,19.23 54.77,17.83 82.92,17.83 83.49,17.26 89.38,17.26 89.52,17.4 92.8,17.4 93.01,17.62 93.01,19.22 94.09,20.3 95.35,20.3 95.88,20.83 95.88,23.89 95.22,24.56 95.22,26.07 97.73,28.59 102.94,28.59 104.15,27.37 106.82,27.37 107.34,27.89 109.08,27.89 109.35,27.62 110.24,27.62 110.24,27.62 123.93,27.62 124.56,26.99 127.95,26.99 128.3,27.34 130.31,27.34 131.04,26.6 131.04,24.16 131.13,24.08 131.13,23.93 131.43,23.63 131.47,23.63 131.48,23.62 v1(131.96,23.62)
  BOTTOM w0.097: R71.1 47.96,5.14 ML6.4 47.96,4.44 47.57,4.05 47.57,3.91 v3(47.7,3.78)
USB20_N5_R: length 4.5
  BOTTOM w0.097: JNGFF2.9 46.25,9.1 46.18,9.02 46.18,8.78 v12(47.23,7.73) 47.45,7.51 47.45,7.4 47.96,6.89 ML6.3 47.96,6.22 R71.2
USB20_N6: length 132.5
  IN1 w0.066: v3(38.92,46.79) 39.74,46.79 39.97,46.56 75.73,46.56 75.92,46.37 81.58,46.37 95.74,32.21 106.29,32.21 109.76,28.75 129.17,28.75 131.06,26.85 131.06,26.55 131.95,25.67 131.95,25.51 132.07,25.39 v4(132.12,25.39)
  IN3 w0.097: v3(28.03,34.76) 28.22,34.57 28.22,33.58 29.58,32.21 37.26,32.21 39.79,34.74 39.79,46.47 39.49,46.77 38.95,46.77 v3(38.92,46.79)
  IN4 w0.066: v4(132.12,25.39) 132.05,25.31 132.05,24.2 v1(131.96,24.12)
  BOTTOM w0.097: v3(28.03,34.76) 28.06,34.76 28.23,34.59 28.23,34.41 27.91,34.08 ML5.4 27.91,33.44 R62.1
USB20_N6_R: length 3.5
  BOTTOM w0.097: JNGFF1.5 28.75,30.18 28.9,30.33 28.9,30.54 28.26,31.19 28.26,31.42 27.91,31.77 ML5.3 27.91,32.36 R62.2
USB20_N7: length 282
  IN1 w0.066: v4(147.5,3.08) 147.5,2.33 148.39,1.44 202.42,1.44 203.82,2.84 241.97,2.84 243.65,4.52 262.38,4.52 264.04,2.87 284.93,2.87 293.63,11.57 293.63,11.87 296.38,14.61 296.38,18.97 298.92,21.5 298.92,48.99 298.36,49.54 298.36,54 298.47,54.1 298.47,56.1 298.65,56.29 298.72,56.29 v3(298.94,56.51)
  IN3 w0.097: v4(147.5,3.08) 147.5,2.61 147.32,2.43 138.5,2.43 138.09,2.84 135.01,2.84 134.68,2.51 124.47,2.51 119.82,7.16 119.82,16.86 124.48,21.52 125.29,21.52 129.11,25.34 130.65,25.34 131.2,25.9 132.46,25.9 132.86,25.5 v4(132.86,24.93)
  IN4 w0.066: v4(132.86,24.93) 132.86,24.92 132.73,24.78 132.73,24.22 v1(132.83,24.12)
  BOTTOM w0.097: JUSH1.19 284.75,52.29 284.9,52.44 284.9,57.17 286.81,59.08 288.94,59.08 292.15,55.87 296.35,55.87 296.59,56.11 v12(296.92,56.11) 297.96,56.11 298.16,56.3 298.74,56.3 v3(298.94,56.51)
USB20_P0: length 79.2
  TOP w0.097: v3(97.41,3.61) 97.19,3.83 97.19,4.29 98.04,5.14 98.04,6.59 97.34,7.29 97.34,14.09 89.92,21.51 89.92,21.91 89.96,21.95 89.96,21.96 v5(90.07,22.06)
  IN1 w0.066: v4(131.56,22.82) 131.56,22.57 131.66,22.47 131.73,22.47 131.78,22.52 131.8,22.52 132.04,22.76 132.04,23.4 131.22,24.22 128.55,24.22 128.12,23.78 126.4,23.78 126.22,23.97 124.51,23.97 123.13,22.59 121.29,22.59 121.02,22.87 118.34,22.87 118.08,23.12 105.5,23.12 104.61,22.24 100.28,22.24 99.95,22.57 96.63,22.57 96.49,22.71 96.49,23.25 96.42,23.31 96.22,23.31 96.16,23.25 96.16,22.71 96.01,22.57 95.7,22.57 95.56,22.71 95.56,23.25 95.49,23.31 95.29,23.31 95.23,23.25 95.23,22.71 95.08,22.57 94.77,22.57 94.63,22.71 94.63,23.25 94.56,23.31 94.36,23.31 94.3,23.25 94.3,22.71 94.15,22.57 93.84,22.57 93.7,22.71 93.7,23.25 93.63,23.31 93.43,23.31 93.37,23.25 93.37,22.71 93.22,22.57 92.91,22.57 92.77,22.71 92.77,23.25 92.7,23.31 92.5,23.31 92.44,23.25 92.44,22.71 92.29,22.57 91.98,22.57 91.84,22.71 91.84,23.25 91.77,23.31 91.57,23.31 91.51,23.25 91.51,22.71 91.36,22.57 91.05,22.57 90.91,22.71 90.91,23.25 90.84,23.31 90.64,23.31 90.58,23.25 90.58,22.71 90.43,22.57 89.97,22.57 89.82,22.42 89.82,22.31 v5(90.07,22.06)
  IN4 w0.066: v4(131.56,22.82) 131.56,22.67 131.68,22.55 131.81,22.55 v1(131.88,22.62)
  BOTTOM w0.097: JIO1.47 97.1,2.95 97,3.05 97,3.12 97.18,3.29 97.18,3.38 v3(97.41,3.61)
USB20_P1: length 122.7
  IN1 w0.066: v3(30.76,42.75) 30.53,42.98 30.53,43.08 30.59,43.15 46.88,43.15 48.05,41.97 61.42,41.97 62.92,40.47 80.56,40.47 84.72,36.31 84.72,33.05 88.65,29.12 88.65,22.19 89.18,21.65 104.97,21.65 105.33,22.01 108.05,22.01 108.57,22.54 117.75,22.54 118,22.28 120.73,22.28 121.12,21.9 124,21.9 124.9,22.8 128.12,22.8 129.09,23.76 130.19,23.76 130.59,23.36 v4(130.59,23.36)
  IN4 w0.066: v1(131.96,23.12) 131.95,23.13 131.33,23.13 131.28,23.08 130.97,23.08 130.69,23.36 v4(130.59,23.36)
  BOTTOM w0.097: JDEBUG.3 27.76,42.9 27.91,42.75 28.89,42.75 29.52,43.38 30.2,43.38 30.5,43.09 30.5,42.95 30.69,42.75 v3(30.76,42.75)
USB20_P2: length 164.5
  IN1 w0.066: v4(160.54,7.51) 160.54,8.73 161.35,9.54 170.81,9.54 172.61,7.74 179.38,7.74 179.86,8.22 181.21,8.22 183.28,10.29 191.24,10.29 191.56,9.97 196.17,9.97 197.54,11.34 200.33,11.34 201.34,12.34 201.34,12.87 201.44,12.98 201.44,13.74 201.52,13.82 v4(201.81,13.82)
  IN3 w0.097: v4(160.54,7.51) 160.54,6.98 159.38,5.82 153.68,5.82 153.39,6.11 147.12,6.11 144.17,3.15 138.7,3.15 138.36,3.49 136.85,3.49 136.37,3.97 136.11,3.97 135.66,3.51 134.26,3.51 134,3.78 130.86,3.78 130.25,3.17 125.63,3.17 120.48,8.32 120.48,16.55 124.69,20.76 125.46,20.76 129.37,24.66 131.55,24.66 132.65,23.56 v4(133.2,23.56)
  IN4 w0.066: v1(198.77,54.64) 198.77,54.54 199.04,54.27 199.04,54.14 198.97,54.07 197.86,54.07 197.18,53.38 196.39,53.38 195.9,52.89 195.9,39.83 197.18,38.54 197.18,38.01 201.85,33.35 201.85,15.88 201.32,15.35 201.32,14.26 201.53,14.06 201.57,14.06 201.8,13.82 v4(201.81,13.82) ; v4(133.2,23.56) 133.14,23.62 v1(132.83,23.62)
  BOTTOM w0.097: v1(198.77,54.64) 198.77,54.54 198.66,54.43 R138.1
USB20_P2_R: length 12.3
  IN4 w0.066: v1(204.43,48.75) 204.23,48.95 199.05,48.95 198.49,49.52 198.49,49.52 198.43,49.58 198.43,49.95 198.35,50.03 197.72,50.03 v1(197.46,50.29)
  BOTTOM w0.097: R138.2 198.66,52.95 198.77,52.84 198.77,52.25 198.87,52.15 198.98,52.15 199.07,52.05 199.07,51.96 198.98,51.86 198.41,51.86 198.11,51.55 198.11,51.22 198.04,51.15 197.57,51.15 197.46,51.04 v1(197.46,50.29)
USB20_P4: length 162.2
  IN1 w0.066: v4(200.82,13.87) 200.81,13.86 200.23,13.86 200.11,13.75 200.11,12.43 199.68,11.99 197.31,11.99 195.88,10.56 191.8,10.56 191.49,10.87 182.54,10.87 182.24,10.56 179.76,10.56 179.47,10.28 179.47,8.66 179.14,8.32 172.93,8.32 171.11,10.15 160.4,10.15 158.94,8.69 v4(158.94,7.51)
  IN3 w0.097: v4(158.94,7.51) 158.8,7.37 158.8,6.98 158.42,6.6 155.74,6.6 155.54,6.8 146.52,6.8 143.54,3.83 138.95,3.83 138.63,4.15 137.14,4.15 136.59,4.7 135.74,4.7 135.21,4.18 134.51,4.18 134.26,4.44 130.55,4.44 129.97,3.85 126.23,3.85 122.35,7.73 122.35,8.79 121.16,9.99 121.16,16.23 124.1,19.18 125.14,19.18 126.5,20.54 126.5,20.87 129.75,24.12 131.42,24.12 132.12,23.42 132.12,23.18 132.39,22.9 132.57,22.9 132.82,22.65 v4(132.93,22.65)
  IN4 w0.066: v4(132.93,22.65) 132.91,22.65 132.58,22.98 132.58,23.21 132.64,23.27 132.64,23.47 132.4,23.71 v1(132.4,23.87) ; v4(200.82,13.87) 200.82,13.89 200.63,14.08 200.37,14.08 200.15,14.31 200.15,14.66 200.14,14.66 200.14,15.43 201.23,16.51 201.23,33.13 196.5,37.86 196.5,38.39 195.3,39.59 195.3,53.15 196.17,54.01 196.94,54.01 197.01,54.08 197.01,54.26 196.74,54.54 v1(196.74,54.65)
  BOTTOM w0.097: R20.1 196.74,54.25 v1(196.74,54.65)
USB20_P4_R: length 15.4
  IN4 w0.066: v1(196.74,52.74) 197.11,52.36 197.11,50.94 196.86,50.69 196.86,50 198.26,48.6 198.26,48.5 197.81,48.05 197.57,48.05 v1(197.46,47.94) 197.46,47.86 197.57,47.74 198.11,47.74 198.32,47.53 198.32,47.46 198.61,47.16 202.7,47.16 202.97,47.43 204.25,47.43 v1(204.43,47.25)
  BOTTOM w0.097: v1(196.74,52.74) 196.74,53.12 R20.2 ; v1(197.46,47.94) v2(196.28,47.94)
USB20_P5: length 115.6
  IN3 w0.097: v3(47.14,3.78) 47.27,3.91 47.27,4.99 46.78,5.47 46.78,7.09 47.97,8.27 47.97,18.1 49.29,19.42 50.52,19.42 v4(50.7,19.6)
  IN4 w0.066: v4(50.7,19.6) 50.93,19.37 53.42,19.37 54.82,17.97 82.98,17.97 83.54,17.4 89.32,17.4 89.46,17.54 92.74,17.54 92.88,17.68 92.88,19.28 94.04,20.43 95.29,20.43 95.75,20.89 95.75,23.84 95.08,24.5 95.08,26.13 97.68,28.72 102.99,28.72 104.21,27.51 106.76,27.51 107.28,28.03 109.13,28.03 109.41,27.75 110.19,27.75 110.19,27.76 123.99,27.76 124.62,27.13 127.89,27.13 128.24,27.48 130.36,27.48 131.18,26.66 131.18,24.22 v1(131.53,23.87)
  BOTTOM w0.097: v3(47.14,3.78) 47.37,4.01 47.37,4.16 47.11,4.42 ML6.1 47.11,5.14 R69.1
USB20_P5_R: length 4.4
  BOTTOM w0.097: R69.2 47.11,6.22 ML6.2 47.11,7 47.25,7.14 47.25,7.43 v12(46.18,8.5) 45.98,8.7 45.98,8.93 45.75,9.16 JNGFF2.7
USB20_P6: length 132.2
  IN1 w0.066: v3(38.92,46.21) 39.37,46.66 39.68,46.66 39.91,46.43 75.67,46.43 75.86,46.24 81.53,46.24 95.69,32.08 106.23,32.08 109.7,28.61 129.11,28.61 130.93,26.8 130.93,26.5 131.81,25.61 131.81,25.47 131.73,25.39 v4(131.52,25.39)
  IN3 w0.097: v3(28.61,34.76) 28.4,34.55 28.4,33.65 29.66,32.39 37.19,32.39 39.61,34.81 39.61,46.4 39.42,46.59 39.3,46.59 v3(38.92,46.21)
  IN4 w0.066: v4(131.52,25.39) 131.66,25.39 131.89,25.16 131.89,24.4 131.82,24.33 131.57,24.33 v1(131.53,24.37)
  BOTTOM w0.097: v3(28.61,34.76) 28.43,34.58 28.43,34.41 28.76,34.08 ML5.1 28.76,33.44 R60.1
USB20_P6_R: length 3.5
  BOTTOM w0.097: JNGFF1.3 29.25,30.07 29.1,30.22 29.1,30.63 28.45,31.27 28.45,31.42 28.76,31.72 ML5.2 28.76,32.36 R60.2
USB20_P7: length 281.6
  IN1 w0.066: v3(298.99,55.9) 298.99,56.02 298.86,56.15 298.7,56.15 298.6,56.05 298.6,54.04 298.5,53.94 298.5,49.6 299.05,49.05 299.05,21.45 296.52,18.91 296.52,14.55 293.77,11.81 293.77,11.52 284.98,2.73 263.98,2.73 262.33,4.38 243.71,4.38 242.03,2.7 203.88,2.7 202.48,1.3 148.34,1.3 147.36,2.28 147.36,2.74 147.02,3.08 v4(146.97,3.08)
  IN3 w0.097: v4(146.97,3.08) 147,3.08 147.32,2.76 147.32,2.68 147.24,2.6 138.57,2.6 138.16,3.01 134.94,3.01 134.61,2.68 124.55,2.68 120,7.23 120,16.78 124.56,21.34 125.36,21.34 129.18,25.16 130.72,25.16 131.27,25.72 132.39,25.72 132.68,25.42 132.68,25.22 132.42,24.96 v4(132.36,24.96)
  IN4 w0.066: v1(132.4,24.37) 132.45,24.31 132.52,24.31 132.59,24.38 132.59,24.78 132.41,24.96 v4(132.36,24.96)
  BOTTOM w0.097: v3(298.99,55.9) 298.79,56.11 298.24,56.11 298.04,55.91 297.17,55.91 297.15,55.89 296.65,55.89 296.43,55.67 292.07,55.67 288.85,58.88 286.89,58.88 285.1,57.09 285.1,52.36 284.95,52.21 284.95,51.49 285.25,51.19 JUSH1.18
USB_OC0#: length 26.3
  IN4 w0.076: v1(128.63,20.33) 128.59,20.3 127.45,20.3 127.25,20.49 127.25,20.64 127.11,20.78 125.32,20.78 124.69,20.15 120.92,20.15 120.73,19.96 117.95,19.96 117.45,19.96 117.45,19.96 117.32,19.96 115.59,18.22 114.08,18.22 113.54,17.69 112.29,17.69 v1(111.52,16.92)
  BOTTOM w0.076: T35.1 110.54,13.74 111.4,13.74 111.4,14.09 111.03,14.46 111.03,16.43 v1(111.52,16.92) 111.58,16.97 112.47,16.97 112.76,16.68 112.76,16.43 112.67,16.34 RP9.1
USB_OC1#: length 22.2
  IN4 w0.076: v1(112.19,15.1) 112.19,15.1 112.8,15.1 114.66,16.96 116.56,16.96 117.5,16.02 118.87,16.02 121.78,18.93 126.04,18.93 126.2,18.78 126.81,18.78 126.92,18.88 128.19,18.88 128.47,18.6 v1(128.63,18.6)
  BOTTOM w0.076: RP9.4 111.92,14.84 112.18,15.1 v1(112.19,15.1) 112.19,14.81 112.78,14.22 112.78,12.84 T36.1
USB_OC2#: length 20.4
  IN4 w0.076: v1(129.38,19.04) 129.22,19.04 128.98,19.28 128.7,19.28 128.5,19.47 128.23,19.47 128.11,19.35 127.8,19.35 127.21,19.35 126.87,19.69 126.66,19.69 126.63,19.72 126.38,19.72 126.37,19.72 126.08,19.72 125.75,19.39 121.23,19.39 121.04,19.19 117.64,19.19 115.88,17.43 114.39,17.43 113.75,16.79 112.85,15.89 v1(112.76,15.89)
  BOTTOM w0.076: T37.1 113,15.65 v1(112.76,15.89) 112.6,15.74 112.02,15.74 111.92,15.84 RP9.2
USB_OC3#: length 20.1
  IN4 w0.076: v1(112.39,15.36) 112.84,15.36 114.59,17.11 115.99,17.11 117.77,18.89 121.17,18.89 121.36,19.08 125.92,19.08 126.25,19.41 126.51,19.41 126.53,19.39 126.72,19.39 127.07,19.04 v1(128.38,19.04)
  BOTTOM w0.076: RP9.3 112.18,15.34 112.2,15.36 v1(112.39,15.36) 113.05,14.7 113.05,14.39 T38.1
USBRBIAS: length 8.6
  BOTTOM w0.076: UCPU1.D13 UCPU1.B13 127.75,22.37 126.17,22.37 126.02,22.52
  BOTTOM w0.097: 126.02,22.52 125.56,22.52 125.3,22.78 121.7,22.78 RH133.1 121.4,23.53 121.85,23.98 v2(121.85,24.14)
USH_ALERT#: length 40.2
  IN1 w0.076: v4(286,78.53) 286.26,78.27 287.75,78.27 288.07,77.94 288.22,77.94 v4(288.45,77.72)
  IN4 w0.076: v1(289.65,53.85) 289.6,53.85 286.65,56.8 286.65,71.81 286.41,72.05 286.41,72.93 286.7,73.22 286.7,74.95 287.54,75.79 287.54,76.23 288.32,77.02 288.32,77.59 v4(288.45,77.72) 288.45,77.75 288.82,78.12 288.82,78.5 288.85,78.53 288.85,78.59 288.86,78.6 288.86,79.22 289.11,79.47 v1(289.11,79.63) ; v4(286,78.53) 286,78.34 v1(285.74,78.07)
  BOTTOM w0.076: v1(285.74,78.07) 285.74,77.66 285.06,76.99 v2(284.38,76.99) ; JUSH1.14 287.25,51.26 286.1,52.41 286.1,52.81 287.04,53.75 289.18,53.75 289.27,53.85 v1(289.65,53.85)
USH_DET#: length 255.8
  TOP w0.076: v5(113.12,11.2) 113.3,11.02 113.3,11.02 113.53,10.8 120.97,10.8 124.05,7.71 133.55,7.71 136.45,4.82 152.44,4.82 152.71,4.56 166.21,4.56 166.48,4.82 166.5,4.82 170.64,8.96 171.18,8.96 175.58,13.35 v3(175.58,13.51)
  IN1 w0.076: v4(113.38,10.94) 113.3,11.02 113.3,11.02 v5(113.12,11.2)
  IN3 w0.076: 287.08,14.57 287.07,14.57 ; 287.08,14.57 288.23,14.57 290.45,16.79 291.4,16.79 296.49,21.89 296.49,44.19 292.92,47.76 292.92,48.02 292.07,48.87 292.07,49.11 291.92,49.26 v4(291.88,49.26) ; 287.08,14.57 287.07,14.57 ; 287.07,14.57 286.2,13.7 285.44,13.7 285.27,13.53 284.16,13.53 283.23,12.61 282.43,12.61 281.2,11.37 273.6,11.37 272.28,12.69 268.76,12.69 267.27,11.2 250.91,11.2 247.87,14.25 237.38,14.25 236.88,14.75 232.89,14.75 232.34,15.3 227.96,15.3 226.75,14.09 226.75,13.35 224.21,10.81 214.17,10.81 213.72,11.25 200.71,11.25 199.72,12.24 192.35,12.24 191.23,11.13 189.08,11.13 188.72,11.49 188.34,11.49 187.35,11.49 185.11,11.49 184.73,11.87 184.4,11.87 183.28,13 176.08,13 v3(175.58,13.51)
  IN4 w0.076: v1(291.62,49.63) 291.62,49.52 v4(291.88,49.26) ; v1(130.13,12.52) 130.08,12.58 129.58,12.58 129.53,12.53 128.77,12.53 128.52,12.28 128.34,12.28 128.33,12.27 126.58,12.27 126.21,11.9 124.71,11.9 124.19,12.43 123.6,12.43 123.39,12.63 123.1,12.63 122.63,12.16 121.25,12.16 120.86,11.77 118.79,11.77 117.88,10.85 114.71,10.85 114.59,10.98 113.79,10.98 113.75,10.94 v4(113.38,10.94) 112.24,9.79 v1(112.24,9.62)
  BOTTOM w0.076: v2(294.74,50.26) 294.3,50.7 JUSH1.1 293.75,50.13 293.14,49.52 291.73,49.52 v1(291.62,49.63)
USH_ON: length 264.3
  TOP w0.076: v5(124.99,23.45) 124.99,27.56 123.25,29.3 117.68,29.3 115.21,26.84 115.21,25.64 115.14,25.57 115.12,25.57 114.89,25.34 113.42,25.34 112.06,26.7 v5(112.06,26.98)
  IN1 w0.076: v4(124.66,23.51) 124.92,23.51 v5(124.99,23.45) ; v4(112.48,26.98) v5(112.06,26.98)
  IN2 w0.076: v4(297.48,44.75) 297.5,44.75 297.89,45.14 297.89,47.77 293.26,52.4 292.53,52.4 292.14,52.01 284.02,52.01 278.9,46.89 245.68,46.89 243.96,48.61 236.56,48.61 234.19,50.98 224.64,50.98 217.28,43.63 217.28,31.56 216.2,30.48 186.38,30.48 184.19,32.68 172.15,32.68 169.66,30.19 117.16,30.19 114.58,27.61 113.12,27.61 v4(112.48,26.98)
  IN4 w0.076: v1(125.03,23.46) 124.98,23.51 v4(124.66,23.51) 124.65,23.52 124.04,23.52 122.93,22.42 118.69,22.42 118.6,22.51 116.42,22.51 115.49,21.58 115.09,21.58 114.63,21.13 114.16,21.13 113.31,20.27 109.87,20.27 108.24,18.65 107.39,18.65 v1(107.21,18.47) ; v4(297.48,44.75) v1(297.48,45.14)
  BOTTOM w0.076: v1(107.21,18.47) 107.53,18.16 RH107.1 ; v1(125.03,23.46) 125.16,23.33 126.05,23.33 126.56,22.82 129.43,22.82 129.63,22.62 UCPU1.J14 ; R384.1 299.73,45.36 v6(298.45,45.36) 297.71,45.36 297.5,45.14 v1(297.48,45.14)
USH_ON_R: length 11.8
  BOTTOM w0.076: R385.2 298.25,53.99 R308.2 298.8,53.68 298.8,53.11 298.39,52.7 U34.3 298.39,51.86 298.53,51.72 299.01,51.72 299.21,51.51 299.21,49.56 299.48,49.29 300.43,49.29 300.94,48.78 300.94,47.11 300.78,46.96 v2(300.78,46.83) 300.78,46.46 300.61,46.28 R384.2
USH_PWR_STATE#: length 52.1
  TOP w0.076: v5(290.36,81.12) 286.36,77.12 286.36,52.32 285.7,51.66 285.7,47.93 286.29,47.34 v5(287.56,47.34)
  IN1 w0.076: v5(287.56,47.34) v4(288.2,47.34) ; v5(290.36,81.12) 290.36,81.15 v4(290.65,81.44)
  IN4 w0.076: v4(290.65,81.44) 290.38,81.44 289.58,80.63 289.58,80.46 289.54,80.42 v1(289.39,80.42) ; v1(286.81,49.63) 286.81,48.67 287.5,47.98 287.5,47.71 287.78,47.44 288.1,47.44 v4(288.2,47.34) 287.89,47.03 v1(287.82,47.03)
  BOTTOM w0.076: v1(286.81,49.63) 287.42,49.63 287.81,50.02 291.13,50.02 291.13,50.01 291.37,50.01 291.4,50.04 291.62,50.04 291.75,50.18 JUSH1.5 ; v1(289.39,80.42) 289.61,80.21 U38.K9 ; v2(289.95,47.45) 289.86,47.54 288.32,47.54 v1(287.82,47.03)
USH_RST#: length 26
  BOTTOM w0.076: JUSH1.6 291.25,51.42 291.45,51.62 295.59,51.62 296.03,51.17 v2(296.03,50.3) 296.03,49.56 295.74,49.27 283.21,49.27 RZ5.2 RZ4.2 281.13,50.52 280.3,50.52 280.07,50.3 R387.2 279.43,50.3 U61.4
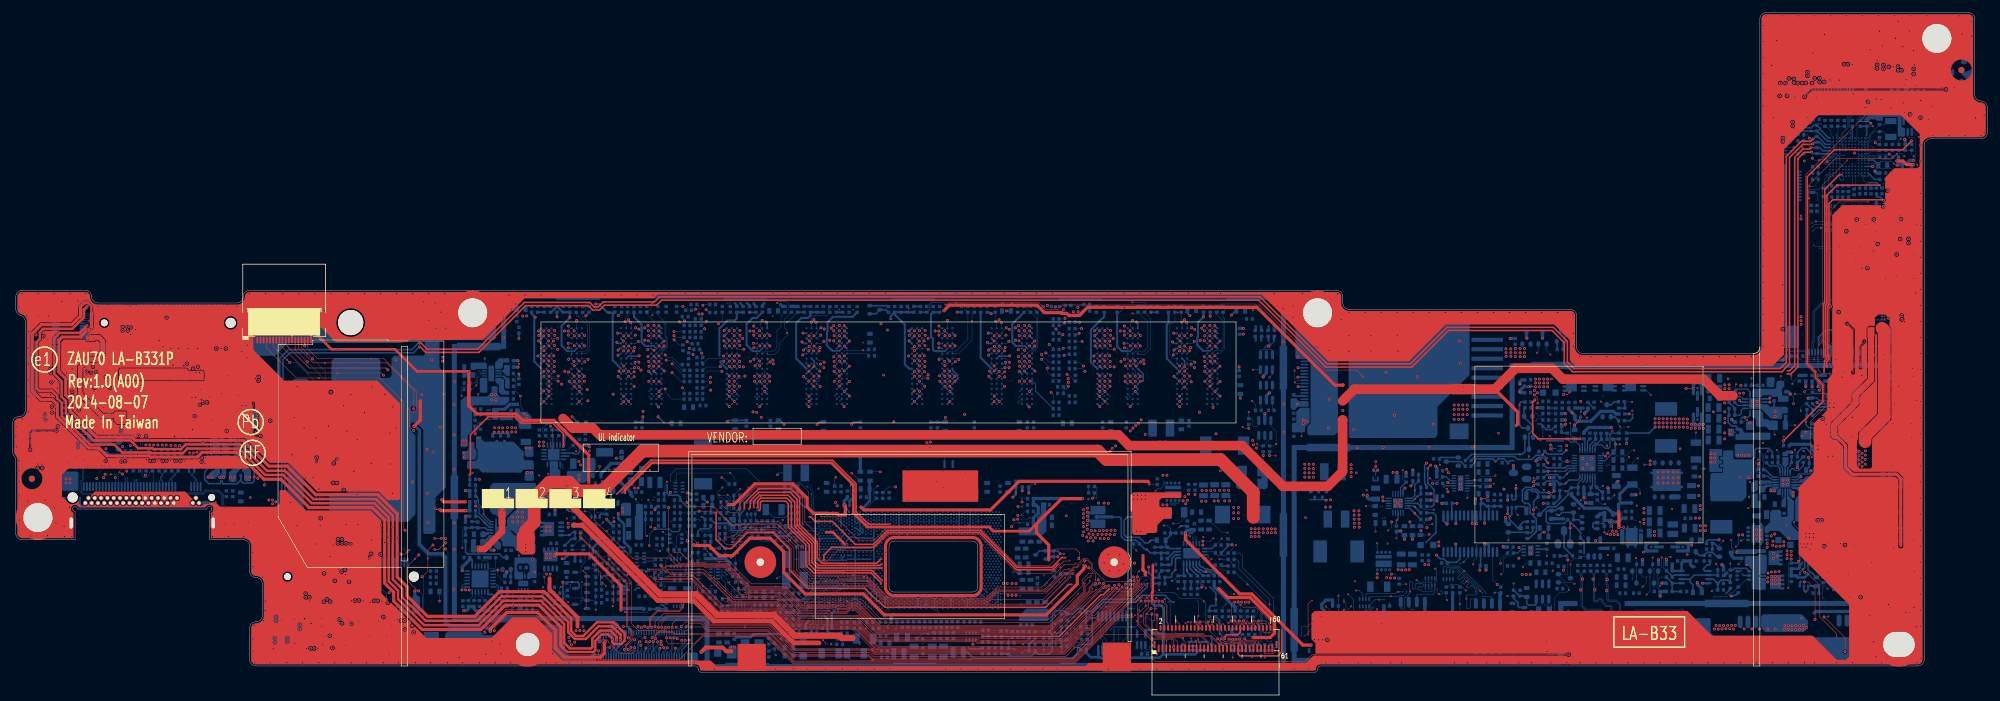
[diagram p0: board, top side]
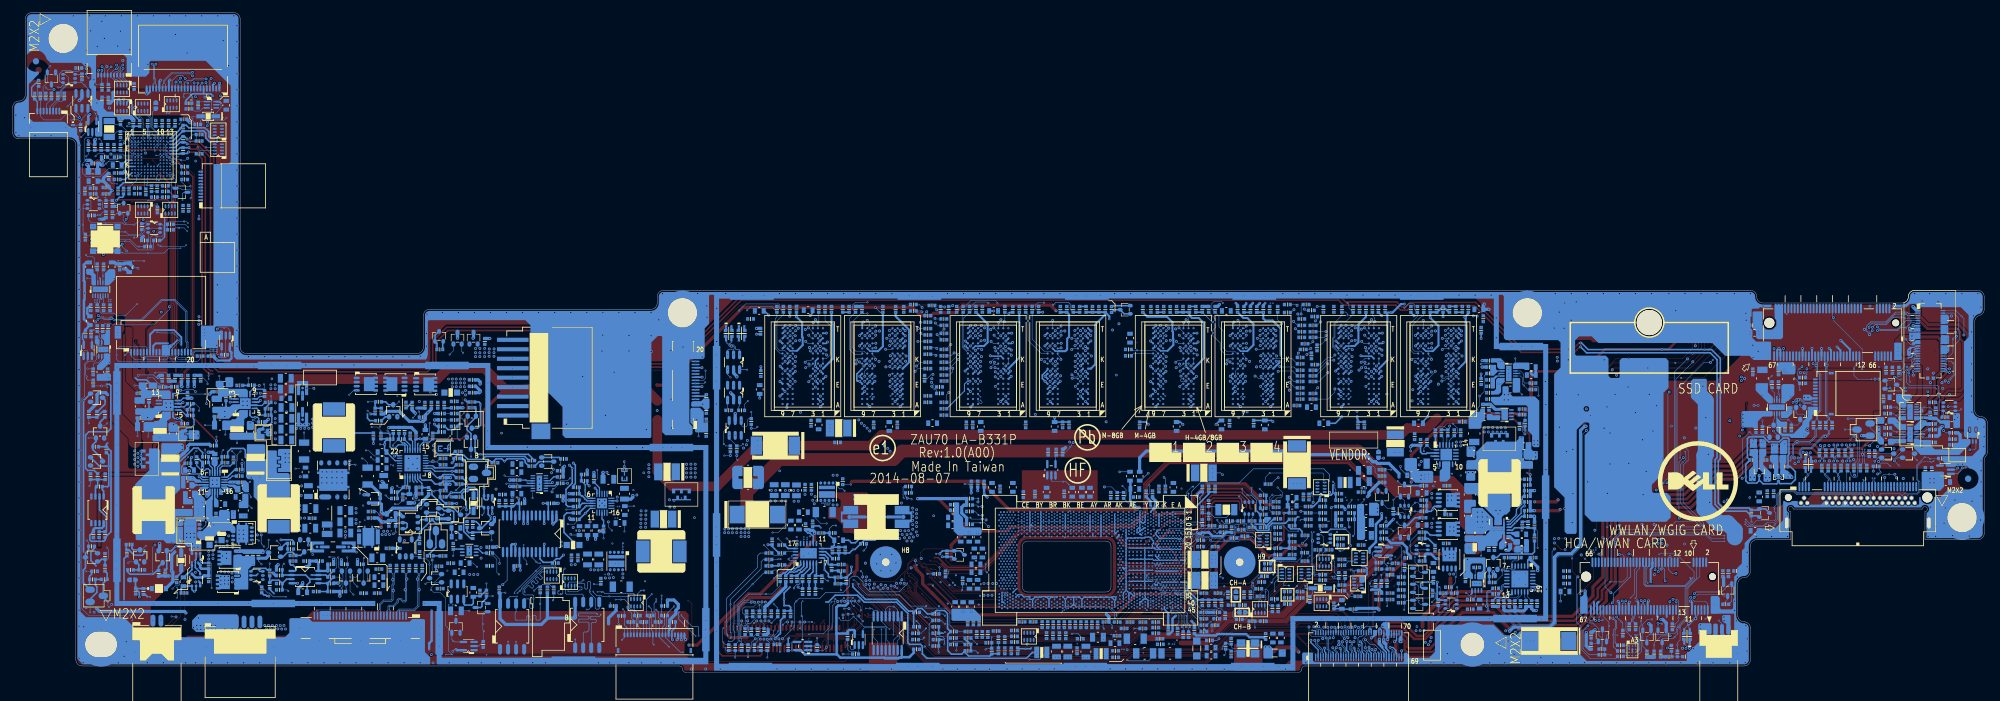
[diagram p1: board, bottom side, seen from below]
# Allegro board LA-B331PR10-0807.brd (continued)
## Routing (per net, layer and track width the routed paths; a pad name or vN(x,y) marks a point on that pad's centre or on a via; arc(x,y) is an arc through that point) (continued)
USH_SMBCLK: length 59.9
  IN4 w0.076: v1(280.13,51.08) 280.01,51.08 279.74,51.35 279.74,79.56 282.09,81.91 282.09,86.18 285.44,89.53 286.47,89.53 v1(286.56,89.43) 286.72,89.43 286.97,89.18 287.2,89.18 287.51,89.5 288.71,89.5 290.47,87.74 290.47,87.52 291.39,86.6 291.39,85.84 291.25,85.7 291.25,85.38 291.2,85.33 290.94,85.33 v1(290.81,85.46)
  BOTTOM w0.076: v1(280.13,51.08) 280.14,51.08 v2(280.78,51.08) 281.32,51.08 281.46,50.94 283.68,50.94 283.97,50.65 283.97,49.92 284.03,49.85 286.28,49.85 286.38,49.95 286.38,50.04 286.25,50.17 JUSH1.16 ; U38.B7 290.86,84.38 290.86,85.41 v1(290.81,85.46)
USH_SMBDAT: length 62.9
  IN4 w0.076: v1(293.11,83.13) 292.87,83.37 292.87,83.74 292.74,83.87 291.51,83.87 291.35,84.03 291.35,84.33 291.3,84.39 291.3,85.21 291.4,85.31 291.4,85.64 291.54,85.78 291.54,86.67 290.62,87.58 290.62,87.8 288.77,89.65 287.45,89.65 287.23,89.43 v1(287.06,89.43) 286.82,89.68 285.38,89.68 281.94,86.24 281.94,81.97 279.59,79.62 279.59,51.27 280.12,50.74 v1(280.13,50.74)
  BOTTOM w0.076: v1(280.13,50.74) 280.18,50.79 283.61,50.79 283.82,50.59 283.82,49.85 284.11,49.56 v2(285.07,49.56) 286.3,49.56 286.54,49.8 286.54,49.97 286.75,50.18 JUSH1.15
V_DDR_REF_CA: length 92.4
  TOP w0.254: v5(138.78,23.45) 135.44,23.45 135.16,23.73 ; 135.16,23.73 133.46,25.43 133.46,29.86 129.73,33.59 100.97,33.59 v5(95.6,28.22) ; 135.16,23.73 v2(135.16,23.73)
  IN1 w0.254: v5(95.6,28.22) 95.6,28.28 v4(95.32,28.55) ; v4(138.24,21.92) 138.44,22.13 138.44,22.64 138.83,23.03 138.83,23.36 138.78,23.41 v5(138.78,23.45)
  IN4 w0.076: v1(138.48,22.36) 138.48,22.31 138.24,22.06 v4(138.24,21.92)
  IN4 w0.254: v1(85.13,57.96) 85.13,57.57 82.08,54.53 82.08,42.77 83.65,41.19 83.65,41.08 87.33,37.4 87.6,37.4 88.63,36.37 88.72,36.37 94.77,30.31 94.77,29.11 v4(95.32,28.55)
  BOTTOM w0.254: CD72.1 v1(85.13,57.96)
V_DDR_REFA_R: length 46.5
  IN2 w0.254: v4(144.23,26.03) 144.22,26.01 143.15,26.01 141.79,24.66 140.31,24.66 139.96,24.31 139.96,23.75 139.53,23.32 139.53,22.86 139.86,22.53 139.86,21.73 139.81,21.68 139.81,21.47 v4(139.77,21.42)
  IN3 w0.254: v4(144.23,26.03) 144.36,26.15 144.45,26.15 145.08,26.79 145.08,28.28 144.71,28.64 144.71,32.42 143.45,33.69 143.45,39.61 139.66,43.4 139.66,54.59 141.3,56.22 142.07,56.22 v4(143.29,57.45)
  IN4 w0.254: v1(143.65,57.96) 143.29,57.6 v4(143.29,57.45) ; v1(139.83,21.95) 139.83,21.71 139.81,21.68 139.81,21.42 v4(139.77,21.42)
  BOTTOM w0.254: v1(143.65,57.96) RD23.1
V_DDR_REFB_R: length 57
  IN2 w0.254: v4(144.23,26.56) 144.08,26.41 143.01,26.41 142.01,25.41 142.01,25.36 141.68,25.04 139.7,25.04 138.69,24.03 138.69,23.23 139.46,22.47 139.46,21.86 139.25,21.65 139.25,21.52 139.1,21.37 v4(139.09,21.37)
  IN3 w0.254: v4(144.23,26.56) 144.28,26.61 144.44,26.61 144.75,26.93 144.75,28.14 144.38,28.5 144.38,32.29 143.12,33.55 143.12,39.4 139.28,43.24 139.28,54.45 138.52,55.21 v3(137.42,55.21) 133.49,55.21 133.02,55.68 128.3,55.68 126.78,57.2 v4(126.78,57.5)
  IN4 w0.203: v4(139.09,21.37) 139.09,21.48 139.28,21.67 139.28,21.69 139.44,21.85 v1(139.44,22.32)
  IN4 w0.254: v1(126.27,57.96) 126.32,57.96 v4(126.78,57.5)
  BOTTOM w0.254: UCPU1.AT13 139.4,22.36 v1(139.44,22.32) ; CD74.1 v1(126.27,57.96)
V_SYS: length 165.4
  TOP w0.102: v3(240.7,30.19) v2(240.7,30.81)
  TOP w0.254: v3(296.07,74.77) 296,74.85 288.02,74.85 287.44,74.26 287.44,58.27 287.26,58.1 287.26,50.3 287.44,50.13 287.44,49.58 287.06,49.2 287.06,48.48 v5(287.18,48.35)
  IN1 w0.254: v5(287.18,48.35) v4(287.18,47.85)
  IN2 w0.254: v4(287.18,47.85) 287.18,47.74 287.44,47.48 288.03,46.89 288.38,46.89 288.77,47.29 289.81,47.29 290.49,46.61 291.02,46.61 292.79,44.85 292.79,42.11 294.72,40.18 294.72,19.84 293.46,18.57 291.99,18.57 288.38,14.96 288.38,12.12 286.94,10.69 274.48,10.69 272.9,12.27 272.9,12.36 272.9,12.52 272.23,13.19 271.76,13.19 269.35,13.19 266.52,10.36 235.84,10.36 231.51,14.69 231.51,21.68 232.47,22.65 232.47,23.94 235.09,26.56 236.79,26.56 240.42,30.19 v3(240.7,30.19)
  BOTTOM w0.254: R228.2 294.96,75.41 295.12,75.25 295.59,75.25 v3(296.07,74.77) ; v3(240.7,30.19) 241.34,30.83 PR715.1
VGATE: length 58.1
  IN3 w0.254: v3(188.83,15.94) 188.08,16.69 186.56,16.69 182.7,20.56 172.69,20.56 171.73,19.6 167.78,19.6 166.97,20.41 165.01,20.41 160.84,16.25 160.84,13.53 165.55,8.83 165.55,5.57 165.79,5.33 v4(165.97,5.33)
  IN4 w0.254: v4(165.97,5.33) 165.97,5.28 165.29,4.59 164.91,4.59 164.53,4.97 162.24,4.97 v1(161.78,5.43)
  BOTTOM w0.102: R6.2 160.08,3.4 v2(159.77,3.09)
  BOTTOM w0.254: PR512.1 189.55,15.89 188.89,15.89 v3(188.83,15.94) 188.4,15.94 188.15,16.2 187.89,16.2 187.31,16.79 PU702.2 ; v1(161.78,5.43) 161.78,5.21 161.52,4.94 161.4,4.94 R7.2 R6.2
VPRO: length 17
  IN4 w0.076: v1(116.93,10.28) 117.35,10.7 119.3,10.7 120.06,11.46 121.02,11.46 121.41,11.85 122.95,11.85 123,11.81 124.16,11.81 124.52,11.45 127.01,11.45 127.45,11.88 v1(128.5,11.88)
  BOTTOM w0.076: RH177.2 RH178.2 ; RH177.2 115.91,8.11 116.44,8.64 116.44,9.66 116.93,10.14 v1(116.93,10.28) ; RH177.2 v2(115.91,7.1)
VR12.6_VR_ON: length 51.4
  IN4 w0.076: v1(164.07,4.41) 164.74,4.41 165.44,3.72 195.45,3.72 196.72,4.98 197.34,4.98 v1(197.4,4.92)
  BOTTOM w0.076: PR519.1 191.04,13.68 192.34,12.39 v2(193.28,12.39) 196,12.39 197.8,10.59 197.8,7.57 197.55,7.32 197.55,5.07 v1(197.4,4.92) ; R7.1 162.26,4.89 163.59,4.89 v1(164.07,4.41)
VR_ON: length 5.4
  BOTTOM w0.102: v2(192.01,14.88) 191.6,15.28 PR519.2
  BOTTOM w0.254: PU702.1 187.81,16.97 188.05,16.73 188.28,16.73 188.61,16.4 189.09,16.4 189.27,16.22 189.75,16.22 190.23,15.74 190.52,15.74 190.98,15.28 PR519.2
VR_ON_MCP: length 15.3
  IN4 w0.076: v1(163.15,4.41) 161.43,4.41 160.08,5.76 158.15,5.76 155.94,7.97 154.59,7.97 154.12,8.44 153.46,9.1 153.38,9.1 152.98,9.5 152.62,9.5 152.24,9.88 152.24,10.37 152.24,10.38 152.23,10.38 152.23,10.39 152.1,10.52 152.1,10.74 v1(151.96,10.88)
  BOTTOM w0.076: v1(163.15,4.41) v2(163.15,3.46)
VR_SVID_ALRT#: length 60.8
  IN4 w0.066: v1(156.5,4.72) 158.55,2.66 196.92,2.66 198.64,4.38 198.64,5.19 v1(198.88,5.43)
  BOTTOM w0.097: RC32.1 v1(156.5,4.72) ; PR516.1 193.69,17.87 194.05,17.51 194.05,16.39 198.89,11.54 v2(198.89,10.76) 198.92,10.73 198.92,6.33 198.82,6.22 198.82,5.49 v1(198.88,5.43)
VR_SVID_CLK: length 60.3
  IN4 w0.066: v1(199.2,4.91) 199.2,4.12 197.22,2.14 158.06,2.14 v1(155.48,4.72)
  BOTTOM w0.097: v1(199.2,4.91) 198.62,4.91 198.24,5.28 198.24,6.42 198.37,6.55 198.37,7.71 198.34,7.74 198.34,11.01 v2(195.41,13.94) 193.51,15.84 PR517.1
VR_SVID_DAT: length 59.4
  IN4 w0.066: v1(158.48,4.67) 159.35,3.79 164.61,3.79 165.22,3.19 196.6,3.19 198.09,4.68 198.09,5.38 198.66,5.95 199.21,5.95 v1(199.38,5.79)
  BOTTOM w0.097: v1(199.38,5.79) 199.38,6.02 199.48,6.11 199.48,7.22 199.55,7.29 v2(199.55,7.93) 199.55,11.67 194.6,16.62 194.6,18.48 194.19,18.89 PR515.1
VRPG_MCP: length 12.4
  IN4 w0.076: v1(160.84,5.45) 160.35,5.95 158.18,5.95 156.01,8.12 154.65,8.12 153.52,9.25 153.44,9.25 153.05,9.65 152.7,9.65 152.54,9.81 152.54,10.02 152.39,10.17 v1(152.39,10.63)
  BOTTOM w0.076: RC31.2 160.86,5.43 v2(159.88,4.45)
VSET_1641: length 8
  IN4 w0.076: v1(288.11,83.13) 288,83.24 287.1,83.24 286.24,84.09 285.49,84.09 285.27,84.32 285.27,84.63 285.05,84.84 284.74,84.84 284.53,84.63 v3(284.35,84.63)
  BOTTOM w0.076: v3(284.35,84.63) 284.19,84.79 284.19,84.96 283.96,85.18 R230.1 C159.1 283.55,84.07 v2(284.41,84.07)
VTTREF_1.35V: length 4.3
  BOTTOM w0.076: v2(219.99,32.02) 219.99,30.64 PC610.1
  BOTTOM w0.203: PC610.1 219.64,29.25 PU600.4
WAKE#: length 26.5
  IN4 w0.076: v1(128.88,19.9) 128.81,19.9 128.53,19.63 128.16,19.63 128.04,19.51 127.74,19.51 127.28,19.51 126.95,19.84 126.72,19.84 126.7,19.87 126.44,19.87 126.02,19.87 125.69,19.54 121.17,19.54 120.98,19.35 117.7,19.35 117.58,19.35 115.81,17.58 114.33,17.58 113.69,16.94 112.62,16.94 111.17,15.5 109.4,15.5 109.26,15.36 107.92,15.36 107.78,15.5 106.63,15.5 v1(106.46,15.33)
  BOTTOM w0.076: v1(106.46,15.33) 106.34,15.46 RH83.1 RH58.1
WL_OFF#_R: length 15.6
  IN1 w0.076: v3(14.77,35.42) 14.41,35.78 12.91,35.78 12.71,35.58 12.71,34.55 15.17,32.09 15.17,28.43 JNGFF1.48
  BOTTOM w0.076: R68.1 17.36,34.64 D20.1 14.77,34.7 v3(14.77,35.42)
WLAN_EN: length 4.7
  BOTTOM w0.076: v2(35.6,39.9) R147.2 34.75,38.91 34.51,39.14 D13.1 33.82,40.06 33.71,40.17 U29.3
WLAN_ON: length 144
  IN2 w0.076: v4(53.87,29.43) 53.87,29.65 51.17,32.35 45.53,32.35 45.22,32.05 28.67,32.05 28.37,32.35 20.62,32.35 19.54,33.43 v3(17.82,33.43)
  IN3 w0.076: v4(100.23,23.49) 99.55,23.49 98.23,24.81 91.92,24.81 91.39,24.27 91.39,12.58 90.79,11.98 85.28,11.98 79.59,17.67 70.29,17.67 69.66,17.04 59.32,17.04 53.88,22.47 53.88,29.25 53.87,29.27 v4(53.87,29.43)
  IN4 w0.076: v4(100.23,23.49) 101.61,23.49 101.61,23.48 102.49,23.48 102.5,23.49 102.8,23.79 103.71,23.79 104.05,23.45 106.92,23.45 106.92,23.45 107.12,23.45 108.14,22.43 108.69,22.43 108.76,22.36 v1(109.05,22.36)
  GND3 w0.076: v8(128.13,20.33) 127.69,20.33 v8(127.25,20.78)
  BOTTOM w0.076: v3(17.82,33.43) 17.82,33.48 17.31,33.99 D20.3 ; v8(127.25,20.78) 127.25,20.9 126.36,21.8 125.39,21.8 125.07,21.48 122.96,21.48 122.73,21.25 120.96,21.25 120.51,21.7 119.3,21.7 119.19,21.82 119.19,23.21 118.99,23.41 118.32,23.41 118.17,23.56 117.3,23.56 117.19,23.46 117.19,22.63 117.03,22.46 116.01,22.46 115.67,22.12 113.71,22.12 113.35,22.48 113.35,23.1 113.09,23.36 111.56,23.36 110.56,22.36 v1(109.05,22.36)
WLAN_PWR: length 116.3
  IN1 w0.076: v4(44.51,23.44) 44.51,24.15 42.84,25.82 42.84,27.43 40.59,29.68 v3(39.85,29.68)
  IN4 w0.076: v1(49.92,23.28) 49.81,23.17 49.81,18.24 50.23,17.82 53.07,17.82 54.98,15.92 61.64,15.92 62.43,16.71 64.41,16.71 65.11,16.01 70.15,16.01 70.92,16.77 82.45,16.77 83.08,16.13 88.71,16.13 88.92,15.92 97.77,15.92 98.95,14.75 104.71,14.75 105.06,15.11 105.41,15.11 105.84,14.67 106.87,14.67 107.03,14.84 112.75,14.84 113.97,16.06 114.98,16.06 115.56,16.64 116.66,16.64 117.44,15.87 118.93,15.87 121.84,18.78 125.98,18.78 126.13,18.62 126.87,18.62 126.98,18.73 128,18.73 v1(128.13,18.6) ; v4(44.51,23.44) 44.6,23.35 v1(45.58,23.35)
  BOTTOM w0.076: v1(45.58,23.35) 45.67,23.35 46.21,23.89 49.31,23.89 v1(49.92,23.28) ; D13.2 34.75,37.24 35.07,37.57 37.13,37.57 v2(37.62,38.06) 38.73,36.94 38.73,31.5 39.85,30.38 v3(39.85,29.68)
WLAN_RST#: length 146.7
  IN1 w0.076: v4(13.12,35.15) 14.07,34.19 27.24,34.19 27.34,34.09 29.36,34.09 29.68,34.4 38.21,34.4 45.01,27.6 46.93,27.6 60.77,13.76 62.28,13.76 64.32,11.72 72.56,11.72 73.29,10.99 84.32,10.99 85.29,10.03 88.15,10.03 88.48,10.36 101.05,10.36 102.19,11.49 104.88,11.49 105.1,11.27 105.1,10.71 104.94,10.55 104.94,10.05 105.36,9.63 108.15,9.63 110.79,12.27 111.42,12.27 v4(111.76,12.61)
  IN3 w0.076: v4(111.76,12.61) 111.76,12.25 112.66,11.34 112.66,10.85 v4(112.74,10.77)
  IN4 w0.076: v1(129.88,12.97) 129.11,12.97 128.97,12.83 128.64,12.83 128.39,12.58 128.21,12.58 128.21,12.58 126.45,12.58 126.09,12.21 124.84,12.21 124.31,12.73 123.72,12.73 122.92,13.53 121.94,13.53 121.18,12.77 120.83,12.77 119.98,11.92 118.65,11.92 118.02,11.28 116.5,11.28 116.35,11.44 115.38,11.44 v1(115.24,11.3) 114.97,11.03 114.75,11.03 114.53,11.26 112.85,11.26 v1(112.77,11.17) 112.66,11.07 112.66,10.85 v4(112.74,10.77) ; v4(13.12,35.15) 12.88,35.39 11.46,35.39 9.61,33.54 9.61,33.53 8.32,32.24 4.8,32.24 v3(4.68,32.35)
  BOTTOM w0.076: RP1.7 115.35,11.19 v1(115.24,11.3) ; U51.2 4.94,32.1 v3(4.68,32.35)
WLAN_RST#_Q: length 18
  BOTTOM w0.076: JNGFF1.44 17,28.14 16.83,28.31 13.85,28.31 13.5,27.96 ; JNGFF1.58 13.5,27.96 ; 13.5,27.96 13.08,28.38 11.11,28.38 10.86,28.63 10.86,30.15 11.17,30.47 11.17,32.83 v2(9.93,34.08) 9.38,34.08 v1(9.1,33.8) 9.03,33.88 R303.1 7.51,33.65 U51.4
WLAN_WIGIG60GHZ_DIS#: length 378.4
  IN2 w0.076: v3(17.4,35.77) 18.03,35.13 18.34,35.13 20.97,32.5 28.46,32.5 28.66,32.3 45.26,32.3 45.46,32.5 51.27,32.5 60.67,23.11 60.67,20.54 69.3,11.9 77,11.9 77.51,12.41 85.61,12.41 86.12,11.9 92.76,11.9 94.36,10.31 97.78,10.31 98.36,9.73 101.85,9.73 102.49,9.1 107.29,9.1 107.63,8.76 108.59,8.76 108.8,8.55 109.01,8.55 110,7.56 119.23,7.56 122.85,3.94 127.76,3.94 128.15,3.55 130.06,3.55 130.62,4.11 133.49,4.11 133.78,4.4 135.01,4.4 135.57,4.96 136.72,4.96 137.95,3.73 148.43,3.73 149.12,3.04 151.2,3.04 151.45,2.79 198.11,2.79 199.46,4.15 201.63,4.15 202.36,3.41 205.81,3.41 206.06,3.66 243.89,3.66 244.86,4.63 259.23,4.63 260.56,3.29 289.16,3.29 292.59,6.72 293.65,6.72 296.13,9.2 296.13,10.72 298.44,13.03 298.44,15.02 298.28,15.18 298.28,16.77 299.16,17.65 299.16,48.23 294.18,53.21 294.18,53.51 293.58,54.11 293.58,55.2 288.64,60.14 288.64,69.58 287.41,70.82 287.41,73.35 286.79,73.97 v4(286.79,76.17)
  IN4 w0.076: v4(286.79,76.17) 286.79,76.42 287.66,77.29 287.66,78.05 287.74,78.13 287.74,78.72 287.97,78.95 288.44,78.95 v1(288.61,79.13)
  BOTTOM w0.076: D20.2 16.92,35.29 v3(17.4,35.77)
WWAN_EN: length 5.3
  BOTTOM w0.076: D18.1 29.62,39.57 30.03,39.16 R79.2 31.02,39.62 31.43,40.02 v2(31.53,40.02) 32.6,40.02 32.91,40.33 U29.5
WWAN_OFF#: length 90.4
  IN3 w0.076: v3(52.12,7.75) 52.12,7.78 52.11,7.79 52.11,14.06 v4(53.62,15.57)
  IN4 w0.076: v1(128.88,18.17) 128.72,18.17 128.48,18.41 128.28,18.41 128.23,18.36 127.96,18.36 127.74,18.58 127.04,18.58 126.94,18.47 126.07,18.47 125.92,18.62 121.9,18.62 119,15.71 117.3,15.71 116.88,16.13 116.52,16.49 115.63,16.49 115.04,15.91 114.03,15.91 112.81,14.69 107.19,14.69 106.73,14.23 103.66,14.23 103.3,14.6 98.88,14.6 97.71,15.77 88.85,15.77 88.64,15.98 83.02,15.98 82.38,16.62 75.93,16.62 75,15.69 65.21,15.69 64.35,16.55 62.49,16.55 61.69,15.74 53.79,15.74 v4(53.62,15.57)
  BOTTOM w0.076: Q7.3 v3(52.12,7.75) 51.6,7.75 v2(51.52,7.67)
WWAN_OFF#_R: length 17.4
  BOTTOM w0.076: R73.2 51.47,3.59 Q7.1 51.47,5.19 51.28,5.38 49.69,5.38 v2(49.46,5.61) 49.07,6 49.07,6.73 48.69,7.11 48.69,7.43 47.69,8.44 47.69,13.23 46,14.91 JNGFF2.8
WWAN_PWR_OFF#: length 96.4
  IN2 w0.076: v3(50.62,3.85) 50.73,3.85 52.26,5.38 63.18,5.38 65.25,7.45 76.34,7.45 78.52,9.63 84.85,9.63 85.7,8.78 92.81,8.78 93.75,7.84 97.13,7.84 98.94,6.02 102.14,6.02 103.19,4.98 105.27,4.98 105.58,4.66 109.87,4.66 110.22,5.02 v4(111.12,5.02) ; v4(111.19,12.6) 111.68,12.11 112.29,12.11 112.32,12.13 112.88,12.13 113.68,11.33 114.54,11.33 115.13,10.75 119.91,10.75 121.38,9.28 122.56,9.28 123.69,8.14 124.64,8.14 125.05,7.72 v4(125.55,7.72)
  IN3 w0.076: v4(111.19,12.6) 110.93,12.6 110.42,12.09 110.42,11.22 110.35,11.14 110.35,5.78 111.11,5.02 v4(111.12,5.02)
  IN4 w0.076: v1(129.8,11.13) 129.64,11.13 126.54,8.03 126.54,7.98 126.29,7.72 v4(125.55,7.72)
  BOTTOM w0.076: R386.2 50.21,4.26 v3(50.62,3.85)
WWAN_PWR_OFF#_R: length 15.5
  BOTTOM w0.076: JNGFF2.6 45.5,15.2 47.38,13.31 47.38,8.53 48.54,7.37 48.54,7.05 48.64,6.95 48.64,5.09 49.06,4.67 v2(49.06,4.35) R389.1
WWAN_RST#: length 93
  TOP w0.076: v3(64.27,18.6) v2(63.66,17.98) 62.37,16.7 62.37,14.63 63.79,13.21 63.79,13.21 64.11,12.9 v3(64.26,12.9)
  IN1 w0.076: v4(130.21,11.96) 130.21,12.23 129.96,12.49 129.49,12.49 128.71,11.71 122.74,11.71 121.99,12.46 116.63,12.46 116.16,12.93 115.35,12.93 114.94,12.51 114.52,12.51 114.01,13.02 111.15,13.02 108.63,10.5 108.59,10.5 108.04,9.95 v4(108.01,9.95)
  IN2 w0.076: v4(108.01,9.95) 107.81,10.15 102.91,10.15 102.13,10.93 99.4,10.93 99.05,11.28 97.83,11.28 97.09,12.02 94.99,12.02 94.02,13 92.88,13 92.74,12.86 86.42,12.86 85.98,13.3 77.32,13.3 77.14,13.48 75.2,13.48 74.92,13.2 74.6,13.2 73.61,14.19 68.6,14.19 64.36,18.43 64.36,18.51 v3(64.27,18.6)
  IN4 w0.076: v7(130.83,12.29) 130.54,12.29 v4(130.21,11.96)
  GND3 w0.076: v7(130.83,12.29) 131.1,12.02 v8(131.1,11.88)
  BOTTOM w0.076: R367.1 61.11,4.02 61.11,5.48 61.48,5.86 61.48,6.85 62.44,7.81 63.15,7.81 64.83,9.49 64.83,12.36 64.3,12.9 v3(64.26,12.9)
WWAN_RST#_Q: length 5.5
  BOTTOM w0.076: JNGFF2.59 60.75,8.81 59.89,7.95 v2(59.89,7.34) 59.89,6.18 60.27,5.8 Q48.3
WWAN_WAKE#: length 2.3
  BOTTOM w0.076: JNGFF2.15 49.75,7.76 R358.2
XCLK_BIASREF: length 7
  BOTTOM w0.076: RH31.1 124.45,6.67 124.85,7.08 124.85,7.87 125,8.02 125,8.35 126.4,9.74 126.4,11.06 127.22,11.88 UCPU1.A38
XDP_BPM0#: length 38.3
  TOP w0.097: v5(187.26,5.03) 187.33,4.96 187.33,4.7 187.36,4.68 JXDP1.21
  IN1 w0.066: v5(187.26,5.03) 187.25,5.02 185.91,5.02 v4(185.64,5.3)
  IN4 w0.066: v4(185.64,5.3) 185.64,5.32 185.41,5.55 179.37,5.55 179.05,5.23 176.42,5.23 176.42,5.23 172.06,5.23 171.99,5.29 169.46,5.29 168.42,6.34 168.42,7.86 166.46,9.82 165.61,9.82 165.21,10.21 158.06,10.21 157.78,10.49 155.48,10.49 155.09,10.89 154.93,10.89 154.92,10.89 154.79,10.89 154.2,11.48 v1(154.2,11.63)
XDP_BPM1#: length 38.7
  TOP w0.097: v5(187.63,5.26) 187.63,4.82 187.96,4.5 JXDP1.23
  IN1 w0.066: v5(187.63,5.26) 187.63,5.68 v4(187.65,5.69)
  IN4 w0.066: v1(154.63,11.88) 154.63,12.03 154.94,12.34 155.2,12.34 155.4,12.14 155.6,12.14 155.62,12.16 156.59,12.16 157.19,11.55 166.47,11.55 170.87,7.15 174,7.15 174.61,6.54 176.3,6.54 176.52,6.31 178.68,6.31 178.95,6.58 182.55,6.58 182.8,6.83 183.93,6.83 184.49,6.27 185.54,6.27 185.84,6.27 186.55,5.57 186.93,5.57 186.93,5.57 187.21,5.57 187.21,5.57 187.42,5.57 187.55,5.69 v4(187.65,5.69)
XDP_PIN60: length 4.1
  TOP w0.076: v3(197.13,8.14) 198.29,8.14 199.06,7.37 JXDP1.60
  BOTTOM w0.076: v3(197.13,8.14) 197.13,7.55 196.9,7.32 196.9,7.18 196.62,6.9 R17.1
XDP_PRDY#: length 34.9
  TOP w0.076: JXDP1.5 182.56,4.98 v5(182.59,5.01)
  IN1 w0.076: v5(182.59,5.01) 182.78,5.2 183.29,5.2 183.78,5.68 v4(183.78,5.89)
  IN4 w0.076: v1(155.5,11.38) 155.89,11.38 v4(155.89,11.38) 156.55,11.38 156.96,10.97 164.43,10.97 v1(164.52,10.88) 164.59,10.82 165.36,10.82 165.5,10.96 166.19,10.96 169,8.16 169,6.62 169.62,6 172.57,6 172.9,5.67 178.89,5.67 179.2,5.97 182.8,5.97 183.05,6.23 183.43,6.23 183.76,5.89 v4(183.78,5.89)
XDP_PREQ#: length 34.4
  TOP w0.076: JXDP1.3 v5(181.96,5.01)
  IN1 w0.076: v4(183.2,5.9) 183.2,5.88 182.99,5.67 182.56,5.67 181.96,5.07 v5(181.96,5.01)
  IN4 w0.076: v1(155.07,11.13) 155.16,11.13 155.66,10.63 157.84,10.63 157.99,10.48 165.9,10.48 v1(165.92,10.46) 166.27,10.46 168.69,8.03 168.69,6.46 169.58,5.57 172.3,5.57 172.35,5.52 178.96,5.52 179.26,5.82 183.12,5.82 v4(183.2,5.9)
XDP_PWRGD: length 51.3
  TOP w0.097: JXDP1.39 192.76,4.35 192.57,4.53 191.73,4.53 191.56,4.7 191.3,4.7 190.69,5.31 v3(190.69,5.31)
  IN4 w0.066: v1(170.93,14.11) 170.83,14.11 170.4,14.54 170.4,14.61 170.2,14.81 170.13,14.81 169.17,15.77 169.17,17.03 168.93,17.27 168.93,17.28 168.73,17.48 168.72,17.48 168.17,18.02 168.17,22.87 168.37,23.06 168.37,25.98 169.29,26.9 169.69,26.9 170.83,28.03 171.18,28.03 171.44,27.78 v1(171.44,27.58)
  BOTTOM w0.097: v3(190.69,5.31) 188.81,7.18 188.81,10.91 v2(188.49,11.23) 188,11.73 184.74,11.73 183.81,12.67 181.03,12.67 180.11,13.59 180.11,14.74 179.63,15.22 178.84,15.22 177.91,14.29 177.91,13.84 176.82,12.74 172.2,12.74 170.93,14.01 v1(170.93,14.11) ; R15.2 171.46,29.43 171.59,29.3 171.59,27.73 v1(171.44,27.58)
XDP_TCK0: length 8.2
  TOP w0.076: v5(199.74,3.46) 199.74,3.22 199.46,2.94 198.27,2.94 198.16,3.05 JXDP1.57
  IN1 w0.076: v4(200.35,3.58) 200.24,3.46 v5(199.74,3.46)
  IN4 w0.076: v4(200.35,3.58) 200.23,3.58 199.9,3.9 v1(199.72,3.9)
  BOTTOM w0.076: RH153.2 RH148.2 ; RH148.2 v2(198.16,2.35) ; RH148.2 RH154.2 199.53,3.45 199.68,3.6 199.68,3.87 v1(199.72,3.9)
XDP_TCK1: length 6.9
  TOP w0.076: JXDP1.55 197.56,4.34 196.78,5.11 195.18,5.11 v3(194.97,5.31)
  BOTTOM w0.076: v3(194.97,5.31) 195.62,4.67 195.62,3.95 RH152.2 v2(196.12,2.41)
XDP_TDI: length 68.3
  TOP w0.076: JXDP1.56 197.86,6.46 198.07,6.25 199.07,6.25 199.32,6.5 199.32,7.83 196.94,10.21 194.86,10.21 v3(193.92,11.14)
  IN2 w0.076: v3(193.92,11.14) 193.43,11.64 192.05,11.64 191.33,10.91 184.09,10.91 181.07,7.89 172.53,7.89 160.68,19.74 160.68,22.18 159.78,23.08 v3(158.07,23.08) 157.82,22.83 157.82,21.29 156.36,19.83 154.89,19.83 154.5,19.44 154.25,19.44 153.86,19.04 v4(153.86,18.98)
  IN4 w0.076: v1(154.12,19.3) 153.86,19.04 v4(153.86,18.98)
  BOTTOM w0.076: v3(158.07,23.08) 158.67,23.68 T20.1 160.38,23.68 RH28.2 ; RH158.1 193.92,9.23 v3(193.92,11.14)
XDP_TDI_SWITCH: length 30.3
  IN4 w0.076: v1(176.19,6.81) 176.41,6.81 176.64,6.59 178.57,6.59 178.83,6.85 182.43,6.85 182.68,7.1 184.04,7.1 184.59,6.56 189.25,6.56 189.77,6.04 193.09,6.04 193.59,6.55 195.49,6.55 196.15,7.2 v1(196.15,7.71)
  BOTTOM w0.076: v1(176.19,6.81) 176.3,6.7 176.3,5.54 175.61,4.86 U4.10 ; v2(194.31,10.66) 194.31,9.76 RH158.2 RH157.2 194.85,9.19 194.85,8.64 195.79,7.71 v1(196.15,7.71)
XDP_TDO: length 28
  TOP w0.076: JXDP1.52 196.66,7.35 196.36,7.64 195.63,7.64 195.48,7.8 194.62,7.8 194.28,8.14 v3(194.08,8.14)
  IN4 w0.076: v1(177.51,10.11) 177.7,10.31 179.11,10.31 179.85,9.57 180.62,9.57 181.45,10.41 186.55,10.41 186.79,10.17 190.19,10.17 191.27,9.09 193.38,9.09 194.08,8.38 v3(194.08,8.14)
  BOTTOM w0.076: v1(177.51,10.11) v2(176.86,10.11) 176.53,10.11 176.24,9.82 175.73,9.82 175.61,9.71 U4.7 ; v3(194.08,8.14) 194.07,8.14 193.58,7.66 RH159.2 RH155.2 RH156.2
XDP_TMS: length 78
  TOP w0.076: JXDP1.58 198.46,7.47 198.17,7.76 197.02,7.76 196.64,8.14 v3(196.19,8.14)
  IN2 w0.076: v4(153.03,21.01) 153.03,21.24 154.26,22.47 155.57,22.47 158.43,25.33 158.43,26.1 158.94,26.61 159.36,26.61 v3(159.74,26.99) 159.99,26.99 162.57,24.41 162.57,18.75 171.16,10.16 179.1,10.16 179.76,9.5 179.76,8.99 v4(179.82,8.93)
  IN4 w0.076: v1(181.72,8.61) 181.82,8.71 181.82,8.81 182.41,9.4 184.69,9.4 185.19,8.91 185.19,8.52 185.52,8.19 185.76,8.19 186.19,8.62 189.77,8.62 190.26,8.13 190.26,7 191.07,6.19 193.02,6.19 193.58,6.75 195.41,6.75 195.91,7.24 195.91,7.87 196.18,8.14 v3(196.19,8.14) ; v4(179.82,8.93) 179.75,8.86 179.45,8.86 v1(179.42,8.84) ; v4(153.03,21.01) 153.51,21.49 v1(153.83,21.49)
  BOTTOM w0.076: U4.13 173.71,4.63 174.19,5.11 174.19,7.04 174.42,7.27 177.84,7.27 179.4,8.84 v1(179.42,8.84) 180.05,8.21 181.41,8.21 181.72,8.52 v1(181.72,8.61) ; v3(159.74,26.99) 159.64,27.09 159.64,27.48 T18.1 160.6,27.53 RH33.2
XDP_TRST#: length 27.8
  TOP w0.076: JXDP1.54 197.26,7.49 197.14,7.61 196.96,7.61 196.77,7.8 195.7,7.8 195.35,8.14 v3(194.76,8.14)
  IN4 w0.076: v1(173.71,9.99) 174.08,10.36 177.02,10.36 177.13,10.46 179.17,10.46 179.91,9.72 180.56,9.72 181.43,10.6 186.57,10.6 186.85,10.32 190.26,10.32 191.34,9.24 193.52,9.24 194.62,8.14 v3(194.76,8.14)
  BOTTOM w0.076: v2(195.18,7.8) 195.1,7.8 v3(194.76,8.14) ; v1(173.71,9.99) U4.4
XTAL24_IN: length 27.5
  IN4 w0.076: v1(120.56,3.68) 120.56,2.99 120.97,2.57 130.14,2.57 132.91,5.35 134.34,5.35 134.64,5.65 136.2,5.65 137.96,7.41 137.96,8.5 v1(138.04,8.58)
  BOTTOM w0.076: YH2.3 118.52,3.35 CH6.1 119.75,3.35 120.08,3.68 v1(120.56,3.68) 120.56,2.91 v2(120.76,2.71) ; UCPU1.AR44 138.97,10.2 138.14,9.37 138.14,8.68 v1(138.04,8.58)
XTAL24_OUT: length 28.9
  IN4 w0.076: v1(137.8,8.92) 137.63,8.75 137.63,7.55 136.06,5.98 134.46,5.98 134.16,5.68 132.77,5.68 130.01,2.91 121.21,2.91 120.99,3.12 120.99,3.58 v1(121.08,3.67)
  BOTTOM w0.076: UCPU1.AP45 137.8,9.4 v1(137.8,8.92) ; v1(121.08,3.67) 121.08,4.07 RH27.1 120.18,4.59 120.05,4.46 CH5.1 119.62,4.41 119.62,4.01 119.39,3.78 116.75,3.78 YH2.1
N13240801: length 11.1
  IN4 w0.254: v1(268.13,16.97) 269.92,16.97 270.29,16.6 271.41,16.6 v1(271.81,16.2)
  BOTTOM w0.076: v1(271.81,16.2) v2(271.81,17.22)
  BOTTOM w0.254: v1(271.81,16.2) 272.18,16.2 272.45,16.46 274.32,16.46 PQ900.4 ; PR903.2 268.59,17.11 268.45,16.97 v1(268.13,16.97) 267.61,16.45 267.61,16.23 267.79,16.06 PU900.1
N13240823: length 8.1
  BOTTOM w0.076: PR909.1 260.76,15.08 260.52,14.84 260.52,13.9 v2(260.74,13.69)
  BOTTOM w0.254: PR907.2 PR911.1 PC906.1 ; PU900.5 262.66,14.11 PC906.1 ; PC906.1 262.62,14.17 PR909.1
N13240827: length 18
  IN4 w0.254: v1(265.2,15.38) 265.87,16.06 269.36,16.06 269.8,15.62 270.74,15.62 271.08,15.28 271.47,15.28 271.98,15.79 273.56,15.79 273.72,15.63 v1(273.72,15.56)
  BOTTOM w0.076: PR910.2 261.29,16.52 261.29,17.98 261.58,18.27 v2(262.37,18.27)
  BOTTOM w0.254: PR910.2 262.62,15.18 PR909.2 262.95,15.41 PU900.7 265.2,15.41 265.2,15.41 v1(265.2,15.38) ; PQ900.5 273.95,15.33 v1(273.72,15.56)
N13240889: length 25.8
  IN4 w0.254: v3(282.63,17.58) 282.6,17.58 282.33,17.32 281.72,17.32 280.49,16.09 280.49,11.88 279.88,11.27 275.21,11.27 274.56,11.92 274.56,15.26 273.68,16.13 v1(273.51,16.13)
  BOTTOM w0.076: v2(281,13.38) 281,17.2 281.11,17.32 PR904.2
  BOTTOM w0.254: PR904.2 282.48,17.32 282.63,17.47 v3(282.63,17.58) 282.82,17.78 PU901.1 ; v1(273.51,16.13) 273.36,15.98 PQ900.3
N13240891: length 3.6
  BOTTOM w0.254: PU902.4 282.82,15.83 v2(283.3,16.3) 283.6,16.6 283.6,17.73 283.47,17.86 PU901.2
N13240897: length 4.7
  BOTTOM w0.254: PR906.1 285.84,13.26 285.43,13.67 PU902.1 284.12,13.1 283.8,12.78 v2(283.71,12.78) 283.47,13.01 PU902.2
N13240925: length 7.3
  BOTTOM w0.076: v2(268.87,12.86) 269.06,13.05 PR905.1
  BOTTOM w0.254: PC903.1 270.37,14.6 271.43,14.6 PR900.2 PR902.1 ; PC903.1 269.14,14.76 PU900.3 ; PC903.1 PR905.1
N13240953: length 25.4
  IN4 w0.254: v1(272.9,15.33) 272.9,15.33 274.23,14 274.23,11.78 275.07,10.94 280.02,10.94 280.82,11.74 280.82,15.95 281.76,16.88 283.53,16.88 v1(284.12,17.48)
  BOTTOM w0.076: PC904.1 286.08,14.42 286.08,13.91 286.29,13.69 286.76,13.69 v2(287.21,13.25)
  BOTTOM w0.254: v1(284.12,17.48) PU901.4 284.12,16.24 284.69,15.68 284.82,15.68 PC904.1
N13282828: length 26.2
  TOP w0.076: v3(237.5,32.73) v2(237.5,32.22)
  IN1 w0.508: v3(237.5,32.73) 238.73,33.96 238.73,35.95 244.51,41.72 246.2,41.72 v3(246.8,41.13)
  BOTTOM w0.508: PR43.1 253.73,40.92 253.31,41.34 251.31,41.34 249.72,39.76 247.51,39.76 247.23,40.05 PR77.2 247.23,40.7 v3(246.8,41.13) 246.24,41.69 PR7.1 ; PQ8.1 v3(237.5,32.73)
N13290509: length 8.8
  BOTTOM w0.076: PR508.1 71.17,22.36 v2(71.17,19.73)
  BOTTOM w0.254: PR521.1 71.67,22.85 PR508.1 72.58,22.85 PR505.2 73.54,22.95 PC508.2 74.82,22.88 75.18,22.52 PU500.4
N13291543: length 8.6
  BOTTOM w0.254: PR521.2 71.67,19.09 72.02,18.74 77.03,18.74 77.58,18.19 PQ7.1
N13321827: length 6.7
  BOTTOM w0.076: v2(300.24,9.49) PQ101.3
  BOTTOM w0.254: PQ101.3 300.24,11.57 299.17,12.64 299.17,13.57 299.41,13.81 PR103.1 PR130.2
N17205976: length 2.5
  BOTTOM w0.076: JDEG1.1 294.97,94.22 294,93.26 R234.2
N22841841: length 0.9
  BOTTOM w0.076: 74.71,48.86 v2(74.71,49.71)
N34536136: length 4.4
  BOTTOM w0.076: T1.1 126.02,19.82 126.02,17.59 126.31,17.3 UCPU1.B25
N35032609: length 29.1
  IN2 w0.076: v4(113.45,27.02) 113.61,26.85 113.61,26.45 114.27,25.79 114.67,25.79 114.67,25.79 115.17,25.79 115.47,26.09 115.47,26.91 116.76,28.2 124.44,28.2 127.87,24.77 127.87,23.73 128.23,23.37 130.05,23.37 130.36,23.06 130.36,22.83 130.43,22.76 130.43,22.7 131.02,22.1 131.55,22.1 131.89,21.76 131.89,21.38 v4(132.04,21.23)
  IN4 w0.076: v1(131.91,21.62) 131.91,21.36 v4(132.04,21.23) ; v1(113.02,27.02) v4(113.45,27.02)
  BOTTOM w0.076: v1(113.02,27.02) 112.41,27.63 111.81,27.63 111.53,27.91 111.53,28.49 v2(112.32,29.28)
N36180324: length 2.5
  BOTTOM w0.076: v2(115.15,29.05) CH49.1
  BOTTOM w0.254: CH49.1 RH137.2
N39815594: length 14.7
  IN1 w0.076: v4(165.01,14.34) 163.49,12.83 156.61,12.83 155.41,11.63 154.11,11.63 153.6,12.13 v4(153.6,12.84)
  IN4 w0.076: v1(153.77,12.38) 153.77,12.54 153.6,12.7 v4(153.6,12.84) ; v4(165.01,14.34) 165.09,14.27 v1(165.66,14.27)
N39815596: length 10.9
  IN1 w0.076: v4(154.19,12.46) 154.89,12.46 155.4,12.98 163.09,12.98 v4(163.89,13.78)
  IN4 w0.076: v1(154.2,12.13) 154.2,12.46 v4(154.19,12.46) ; v1(164.25,13.78) v4(163.89,13.78)
N39815598: length 9.8
  IN1 w0.076: v4(154.52,12.84) 154.81,13.13 162.17,13.13 v4(162.82,13.78)
  IN4 w0.076: v1(163.41,13.78) v4(162.82,13.78) ; v1(154.63,12.38) 154.63,12.73 v4(154.52,12.84)
N39815600: length 4.5
  IN4 w0.076: v1(159.41,12.13) 158.92,12.62 157.81,12.62 156.18,12.62 156.17,12.63 v1(155.07,12.63)
N39815609: length 11.2
  IN1 w0.076: v4(163.23,14.72) 162.93,14.72 161.64,13.44 154.61,13.44 154.32,13.73 v4(154.32,13.74)
  IN4 w0.076: v4(154.32,13.74) 154.32,13.73 154.47,13.73 154.63,13.58 154.63,13.57 154.96,13.24 v1(155.12,13.24) ; v1(163.23,15.37) v4(163.23,14.72)
N39815611: length 10.4
  IN1 w0.076: v4(163.21,14.19) 162.75,14.19 161.84,13.29 v4(154.15,13.29)
  IN4 w0.076: v1(154.62,13.24) 154.57,13.29 v4(154.15,13.29) ; v1(163.71,14.19) v4(163.21,14.19)
N40621945: length 4
  BOTTOM w0.076: R33.2 v2(236.54,12.08)
  BOTTOM w0.254: R33.2 237.53,11.73 238.22,11.03 238.22,10.44 238.42,10.25 Q3.1
N41500627: length 3
  BOTTOM w0.076: U28.1 87.96,35.24 C111.1 89.18,35.46 v2(89.18,35.03)
N41500629: length 4.2
  BOTTOM w0.076: U28.15 85.13,36.71 R156.1 83.87,37.98 83.87,38.68 v2(84.57,39.38)
N41500729: length 0.5
  BOTTOM w0.076: 85.19,31.45 v2(84.71,31.45)
N41505847: length 1.6
  BOTTOM w0.076: U28.16 85.63,37.23 R157.1
N41869823: length 1.6
  BOTTOM w0.076: C108.1 86.13,37.22 U28.17
N42233415: length 6.3
  IN1 w0.076: JNGFF1.42 17.5,31.27 v3(17.36,31.41)
  BOTTOM w0.076: v3(17.36,31.41) 17.14,31.41 16.9,31.65 v2(16.9,31.66) 16.9,31.84 17.13,32.07 R65.1
N42775202: length 4.3
  BOTTOM w0.076: RH25.1 117.53,24.13 Q1.1 117.53,25.36 118.06,25.89 118.06,27.49 v2(118.44,27.87)
N43454028: length 0.8
  BOTTOM w0.076: 230.22,28.45 v2(230.22,27.63)
N43599831: length 2.4
  BOTTOM w0.076: Q1.2 116.88,24.03 116.83,23.98 R1.1 116.81,23.97 116.23,24.56 Q1.3
N44370994: length 5.7
  BOTTOM w0.076: U27.12 299.01,63.66 C104.1 299.59,64.24 299.59,65.61 299.81,65.83 300.61,65.83 v2(300.9,66.12)
N44372336:
  vias: v2(296.43,62.36)
N44373242: length 2.1
  BOTTOM w0.076: C105.1 298.21,63.66 v2(298.21,62.79) U27.10
N44377351: length 6.8
  BOTTOM w0.076: v2(71.04,43.82) 71.04,45.15 71.16,45.27 71.84,45.27 72.38,45.8 C98.1 73.19,45.81 73.37,45.99 73.37,47.21 73.89,47.74 U26.12
N44380707: length 4.5
  BOTTOM w0.076: U29.12 33.71,44.26 34.07,44.62 C113.1 34.53,45.56 34.53,46.54 v2(34.08,46.98)
N44531503: length 4.4
  BOTTOM w0.076: v2(234.36,29.88) 232.65,29.88 232.24,29.47 C93.1
  BOTTOM w0.203: C93.1 232.13,29.54 U25.12
N44535135: length 2.1
  BOTTOM w0.203: C94.1 v2(231.3,30.45) 231.2,30.34 U25.10
N44948988: length 4.5
  BOTTOM w0.076: UD5.L8 131.73,51.01 v2(134.55,51.01) 135.34,51.01 RD9.1
N44951196: length 12.4
  BOTTOM w0.076: UD6.L8 118.75,50.5 119.12,50.87 120.41,50.87 120.94,51.4 120.94,54.1 121.6,54.75 121.6,56.43 RD10.1 122.73,57.56 122.73,58.4 122.36,58.77 121.24,58.77 v2(120.99,58.51)
N44953884: length 8.7
  BOTTOM w0.076: RD13.1 89.19,56.53 89.29,56.43 89.52,56.43 90.97,54.98 90.97,51.22 90.62,50.87 89.64,50.87 UD7.L8
N44956010: length 11.3
  BOTTOM w0.076: v2(101.26,58.49) 101.03,58.26 101.03,57.7 RD14.1 100.37,56.71 101.45,55.63 102.74,55.63 103.24,55.14 103.24,53.08 103.44,52.88 103.44,51.56 102.87,51 102.4,51 101.91,50.5 UD8.L8
N44984260: length 9.9
  BOTTOM w0.076: UD1.L8 177.39,50.5 177.76,50.87 179.06,50.87 179.59,51.4 179.59,55.54 RD1.1 177.89,56.84 v2(177.23,56.84)
N44985933: length 16.5
  BOTTOM w0.076: v2(197.56,57.31) 196.51,58.36 191.26,58.36 191.15,58.24 191.15,57.65 RD2.1 190.54,56.67 191.55,55.66 191.55,51.4 191.16,51.01 190.38,51.01 UD2.L8
N44994261: length 11.3
  BOTTOM w0.076: UD3.L8 148.29,50.87 149.26,50.87 151.17,52.77 RD5.1 150.67,57.54 150.67,58.13 150.25,58.55 v2(149.27,58.55)
N44996448: length 12
  BOTTOM w0.076: UD4.L8 160.55,50.5 161.05,51 161.52,51 162.08,51.56 162.08,56.03 RD6.1 160.53,57.59 160.53,58.26 160.13,58.65 158.24,58.65 v2(158.09,58.5)
N45067794: length 5.5
  BOTTOM w0.102: RD27.1 145.15,57.52 145.15,58.34 145.4,58.59 147.43,58.59 v2(147.86,58.16)
  BOTTOM w0.254: RD27.1 CD73.2
N45067802: length 3.4
  BOTTOM w0.102: v2(122.51,55.46) 122.67,55.46 RD28.1
  BOTTOM w0.254: RD28.1 CD74.2
N45067875: length 1
  BOTTOM w0.254: RD20.1 CD72.2
N45134129: length 12.5
  BOTTOM w0.076: UD1.L9 178.19,50.37 179.25,50.37 180.05,51.17 180.05,56.09 RD3.1 179.58,57.51 179.58,58.18 179.14,58.61 v2(177.21,58.61)
N45134345: length 12.7
  BOTTOM w0.076: v2(196.26,57.34) 195.63,57.98 192.45,57.98 191.55,57.08 RD4.1 191.55,56.29 191.78,56.06 191.78,51.25 191.03,50.5 UD2.L9
N45134724: length 8.6
  BOTTOM w0.076: UD3.L9 149.73,50.5 151.81,52.58 v2(151.81,55.64) 151.81,56.67 RD7.1
N45134937: length 13.8
  BOTTOM w0.076: v2(156.65,58.45) 156.65,58.59 156.98,58.92 160.8,58.92 161.63,58.09 161.63,57.5 RD8.1 162.24,56.89 162.24,51.5 161.33,50.59 UD4.L9
N45136338: length 3.6
  BOTTOM w0.076: UD5.L9 135.1,50.5 RD11.1
N45136742: length 9.4
  BOTTOM w0.076: UD6.L9 119.54,50.37 120.61,50.37 121.41,51.17 121.41,52.19 122.57,53.34 v2(122.57,53.76) 122.57,54.19 122.12,54.64 122.12,55.94 RD12.1
N45137119: length 11.2
  BOTTOM w0.076: UD7.L9 90.75,50.5 91.27,51.02 91.27,55.29 90.21,56.35 RD15.1 90.21,57.03 90.68,57.5 90.68,58.22 90.83,58.37 91.62,58.37 v2(92.25,57.74)
N45137332: length 8.8
  BOTTOM w0.076: v2(101.24,56.56) 101.24,56.78 101.53,57.06 102.12,57.06 RD16.1 102.14,56.53 103.39,55.29 103.39,53.15 103.59,52.94 103.59,51.5 102.68,50.59 UD8.L9
N45346942: length 3.8
  BOTTOM w0.076: U26.10 73.88,46.94 73.59,46.65 73.59,45.67 v2(73.37,45.45) 72.72,44.8 C99.1
N45347364: length 2.1
  BOTTOM w0.076: U29.10 32.91,44 v2(33.06,44.14) C114.1
N47519532:
  vias: v2(252.42,18.57)
N48029100: length 1.1
  BOTTOM w0.076: PC612.1 v2(220.52,13.96)
N48096052: length 5.8
  BOTTOM w0.076: PR306.1 277.1,31.11 276.62,31.59 275.99,31.59 275.78,31.81 275.78,33.27 v2(276.2,33.69)
  BOTTOM w0.203: PR306.1 277.75,31.08 278.13,30.7 278.29,30.7 278.49,30.5 PU300.19
N48096365: length 1.5
  BOTTOM w0.076: PR310.2 275.14,26.47 v2(274.67,26)
N48096452: length 1
  BOTTOM w0.076: PC306.1 275.02,30.07 v2(274.9,30.18)
N49570867: length 7.1
  BOTTOM w0.203: PR500.1 PR501.1 PC500.1 73.5,27.89 73.6,27.79 73.6,27.44 73.69,27.35 73.69,26.62 74.53,25.78 v2(74.53,25.05) 74.53,24.93 75.58,23.87 PU500.1
N49813715: length 14.2
  IN4 w0.076: v1(115.3,14.29) 115.55,14.54 119.37,14.54 121.37,16.54 125.94,16.54 126.24,16.25 127.21,16.25 127.28,16.32 127.86,16.32 127.97,16.44 v1(128.38,16.44)
N50118236: length 4.2
  BOTTOM w0.254: C124.1 R170.2 R171.2 88.06,25.49 v2(87.79,25.76) 87.79,25.99 87.5,26.28 Q11.4
N50118262: length 4.2
  BOTTOM w0.076: R170.1 90.13,26.87 v2(90.55,26.87) 91.18,26.23 91.18,26.07 91.48,25.77 92.27,25.77 Q12.3
N50118264: length 2.6
  BOTTOM w0.076: Q12.6 91.59,25.01 91.11,25.49 v2(90.57,25.49) R171.1
N50119442: length 5.4
  BOTTOM w0.254: C127.1 88.48,21.18 R179.2 R177.2 88.62,22.19 88.14,21.71 v2(88.02,21.71) Q15.4
N50119466: length 4.8
  BOTTOM w0.076: R177.1 91.34,20.76 v2(91.34,20.08) 91.34,19.21 90.88,18.75 Q16.3
N50119468: length 1.8
  BOTTOM w0.076: Q16.6 88.77,20.05 R179.1
N50121680: length 5.1
  BOTTOM w0.076: Q19.4 84.14,15.87 84.07,15.8 84.07,15.14 v2(84.14,15.08) 84.14,14.24 C130.1 R185.2 R187.2
N50121692: length 2.1
  BOTTOM w0.076: v2(83.91,13.48) R185.1 83.91,11.48 Q20.3
N50121694: length 5
  BOTTOM w0.076: v2(86.73,13.52) 86.6,13.39 R187.1 86,11.94 85.47,11.94 85.08,11.55 85.08,10.25 85.22,10.11 Q20.6
N50198050: length 14
  IN4 w0.254: v1(108.98,24.63) 108.75,24.86 101.46,24.86 v1(101.08,25.24) 99.64,25.24 v1(99.13,25.75)
  BOTTOM w0.076: v2(98.61,27.41) 98.61,27.23 99.13,26.71 v1(99.13,25.75)
  BOTTOM w0.254: RH144.2 RH147.2 109.15,24.63 v1(108.98,24.63)
N50266102: length 12.4
  IN4 w0.076: v3(29.34,48.41) 29.34,49.3 31.02,50.98 31.02,56 v1(31.75,56.72)
  BOTTOM w0.076: R76.1 30,46.99 30,47.76 v2(29.75,48.01) 29.36,48.41 v3(29.34,48.41) ; JNGFF3.60 32,56.98 v1(31.75,56.72)
N50817741: length 8.7
  IN4 w0.508: v1(256.79,24.09) 248.94,24.09 248.37,24.65 v1(248.37,24.65)
  vias: v2(257.02,26.41)
N50817746: length 6.7
  IN4 w0.508: v1(252.96,23.14) 253.31,23.5 256.6,23.5 v1(257.67,22.43)
  BOTTOM w0.076: v1(257.67,22.43) 257.67,23.69 v2(257.54,23.82)
N50817748: length 6.1
  BOTTOM w0.508: PQ701.3 251.2,25.09 PC700.2 PR702.1 PR701.2 253.2,23.82 v2(253.86,23.82) 254.1,23.82 254.72,24.44 PC701.2
N50817758: length 14.6
  IN4 w0.254: v1(255.31,25.47) 254.84,25.94 248.41,25.94 248.02,26.33 248.02,28.77 248.55,29.3 249.31,29.3 249.62,29.61 249.62,30.21 v1(249.61,30.21)
  BOTTOM w0.102: v1(255.31,25.47) 254.95,25.47 v2(254.44,24.96)
  BOTTOM w0.203: v1(249.61,30.21) PU700.3
N50817759: length 2.1
  BOTTOM w0.254: PQ701.2 250.25,23.7 250.07,23.52 250.07,22.98 250.3,22.75 PQ701.1
N50817763: length 20.2
  TOP w0.254: v3(248,36.99) 241.42,36.99 240.55,37.86 240.55,42.79 240.89,43.13 v3(240.89,43.16)
  BOTTOM w0.102: PR720.1 247.09,36.99 246.5,37.57 v2(246.5,39.48)
  BOTTOM w0.203: PC721.2 248.81,36.83 PU700.17
  BOTTOM w0.254: PC721.2 248.65,36.99 v3(248,36.99) PR720.1 ; v3(240.89,43.16) 240.55,42.82 PR41.1
N50817815: length 13.2
  IN4 w0.254: v1(251.41,23.6) 251.38,23.57 248.56,23.57 247.69,24.45 247.69,28.91 248.59,29.81 248.68,29.81 v1(249.01,30.14)
  BOTTOM w0.102: v2(251.89,22.16) PR702.2
  BOTTOM w0.203: v1(249.01,30.14) 249.21,30.35 PU700.4
  BOTTOM w0.254: PR702.2 251.89,23.46 251.75,23.6 v1(251.41,23.6)
N50817862: length 12.7
  BOTTOM w0.076: v2(241.12,26.11) 241.62,25.62 PQ709.1
  BOTTOM w0.203: PU700.6 248.41,30.61 247.74,29.94 PC707.2
  BOTTOM w0.254: PR709.2 PC707.2 247.69,29.25 PR707.2 246.15,28.73 246.15,28.13 244.23,26.22 242.91,26.22 241.66,24.97 241.63,24.97 PQ709.1
N50817876: length 8.8
  IN4 w0.254: v1(244.84,28.8) 247.11,28.8 248.45,30.14 v1(248.47,30.14)
  BOTTOM w0.102: v1(244.84,28.8) 245.64,28.8 v2(245.78,28.66)
  BOTTOM w0.203: PU700.5 248.81,30.48 v1(248.47,30.14)
  BOTTOM w0.254: PR710.2 244.03,26.74 244.84,27.55 PR711.2 v1(244.84,28.8)
N50817886: length 6.8
  BOTTOM w0.203: 247.41,30.45 247.71,30.45 248.01,30.75 PU700.7
  BOTTOM w0.254: PR713.2 242.78,30.29 244.36,30.29 PC715.2 245.62,29.81 v2(245.82,30.02) 246.25,30.45 247.41,30.45
N50817889: length 5.7
  BOTTOM w0.203: PC716.2 245.35,30.83 v2(245.97,31.45) 246.44,31.91 PU700.8
  BOTTOM w0.254: PC716.2 244.36,31.31 242.78,31.31 PR715.2
N50817892: length 8.8
  IN4 w0.254: v1(241.54,34.97) 241.54,33.84 242.96,32.41 v3(242.96,31.84)
  BOTTOM w0.203: PU700.9 246.15,32.31 245.68,31.84 v2(244.12,31.84) v3(242.96,31.84)
  BOTTOM w0.254: PR716.2 v3(242.96,31.84)
N50817915: length 5.2
  BOTTOM w0.203: 245.81,32.5 246.02,32.71 PU700.10
  BOTTOM w0.254: 245.81,32.5 245.68,32.38 242.78,32.38 PR714.2
N50817928: length 5.2
  BOTTOM w0.076: PC703.2 251.42,29.3 v2(251.66,29.55)
  BOTTOM w0.203: PC703.2 250.41,29.58 PU700.1
  BOTTOM w0.254: PC703.2 251.43,28.55 PC704.1 PR704.1
N50817929: length 7.5
  IN4 w0.203: v1(248.32,36.24) 248.78,36.7 252.13,36.7 v1(252.36,36.92)
  BOTTOM w0.076: PR723.1 252.72,37.86 253.13,38.28 v2(253.18,38.28)
  BOTTOM w0.203: PU700.16 248.41,36.15 v1(248.32,36.24)
  BOTTOM w0.254: PR721.2 252.26,36.97 PR723.1
N50817930: length 6.4
  BOTTOM w0.076: PC702.2 249.17,28.22 249.04,28.1 249.04,27.4 248.91,27.26 v2(248.16,27.26)
  BOTTOM w0.203: PU700.2 250.01,29.55 PC703.1
  BOTTOM w0.254: PC703.1 249.72,29.25 PC702.2 250.76,28.22 PR703.1
N50817943: length 26.8
  IN4 w0.254: v1(266.62,41.21) 266.62,42.4 266.4,42.62 265.21,42.62 263.82,44.01 259.18,44.01 258,42.83 258,39.82 257.47,39.29 251.99,39.29 251.37,38.67 v1(251.37,37.86)
  BOTTOM w0.102: v2(252.31,35.88) 252.31,36.06 PC724.1
  BOTTOM w0.203: PU700.20 250.01,35.87 250.45,36.31 250.84,36.31 PC724.1
  BOTTOM w0.254: PC724.1 251.37,37 v1(251.37,37.86)
N50817947: length 25.2
  IN4 w0.254: v1(266.62,43.83) 266.61,43.82 266.61,43.17 266.46,43.02 265.31,43.02 263.94,44.39 259.09,44.39 257.67,42.97 257.67,39.96 257.33,39.62 251.85,39.62 250.48,38.24 v1(250.48,37.86)
  BOTTOM w0.203: PU700.19 249.61,36 PC724.2
  BOTTOM w0.254: v1(250.48,37.86) 250.48,36.97 PC724.2
N50817961: length 6.2
  BOTTOM w0.076: v2(243.24,37.44) 243.71,36.97 PR722.2
  BOTTOM w0.203: PR722.2 246.54,36.47 247.48,36.47 248.01,35.94 PU700.15
N50817990: length 2
  BOTTOM w0.203: PU700.18 249.21,36.59 PR718.1
N51581707: length 1.4
  BOTTOM w0.076: v2(239.01,16.7) 239.61,17.3 R161.1
N51581718: length 2.5
  BOTTOM w0.076: C121.1 v2(242.78,18.46)
  BOTTOM w0.254: C121.1 242.76,19.52 U24.6
N51582271:
  vias: v2(10.09,40.26)
N51582977: length 1.4
  BOTTOM w0.076: R292.1 74.45,44.8 v2(73.66,44.01)
N51584481: length 0.9
  BOTTOM w0.076: 299.87,62.4 v2(300.8,62.4)
N51589797:
  vias: v2(35.66,43.88)
N51592304: length 3.2
  BOTTOM w0.076: R160.1 232,31.44 232.43,31 234.48,31 v2(234.66,31.18)
N51594594: length 2.3
  BOTTOM w0.076: U30.12 14.08,40.84 v2(14.25,40.67) 14.5,40.67 14.82,40.99 C34.1
N51597050:
  vias: v2(31.13,43.63)
N51600655:
  vias: v2(14.29,36.59)
N51600691:
  vias: v2(14.27,39.39)
N51600744: length 2.2
  BOTTOM w0.076: U33.12 14.93,37.29 C132.1
N51600766: length 2.3
  BOTTOM w0.076: U33.10 v2(14.34,38.09) 14.71,38.09 C135.1
N52122807: length 29.2
  IN1 w0.508: v3(248.14,42.9) 248.7,42.9 250.68,40.92 v3(255.81,40.92)
  IN4 w0.254: v1(242.81,36.61) 241.01,36.61 240.32,35.92 240.32,31.36 v1(239.58,30.62) ; v1(247.25,42.77) 246.21,41.72 246.21,37.46 245.36,36.61 v1(245.36,36.61)
  BOTTOM w0.076: v3(255.81,40.92) 255.81,40.94 v2(256.32,41.44)
  BOTTOM w0.254: v1(242.81,36.61) 242.86,36.66 245.31,36.66 v1(245.36,36.61) ; PR8.1 250.18,41.88 PR58.1 ; PR44.1 v3(255.81,40.92)
N52128481:
  vias: v2(274.46,17.04)
N52131952: length 7.1
  BOTTOM w0.076: PR330.2 285.23,33.57 v2(284.72,34.08)
  BOTTOM w0.203: PU300.6 282.42,30.9 282.57,31.06 282.57,31.27 282.71,31.41 285.61,31.41 285.75,31.55 285.75,32.59 PR330.2
N52518612: length 2.1
  BOTTOM w0.076: Q48.2 61.89,4.58 R390.2 R391.2
N52542818: length 1.5
  BOTTOM w0.076: U53.A1 56.81,4.28 R362.1
  BOTTOM w0.097: U53.B1 U53.A1
N52542819: length 1
  BOTTOM w0.076: U53.C1 57.37,3.15 R363.1
N52542820: length 1
  BOTTOM w0.076: U53.D1 57.46,2.65 R364.1
N52674055: length 22.1
  IN1 w0.508: v3(241.23,41.9) 243.73,41.9 244.23,42.41 246.58,42.41 247.95,41.04 v3(248.78,41.04)
  IN4 w0.508: v1(239.58,32.56) 239.58,36.63 242.35,39.4 242.35,40.78 v3(241.23,41.9)
  BOTTOM w0.102: v3(248.78,41.04) 248.78,40.68 v2(249.13,40.33)
  BOTTOM w0.508: v3(241.23,41.9) PR9.1 ; PR8.2 249.29,41.55 v3(248.78,41.04)
N52697183: length 5.5
  BOTTOM w0.102: PR705.1 256.66,29.75 257.54,28.87 v2(257.54,28.33)
  BOTTOM w0.508: PR705.1 255.85,29.75 254.33,28.23 PD700.1
N52711885: length 3.5
  BOTTOM w0.102: PQ901.4 237.9,25.22 v2(238.19,24.93)
  BOTTOM w0.254: PD1.2 239.56,25.87 239.18,26.26 238.08,26.26 PQ901.4
N53141348:
  vias: v2(12.19,43.46)
N53141760: length 2.2
  BOTTOM w0.076: C133.1 14.38,42 v2(14.34,41.96) 14.02,41.64 U30.10
N53209975: length 2.2
  BOTTOM w0.076: v2(184.39,13.25) PC533.2
  BOTTOM w0.254: PC533.2 PR564.1
N53258922: length 11.7
  IN4 w0.076: v1(155.87,16.27) 156.03,16.11 157.4,16.11 157.56,16.27 162.07,16.27 162.35,16.55 164.96,16.55 v1(165.9,15.61)
  BOTTOM w0.076: R310.2 v2(165.82,16.63)
N53478108: length 3.1
  BOTTOM w0.076: U57.6 81.06,11.83 C238.1 81.37,11.54 82.41,12.58 v2(82.48,12.58)
N53657262: length 3.3
  BOTTOM w0.076: R142.2 226.3,29.56 226.79,29.06 v2(226.99,29.06)
  BOTTOM w0.203: U25.3 226.7,29.54 R142.2
N53764974: length 3.1
  BOTTOM w0.076: v2(183.68,23.58) 184.62,23.58 185.39,24.35 PR548.2
N53793451: length 5.6
  BOTTOM w0.076: v2(276.43,34.99) 276.95,34.47 276.95,33.52 277.1,33.37 PR331.1
  BOTTOM w0.203: 278.38,31.06 278.54,30.9 PU300.20
  BOTTOM w0.254: PR331.1 277.34,32.1 278.38,31.06
N53869491: length 0.9
  BOTTOM w0.076: C162.1 R231.2
N54019852: length 3.8
  BOTTOM w0.076: v2(300.67,48.12) 300.6,48.05 C218.1 299.76,48.73 299.49,49 298.97,49 298.39,49.58 U34.6
N54019866:
  vias: v2(297.22,49.09)
N54349775: length 10.4
  IN4 w0.508: v1(248.65,44.61) 253.26,44.61 v1(255.03,42.84)
  BOTTOM w0.076: v1(255.03,42.84) v2(256.28,42.84)
  BOTTOM w0.254: PR43.2 PR44.2 255.14,42.73 v1(255.03,42.84)
N54350306: length 3.2
  BOTTOM w0.076: v2(291.41,20.04) 292.06,19.4 PQ53.1
  BOTTOM w0.254: PQ53.1 293.41,19.4 293.61,19.6 PR48.2
N54350813: length 3.6
  BOTTOM w0.076: PQ53.2 294.05,17.5 v2(294.19,17.35)
  BOTTOM w0.254: PR60.2 PC60.1 292.53,17.05 PQ53.2
N54351061: length 7.1
  BOTTOM w0.254: PR60.1 294.3,15.91 293.91,15.52 v2(290.55,15.52) 290.26,15.52 289.66,16.12 PR61.2 289.41,16.71 PQ54.1
N54351819: length 3.4
  BOTTOM w0.076: v2(273.12,17.12) 273.5,17.5
  BOTTOM w0.102: PR95.1 273.62,17.63 273.5,17.5
  BOTTOM w0.508: PR95.1 272.4,18.08 272,18.47 PQ51.1
N54351962: length 3.8
  BOTTOM w0.076: PQ51.3 270.1,20.24 v2(270.7,20.84)
  BOTTOM w0.254: PR62.2 PR93.1 269.3,20.41 270.1,19.61 PQ51.3
N54352171: length 4.5
  BOTTOM w0.254: PQ51.2 269.7,18.31 268.99,19.02 268.18,19.02 PR63.2 266.93,18.51 PQ52.1
N54358925: length 2.1
  BOTTOM w0.254: PR913.2 PR530.2 78.83,15.2 PQ7.2
N54390062: length 6.3
  BOTTOM w0.076: v2(300.36,29.49) 300.18,29.67 PR75.1
  BOTTOM w0.254: PR72.2 299.04,29.58 PR80.1 299.4,29.23 PU904.3 ; PR72.2 PR75.1 ; PR72.2 PC70.1
N54390064: length 7.1
  BOTTOM w0.254: PR76.1 PR73.2 297.67,22.46 297.67,24.62 298.75,25.7 PU904.2
N54390136: length 11.6
  BOTTOM w0.254: PU904.1 298.1,28.69 298.31,28.91 PR80.2 297.45,29.4 297.29,29.57 v2(297.29,32.66) ; PQ62.2 298.78,32.66 v2(297.29,32.66) ; v2(297.29,32.66) 297.29,34.42 PR74.2
N54390171: length 3.9
  BOTTOM w0.076: PR78.2 v2(300.44,39.44)
  BOTTOM w0.254: PR70.1 298.26,41.32 PR71.1 PR78.2
N54390185: length 46.4
  IN4 w0.254: v1(301.28,19.11) 301.28,11.85 v1(301.28,11.85) 300.9,11.47 294.93,11.47 v1(294.87,11.53)
  BOTTOM w0.254: PQ60.2 v2(301.28,43.04) v1(301.28,19.11) ; PR79.1 294.87,18 v1(294.87,11.53)
N54390343: length 5.7
  BOTTOM w0.076: v2(300.49,37.12) PQ61.2
  BOTTOM w0.254: PQ61.2 299.31,36.55 299.81,36.06 PR81.2 299.81,35.28 298.27,33.75 PQ62.1
N54404550: length 4.1
  BOTTOM w0.076: v2(225.87,32.86) 225.78,32.95 PR46.1
  BOTTOM w0.254: PQ32.2 226.01,34.03 PR46.1
N54411628: length 3.2
  BOTTOM w0.076: v2(251.34,42.88) 251.85,42.38 PQ34.1
  BOTTOM w0.254: PR45.2 253.47,42.84 253.01,42.38 PQ34.1
N54411650: length 9.1
  BOTTOM w0.076: v2(255.7,38.85) 254.76,38.85 254.23,38.32 PR740.1
  BOTTOM w0.203: PU700.21 250.41,35.87 250.57,36.03 251.47,36.03 252.02,35.49 252.56,35.49 252.78,35.7 252.78,37.62 253.05,37.89 PR740.1
N54411767: length 2.5
  BOTTOM w0.076: v2(254.38,38.92) 254.14,39.17 PR49.1
  BOTTOM w0.254: PQ34.2 253.51,40.48 PR49.1
N54412068: length 5.9
  BOTTOM w0.076: v2(236.7,20.9) PQ6.2
  BOTTOM w0.254: PR55.2 240.59,22.39 240.31,22.11 PR56.2 239.62,22.18 PQ6.2
N54716504: length 1.5
  BOTTOM w0.076: U58.1 283.05,90.41 C261.1
N54825139: length 1.6
  BOTTOM w0.076: U59.6 78.42,41.06 C264.1
N54916658: length 5.1
  BOTTOM w0.076: Q48.1 60.92,4.03 R367.2 R366.2 v2(59.61,2.77)
N55068043: length 3
  BOTTOM w0.254: PQ60.1 297.85,43.08 v2(297.85,42.52) 299.05,41.32 PR71.2
N55068086: length 3
  BOTTOM w0.076: v2(297.56,39.44) 297.98,39.02 PQ61.1
  BOTTOM w0.254: PR70.2 298.66,39.64 PQ61.1
N55263746: length 2.5
  BOTTOM w0.076: R320.1 76.44,16.09 76.38,16.03 U56.7
N55267985: length 8.7
  BOTTOM w0.076: v2(239.96,34.17) PQ30.1
  BOTTOM w0.254: PQ30.1 239.96,37.8 240.61,38.45 240.61,38.98 239.19,40.4 PQ31.2 239.19,41.76 PR40.2
N55268579: length 6
  BOTTOM w0.254: PQ31.1 238.91,38.68 238.47,39.12 v2(238.47,42.33) 238.47,42.59 238.69,42.82 PR41.2
N55269036: length 12.3
  BOTTOM w0.254: PR67.2 230.87,34.52 v2(238.5,34.52) 238.9,34.52 239.31,34.94 PQ30.2
N55274703: length 24.2
  TOP w0.076: v3(246.48,22.89) v2(246.48,23.51)
  IN3 w0.254: v3(246.48,22.89) 246.48,25.15 246.95,25.62 252.49,25.62 253.55,26.69 253.55,34.39 v3(255.41,36.25)
  BOTTOM w0.254: PQ720.2 v3(246.48,22.89) ; PR770.2 v3(255.41,36.25)
N55277501: length 4.5
  BOTTOM w0.254: PQ720.1 245.51,19.79 PR771.1
N55277504: length 13.3
  IN4 w0.254: v1(247,26.61) 247,24.41 243.83,21.25 243.83,19.54 244.42,18.95 245.54,18.95 245.95,18.55 v1(245.95,18.44)
  BOTTOM w0.076: v2(247.93,25.92) 247.24,26.61 v1(247,26.61)
  BOTTOM w0.254: v1(245.95,18.44) 244.88,18.44 PR772.1
N55277649: length 65.2
  IN3 w0.254: v4(247.83,18.79) 248.78,18.79 249.7,17.86 252,17.86 253.79,16.07 261.63,16.07 263.12,14.58 263.12,14.56 v4(263.36,14.32)
  IN4 w0.254: v1(248.69,18.79) v4(247.83,18.79) ; v4(263.36,14.32) 263.36,14.01 263.95,13.42 269.65,13.42 269.98,13.09 271.65,13.09 272.4,12.34 272.4,11.02 274.31,9.11 280.78,9.11 282.65,10.99 282.65,14.6 282.88,14.82 284.13,14.82 285.82,16.52 v1(285.82,16.52)
  BOTTOM w0.254: PC760.1 285.82,15.81 v1(285.82,16.52) ; v1(248.69,18.79) 248.69,20.72 PR773.2 248.12,22.19 v2(247.1,23.21) 246.14,24.17 PR774.1 245.51,23.57 243,23.57 242.69,23.88 242.69,25.42 242.89,25.61 PQ709.2 244.2,25.61 244.55,25.96 PQ721.1
N55277894: length 26.8
  TOP w0.076: v3(236.6,25.11) v2(236.6,25.71)
  IN3 w0.254: v4(245.45,42.94) 244.54,42.03 244.54,28.32 243.56,27.35 238.57,27.35 236.6,25.38 v3(236.6,25.11)
  IN4 w0.254: v1(246.24,42.77) 245.63,42.77 v4(245.45,42.94)
  BOTTOM w0.254: v3(236.6,25.11) PQ901.6
N55924880: length 2.6
  BOTTOM w0.076: C273.1 R389.2 R72.2 50,2.54 R386.1
N62111964: length 3.5
  BOTTOM w0.076: v2(294.63,71.21) 295.01,71.59 295.01,72.47 295.25,72.71 Q26.2 296.02,72.71 R235.2
N93297419: length 3.1
  BOTTOM w0.076: U7.4 242.61,4.81 v2(242.76,4.96) 243,5.2 Q4.2
N93297423: length 1.3
  BOTTOM w0.076: R39.2 v2(240.24,9.75)
N115444004: length 2.2
  BOTTOM w0.254: PR540.1 183.84,19.1 PU702.9
N115444061: length 3.7
  BOTTOM w0.076: v2(192.25,22.13) 191.35,22.13 190.07,23.41 189.94,23.41 PC534.1
N115444065: length 22
  IN4 w0.254: v1(181.14,29.74) 181.14,29.68 180.41,28.96 180.41,25.38 182.73,23.07 182.73,15.65 184.01,14.37 v1(186.47,14.37)
  BOTTOM w0.076: v1(181.14,29.74) v2(179.87,29.74)
  BOTTOM w0.254: PR529.1 v1(186.47,14.37)
N115444070: length 11.1
  BOTTOM w0.254: PR546.1 180.19,20.92 v2(180.03,20.77) 179.78,20.52 179.14,20.52 178.28,21.38 176.29,21.38 175.91,21.76 175.91,24.07 176.45,24.62 178.6,24.62 PL504.2
N115444157: length 1.9
  BOTTOM w0.076: PC523.1 v2(181.43,13.02)
  BOTTOM w0.254: PR542.2 181.39,14.06 PC523.1
N115444179: length 6.9
  IN4 w0.254: v1(182.33,22.06) 180.62,20.35 v1(177.39,20.35)
  BOTTOM w0.102: v2(177.84,19.27) 177.39,19.71 v1(177.39,20.35)

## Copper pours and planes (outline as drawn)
1.35V_B+ on BOTTOM: 223.48,20.77 216.7,20.77 216.39,20.46 216.39,18.64 216.32,18.56 215.71,18.56 215.63,18.48 215.63,18.03 215.71,17.95 222.18,17.95 222.41,18.18 224.32,18.18 224.39,18.25 224.39,18.86 223.78,19.47 223.78,20.46
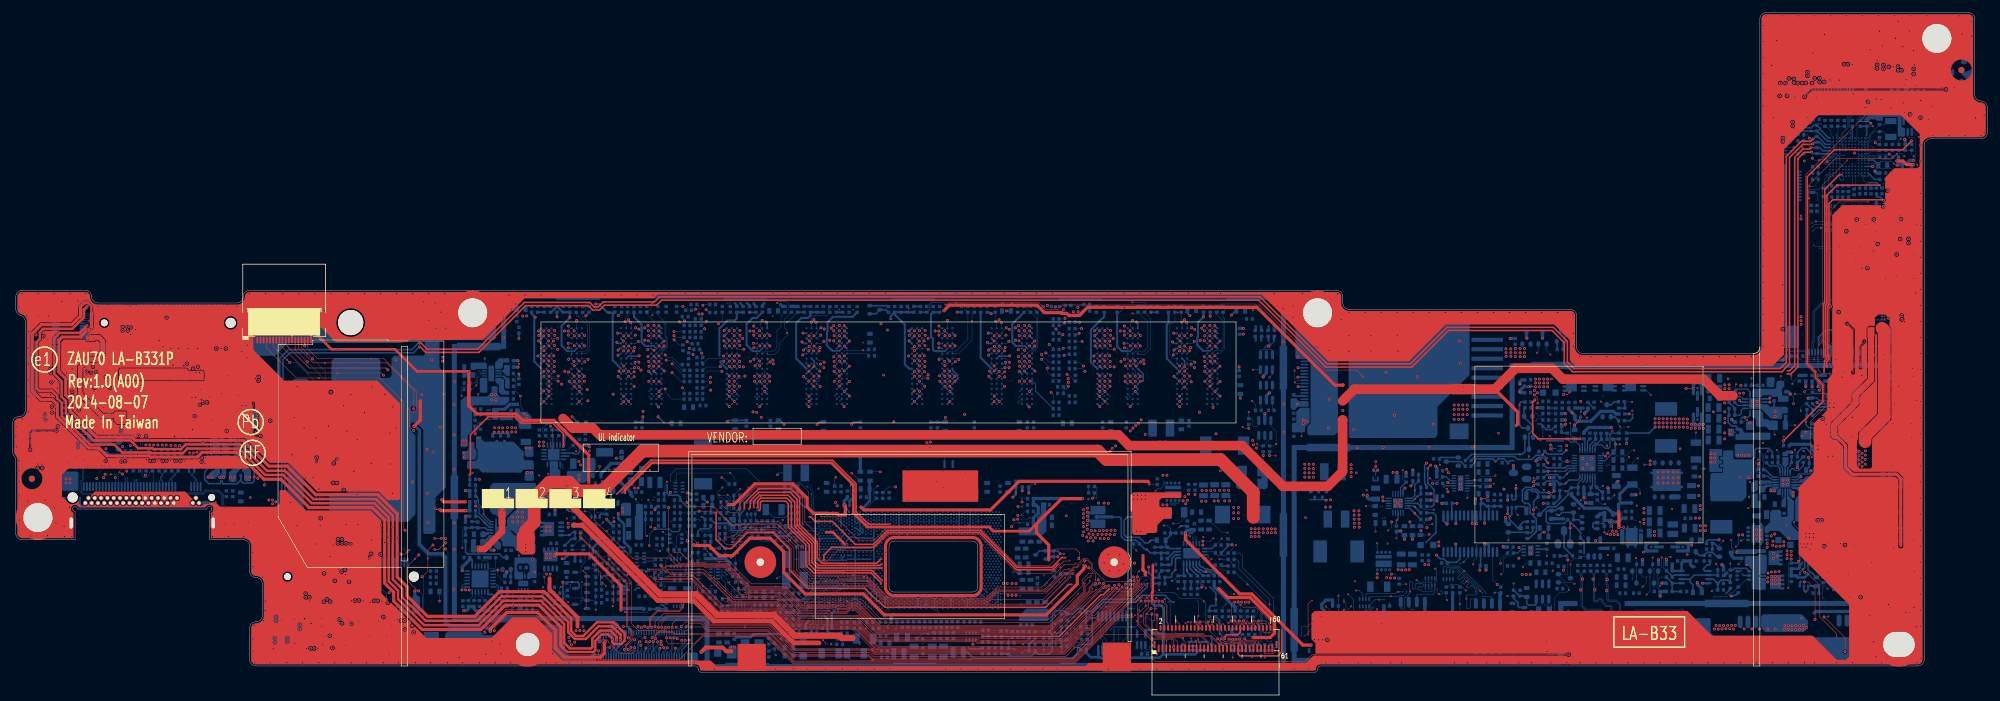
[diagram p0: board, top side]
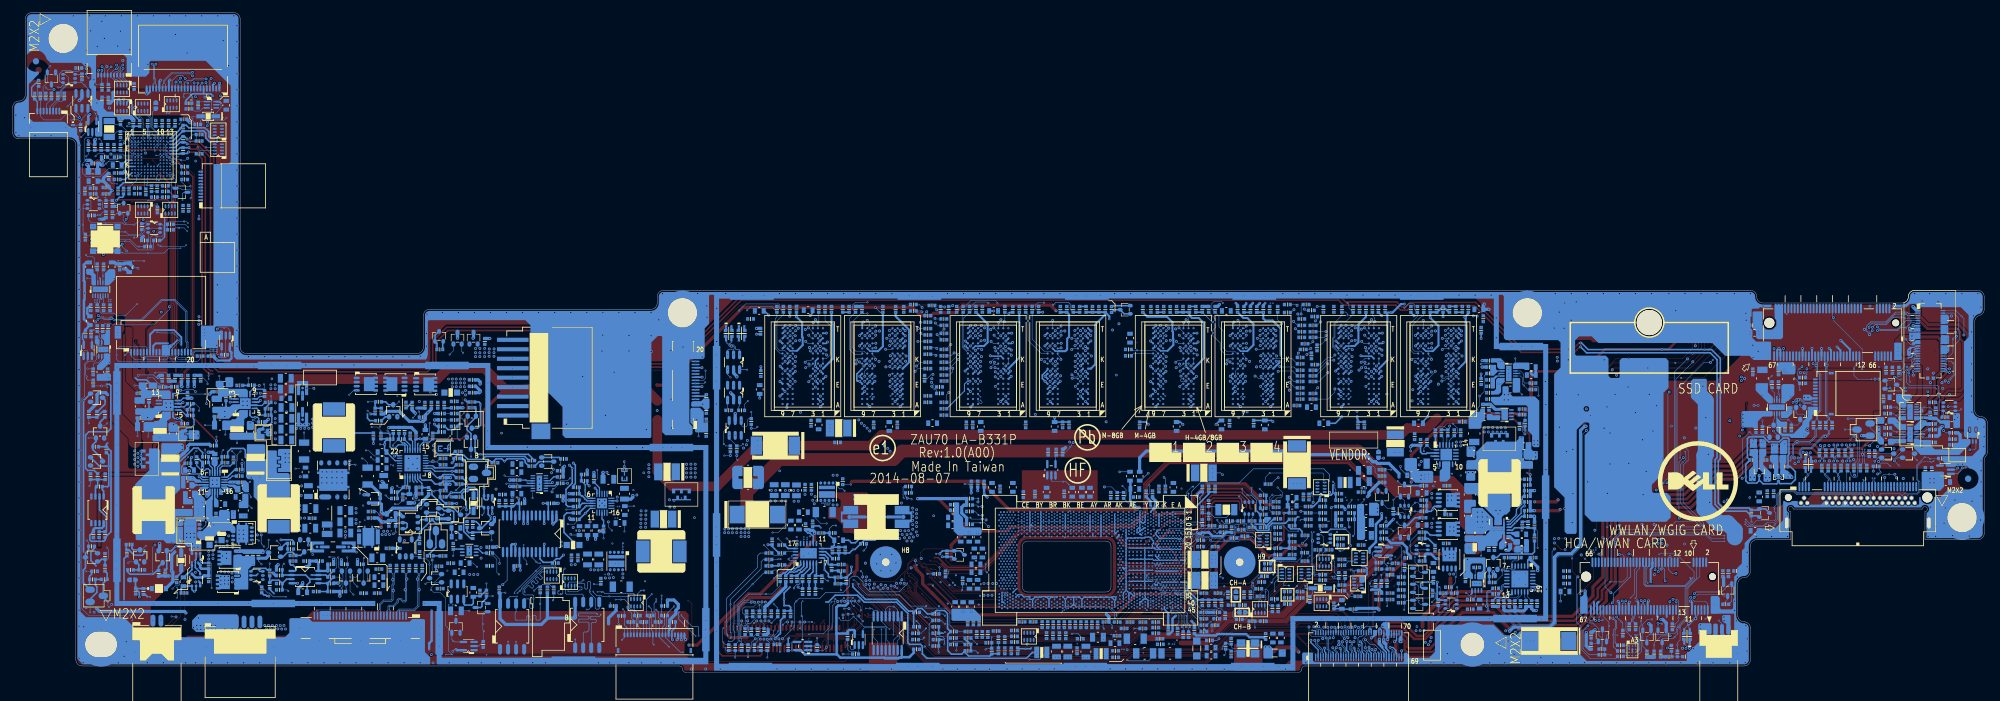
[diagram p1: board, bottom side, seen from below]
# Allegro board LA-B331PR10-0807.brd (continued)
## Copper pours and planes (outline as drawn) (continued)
3/5V_B+ on BOTTOM (solid shape): 281.01,29.05 281.01,28.01 281.93,27.09 281.93,24.18 281.53,23.79 281.53,23.32 282.5,22.35 283.07,22.35 283.26,22.15 283.26,21.42 282.79,20.95 281.01,20.95 279.57,22.4 278.15,22.4 277.79,22.03 277.33,22.03 277.25,22.11 277.25,22.95 278.12,23.82 278.12,25.42 278.42,25.72 279.64,25.72 279.87,25.49 279.87,24.73 279.94,24.66 280.71,24.66 280.86,24.81 280.86,27.25 280.78,27.32 280.78,29.02 280.86,29.1 280.96,29.1
+0.675VS on BOTTOM: 215.02,32.66 215.02,31.51 215.1,31.44 215.63,31.44 215.63,30.9 215.71,30.9 215.78,30.98 215.78,31.44 216.24,31.44 216.32,31.51 216.32,32.73 216.24,32.81 215.17,32.81
+0.675VS on BOTTOM: 106.59,58.64 107.6,58.64 107.65,58.59 107.65,58.02 107.59,57.96 107.2,57.96 106.97,57.73 106.97,56.89 107.12,56.74 107.96,56.74 108.34,56.35 108.34,52.62 108.42,52.54 109.64,52.54 110.17,53.08 110.17,55.9 110.86,56.58 110.86,58.56 111.01,58.72 113.68,58.72 113.98,58.41 113.98,57.65 113.83,57.5 111.92,57.5 111.77,57.35 111.77,55.9 111.39,55.52 111.39,51.4 110.93,50.94 109.1,50.94 108.72,50.56 108.72,49.5 108.65,49.42 107.96,49.42 107.81,49.27 107.81,48.35 107.88,48.28 108.49,48.28 108.72,48.05 108.72,43.02 109.26,42.49 109.26,41.5 109.1,41.34 107.05,41.34 106.74,41.65 106.74,48.2 106.51,48.43 106.51,49.12 106.36,49.27 105.45,49.27 103.81,50.91 103.81,52.89 103.16,53.54 103.16,54.98 103.01,55.14 103.01,57.35 103.16,57.5 105.52,57.5 105.67,57.65 106.36,57.65 106.51,57.8 106.51,58.56 ; 2 cut-outs
+0.675VS on BOTTOM: 171.74,58.64 171.89,58.49 171.89,57.65 171.74,57.5 171.13,57.5 171.05,57.42 171.05,55.29 170.37,54.6 170.37,50.18 169.91,49.73 167.93,49.73 167.63,49.42 167.63,47.74 167.78,47.59 169.23,47.59 169.45,47.36 169.45,44.7 169.11,44.35 167.89,44.35 167.63,44.09 167.63,41.57 166.94,40.89 166.94,38.91 166.71,38.68 165.42,38.68 165.11,38.98 165.11,51.55 164.42,52.24 162.9,52.24 162.82,52.32 162.82,57.19 163.05,57.42 165.95,57.42 166.25,57.12 166.56,57.12 167.02,57.57 167.02,58.41 167.09,58.49 167.7,58.49 167.85,58.34 167.85,57.73 167.47,57.35 167.47,56.89 167.7,56.66 167.7,52.16 167.85,52.01 169.45,52.01 169.61,52.16 169.61,56.51 169.91,56.81 169.91,58.56 169.99,58.64 ; 4 cut-outs
+0.675VS on IN1: 115.61,59.02 104.43,59.02 103.54,58.13 103.54,56.99 104.3,56.23 137.58,56.23 138.47,55.34 198.54,55.34 199.3,56.1 199.3,57.37 198.28,58.39 197.39,58.39 196.63,59.15 115.73,59.15 ; 1 cut-out
+0.675VS on IN2: 196.89,56.74 199.43,56.74 207.05,49.12 213.9,49.12 216.19,46.83 216.19,31.97 216,31.78 213.84,31.78 213.4,32.22 213.4,45.56 212.51,46.45 205.27,46.45 196.51,55.21 196.51,56.35
+0.675VSP on BOTTOM: 215.4,31.21 214.26,31.21 214.11,31.06 214.11,28.77 214.34,28.54 217,28.54 217.26,28.29 217.26,27.53 217.31,27.48 218.15,27.48 218.22,27.55 218.22,27.7 218.07,27.86 218.07,28.77 218.22,28.92 218.6,28.92 218.76,28.77 218.76,27.86 218.91,27.86 218.91,29.23 218.3,29.84 218.3,31.06 218.07,31.29 215.94,31.29 215.94,30.68 215.4,30.68
+1.5V_B+ on BOTTOM (solid shape): 292.56,45.8 292.56,45.03 292.2,44.68 292.2,43.65 292.26,43.59 293.08,43.59 293.23,43.44 293.23,42.69 293.1,42.56 293.1,42.56 291.67,42.56 291.61,42.62 291.61,43.26 291.48,43.38 290.65,43.38 290.4,43.64 289.19,43.64 288.84,43.29 287.5,43.29 287.48,43.31 287.48,43.38 287.48,44.4 287.73,44.65 291.03,44.65 291.29,44.91 291.29,45.67 291.54,45.92 292.43,45.92
+1.05V_M on BOTTOM (solid shape): 80.27,41.67 80.27,41.39 80.37,41.28 81.36,41.28 82.1,40.55 82.1,38.66 82.02,38.58 80.26,38.58 80.04,38.8 80.04,39.51 79.49,40.06 79.49,41.76 79.52,41.79 80.15,41.79
+1.05V_M on TOP: 97.93,29.67 97.93,28.27 98.14,28.06 101.92,28.06 103.99,30.13 124.14,30.13 126.5,27.77 126.5,26.24 126.91,25.84 130.8,25.84 130.95,25.99 130.95,31.32 129.22,33.05 101.31,33.05
+1.05V_M on BOTTOM: 88.13,33.97 89.95,33.97 90.09,33.83 90.09,32.24 89.97,32.13 88.32,32.13 88.1,32.34 88.1,33.93
+1.05V_M on BOTTOM: 130.52,25.2 130.44,25.27 130.44,25.35 129.92,25.87 127.24,25.87 126.78,26.33 126.78,29.33 129.35,29.33 129.75,28.92 131.35,28.92 131.51,28.77 131.51,28.01 131.2,27.7 131.2,26.87 131.21,26.86 131.21,26.03 131.74,25.5 131.74,25.35 131.58,25.2
+1.05V_M on IN3: 80.82,41.32 82.34,41.32 84.77,38.9 86.99,38.9 90.8,35.08 99.46,35.08 100.18,34.37 100.18,29.24 99.96,29.02 96.24,29.02 95.48,29.78 95.48,31.26 95.26,31.47 90.54,31.47 89.55,32.46 88.31,32.46 88.02,32.74 88.02,34.3 87.54,34.79 84.39,34.79 80.67,38.51 80.67,41.17
+1.05V_SATAMODPHY on TOP: 88.83,23.89 87.69,23.89 87.54,23.74 87.54,22.83 87.62,22.75 88.99,22.75 89.06,22.83 89.06,23.67
+1.05V_SATAMODPHY on TOP: 129.68,3.85 129.83,4.01 129.83,5.07 129.75,5.15 126.59,5.15 126.53,5.08 126.53,4.07 126.74,3.85
+1.05V_SATAMODPHY on BOTTOM: 124.42,2.1 124.34,2.18 124.34,3.09 124.5,3.24 126.01,3.24 126.05,3.24 127.09,4.28 127.99,4.28 128.36,4.65 129,4.65 129.12,4.54 129.12,3.92 129.02,3.81 128.66,3.81 128.66,2.19 128.57,2.1
+1.05V_SATAMODPHY on BOTTOM: 89.14,24.88 86.62,24.88 86.32,24.58 86.32,21.99 86.47,21.84 87.46,21.84 88.3,22.67 89.14,22.67 89.22,22.75 89.22,24.81
+1.05V_SATAMODPHY on IN1: 128.69,4.23 129.8,4.23 129.8,4.94 129.77,4.97 128.52,4.97 128.43,4.88 128.43,4.49
+1.05V_USB3MODPHY on BOTTOM (solid shape): 114.56,4.09 114.56,2.24 114.5,2.18 113.03,2.18 113.03,3.75 113.51,4.23 114.42,4.23
+1.05V_USB3MODPHY on TOP: 89.01,7.62 89.71,7.62 89.99,7.34 89.99,6.49 89.89,6.39 88.96,6.39 88.89,6.47 88.89,7.5
+1.05V_USB3MODPHY on TOP: 114.46,3 114.34,2.87 113.73,2.87 113.32,3.28 113.32,4.16 113.45,4.28 114.41,4.28 114.46,4.23
+1.05V_USB3MODPHY on TOP: 84.52,15.81 85.2,15.81 85.37,15.65 85.37,14.66 85.19,14.48 84.59,14.48 84.24,14.84 84.24,15.54
+1.05V_USB3MODPHY on BOTTOM: 135.66,6.29 135.59,6.22 135.59,3.63 135.9,3.33 137,3.33 137.12,3.45 137.12,3.84 136.94,4.02 136.94,6.21 136.85,6.29
+1.05V_USB3MODPHY on BOTTOM: 88.22,14.9 88.07,14.75 84.64,14.75 84.49,14.9 84.49,15.23 84.26,15.46 84.26,15.71 84.49,15.94 84.49,16.86 84.62,16.98 86.7,16.98 87.01,16.68 88.12,16.68 88.22,16.58
+1.05V_USB3MODPHY on IN2: 89.02,6.86 89.88,6.86 90.07,6.67 90.07,5.72 89.86,5.52 89.6,5.52 88.9,6.21 88.9,6.73
+1.05V_USB3MODPHY on IN2: 114.58,3.86 114.41,3.7 113.64,3.7 113.4,3.94 113.4,4.75 113.55,4.91 114.39,4.91 114.58,4.72
+1.05VA on BOTTOM (solid shape): 114.46,24.48 114.46,23.79 114.37,23.7 113.92,23.7 113.33,24.29 113.33,24.55 113.38,24.6 114.34,24.6
+1.05VA on IN4 (solid shape): 114.22,24.6 114.22,23.85 114.21,23.84 112.56,23.84 112.3,24.1 112.3,24.73 112.43,24.86 113.96,24.86
+1.05VA on BOTTOM: 101.13,27.02 100.98,27.17 100.98,28.44 101.56,29.02 101.56,32.81 102.85,34.1 111.07,34.1 111.53,34.56 127.85,34.56 128.15,34.26 128.15,29.98 126.72,29.98 126.55,30.14 125.04,30.14 124.5,30.69 124.5,32.5 123.89,33.11 104.15,33.11 103.08,32.05 103.08,29.23 102.55,28.69 102.55,28.08 102.45,27.98 101.92,27.98 101.74,27.81 101.74,27.12 101.64,27.02
+1.05VA on BOTTOM: outline of 82 points within 73.65,17.54 87.91,40.71
+1.05VA on VCC: 75.58,17.75 75.09,18.23 75.09,38.6 75.71,39.21 85.15,39.21 86.78,37.58 86.78,18.74 85.78,17.75
+1.05VA on IN3: 113.18,24.8 113.27,24.71 113.27,24.05 113.07,23.84 110.53,23.84 110.27,24.1 110.27,24.73 108.11,26.89 103.34,26.89 102.88,26.43 101.59,26.43 101.13,26.89 96.56,26.89 95.92,26.26 84.75,26.26 84.49,26.51 84.49,33.09 84.5,33.09 84.5,33.58 85,34.08 87.18,34.08 87.44,33.83 87.44,30.8 86.04,29.41 86.04,27.88 86.4,27.53 95.16,27.53 96.43,28.8 108.75,28.8 109.38,28.16 110.78,28.16 111.64,27.3 111.64,26.1 112,25.75 112,25.06 112.27,24.8
+1.05VA on IN4: 83.09,20.46 83.09,36.54 83.35,36.8 84.24,36.8 87.29,33.75 87.29,22.55 84.82,20.08 83.48,20.08
+1.05VA on IN4: 101.03,27.98 101.99,27.98 102.86,27.12 102.86,26.74 102.68,26.56 101.2,26.56 100.82,26.94 100.82,27.78
+1.05VDX_MODPHY on TOP: 134.02,3.93 134.17,4.08 134.17,5.06 133.25,5.99 132.55,5.99 132.41,5.85 132.41,4.02 132.5,3.93
+1.05VDX_MODPHY on TOP: 88.68,28.62 87.46,28.62 87.39,28.54 87.39,26.41 87.54,26.26 88.61,26.26 88.83,26.48 88.83,28.47
+1.05VDX_MODPHY on BOTTOM: 135.19,2.05 135.32,2.18 135.32,3.76 135.13,3.95 133.51,3.95 133.36,3.81 133.36,2.44 133.75,2.05
+1.05VDX_MODPHY on BOTTOM: 87.39,29.76 89.06,29.76 89.14,29.68 89.14,28.01 88.91,27.78 88.3,27.78 88.15,27.63 88.15,26.97 87.82,26.64 86.43,26.64 86.24,26.83 86.24,28.62
+1.05VDX_MODPHY on IN1: 134.55,3.53 134.16,3.14 133.45,3.14 133.45,3.15 133.27,3.15 133.13,3.28 133.13,3.7 133.73,4.3 133.73,4.67 133.98,4.92 134.45,4.92 134.55,4.82
+1.05VDX_MODPHY on IN4: 133.33,2.92 133.59,2.92 134.09,3.43 134.09,3.82 133.92,3.99 133.32,3.99 133.32,3.98 133.24,3.98 133.11,3.85 133.11,3.15
+1.05VS on BOTTOM (solid shape): 97.84,26.77 97.84,24.88 97.75,24.78 96.35,24.78 96.25,24.88 96.25,26.59 96.53,26.87 97.75,26.87
+1.5VS on BOTTOM (solid shape): 284.67,38.27 284.67,37.86 285.23,37.86 285.23,37.68 284.67,37.68 284.67,37.11 284.43,36.87 283.09,36.87 282.93,37.03 282.93,38.15 283.13,38.35 284.59,38.35
+1.05VS on BOTTOM (solid shape): 92.06,33.93 92.25,33.74 92.25,32.17 91.92,31.84 91.5,31.84 91.3,31.65 91.3,30.77 90.54,30 87.87,30 87.69,30.18 87.69,31.72 87.88,31.91 89.98,31.91 90.27,32.2 90.27,33.78 90.43,33.94 92.06,33.94
+1.05VS on IN4 (solid shape): 89.95,32.12 89.95,30.42 89.85,30.32 88.3,30.32 88.15,30.47 88.15,32.22 88.2,32.28 89.8,32.28
+1.05VS on BOTTOM: 149.95,4.01 149.95,2.25 150.02,2.18 150.86,2.18 150.94,2.25 150.94,4.01 150.86,4.08 150.02,4.08
+1.05VS on BOTTOM: 135.77,10.25 136.99,10.25 137.45,9.8 137.52,9.73 137.52,8.84 137.75,8.6 137.75,7.61 137.83,7.53 138,7.53 139.1,6.43 139.1,4.79 139.91,3.98 139.91,2.08 139.79,1.95 138.12,1.95 137.91,2.16 137.91,5.3 137.67,5.53 137.67,6.3 137.37,6.6 136.84,6.6 136.69,6.75 136.69,8.27 136.38,8.58 135.85,8.58 135.7,8.73 135.7,10.18
+1.05VS on BOTTOM: 125.35,13.15 125.85,13.66 125.85,19.21 125.66,19.4 124.42,19.4 124.42,21.15 124.27,21.3 123.43,21.3 123.28,21.15 123.28,20.46 123.12,20.31 122.44,20.31 122.36,20.24 122.36,19.63 122.52,19.47 123.59,19.47 123.73,19.32 123.73,13.66 124.24,13.15
+1.05VS on IN1: 138.82,5.76 138.52,5.45 137.68,5.45 137.37,5.76 137.37,8.81 137.45,8.88 137.45,10.24 136.7,10.99 136.7,11.88 136.95,12.13 137.56,12.13 138,12.57 138.55,12.57 138.82,12.3
+1.05VS on VCC: 128.41,11.52 125.11,14.83 117.62,14.83 116.22,16.22 114.31,16.22 108.57,21.96 105.34,21.96 104.96,21.58 87.77,21.58 87.29,22.07 87.29,36.56 87.9,37.18 94.93,37.18 96.7,35.4 103.18,35.4 109.79,28.8 129.6,28.8 130.59,27.8 130.59,27.17 132.88,24.88 132.88,21.96 134.04,20.79 135.96,20.79 136.26,21.09 137.43,21.09 138.39,20.13 138.38,20.06 138.38,19.98 138.38,13.54 138.38,13.42 138.4,13.31 138.4,12.58 137.34,11.52
+1.05VS on IN4: 124.88,15.67 124.88,15.66 125.03,15.51 125.03,14.98 124.95,14.9 123.96,14.9 123.88,14.98 123.43,14.98 123.35,15.05 123.35,15.59 123.43,15.67
+1.05VS on IN4: 137.51,6.76 138.4,6.76 138.85,6.32 138.85,5.24 138.66,5.05 137.45,5.05 137.32,5.17 137.32,6.57
+1.05VS on IN4: 135.02,22.5 135.27,22.5 135.44,22.32 135.44,21.61 135.52,21.53 135.52,21.07 135.44,21 134.48,21 134.4,21.07 134.4,21.5 134.84,21.94 134.84,22.32
+1.05VS on IN4: 124.88,18.03 124.95,17.96 124.95,17.65 124.56,17.26 122.97,17.26 122.9,17.34 122.9,17.95 122.97,18.03
+1.5VSP on BOTTOM (solid shape): 286.33,37.92 287.89,37.92 287.95,37.87 289.97,37.87 290.38,37.46 290.38,36.76 290.18,36.56 285.22,36.56 284.82,36.96 284.82,37.55 285.36,37.55 285.36,37.98 284.82,37.98 284.82,38.38 284.93,38.48 285.77,38.48
+1.05VSP on BOTTOM (solid shape): 74.18,37.3 74.18,36.97 74.61,36.54 79.24,36.54 80.86,34.93 80.86,33.86 81.12,33.6 82.26,33.6 82.45,33.41 82.45,32.14 80.93,32.14 80.42,31.63 74.29,31.63 73.69,32.23 71.93,32.23 71.91,32.25 71.91,33.35 72.04,33.47 73.18,33.47 73.58,33.87 73.58,35.22 73.33,35.47 73.33,37.29 73.43,37.39 74.09,37.39
+1.8V_B+ on BOTTOM (solid shape): 280.37,46.05 280.37,45.29 280.01,44.93 280.01,43.9 280.07,43.84 280.88,43.84 281.04,43.69 281.04,42.94 280.91,42.82 280.91,42.81 279.48,42.81 279.41,42.88 279.41,43.51 279.29,43.64 278.46,43.64 278.21,43.89 277,43.89 276.65,43.54 275.31,43.54 275.28,43.57 275.29,43.64 275.29,44.65 275.54,44.91 278.84,44.91 279.1,45.16 279.1,45.92 279.35,46.18 280.24,46.18
+1.8VS on BOTTOM (solid shape): 272.46,38.48 272.46,37.59 272.24,37.37 271.6,37.37 271.44,37.53 271.44,38.5 271.54,38.61 272.33,38.61
+1.8VS on BOTTOM (solid shape): 5.45,40.94 5.45,39.67 5.39,39.61 5.39,38.83 5.29,38.74 4.4,38.74 4.33,38.82 4.33,40.84 4.33,40.92 4.46,41.05 5.33,41.05
+1.8VS on IN1 (solid shape): 272.93,38.4 272.93,38.02 272.35,37.43 271.66,37.43 271.51,37.58 271.51,38.47 271.61,38.57 272.76,38.57
+1.8VS on IN1 (solid shape): 294.78,44.09 294.78,43.78 294.53,43.53 293.23,43.53 293.13,43.63 293.13,44.14 293.24,44.25 294.05,44.25 294.11,44.31 294.21,44.31 294.22,44.32 294.55,44.32
+1.8VS on IN2 (solid shape): 5.71,41.28 5.71,39.23 5.53,39.05 5.1,39.05 4.91,39.24 4.91,41.3 5.02,41.42 5.57,41.42
+1.8VS on IN2 (solid shape): 44.52,26.82 44.52,26.15 44.34,25.96 43.92,25.96 43.38,26.5 43.38,27.01 43.55,27.18 44.16,27.18
+1.8VS on IN2 (solid shape): 295.31,44.16 295.31,43.63 295.21,43.53 294.19,43.53 294.04,43.68 294.04,44.21 294.35,44.52 294.96,44.52
+1.8VS on IN2 (solid shape): 41.04,25.48 42.56,25.48 43.38,24.67 43.38,24.45 42.92,24 41.11,24 40.98,24.12 40.98,24.6 40.75,24.83 40.37,24.83 40.27,24.94 40.27,25.34 40.42,25.49 41.03,25.49
+1.8VS on IN3 (solid shape): 44.24,26.59 44.24,25.31 43.32,24.39 42.94,24.39 42.42,24.91 42.42,25.19 43.1,25.88 43.1,26.68 43.21,26.78 44.04,26.78
+1.8VS_AUDIO on BOTTOM (solid shape): 11.57,52.33 11.77,52.33 11.97,52.12 11.97,51.81 11.94,51.77 11.58,51.77 11.34,52.01 10.65,52.01 10.6,52.06 10.6,52.54 10.65,52.6 11.3,52.6
+1.8VSP on BOTTOM (solid shape): 273.9,38.42 273.9,38.09 274.03,37.96 278.06,37.96 278.19,37.84 278.19,37.73 278.18,37.72 278.18,37.02 277.98,36.81 272.74,36.81 272.63,36.92 272.63,37.69 272.71,37.76 273.24,37.76 273.24,38.3 272.63,38.3 272.63,38.68 272.69,38.73 272.88,38.73 272.88,38.74 273.58,38.74
+1.35V_DDR on TOP: 146.15,57.96 102.26,57.96 102.07,57.76 93.83,57.76 93.02,56.96 91.57,56.96 90.92,57.61 81.78,57.61 78.93,54.75 78.93,45.51 81.8,42.64 84.11,42.64 84.12,42.63 86.03,42.63 88.21,40.44 92.25,40.44 94.19,38.5 189.37,38.5 190.79,37.08 197.75,37.08 198.74,36.09 198.74,35.55 203.69,30.6 207.27,30.6 209.54,32.86 209.54,45.53 198.26,56.81 187.59,56.81 186.99,57.41 170.19,57.41 168.69,55.92 166.52,55.92 165.93,56.51 163.09,56.51 162.02,57.59 148.26,57.59 147.6,56.92 147.18,56.92
+1.35V_DDR on BOTTOM: 141.34,22.14 143.32,22.14 143.47,21.99 143.47,21.53 143.32,21.38 141.34,21.38 141.26,21.46 141.26,22.06
+1.35V_DDR on BOTTOM: 209.25,33.34 204.05,33.34 203.74,33.04 203.74,28.16 203.87,28.03 205.65,28.03 205.65,28.54 206.41,28.54 206.41,28.03 206.92,28.03 206.92,28.54 207.68,28.54 207.68,28.03 208.67,28.03 209.25,28.62
+1.35V_DDR on BOTTOM: outline of 245 points within 79.08,24.73 195.74,58.06 ; 1 cut-out
+1.35V_DDR on IN2: 146.04,23.67 143.61,21.24 142.54,21.24 142.43,21.35 142.43,24.43 143.52,25.52 144.23,25.52 144.7,25.99 144.7,27.69 144.85,27.84 145.91,27.84 146.04,27.72
+1.35V_DDR on IN3: 146.07,22.52 144.73,21.18 142.63,21.18 142.63,25.13 143.24,25.74 144.7,25.74 145.44,26.47 145.44,27.54 145.43,27.55 145.43,27.73 145.53,27.83 145.96,27.83 146.07,27.72
+1.35VP on BOTTOM: 203.82,17.8 204.51,17.11 208.7,17.11 209.08,17.49 209.08,27.4 208.7,27.78 207.43,27.78 207.43,28.29 207.17,28.29 207.17,27.78 206.28,27.78 206.28,28.29 205.9,28.29 205.9,27.78 204.13,27.78 203.82,27.48
+1.35VP on BOTTOM: 216.98,28.03 216.6,28.03 216.52,27.96 216.52,27.09 216.67,26.94 217.16,26.94 217.26,27.04 218.17,27.04 218.22,27.09 218.22,27.22 218.17,27.27 217.21,27.27 217.05,27.42 217.05,27.96
+1.35VP on IN3: 215.78,28.01 217,28.01 217.1,27.91 217.1,26.99 216.98,26.87 215.81,26.87 215.68,26.99 215.68,27.91
+1.35VP on IN3: 209.94,26.84 207.66,26.84 207.5,26.69 207.5,25.75 207.66,25.6 209.97,25.6 210.09,25.72 210.09,26.69
+3.3V_M on BOTTOM: 241.34,17.82 242.99,17.82 243.1,17.71 243.1,16.79 242.94,16.63 241.29,16.63 241.2,16.72 241.2,17.68
+3.3V_SUS on BOTTOM (solid shape): 298.13,47.29 299.07,47.29 299.2,47.16 299.2,46.21 299.16,46.18 297.02,46.18 296.94,46.25 296.94,47.17 297.19,47.43 297.99,47.43
+3.3V_SUS on BOTTOM (solid shape): 287.75,51.84 288.82,51.84 288.9,51.76 288.9,50.21 288.87,50.18 287.66,50.18 287.59,50.25 287.59,51.22 287.18,51.63 287.18,51.77 287.25,51.84 287.28,51.84 287.39,51.95 287.64,51.95
+3.3V_SUS on IN1 (solid shape): 288.18,51.38 288.18,50.81 287.96,50.59 286.74,50.59 286.46,50.87 286.46,51.45 286.59,51.59 287.97,51.59
+3.3V_SUS on IN4 (solid shape): 297.72,48 297.72,46.68 297.61,46.56 297.09,46.56 296.96,46.69 296.96,47.33 296.5,47.78 296.5,47.95 296.78,48.23 297.5,48.23
+3.3V_SUS on IN2: 297.72,47.34 297.72,46.94 297.23,46.45 296.66,46.45 295.7,47.41 293.88,47.41 292.01,49.28 291.51,49.28 291.23,49.56 289.53,49.56 288.67,50.42 287.4,50.42 287.32,50.51 287.32,50.71 287.31,50.72 287.31,51.48 287.49,51.66 292.22,51.66 292.25,51.63 293.43,51.63
+3.3VDX_SSD on TOP (solid shape): 27.88,47.77 28.4,47.77 28.56,47.73 28.72,47.77 30.11,47.77 30.26,47.62 30.26,46.33 30.16,46.23 16.91,46.23 16.81,46.34 16.81,47.97 16.98,48.15 27.5,48.15
+3.3VDX_SSD on BOTTOM (solid shape): 33.67,58.19 33.67,56.07 33.4,55.8 33.4,54.89 34.03,54.26 35.01,54.26 35.57,54.82 35.57,57.12 35.62,57.17 37.02,57.17 37.16,57.03 37.16,54.54 36.61,53.99 36.61,53.04 36.35,52.77 32.62,52.77 32.33,53.07 32.33,58.21 32.36,58.24 33.62,58.24
+3.3VDX_SSD on IN4 (solid shape): 37.54,56 37.53,55.99 37.53,54.08 35.64,52.19 35.64,49.88 35.19,49.43 32.99,49.43 30.62,47.06 28.99,47.06 28.72,47.33 28.72,47.69 29.09,48.06 29.51,48.06 32.15,50.7 34.14,50.7 34.26,50.83 34.26,53.13 36.22,55.08 36.22,55.99 36.4,56.16 37.37,56.16
+3.3VDX_SSD on BOTTOM: 15.99,43.29 15.78,43.08 15.15,43.08 15.1,43.13 15.1,44.09 15.26,44.24 16.94,44.24 17.08,44.38 17.08,45.52 16.92,45.68 16.92,47.62 16.51,48.04 13.63,48.04 13.43,48.23 13.43,48.81 13.64,49.01 17.94,49.01 18.45,49.52 18.45,51.86 19.57,52.98 19.57,54.86 18.7,55.73 16.11,55.73 15.34,56.5 15.34,58.08 15.4,58.15 16.04,58.15 16.15,58.03 16.15,56.73 16.28,56.61 19.8,56.61 21.02,55.39 21.02,52.65 19.7,51.33 19.7,48.61 18,46.91 18,46.05 18.28,45.77 18.28,43.4 18.17,43.29
+3V_PCH on BOTTOM: 108.19,17.04 108.04,16.88 108.04,14.67 107.81,14.44 106.74,14.44 106.36,14.06 104.43,14.06 104.38,14.11 104.38,15.82 104.84,16.27 104.84,17.04 104.68,17.19 103.69,17.19 103.54,17.04 103.54,16.19 103.77,15.96 103.77,13.76 105.14,13.76 105.22,13.68 105.22,12.92 105.07,12.77 103.39,12.77 103.16,12.54 100.99,12.54 100.61,12.16 100.61,11.89 100.34,11.63 98.59,11.63 98.36,11.85 98.36,13.45 98.51,13.61 99.35,13.61 99.43,13.68 99.43,13.91 99.35,13.99 98.59,13.99 98.21,14.37 98.21,16.5 98.36,16.65 99.05,16.65 99.2,16.81 99.2,18.94 99.05,19.09 97.75,19.09 97.22,18.56 97.22,10.86 97.52,10.56 101.03,10.56 101.48,11.02 101.48,11.78 101.64,11.93 104.15,11.93 104.46,12.24 105.75,12.24 105.98,12.46 105.98,13.68 106.06,13.76 110.63,13.76 110.86,13.99 110.86,16.49 110.31,17.04
+3V_PCH_DSW on BOTTOM (solid shape): 99.38,15.16 99.38,14.34 99.22,14.19 98.64,14.19 98.46,14.37 98.46,15.13 98.61,15.28 98.61,15.31 99.22,15.31
+3V_PCH_DSW on BOTTOM: 133.64,30.76 133.56,30.68 133.56,27.41 133.11,26.95 133.11,25.27 133.18,25.2 133.41,25.2 133.49,25.27 133.49,25.88 134.71,27.1 134.71,28.5 134.64,28.56 134.64,30.73 134.61,30.76
+3VALW on BOTTOM (solid shape): 78.57,49.7 78.57,49.09 78.55,49.07 77.68,49.07 77.58,48.96 77.58,48.35 77.25,48.02 76.49,48.02 76.36,48.15 76.36,49.12 77,49.75 78.52,49.75
+3VALW on BOTTOM (solid shape): 31.77,42.08 31.77,41.47 31.89,41.36 32.6,41.36 32.69,41.26 32.69,40.39 32.59,40.28 31.61,40.28 30.85,41.04 30.85,42.08 30.91,42.15 31.7,42.15
+3VALW on BOTTOM (solid shape): 77.76,46.35 77.76,44.87 78.06,44.57 78.47,44.57 78.55,44.49 78.55,44.09 78.45,43.99 77.33,43.99 76.95,44.37 76.95,45.43 76.39,45.99 76.39,46.5 76.52,46.63 77.48,46.63
+3VALW on BOTTOM (solid shape): 297.8,54.21 297.8,53.65 297.91,53.53 298.41,53.53 298.49,53.45 298.49,53.03 298.03,52.57 298.03,51.88 298.01,51.86 297.19,51.86 297.1,51.95 297.1,54.16 297.2,54.26 297.74,54.26
+3VALW on BOTTOM (solid shape): 38.91,41.15 38.91,38.9 38.8,38.78 37.09,38.78 36.92,38.61 36.37,38.61 36.32,38.66 36.32,39.73 35.53,40.52 34.14,40.52 34.01,40.65 34.01,41.33 34.07,41.39 38.67,41.39
+3VALW on BOTTOM (solid shape): 76.63,21.13 77.24,20.52 77.24,19.54 77.15,19.45 76.7,19.45 76.6,19.55 76.59,19.55 76.36,19.78 76.24,19.78 76.11,19.91 76.11,20.8 76.35,21.05 76.35,22.26 76.63,22.26
+3VALW on BOTTOM (solid shape): 11.61,36.91 11.61,35.48 10.56,34.43 4.44,34.43 2.67,36.21 2.67,36.86 2.76,36.95 4.05,36.95 4.66,36.34 5.13,36.34 5.13,36.34 5.28,36.34 5.45,36.17 5.45,35.63 5.77,35.31 8.34,35.31 8.86,35.83 8.86,36.72 8.95,36.81 10.73,36.81 10.91,36.99 11.53,36.99
+3VALW on IN4 (solid shape): 32.5,41.67 32.5,41 32.23,40.73 31.62,40.73 30.27,42.08 30.27,42.24 30.37,42.33 30.82,42.33 31.23,42.74 31.43,42.74
+3VALW on IN4 (solid shape): 70,20.87 77.07,20.87 77.25,20.69 77.25,20.03 76.99,19.77 76.27,19.77 75.86,20.19 73.21,20.19 72.97,19.94 67.83,19.94 67.47,20.3 67.47,21.56 67.54,21.62 69.25,21.62
+3VALW on TOP: 294.13,36.71 293.96,36.87 292.14,36.87 291.96,36.7 291.96,32.72 292.3,32.38 293.94,32.38 294.13,32.57
+3VALW on TOP: 294.8,56.13 294.8,53.92 295.21,53.51 296.53,53.51 296.91,53.89 296.91,55.92 296.28,56.56 295.23,56.56
+3VALW on BOTTOM: 294.35,35.7 291.3,35.7 291.07,35.48 291.07,34.87 291.68,34.87 291.68,34.03 291.07,34.03 291.07,33.57 291.68,33.57 291.68,32.81 291.07,32.81 291.07,32.2 291.37,31.89 294.42,31.89 294.57,32.05 294.57,35.48
+3VALW on BOTTOM: 251.64,21.71 251.75,21.6 251.75,20.72 251.45,20.41 249.03,20.41 248.96,20.49 248.96,21.56 249.11,21.71
+3VALW on BOTTOM: 226.99,32.38 226.07,32.38 225.99,32.3 225.99,31.54 226.07,31.46 226.76,31.46 227.59,30.62 228.43,30.62 228.51,30.7 228.51,31.23 228.43,31.31 228.05,31.31
+3VALW on BOTTOM: 239.51,19.14 238.8,19.14 237.2,17.54 237.2,16.63 237.32,16.51 238.28,16.51 239.57,17.8 239.57,19.08
+3VALW on BOTTOM: 280.2,92.97 280.34,92.97 280.44,92.87 280.44,91 280.78,90.66 280.78,90.28 280.72,90.21 278.28,90.21 278.22,90.28 278.22,91.4 278.51,91.69 279.98,91.69 280.12,91.83 280.12,92.89
+3VALW on BOTTOM: 299.39,60.06 300.14,60.06 300.49,59.71 300.49,58.03 300.34,57.88 299.91,57.88 299.76,58.03 299.76,58.41 299.68,58.49 299.53,58.49 299.45,58.56 299.07,58.56 298.96,58.68 298.96,59.03 299.11,59.19 299.22,59.19 299.32,59.29 299.32,60
+3VALW on BOTTOM: 296.77,60.08 297.83,60.08 297.9,60 297.9,59.2 297.53,58.83 297.53,58.07 297.34,57.88 296.57,57.88 296.44,58.01 296.44,59.75
+3VALW on BOTTOM: 11.59,42 11.53,41.94 10.81,41.94 10.61,42.14 8.92,42.14 8.75,42.31 8.75,44.47 9.09,44.81 11.28,44.81 11.59,44.49
+3VALW on IN1: 294.47,56.61 294.47,55.26 294.63,55.11 296.25,55.11 296.38,55.24 296.38,56.66 296.25,56.79 294.65,56.79
+3VALW on VCC: outline of 90 points within 1.27,1.27 301.23,59.23 ; 2 cut-outs
+3VALW on IN2: 293.43,39.43 287.68,45.18 274.13,45.18 273.92,44.98 273.09,44.98 272.62,44.51 272.62,37.53 272.3,37.21 272.3,31.44 274.13,29.61 278.97,29.61 279.41,29.16 292.61,29.16 293.43,29.99
+3VALW on IN4: 76.53,45.77 76.68,45.93 77.93,45.93 78.15,46.16 78.15,48.23 77.9,48.48 68.13,48.48 67.68,48.94 67.68,50.13 68.01,50.46 79.04,50.46 79.35,50.16 79.35,42.85 78.46,41.96 76.59,41.96 76.53,42.03
+3VALW on IN4: 296.26,64.66 297.06,63.87 297.06,59.68 297.07,59.66 297.07,59.57 297.47,59.17 297.47,58.16 297.77,57.85 298.49,57.85 298.84,58.21 298.84,59.15 298.94,59.25 299.53,59.25 299.71,59.07 299.71,57.78 298.62,56.69 298.62,52.84 298.52,52.75 297.19,52.75 296.81,53.13 296.81,54.88 296.4,55.29 294.68,55.29 294.45,55.52 294.45,57.57 294.9,58.03 294.9,61.33 294.91,61.34 294.91,63.31 294.9,63.32 294.9,64.55 295.01,64.66
+3VALW_EC on BOTTOM: 286.23,91.53 287.44,91.53 287.48,91.58 291.57,91.58 292.05,92.05 292.05,92.16 292.59,92.7 293.96,92.7 294.12,92.55 297.47,92.55 297.6,92.68 298.71,92.68 298.77,92.63 298.77,91.79 298.64,91.66 293.91,91.66 293.03,90.77 293.03,90.26 293.02,90.26 293.02,90.02 292.76,89.76 290.99,89.76 290.5,90.25 290.5,90.51 290.23,90.77 289.22,90.77 288.45,90.01 286.12,90.01 286.06,90.08 286.06,91.36
+3VALW_EC on BOTTOM: outline of 82 points within 278.42,71.6 293.53,86.92
+3VALWP on BOTTOM (solid shape): 290.92,35.4 290.92,34.64 291.45,34.64 291.45,34.26 290.92,34.26 290.92,33.42 291.45,33.42 291.45,33.04 290.88,33.04 290.88,32.02 293.09,29.81 293.09,27.59 292.9,27.4 287.56,27.4 285.98,28.99 285.98,33.05 286.61,33.69 288.83,33.69 289.15,34 289.15,35.15 289.47,35.46 290.85,35.46
+3VLP on BOTTOM (solid shape): 281.02,34 281.02,32.92 280.64,32.54 280.64,31.15 280.58,31.08 280.45,31.08 280.39,31.15 280.39,32.54 280.07,32.86 280.07,34 280.2,34.13 280.9,34.13
+3VS on TOP (solid shape): 231.56,45.47 231.56,44.19 231.39,44.02 227.72,44.02 227.72,45.69 231.34,45.69
+3VS on BOTTOM (solid shape): 203.55,42.95 204.86,42.95 205.12,42.7 205.12,42.2 205,42.09 203.44,42.09 202.92,41.57 202.52,41.57 202.22,41.87 202.22,43.26 202.36,43.4 203.11,43.4
+3VS on BOTTOM (solid shape): 76.74,45.2 76.74,44.06 77.15,43.65 78.47,43.65 78.57,43.55 78.57,42.95 77.9,42.28 73,42.28 72.72,42 72.72,38.24 72.05,37.56 72.05,35.91 71.79,35.65 71.03,35.65 70.9,35.78 70.9,43.01 71.6,43.71 75.09,43.71 75.75,44.36 75.75,45.17 75.88,45.31 76.64,45.31
+3VS on IN4 (solid shape): 231.01,45.17 231.01,44.24 230.86,44.09 229.54,44.09 229.28,44.34 229.28,45.24 229.42,45.38 230.8,45.38
+3VS on IN4 (solid shape): 242.36,23.76 242.36,22.56 242.2,22.5 242.08,22.37 241.5,22.37 241.32,22.55 241.32,23.86 241.43,23.96 242.16,23.96
+3VS on TOP: 75.45,44.37 75.32,44.24 75.32,42.74 75.45,42.61 78.98,42.61 81.42,40.18 86.09,40.18 86.68,39.59 87.39,39.59 87.92,40.12 87.92,40.51 86.22,42.21 82.61,42.21 82.59,42.18 81.93,42.18 79.74,44.37
+3VS on TOP: 71.89,37.03 68.18,37.03 63.99,32.83 63.99,22.04 64.22,21.81 69.35,21.81 70.04,21.13 70.04,9.85 70.37,9.52 71.59,9.52 71.89,9.82 71.89,10.13 71.11,10.91 71.11,14.42 72.5,15.82 72.5,20.92 70.11,23.31 66.63,23.31 66.38,23.57 66.38,26.23 66.58,26.43 71.84,26.43 72.1,26.69 72.1,27.91 70.6,29.41 70.6,34.87 70.83,35.1 71.92,35.1 72.12,35.3 72.12,36.8
+3VS on TOP: 271.41,44.57 271.31,44.47 271.31,42.11 271.56,41.85 273.95,41.85 274.25,42.16 274.25,44.32 274,44.57
+3VS on TOP: 212.35,46.53 209.87,46.53 209.66,46.32 209.66,39.84 209.99,39.51 212.46,39.51 212.84,39.9 212.84,46.27 212.56,46.55 212.38,46.55
+3VS on BOTTOM: 281.07,75.49 280.88,75.3 280.88,55.39 281.19,55.08 282.61,55.08 282.8,54.89 283.28,54.89 283.47,55.08 283.47,64.41 283.96,64.89 292.29,64.89 292.82,65.42 298.69,65.42 298.84,65.58 298.84,66.49 298.74,66.59 298.21,66.59 297.65,66.03 285.84,66.03 282.05,69.82 282.05,72.05 283.2,73.2 283.2,75.4 283.11,75.49
+3VS on BOTTOM: 92.8,15.13 92.8,14.52 92.87,14.44 93.56,14.44 93.64,14.37 93.64,12.77 93.48,12.62 92.95,12.62 92.8,12.46 92.8,11.7 92.87,11.63 93.43,11.63 93.73,11.93 94.4,11.93 94.55,12.08 94.55,12.92 94.63,13 95.67,13 96.05,13.38 96.2,13.38 96.2,14.01 96.07,14.14 94.63,14.14 94.47,14.29 94.47,14.83 94.32,14.98 93.71,14.98 93.64,15.05 93.64,17.44 93.86,17.67 93.86,18.71 94.17,19.02 95.16,19.02 95.39,19.25 95.39,19.93 95.24,20.08 93.1,20.08 92.9,19.89 92.9,15.24
+3VS on BOTTOM: 150.86,6.9 152.46,6.9 152.61,6.75 152.61,6.01 152.54,5.94 150.86,5.94 150.79,6.01 150.79,6.82
+3VS on BOTTOM: outline of 137 points within 104.23,6.25 123.89,15.52
+3VS on BOTTOM: 126.27,5.81 127.52,5.81 127.68,5.97 127.7,5.99 127.7,6.29 127.77,6.37 128.39,6.37 128.45,6.32 128.45,5.79 128.43,5.78 128.04,5.78 127.53,5.27 127.45,5.27 127.44,5.28 126.2,5.28 126.2,5.73
+3VS on IN3: 287.86,52.81 288.36,52.3 288.36,50.98 288.35,50.97 288.35,48 289.49,46.86 289.49,41.98 286.7,39.18 278.78,39.18 278.03,39.93 277.47,39.93 277.45,39.95 275.14,39.95 273.72,41.37 273.72,43.3 273.04,43.99 273.04,44.37 273.19,44.52 280.81,44.52 281.38,45.09 281.38,56.33 281.66,56.61 283.27,56.61 283.42,56.46 283.42,54.86 285.47,52.81
+3VS on IN4: 98.59,28.11 97.39,28.11 96.18,26.89 96.18,20.49 95.54,19.86 94.14,19.86 93.3,19.02 93.3,18.05 93.51,17.85 93.81,17.85 94.27,18.31 95.62,18.31 97.75,20.44 99.83,20.44 100.16,20.11 101.51,20.11 102.22,19.4 102.88,19.4 104.18,20.69 106.11,20.69 106.23,20.82 106.23,21.33 106.03,21.53 102.53,21.53 101.99,21 100.47,21 100.29,21.18 100.29,21.66 100.47,21.84 102.17,21.84 103.44,23.11 103.44,23.26 103.24,23.46 102.6,23.46 102.09,22.95 97.22,22.95 96.91,23.26 96.91,24.4 98.82,26.31 98.82,27.88
+3VS on IN4: 77.91,13.94 75.59,13.94 74.94,13.28 74.94,12.65 75.52,12.06 76.57,12.06 77.81,13.3 78.27,13.3 78.34,13.38 78.34,13.84 78.22,13.96 77.94,13.96
+3VS on IN4: 123.2,10.86 124.72,10.86 125.03,10.56 125.03,8.53 126.05,7.51 126.05,7.49 126.3,7.23 126.3,6.7 126.2,6.6 125.92,6.6 125.7,6.81 124.88,6.81 122.97,8.72 122.97,10.63
+3VS_AUDIO on BOTTOM (solid shape): 17.64,38.83 17.64,38.09 17.38,37.84 17.38,36.42 17.04,36.07 16.48,36.07 16.36,36.2 16.36,36.92 16.9,37.46 16.9,38.91 17.02,39.03 17.44,39.03
+3VS_AUDIO on BOTTOM (solid shape): 11.56,51.55 12.28,51.55 12.7,51.12 12.7,50.28 12.56,50.13 12.22,50.13 12.1,50.26 12.1,51.14 11.87,51.36 11.52,51.36 11.29,51.59 10.67,51.59 10.6,51.66 10.6,51.73 10.67,51.8 11.31,51.8
+3VS_AUDIO on IN4: 12.08,42.59 12.08,38.91 13.08,37.9 17.28,37.9 17.44,38.05 17.44,38.98 17.23,39.18 13.85,39.18 13.19,39.84 13.19,44.26 11.36,46.09 11.36,49.6 11.9,50.13 12.56,50.13 12.76,50.34 12.76,50.79 12.47,51.08 10.92,51.08 10.55,50.72 10.55,44.11
+3VS_CAM on BOTTOM (solid shape): 205.27,41.7 205.27,39.56 204.53,38.82 204.53,38.16 204.37,38 202.5,38 202.44,38.06 202.44,39.43 202.51,39.5 203.1,39.5 203.12,39.52 203.12,41.29 203.74,41.91 205.05,41.91
+3VS_CAM on IN4 (solid shape): 205.99,38.97 205.99,38.57 205.4,37.98 204.66,37.98 203.55,39.08 203.55,39.72 204.15,40.31 204.65,40.31
+3VS_CAM on BOTTOM: 233.72,33.49 233.08,33.49 232.95,33.37 232.95,31.34 233.08,31.21 233.72,31.21 233.84,31.34 233.84,33.37
+3VS_CAM on IN4: 232.93,31.72 232.93,33.55 232.92,33.56 232.92,34.79 233.21,35.08 233.89,35.08 234.35,34.63 234.35,31.73 234.11,31.49 233.16,31.49
+3VS_TS on IN4: 305.71,88.28 302,88.28 301.03,89.26 301.03,91.56 300.11,92.47 300.11,96.39 300.73,97.01 306.56,97.01 308.66,94.91 308.66,91.23
+3VS_WLAN on BOTTOM (solid shape): 10.41,31.68 10.41,28.88 10.28,28.76 7.49,28.76 6.86,29.39 6.86,31.61 7.05,31.8 10.28,31.8
+3VS_WLAN on IN4 (solid shape): 11.3,29.83 11.3,29.18 12.32,28.16 12.32,27.47 11.97,27.13 11.97,26.73 11.67,26.43 11.26,26.43 11.03,26.66 11.03,28.03 10.2,28.87 8.33,28.87 8.17,29.02 8.17,30.87 8.28,30.98 10.16,30.98
+3VS_WLAN on TOP: 10.98,26.35 10.6,26.73 10.6,28.43 10.12,28.92 8.35,28.92 8.06,29.2 8.06,31.11 8.89,31.93 37.4,31.93 39.3,30.03 41.78,30.03 41.95,29.85 41.95,27.02 41.4,26.47 32.89,26.47 32.38,26.98 32.15,26.98 32.06,27.04 32.08,27.15 31.4,28.49 31.06,27.03 31.08,27.02 31.08,26.98 31.08,26.93 31.05,26.89 30.94,26.78 30.28,26.78 29.93,26.43 29.3,26.43 29.09,26.63 29.09,26.98 28.94,27.13 28.92,27.13 27.32,28.74 12.96,28.74 12.32,28.09 12.32,27.46 11.87,27.01 11.87,26.63 11.59,26.35
+3VS_WLAN on BOTTOM: 37.63,26.42 37.83,26.22 40.73,26.22 40.9,26.39 41.39,26.39 42.4,27.39 42.4,33.34 42.2,33.54 42.2,48.71 41.83,49.07 41.83,49.72 41.63,49.92 37.65,49.92 36.94,49.22 35.32,49.22 34.76,48.66 34.76,47.34 34.88,47.21 36.15,47.21 36.61,47.67 38.83,47.67 39.1,47.41 39.1,31.51 40.12,30.49 40.12,29.24 39.56,28.69 37.81,28.69 36.76,27.64 35.63,27.64 35.14,28.13 33.55,28.13 33.51,28.09 33.51,26.66 33.75,26.42
+3VS_WLAN on IN1: 10.51,26.45 10.01,26.95 8.48,26.95 8.44,26.92 6.74,26.92 6.18,27.48 6.18,30.98 6.46,31.26 11.25,31.26 12.46,30.06 12.46,27.41 11.91,26.87 11.91,26.57 11.8,26.45
+3VS_WWAN on BOTTOM (solid shape): 46.92,46.12 46.92,43.53 46.61,43.21 44.89,43.21 44.37,43.73 44.37,45.01 44.38,45.03 44.38,46.35 44.52,46.49 46.56,46.49
+3VS_WWAN on BOTTOM (solid shape): 33.36,48.76 33.36,47.8 33.31,47.74 32.6,47.74 32.5,47.64 32.5,47.3 32.38,47.18 30.56,47.18 30.36,47.38 30.36,48.71 30.77,49.12 33.01,49.12
+3VS_WWAN on BOTTOM: 43.25,16.16 44.64,16.16 45.12,16.64 45.12,18.43 46.17,19.47 52.94,19.47 53.25,19.78 53.25,21 52.87,21.38 44.64,21.38 43.47,20.21 41.49,20.21 41.22,20.48 41.22,22.3 40.68,22.84 37.33,22.84 37.33,22.83 37.17,22.83 37.09,22.76 37.09,22.11 38.66,20.55 38.66,19.81 39.02,19.45 39.02,17.37 39.85,16.54 39.85,15.62 39.88,15.6 42.68,15.6
+3VS_WWAN on BOTTOM: 61.48,16.23 64.24,16.23 64.25,16.22 64.73,16.22 65.21,15.74 65.21,7.61 64.48,6.88 64.48,3.57 64.88,3.17 67.32,3.17 67.85,3.7 67.85,10.48 66.51,11.83 66.51,17.57 66.2,17.87 65.81,17.87 63.76,19.92 61.49,19.92 61.38,19.8 61.38,18.13 61.34,18.09 61.34,17.5 61.33,17.49 61.33,16.38
+3VS_WWAN on BOTTOM: 56.89,5.91 56.89,5.11 56.38,4.6 56.11,4.6 56.02,4.51 56.02,3.96 56.06,3.92 56.51,3.92 56.62,4.03 56.62,4.04 57.3,4.72 58.66,4.72 58.74,4.79 58.74,5.99 58.66,6.06 57.04,6.06
+3VS_WWAN on IN4: 33.6,46.31 33.6,46.32 31.07,46.32 30.97,46.42 30.97,47.07 32.95,49.05 37.17,49.05 39.27,46.95 46.12,46.95 46.52,46.55 46.52,42.5 45.69,41.67 38.24,41.67
+3VS_WWAN on IN4: 62.75,18.97 62.65,18.86 57.08,18.86 56.3,19.65 51.6,19.65 51.22,20.03 51.22,21.3 51.34,21.43 62.52,21.43 62.75,21.2
+5V_DOCK on TOP: 90.26,14.6 89.27,14.6 89.04,14.37 89.04,9.6 90.18,8.45 90.18,6.49 90.31,6.37 90.49,6.37 90.82,6.7 90.82,9.05 89.88,9.99 89.88,13.07 90.46,13.66 90.46,14.39
+5V_DOCK on BOTTOM: 90.13,2.91 89.25,3.79 89.26,3.81 89.25,3.97 89.16,4.11 89.16,4.3 89.24,4.5 89.16,4.7 89.16,6.39 89.3,6.52 89.39,6.55 89.46,6.49 89.96,6.38 89.86,6.88 89.79,6.96 89.82,7.05 89.91,7.14 89.91,7.17 90.28,7.54 92.94,7.54 93.2,7.27 93.2,7.02 93.2,7.02 93.2,5.9 93.17,5.86 93.05,5.86 92.99,5.92 92.99,6.91 92.89,7.02 92.39,7.02 92.2,6.82 91.58,6.82 91.56,6.81 91.51,6.81 91.16,6.45 91.16,4.44 91.51,4.08 93.23,4.08 93.27,4.04 93.27,3.09 93.2,3.03 93.2,1.8 93.17,1.76 93.05,1.76 93,1.81 93,3.19 93.08,3.28 93.08,3.67 92.9,3.85 92.21,3.85 91.88,3.52 91.88,3.42 91.37,2.91
+5V_DOCK on BOTTOM: 79.87,10.46 79.87,9.75 80,9.62 81.67,9.62 81.8,9.75 81.8,10.3 81.93,10.43 83.3,10.43 83.48,10.61 83.48,12.9 83.91,13.33 83.91,15.71 83.78,15.84 83.25,15.84 83.14,15.74 83.14,14.11 82.64,13.61 82.64,11.17 82.61,11.14 81.52,11.14 80.91,10.53 79.94,10.53
+5V_DOCK on IN3: 84.14,15.82 83.73,15.82 83.6,15.69 83.6,13.68 84.24,13.05 89.14,13.05 90.16,14.06 90.16,14.39 90,14.55 89.39,14.55 88.78,13.94 84.9,13.94 84.31,14.52 84.31,15.64
+5VALW on TOP (solid shape): 294.66,54.63 294.66,53.19 294.46,52.99 293.61,52.99 293.51,53.09 293.51,54.48 293.77,54.74 294.55,54.74
+5VALW on TOP (solid shape): 288.78,38.6 288.78,37.55 289.14,37.2 289.14,37.09 289.01,36.96 288.21,36.96 287.68,37.48 287.68,37.54 287.68,37.55 287.68,38.59 287.83,38.74 288.64,38.74
+5VALW on BOTTOM (solid shape): 299.49,53.27 299.49,52.14 299.21,51.87 298.81,51.87 298.77,51.91 298.77,52.71 298.95,52.89 298.95,53.3 299,53.36 299.41,53.36
+5VALW on BOTTOM (solid shape): 11.58,38.96 11.58,38.47 11.49,38.38 10.51,38.38 9.86,39.04 8.89,39.04 8.82,39.11 8.82,39.55 8.89,39.62 9.55,39.62 9.88,39.95 10.59,39.95
+5VALW on BOTTOM (solid shape): 270.35,35.38 270.54,35.2 270.54,34.27 270.02,34.27 270.02,33.56 270.54,33.56 270.54,33.06 270.02,33.06 270.02,32.36 270.54,32.36 270.54,31.8 270.46,31.72 268.58,31.72 268.5,31.8 268.5,35.31 268.58,35.38 270.33,35.38
+5VALW on BOTTOM (solid shape): 82.93,17.86 82.93,15.08 82.76,14.91 81.96,14.91 81.81,14.76 81.49,14.76 81.43,14.83 81.43,15.64 81.65,15.85 81.65,15.87 81.79,16.01 81.79,17.01 81.56,17.24 80.06,17.24 79.84,17.02 79.84,16.15 80.07,15.92 80.59,15.92 80.76,15.75 80.76,14.78 80.68,14.7 79.61,14.7 79.4,14.91 79.4,18.06 79.54,18.2 82.59,18.2
+5VALW on BOTTOM (solid shape): 28.43,41.95 28.43,40.5 28.48,40.45 28.49,40.44 28.55,40.35 28.64,40.29 28.65,40.29 29.28,39.65 29.28,39.21 30.67,37.83 32.43,37.83 32.6,37.99 32.6,38.75 32.52,38.83 31.76,38.83 31.68,38.91 31.68,39.67 31.74,39.72 32.65,39.72 33.23,40.3 33.23,41.34 33.26,41.37 33.34,41.37 33.41,41.29 33.41,39.44 33.37,39.34 33.36,39.23 33.36,39.06 33.37,38.95 33.41,38.84 33.41,38.27 32.52,37.38 31.3,37.38 31.03,37.11 28.84,37.11 28.56,37.39 28.56,37.4 28.17,37.79 28.17,38.06 28.21,38.15 28.31,38.15 28.79,38.45 28.31,38.74 28.21,38.75 28.17,38.84 28.17,39.68 28.01,39.83 27.96,39.92 27.9,39.98 27.7,40.19 27.7,40.72 26.79,41.62 26.79,41.95 26.9,42.05 28.33,42.05
+5VALW on IN1 (solid shape): 288.71,37.7 288.71,36.97 288.02,36.29 287.39,36.29 287.12,36.56 287.12,37.11 287.86,37.85 288.55,37.85
+5VALW on IN1 (solid shape): 294.56,55.01 294.75,55.01 294.83,54.93 294.83,54.09 294.68,53.94 293.93,53.94 293.6,54.27 293.6,55.35 293.77,55.53 294.04,55.53
+5VALW on IN4 (solid shape): 269.94,35.07 269.94,31.72 269.66,31.44 268.23,31.44 267.98,31.69 267.98,34.99 268.34,35.35 269.66,35.35
+5VALW on BOTTOM: 219.67,25.72 219.59,25.72 219.52,25.65 219.52,22.9 220.2,22.22 222.11,22.22 222.18,22.14 222.18,21.46 222.26,21.38 223.25,21.38 223.33,21.46 223.33,22.6 223.25,22.67 220.89,22.67 220.74,22.83 220.74,23.59 219.75,24.58 219.75,25.65
+5VALW on BOTTOM: 228.43,29.25 227.52,29.25 226.68,28.41 226.15,28.41 225.99,28.26 225.99,27.58 226.07,27.5 227.67,27.5 228.51,28.34 228.51,29.18
+5VALW on BOTTOM: 239.43,19.88 238.81,19.88 238.46,19.53 238.04,19.53 237.95,19.62 237.95,20.26 238.09,20.41 239.46,20.41 239.55,20.31 239.55,20
+5VALW on IN1: 9.23,46.02 8.72,46.53 8.72,54.55 11.21,57.04 25.28,57.04 27.44,54.88 43.09,54.88 44.41,53.56 74.36,53.56 80,59.2 101.89,59.2 103.29,57.8 103.29,56.86 104.05,56.1 137.7,56.1 138.47,55.34 200.52,55.34 203.85,52.01 208.49,52.01 211.67,55.19 243.44,55.19 245.02,53.61 245.02,48.51 246.44,47.08 270.8,47.08 272.1,45.79 272.1,33.6 271.31,32.81 268.41,32.81 267.85,33.37 267.85,40.99 266.41,42.44 250.81,42.44 248.68,44.57 244.94,44.57 243.69,45.83 243.69,46.46 242.5,47.64 242.5,51.02 241.56,51.96 235.24,51.96 233.18,49.9 211.19,49.9 209.84,48.56 198.79,48.56 196.48,50.87 121.6,50.87 119.71,52.76 102.06,52.76 98.94,55.87 82.26,55.87 76.92,50.54 42.63,50.54 41.51,51.66 24.88,51.66 21.22,55.31 17.16,55.31 13.5,51.66 12.33,51.66 10.64,49.97 10.64,46.23 10.43,46.02 ; 1 cut-out
+5VALW on IN1: 221.93,21.53 222.21,21.25 223.07,21.25 223.28,21.46 223.28,23.97 227.92,28.62 227.92,29.94 227.47,30.4 226.91,30.4 222.35,25.84 222.35,25.02 221.93,24.6
+5VALW on IN1: 239.1,20.62 238.8,20.62 238.07,19.89 238.07,19.77 238.67,19.17 238.92,19.17 239.43,19.68 239.43,20.29
+5VALW on IN4: 76.59,47.46 77.37,47.46 77.53,47.3 77.53,46.56 77.35,46.38 76.53,46.38 76.38,46.54 76.38,47.25
+5VALW on IN4: 18.44,38.78 25.97,38.78 25.99,38.75 27.67,38.75 28.23,38.2 28.93,38.2 29.81,37.32 30.2,37.32 30.31,37.21 30.33,37.21 30.33,36.56 30.27,36.51 30.26,36.52 28.24,36.52 27.53,37.23 24.7,37.23 24.45,36.97 19.11,36.97 18.79,36.66 10.6,36.66 10.15,37.11 10.03,37.11 9.87,37.28 9.87,38.63 9.78,38.71 9.78,39.83 9.79,39.83 9.79,41.1 9.6,41.29 8.82,41.29 8.34,41.78 8.34,47.39 8.48,47.53 10.26,47.53 10.35,47.44 10.35,44.01 11.82,42.54 11.82,38.77 12.85,37.74 17.4,37.74
+5VALW on IN4: 296.92,52.58 298.57,52.58 298.79,52.8 298.79,53.17 298.97,53.35 299.46,53.35 299.53,53.28 299.53,52.35 299.51,52.34 299.51,51.8 299.3,51.58 296.96,51.58 296.52,52.02 295.65,52.02 295.16,52.52 295.16,53.61 295.01,53.76 294.27,53.76 294.26,53.76 294.09,53.76 293.79,54.06 293.79,54.59 294.17,54.97 296.31,54.97 296.56,54.73 296.56,52.95
+5VALWP on BOTTOM (solid shape): 272.31,35.08 272.31,33.9 272.48,33.72 275.36,33.72 275.59,33.5 275.59,30.89 275.29,30.59 274.54,30.59 274.37,30.42 274.37,27.81 273.64,27.08 268.88,27.08 268.65,27.3 268.65,31.34 268.88,31.57 270.56,31.57 270.69,31.7 270.69,32.49 270.14,32.49 270.14,32.94 270.69,32.94 270.69,33.69 270.14,33.69 270.14,34.14 270.69,34.14 270.69,35.04 270.8,35.15 272.23,35.15
+5VLP on BOTTOM (solid shape): 280.64,29.05 280.64,26.26 280.52,26.13 280.01,26.13 279.94,26.19 279.94,27.08 279.95,27.09 279.95,27.27 280.39,27.7 280.39,29.05 280.45,29.11 280.58,29.11
+5VS on BOTTOM: 234.02,28.72 233.08,28.72 233,28.64 233,27.73 233.08,27.65 234.61,27.65 234.73,27.78 234.73,28.29 234.99,28.54 236,28.54 236.21,28.75 236.21,29.28 236.05,29.43 234.73,29.43
+5VS_AUDIO on TOP (solid shape): 13.27,53.33 13.27,52.72 12.99,52.45 11.77,52.45 11.6,52.61 11.6,53.26 11.83,53.48 13.12,53.48
+5VS_AUDIO on TOP (solid shape): 18.01,41.25 18.01,39.46 17.87,39.32 16.55,39.32 16.02,39.85 16.02,41.13 16.24,41.35 17.91,41.35
+5VS_AUDIO on BOTTOM (solid shape): 17.65,40.26 17.65,39.51 17.5,39.36 16.42,39.36 16.32,39.46 16.32,40.28 16.47,40.43 17.49,40.43
+5VS_AUDIO on BOTTOM (solid shape): 12.16,53.81 12.31,53.81 12.38,53.73 12.38,52.56 12.26,52.43 11.68,52.43 11.32,52.8 10.66,52.8 10.6,52.86 10.6,53.73 10.68,53.81 12.16,53.81
+V1.05A_AOSCSUS on BOTTOM: 101.1,32.66 98.97,32.66 98.89,32.58 98.89,29.3 99.12,29.08 99.12,27.17 99.2,27.09 99.73,27.09 99.88,27.25 99.88,28.77 100.19,29.08 101.26,29.08 101.33,29.15 101.33,32.43
+V1.05S_ASATA3PLL on BOTTOM: 125.8,5.29 126.05,5.05 127.58,5.05 128.15,5.62 128.47,5.62 128.59,5.73 128.59,6.09 128.86,6.37 129.92,6.37 129.96,6.33 129.96,5.76 129.86,5.66 129.23,5.66 127.94,4.37 127.04,4.37 126.06,3.39 124.31,3.39 124.09,3.18 124.09,2.29 123.87,2.07 123.04,2.07 122.83,2.28 122.83,4.41 123.13,4.71 123.13,5.12 123.3,5.29
+V1.05S_AUSB3PLL on BOTTOM: 110.96,4.08 110.96,2.53 111.31,2.18 112.38,2.18 112.53,2.33 112.53,4.26 112.69,4.41 113.49,4.41 113.73,4.65 114.62,4.65 114.74,4.78 114.74,5.4 114.59,5.55 111.42,5.55 111.29,5.43 111.29,4.54 111.29,4.41
+V1.05S_AXCK_DCB on BOTTOM: 149.18,4.69 149.41,4.46 149.41,2.33 149.26,2.18 148.35,2.18 148.27,2.25 148.27,3.32 148.12,3.47 143.85,3.47 143.7,3.62 143.7,4.62 143.77,4.69
+V1.05S_AXCK_LCPLL on BOTTOM: 143.36,5.55 143.36,3.33 143.13,3.1 141.91,3.1 141.73,2.93 141.73,2.11 141.53,1.91 140.69,1.91 140.49,2.11 140.49,3.92 141.11,4.54 141.11,6.44 141.28,6.62 142.4,6.62 142.53,6.48 142.53,5.91 142.72,5.72 143.19,5.72
+V1.05S_MPHY_PCIE on BOTTOM: 133.34,10.34 132.27,10.34 131.62,9.69 131.62,8.57 131.79,8.4 131.79,4.82 131.69,4.73 131.69,4.05 131.48,3.84 131.48,2.14 131.58,2.04 132.57,2.04 132.65,2.11 132.65,8.19 132.84,8.39 132.84,9.39 133.49,10.03 133.49,10.19
+V1.05S_MPHY_SATA on BOTTOM: 130.52,10.25 131.58,10.25 131.66,10.18 131.66,9.95 131.35,9.64 131.35,8.88 130.77,8.3 130.77,4.25 131.28,3.74 131.28,2.19 131.22,2.13 130.12,2.13 130.07,2.18 130.07,3.83 130.06,3.84 129.58,3.84 129.34,4.07 129.34,5.33 129.4,5.39 129.96,5.39 130.09,5.52 130.09,9.07 130.2,9.18 130.2,9.94
+V1.05S_MPHY_USB3 on BOTTOM: 135.09,10.33 134.02,10.33 133.64,9.95 133.64,6.65 133.51,6.52 132.95,6.52 132.8,6.37 132.8,4.54 132.88,4.46 134.02,4.46 134.12,4.57 134.12,6.14 134.16,6.17 134.66,6.17 134.78,6.3 134.78,8.5 135.16,8.88 135.16,10.25
+VCC_CORE on IN4 (solid shape): 151.18,11.62 151.18,11.42 151.08,11.32 151.08,10.2 150.81,9.92 150.22,9.92 150.17,9.88 150.1,9.84 150.02,9.87 148.96,10.94 148.96,11.73 149.25,12.02 150.78,12.02
+VCC_CORE on BOTTOM: outline of 102 points within 140.07,4.38 174.57,27.25 ; 2 cut-outs
+VCC_CORE on VCC: 179.61,13.03 175.95,9.36 147.97,9.36 147.33,10 140.22,10 139.99,10.23 139.99,11.8 140.59,12.4 151.85,12.4 152.17,12.44 152.47,12.58 152.83,12.58 152.83,12.94 152.96,13.24 153.01,13.56 153.01,14.28 153.56,14.83 160.16,14.83 167.8,22.47 167.8,25.52 169.43,27.14 179,27.14 179.61,26.53 ; 1 cut-out
+VCC_CORE on IN3: 171.94,27.27 174.28,27.27 174.66,26.89 174.66,21.68 173.9,20.92 171.51,20.92 171.13,20.54 167.55,20.54 167.17,20.92 164.63,20.92 160.44,16.73 160.44,11.27 159.8,10.63 153.07,10.63 152.69,10.25 145.07,10.25 144.82,10.51 144.82,11.65 145.45,12.29 152.31,12.29 153.2,13.17 153.2,16.56 154.07,17.43 154.07,19.13 154.15,19.21 156.22,19.21 156.92,19.91 161.07,19.91 161.14,19.98 161.62,19.98 168.41,26.76 169.81,26.76 169.82,26.75 171.42,26.75
+VCC_CORE on IN4: 145.17,11.9 146.28,11.9 146.3,11.89 146.56,11.89 146.64,11.8 146.64,11.5 146.19,11.04 146.21,11.02 146.21,10.25 146.47,10 146.47,9.87 146.67,9.67 146.67,9.42 146.56,9.3 146.35,9.3 144.87,10.79 144.87,11.6
AGND on BOTTOM (solid shape): 12.54,54.59 12.54,54.11 12.38,53.95 11.33,53.95 11.27,54.01 10.68,54.01 10.61,54.08 10.61,54.56 10.66,54.61 11.36,54.61 11.42,54.56 11.96,54.56 12.14,54.74 12.39,54.74
AGND on BOTTOM (solid shape): 95.93,7.61 95.93,7.17 95.69,6.93 95.46,6.93 95.21,6.68 95.21,5.82 95.11,5.72 95.11,5.07 95,4.96 94.79,4.96 94.68,5.07 94.68,5.68 94.59,5.77 94.59,6.62 94.59,7.78 94.75,7.94 95.6,7.94
GND on TOP (solid shape): 77.5,2 62.63,2 62.63,5 77.5,5
GND on TOP (solid shape): 152.8,27 140.8,27 140.8,32 152.8,32
GND on TOP (solid shape): 221,50.5 211,50.5 211,56.5 221,56.5
GND on TOP (solid shape): 69.5,52.64 59.5,52.64 59.5,59.5 69.5,59.5
GND on TOP (solid shape): 3.45,44.8 3.48,44.85 3.53,44.84 4.06,44.31 6.08,44.31 6.75,43.65 6.75,43.49 6.68,43.4 6.57,43.42 6.4,43.6 4.6,43.6 3.45,44.75
GND on TOP (solid shape): outline of 162 points within 4.1,43.97 7.43,54.12
GND on TOP (solid shape): outline of 179 points within 137.87,11.9 153.52,21.6
GND on TOP (solid shape): outline of 9224 points within 0.25,0.14 312.25,104.25
GND on BOTTOM (solid shape): 275.44,36.03 275.44,34.26 275.18,34 272.77,34 272.51,34.26 272.51,35.97 272.64,36.1 275.37,36.1
GND on BOTTOM (solid shape): 82.45,31.76 82.45,30.43 82.37,30.35 81.13,30.35 81.05,30.43 81.05,31.76 81.18,31.89 82.32,31.89
GND on BOTTOM (solid shape): 163.94,9.98 163.94,8.36 163.72,8.13 159.32,8.13 159.25,8.21 159.25,8.9 160.43,10.08 163.84,10.08
GND on BOTTOM (solid shape): 29.15,43.92 29.15,43.24 28.94,43.03 27.87,43.03 27.67,43.23 26.89,43.23 26.83,43.29 26.83,43.5 26.87,43.55 27.66,43.55 28.08,43.97 29.1,43.97
GND on BOTTOM (solid shape): 82.42,35.69 82.42,34.25 82.28,34.11 81.3,34.11 81.02,34.38 81.02,35.66 81.14,35.78 82.33,35.78
GND on BOTTOM (solid shape): 97.2,6.65 97.2,5.87 97.37,5.7 97.59,5.7 97.65,5.64 97.65,5.24 97.58,5.17 97.43,5.17 96.82,5.78 96.72,5.78 96.59,5.91 96.59,6.61 96.7,6.71 97.14,6.71
GND on BOTTOM (solid shape): 80.11,42.68 80.11,42.22 80.06,42.17 78.78,42.17 78.04,41.43 77.02,41.43 76.87,41.28 76.87,40.01 76.86,40 75.91,40 75.87,40.03 75.87,41.79 75.98,41.9 77.73,41.9 78.53,42.7 80.08,42.7
GND on BOTTOM (solid shape): 275.45,39.67 275.45,38.52 275.32,38.39 274.44,38.39 274.31,38.52 274.31,39.59 274.42,39.71 274.58,39.72 274.71,39.82 275.3,39.82
GND on BOTTOM (solid shape): 288.96,36.16 288.96,34.21 288.68,33.93 287.21,33.93 286.5,34.63 286.26,34.63 285.87,35.02 285.58,35.02 285.41,35.2 285.41,36.03 285.66,36.29 288.83,36.29
GND on BOTTOM (solid shape): 163.6,26.86 163.6,22.37 162.91,21.68 159.42,21.68 159.18,21.93 159.18,22.08 159.14,22.12 159.14,22.74 159.36,22.95 161.84,22.95 162.09,23.21 162.09,24.47 162.7,25.07 162.7,26.82 162.81,26.93 163.53,26.93
GND on BOTTOM (solid shape): 73.09,36.34 73.09,35.46 73.39,35.16 73.39,33.96 73.09,33.67 72.86,33.67 71.26,33.67 71.13,33.8 71.13,34.94 71.23,35.05 71.28,35.05 71.56,35.05 71.57,35.05 71.85,35.05 72.16,35.36 72.16,36.42 72.21,36.47 72.96,36.47
GND on BOTTOM (solid shape): 287.85,39.36 287.85,38.23 287.71,38.08 286.37,38.08 286.23,38.22 286.23,38.34 286.23,38.34 286.23,39.02 286.23,39.02 286.62,39.41 286.83,39.43 286.97,39.58 287.64,39.58
GND on BOTTOM (solid shape): 284.1,8.22 284.1,7.02 283.45,6.37 283.38,6.37 283.37,6.37 277.34,6.37 276.76,6.95 276.76,8.94 277.01,9.19 283.13,9.19
GND on BOTTOM (solid shape): 81.62,25.85 81.62,25.03 81.75,24.9 82.51,24.9 82.64,24.78 82.64,22.11 82.45,21.92 79.59,21.92 79.05,22.46 76.38,22.46 76.38,24.39 76.63,24.39 76.63,23.12 78.26,23.12 78.26,24.39 79.91,26.05 81.43,26.05
GND on BOTTOM (solid shape): 284.14,28.69 284.14,27.78 283.83,27.48 283.83,24.66 283.91,24.58 284.04,24.58 285.03,24.58 285.23,24.37 285.23,23.93 285.35,23.81 285.35,20.39 284.83,19.87 284.25,19.87 283.91,19.52 282.71,19.52 282.64,19.59 282.64,20.59 282.78,20.73 283,20.73 283.43,21.15 283.43,23.81 283.34,23.89 282.23,23.89 282.08,24.05 282.08,27.53 283.32,28.77 284.06,28.77
GND on BOTTOM (solid shape): 278.27,49 278.27,49 279.57,49 279.57,49 296.4,49 296.4,10.5 255.1,10.5 255.1,11.3 295.6,11.3 295.6,48.2 237.7,48.2 237.7,35.2 203.2,35.2 203.2,2.3 244.6,2.3 244.6,11.3 247.64,11.3 247.64,10.5 245.4,10.5 245.4,1.71 245.4,1.39 245.27,1.26 202.43,1.26 202.4,1.28 202.4,36 236.9,36 236.9,49 246.91,49
GND on BOTTOM (solid shape): 276.5,43.23 276.52,43.21 276.52,42.56 276.55,42.53 276.56,42.53 276.66,42.43 277.76,42.43 278.11,42.08 280.74,42.08 280.92,41.9 280.92,41.23 280.9,41.23 280.91,41.22 280.91,41.14 280.81,41.03 280.12,41.03 280.02,40.93 280.03,40.92 280.03,40.28 280.01,40.28 279.88,40.14 278.27,40.14 276.71,41.71 274.87,41.71 274.87,42.09 274.79,42.17 273.84,42.17 273.75,42.26 273.75,42.34 273.83,42.42 274.8,42.42 274.87,42.49 274.87,43.35 276.5,43.35
GND on BOTTOM (solid shape): 288.69,42.98 288.71,42.96 288.71,42.3 288.74,42.28 288.75,42.28 288.85,42.18 289.95,42.18 290.3,41.83 292.93,41.83 293.11,41.65 293.11,40.98 293.09,40.98 293.1,40.97 293.1,40.88 293,40.78 292.31,40.78 292.21,40.68 292.22,40.67 292.22,40.02 292.2,40.02 292.07,39.89 290.46,39.89 288.9,41.45 287.06,41.45 287.06,41.84 286.98,41.92 286.03,41.92 285.94,42.01 285.94,42.08 286.02,42.17 286.99,42.17 287.06,42.24 287.06,43.1 288.69,43.1
GND on BOTTOM (solid shape): outline of 183 points within 246.43,1.26 312.25,95.97
GND on BOTTOM (solid shape): outline of 639 points within 34.16,0.26 310.25,104.25
GND on BOTTOM (solid shape): outline of 924 points within 0.25,1.27 108.44,60.25
GND on IN1 (solid shape): outline of 3390 points within 0.25,0.25 312.25,104.25
GND on VCC (solid shape): outline of 1615 points within 0.25,0.25 312.25,104.25
GND on IN2 (solid shape): outline of 10980 points within 0.25,0.25 312.25,104.25
GND on IN3 (solid shape): outline of 10822 points within 0.25,0.25 312.25,104.25
GND on IN4 (solid shape): 195.49,57.62 195.49,56.86 195.36,56.74 194.47,56.74 194.35,56.86 194.35,57.62 194.47,57.75 195.36,57.75
GND on IN4 (solid shape): outline of 4008 points within 0.25,0.25 312.25,104.25
GND on BOTTOM: 213.19,25.85 210.37,25.85 210.22,25.7 210.22,22.78 210.32,22.67 213.32,22.67 213.42,22.78 213.42,25.62
GND on BOTTOM: 264.48,32.43 258.07,32.43 257.85,32.2 257.85,23.36 258.46,22.75 258.46,21.38 258.61,21.23 259.98,21.23 260.13,21.38 260.13,26.33 259.29,27.17 259.29,28.24 259.75,28.69 266.3,28.69 266.61,28.39 266.61,26.94 266.38,26.71 265.54,26.71 265.31,26.48 265.31,22.14 265.47,21.99 267.98,21.99 268.21,22.22 268.21,31.21 267.75,31.67 265.24,31.67
